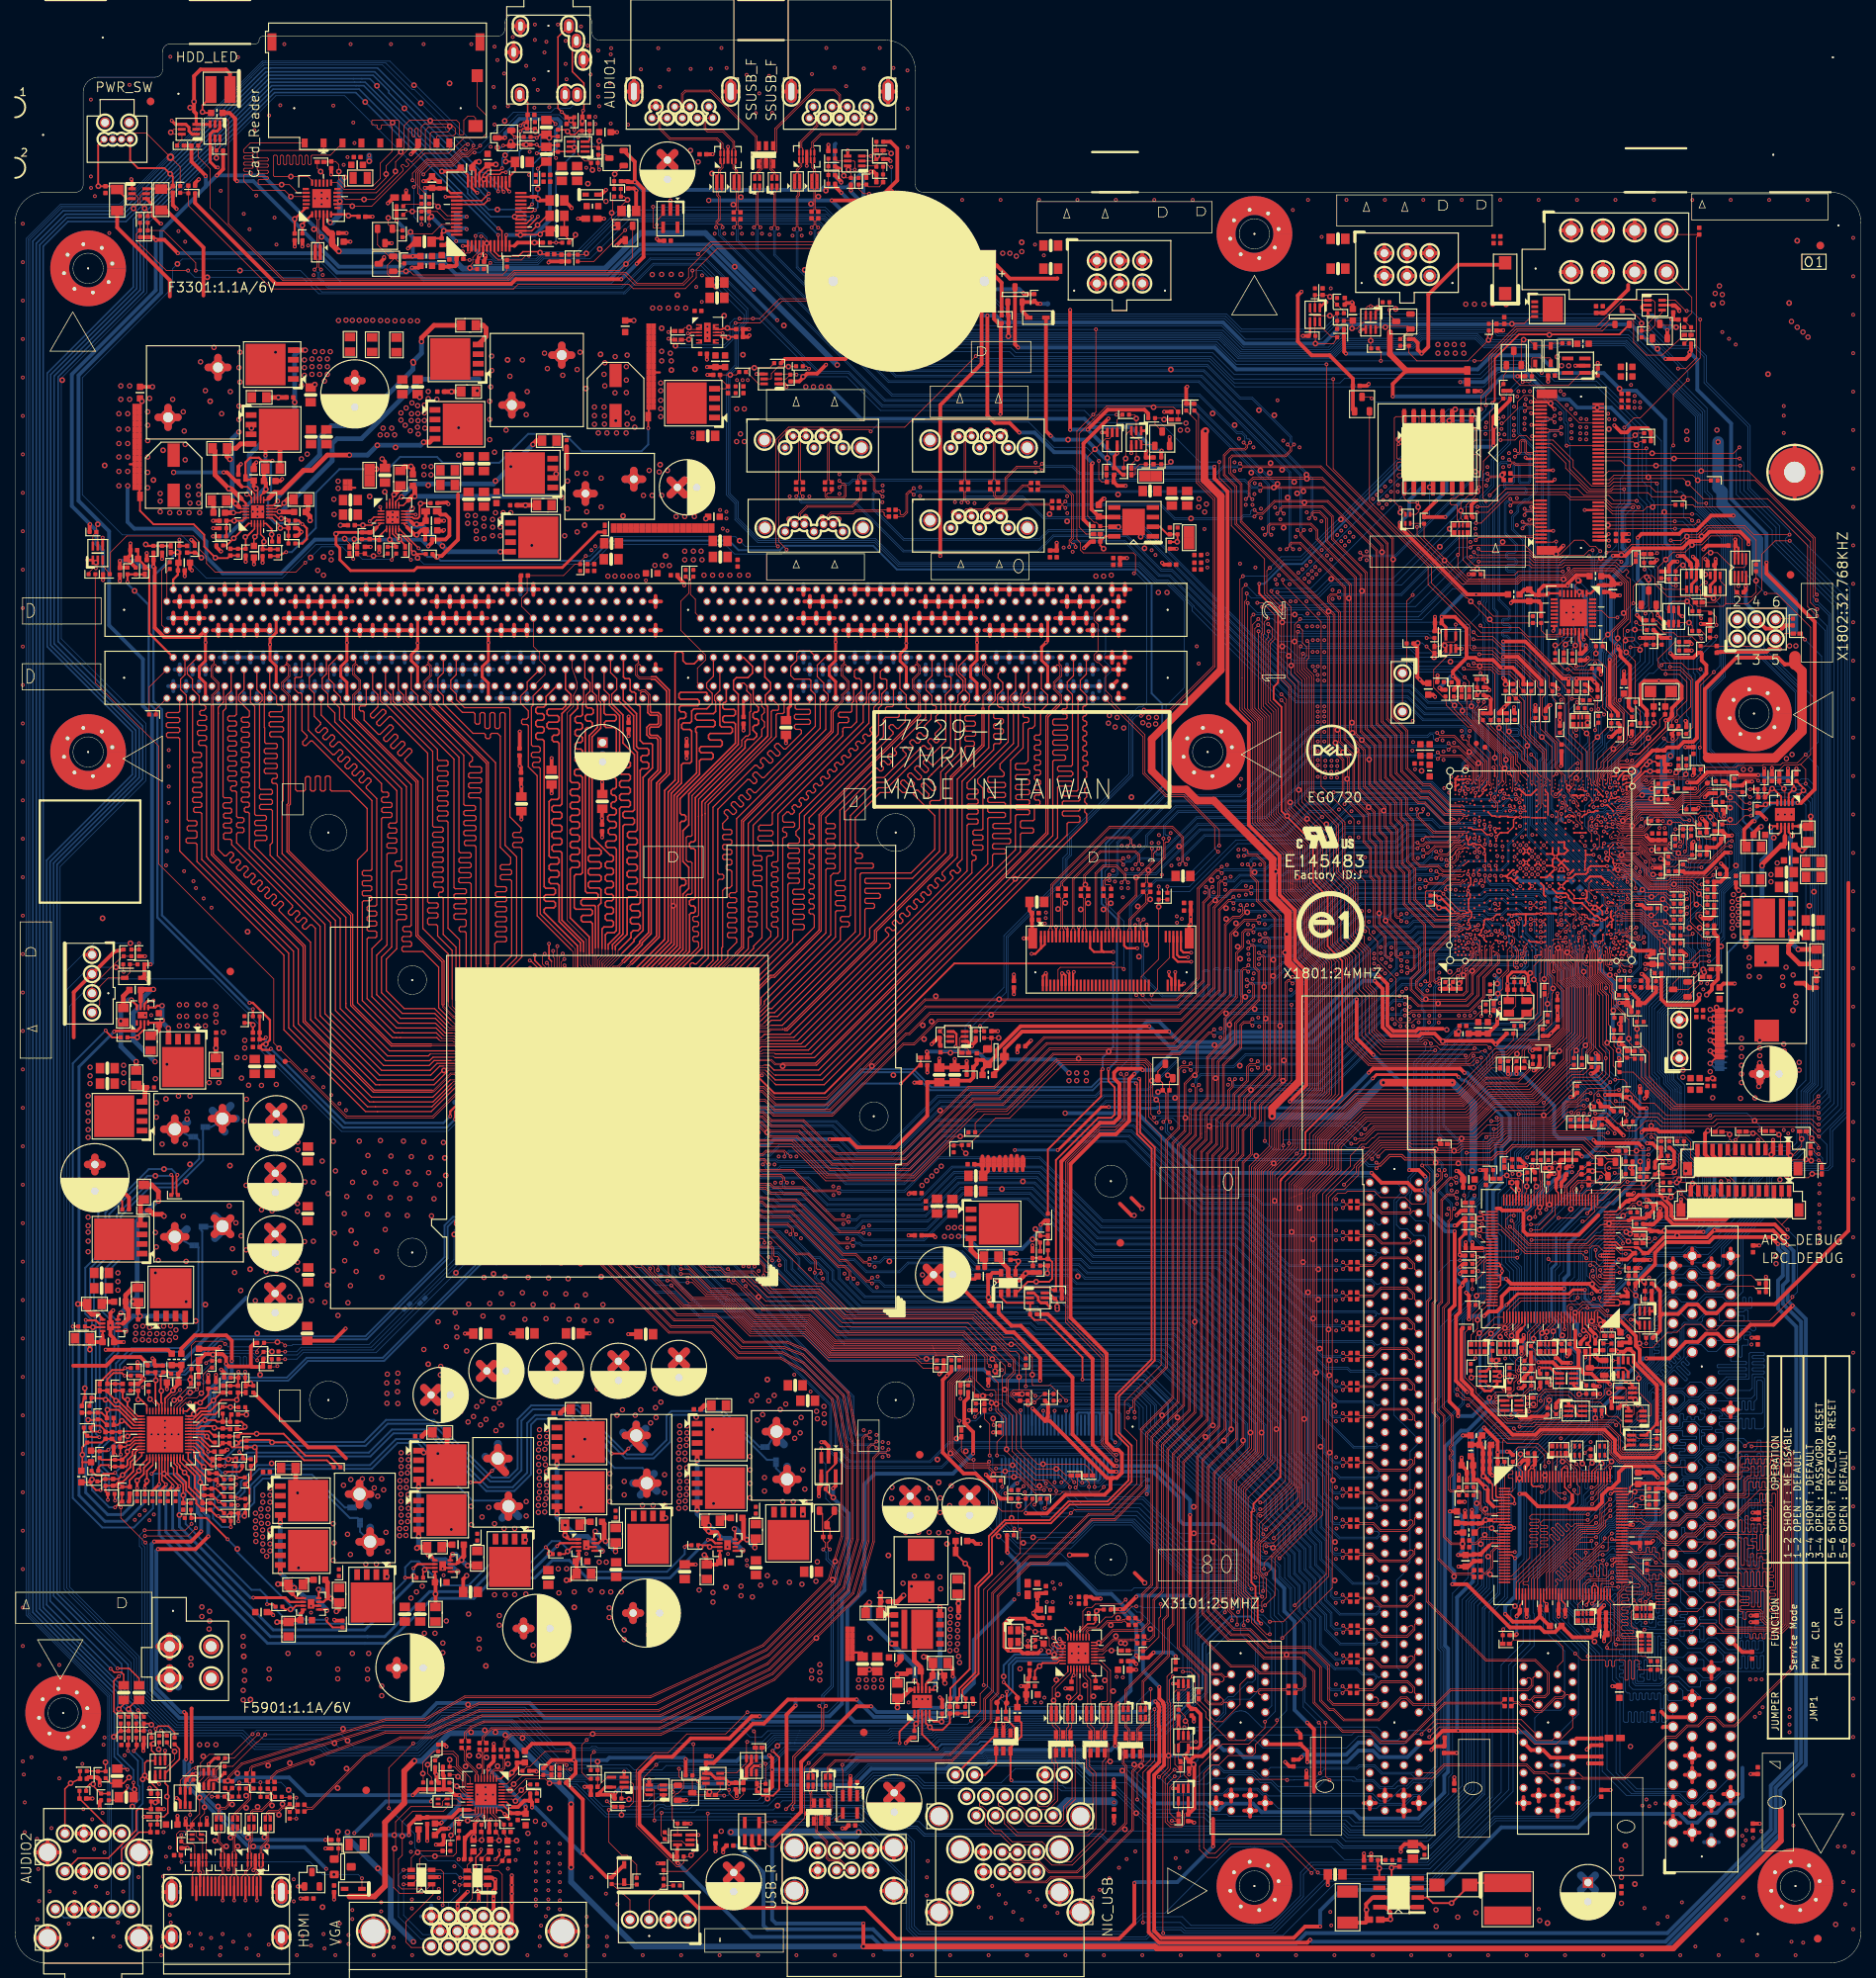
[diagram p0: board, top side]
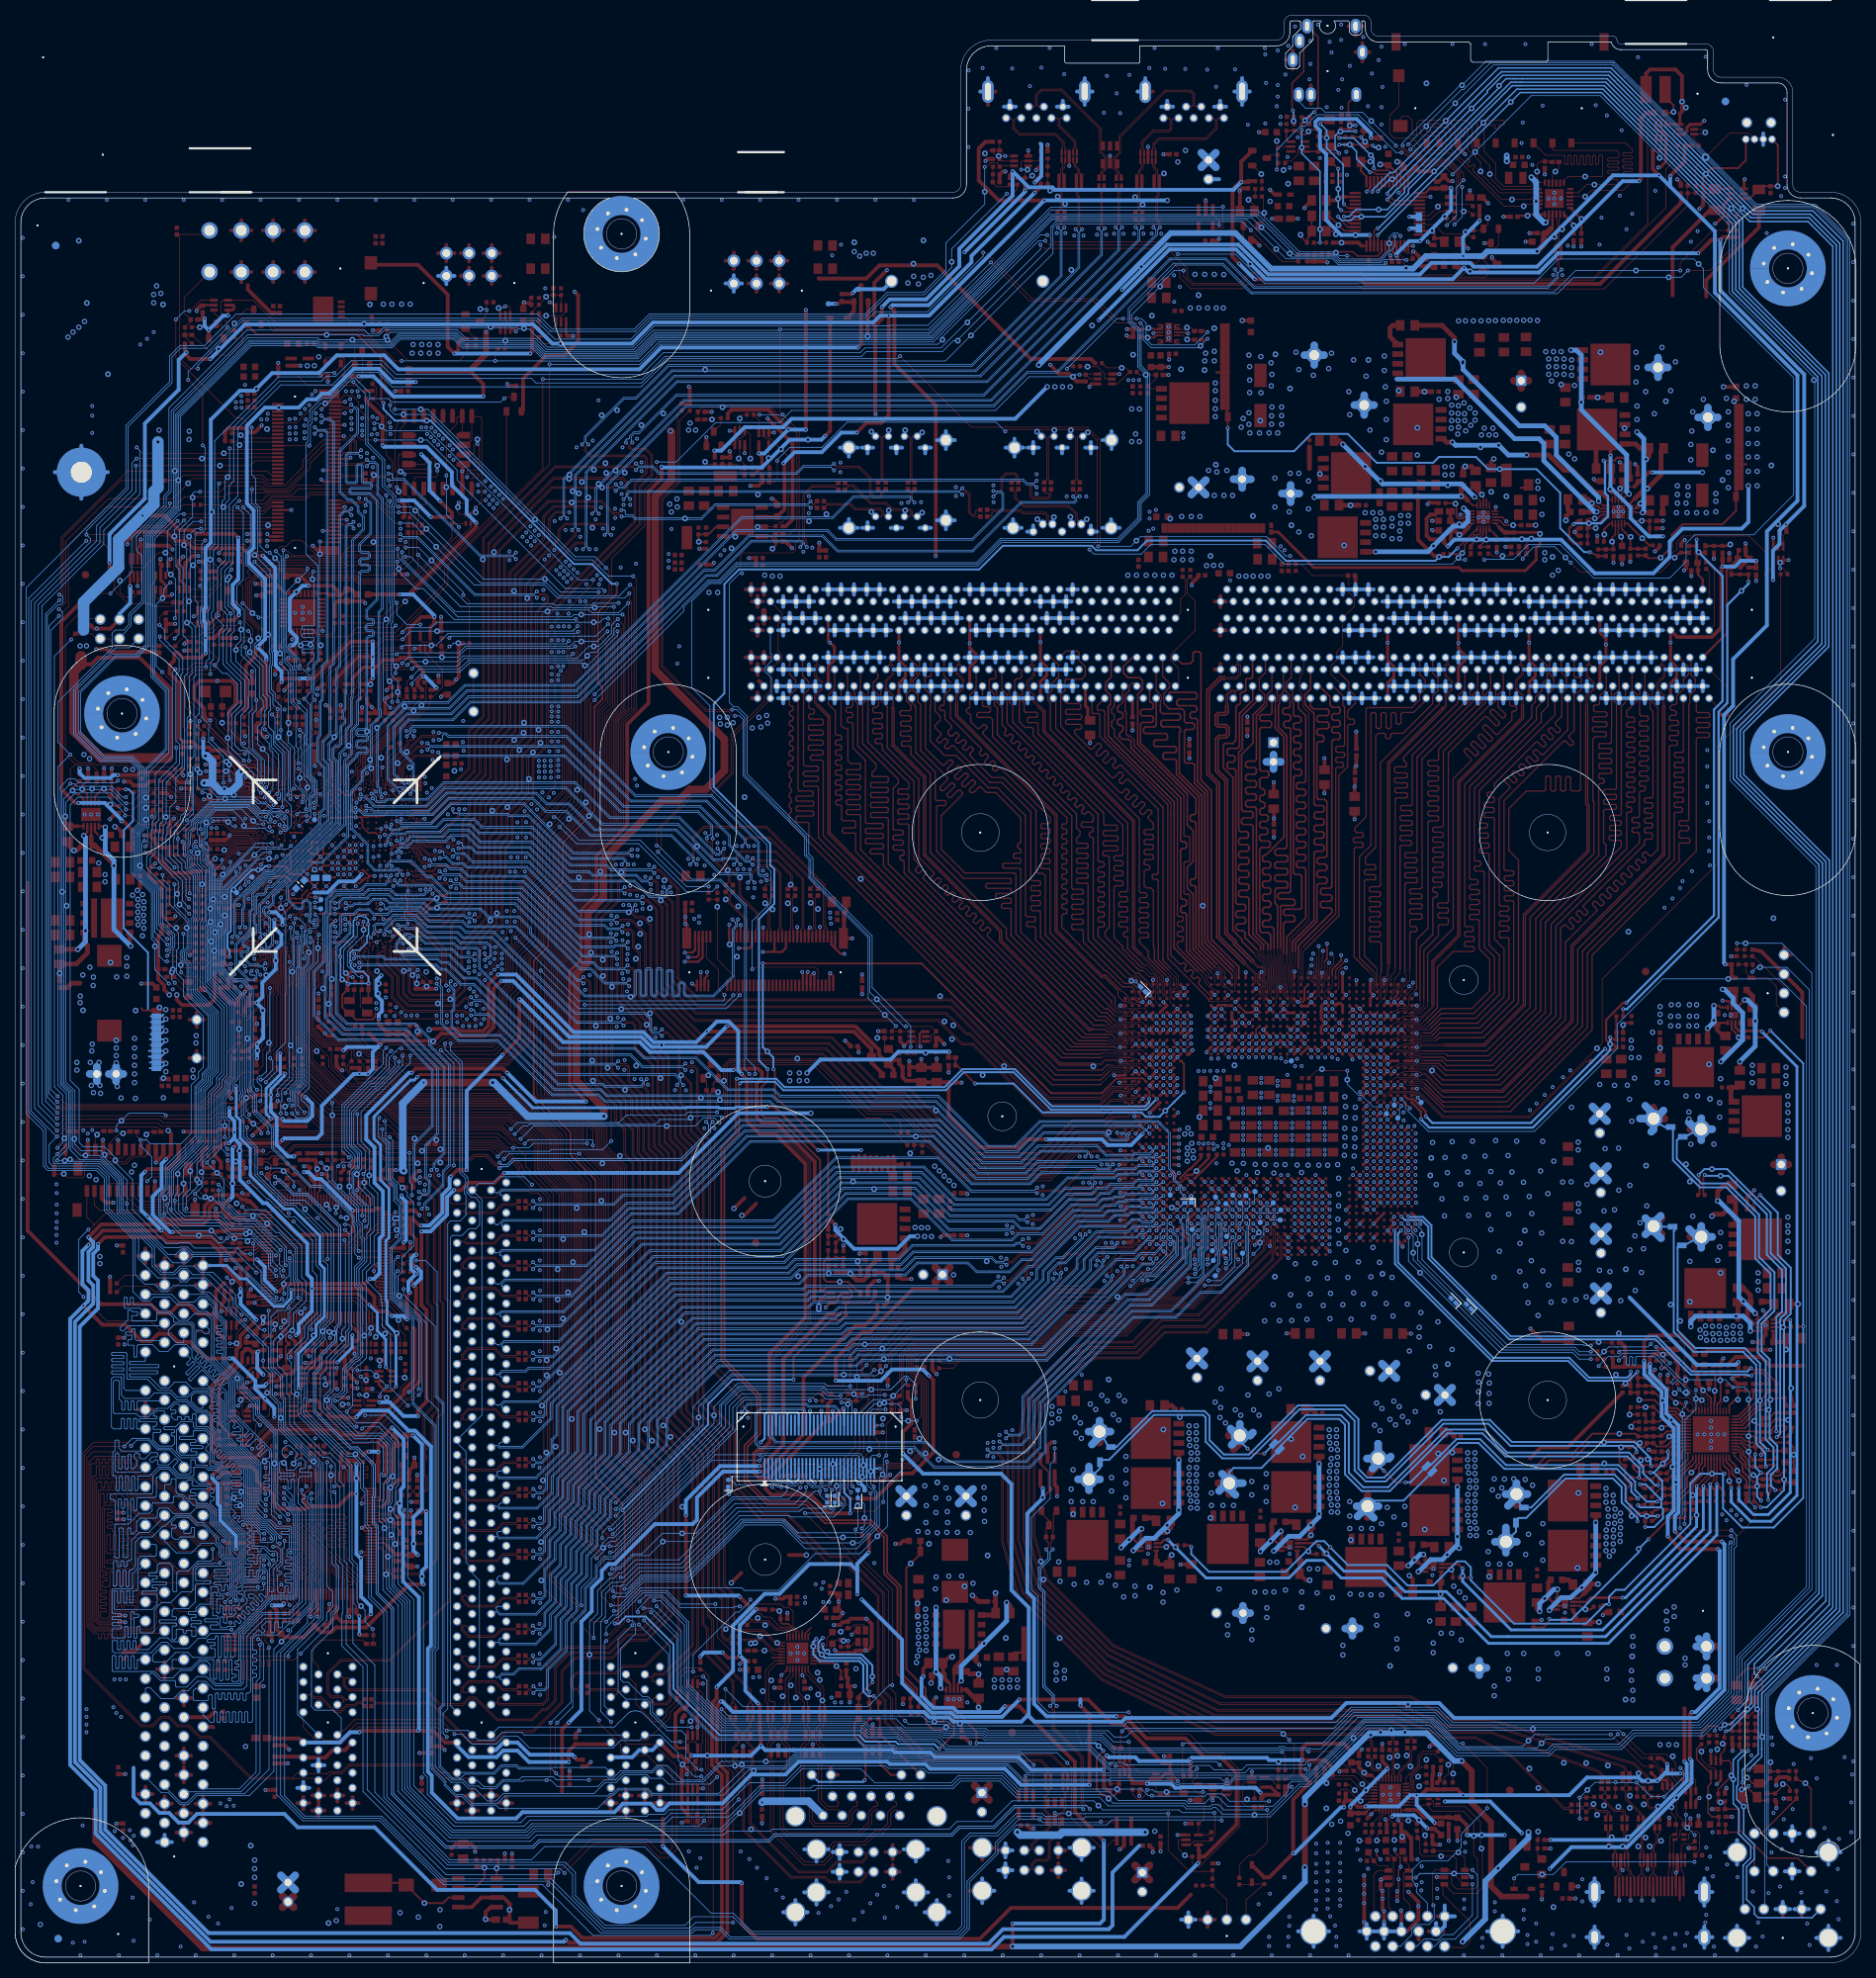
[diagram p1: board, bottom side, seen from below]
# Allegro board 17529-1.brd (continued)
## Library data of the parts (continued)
X1801 = OSC-3225-4P-3H36: tolerance: 082.30006.0531
X1802 = SMD49-3215-0713H36: tolerance: 082.30003.0191
X3101 = SMD-OSC38H20: tolerance: 82.30020.I61
XDP1 = DM-BSH-03001-FDA-01: tolerance: ZZ.F0441.06001

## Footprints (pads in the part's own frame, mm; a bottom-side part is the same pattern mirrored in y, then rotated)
0R0402-PAD-1
  custom 0.14x0.14 smd: 1(0,0.445) 2(0,-0.445)
0R0603-PAD-1-U
  custom 0.216x0.216 smd: 1(0,0.762) 2(0,-0.762)
0R0805-PAD-1-U
  rect 1.397x1.562 smd: 1(0,0.965)
  rect 1.397x1.569 smd: 2(0,-0.965)
0R1210-4P-PAD
  rect 1.041x0.457 smd: 1(-0.635,0.33) 2(-0.635,-0.33) 3(0.635,-0.33) 4(0.635,0.33)
2SJ3062-004111F
  round 0.254 hole 1.219 unplated: (0,6) (0,0)
  oval 1.321x1.93 hole 0.61x1.219: 1(3.8,9.1) 2(-3.7,2) 3(3.7,0.05) 4(-2.7,0.05) 5(-2.2,9.1) 6(-3.8,9.1) G1(4.6,3.5) G2(-4.6,4.5)
10-00870-1A61-A
  round 0.254 hole 2.464 unplated: (0,0) (64.77,0)
  round 1.448 hole 1.041: 1(62.865,-3.81) 2(62.865,1.27) 3(61.595,-1.27) 4(61.595,3.81) 5(60.325,-3.81) 6(60.325,1.27) 7(59.055,-1.27) 8(59.055,3.81) 9(57.785,-3.81) 10(57.785,1.27) 11(56.515,-1.27) 12(56.515,3.81) 13(55.245,-3.81) 14(55.245,1.27) 15(53.975,-1.27) 16(53.975,3.81) 17(52.705,-3.81) 18(52.705,1.27) 19(51.435,-1.27) 20(51.435,3.81) 21(50.165,-3.81) 22(50.165,1.27) 23(48.895,-1.27) 24(48.895,3.81) 25(47.625,-3.81) 26(47.625,1.27) 27(46.355,-1.27) 28(46.355,3.81) 29(45.085,-3.81) 30(45.085,1.27) 31(43.815,-1.27) 32(43.815,3.81) 33(42.545,-3.81) 34(42.545,1.27) 35(41.275,-1.27) 36(41.275,3.81) 37(40.005,-3.81) 38(40.005,1.27) 39(38.735,-1.27) 40(38.735,3.81) 41(37.465,-3.81) 42(37.465,1.27) 43(36.195,-1.27) 44(36.195,3.81) 45(34.925,-3.81) 46(34.925,1.27) 47(33.655,-1.27) 48(33.655,3.81) 49(32.385,-3.81) 50(32.385,1.27) 51(31.115,-1.27) 52(31.115,3.81) 53(29.845,-3.81) 54(29.845,1.27) 55(28.575,-1.27) 56(28.575,3.81) 57(27.305,-3.81) 58(27.305,1.27) 59(26.035,-1.27) 60(26.035,3.81) 61(24.765,-3.81) 62(24.765,1.27) 63(23.495,-1.27) 64(23.495,3.81) 65(22.225,-3.81) 66(22.225,1.27) 67(20.955,-1.27) 68(20.955,3.81) 69(19.685,-3.81) 70(19.685,1.27) 71(18.415,-1.27) 72(18.415,3.81) 73(17.145,-3.81) 74(17.145,1.27) 75(15.875,-1.27) 76(15.875,3.81) 77(14.605,-3.81) 78(14.605,1.27) 79(13.335,-1.27) 80(13.335,3.81) 81(12.065,-3.81) 82(12.065,1.27) 83(10.795,-1.27) 84(10.795,3.81) 85(9.525,-3.81) 86(9.525,1.27) 87(8.255,-1.27) 88(8.255,3.81) 89(6.985,-3.81) 90(6.985,1.27) 91(5.715,-1.27) 92(5.715,3.81) 93(4.445,-3.81) 94(4.445,1.27) 95(3.175,-1.27) 96(3.175,3.81) 97(1.905,-3.81) 98(1.905,1.27) 99(-1.905,-1.27) 100(-1.905,3.81) 101(-3.175,-3.81) 102(-3.175,1.27) 103(-4.445,-1.27) 104(-4.445,3.81) 105(-5.715,-3.81) 106(-5.715,1.27) 107(-6.985,-1.27) 108(-6.985,3.81) 109(-8.255,-3.81) 110(-8.255,1.27) 111(-9.525,-1.27) 112(-9.525,3.81) 113(-10.795,-3.81) 114(-10.795,1.27) 115(-12.065,-1.27) 116(-12.065,3.81) 117(-13.335,-3.81) 118(-13.335,1.27) 119(-14.605,-1.27) 120(-14.605,3.81)
20-00950-1A01-A-U
  round 1.727 hole 1.321: 1(11.8,0) 2(-8.2,0)
21S-92-03GB16
  round 1.422 hole 1.016: 1(-2.54,-1.27) 2(-2.54,1.27) 3(0,-1.27) 4(0,1.27) 5(2.54,-1.27) 6(2.54,1.27)
733-71-06TB18
  round 0.254 hole 1.041 unplated: (-6,0) (6,0)
  round 1.676 hole 1.041: 1(3,-3.94) 2(0,-3.94) 3(-3,-3.94) 4(3,-0.94) 5(0,-0.94) 6(-3,-0.94)
87212-1400N
  rect 0.61x1.549 smd: 1(-6.5,-2.525) 2(-5.5,-2.525) 3(-4.5,-2.525) 4(-3.5,-2.525) 5(-2.5,-2.525) 6(-1.5,-2.525) 7(-0.5,-2.525) 8(0.5,-2.525) 9(1.5,-2.525) 10(2.5,-2.525) 11(3.5,-2.525) 12(4.5,-2.525) 13(5.5,-2.525) 14(6.5,-2.525)
  rect 1.194x1.803 smd: 15(-7.797,0) 16(7.797,0)
A1002WV0-13PS-5E
  rect 0.61x1.549 smd: 1(-6,-2.525) 2(-5,-2.525) 3(-4,-2.525) 4(-3,-2.525) 5(-2,-2.525) 6(-1,-2.525) 7(0,-2.525) 8(1,-2.525) 9(2,-2.525) 10(3,-2.525) 11(4,-2.525) 12(5,-2.525) 13(6,-2.525)
  rect 1.194x1.803 smd: 14(-7.297,0) 15(7.297,0)
AAA-PCI-003-K45
  round 0.254 hole 2.362 unplated: (0,0) (9.15,0)
  round 1.092 hole 0.737: A1(-11.65,1.25) A2(-10.65,3.25) A3(-9.65,1.25) A4(-8.65,3.25) A5(-7.65,1.25) A6(-6.65,3.25) A7(-5.65,1.25) A8(-4.65,3.25) A9(-3.65,1.25) A10(-2.65,3.25) A11(-1.65,1.25) A12(1.35,3.25) A13(2.35,1.25) A14(3.35,3.25) A15(4.35,1.25) A16(5.35,3.25) A17(6.35,1.25) A18(7.35,3.25) B1(-11.65,-1.25) B2(-10.65,-3.25) B3(-9.65,-1.25) B4(-8.65,-3.25) B5(-7.65,-1.25) B6(-6.65,-3.25) B7(-5.65,-1.25) B8(-4.65,-3.25) B9(-3.65,-1.25) B10(-2.65,-3.25) B11(-1.65,-1.25) B12(1.35,-3.25) B13(2.35,-1.25) B14(3.35,-3.25) B15(4.35,-1.25) B16(5.35,-3.25) B17(6.35,-1.25) B18(7.35,-3.25)
AAA-PCI-190-K10
  round 0.254 hole 2.362 unplated: (-73.15,0) (0,0)
  round 1.092 hole 0.737: A1(11.65,-1.25) A2(10.65,-3.25) A3(9.65,-1.25) A4(8.65,-3.25) A5(7.65,-1.25) A6(6.65,-3.25) A7(5.65,-1.25) A8(4.65,-3.25) A9(3.65,-1.25) A10(2.65,-3.25) A11(1.65,-1.25) A12(-1.35,-3.25) A13(-2.35,-1.25) A14(-3.35,-3.25) A15(-4.35,-1.25) A16(-5.35,-3.25) A17(-6.35,-1.25) A18(-7.35,-3.25) A19(-8.35,-1.25) A20(-9.35,-3.25) A21(-10.35,-1.25) A22(-11.35,-3.25) A23(-12.35,-1.25) A24(-13.35,-3.25) A25(-14.35,-1.25) A26(-15.35,-3.25) A27(-16.35,-1.25) A28(-17.35,-3.25) A29(-18.35,-1.25) A30(-19.35,-3.25) A31(-20.35,-1.25) A32(-21.35,-3.25) A33(-22.35,-1.25) A34(-23.35,-3.25) A35(-24.35,-1.25) A36(-25.35,-3.25) A37(-26.35,-1.25) A38(-27.35,-3.25) A39(-28.35,-1.25) A40(-29.35,-3.25) A41(-30.35,-1.25) A42(-31.35,-3.25) A43(-32.35,-1.25) A44(-33.35,-3.25) A45(-34.35,-1.25) A46(-35.35,-3.25) A47(-36.35,-1.25) A48(-37.35,-3.25) A49(-38.35,-1.25) A50(-39.35,-3.25) A51(-40.35,-1.25) A52(-41.35,-3.25) A53(-42.35,-1.25) A54(-43.35,-3.25) A55(-44.35,-1.25) A56(-45.35,-3.25) A57(-46.35,-1.25) A58(-47.35,-3.25) A59(-48.35,-1.25) A60(-49.35,-3.25) A61(-50.35,-1.25) A62(-51.35,-3.25) A63(-52.35,-1.25) A64(-53.35,-3.25) A65(-54.35,-1.25) A66(-55.35,-3.25) A67(-56.35,-1.25) A68(-57.35,-3.25) A69(-58.35,-1.25) A70(-59.35,-3.25) A71(-60.35,-1.25) A72(-61.35,-3.25) A73(-62.35,-1.25) A74(-63.35,-3.25) A75(-64.35,-1.25) A76(-65.35,-3.25) A77(-66.35,-1.25) A78(-67.35,-3.25) A79(-68.35,-1.25) A80(-69.35,-3.25) A81(-70.35,-1.25) A82(-71.35,-3.25) B1(11.65,1.25) B2(10.65,3.25) B3(9.65,1.25) B4(8.65,3.25) B5(7.65,1.25) B6(6.65,3.25) B7(5.65,1.25) B8(4.65,3.25) B9(3.65,1.25) B10(2.65,3.25) B11(1.65,1.25) B12(-1.35,3.25) B13(-2.35,1.25) B14(-3.35,3.25) B15(-4.35,1.25) B16(-5.35,3.25) B17(-6.35,1.25) B18(-7.35,3.25) B19(-8.35,1.25) B20(-9.35,3.25) B21(-10.35,1.25) B22(-11.35,3.25) B23(-12.35,1.25) B24(-13.35,3.25) B25(-14.35,1.25) B26(-15.35,3.25) B27(-16.35,1.25) B28(-17.35,3.25) B29(-18.35,1.25) B30(-19.35,3.25) B31(-20.35,1.25) B32(-21.35,3.25) B33(-22.35,1.25) B34(-23.35,3.25) B35(-24.35,1.25) B36(-25.35,3.25) B37(-26.35,1.25) B38(-27.35,3.25) B39(-28.35,1.25) B40(-29.35,3.25) B41(-30.35,1.25) B42(-31.35,3.25) B43(-32.35,1.25) B44(-33.35,3.25) B45(-34.35,1.25) B46(-35.35,3.25) B47(-36.35,1.25) B48(-37.35,3.25) B49(-38.35,1.25) B50(-39.35,3.25) B51(-40.35,1.25) B52(-41.35,3.25) B53(-42.35,1.25) B54(-43.35,3.25) B55(-44.35,1.25) B56(-45.35,3.25) B57(-46.35,1.25) B58(-47.35,3.25) B59(-48.35,1.25) B60(-49.35,3.25) B61(-50.35,1.25) B62(-51.35,3.25) B63(-52.35,1.25) B64(-53.35,3.25) B65(-54.35,1.25) B66(-55.35,3.25) B67(-56.35,1.25) B68(-57.35,3.25) B69(-58.35,1.25) B70(-59.35,3.25) B71(-60.35,1.25) B72(-61.35,3.25) B73(-62.35,1.25) B74(-63.35,3.25) B75(-64.35,1.25) B76(-65.35,3.25) B77(-66.35,1.25) B78(-67.35,3.25) B79(-68.35,1.25) B80(-69.35,3.25) B81(-70.35,1.25) B82(-71.35,3.25)
ABA-JAK-028-K03
  round 0.254 hole 2.311 unplated: (0,0)
  round 1.422 hole 1.016: 1(0,-3.8) 2(-5,-3.8) 3(-2.5,-3.8) 4(2.5,-3.8) 5(5,-3.8) 22(-3.75,-8.8) 23(-1.25,-8.8) 24(1.25,-8.8) 25(3.75,-8.8) 32(-3.75,-13.8) 33(-1.25,-13.8) 34(1.25,-13.8) 35(3.75,-13.8)
  round 2.718 hole 2.311: G1(6.04,0) G2(-6.04,0) G3(6.04,-11.3) G4(-6.04,-11.3)
ABA-SAT-010-K04-U
  round 1.118 hole 0.762: 1(-3.81,-0.5) 4(0,-0.5) 7(3.81,-0.5)
  oval 1.041x1.168 hole 0.762: 2(-2.54,0.5) 3(-1.27,0.5) 5(1.27,0.5) 6(2.54,0.5)
  round 1.778 hole 1.372: 8(-6.48,0) 9(6.48,0)
AH08847-A9L2-4M
  round 0.254 hole 2.464 unplated: (-74.55,0) (63.4,0)
  round 0.254 hole 2.464x1.219 unplated: (0,0)
  round 0.965 hole 0.66: 1(-68.9,-2.7) 2(-68.05,-1.1) 3(-67.2,-2.7) 4(-66.35,-1.1) 5(-65.5,-2.7) 6(-64.65,-1.1) 7(-63.8,-2.7) 8(-62.95,-1.1) 9(-62.1,-2.7) 10(-61.25,-1.1) 11(-60.4,-2.7) 12(-59.55,-1.1) 13(-58.7,-2.7) 14(-57.85,-1.1) 15(-57,-2.7) 16(-56.15,-1.1) 17(-55.3,-2.7) 18(-54.45,-1.1) 19(-53.6,-2.7) 20(-52.75,-1.1) 21(-51.9,-2.7) 22(-51.05,-1.1) 23(-50.2,-2.7) 24(-49.35,-1.1) 25(-48.5,-2.7) 26(-47.65,-1.1) 27(-46.8,-2.7) 28(-45.95,-1.1) 29(-45.1,-2.7) 30(-44.25,-1.1) 31(-43.4,-2.7) 32(-42.55,-1.1) 33(-41.7,-2.7) 34(-40.85,-1.1) 35(-40,-2.7) 36(-39.15,-1.1) 37(-38.3,-2.7) 38(-37.45,-1.1) 39(-36.6,-2.7) 40(-35.75,-1.1) 41(-34.9,-2.7) 42(-34.05,-1.1) 43(-33.2,-2.7) 44(-32.35,-1.1) 45(-31.5,-2.7) 46(-30.65,-1.1) 47(-29.8,-2.7) 48(-28.95,-1.1) 49(-28.1,-2.7) 50(-27.25,-1.1) 51(-26.4,-2.7) 52(-25.55,-1.1) 53(-24.7,-2.7) 54(-23.85,-1.1) 55(-23,-2.7) 56(-22.15,-1.1) 57(-21.3,-2.7) 58(-20.45,-1.1) 59(-19.6,-2.7) 60(-18.75,-1.1) 61(-17.9,-2.7) 62(-17.05,-1.1) 63(-16.2,-2.7) 64(-15.35,-1.1) 65(-14.5,-2.7) 66(-13.65,-1.1) 67(-12.8,-2.7) 68(-11.95,-1.1) 69(-11.1,-2.7) 70(-10.25,-1.1) 71(-9.4,-2.7) 72(-8.55,-1.1) 73(-7.7,-2.7) 74(-6.85,-1.1) 75(-6,-2.7) 76(-5.15,-1.1) 77(-4.3,-2.7) 78(1.65,-1.1) 79(2.5,-2.7) 80(3.35,-1.1) 81(4.2,-2.7) 82(5.05,-1.1) 83(5.9,-2.7) 84(6.75,-1.1) 85(7.6,-2.7) 86(8.45,-1.1) 87(9.3,-2.7) 88(10.15,-1.1) 89(11,-2.7) 90(11.85,-1.1) 91(12.7,-2.7) 92(13.55,-1.1) 93(14.4,-2.7) 94(15.25,-1.1) 95(16.1,-2.7) 96(16.95,-1.1) 97(17.8,-2.7) 98(18.65,-1.1) 99(19.5,-2.7) 100(20.35,-1.1) 101(21.2,-2.7) 102(22.05,-1.1) 103(22.9,-2.7) 104(23.75,-1.1) 105(24.6,-2.7) 106(25.45,-1.1) 107(26.3,-2.7) 108(27.15,-1.1) 109(28,-2.7) 110(28.85,-1.1) 111(29.7,-2.7) 112(30.55,-1.1) 113(31.4,-2.7) 114(32.25,-1.1) 115(33.1,-2.7) 116(33.95,-1.1) 117(34.8,-2.7) 118(35.65,-1.1) 119(36.5,-2.7) 120(37.35,-1.1) 121(38.2,-2.7) 122(39.05,-1.1) 123(39.9,-2.7) 124(40.75,-1.1) 125(41.6,-2.7) 126(42.45,-1.1) 127(43.3,-2.7) 128(44.15,-1.1) 129(45,-2.7) 130(45.85,-1.1) 131(46.7,-2.7) 132(47.55,-1.1) 133(48.4,-2.7) 134(49.25,-1.1) 135(50.1,-2.7) 136(50.95,-1.1) 137(51.8,-2.7) 138(52.65,-1.1) 139(53.5,-2.7) 140(54.35,-1.1) 141(55.2,-2.7) 142(56.05,-1.1) 143(56.9,-2.7) 144(57.75,-1.1) 145(-68.9,1.1) 146(-68.05,2.7) 147(-67.2,1.1) 148(-66.35,2.7) 149(-65.5,1.1) 150(-64.65,2.7) 151(-63.8,1.1) 152(-62.95,2.7) 153(-62.1,1.1) 154(-61.25,2.7) 155(-60.4,1.1) 156(-59.55,2.7) 157(-58.7,1.1) 158(-57.85,2.7) 159(-57,1.1) 160(-56.15,2.7) 161(-55.3,1.1) 162(-54.45,2.7) 163(-53.6,1.1) 164(-52.75,2.7) 165(-51.9,1.1) 166(-51.05,2.7) 167(-50.2,1.1) 168(-49.35,2.7) 169(-48.5,1.1) 170(-47.65,2.7) 171(-46.8,1.1) 172(-45.95,2.7) 173(-45.1,1.1) 174(-44.25,2.7) 175(-43.4,1.1) 176(-42.55,2.7) 177(-41.7,1.1) 178(-40.85,2.7) 179(-40,1.1) 180(-39.15,2.7) 181(-38.3,1.1) 182(-37.45,2.7) 183(-36.6,1.1) 184(-35.75,2.7) 185(-34.9,1.1) 186(-34.05,2.7) 187(-33.2,1.1) 188(-32.35,2.7) 189(-31.5,1.1) 190(-30.65,2.7) 191(-29.8,1.1) 192(-28.95,2.7) 193(-28.1,1.1) 194(-27.25,2.7) 195(-26.4,1.1) 196(-25.55,2.7) 197(-24.7,1.1) 198(-23.85,2.7) 199(-23,1.1) 200(-22.15,2.7) 201(-21.3,1.1) 202(-20.45,2.7) 203(-19.6,1.1) 204(-18.75,2.7) 205(-17.9,1.1) 206(-17.05,2.7) 207(-16.2,1.1) 208(-15.35,2.7) 209(-14.5,1.1) 210(-13.65,2.7) 211(-12.8,1.1) 212(-11.95,2.7) 213(-11.1,1.1) 214(-10.25,2.7) 215(-9.4,1.1) 216(-8.55,2.7) 217(-7.7,1.1) 218(-6.85,2.7) 219(-6,1.1) 220(-5.15,2.7) 221(-4.3,1.1) 222(1.65,2.7) 223(2.5,1.1) 224(3.35,2.7) 225(4.2,1.1) 226(5.05,2.7) 227(5.9,1.1) 228(6.75,2.7) 229(7.6,1.1) 230(8.45,2.7) 231(9.3,1.1) 232(10.15,2.7) 233(11,1.1) 234(11.85,2.7) 235(12.7,1.1) 236(13.55,2.7) 237(14.4,1.1) 238(15.25,2.7) 239(16.1,1.1) 240(16.95,2.7) 241(17.8,1.1) 242(18.65,2.7) 243(19.5,1.1) 244(20.35,2.7) 245(21.2,1.1) 246(22.05,2.7) 247(22.9,1.1) 248(23.75,2.7) 249(24.6,1.1) 250(25.45,2.7) 251(26.3,1.1) 252(27.15,2.7) 253(28,1.1) 254(28.85,2.7) 255(29.7,1.1) 256(30.55,2.7) 257(31.4,1.1) 258(32.25,2.7) 259(33.1,1.1) 260(33.95,2.7) 261(34.8,1.1) 262(35.65,2.7) 263(36.5,1.1) 264(37.35,2.7) 265(38.2,1.1) 266(39.05,2.7) 267(39.9,1.1) 268(40.75,2.7) 269(41.6,1.1) 270(42.45,2.7) 271(43.3,1.1) 272(44.15,2.7) 273(45,1.1) 274(45.85,2.7) 275(46.7,1.1) 276(47.55,2.7) 277(48.4,1.1) 278(49.25,2.7) 279(50.1,1.1) 280(50.95,2.7) 281(51.8,1.1) 282(52.65,2.7) 283(53.5,1.1) 284(54.35,2.7) 285(55.2,1.1) 286(56.05,2.7) 287(56.9,1.1) 288(57.75,2.7)
ARES2H16
  rect 0.356x0.66 smd: 1(-0.325,-0.599) 2(0.325,-0.599) 3(0.325,0.599) 4(-0.325,0.599)
ARES8-CN24-UH20
  rect 0.61x0.66 smd: 1(-0.9,-0.486) 4(0.9,-0.486) 5(0.9,0.486) 8(-0.9,0.486)
  rect 0.305x0.66 smd: 2(-0.25,-0.486) 3(0.25,-0.486) 6(0.25,0.486) 7(-0.25,0.486)
ARES8-CN24-UH22
  rect 0.61x0.66 smd: 1(-0.9,-0.486) 4(0.9,-0.486) 5(0.9,0.486) 8(-0.9,0.486)
  rect 0.305x0.66 smd: 2(-0.25,-0.486) 3(0.25,-0.486) 6(0.25,0.486) 7(-0.25,0.486)
ARES8-CN24H20
  rect 0.61x0.66 smd: 1(-0.9,-0.486) 4(0.9,-0.486) 5(0.9,0.486) 8(-0.9,0.486)
  rect 0.305x0.66 smd: 2(-0.25,-0.486) 3(0.25,-0.486) 6(0.25,0.486) 7(-0.25,0.486)
AS0BC21-S40BE-7H
  round 0.254 hole 1.168 unplated: (-10,0)
  round 0.254 hole 1.651 unplated: (10,0)
  rect 0.305x1.549 smd: 1(-9.25,5.275) 2(-9,-2.275) 3(-8.75,5.275) 4(-8.5,-2.275) 5(-8.25,5.275) 6(-8,-2.275) 7(-7.75,5.275) 8(-7.5,-2.275) 9(-7.25,5.275) 10(-7,-2.275) 11(-6.75,5.275) 12(-6.5,-2.275) 13(-6.25,5.275) 14(-6,-2.275) 15(-5.75,5.275) 16(-5.5,-2.275) 17(-5.25,5.275) 18(-5,-2.275) 19(-4.75,5.275) 20(-4.5,-2.275) 21(-4.25,5.275) 22(-4,-2.275) 23(-3.75,5.275) 32(-1.5,-2.275) 33(-1.25,5.275) 34(-1,-2.275) 35(-0.75,5.275) 36(-0.5,-2.275) 37(-0.25,5.275) 38(0,-2.275) 39(0.25,5.275) 40(0.5,-2.275) 41(0.75,5.275) 42(1,-2.275) 43(1.25,5.275) 44(1.5,-2.275) 45(1.75,5.275) 46(2,-2.275) 47(2.25,5.275) 48(2.5,-2.275) 49(2.75,5.275) 50(3,-2.275) 51(3.25,5.275) 52(3.5,-2.275) 53(3.75,5.275) 54(4,-2.275) 55(4.25,5.275) 56(4.5,-2.275) 57(4.75,5.275) 58(5,-2.275) 59(5.25,5.275) 60(5.5,-2.275) 61(5.75,5.275) 62(6,-2.275) 63(6.25,5.275) 64(6.5,-2.275) 65(6.75,5.275) 66(7,-2.275) 67(7.25,5.275) 68(7.5,-2.275) 69(7.75,5.275) 70(8,-2.275) 71(8.25,5.275) 72(8.5,-2.275) 73(8.75,5.275) 74(9,-2.275) 75(9.25,5.275)
  rect 1.194x2.743 smd: 76(-10.35,4.5) 77(10.35,4.5)
AS0BC21-S85BM-7H
  round 0.254 hole 1.168 unplated: (-10,0)
  round 0.254 hole 1.651 unplated: (10,0)
  rect 0.305x1.549 smd: 1(-9.25,4.725) 2(-9,-1.725) 3(-8.75,4.725) 4(-8.5,-1.725) 5(-8.25,4.725) 6(-8,-1.725) 7(-7.75,4.725) 8(-7.5,-1.725) 9(-7.25,4.725) 10(-7,-1.725) 11(-6.75,4.725) 12(-6.5,-1.725) 13(-6.25,4.725) 14(-6,-1.725) 15(-5.75,4.725) 16(-5.5,-1.725) 17(-5.25,4.725) 18(-5,-1.725) 19(-4.75,4.725) 20(-4.5,-1.725) 21(-4.25,4.725) 22(-4,-1.725) 23(-3.75,4.725) 24(-3.5,-1.725) 25(-3.25,4.725) 26(-3,-1.725) 27(-2.75,4.725) 28(-2.5,-1.725) 29(-2.25,4.725) 30(-2,-1.725) 31(-1.75,4.725) 32(-1.5,-1.725) 33(-1.25,4.725) 34(-1,-1.725) 35(-0.75,4.725) 36(-0.5,-1.725) 37(-0.25,4.725) 38(0,-1.725) 39(0.25,4.725) 40(0.5,-1.725) 41(0.75,4.725) 42(1,-1.725) 43(1.25,4.725) 44(1.5,-1.725) 45(1.75,4.725) 46(2,-1.725) 47(2.25,4.725) 48(2.5,-1.725) 49(2.75,4.725) 50(3,-1.725) 51(3.25,4.725) 52(3.5,-1.725) 53(3.75,4.725) 54(4,-1.725) 55(4.25,4.725) 56(4.5,-1.725) 57(4.75,4.725) 58(5,-1.725) 67(7.25,4.725) 68(7.5,-1.725) 69(7.75,4.725) 70(8,-1.725) 71(8.25,4.725) 72(8.5,-1.725) 73(8.75,4.725) 74(9,-1.725) 75(9.25,4.725)
  rect 1.194x2.743 smd: 76(-10.35,4.5) 77(10.35,4.5)
AT4203W-D067-08E801B-U
  round 0.254 hole 3.023 unplated: (-11,-2.29)
  round 2.184 hole 1.422: 1(-6.3,2.75) 2(-2.1,2.75) 3(2.1,2.75) 4(6.3,2.75) 5(-6.3,-2.75) 6(-2.1,-2.75) 7(2.1,-2.75) 8(6.3,-2.75)
BGA874M250240H60
  round 0.305 smd: A2(-11.46,11.314) A3(-10.959,11.314) A4(-10.459,11.314) A46(10.459,11.314) A47(10.959,11.314) A48(11.46,11.314) AA19(-3.099,1.549) AA20(-2.324,1.549) AA22(-1.549,1.549) AA23(-0.775,1.549) AA25(0,1.549) AA27(0.775,1.549) AA28(1.549,1.549) AA30(2.324,1.549) AA31(3.099,1.549) AB19(-3.099,0.775) AB20(-2.324,0.775) AB22(-1.549,0.775) AB23(-0.775,0.775) AB25(0,0.775) AB27(0.775,0.775) AB28(1.549,0.775) AB30(2.324,0.775) AB31(3.099,0.775) AC6(-9.374,0.579) AC7(-8.612,0.579) AC9(-7.85,0.579) AC11(-7.088,0.579) AC12(-6.326,0.579) AC14(-5.564,0.579) AC15(-4.802,0.579) AC17(-4.04,0.579) AC33(4.04,0.579) AC35(4.802,0.579) AC36(5.564,0.579) AC38(6.326,0.579) AC39(7.088,0.579) AC41(7.85,0.579) AC43(8.612,0.579) AC44(9.374,0.579) AD19(-3.099,0) AD20(-2.324,0) AD22(-1.549,0) AD23(-0.775,0) AD25(0,0) AD27(0.775,0) AD28(1.549,0) AD30(2.324,0) AD31(3.099,0) AE6(-9.374,-0.579) AE7(-8.612,-0.579) AE9(-7.85,-0.579) AE11(-7.088,-0.579) AE12(-6.326,-0.579) AE14(-5.564,-0.579) AE15(-4.802,-0.579) AE17(-4.04,-0.579) AE33(4.04,-0.579) AE35(4.802,-0.579) AE36(5.564,-0.579) AE38(6.326,-0.579) AE39(7.088,-0.579) AE41(7.85,-0.579) AE43(8.612,-0.579) AE44(9.374,-0.579) AF19(-3.099,-0.775) AF20(-2.324,-0.775) AF22(-1.549,-0.775) AF23(-0.775,-0.775) AF25(0,-0.775) AF27(0.775,-0.775) AF28(1.549,-0.775) AF30(2.324,-0.775) AF31(3.099,-0.775) AG19(-3.099,-1.549) AG20(-2.324,-1.549) AG22(-1.549,-1.549) AG23(-0.775,-1.549) AG25(0,-1.549) AG27(0.775,-1.549) AG28(1.549,-1.549) AG30(2.324,-1.549) AG31(3.099,-1.549) AH9(-7.919,-2.205) AH10(-7.18,-2.014) AH12(-6.402,-2.014) AH14(-5.564,-2.014) AH15(-4.789,-2.014) AH17(-4.027,-2.014) AH33(4.027,-2.014) AH35(4.789,-2.014) AH36(5.564,-2.014) AH38(6.402,-2.014) AH40(7.18,-2.014) AH41(7.919,-2.205) AJ6(-9.397,-2.586) AJ7(-8.658,-2.395) AJ19(-3.099,-2.324) AJ20(-2.324,-2.324) AJ22(-1.549,-2.324) AJ23(-0.775,-2.324) AJ25(0,-2.324) AJ27(0.775,-2.324) AJ28(1.549,-2.324) AJ30(2.324,-2.324) AJ31(3.099,-2.324) AJ43(8.658,-2.395) AJ44(9.397,-2.586) AK19(-3.099,-3.099) AK20(-2.324,-3.099) AK22(-1.549,-3.099) AK23(-0.775,-3.099) AK25(0,-3.099) AK27(0.775,-3.099) AK28(1.549,-3.099) AK30(2.324,-3.099) AK31(3.099,-3.099) AL9(-7.914,-3.495) AL10(-7.181,-3.259) AL12(-6.419,-3.259) AL13(-5.657,-3.259) AL15(-4.895,-3.259) AL17(-4.133,-3.259) AL21(-2.014,-3.578) AL24(-0.579,-3.591) AL26(0.579,-3.591) AL29(2.014,-3.578) AL33(4.133,-3.259) AL35(4.895,-3.259) AL37(5.657,-3.259) AL38(6.419,-3.259) AL40(7.181,-3.259) AL41(7.914,-3.495) AM7(-8.635,-3.843) AM18(-3.259,-3.683) AM32(3.259,-3.683) AM43(8.635,-3.843) AN6(-9.295,-4.224) AN10(-7.181,-4.656) AN12(-6.444,-4.351) AN13(-5.682,-4.351) AN15(-4.92,-4.351) AN16(-4.351,-4.394) AN18(-3.259,-4.394) AN21(-2.014,-4.289) AN24(-0.579,-4.302) AN26(0.579,-4.302) AN29(2.014,-4.289) AN32(3.259,-4.394) AN34(4.351,-4.394) AN35(4.92,-4.351) AN37(5.682,-4.351) AN38(6.444,-4.351) AN40(7.181,-4.656) AN44(9.295,-4.224) AP9(-7.914,-4.968) AP21(-2.014,-5.064) AP24(-0.579,-5.064) AP26(0.579,-5.064) AP29(2.014,-5.064) AP41(7.914,-4.968) AR8(-8.508,-5.469) AR12(-6.444,-5.443) AR13(-5.682,-5.443) AR15(-4.92,-5.443) AR16(-4.351,-5.182) AR18(-3.259,-5.156) AR32(3.259,-5.156) AR34(4.351,-5.182) AR35(4.92,-5.443) AR37(5.682,-5.443) AR38(6.444,-5.443) AR42(8.508,-5.469) AT6(-9.295,-5.659) AT10(-7.181,-5.773) AT16(-4.351,-5.944) AT18(-3.259,-5.918) AT21(-2.014,-5.902) AT24(-0.579,-5.826) AT26(0.579,-5.826) AT29(2.014,-5.902) AT32(3.259,-5.918) AT34(4.351,-5.944) AT40(7.181,-5.773) AT44(9.295,-5.659) AU9(-7.914,-6.416) AU24(-0.579,-6.588) AU26(0.579,-6.588) AU41(7.914,-6.416) AV6(-9.295,-7.094) AV7(-8.597,-6.764) AV11(-7.079,-6.975) AV13(-5.748,-6.757) AV16(-4.656,-6.719) AV18(-3.259,-6.68) AV21(-2.014,-6.679) AV29(2.014,-6.679) AV32(3.259,-6.68) AV34(4.656,-6.719) AV37(5.748,-6.757) AV39(7.079,-6.975) AV43(8.597,-6.764) AV44(9.295,-7.094) AW9(-7.824,-7.577) AW10(-7.262,-7.509) AW13(-6.01,-7.49) AW15(-4.892,-7.452) AW18(-3.495,-7.413) AW21(-2.205,-7.419) AW24(-0.579,-7.35) AW26(0.579,-7.35) AW29(2.205,-7.419) AW32(3.495,-7.413) AW35(4.892,-7.452) AW37(6.01,-7.49) AW40(7.262,-7.509) AW41(7.824,-7.577) AY8(-8.533,-7.898) AY42(8.533,-7.898) B1(-11.814,10.96) B2(-11.33,10.83) B3(-10.709,10.878) B47(10.709,10.878) B48(11.33,10.83) B49(11.814,10.96) BA6(-9.13,-8.203) BA12(-6.485,-8.135) BA14(-5.24,-8.135) BA17(-3.843,-8.135) BA20(-2.395,-8.158) BA24(-0.579,-8.112) BA26(0.579,-8.112) BA30(2.395,-8.158) BA33(3.843,-8.135) BA36(5.24,-8.135) BA38(6.485,-8.135) BA44(9.13,-8.203) BB6(-9.088,-8.706) BB7(-8.589,-9) BB9(-8.024,-8.774) BB11(-6.866,-8.795) BB14(-5.621,-8.795) BB16(-4.224,-8.795) BB20(-2.586,-8.897) BB24(-0.579,-8.874) BB26(0.579,-8.874) BB30(2.586,-8.897) BB34(4.224,-8.795) BB36(5.621,-8.795) BB39(6.866,-8.795) BB41(8.024,-8.774) BB43(8.589,-9) BB44(9.088,-8.706) BC5(-9.634,-9.254) BC45(9.634,-9.254) BD1(-11.814,-9.959) BD4(-10.474,-9.983) BD46(10.474,-9.983) BD49(11.814,-9.959) BE1(-11.814,-10.459) BE2(-11.373,-10.196) BE3(-10.86,-10.311) BE4(-10.391,-10.487) BE5(-9.965,-10.212) BE45(9.965,-10.212) BE46(10.391,-10.487) BE47(10.86,-10.311) BE48(11.373,-10.196) BE49(11.814,-10.459) BF1(-11.814,-10.96) BF2(-11.33,-10.83) BF3(-10.709,-10.878) BF47(10.709,-10.878) BF48(11.33,-10.83) BF49(11.814,-10.96) BG2(-11.46,-11.314) BG3(-10.959,-11.314) BG4(-10.459,-11.314) BG46(10.459,-11.314) BG47(10.959,-11.314) BG48(11.46,-11.314) C1(-11.814,10.459) C2(-11.373,10.196) C3(-10.86,10.311) C4(-10.391,10.487) C5(-9.965,10.212) C45(9.965,10.212) C46(10.391,10.487) C47(10.86,10.311) C48(11.373,10.196) C49(11.814,10.459) D1(-11.814,9.959) D4(-10.474,9.983) D46(10.474,9.983) D49(11.814,9.959) E5(-9.634,9.254) E45(9.634,9.254) F6(-9.088,8.706) F7(-8.589,9) F9(-8.024,8.774) F11(-6.866,8.795) F14(-5.621,8.795) F16(-4.224,8.795) F20(-2.586,8.897) F24(-0.579,8.874) F26(0.579,8.874) F30(2.586,8.897) F34(4.224,8.795) F36(5.621,8.795) F39(6.866,8.795) F41(8.024,8.774) F43(8.589,9) F44(9.088,8.706) G6(-9.13,8.203) G12(-6.485,8.135) G14(-5.24,8.135) G17(-3.843,8.135) G20(-2.395,8.158) G24(-0.579,8.112) G26(0.579,8.112) G30(2.395,8.158) G33(3.843,8.135) G36(5.24,8.135) G38(6.485,8.135) G44(9.13,8.203) H8(-8.533,7.898) H42(8.533,7.898) J9(-7.824,7.577) J10(-7.262,7.509) J13(-6.01,7.49) J15(-4.892,7.452) J18(-3.495,7.413) J21(-2.205,7.419) J24(-0.579,7.35) J26(0.579,7.35) J29(2.205,7.419) J32(3.495,7.413) J35(4.892,7.452) J37(6.01,7.49) J40(7.262,7.509) J41(7.824,7.577) K6(-9.295,7.094) K7(-8.597,6.764) K11(-7.079,6.975) K13(-5.748,6.757) K16(-4.656,6.719) K18(-3.259,6.68) K21(-2.014,6.679) K29(2.014,6.679) K32(3.259,6.68) K34(4.656,6.719) K37(5.748,6.757) K39(7.079,6.975) K43(8.597,6.764) K44(9.295,7.094) L9(-7.914,6.416) L24(-0.579,6.588) L26(0.579,6.588) L41(7.914,6.416) M6(-9.295,5.659) M10(-7.181,5.773) M16(-4.351,5.944) M18(-3.259,5.918) M21(-2.014,5.902) M24(-0.579,5.826) M26(0.579,5.826) M29(2.014,5.902) M32(3.259,5.918) M34(4.351,5.944) M40(7.181,5.773) M44(9.295,5.659) N8(-8.508,5.469) N12(-6.444,5.443) N13(-5.682,5.443) N15(-4.92,5.443) N16(-4.351,5.182) N18(-3.259,5.156) N32(3.259,5.156) N34(4.351,5.182) N35(4.92,5.443) N37(5.682,5.443) N38(6.444,5.443) N42(8.508,5.469) P9(-7.914,4.968) P21(-2.014,5.064) P24(-0.579,5.064) P26(0.579,5.064) P29(2.014,5.064) P41(7.914,4.968) R6(-9.295,4.224) R10(-7.181,4.656) R12(-6.444,4.351) R13(-5.682,4.351) R15(-4.92,4.351) R16(-4.351,4.394) R18(-3.259,4.394) R21(-2.014,4.289) R24(-0.579,4.302) R26(0.579,4.302) R29(2.014,4.289) R32(3.259,4.394) R34(4.351,4.394) R35(4.92,4.351) R37(5.682,4.351) R38(6.444,4.351) R40(7.181,4.656) R44(9.295,4.224) T7(-8.635,3.843) T17(-3.811,3.683) T18(-3.259,3.683) T32(3.259,3.683) T43(8.635,3.843) U9(-7.914,3.495) U10(-7.181,3.259) U12(-6.419,3.259) U13(-5.657,3.259) U15(-4.895,3.259) U17(-4.133,3.259) U21(-2.014,3.578) U24(-0.579,3.591) U26(0.579,3.591) U29(2.014,3.578) U33(4.133,3.259) U35(4.895,3.259) U37(5.657,3.259) U38(6.419,3.259) U40(7.181,3.259) U41(7.914,3.495) V19(-3.099,3.099) V20(-2.324,3.099) V22(-1.549,3.099) V23(-0.775,3.099) V25(0,3.099) V27(0.775,3.099) V28(1.549,3.099) V30(2.324,3.099) V31(3.099,3.099) W6(-9.397,2.586) W7(-8.658,2.395) W19(-3.099,2.324) W20(-2.324,2.324) W22(-1.549,2.324) W23(-0.775,2.324) W25(0,2.324) W27(0.775,2.324) W28(1.549,2.324) W30(2.324,2.324) W31(3.099,2.324) W43(8.658,2.395) W44(9.397,2.586) Y9(-7.919,2.205) Y10(-7.18,2.014) Y12(-6.402,2.014) Y14(-5.564,2.014) Y15(-4.789,2.014) Y17(-4.027,2.014) Y33(4.027,2.014) Y35(4.789,2.014) Y36(5.564,2.014) Y38(6.402,2.014) Y40(7.18,2.014) Y41(7.919,2.205)
  round 0.279 smd: A5(-9.958,11.314) A45(9.958,11.314) BC1(-11.814,-9.458) BC49(11.814,-9.458) BG5(-9.958,-11.314) BG45(9.958,-11.314) E1(-11.814,9.458) E49(11.814,9.458)
  oval 0.203x0.254 smd: A6(-9.399,11.314) A8(-8.294,11.314) A42(8.294,11.314) A44(9.399,11.314) BD8(-8.411,-9.813) BD12(-6.214,-9.813) BD17(-4.017,-9.813) BD21(-1.82,-9.813) BD29(1.82,-9.813) BD33(4.017,-9.813) BD38(6.214,-9.813) BD42(8.411,-9.813) BE9(-7.784,-10.186) BE10(-7.283,-10.059) BE14(-5.587,-10.186) BE15(-5.086,-10.059) BE18(-3.39,-10.186) BE19(-2.889,-10.059) BE23(-1.193,-10.186) BE24(-0.692,-10.059) BE26(0.692,-10.059) BE27(1.193,-10.186) BE31(2.889,-10.059) BE32(3.39,-10.186) BE35(5.086,-10.059) BE36(5.587,-10.186) BE40(7.283,-10.059) BE41(7.784,-10.186) BG6(-9.399,-11.314) BG8(-8.294,-11.314) BG42(8.294,-11.314) BG44(9.399,-11.314) C9(-7.784,10.186) C10(-7.283,10.059) C14(-5.587,10.186) C15(-5.086,10.059) C18(-3.39,10.186) C19(-2.889,10.059) C23(-1.193,10.186) C24(-0.692,10.059) C26(0.692,10.059) C27(1.193,10.186) C31(2.889,10.059) C32(3.39,10.186) C35(5.086,10.059) C36(5.587,10.186) C40(7.283,10.059) C41(7.784,10.186) D8(-8.411,9.813) D12(-6.214,9.813) D17(-4.017,9.813) D21(-1.82,9.813) D29(1.82,9.813) D33(4.017,9.813) D38(6.214,9.813) D42(8.411,9.813)
  oval 0.152x0.254 smd: A13(-6.072,11.314) A17(-3.875,11.314) A22(-1.678,11.314) A25(0,11.314) A28(1.678,11.314) A33(3.875,11.314) A37(6.072,11.314) B10(-7.123,10.603) B12(-6.265,10.816) B14(-5.587,10.687) B15(-4.926,10.603) B17(-4.068,10.816) B18(-3.39,10.687) B19(-2.729,10.603) B21(-1.871,10.816) B23(-1.193,10.687) B24(-0.532,10.603) B25(0,10.806) B26(0.532,10.603) B27(1.193,10.687) B29(1.871,10.816) B31(2.729,10.603) B32(3.39,10.687) B33(4.068,10.816) B35(4.926,10.603) B36(5.587,10.687) B38(6.265,10.816) B40(7.123,10.603) BE11(-6.76,-10.118) BE12(-6.295,-10.313) BE16(-4.563,-10.118) BE17(-4.098,-10.313) BE20(-2.366,-10.118) BE21(-1.901,-10.313) BE25(0,-10.298) BE29(1.901,-10.313) BE30(2.366,-10.118) BE33(4.098,-10.313) BE34(4.563,-10.118) BE38(6.295,-10.313) BE39(6.76,-10.118) BF10(-7.123,-10.603) BF12(-6.265,-10.816) BF14(-5.587,-10.687) BF15(-4.926,-10.603) BF17(-4.068,-10.816) BF18(-3.39,-10.687) BF19(-2.729,-10.603) BF21(-1.871,-10.816) BF23(-1.193,-10.687) BF24(-0.532,-10.603) BF25(0,-10.806) BF26(0.532,-10.603) BF27(1.193,-10.687) BF29(1.871,-10.816) BF31(2.729,-10.603) BF32(3.39,-10.687) BF33(4.068,-10.816) BF35(4.926,-10.603) BF36(5.587,-10.687) BF38(6.265,-10.816) BF40(7.123,-10.603) BG13(-6.072,-11.314) BG17(-3.875,-11.314) BG22(-1.678,-11.314) BG25(0,-11.314) BG28(1.678,-11.314) BG33(3.875,-11.314) BG37(6.072,-11.314) C11(-6.76,10.118) C12(-6.295,10.313) C16(-4.563,10.118) C17(-4.098,10.313) C20(-2.366,10.118) C21(-1.901,10.313) C25(0,10.298) C29(1.901,10.313) C30(2.366,10.118) C33(4.098,10.313) C34(4.563,10.118) C38(6.295,10.313) C39(6.76,10.118)
  oval 0.254x0.152 smd: AA1(-11.814,1.678) AA49(11.814,1.678) AB2(-11.187,1.193) AB48(11.187,1.193) AC2(-11.103,0.532) AC48(11.103,0.532) AD1(-11.814,0) AD2(-11.306,0) AD3(-10.798,0) AD47(10.798,0) AD48(11.306,0) AD49(11.814,0) AE2(-11.103,-0.532) AE48(11.103,-0.532) AF2(-11.187,-1.193) AF48(11.187,-1.193) AG1(-11.814,-1.678) AG49(11.814,-1.678) AH2(-11.316,-1.871) AH3(-10.813,-1.901) AH47(10.813,-1.901) AH48(11.316,-1.871) AJ3(-10.618,-2.366) AJ47(10.618,-2.366) AK2(-11.103,-2.729) AK48(11.103,-2.729) AL2(-11.187,-3.39) AL48(11.187,-3.39) AM1(-11.814,-3.875) AM2(-11.316,-4.068) AM3(-10.813,-4.098) AM47(10.813,-4.098) AM48(11.316,-4.068) AM49(11.814,-3.875) AN3(-10.618,-4.563) AN47(10.618,-4.563) AP2(-11.103,-4.926) AP48(11.103,-4.926) P2(-11.103,4.926) P48(11.103,4.926) R3(-10.618,4.563) R47(10.618,4.563) T1(-11.814,3.875) T2(-11.316,4.068) T3(-10.813,4.098) T47(10.813,4.098) T48(11.316,4.068) T49(11.814,3.875) U2(-11.187,3.39) U48(11.187,3.39) V2(-11.103,2.729) V48(11.103,2.729) W3(-10.618,2.366) W47(10.618,2.366) Y2(-11.316,1.871) Y3(-10.813,1.901) Y47(10.813,1.901) Y48(11.316,1.871)
  round 0.254 smd: AA5(-9.856,1.601) AA45(9.856,1.601) AC4(-10.06,0.579) AC46(10.06,0.579) AE4(-10.06,-0.579) AE46(10.06,-0.579) AG5(-9.856,-1.601) AG45(9.856,-1.601) AJ4(-10.098,-2.274) AJ46(10.098,-2.274) AK4(-10.06,-2.776) AK46(10.06,-2.776) AM5(-9.856,-3.799) AM45(9.856,-3.799) AN4(-10.098,-4.471) AN46(10.098,-4.471) AP4(-10.06,-4.973) AP46(10.06,-4.973) AT5(-9.856,-5.996) AT45(9.856,-5.996) AV4(-10.098,-6.669) AV46(10.098,-6.669) AW4(-10.06,-7.17) AW46(10.06,-7.17) B6(-9.397,10.811) B44(9.397,10.811) BA2(-11.316,-8.526) BA3(-10.809,-8.594) BA4(-10.304,-8.468) BA5(-9.856,-8.193) BA45(9.856,-8.193) BA46(10.304,-8.468) BA47(10.809,-8.594) BA48(11.316,-8.526) BB3(-11.318,-9.315) BB4(-10.825,-9.126) BB46(10.825,-9.126) BB47(11.318,-9.315) BC8(-8.193,-9.356) BC10(-7.17,-9.56) BC13(-5.996,-9.356) BC15(-4.973,-9.56) BC17(-3.799,-9.356) BC19(-2.776,-9.56) BC22(-1.601,-9.356) BC24(-0.579,-9.56) BC26(0.579,-9.56) BC28(1.601,-9.356) BC31(2.776,-9.56) BC33(3.799,-9.356) BC35(4.973,-9.56) BC37(5.996,-9.356) BC40(7.17,-9.56) BC42(8.193,-9.356) BD7(-8.914,-9.872) BD11(-6.669,-9.598) BD16(-4.471,-9.598) BD20(-2.274,-9.598) BD30(2.274,-9.598) BD34(4.471,-9.598) BD39(6.669,-9.598) BD43(8.914,-9.872) BE6(-9.091,-10.357) BE44(9.091,-10.357) BF6(-9.397,-10.811) BF44(9.397,-10.811) C6(-9.091,10.357) C44(9.091,10.357) D7(-8.914,9.872) D11(-6.669,9.598) D16(-4.471,9.598) D20(-2.274,9.598) D30(2.274,9.598) D34(4.471,9.598) D39(6.669,9.598) D43(8.914,9.872) E8(-8.193,9.356) E10(-7.17,9.56) E13(-5.996,9.356) E15(-4.973,9.56) E17(-3.799,9.356) E19(-2.776,9.56) E22(-1.601,9.356) E24(-0.579,9.56) E26(0.579,9.56) E28(1.601,9.356) E31(2.776,9.56) E33(3.799,9.356) E35(4.973,9.56) E37(5.996,9.356) E40(7.17,9.56) E42(8.193,9.356) F3(-11.318,9.315) F4(-10.825,9.126) F46(10.825,9.126) F47(11.318,9.315) G2(-11.316,8.526) G3(-10.809,8.594) G4(-10.304,8.468) G5(-9.856,8.193) G45(9.856,8.193) G46(10.304,8.468) G47(10.809,8.594) G48(11.316,8.526) J4(-10.06,7.17) J46(10.06,7.17) K4(-10.098,6.669) K46(10.098,6.669) M5(-9.856,5.996) M45(9.856,5.996) P4(-10.06,4.973) P46(10.06,4.973) R4(-10.098,4.471) R46(10.098,4.471) T5(-9.856,3.799) T45(9.856,3.799) V4(-10.06,2.776) V46(10.06,2.776) W4(-10.098,2.274) W46(10.098,2.274)
  oval 0.254x0.203 smd: AB3(-10.686,1.193) AB47(10.686,1.193) AC3(-10.559,0.692) AC47(10.559,0.692) AE3(-10.559,-0.692) AE47(10.559,-0.692) AF3(-10.686,-1.193) AF47(10.686,-1.193) AH4(-10.313,-1.82) AH46(10.313,-1.82) AK3(-10.559,-2.883) AK47(10.559,-2.883) AL3(-10.686,-3.39) AL47(10.686,-3.39) AM4(-10.313,-4.017) AM46(10.313,-4.017) AP3(-10.559,-5.08) AP47(10.559,-5.08) AR3(-10.686,-5.587) AR47(10.686,-5.587) AT1(-11.814,-6.097) AT49(11.814,-6.097) AU4(-10.313,-6.214) AU46(10.313,-6.214) AW3(-10.559,-7.277) AW47(10.559,-7.277) AY3(-10.686,-7.784) AY47(10.686,-7.784) BA1(-11.814,-8.32) BA49(11.814,-8.32) G1(-11.814,8.32) G49(11.814,8.32) H3(-10.686,7.784) H47(10.686,7.784) J3(-10.559,7.277) J47(10.559,7.277) L4(-10.313,6.214) L46(10.313,6.214) M1(-11.814,6.097) M49(11.814,6.097) N3(-10.686,5.587) N47(10.686,5.587) P3(-10.559,5.08) P47(10.559,5.08) T4(-10.313,4.017) T46(10.313,4.017) U3(-10.686,3.39) U47(10.686,3.39) V3(-10.559,2.883) V47(10.559,2.883) Y4(-10.313,1.82) Y46(10.313,1.82)
  oval 0.305x0.152 smd: AR2(-11.187,-5.587) AR48(11.187,-5.587) AU2(-11.316,-6.265) AU3(-10.813,-6.295) AU47(10.813,-6.295) AU48(11.316,-6.265) AV3(-10.618,-6.76) AV47(10.618,-6.76) AW2(-11.103,-7.123) AW48(11.103,-7.123) AY2(-11.187,-7.784) AY48(11.187,-7.784) H2(-11.187,7.784) H48(11.187,7.784) J2(-11.103,7.123) J48(11.103,7.123) K3(-10.618,6.76) K47(10.618,6.76) L2(-11.316,6.265) L3(-10.813,6.295) L47(10.813,6.295) L48(11.316,6.265) N2(-11.187,5.587) N48(11.187,5.587)
  oval 0.152x0.305 smd: B8(-8.462,10.816) B9(-7.784,10.687) B41(7.784,10.687) B42(8.462,10.816) BE8(-8.492,-10.313) BE42(8.492,-10.313) BF8(-8.462,-10.816) BF9(-7.784,-10.687) BF41(7.784,-10.687) BF42(8.462,-10.816) C8(-8.492,10.313) C42(8.492,10.313)
C402H22
  custom 0.152x0.152 smd: 1(0,0.445) 2(0,-0.445)
C603H35
  custom 0.216x0.216 smd: 1(0,0.762) 2(0,-0.762)
C603H36
  custom 0.216x0.216 smd: 1(0,0.762) 2(0,-0.762)
C603H40
  custom 0.216x0.216 smd: 1(0,0.762) 2(0,-0.762)
C805H50
  rect 1.397x1.143 smd: 1(0,0.965) 2(0,-0.965)
C805H54
  rect 1.397x1.143 smd: 1(0,0.965) 2(0,-0.965)
C805H56
  rect 1.397x1.143 smd: 1(0,0.965) 2(0,-0.965)
C805H58
  rect 1.397x1.143 smd: 1(0,0.965) 2(0,-0.965)
D4626-D914AKH44
  rect 1.651x1.778 smd: A(0,2.035) K(0,-2.035)
D5126145AKH91
  rect 1.702x2.032 smd: A(0,2.172) K(0,-2.172)
DFN8G2-G1309-UH40
  rect 0.305x0.737 smd: 1(0.75,1.018) 2(0.25,1.018) 3(-0.25,1.018) 4(-0.75,1.018) 5(-0.75,-1.018) 6(-0.25,-1.018) 7(0.25,-1.018) 8(0.75,-1.018)
  rect 1.295x0.889 smd: 9(0,0)
DFN10G3-G265175H32
  rect 0.305x0.914 smd: 1(1,1.549) 2(0.5,1.549) 3(0,1.549) 4(-0.5,1.549) 5(-1,1.549) 6(-1,-1.549) 7(-0.5,-1.549) 8(0,-1.549) 9(0.5,-1.549) 10(1,-1.549)
  rect 2.642x1.753 smd: 11(0,0)
DFN10G2510H26
  rect 0.305x0.787 smd: 1(1,0.494) 5(-1,0.494) 6(-1,-0.494) 10(1,-0.494)
  rect 0.254x0.787 smd: 2(0.521,0.494) 4(-0.521,0.494) 7(-0.521,-0.494) 9(0.521,-0.494)
  rect 0.025x0.025 smd: 3(0,0.494)
  rect 0.406x1.753 smd: 8(0,-0.494)
DM-BSH-03001-FDA-01
  round 0.254 hole 1.016 unplated: (-10.065,0) (10.065,0)
  rect 0.279x2.769 smd: 1(-7.25,-5.526) 2(-7.25,0.198) 3(-6.75,-5.526) 4(-6.75,0.198) 5(-6.25,-5.526) 6(-6.25,0.198) 7(-5.751,-5.526) 8(-5.751,0.198) 9(-5.25,-5.526) 10(-5.25,0.198) 11(-4.75,-5.526) 12(-4.75,0.198) 13(-4.249,-5.526) 14(-4.249,0.198) 15(-3.75,-5.526) 16(-3.75,0.198) 17(-3.25,-5.526) 18(-3.25,0.198) 19(-2.75,-5.526) 20(-2.75,0.198) 21(-2.25,-5.526) 22(-2.25,0.198) 23(-1.75,-5.526) 24(-1.75,0.198) 25(-1.25,-5.526) 26(-1.25,0.198) 27(-0.751,-5.526) 28(-0.751,0.198) 29(-0.25,-5.526) 30(-0.25,0.198) 31(0.25,-5.526) 32(0.25,0.198) 33(0.751,-5.526) 34(0.751,0.198) 35(1.25,-5.526) 36(1.25,0.198) 37(1.75,-5.526) 38(1.75,0.198) 39(2.25,-5.526) 40(2.25,0.198) 41(2.75,-5.526) 42(2.75,0.198) 43(3.25,-5.526) 44(3.25,0.198) 45(3.75,-5.526) 46(3.75,0.198) 47(4.249,-5.526) 48(4.249,0.198) 49(4.75,-5.526) 50(4.75,0.198) 51(5.25,-5.526) 52(5.25,0.198) 53(5.751,-5.526) 54(5.751,0.198) 55(6.25,-5.526) 56(6.25,0.198) 57(6.75,-5.526) 58(6.75,0.198) 59(7.25,-5.526) 60(7.25,0.198)
ECAP-100D6D3H375
  rect 1.397x1.397 hole 0.991: 1(0,-1.27)
  round 1.397 hole 0.991: 2(0,1.27)
ECAP-100D6D3H493
  rect 1.397x1.397 hole 0.991: 1(0,-1.27)
  round 1.397 hole 0.991: 2(0,1.27)
ECAP-138D8-UH355
  rect 1.397x1.397 hole 0.991: 1(0,-1.75)
  round 1.397 hole 0.991: 2(0,1.75)
GAP-CLOSE-PWR-2U
  rect 0.521x0.61 smd: 1(-0.235,0) 2(0.235,0)
GAP-CLOSE-PWR-3
  rect 0.66x0.762 smd: 1(-0.305,0) 2(0.305,0)
GEN315R158-8-F-C-S-U
  round 0.254 hole 4.013 unplated: (0,0)
  round 0.864 hole 0.508: 1(3.189,0.634) 2(1.806,2.703) 3(-0.634,3.189) 4(-2.703,1.806) 5(-3.189,-0.634) 6(-1.806,-2.703) 7(0.634,-3.189) 8(2.703,-1.806)
HB9603E-DW
  round 1.397 hole 0.991: 1(-2.54,0) 2(2.54,0)
HF2704F-RM1
  round 0.254 hole 1.27 unplated: (-1.27,-2.16)
  round 1.422 hole 1.016: 1(3.81,0) 2(1.27,0) 3(-1.27,0) 4(-3.81,0)
HM3502E-P1
  round 0.254 hole 3.023 unplated: (-6.8,-2.29)
  round 2.184 hole 1.422: 1(-2.1,2.75) 2(2.1,2.75) 3(-2.1,-2.75) 4(2.1,-2.75)
L402H24
  custom 0.14x0.14 smd: 1(0,0.445) 2(0,-0.445)
L603H38
  custom 0.216x0.216 smd: 1(0,0.762) 2(0,-0.762)
L805H44
  rect 1.397x1.143 smd: 1(0,0.965) 2(0,-0.965)
L1608-UH38
  custom 0.216x0.216 smd: 1(0,0.762) 2(0,-0.762)
L6060-6018H186
  rect 6.248x2.438 smd: 1(0,2.165) 2(0,-2.165)
L7066-1830-UH119
  rect 3.505x2.921 smd: 1(0,2.78) 2(0,-2.78)
L115100-2030H158
  rect 3.251x2.896 smd: 1(0,4.944) 2(0,-4.944)
L125100-4PH24
  rect 0.457x0.838 smd: 1(-0.326,-0.587) 2(0.326,-0.587) 3(0.326,0.587) 4(-0.326,0.587)
L125100-4PH26
  rect 0.457x0.838 smd: 1(-0.326,-0.587) 2(0.326,-0.587) 3(0.326,0.587) 4(-0.326,0.587)
LE18077-Z55D-4F
  round 0.991 hole 0.635: 1(3.81,0) 2(2.755,1.5) 3(1.055,1.5) 4(0,0) 5(-1.055,1.5) 6(-2.755,1.5) 7(-3.81,0)
  round 1.854 hole 1.372: 8(6.29,0) 9(-6.54,1)
LED3640AK-1H160
  rect 3.556x1.499 smd: A(-0.254,1.27) K(-0.254,-1.27)
LQFP48H63
  rect 0.305x1.524 smd: 1(2.75,4.242) 2(2.25,4.242) 3(1.75,4.242) 4(1.25,4.242) 5(0.751,4.242) 6(0.25,4.242) 7(-0.25,4.242) 8(-0.751,4.242) 9(-1.25,4.242) 10(-1.75,4.242) 11(-2.25,4.242) 12(-2.75,4.242) 25(-2.75,-4.242) 26(-2.25,-4.242) 27(-1.75,-4.242) 28(-1.25,-4.242) 29(-0.751,-4.242) 30(-0.25,-4.242) 31(0.25,-4.242) 32(0.751,-4.242) 33(1.25,-4.242) 34(1.75,-4.242) 35(2.25,-4.242) 36(2.75,-4.242)
  rect 1.524x0.305 smd: 13(-4.242,2.75) 14(-4.242,2.25) 15(-4.242,1.75) 16(-4.242,1.25) 17(-4.242,0.751) 18(-4.242,0.25) 19(-4.242,-0.25) 20(-4.242,-0.751) 21(-4.242,-1.25) 22(-4.242,-1.75) 23(-4.242,-2.25) 24(-4.242,-2.75) 37(4.242,-2.75) 38(4.242,-2.25) 39(4.242,-1.75) 40(4.242,-1.25) 41(4.242,-0.751) 42(4.242,-0.25) 43(4.242,0.25) 44(4.242,0.751) 45(4.242,1.25) 46(4.242,1.75) 47(4.242,2.25) 48(4.242,2.75)
LQFP128H63
  rect 0.203x1.524 smd: 1(6.2,7.747) 2(5.8,7.747) 3(5.4,7.747) 4(5,7.747) 5(4.6,7.747) 6(4.2,7.747) 7(3.8,7.747) 8(3.4,7.747) 9(3,7.747) 10(2.6,7.747) 11(2.2,7.747) 12(1.8,7.747) 13(1.4,7.747) 14(0.999,7.747) 15(0.599,7.747) 16(0.199,7.747) 17(-0.199,7.747) 18(-0.599,7.747) 19(-0.999,7.747) 20(-1.4,7.747) 21(-1.8,7.747) 22(-2.2,7.747) 23(-2.6,7.747) 24(-3,7.747) 25(-3.4,7.747) 26(-3.8,7.747) 27(-4.2,7.747) 28(-4.6,7.747) 29(-5,7.747) 30(-5.4,7.747) 31(-5.8,7.747) 32(-6.2,7.747) 65(-6.2,-7.747) 66(-5.8,-7.747) 67(-5.4,-7.747) 68(-5,-7.747) 69(-4.6,-7.747) 70(-4.2,-7.747) 71(-3.8,-7.747) 72(-3.4,-7.747) 73(-3,-7.747) 74(-2.6,-7.747) 75(-2.2,-7.747) 76(-1.8,-7.747) 77(-1.4,-7.747) 78(-0.999,-7.747) 79(-0.599,-7.747) 80(-0.199,-7.747) 81(0.199,-7.747) 82(0.599,-7.747) 83(0.999,-7.747) 84(1.4,-7.747) 85(1.8,-7.747) 86(2.2,-7.747) 87(2.6,-7.747) 88(3,-7.747) 89(3.4,-7.747) 90(3.8,-7.747) 91(4.2,-7.747) 92(4.6,-7.747) 93(5,-7.747) 94(5.4,-7.747) 95(5.8,-7.747) 96(6.2,-7.747)
  rect 1.524x0.203 smd: 33(-7.747,6.2) 34(-7.747,5.8) 35(-7.747,5.4) 36(-7.747,5) 37(-7.747,4.6) 38(-7.747,4.2) 39(-7.747,3.8) 40(-7.747,3.4) 41(-7.747,3) 42(-7.747,2.6) 43(-7.747,2.2) 44(-7.747,1.8) 45(-7.747,1.4) 46(-7.747,0.999) 47(-7.747,0.599) 48(-7.747,0.199) 49(-7.747,-0.199) 50(-7.747,-0.599) 51(-7.747,-0.999) 52(-7.747,-1.4) 53(-7.747,-1.8) 54(-7.747,-2.2) 55(-7.747,-2.6) 56(-7.747,-3) 57(-7.747,-3.4) 58(-7.747,-3.8) 59(-7.747,-4.2) 60(-7.747,-4.6) 61(-7.747,-5) 62(-7.747,-5.4) 63(-7.747,-5.8) 64(-7.747,-6.2) 97(7.747,-6.2) 98(7.747,-5.8) 99(7.747,-5.4) 100(7.747,-5) 101(7.747,-4.6) 102(7.747,-4.2) 103(7.747,-3.8) 104(7.747,-3.4) 105(7.747,-3) 106(7.747,-2.6) 107(7.747,-2.2) 108(7.747,-1.8) 109(7.747,-1.4) 110(7.747,-0.999) 111(7.747,-0.599) 112(7.747,-0.199) 113(7.747,0.199) 114(7.747,0.599) 115(7.747,0.999) 116(7.747,1.4) 117(7.747,1.8) 118(7.747,2.2) 119(7.747,2.6) 120(7.747,3) 121(7.747,3.4) 122(7.747,3.8) 123(7.747,4.2) 124(7.747,4.6) 125(7.747,5) 126(7.747,5.4) 127(7.747,5.8) 128(7.747,6.2)
NTC-402H24-U
  custom 0.14x0.14 smd: 1(0,0.445) 2(0,-0.445)
OSC-3225-4P-3H36
  rect 1.397x0.914 smd: 1(-1.171,-0.825) 2(1.171,-0.825) 3(1.171,0.825) 4(-1.171,0.825)
P254-1104A0ADKP-W
  round 0.254 hole 1.27 unplated: (-1.27,-2.16)
  round 1.422 hole 1.016: 1(3.81,0) 2(1.27,0) 3(-1.27,0) 4(-3.81,0)
PFPCC128-5H48
  rect 0.203x1.524 smd: 1(6.2,7.747) 2(5.8,7.747) 3(5.4,7.747) 4(5,7.747) 5(4.6,7.747) 6(4.2,7.747) 7(3.8,7.747) 8(3.4,7.747) 9(3,7.747) 10(2.6,7.747) 11(2.2,7.747) 12(1.8,7.747) 13(1.4,7.747) 14(0.999,7.747) 15(0.599,7.747) 16(0.199,7.747) 17(-0.199,7.747) 18(-0.599,7.747) 19(-0.999,7.747) 20(-1.4,7.747) 21(-1.8,7.747) 22(-2.2,7.747) 23(-2.6,7.747) 24(-3,7.747) 25(-3.4,7.747) 26(-3.8,7.747) 27(-4.2,7.747) 28(-4.6,7.747) 29(-5,7.747) 30(-5.4,7.747) 31(-5.8,7.747) 32(-6.2,7.747) 65(-6.2,-7.747) 66(-5.8,-7.747) 67(-5.4,-7.747) 68(-5,-7.747) 69(-4.6,-7.747) 70(-4.2,-7.747) 71(-3.8,-7.747) 72(-3.4,-7.747) 73(-3,-7.747) 74(-2.6,-7.747) 75(-2.2,-7.747) 76(-1.8,-7.747) 77(-1.4,-7.747) 78(-0.999,-7.747) 79(-0.599,-7.747) 80(-0.199,-7.747) 81(0.199,-7.747) 82(0.599,-7.747) 83(0.999,-7.747) 84(1.4,-7.747) 85(1.8,-7.747) 86(2.2,-7.747) 87(2.6,-7.747) 88(3,-7.747) 89(3.4,-7.747) 90(3.8,-7.747) 91(4.2,-7.747) 92(4.6,-7.747) 93(5,-7.747) 94(5.4,-7.747) 95(5.8,-7.747) 96(6.2,-7.747)
  rect 1.524x0.203 smd: 33(-7.747,6.2) 34(-7.747,5.8) 35(-7.747,5.4) 36(-7.747,5) 37(-7.747,4.6) 38(-7.747,4.2) 39(-7.747,3.8) 40(-7.747,3.4) 41(-7.747,3) 42(-7.747,2.6) 43(-7.747,2.2) 44(-7.747,1.8) 45(-7.747,1.4) 46(-7.747,0.999) 47(-7.747,0.599) 48(-7.747,0.199) 49(-7.747,-0.199) 50(-7.747,-0.599) 51(-7.747,-0.999) 52(-7.747,-1.4) 53(-7.747,-1.8) 54(-7.747,-2.2) 55(-7.747,-2.6) 56(-7.747,-3) 57(-7.747,-3.4) 58(-7.747,-3.8) 59(-7.747,-4.2) 60(-7.747,-4.6) 61(-7.747,-5) 62(-7.747,-5.4) 63(-7.747,-5.8) 64(-7.747,-6.2) 97(7.747,-6.2) 98(7.747,-5.8) 99(7.747,-5.4) 100(7.747,-5) 101(7.747,-4.6) 102(7.747,-4.2) 103(7.747,-3.8) 104(7.747,-3.4) 105(7.747,-3) 106(7.747,-2.6) 107(7.747,-2.2) 108(7.747,-1.8) 109(7.747,-1.4) 110(7.747,-0.999) 111(7.747,-0.599) 112(7.747,-0.199) 113(7.747,0.199) 114(7.747,0.599) 115(7.747,0.999) 116(7.747,1.4) 117(7.747,1.8) 118(7.747,2.2) 119(7.747,2.6) 120(7.747,3) 121(7.747,3.4) 122(7.747,3.8) 123(7.747,4.2) 124(7.747,4.6) 125(7.747,5) 126(7.747,5.4) 127(7.747,5.8) 128(7.747,6.2)
POLYSW-2114H30
  rect 1.6x0.965 smd: 1(0,0.94) 2(0,-0.94)
PPAK-8P-3232H36
  rect 0.406x0.914 smd: 1(-0.975,-2.396) 2(-0.325,-2.396) 3(0.325,-2.396) 4(0.975,-2.396)
  rect 3.353x2.692 smd: 5(0,0)
  rect 0.025x0.025 smd: 6(0.65,0.838) 7(0,0.838) 8(-0.65,0.838)
PPAK-8P-5262H40
  rect 0.762x1.448 smd: 1(-1.905,-3.684) 2(-0.635,-3.684) 3(0.635,-3.684) 4(1.905,-3.684)
  rect 5.512x5.309 smd: 5(1.543,1.492)
  rect 0.025x0.025 smd: 6(-1.543,1.492) 7(-1.543,-1.492) 8(1.543,-1.492)
PPAK-8P-G5324H44-COLAY
  rect 0.762x1.016 smd: 1(-1.905,-3.01) 2(-0.635,-3.01) 3(0.635,-3.01) 4(1.905,-3.01) 5(1.905,3.01) 6(0.635,3.01) 7(-0.635,3.01) 8(-1.905,3.01)
  rect 5.207x2.896 smd: 9(0,0.65)
  rect 5.207x0.787 smd: 10(0,-1.7)
QFN20-G1D75H32
  rect 0.203x0.914 smd: 1(0.8,1.551) 2(0.4,1.551) 3(0,1.551) 4(-0.4,1.551) 5(-0.8,1.551) 11(-0.8,-1.551) 12(-0.4,-1.551) 13(0,-1.551) 14(0.4,-1.551) 15(0.8,-1.551)
  rect 0.914x0.203 smd: 6(-1.551,0.8) 7(-1.551,0.4) 8(-1.551,0) 9(-1.551,-0.4) 10(-1.551,-0.8) 16(1.551,-0.8) 17(1.551,-0.4) 18(1.551,0) 19(1.551,0.4) 20(1.551,0.8)
  rect 1.753x1.753 smd: 21(0,0)
QFN24-G2D5H40-U
  rect 0.305x0.838 smd: 1(1.25,2.095) 6(-1.25,2.095) 13(-1.25,-2.095) 18(1.25,-2.095)
  rect 0.305x0.965 smd: 2(0.751,2.032) 3(0.25,2.032) 4(-0.25,2.032) 5(-0.751,2.032) 14(-0.751,-2.032) 15(-0.25,-2.032) 16(0.25,-2.032) 17(0.751,-2.032)
  rect 0.838x0.305 smd: 7(-2.095,1.25) 12(-2.095,-1.25) 19(2.095,-1.25) 24(2.095,1.25)
  rect 0.965x0.305 smd: 8(-2.032,0.751) 9(-2.032,0.25) 10(-2.032,-0.25) 11(-2.032,-0.751) 20(2.032,-0.751) 21(2.032,-0.25) 22(2.032,0.25) 23(2.032,0.751)
  rect 2.489x2.489 smd: 25(0,0)
QFN32G5-G3D6H32
  rect 0.305x0.914 smd: 1(1.75,2.551) 8(-1.75,2.551) 17(-1.75,-2.551) 24(1.75,-2.551)
  rect 0.305x0.991 smd: 2(1.25,2.513) 3(0.75,2.513) 4(0.25,2.513) 5(-0.25,2.513) 6(-0.75,2.513) 7(-1.25,2.513) 18(-1.25,-2.513) 19(-0.75,-2.513) 20(-0.25,-2.513) 21(0.25,-2.513) 22(0.75,-2.513) 23(1.25,-2.513)
  rect 0.914x0.305 smd: 9(-2.551,1.75) 16(-2.551,-1.75) 25(2.551,-1.75) 32(2.551,1.75)
  rect 0.991x0.305 smd: 10(-2.513,1.25) 11(-2.513,0.75) 12(-2.513,0.25) 13(-2.513,-0.25) 14(-2.513,-0.75) 15(-2.513,-1.25) 26(2.513,-1.25) 27(2.513,-0.75) 28(2.513,-0.25) 29(2.513,0.25) 30(2.513,0.75) 31(2.513,1.25)
  rect 3.607x3.607 smd: 33(0,0)
QFN32J4-G2D85H36
  rect 0.203x0.864 smd: 1(1.4,2.085) 2(1,2.085) 3(0.6,2.085) 4(0.2,2.085) 5(-0.2,2.085) 6(-0.6,2.085) 7(-1,2.085) 8(-1.4,2.085) 17(-1.4,-2.085) 18(-1,-2.085) 19(-0.6,-2.085) 20(-0.2,-2.085) 21(0.2,-2.085) 22(0.6,-2.085) 23(1,-2.085) 24(1.4,-2.085)
  rect 0.864x0.203 smd: 9(-2.085,1.4) 10(-2.085,1) 11(-2.085,0.6) 12(-2.085,0.2) 13(-2.085,-0.2) 14(-2.085,-0.6) 15(-2.085,-1) 16(-2.085,-1.4) 25(2.085,-1.4) 26(2.085,-1) 27(2.085,-0.6) 28(2.085,-0.2) 29(2.085,0.2) 30(2.085,0.6) 31(2.085,1) 32(2.085,1.4)
  rect 2.845x2.845 smd: 33(0,0)
QFN52J6-G4D8-UH40
  rect 0.203x0.838 smd: 1(2.4,3.063) 13(-2.4,3.063) 27(-2.4,-3.063) 39(2.4,-3.063)
  rect 0.203x0.889 smd: 2(2,3.063) 3(1.6,3.063) 4(1.2,3.063) 5(0.8,3.063) 6(0.4,3.063) 7(0,3.063) 8(-0.4,3.063) 9(-0.8,3.063) 10(-1.2,3.063) 11(-1.6,3.063) 12(-2,3.063) 28(-2,-3.063) 29(-1.6,-3.063) 30(-1.2,-3.063) 31(-0.8,-3.063) 32(-0.4,-3.063) 33(0,-3.063) 34(0.4,-3.063) 35(0.8,-3.063) 36(1.2,-3.063) 37(1.6,-3.063) 38(2,-3.063)
  rect 0.838x0.203 smd: 14(-3.063,2.4) 26(-3.063,-2.4) 40(3.063,-2.4) 52(3.063,2.4)
  rect 0.889x0.203 smd: 15(-3.063,2) 16(-3.063,1.6) 17(-3.063,1.2) 18(-3.063,0.8) 19(-3.063,0.4) 20(-3.063,0) 21(-3.063,-0.4) 22(-3.063,-0.8) 23(-3.063,-1.2) 24(-3.063,-1.6) 25(-3.063,-2) 41(3.063,-2) 42(3.063,-1.6) 43(3.063,-1.2) 44(3.063,-0.8) 45(3.063,-0.4) 46(3.063,0) 47(3.063,0.4) 48(3.063,0.8) 49(3.063,1.2) 50(3.063,1.6) 51(3.063,2)
  rect 4.801x4.801 smd: 53(0,0)
R402H14
  custom 0.14x0.14 smd: 1(0,0.445) 2(0,-0.445)
R402H16
  custom 0.14x0.14 smd: 1(0,0.445) 2(0,-0.445)
R603
  custom 0.216x0.216 smd: 1(0,0.762) 2(0,-0.762)
R603H22
  custom 0.216x0.216 smd: 1(0,0.762) 2(0,-0.762)
R805H24
  rect 1.397x1.143 smd: 1(0,0.965) 2(0,-0.965)
R1206H24
  rect 1.651x1.27 smd: 1(0,1.397) 2(0,-1.397)
R1206H26
  rect 1.651x1.27 smd: 1(0,1.397) 2(0,-1.397)
R2010-2H28
  rect 2.743x1.626 smd: 1(0,2.059) 2(0,-2.059)
RT-D6D3-1D4-103065H394
  round 2.388 hole 1.626: 1(3.15,0.7) 2(-3.15,-0.7)
RT-D6D4-1D9-103072H394
  round 1.778 hole 1.016: 1(3.2,0.95) 2(-3.2,-0.95)
RT-D6D6-6D6-108108H426
  round 2.083 hole 1.321: 1(-3.3,-3.3) 2(3.3,3.3)
RUA1JA-KJKC-DE0-0R
  round 1.346 hole 0.94: 1(-3.5,-7.34) 2(-1,-7.34) 3(1,-7.34) 4(3.5,-7.34) 5(-3.5,-4.72) 6(-1,-4.72) 7(1,-4.72) 8(3.5,-4.72)
  round 1.321 hole 0.914: 9(5.715,0.1) 10(4.445,2.64) 11(3.175,0.1) 12(1.905,2.64) 13(0.635,0.1) 14(-0.635,2.64) 15(-1.905,0.1) 16(-3.175,2.64) 17(-4.445,0.1) 18(-5.715,2.64) 19(-4.66,5.47) 20(-7.2,5.47) 21(4.66,5.47) 22(7.2,5.47)
  round 2.718 hole 2.311: 23(-9.35,-12.68) 24(9.35,-12.68) 25(-6.57,-10.05) 26(6.57,-10.05) 27(-6.57,-4.37) 28(6.57,-4.37) 29(-9.35,0) 30(9.35,0)
SC70-5H44
  rect 0.406x1.219 smd: 1(0.65,0.826) 2(0,0.826) 3(-0.65,0.826) 4(-0.65,-0.826) 5(0.65,-0.826)
SE3116H241
  rect 1.626x3.099 smd: 1(0,2.654) 2(0,-2.654)
SFNSDAA1542T-U
  round 1.016 hole 0.711: L1(1.725,2.2) L2(-1.725,2.2) S1(0.575,2.2) S2(-0.575,2.2)
  round 1.422 hole 1.016: PTH1(1.6,0) PTH2(-1.6,0)
SKT-HDMI23-150122-9-U
  rect 0.305x2.591 smd: 1(4.5,0.76) 2(4,0.76) 3(3.5,0.76) 4(3,0.76) 5(2.5,0.76) 6(2,0.76) 7(1.5,0.76) 8(1,0.76) 9(0.5,0.76) 10(0,0.76) 11(-0.5,0.76) 12(-1,0.76) 13(-1.5,0.76) 14(-2,0.76) 15(-2.5,0.76) 16(-3,0.76) 17(-3.5,0.76) 18(-4,0.76) 19(-4.5,0.76)
  oval 1.626x3.124 hole 0.914x2.413: 20(7.25,0) 21(-7.25,0)
  oval 1.626x2.311 hole 0.914x1.6: 22(7.25,-5.96) 23(-7.25,-5.96)
SKT-SOIC8-1H211
  rect 0.889x1.499 smd: 1(1.905,3.751) 2(0.635,3.751) 3(-0.635,3.751) 4(-1.905,3.751) 5(-1.905,-3.751) 6(-0.635,-3.751) 7(0.635,-3.751) 8(1.905,-3.751)
SKT-SOIC16-153139H258
  rect 0.508x1.676 smd: 1(4.445,4.897) 2(3.175,4.897) 3(1.905,4.897) 4(0.635,4.897) 5(-0.635,4.897) 6(-1.905,4.897) 7(-3.175,4.897) 8(-4.445,4.897) 9(-4.445,-4.897) 10(-3.175,-4.897) 11(-1.905,-4.897) 12(-0.635,-4.897) 13(0.635,-4.897) 14(1.905,-4.897) 15(3.175,-4.897) 16(4.445,-4.897)
SKT-USB11-138166
  round 1.067 hole 0.711: 1(-3.5,2) 2(-1,2) 3(1,2) 4(3.5,2) 5(4,3.5) 6(2,3.5) 7(0,3.5) 8(-2,3.5) 9(-4,3.5)
  oval 1.524x3.023 hole 0.813x2.311: 10(-6.4,0) 11(6.4,0)
SKT-USB12-157183
  round 1.346 hole 0.94: 1(-3.5,2.71) 2(-1,2.71) 3(1,2.71) 4(3.5,2.71) 5(-3.5,5.33) 6(-1,5.33) 7(1,5.33) 8(3.5,5.33)
  round 2.718 hole 2.311: 9(-6.57,0) 10(6.57,0) 11(-6.57,5.68) 12(6.57,5.68)
SKTBGA1151R754612-UH369
  round 0.254 hole 3.81 unplated: (-35.21,0) (25.81,18) (25.81,-18)
  round 0.508 smd: A4(-16.187,18.288) A5(-15.273,18.288) AT40(18.931,-14.63) AU1(-18.931,-14.63) AU39(18.016,-15.545) AU40(18.931,-15.545) AV1(-18.931,-15.545) AV2(-18.016,-15.545) AV38(17.102,-16.459) AV39(18.016,-16.459) AW2(-18.016,-16.459) AW3(-17.102,-16.459) AW37(16.187,-17.374) AW38(17.102,-17.374) AY3(-17.102,-17.374) AY4(-16.187,-17.374) B3(-17.102,17.374) B4(-16.187,17.374) B37(16.187,16.459) B38(17.102,16.459) B39(18.016,16.459) C2(-18.016,16.459) C3(-17.102,16.459) C39(18.016,15.545) C40(18.931,15.545) D1(-18.931,15.545) D2(-18.016,15.545) D40(18.931,14.63) E40(18.931,13.716)
  round 0.429 smd: A6(-14.359,18.288) A7(-13.444,18.288) A25(3.015,18.288) A26(3.929,18.288) A27(4.844,18.288) A28(5.758,18.288) A29(6.673,18.288) A30(7.587,18.288) AA5(-15.273,0) AA6(-14.359,0) AA7(-13.444,0) AA8(-12.53,0) AA33(12.53,-0.914) AA34(13.444,-0.914) AA35(14.359,-0.914) AA36(15.273,-0.914) AA37(16.187,-0.914) AA38(17.102,-0.914) AB5(-15.273,-0.914) AB6(-14.359,-0.914) AB7(-13.444,-0.914) AB8(-12.53,-0.914) AB33(12.53,-1.829) AB34(13.444,-1.829) AB35(14.359,-1.829) AB36(15.273,-1.829) AB37(16.187,-1.829) AC5(-15.273,-1.829) AC6(-14.359,-1.829) AC7(-13.444,-1.829) AC8(-12.53,-1.829) AC33(12.53,-2.743) AC34(13.444,-2.743) AC35(14.359,-2.743) AC36(15.273,-2.743) AC37(16.187,-2.743) AD3(-17.102,-2.743) AD4(-16.187,-2.743) AD5(-15.273,-2.743) AD6(-14.359,-2.743) AD7(-13.444,-2.743) AD8(-12.53,-2.743) AD33(12.53,-3.658) AD34(13.444,-3.658) AD35(14.359,-3.658) AD36(15.273,-3.658) AD37(16.187,-3.658) AE3(-17.102,-3.658) AE4(-16.187,-3.658) AE5(-15.273,-3.658) AE6(-14.359,-3.658) AE7(-13.444,-3.658) AE8(-12.53,-3.658) AE33(12.53,-4.572) AE34(13.444,-4.572) AE35(14.359,-4.572) AE36(15.273,-4.572) AE37(16.187,-4.572) AE38(17.102,-4.572) AF4(-16.187,-4.572) AF5(-15.273,-4.572) AF6(-14.359,-4.572) AF7(-13.444,-4.572) AF8(-12.53,-4.572) AF33(12.53,-5.486) AF34(13.444,-5.486) AF35(14.359,-5.486) AF36(15.273,-5.486) AF37(16.187,-5.486) AF38(17.102,-5.486) AG4(-16.187,-5.486) AG5(-15.273,-5.486) AG6(-14.359,-5.486) AG7(-13.444,-5.486) AG8(-12.53,-5.486) AG33(12.53,-6.401) AG34(13.444,-6.401) AG35(14.359,-6.401) AG36(15.273,-6.401) AG37(16.187,-6.401) AG38(17.102,-6.401) AH3(-17.102,-6.401) AH4(-16.187,-6.401) AH5(-15.273,-6.401) AH6(-14.359,-6.401) AH7(-13.444,-6.401) AH8(-12.53,-6.401) AH33(12.53,-7.315) AH34(13.444,-7.315) AH35(14.359,-7.315) AH36(15.273,-7.315) AH37(16.187,-7.315) AH38(17.102,-7.315) AJ3(-17.102,-7.315) AJ4(-16.187,-7.315) AJ5(-15.273,-7.315) AJ6(-14.359,-7.315) AJ7(-13.444,-7.315) AJ8(-12.53,-7.315) AJ9(-11.615,-7.315) AJ11(-7.587,-8.23) AJ12(-6.673,-8.23) AJ13(-5.758,-8.23) AJ14(-4.844,-8.23) AJ15(-3.929,-8.23) AJ16(-3.015,-8.23) AJ17(-2.101,-8.23) AJ18(-1.186,-8.23) AJ19(-0.272,-8.23) AJ20(0.643,-8.23) AJ21(1.557,-8.23) AJ22(2.471,-8.23) AJ23(3.386,-8.23) AJ24(4.3,-8.23) AJ25(5.215,-8.23) AJ26(6.129,-8.23) AJ27(7.043,-8.23) AJ28(7.958,-8.23) AJ29(8.872,-8.23) AJ30(9.787,-8.23) AJ31(10.701,-8.23) AJ32(11.615,-8.23) AJ33(12.53,-8.23) AJ34(13.444,-8.23) AJ35(14.359,-8.23) AJ36(15.273,-8.23) AJ37(16.187,-8.23) AJ38(17.102,-8.23) AK3(-17.102,-8.23) AK4(-16.187,-8.23) AK5(-15.273,-8.23) AK6(-14.359,-8.23) AK7(-13.444,-8.23) AK8(-12.53,-8.23) AK9(-11.615,-8.23) AK10(-10.701,-8.23) AK11(-7.587,-9.144) AK12(-6.673,-9.144) AK13(-5.758,-9.144) AK14(-4.844,-9.144) AK15(-3.929,-9.144) AK16(-3.015,-9.144) AK17(-2.101,-9.144) AK18(-1.186,-9.144) AK19(-0.272,-9.144) AK20(0.643,-9.144) AK21(1.557,-9.144) AK22(2.471,-9.144) AK23(3.386,-9.144) AK24(4.3,-9.144) AK25(5.215,-9.144) AK26(6.129,-9.144) AK27(7.043,-9.144) AK28(7.958,-9.144) AK29(8.872,-9.144) AK30(9.787,-9.144) AK31(10.701,-9.144) AK32(11.615,-9.144) AK33(12.53,-9.144) AK34(13.444,-9.144) AK35(14.359,-9.144) AK36(15.273,-9.144) AK37(16.187,-9.144) AK38(17.102,-9.144) AL3(-17.102,-9.144) AL4(-16.187,-9.144) AL5(-15.273,-9.144) AL6(-14.359,-9.144) AL7(-13.444,-9.144) AL8(-12.53,-9.144) AL9(-11.615,-9.144) AL10(-10.701,-9.144) AL11(-7.587,-10.058) AL12(-6.673,-10.058) AL13(-5.758,-10.058) AL14(-4.844,-10.058) AL15(-3.929,-10.058) AL16(-3.015,-10.058) AL17(-2.101,-10.058) AL18(-1.186,-10.058) AL19(-0.272,-10.058) AL20(0.643,-10.058) AL21(1.557,-10.058) AL22(2.471,-10.058) AL23(3.386,-10.058) AL24(4.3,-10.058) AL25(5.215,-10.058) AL26(6.129,-10.058) AL27(7.043,-10.058) AL28(7.958,-10.058) AL29(8.872,-10.058) AL30(9.787,-10.058) AL31(10.701,-10.058) AL32(11.615,-10.058) AL33(12.53,-10.058) AL34(13.444,-10.058) AL35(14.359,-10.058) AL36(15.273,-10.058) AL37(16.187,-10.058) AL38(17.102,-10.058) AM3(-17.102,-10.058) AM4(-16.187,-10.058) AM5(-15.273,-10.058) AM6(-14.359,-10.058) AM7(-13.444,-10.058) AM8(-12.53,-10.058) AM9(-11.615,-10.058) AM10(-10.701,-10.058) AM11(-7.587,-10.973) AM12(-6.673,-10.973) AM13(-5.758,-10.973) AM14(-4.844,-10.973) AM15(-3.929,-10.973) AM16(-3.015,-10.973) AM17(-2.101,-10.973) AM18(-1.186,-10.973) AM19(-0.272,-10.973) AM20(0.643,-10.973) AM21(1.557,-10.973) AM22(2.471,-10.973) AM23(3.386,-10.973) AM24(4.3,-10.973) AM25(5.215,-10.973) AM26(6.129,-10.973) AM27(7.043,-10.973) AM28(7.958,-10.973) AM29(8.872,-10.973) AM30(9.787,-10.973) AM31(10.701,-10.973) AM32(11.615,-10.973) AM33(12.53,-10.973) AM34(13.444,-10.973) AM35(14.359,-10.973) AM36(15.273,-10.973) AM37(16.187,-10.973) AM38(17.102,-10.973) AN3(-17.102,-10.973) AN4(-16.187,-10.973) AN5(-15.273,-10.973) AN6(-14.359,-10.973) AN7(-13.444,-10.973) AN8(-12.53,-10.973) AN9(-11.615,-10.973) AN10(-10.701,-10.973) AN11(-7.587,-11.887) AN12(-6.673,-11.887) AN13(-5.758,-11.887) AN14(-4.844,-11.887) AN15(-3.929,-11.887) AN16(-3.015,-11.887) AN17(-2.101,-11.887) AN18(-1.186,-11.887) AN19(-0.272,-11.887) AN20(0.643,-11.887) AN21(1.557,-11.887) AN22(2.471,-11.887) AN23(3.386,-11.887) AN24(4.3,-11.887) AN25(5.215,-11.887) AN26(6.129,-11.887) AN27(7.043,-11.887) AN28(7.958,-11.887) AN29(8.872,-11.887) AN30(9.787,-11.887) AN31(10.701,-11.887) AN32(11.615,-11.887) AN33(12.53,-11.887) AN34(13.444,-11.887) AN35(14.359,-11.887) AN36(15.273,-11.887) AN37(16.187,-11.887) AN38(17.102,-11.887) AP3(-17.102,-11.887) AP4(-16.187,-11.887) AP5(-15.273,-11.887) AP6(-14.359,-11.887) AP7(-13.444,-11.887) AP8(-12.53,-11.887) AP9(-11.615,-11.887) AP10(-10.701,-11.887) AP11(-7.587,-12.802) AP12(-6.673,-12.802) AP13(-5.758,-12.802) AP14(-4.844,-12.802) AP15(-3.929,-12.802) AP16(-3.015,-12.802) AP17(-2.101,-12.802) AP18(-1.186,-12.802) AP19(-0.272,-12.802) AP20(0.643,-12.802) AP21(1.557,-12.802) AP22(2.471,-12.802) AP23(3.386,-12.802) AP24(4.3,-12.802) AP25(5.215,-12.802) AP26(6.129,-12.802) AP27(7.043,-12.802) AP28(7.958,-12.802) AP29(8.872,-12.802) AP30(9.787,-12.802) AP31(10.701,-12.802) AP32(11.615,-12.802) AP33(12.53,-12.802) AP34(13.444,-12.802) AP35(14.359,-12.802) AP36(15.273,-12.802) AP37(16.187,-12.802) AP38(17.102,-12.802) AR3(-17.102,-12.802) AR4(-16.187,-12.802) AR5(-15.273,-12.802) AR6(-14.359,-12.802) AR7(-13.444,-12.802) AR8(-12.53,-12.802) AR9(-11.615,-12.802) AR10(-10.701,-12.802) AR11(-7.587,-13.716) AR12(-6.673,-13.716) AR13(-5.758,-13.716) AR14(-4.844,-13.716) AR15(-3.929,-13.716) AR16(-3.015,-13.716) AR17(-2.101,-13.716) AR18(-1.186,-13.716) AR19(-0.272,-13.716) AR20(0.643,-13.716) AR21(1.557,-13.716) AR22(2.471,-13.716) AR23(3.386,-13.716) AR24(4.3,-13.716) AR25(5.215,-13.716) AR26(6.129,-13.716) AR27(7.043,-13.716) AR28(7.958,-13.716) AR29(8.872,-13.716) AR30(9.787,-13.716) AR31(10.701,-13.716) AR32(11.615,-13.716) AR33(12.53,-13.716) AR34(13.444,-13.716) AR35(14.359,-13.716) AR36(15.273,-13.716) AR37(16.187,-13.716) AR38(17.102,-13.716) AT3(-17.102,-13.716) AT4(-16.187,-13.716) AT5(-15.273,-13.716) AT6(-14.359,-13.716) AT7(-13.444,-13.716) AT8(-12.53,-13.716) AT9(-11.615,-13.716) AT10(-10.701,-13.716) AT11(-7.587,-14.63) AT12(-6.673,-14.63) AT13(-5.758,-14.63) AT14(-4.844,-14.63) AT15(-3.929,-14.63) AT16(-3.015,-14.63) AT17(-2.101,-14.63) AT18(-1.186,-14.63) AT19(-0.272,-14.63) AT20(0.643,-14.63) AT21(1.557,-14.63) AT22(2.471,-14.63) AT23(3.386,-14.63) AT24(4.3,-14.63) AT25(5.215,-14.63) AT26(6.129,-14.63) AT27(7.043,-14.63) AT28(7.958,-14.63) AT29(8.872,-14.63) AT30(9.787,-14.63) AT31(10.701,-14.63) AT32(11.615,-14.63) AT33(12.53,-14.63) AT34(13.444,-14.63) AT35(14.359,-14.63) AT36(15.273,-14.63) AT37(16.187,-14.63) AT38(17.102,-14.63) AU3(-17.102,-14.63) AU4(-16.187,-14.63) AU5(-15.273,-14.63) AU6(-14.359,-14.63) AU7(-13.444,-14.63) AU8(-12.53,-14.63) AU9(-11.615,-14.63) AU10(-10.701,-14.63) AU11(-7.587,-15.545) AU12(-6.673,-15.545) AU13(-5.758,-15.545) AU14(-4.844,-15.545) AU15(-3.929,-15.545) AU16(-3.015,-15.545) AU17(-2.101,-15.545) AU18(-1.186,-15.545) AU19(-0.272,-15.545) AU20(0.643,-15.545) AU21(1.557,-15.545) AU24(4.3,-15.545) AU25(5.215,-15.545) AU26(6.129,-15.545) AU27(7.043,-15.545) AU28(7.958,-15.545) AU29(8.872,-15.545) AU30(9.787,-15.545) AU31(10.701,-15.545) AU32(11.615,-15.545) AU33(12.53,-15.545) AU34(13.444,-15.545) AU35(14.359,-15.545) AU36(15.273,-15.545) AU37(16.187,-15.545) AU38(17.102,-15.545) AV3(-17.102,-15.545) AV4(-16.187,-15.545) AV5(-15.273,-15.545) AV6(-14.359,-15.545) AV7(-13.444,-15.545) AV8(-12.53,-15.545) AV9(-11.615,-15.545) AV10(-10.701,-15.545) AV11(-7.587,-16.459) AV12(-6.673,-16.459) AV13(-5.758,-16.459) AV14(-4.844,-16.459) AV24(4.3,-16.459) AV25(5.215,-16.459) AV28(7.958,-16.459) AV29(8.872,-16.459) AV37(16.187,-16.459) AW4(-16.187,-16.459) AW9(-11.615,-16.459) AW10(-10.701,-16.459) AW11(-7.587,-17.374) AW12(-6.673,-17.374) AW13(-5.758,-17.374) AW14(-4.844,-17.374) AY10(-10.701,-17.374) B5(-15.273,17.374) B6(-14.359,17.374) B7(-13.444,17.374) B25(3.015,17.374) B26(3.929,17.374) B27(4.844,17.374) B28(5.758,17.374) B29(6.673,17.374) B30(7.587,17.374) B31(10.701,16.459) B32(11.615,16.459) B33(12.53,16.459) B34(13.444,16.459) B35(14.359,16.459) B36(15.273,16.459) C4(-16.187,16.459) C5(-15.273,16.459) C6(-14.359,16.459) C7(-13.444,16.459) C8(-12.53,16.459) C9(-11.615,16.459) C12(-8.872,16.459) C13(-7.958,16.459) C14(-7.043,16.459) C15(-6.129,16.459) C16(-5.215,16.459) C17(-4.3,16.459) C25(3.015,16.459) C26(3.929,16.459) C27(4.844,16.459) C28(5.758,16.459) C29(6.673,16.459) C30(7.587,16.459) C31(10.701,15.545) C32(11.615,15.545) C33(12.53,15.545) C34(13.444,15.545) C35(14.359,15.545) C36(15.273,15.545) C37(16.187,15.545) C38(17.102,15.545) D3(-17.102,15.545) D4(-16.187,15.545) D5(-15.273,15.545) D6(-14.359,15.545) D7(-13.444,15.545) D8(-12.53,15.545) D9(-11.615,15.545) D10(-10.701,15.545) D11(-9.787,15.545) D12(-8.872,15.545) D13(-7.958,15.545) D14(-7.043,15.545) D15(-6.129,15.545) D16(-5.215,15.545) D17(-4.3,15.545) D24(2.101,15.545) D25(3.015,15.545) D26(3.929,15.545) D27(4.844,15.545) D28(5.758,15.545) D29(6.673,15.545) D30(7.587,15.545) D31(10.701,14.63) D32(11.615,14.63) D33(12.53,14.63) D34(13.444,14.63) D35(14.359,14.63) D36(15.273,14.63) D37(16.187,14.63) D38(17.102,14.63) D39(18.016,14.63) E3(-17.102,14.63) E4(-16.187,14.63) E5(-15.273,14.63) E6(-14.359,14.63) E7(-13.444,14.63) E8(-12.53,14.63) E9(-11.615,14.63) E10(-10.701,14.63) E11(-9.787,14.63) E12(-8.872,14.63) E13(-7.958,14.63) E14(-7.043,14.63) E15(-6.129,14.63) E16(-5.215,14.63) E17(-4.3,14.63) E18(-3.386,14.63) E19(-2.471,14.63) E21(-0.643,14.63) E23(1.186,14.63) E24(2.101,14.63) E25(3.015,14.63) E26(3.929,14.63) E27(4.844,14.63) E28(5.758,14.63) E29(6.673,14.63) E30(7.587,14.63) E31(10.701,13.716) E32(11.615,13.716) E33(12.53,13.716) E34(13.444,13.716) E35(14.359,13.716) E36(15.273,13.716) E37(16.187,13.716) E38(17.102,13.716) E39(18.016,13.716) F4(-16.187,13.716) F5(-15.273,13.716) F6(-14.359,13.716) F7(-13.444,13.716) F8(-12.53,13.716) F9(-11.615,13.716) F10(-10.701,13.716) F11(-9.787,13.716) F12(-8.872,13.716) F13(-7.958,13.716) F14(-7.043,13.716) F15(-6.129,13.716) F16(-5.215,13.716) F17(-4.3,13.716) F18(-3.386,13.716) F19(-2.471,13.716) F20(-1.557,13.716) F21(-0.643,13.716) F22(0.272,13.716) F23(1.186,13.716) F24(2.101,13.716) F25(3.015,13.716) F26(3.929,13.716) F27(4.844,13.716) F28(5.758,13.716) F29(6.673,13.716) F30(7.587,13.716) F31(10.701,12.802) F32(11.615,12.802) F33(12.53,12.802) F34(13.444,12.802) F35(14.359,12.802) F36(15.273,12.802) F37(16.187,12.802) F38(17.102,12.802) F39(18.016,12.802) F40(18.931,12.802) G3(-17.102,12.802) G4(-16.187,12.802) G5(-15.273,12.802) G6(-14.359,12.802) G7(-13.444,12.802) G8(-12.53,12.802) G9(-11.615,12.802) G10(-10.701,12.802) G11(-9.787,12.802) G12(-8.872,12.802) G13(-7.958,12.802) G14(-7.043,12.802) G15(-6.129,12.802) G16(-5.215,12.802) G17(-4.3,12.802) G18(-3.386,12.802) G19(-2.471,12.802) G20(-1.557,12.802) G21(-0.643,12.802) G22(0.272,12.802) G23(1.186,12.802) G24(2.101,12.802) G25(3.015,12.802) G26(3.929,12.802) G27(4.844,12.802) G28(5.758,12.802) G29(6.673,12.802) G30(7.587,12.802) G31(10.701,11.887) G32(11.615,11.887) G33(12.53,11.887) G34(13.444,11.887) G35(14.359,11.887) G36(15.273,11.887) G37(16.187,11.887) G38(17.102,11.887) G39(18.016,11.887) G40(18.931,11.887) H4(-16.187,11.887) H5(-15.273,11.887) H6(-14.359,11.887) H7(-13.444,11.887) H8(-12.53,11.887) H9(-11.615,11.887) H10(-10.701,11.887) H11(-9.787,11.887) H12(-8.872,11.887) H13(-7.958,11.887) H14(-7.043,11.887) H15(-6.129,11.887) H16(-5.215,11.887) H17(-4.3,11.887) H18(-3.386,11.887) H19(-2.471,11.887) H20(-1.557,11.887) H21(-0.643,11.887) H22(0.272,11.887) H23(1.186,11.887) H24(2.101,11.887) H25(3.015,11.887) H26(3.929,11.887) H27(4.844,11.887) H28(5.758,11.887) H29(6.673,11.887) H30(7.587,11.887) H31(10.701,10.973) H32(11.615,10.973) H33(12.53,10.973) H34(13.444,10.973) H35(14.359,10.973) H36(15.273,10.973) H37(16.187,10.973) H38(17.102,10.973) H39(18.016,10.973) H40(18.931,10.973) J3(-17.102,10.973) J4(-16.187,10.973) J5(-15.273,10.973) J6(-14.359,10.973) J7(-13.444,10.973) J8(-12.53,10.973) J9(-11.615,10.973) J10(-10.701,10.973) J11(-9.787,10.973) J12(-8.872,10.973) J13(-7.958,10.973) J14(-7.043,10.973) J15(-6.129,10.973) J16(-5.215,10.973) J17(-4.3,10.973) J18(-3.386,10.973) J19(-2.471,10.973) J20(-1.557,10.973) J21(-0.643,10.973) J22(0.272,10.973) J23(1.186,10.973) J24(2.101,10.973) J25(3.015,10.973) J26(3.929,10.973) J27(4.844,10.973) J28(5.758,10.973) J29(6.673,10.973) J30(7.587,10.973) J31(10.701,10.058) J32(11.615,10.058) J33(12.53,10.058) J34(13.444,10.058) J35(14.359,10.058) J36(15.273,10.058) J37(16.187,10.058) J38(17.102,10.058) J39(18.016,10.058) J40(18.931,10.058) K4(-16.187,10.058) K5(-15.273,10.058) K6(-14.359,10.058) K7(-13.444,10.058) K8(-12.53,10.058) K9(-11.615,10.058) K10(-10.701,10.058) K11(-9.787,10.058) K12(-8.872,10.058) K13(-7.958,10.058) K14(-7.043,10.058) K15(-6.129,10.058) K16(-5.215,10.058) K17(-4.3,10.058) K18(-3.386,10.058) K19(-2.471,10.058) K20(-1.557,10.058) K21(-0.643,10.058) K22(0.272,10.058) K23(1.186,10.058) K24(2.101,10.058) K25(3.015,10.058) K26(3.929,10.058) K27(4.844,10.058) K28(5.758,10.058) K29(6.673,10.058) K30(7.587,10.058) K31(10.701,9.144) K32(11.615,9.144) K33(12.53,9.144) K34(13.444,9.144) K35(14.359,9.144) K36(15.273,9.144) K37(16.187,9.144) K38(17.102,9.144) K39(18.016,9.144) K40(18.931,9.144) L3(-17.102,9.144) L4(-16.187,9.144) L5(-15.273,9.144) L6(-14.359,9.144) L7(-13.444,9.144) L8(-12.53,9.144) L9(-11.615,9.144) L10(-10.701,9.144) L11(-9.787,9.144) L12(-8.872,9.144) L13(-7.958,9.144) L14(-7.043,9.144) L15(-6.129,9.144) L16(-5.215,9.144) L17(-4.3,9.144) L18(-3.386,9.144) L19(-2.471,9.144) L20(-1.557,9.144) L21(-0.643,9.144) L22(0.272,9.144) L23(1.186,9.144) L24(2.101,9.144) L25(3.015,9.144) L26(3.929,9.144) L27(4.844,9.144) L28(5.758,9.144) L29(6.673,9.144) L30(7.587,9.144) L31(10.701,8.23) L32(11.615,8.23) L33(12.53,8.23) L34(13.444,8.23) L35(14.359,8.23) L36(15.273,8.23) L37(16.187,8.23) L38(17.102,8.23) L39(18.016,8.23) L40(18.931,8.23) M4(-16.187,8.23) M5(-15.273,8.23) M6(-14.359,8.23) M7(-13.444,8.23) M8(-12.53,8.23) M9(-11.615,8.23) M10(-10.701,8.23) M11(-9.787,8.23) M12(-8.872,8.23) M13(-7.958,8.23) M14(-7.043,8.23) M15(-6.129,8.23) M16(-5.215,8.23) M17(-4.3,8.23) M18(-3.386,8.23) M19(-2.471,8.23) M20(-1.557,8.23) M21(-0.643,8.23) M22(0.272,8.23) M23(1.186,8.23) M24(2.101,8.23) M25(3.015,8.23) M26(3.929,8.23) M27(4.844,8.23) M28(5.758,8.23) M29(6.673,8.23) M30(7.587,8.23) M32(11.615,7.315) M33(12.53,7.315) M34(13.444,7.315) M35(14.359,7.315) M36(15.273,7.315) M37(16.187,7.315) M38(17.102,7.315) M39(18.016,7.315) M40(18.931,7.315) N3(-17.102,7.315) N4(-16.187,7.315) N5(-15.273,7.315) N6(-14.359,7.315) N7(-13.444,7.315) N8(-12.53,7.315) N33(12.53,6.401) N34(13.444,6.401) N35(14.359,6.401) N36(15.273,6.401) N37(16.187,6.401) N38(17.102,6.401) N39(18.016,6.401) N40(18.931,6.401) P4(-16.187,6.401) P5(-15.273,6.401) P6(-14.359,6.401) P7(-13.444,6.401) P8(-12.53,6.401) P33(12.53,5.486) P34(13.444,5.486) P35(14.359,5.486) P36(15.273,5.486) P37(16.187,5.486) P38(17.102,5.486) P39(18.016,5.486) P40(18.931,5.486) R3(-17.102,5.486) R4(-16.187,5.486) R5(-15.273,5.486) R6(-14.359,5.486) R7(-13.444,5.486) R8(-12.53,5.486) R33(12.53,4.572) R34(13.444,4.572) R35(14.359,4.572) R36(15.273,4.572) R37(16.187,4.572) R38(17.102,4.572) R39(18.016,4.572) R40(18.931,4.572) T4(-16.187,4.572) T5(-15.273,4.572) T6(-14.359,4.572) T7(-13.444,4.572) T8(-12.53,4.572) T33(12.53,3.658) T34(13.444,3.658) T35(14.359,3.658) T36(15.273,3.658) T37(16.187,3.658) T38(17.102,3.658) T39(18.016,3.658) T40(18.931,3.658) U4(-16.187,3.658) U5(-15.273,3.658) U6(-14.359,3.658) U7(-13.444,3.658) U8(-12.53,3.658) U33(12.53,2.743) U34(13.444,2.743) U35(14.359,2.743) U36(15.273,2.743) U37(16.187,2.743) U38(17.102,2.743) U39(18.016,2.743) U40(18.931,2.743) V4(-16.187,2.743) V5(-15.273,2.743) V6(-14.359,2.743) V7(-13.444,2.743) V8(-12.53,2.743) V33(12.53,1.829) V34(13.444,1.829) V35(14.359,1.829) V36(15.273,1.829) V37(16.187,1.829) V38(17.102,1.829) V39(18.016,1.829) V40(18.931,1.829) W4(-16.187,1.829) W5(-15.273,1.829) W6(-14.359,1.829) W7(-13.444,1.829) W8(-12.53,1.829) W33(12.53,0.914) W34(13.444,0.914) W35(14.359,0.914) W36(15.273,0.914) W37(16.187,0.914) W38(17.102,0.914) Y5(-15.273,0.914) Y6(-14.359,0.914) Y7(-13.444,0.914) Y8(-12.53,0.914) Y33(12.53,0) Y34(13.444,0) Y35(14.359,0) Y36(15.273,0) Y37(16.187,0) Y38(17.102,0)
  oval 0.356x0.457 smd: A11(-9.787,18.288) A12(-8.872,18.288) A13(-7.958,18.288) A14(-7.043,18.288) A15(-6.129,18.288) A16(-5.215,18.288) A17(-4.3,18.288) A18(-3.386,18.288) A23(1.186,18.288) A24(2.101,18.288) AU22(2.471,-15.545) AU23(3.386,-15.545) AV15(-3.929,-16.459) AV16(-3.015,-16.459) AV17(-2.101,-16.459) AV18(-1.186,-16.459) AV19(-0.272,-16.459) AV20(0.643,-16.459) AV21(1.557,-16.459) AV22(2.471,-16.459) AV23(3.386,-16.459) AV26(6.129,-16.459) AV27(7.043,-16.459) AV30(9.787,-16.459) AV31(10.701,-16.459) AV32(11.615,-16.459) AV33(12.53,-16.459) AV34(13.444,-16.459) AV35(14.359,-16.459) AV36(15.273,-16.459) AW5(-15.273,-16.459) AW6(-14.359,-16.459) AW7(-13.444,-16.459) AW8(-12.53,-16.459) AW15(-3.929,-17.374) AW16(-3.015,-17.374) AW17(-2.101,-17.374) AW18(-1.186,-17.374) AW23(3.386,-17.374) AW24(4.3,-17.374) AW25(5.215,-17.374) AW26(6.129,-17.374) AW27(7.043,-17.374) AW28(7.958,-17.374) AW29(8.872,-17.374) AW30(9.787,-17.374) AW31(10.701,-17.374) AW32(11.615,-17.374) AW33(12.53,-17.374) AW34(13.444,-17.374) AW35(14.359,-17.374) AW36(15.273,-17.374) AY5(-15.273,-17.374) AY6(-14.359,-17.374) AY7(-13.444,-17.374) AY8(-12.53,-17.374) AY9(-11.615,-17.374) AY11(-7.587,-18.288) AY12(-6.673,-18.288) AY13(-5.758,-18.288) AY14(-4.844,-18.288) AY15(-3.929,-18.288) AY16(-3.015,-18.288) AY17(-2.101,-18.288) AY18(-1.186,-18.288) AY23(3.386,-18.288) AY24(4.3,-18.288) AY25(5.215,-18.288) AY26(6.129,-18.288) AY27(7.043,-18.288) AY28(7.958,-18.288) AY29(8.872,-18.288) AY30(9.787,-18.288) AY31(10.701,-18.288) B8(-12.53,17.374) B9(-11.615,17.374) B10(-10.701,17.374) B11(-9.787,17.374) B12(-8.872,17.374) B13(-7.958,17.374) B14(-7.043,17.374) B15(-6.129,17.374) B16(-5.215,17.374) B17(-4.3,17.374) B18(-3.386,17.374) B23(1.186,17.374) B24(2.101,17.374) C10(-10.701,16.459) C11(-9.787,16.459) C18(-3.386,16.459) C19(-2.471,16.459) C20(-1.557,16.459) C21(-0.643,16.459) C22(0.272,16.459) C23(1.186,16.459) C24(2.101,16.459) D18(-3.386,15.545) D19(-2.471,15.545) D20(-1.557,15.545) D21(-0.643,15.545) D22(0.272,15.545) D23(1.186,15.545) E20(-1.557,14.63) E22(0.272,14.63)
  oval 0.457x0.356 smd: AA3(-17.102,0) AA4(-16.187,0) AB3(-17.102,-0.914) AB4(-16.187,-0.914) AB38(17.102,-1.829) AB39(18.016,-1.829) AB40(18.931,-1.829) AC1(-18.931,-1.829) AC2(-18.016,-1.829) AC3(-17.102,-1.829) AC4(-16.187,-1.829) AC38(17.102,-2.743) AC39(18.016,-2.743) AC40(18.931,-2.743) AD1(-18.931,-2.743) AD2(-18.016,-2.743) AD38(17.102,-3.658) AD39(18.016,-3.658) AD40(18.931,-3.658) AE1(-18.931,-3.658) AE2(-18.016,-3.658) AE39(18.016,-4.572) AE40(18.931,-4.572) AF1(-18.931,-4.572) AF2(-18.016,-4.572) AF3(-17.102,-4.572) AF39(18.016,-5.486) AF40(18.931,-5.486) AG1(-18.931,-5.486) AG2(-18.016,-5.486) AG3(-17.102,-5.486) AG39(18.016,-6.401) AG40(18.931,-6.401) AH1(-18.931,-6.401) AH2(-18.016,-6.401) AH39(18.016,-7.315) AH40(18.931,-7.315) AJ1(-18.931,-7.315) AJ2(-18.016,-7.315) AJ39(18.016,-8.23) AJ40(18.931,-8.23) AK1(-18.931,-8.23) AK2(-18.016,-8.23) AK39(18.016,-9.144) AK40(18.931,-9.144) AL1(-18.931,-9.144) AL2(-18.016,-9.144) AL39(18.016,-10.058) AL40(18.931,-10.058) AM1(-18.931,-10.058) AM2(-18.016,-10.058) AM39(18.016,-10.973) AM40(18.931,-10.973) AN1(-18.931,-10.973) AN2(-18.016,-10.973) AN39(18.016,-11.887) AN40(18.931,-11.887) AP1(-18.931,-11.887) AP2(-18.016,-11.887) AP39(18.016,-12.802) AP40(18.931,-12.802) AR1(-18.931,-12.802) AR2(-18.016,-12.802) AR39(18.016,-13.716) AR40(18.931,-13.716) AT1(-18.931,-13.716) AT2(-18.016,-13.716) AT39(18.016,-14.63) AU2(-18.016,-14.63) E1(-18.931,14.63) E2(-18.016,14.63) F1(-18.931,13.716) F2(-18.016,13.716) F3(-17.102,13.716) G1(-18.931,12.802) G2(-18.016,12.802) H1(-18.931,11.887) H2(-18.016,11.887) H3(-17.102,11.887) J1(-18.931,10.973) J2(-18.016,10.973) K1(-18.931,10.058) K2(-18.016,10.058) K3(-17.102,10.058) L1(-18.931,9.144) L2(-18.016,9.144) M1(-18.931,8.23) M2(-18.016,8.23) M3(-17.102,8.23) N1(-18.931,7.315) N2(-18.016,7.315) P1(-18.931,6.401) P2(-18.016,6.401) P3(-17.102,6.401) R1(-18.931,5.486) R2(-18.016,5.486) T1(-18.931,4.572) T2(-18.016,4.572) T3(-17.102,4.572) U1(-18.931,3.658) U2(-18.016,3.658) U3(-17.102,3.658) V1(-18.931,2.743) V2(-18.016,2.743) V3(-17.102,2.743) W1(-18.931,1.829) W2(-18.016,1.829) W3(-17.102,1.829) Y3(-17.102,0.914) Y4(-16.187,0.914)
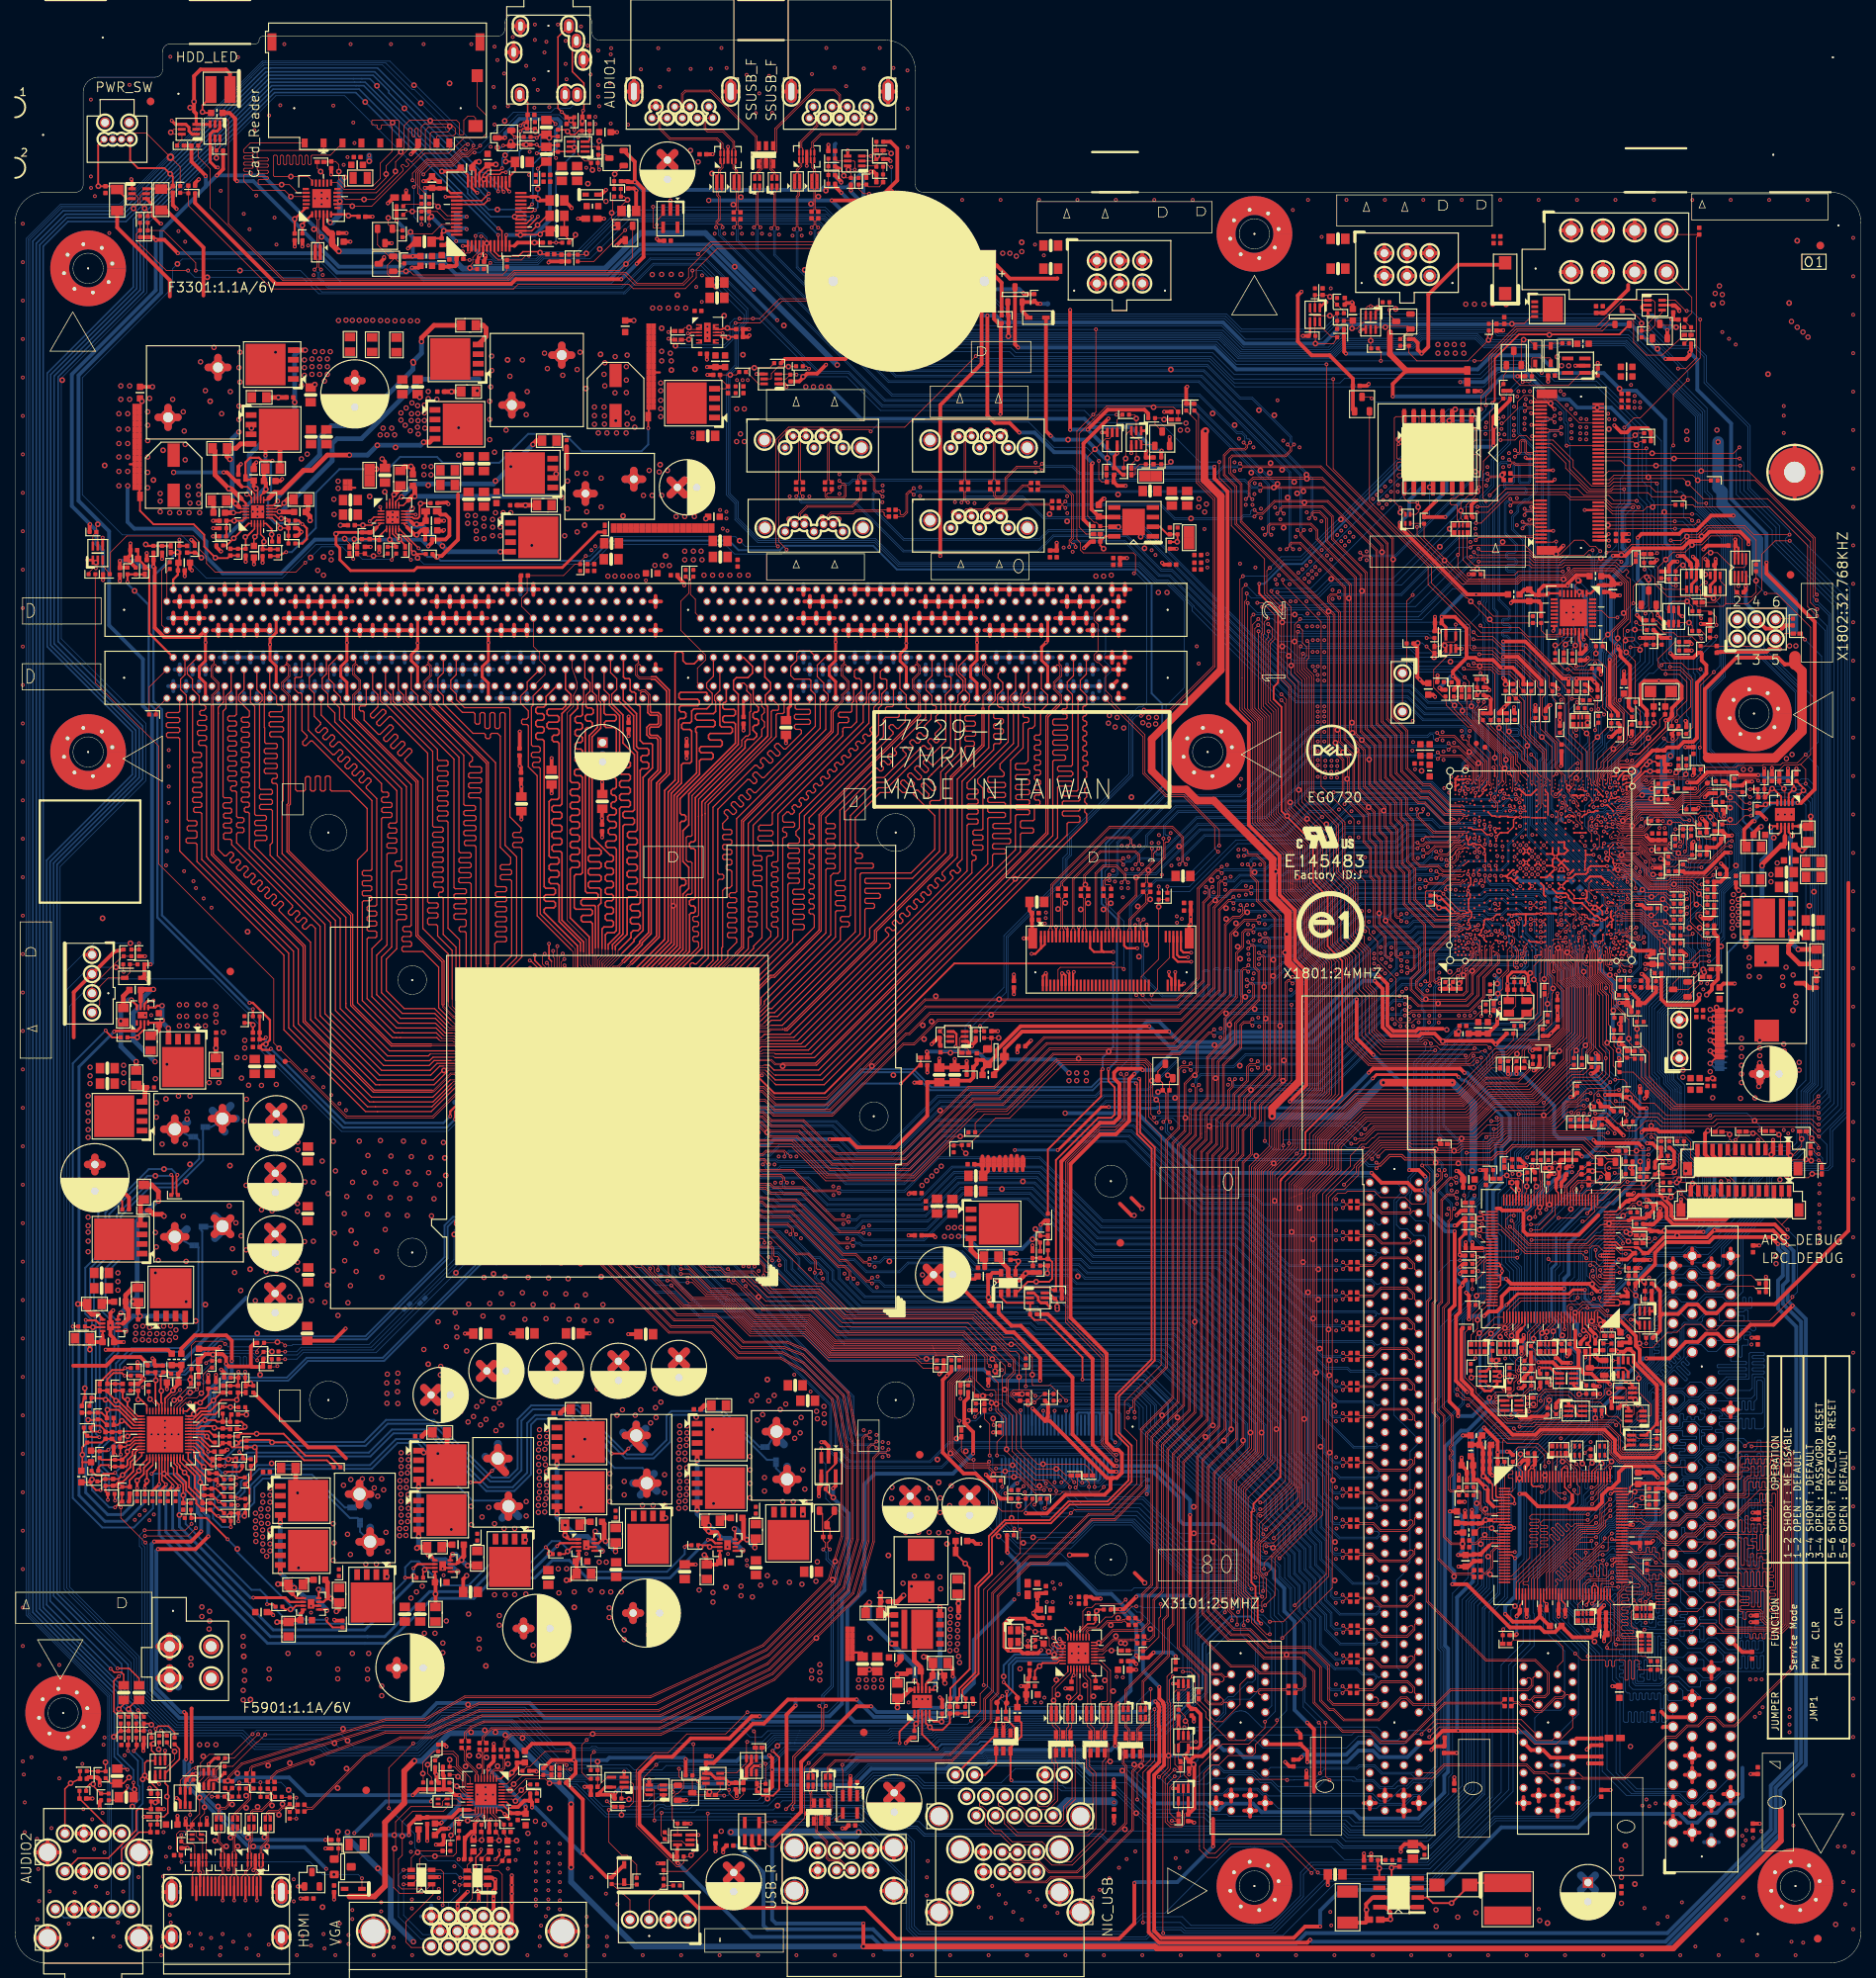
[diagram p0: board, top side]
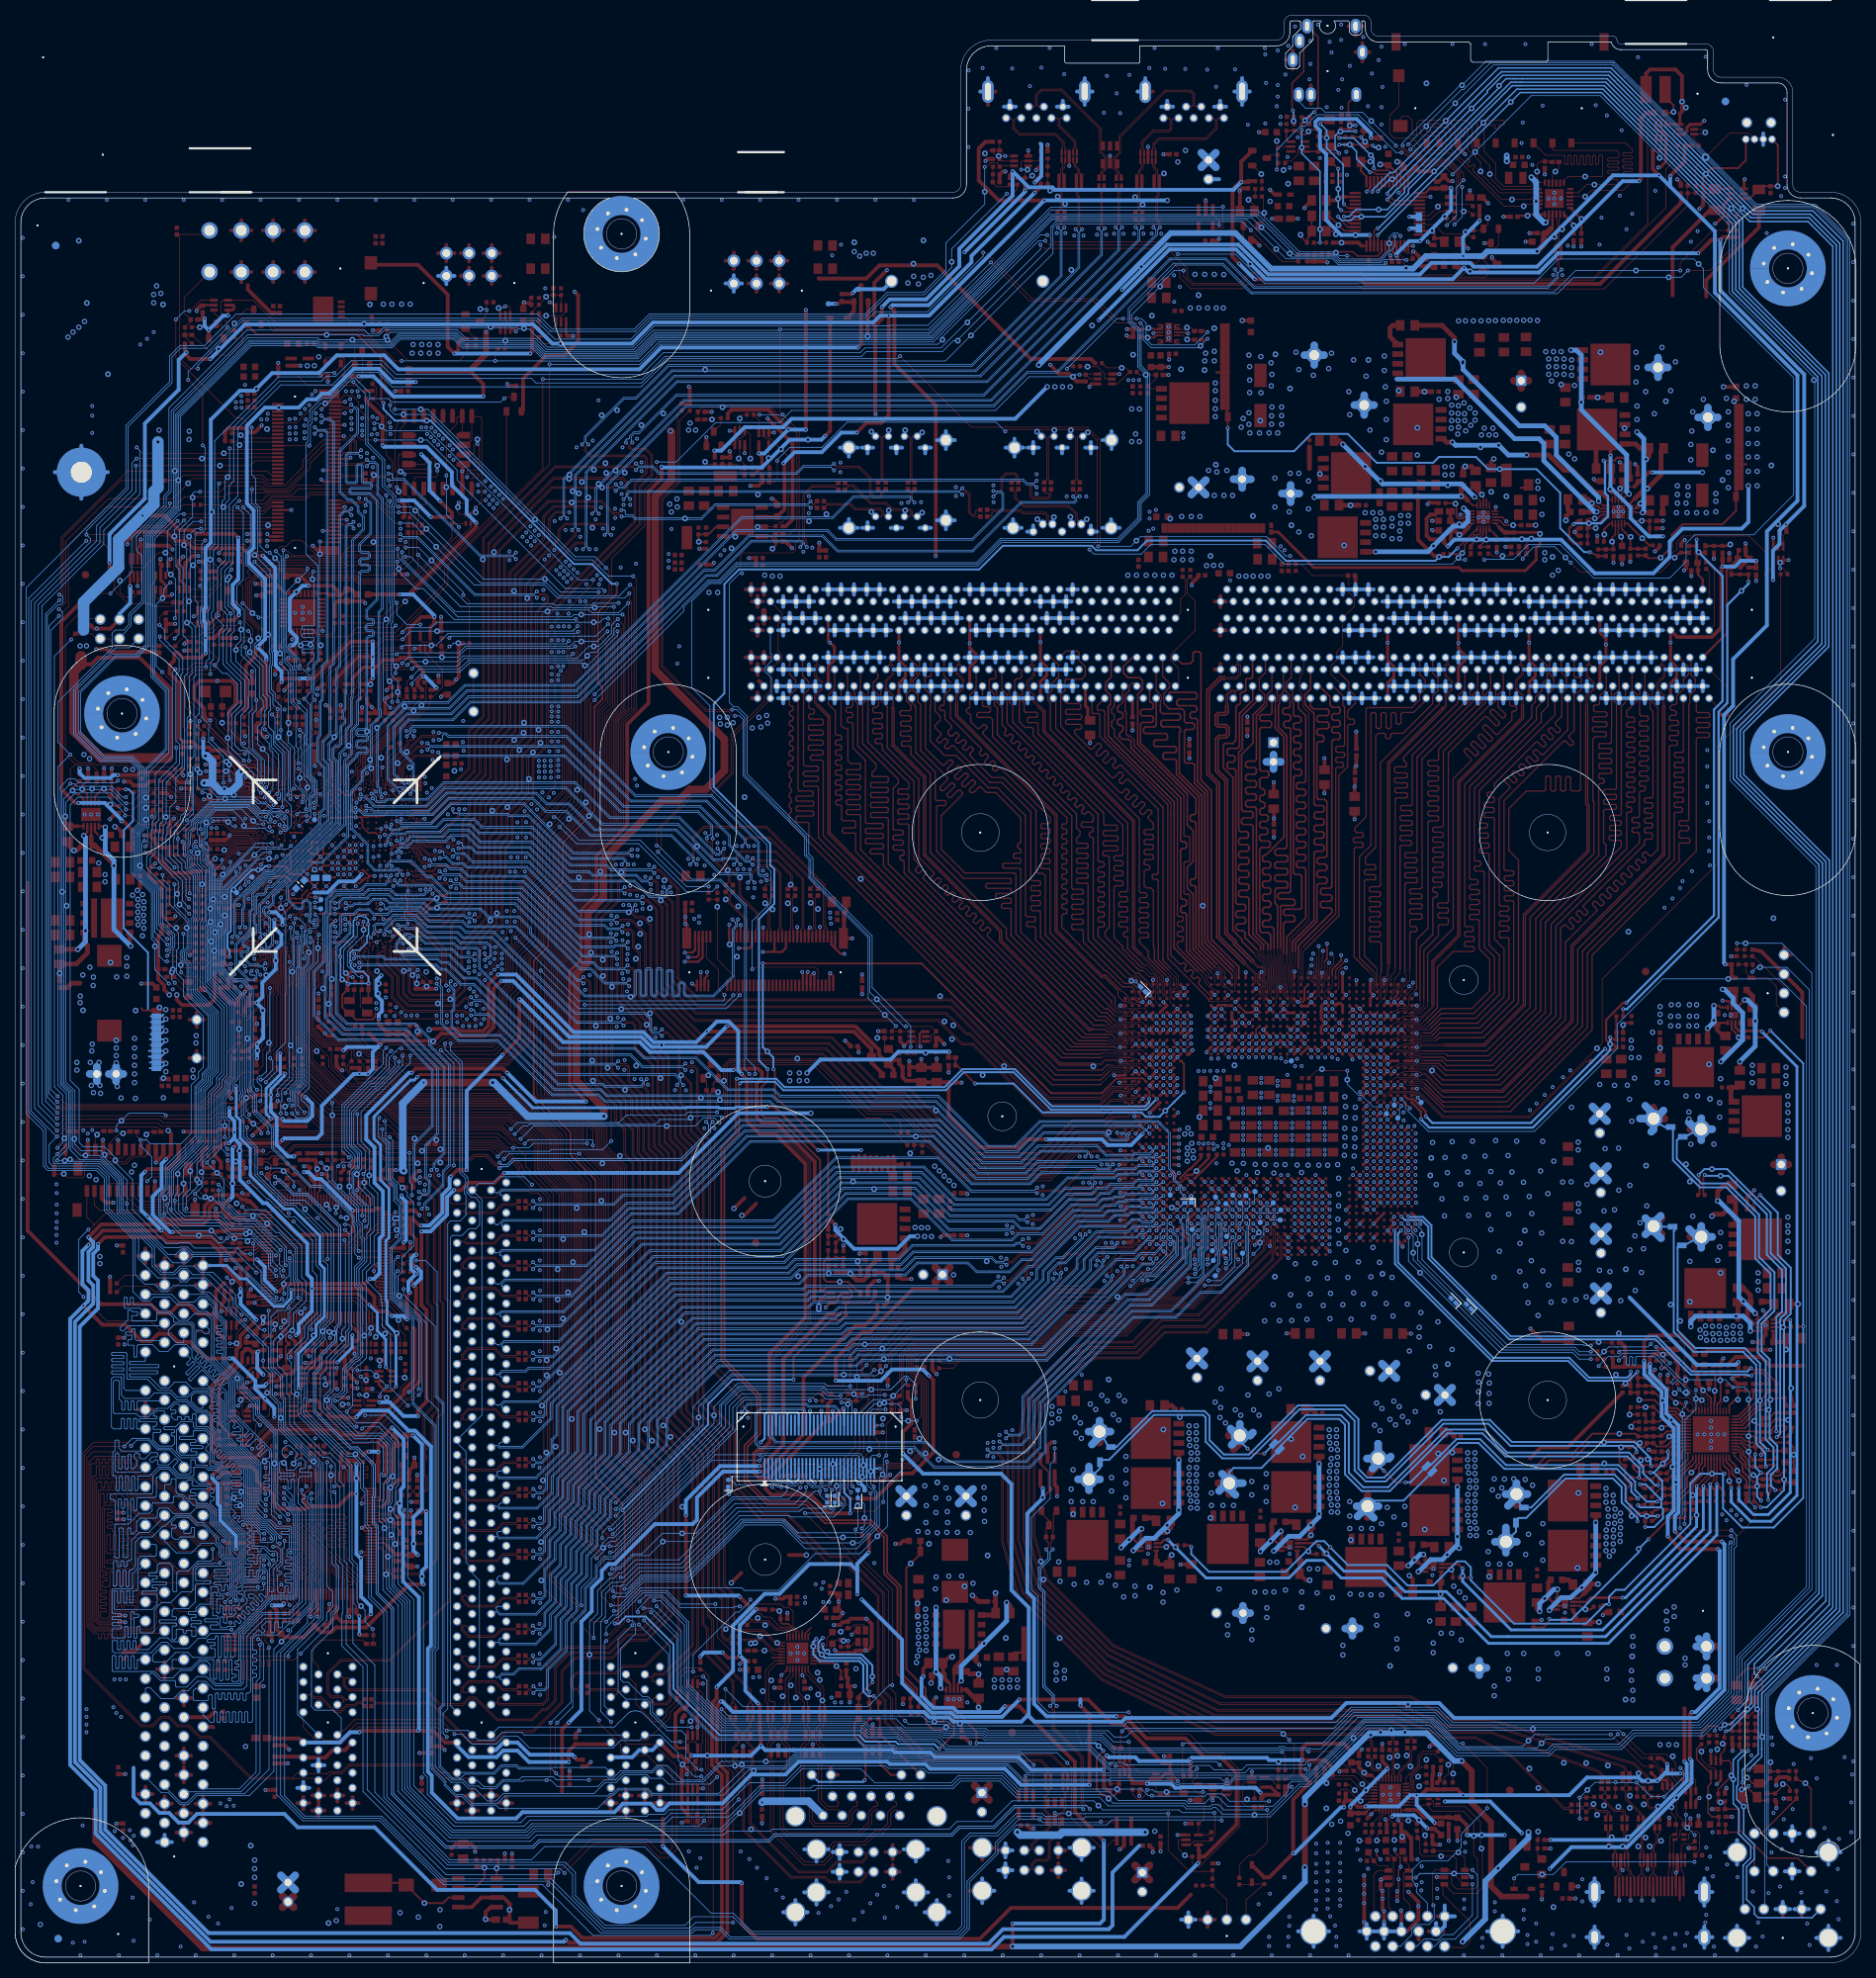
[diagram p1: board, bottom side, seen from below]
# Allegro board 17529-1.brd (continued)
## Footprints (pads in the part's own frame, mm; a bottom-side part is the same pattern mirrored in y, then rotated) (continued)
SMD49-3215-0713H36
  rect 1.549x1.549 smd: 1(0,1.371) 2(0,-1.371)
SMD-ARES4
  rect 0.356x0.66 smd: 1(-0.325,-0.599) 2(0.325,-0.599) 3(0.325,0.599) 4(-0.325,0.599)
SMD-ARES4H18
  rect 0.356x0.66 smd: 1(-0.325,-0.599) 2(0.325,-0.599) 3(0.325,0.599) 4(-0.325,0.599)
SMD-OSC38H20
  rect 1.092x0.737 smd: 1(-0.769,-0.495) 2(0.769,-0.495) 3(0.769,0.495) 4(-0.769,0.495)
SOD323AKH38
  rect 0.559x1.016 smd: A(0,1.143) K(0,-1.143)
SOD-523-4H28
  rect 0.559x0.864 smd: 1(0,0.778) 2(0,-0.778)
SOIC8-1H86
  rect 0.635x1.651 smd: 1(-1.905,-3.493) 2(-0.635,-3.493) 3(0.635,-3.493) 4(1.905,-3.493) 5(1.905,3.493) 6(0.635,3.493) 7(-0.635,3.493) 8(-1.905,3.493)
SOIC8-G3530H63
  rect 0.635x1.651 smd: 1(-1.905,-2.555) 2(-0.635,-2.555) 3(0.635,-2.555) 4(1.905,-2.555) 5(1.905,2.555) 6(0.635,2.555) 7(-0.635,2.555) 8(-1.905,2.555)
  rect 3.505x2.997 smd: 9(0,0)
SOIC8H69
  rect 0.635x1.651 smd: 1(-1.905,-2.54) 2(-0.635,-2.54) 3(0.635,-2.54) 4(1.905,-2.54) 5(1.905,2.54) 6(0.635,2.54) 7(-0.635,2.54) 8(-1.905,2.54)
SOIC16-6H105
  rect 0.635x1.651 smd: 1(-4.445,-4.718) 2(-3.175,-4.718) 3(-1.905,-4.718) 4(-0.635,-4.718) 5(0.635,-4.718) 6(1.905,-4.718) 7(3.175,-4.718) 8(4.445,-4.718) 9(4.445,4.718) 10(3.175,4.718) 11(1.905,4.718) 12(0.635,4.718) 13(-0.635,4.718) 14(-1.905,4.718) 15(-3.175,4.718) 16(-4.445,4.718)
SON14J3020-G2610H32
  rect 0.025x0.025 smd: 1(1.2,1.105) 6(-0.8,1.105) 9(-0.8,-1.105) 14(1.2,-1.105)
  custom 0.151x0.151 smd: 2(0.8,1.105) 7(-1.2,1.105) 8(-1.2,-1.105) 13(0.8,-1.105)
  rect 0.203x0.813 smd: 3(0.4,1.105) 4(0,1.105) 5(-0.4,1.105) 10(-0.4,-1.105) 11(0,-1.105) 12(0.4,-1.105)
  rect 2.591x0.889 smd: 15(0,0)
SOT23-2D4-123H44
  custom 0.191x0.191 smd: 1(0,0.953) 2(-0.984,-0.953) 3(0.984,-0.953)
SOT23-2D4-312H48
  custom 0.191x0.191 smd: 1(-0.984,-0.953) 2(0.984,-0.953) 3(0,0.953)
SOT23CBE2D4H44
  custom 0.191x0.191 smd: B(-0.984,-0.953) C(0,0.953) E(0.984,-0.953)
SOT23DGS2D4H44
  custom 0.191x0.191 smd: D(0,0.953) G(-0.984,-0.953) S(0.984,-0.953)
SOT23DGS2D8H50
  custom 0.254x0.254 smd: D(0,1.118) G(-1.016,-1.118) S(1.016,-1.118)
SOT-6-1H58
  rect 0.584x1.219 smd: 1(-0.95,-1.194) 2(0,-1.194) 3(0.95,-1.194) 4(0.95,1.194) 5(0,1.194) 6(-0.95,1.194)
SOT-6H58
  rect 0.584x1.016 smd: 1(-0.953,-1.346) 2(0,-1.346) 3(0.953,-1.346) 4(0.953,1.346) 5(0,1.346) 6(-0.953,1.346)
SOT-23-5H51
  rect 0.508x1.524 smd: 1(-0.95,-1.143) 2(0,-1.143) 3(0.95,-1.143) 4(0.95,1.143) 5(-0.95,1.143)
SOT-23-5H56
  rect 0.508x1.524 smd: 1(-0.95,-1.143) 2(0,-1.143) 3(0.95,-1.143) 4(0.95,1.143) 5(-0.95,1.143)
SOT-23-5H58
  rect 0.508x1.524 smd: 1(-0.95,-1.143) 2(0,-1.143) 3(0.95,-1.143) 4(0.95,1.143) 5(-0.95,1.143)
SOT-23-9H44
  custom 0.178x0.178 smd: 1(-0.95,-0.999) 2(0.95,-0.999) 3(0,0.999)
SOT-363-1H44
  rect 0.356x1.219 smd: 1(-0.65,-0.922) 2(0,-0.922) 3(0.65,-0.922) 4(0.65,0.922) 5(0,0.922) 6(-0.65,0.922)
SOT-363H44
  rect 0.406x1.016 smd: 1(-0.65,-0.94) 2(0,-0.94) 3(0.65,-0.94) 4(0.65,0.94) 5(0,0.94) 6(-0.65,0.94)
SSOIC8-4H36
  rect 0.305x1.524 smd: 1(-0.751,-1.168) 2(-0.25,-1.168) 3(0.25,-1.168) 4(0.751,-1.168) 5(0.751,1.168) 6(0.25,1.168) 7(-0.25,1.168) 8(-0.751,1.168)
STF256R109H99
  round 6.502 hole 2.769: 1(0,0)
TPAD28
  round 0.711 smd: 1(0,0)
TPAD30
  round 0.762 smd: 1(0,0)
unnamed
  round 1.016 smd: (0,0)
VDS075W-D307-00A3F2B
  round 1.448 hole 1.041: 1(4.33,1.98) 2(2.04,1.98) 3(-0.25,1.98) 4(-2.54,1.98) 5(-4.83,1.98) 6(5.475,0) 7(3.185,0) 8(0.895,0) 9(-1.395,0) 10(-3.685,0) 11(4.33,-1.98) 12(2.04,-1.98) 13(-0.25,-1.98) 14(-2.54,-1.98) 15(-4.83,-1.98)
  round 3.607 hole 3.2: 16(-12.495,0) 17(12.495,0)
WK21921-151146-7H
  round 0.254 hole 1.219 unplated: (-11.2,0)
  round 0.254 hole 1.702 unplated: (10.8,0)
  rect 0.813x1.194 smd: 1(6.925,4.6) 2(4.425,4.6) 3(1.925,4.6) 4(-0.575,4.6) 5(-3.075,4.6) 6(-5.575,4.6) 7(-8,4.6) 8(-9.7,4.6) 9(9.425,4.6)
  rect 1.905x1.6 smd: 10(-13.17,2.35)
  rect 1.499x1.702 smd: 11(-13.39,-4.3)
  rect 1.194x2.311 smd: 12(-13.75,-8.75) 13(13.75,-8.75)

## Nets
1.8VA: C9516.1 C9517.1 C9518.1 L9502.2 U9501.11 U9501.12
1.8VAAUX: C9523.1 C9525.1 C9527.1 L9503.2 U9501.19
1.8VD: C9513.1 C9514.1 C9515.1 L9501.2 U9501.23 U9501.41 U9501.78 U9501.96 U9501.112 U9501.125
1.8VDAUX: C9522.1 C9524.1 C9526.1 L9504.2 U9501.7
1V_CPU_CORE: C1001.1 C1002.1 C1004.1 C1005.1 C1007.1 C1008.1 C1009.1 C1010.1 C1011.1 C1012.1 C1013.1 C1014.1 C1015.1 C1016.1 C1017.1 C1018.1 C1019.1 C1020.1 C1021.1 C1022.1 CPU1.A25 CPU1.A26 CPU1.A27 CPU1.A28 CPU1.A29 CPU1.A30 CPU1.AJ11 CPU1.AJ12 CPU1.AJ13 CPU1.AJ14 CPU1.AJ15 CPU1.AJ16 CPU1.AJ17 CPU1.AJ18 CPU1.AJ19 CPU1.AJ20 CPU1.AJ21 CPU1.AJ25 CPU1.AJ26 CPU1.AJ27 CPU1.AJ28 CPU1.AJ29 CPU1.AK21 CPU1.B25 CPU1.B27 CPU1.B29 CPU1.B31 CPU1.B32 CPU1.B33 CPU1.B34 CPU1.B35 CPU1.B36 CPU1.B37 CPU1.C25 CPU1.C26 CPU1.C27 CPU1.C28 CPU1.C29 CPU1.C30 CPU1.C32 CPU1.C34 CPU1.C36 CPU1.D25 CPU1.D27 CPU1.D29 CPU1.D31 CPU1.D32 CPU1.D33 CPU1.D34 CPU1.D35 CPU1.D36 CPU1.E24 CPU1.E25 CPU1.E26 CPU1.E27 CPU1.E28 CPU1.E29 CPU1.E30 CPU1.E32 CPU1.E34 CPU1.E36 CPU1.F23 CPU1.F24 CPU1.F25 CPU1.F27 CPU1.F29 CPU1.F31 CPU1.F32 CPU1.F33 CPU1.F34 CPU1.F35 CPU1.F37 CPU1.G23 CPU1.G24 CPU1.G25 CPU1.G26 CPU1.G27 CPU1.G28 CPU1.G29 CPU1.G30 CPU1.G32 CPU1.G34 CPU1.G35 CPU1.H22 CPU1.H23 CPU1.H25 CPU1.H27 CPU1.H29 CPU1.H31 CPU1.H32 CPU1.H33 CPU1.H34 CPU1.J21 CPU1.J22 CPU1.J23 CPU1.J24 CPU1.J25 CPU1.J26 CPU1.J27 CPU1.J28 CPU1.J29 CPU1.J30 CPU1.J31 CPU1.J33 CPU1.J35 CPU1.K16 CPU1.K18 CPU1.K20 CPU1.K21 CPU1.K23 CPU1.K25 CPU1.K27 CPU1.K29 CPU1.K31 CPU1.K32 CPU1.K34 CPU1.L14 CPU1.L15 CPU1.L16 CPU1.L17 CPU1.L18 CPU1.L19 CPU1.L20 CPU1.L21 CPU1.L22 CPU1.L23 CPU1.L24 CPU1.L25 CPU1.L26 CPU1.L27 CPU1.L28 CPU1.L29 CPU1.L30 CPU1.L31 CPU1.L33 CPU1.M13 CPU1.M14 CPU1.M16 CPU1.M18 CPU1.M20 CPU1.M22 CPU1.M24 CPU1.M26 CPU1.M28 CPU1.M30 CPU1.M32 PG4502.1 PG4504.1 PG4506.1 PG4508.1 PL4501.2 PL4502.2 PL4503.2 PL4504.2 PR4416.1 PT4502.1 PT4503.1 PT4505.1 PT4507.1 PT4508.1
1V_CPU_GT: CPU1.AA34 CPU1.AA35 CPU1.AA36 CPU1.AA37 CPU1.AA38 CPU1.AB33 CPU1.AB34 CPU1.G36 CPU1.G37 CPU1.G38 CPU1.G39 CPU1.G40 CPU1.H36 CPU1.H38 CPU1.H40 CPU1.J36 CPU1.J37 CPU1.J38 CPU1.J39 CPU1.J40 CPU1.K36 CPU1.K38 CPU1.K40 CPU1.L34 CPU1.L35 CPU1.L36 CPU1.L37 CPU1.L38 CPU1.L39 CPU1.L40 CPU1.M33 CPU1.M34 CPU1.M36 CPU1.M38 CPU1.M40 CPU1.N34 CPU1.N35 CPU1.N36 CPU1.N37 CPU1.N38 CPU1.N39 CPU1.N40 CPU1.P33 CPU1.P34 CPU1.P36 CPU1.P38 CPU1.P40 CPU1.R34 CPU1.R35 CPU1.R36 CPU1.R37 CPU1.R38 CPU1.R39 CPU1.R40 CPU1.T33 CPU1.T34 CPU1.T36 CPU1.T38 CPU1.T40 CPU1.U34 CPU1.U35 CPU1.U36 CPU1.U37 CPU1.U38 CPU1.U39 CPU1.U40 CPU1.V33 CPU1.V34 CPU1.V36 CPU1.V38 CPU1.V40 CPU1.W34 CPU1.W35 CPU1.W36 CPU1.W37 CPU1.W38 CPU1.Y33 CPU1.Y34 CPU1.Y36 CPU1.Y38 PC1034.1 PC1035.1 PC1036.1 PC1037.1 PC1038.1 PC1039.1 PC1040.1 PC1041.1 PC1042.1 PC1043.1 PC1044.1 PC1045.1 PC1068.1 PG4602.1 PG4604.1 PL4601.2 PL4602.2 PR4445.1 PT4602.1 PT4603.1 PT4604.1 PT4605.1
1V_PCH_SB: C2113.1 C2114.1 C2115.1 C2116.1 C2117.1 C2120.1 C2121.1 C2122.1 C2123.1 C2124.1 C2127.1 C2128.1 L2101.1 L2102.1 PR5117.2 PR5118.2 PR5119.2 PR5120.2 PR5121.2 PR5122.2 PR5123.2 PR5124.2 PR5125.2 PR5126.2 PR5127.2 PR5128.2 PR5129.2 PR5130.2 PR5131.2 PR5132.2 PR5133.2 PR5134.2 PR5135.2 Q801.D Q2406.1 R803.1 R9909.1 SB1.AA22 SB1.AA23 SB1.AB20 SB1.AB22 SB1.AB23 SB1.AB27 SB1.AB28 SB1.AB30 SB1.AD20 SB1.AD23 SB1.AD27 SB1.AD28 SB1.AD30 SB1.AD31 SB1.AE17 SB1.AF23 SB1.AF27 SB1.AF30 SB1.AF31 SB1.AG31 SB1.B1 SB1.B2 SB1.B3 SB1.C1 SB1.C2 SB1.D1 SB1.E1 SB1.U26 SB1.U29 SB1.V19 SB1.V25 SB1.V27 SB1.V28 SB1.V30 SB1.V31 SB1.W19 SB1.W20 SB1.W22 SB1.W23 SB1.W31 XDP1.43 XDP1.44
1V_VCCA_XTAL: C2118.1 C2119.1 L2102.2 SB1.P2 SB1.P3
1V_VCCAMPHYPLL: C2110.1 C2111.1 C2112.1 L2101.2 SB1.C49 SB1.D49 SB1.E49
1V_VCCDSW: C2125.1 SB1.BG45 SB1.BG46
5V_AUD_S5: C2704.1 C2705.1 C2708.1 C2709.1 D2701.1 L2701.1 R2701.1 U2701.24
5V_DDC_HDMI: C5609.1 D5601.K RN5601.1(A) RN5601.2(A)
5V_DISPLAY_S0: C5906.1 C5907.1 F5901.1 Q5901.D U5901.17
5V_DISPLAY_SFR_G: Q5901.G R5920.2 R5921.1
5V_HDMI_CONN: C5613.1 HDMI1.18 U5602.2
5V_S0: C4207.1 C4208.1 C5612.1 C6017.1 C6018.1 C9204.1 C9205.1 C9206.1 D5601.A PR4470.1 PR4712.2 Q2402.4 Q5901.S R6418.1 SATAP1.2 SATAP2.2 SLOT4.5 SLOT4.7 SLOT4.9 SLOT4.10 SLOT4.12 SLOT4.15 SLOT4.19 SLOT4.31 SLOT4.38 SLOT4.113 SLOT4.114 SLOT4.117 SLOT4.118 SLOT4.119 SLOT4.120 U4201.13 U4201.14 U5602.3
5V_S5: C3201.1 C3805.1 C3901.1 C4203.1 L2701.2 PC5202.1 PR4401.1 PR4925.2 PR4927.2 PR4929.2 PR4933.2 PR4934.2 PR4936.2 PR4937.2 PR4938.2 PR4939.2 PR4940.2 PR4945.2 PR4946.2 PR4947.2 PR4948.2 PR4949.2 PR5001.1 PR5002.2 PR5115.2 PU5201.6 R2419.2 R2468.1 R3810.2 R4305.1 R6409.2 R6413.1 U3201.5 U3801.5 U3901.5 U4201.1 U4201.2 U4201.4
5V_USB_FRONT: R3807.1 TC3801.1 U3801.1 UC3801.1 USB3F1.1 USB3F2.1
5V_USB_REAR: TC3901.1 U3901.1 UC3901.1 USB2R1.1 USB2R1.5
5V_USB_RJ45: RJ45R1.1 RJ45R1.5 TC3201.1 U3201.1 UC3203.1
5V_VGA_CONN: F5901.2 RN5901.1(A) RN5901.2(A) VGA1.9
12V_CPU: ATX2.3 ATX2.4 C4303.1 FANC1.2 PC4501.1 PC4502.1 PC4506.1 PC4507.1 PC4511.1 PC4512.1 PC4516.1 PC4517.1 PC4601.1 PC4602.1 PC4606.1 PC4607.1 PR4402.1 PR4502.1 PR4508.1 PR4513.1 PR4519.1 PR4602.1 PR4607.1 PR4701.2 PR4702.2 PR4703.2 PR4704.2 PR4705.2 PR4706.2 PT4501.1 PT4504.1 PT4506.1 PT4601.1 PU4501.5 PU4501.6 PU4501.7 PU4501.8 PU4505.5 PU4505.6 PU4505.7 PU4505.8 PU4509.5 PU4509.6 PU4509.7 PU4509.8 PU4513.5 PU4513.6 PU4513.7 PU4513.8 PU4601.5 PU4601.6 PU4601.7 PU4601.8 PU4604.5 PU4604.6 PU4604.7 PU4604.8 R2402.1 R2601.1 R5920.1
12V_DETECT: C4216.1 Q4204.2 R4212.2 R4214.1 R4217.1
12V_DETECT_1: Q4204.3 R4211.2 R4214.2 R4215.1
12V_DETECT_2: Q4204.5 Q4204.6 R4218.2 R4219.1
12V_DETECT_DELAY: C4217.1 Q4202.2 R4215.2
12V_S0: ATX3.5 ATX3.6 C4215.1 C4308.1 C4309.1 C5302.1 C5303.1 C6019.1 C6020.1 C9106.1 C9201.1 C9310.1 C9405.1 C9409.1 FANS1.2 PR4808.1 Q9101.G R2615.1 R4203.1 R4212.1 R4213.1 R5301.2 SATAP1.1 SATAP1.4 SATAP2.1 SATAP2.4 SLOT1.A2 SLOT1.A3 SLOT1.B1 SLOT1.B2 SLOT1.B3 SLOT2.A2 SLOT2.A3 SLOT2.B1 SLOT2.B2 SLOT2.B3 SLOT3.A2 SLOT3.A3 SLOT3.B1 SLOT3.B2 SLOT3.B3 SLOT4.3 U4203.5 U4203.6 U4203.7 U4203.8 U5301.6
12V_S5: C4213.2 D4201.K PL4903.1 PL4904.1 PL4905.1 PL5002.2 PL5003.2 PL5104.2 PL5105.2 R804.1 R807.1 R2466.1 R2467.1 R4206.1 U4203.1 U4203.2 U4203.3
12V_SYSATX_S5: ATX3.1 C4310.1 C4311.1 D4201.A R4208.1 R4211.1 R4218.1
12VBDC_EN: C4213.1 C4214.1 R4209.2 U4203.4
12VBDC_EN_1: R4208.2 R4209.1 R4210.1
12VBDC_EN_2: Q4202.6 Q4203.G R4210.2
+12V_PG: Q4203.D R4213.2
+12V_PG_U29: R4207.1 U4202.5
-12V_S0: C5301.2 C5304.1 C9202.1 D5301.A R5303.2 R5305.1 SLOT4.2 TC5301.2 U5301.4
AGND: AUD1.1 AUD1.4 AUD1.24 AUD1.34 AUD1.G1 AUD1.G2 AUD1.G3 AUD1.G4 C2701.1 C2703.2 C2704.2 C2705.2 C2706.2 C2707.2 C2708.2 C2709.2 C2710.2 C2719.2 C2720.2 C2903.2 C2906.2 C2907.2 C3003.2 C3004.2 C3005.2 C3006.2 C3009.2 C3010.2 HPMIC1.3 HPMIC1.5 HPMIC1.G1 HPMIC1.G2 Q2901.1 Q2901.4 Q3001.1 Q3001.4 R2701.2 R2705.2 R2708.2 R2713.2 R2907.2 R2909.2 R3003.2 R3004.2 R3007.2 R3009.2 R3015.2 R3016.2 U2701.26 U2701.35 U2701.38
GND: APS1.1 APS1.3 APS1.5 APS1.10 APS1.11 ATX2.1 ATX2.2 ATX3.2 ATX3.3 ATX3.7 BT2501.2 C301.2 C302.2 C304.2 C305.2 C402.2 C403.2 C601.2 C603.2 C801.2 C802.2 C804.2 C805.2 C806.2 C1001.2 C1002.2 C1004.2 C1005.2 C1007.2 C1008.2 C1009.2 C1010.2 C1011.2 C1012.2 C1013.2 C1014.2 C1015.2 C1016.2 C1017.2 C1018.2 C1019.2 C1020.2 C1021.2 C1022.2 C1024.2 C1025.2 C1026.2 C1027.2 C1028.2 C1029.2 C1030.2 C1031.2 C1032.2 C1033.2 C1101.2 C1102.2 C1103.2 C1104.2 C1105.2 C1106.2 C1107.2 C1108.2 C1109.2 C1110.2 C1201.2 C1202.2 C1203.2 C1204.2 C1205.2 C1206.2 C1207.2 C1208.2 C1210.2 C1211.2 C1212.2 C1213.2 C1214.2 C1215.2 C1216.2 C1217.2 C1701.2 C1801.2 C1802.2 C1803.2 C1804.2 C2001.2 C2002.2 C2003.2 C2004.2 C2005.2 C2006.2 C2007.2 C2101.2 C2102.2 C2103.2 C2104.2 C2105.2 C2106.2 C2107.2 C2108.2 C2109.2 C2110.2 C2111.2 C2112.2 C2113.2 C2114.2 C2115.2 C2116.2 C2117.2 C2118.2 C2119.2 C2120.2 C2121.2 C2122.2 C2123.2 C2124.2 C2125.2 C2126.2 C2127.2 C2128.2 C2405.2 C2406.2 C2407.2 C2408.2 C2409.2 C2410.2 C2411.2 C2412.2 C2413.2 C2414.2 C2415.2 C2416.2 C2417.2 C2418.2 C2419.2 C2420.2 C2421.2 C2422.2 C2423.2 C2424.2 C2425.2 C2426.2 C2501.2 C2711.2 C2712.2 C2713.2 C2714.2 C2715.2 C2717.2 C2718.2 C2719.1 C2720.1 C2721.2 C2722.2 C3101.2 C3102.2 C3103.2 C3104.2 C3105.2 C3106.2 C3107.2 C3108.2 C3111.2 C3112.2 C3113.2 C3114.2 C3117.2 C3118.2 C3119.2 C3201.2 C3301.2 C3302.2 C3303.2 C3304.2 C3305.2 C3306.2 C3307.2 C3805.2 C3806.2 C3807.2 C3901.2 C4001.2 C4002.2 C4003.2 C4004.2 C4005.2 C4006.2 C4007.2 C4008.2 C4009.2 C4010.2 C4011.2 C4012.2 C4013.2 C4201.2 C4202.2 C4203.2 C4204.2 C4205.2 C4206.2 C4207.2 C4208.2 C4209.2 C4211.2 C4212.2 C4214.2 C4215.2 C4216.2 C4217.2 C4303.2 C4305.2 C4306.2 C4307.2 C4308.2 C4309.2 C4310.2 C4311.2 C5101.2 C5302.2 C5303.2 C5304.2 C5609.2 C5610.2 C5611.2 C5612.2 C5613.2 C5901.2 C5902.2 C5903.1 C5904.2 C5905.2 C5906.2 C5907.2 C5908.2 C5909.2 C5916.2 C5917.2 C5918.2 C5919.2 C5920.2 C5921.2 C5922.2 C5923.2 C6017.2 C6018.2 C6019.2 C6020.2 C6201.2 C6203.2 C6205.2 C6206.2 C6213.2 C6214.2 C6301.2 C6302.2 C6303.2 C6304.2 C6307.2 C6308.2 C6309.2 C6310.2 C6401.2 C6402.2 C6403.2 C9101.2 C9102.2 C9103.2 C9104.2 C9105.2 C9106.2 C9201.2 C9202.2 C9203.2 C9204.2 C9205.2 C9206.2 C9207.2 C9208.2 C9209.2 C9310.2 C9311.2 C9312.2 C9403.2 C9404.2 C9405.2 C9408.2 C9409.2 C9410.2 C9411.2 C9505.2 C9506.2 C9507.2 C9508.2 C9509.2 C9510.2 C9511.2 C9512.2 C9513.2 C9514.2 C9515.2 C9516.2 C9517.2 C9518.2 C9519.2 C9520.2 C9521.2 C9522.2 C9523.2 C9524.2 C9525.2 C9526.2 C9527.2 C9901.2 CPU1.A4 CPU1.A7 CPU1.A11 CPU1.A13 CPU1.A15 CPU1.A17 CPU1.A24 CPU1.AA3 CPU1.AA8 CPU1.AA33 CPU1.AB5 CPU1.AB39 CPU1.AC3 CPU1.AC6 CPU1.AC33 CPU1.AC34 CPU1.AC35 CPU1.AD1 CPU1.AD4 CPU1.AD6 CPU1.AD7 CPU1.AD8 CPU1.AD33 CPU1.AD36 CPU1.AD37 CPU1.AD38 CPU1.AD39 CPU1.AD40 CPU1.AE3 CPU1.AE5 CPU1.AE8 CPU1.AE33 CPU1.AE36 CPU1.AF1 CPU1.AF5 CPU1.AF8 CPU1.AF33 CPU1.AF36 CPU1.AF37 CPU1.AF40 CPU1.AG1 CPU1.AG2 CPU1.AG3 CPU1.AG4 CPU1.AG5 CPU1.AG8 CPU1.AG33 CPU1.AG36 CPU1.AH5 CPU1.AH8 CPU1.AH33 CPU1.AH36 CPU1.AH37 CPU1.AH38 CPU1.AH39 CPU1.AH40 CPU1.AJ1 CPU1.AJ4 CPU1.AJ5 CPU1.AJ8 CPU1.AJ24 CPU1.AJ30 CPU1.AJ31 CPU1.AJ32 CPU1.AJ33 CPU1.AJ34 CPU1.AJ35 CPU1.AJ36 CPU1.AK5 CPU1.AK6 CPU1.AK7 CPU1.AK8 CPU1.AK9 CPU1.AK10 CPU1.AK12 CPU1.AK13 CPU1.AK15 CPU1.AK16 CPU1.AK17 CPU1.AK18 CPU1.AK19 CPU1.AK20 CPU1.AK22 CPU1.AK23 CPU1.AK25 CPU1.AK26 CPU1.AK27 CPU1.AK28 CPU1.AK29 CPU1.AK30 CPU1.AK36 CPU1.AK37 CPU1.AK40 CPU1.AL1 CPU1.AL2 CPU1.AL3 CPU1.AL4 CPU1.AL5 CPU1.AL11 CPU1.AL14 CPU1.AL21 CPU1.AL24 CPU1.AL27 CPU1.AL30 CPU1.AL36 CPU1.AM5 CPU1.AM11 CPU1.AM14 CPU1.AM17 CPU1.AM19 CPU1.AM24 CPU1.AM27 CPU1.AM30 CPU1.AM31 CPU1.AM32 CPU1.AM33 CPU1.AM34 CPU1.AM35 CPU1.AM36 CPU1.AM37 CPU1.AM38 CPU1.AM39 CPU1.AM40 CPU1.AN1 CPU1.AN4 CPU1.AN5 CPU1.AN6 CPU1.AN7 CPU1.AN8 CPU1.AN9 CPU1.AN10 CPU1.AN11 CPU1.AN14 CPU1.AN16 CPU1.AN19 CPU1.AN22 CPU1.AN23 CPU1.AN24 CPU1.AN27 CPU1.AN30 CPU1.AN36 CPU1.AP5 CPU1.AP11 CPU1.AP14 CPU1.AP24 CPU1.AP27 CPU1.AP30 CPU1.AP36 CPU1.AP37 CPU1.AP40 CPU1.AR1 CPU1.AR2 CPU1.AR3 CPU1.AR4 CPU1.AR5 CPU1.AR11 CPU1.AR14 CPU1.AR16 CPU1.AR17 CPU1.AR18 CPU1.AR19 CPU1.AR20 CPU1.AR21 CPU1.AR22 CPU1.AR23 CPU1.AR24 CPU1.AR27 CPU1.AR30 CPU1.AR31 CPU1.AR32 CPU1.AR33 CPU1.AR34 CPU1.AR35 CPU1.AR36 CPU1.AT5 CPU1.AT6 CPU1.AT7 CPU1.AT8 CPU1.AT9 CPU1.AT10 CPU1.AT11 CPU1.AT12 CPU1.AT13 CPU1.AT14 CPU1.AT15 CPU1.AT17 CPU1.AT24 CPU1.AT25 CPU1.AT26 CPU1.AT27 CPU1.AT28 CPU1.AT29 CPU1.AT30 CPU1.AT31 CPU1.AT32 CPU1.AT34 CPU1.AT36 CPU1.AT37 CPU1.AT38 CPU1.AT39 CPU1.AT40 CPU1.AU1 CPU1.AU4 CPU1.AU5 CPU1.AU7 CPU1.AU25 CPU1.AU30 CPU1.AU34 CPU1.AU39 CPU1.AU40 CPU1.AV2 CPU1.AV5 CPU1.AV9 CPU1.AV26 CPU1.AV28 CPU1.AV30 CPU1.AV34 CPU1.AV38 CPU1.AV39 CPU1.AW3 CPU1.AW5 CPU1.AW9 CPU1.AW30 CPU1.AW32 CPU1.AW34 CPU1.AW36 CPU1.AW38 CPU1.AY5 CPU1.AY7 CPU1.AY9 CPU1.AY27 CPU1.AY30 CPU1.B6 CPU1.B24 CPU1.B26 CPU1.B28 CPU1.B30 CPU1.B38 CPU1.C2 CPU1.C5 CPU1.C8 CPU1.C10 CPU1.C12 CPU1.C14 CPU1.C16 CPU1.C18 CPU1.C20 CPU1.C22 CPU1.C24 CPU1.C31 CPU1.C33 CPU1.C35 CPU1.C37 CPU1.D4 CPU1.D7 CPU1.D24 CPU1.D26 CPU1.D28 CPU1.D30 CPU1.D37 CPU1.D39 CPU1.D40 CPU1.E3 CPU1.E6 CPU1.E9 CPU1.E11 CPU1.E13 CPU1.E15 CPU1.E17 CPU1.E19 CPU1.E21 CPU1.E23 CPU1.E31 CPU1.E33 CPU1.E35 CPU1.E37 CPU1.F1 CPU1.F4 CPU1.F7 CPU1.F10 CPU1.F22 CPU1.F26 CPU1.F28 CPU1.F30 CPU1.F36 CPU1.F40 CPU1.G3 CPU1.G6 CPU1.G11 CPU1.G13 CPU1.G15 CPU1.G17 CPU1.G19 CPU1.G22 CPU1.G31 CPU1.G33 CPU1.H1 CPU1.H4 CPU1.H7 CPU1.H9 CPU1.H11 CPU1.H12 CPU1.H21 CPU1.H24 CPU1.H26 CPU1.H28 CPU1.H30 CPU1.H35 CPU1.H37 CPU1.H39 CPU1.J3 CPU1.J6 CPU1.J10 CPU1.J12 CPU1.J16 CPU1.J18 CPU1.J20 CPU1.J32 CPU1.J34 CPU1.K1 CPU1.K4 CPU1.K7 CPU1.K14 CPU1.K15 CPU1.K17 CPU1.K19 CPU1.K22 CPU1.K24 CPU1.K26 CPU1.K28 CPU1.K30 CPU1.K33 CPU1.K35 CPU1.K37 CPU1.K39 CPU1.L3 CPU1.L6 CPU1.L9 CPU1.L11 CPU1.L13 CPU1.L32 CPU1.M1 CPU1.M4 CPU1.M7 CPU1.M10 CPU1.M12 CPU1.M15 CPU1.M17 CPU1.M19 CPU1.M21 CPU1.M23 CPU1.M25 CPU1.M27 CPU1.M29 CPU1.M35 CPU1.M37 CPU1.M39 CPU1.N3 CPU1.N6 CPU1.N8 CPU1.N33 CPU1.P1 CPU1.P4 CPU1.P35 CPU1.P37 CPU1.P39 CPU1.R3 CPU1.R6 CPU1.R8 CPU1.R33 CPU1.T1 CPU1.T4 CPU1.T35 CPU1.T37 CPU1.T39 CPU1.U3 CPU1.U6 CPU1.U33 CPU1.V1 CPU1.V8 CPU1.V35 CPU1.V37 CPU1.V39 CPU1.W3 CPU1.W6 CPU1.W33 CPU1.Y5 CPU1.Y35 CPU1.Y37 D2701.2 DB2001.2 DIMM1.2 DIMM1.4 DIMM1.6 DIMM1.9 DIMM1.11 DIMM1.13 DIMM1.15 DIMM1.17 DIMM1.20 DIMM1.22 DIMM1.24 DIMM1.26 DIMM1.28 DIMM1.31 DIMM1.33 DIMM1.35 DIMM1.37 DIMM1.39 DIMM1.42 DIMM1.44 DIMM1.46 DIMM1.48 DIMM1.50 DIMM1.53 DIMM1.55 DIMM1.57 DIMM1.94 DIMM1.96 DIMM1.98 DIMM1.101 DIMM1.103 DIMM1.105 DIMM1.107 DIMM1.109 DIMM1.112 DIMM1.114 DIMM1.116 DIMM1.118 DIMM1.120 DIMM1.123 DIMM1.125 DIMM1.127 DIMM1.129 DIMM1.131 DIMM1.134 DIMM1.136 DIMM1.138 DIMM1.139 DIMM1.140 DIMM1.147 DIMM1.149 DIMM1.151 DIMM1.154 DIMM1.156 DIMM1.158 DIMM1.160 DIMM1.162 DIMM1.165 DIMM1.167 DIMM1.169 DIMM1.171 DIMM1.173 DIMM1.176 DIMM1.178 DIMM1.180 DIMM1.182 DIMM1.184 DIMM1.187 DIMM1.189 DIMM1.191 DIMM1.193 DIMM1.195 DIMM1.198 DIMM1.200 DIMM1.202 DIMM1.238 DIMM1.239 DIMM1.241 DIMM1.243 DIMM1.246 DIMM1.248 DIMM1.250 DIMM1.252 DIMM1.254 DIMM1.257 DIMM1.259 DIMM1.261 DIMM1.263 DIMM1.265 DIMM1.268 DIMM1.270 DIMM1.272 DIMM1.274 DIMM1.276 DIMM1.279 DIMM1.281 DIMM1.283 DIMM2.2 DIMM2.4 DIMM2.6 DIMM2.9 DIMM2.11 DIMM2.13 DIMM2.15 DIMM2.17 DIMM2.20 DIMM2.22 DIMM2.24 DIMM2.26 DIMM2.28 DIMM2.31 DIMM2.33 DIMM2.35 DIMM2.37 DIMM2.39 DIMM2.42 DIMM2.44 DIMM2.46 DIMM2.48 DIMM2.50 DIMM2.53 DIMM2.55 DIMM2.57 DIMM2.94 DIMM2.96 DIMM2.98 DIMM2.101 DIMM2.103 DIMM2.105 DIMM2.107 DIMM2.109 DIMM2.112 DIMM2.114 DIMM2.116 DIMM2.118 DIMM2.120 DIMM2.123 DIMM2.125 DIMM2.127 DIMM2.129 DIMM2.131 DIMM2.134 DIMM2.136 DIMM2.138 DIMM2.139 DIMM2.147 DIMM2.149 DIMM2.151 DIMM2.154 DIMM2.156 DIMM2.158 DIMM2.160 DIMM2.162 DIMM2.165 DIMM2.167 DIMM2.169 DIMM2.171 DIMM2.173 DIMM2.176 DIMM2.178 DIMM2.180 DIMM2.182 DIMM2.184 DIMM2.187 DIMM2.189 DIMM2.191 DIMM2.193 DIMM2.195 DIMM2.198 DIMM2.200 DIMM2.202 DIMM2.238 DIMM2.239 DIMM2.241 DIMM2.243 DIMM2.246 DIMM2.248 DIMM2.250 DIMM2.252 DIMM2.254 DIMM2.257 DIMM2.259 DIMM2.261 DIMM2.263 DIMM2.265 DIMM2.268 DIMM2.270 DIMM2.272 DIMM2.274 DIMM2.276 DIMM2.279 DIMM2.281 DIMM2.283 EU3201.2 EU3202.2 EU3203.2 EU3204.2 EU3801.3 EU3801.8 EU3802.3 EU3802.8 EU3803.2 EU3901.2 EU5601.3 EU5601.8 EU5602.3 EU5602.8 EU5603.3 EU5603.8 EU5901.2 EU5902.2 FANC1.1 FANS1.1 HDMI1.2 HDMI1.5 HDMI1.8 HDMI1.11 HDMI1.17 HDMI1.20 HDMI1.21 HDMI1.22 HDMI1.23 HS1902.1 HS1902.2 HS2601.1 HS2601.2 HS2601.3 HS2601.4 HS2601.5 HS2601.6 HS2601.7 HS2601.8 HS2602.1 HS2602.2 HS2602.3 HS2602.4 HS2602.5 HS2602.6 HS2602.7 HS2602.8 HS2603.1 HS2603.2 HS2603.3 HS2603.4 HS2603.5 HS2603.6 HS2603.7 HS2603.8 HS2604.1 HS2604.2 HS2604.3 HS2604.4 HS2604.5 HS2604.6 HS2604.7 HS2604.8 HS2605.1 HS2605.2 HS2605.3 HS2605.4 HS2605.5 HS2605.6 HS2605.7 HS2605.8 HS2606.1 HS2606.2 HS2606.3 HS2606.4 HS2606.5 HS2606.6 HS2606.7 HS2606.8 HS2607.1 HS2607.2 HS2607.3 HS2607.4 HS2607.5 HS2607.6 HS2607.7 HS2607.8 HS2608.1 HS2608.2 HS2608.3 HS2608.4 HS2608.5 HS2608.6 HS2608.7 HS2608.8 HS6301.1 JMP1.4 L5301.2 LPC1.3 LPC1.15 LPC1.16 NGFF1.7 NGFF1.13 NGFF1.18 NGFF1.19 NGFF1.33 NGFF1.39 NGFF1.45 NGFF1.57 NGFF1.63 NGFF1.69 NGFF1.75 NGFF1.76 NGFF1.77 NGFF2.1 NGFF2.3 NGFF2.9 NGFF2.15 NGFF2.21 NGFF2.27 NGFF2.33 NGFF2.39 NGFF2.45 NGFF2.51 NGFF2.57 NGFF2.71 NGFF2.73 NGFF2.75 NGFF2.76 NGFF2.77 PC1034.2 PC1035.2 PC1036.2 PC1037.2 PC1038.2 PC1039.2 PC1040.2 PC1041.2 PC1042.2 PC1043.2 PC1044.2 PC1045.2 PC1046.2 PC1047.2 PC1048.2 PC1049.2 PC1050.2 PC1051.2 PC1052.2 PC1053.2 PC1068.2 PC4401.2 PC4402.2 PC4403.2 PC4414.2 PC4416.2 PC4426.2 PC4427.2 PC4428.2 PC4429.2 PC4501.2 PC4502.2 PC4504.1 PC4505.2 PC4506.2 PC4507.2 PC4509.1 PC4510.2 PC4511.2 PC4512.2 PC4514.1 PC4515.2 PC4516.2 PC4517.2 PC4519.1 PC4520.2 PC4601.2 PC4602.2 PC4604.1 PC4605.2 PC4606.2 PC4607.2 PC4609.1 PC4610.2 PC4701.2 PC4702.2 PC4703.2 PC4705.2 PC4706.2 PC4707.2 PC4801.2 PC4802.2 PC4803.2 PC4804.2 PC4805.2 PC4808.2 PC4809.2 PC4810.2 PC4901.2 PC4902.2 PC4903.2 PC4904.2 PC4905.2 PC4906.2 PC4909.2 PC4910.2 PC4911.2 PC4912.2 PC4913.2 PC4916.2 PC4917.2 PC4918.2 PC4919.2 PC5001.2 PC5002.2 PC5003.2 PC5004.2 PC5005.2 PC5006.2 PC5007.2 PC5009.2 PC5010.2 PC5011.2 PC5012.2 PC5014.2 PC5015.2 PC5101.2 PC5102.2 PC5103.2 PC5104.2 PC5105.2 PC5107.2 PC5109.2 PC5110.2 PC5201.2 PC5202.2 PC5203.2 PC5204.2 PC5205.2 PR4403.2 PR4413.2 PR4423.2 PR4424.2 PR4430.2 PR4441.2 PR4454.2 PR4456.2 PR4458.2 PR4465.2 PR4466.2 PR4467.2 PR4468.2 PR4469.2 PR4471.2 PR4708.1 PR4711.2 PR4717.2 PR4816.2 PR4952.2 PR4953.2 PR4956.2 PR4957.2 PR4961.2 PR4962.2 PR5003.2 PR5025.2 PR5111.2 PR5112.2 PR5116.2 PR5206.2 PT4501.2 PT4502.2 PT4503.2 PT4504.2 PT4505.2 PT4506.2 PT4507.2 PT4508.2 PT4601.2 PT4602.2 PT4603.2 PT4604.2 PT4605.2 PT4701.2 PT4702.2 PT4801.2 PT4901.2 PT4902.2 PT4903.2 PT5001.2 PT5101.2 PU4401.53 PU4502.6 PU4502.9 PU4503.1 PU4503.2 PU4503.3 PU4504.1 PU4504.2 PU4504.3 PU4506.6 PU4506.9 PU4507.1 PU4507.2 PU4507.3 PU4508.1 PU4508.2 PU4508.3 PU4510.6 PU4510.9 PU4511.1 PU4511.2 PU4511.3 PU4512.1 PU4512.2 PU4512.3 PU4514.6 PU4514.9 PU4515.1 PU4515.2 PU4515.3 PU4516.1 PU4516.2 PU4516.3 PU4602.6 PU4602.9 PU4603.1 PU4603.2 PU4603.3 PU4605.6 PU4605.9 PU4606.1 PU4606.2 PU4606.3 PU4701.11 PU4702.5 PU4702.6 PU4702.7 PU4801.2 PU4902.21 PU4904.1 PU4904.2 PU4904.3 PU4905.1 PU4905.2 PU4905.3 PU5001.1 PU5001.3 PU5001.14 PU5001.21 PU5003.1 PU5003.2 PU5003.3 PU5101.11 PU5102.5 PU5102.6 PU5102.7 PU5201.1 PWRSW1.S1 Q802.1 Q802.4 Q2401.1 Q2401.4 Q2407.S Q2408.1 Q2408.4 Q2702.C Q2703.C Q2704.C Q3801.4 Q4001.E Q4002.1 Q4002.4 Q4202.4 Q4203.S Q4204.1 Q4204.4 Q4301.E Q5601.1 Q6301.1 Q6301.4 Q6401.1 Q6401.4 R415.2 R418.2 R420.2 R424.2 R426.2 R602.2 R806.2 R808.2 R810.2 R902.1 R903.1 R1106.2 R1206.2 R1207.2 R1511.1 R1512.2 R1514.2 R1515.2 R1516.2 R1609.2 R1610.2 R1611.2 R1708.2 R1713.2 R1802.1 R1808.1 R1917.2 R1919.2 R1920.2 R2011.2 R2030.2 R2035.2 R2043.2 R2047.1 R2049.2 R2050.2 R2051.2 R2052.2 R2053.2 R2054.2 R2055.2 R2056.2 R2057.2 R2058.2 R2304.2 R2305.2 R2309.2 R2311.2 R2312.2 R2315.2 R2316.2 R2320.2 R2322.2 R2323.2 R2326.2 R2328.2 R2330.2 R2331.2 R2332.2 R2406.2 R2408.2 R2409.2 R2410.2 R2416.2 R2417.2 R2423.2 R2424.2 R2442.2 R2446.1 R2448.1 R2449.1 R2450.1 R2453.2 R2460.2 R2471.2 R2472.2 R2474.2 R2475.2 R2505.2 R2604.2 R2611.2 R2617.2 R2619.2 R2704.2 R2705.1 R2708.1 R2713.1 R3101.1 R3106.2 R3302.2 R3809.2 R3812.2 R3813.1 R4002.2 R4004.2 R4023.2 R4205.2 R4217.2 R4219.2 R5304.2 R5305.2 R5609.2 R5904.2 R5908.2 R5909.2 R5910.2 R5913.2 R5914.2 R5915.2 R5921.2 R6301.1 R6302.1 R6304.1 R6315.2 R6406.2 R6407.2 R6408.2 R6423.2 R9110.1 R9504.2 R9505.2 R9506.2 R9507.2 R9509.2 R9510.2 R9511.2 R9904.1 R9914.2 R9915.2 RJ45R1.4 RJ45R1.8 RJ45R1.18 RJ45R1.23 RJ45R1.24 RJ45R1.25 RJ45R1.26 RJ45R1.27 RJ45R1.28 RJ45R1.29 RJ45R1.30 SATA1.1 SATA1.4 SATA1.7 SATA1.8 SATA1.9 SATA2.1 SATA2.4 SATA2.7 SATA2.8 SATA2.9 SATA3.1 SATA3.4 SATA3.7 SATA3.8 SATA3.9 SATA4.1 SATA4.4 SATA4.7 SATA4.8 SATA4.9 SATAP1.3 SATAP1.5 SATAP2.3 SATAP2.5 SB1.A2 SB1.A3 SB1.A4 SB1.A5 SB1.A8 SB1.A28 SB1.A33 SB1.A37 SB1.A45 SB1.A46 SB1.A47 SB1.A48 SB1.AA5 SB1.AA19 SB1.AA20 SB1.AA25 SB1.AA27 SB1.AA28 SB1.AA30 SB1.AA31 SB1.AA49 SB1.AB19 SB1.AB25 SB1.AB31 SB1.AC4 SB1.AC12 SB1.AC17 SB1.AC33 SB1.AC38 SB1.AC46 SB1.AD1 SB1.AD2 SB1.AD19 SB1.AD22 SB1.AD25 SB1.AD49 SB1.AE4 SB1.AE12 SB1.AE33 SB1.AE38 SB1.AE46 SB1.AF22 SB1.AF25 SB1.AF28 SB1.AG1 SB1.AG22 SB1.AG23 SB1.AG25 SB1.AG27 SB1.AG28 SB1.AG30 SB1.AG49 SB1.AH12 SB1.AH17 SB1.AH33 SB1.AH38 SB1.AJ19 SB1.AJ20 SB1.AJ25 SB1.AJ27 SB1.AJ28 SB1.AJ30 SB1.AJ31 SB1.AK4 SB1.AK19 SB1.AK20 SB1.AK25 SB1.AK27 SB1.AK28 SB1.AK30 SB1.AK31 SB1.AK46 SB1.AL12 SB1.AL17 SB1.AL21 SB1.AL24 SB1.AL26 SB1.AL29 SB1.AL33 SB1.AL38 SB1.AM1 SB1.AM18 SB1.AM32 SB1.AM49 SB1.AN12 SB1.AN16 SB1.AN34 SB1.AN38 SB1.AP4 SB1.AP46 SB1.AR12 SB1.AR16 SB1.AR34 SB1.AR38 SB1.AT1 SB1.AT16 SB1.AT18 SB1.AT21 SB1.AT24 SB1.AT26 SB1.AT29 SB1.AT32 SB1.AT34 SB1.AT45 SB1.AV11 SB1.AV39 SB1.AW4 SB1.AW10 SB1.AW40 SB1.AW46 SB1.B47 SB1.B48 SB1.B49 SB1.BA5 SB1.BA6 SB1.BA12 SB1.BA14 SB1.BA44 SB1.BB9 SB1.BB41 SB1.BB43 SB1.BC8 SB1.BC10 SB1.BC13 SB1.BC15 SB1.BC19 SB1.BC24 SB1.BC26 SB1.BC31 SB1.BC35 SB1.BC40 SB1.BC45 SB1.BD43 SB1.BE44 SB1.BF1 SB1.BF2 SB1.BF3 SB1.BF48 SB1.BF49 SB1.BG2 SB1.BG3 SB1.BG4 SB1.BG17 SB1.BG22 SB1.BG25 SB1.BG28 SB1.BG33 SB1.BG37 SB1.BG48 SB1.C4 SB1.C5 SB1.C12 SB1.C25 SB1.C30 SB1.C48 SB1.D8 SB1.D12 SB1.D16 SB1.D17 SB1.D30 SB1.D33 SB1.E8 SB1.E10 SB1.E13 SB1.E15 SB1.E17 SB1.E19 SB1.E22 SB1.E24 SB1.E26 SB1.E31 SB1.E33 SB1.E35 SB1.E40 SB1.E42 SB1.F41 SB1.F43 SB1.F47 SB1.G6 SB1.G44 SB1.H8 SB1.J4 SB1.J9 SB1.J10 SB1.J26 SB1.J29 SB1.J40 SB1.J46 SB1.J47 SB1.J48 SB1.K11 SB1.K39 SB1.M5 SB1.M16 SB1.M18 SB1.M21 SB1.M24 SB1.M32 SB1.M34 SB1.M49 SB1.N12 SB1.N16 SB1.N34 SB1.N35 SB1.N37 SB1.N38 SB1.P4 SB1.P26 SB1.P29 SB1.P46 SB1.R3 SB1.R4 SB1.R12 SB1.R16 SB1.R26 SB1.R29 SB1.R34 SB1.R38 SB1.T4 SB1.T5 SB1.T7 SB1.T17 SB1.T18 SB1.T32 SB1.T49 SB1.U12 SB1.U15 SB1.U17 SB1.U21 SB1.U24 SB1.U33 SB1.U38 SB1.V4 SB1.V20 SB1.V22 SB1.V46 SB1.W25 SB1.W27 SB1.W28 SB1.W30 SB1.Y9 SB1.Y10 SB1.Y12 SB1.Y17 SB1.Y33 SB1.Y38 SD1.3 SD1.6 SD1.12 SD1.13 SLOT1.A1 SLOT1.A4 SLOT1.A12 SLOT1.A15 SLOT1.A18 SLOT1.B4 SLOT1.B7 SLOT1.B13 SLOT1.B16 SLOT1.B18 SLOT2.A1 SLOT2.A4 SLOT2.A12 SLOT2.A15 SLOT2.A18 SLOT2.A20 SLOT2.A23 SLOT2.A24 SLOT2.A27 SLOT2.A28 SLOT2.A31 SLOT2.A34 SLOT2.A37 SLOT2.A38 SLOT2.A41 SLOT2.A42 SLOT2.A45 SLOT2.A46 SLOT2.A49 SLOT2.A51 SLOT2.A54 SLOT2.A55 SLOT2.A58 SLOT2.A59 SLOT2.A62 SLOT2.A63 SLOT2.A66 SLOT2.A67 SLOT2.A70 SLOT2.A71 SLOT2.A74 SLOT2.A75 SLOT2.A78 SLOT2.A79 SLOT2.A82 SLOT2.B4 SLOT2.B7 SLOT2.B13 SLOT2.B16 SLOT2.B18 SLOT2.B21 SLOT2.B22 SLOT2.B25 SLOT2.B26 SLOT2.B29 SLOT2.B32 SLOT2.B35 SLOT2.B36 SLOT2.B39 SLOT2.B40 SLOT2.B43 SLOT2.B44 SLOT2.B47 SLOT2.B49 SLOT2.B52 SLOT2.B53 SLOT2.B56 SLOT2.B57 SLOT2.B60 SLOT2.B61 SLOT2.B64 SLOT2.B65 SLOT2.B68 SLOT2.B69 SLOT2.B72 SLOT2.B73 SLOT2.B76 SLOT2.B77 SLOT2.B80 SLOT3.A1 SLOT3.A4 SLOT3.A12 SLOT3.A15 SLOT3.A18 SLOT3.B4 SLOT3.B7 SLOT3.B13 SLOT3.B16 SLOT3.B18 SLOT4.1 SLOT4.4 SLOT4.6 SLOT4.23 SLOT4.24 SLOT4.25 SLOT4.26 SLOT4.30 SLOT4.34 SLOT4.35 SLOT4.44 SLOT4.47 SLOT4.56 SLOT4.59 SLOT4.68 SLOT4.69 SLOT4.73 SLOT4.76 SLOT4.83 SLOT4.92 SLOT4.95 SLOT4.98 SLOT4.107 SLOT4.110 SSKT1.4 SSKT2.10 TC1101.2 TC3201.2 TC3801.2 TC3901.2 TC5301.1 U401.1 U401.4 U2001.2 U2002.4 U2003.2 U2401.1 U2401.3 U2401.17 U2401.18 U2401.35 U2401.40 U2401.59 U2401.66 U2401.82 U2401.83 U2401.86 U2401.88 U2401.90 U2401.117 U2402.2 U2403.3 U2404.4 U2405.3 U2501.4 U2502.10 U2601.2 U2601.4 U2602.3 U2701.1 U3101.33 U3201.2 U3301.25 U3801.2 U3901.2 U4001.3 U4002.1 U4002.4 U4003.S U4004.3 U4005.2 U4006.3 U4007.3 U4008.2 U4009.3 U4010.3 U4201.11 U4201.15 U4202.1 U4202.4 U4301.2 U4301.3 U4801.1 U4801.4 U5602.1 U5901.24 U5901.33 U6301.2 U6305.S U6401.1 U6401.4 U6402.1 U6402.4 U9101.16 U9101.23 U9101.33 U9501.3 U9501.6 U9501.13 U9501.14 U9501.15 U9501.22 U9501.36 U9501.42 U9501.48 U9501.58 U9501.60 U9501.73 U9501.79 U9501.95 U9501.97 U9501.111 U9501.113 U9501.122 U9501.124 UC3201.2 UC3202.2 UC3203.2 UC3801.2 UC3901.2 USB2R1.4 USB2R1.8 USB2R1.9 USB2R1.10 USB2R1.11 USB2R1.12 USB3F1.4 USB3F1.7 USB3F1.10 USB3F1.11 USB3F2.4 USB3F2.7 USB3F2.10 USB3F2.11 VGA1.5 VGA1.6 VGA1.7 VGA1.8 VGA1.10 VGA1.16 VGA1.17 X1801.2 X1801.4 X3101.2 X3101.4 XDP1.2 XDP1.7 XDP1.8 XDP1.13 XDP1.14 XDP1.19 XDP1.20 XDP1.25 XDP1.26 XDP1.31 XDP1.32 XDP1.37 XDP1.38 XDP1.49 XDP1.50 XDP1.59
V5_ALW_MON: C2426.1 Q2408.3 R2468.2 R2472.1 U2401.15
V5_ALW_MON_1: Q2408.5 Q2408.6 R2467.2
V5_ALW_MON_2: C2425.1 Q2408.2 R2466.2 R2471.1
VBAT1: BT2501.1 R2506.1 TP2501.1
VBAT1_L: D2501.A D2502.2 R2506.2 TP2502.1
VBAT1_R: D2502.1 R2504.2 R2505.1
VBAT2: C2405.1 D2501.K U2401.21
VCCGT_VCC_SEN: CPU1.F39 PR4445.2 PR4447.1
VCCGT_VSS_SEN: CPU1.F38 PC4422.2 PC4423.1 PR4450.1 PR4454.1
VCCIO_SENSE: CPU1.AF4 PR4815.2
VCCPGPPD_PWR: R2101.1 R2102.1 SB1.AN24
VCCPLL_OC_R: C801.1 CPU1.AJ9 R801.1
VCCSA_SENSE: CPU1.AD5 PR4714.1 PR4715.2
VCCST_GD_CPU: CPU1.U2 R419.2 R420.1
VCCST_GD_DRIVER: R419.1 R4014.2 R9908.1
VDD: EU5901.5 EU5902.5
VDDQ_EN: C4012.1 R4024.2 R5003.1
VDDQ_EN_CR: R4024.1 U4010.4
VIN_DET: C2407.1 R2411.2 R2416.1 U2401.46
VSS_SA_IO_SENSE: CPU1.AE4 PR4716.2 PR4717.1
0D95V_CPU_VCCIO: C301.1 C302.1 CPU1.AJ23 CPU1.AK11 CPU1.AK14 CPU1.AK24 CPU1.M8 CPU1.P8 CPU1.T8 CPU1.U8 CPU1.W8 PC1046.1 PC1047.1 PC1048.1 PC1049.1 PC4806.2 PC4808.1 PC4809.1 PC4810.1 PR4812.2 PR4815.1 PT4801.1 PU4802.1 PU4802.2 PU4802.3 Q2402.1 R301.1 R422.1 R425.2 R701.2 R9912.1
0D675V_VTT_S0: C1204.1 C1205.1 DIMM1.77 DIMM1.221 DIMM2.77 DIMM2.221 PG5005.1 PG5006.1
1D2V_SM_S3: C1024.1 C1025.1 C1026.1 C1027.1 C1028.1 C1029.1 C1030.1 C1031.1 C1101.1 C1102.1 C1105.1 C1201.1 C1202.1 C1203.1 C1208.1 C1212.1 C1213.1 C1214.1 C1215.1 CPU1.AT18 CPU1.AT21 CPU1.AU13 CPU1.AU15 CPU1.AU19 CPU1.AU23 CPU1.AV11 CPU1.AV17 CPU1.AV21 CPU1.AW10 CPU1.AW14 CPU1.AW25 CPU1.AY12 CPU1.AY16 CPU1.AY18 CPU1.AY23 DIMM1.7 DIMM1.18 DIMM1.29 DIMM1.40 DIMM1.51 DIMM1.59 DIMM1.61 DIMM1.64 DIMM1.67 DIMM1.70 DIMM1.73 DIMM1.76 DIMM1.80 DIMM1.83 DIMM1.85 DIMM1.88 DIMM1.90 DIMM1.92 DIMM1.99 DIMM1.110 DIMM1.121 DIMM1.132 DIMM1.204 DIMM1.206 DIMM1.209 DIMM1.212 DIMM1.215 DIMM1.217 DIMM1.220 DIMM1.223 DIMM1.226 DIMM1.229 DIMM1.231 DIMM1.233 DIMM1.236 DIMM2.7 DIMM2.18 DIMM2.29 DIMM2.40 DIMM2.51 DIMM2.59 DIMM2.61 DIMM2.64 DIMM2.67 DIMM2.70 DIMM2.73 DIMM2.76 DIMM2.80 DIMM2.83 DIMM2.85 DIMM2.88 DIMM2.90 DIMM2.92 DIMM2.99 DIMM2.110 DIMM2.121 DIMM2.132 DIMM2.204 DIMM2.206 DIMM2.209 DIMM2.212 DIMM2.215 DIMM2.217 DIMM2.220 DIMM2.223 DIMM2.226 DIMM2.229 DIMM2.231 DIMM2.233 DIMM2.236 PR4801.2 PR4802.2 PR4803.2 PR4804.2 PR4805.2 PR4806.2 PR4807.2 PR4809.2 PR5006.2 PR5008.2 PR5010.2 PR5011.2 PR5012.2 PR5013.2 PR5014.1 PR5015.2 PR5017.2 PR5018.2 PR5020.2 PR5021.2 PR5022.2 PR5023.2 PR5026.2 PR5027.2 PR5028.2 PR5029.2 PR5030.2 Q2405.4 R801.2 R1101.1 R1103.1 R1104.1 R1201.1 R1203.1 R3816.2 TC1101.1
1D05V_CPU_SA: C304.1 C305.1 CPU1.AA6 CPU1.AA7 CPU1.AB6 CPU1.AB7 CPU1.AB8 CPU1.AC7 CPU1.AC8 CPU1.N7 CPU1.P7 CPU1.R7 CPU1.T7 CPU1.U7 CPU1.V7 CPU1.W7 CPU1.Y6 CPU1.Y7 CPU1.Y8 PC1050.1 PC1051.1 PC1052.1 PC1053.1 PC4705.1 PG4701.1 PL4701.2 PT4701.1 PT4702.1
1D05V_LAN: C3103.1 C3104.1 C3106.1 C3107.1 C3108.1 C3111.1 C3112.1 U3101.3 U3101.8 U3101.22 U3101.24 U3101.30
1D8V_PCH: C2108.1 R1521.1 R1522.1 R2101.2 R2303.2 R2310.2 R6316.1 R6317.1 SB1.AF19 SB1.AF20 SB1.AG19 SB1.AG20 SB1.AN15 SB1.AR15 SB1.BB11
1D24V_PCH: C2109.1 SB1.AJ22 SB1.AJ23 SB1.AK22 SB1.AK23 SB1.BG5
2D5V_VPP_S3: C1103.1 C1104.1 C1206.1 C1207.1 DIMM1.142 DIMM1.143 DIMM1.286 DIMM1.287 DIMM1.288 DIMM2.142 DIMM2.143 DIMM2.286 DIMM2.287 DIMM2.288 PR5203.2
3D3V_AUD_S0: C2706.1 C2707.1 C2713.1 C2714.1 C2718.1 L2702.2 L2703.2 U2701.5 U2701.37 U2701.48
3D3V_CARD_CON_S0: C3306.1 C3307.1 F3301.2 SD1.4
3D3V_CARD_S0: F3301.1 U3301.5
3D3V_LAN: C3101.1 C3102.1 C3105.1 C3113.1 C3114.1 C3117.1 R3105.2 RJ45R1.21 U3101.11 U3101.23 U3101.32
3D3V_PCIVAUX_SB: C9203.1 C9312.1 C9404.1 C9410.1 C9411.1 R9403.2 R9501.2 R9512.2 SLOT1.B10 SLOT2.B10 SLOT3.B10 SLOT4.27 U9501.4
3D3V_S0: C1109.1 C1110.1 C1216.1 C1217.1 C2406.1 C3301.1 C3302.1 C4001.1 C4002.1 C4004.1 C4005.1 C4210.2 C4211.1 C4212.1 C5904.1 C5905.1 C6201.1 C6203.1 C6205.1 C6206.1 C6213.1 C6214.1 C9207.1 C9208.1 C9209.1 C9311.1 C9403.1 C9408.1 C9519.1 C9520.1 C9521.1 D2601.K D2602.K DIMM1.284 DIMM2.140 DIMM2.284 L2702.1 L5901.1 L5902.1 LPC1.10 NGFF2.2 NGFF2.4 NGFF2.12 NGFF2.14 NGFF2.16 NGFF2.18 NGFF2.70 NGFF2.72 NGFF2.74 Q2406.4 Q4201.1 Q4201.2 Q4201.3 Q5601.2 Q5601.5 R1505.1 R1506.1 R1601.2 R1704.2 R1706.2 R1714.2 R1801.2 R1803.2 R1805.2 R1806.1 R1807.2 R1809.2 R1810.2 R1811.2 R1906.2 R1907.2 R1908.2 R1910.2 R1911.2 R1912.2 R2001.2 R2002.2 R2003.2 R2302.2 R2308.2 R2324.2 R2327.2 R2329.2 R2404.1 R2405.1 R2412.1 R2413.1 R2414.1 R2415.1 R2435.1 R2459.2 R2461.2 R2462.2 R2463.2 R2464.2 R2465.2 R2469.2 R2470.2 R2473.2 R2476.2 R2603.1 R2616.1 R2706.1 R2707.1 R2717.1 R3103.1 R4003.1 R4005.1 R4022.2 R4205.1 R4801.1 R5610.2 R5901.1 R5902.1 R5903.2 R5905.1 R5906.1 R5907.1 R5918.1 R5919.1 R6314.1 R6402.1 R6403.1 R6404.1 R6416.2 R6420.1 R6421.2 R6422.1 R9101.1 R9204.1 R9205.1 RN2402.5(B) RN2402.6(B) RN2402.7(B) RN2402.8(B) RN2403.6(B) RN2403.7(B) RN2403.8(B) RN9501.3(B) RN9501.4(B) RN9502.3(B) RN9502.4(B) RN9503.5(B) RN9503.6(B) RN9503.7(B) RN9503.8(B) RN9504.5(B) RN9504.6(B) RN9504.7(B) RN9504.8(B) RN9505.5(B) RN9505.6(B) RN9505.7(B) RN9505.8(B) RN9506.5(B) RN9506.6(B) RN9506.7(B) RN9506.8(B) SATAP1.6 SATAP2.6 SLOT1.A9 SLOT1.A10 SLOT1.B8 SLOT2.A9 SLOT2.A10 SLOT2.B8 SLOT3.A9 SLOT3.A10 SLOT3.B8 SLOT4.41 SLOT4.50 SLOT4.53 SLOT4.62 SLOT4.65 SLOT4.72 SLOT4.77 SLOT4.82 SLOT4.86 SLOT4.89 SLOT4.101 SLOT4.104 U2401.4 U3301.4 U4001.5 U4004.5 U4006.5 U4007.5 U5601.2 U5601.5 U5901.14 U5901.26 U9501.35 U9501.47 U9501.57 U9501.72 U9501.84 U9501.94 U9501.110 U9501.123
3D3V_S5: APS1.13 C2107.1 C2410.1 C2415.1 C2416.1 C2417.1 C2418.1 C2419.1 C2420.1 C2421.1 C2422.1 C2423.1 C2424.1 C2721.1 C4204.1 C6310.1 PR4901.1 PR4902.1 PR4903.1 PR4904.1 PR4905.1 PR4906.1 PR4908.1 PR4910.1 PR4912.1 PR4914.1 PR4916.1 PR4918.1 PR4920.1 PR4922.1 PR4924.1 PR5201.2 PR5202.1 Q2701.E Q4201.5 Q4201.6 Q4201.7 Q4201.8 R2014.2 R2015.2 R2016.2 R2018.2 R2044.2 R2318.2 R2403.1 R2504.1 R2613.1 R2714.2 R3818.1 R6306.1 R6308.1 R6313.1 R6318.1 R6401.1 SB1.BE48 SB1.BE49 U2401.22 U2401.32 U2401.45 U2401.55 U2401.60 U2401.65 U2401.77 U2401.104 U2401.120 U2403.5 U2601.5 U2602.5 U4201.6 U4201.7 U6301.4 U6301.5
3D3V_SB: APS1.12 C2002.1 C2003.1 C2005.1 C2104.1 C2105.1 C2106.1 C2126.1 C2408.1 C2409.1 C4003.1 C4006.1 C4007.1 C4011.1 C4205.1 C4206.1 C4305.1 C9104.1 C9105.1 JMP1.2 L2703.1 PR5107.1 R413.1 R414.1 R1502.2 R1503.2 R1508.1 R1509.1 R1602.2 R1603.2 R1604.2 R1605.2 R1705.2 R1709.1 R1712.1 R1901.2 R1902.2 R1904.2 R1918.2 R2007.2 R2009.2 R2010.2 R2012.2 R2013.2 R2034.1 R2041.1 R2045.2 R2102.2 R2301.2 R2307.2 R2314.2 R2319.2 R2321.2 R2411.1 R2421.2 R2425.2 R2427.2 R2431.2 R2432.2 R2436.2 R2437.2 R2452.1 R2478.2 R2503.1 R3105.1 R3811.1 R4001.1 R4011.1 R4017.1 R4018.1 R4802.1 R4803.2 R6410.1 R6412.1 R9104.1 R9113.1 R9403.1 R9922.2 RN1601.6(B) RN1601.7(B) RN1601.8(B) RN2401.5(B) RN2401.6(B) RN2401.7(B) RN2401.8(B) SB1.AC35 SB1.AC36 SB1.AE35 SB1.AE36 SB1.AN21 SB1.AN26 SB1.AN32 SB1.AN44 SB1.AP26 SB1.AT44 SB1.AW9 SB1.AY8 SB1.BB7 SB1.BB14 SB1.V23 U2001.1 U2001.5 U2002.2 U2002.7 U2002.8 U2003.1 U2003.5 U2401.27 U2402.1 U2402.5 U2405.5 U4005.1 U4005.5 U4008.1 U4008.5 U4009.5 U4010.5 U4201.8 U4201.9 U4301.5 U9101.1
3D3V_SPI: C2501.1 R2313.2 R2317.2 R2325.2 R2501.1 R2502.1 R2503.2 SSKT1.8 SSKT2.2 U2501.8 U2502.2
3D3V_WLAN_SB: C6301.1 C6302.1 C6303.1 C6304.1 C6307.1 C6308.1 C6309.1 NGFF1.2 NGFF1.4 NGFF1.72 NGFF1.74 R6308.2 R6311.1 R6312.1 U6301.3
3P0V_BAT_VREG: C2102.1 C2103.1 D2502.3 R1507.2 R2040.2 R2042.1 SB1.BC49 SB1.BD49
3P3V_S5_EN: C5101.1 PU5101.3 R5101.2
A20GATE: R2464.1 U2401.119
ACK64_N1: R9204.2 SLOT4.115
ACPRESENT: R2015.1 SB1.BG42
ALDO_CAP: C2710.1 U2701.23
ALL_SYS_PWRGD: C4008.1 R4014.1 R4016.1 U4009.4
AUD_AZACPU_SCLK: CPU1.V3 R2027.1
AUD_AZACPU_SCLK_R: R2027.2 SB1.AM3
AUD_AZACPU_SDI: CPU1.U1 R702.1
AUD_AZACPU_SDI_R: R702.2 SB1.AN3
AUD_AZACPU_SDO: CPU1.V2 R2025.1
AUD_AZACPU_SDO_R: R2025.2 SB1.AM2
AUD_BEEP: C2716.1 U2701.8
AUD_BEEP_R: C2716.2 C2717.1 R2702.1 R2704.1
AUD_LINE1_L: C3001.1 U2701.28
AUD_LINE1_R: C3002.1 U2701.27
AUD_LINE2_L: C2901.1 U2701.13
AUD_LINE2_R: C2902.1 U2701.14
AUD_LINK_SDO_C: Q2001.C R2038.2 R2039.1
AUD_LINK_SDO_R1: JMP1.1 R2039.2
AUD_MIC1_L: C3007.1 U2701.15
AUD_MIC1_R: C3008.1 U2701.16
AUD_MIC2_L: C2905.1 U2701.19
AUD_MIC2_L_C: C2901.2 C2902.2 R2902.1
AUD_MIC2_R: C2904.1 U2701.20
AUD_VREF: C2703.1 U2701.25
AUDOUT_L: R3005.1 U2701.40
AUDOUT_LL: L3003.1 Q3001.3 R3005.2 R3007.1
AUDOUT_R: R3006.1 U2701.39
AUDOUT_RR: L3004.1 Q3001.6 R3006.2 R3009.1
BATLOW_N: R2016.1 SB1.BF44
BLUE_CRT: C5919.1 EU5901.4 L5905.2 VGA1.3
BPM_CPU_N0: CPU1.D16 XDP1.21
BPM_CPU_N1: CPU1.D17 XDP1.23
BPM_CPU_N2: CPU1.G14 TP401.1
BPM_CPU_N3: CPU1.H14 TP402.1
CAP_1: C2414.1 U2401.128
CATERR#_CPU: CPU1.D13 TP403.1
CBN: C2702.1 U2701.34
CBP: C2702.2 U2701.36
CEC_PS_ON_N: Q4301.C R4303.1
CEC_PS_ON_N_EXTD1: Q4301.B R4304.2
CEC_PS_ON_N_EXTD2: D4303.3 R4304.1 U4301.4
CK_100M_CPU_XDP_DN: SB1.Y3 XDP1.42
CK_100M_CPU_XDP_DP: SB1.Y4 XDP1.40
CLKIN_XTAL: R1815.1 SB1.R6
CNV_BRI_DT: R1517.2 R1522.2 R2303.1 R2305.1 SB1.AV4
CNV_BRI_DT_R: NGFF1.36 R1517.1
CNV_BRI_RSP: R1518.1 R6316.2 SB1.AY2
CNV_BRI_RSP_R: NGFF1.22 R1518.2
CNV_DET_G: Q6301.2 Q6301.5 R6318.2 U6305.D
CNV_DET_S: D6301.A D6302.A R6313.2 U6302.S
CNV_RGI_DT: R1519.2 R1521.2 R2310.1 R2312.1 SB1.BA4
CNV_RGI_DT_R: NGFF1.32 R1519.1
CNV_RGI_RSP: R1520.1 R6317.2 SB1.AV3
CNV_RGI_RSP_R: NGFF1.34 R1520.2
CNV_WR_0_DN: NGFF1.15 SB1.BB3
CNV_WR_0_DP: NGFF1.17 SB1.BB4
CNV_WR_1_DN: NGFF1.9 SB1.BA3
CNV_WR_1_DP: NGFF1.11 SB1.BA2
CNV_WR_CLK_DN: NGFF1.21 SB1.BD4
CNV_WR_CLK_DP: NGFF1.23 SB1.BE3
CNV_WT_0_DN: NGFF1.65 SB1.BE6
CNV_WT_0_DP: NGFF1.67 SB1.BD7
CNV_WT_1_DN: NGFF1.59 SB1.BG6
CNV_WT_1_DP: NGFF1.61 SB1.BF6
CNV_WT_CLK_DN: NGFF1.71 SB1.BC5
CNV_WT_CLK_DP: NGFF1.73 SB1.BB6
CNV_WT_RCOMP: R1512.1 SB1.BA1
CPU1_AY3: CPU1.AY3 R903.2
CPU1_G8: CPU1.G8 R902.2
CPU_FAN_CTRL_CONN: D2601.A FANC1.4 R2603.2 R2605.2
CPU_FAN_CTRL_SIO: R2605.1 U2401.47
CPU_FAN_TACH_1: FANC1.3 R2601.2 R2602.1
CPU_FAN_TACH_SIO: R2602.2 R2604.1 U2401.37
CPU_THERMDA+: C2401.1 C2404.1 Q2404.B Q2404.C U2401.41
CPU_THERMDA-: C2401.2 C2404.2 Q2404.E U2401.42
CPVEE: C2701.2 U2701.33
DAS/DSS#: NGFF2.10 R6420.2 U6402.2
DAS/DSS#_NMOS: R6421.1 U6402.5 U6402.6
DCPRTC: C2101.1 SB1.BF47 SB1.BG47
DDI_VGA_DATA_C_N2: C5913.1 U5901.6
DDI_VGA_DATA_C_N3: C5915.1 U5901.8
DDI_VGA_DATA_C_P2: C5912.1 U5901.5
DDI_VGA_DATA_C_P3: C5914.1 U5901.7
DDI_VGA_DATA_CPU_N2: C5913.2 CPU1.H10
DDI_VGA_DATA_CPU_N3: C5915.2 CPU1.G9
DDI_VGA_DATA_CPU_P2: C5912.2 CPU1.G10
DDI_VGA_DATA_CPU_P3: C5914.2 CPU1.F9
DDPC_CTRL_CLK: R1906.1 SB1.AN13
DDPC_CTRL_DATA: R2327.1 SB1.AL10
DDPD_CTRL_CLK: R1907.1 SB1.AL9
DDPD_CTRL_DATA: R2329.1 SB1.AR3
DDR_VTT_CNTL_CPU: R414.2 R4025.1 U401.3
DDR_VTT_CNTL_GATE: R413.2 U401.5 U401.6
DDR_VTT_CNTL_R: R416.1 U401.2
DDSP_B_TX_N0: Q5601.6 R5601.2 R5602.2 R5603.2 R5604.2 R5605.2 R5606.2 R5607.2 R5608.2
DIMM1_EVENT_N: DIMM1.78 R1101.2
DIMM2_EVENT_N: DIMM2.78 R1201.2
DIMM_CA_CPU_VREF_RC: C602.2 R602.1
DIMM_CA_VREF_A: R601.2 R1103.2 R1105.1 R1106.1
DIMM_CA_VREF_A_L: C1106.1 C1107.1 DIMM1.146 R1105.2
DIMM_CA_VREF_B: R1203.2 R1205.1 R1206.1
DIMM_CA_VREF_B_L: C1210.1 C1211.1 DIMM2.146 R1204.2 R1205.2
DIMM_DQ_CPU_VREF_B_RC: C1209.2 R1207.1
DISP_UTIL_CPU: CPU1.D14 TP701.1
DLDO_CAP: C2711.1 C2712.1 U2701.47
DMI_RX_CPU_N0: CPU1.Y4 SB1.C29
DMI_RX_CPU_N1: CPU1.AA5 SB1.C31
DMI_RX_CPU_N2: CPU1.AB3 SB1.C32
DMI_RX_CPU_N3: CPU1.AC5 SB1.C33
DMI_RX_CPU_P0: CPU1.Y3 SB1.B29
DMI_RX_CPU_P1: CPU1.AA4 SB1.B31
DMI_RX_CPU_P2: CPU1.AB4 SB1.B32
DMI_RX_CPU_P3: CPU1.AC4 SB1.B33
DMI_TX_CPU_N0: CPU1.AC1 SB1.G30
DMI_TX_CPU_N1: CPU1.AD2 SB1.K32
DMI_TX_CPU_N2: CPU1.AE1 SB1.G33
DMI_TX_CPU_N3: CPU1.AF3 SB1.K34
DMI_TX_CPU_P0: CPU1.AC2 SB1.F30
DMI_TX_CPU_P1: CPU1.AD3 SB1.J32
DMI_TX_CPU_P2: CPU1.AE2 SB1.F34
DMI_TX_CPU_P3: CPU1.AF2 SB1.J35
DP_AUX_CON_N: C5911.1 U5901.3
DP_AUX_CON_P: C5910.1 U5901.2
DP_AUX_CPU_N: C5911.2 CPU1.E12
DP_AUX_CPU_P: C5910.2 CPU1.D12
DP_HPD_CPU: R1701.1 R5910.1 SB1.AL15 U5901.32
EAPD: R2719.1 U2701.45
EC_PWRGD_3V: R2433.2 U2401.57
EDP_5VDDCCL: EU5902.1 RN5901.4(B) U5901.15 VGA1.15
EDP_5VDDCDA: EU5902.3 RN5901.3(B) U5901.16 VGA1.12
EDP_AVC12: C5901.1 C5902.1 C5903.2 U5901.4 U5901.25
EDP_AVC33: C5908.1 L5901.2 U5901.1
EDP_BLUE_P: C5916.1 L5905.1 R5913.1 U5901.21
EDP_DAC33: C5909.1 L5902.2 U5901.20
EDP_EXPCLKIN: R5904.1 U5901.28
EDP_GPI1: R5905.2 U5901.11
EDP_GPI2: R5906.2 U5901.12
EDP_GPI3: R5907.2 U5901.13
EDP_GREEN_P: C5917.1 L5904.1 R5914.1 U5901.22
EDP_HSYNC: R5917.1 U5901.19
EDP_HSYNC_C: C5923.1 EU5902.6 R5917.2 VGA1.13
EDP_LDORSTB: R5903.1 U5901.27
EDP_RED_P: C5918.1 L5903.1 R5915.1 U5901.23
EDP_VSYNC: R5916.1 U5901.18
EDP_VSYNC_C: C5922.1 EU5902.4 R5916.2 VGA1.14
EXT_ARB: R9511.1 U9501.92
FDI_COMP: CPU1.M9 R701.1
FORM_FAC_ID_0: R6404.2 R6408.1 SB1.BD38
FORM_FAC_ID_1: R6403.2 R6407.1 SB1.BF35
FORM_FAC_ID_2: R6402.2 R6406.1 SB1.BD34
FORM_FAC_ID_3: R6422.2 R6423.1 SB1.BE34
FP_CBL_DET_PD: R2448.2 U2401.50
FP_MIC2_L: C2903.1 FL2901.2 HPMIC1.4
FP_OUT_L: C2906.1 FL2903.2 HPMIC1.1
FP_OUT_LL: FL2903.1 Q2901.6 R2906.2 R2907.1
FP_OUT_R: C2907.1 FL2902.2 HPMIC1.2
FP_OUT_RR: FL2902.1 Q2901.3 R2905.2 R2909.1
FP_RST_N: R2045.1 R9921.1 SB1.AU2 XDP1.48
FP_RST_N_CN: APS1.2 R9921.2
FRONT_JD: AUD1.23 R2710.2
GPD7: R2318.1 SB1.BE41
GPD10: R2057.1 SB1.BC42
GPIO_LAN_RESET_N: R1912.1 SB1.M45 U4001.2
GPIO_PCI_RESET_N: R1601.1 SB1.AV43 U4007.2
GPIO_PEG_RESET_N: R1911.1 SB1.AT49 U4006.2
GPP_A7: R1918.1 R1919.1 SB1.BA36
GPP_A8: R2001.1 SB1.AV32
GPP_A14: R1920.1 SB1.BF38
GPP_H_12: R2322.1 SB1.AB47
GPP_H_15: R2301.1 R2330.1 SB1.AC47
GPP_J0_CNV_BLANKING: NGFF1.44 SB1.AV6
GPP_J1: R1511.2 SB1.AY3
GPP_J8_CNV_RXD: NGFF1.48 SB1.AW2
GPP_J9_CNV_TXD: NGFF1.46 R2315.1 SB1.AU9
GPP_K3: R6314.2 R6315.1 SB1.U47 U6302.G
GPP_K5: R1713.1 R1714.1 SB1.N47
GREEN_CRT: C5920.1 EU5901.1 L5904.2 VGA1.2
H_PRDY_N: CPU1.B10 R9902.2 XDP1.5
H_PREQ_N: CPU1.B9 R9901.2 XDP1.3
H_PWRGD: C402.1 CPU1.F8 R2006.2 R9907.1
H_PWRGD_R: R2006.1 SB1.AE3
H_RSTOUT_XDP_N: R9909.2 R9910.2 R9911.2 XDP1.46
H_SKTOCC_CPU: CPU1.AC38 R2477.2 R2478.1 U2405.1
H_SKTOCC_N: R1509.2 R2477.1 SB1.AP3 U2405.4
H_TCK: CPU1.F11 R415.1 R2008.2 XDP1.57
H_TDI: CPU1.G12 R411.1 XDP1.56
H_TDO: CPU1.H13 R402.1 R410.1 XDP1.52
H_TMS: CPU1.F13 R412.1 XDP1.58
H_TRST_N: CPU1.F12 R417.1 R9915.1 XDP1.54
H_TRST_N_R: R417.2 SB1.AM4
HDA_BITCLK_CODEC: C2715.1 R2017.1 U2701.2
HDA_BITCLK_PCH: R2017.2 R2055.1 SB1.BD11
HDA_RST#_CODEC: R2019.1 R2718.1 U2701.7
HDA_RST#_PCH: R2019.2 R2056.1 SB1.BE10
HDA_SDIN0_CODEC: R2703.2 U2701.4
HDA_SDIN0_PCH: R2703.1 SB1.BE11
HDA_SDOUT_CODEC: R2020.1 U2701.3
HDA_SDOUT_PCH: R2020.2 R2038.1 SB1.BF12
HDA_SYNC_CODEC: R2022.1 U2701.6
HDA_SYNC_PCH: R2022.2 SB1.BG13
HDD_LED_PWR1: LED1.A R6418.2
HDMI1_DETECT: R1702.2 SB1.P47
HDMI_CLK_CON: C5610.1 EU5603.1 EU5603.10 HDMI1.15 RN5601.4(B) U5601.3
HDMI_CLK_CPU: R1908.1 SB1.AL13 U5601.4
HDMI_DATA_CMC_N0: C5602.2 R5601.1 TR5601.4
HDMI_DATA_CMC_N1: C5604.2 R5603.1 TR5602.4
HDMI_DATA_CMC_N2: C5606.2 R5605.1 TR5603.4
HDMI_DATA_CMC_N3: C5608.2 R5607.1 TR5604.4
HDMI_DATA_CMC_P0: C5601.2 R5602.1 TR5601.3
HDMI_DATA_CMC_P1: C5603.2 R5604.1 TR5602.3
HDMI_DATA_CMC_P2: C5605.2 R5606.1 TR5603.3
HDMI_DATA_CMC_P3: C5607.2 R5608.1 TR5604.3
HDMI_DATA_CON: C5611.1 EU5603.2 EU5603.9 HDMI1.16 RN5601.3(B) U5601.6
HDMI_DATA_CON_N0: EU5601.2 EU5601.9 HDMI1.3 TR5601.1
HDMI_DATA_CON_N1: EU5601.5 EU5601.6 HDMI1.6 TR5602.1
HDMI_DATA_CON_N2: EU5602.2 EU5602.9 HDMI1.9 TR5603.1
HDMI_DATA_CON_N3: EU5602.5 EU5602.6 HDMI1.12 TR5604.1
HDMI_DATA_CON_P0: EU5601.1 EU5601.10 HDMI1.1 TR5601.2
HDMI_DATA_CON_P1: EU5601.4 EU5601.7 HDMI1.4 TR5602.2
HDMI_DATA_CON_P2: EU5602.1 EU5602.10 HDMI1.7 TR5603.2
HDMI_DATA_CON_P3: EU5602.4 EU5602.7 HDMI1.10 TR5604.2
HDMI_DATA_CPU: R2324.1 SB1.AR8 U5601.1
HDMI_DATA_CPU_N0: C5602.1 CPU1.D21
HDMI_DATA_CPU_N1: C5604.1 CPU1.E22
HDMI_DATA_CPU_N2: C5606.1 CPU1.A23
HDMI_DATA_CPU_N3: C5608.1 CPU1.D23
HDMI_DATA_CPU_P0: C5601.1 CPU1.C21
HDMI_DATA_CPU_P1: C5603.1 CPU1.D22
HDMI_DATA_CPU_P2: C5605.1 CPU1.B23
HDMI_DATA_CPU_P3: C5607.1 CPU1.C23
HDMI_DET_CON: EU5603.4 EU5603.7 HDMI1.19 Q5601.3 R5609.1
HDMI_DET_CPU: Q5601.4 R1702.1 R5610.1 SB1.AT6
HP_OUT_L: C2905.2 R2904.2 R2906.1 U2701.31
HP_OUT_R: C2904.2 R2903.2 R2905.1 U2701.32
I2C0_SCL_VGA: R5911.1 R5918.2 U5901.30
I2C0_SDA_VGA: R5912.1 R5919.2 U5901.29
I2S1_SFRM: R2058.1 SB1.BD12
IDSEL_1: R9203.2 SLOT4.51
IO_SMI_N: R2420.2 U2401.126
ITP_PMODE: R9911.1 SB1.AL3
KBRST_N: R2463.1 SB1.BE39 U2401.118
KCLK: RN2401.4(A) U2401.113
KDAT: RN2401.3(A) U2401.114
LAN_CONN_CVT: RJ45R1.9 UC3201.1 UC3202.1
LAN_LEDACT_R#: EU3202.6 R3204.1 RJ45R1.22
LAN_MDI0_DN: R3203.3 U3101.2
LAN_MDI0_DN_C: EU3201.1 R3203.2 RJ45R1.11
LAN_MDI0_DP: R3203.4 U3101.1
LAN_MDI0_DP_C: EU3201.6 R3203.1 RJ45R1.10
LAN_MDI1_DN: R3205.3 U3101.5
LAN_MDI1_DN_C: EU3201.4 R3205.2 RJ45R1.13
LAN_MDI1_DP: R3205.4 U3101.4
LAN_MDI1_DP_C: EU3201.3 R3205.1 RJ45R1.12
LAN_MDI2_DN: R3206.3 U3101.7
LAN_MDI2_DN_C: EU3203.1 R3206.2 RJ45R1.15
LAN_MDI2_DP: R3206.4 U3101.6
LAN_MDI2_DP_C: EU3203.6 R3206.1 RJ45R1.14
LAN_MDI3_DN: R3207.3 U3101.10
LAN_MDI3_DN_C: EU3203.4 R3207.2 RJ45R1.17
LAN_MDI3_DP: R3207.4 U3101.9
LAN_MDI3_DP_C: EU3203.3 R3207.1 RJ45R1.16
LAN_RSET: R3101.2 U3101.31
LAN_XTALI: C3119.1 R3104.2 U3101.28 X3101.1
LAN_XTALO: R3104.1 R3107.1 U3101.29
LAN_XTALO_C: C3118.1 R3107.2 X3101.3
LANCLK_REQ_U_N: R3102.1 U3101.12
LANWAKE_R_N: R2018.1 SB1.BG44
LDO5V: PG4903.2 PR4958.2 PR4959.1
LDO_18V: C9505.1 C9506.1 C9507.1 C9508.1 L9501.1 L9502.1 U9501.59
LDO_AUX_18V: C9509.1 C9510.1 C9511.1 C9512.1 L9503.1 L9504.1 U9501.5
LINE1_JD: AUD1.33 R2711.2
LINE1_JD/LINE2_JD: R2707.2 R2711.1 R2712.1 U2701.43
LINE1_LL: L3001.1 R3001.2 R3003.1
LINE1_LL_C: C3001.2 R3001.1
LINE1_RR: L3002.1 R3002.2 R3004.1
LINE1_RR_C: C3002.2 R3002.1
LINE2_JD: HPMIC1.6 R2712.2
LINE2_VREFO: R2901.1 U2701.12
LINEIN_L: D2901.2 R2904.1
LINEIN_R: D2901.3 R2903.1
LINK_ACTIVITY_N: R3204.2 TP3101.1 U3101.27
LPC_AD_PCH_P0: LPC1.9 SB1.BB39 U2401.8
LPC_AD_PCH_P1: LPC1.8 SB1.AW37 U2401.9
LPC_AD_PCH_P2: LPC1.7 SB1.AV37 U2401.10
LPC_AD_PCH_P3: LPC1.6 SB1.BA38 U2401.11
LPC_CLK_14M_DEBUG: LPC1.2 R1915.2
LPC_CLK_14M_EC: R1914.2 U2401.7
LPC_CLK_33M_EC: R1916.2 U2401.16
LPC_CLK_PCH_P0: R1914.1 R1915.1 SB1.BB36
LPC_CLK_PCH_P1: R1916.1 SB1.BB34
LPC_FRAME#_PCH: LPC1.5 R1913.2 U2401.12
LPC_FRAME#_PCH_R: R1913.1 SB1.BE38
LPC_PME_N: R2421.1 SB1.AV21 U2401.75
LPC_SERIRQ_PCH: LPC1.1 R1910.1 SB1.AW35 U2401.127
LPSS_GSPI0_MOSI: R2308.1 R2311.1 SB1.BE30
LPSS_GSPI1_MOSI: R2319.1 R2320.1 SB1.BA26
M_A_A0: CPU1.AW15 DIMM1.79
M_A_A1: CPU1.AU18 DIMM1.72
M_A_A2: CPU1.AU17 DIMM1.216
M_A_A3: CPU1.AV19 DIMM1.71
M_A_A4: CPU1.AT19 DIMM1.214
M_A_A5: CPU1.AU20 DIMM1.213
M_A_A6: CPU1.AV20 DIMM1.69
M_A_A7: CPU1.AU21 DIMM1.211
M_A_A8: CPU1.AT20 DIMM1.68
M_A_A9: CPU1.AT22 DIMM1.66
M_A_A10: CPU1.AY14 DIMM1.225
M_A_A11: CPU1.AU22 DIMM1.210
M_A_A12: CPU1.AV22 DIMM1.65
M_A_A13: CPU1.AV12 DIMM1.232
M_A_A14: CPU1.AV14 DIMM1.228
M_A_A15: CPU1.AY11 DIMM1.86
M_A_A16: CPU1.AW13 DIMM1.82
M_A_ACT#: CPU1.AU24 DIMM1.62
M_A_ALERT#: CPU1.AT23 DIMM1.208
M_A_BG0: CPU1.AW23 DIMM1.63
M_A_BG1: CPU1.AV23 DIMM1.207
M_A_BS0: CPU1.AY13 DIMM1.81
M_A_BS1: CPU1.AV15 DIMM1.224
M_A_CKE0: CPU1.AY24 DIMM1.60
M_A_CKE1: CPU1.AW24 DIMM1.203
M_A_CLK0: CPU1.AW18 DIMM1.74
M_A_CLK1: CPU1.AW17 DIMM1.218
M_A_CLK#0: CPU1.AV18 DIMM1.75
M_A_CLK#1: CPU1.AY17 DIMM1.219
M_A_CS#0: CPU1.AW12 DIMM1.84
M_A_CS#1: CPU1.AU11 DIMM1.89
M_A_DQ0: CPU1.AE40 DIMM1.5
M_A_DQ1: CPU1.AE37 DIMM1.150
M_A_DQ2: CPU1.AG38 DIMM1.12
M_A_DQ3: CPU1.AG37 DIMM1.157
M_A_DQ4: CPU1.AE39 DIMM1.3
M_A_DQ5: CPU1.AE38 DIMM1.148
M_A_DQ6: CPU1.AG39 DIMM1.10
M_A_DQ7: CPU1.AG40 DIMM1.155
M_A_DQ8: CPU1.AJ40 DIMM1.16
M_A_DQ9: CPU1.AJ37 DIMM1.161
M_A_DQ10: CPU1.AL38 DIMM1.23
M_A_DQ11: CPU1.AL37 DIMM1.168
M_A_DQ12: CPU1.AJ39 DIMM1.14
M_A_DQ13: CPU1.AJ38 DIMM1.159
M_A_DQ14: CPU1.AL39 DIMM1.21
M_A_DQ15: CPU1.AL40 DIMM1.166
M_A_DQ16: CPU1.AN40 DIMM1.27
M_A_DQ17: CPU1.AN37 DIMM1.172
M_A_DQ18: CPU1.AR38 DIMM1.34
M_A_DQ19: CPU1.AR37 DIMM1.179
M_A_DQ20: CPU1.AN39 DIMM1.25
M_A_DQ21: CPU1.AN38 DIMM1.170
M_A_DQ22: CPU1.AR39 DIMM1.32
M_A_DQ23: CPU1.AR40 DIMM1.177
M_A_DQ24: CPU1.AV37 DIMM1.38
M_A_DQ25: CPU1.AW37 DIMM1.183
M_A_DQ26: CPU1.AU35 DIMM1.45
M_A_DQ27: CPU1.AV35 DIMM1.190
M_A_DQ28: CPU1.AU38 DIMM1.36
M_A_DQ29: CPU1.AU37 DIMM1.181
M_A_DQ30: CPU1.AT35 DIMM1.43
M_A_DQ31: CPU1.AW35 DIMM1.188
M_A_DQ32: CPU1.AY8 DIMM1.97
M_A_DQ33: CPU1.AU8 DIMM1.242
M_A_DQ34: CPU1.AV6 DIMM1.104
M_A_DQ35: CPU1.AU6 DIMM1.249
M_A_DQ36: CPU1.AW8 DIMM1.95
M_A_DQ37: CPU1.AV8 DIMM1.240
M_A_DQ38: CPU1.AY6 DIMM1.102
M_A_DQ39: CPU1.AW6 DIMM1.247
M_A_DQ40: CPU1.AV4 DIMM1.108
M_A_DQ41: CPU1.AV3 DIMM1.253
M_A_DQ42: CPU1.AT3 DIMM1.115
M_A_DQ43: CPU1.AT2 DIMM1.260
M_A_DQ44: CPU1.AY4 DIMM1.106
M_A_DQ45: CPU1.AW4 DIMM1.251
M_A_DQ46: CPU1.AT4 DIMM1.113
M_A_DQ47: CPU1.AT1 DIMM1.258
M_A_DQ48: CPU1.AP1 DIMM1.119
M_A_DQ49: CPU1.AP2 DIMM1.264
M_A_DQ50: CPU1.AM3 DIMM1.126
M_A_DQ51: CPU1.AM2 DIMM1.271
M_A_DQ52: CPU1.AP4 DIMM1.117
M_A_DQ53: CPU1.AP3 DIMM1.262
M_A_DQ54: CPU1.AM4 DIMM1.124
M_A_DQ55: CPU1.AM1 DIMM1.269
M_A_DQ56: CPU1.AK1 DIMM1.130
M_A_DQ57: CPU1.AK2 DIMM1.275
M_A_DQ58: CPU1.AH3 DIMM1.137
M_A_DQ59: CPU1.AH2 DIMM1.282
M_A_DQ60: CPU1.AK4 DIMM1.128
M_A_DQ61: CPU1.AK3 DIMM1.273
M_A_DQ62: CPU1.AH4 DIMM1.135
M_A_DQ63: CPU1.AH1 DIMM1.280
M_A_DQS_DN0: CPU1.AF39 DIMM1.152
M_A_DQS_DN1: CPU1.AK39 DIMM1.163
M_A_DQS_DN2: CPU1.AP39 DIMM1.174
M_A_DQS_DN3: CPU1.AU36 DIMM1.185
M_A_DQS_DN4: CPU1.AW7 DIMM1.244
M_A_DQS_DN5: CPU1.AU3 DIMM1.255
M_A_DQS_DN6: CPU1.AN3 DIMM1.266
M_A_DQS_DN7: CPU1.AJ3 DIMM1.277
M_A_DQS_DP0: CPU1.AF38 DIMM1.153
M_A_DQS_DP1: CPU1.AK38 DIMM1.164
M_A_DQS_DP2: CPU1.AP38 DIMM1.175
M_A_DQS_DP3: CPU1.AV36 DIMM1.186
M_A_DQS_DP4: CPU1.AV7 DIMM1.245
M_A_DQS_DP5: CPU1.AU2 DIMM1.256
M_A_DQS_DP6: CPU1.AN2 DIMM1.267
M_A_DQS_DP7: CPU1.AJ2 DIMM1.278
M_A_ODT0: CPU1.AW11 DIMM1.87
M_A_ODT1: CPU1.AU14 DIMM1.91
M_A_PARITY: CPU1.AY15 DIMM1.222
M_B_A0: CPU1.AL19 DIMM2.79
M_B_A1: CPU1.AL22 DIMM2.72
M_B_A2: CPU1.AM22 DIMM2.216
M_B_A3: CPU1.AM23 DIMM2.71
M_B_A4: CPU1.AP23 DIMM2.214
M_B_A5: CPU1.AL23 DIMM2.213
M_B_A6: CPU1.AW26 DIMM2.69
M_B_A7: CPU1.AY26 DIMM2.211
M_B_A8: CPU1.AU26 DIMM2.68
M_B_A9: CPU1.AW27 DIMM2.66
M_B_A10: CPU1.AP18 DIMM2.225
M_B_A11: CPU1.AU27 DIMM2.210
M_B_A12: CPU1.AV27 DIMM2.65
M_B_A13: CPU1.AR15 DIMM2.232
M_B_A14: CPU1.AL17 DIMM2.228
M_B_A15: CPU1.AP16 DIMM2.86
M_B_A16: CPU1.AN18 DIMM2.82
M_B_ACT#: CPU1.AU28 DIMM2.62
M_B_ALERT#: CPU1.AY25 DIMM2.208
M_B_BG0: CPU1.AW28 DIMM2.63
M_B_BG1: CPU1.AY28 DIMM2.207
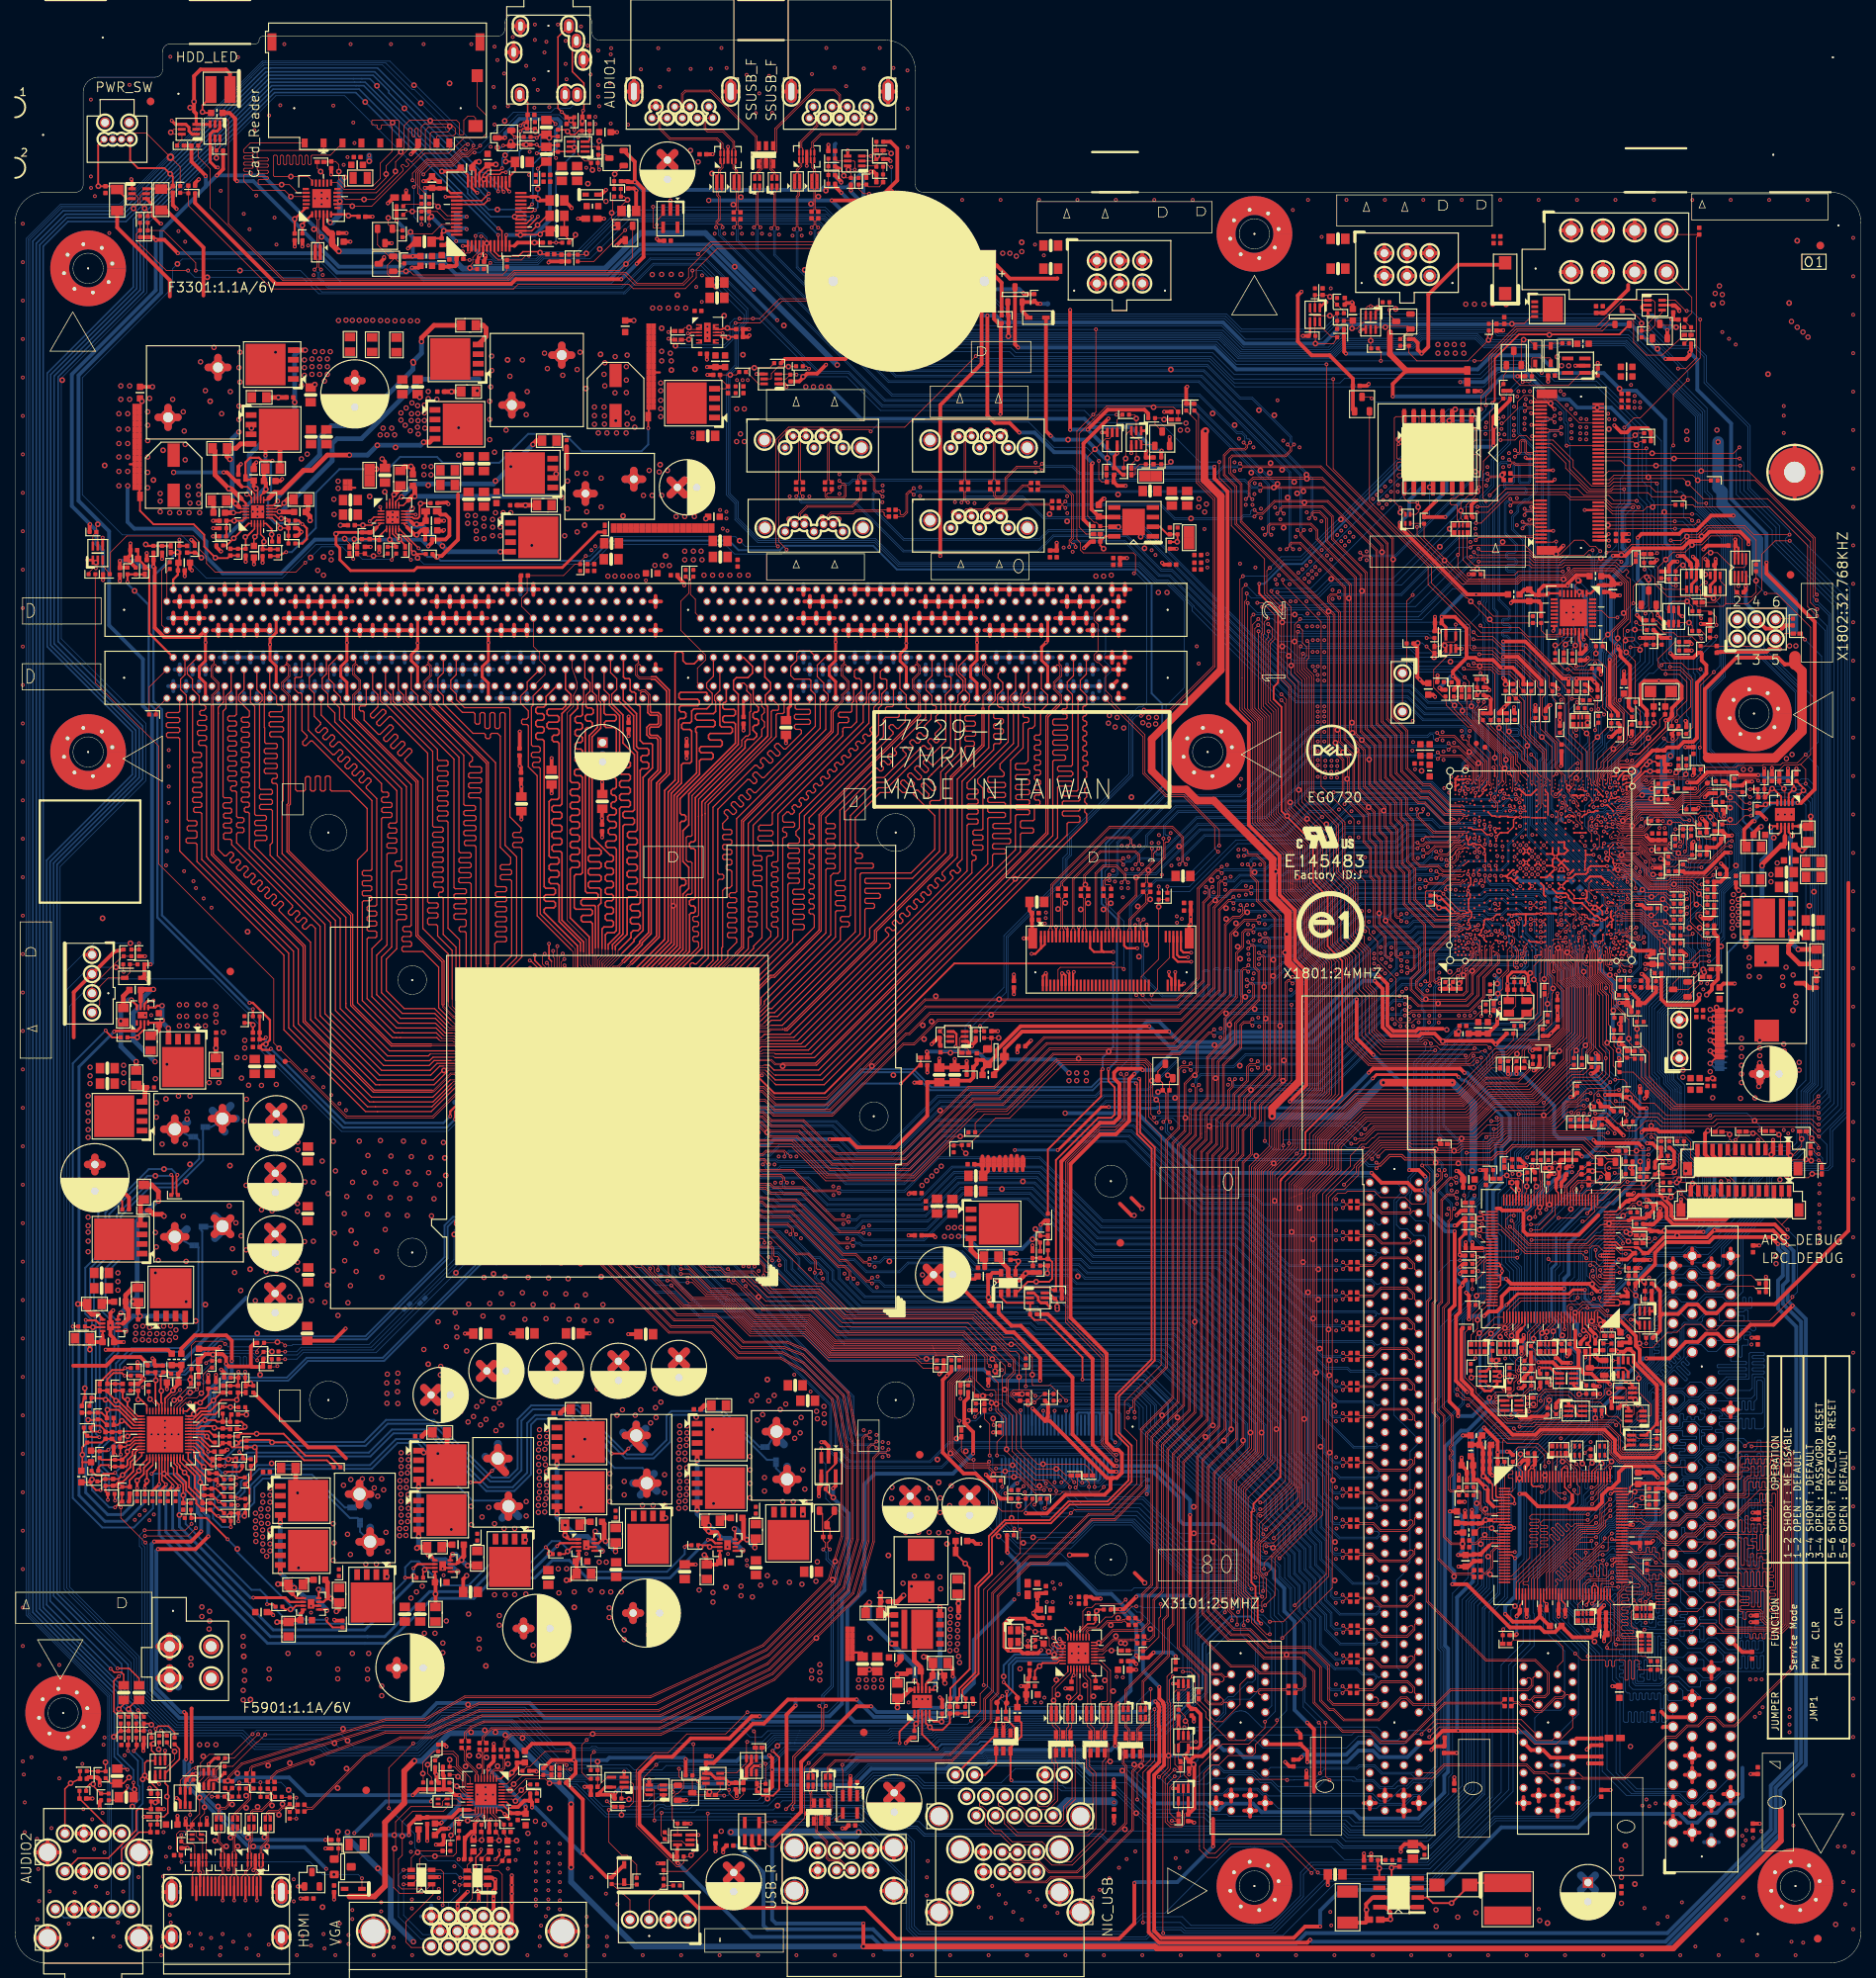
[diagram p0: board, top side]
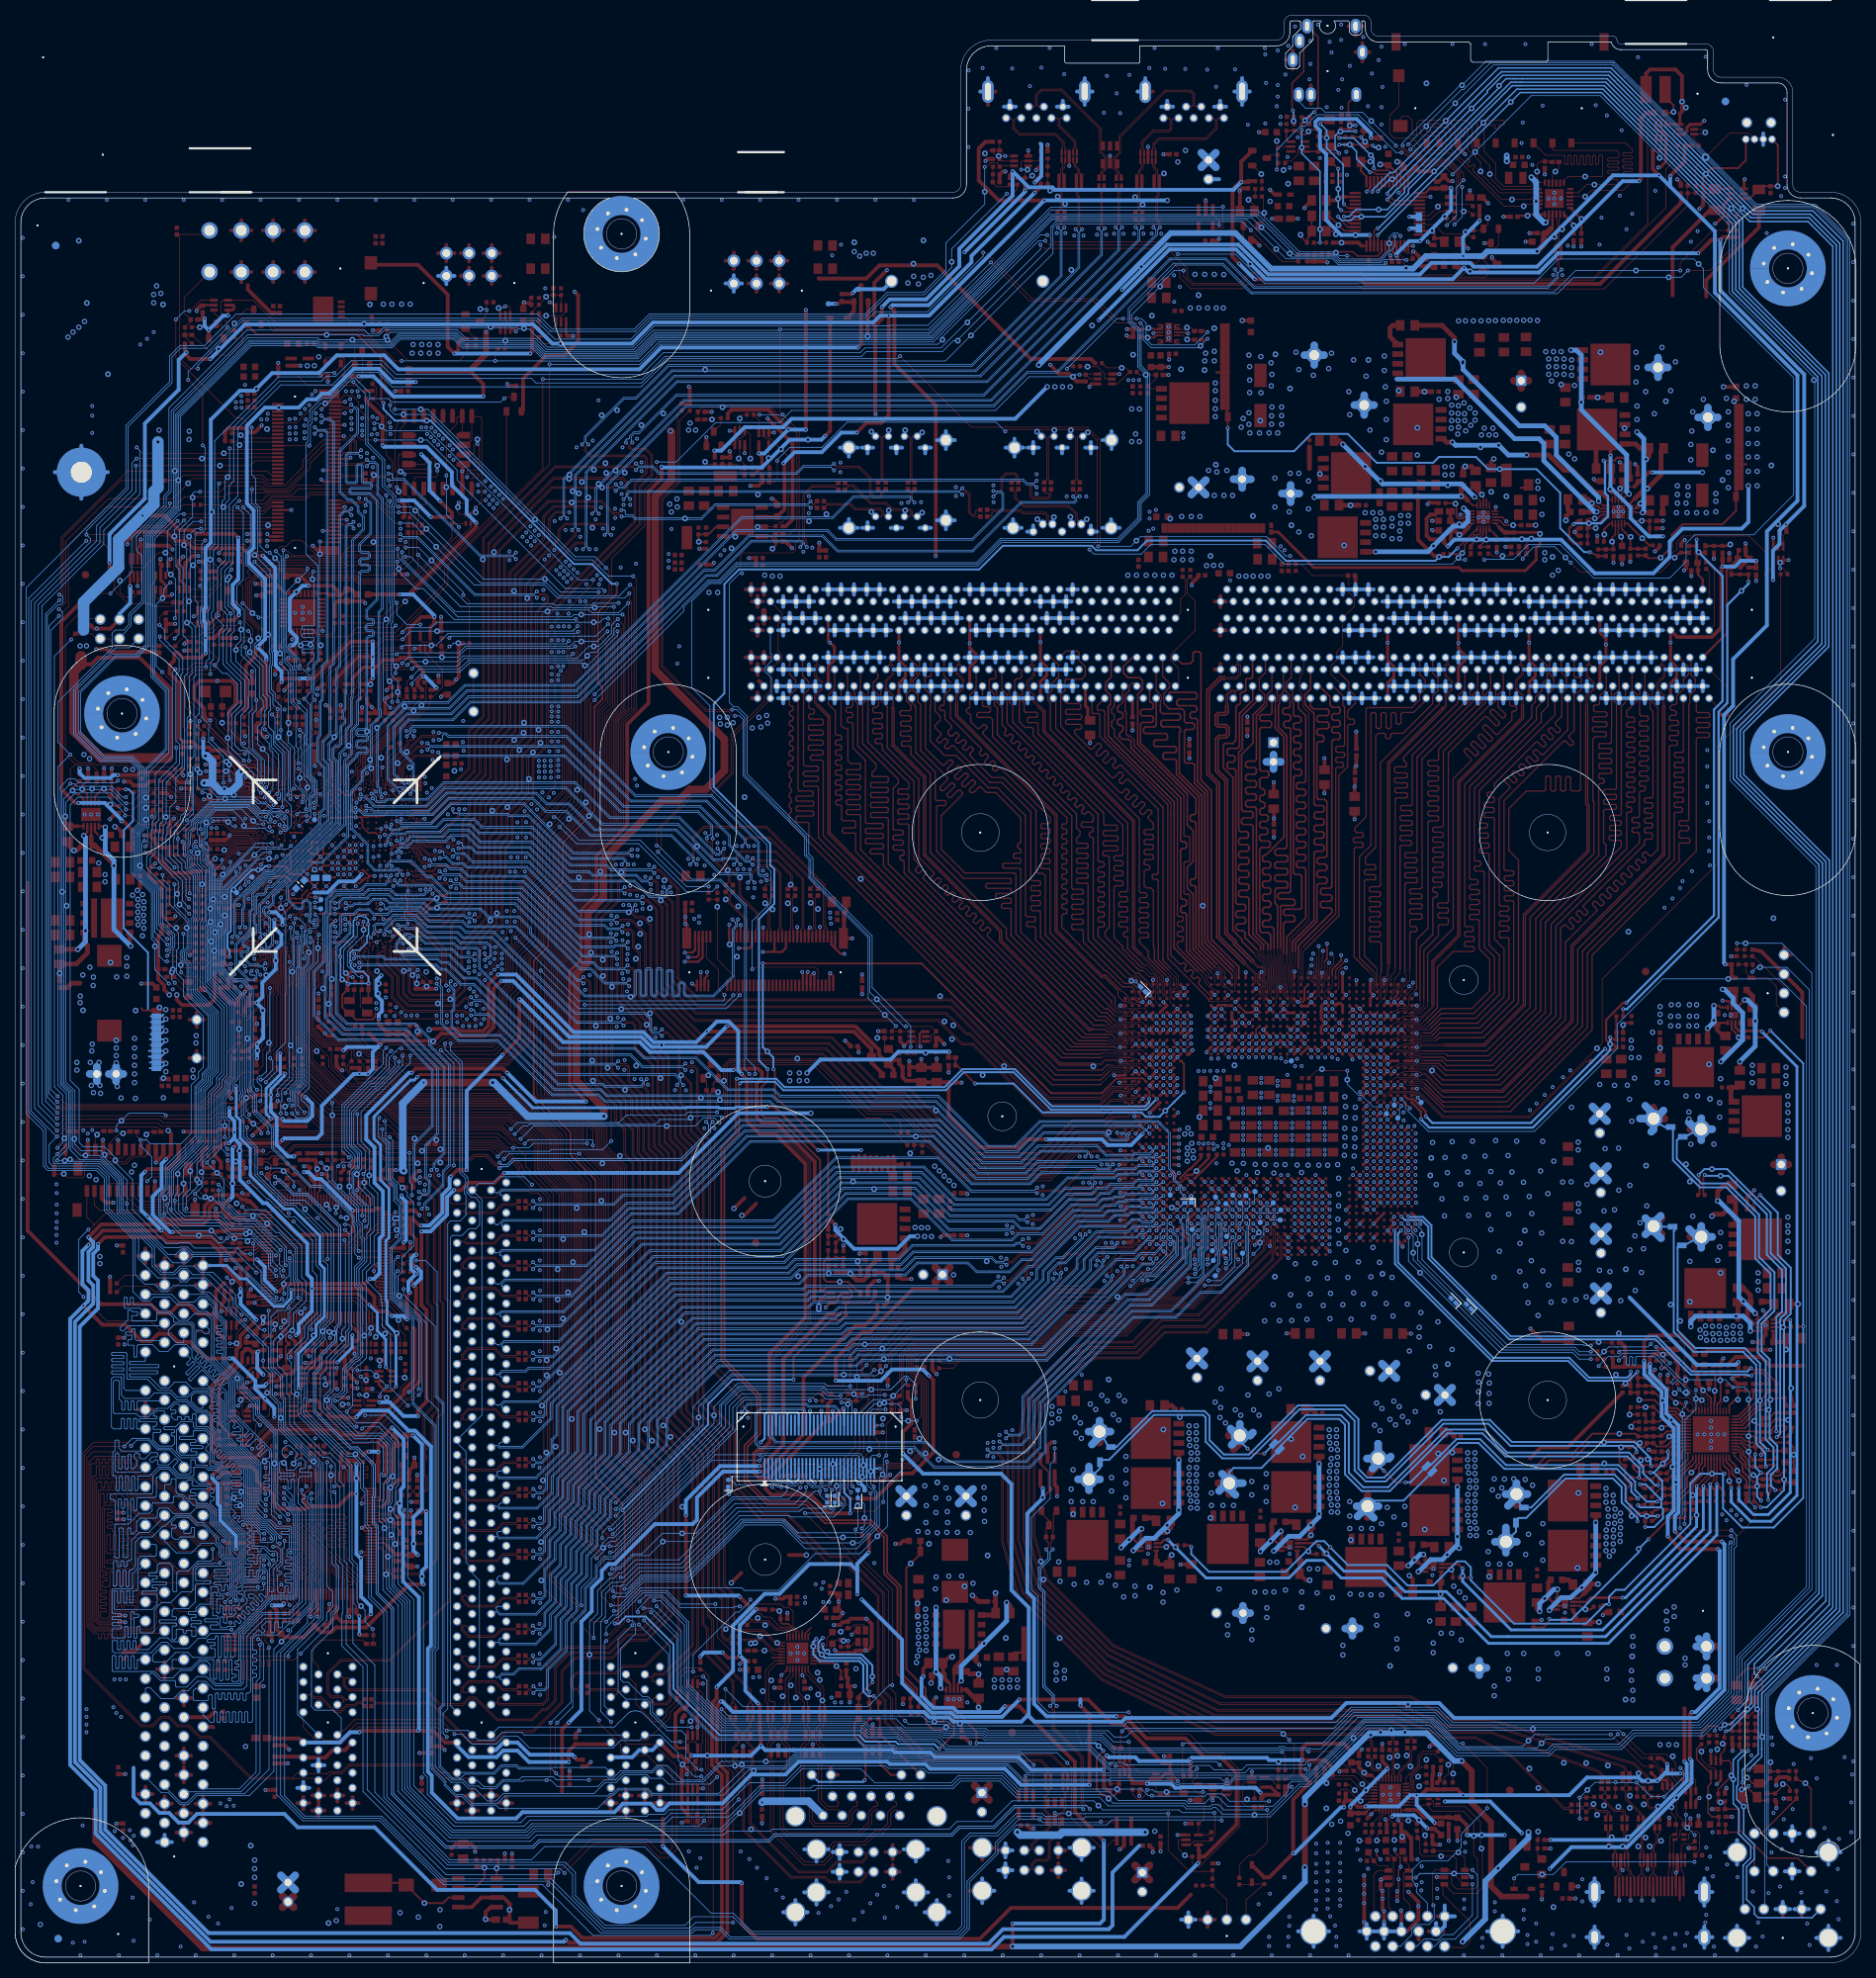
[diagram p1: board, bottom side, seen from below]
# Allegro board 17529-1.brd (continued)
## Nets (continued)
M_B_BS0: CPU1.AL18 DIMM2.81
M_B_BS1: CPU1.AM18 DIMM2.224
M_B_CKE0: CPU1.AY29 DIMM2.60
M_B_CKE1: CPU1.AV29 DIMM2.203
M_B_CLK0: CPU1.AM20 DIMM2.74
M_B_CLK1: CPU1.AP22 DIMM2.218
M_B_CLK#0: CPU1.AM21 DIMM2.75
M_B_CLK#1: CPU1.AP21 DIMM2.219
M_B_CS#0: CPU1.AP17 DIMM2.84
M_B_CS#1: CPU1.AN15 DIMM2.89
M_B_DQ0: CPU1.AE34 DIMM2.5
M_B_DQ1: CPU1.AE35 DIMM2.150
M_B_DQ2: CPU1.AH34 DIMM2.12
M_B_DQ3: CPU1.AH35 DIMM2.157
M_B_DQ4: CPU1.AD34 DIMM2.3
M_B_DQ5: CPU1.AD35 DIMM2.148
M_B_DQ6: CPU1.AG34 DIMM2.10
M_B_DQ7: CPU1.AG35 DIMM2.155
M_B_DQ8: CPU1.AL34 DIMM2.16
M_B_DQ9: CPU1.AL35 DIMM2.161
M_B_DQ10: CPU1.AK31 DIMM2.23
M_B_DQ11: CPU1.AL31 DIMM2.168
M_B_DQ12: CPU1.AK34 DIMM2.14
M_B_DQ13: CPU1.AK35 DIMM2.159
M_B_DQ14: CPU1.AK32 DIMM2.21
M_B_DQ15: CPU1.AL32 DIMM2.166
M_B_DQ16: CPU1.AP35 DIMM2.27
M_B_DQ17: CPU1.AN34 DIMM2.172
M_B_DQ18: CPU1.AN31 DIMM2.34
M_B_DQ19: CPU1.AP31 DIMM2.179
M_B_DQ20: CPU1.AN35 DIMM2.25
M_B_DQ21: CPU1.AP34 DIMM2.170
M_B_DQ22: CPU1.AN32 DIMM2.32
M_B_DQ23: CPU1.AP32 DIMM2.177
M_B_DQ24: CPU1.AM29 DIMM2.38
M_B_DQ25: CPU1.AM28 DIMM2.183
M_B_DQ26: CPU1.AR29 DIMM2.45
M_B_DQ27: CPU1.AR28 DIMM2.190
M_B_DQ28: CPU1.AL29 DIMM2.36
M_B_DQ29: CPU1.AL28 DIMM2.181
M_B_DQ30: CPU1.AP29 DIMM2.43
M_B_DQ31: CPU1.AP28 DIMM2.188
M_B_DQ32: CPU1.AR12 DIMM2.97
M_B_DQ33: CPU1.AP12 DIMM2.242
M_B_DQ34: CPU1.AL13 DIMM2.104
M_B_DQ35: CPU1.AL12 DIMM2.249
M_B_DQ36: CPU1.AR13 DIMM2.95
M_B_DQ37: CPU1.AP13 DIMM2.240
M_B_DQ38: CPU1.AM13 DIMM2.102
M_B_DQ39: CPU1.AM12 DIMM2.247
M_B_DQ40: CPU1.AP9 DIMM2.108
M_B_DQ41: CPU1.AR9 DIMM2.253
M_B_DQ42: CPU1.AP7 DIMM2.115
M_B_DQ43: CPU1.AP6 DIMM2.260
M_B_DQ44: CPU1.AP10 DIMM2.106
M_B_DQ45: CPU1.AR10 DIMM2.251
M_B_DQ46: CPU1.AR7 DIMM2.113
M_B_DQ47: CPU1.AR6 DIMM2.258
M_B_DQ48: CPU1.AM9 DIMM2.119
M_B_DQ49: CPU1.AL9 DIMM2.264
M_B_DQ50: CPU1.AL6 DIMM2.126
M_B_DQ51: CPU1.AL7 DIMM2.271
M_B_DQ52: CPU1.AM10 DIMM2.117
M_B_DQ53: CPU1.AL10 DIMM2.262
M_B_DQ54: CPU1.AM6 DIMM2.124
M_B_DQ55: CPU1.AM7 DIMM2.269
M_B_DQ56: CPU1.AJ7 DIMM2.130
M_B_DQ57: CPU1.AH6 DIMM2.275
M_B_DQ58: CPU1.AF7 DIMM2.137
M_B_DQ59: CPU1.AE7 DIMM2.282
M_B_DQ60: CPU1.AH7 DIMM2.128
M_B_DQ61: CPU1.AJ6 DIMM2.273
M_B_DQ62: CPU1.AF6 DIMM2.135
M_B_DQ63: CPU1.AE6 DIMM2.280
M_B_DQS_DN0: CPU1.AF34 DIMM2.152
M_B_DQS_DN1: CPU1.AK33 DIMM2.163
M_B_DQS_DN2: CPU1.AN33 DIMM2.174
M_B_DQS_DN3: CPU1.AN29 DIMM2.185
M_B_DQS_DN4: CPU1.AN13 DIMM2.244
M_B_DQS_DN5: CPU1.AR8 DIMM2.255
M_B_DQS_DN6: CPU1.AM8 DIMM2.266
M_B_DQS_DN7: CPU1.AG6 DIMM2.277
M_B_DQS_DP0: CPU1.AF35 DIMM2.153
M_B_DQS_DP1: CPU1.AL33 DIMM2.164
M_B_DQS_DP2: CPU1.AP33 DIMM2.175
M_B_DQS_DP3: CPU1.AN28 DIMM2.186
M_B_DQS_DP4: CPU1.AN12 DIMM2.245
M_B_DQS_DP5: CPU1.AP8 DIMM2.256
M_B_DQS_DP6: CPU1.AL8 DIMM2.267
M_B_DQS_DP7: CPU1.AG7 DIMM2.278
M_B_ODT0: CPU1.AM16 DIMM2.87
M_B_ODT1: CPU1.AL16 DIMM2.91
M_B_PARITY: CPU1.AL20 DIMM2.222
M_VREF_DQ_DIM0: CPU1.AC40 TP601.1
M_VREF_DQ_DIM1: C603.1 C1209.1 CPU1.AC39 R1204.1
MB_REG_PG: Q2402.6 Q2405.6 Q2406.3 Q2406.6 R2469.1 U2401.109
MB_REG_PG_1: Q2402.2 R2404.2 R2409.1
MB_REG_PG_2: Q2406.5 R2415.2 R2424.1
MB_REG_PG_3: Q2406.2 R2414.2 R2423.1
MCLK: RN2401.2(A) U2401.115
MDAT: RN2401.1(A) U2401.116
ME_CNTL: R2037.1 SB1.BF32
ME_CNTL_1: Q2001.B R2037.2
ME_CNTL_2: Q2001.E R2034.2
MEM_REG_PG: Q2405.3 R2470.1 U2401.111
MEM_REG_PG_1: Q2405.5 R2413.2 R2417.1
MEM_REG_PG_2: Q2405.2 R2412.2
MIC1_JD: AUD1.3 R2709.2
MIC1_JD/FRONT_JD: R2706.2 R2709.1 R2710.1 U2701.44
MIC1_LL: L3005.1 R3011.2 R3013.2 R3016.1
MIC1_LL_C: C3007.2 R3013.1
MIC1_RR: L3006.1 R3012.2 R3014.2 R3015.1
MIC1_RR_C: C3008.2 R3014.1
MIC1_VREFO_LL: R3011.1 U2701.9
MIC1_VREFO_RR: R3012.1 U2701.10
MIC2_VREFO: D2901.1 U2701.11
MUTE: Q2701.C R2908.1 R2910.1 R3008.1 R3010.1
MUTE_AUDOUT_LL: Q3001.5 R3010.2
MUTE_AUDOUT_RR: Q3001.2 R3008.2
MUTE_FP_OUT_LL: Q2901.2 R2908.2
MUTE_FP_OUTR_RR: Q2901.5 R2910.2
NGFF_WIFI_PWR_CRL: D6302.K R1712.2 SB1.U48
NGFF_WIFI_PWR_EN: R6306.2 U6301.1 U6302.D
NPC3063_#8: R5302.2 U5301.8
NPC3063_COMP: R5303.1 R5304.1 U5301.5
NPC3063_SWC: R5301.1 R5302.1 U5301.1 U5301.7
NPC3063_SWE: D5301.K L5301.1 U5301.2
NPC3063_TCAP: C5301.1 U5301.3
PAD0: SLOT4.111 U9501.30
PAD1: SLOT4.112 U9501.31
PAD2: SLOT4.109 U9501.33
PAD3: SLOT4.108 U9501.34
PAD4: SLOT4.105 U9501.37
PAD5: SLOT4.106 U9501.38
PAD6: SLOT4.103 U9501.39
PAD7: SLOT4.102 U9501.40
PAD8: SLOT4.100 U9501.43
PAD9: SLOT4.97 U9501.44
PAD10: SLOT4.96 U9501.45
PAD11: SLOT4.93 U9501.50
PAD12: SLOT4.94 U9501.51
PAD13: SLOT4.91 U9501.52
PAD14: SLOT4.90 U9501.53
PAD15: SLOT4.87 U9501.54
PAD16: R9203.1 SLOT4.63 U9501.74
PAD17: SLOT4.64 U9501.75
PAD18: SLOT4.61 U9501.76
PAD19: SLOT4.60 U9501.77
PAD20: SLOT4.57 U9501.80
PAD21: SLOT4.58 U9501.81
PAD22: SLOT4.55 U9501.82
PAD23: SLOT4.54 U9501.83
PAD24: SLOT4.49 U9501.85
PAD25: SLOT4.48 U9501.86
PAD26: SLOT4.45 U9501.88
PAD27: SLOT4.46 U9501.89
PAD28: SLOT4.43 U9501.98
PAD29: SLOT4.42 U9501.99
PAD30: SLOT4.39 U9501.100
PAD31: SLOT4.40 U9501.101
PC_SPKR_DET_PD: R2449.2 U2401.54
PCBE0#: SLOT4.99 U9501.46
PCBE1#: SLOT4.88 U9501.49
PCBE2#: SLOT4.66 U9501.69
PCBE3#: SLOT4.52 U9501.87
PCH_CPU_BCLK_DN: CPU1.W4 SB1.C8
PCH_CPU_BCLK_DP: CPU1.W5 SB1.B8
PCH_CPU_NSSC_CLK_DN: CPU1.J9 SB1.C6
PCH_CPU_NSSC_CLK_DP: CPU1.K9 SB1.D7
PCH_CPU_PCIBCLK_DN: CPU1.W2 SB1.B6
PCH_CPU_PCIBCLK_DP: CPU1.W1 SB1.A6
PCH_DPWROK: R2612.2 R2619.1 SB1.AW41 U2602.4
PCH_HEATSINK_DET: HS1901.1 HS1901.2 R1904.1 SB1.AN37
PCH_INTRUDER_N: R1507.1 SB1.BB44
PCH_JTAG_TCK: C2001.1 R2011.1 SB1.AJ3 XDP1.55
PCH_JTAG_TDI: R411.2 R2026.1 SB1.AH2
PCH_JTAG_TDO: R410.2 R2024.1 SB1.AH3
PCH_JTAG_TMS: R412.2 R2028.1 SB1.AJ4
PCH_JTAGX: R2008.1 R2021.1 SB1.AH4
PCH_PECI: R1708.1 SB1.AF2
PCH_PME_N: R1508.2 R9202.2 SB1.BE36
PCH_PS_ON_N: R2023.1 SB1.AP41 U4301.6
PCH_PS_ON_N_EXTD1: C2004.1 R2023.2 U2002.1
PCH_PWROK: DB2001.1 R4016.2 SB1.AY42
PCH_PWROK_EC: C2413.1 R2433.1 R2439.1 R2442.1
PCH_RTCRST_DOWN: JMP1.6 R2035.1
PCH_RTCRST_N: R2036.2 R9919.1
PCH_RTCRST_PULLUP: C2006.1 JMP1.5 R2036.1 R2040.1 SB1.BE47
PCH_RTCX1: C1803.1 R1814.1 SB1.BA49 X1802.1
PCH_RTCX2: C1804.1 R1814.2 SB1.BA48 X1802.2
PCH_SATA_LED_N: R1704.1 SB1.AK48 U6401.2
PCH_SATA_LED_NMOS: R6416.1 U6401.5 U6401.6
PCH_SIO_DPWROK: R2475.1 R2612.1 U2401.28 U2602.1
PCH_SLP_A_N: R2051.1 R2420.1 R9916.1 SB1.BE40
PCH_SRTCRSTB_PULLUP: C2007.1 R2042.2 R2043.1 SB1.BD46
PCH_SYSPWROK: R2003.1 R2439.2 R9905.1 SB1.AU3 U2404.6
PCH_SYSPWROK_EXTD1: U2402.4 U2403.2 U2404.2
PCH_SYSPWROK_EXTD2: U2403.4 U2404.5
PCH_SYSPWROK_EXTD3: U2404.1 U2404.3
PCH_WAKE_N: NGFF1.55 R2014.1 R6202.2 R9512.1 SB1.BB47 SLOT1.B11 SLOT2.B11 SLOT3.B11 U3101.21 U9501.1
PCH_XDP_PRDY_R_N: R9902.1 SB1.AM5
PCH_XDP_PREQ_R_N: R9901.1 SB1.AL2
PCI_CLK1: R9508.2 SLOT4.32
PCI_R_CLKN: R9502.1 U9501.9
PCI_R_CLKP: R9503.1 U9501.10
PCIAUX_GATE: R2432.1 U2401.92
PCICLK0: R9508.1 U9501.104
PCICLK_SEL: R9509.1 U9501.126
PCIE_RCOMP_N: R1513.1 SB1.B12
PCIE_RCOMP_P: R1513.2 SB1.A13
PCIE_RX_CON_N5: C3109.1 U3101.18
PCIE_RX_CON_N6: C9503.1 U9501.20
PCIE_RX_CON_P5: C3110.1 U3101.17
PCIE_RX_CON_P6: C9504.1 U9501.21
PCIE_RX_PCH_N5: C3109.2 SB1.F20
PCIE_RX_PCH_N6: C9503.2 SB1.K21
PCIE_RX_PCH_N7: SB1.L24 SLOT1.A17
PCIE_RX_PCH_N8: NGFF1.43 SB1.F24
PCIE_RX_PCH_N9: SB1.G36 SLOT3.A17
PCIE_RX_PCH_N21: NGFF2.41 SB1.T43
PCIE_RX_PCH_N22: NGFF2.29 SB1.U40
PCIE_RX_PCH_N23: NGFF2.17 SB1.W43
PCIE_RX_PCH_N24: NGFF2.5 SB1.Y40
PCIE_RX_PCH_P5: C3110.2 SB1.G20
PCIE_RX_PCH_P6: C9504.2 SB1.J21
PCIE_RX_PCH_P7: SB1.J24 SLOT1.A16
PCIE_RX_PCH_P8: NGFF1.41 SB1.G24
PCIE_RX_PCH_P9: SB1.F36 SLOT3.A16
PCIE_RX_PCH_P21: NGFF2.43 SB1.R44
PCIE_RX_PCH_P22: NGFF2.31 SB1.U41
PCIE_RX_PCH_P23: NGFF2.19 SB1.W44
PCIE_RX_PCH_P24: NGFF2.7 SB1.Y41
PCIE_SLOT1_PRSNT_N: R1506.2 R9401.1 SB1.BB26
PCIE_SLOT1_PRSNT_N_R: R9401.2 SLOT1.B17
PCIE_SLOT2_PRSNT_N: R1806.2 R9301.1 SB1.BA30
PCIE_SLOT2_PRSNT_N_R: R9301.2 SLOT2.B17 SLOT2.B31 SLOT2.B48 SLOT2.B81
PCIE_SLOT4_PRSNT_N: R1505.2 R9402.1 SB1.BF29
PCIE_SLOT4_PRSNT_N_R: R9402.2 SLOT3.B17
PCIE_TX_CON_N5: C3115.1 U3101.14
PCIE_TX_CON_N6: C9501.1 U9501.18
PCIE_TX_CON_N7: C9402.2 SLOT1.B15
PCIE_TX_CON_N8: C6305.1 NGFF1.37
PCIE_TX_CON_N9: C9407.2 SLOT3.B15
PCIE_TX_CON_N21: C6211.2 NGFF2.47
PCIE_TX_CON_N22: C6209.2 NGFF2.35
PCIE_TX_CON_N23: C6207.2 NGFF2.23
PCIE_TX_CON_N24: C6202.2 NGFF2.11
PCIE_TX_CON_P5: C3116.1 U3101.13
PCIE_TX_CON_P6: C9502.1 U9501.17
PCIE_TX_CON_P7: C9401.2 SLOT1.B14
PCIE_TX_CON_P8: C6306.1 NGFF1.35
PCIE_TX_CON_P9: C9406.2 SLOT3.B14
PCIE_TX_CON_P21: C6212.2 NGFF2.49
PCIE_TX_CON_P22: C6210.2 NGFF2.37
PCIE_TX_CON_P23: C6208.2 NGFF2.25
PCIE_TX_CON_P24: C6204.2 NGFF2.13
PCIE_TX_PCH_N5: C3115.2 SB1.B21
PCIE_TX_PCH_N6: C9501.2 SB1.D21
PCIE_TX_PCH_N7: C9402.1 SB1.C23
PCIE_TX_PCH_N8: C6305.2 SB1.B24
PCIE_TX_PCH_N9: C9407.1 SB1.C34
PCIE_TX_PCH_N21: C6211.1 SB1.G47
PCIE_TX_PCH_N22: C6209.1 SB1.H47
PCIE_TX_PCH_N23: C6207.1 SB1.G49
PCIE_TX_PCH_N24: C6202.1 SB1.G46
PCIE_TX_PCH_P5: C3116.2 SB1.A22
PCIE_TX_PCH_P6: C9502.2 SB1.C21
PCIE_TX_PCH_P7: C9401.1 SB1.B23
PCIE_TX_PCH_P8: C6306.2 SB1.C24
PCIE_TX_PCH_P9: C9406.1 SB1.D34
PCIE_TX_PCH_P21: C6212.1 SB1.F46
PCIE_TX_PCH_P22: C6210.1 SB1.H48
PCIE_TX_PCH_P23: C6208.1 SB1.G48
PCIE_TX_PCH_P24: C6204.1 SB1.G45
PCIRST1#: R2401.1 R2406.1 U2401.51
PCIRST2#: R2407.1 R2410.1 U2401.52
PCIRST#: RN9505.2(A) SLOT4.29 U9501.115
PCM_CLK: NGFF1.8 R2033.1
PCM_CLK_PCH: R2033.2 SB1.AV18
PCM_IN: NGFF1.12 R2032.1
PCM_IN_PCH: R2032.2 SB1.AW18
PCM_OUT: NGFF1.14 R2031.1 R6301.2 R6319.2
PCM_OUT_C: Q6301.3 R6319.1
PCM_OUT_PCH: R2031.2 SB1.BA17
PCM_SYNC: NGFF1.10 R2029.1 R6302.2 R6320.2
PCM_SYNC_C: Q6301.6 R6320.1
PCM_SYNC_PCH: R2029.2 SB1.BE16
PDVSEL#: RN9506.1(A) SLOT4.74 U9501.66
PECI_CPU: CPU1.G7 R2428.1
PECI_EC: R2428.2 U2401.30
PECI_READY: R2430.2 U2401.31
PEG_CLK1_PCH: NGFF1.47 SB1.AH10
PEG_CLK1_PCH#: NGFF1.49 SB1.AH9
PEG_CLK2_PCH: SB1.AE15 U3101.15
PEG_CLK2_PCH#: SB1.AE14 U3101.16
PEG_CLK3_PCH: NGFF2.55 SB1.AE7
PEG_CLK3_PCH#: NGFF2.53 SB1.AE6
PEG_CLK8_PCH: SB1.AC15 SLOT2.A13
PEG_CLK8_PCH#: SB1.AC14 SLOT2.A14
PEG_CLK9_PCH: SB1.U3 SLOT1.A13
PEG_CLK9_PCH#: SB1.U2 SLOT1.A14
PEG_CLK10_PCH: R9503.2 R9505.1 SB1.AC11
PEG_CLK10_PCH#: R9502.2 R9504.1 SB1.AC9
PEG_CLK11_PCH: SB1.AE11 SLOT3.A13
PEG_CLK11_PCH#: SB1.AE9 SLOT3.A14
PEG_CLKREQ1_PCH#: NGFF1.53 R1801.1 SB1.BE31
PEG_CLKREQ2_PCH#: R1803.1 R3102.2 SB1.AR32
PEG_CLKREQ3_PCH#: NGFF2.52 R1805.1 SB1.BB30
PEG_CLKREQ8_PCH#: R1807.1 SB1.AE41 SLOT2.B12
PEG_CLKREQ9_PCH#: R1809.1 SB1.AF48 SLOT1.B12
PEG_CLKREQ10_PCH#: R1808.2 R1810.1 SB1.AC41
PEG_CLKREQ11_PCH#: R1811.1 SB1.AC39 SLOT3.B12
PEG_RCOMP_CPU: CPU1.L7 R301.2
PEG_RX_CPU_N0: CPU1.B7 SLOT2.A17
PEG_RX_CPU_N1: CPU1.C6 SLOT2.A22
PEG_RX_CPU_N2: CPU1.D5 SLOT2.A26
PEG_RX_CPU_N3: CPU1.E4 SLOT2.A30
PEG_RX_CPU_N4: CPU1.F5 SLOT2.A36
PEG_RX_CPU_N5: CPU1.G4 SLOT2.A40
PEG_RX_CPU_N6: CPU1.H5 SLOT2.A44
PEG_RX_CPU_N7: CPU1.J4 SLOT2.A48
PEG_RX_CPU_N8: CPU1.K5 SLOT2.A53
PEG_RX_CPU_N9: CPU1.L4 SLOT2.A57
PEG_RX_CPU_N10: CPU1.M5 SLOT2.A61
PEG_RX_CPU_N11: CPU1.N4 SLOT2.A65
PEG_RX_CPU_N12: CPU1.P5 SLOT2.A69
PEG_RX_CPU_N13: CPU1.R4 SLOT2.A73
PEG_RX_CPU_N14: CPU1.T5 SLOT2.A77
PEG_RX_CPU_N15: CPU1.U4 SLOT2.A81
PEG_RX_CPU_P0: CPU1.B8 SLOT2.A16
PEG_RX_CPU_P1: CPU1.C7 SLOT2.A21
PEG_RX_CPU_P2: CPU1.D6 SLOT2.A25
PEG_RX_CPU_P3: CPU1.E5 SLOT2.A29
PEG_RX_CPU_P4: CPU1.F6 SLOT2.A35
PEG_RX_CPU_P5: CPU1.G5 SLOT2.A39
PEG_RX_CPU_P6: CPU1.H6 SLOT2.A43
PEG_RX_CPU_P7: CPU1.J5 SLOT2.A47
PEG_RX_CPU_P8: CPU1.K6 SLOT2.A52
PEG_RX_CPU_P9: CPU1.L5 SLOT2.A56
PEG_RX_CPU_P10: CPU1.M6 SLOT2.A60
PEG_RX_CPU_P11: CPU1.N5 SLOT2.A64
PEG_RX_CPU_P12: CPU1.P6 SLOT2.A68
PEG_RX_CPU_P13: CPU1.R5 SLOT2.A72
PEG_RX_CPU_P14: CPU1.T6 SLOT2.A76
PEG_RX_CPU_P15: CPU1.U5 SLOT2.A80
PEG_TX_CON_N0: C9304.2 SLOT2.B15
PEG_TX_CON_N1: C9302.2 SLOT2.B20
PEG_TX_CON_N2: C9303.2 SLOT2.B24
PEG_TX_CON_N3: C9308.2 SLOT2.B28
PEG_TX_CON_N4: C9313.2 SLOT2.B34
PEG_TX_CON_N5: C9315.2 SLOT2.B38
PEG_TX_CON_N6: C9317.2 SLOT2.B42
PEG_TX_CON_N7: C9319.2 SLOT2.B46
PEG_TX_CON_N8: C9321.2 SLOT2.B51
PEG_TX_CON_N9: C9323.2 SLOT2.B55
PEG_TX_CON_N10: C9325.2 SLOT2.B59
PEG_TX_CON_N11: C9328.2 SLOT2.B63
PEG_TX_CON_N12: C9331.2 SLOT2.B67
PEG_TX_CON_N13: C9334.2 SLOT2.B71
PEG_TX_CON_N14: C9336.2 SLOT2.B75
PEG_TX_CON_N15: C9338.2 SLOT2.B79
PEG_TX_CON_P0: C9301.2 SLOT2.B14
PEG_TX_CON_P1: C9305.2 SLOT2.B19
PEG_TX_CON_P2: C9306.2 SLOT2.B23
PEG_TX_CON_P3: C9307.2 SLOT2.B27
PEG_TX_CON_P4: C9309.2 SLOT2.B33
PEG_TX_CON_P5: C9314.2 SLOT2.B37
PEG_TX_CON_P6: C9316.2 SLOT2.B41
PEG_TX_CON_P7: C9318.2 SLOT2.B45
PEG_TX_CON_P8: C9320.2 SLOT2.B50
PEG_TX_CON_P9: C9322.2 SLOT2.B54
PEG_TX_CON_P10: C9324.2 SLOT2.B58
PEG_TX_CON_P11: C9326.2 SLOT2.B62
PEG_TX_CON_P12: C9329.2 SLOT2.B66
PEG_TX_CON_P13: C9332.2 SLOT2.B70
PEG_TX_CON_P14: C9335.2 SLOT2.B74
PEG_TX_CON_P15: C9337.2 SLOT2.B78
PEG_TX_CPU_N0: C9304.1 CPU1.A6
PEG_TX_CPU_N1: C9302.1 CPU1.B5
PEG_TX_CPU_N2: C9303.1 CPU1.C4
PEG_TX_CPU_N3: C9308.1 CPU1.D3
PEG_TX_CPU_N4: C9313.1 CPU1.E2
PEG_TX_CPU_N5: C9315.1 CPU1.F3
PEG_TX_CPU_N6: C9317.1 CPU1.G2
PEG_TX_CPU_N7: C9319.1 CPU1.H3
PEG_TX_CPU_N8: C9321.1 CPU1.J2
PEG_TX_CPU_N9: C9323.1 CPU1.K3
PEG_TX_CPU_N10: C9325.1 CPU1.L2
PEG_TX_CPU_N11: C9328.1 CPU1.M3
PEG_TX_CPU_N12: C9331.1 CPU1.N2
PEG_TX_CPU_N13: C9334.1 CPU1.P3
PEG_TX_CPU_N14: C9336.1 CPU1.R1
PEG_TX_CPU_N15: C9338.1 CPU1.T3
PEG_TX_CPU_P0: C9301.1 CPU1.A5
PEG_TX_CPU_P1: C9305.1 CPU1.B4
PEG_TX_CPU_P2: C9306.1 CPU1.C3
PEG_TX_CPU_P3: C9307.1 CPU1.D2
PEG_TX_CPU_P4: C9309.1 CPU1.E1
PEG_TX_CPU_P5: C9314.1 CPU1.F2
PEG_TX_CPU_P6: C9316.1 CPU1.G1
PEG_TX_CPU_P7: C9318.1 CPU1.H2
PEG_TX_CPU_P8: C9320.1 CPU1.J1
PEG_TX_CPU_P9: C9322.1 CPU1.K2
PEG_TX_CPU_P10: C9324.1 CPU1.L1
PEG_TX_CPU_P11: C9326.1 CPU1.M2
PEG_TX_CPU_P12: C9329.1 CPU1.N1
PEG_TX_CPU_P13: C9332.1 CPU1.P2
PEG_TX_CPU_P14: C9335.1 CPU1.R2
PEG_TX_CPU_P15: C9337.1 CPU1.T2
PF_MIC2_LL: FL2901.1 R2901.2 R2902.2
PFRAME#: RN9504.1(A) SLOT4.67 U9501.71
PGNT0#: RN9505.4(A) SLOT4.33 U9501.108
PGNT1#: RN9501.1(A) U9501.103
PINTA_N: RN9506.2(A) SLOT4.11 U9501.65
PINTB_N: RN9506.4(A) SLOT4.14 U9501.63
PINTC_N: RN9506.3(A) SLOT4.13 U9501.64
PINTD_N: RN9505.1(A) SLOT4.16 U9501.116
PIRDY#: RN9504.2(A) SLOT4.70 U9501.70
PIRQA_N: R1902.1 R1917.1 R9112.2 SB1.T45
PLOCK#: RN9503.1(A) SLOT4.78 U9501.62
PLTRST#_PCH: R1504.1 R1516.1 SB1.AV29
PLTRST#_SIO: R1504.2 U2401.14
PLTRST_BUF_LAN_N: R2407.2 R4008.1 U4001.1
PLTRST_BUF_PCI_N: R2401.2 R4009.1 R4010.1 U4004.1
PLTRST_CPU_N: C403.1 CPU1.E7 R9910.1 SB1.AG5
PLTRST_LAN_N: LPC1.4 NGFF1.52 NGFF2.50 Q9101.D R4002.1 R4008.2 R9111.1 U3101.19 U4001.4
PLTRST_PCI_N: R4010.2 SLOT1.A11 SLOT3.A11 U4007.4 U9501.117
PLTRST_PCON_N: R4004.1 U4004.4 U4006.1
PLTRST_PEG_N: R4009.2 SLOT2.A11 U4006.4 U4007.1
PM_DOWN_CPU: CPU1.D8 R421.2
PM_DOWN_PCH: R421.1 SB1.AE2
PM_SYNC_CPU: CPU1.E8 R1711.2
PM_SYNC_PCH: R1711.1 SB1.AF3
PME_N: R9201.2 R9501.1 U9501.2
PME_N_1: R9201.1 R9202.1 SLOT4.37
POL1_SDA: R5901.2 R5908.1 U5901.10
POL2_SCL: R5902.2 R5909.1 U5901.9
PPAR: RN9503.2(A) SLOT4.85 U9501.61
PPERR#: RN9503.4(A) SLOT4.80 U9501.55
PREQ0#: RN9502.1(A) SLOT4.36 U9501.107
PREQ1#: RN9501.2(A) U9501.102
PROC_TRIGIN_CPU: CPU1.D1 R2201.2
PROC_TRIGIN_PCH: R2201.1 SB1.AK3
PROC_TRIGOUT_CPU: CPU1.B3 R901.2
PROC_TRIGOUT_PCH: R901.1 SB1.AK2
PROCHOT#_CPU: CPU1.C39 R409.2
PROCHOT#_CPU_R: PR4461.1 R404.2 R409.1 R2458.2
PROCHOT#_EC: R2458.1 R2460.1 U2401.36
PROCHOT#_IMVP: PR4461.2 PU4401.10
PS_ON_N: ATX3.8 C4306.1 R4302.2 R4303.2 R4305.2
PSERR#: RN9503.3(A) SLOT4.84 U9501.56
PSPWRGD: ATX3.4 C4307.1 R4201.1 R4207.2
PSTOP#: RN9504.4(A) SLOT4.75 U9501.67
PTRDY#: RN9504.3(A) SLOT4.71 U9501.68
PULSAR_38D4M_REFCLK: NGFF1.64 R1815.2 R6304.2
PW_CLEAR: JMP1.3 R2041.2 SB1.V48
PWR2_PRSN_1: Q2401.2 R2402.2 R2408.1
PWR2_PRSN_2: Q2401.5 Q2401.6 R2403.2 U2405.2
PWR2_PRSNT: Q2401.3 R2465.1 U2401.108
PWR_1D0V: PC5107.1 PC5108.1 PL5101.2 PR5114.1 PR5117.1 PR5118.1 PR5119.1 PR5120.1 PR5121.1 PR5122.1 PR5123.1 PR5124.1 PR5125.1 PR5126.1 PR5127.1 PR5128.1 PR5129.1 PR5130.1 PR5131.1 PR5132.1 PR5133.1 PR5134.1 PR5135.1 PT5101.1
PWR_1D0V_BOOT: PR5110.2 PU5101.10
PWR_1D0V_BOOT_R: PC5106.2 PR5110.1
PWR_1D0V_CS: PR5111.1 PU5101.2
PWR_1D0V_FB: PC5108.2 PR5114.2 PR5116.1 PU5101.4
PWR_1D0V_LGATE: PU5101.6 PU5102.8
PWR_1D0V_PG: PR5107.2 PU5101.1
PWR_1D0V_PHASE: PC5106.1 PL5101.1 PR5109.2 PR5113.1 PU5101.8 PU5102.9
PWR_1D0V_RF: PR5112.1 PU5101.5
PWR_1D0V_SNB: PC5110.1 PR5113.2
PWR_1D0V_UGATE: PR5108.2 PU5101.9
PWR_1D0V_UGATE_R: PR5108.1 PR5109.1 PU5102.1
PWR_1D0V_VCC: PC5109.1 PR5115.1 PU5101.7
PWR_2D5V: PC5203.1 PC5204.1 PC5206.2 PR5203.1 PR5205.1 PU5201.3 PU5201.4
PWR_2D5V_EN: PC5205.1 PR5204.2 PU5201.8
PWR_2D5V_FB: PC5206.1 PR5205.2 PR5206.1 PU5201.2
PWR_2D5V_VIN: PC5201.1 PR5201.1 PU5201.5 PU5201.9
PWR_3D3V: PC4909.1 PG4902.2 PL4901.1 PR4901.2 PR4902.2 PR4903.2 PR4904.2 PR4905.2 PR4906.2 PR4908.2 PR4910.2 PR4912.2 PR4914.2 PR4916.2 PR4918.2 PR4920.2 PR4922.2 PR4924.2 PT4902.1
PWR_3D3V_SN: PC4911.1 PR4950.2
PWR_3V_BOOT2: PR4942.2 PU4902.9
PWR_3V_BOOT2_R: PC4907.2 PR4942.1
PWR_3V_CS2: PR4952.1 PU4902.5
PWR_3V_EN2: PC4918.1 PR4959.2 PR4961.1 PU4902.6
PWR_3V_FB2: PC4914.2 PR4954.2 PR4956.1 PU4902.4
PWR_3V_FB2_A: PC4914.1 PG4902.1 PR4954.1
PWR_3V_LGATE2: PU4902.11 PU4904.4
PWR_3V_PHASE2: PC4907.1 PL4901.2 PR4950.1 PU4901.1 PU4901.2 PU4901.3 PU4902.8 PU4904.5 PU4904.6 PU4904.7 PU4904.8
PWR_3V_UGATE2: PR4944.1 PU4902.10
PWR_3V_UGATE2R: PR4944.2 PU4901.4
PWR_5V: PC4910.1 PC4913.1 PG4901.2 PL4902.2 PR4925.1 PR4927.1 PR4929.1 PR4933.1 PR4934.1 PR4936.1 PR4937.1 PR4938.1 PR4939.1 PR4940.1 PR4945.1 PR4946.1 PR4947.1 PR4948.1 PR4949.1 PT4903.1 PU4902.14
PWR_5V3D3V_LDO3: PC4916.1 PU4902.3
PWR_5V3D3V_VIN: PC4901.1 PC4902.1 PC4903.1 PC4904.1 PC4905.1 PL4903.2 PL4904.2 PL4905.2 PR4932.1 PR4960.1 PT4901.1 PU4901.5 PU4901.6 PU4901.7 PU4901.8 PU4903.5 PU4903.6 PU4903.7 PU4903.8
PWR_5V_BOOT1: PR4943.1 PU4902.17
PWR_5V_BOOT1_R: PC4908.1 PR4943.2
PWR_5V_CS1: PR4953.1 PU4902.1
PWR_5V_EN1: PC4919.1 PR4960.2 PR4962.1 PU4902.20
PWR_5V_FB1: PC4915.2 PR4955.2 PR4957.1 PU4902.2
PWR_5V_FB1_A: PC4915.1 PG4901.1 PR4955.1
PWR_5V_LGATE1: PU4902.15 PU4905.4
PWR_5V_PHASE1: PC4908.2 PL4902.1 PR4951.1 PU4902.18 PU4903.1 PU4903.2 PU4903.3 PU4905.5 PU4905.6 PU4905.7 PU4905.8
PWR_5V_SN: PC4912.1 PR4951.2
PWR_5V_UGATE1: PR4941.2 PU4902.16
PWR_5V_UGATE1R: PR4941.1 PU4903.4
PWR_12V_DUAL_1D0V: PC5101.1 PC5102.1 PC5103.1 PC5104.1 PC5105.1 PL5104.1 PL5105.1 PU5102.2 PU5102.3 PU5102.4 PU5102.10
PWR_BTNJ_C: PWRSW1.S2 R6405.1
PWR_DDR4_BT: PR5007.1 PU5001.18
PWR_DDR4_BT1: PC5008.1 PR5007.2
PWR_DDR4_CS: PR5003.1 PU5001.13
PWR_DDR4_FB: PC5013.2 PR5024.2 PR5025.1 PU5001.6
PWR_DDR4_LDOIN: PC5009.1 PR5014.2 PU5001.19
PWR_DDR4_LG: PU5001.15 PU5003.4
PWR_DDR4_LX: PC5008.2 PL5001.1 PR5004.2 PR5016.1 PU5001.16 PU5002.1 PU5002.2 PU5002.3 PU5003.5 PU5003.6 PU5003.7 PU5003.8
PWR_DDR4_UG: PR5005.2 PU5001.17
PWR_DDR4_UG1: PR5004.1 PR5005.1 PU5002.4
PWR_DDR4_VDDQ: PC5013.1 PR5019.1 PR5024.1 PU5001.5
PWR_DDR4_VTTREF: PC5015.1 PU5001.4
PWR_GT_BST1: PR4601.1 PU4602.1
PWR_GT_BST1_R: PC4603.1 PR4601.2
PWR_GT_BST2: PR4608.1 PU4605.1
PWR_GT_BST2_R: PC4608.1 PR4608.2
PWR_GT_COMP: PC4418.2 PC4419.2 PU4401.18
PWR_GT_COMP_A: PC4417.1 PR4439.2
PWR_GT_COMP_R: PC4418.1 PR4440.2
PWR_GT_CSCOMP: PC4424.1 PC4425.1 PR4451.1 PR4455.1 PR4457.2 PU4401.19
PWR_GT_CSN1: PC4420.2 PG4602.2 PR4443.2 PR4459.2 PU4401.24
PWR_GT_CSN2: PC4421.2 PG4604.2 PR4446.2 PR4460.2 PU4401.26
PWR_GT_CSP1: PG4601.2 PR4444.1 PR4449.2
PWR_GT_CSP1_IC: PC4420.1 PR4443.1 PR4444.2 PU4401.23
PWR_GT_CSP2: PG4603.2 PR4448.1 PR4453.2
PWR_GT_CSP2_IC: PC4421.1 PR4446.1 PR4448.2 PU4401.25
PWR_GT_CSREF: PC4427.1 PR4459.1 PR4460.1 PU4401.22
PWR_GT_CSSUM: PC4424.2 PC4425.2 PR4449.1 PR4452.2 PR4453.1 PU4401.21
PWR_GT_DOUT: PR4439.1 PR4442.1 PU4401.16
PWR_GT_EN1: PR4606.2 PU4602.3
PWR_GT_EN2: PR4612.2 PU4605.3
PWR_GT_FB: PC4417.2 PC4419.1 PR4440.1 PR4442.2 PU4401.17
PWR_GT_HG1: PR4604.1 PU4602.8
PWR_GT_HG1_R: PR4603.1 PR4604.2 PU4601.4
PWR_GT_HG2: PR4610.1 PU4605.8
PWR_GT_HG2_R: PR4609.1 PR4610.2 PU4604.4
PWR_GT_ILIM: PR4457.1 PU4401.20
PWR_GT_IOUT: PC4426.1 PR4458.1 PU4401.13
PWR_GT_LG1: PU4602.5 PU4603.4
PWR_GT_LG2: PU4605.5 PU4606.4
PWR_GT_PWM1: PR4465.1 PU4401.28 PU4602.2
PWR_GT_PWM2: PR4441.1 PU4401.29 PU4605.2
PWR_GT_SNB1: PC4605.1 PR4605.2
PWR_GT_SNB2: PC4610.1 PR4611.2
PWR_GT_SW1: PC4603.2 PG4601.1 PL4601.1 PR4603.2 PR4605.1 PU4601.1 PU4601.2 PU4601.3 PU4602.7 PU4603.5 PU4603.6 PU4603.7 PU4603.8
PWR_GT_SW2: PC4608.2 PG4603.1 PL4602.1 PR4609.2 PR4611.1 PU4604.1 PU4604.2 PU4604.3 PU4605.7 PU4606.5 PU4606.6 PU4606.7 PU4606.8
PWR_GT_TCP: PR4451.2 PR4452.1 PR4455.2
PWR_GT_TSNS: PC4428.1 PR4463.1 PU4401.27
PWR_GT_TSNS_R: PR4463.2 PR4467.1 PR4468.1
PWR_GT_VCC1: PC4604.2 PR4602.2 PU4602.4
PWR_GT_VCC2: PC4609.2 PR4607.2 PU4605.4
PWR_GT_VSN: PC4423.2 PR4450.2 PU4401.14
PWR_GT_VSP: PC4422.1 PR4447.2 PU4401.15
PWR_LED_G: C6402.1 PWRSW1.L2 Q6401.6 R6409.1
PWR_LED_Y: C6403.1 PWRSW1.L1 Q6401.3 R6413.2
PWR_PSYS: PR4462.1 PR4471.1 PU4401.8
PWR_RT6575_LDO5: PC4917.1 PG4903.1 PU4902.13
PWR_RT6575_PG: PR4958.1 PU4902.7
PWR_RT6575_VIN: PC4906.1 PR4932.2 PU4902.12
PWR_V_12V_CPU_S0_VSA: PC4701.1 PC4702.1 PC4703.1 PR4701.1 PR4702.1 PR4703.1 PR4704.1 PR4705.1 PR4706.1 PU4702.2 PU4702.3 PU4702.4 PU4702.10
PWR_VCCIO_DRV: PC4807.1 PR4810.2 PR4811.1 PU4801.5
PWR_VCCIO_DRV_R: PC4806.1 PR4810.1 PU4802.4
PWR_VCCIO_FB: PC4807.2 PC4811.2 PC4812.2 PR4814.2 PR4816.1 PU4801.3
PWR_VCCIO_FB1: PR4812.1 PR4813.1 PR4814.1
PWR_VCCIO_FB2: PC4811.1 PR4813.2
PWR_VCCIO_FB3: PC4812.1 PR4811.2
PWR_VCCIO_SS: PC4805.1 PU4801.4
PWR_VCCIO_VCC: PC4804.1 PR4808.2 PU4801.6
PWR_VCCIO_VCCSA_EN: D4303.2 PU4701.3 PU4801.1 R4801.2 U4801.3
PWR_VCCIO_VIN: PC4801.1 PC4802.1 PC4803.1 PR4801.1 PR4802.1 PR4803.1 PR4804.1 PR4805.1 PR4806.1 PR4807.1 PR4809.1 PU4802.5 PU4802.6 PU4802.7 PU4802.8
PWR_VCCSA_BOOT: PR4709.1 PU4701.10
PWR_VCCSA_BOOT_R: PC4704.2 PR4709.2
PWR_VCCSA_CS: PR4708.2 PU4701.2
PWR_VCCSA_FB: PC4708.2 PR4714.2 PR4716.1 PU4701.4
PWR_VCCSA_FB1: PC4708.1 PG4701.2 PR4715.1
PWR_VCCSA_LG: PU4701.6 PU4702.8
PWR_VCCSA_PG: PU4701.1 R4006.1
PWR_VCCSA_PHASE: PC4704.1 PL4701.1 PR4710.1 PR4713.1 PU4701.8 PU4702.9
PWR_VCCSA_RF: PR4711.1 PU4701.5
PWR_VCCSA_SNB: PC4707.1 PR4713.2
PWR_VCCSA_UG: PR4707.2 PU4701.9
PWR_VCCSA_UG_R: PR4707.1 PR4710.2 PU4702.1
PWR_VCCSA_VCC: PC4706.1 PR4712.1 PU4701.7
PWR_VCORE_BST1: PR4501.1 PU4502.1
PWR_VCORE_BST1_R: PC4503.1 PR4501.2
PWR_VCORE_BST2: PR4507.1 PU4506.1
PWR_VCORE_BST2_R: PC4508.1 PR4507.2
PWR_VCORE_BST3: PR4514.1 PU4510.1
PWR_VCORE_BST3_R: PC4513.1 PR4514.2
PWR_VCORE_BST4: PR4520.1 PU4514.1
PWR_VCORE_BST4_R: PC4518.1 PR4520.2
PWR_VCORE_COMP: PC4405.2 PC4406.2 PU4401.48
PWR_VCORE_COMP_A: PC4404.1 PR4407.2
PWR_VCORE_COMP_R: PC4405.1 PR4408.2
PWR_VCORE_CSCOMP: PC4413.1 PC4415.1 PR4427.1 PR4431.1 PR4433.2 PU4401.47
PWR_VCORE_CSN1: PC4407.2 PG4502.2 PR4412.2 PR4435.2 PU4401.36
PWR_VCORE_CSN2: PC4408.2 PG4504.2 PR4415.2 PR4436.2 PU4401.38
PWR_VCORE_CSN3: PC4410.2 PG4506.2 PR4419.2 PR4437.2 PU4401.40
PWR_VCORE_CSN4: PC4412.2 PG4508.2 PR4422.2 PR4438.2 PU4401.42
PWR_VCORE_CSP1: PG4501.2 PR4414.1 PR4426.2
PWR_VCORE_CSP1_IC: PC4407.1 PR4412.1 PR4414.2 PU4401.37
PWR_VCORE_CSP2: PG4503.2 PR4417.1 PR4429.2
PWR_VCORE_CSP2_IC: PC4408.1 PR4415.1 PR4417.2 PU4401.39
PWR_VCORE_CSP3: PG4505.2 PR4421.1 PR4432.2
PWR_VCORE_CSP3_IC: PC4410.1 PR4419.1 PR4421.2 PU4401.41
PWR_VCORE_CSP4: PG4507.2 PR4425.1 PR4434.2
PWR_VCORE_CSP4_IC: PC4412.1 PR4422.1 PR4425.2 PU4401.43
PWR_VCORE_CSREF: PC4416.1 PR4435.1 PR4436.1 PR4437.1 PR4438.1 PU4401.44
PWR_VCORE_CSSUM: PC4413.2 PC4415.2 PR4426.1 PR4428.2 PR4429.1 PR4432.1 PR4434.1 PU4401.45
PWR_VCORE_DOUT: PR4407.1 PR4409.1 PU4401.50
PWR_VCORE_DRVON: PR4506.1 PR4512.1 PR4518.1 PR4524.1 PR4606.1 PR4612.1 PU4401.30
PWR_VCORE_EN1: PR4506.2 PU4502.3
PWR_VCORE_EN2: PR4512.2 PU4506.3
PWR_VCORE_EN3: PR4518.2 PU4510.3
PWR_VCORE_EN4: PR4524.2 PU4514.3
PWR_VCORE_FB: PC4404.2 PC4406.1 PR4408.1 PR4409.2 PU4401.49
PWR_VCORE_HG1: PR4504.1 PU4502.8
PWR_VCORE_HG1_R: PR4503.1 PR4504.2 PU4501.4
PWR_VCORE_HG2: PR4510.1 PU4506.8
PWR_VCORE_HG2_R: PR4509.1 PR4510.2 PU4505.4
PWR_VCORE_HG3: PR4516.1 PU4510.8
PWR_VCORE_HG3_R: PR4515.1 PR4516.2 PU4509.4
PWR_VCORE_HG4: PR4522.1 PU4514.8
PWR_VCORE_HG4_R: PR4521.1 PR4522.2 PU4513.4
PWR_VCORE_ILIM: PR4433.1 PU4401.46
PWR_VCORE_IOUT: PC4414.1 PR4430.1 PU4401.1
PWR_VCORE_LG1: PU4502.5 PU4503.4 PU4504.4
PWR_VCORE_LG2: PU4506.5 PU4507.4 PU4508.4
PWR_VCORE_LG3: PU4510.5 PU4511.4 PU4512.4
PWR_VCORE_LG4: PU4514.5 PU4515.4 PU4516.4
PWR_VCORE_PWM1: PR4413.1 PU4401.34 PU4502.2
PWR_VCORE_PWM2: PR4424.1 PU4401.33 PU4506.2
PWR_VCORE_PWM3: PR4456.1 PU4401.32 PU4510.2
PWR_VCORE_PWM4: PR4403.1 PU4401.31 PU4514.2
PWR_VCORE_SCLK: PR4411.1 PU4401.5
PWR_VCORE_SDIO: PR4410.1 PU4401.3
PWR_VCORE_SNB1: PC4505.1 PR4505.2
PWR_VCORE_SNB2: PC4510.1 PR4511.2
PWR_VCORE_SNB3: PC4515.1 PR4517.2
PWR_VCORE_SNB4: PC4520.1 PR4523.2
PWR_VCORE_SW1: PC4503.2 PG4501.1 PL4501.1 PR4503.2 PR4505.1 PU4501.1 PU4501.2 PU4501.3 PU4502.7 PU4503.5 PU4503.6 PU4503.7 PU4503.8 PU4504.5 PU4504.6 PU4504.7 PU4504.8
PWR_VCORE_SW2: PC4508.2 PG4503.1 PL4502.1 PR4509.2 PR4511.1 PU4505.1 PU4505.2 PU4505.3 PU4506.7 PU4507.5 PU4507.6 PU4507.7 PU4507.8 PU4508.5 PU4508.6 PU4508.7 PU4508.8
PWR_VCORE_SW3: PC4513.2 PG4505.1 PL4503.1 PR4515.2 PR4517.1 PU4509.1 PU4509.2 PU4509.3 PU4510.7 PU4511.5 PU4511.6 PU4511.7 PU4511.8 PU4512.5 PU4512.6 PU4512.7 PU4512.8
PWR_VCORE_SW4: PC4518.2 PG4507.1 PL4504.1 PR4521.2 PR4523.1 PU4513.1 PU4513.2 PU4513.3 PU4514.7 PU4515.5 PU4515.6 PU4515.7 PU4515.8 PU4516.5 PU4516.6 PU4516.7 PU4516.8
PWR_VCORE_TCP: PR4427.2 PR4428.1 PR4431.2
PWR_VCORE_TSNS: PC4429.1 PR4464.1 PU4401.35
PWR_VCORE_TSNS_R: PR4464.2 PR4466.1 PR4469.1
PWR_VCORE_VCC: PC4402.1 PR4401.2 PR4462.2 PR4470.2 PU4401.7
PWR_VCORE_VCC1: PC4504.2 PR4502.2 PU4502.4
PWR_VCORE_VCC2: PC4509.2 PR4508.2 PU4506.4
PWR_VCORE_VCC3: PC4514.2 PR4513.2 PU4510.4
PWR_VCORE_VCC4: PC4519.2 PR4519.2 PU4514.4
PWR_VCORE_VRMP: PC4403.1 PR4402.2 PU4401.9
PWR_VCORE_VSN: PC4411.2 PR4420.2 PU4401.52
PWR_VCORE_VSP: PC4409.1 PR4418.2 PU4401.51
PWR_VDDQ: PC5010.1 PL5001.2 PR5006.1 PR5008.1 PR5010.1 PR5011.1 PR5012.1 PR5013.1 PR5015.1 PR5017.1 PR5018.1 PR5019.2 PR5020.1 PR5021.1 PR5022.1 PR5023.1 PR5026.1 PR5027.1 PR5028.1 PR5029.1 PR5030.1 PT5001.1
PWR_VDDQ_PG: PU5001.10 R4802.2 U4801.2
PWR_VDDQ_PG_ISOLATE: R4803.1 U4801.5 U4801.6
PWR_VDDQ_S3_EN: PU5001.7 R5001.1 R5002.1
PWR_VDDQ_S5_EN: PU5001.8 R5003.2
PWR_VDDQ_SNB: PC5014.1 PR5016.2
PWR_VDDQ_TON: PR5009.2 PU5001.9
PWR_VDDQ_VDDP: PC5002.1 PR5002.1 PU5001.12
PWR_VDDQ_VIN: PC5003.1 PC5004.1 PC5005.1 PC5006.1 PC5007.1 PL5002.1 PL5003.1 PR5009.1 PU5002.5 PU5002.6 PU5002.7 PU5002.8
PWR_VDDQ_VIOP: PC5001.1 PR5001.2 PU5001.11
PWR_VTT: PC5011.1 PC5012.1 PG5005.2 PG5006.2 PU5001.2 PU5001.20
PWRBTN_N: C6401.1 R6401.2 R6405.2 R9920.1 SB1.BE46 U2401.34 XDP1.41
PWRBTN_N_CN: APS1.4 R9920.2
PWRGD_PS: Q2407.D R2435.2 U2401.123 U2402.3
PWRGD_VPP: PR5202.2 PU5201.7 U4010.2
Q82_B: Q2703.B R2718.2
Q83_B: Q2704.B R2719.2
Q84_B: Q2702.B Q2703.E Q2704.E R2717.2
Q84_E: Q2702.E R2715.1
Q84_E2: C2722.1 R2715.2 R2716.1
Q85_B: Q2701.B R2714.1 R2716.2
RED_CRT: C5921.1 EU5901.3 L5903.2 VGA1.1
REQ64B_N1: R9205.2 SLOT4.116
RP_AUDOUT_L: AUD1.22 C3006.1 L3003.2
RP_AUDOUT_R: AUD1.25 C3005.1 L3004.2
RP_LINE1_L: AUD1.32 C3004.1 L3001.2
RP_LINE1_R: AUD1.35 C3003.1 L3002.2
RP_MIC1_L: AUD1.2 C3010.1 L3005.2
RP_MIC1_R: AUD1.5 C3009.1 L3006.2
RREF: R9506.1 U9501.16
RSMRST_SIO_N: R2434.1 R2474.1 R9906.1 SB1.BA47 U6305.G
RSMRST_SIO_N_1: R2434.2 U2401.58
RST_SEL: R9510.1 U9501.91
RTCRST_N_CN: APS1.6 R9919.2
RTL_ISOLATE_N: R3103.2 R3106.1 U3101.20
S0_5V_EN: R4201.2 U4201.3
S3_QUK: R4001.2 U4002.2 U4002.3 U4003.G
S4_VPP_OR: Q4002.5 R4021.1
S4_VPP_OR_R: C4010.1 R4021.2 R4022.1 R4023.1
SATA_LED_OUT: LED1.K U6401.3 U6402.3
SATA_RX_CON_N0: C6004.2 SATA1.5
SATA_RX_CON_N1: C6008.2 SATA4.5
SATA_RX_CON_N2: C6012.2 SATA2.3
SATA_RX_CON_N3: C6016.2 SATA3.5
SATA_RX_CON_P0: C6003.2 SATA1.6
SATA_RX_CON_P1: C6007.2 SATA4.6
SATA_RX_CON_P2: C6011.2 SATA2.2
SATA_RX_CON_P3: C6015.2 SATA3.6
SATA_RX_PCH_N0: C6004.1 SB1.C45
SATA_RX_PCH_N1: C6008.1 SB1.D46
SATA_RX_PCH_N2: C6012.1 SB1.F44
SATA_RX_PCH_N3: C6016.1 SB1.L41
SATA_RX_PCH_P0: C6003.1 SB1.C46
SATA_RX_PCH_P1: C6007.1 SB1.C47
SATA_RX_PCH_P2: C6011.1 SB1.E45
SATA_RX_PCH_P3: C6015.1 SB1.M40
SATA_TX_CON_N0: C6001.2 SATA1.3
SATA_TX_CON_N1: C6006.2 SATA4.3
SATA_TX_CON_N2: C6010.2 SATA2.5
SATA_TX_CON_N3: C6014.2 SATA3.3
SATA_TX_CON_P0: C6002.2 SATA1.2
SATA_TX_CON_P1: C6005.2 SATA4.2
SATA_TX_CON_P2: C6009.2 SATA2.6
SATA_TX_CON_P3: C6013.2 SATA3.2
SATA_TX_PCH_N0: C6001.1 SB1.B38
SATA_TX_PCH_N1: C6006.1 SB1.C39
SATA_TX_PCH_N2: C6010.1 SB1.B40
SATA_TX_PCH_N3: C6014.1 SB1.B41
SATA_TX_PCH_P0: C6002.1 SB1.C38
SATA_TX_PCH_P1: C6005.1 SB1.D39
SATA_TX_PCH_P2: C6009.1 SB1.C40
SATA_TX_PCH_P3: C6013.1 SB1.C41
SB3V_CT2: C4202.1 U4201.10
SB3V_EN: R4202.2 U4201.5
SB5V_CT1: C4201.1 U4201.12
SD_CD_BD: SD1.10 U3301.13
SD_CLK_BD: C3305.1 R3301.1 SD1.5
SD_CMD_BD: SD1.2 U3301.18
SD_DATA0_BD: SD1.7 U3301.11
SD_DATA1_BD: SD1.8 U3301.10
SD_DATA2_BD: SD1.9 U3301.21
SD_DATA3_BD: SD1.1 U3301.20
SD_RCOMP: R1514.1 SB1.BD1 SB1.BE1 SB1.BE2 SB1.BE4 SB1.BE5
SD_WP_BD: SD1.11 U3301.8
SIO_GREEN: R6412.2 R6414.2 U2401.2 U2401.24
SIO_GREEN_1: Q6401.5 R6414.1
SIO_PECI_REQ_N: R2002.1 SB1.BF36 U2401.20
SIO_PS_ON_N: R4302.1 U2401.53
SIO_SMBCLK1: R2425.1 U2401.70
SIO_SMBCLK2: R2426.2 U2401.26
SIO_SMBDAT1: R2427.1 U2401.72
SIO_SMBDAT2: R2422.2 U2401.25
SIO_SPKR: R2452.2 R2453.1 U2401.125
SIO_YELLOW: R6410.2 R6411.2 U2401.23
SIO_YELLOW_1: Q6401.2 R6411.1
SKL_CNL_N: CPU1.AB36 R422.2
SKL_PCUDEBUG_0: CPU1.H15 R9913.1 TP404.1
SKL_PCUDEBUG_1: CPU1.F15 TP405.1
SKL_PCUDEBUG_2: CPU1.F16 TP406.1
SKL_PCUDEBUG_3: CPU1.H16 R423.1 TP407.1
SKL_PCUDEBUG_4: CPU1.F19 R424.1
SKL_PCUDEBUG_5: CPU1.H18 TP408.1
SKL_PCUDEBUG_6: CPU1.G21 TP409.1
SKL_PCUDEBUG_7: CPU1.H20 TP410.1
SKL_PCUDEBUG_8: CPU1.G16 TP411.1
SKL_PCUDEBUG_9: CPU1.E16 R425.1
SKL_PCUDEBUG_10: CPU1.F17 TP412.1
SKL_PCUDEBUG_11: CPU1.H17 TP413.1
SKL_PCUDEBUG_12: CPU1.G20 TP414.1
SKL_PCUDEBUG_13: CPU1.F20 TP415.1
SKL_PCUDEBUG_14: CPU1.F21 R426.1
SKL_PCUDEBUG_15: CPU1.H19 TP416.1
SKL_PCUSTB_0_DN: CPU1.E14 XDP1.6
SKL_PCUSTB_0_DP: CPU1.F14 XDP1.4
SKL_PCUSTB_1_DN: CPU1.G18 XDP1.24
SKL_PCUSTB_1_DP: CPU1.F18 XDP1.22
SLP_A_N_CN: APS1.9 R9916.2
SLP_S0_N: R2048.1 SB1.BC28 U2001.6 U2003.3
SLP_S0_N_EXTD1: U2001.4 U2002.6
SLP_S0_N_EXTD2: U2002.5 U2003.6
SLP_S0_PLT_N: R2048.2 U2003.4 U2402.6 U4004.2 U4005.6 U4008.6 U9101.29
SLP_S3_N: R2046.1 R2049.1 R4216.2 R5002.2 R9917.1 SB1.BF42 U2401.121 U4002.5 U4301.1
SLP_S3_N_CN: APS1.8 R9917.2
SLP_S3_N_EXTD1: R2046.2 R2047.2 U2001.3
SLP_S3_N_R: Q4202.5 R4216.1
SLP_S3_N_R_1: Q4202.1 Q4202.3
SLP_S4_N: R809.2 R2050.1 R4020.1 R9918.1 SB1.BE42 U2401.69 U2401.122 U3201.4 U3801.4 U3901.4 U4010.1
SLP_S4_N_CN: APS1.7 R9918.2
SLP_S4_N_SFR: C806.1 Q802.2 R809.1
SLP_S4_N_SFR_1: Q802.5 Q802.6 R807.2 R810.1
SLP_S4_N_SFR_2: Q802.3 R804.2 R805.1 R806.1
SLP_S4_N_SFR_G: C802.1 C803.1 Q801.G R805.2
SLP_S4_VPP_N: Q4002.2 R4020.2
SLP_SUSB: R2053.1 R4202.1 R5101.1 SB1.BD39 U2401.71
SLP_WLAN_N: D6301.K R2044.1 R2052.1 SB1.BD42
SM_DRAMRST#: C1108.1 DIMM1.58 DIMM2.58 R1104.2 SB1.BB46
SM_PGCNTL: CPU1.AC36 R416.2
SMB_CLK_MAIN: DIMM1.141 DIMM2.141 R2461.1 R5911.2 U2401.81 XDP1.53
SMB_CLK_RESUME: R2437.1 SB1.BE26 SLOT1.B5 SLOT2.B5 SLOT3.B5 SLOT4.79 U2401.80
SMB_DATA_MAIN: DIMM1.285 DIMM2.285 R2459.1 R5912.2 U2401.79 XDP1.51
SMB_DATA_RESUME: R2436.1 SB1.BF26 SLOT1.B6 SLOT2.B6 SLOT3.B6 SLOT4.81 U2401.78
SMBALERT_N: R2314.1 R2316.1 SB1.BE25
SML0ALERT#: R2321.1 R2323.1 SB1.BF24
SML0CLK_PCH: R2009.1 SB1.BF25
SML0DATA_PCH: R2010.1 SB1.BE24
SMLICLK_PCH: R2012.1 R2426.1 SB1.BF27
SMLIDATA_PCH: R2013.1 R2422.1 SB1.BE27
SP_CTS_N: RN2403.3(A) U2401.101
SP_DCD_N: RN2402.4(A) U2401.96
SP_DSR_N: RN2402.3(A) U2401.97
SP_DTR_N: RN2403.2(A) U2401.102
SP_RI_N: RN2403.1(A) U2401.103
SP_RTS_N: RN2402.1(A) U2401.99
SP_RXD_N: R6802.1 RN2402.2(A) U2401.98
SP_RXD_N_CON: LPC1.14 R6802.2
SP_TXD_N: Q2402.3 R2429.2 R2473.1
SP_TXD_N_1: Q2402.5 R2405.2
SP_TXD_SIO: R2429.1 R6801.1 U2401.100
SP_TXD_SIO_CON: LPC1.13 R6801.2
SPEED_100*_CON: EU3202.4 R3201.1 RJ45R1.19
SPEED_100_N: R3201.2 TP3102.1 U3101.26
SPEED_1000*_CON: EU3202.3 R3202.1 RJ45R1.20
SPEED_1000_N: R3202.2 TP3103.1 U3101.25
SPI_CLK_PCH: R1515.1 R9107.1 RN2502.7(B) SB1.AW47
SPI_CLK_ROM1: RN2502.2(A) SSKT1.6 SSKT2.16 U2501.6 U2502.16
SPI_CLK_TPM: R9107.2 U9101.19
SPI_CS_PCH_N0: SB1.AY47 SSKT1.1 SSKT2.7 U2501.1 U2502.7
SPI_CS_PCH_N2: R9108.1 R9113.2 SB1.AT40
SPI_HOLD_PCH: R2317.1 R2331.1 RN2502.8(B) SB1.BA46
SPI_HOLD_ROM1: R2502.2 RN2502.1(A) SSKT1.7 SSKT2.1 U2501.7 U2502.1
SPI_SI_PCH: R2325.1 R2326.1 R9106.1 R9903.1 RN2502.6(B) SB1.AU41
SPI_SI_ROM1: RN2502.3(A) SSKT1.5 SSKT2.15 U2501.5 U2502.15
SPI_SI_TPM: R9106.2 U9101.21
SPI_SO_PCH: R2328.1 R9105.1 RN2501.1(A) SB1.BA45
SPI_SO_ROM1: RN2501.4(B) SSKT1.2 SSKT2.8 U2501.2 U2502.8
SPI_SO_TPM: R9105.2 U9101.24
SPI_WP_PCH: R2313.1 R2332.1 R2501.2 RN2501.2(A) SB1.AY48
SPI_WP_ROM1: RN2501.3(B) SSKT1.3 SSKT2.9 U2501.3 U2502.9
SPKR: R2302.1 R2304.1 R2702.2 SB1.AW29
SSD_PEDET: C1701.1 NGFF2.69 R1705.1 SB1.AM46
SSD_PEWAKE_N: NGFF2.54 R6202.1 R6203.1
SUS_ACK_EN_N: Q3801.1 R2419.1 R3817.2 U2401.94
SUS_PWR_ACK: C3807.1 R2004.1 R3813.2 R3815.1 R3817.1 R3818.2 SB1.BE35
SUS_PWR_ACK_5V_DUAL: R3807.2 R3808.1 R3812.1 R3816.1
SUS_PWR_ACK_5V_DUAL_L: C3806.1 Q3801.5 R3808.2
SUS_PWR_ACK_BJT: Q3801.2 R3809.1 R3814.2
SUS_PWR_ACK_BJT_L: Q3801.3 R3810.1 R3814.1
SUS_PWR_ACK_R: Q3801.6 R3811.2 R3815.2
SUS_WARNB: R2004.2 R2438.1 SB1.BC37
SUS_WARNB_R: C2412.1 R2438.2 U2401.68
SUSCLK: R1818.1 R1822.1 R2030.1 SB1.BE45
SUSCLK_SIO: R1818.2 U2401.19
SUSCLK_WIFI: NGFF1.50 R1822.2
SYS_FAN2_TACH_SIO: R2462.1 U2401.39
SYS_FAN_CTRL_CONN: D2602.A FANS1.4 R2614.2 R2616.2
SYS_FAN_CTRL_SIO: R2614.1 U2401.48
SYS_FAN_TACH_1: FANS1.3 R2615.2 R2618.1
SYS_FAN_TACH_SIO: R2476.1 R2617.1 R2618.2 U2401.38
SYS_THERMDA+: C2402.1 C2403.1 C2427.1 Q2403.B Q2403.C Q2409.E U2401.43
SYS_THERMDA-: C2402.2 C2403.2 C2427.2 Q2403.E Q2409.B Q2409.C U2401.44
TEST_EN: R9507.1 U9501.90
TH_SET: R2611.1 U2601.1
THERMTRIP#_CPU: CPU1.D11 R1703.1 R1710.2
THERMTRIP#_PCH: R1710.1 SB1.AD3
TMIN_SHIFT: R2306.2 R2431.1 R2446.2 U2401.33
TMIN_SHIFT_PCH: R2306.1 R2307.1 R2309.1 SB1.BD33
TP0: RN9502.2(A) U9501.105
TP1: RN9505.3(A) U9501.109
TP_CPU1_AB35: CPU1.AB35 TP902.1
TP_CPU1_AB37: CPU1.AB37 TP904.1
TP_CPU1_AB38: CPU1.AB38 TP905.1
TP_CPU1_AC37: CPU1.AC37 TP901.1
TP_CPU1_AJ22: CPU1.AJ22 TP906.1
TP_CPU1_D15: CPU1.D15 TP907.1
TP_CPU1_L8: CPU1.L8 TP903.1
TP_DIMM1_PIN1: DIMM1.1 R1102.1
TP_DIMM1_PIN145: DIMM1.145 R1102.2
TP_DIMM2_PIN1: DIMM2.1 R1202.1
TP_DIMM2_PIN145: DIMM2.145 R1202.2
TP_PCH_AH14: SB1.AH14 TP2202.1
TP_PCH_AH15: SB1.AH15 TP2201.1
TP_RSVD3_BC1: SB1.BC1 TP1506.1
TP_SLP_LAN_N: R2054.1 SB1.BF40 TP2001.1
TP_VCCPHY_SENSE: SB1.K47 TP2101.1
TP_VSS_AL37: SB1.AL37 TP1501.1
TP_VSSPHY_SENSE: SB1.K46 TP2102.1
TPEV_CFG_RCOMP: CPU1.M11 R418.1
TPM_CS: R9108.2 U9101.20
TPM_PIRQ: R9112.1 U9101.18
TPM_PP: TP9106.1 U9101.4
TPM_RST_R: Q9101.S R9110.2 R9111.2 U9101.17
TPM_VDD_P8: C9101.1 C9102.1 C9103.1 R9101.2 R9104.2 U9101.8 U9101.22
TRST_N: R2450.2 U2401.124
TS_CRIT#: R2613.2 U2601.3 U2602.2
U1.1: R3302.1 U3301.1
U1.6: C3304.1 U3301.6
U1.15: R3301.2 U3301.15
U1.24: C3303.1 U3301.24
UART0_RX: SB1.BE23 TP1505.1
UART0_TX: SB1.BB24 TP1504.1
UART_BT_WAKE_N: NGFF1.20 R2007.1 SB1.BE32
USB2_COMP: R1609.1 SB1.F4
USB2_ID: R1611.1 SB1.G3
USB2_VBUSSENSE: R1610.1 SB1.F3
USB30_RX_CON_N1: EU3801.1 EU3801.10 R3804.4 USB3F1.5
USB30_RX_CON_N2: EU3802.1 EU3802.10 R3806.4 USB3F2.5
USB30_RX_CON_P1: EU3801.2 EU3801.9 R3804.3 USB3F1.6
USB30_RX_CON_P2: EU3802.2 EU3802.9 R3806.3 USB3F2.6
USB30_RX_PCH_N1: R3804.1 SB1.D11
USB30_RX_PCH_N2: R3806.1 SB1.B9
USB30_RX_PCH_P1: R3804.2 SB1.C11
USB30_RX_PCH_P2: R3806.2 SB1.C9
USB30_TX_CMC_N1: C3802.2 R3801.1
USB30_TX_CMC_N2: C3804.2 R3802.1
USB30_TX_CMC_P1: C3801.2 R3801.2
USB30_TX_CMC_P2: C3803.2 R3802.2
USB30_TX_CON_N1: EU3801.4 EU3801.7 R3801.4 USB3F1.8
USB30_TX_CON_N2: EU3802.4 EU3802.7 R3802.4 USB3F2.8
USB30_TX_CON_P1: EU3801.5 EU3801.6 R3801.3 USB3F1.9
USB30_TX_CON_P2: EU3802.5 EU3802.6 R3802.3 USB3F2.9
USB30_TX_PCH_N1: C3802.1 SB1.F9
USB30_TX_PCH_N2: C3804.1 SB1.C3
USB30_TX_PCH_P1: C3801.1 SB1.F7
USB30_TX_PCH_P2: C3803.1 SB1.D4
USB_CON_PN1: EU3803.1 TR3801.4 USB3F1.2
USB_CON_PN2: EU3803.4 TR3802.4 USB3F2.2
USB_CON_PN5: EU3204.4 RJ45R1.2 TR3202.4
USB_CON_PN6: EU3204.1 RJ45R1.6 TR3201.4
USB_CON_PN7: EU3901.4 TR3902.3 USB2R1.6
USB_CON_PN8: R3303.2 U3301.2
USB_CON_PN9: EU3901.1 TR3901.3 USB2R1.2
USB_CON_PP1: EU3803.6 TR3801.3 USB3F1.3
USB_CON_PP2: EU3803.3 TR3802.3 USB3F2.3
USB_CON_PP5: EU3204.3 RJ45R1.3 TR3202.3
USB_CON_PP6: EU3204.6 RJ45R1.7 TR3201.3
USB_CON_PP7: EU3901.3 TR3902.4 USB2R1.7
USB_CON_PP8: R3303.1 U3301.3
USB_CON_PP9: EU3901.6 TR3901.4 USB2R1.3
USB_OC0_R_N: R1602.1 SB1.AH36 U3801.3
USB_OC1_R_N: R1603.1 SB1.AL40 U3901.3
USB_OC2_R_N: R1605.1 SB1.AJ44
USB_OC3_R_N: R1604.1 SB1.AL41 U3201.3
USB_OC4_R_N: RN1601.3(A) SB1.AV47
USB_OC5_R_N: RN1601.1(A) SB1.AR35
USB_OC6_R_N: RN1601.2(A) SB1.AR37
USB_PCH_PN1: SB1.J3 TR3801.1
USB_PCH_PN2: SB1.N13 TR3802.1
USB_PCH_PN5: SB1.M1 TR3202.1
USB_PCH_PN6: SB1.K7 TR3201.1
USB_PCH_PN7: SB1.L4 TR3902.2
USB_PCH_PN8: R3303.3 SB1.G4
USB_PCH_PN9: SB1.M6 TR3901.2
USB_PCH_PN14: NGFF1.5 SB1.E5
USB_PCH_PP1: SB1.J2 TR3801.2
USB_PCH_PP2: SB1.N15 TR3802.2
USB_PCH_PP5: SB1.L2 TR3202.2
USB_PCH_PP6: SB1.K6 TR3201.2
USB_PCH_PP7: SB1.L3 TR3902.1
USB_PCH_PP8: R3303.4 SB1.G5
USB_PCH_PP9: SB1.N8 TR3901.1
USB_PCH_PP14: NGFF1.3 SB1.F6
V_CPU_ST_PLL: C803.2 C804.1 C805.1 C1032.1 C1033.1 C2411.1 CPU1.V4 CPU1.V5 CPU1.V6 PC4401.1 PR4404.1 PR4405.1 PR4406.1 Q801.S R401.1 R402.2 R403.1 R404.1 R803.2 R808.1 R1703.2 R2021.2 R2024.2 R2026.2 R2028.2 R2430.1 U2401.29
V_SM_VREF_CNT: C601.1 C602.1 CPU1.AB40 R601.1
V_VCC3P3_EN: C4209.1 C4210.1 Q4201.4 R4204.2
V_VCC3P3_EN_R: R4203.2 R4204.1 U4202.6
VCORE_VCC_SEN: CPU1.C38 PR4416.2 PR4418.1 R802.1
VCORE_VSS_SEN: CPU1.D38 PC4409.2 PC4411.1 PR4420.1 PR4423.1 R802.2
VCTRL_VCC_EN: Q2407.G R4206.2 U4202.2 U4202.3
VGA1_DETECT: R1701.2 R1706.1 SB1.P48
VGA_CABLE_DET_N: EU5901.6 R1502.1 SB1.Y48 VGA1.4
VIDALERT#_CPU: CPU1.E39 R405.2
VIDALERT#_CPU_R: PR4406.2 PU4401.4 R401.2 R405.1
VIDSCK_CPU: CPU1.E38 R407.2
VIDSCK_CPU_R: PR4405.2 PR4411.2 R407.1
VIDSOUT_CPU: CPU1.E40 R408.2
VIDSOUT_CPU_R: PR4404.2 PR4410.2 R403.2 R408.1
VPP_EN: C4009.1 PR5204.1 R4019.2
VPP_EN_CR: Q4001.C R4017.2 R4019.1
VPP_EN_DDR4: Q4001.B Q4002.3 Q4002.6 R4018.2
VR_ENABLE: D4303.1 R4005.2 R4006.2 R4007.1 U4002.6 U4005.3
VR_ENABLE_IMVP: PU4401.2 R4007.2 U4005.4
VR_READY: Q2405.1 R4013.2 R4015.1 U4008.4
VR_READY_A: R4011.2 U4009.1
VR_READY_B: R4015.2 U4009.2
VR_READY_IMVP: PU4401.6 R4003.2 R4013.1 U4003.D U4008.3
VTT_EN: C4013.1 R4026.2 R5001.2
VTT_EN_CR: R4025.2 R4026.1
W_DISABLE#1: NGFF1.56 R6311.2
W_DISABLE#2: NGFF1.54 R6312.2
WAKE_M2_SSD_N: R1503.1 R6203.2 SB1.AL47
WLAN_PEDET: NGFF1.51 R1709.2 SB1.AR42
WLAN_USB_DET: NGFF1.1 R1901.1 SB1.AP48
XCLK_RBIAS: R1802.2 SB1.T3
XDP_PCUDEBUG_3: R423.2 R9904.2 XDP1.1
XDP_PRS: R9914.1 XDP1.60
XDP_PWR_DEBUG: R9912.2 R9913.2 XDP1.45
XDP_PWRGD: R9906.2 R9907.2 R9908.2 XDP1.39
XDP_VR_READY: C9901.1 R9903.2 R9905.2 R9922.1 XDP1.47
XTAL_24M_PCH_IN: C1802.1 R1812.1 SB1.U10 X1801.3
XTAL_24M_PCH_OUT: C1801.1 R1812.2 SB1.U9 X1801.1

Pads without a net: APS1 14 15; CPU1 A12 A14 A16 A18 AL15 AL25 AL26 AM15 AM25 AM26 AN17 AN20 AN21 AN25 AN26 AP15 AP19 AP20 AP25 AP26 AR25 AR26 AT16 AT33 AU9 AU10 AU12 AU16 AU29 AU31 AU32 AU33 AV1 AV10 AV13 AV16 AV24 AV25 AV31 AV32 AV33 AW2 AW16 AW29 AW31 AW33 AY10 AY31 B11 B12 B13 B14 B15 B16 B17 B18 B39 C9 C11 C13 C15 C17 C19 C40 D9 D10 D18 D19 D20 E10 E18 E20 H8 J7 J8 J11 J13 J14 J15 J17 J19 K8 K10 K11 K12 K13 L10 L12; DIMM1 8 19 30 41 47 49 52 54 56 93 100 111 122 133 144 192 194 196 197 199 201 205 227 230 234 235 237; DIMM2 8 19 30 41 47 49 52 54 56 93 100 111 122 133 144 192 194 196 197 199 201 205 227 230 234 235 237; EU3201 5; EU3202 1 5; EU3203 5; EU3204 5; EU3803 5; EU3901 5; EU5603 5 6; HDMI1 13 14; LPC1 11 12; NGFF1 6 16 38 40 42 58 60 62 66 68 70; NGFF2 6 8 20 22 24 26 28 30 32 34 36 38 40 42 44 46 48 56 58 67 68; PU4401 11 12; PU4902 19; PWRSW1 PTH1 PTH2; RN1601 4 5; RN2403 4 5; RN2502 4 5; SB1 A17 A25 A42 A44 AA1 AA45 AB2 AB3 AB48 AC2 AC3 AC6 AC7 AC43 AC44 AC48 AD47 AD48 AE39 AE43 AE44 AE47 AE48 AF47 AG45 AH35 AH40 AH41 AH46 AH47 AH48 AJ6 AJ7 AJ43 AJ46 AJ47 AK47 AL35 AL48 AM7 AM43 AM45 AM47 AM48 AN4 AN6 AN10 AN18 AN29 AN35 AN40 AN46 AN47 AP2 AP9 AP21 AP24 AP29 AP47 AR2 AR13 AR18 AR47 AR48 AT5 AT10 AU4 AU24 AU26 AU46 AU47 AU48 AV7 AV13 AV16 AV34 AV44 AV46 AW3 AW13 AW15 AW21 AW24 AW26 AW32 AW48 B10 B14 B15 B17 B18 B19 B25 B26 B27 B35 B36 B42 B44 BA20 BA24 BA33 BB16 BB20 BC17 BC22 BC33 BD8 BD16 BD17 BD20 BD21 BD29 BD30 BE8 BE9 BE12 BE14 BE15 BE17 BE18 BE19 BE20 BE21 BE29 BE33 BF8 BF9 BF10 BF14 BF15 BF17 BF18 BF19 BF21 BF23 BF31 BF33 BF41 BG8 C10 C14 C15 C16 C17 C18 C19 C20 C26 C27 C35 C36 C42 C44 D20 D29 D38 D42 D43 E28 E37 F11 F14 F16 F26 F39 G1 G2 G12 G14 G17 G26 G38 H2 H3 H42 J13 J15 J18 J37 J41 K3 K4 K13 K16 K18 K29 K37 K43 K44 L9 L26 L46 L47 L48 M10 M26 M29 M44 N2 N3 N18 N32 N42 N48 P9 P21 P24 P41 R10 R13 R15 R18 R21 R24 R32 R35 R37 R40 R46 R47 T1 T2 T46 T47 T48 U13 U35 U37 V2 V3 V47 W3 W4 W6 W7 W46 W47 Y2 Y14 Y15 Y35 Y36 Y46 Y47; SLOT1 A5 A6 A7 A8 B9; SLOT2 A5 A6 A7 A8 A19 A32 A33 A50 B9 B30 B82; SLOT3 A5 A6 A7 A8 B9; SLOT4 8 17 18 20 21 22 28; SSKT2 3 4 5 6 11 12 13 14; U2002 3; U2401 5 6 13 49 56 61 62 63 64 67 73 74 76 84 85 87 89 91 93 95 105 106 107 110 112; U2403 1; U2502 3 4 5 6 11 12 13 14; U2701 17 18 21 22 29 30 41 42 46; U3301 7 9 12 14 16 17 19 22 23; U5901 31; U9101 2 3 5 6 7 9 10 11 12 13 14 15 25 26 27 28 30 31 32; U9501 8 24 25 26 27 28 29 32 93 106 114 118 119 120 121 127 128; VGA1 11; XDP1 9 10 11 12 15 16 17 18 27 28 29 30 33 34 35 36

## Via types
v1: diameter 0.762, hole 0.381, TOP to BOTTOM, 1111 vias
v2: diameter 0.508, hole 0.254, TOP to BOTTOM, 4000 vias
v3: diameter 0.711, hole 0.406, TOP to BOTTOM, 1078 vias
v4: diameter 1.016, hole 0.508, TOP to BOTTOM, 1 via
v5: diameter 0.711, hole 0.356, TOP to BOTTOM, 1 via

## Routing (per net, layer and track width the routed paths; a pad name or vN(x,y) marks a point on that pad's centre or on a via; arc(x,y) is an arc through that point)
1.8VA: length 8.4
  TOP w0.203: U9501.11 195.31,58.69 195.14,58.52 195.37,58.29 U9501.12
  TOP w0.508: L9502.2 191.6,58.14 C9517.1 C9518.1 C9516.1 193.89,58.08 194.34,58.52 v1(194.41,58.52) 195.14,58.52
1.8VAAUX: length 24.8
  TOP w0.203: U9501.19 195.19,55.49 194.87,55.17
  TOP w0.508: L9503.2 v2(191.39,69.7) ; 194.87,55.17 193.73,54.03 C9523.1 C9527.1 192.75,53.9 C9525.1 v2(190.75,53.9)
  BOTTOM w0.508: v2(191.39,69.7) 190.22,68.53 190.22,60 191.34,58.89 v1(191.34,55.37) 191.34,54.48 v2(190.75,53.9)
1.8VD: length 80.1
  TOP w0.203: 205.84,61.79 205.84,61.87 204.85,62.87 U9501.112 ; U9501.78 213.66,55.49 ; U9501.125 199.65,65.34 ; v2(198.27,53.47) 197.85,53.89 U9501.23 ; 211.07,62.69 U9501.96 ; U9501.41 201.65,47.17
  TOP w0.508: 201.56,45.8 202.83,44.53 L9501.2 ; 201.56,45.8 C9513.1 201.56,47.08 201.65,47.17 ; 201.56,45.8 200.85,45.09 197.99,45.09 v2(196.98,46.1) ; 205.23,60.33 205.84,60.93 205.84,61.79 ; 205.23,60.33 205.56,59.99 208.94,59.99 209.78,60.83 209.78,61.82 210.64,62.69 211.07,62.69 211.07,62.77 212.01,63.71 212.01,64.82 212.83,65.63 216.71,65.63 v2(217.94,64.4) ; 205.23,60.33 201.29,60.33 199.64,61.98 v2(198.88,61.98) ; v2(198.88,65.91) 199.03,66.06 199.25,66.31 199.36,66.42 C9514.1 200.01,65.93 199.65,65.56 199.65,65.34 ; 213.66,55.49 214.79,55.49 C9515.1 v2(214.8,54.69)
  BOTTOM w0.508: v2(198.88,65.91) v1(198.88,64.03) v2(198.88,61.98) 198.88,54.03 198.32,53.47 v2(198.27,53.47) 198.27,48.41 196.98,47.12 v2(196.98,46.1) ; v2(217.94,64.4) 217.94,64.01 217.22,63.29 217.22,60.65 216.89,60.32 216.89,58.5 214.8,56.4 v2(214.8,54.69)
1.8VDAUX: length 9.7
  TOP w0.203: U9501.7 195.45,60.29
  TOP w0.508: 195.45,60.29 194.69,61.05 194.69,62.51 v1(194.39,62.81) 193.37,63.83 C9526.1 C9522.1 192.74,64.78 C9524.1 192.71,65.79 192.69,66.69 L9504.2
1V_CPU_CORE: length 139.4
  TOP w0.254: v2(81.08,67.97) 80.42,67.31 v2(78.87,67.31) ; v2(63.04,65.02) 61.52,63.5 v2(60.2,63.5)
  TOP w0.508: 43.74,66.67 42.29,68.12 38.75,68.12 PR4416.1
  TOP w1.016: PT4505.1 72.45,78.55 ; PT4505.1 72.45,80.46 ; PT4505.1 70.55,78.55 ; PT4505.1 70.55,80.46 ; 99.2,70.21 PL4504.2 ; PL4504.2 100.65,68.76 ; PL4504.2 102.09,70.21 ; PL4504.2 100.65,71.65 ; 86.8,80.84 PT4508.1 ; PT4508.1 88.71,80.84 ; PT4508.1 86.8,78.93 ; PT4508.1 88.71,78.93 ; 45.53,60.5 PL4501.2 ; PL4501.2 46.98,61.95 ; PL4501.2 45.53,63.4 ; PL4501.2 44.08,61.95 ; 64.82,64.8 63.82,65.8 PL4502.2 ; PT4507.1 80.71,80.46 ; PT4507.1 78.8,80.46 ; PT4507.1 80.71,78.55 ; PT4507.1 78.8,78.55 ; 61.4,79.19 PT4503.1 ; PT4503.1 63.31,79.19 ; PT4503.1 63.31,77.28 ; PT4503.1 61.4,77.28 ; 62.37,66.65 PL4502.2 ; PL4502.2 63.82,68.1 ; PL4502.2 65.26,66.65 ; 82.93,67.89 82.1,68.72 PL4503.2 ; 54.04,74.1 PT4502.1 ; PT4502.1 54.04,76.01 ; PT4502.1 55.94,76.01 ; PT4502.1 55.94,74.1 ; PL4503.2 83.55,69.7 ; PL4503.2 80.66,69.7 ; PL4503.2 82.1,71.15
  BOTTOM w0.254: 82.1,69.53 82.1,69 v2(81.08,67.97) ; v2(60.2,63.5) 59.56,63.5 PG4504.1 ; PG4502.1 45.59,61.89 PL4501.2 ; v2(63.04,65.02) 63.82,65.8 63.82,66.05 ; PL4504.2 100.58,70.14 PG4508.1 ; PG4506.1 v2(78.87,67.31)
  BOTTOM w1.016: PL4501.2 45.53,61.53 46.66,60.4 ; PL4501.2 45.53,63.4 ; PL4501.2 46.98,61.95 ; PL4501.2 44.08,61.95 ; 80.37,70.08 80.75,69.7 PL4503.2 ; PL4504.2 100.65,69.51 101.65,68.5 ; PL4504.2 99.2,70.21 ; PL4504.2 102.09,70.21 ; PL4504.2 100.65,71.65 ; 70.55,80.46 PT4505.1 ; PT4505.1 70.55,78.55 ; PT4505.1 72.45,78.55 ; PT4505.1 72.45,80.46 ; 61.4,77.28 PT4503.1 ; PT4503.1 63.31,77.28 ; PT4503.1 63.31,79.19 ; PT4503.1 61.4,79.19 ; 62.15,66.9 62.41,66.65 PL4502.2 ; PL4502.2 63.82,68.59 63.83,68.61 ; PL4502.2 65.28,66.65 ; PL4502.2 63.82,66.05 64.57,65.3 ; PL4503.2 82.1,71.24 ; PL4503.2 82.42,69.7 83.34,70.61 ; PL4503.2 82.1,69.53 83.19,68.45 ; 86.8,78.93 PT4508.1 ; PT4508.1 88.71,78.93 ; PT4508.1 86.8,80.84 ; PT4508.1 88.71,80.84 ; PT4502.1 55.94,76.01 ; PT4502.1 55.94,74.1 ; PT4502.1 54.04,76.01 ; PT4502.1 54.04,74.1 ; 78.8,78.55 PT4507.1 ; PT4507.1 80.71,78.55 ; PT4507.1 80.71,80.46 ; PT4507.1 78.8,80.46
  vias: v1(54.61,79.12) v1(63.25,91.06) v1(71.25,118.11) v1(77.47,90.68) v1(78.36,107.7) v1(82.8,118.62) v1(99.44,77.09) v2(63.5,101.33) v2(64.42,102.27) v2(64.39,100.44) v2(64.39,99.55) v2(65.31,103.18) v2(65.33,101.36) v2(65.33,100.44) v2(66.22,104.1) v2(66.22,102.3) v2(67.14,104.99) v2(67.14,104.11) v2(69.17,119.44) v2(69.9,119.67) v2(70.26,100.44) v2(70.26,98.61) v2(70.26,96.78) v2(70.26,94.96) v2(70.82,119.67) v2(71.17,102.32) v2(71.2,101.33) v2(71.17,100.44) v2(71.17,99.55) v2(71.17,98.61) v2(71.17,97.7) v2(71.17,96.78) v2(71.17,95.87) v2(71.17,94.96) v2(71.73,119.67) v2(72.08,104.11) v2(72.09,103.18) v2(72.09,102.27) v2(72.09,100.44) v2(72.09,98.61) v2(72.09,96.78) v2(72.65,119.67) v2(73.02,107.44) v2(73.02,106.81) v2(73,102.27) v2(73,101.36) v2(73,100.44) v2(73,99.53) v2(73,98.61) v2(73,97.7) v2(73,96.78) v2(73.92,103.18) v2(73.92,102.27) v2(73.92,100.44) v2(73.92,98.61) v2(73.92,96.78) v2(74.83,102.27) v2(74.83,101.36) v2(74.83,100.44) v2(74.83,99.53) v2(74.83,98.61) v2(74.83,97.7) v2(74.83,96.78) v2(75.18,111) v2(75.18,110.37) v2(75.18,109.37) v2(75.18,108.74) v2(75.74,104.11) v2(75.81,117.35) v2(76.64,119.52) v2(76.66,104.11) v2(77.11,116.56) v2(77.11,115.93) v2(77.11,114.58) v2(77.11,113.95) v2(77.34,107.44) v2(77.34,106.81) v2(77.36,119.59) v2(77.57,99.54) v2(78.15,119.69) v2(78.49,102.28) v2(78.5,100.43) v2(79.06,119.69) v2(79.4,101.36) v2(79.5,111) v2(79.5,110.37) v2(79.5,109.37) v2(79.5,108.74) v2(79.98,119.69) v2(80.89,119.69) v2(81.23,104.11) v2(81.66,112.93) v2(81.66,112.3) v2(81.66,107.44) v2(81.66,106.81) v2(81.81,119.69) v2(82.14,101.36) v2(82.72,119.69) v2(83.58,119.7) v2(83.55,111.64) v2(83.55,108.08) v2(83.97,101.36) v2(84.97,119.51) v2(85.8,103.19) v2(85.87,119.51) v3(43.41,63.12) v3(44.37,63.88) v3(45.9,63.96) v3(47.12,63.93) v3(47.47,62.76) v3(47.93,61.67) v3(48.46,63.96) v3(48.72,62.51) v3(49.12,76.63) v3(49.15,75.26) v3(49.2,77.8) v3(49.15,73.95) v3(50.52,76.76) v3(50.55,75.49) v3(50.6,77.93) v3(50.6,73.91) v3(54.03,81.06) v3(55.6,72.83) v3(55.91,84.72) v3(56.21,77.71) v3(56.26,78.83) v3(57,81.44) v3(58.17,85.94) v3(58.37,83.98) v3(58.4,82.71) v3(58.91,72.86) v3(59.69,80.86) v3(59.95,87.06) v3(59.88,71.48) v3(60.6,72.2) v3(61.02,73.51) v3(61.53,71.1) v3(61.74,74.23) v3(61.85,85.48) v3(61.98,90.59) v3(62.25,71.82) v3(62.74,87.13) v3(63.31,73.26) v3(63.63,92.57) v3(63.56,70.34) v3(64.03,73.98) v3(64.27,88.48) v3(64.28,71.06) v3(64.44,85.3) v3(64.49,94.55) v3(64.77,90.66) v3(65.79,87.06) v3(66.42,92.64) v3(67.06,88.55) v3(67.39,85.05) v3(67.82,90.59) v3(68.08,94.14) v3(68.48,86.98) v3(69.04,103.69) v3(69.04,101.58) v3(69.04,100.04) v3(69.04,96.83) v3(68.99,95.06) v3(69.14,98.28) v3(69.17,105.5) v3(69.47,92.57) v3(70.11,88.48) v3(70.18,85.13) v3(70.49,105.42) v3(70.51,90.51) v3(71.07,86.88) v3(71.66,105.42) v3(72.17,92.49) v3(72.8,88.4) v3(73.08,105.42) v3(73.11,90.41) v3(73.23,85.05) v3(73.94,104.45) v3(74.27,86.83) v3(74.53,105.45) v3(74.76,92.39) v3(75.24,84.9) v3(75.39,88.3) v3(76.13,105.5) v3(76.86,84.87) v3(76.94,75.85) v3(77.3,105.47) v3(77.6,104.38) v3(77.7,86.98) v3(78.23,75.18) v3(78.79,105.5) v3(78.82,84.85) v3(79.56,72.37) v3(79.79,104.45) v3(80.06,105.52) v3(80.28,73.09) v3(81.03,75.06) v3(81.64,105.65) v3(81.98,72.37) v3(82.45,104.66) v3(82.7,73.09) v3(83.14,105.67) v3(84.01,71.35) v3(84.59,75.88) v3(84.64,73.39) v3(84.73,72.07) v3(85.36,74.11) v3(97.34,74.28) v3(98.06,74.99) v3(98.11,71.74) v3(98.82,72.45) v3(99.63,74.28) v3(100.35,74.99) v3(101.15,73.13) v3(101.87,73.85) v3(103.06,69.32) v3(103.19,71.35) v3(103.78,70.04) v3(103.9,72.07)
1V_CPU_GT: length 93
  TOP w0.508: v2(16.19,79.4) PR4445.1
  TOP w1.016: PL4602.2 27.41,113.02 ; PL4602.2 25.96,111.57 ; PL4602.2 28.86,111.57 ; PL4602.2 27.41,110.12 ; 33.41,87.52 PT4602.1 ; PT4602.1 33.41,89.42 ; PT4602.1 35.32,87.52 ; PT4602.1 35.32,89.42 ; 33.44,103.39 PT4604.1 ; PT4604.1 35.34,103.39 ; PT4604.1 33.44,105.3 ; PT4604.1 35.34,105.3 ; PT4603.1 35.47,113.17 ; PT4603.1 35.47,111.26 ; PT4603.1 33.57,111.26 ; PT4603.1 33.57,113.17 ; 26.33,98.42 PL4601.2 ; PL4601.2 28.48,96.27 ; PL4601.2 26.33,96.27 ; PL4601.2 28.48,98.42 ; 33.41,95.39 PT4605.1 ; PT4605.1 35.32,95.39 ; PT4605.1 33.41,97.3 ; PT4605.1 35.32,97.3
  BOTTOM w0.254: PL4602.2 26.78,110.95 25.91,110.46 PG4604.1 ; PG4602.1 27.34,97.28 PL4601.2
  BOTTOM w0.508: 30.58,87.93 21.69,79.04 16.55,79.04 v2(16.19,79.4)
  BOTTOM w1.016: 33.41,87.52 PT4602.1 ; PT4602.1 35.32,89.42 ; PT4602.1 35.32,87.52 ; PT4602.1 33.41,89.42 ; 33.57,111.26 PT4603.1 ; PT4603.1 33.57,113.17 ; PT4603.1 35.47,111.26 ; PT4603.1 35.47,113.17 ; PL4602.2 29.21,111.57 ; PL4602.2 27.41,112.19 28.5,113.28 ; PL4602.2 27.41,110.13 27.71,109.83 ; PL4602.2 27.16,111.57 26.09,112.65 ; PT4605.1 35.32,97.3 ; PT4605.1 33.41,97.3 ; PT4605.1 35.32,95.39 ; PT4605.1 33.41,95.39 ; PT4604.1 35.34,105.3 ; PT4604.1 33.44,103.39 ; PT4604.1 33.44,105.3 ; PT4604.1 35.34,103.39 ; PL4601.2 28.48,96.27 ; PL4601.2 28.48,98.42 ; PL4601.2 27.41,96.75 26.42,95.76 ; PL4601.2 27.41,97.79 26.47,98.73
  vias: v1(28.4,105.36) v1(31.06,91.67) v1(44.42,96.77) v1(56.79,106.38) v1(56.92,104.06) v2(58.8,100.47) v2(58.86,109.61) v2(58.86,108.67) v2(58.88,107.78) v2(58.86,106.87) v2(58.88,105.93) v2(58.88,105.04) v2(58.88,104.12) v2(58.88,103.21) v2(58.91,102.3) v2(58.88,101.36) v2(59.01,110.6) v2(59.85,109.59) v2(59.85,107.76) v2(59.85,105.93) v2(59.82,104.12) v2(59.8,102.3) v2(59.82,100.47) v2(60.43,111.34) v2(60.46,112.41) v2(60.74,110.5) v2(60.74,107.78) v2(60.74,106.84) v2(60.74,105.93) v2(60.74,105.01) v2(60.74,104.12) v2(60.76,109.59) v2(60.76,108.67) v2(60.76,103.18) v2(60.76,102.3) v2(60.76,101.36) v2(60.76,100.44) v2(61.65,109.56) v2(61.65,107.76) v2(61.65,104.12) v2(61.65,102.3) v2(61.62,100.47) v2(61.68,105.93) v2(62.54,105.95) v2(62.57,111.42) v2(62.59,110.5) v2(62.56,109.64) v2(62.59,108.67) v2(62.56,107.78) v2(62.56,106.84) v2(62.56,105.01) v2(62.59,104.12) v2(62.56,103.18) v2(62.59,102.3) v2(62.56,101.38) v2(62.56,100.47) v2(63.48,111.41) v2(63.48,109.59) v2(63.48,107.78) v2(63.48,105.93) v2(63.48,104.1) v2(63.45,102.27) v2(64.39,112.3) v2(64.39,111.41) v2(64.39,110.5) v2(64.42,109.59) v2(64.42,108.65) v2(64.42,107.76) v2(64.42,106.82) v2(64.39,105.93) v2(64.39,105.04) v2(64.39,104.1) v2(64.37,103.18) v2(65.33,112.33) v2(65.31,110.5) v2(65.31,108.65) v2(65.31,106.84) v2(65.31,105.01) v2(65.33,104.12) v2(66.23,114.17) v2(70.86,111.03) v2(70.86,110.37) v2(70.86,107.44) v2(70.86,106.81) v2(73.02,111) v2(73.02,110.37) v3(28.3,100.04) v3(28.73,94.37) v3(29.01,91.25) v3(29.19,97.8) v3(29.82,88.86) v3(29.93,116.93) v3(29.87,96.07) v3(30.28,111.24) v3(30.53,102.75) v3(30.53,94.22) v3(30.59,114.13) v3(30.86,115.99) v3(31.75,87.51) v3(32.03,107.66) v3(32,102.11) v3(32.57,115.96) v3(32.57,99.53) v3(33.18,91.35) v3(33.81,107.6) v3(33.96,99.37) v3(34.52,116.09) v3(34.55,91.53) v3(36.2,102.87) v3(36.32,88.01) v3(37.67,87.61) v3(38.26,113.07) v3(38.31,103.21) v3(38.26,95.31) v3(39.2,87.54) v3(39.42,103.18) v3(39.42,95.36) v3(40.59,105.95) v3(40.95,87.31) v3(41.28,89.57) v3(41.38,101.66) v3(42.04,91.45) v3(42.07,108.57) v3(42.19,96.45) v3(42.35,104.66) v3(42.68,85.56) v3(43.51,99.02) v3(43.56,92.8) v3(43.84,101.28) v3(44,87.23) v3(44.33,89.49) v3(44.61,103.16) v3(45.06,95.08) v3(45.09,91.37) v3(45.5,108.6) v3(46.13,104.51) v3(46.64,106.69) v3(46.56,98.94) v3(46.89,101.2) v3(47.65,103.08) v3(47.78,94.04) v3(48.29,108.67) v3(48.49,90.61) v3(48.92,104.58) v3(48.92,96.91) v3(49.25,98.87) v3(49.58,101.13) v3(49.69,106.61) v3(50.35,103.01) v3(51.34,108.6) v3(51.85,98.77) v3(51.97,104.51) v3(52.18,101.03) v3(52.38,106.54) v3(52.94,102.91) v3(54.03,108.52) v3(54.66,104.43) v3(54.97,106.44) v3(55.05,98.71) v3(55.38,100.98) v3(56.14,102.85) v3(56.62,108.42) v3(66.83,113.07) v3(66.86,111.67) v3(66.93,110.2) v3(66.91,109) v3(66.91,107.83) v3(66.98,106.61) v3(68.13,113.17) v3(68.23,114.46) v3(68.15,111.77) v3(68.23,110.3) v3(68.2,109.1) v3(68.2,107.93) v3(68.28,106.72)
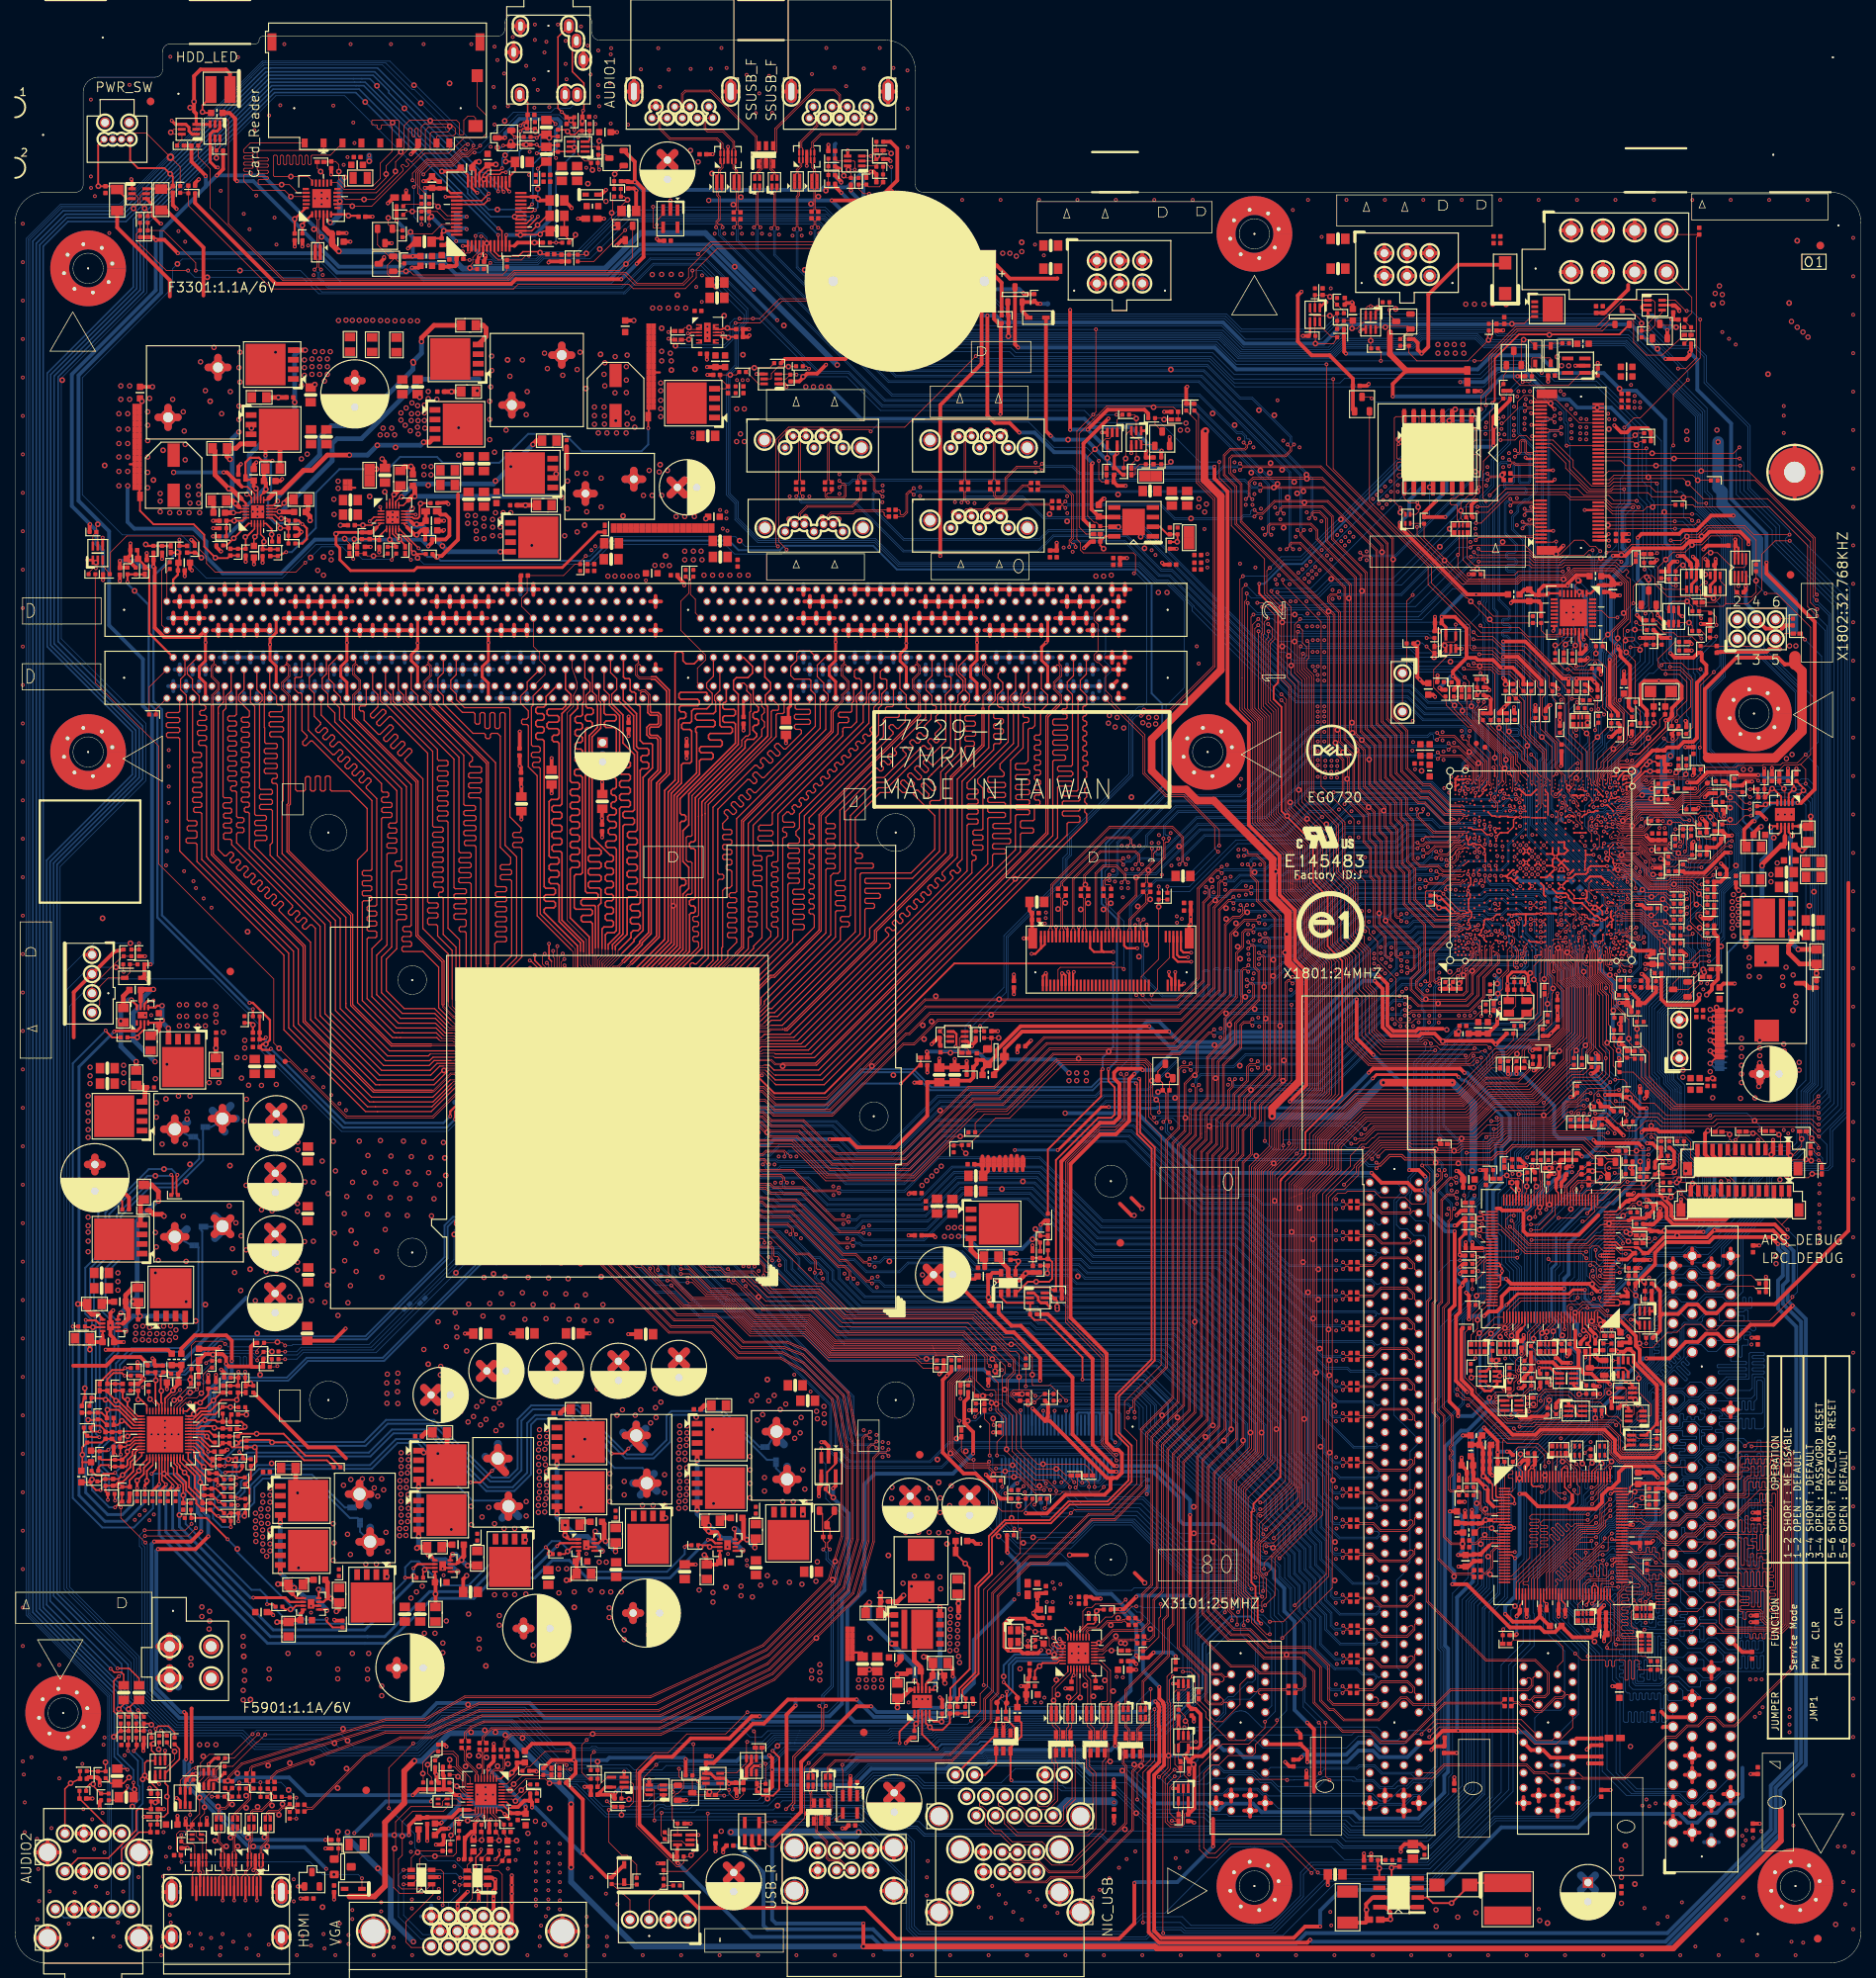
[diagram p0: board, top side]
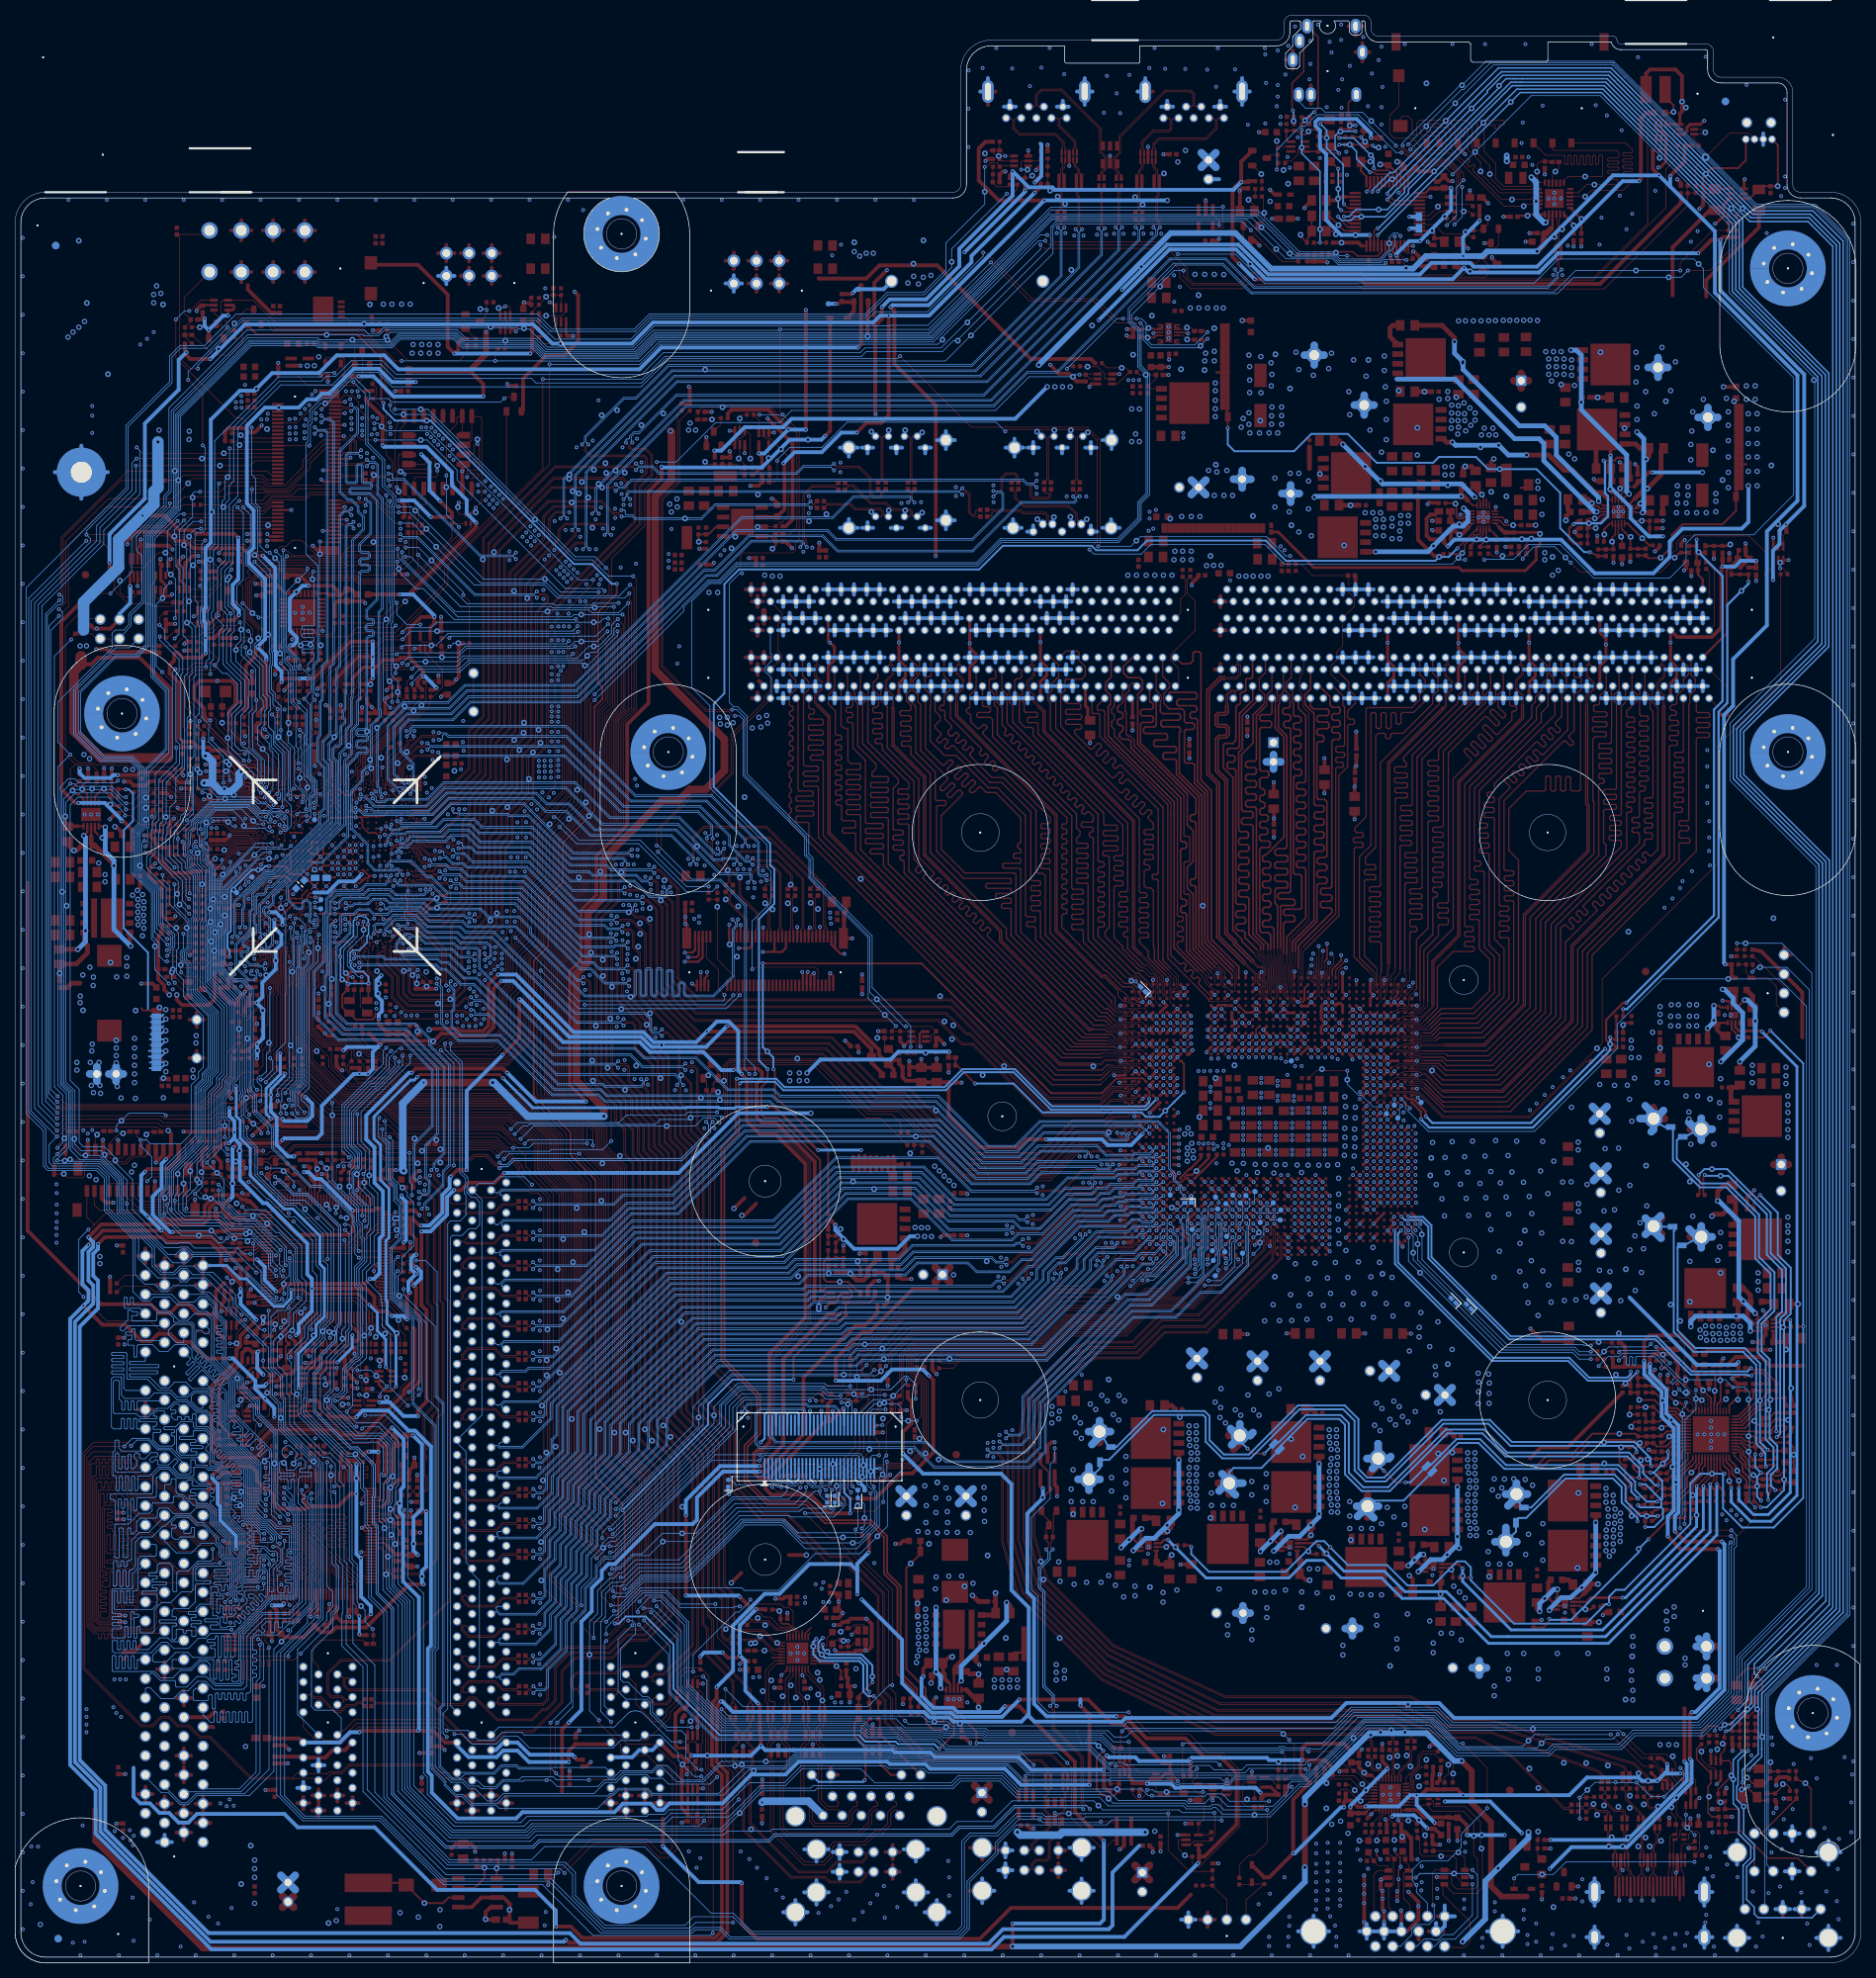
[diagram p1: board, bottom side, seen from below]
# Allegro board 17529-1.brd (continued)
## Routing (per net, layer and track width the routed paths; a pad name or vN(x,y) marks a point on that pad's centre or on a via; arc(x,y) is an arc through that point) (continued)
1V_PCH_SB: length 259.8
  TOP w0.254: v3(224.08,118.87) 224.97,119.76 ; 224.97,119.76 PR5122.2 ; 224.97,119.76 224.71,119.76 224.08,120.39 v3(224.08,120.52) PR5121.2 ; SB1.AD20 202.08,142.29 202.08,141.16 SB1.AE17 ; PR5119.2 224.46,124.33 v3(224.08,124.71) 224.46,125.09 PR5133.2 ; PR5120.2 224.21,122.05 v3(224.08,121.92) 224.08,121.92 224.71,121.28 PR5123.2 ; PR5134.2 224.21,125.86 v3(224.08,125.98) ; PR5117.2 224.46,123.57 v3(224.08,123.19) 224.46,122.81 PR5118.2
  TOP w0.356: v2(206.55,75.95) 206.4,75.95 206.03,76.32 Q2406.1
  TOP w0.508: 136.14,71.63 v2(134.49,73.28) ; 136.14,71.63 136.14,71.75 136.53,72.14 136.53,72.67 136.55,72.69 136.55,73.89 R9909.1 ; 136.14,71.63 136.78,71.63 144.32,64.08 145.11,64.08 ; v2(180.15,130.61) 181.41,129.35 181.41,123.91 182.17,123.14 185.17,123.14 185.47,123.44 188.72,123.44 ; v2(133.6,59.44) 133.65,59.39 136.4,59.39 138.86,61.86 144.03,61.86 144.81,62.64 144.81,63.78 145.11,64.08 ; 145.11,64.08 145.63,64.08 146.3,64.76 146.3,67.32 145.83,67.79 145.29,67.79 144.28,68.8 144.28,80.51 139.52,85.27 139.52,105.58 143.44,109.5 145.52,109.5 147.27,111.25 147.27,116.79 v2(147.96,117.47) ; v2(214.77,115.87) 214.77,115.72 214.82,115.67 C2122.1 ; v2(152.55,123.08) 133.11,123.08 130.78,120.75 Q801.D 130.78,118.97 129.41,117.6 R803.1 ; C2124.1 203.91,125.5 v2(203.89,125.53) C2113.1
  BOTTOM w0.254: PR5122.2 224.71,119.76 224.08,120.39 v3(224.08,120.52) PR5121.2 ; PR5123.2 224.66,121.28 224.28,121.67 ; 224.41,123.83 224.66,123.57 PR5117.2 ; v3(224.08,121.92) 224.21,122.05 PR5120.2 ; 224.41,125.35 224.66,125.09 PR5133.2 ; v3(224.08,124.71) 224.46,124.33 PR5119.2 ; PR5118.2 224.66,122.81 224.41,123.06 ; PR5135.2 224.71,118.24 224.08,118.87 v3(224.08,118.87) 224.21,119 PR5132.2
  BOTTOM w0.279: XDP1.44 134.42,73.05 134.43,73.06 134.43,73.22 v2(134.49,73.28) ; v2(133.6,59.44) 133.6,61.34 134.36,62.1 134.36,62.59 134.42,62.65 XDP1.43
  BOTTOM w0.381: v2(206.55,75.95) 206.55,80.52 204.22,82.85 204.22,84.31 203.11,85.42 203.11,91.76 203.4,92.05 203.4,92.05 203.71,92.35 203.71,96.06 207.29,99.64 208.46,99.64 210.27,101.46 210.3,101.46 212.92,104.08 212.92,107.66 214.25,108.99 214.25,111.35 214.77,111.87 v2(214.77,115.87)
  BOTTOM w0.508: v2(147.96,117.47) 148.41,117.93 148.41,123.16 149.66,124.41 151.22,124.41 v2(152.55,123.08) 153.95,121.68 159.61,121.68 160.93,123.01 170.17,123.01 177.77,130.61 v2(180.15,130.61)
  vias: v1(189.61,129.03) v1(224.38,116.92) v1(224.92,126.26) v2(188.92,155.25) v2(189.56,154.66) v2(198.2,147.73) v2(198.23,146.17) v2(198.98,147.73) v2(198.98,146.94) v2(198.99,145.4) v2(198.98,144.63) v2(198.97,142.29) v2(199.75,143.84) v2(199.77,147.7) v2(199.77,144.6) v2(200.53,146.15) v2(200.53,144.6) v2(200.53,143.84) v2(201.32,146.15) v2(201.32,144.6) v2(201.29,143.84) v2(202.08,147.7) v2(202.08,145.39) v2(202.08,144.6) v2(214.12,129.03) v3(189.26,123.32) v3(189.66,130.96) v3(220.07,122.53) v3(220.09,121.56) v3(220.5,117.98) v3(220.47,117.04) v3(224.08,117.78)
1V_VCCA_XTAL: length 12.1
  TOP w0.127: SB1.P2 196.72,133.95 196.72,134.34 SB1.P3
  TOP w0.508: v2(195.94,124.76) 195.94,124.05 C2119.1 C2118.1 L2102.2
  BOTTOM w0.508: v2(195.94,124.76) 195.94,125.35 195.53,125.76 195.53,127.15 196.24,127.86 196.24,129.84 v2(195.58,130.51)
  vias: v1(196.16,131.06)
1V_VCCAMPHYPLL:
  vias: v1(185.93,157.53)
1V_VCCDSW: length 5.5
  TOP w0.254: SB1.BG45 SB1.BG46 213.47,155.46 215.49,157.48 v1(216.13,157.48) C2125.1
5V_AUD_S5:
  vias: v1(75.72,235.13)
5V_DDC_HDMI: length 33.8
  TOP w0.102: v2(22,13.34) 21.91,13.42 C5609.1 21.91,14.32 21.34,14.89 21.34,17.02 21.72,17.4 22.35,17.4 22.75,17 ; 22.75,17 22.75,16.38 22.82,16.31 RN5601.2 ; 22.75,17 22.79,16.96 RN5601.1 ; v2(45.85,11.18) D5601.K
  BOTTOM w0.102: v2(22,13.34) 38.99,13.34 40.64,11.68 v1(42.14,11.68) 45.34,11.68 v2(45.85,11.18)
5V_DISPLAY_S0: length 15.9
  TOP w0.203: 60.14,20.22 60.2,20.17 U5901.17
  TOP w0.508: v2(52.07,16.89) 52.07,18.16 53.09,19.18 C5907.1 54.42,19.18 C5906.1 54.49,19.23 57.71,19.23 58.7,20.22 60.14,20.22
  BOTTOM w0.508: v2(52.07,16.89) v1(50.11,16.89) v2(47.09,16.89)
5V_DISPLAY_SFR_G: length 3.9
  TOP w0.102: v1(42.67,17.35) 42.67,16.32 R5920.2 R5921.1 42.74,14.26 Q5901.G
5V_HDMI_CONN: length 1.8
  TOP w0.305: HDMI1.18 23.95,8.31
  vias: v1(40.64,7.37)
5V_S0: length 596.3
  TOP w0.356: v2(195,78.77) 195,78.7 194.46,78.17 Q2402.4
  TOP w0.381: v2(207.52,88.95) 205.94,88.95 205.41,88.42 198.63,88.42 v2(197.15,86.94)
  TOP w0.508: 225.8,93.43 SLOT4.120 ; SLOT4.120 227.76,93.43 ; SLOT4.120 226.78,92.45 ; SLOT4.120 226.78,94.4 ; SATAP2.2 185.09,225.94 ; SATAP2.2 184,227.03 ; SATAP2.2 184,224.85 ; v2(113.16,33.91) 111.28,33.91 103.91,26.54 103.91,19.96 v2(100.08,16.13) ; 221.7,34.03 SLOT4.31 ; SLOT4.31 222.68,35.01 ; SLOT4.31 221.7,35.98 ; SLOT4.31 220.72,35.01 ; SLOT4.38 225.22,38.82 ; SLOT4.38 223.26,38.82 ; SLOT4.38 224.24,39.79 ; SLOT4.38 224.24,37.55 ; v2(28.64,79.55) 28.64,82.21 27.91,82.93 23.72,82.93 21.97,81.18 PR4470.1 ; 146,223.85 SATAP1.2 ; SATAP1.2 146,226.03 ; SATAP1.2 147.09,224.94 ; SLOT4.12 226.78,23.28 ; SLOT4.12 226.78,21.33 ; SLOT4.12 225.8,22.31 ; SLOT4.12 227.76,22.31 ; SLOT4.117 220.14,92.16 ; SLOT4.117 219.16,91.18 ; SLOT4.117 219.16,93.13 ; SLOT4.117 218.18,92.16 ; SLOT4.5 219.16,19.47 ; SLOT4.5 220.14,18.5 ; SLOT4.5 218.18,18.5 ; 219.16,20.06 SLOT4.9 ; SLOT4.9 219.16,22.01 ; SLOT4.9 218.18,21.04 ; SLOT4.9 220.14,21.04 ; v2(22.35,33.13) 22.61,32.88 v2(22.61,26.92) ; 224.24,91.18 SLOT4.118 ; SLOT4.118 225.22,92.16 ; SLOT4.118 223.26,92.16 ; SLOT4.118 224.24,93.13 ; SLOT4.10 224.24,22.01 ; SLOT4.10 223.26,21.04 ; SLOT4.10 225.22,21.04 ; SLOT4.10 224.24,20.06 ; 220.72,93.43 SLOT4.119 ; SLOT4.119 221.7,92.45 ; SLOT4.119 222.68,93.43 ; SLOT4.119 221.7,94.4 ; SLOT4.7 222.68,19.77 ; SLOT4.7 221.7,20.74 ; SLOT4.7 220.72,19.77 ; 218.18,89.62 SLOT4.113 ; SLOT4.113 219.16,88.64 ; SLOT4.113 219.16,90.59 ; SLOT4.113 220.14,89.62 ; SLOT4.19 222.68,27.39 ; SLOT4.19 221.7,28.36 ; SLOT4.19 220.72,27.39 ; SLOT4.19 221.7,26.41 ; v2(18.89,54.68) 23.85,54.68 v2(25.53,56.36) ; v2(123.95,37.85) 123.95,38.86 123.27,39.55 PR4712.2 ; v2(112.14,5.21) v3(112.14,2.16) ; 225.22,89.62 SLOT4.114 224.24,90.59 ; 221.7,23.87 SLOT4.15 ; SLOT4.15 221.7,25.82 ; SLOT4.15 222.68,24.85 ; SLOT4.15 220.72,24.85 ; R6418.1 28.35,244.47 29.08,243.74 29.08,235.71 v2(29.34,235.46)
  TOP w0.762: v3(73.5,12.62) v3(73.5,20.95) ; v3(112.14,2.16) 150.67,2.16 150.92,1.91 219.2,1.91 233.43,16.13 233.43,20.19 ; v3(52.78,26.7) 51.44,25.35 51.44,21.11 48.9,18.57 48.9,10.16 47.5,8.76 44.2,8.76
  L3 w0.508: 144.91,224.94 SATAP1.2 ; SATAP1.2 146,226.03 ; SATAP1.2 147.09,224.94 ; SATAP1.2 146,223.85 ; 182.91,225.94 SATAP2.2 ; SATAP2.2 184,224.85 ; SATAP2.2 185.09,225.94 ; SATAP2.2 184,227.03
  BOTTOM w0.381: v2(195,78.77) 195,82.4 196.11,83.52 196.11,85.9 v2(197.15,86.94) ; SLOT4.117 216.03,92.16 214.27,90.39 213.39,90.39 209.76,86.76 208.58,86.76 207.52,87.82 v2(207.52,88.95)
  BOTTOM w0.508: v2(113.16,33.91) 113.92,33.15 119.44,33.15 119.99,33.71 122.59,33.71 122.92,34.04 122.92,34.04 124.18,35.3 124.18,37.62 v2(123.95,37.85) ; v2(100.08,16.13) 100.08,5.71 100.58,5.21 v2(112.14,5.21) ; v2(29.34,235.46) 31.5,235.46 42.8,224.16 51.18,224.16 51.69,224.66 52.19,224.66 56.77,224.66 58.29,223.14 78.36,223.14 82.3,227.08 91.69,227.08 v2(97.66,221.11) ; v2(22.61,26.92) 22.38,26.7 22.38,23.81 30.89,15.29 38.26,15.29 v2(41.13,12.42) ; v2(25.53,56.36) 25.53,59 24.74,59.78 24.74,70.61 26.34,72.21 26.34,75.49 28.64,77.79 v2(28.64,79.55) ; v2(22.35,33.13) 21.86,33.13 18.67,36.32 18.67,54.46 v2(18.89,54.68)
  BOTTOM w0.762: v3(112.14,2.16) 82.04,2.16 73.5,10.7 v3(73.5,12.62) ; v3(52.78,26.7) 53.75,26.7 57.4,30.35 64.97,30.35 65.6,29.72 65.6,29.72 66.75,28.57 73.5,21.82 v3(73.5,20.95)
  vias: v1(93.73,217.68) v1(95.12,224.16) v2(229.36,37.47) v2(230,32.51) v2(230.12,37.47) v2(230.63,33.02) v2(230.89,37.47) v2(231.01,33.78) v2(234.57,33.53) v2(234.57,32.51) v2(234.57,31.5) v2(234.57,30.48) v3(232.79,93.34) v3(232.79,92.41)
5V_S5: length 723.1
  TOP w0.203: U4201.4 89.36,215.47 89.23,215.34 v2(88.95,215.34)
  TOP w0.305: PR4937.2 PR4938.2 PR4939.2 PR4940.2 PR4925.2 PR4927.2 PR4929.2 PR4949.2 PR4948.2 PR4947.2 PR4946.2 ; PR4946.2 PR4945.2 PR4936.2 PR4933.2 PR4934.2 ; PR4946.2 15.16,198.04
  TOP w0.508: R4305.1 221.55,213.04 v2(221.36,212.85) 221.36,212.47 220.85,211.96 v2(218.19,211.96) ; v2(233.04,95) 232.13,95.91 224.56,95.91 223.9,95.25 218.2,95.25 216.79,93.84 216.79,92.31 214.27,89.79 R2468.1 v2(214.19,89.05) ; v2(231.52,185.06) 231.52,183.62 237.9,177.24 237.9,155.09 236.09,153.29 v2(235.62,153.29) ; R3810.2 115.72,240.66 116.61,239.78 116.61,235.56 113.97,232.92 v2(107.95,232.92) ; PR5115.2 228.57,147.8 228.57,149.78 229.67,150.88 v2(229.96,150.88) ; PU5201.6 143.29,191.06 PC5202.1 142.29,192.1 142.29,198.04 v2(142.43,198.18) ; R2419.2 191.19,83.71 191.19,77.1 192.58,75.7 192.58,75.18 197.97,69.8 200.99,69.8 201.65,70.46 210.13,70.46 211.48,69.1 211.48,67.54 212.25,66.78 216.87,66.78 217.98,67.89 217.98,76.28 217.68,76.58 217.68,76.59 214.76,79.51 214.76,81.03 214.25,81.53 214.25,82.83 v2(212.1,84.98) ; PR5002.2 56.24,191.39 56.9,191.39 57.4,190.88 57.4,188.62 56.9,188.11 PR5001.1 55.11,187.69 v2(54.61,187.2) ; v2(132.74,202.23) 131.47,203.5 129.51,203.5 128.52,204.5 v2(128.52,217.69) ; PR4401.1 20.19,81.03 v2(11.96,81.03) ; R6413.1 13.49,229.34 20.45,222.38 20.45,220.22 ; 24.89,220.34 24.89,226.69 19.96,231.62 R6409.2
  BOTTOM w0.508: v2(229.96,150.88) 229.96,151.09 232.16,153.29 v2(235.62,153.29) ; v2(212.1,84.98) 214.19,87.06 v2(214.19,89.05) ; v3(91.69,232.92) v2(107.95,232.92) 123.18,217.69 v2(128.52,217.69) 129.65,217.69 130.56,216.79 159.68,216.79 162.48,214 172.97,214 175.51,216.53 213.61,216.53 v2(218.19,211.96) ; 95.38,15.49 98.93,11.94 98.93,4.95 99.44,4.45 113.41,4.45 115.32,2.54 169.27,2.54 170.66,3.94 218.42,3.94 232.09,17.61 232.09,23.43 235.46,26.8 235.46,84.07 233.04,86.49 233.04,90.17 233.68,90.81 233.68,93.71 233.04,94.34 v2(233.04,95) ; v2(221.36,212.85) 222.38,211.84 222.38,207.9 226.85,203.43 226.85,193.49 231.52,188.81 v2(231.52,185.06) ; v3(14.88,195.2) 14.86,195.17 14.86,190.42 15.75,189.53 23.57,189.53 25.27,187.83 25.27,185.8 27.43,183.64 35.18,183.64 39.62,188.09 53.72,188.09 v2(54.61,187.2) ; v2(142.43,198.18) 140.97,199.64 137.36,199.64 134.77,202.23 v2(132.74,202.23)
  BOTTOM w1.016: v3(111.51,17.27) 111.12,16.89 105.92,16.89 105.54,17.27 v3(94.61,17.27)
  vias: v1(11.84,197.89) v1(24.87,27.3) v1(61.26,27.36) v1(87.55,220.4) v3(13.72,204.72) v3(13.72,202.69) v3(13.72,200.79) v3(13.72,199.01) v3(13.72,197.1) v3(13.72,195.2) v3(13.97,208.41) v3(13.97,206.63) v3(14.88,204.72) v3(14.88,202.69) v3(14.88,200.79) v3(14.88,199.01) v3(14.88,197.1) v3(15.14,208.41) v3(15.14,206.63) v3(24.38,28.83) v3(25.4,28.83) v3(26.54,28.83) v3(78.11,232.79) v3(84.22,223.12) v3(84.28,218.69) v3(85.22,218.69) v3(85.47,223.14) v3(86.36,218.69) v3(86.74,223.14) v3(87.5,218.69) v3(88.04,223.14) v3(88.65,218.69) v3(93.34,17.4)
5V_USB_FRONT: length 22.4
  TOP w0.508: R3807.1 108.39,236.23 109.19,235.43 v2(109.19,235.28)
  TOP w1.016: 85.28,237.3 TC3801.1 ; TC3801.1 87.19,237.3 ; TC3801.1 87.19,239.21 ; TC3801.1 85.28,239.21
  BOTTOM w0.508: USB3F1.1 91.7,246.09 ; USB3F1.1 90.91,245.3 ; USB3F1.1 92.49,245.3 ; USB3F2.1 112.5,246.09 ; USB3F2.1 113.29,245.3 ; USB3F2.1 111.71,245.3 ; v2(109.19,235.28) 108.33,236.14 108.33,240.28 108.46,240.41
  BOTTOM w1.016: TC3801.1 87.19,237.3 ; TC3801.1 85.28,239.21 ; TC3801.1 87.19,239.21 ; TC3801.1 85.28,237.3
  vias: v1(92.13,236.47) v3(89.28,239.52) v3(90.3,238)
5V_USB_REAR: length 11.9
  TOP w0.508: USB2R1.1 107.02,12.24 ; USB2R1.1 105.16,12.24 ; USB2R1.1 106.09,11.31 ; USB2R1.1 106.09,13.17 ; 105.16,14.86 USB2R1.5 ; USB2R1.5 106.09,15.79 ; USB2R1.5 106.09,13.93
  TOP w1.016: TC3901.1 95.95,12.89 ; TC3901.1 94.04,10.98 ; TC3901.1 95.95,10.98 ; TC3901.1 94.04,12.89
5V_USB_RJ45: length 12.8
  TOP w0.508: 128,13.72 RJ45R1.5 ; RJ45R1.5 127.07,14.65 ; RJ45R1.5 128.93,14.65 ; RJ45R1.5 128,15.58 ; RJ45R1.1 128.93,12.03 ; RJ45R1.1 128,12.96 ; RJ45R1.1 127.07,12.03 ; RJ45R1.1 128,11.1
  TOP w1.016: 115.25,21.53 TC3201.1 ; TC3201.1 117.16,21.53 ; TC3201.1 117.16,23.43 ; TC3201.1 115.25,23.43
5V_VGA_CONN: length 31.1
  TOP w0.508: VGA1.9 58.46,3.11 58.45,3.1
  BOTTOM w0.508: v2(44.83,17.14) 49.02,21.34 v2(54.99,21.34)
  BOTTOM w0.762: v3(43.94,17.27) 43.94,16.51 v1(47.96,12.5) 49.66,10.79 49.66,5.79 v3(52.65,2.79)
12V_CPU: length 277.3
  TOP w0.305: PR4701.2 PR4702.2 PR4703.2 PR4704.2 PR4705.2 PR4706.2
  TOP w0.508: R2402.1 202.3,72.19 200.44,72.19 200.28,72.03 198.98,72.03 v2(198.88,72.14) ; PR4402.1 17.53,79.12 16.59,80.06 13.18,80.06 12.04,78.92 7.67,78.92 ; v2(101.98,23.52) 101.98,32.82 v2(103.17,34.01) ; 7.75,122.3 7.75,128.27 10.16,130.68 FANC1.2 13.15,133.67 R2601.1 ; 23.33,33.62 23.32,33.6 v2(23.32,26.59) ; R5920.1 v2(41.02,16.26)
  TOP w1.016: PT4506.1 81.69,47.18 ; PT4506.1 80.74,46.23 ; PT4506.1 82.64,46.23 ; PT4506.1 81.69,45.27 ; 20.41,36.27 ATX2.4 ; ATX2.4 21.76,37.62 ; ATX2.4 20.41,38.97 ; ATX2.4 19.06,37.62 ; 66.26,44.2 PT4501.1 ; PT4501.1 67.21,43.24 ; PT4501.1 67.21,45.15 ; PT4501.1 68.16,44.2 ; PT4601.1 10.54,106.46 ; PT4601.1 9.59,105.51 ; PT4601.1 10.54,104.56 ; PT4601.1 11.49,105.51 ; 19.06,41.82 ATX2.3 ; ATX2.3 21.76,41.82 ; ATX2.3 20.41,40.47 ; ATX2.3 20.41,43.17 ; 49.49,38.99 PT4504.1 ; PT4504.1 50.45,38.04 ; PT4504.1 50.45,39.94 ; PT4504.1 51.4,38.99
  BOTTOM w0.508: v2(41.02,16.26) 30.83,16.26 23.01,24.07 23.01,26.29 v2(23.32,26.59) ; v2(101.98,23.52) 111.02,23.52 113.15,25.65 123.06,25.65 123.67,26.26 128.37,26.26 128.7,26.59 140.43,26.59 142.13,24.89 146.69,24.89 150.5,21.08 157.48,21.08 158.37,20.19 159.14,20.19 160,21.05 163.64,21.05 164.77,19.92 176.93,19.92 177.76,19.09 185.51,19.09 188.93,22.51 188.93,24.74 189.43,25.25 189.43,41.52 189.03,41.93 189.03,68.23 191.13,70.33 192,70.33 194.66,72.99 198.02,72.99 v2(198.88,72.14) ; 103.17,34.82 v2(103.17,34.01)
  BOTTOM w1.016: 21.76,37.62 20.44,37.62 ; 20.44,37.62 21.56,36.5 ; 20.44,37.62 ATX2.4 ; PT4501.1 67.21,45.15 ; PT4501.1 67.21,43.24 ; PT4501.1 68.16,44.2 ; PT4501.1 66.26,44.2 ; ATX2.3 20.41,43.17 ; ATX2.3 20.41,40.47 ; ATX2.3 20.43,41.82 ; 50.45,38.04 PT4504.1 ; PT4504.1 49.49,38.99 ; PT4504.1 50.45,39.94 ; PT4504.1 51.4,38.99 ; 80.74,46.23 PT4506.1 ; PT4506.1 81.69,45.27 ; PT4506.1 82.64,46.23 ; PT4506.1 81.69,47.18 ; 21.44,42.82 20.43,41.82 ; 20.43,41.82 21.76,41.82 ; 20.41,36.27 ATX2.4 ; ATX2.4 20.41,38.97
  vias: v1(30.23,40.51) v1(31.11,34.8) v1(62.23,39.24) v1(73.91,46.99) v1(93.98,49.66) v1(105.92,42.93) v3(9.65,114.55) v3(9.65,113.41) v3(9.65,112.39) v3(9.65,111.25) v3(9.65,110.11) v3(9.65,109.09) v3(9.65,98.55) v3(9.65,97.41) v3(9.65,96.57) v3(9.65,95.38) v3(9.65,93.98) v3(9.91,118.36) v3(9.91,117.22) v3(9.91,116.2) v3(23.24,40.26) v3(23.24,39.37) v3(24.69,47.04) v3(24.69,45.77) v3(25.64,44.12) v3(25.7,46.46) v3(25.7,45.19) v3(30.15,43.13) v3(30.15,41.86) v3(30.15,36.02) v3(30.15,34.75) v3(30.33,38.61) v3(30.33,37.34) v3(33.58,38.81) v3(33.58,37.54) v3(36.07,40.89) v3(40.13,40.89) v3(42.65,38.81) v3(42.65,37.54) v3(44.58,40.89) v3(46.58,38.79) v3(46.58,37.52) v3(46.74,40.89) v3(48.46,36.58) v3(48.46,35.31) v3(52.83,42.67) v3(54.1,43.56) v3(55.5,43.56) v3(56.54,42.27) v3(56.54,41) v3(57,45.19) v3(59.94,46.1) v3(61.34,42.8) v3(61.34,41.53) v3(63.37,48.64) v3(64.01,45.9) v3(64.01,44.63) v3(64.77,48.64) v3(66.04,48.67) v3(67.51,48.74) v3(68.48,41.96) v3(68.48,40.69) v3(69.85,48.26) v3(71.88,48.9) v3(73.91,49.02) v3(76.07,49.28) v3(77.6,49.02) v3(78.54,46.91) v3(78.54,45.64) v3(78.74,49.02) v3(80.14,49.02) v3(80.52,43.99) v3(80.52,42.72) v3(83.72,44.63) v3(83.72,43.36) v3(84.84,49.4) v3(90.42,49.28) v3(92.25,48.95) v3(92.25,47.68) v3(95.96,49.78) v3(95.96,48.51) v3(97.46,48.36) v3(98.55,49.91) v3(99.44,51.18) v3(100.46,50.29) v3(102.36,50.29) v3(104.01,50.04) v3(105.28,38.63) v3(105.28,37.62) v3(106.38,39.42) v3(106.38,38.4) v3(106.38,37.39)
12V_DETECT: length 6.7
  TOP w0.102: R4214.1 175.65,218.24 R4212.2 174.15,219.74 174.15,219.85 v1(173.81,220.19) 173.59,220.41 C4216.1 R4217.1 Q4204.2
12V_DETECT_1: length 6.5
  TOP w0.102: Q4204.3 171.18,218.2 171.7,217.68 v1(173.81,217.68) 174.43,217.68 R4214.2 R4215.1 R4211.2
12V_DETECT_2: length 9.7
  TOP w0.102: Q4204.5 171.83,215.07 R4219.1 v1(171.89,214) 174.31,214 R4218.2 174.43,214.88 173.99,214.88 172.48,216.39 Q4204.6
12V_DETECT_DELAY: length 5.8
  TOP w0.102: Q4202.2 179.2,217.04 178.94,216.79 178.18,216.79 177.39,216 v1(176.73,216) 176.73,216.94 C4217.1 175.7,217.04 R4215.2
12V_S0: length 331.1
  TOP w0.508: SLOT3.A3 202.2,22.12 ; SLOT3.A3 201.4,21.32 ; SLOT3.A3 201.4,22.92 ; SLOT3.A3 200.6,22.12 ; SATAP2.1 181,227.03 ; SATAP2.1 181,224.85 ; SATAP2.1 179.91,225.94 ; SATAP2.1 182.09,225.94 ; R4203.1 101.79,211.96 109.73,211.96 122.1,224.33 129.74,224.33 131.5,222.58 137.74,222.58 137.79,222.63 ; 183.58,19.32 SLOT2.B1 ; SLOT2.B1 183.58,20.92 ; SLOT2.B1 182.78,20.12 ; SLOT2.B1 184.38,20.12 ; 179.08,20.32 SLOT2.A2 ; SLOT2.A2 178.28,21.12 ; SLOT2.A2 179.88,21.12 ; SLOT2.A2 179.08,21.92 ; 143,220.85 SATAP1.4 ; SATAP1.4 141.91,221.94 ; SATAP1.4 144.09,221.94 ; SATAP1.4 143,223.03 ; v2(147.96,10.54) 147.96,5.21 145.92,3.17 116.46,3.17 112.37,7.26 90.32,7.26 88.57,9.02 ; SLOT3.B2 206.7,21.12 ; SLOT3.B2 205.9,21.92 ; SLOT3.B2 205.1,21.12 ; SLOT3.B2 205.9,20.32 ; SLOT1.A2 159.56,21.12 ; SLOT1.A2 158.76,21.92 ; SLOT1.A2 158.76,20.32 ; SLOT1.A2 157.96,21.12 ; SLOT3.B3 204.7,22.12 ; SLOT3.B3 203.1,22.12 ; SLOT3.B3 203.9,21.32 ; SLOT3.B3 203.9,22.92 ; ATX3.6 211.25,223.45 ; ATX3.6 209.9,224.8 ; ATX3.6 208.55,223.45 ; ATX3.6 209.9,222.1 ; SATAP2.4 181,224.03 ; SATAP2.4 181,221.85 ; SATAP2.4 182.09,222.94 ; SATAP2.4 179.91,222.94 ; PR4808.1 130.01,85.89 131.7,84.2 132.94,84.2 139.78,77.36 139.78,69.84 144.7,64.92 v2(145.57,64.92) ; 141.91,224.94 SATAP1.1 ; SATAP1.1 143,226.03 ; SATAP1.1 143,223.85 ; SATAP1.1 144.09,224.94 ; Q9101.G 176.85,205.26 C9106.1 176.85,209.36 173.76,212.45 171.4,212.45 169.57,214.27 169.57,220.37 v2(170.05,220.85) ; SLOT1.A3 160.76,22.92 ; SLOT1.A3 161.56,22.12 ; SLOT1.A3 159.96,22.12 ; SLOT1.A3 160.76,21.32 ; SLOT2.A3 181.08,22.92 ; SLOT2.A3 181.88,22.12 ; SLOT2.A3 181.08,21.32 ; SLOT2.A3 180.28,22.12 ; 85.39,5.71 FANS1.2 ; FANS1.2 86.36,6.68 ; FANS1.2 87.33,5.71 ; FANS1.2 86.36,4.75 ; 205.7,222.1 ATX3.5 ; ATX3.5 204.35,223.45 ; ATX3.5 205.7,224.8 ; ATX3.5 207.05,223.45 ; SLOT2.B2 185.58,21.92 ; SLOT2.B2 186.38,21.12 ; SLOT2.B2 184.78,21.12 ; SLOT2.B2 185.58,20.32 ; 199.4,20.32 SLOT3.A2 ; SLOT3.A2 199.4,21.92 ; SLOT3.A2 200.2,21.12 ; SLOT3.A2 198.6,21.12 ; 163.26,21.32 SLOT1.B3 ; SLOT1.B3 162.46,22.12 ; SLOT1.B3 163.26,22.92 ; SLOT1.B3 164.06,22.12 ; SLOT2.B3 184.38,22.12 ; SLOT2.B3 183.58,21.32 ; SLOT2.B3 183.58,22.92 ; SLOT2.B3 182.78,22.12 ; 203.9,19.32 SLOT3.B1 ; SLOT3.B1 203.1,20.12 ; SLOT3.B1 203.9,20.92 ; SLOT3.B1 204.7,20.12 ; SLOT1.B1 163.26,20.92 ; SLOT1.B1 164.06,20.12 ; SLOT1.B1 162.46,20.12 ; SLOT1.B1 163.26,19.32 ; SLOT4.3 221.7,18.2 ; SLOT4.3 221.7,16.25 ; SLOT4.3 222.68,17.23 ; SLOT4.3 220.72,17.23 ; SLOT1.B2 165.26,21.92 ; SLOT1.B2 165.26,20.32 ; SLOT1.B2 164.46,21.12 ; SLOT1.B2 166.06,21.12 ; v2(170.81,31.75) 171.7,30.86 171.7,22.61 ; v2(158.37,15.41) 158.37,19.05
  L3 w0.508: ATX3.5 207.05,223.45 ; ATX3.5 205.7,224.8 ; ATX3.5 205.7,222.1 ; ATX3.5 204.35,223.45 ; 209.9,222.1 ATX3.6 ; ATX3.6 209.9,224.8 ; ATX3.6 211.25,223.45 ; ATX3.6 208.55,223.45
  BOTTOM w0.508: v2(170.81,31.75) 169.14,33.43 169.14,45.11 167.78,46.47 167.78,49.51 166.45,50.84 166.45,51.82 165.56,52.7 164.72,52.7 159.44,57.99 154.43,57.99 153.87,58.55 153.87,61.49 150.44,64.92 v2(145.57,64.92) ; v2(158.37,15.41) 153.63,10.67 148.08,10.67 v2(147.96,10.54)
  vias: v2(215.11,20.78) v2(215.65,21.59) v2(216.03,20.7) v2(216.87,21.08) v2(228.33,16.79) v2(228.42,15.54) v2(228.76,16.2) v2(228.85,17.53) v2(229.74,16.51) v2(230.84,17.4)
12V_S5: length 93.6
  TOP w0.508: v2(154.94,208.31) 154.81,208.18 R807.1 R804.1 ; 242.35,142.71 242.35,96.76 232.64,87.05 226.11,87.05 224.92,85.85 223.55,85.85 222.4,87 221.08,87 219.84,85.75 217.78,85.75 217.45,85.42 ; R2466.1 216.43,89.79 217.45,88.77 217.45,85.42 ; 217.45,85.42 217.45,83.55 R2467.1 ; v2(107.19,211.2) 106.02,210.03 104.7,210.03 103.67,209 R4206.1
  vias: v1(50.29,200.28) v1(54.61,195.28) v1(197.1,219.18) v1(224.46,219.15) v3(42.75,217.04) v3(43.74,217.09) v3(44.58,217.07) v3(45.49,217.07) v3(46.41,217.07) v3(47.27,217.07) v3(48.31,217.04) v3(48.26,201.93) v3(48.64,202.82) v3(49.15,201.93) v3(49.2,217.02) v3(49.78,202.82) v3(50.22,217) v3(50.16,201.93) v3(51.23,217) v3(52.27,217) v3(53.19,216.99) v3(54.04,196.67) v3(54.05,197.76) v3(54.99,197.74) v3(54.98,196.65) v3(188.09,213.87) v3(188.09,212.72) v3(189.23,213.87) v3(189.23,212.72) v3(190.25,213.87) v3(190.37,212.72) v3(191.39,213.87) v3(191.52,212.72) v3(191.77,219.2) v3(192.91,219.2) v3(194.18,219.2) v3(195.33,219.2) v3(224.74,220.62) v3(225.3,221.62) v3(225.68,220.47) v3(225.68,219.38)
12V_SYSATX_S5: length 41.8
  TOP w0.508: ATX3.1 205.7,230.3 ; ATX3.1 204.35,228.95 ; ATX3.1 207.05,228.95 ; ATX3.1 205.7,227.6 ; R4211.1 R4218.1 175.7,212.89 v2(175.92,212.67) ; D4201.A 196.72,224.41 190.75,224.41 186.82,220.47 186.82,213.56 v2(185.93,212.67) 185.42,213.18 185.42,214.08 184.91,214.59 R4208.1
  BOTTOM w0.508: v2(175.92,212.67) v2(185.93,212.67)
12VBDC_EN: length 6.5
  TOP w0.102: R4209.2 C4214.1 C4213.1 v1(197.87,216.6) 197.93,216.66 199.52,216.66 200.42,217.57 U4203.4
12VBDC_EN_1: length 15.4
  TOP w0.102: R4209.1 194.82,214.5 v1(194.78,214.46) 192.02,211.71 185.32,211.71 184.25,212.78 R4208.2 R4210.1
12VBDC_EN_2: length 6.9
  TOP w0.102: R4210.2 183.13,214.59 Q4203.G 184.12,216.28 181.24,216.28 v1(181.14,216.17) 181.12,216.15 180.13,216.15 Q4202.6
+12V_PG: length 3.8
  TOP w0.102: R4213.2 v2(181.67,218.44) 181.67,217.81 Q4203.D
  BOTTOM w0.102: v1(182.5,218.57) 181.8,218.57 v2(181.67,218.44)
+12V_PG_U29: length 5.3
  TOP w0.102: U4202.5 99.9,209.32 99.97,209.4 99.97,210.03 100.89,210.95 v1(102.23,210.95) 103.19,210.95 R4207.1
-12V_S0: length 7
  TOP w1.016: TC5301.2 208.65,7.35 ; TC5301.2 208.65,8.8 ; TC5301.2 207.2,8.8 ; TC5301.2 207.2,7.35
  BOTTOM w0.508: SLOT4.2 225.22,15.96 ; SLOT4.2 224.24,16.93 ; SLOT4.2 223.26,15.96
  vias: v1(212.85,15.49) v1(214.12,10.41) v3(212.34,13.59) v3(212.34,12.45) v3(212.34,11.3)
AGND: length 170.6
  TOP w0.305: v2(65.33,234.09) 65.15,234.27 65.15,234.28 64.87,234.56 64.87,235.29 64.86,235.3 U2701.26 ; v2(61.09,233.93) 61,233.93 60.36,234.57 U2701.35 ; v2(56.9,233.39) U2701.38
  TOP w0.356: Q3001.4 v2(19.83,28.05) ; v2(19.05,23.62) 18.53,24.14 Q3001.1
  TOP w0.508: 4.29,12.99 AUD1.G3 ; AUD1.G3 2.68,14.6 ; AUD1.G3 5.9,14.6 ; AUD1.G3 4.29,16.21 ; 16.37,12.99 AUD1.G4 ; AUD1.G4 17.98,14.6 ; AUD1.G4 16.37,16.21 ; C2707.2 55.82,235.39 C2706.2 54.48,235.46 v2(53.98,235.46) ; 64.99,252.5 HPMIC1.G1 ; HPMIC1.G1 66.81,252.5 ; HPMIC1.G1 65.9,251.28 ; HPMIC1.G1 65.9,253.72 ; HPMIC1.G2 76.01,251.5 ; HPMIC1.G2 75.1,250.28 ; HPMIC1.G2 75.1,252.72 ; AUD1.1 11.3,7.1 ; AUD1.1 10.33,8.07 ; AUD1.1 10.33,6.13 ; AUD1.1 9.36,7.1 ; v2(17.78,23.14) 17.78,22.99 17.97,22.8 R3009.2 ; 16.37,1.69 AUD1.G2 ; AUD1.G2 16.37,4.91 ; AUD1.G2 14.76,3.3 ; AUD1.G2 17.98,3.3 ; 9.08,11.13 AUD1.24 ; AUD1.24 9.08,13.07 ; AUD1.24 8.11,12.1 ; AUD1.24 10.05,12.1 ; C2710.2 73.53,231.98 73.53,231.93 v2(73.56,231.9) ; C3004.2 v2(10.22,21.72) ; R2713.2 v2(74.42,230.5) ; R2708.2 v2(51.69,234.24) ; R3003.2 11.18,21.31 v2(11.18,20.45) ; C3003.2 9.68,24.54 10.82,24.54 R3004.2 11.18,24.18 v2(11.18,23.46) ; 6.86,7.1 AUD1.4 ; AUD1.4 8.8,7.1 ; AUD1.4 7.83,8.07 ; AUD1.4 7.83,6.13 ; C3005.2 v2(19.68,20.32) ; HPMIC1.3 67.71,255.95 ; HPMIC1.3 66.8,254.73 ; HPMIC1.3 65.89,255.95 ; 8.11,17.1 AUD1.34 ; AUD1.34 9.08,18.07 ; AUD1.34 10.05,17.1 ; AUD1.34 9.08,16.13 ; 2.68,3.3 AUD1.G1 ; AUD1.G1 4.29,1.69 ; AUD1.G1 4.29,4.91 ; AUD1.G1 5.9,3.3 ; v2(16.95,28.02) C3010.2 17.02,28.89 R3016.2 ; 72.7,248.12 HPMIC1.5 72.7,245.68 ; R3007.2 v2(17.02,19.3)
  L3 w0.508: 16.37,12.99 AUD1.G4 ; AUD1.G4 16.37,16.21 ; AUD1.G4 17.98,14.6 ; AUD1.G4 14.76,14.6 ; 71.78,246.9 HPMIC1.5 ; HPMIC1.5 72.7,245.68 ; HPMIC1.5 72.7,248.12 ; AUD1.34 10.05,17.1 ; AUD1.34 9.08,18.07 ; AUD1.34 8.11,17.1 ; AUD1.34 9.08,16.13 ; 9.36,7.1 AUD1.1 ; AUD1.1 10.33,6.13 ; AUD1.1 11.3,7.1 ; AUD1.1 10.33,8.07 ; 16.37,1.69 AUD1.G2 ; AUD1.G2 16.37,4.91 ; AUD1.G2 14.76,3.3 ; AUD1.G2 17.98,3.3 ; 66.8,254.73 HPMIC1.3 ; HPMIC1.3 65.89,255.95 ; HPMIC1.3 67.71,255.95 ; HPMIC1.G1 66.81,252.5 ; HPMIC1.G1 64.99,252.5 ; HPMIC1.G1 65.9,251.28 ; HPMIC1.G1 65.9,253.72 ; AUD1.G1 4.29,4.91 ; AUD1.G1 2.68,3.3 ; AUD1.G1 4.29,1.69 ; AUD1.G1 5.9,3.3 ; 7.83,6.13 AUD1.4 ; AUD1.4 8.8,7.1 ; AUD1.4 7.83,8.07 ; AUD1.4 6.86,7.1 ; AUD1.24 9.08,13.07 ; AUD1.24 10.05,12.1 ; AUD1.24 9.08,11.13 ; AUD1.24 8.11,12.1 ; 2.68,14.6 AUD1.G3 ; AUD1.G3 4.29,16.21 ; AUD1.G3 5.9,14.6 ; AUD1.G3 4.29,12.99 ; HPMIC1.G2 76.01,251.5 ; HPMIC1.G2 75.1,252.72 ; HPMIC1.G2 74.19,251.5 ; HPMIC1.G2 75.1,250.28
  BOTTOM w0.508: AUD1.G1 4.29,4.91 ; AUD1.G1 5.9,3.3 ; AUD1.G1 4.29,1.69 ; AUD1.G1 2.68,3.3 ; 2.68,14.6 AUD1.G3 ; AUD1.G3 5.9,14.6 ; AUD1.G3 4.29,16.21 ; AUD1.G3 4.29,12.99 ; AUD1.G2 17.98,3.3 ; AUD1.G2 16.37,4.91 ; AUD1.G2 14.76,3.3 ; AUD1.G2 16.37,1.69 ; 8.11,17.1 AUD1.34 ; AUD1.34 9.08,16.13 ; AUD1.34 10.05,17.1 ; AUD1.34 9.08,18.07 ; AUD1.G4 17.98,14.6 ; AUD1.G4 16.37,16.21 ; AUD1.G4 16.37,12.99 ; AUD1.4 8.8,7.1 ; AUD1.4 7.83,8.07 ; AUD1.4 6.86,7.1 ; 9.36,7.1 AUD1.1 ; AUD1.1 11.3,7.1 ; AUD1.1 10.33,8.07 ; 8.11,12.1 AUD1.24 ; AUD1.24 9.08,11.13 ; AUD1.24 9.08,13.07 ; AUD1.24 10.05,12.1 ; R2705.2 v2(59.69,230.76)
  vias: v1(18.29,28.96) v1(18.54,21.21) v2(1.14,24.89) v2(1.27,21.21) v2(1.27,17.27) v2(2.9,16.39) v2(2.95,5.77) v2(3.05,12.4) v2(3.18,8.16) v2(4.55,9.45) v2(4.81,17.81) v2(5.84,24.38) v2(6.79,2.37) v2(7.09,5.18) v2(7.85,14.76) v2(7.88,9.3) v2(8.89,26.29) v2(9.02,20.32) v2(10.19,18.98) v2(10.44,15.04) v2(10.7,10.09) v2(11.56,19.81) v2(11.68,28.83) v2(11.81,29.78) v2(11.81,14.61) v2(12.22,9.22) v2(12.98,3.48) v2(13.59,5.34) v2(13.87,2.16) v2(14.28,9.43) v2(14.48,27.43) v2(16.31,11.33) v2(17.68,13.01) v2(19.62,17.27) v2(62.87,240) v2(63.25,247.9) v2(63.37,253.24) v2(63.37,245.24) v2(63.37,242.95) v2(63.75,251.46) v2(64.64,249.68) v2(65.15,245.36) v2(65.79,254.51) v2(67.56,250.7) v2(67.94,236.28) v2(68.02,239.34) v2(68.58,248.92) v2(68.64,245.17) v2(68.71,256.16) v2(68.71,254.13) v2(69.09,247.52) v2(69.98,252.48) v2(70.23,253.87) v2(70.61,245.24) v2(71.5,238.51) v2(71.75,256.16) v2(72.77,254) v2(72.77,250.95) v2(72.9,248.92) v2(74.42,241.26) v2(74.8,255.91) v2(75.5,237.24) v2(75.69,253.37) v2(75.8,238.66) v2(76.07,249.56) v2(76.71,243.97) v2(76.73,243.01) v2(77.09,252.73) v2(77.09,248.16) v2(77.09,246.63) v2(77.22,245.36)
GND: length 3403.7
  TOP w0.102: 190.14,138.3 190.49,138.3 190.7,138.51 191.19,138.51 SB1.C12 ; CPU1.AW38 v2(60.53,129.92) ; CPU1.AU39 60.28,127.73 59.21,128.8 v2(59.21,129.54) ; SB1.D8 191.7,136.78 190.46,136.78 SB1.A8 ; v2(59.7,129.06) 59.7,128.97 60.28,128.38 CPU1.AV39 ; CPU1.AU40 v2(58.79,128.01)
  TOP w0.127: v2(210.36,150.11) 210.99,150.11 211.12,149.97 SB1.BC35 ; SB1.D12 191.61,139.06 190.97,139.06 188.82,141.22 v2(188.82,141.29) 188.45,141.66 186.56,141.66 186.44,141.53 186.44,139.98 188.11,138.3 190.14,138.3 ; v2(213.16,140.61) 213.16,140.98 SB1.BG17 ; v2(200.41,159.69) 201.19,158.9 201.19,157.32 SB1.AD49
  TOP w0.152: v2(199.48,157.43) 200.02,156.89 SB1.AA49 ; SB1.E24 192.06,144.34 v2(192.06,143.87) SB1.E22 ; v2(215.65,149.02) 213.16,149.02 SB1.BG33 ; SB1.E19 192.06,142.15 v2(192.06,141.68) ; v2(203.76,157.13) 203.69,157.13 SB1.AG49 ; v2(205.81,132.72) 205.81,132.95 SB1.AM1 ; SB1.AD2 SB1.AD1 201.25,133.19 v2(201,132.93) ; SB1.AM49 206.55,157.79 v2(206.55,157.81) ; SB1.T5 197.9,134.91 SB1.T4 ; SB1.AG1 203.38,132.14 203.31,132.07 203.31,131.08 v2(203.38,131.01) ; v2(214.45,146.61) 214.38,146.68 SB1.BG28 ; v2(213.53,145.03) 213.5,145 SB1.BG25 212.76,145.25 211.62,145.25 v2(211.5,145.13) ; SB1.AR16 SB1.AN16 ; SB1.D12 191.81,138.7 SB1.C12 ; SB1.M24 195.87,144.81 195.74,144.94 v2(195.74,145) ; SB1.E17 v2(192.06,141.68) ; v2(192.06,141.68) SB1.D17 ; 197.14,134.81 SB1.R3 ; SB1.N38 195.8,151.44 195.7,151.55 ; SB1.BG22 213.01,142.97 v2(213.13,142.85) ; SB1.BC26 211.26,145.86 210.75,146.37 210.75,147.23 211.26,147.74 SB1.BC31 ; SB1.BG37 213.17,151.23 v2(213.59,151.23) ; SB1.C25 SB1.E26 ; SB1.A33 190.33,148.82 186.44,148.82 v2(186.06,148.44) ; v2(195.63,143.66) 195.8,143.5 SB1.M21 ; v2(189.84,145.95) 189.84,146.06 190.39,146.6 SB1.A28 190.39,146.82 190.79,147.22 191.43,147.22 SB1.C30 192.01,147.37 SB1.D30 ; SB1.J47 194.58,155.71 SB1.J48 ; SB1.BA6 SB1.BA5 209.57,134.95 209.47,134.87 v2(209.45,134.87) 209.41,134.87 209.35,134.94 SB1.AW4 ; v2(189.87,151.19) 189.88,151.21 190.25,151.21 SB1.A37
  TOP w0.203: U9501.124 200.05,65.02 v2(200.54,65.52) 200.85,65.22 U9501.122 ; PU5001.14 52.88,191.46 v2(52.96,191.39) ; PU5001.3 47.42,191.06 v2(46.86,190.5) ; SB1.BC45 211.03,154.56 v2(211.03,154.01) ; SB1.AT34 SB1.AR34 SB1.AN34 ; 196.37,92 196.37,92.28 196.18,92.47 U2401.82 ; 196.37,92 196.57,91.8 v2(196.57,91.44) 196.57,91.11 196.37,90.91 ; 196.37,92 196.3,92.07 U2401.83 ; 196.37,90.07 196.36,90.07 U2401.88 ; 196.37,90.07 196.37,89.6 196.04,89.27 U2401.90 ; 196.37,90.07 196.37,90.91 ; SB1.M34 195.61,149.5 v2(195.61,149.89) 195.64,149.92 SB1.N35 ; v2(209.81,153) 210.45,153 SB1.BB41 211.26,152.24 SB1.BC40 ; SB1.D8 192.13,136.59 SB1.E8 192.34,137.08 v2(192.1,137.32) 192.1,137.33 192.1,137.36 192.14,137.4 SB1.E10 192.53,138.22 192.53,138.82 SB1.E13 ; v2(193.74,99.2) 194.07,98.87 U2401.66 ; U9501.14 v2(198.18,57.49) ; v2(198.18,57.49) 197.78,57.89 U9501.13 ; v2(198.18,57.49) 197.78,57.09 U9501.15 ; SB1.AW10 208.86,137.74 SB1.AV11 208.05,137.92 207.67,138.3 v2(207.67,138.31) 207.67,138.32 207.67,138.35 207.47,138.56 SB1.AR12 ; U5901.24 64.21,20.17 v2(64.72,19.66) ; v2(211.03,154.01) 210.7,153.68 SB1.BB43 ; v2(211.03,154.01) 211.13,153.91 SB1.BD43 211.75,154.09 SB1.BE44 ; SB1.E19 192.43,142.52 192.43,143.31 SB1.E22 ; CPU1.AV2 96.05,127.42 95.59,126.97 v2(94.94,126.97) 94.94,127.6 95.4,128.05 CPU1.AW3 ; SB1.P4 196.26,134.94 v2(196.2,134.88) 196.16,134.88 195.9,135.14 SB1.M5 ; PU5001.1 48.36,192.3 v2(48.26,192.41) ; v2(210.92,61.99) 211.06,61.99 211.36,62.29 U9501.95 ; v2(206.76,135.51) 206.67,135.43 SB1.AP4 ; 202.63,151.68 202.63,154.52 202.28,154.88 SB1.AE46 ; 200.17,151.4 SB1.Y38 v2(198.98,151.4) 198.46,151.4 SB1.U38 ; v2(208.66,146.43) 207.62,146.43 ; 207.62,146.43 207.62,145.64 SB1.AT26 SB1.AT24 ; 207.62,146.43 207.62,146.99 SB1.AT29 ; SB1.AK4 204.91,134.94 204.99,134.86 v2(205,134.86) ; v2(207.82,99.06) 208.4,99.63 U2401.35 ; v2(201.72,134.87) 202.21,134.87 SB1.AE4 ; U4201.11 93.43,215.47 v2(93.53,215.37) ; v2(194.04,154.93) 194.04,154.54 193.62,154.13 SB1.G44 ; v2(194.04,154.93) 194.4,154.93 SB1.J46 ; v2(194.04,154.93) 194.04,155.17 SB1.J47 ; U9501.6 v2(198.21,60.69) 198.21,61.37 197.69,61.89 U9501.3 ; SB1.E33 192.34,148.6 192.06,148.32 ; SB1.AW46 209.04,155.06 209.35,154.75 209.35,154.48 v2(209.37,154.46) 209.57,154.46 SB1.BA44 ; U9501.113 204.45,65.22 204.76,65.53 v2(205.03,65.53) 205.04,65.53 205.25,65.33 U9501.111 ; v2(61.29,9.47) 61.11,9.65 v2(61.11,11.05) 61.11,12.24 60.83,12.52 v2(60.83,12.7) 60.9,12.76 60.9,13.91 61.59,14.61 v2(61.59,14.99) ; U9501.42 202.05,47.82 v2(202.45,47.42) ; v2(198.42,155.11) 198.87,155.11 SB1.V46 ; U9501.60 209.25,49.58 v2(208.81,50.01) 208.45,49.65 U9501.58 ; SB1.R4 197.14,134.81 ; SB1.AL12 205.41,138.58 v2(205.51,138.48) 205.59,138.48 205.66,138.56 SB1.AN12 ; SB1.U38 197.37,151.42 SB1.R38 197.28,151.52 196.33,151.52 SB1.N38 ; SB1.U38 198.09,151.06 198.09,150.13 SB1.R34 SB1.N34 196.33,149.35 v2(195.78,148.8) SB1.M32 ; 192.06,148.32 191.89,148.5 SB1.D33 ; 192.06,148.32 192.06,147.85 SB1.E31 192.49,147.78 192.66,147.94 192.95,147.94 193.12,147.78 193.67,147.78 194.25,147.2 SB1.J29 194.28,146.68 194.2,146.6 v2(194.2,146.58) 194.2,146.56 194.35,146.42 SB1.J26 ; SB1.AC4 200.3,134.94 SB1.AA5 ; SB1.T49 197.83,156.89 v2(197.49,157.23) ; U9501.22 v2(198.25,54.29) ; SB1.AE38 SB1.AC38 200.46,151.33 ; v2(198.8,102.11) U2401.59 ; U2401.17 209.73,93.26 v2(209.52,93.47) 209.72,93.66 U2401.18 ; v2(210.32,142.87) 210.35,142.87 210.35,142.87 210.64,142.87 211.26,142.25 SB1.BC19 ; SB1.C48 191.59,156.46 192.25,156.46 SB1.F47 ; SB1.E17 192.34,140.77 SB1.D16 192.14,140.49 SB1.E15 192.14,139.21 SB1.E13 ; U2401.40 206.4,102.13 206.42,102.15 v2(206.41,102.15) ; SB1.N12 195.86,138.56 195.32,138.02 v2(195.32,137.92) SB1.K11 194.37,137.92 SB1.J10 194.19,137.24 SB1.J9 194.12,136.79 SB1.H8 193.8,136.18 SB1.G6 193.56,135.87 193.67,135.76 194,135.76 v2(194.07,135.69) 194.18,135.58 194.18,135.25 194.49,134.94 SB1.J4 ; SB1.AT45 207.46,154.86 207.17,155.15 v2(207.17,155.18) 207.11,155.18 206.99,155.06 SB1.AP46 ; v2(207.72,132.27) 207.72,132.81 207.83,132.92 207.83,133.16 SB1.AT1 ; U2401.1 211.96,86.87 v2(212.33,87.24) 211.9,87.67 U2401.3 ; v2(195.15,149.1) 194.54,149.1 193.85,149.78 192.71,149.78 192.52,149.97 SB1.E35 ; v2(210.89,65.46) 210.85,65.42 U9501.97 ; SB1.AH17 203.87,140.82 v2(204.29,140.82) 204.91,140.82 SB1.AL17 ; SB1.BA12 209.83,138.95 209.43,139.36 ; C9520.2 204.91,47.41 204.45,47.88 U9501.48 ; U9501.79 211.19,55.89 v2(211.07,56.01) ; SB1.K39 195.24,151.56 195.59,151.56 195.61,151.55 195.7,151.55 ; SB1.Y9 199.69,137.27 SB1.Y10 ; v2(197.36,137.29) 197.86,136.79 SB1.T7 ; C9519.2 199.65,46.77 U9501.36 ; SB1.E13 192.13,138.79 SB1.D12 ; CPU1.AV38 61.2,128.06 61.66,127.61 v2(61.66,126.99) ; 196.37,90.91 196.33,90.87 U2401.86 ; 209.43,139.36 209.04,139.75 208.3,139.75 v2(208.18,139.87) 207.64,140.4 SB1.AT16 SB1.AR16 ; 209.43,139.36 SB1.BA14 ; v2(218.19,164.21) 218.19,163.26 214.69,159.77 v2(213.61,159.77) ; SB1.AK46 204.17,154.75 204.1,154.75 203.78,154.43 v2(203.66,154.43) ; U9501.73 211.32,53.49 v2(211.09,53.25) ; SB1.AL38 205.03,151.42 205.2,151.59 v2(205.46,151.59) ; SB1.M49 195.6,156.82 195.6,157.84 v2(195.45,157.99) ; SB1.AN16 206.09,141.03 SB1.AM18 ; v2(204.83,83.72) 204.8,83.72 U2401.117 ; v2(197.84,138.35) 197.84,138.36 198.07,138.58 SB1.U12 ; SB1.AW40 208.86,152.26 SB1.AV39 208.17,152.08 v2(208.05,152.2) 208.05,152.14 207.67,151.76 207.46,151.76 SB1.AR38 ; CPU1.V1 97.26,109.11 97.94,109.11 98.3,109.47 98.3,109.73 v2(98.31,109.74)
  TOP w0.254: SB1.V22 198.59,143.45 SB1.U21 ; v2(196.47,143.64) 197.05,143.64 ; 197.05,143.64 197.32,143.37 197.74,143.37 SB1.U21 ; 197.05,143.64 197.2,143.64 197.98,144.42 SB1.U24 ; SB1.V20 198.43,142.68 SB1.U21 ; v2(200.16,190.7) 200.21,190.75 NGFF1.13 ; SB1.AJ20 204.03,142.68 v2(204.41,142.29) ; SB1.BC15 211.16,140.13 v2(210.62,140.13) ; v2(199.74,145.39) 200.13,145.77 SB1.AA27 ; v2(199.74,145.39) 199.38,145.75 SB1.W27 ; v2(199.74,145.39) 199.38,145.02 SB1.W25 ; v2(199.74,145.39) 200.13,145 SB1.AA25 ; C1804.2 215.71,163.83 R2331.2 215.71,163.83 215.71,163.01 213.87,161.16 v2(213.74,161.16) ; SB1.AD22 SB1.AF22 202.85,143.83 ; SB1.AK19 204.8,141.91 v2(204.41,142.29) ; C1802.2 200.75,127.94 200.75,126.28 199.99,125.51 X1801.2 198.95,124.66 196.77,124.66 196.39,125.04 196.39,125.5 ; SB1.AD25 201.7,145.01 v2(201.31,145.4) 200.93,145.02 SB1.AB25 ; 204.4,145.4 204.03,145.77 SB1.AJ27 v2(203.64,146.16) ; 204.4,145.4 204.78,145.77 SB1.AK27 204.99,145.58 SB1.AL26 ; 204.4,145.4 204.02,145.02 SB1.AJ25 ; 204.4,145.4 204.8,145.01 SB1.AK25 205.29,144.51 SB1.AL24 ; 202.85,143.83 SB1.AG23 v2(203.63,144.6) 203.6,144.6 203.25,144.96 SB1.AG25 ; 202.85,143.83 203.23,143.45 SB1.AG22 ; v2(213.5,156.67) 213.31,156.87 212.72,156.87 SB1.BF49 SB1.BF48 SB1.BG48 ; SB1.C48 190.91,156.37 SB1.B48 190.83,156.37 190.48,156.37 SB1.A48 ; SB1.AC4 201.19,134.87 v2(201.72,134.87) ; SB1.A48 SB1.B49 ; SB1.A48 SB1.A47 SB1.A46 ; SB1.R12 197.64,138.56 v2(197.84,138.35) ; SB1.AH12 203.64,138.67 SB1.AE12 201.76,138.67 v2(201.72,138.63) 201.68,138.67 SB1.AC12 201.05,138.6 SB1.Y12 ; v2(199.75,146.93) SB1.AA30 200.17,147.32 200.53,146.96 v2(200.53,146.94) ; v2(199.75,146.93) 199.38,147.3 SB1.W30 ; v2(199.75,146.93) SB1.W28 ; v2(199.75,146.93) 200.13,146.55 SB1.AA28 ; SB1.BC24 211.46,144.62 211.46,145.09 v2(211.5,145.13) 211.26,145.37 SB1.BC26 ; SB1.AT18 207.77,141.59 207.77,140.78 SB1.AT16 ; v2(133.4,43.38) 132.83,43.95 X3101.4 ; SB1.V46 199.21,154.78 199.24,154.78 199.28,154.74 199.31,154.74 199.72,154.33 200.39,154.33 SB1.AC46 ; v2(97.87,114.62) CPU1.AD1 ; SB1.A46 SB1.B47 ; SB1.A46 SB1.A45 ; X1801.4 197.29,127.33 C1801.2 ; v2(210.89,137.41) 211.06,137.25 SB1.BC8 ; v2(210.89,137.41) 210.89,137.46 SB1.BC10 211.26,137.87 210.94,138.18 210.94,138.89 SB1.BC13 ; v2(210.89,137.41) 210.47,136.99 SB1.BB9 ; SB1.AJ19 v2(204.41,142.29) ; v2(204.41,142.29) 204.8,142.67 SB1.AK20 205.11,142.99 SB1.AL21 ; SB1.U12 198.46,138.6 SB1.Y12 ; SB1.AG30 SB1.AG28 ; SB1.AG28 SB1.AF28 ; SB1.AG28 v2(203.64,146.16) ; v2(63.5,13.69) 64.01,14.2 v2(64.01,14.86) ; CPU1.AF1 97.83,116.45 97.95,116.33 v2(98.02,116.33) ; SB1.AN38 205.91,151.59 v2(205.46,151.59) ; SB1.AA20 200.15,142.67 v2(200.52,142.29) 200.15,141.92 SB1.AA19 ; SB1.AF25 SB1.AG25 ; SB1.AG25 SB1.AG27 v2(203.64,146.16) ; v2(196.3,154.78) 196.31,154.78 196.59,155.06 SB1.P46 ; SB1.AJ30 SB1.AJ28 ; SB1.AJ28 v2(203.64,146.16) ; SB1.AJ28 SB1.AK28 204.81,146.55 SB1.AL29 204.97,147.32 SB1.AK30 SB1.AK31 SB1.AJ31 ; CPU1.AT15 CPU1.AR16 ; SB1.Y12 SB1.Y10 ; CPU1.E9 89.47,96.81 89.47,96.11 89.39,96.03
  TOP w0.279: NGFF2.57 149.61,137.18 v2(149.58,137.21)
  TOP w0.305: CPU1.AR16 81.31,125.6 CPU1.AR17 ; U2701.1 v2(59.18,226.9) ; v2(203.33,176.02) 203.44,176.14 U9101.16 ; NGFF2.51 148.11,137.13 v2(148.08,137.15) ; v2(67.14,125.98) 67.52,125.6 CPU1.AR31 ; v2(67.14,125.98) 66.75,125.6 CPU1.AR32 ; v2(67.14,125.98) 67.6,126.45 CPU1.AT31 ; v2(173.36,219.46) 173.17,219.46 172.73,219.02 Q4204.1 ; CPU1.AD38 v2(60.74,115.99) CPU1.AD39 ; PU4510.6 75.54,54.97 v2(75.51,54.94) ; PU4602.6 12.83,84 v2(12.58,84.25) ; v2(203.3,197.25) NGFF1.39 ; v2(155.47,132.3) 153.7,132.3 153.11,132.89 NGFF2.71 ; NGFF1.57 v2(200.54,201.75) ; PU4506.6 56.62,52.2 v2(56.52,52.1) ; v2(95.86,109.59) CPU1.W3 ; CPU1.AT13 84.14,126.6 84.89,126.6 CPU1.AT12 ; v2(134.37,133.35) 134.87,133.35 135.61,134.09 ; v2(155.04,132.9) 153.91,132.9 153.61,133.21 NGFF2.73 ; NGFF2.39 v2(145.11,136.83) ; CPU1.C24 76.16,95.42 v2(75.7,94.96) ; Q802.4 124.1,123.08 124.43,122.75 124.43,121.2 v2(124.33,121.1) ; 135.61,134.09 NGFF2.1 ; 135.61,134.09 136.11,134.59 NGFF2.3 ; NGFF2.15 139.11,136.66 v2(138.94,136.82) ; v2(199.67,198.93) 199.85,198.75 NGFF1.45 ; Q2401.1 205.91,73.58 206.27,73.23 206.27,72.7 206.69,72.28 Q2401.4 ; HDMI1.5 v2(30.45,8.26) ; SB1.AT21 208.18,143.56 209.63,143.56 v2(210.32,142.87) ; v2(75.7,93.13) 76.16,93.59 CPU1.A24 ; v2(213.31,76.71) 213.28,76.73 212.88,76.73 212.57,77.04 U2402.2 ; 228.79,181.89 228.82,181.92 U2002.4 ; NGFF2.27 142.11,134.12 142.62,133.6 143.89,133.6 ; U9101.23 207.24,175.03 v2(207.39,174.88) ; CPU1.AC3 95.4,113.73 v2(94.94,114.19) ; U2405.3 213.14,68.44 v2(212.65,67.95) ; HDMI1.2 v2(31.95,8.26) ; CPU1.AC34 v2(65.31,115.08) ; v2(140.61,136.88) NGFF2.21 ; v2(200.41,192.41) 200.71,192.41 200.86,192.25 NGFF1.19 ; v2(75.7,94.04) 76.16,94.51 CPU1.B24 ; v2(155.47,133.5) 155.42,133.5 155.4,133.53 154.44,133.53 154.11,133.86 NGFF2.75 ; 76.75,121.94 CPU1.AL21 ; R4219.2 171.18,215.19 Q4204.4 ; CPU1.AA3 96.04,111.88 v2(96.04,111.88) ; HDMI1.11 v2(27.45,8.26) ; PU4502.9 39.37,47.2 PU4502.6 ; CPU1.AB39 60.28,113.6 v2(59.62,112.94) ; 143.89,133.6 143.61,133.88 NGFF2.33 ; 143.89,133.6 v2(145.16,133.6) ; v2(203.5,205.32) 202.57,206.25 NGFF1.75 200.41,206.25 v2(200.36,206.3) ; NGFF1.18 v2(207.49,192) ; v2(70.8,121.48) CPU1.AK27 ; v2(148.34,134.09) 146.96,134.09 146.61,134.44 NGFF2.45 ; NGFF1.7 v2(203.33,189.25) ; NGFF1.69 200.44,204.75 v2(200.4,204.8) ; v2(18.29,127.18) 18.21,127.1 17.5,127.1 17.09,126.69 PU4605.6 ; HDMI1.17 v2(24.45,11.94) ; NGFF2.9 v2(137.61,136.91) ; NGFF1.63 v2(200.44,203.25) ; NGFF1.33 203.24,195.75 v2(203.53,196.04) ; HDMI1.8 v2(28.95,8.26)
  TOP w0.33: CPU1.AF40 v2(58.72,117.37)
  TOP w0.356: CPU1.AN1 97.57,122.85 v2(97.89,122.85) ; CPU1.C22 78.03,94.83 v2(78.13,94.73) ; v2(86.36,92.98) 86.36,93.09 86.26,93.19 CPU1.A13 ; v2(72.67,127.88) 72.63,127.88 72.36,128.15 CPU1.AV26 ; v2(85.43,126.05) 85.21,126.26 85.21,126.27 CPU1.AT12 ; CPU1.AM40 59.06,122.85 v2(58.7,122.85) ; CPU1.AM27 71.36,122.95 71.36,123.67 CPU1.AN27 71.02,124 70.99,124 v2(70.76,124.22) 70.99,124.45 71.02,124.45 CPU1.AP27 71.36,124.78 71.36,125.5 CPU1.AR27 71.35,125.69 71.35,126.42 CPU1.AT27 71.06,126.71 v2(70.76,126.97) 70.51,126.71 70.34,126.54 CPU1.AT28 ; CPU1.AN11 86.1,123.55 v2(86.34,123.31) CPU1.AM11 ; CPU1.AN23 75.16,123.53 v2(75.37,123.31) CPU1.AN22 ; CPU1.AT39 60.52,126.72 v2(60.74,126.94) ; v2(82.15,94.96) 81.69,95.42 CPU1.C18 ; EU3802.8 EU3802.3 v2(104.65,237.48) ; Q2408.4 214.05,84.99 v2(213.56,84.99) ; CPU1.AP11 v2(86.34,125.14) 86.1,125.38 CPU1.AR11 ; CPU1.C12 87.18,95.42 v2(87.65,94.95) ; CPU1.AP40 59.06,124.68 v2(58.72,124.68) ; v2(61.7,98.61) 61.7,98.58 CPU1.E37 62.11,98.16 v2(61.68,97.72) ; CPU1.C16 83.51,95.42 v2(83.98,94.96) ; CPU1.AT25 72.83,126.76 72.83,126.77 v2(72.67,126.97) 72.63,126.97 CPU1.AT26 ; v2(79.92,126.05) 79.69,125.81 79.69,125.79 CPU1.AR18 ; v2(79.92,126.05) 80.15,126.27 80.16,126.27 CPU1.AT17 ; v2(79.92,126.05) 80.15,125.83 80.39,125.6 CPU1.AR17 ; v2(77.2,121.48) 76.95,121.73 76.95,121.74 76.75,121.94 ; v2(80.14,94.87) 79.86,95.15 CPU1.C20 ; v2(97.94,101.78) 97.87,101.78 97.82,101.82 CPU1.K1 ; CPU1.AG1 97.28,117.37 97.37,117.28 98.6,117.28 98.61,117.29 v2(98.72,117.29) ; v2(68.51,130.83) 68.51,130.49 CPU1.AY30 68.51,129.65 CPU1.AW30 68.51,128.71 CPU1.AV30 68.32,128.12 68.14,127.94 v2(68.05,127.94) 68.05,127.92 68.32,127.64 CPU1.AU30 ; v2(98.03,103.49) 97.88,103.65 CPU1.M1 ; CPU1.AK36 63.02,121.02 62.81,121.23 v2(62.57,121.46) 62.59,121.48 62.59,121.5 CPU1.AL36 ; v2(177.8,215.6) 178.07,215.87 Q4202.4 ; CPU1.AV28 v2(69.91,127.88) ; CPU1.C10 89,95.64 89.39,96.03 ; v2(76.31,126.05) 76.54,125.81 76.74,125.61 CPU1.AR21 ; CPU1.H12 87.12,99.99 v2(86.67,100.44) ; CPU1.A17 82.6,93.27 v2(82.3,92.96) ; CPU1.T1 97.84,107.31 v2(97.9,107.37) ; CPU1.AF36 62.84,117.56 v2(62.57,117.82) ; U6305.S 216.94,178.72 217.13,178.52 v2(217.13,178.07) 217.2,178.07 218.28,176.99 Q6301.1 ; v2(98.52,26.04) 97.69,26.04 97.33,25.68 U4005.2 ; v2(85.8,94.96) CPU1.C14 ; CPU1.AY27 71.26,130.84 v2(71.25,130.85) ; v2(97.95,121.02) CPU1.AL1 ; U4801.1 134.68,88.53 135.25,87.96 135.25,87.55 135.58,87.23 U4801.4 136.24,87.23 v2(136.86,86.61) ; CPU1.AL11 v2(86.34,122.4) ; CPU1.AJ24 CPU1.AK25 ; CPU1.AD40 59.06,115.54 58.69,115.54 v2(58.67,115.52) ; v2(91.29,94.96) CPU1.C8 ; v2(62.55,118.77) 62.36,118.96 CPU1.AH37 CPU1.AH38 ; v2(75.37,120.57) 75.13,120.81 75.13,120.81 CPU1.AK23 ; CPU1.F36 CPU1.E35 ; v2(95.86,117.82) 96.11,117.58 CPU1.AG2 ; v2(97.85,119.19) 97.84,119.2 CPU1.AJ1 ; EU3801.8 v2(94.23,240) ; CPU1.AW36 63.03,129.81 v2(62.93,129.91) ; CPU1.AR24 v2(73.54,125.14) 73.79,124.9 CPU1.AP24 v2(73.54,124.22) 73.77,123.99 CPU1.AN24 ; CPU1.AV5 v2(94.03,127.88) 93.77,128.14 CPU1.AW5 ; v2(92.2,95.88) CPU1.D7 ; CPU1.AL2 95.88,121.46 v2(95.86,121.46) 95.83,121.46 CPU1.AL3 ; v2(98.06,105.48) CPU1.P1 ; v2(93.57,129.91) CPU1.AY5 ; CPU1.AT40 59.03,126.51 v2(58.71,126.51) ; v2(83.94,93.1) CPU1.A15 ; v2(21.33,21.78) 21.47,21.78 21.83,21.43 Q5601.1 ; CPU1.AR19 78.35,125.82 78.34,125.82 v2(78.09,126.05) 77.85,125.8 77.85,125.79 CPU1.AR20 ; CPU1.AH40 59.01,119.2 v2(58.68,119.2) ; CPU1.H11 v2(87.61,99.51) ; v2(91.74,129.91) CPU1.AY7 ; v2(66.68,129.87) 66.68,129.55 CPU1.AW32 ; v2(216.75,86.11) 216.69,86.11 216.68,86.11 Q2408.1 ; v2(58.7,121.02) 59.08,121.02 CPU1.AK40 ; Q4002.1 v2(149.54,202.47) ; U401.4 v2(11.57,188.35) ; v2(82.69,122.4) CPU1.AM14 ; Q4002.4 v2(147.56,199.51) ; CPU1.AR1 97.54,124.68 v2(97.89,124.68) ; v2(97.87,99.99) 97.54,99.99 97.23,99.99 CPU1.H1 ; U4301.2 215.21,219.07 215.04,218.9 215.04,218.66 215.27,218.42 U4301.3 v2(215.85,217.68) ; v2(97.92,98.16) CPU1.F1 ; CPU1.H9 v2(90.35,100.43) ; v2(88.09,92.96) CPU1.A11 ; Q6301.4 219.9,178.31 220.26,177.95 v2(220.41,177.95) ; CPU1.AT14 CPU1.AT13 ; CPU1.AL21 v2(76.29,121.48) CPU1.AK22 ; v2(61.66,121.46) 61.91,121.22 62.1,121.02 CPU1.AK37 ; CPU1.AN36 v2(62.57,123.34) ; U401.1 v2(9.56,185.39) ; CPU1.AY9 v2(89.47,128.81)
  TOP w0.381: v2(90.37,115.99) CPU1.AE8 ; CPU1.M7 v2(92.2,104.11) CPU1.N6 ; v2(92.2,126.97) CPU1.AU7 CPU1.AT6 ; v2(90.37,115.08) CPU1.AD8 ; CPU1.AR30 CPU1.AT30 ; CPU1.AT10 89,125.57 v2(88.57,125.14) ; CPU1.AM39 v2(60.73,123.34) CPU1.AM38 ; CPU1.L6 v2(92.2,102.28) CPU1.K7 ; v2(79,123.31) 78.57,123.74 CPU1.AN19 ; v2(65.31,115.08) CPU1.AC33 v2(66.23,115.08) ; v2(197.29,129.43) 197.29,130.32 197.87,130.9 197.87,130.91 197.91,130.95 199.59,130.95 200.03,130.52 200.03,129.42 v2(199.97,129.36) ; CPU1.U6 v2(92.2,107.77) ; CPU1.R3 v2(94.94,105.94) CPU1.P4 ; CPU1.AN14 83.12,123.77 82.66,124.23 v2(82.66,124.27) 82.66,124.27 82.97,124.58 83.05,124.58 CPU1.AP14 ; CPU1.AD36 v2(62.57,115.99) ; CPU1.AR22 75.85,125.6 ; 75.85,125.6 75.85,125.67 76.24,126.05 v2(76.31,126.05) ; 75.85,125.6 75.8,125.54 74.97,125.54 CPU1.AR23 ; CPU1.AT36 v2(62.57,126.99) CPU1.AT37 v2(61.66,126.99) CPU1.AT38 v2(60.74,126.94) ; v2(94.01,94.96) 93.57,95.4 CPU1.C5 ; CPU1.AT9 90.37,126.05 ; v2(213.31,76.71) 213.42,76.71 213.8,76.33 U2403.3 ; v2(90.18,106.39) CPU1.R8 ; CPU1.B6 v2(92.2,94.05) CPU1.A7 ; v2(90.37,116.91) CPU1.AF8 ; CPU1.D39 v2(59.83,96.79) ; CPU1.D40 59.29,97.25 v2(58.86,96.82) ; CPU1.AT34 CPU1.AU34 v2(64.42,127.88) CPU1.AV34 CPU1.AW34 64.86,129.81 v2(64.75,129.91) ; C2113.2 v2(203.89,128.12) ; CPU1.AU25 v2(72.67,127.88) ; v2(90.17,109.14) CPU1.V8 ; CPU1.AM30 v2(68.06,122.4) ; CPU1.AT32 66.29,126.14 66.24,126.14 66.23,126.13 v2(66.23,126.13) 66.23,126.08 CPU1.AR33 ; CPU1.H4 v2(94.94,100.45) CPU1.J3 ; v2(91.29,117.82) CPU1.AH8 ; v2(61.18,18.88) 61.18,18.79 60.76,18.37 R5913.2 ; v2(63.5,119.66) CPU1.AJ35 ; R5914.2 62.68,18.79 v2(62.87,18.97) ; v2(92.2,115.08) CPU1.AD6 ; CPU1.T4 v2(94.94,107.77) CPU1.U3 ; CPU1.AN30 v2(68.97,124.22) CPU1.AP30 ; v2(61.66,115.99) CPU1.AD37 ; CPU1.N3 v2(94.94,104.11) CPU1.M4 ; CPU1.K4 v2(94.94,102.28) CPU1.L3 ; CPU1.AH39 CPU1.AH40 ; CPU1.A4 v2(94.99,93.09) ; v2(91.29,116.91) CPU1.AG8 ; CPU1.AE33 v2(65.31,115.99)
  TOP w0.406: CPU1.AT25 73.14,126.45 73.94,126.45 CPU1.AT24 ; v2(68.99,120.58) 68.92,120.52 68.88,120.51 68.55,120.18 68.53,120.13 CPU1.AJ30 ; v2(85.81,102.29) 86.25,102.74 CPU1.L13 ; CPU1.W6 v2(93.12,110.51) ; CPU1.F10 89,98.15 v2(88.54,97.69) ; U4202.1 101.72,208.67 101.98,208.41 v2(101.98,208.28) ; CPU1.AJ8 90.83,119.22 v2(90.35,119.69) 89.94,120.11 CPU1.AK9 ; v2(20.7,243.46) 21.19,242.97 U6402.4 22.58,242.97 22.99,242.55 22.99,242.07 23.39,241.67 U6402.1 ; U4202.4 v2(98,209.97) ; v2(69.89,126.97) CPU1.AT29 69.16,126.78 68.78,126.78 CPU1.AT30 ; CPU1.AW9 89.96,128.3 89.96,128.25 90.29,127.92 90.36,127.92 v2(90.4,127.87) 89.95,127.42 CPU1.AV9 ; CPU1.AR14 CPU1.AP14 ; CPU1.L11 v2(88.54,103.19) CPU1.M10 ; CPU1.F40 58.24,97.95 58.24,97.64 v2(58.24,97.64) ; CPU1.AT11 v2(85.43,126.05) ; U2602.3 v2(90.34,16.91) ; CPU1.E21 v2(78.49,96.79) ; U4009.3 v2(80.51,25.27) ; EU5603.3 EU5603.8 24.26,12.13 v2(24.45,11.94) ; U6401.1 27.07,242.43 26.7,242.06 26.17,242.06 25.77,241.66 U6401.4 25.77,241.03 25.78,241.02 25.78,238.02 26.54,237.26 v2(26.8,237.26) ; U4008.2 90.68,24.39 v2(90.3,24) ; v2(90.28,112.38) 90.78,111.88 CPU1.AA8 ; 126.49,121.16 125.87,121.78 Q802.1 ; CPU1.E19 v2(80.31,96.79) ; v2(205.03,74.32) 205.03,74.32 205.38,73.98 Q2401.1 ; CPU1.AT8 90.37,126.05 v2(90.37,126.11) ; U4001.3 191.21,173.7 v2(191.24,173.67) ; CPU1.AL30 v2(68.06,121.48) ; v2(19.3,229.84) 19.15,229.84 18.15,230.85 18.15,232.33 Q6401.4 ; v2(155.88,18.54) 155.7,18.54 155.51,18.73 C4005.2 ; v2(93.12,96.79) 92.66,97.25 CPU1.E6 ; CPU1.G17 v2(82.14,98.62) ; U4004.3 v2(153.07,36.89) ; U2404.4 213.31,73.29 v2(212.98,73.62) ; CPU1.M12 v2(86.72,103.19) ; v2(223.25,180.85) 223.45,180.64 224.43,180.64 224.74,180.95 U2003.2 ; U2001.2 221.62,184.02 221.63,184.04 221.63,184.61 C2002.2 ; v2(91.32,104.07) CPU1.N8 ; v2(153.78,31.15) U4006.3 ; CPU1.J6 v2(92.2,100.45) ; CPU1.E13 v2(85.8,96.79) ; Q6401.1 15.44,235.64 v2(15.35,235.72) ; CPU1.G15 v2(83.95,98.6) ; EU5601.3 EU5601.8 31.75,12.5 v2(31.5,12.24) ; CPU1.AG36 v2(62.57,117.82) ; U4010.3 v2(143.67,202.25) ; v2(28.19,12.33) EU5602.8 EU5602.3 ; CPU1.G13 v2(85.8,98.62) ; CPU1.F4 v2(94.94,98.62) CPU1.G3 ; Q3801.4 v2(110.06,239.52) ; U4007.3 v2(153.07,23.05) ; CPU1.R6 v2(92.2,105.94) ; CPU1.E15 v2(83.99,96.81)
  TOP w0.432: CPU1.D30 70.5,96.13 70.22,95.87 v2(70.21,95.87) ; v2(64.4,114.17) 64.17,114.39 CPU1.AC35 ; v2(88.54,123.34) 88.77,123.11 88.77,123.09 CPU1.AN10 v2(89.42,122.43) ; CPU1.F10 88.09,99.08 CPU1.G11 ; CPU1.K28 72.33,101.62 72.05,101.36 v2(72.04,101.36) ; CPU1.AN4 94.72,123.08 v2(94.94,123.34) ; CPU1.G22 v2(78.49,99.54) ; CPU1.AM17 80.63,122.62 v2(80.86,122.4) ; CPU1.M15 84.22,103.45 83.94,103.19 v2(83.93,103.19) ; CPU1.AK29 v2(68.99,120.58) ; CPU1.AR2 96.12,124.88 v2(95.86,125.14) CPU1.AR3 ; CPU1.M35 63.74,104.78 v2(63.48,105.05) ; v2(64.37,101.36) 64.64,101.62 CPU1.J34 ; CPU1.G19 80.75,99.08 v2(80.3,98.62) ; v2(78.11,120.57) 77.89,120.79 77.89,120.79 CPU1.AK20 ; CPU1.V37 62.1,110.05 v2(61.65,110.5) ; CPU1.E17 82.59,97.25 v2(82.15,96.81) ; v2(74.79,103.19) 74.8,103.19 75.07,103.45 CPU1.M25 ; CPU1.B28 72.33,94.31 72.05,94.04 v2(72.04,94.04) ; CPU1.AK7 91.98,119.88 91.98,119.88 v2(92.2,119.65) ; CPU1.AJ5 v2(94.03,119.65) 93.8,119.89 93.79,119.89 CPU1.AK5 ; CPU1.AN5 93.76,123.04 93.76,123.05 v2(94.03,123.34) 93.81,123.55 93.79,123.55 CPU1.AP5 ; CPU1.AM5 93.79,121.72 93.79,121.71 v2(94.03,121.46) 93.78,121.22 93.77,121.22 CPU1.AL5 ; CPU1.AR5 v2(94.03,125.14) 93.8,125.37 CPU1.AT5 ; v2(64.4,123.34) 64.63,123.09 CPU1.AM34 ; v2(63.5,110.5) 63.94,110.06 CPU1.V35 ; CPU1.AJ4 v2(94.94,119.65) ; CPU1.H37 61.91,101.12 61.65,101.4 v2(61.65,101.41) ; v2(81.77,120.57) 81.53,120.81 CPU1.AK16 ; v2(61.66,117.82) 61.91,117.57 CPU1.AF37 ; CPU1.AL27 v2(70.8,121.48) ; v2(90.37,102.28) CPU1.L9 ; v2(65.31,115.99) 65.54,115.77 CPU1.AD33 ; v2(83.6,121.48) 83.37,121.71 CPU1.AL14 v2(83.6,122.4) CPU1.AM14 ; v2(75.7,101.36) 75.71,101.36 75.99,101.62 CPU1.K24 ; v2(63.48,103.22) 63.74,102.95 CPU1.K35 ; CPU1.AE5 93.96,115.93 94.01,115.93 v2(94.02,115.93) 94.01,115.94 94.01,116.02 CPU1.AF5 ; v2(79,123.31) 78.57,122.88 CPU1.AM19 v2(78.11,122.4) ; v2(62.57,123.34) 62.83,123.08 CPU1.AM36 ; CPU1.AR36 v2(62.57,125.14) 62.83,124.88 CPU1.AP36 ; CPU1.J32 66.47,101.62 v2(66.2,101.36) ; v2(70.21,99.53) 70.22,99.53 70.5,99.79 CPU1.H30 ; CPU1.B26 74.16,94.31 73.88,94.04 v2(73.87,94.04) ; CPU1.AD4 94.92,114.19 v2(94.94,114.19) ; CPU1.M23 76.9,103.45 76.62,103.19 v2(76.61,103.19) ; v2(72.96,103.19) 72.97,103.19 73.24,103.45 CPU1.M27 ; v2(72.04,99.53) 72.05,99.53 72.33,99.79 CPU1.H28 ; CPU1.J20 79.84,100.91 v2(79.38,100.44) 78.94,100.01 CPU1.H21 ; CPU1.E23 v2(77.55,97.69) ; CPU1.K30 70.5,101.62 70.22,101.36 v2(70.21,101.36) ; CPU1.K26 74.16,101.62 73.88,101.36 v2(73.87,101.36) ; v2(68.06,97.66) 68.06,97.67 67.8,97.95 CPU1.E31 ; v2(65.31,116.91) CPU1.AF33 ; CPU1.AN16 v2(81.77,124.22) ; v2(77.53,101.36) 77.54,101.36 77.82,101.62 CPU1.K22 ; v2(78.44,103.19) 78.45,103.19 78.73,103.45 CPU1.M21 ; CPU1.AK19 78.83,120.77 78.83,120.77 v2(79.03,120.57) ; v2(61.66,106.88) 61.91,106.61 CPU1.P37 ; CPU1.D28 72.33,96.13 72.05,95.87 v2(72.04,95.87) ; v2(94.97,117.82) 94.7,117.57 94.69,117.57 CPU1.AG4 ; v2(65.31,105.96) 65.57,105.69 CPU1.N33 ; CPU1.Y35 63.94,111.89 v2(63.5,112.33) ; v2(73.87,97.7) 73.88,97.7 74.16,97.96 CPU1.F26 ; CPU1.AN6 92.2,123.31 v2(92.2,123.34) ; v2(66.23,119.65) CPU1.AJ32 ; CPU1.M17 82.39,103.45 82.11,103.19 v2(82.1,103.19) ; v2(83.07,100.46) 83.51,100.9 CPU1.J16 ; CPU1.AK15 82.47,120.78 v2(82.69,120.57) ; v2(81.24,102.29) 80.77,101.82 CPU1.K19 ; v2(94.03,116.98) 93.96,116.98 CPU1.AG5 93.36,117.58 93.14,117.8 v2(93.14,117.85) ; v2(63.46,100.45) 63.73,100.71 CPU1.H35 ; CPU1.AG3 v2(95.86,117.82) ; CPU1.AJ31 67.21,119.72 v2(67.21,119.39) ; v2(75.7,95.87) 75.71,95.87 75.99,96.13 CPU1.D24 ; v2(85.81,102.29) 85.34,101.82 CPU1.K14 ; v2(65.31,118.74) CPU1.AH33 ; CPU1.H24 75.99,99.79 75.71,99.53 v2(75.7,99.53) ; CPU1.Y37 62.11,111.89 v2(61.68,112.33) ; v2(65.33,113.24) 65.77,112.81 CPU1.AA33 ; v2(94.94,121.46) 94.92,121.46 CPU1.AL4 ; CPU1.E11 88.53,97.69 v2(88.54,97.69) ; CPU1.K17 82.6,101.82 v2(83.07,102.29) ; CPU1.AD7 v2(92.2,115.08) ; CPU1.R33 65.57,107.52 v2(65.31,107.79) ; CPU1.AM33 v2(66.23,123.34) ; v2(70.21,94.04) 70.22,94.04 70.5,94.31 CPU1.B30 ; v2(92.2,120.57) 92.49,120.28 92.49,120.28 CPU1.AK6 92.89,119.88 v2(93.12,119.65) ; v2(71.13,103.19) 71.14,103.19 71.41,103.45 CPU1.M29 ; v2(65.31,119.65) CPU1.AJ33 ; v2(66.23,97.66) 66.23,97.67 65.97,97.95 CPU1.E33 ; CPU1.C33 65.97,96.12 66.23,95.85 v2(66.23,95.84) ; CPU1.AP37 61.91,124.88 v2(61.66,125.14) ; v2(68.06,122.4) 67.85,122.6 CPU1.AM31 ; CPU1.AK26 v2(71.73,120.58) ; v2(91.29,119.65) 91.03,119.91 CPU1.AK8 ; v2(61.66,105.05) 61.91,104.78 CPU1.M37 ; CPU1.G33 65.56,99.79 v2(65.29,99.54) ; CPU1.AC6 92.87,113.5 CPU1.AB5 94.02,112.35 v2(94.02,112.32) ; CPU1.AH5 v2(94.03,118.74) ; CPU1.T35 63.94,108.23 v2(63.5,108.67) ; v2(95.85,96.81) 95.7,96.95 CPU1.E3 ; v2(65.33,109.59) 65.77,109.15 CPU1.U33 ; v2(73.87,99.53) 73.88,99.53 74.16,99.79 CPU1.H26 ; v2(90.37,96.79) CPU1.E9 ; CPU1.H39 59.86,101.33 v2(59.85,101.33) ; v2(80.27,103.19) 80.28,103.19 80.56,103.45 CPU1.M19 ; v2(84.52,120.57) 84.31,120.77 CPU1.AK13 ; v2(65.29,102.28) 65.56,102.53 CPU1.K33 ; CPU1.AM37 61.88,123.09 v2(61.65,123.34) ; v2(91.29,123.34) 91.55,123.06 91.55,123.04 CPU1.AN7 ; v2(95.86,115.11) 95.58,115.37 95.57,115.37 CPU1.AE3 ; v2(73.54,122.4) CPU1.AM24 ; CPU1.E35 64.14,97.95 64.4,97.67 v2(64.4,97.66) ; v2(65.31,117.82) CPU1.AG33 ; v2(59.83,103.22) 60.08,102.95 CPU1.K39 ; CPU1.P35 63.74,106.61 v2(63.48,106.88) ; v2(70.21,97.7) 70.22,97.7 70.5,97.96 CPU1.F30 ; CPU1.AR35 64.34,125.2 v2(64.34,125.16) 64.42,125.16 CPU1.AR34 ; CPU1.AU4 94.29,126.71 94.03,126.96 v2(94.03,126.97) 94.03,126.97 CPU1.AU5 ; v2(59.83,105.05) 60.08,104.78 CPU1.M39 ; CPU1.F7 v2(92.2,98.62) CPU1.G6 ; v2(64.4,95.84) 64.4,95.85 64.14,96.12 CPU1.C35 ; v2(89.46,123.34) 89.7,123.08 89.7,123.07 CPU1.AN9 ; CPU1.AK18 79.69,120.82 v2(79.94,120.57) ; v2(85.43,120.57) 85.23,120.77 CPU1.AK12 ; v2(84.9,102.29) 84.43,101.82 CPU1.K15 ; CPU1.D4 94.49,96.31 v2(94.92,95.87) ; CPU1.K37 61.91,102.95 v2(61.66,103.22) ; CPU1.AK30 68.34,121.2 v2(68.06,121.48) ; v2(77.57,98.62) CPU1.F22 ; v2(62.57,115.99) CPU1.AE36 ; CPU1.AR4 v2(94.94,125.14) ; v2(73.54,121.48) CPU1.AL24 ; CPU1.AK28 v2(69.9,120.58) ; v2(68.06,95.84) 68.06,95.85 67.8,96.12 CPU1.C31 ; v2(65.33,111.41) 65.77,110.98 CPU1.W33 ; CPU1.AM35 63.74,123.07 v2(63.48,123.34) ; CPU1.V39 59.87,110.46 59.87,110.47 v2(59.82,110.53) ; v2(86.72,101.36) CPU1.J12 ; CPU1.AM32 v2(67.14,123.34) ; v2(73.87,95.87) 73.88,95.87 74.16,96.13 CPU1.D26 ; v2(93.12,110.51) CPU1.Y5 ; v2(81.22,100.43) 81.69,100.9 CPU1.J18 ; v2(88.54,101.36) CPU1.J10 ; CPU1.AT7 v2(91.29,125.14) ; v2(90.37,123.34) 90.61,123.08 90.61,123.07 CPU1.AN8 ; CPU1.F28 72.33,97.96 72.05,97.7 v2(72.04,97.7) ; CPU1.P39 60.08,106.61 v2(59.83,106.88) ; v2(61.68,108.67) 62.11,108.23 CPU1.T37 ; v2(59.85,108.67) 60.28,108.23 CPU1.T39 ; v2(80.86,120.57) 80.64,120.78 80.64,120.78 CPU1.AK17 ; CPU1.G31 67.8,99.78 68.06,99.5 v2(68.06,99.49) ; CPU1.L32 66.47,103.45 v2(66.2,103.19) ; v2(64.4,119.65) CPU1.AJ34 ; CPU1.C37 62.14,96.34 v2(62.57,96.77) 62.31,97.04 CPU1.D37 61.68,97.69 v2(61.68,97.72) ; CPU1.AH36 62.8,119.41 v2(62.57,119.63) CPU1.AJ36 ; v2(92.2,100.45) CPU1.H7 ; CPU1.AK25 v2(72.65,120.58)
  TOP w0.457: PC4804.2 126.87,90.37 v2(125.5,90.37) ; v2(93.12,123.34) 93.12,123.31 CPU1.AN6
  TOP w0.508: DIMM2.46 58.31,178.45 ; DIMM2.46 59.05,177.71 ; DIMM2.46 58.31,176.97 ; DIMM2.46 57.57,177.71 ; USB3F2.10 116.42,247.3 ; USB3F2.10 115.4,249.07 ; USB3F2.10 115.4,245.53 ; USB3F2.10 114.38,247.3 ; 125.57,177.71 DIMM2.120 ; DIMM2.120 126.31,178.45 ; DIMM2.120 127.05,177.71 ; DIMM2.120 126.31,176.97 ; VGA1.6 VGA1.7 ; VGA1.6 65.66,4.5 v2(65.66,5.41) v2(65.66,7.87) v2(65.66,9.14) v2(65.66,10.29) v2(65.66,11.56) ; VGA1.6 65.32,3.19 ; VGA1.6 66.3,4.17 ; VGA1.7 VGA1.8 ; VGA1.7 v2(63.03,5.44) v2(63.03,6.83) 63.25,7.04 v2(63.25,8.48) v2(63.25,9.53) 63.47,9.75 v2(63.47,11.01) 63.3,11.01 63.05,11.25 EU5901.2 ; DIMM2.263 125.46,180.65 ; DIMM2.263 124.72,179.91 ; DIMM2.263 125.46,179.17 ; DIMM2.263 126.2,179.91 ; DIMM2.15 32.7,176.11 ; DIMM2.15 31.96,176.85 ; DIMM2.15 31.96,175.37 ; DIMM2.15 31.22,176.11 ; VGA1.17 74.4,4.17 ; VGA1.17 72.35,6.23 ; VGA1.17 72.35,2.11 ; VGA1.17 70.29,4.17 ; DIMM2.250 115.15,181.51 ; DIMM2.250 114.41,180.77 ; DIMM2.250 113.67,181.51 ; R6301.1 224.08,176.06 224.08,176.94 ; C3301.2 v2(43.81,228.6) ; C1005.2 v2(75.95,83.19) ; DIMM2.53 65,176.11 ; DIMM2.53 63.52,176.11 ; DIMM2.53 64.26,176.85 ; DIMM2.53 64.26,175.37 ; PC4916.2 v2(31.57,184.84) ; 121.32,179.91 DIMM2.259 ; DIMM2.259 122.06,180.65 ; DIMM2.259 122.8,179.91 ; DIMM2.259 122.06,179.17 ; DIMM2.22 38.65,177.71 ; DIMM2.22 37.91,178.45 ; DIMM2.22 37.91,176.97 ; DIMM2.22 37.17,177.71 ; RJ45R1.23 123.76,6.69 ; RJ45R1.23 120.54,6.69 ; RJ45R1.23 122.15,8.3 ; RJ45R1.23 122.15,5.08 ; C3102.2 v2(148.21,38.73) ; 27.82,176.11 DIMM2.11 ; DIMM2.11 28.56,175.37 ; DIMM2.11 28.56,176.85 ; DIMM2.11 29.3,176.11 ; 54.17,177.71 DIMM2.42 ; DIMM2.42 54.91,178.45 ; DIMM2.42 55.65,177.71 ; DIMM2.42 54.91,176.97 ; 139.91,176.97 DIMM2.136 ; DIMM2.136 139.91,178.45 ; DIMM2.136 140.65,177.71 ; DIMM2.136 139.17,177.71 ; USB3F1.10 95.62,247.3 ; USB3F1.10 94.6,249.07 ; USB3F1.10 93.58,247.3 ; 22.61,176.97 DIMM2.4 ; DIMM2.4 21.87,177.71 ; DIMM2.4 22.61,178.45 ; DIMM2.4 23.35,177.71 ; DIMM2.118 125.35,177.71 ; DIMM2.118 124.61,178.45 ; DIMM2.118 123.87,177.71 ; DIMM2.118 124.61,176.97 ; DIMM2.162 34.51,182.25 ; DIMM2.162 35.25,181.51 ; DIMM2.162 34.51,180.77 ; DIMM2.162 33.77,181.51 ; 41.31,176.97 DIMM2.26 ; DIMM2.26 42.05,177.71 ; DIMM2.26 41.31,178.45 ; DIMM2.26 40.57,177.71 ; C3112.2 135.13,45.59 134.62,46.1 134.62,46.2 v2(134.6,46.23) 134.62,46.23 135.08,46.69 C3104.2 135.13,47.04 v2(135.13,47.75) C3117.2 135.33,48.84 136.2,48.84 C3113.2 ; v2(70.51,224.71) 70.65,224.85 C2717.2 R2704.2 ; C4306.2 219.07,217.17 v2(218.95,217.3) 219.2,217.55 C4305.2 ; C5612.2 v2(42.16,8.38) ; U3801.2 v2(86.61,232.92) ; CPU1.B38 60.58,94.8 v2(60.58,94.63) ; C2004.2 228.79,181.41 v2(228.79,181.94) ; C4308.2 C4309.2 210.14,218.05 213.23,221.14 213.23,221.74 ; C5906.2 v2(54.48,16.13) ; R2056.2 216.55,131.94 C2109.2 v2(215.47,132) ; R1611.2 R1609.2 R1610.2 189.05,128.73 v2(188.31,128.74) ; 111.97,181.51 DIMM2.248 ; DIMM2.248 112.71,180.77 ; DIMM2.248 113.45,181.51 ; C3807.2 R3813.1 113.47,236.73 v2(113.09,236.73) ; v3(139.4,53.9) 141.71,53.9 ; R2058.2 215.52,139.36 215.07,139.81 214.41,139.81 v2(214.41,139.8) ; 68.51,180.77 DIMM2.202 ; DIMM2.202 68.51,182.25 ; DIMM2.202 69.25,181.51 ; PC4805.2 132.27,93.79 132.33,93.73 v2(132.38,93.73) ; C9517.2 v2(191.67,59.79) ; v2(110.43,24.69) UC3203.2 110.36,23.81 U3201.2 ; Q4001.E v2(152.62,201.64) ; v2(43.69,83.82) 42.09,82.22 PC1043.2 ; 43.01,176.97 DIMM2.28 ; DIMM2.28 43.01,178.45 ; DIMM2.28 42.27,177.71 ; DIMM2.28 43.75,177.71 ; 130.56,175.37 DIMM2.125 ; DIMM2.125 129.82,176.11 ; DIMM2.125 130.56,176.85 ; DIMM2.125 131.3,176.11 ; C2721.2 81.83,234.51 v2(82.12,234.21) 82.09,234.19 C2722.2 ; U2501.4 184.85,197.18 v2(184.9,197.13) U2502.10 ; 131.52,176.11 DIMM2.127 ; DIMM2.127 132.26,175.37 ; DIMM2.127 133,176.11 ; DIMM2.127 132.26,176.85 ; PC4701.2 117.04,39.9 v2(116.51,39.37) ; v2(21.34,231.79) 20.85,232.28 C6402.2 ; C4010.2 R4023.2 149.48,199.69 v2(149.56,199.77) ; v2(57.02,28.57) 56.76,28.84 R5909.2 ; PR4961.2 37.34,188.59 v2(37.85,189.1) 37.34,189.61 PC4918.2 ; v2(14.35,82.04) 13.08,82.04 13.08,82.48 12.58,82.98 v2(12.58,84.25) 12.58,85.86 v2(12.95,86.23) ; C9312.2 208.34,28.77 v2(207.77,28.19) ; C2426.2 R2472.2 v2(214.86,91.82) ; C1103.2 151.87,184.78 v2(151.63,185.03) ; C402.2 v2(128.65,76.26) ; APS1.10 v2(225.4,105.77) 224.4,106.77 APS1.11 ; 214.1,222.1 ATX3.7 ; ATX3.7 214.1,224.8 ; ATX3.7 212.75,223.45 ; ATX3.7 215.45,223.45 ; PC5107.2 225.83,129.41 v2(227.33,129.41) ; v2(197.29,129.43) 197.29,128.6 C1801.2 ; C4006.2 92,27.31 92,27.3 v2(92.15,27.3) ; v2(97.89,126.51) 97.51,126.51 CPU1.AU1 ; R3812.2 108.99,237.08 v2(109.04,236.91) ; VGA1.16 49.41,4.17 ; VGA1.16 47.35,6.23 ; VGA1.16 47.35,2.11 ; VGA1.16 45.3,4.17 ; 122.91,176.97 DIMM2.116 ; DIMM2.116 122.17,177.71 ; DIMM2.116 122.91,178.45 ; DIMM2.116 123.65,177.71 ; C1210.2 v2(22.42,183.26) ; v2(187.71,167.31) 187.43,167.59 C2126.2 ; 33.95,253.53 SD1.13 ; v2(220.83,164.13) 220.93,164.03 R2052.2 ; 48.96,175.37 DIMM2.35 ; DIMM2.35 48.22,176.11 ; DIMM2.35 49.7,176.11 ; DIMM2.35 48.96,176.85 ; DIMM2.180 50.55,181.51 ; DIMM2.180 49.81,180.77 ; DIMM2.180 49.07,181.51 ; DIMM2.180 49.81,182.25 ; v2(56.69,189.36) 56.58,189.25 55.86,189.25 PC5001.2 ; 17.4,185.39 v2(17.4,186.31) ; UC3201.2 v2(145.26,18.44) ; RJ45R1.26 139.68,9.32 ; RJ45R1.26 138.07,7.71 ; RJ45R1.26 136.46,9.32 ; v2(31.89,198.3) 31.55,197.95 PC4917.2 ; v2(88.35,120.63) 88.87,120.11 CPU1.AK10 ; C2416.2 205.25,105.26 v2(205.82,105.26) ; DIMM2.154 27.71,182.25 ; DIMM2.154 27.71,180.77 ; DIMM2.154 28.45,181.51 ; DIMM2.154 26.97,181.51 ; VGA1.8 60.75,6.9 v2(60.78,6.93) ; VGA1.8 60.02,4.17 58.91,5.27 58.91,5.27 58.5,5.69 v2(58.5,7.49) 58.5,8.08 v2(59.82,9.4) ; R2049.2 218.62,183.88 R2047.1 218.63,184.67 219.15,185.19 v2(219.76,185.19) ; v2(128.32,64.52) 128.35,64.52 129.11,63.75 R415.2 ; 135.77,181.51 DIMM2.276 ; DIMM2.276 137.25,181.51 ; DIMM2.276 136.51,180.77 ; 141.72,176.11 DIMM2.139 ; DIMM2.139 142.46,175.37 ; DIMM2.139 142.46,176.85 ; R4219.2 v2(170.23,215.01) ; HDMI1.20 35.2,11.18 ; HDMI1.20 36.27,9.36 ; HDMI1.20 34.13,9.36 ; R5913.2 60.76,17.35 C5916.2 60.29,17.31 C5923.2 59.47,16.24 59.42,16.2 59.42,13.77 C5919.2 ; R1206.2 v2(19.43,185.55) ; DIMM2.167 38.76,180.65 ; DIMM2.167 38.76,179.17 ; DIMM2.167 39.5,179.91 ; DIMM2.167 38.02,179.91 ; SD1.12 61.45,253.51 61.47,253.49 ; v2(196.72,215.75) 196.7,215.75 196.66,215.71 C4214.2 ; C6206.2 134.11,139.05 C6213.2 C6205.2 134.43,135.48 NGFF2.76 v2(133.33,135.4) ; PR5111.2 v2(234.36,157.86) ; v2(14.1,102.11) 15.05,101.16 PR4468.2 ; VGA1.5 56,6.15 ; VGA1.5 55.02,5.17 ; VGA1.5 54.04,6.15 ; VGA1.5 55.02,7.13 ; C9512.2 194.93,68.26 C9511.2 C9510.2 C9509.2 194.93,64.76 v2(195.28,64.41) ; DIMM2.44 56.61,178.45 ; DIMM2.44 56.61,176.97 ; DIMM2.44 55.87,177.71 ; DIMM2.44 57.35,177.71 ; C2407.2 R2416.2 203.52,106.97 v2(203.5,106.98) 202.7,106.98 R2406.2 R2410.2 ; v2(223.44,185.52) 223.74,185.23 C2005.2 ; v2(75.29,23.27) C4008.2 C4007.2 ; v2(205.03,74.32) 204.12,74.32 203.71,73.91 R2408.2 ; R2417.2 199.2,75.95 v2(198.75,75.95) ; v2(167.89,26.54) 168.48,25.96 C9403.2 ; v2(48.77,225.41) 48.77,225.23 Q2703.C ; C2417.2 213.78,101.54 v2(214,101.75) ; C2003.2 223.7,187.3 v2(223.19,186.79) ; DIMM2.107 116,176.11 ; DIMM2.107 115.26,175.37 ; DIMM2.107 115.26,176.85 ; DIMM2.107 114.52,176.11 ; 47.37,181.51 DIMM2.178 ; DIMM2.178 48.85,181.51 ; DIMM2.178 48.11,182.25 ; DIMM2.178 48.11,180.77 ; v2(49.28,232.54) 50.04,233.3 R2708.1 ; 43.12,179.91 DIMM2.173 ; DIMM2.173 44.6,179.91 ; DIMM2.173 43.86,180.65 ; DIMM2.173 43.86,179.17 ; C5908.2 66.34,27.85 v2(65.96,28.22) ; 32.92,176.11 DIMM2.17 33.66,176.85 ; v2(220.9,133.17) 220.93,133.17 220.89,133.21 220.89,133.25 220.34,133.72 R2055.2 ; C2413.2 198.93,106.2 v2(199.77,105.36) 199.59,105.18 R2442.2 ; C2405.2 C2415.2 v2(216.15,92.9) ; DIMM2.50 61.71,178.45 ; DIMM2.50 62.45,177.71 ; DIMM2.50 61.71,176.97 ; DIMM2.50 60.97,177.71 ; C9310.2 v2(190.25,24.51) ; v2(215.01,130.68) 215.13,130.68 215.84,129.98 C2115.2 C2114.2 216.85,128.91 R2320.2 216.92,128.3 215.44,126.82 214.7,126.82 C2108.2 214.63,127.3 v2(213.61,128.32) 213.61,128.4 213.36,128.65 R1514.2 R1512.2 ; R2057.2 v2(219.05,153.75) ; v2(27.23,186.54) 27.18,186.54 26.61,187.11 PR4953.2 ; 28.67,181.51 DIMM2.156 ; DIMM2.156 29.41,180.77 ; DIMM2.156 30.15,181.51 ; DIMM2.156 29.41,182.25 ; 128.12,176.11 DIMM2.123 ; DIMM2.123 128.86,175.37 ; DIMM2.123 128.86,176.85 ; DIMM2.123 129.6,176.11 ; v2(79.5,226.95) 80.2,227.65 Q2702.C ; C1021.2 v2(81.05,83.08) ; 23.46,179.17 DIMM2.149 ; DIMM2.149 22.72,179.91 ; DIMM2.149 23.46,180.65 ; DIMM2.149 24.2,179.91 ; C2410.2 212.24,73.62 v2(212.98,73.62) ; PC4706.2 122.81,37.08 v3(122.92,36.97) ; v2(204.34,158.17) 204.42,158.24 C1701.2 ; v2(56.08,11.33) EU5902.2 ; R6408.2 222.33,152.45 v2(222.53,152.65) ; C2406.2 v2(212.33,87.24) ; C4209.2 v2(91.52,209.85) ; DIMM2.265 127.16,180.65 ; DIMM2.265 127.16,179.17 ; DIMM2.265 126.42,179.91 ; DIMM2.265 127.9,179.91 ; HS1902.2 220.95,124.64 ; HS1902.2 219.05,124.64 ; HS1902.2 220,125.59 ; HS1902.2 220,123.69 ; Q4301.E v2(218.41,215.77) ; 61.82,179.91 DIMM2.195 ; DIMM2.195 62.56,180.65 ; DIMM2.195 63.3,179.91 ; DIMM2.195 62.56,179.17 ; DIMM2.182 52.25,181.51 ; DIMM2.182 51.51,182.25 ; DIMM2.182 51.51,180.77 ; DIMM2.182 50.77,181.51 ; v2(130.63,31.52) EU3202.2 ; 81.8,245.53 USB3F1.11 ; USB3F1.11 81.8,249.07 ; USB3F1.11 82.82,247.3 ; USB3F1.11 80.78,247.3 ; 134.81,180.77 DIMM2.274 ; DIMM2.274 134.07,181.51 ; DIMM2.274 135.55,181.51 ; SATAP2.3 187,227.03 ; SATAP2.3 187,224.85 ; SATAP2.3 185.91,225.94 ; SATAP2.3 188.09,225.94 ; 111.86,175.37 DIMM2.103 ; DIMM2.103 111.12,176.11 ; DIMM2.103 111.86,176.85 ; DIMM2.103 112.6,176.11 ; D2701.2 77.47,233.68 v2(78.11,234.31) ; DIMM2.147 21.76,180.65 ; DIMM2.147 22.5,179.91 ; DIMM2.147 21.02,179.91 ; DIMM2.147 21.76,179.17 ; 123.76,179.17 DIMM2.261 ; DIMM2.261 124.5,179.91 ; DIMM2.261 123.76,180.65 ; DIMM2.261 123.02,179.91 ; 35.2,1.99 HDMI1.22 ; HDMI1.22 34.13,3.4 ; HDMI1.22 36.27,3.4 ; PC4506.2 59.23,50.72 v3(59.69,51.18) ; C6203.2 C6201.2 v2(155.41,138.21) v2(155.41,137.31) 155.21,137.11 NGFF2.77 ; RJ45R1.24 140.85,8.3 ; RJ45R1.24 139.24,6.69 ; RJ45R1.24 140.85,5.08 ; RJ45R1.24 142.46,6.69 ; C5101.2 v2(232.24,157.91) ; R2619.2 v2(89.31,18.41) ; v3(81.79,217.04) PC4909.2 ; C9209.2 v2(229.44,45.02) ; v2(218.8,157.48) C2125.2 218.14,157.52 218.14,158.33 C2101.2 ; v2(68.94,25.27) 68.83,25.38 R5910.2 ; R1917.2 194.51,168.58 v2(194.89,168.2) ; DIMM2.57 67.66,176.85 ; DIMM2.57 66.92,176.11 ; DIMM2.57 67.66,175.37 ; C9513.2 v2(202.45,47.42) ; v2(23.37,184.02) 23.11,184.28 C1211.2 ; v2(127.64,55.37) 127,55.37 126.62,55.75 PC4705.2 ; DIMM2.48 60.75,177.71 ; DIMM2.48 59.27,177.71 ; DIMM2.48 60.01,176.97 ; DIMM2.48 60.01,178.45 ; R2054.2 226.14,156.16 226.71,155.59 R2051.2 228.3,155.59 R2053.2 228.82,156.11 v2(229.62,156.11) ; USB3F2.11 102.6,249.07 ; USB3F2.11 103.62,247.3 ; USB3F2.11 101.58,247.3 ; v2(125.79,119.19) C805.2 ; C805.2 R808.2 ; C805.2 124.26,118.36 C804.2 ; 116.96,175.37 DIMM2.109 ; DIMM2.109 116.22,176.11 ; DIMM2.109 116.96,176.85 ; DIMM2.189 58.2,179.91 ; DIMM2.189 57.46,180.65 ; DIMM2.189 57.46,179.17 ; DIMM2.189 56.72,179.91 ; v2(210.06,42.52) 210.06,43.1 210.36,43.4 C9508.2 210.3,43.52 C9506.2 C9505.2 C9507.2 ; DIMM2.2 20.91,178.45 ; DIMM2.2 21.65,177.71 ; DIMM2.2 20.91,176.97 ; R2423.2 208.72,76.2 v2(209.47,76.2) ; C4217.2 176.83,219.35 v2(176.73,219.46) 176.63,219.35 175.98,219.35 C4215.2 ; DIMM2.20 36.95,177.71 ; DIMM2.20 36.21,178.45 ; DIMM2.20 35.47,177.71 ; DIMM2.20 36.21,176.97 ; v2(24.28,235.71) 23.79,235.22 C6401.2 ; DIMM2.268 130.45,181.51 ; DIMM2.268 129.71,180.77 ; DIMM2.268 128.97,181.51 ; 134.92,176.11 DIMM2.131 ; DIMM2.131 135.66,175.37 ; DIMM2.131 135.66,176.85 ; R2453.2 R2450.1 v2(208.89,80.16) 209.43,79.62 Q2407.S ; v2(138.84,36.26) C3107.2 ; C1212.2 77.6,151.23 v2(77.58,151.24) 77.58,152.49 C1028.2 ; C2712.2 56.83,227.01 v2(57.28,227.46) ; C2718.2 62.19,225.46 62.18,225.48 v2(62.18,225.63) ; v2(213.33,188.82) C6304.2 C6303.2 213.23,187.95 v2(213.33,187.95) ; 104.21,180.77 DIMM2.238 ; DIMM2.238 103.47,181.51 ; DIMM2.238 104.95,181.51 ; v2(117.73,29.06) 118.45,29.78 PR4708.1 ; v2(122.25,35.08) 122.56,34.77 PR4711.2 ; R5908.2 55.52,25.07 v2(55.7,24.89) 55.7,24.12 C5904.2 ; v2(57.28,192.79) 57.07,192.99 PR5003.2 ; R1808.1 197.5,166.59 v2(196.88,165.96) 196.16,165.25 R2322.2 R2330.2 ; C3806.2 v2(107.51,240.26) ; C9409.2 v2(210.91,22.85) ; PC4910.2 v3(18.16,208.28) ; C5909.2 56.64,15.81 C5922.2 56.45,15.62 v2(55.63,15.62) ; 36.32,179.91 DIMM2.165 ; DIMM2.165 37.06,180.65 ; DIMM2.165 37.8,179.91 ; DIMM2.165 37.06,179.17 ; v2(200.54,65.52) 200.9,65.88 C9514.2 R9509.2 ; C1102.2 66.71,159.54 v2(66.71,158.17) 66.88,158 C1214.2 ; R2030.2 216.66,185.04 v2(217.04,185.42) ; DIMM2.9 27.6,176.11 ; DIMM2.9 26.86,176.85 ; DIMM2.9 26.12,176.11 ; DIMM2.9 26.86,175.37 ; PC4428.2 15.11,61.02 PR4467.2 ; PR4952.2 v2(34.86,188.59) ; C4204.2 v2(91.45,211.89) ; v2(98,15) 97.91,15 97.41,15.49 U3901.2 ; C1802.2 200.08,128.6 200.08,129.25 v2(199.97,129.36) ; v2(200.74,117.94) 200.88,117.94 201.51,118.57 R2011.2 201.54,118.8 C2001.2 ; C2414.2 212.41,81.98 C2409.2 213.49,82.55 v2(213.23,82.8) ; 24.42,179.91 DIMM2.151 ; DIMM2.151 25.16,180.65 ; DIMM2.151 25.9,179.91 ; DIMM2.151 25.16,179.17 ; C9205.2 228.32,41.08 SLOT4.44 ; 30.37,181.51 DIMM2.158 ; DIMM2.158 31.11,182.25 ; DIMM2.158 31.85,181.51 ; DIMM2.158 31.11,180.77 ; v2(218.19,164.21) 218.5,164.21 219.01,164.72 219.01,164.98 C1803.2 219.02,165.8 220.32,167.11 220.32,168.71 219.61,169.42 v2(217.3,169.42) 215.39,169.42 214.88,168.91 214.88,166.34 215.71,165.52 C1804.2 ; C3201.2 109.79,17.78 v2(109.35,17.78) ; ATX3.3 214.1,230.3 ; ATX3.3 212.75,228.95 ; ATX3.3 214.1,227.6 ; ATX3.3 215.45,228.95 ; U5602.1 v2(37.37,10.1) ; 19.63,3.4 HDMI1.23 ; HDMI1.23 20.7,4.81 ; HDMI1.23 20.7,1.99 ; C2006.2 225.03,173.23 225.46,173.23 225.48,173.25 231.53,173.25 231.89,173.61 v2(233.3,173.61) ; DIMM2.241 107.5,179.91 ; DIMM2.241 106.76,179.17 ; DIMM2.241 106.02,179.91 ; DIMM2.241 106.76,180.65 ; v2(29.84,198.07) 29.51,197.74 PC4913.2 ; DIMM2.176 47.15,181.51 ; DIMM2.176 45.67,181.51 ; DIMM2.176 46.41,182.25 ; DIMM2.176 46.41,180.77 ; DIMM2.101 110.9,176.11 ; DIMM2.101 109.42,176.11 ; DIMM2.101 110.16,175.37 ; DIMM2.101 110.16,176.85 ; C9204.2 v2(229.43,24.96) ; USB2R1.8 113.09,15.79 ; USB2R1.8 114.02,14.86 ; USB2R1.8 113.09,13.93 ; USB2R1.8 112.16,14.86 ; v2(93.6,14.61) 93.6,15.05 UC3901.2 ; SLOT4.25 217.89,31.2 217.81,31.11 ; R1919.2 221.36,174.57 v2(221.64,174.29) ; 132.37,181.51 DIMM2.272 ; DIMM2.272 133.85,181.51 ; DIMM2.272 133.11,180.77 ; v2(15.24,187.58) C1106.2 15.24,186.06 C1107.2 14.79,185.55 R1106.2 ; R2316.2 224.6,138.8 R2323.2 224.59,138.43 224.15,137.99 223.12,137.99 v2(222.79,138.32) ; C3111.2 C3108.2 142.27,48.36 142.49,48.13 v2(143.51,48.13) ; R2713.1 v2(77.85,230.5) ; v2(46.99,187.13) C4013.2 ; PC4416.2 27.67,67.56 27.93,67.83 v2(28.07,67.83) ; v2(97.03,215.9) C4201.2 C4202.2 96.88,214.88 v2(97.08,215.09) ; R9506.2 v2(190.45,56.87) ; 121.21,176.97 DIMM2.114 ; DIMM2.114 121.95,177.71 ; DIMM2.114 120.47,177.71 ; DIMM2.114 121.21,178.45 ; DIMM2.134 138.95,177.71 ; DIMM2.134 138.21,178.45 ; DIMM2.134 138.21,176.97 ; DIMM2.134 137.47,177.71 ; PR5025.2 v2(48.13,186.41) ; PC5205.2 142.16,187.83 v2(141.3,186.97) ; CPU1.C2 96.54,95.19 v2(97.46,95.19) ; v2(214.78,175.09) C2007.2 R2043.2 ; R5921.2 v2(41.02,15.11) ; DIMM2.184 53.21,182.25 ; DIMM2.184 53.95,181.51 ; DIMM2.184 53.21,180.77 ; DIMM2.184 52.47,181.51 ; USB3F1.4 84.7,246.09 ; USB3F1.4 85.49,245.3 ; USB3F1.4 83.91,245.3 ; VGA1.10 57.14,4.17 ; VGA1.10 56.16,5.15 ; VGA1.10 55.19,4.17 ; 107.61,176.97 DIMM2.98 ; DIMM2.98 107.61,178.45 ; DIMM2.98 108.35,177.71 ; DIMM2.98 106.87,177.71 ; C2719.1 v2(21.46,19.43) ; APS1.3 v2(232.4,108.76) ; HS1902.1 220.95,119.56 ; HS1902.1 220,120.51 ; HS1902.1 219.05,119.56 ; 39.72,179.91 DIMM2.169 ; DIMM2.169 41.2,179.91 ; DIMM2.169 40.46,180.65 ; DIMM2.169 40.46,179.17 ; v2(146.99,185.65) C1217.2 C1110.2 ; v2(153.78,31.15) 153.8,31.17 R4004.2 ; LPC1.3 232.52,100.97 232.01,100.46 v2(231.01,100.46) ; 60.12,179.91 DIMM2.193 ; DIMM2.193 60.86,179.17 ; DIMM2.193 60.86,180.65 ; DIMM2.193 61.6,179.91 ; C2711.2 52.83,227.46 v2(51.94,226.57) ; 44.82,176.11 DIMM2.31 ; DIMM2.31 45.56,176.85 ; DIMM2.31 45.56,175.37 ; DIMM2.31 46.3,176.11 ; DIMM2.279 139.8,179.91 ; DIMM2.279 139.06,180.65 ; DIMM2.279 139.06,179.17 ; DIMM2.279 138.32,179.91 ; v2(148.21,39.5) 147.83,39.88 C3101.2 ; DIMM2.257 120.36,180.65 ; DIMM2.257 119.62,179.91 ; DIMM2.257 120.36,179.17 ; DIMM2.257 121.1,179.91 ; 113.09,11.31 USB2R1.4 ; USB2R1.4 113.09,13.17 ; USB2R1.4 112.16,12.24 ; USB2R1.4 114.02,12.24 ; R2449.1 200.56,104.81 v2(200.56,105.28) ; 19.63,9.36 HDMI1.21 ; HDMI1.21 20.7,7.54 ; HDMI1.21 20.7,11.18 ; R3809.2 115.47,238.38 v2(115.72,238.12) ; 235.25,193.49 HS6301.1 ; HS6301.1 238.76,197 ; HS6301.1 231.74,197 ; HS6301.1 235.25,200.51 ; PR4957.2 v2(30.48,185.17) ; DIMM2.37 50.66,176.85 ; DIMM2.37 49.92,176.11 ; DIMM2.37 51.4,176.11 ; DIMM2.37 50.66,175.37 ; v2(106.26,61.66) R2611.2 106.26,62.86 106.57,63.17 U2601.4 ; NGFF1.76 204.02,186.65 v2(204.66,187.29) ; v2(34.11,45.95) 33.71,46.35 C4303.2 ; C9201.2 v2(230.63,18.4) ; v2(210.69,162.05) 211.07,162.05 211.77,162.75 R2328.2 212.14,162.8 212.14,163.59 R2326.2 ; EU3201.2 v2(138.56,28.91) ; v2(129.79,90.14) 130.4,90.14 131.29,89.25 PU4801.2 ; DIMM2.55 65.96,176.85 ; DIMM2.55 65.22,176.11 ; DIMM2.55 65.96,175.37 ; DIMM2.55 66.7,176.11 ; DIMM2.243 109.2,179.91 ; DIMM2.243 108.46,179.17 ; DIMM2.243 107.72,179.91 ; DIMM2.243 108.46,180.65 ; PR5116.2 v2(231.23,157.86) ; R9505.2 v2(191.64,60.92) ; R2409.2 v2(196.77,75.86) ; 55.76,179.17 DIMM2.187 ; DIMM2.187 55.02,179.91 ; DIMM2.187 56.5,179.91 ; DIMM2.187 55.76,180.65 ; v2(27.23,78.41) 27.62,78.02 PR4423.2 ; v2(212.69,170.69) 212.69,170.12 212.67,170.1 DB2001.2 ; v2(183.18,14.68) 183.18,15.19 183.69,15.7 C5304.2 185.79,15.7 R5305.2 ; v2(131.58,41.27) 132.84,41.27 133.2,40.92 133.87,40.92 C3118.2 133.9,40.92 134.57,40.92 134.58,40.93 135.22,40.93 v2(135.64,41.34) ; v2(131.58,41.27) 131.27,41.27 130.77,41.77 130.77,44.8 v2(131.46,45.49) 133.55,45.49 C3119.2 134.67,45 134.92,44.65 134.94,44.64 v2(135.76,44.64) ; v2(131.58,41.27) X3101.2 ; v2(23.29,188.06) 23.75,187.6 R1207.2 ; v2(203.48,104.24) 202.98,104.24 R2448.1 ; 58.65,13.69 v2(58.62,13.69) ; v2(188.04,170.15) 188.04,169.33 R1713.2 ; C4009.2 v2(151.89,204.98) ; R1708.2 202.68,122.49 v2(203.03,122.85) C2124.2 ; C1205.2 87.57,183.2 88.45,182.31 v2(88.45,182.05) ; PR4717.2 126.64,34.84 v2(126.64,34.19) ; v2(122.17,77.8) 122.17,77.8 122.75,78.37 R426.2 R424.2 ; v2(35.31,196.09) 35.05,195.83 PC4906.2 ; v2(133.66,34.42) C3114.2 133.66,36.31 C3105.2 ; 24.31,176.97 DIMM2.6 ; DIMM2.6 23.57,177.71 ; DIMM2.6 25.05,177.71 ; DIMM2.6 24.31,178.45 ; v2(221.77,156.92) 221.93,157.09 R2050.2 ; 103.47,177.71 DIMM2.94 ; DIMM2.94 104.21,178.45 ; DIMM2.94 104.21,176.97 ; DIMM2.94 104.95,177.71 ; v2(96.29,162.88) 96.29,163.76 C1101.2 ; v2(121.16,121.41) 121.98,122.24 R810.2 122.25,121.3 C806.2 ; 112.82,176.11 DIMM2.105 ; DIMM2.105 113.56,175.37 ; DIMM2.105 113.56,176.85 ; DIMM2.105 114.3,176.11 ; C804.2 v2(124.21,119.46) ; C804.2 C1032.2 v2(122.17,119.51) ; v3(227.84,141.73) 227.51,142.06 PC5110.2 ; 10.16,134.19 FANC1.1 9.19,133.22 ; v3(48.51,198.75) 48.9,198.37 PC5009.2 ; C5907.2 v2(53.34,16.13) ; 131.41,180.77 DIMM2.270 ; DIMM2.270 132.15,181.51 ; DIMM2.270 130.67,181.51 ; ATX3.2 211.25,228.95 ; ATX3.2 208.55,228.95 ; ATX3.2 209.9,227.6 ; ATX3.2 209.9,230.3 ; v2(187.69,177.88) C4001.2 187.69,176.05 R4002.2 ; v2(129.92,123.13) C802.2 ; v2(202.65,208.97) C6310.2 ; C3805.2 85.09,227.58 v2(84.84,227.84) ; C9106.2 178.69,208.41 v2(178.94,208.66) ; v2(215.42,114.25) 215.71,114.54 C2122.2 ; Q2704.C v2(49.78,227.27) ; C5303.2 v2(173.53,10.29) ; v2(198.8,102.11) 198.8,102.14 198.7,102.23 198.7,102.25 198.56,102.39 C2422.2 ; DIMM2.33 48,176.11 ; DIMM2.33 47.26,176.85 ; DIMM2.33 46.52,176.11 ; DIMM2.33 47.26,175.37 ; 104.32,179.91 DIMM2.239 ; DIMM2.239 105.8,179.91 ; DIMM2.239 105.06,180.65 ; DIMM2.239 105.06,179.17 ; C3302.2 v2(44.32,227.46) ; C9519.2 v2(199.81,45.72) ; R9915.2 v2(126.11,73.03) ; C5302.2 v2(178.31,14.45) ; v2(91.47,210.9) C4206.2 C4205.2 ; 59.16,179.17 DIMM2.191 ; DIMM2.191 59.16,180.65 ; DIMM2.191 58.42,179.91 ; DIMM2.191 59.9,179.91 ; C1105.2 v2(13.84,182.63) ; C1029.2 v2(70.92,154.56) ; v2(143.99,193.5) 143.84,193.5 143.26,192.91 PC5202.2 ; v2(216.75,86.11) 216.75,87.03 216.34,87.44 R2471.2 C2425.2 ; DIMM2.24 40.35,177.71 ; DIMM2.24 39.61,178.45 ; DIMM2.24 38.87,177.71 ; DIMM2.24 39.61,176.97 ; PR4454.2 16.57,77.6 16.95,77.22 v2(17.02,77.22) 16.32,76.52 PC4426.2 PR4458.2 ; R6423.2 223.58,149.38 R6407.2 223.58,150.65 v2(223.01,151.23) ; R2035.2 234,176.75 233.58,176.33 v2(233.2,176.33) 231.42,176.33 JMP1.4 ; C5903.1 v2(63.27,28.96) ; C2002.2 221.48,185 220.55,185.93 v2(219.79,185.93) ; 89.87,5.71 FANS1.1 88.9,4.75 ; U4002.4 v2(83.82,24.22) ; 41.42,179.91 DIMM2.171 ; DIMM2.171 42.9,179.91 ; DIMM2.171 42.16,180.65 ; DIMM2.171 42.16,179.17 ; 225.8,73.11 SLOT4.92 ; SLOT4.92 226.78,74.08 ; SLOT4.92 226.78,72.13 ; SLOT4.92 227.76,73.11 ; SLOT4.73 218.15,62.69 R9511.2 R9510.2 R9507.2 ; DIMM2.112 119.51,178.45 ; DIMM2.112 119.51,176.97 ; DIMM2.112 120.25,177.71 ; DIMM2.112 118.77,177.71 ; R2604.2 v2(17.17,133.03) ; v2(13.21,67.13) 13.02,67.32 PC4427.2 ; v2(169.42,30.73) 169.93,30.23 C9404.2 ; PC5002.2 v2(56.69,190.58) ; UC3202.2 v2(145.24,24.23) ; C2106.2 C2105.2 C2104.2 216.17,148.37 215.65,148.89 v2(215.65,149.02) ; v2(134.28,121.88) C301.2 ; C801.2 v2(120.59,117.67) ; R2311.2 v2(216.43,144.72) ; v2(106.58,68.81) 107.01,68.81 107.52,68.3 U2601.2 ; 65.28,19.05 65.05,19.28 65.05,19.33 v2(64.72,19.66) ; C2101.2 218.01,158.46 C2103.2 C2102.2 ; C2101.2 v2(218.85,158.37) ; C2423.2 v2(199.14,80.52) ; C4002.2 155.83,32.37 v2(155.83,31.9) ; C3901.2 v2(92.58,14.73) ; C5613.2 v2(37.72,8.51) ; SATAP2.5 185.09,222.94 ; SATAP2.5 184,224.03 ; SATAP2.5 184,221.85 ; C2418.2 194.44,104.71 R2474.2 v2(193.65,104.78) ; 224.08,176.94 222.94,176.94 222.91,176.96 v2(222.83,176.96) ; 224.08,176.94 R6302.1 ; C2720.1 v2(79.58,241.94) ; 111.01,180.77 DIMM2.246 ; DIMM2.246 111.75,181.51 ; DIMM2.246 110.27,181.51 ; SATAP1.5 147.09,221.94 ; SATAP1.5 146,220.85 ; SATAP1.5 146,223.03 ; C9521.2 216.51,64.8 v2(217.17,64.14) ; DIMM2.198 65.11,182.25 ; DIMM2.198 65.11,180.77 ; DIMM2.198 64.37,181.51 ; DIMM2.198 65.85,181.51 ; U4003.S v2(88.7,21.49) ; C2412.2 191.16,99.44 v2(190.53,98.81) ; DIMM2.129 133.96,176.85 ; DIMM2.129 134.7,176.11 ; DIMM2.129 133.96,175.37 ; DIMM2.129 133.22,176.11 ; v2(187.22,28.14) 187.71,28.63 C9311.2 188.98,28.7 C9410.2 ; 29.52,176.11 DIMM2.13 ; DIMM2.13 30.26,175.37 ; DIMM2.13 31,176.11 ; DIMM2.13 30.26,176.85 ; 114.55,9.53 USB2R1.10 ; USB2R1.10 116.16,11.14 ; USB2R1.10 117.77,9.53 ; USB2R1.10 116.16,7.92 ; R6406.2 221.69,147.98 v2(221.87,148.16) ; DIMM2.160 33.55,181.51 ; DIMM2.160 32.07,181.51 ; DIMM2.160 32.81,182.25 ; DIMM2.160 32.81,180.77 ; v3(147.93,98.78) 147.6,98.78 146.05,100.33 ; v2(179.26,14.45) R5304.2 ; R1515.2 v2(192.15,183.51) ; C1213.2 v2(88.77,161.77) ; v2(52.32,239.01) 53.27,239.96 SD1.6 ; 147.57,101.09 v3(148.97,99.7) ; C3103.2 v2(143.64,36.36) ; v2(209.3,113.94) 209.3,113.79 209.61,113.47 R2315.2 210.66,113.16 211.27,112.55 211.36,112.55 R1516.2 ; R2424.2 201.61,76.01 v2(201.42,75.82) ; v2(190.53,104.65) 190.75,104.65 191.41,103.99 C2424.2 191.43,103.52 C2419.2 ; R2617.2 v2(84.94,13.14) ; DIMM2.283 142.46,180.65 ; DIMM2.283 141.72,179.91 ; DIMM2.283 142.46,179.17 ; DIMM2.283 143.2,179.91 ; EU3901.2 v2(106.55,19.81) ; C1109.2 C1216.2 v2(137.69,187.68) ; C4003.2 95.38,22.8 v2(95.38,22.05) ; DIMM2.39 52.36,176.85 ; DIMM2.39 52.36,175.37 ; DIMM2.39 51.62,176.11 ; C9208.2 v2(229.62,58.61) ; DIMM2.252 116.85,181.51 ; DIMM2.252 116.11,180.77 ; DIMM2.252 115.37,181.51 ; R5914.2 62.68,17.3 C5917.2 ; C1031.2 v2(66.93,151.12) ; C4004.2 v2(155.19,24.89) ; 123.32,9.32 RJ45R1.25 ; RJ45R1.25 126.54,9.32 ; RJ45R1.25 124.93,7.71 ; C9405.2 v2(170.71,25.4) ; R5609.2 22.77,15.18 v2(22.78,15.19) ; v2(217.81,105.87) R2446.1 218.89,105.09 219.3,105.5 219.3,107.2 218.8,107.71 R2309.2 ; R2304.2 207.68,168.95 208.41,168.22 v2(208.41,168.15) ; v2(191.21,66.78) C9524.2 191.91,65.06 C9522.2 C9526.2 ; v2(207.9,172.47) 207.58,172.15 C9103.2 ; C3305.2 v2(41.78,236.35) ; R9504.2 v2(190.86,64.52) ; 114.55,15.21 USB2R1.12 ; USB2R1.12 116.16,13.6 ; USB2R1.12 117.77,15.21 ; C3106.2 134.11,37.78 R3101.1 C3105.2 ; C5611.2 v2(22.54,19.1) ; C2421.2 v2(207.58,80.04) ; v3(230.82,150.15) 230.64,150.15 229.83,149.33 PC5109.2 ; R2305.2 212.26,123.86 v2(212.01,124.1) 212.31,124.4 R1511.1 ; R2460.2 215.9,105.09 v2(215.9,106.05) ; v2(18.16,79.88) 18.41,79.63 18.41,79.06 PC4403.2 PR4471.2 ; 117.81,180.77 DIMM2.254 ; DIMM2.254 117.07,181.51 ; DIMM2.254 118.55,181.51 ; 140.87,177.71 DIMM2.138 ; DIMM2.138 141.61,176.97 ; DIMM2.138 141.61,178.45 ; SATAP1.3 150.09,224.94 ; SATAP1.3 149,226.03 ; SATAP1.3 149,223.85 ; R9110.1 201.73,179.59 C9102.2 201.36,179.96 C9101.2 197.99,179.96 v2(197.74,179.71) ; C1215.2 v2(81.1,162.13) ; C304.2 121.41,96.14 v2(121.64,95.91) ; U4002.1 v2(85.7,21.49) ; EU3803.2 v2(99.26,238.81) ; C2713.2 57.34,224.16 C2714.2 58.17,224.22 58.36,224.41 C2715.2 58.36,225.44 59.07,226.16 v2(59.18,226.16) ; APS1.1 v2(234.4,108.76) ; 60.58,83.16 v2(59.46,83.16) ; C3303.2 v2(36.96,226.82) ; R3302.2 v2(37.97,226.82) ; C2501.2 v2(193.78,207.72) ; EU3203.2 v2(143.1,28.75) ; v2(132.97,36.58) C3105.2 ; 197.76,207.73 197.74,207.76 R6315.2 ; PR5112.2 230.62,151.98 v2(231.47,151.13) ; PC4401.2 26.82,81.15 v2(27.08,81.41) ; DIMM2.200 66.81,183.26 C1108.2 ; v2(216.51,55.78) 216.23,55.5 C9515.2 ; C4011.2 145.22,196.6 C4012.2 145.73,195.2 v2(146.81,195.2) ; 140.76,179.17 DIMM2.281 ; DIMM2.281 141.5,179.91 ; DIMM2.281 140.02,179.91 ; DIMM2.281 140.76,180.65 ; EU3204.2 v2(147.78,28.65) ; v2(61.29,9.47) v2(61.29,8.18) ; C9411.2 v2(211.15,36.55) ; PC5015.2 v3(43,189.99) ; v3(149.33,50.22) 148.01,51.54 ; 105.91,176.97 DIMM2.96 ; DIMM2.96 106.65,177.71 ; DIMM2.96 105.17,177.71 ; DIMM2.96 105.91,178.45 ; C9523.2 C9527.2 192.11,52.37 C9525.2 v2(190.8,52.37) ; PC4402.2 v2(20.07,75.82) ; PR4956.2 v2(32.72,185.04) ; APS1.5 v2(230.4,108.76) ; C1020.2 v2(65.53,83.19) ; v2(141.91,46.25) 141.92,46.24 R3106.2 ; v2(212.14,180.72) C9104.2 210.76,181.17 C9105.2 ; C1030.2 v2(101.9,161.2) ; v2(128.75,223.7) 130.4,222.05 130.4,217.72 R2505.2 ; PC4414.2 v2(25.53,77.72) ; C3304.2 v2(47.24,230.76) ; C1033.2 v2(118.87,116.33) ; UC3801.2 v2(92.2,239.01) ; C403.2 v2(132.03,75.18) ; v2(126.49,121.15) 126.49,121.28 127,121.79 R806.2 ; LPC1.16 v2(220.22,100.9) ; PR4962.2 v2(26.19,189.59) ; v2(217.47,99.69) 217.47,99.59 217.42,99.54 C2411.2 217.42,98.42 216.6,97.6 C2408.2 215.26,97.6 R2475.2 ; R1920.2 223.9,154.58 v2(223.37,154.05) ; C9408.2 v2(207.95,26.37) ; PR4816.2 v2(134.49,94.82) ; v2(26.16,190.58) PC4919.2 ; PR4430.2 v2(26.54,77.72) ; C2420.2 v2(191.76,95.22) ; v2(42.19,45.34) 42.3,45.22 PR4466.2 ; R2332.2 213.74,162.26 v2(213.59,162.1) ; PR5206.2 v2(153.54,186.88) ; C302.2 v2(132.03,130.61) ; C5610.2 v2(25.34,19.18) ; PC4512.2 v2(89.97,52.65) ; C9206.2 v2(230.57,94.81) ; v2(204.91,45.75) C9520.2 ; v2(192.58,59.87) C9518.2 C9516.2 ; C2107.2 v2(220.8,160.67) ; U6301.2 v2(206.25,211.07) ; R9914.2 v2(129.29,70.1)
  TOP w1.016: 233.2,116.52 PT5101.2 ; PT5101.2 234.15,117.47 ; PT5101.2 233.2,118.43
  L3 w0.508: 34.13,3.4 HDMI1.22 ; HDMI1.22 35.2,4.81 ; HDMI1.22 35.2,1.99 ; HDMI1.22 36.27,3.4 ; SLOT4.76 226.78,63.92 ; SLOT4.76 227.76,62.95 ; SLOT4.76 226.78,61.97 ; SLOT4.76 225.8,62.95 ; SLOT3.A1 201.4,20.92 ; SLOT3.A1 200.6,20.12 ; SLOT3.A1 202.2,20.12 ; SLOT3.A1 201.4,19.32 ; 205.9,38.32 SLOT3.B18 ; SLOT3.B18 206.7,39.12 ; SLOT3.B18 205.9,39.92 ; SLOT3.B18 205.1,39.12 ; 185.58,80.32 SLOT2.B60 ; SLOT2.B60 184.78,81.12 ; SLOT2.B60 185.58,81.92 ; SLOT2.B60 186.38,81.12 ; SLOT3.A12 199.4,33.92 ; SLOT3.A12 199.4,32.32 ; SLOT3.A12 200.2,33.12 ; SLOT3.A12 198.6,33.12 ; SLOT3.B4 206.7,23.12 ; SLOT3.B4 205.1,23.12 ; SLOT3.B4 205.9,23.92 ; SLOT3.B4 205.9,22.32 ; SLOT4.44 226.78,43.6 ; SLOT4.44 226.78,41.65 ; SLOT4.44 225.8,42.63 ; SLOT4.44 227.76,42.63 ; SLOT4.25 219.16,32.17 ; SLOT4.25 219.16,30.22 ; SLOT4.25 218.18,31.2 ; SLOT4.25 220.14,31.2 ; 180.28,92.12 SLOT2.A71 ; SLOT2.A71 181.08,91.32 ; SLOT2.A71 181.08,92.92 ; SLOT2.A71 181.88,92.12 ; 181.08,83.32 SLOT2.A63 ; SLOT2.A63 181.08,84.92 ; SLOT2.A63 180.28,84.12 ; SLOT2.A63 181.88,84.12 ; 184.78,97.12 SLOT2.B76 ; SLOT2.B76 185.58,96.32 ; SLOT2.B76 186.38,97.12 ; SLOT2.B76 185.58,97.92 ; SLOT2.A28 179.88,49.12 ; SLOT2.A28 178.28,49.12 ; SLOT2.A28 179.08,48.32 ; SLOT2.A28 179.08,49.92 ; SLOT2.B22 185.58,43.92 ; SLOT2.B22 185.58,42.32 ; SLOT2.B22 184.78,43.12 ; SLOT2.B22 186.38,43.12 ; SATA4.1 110.16,200.24 ; SATA4.1 109.41,200.99 ; SATA4.1 108.66,200.24 ; SATA4.1 109.41,199.49 ; 183.58,89.32 SLOT2.B69 ; SLOT2.B69 182.78,90.12 ; SLOT2.B69 184.38,90.12 ; SLOT2.B69 183.58,90.92 ; SLOT2.A70 179.88,91.12 ; SLOT2.A70 179.08,91.92 ; SLOT2.A70 179.08,90.32 ; SLOT2.A70 178.28,91.12 ; 20.17,177.71 DIMM2.2 ; DIMM2.2 20.91,176.97 ; DIMM2.2 20.91,178.45 ; RJ45R1.8 135.93,14.65 ; RJ45R1.8 135,13.72 ; RJ45R1.8 134.07,14.65 ; RJ45R1.8 135,15.58 ; 184.78,57.12 SLOT2.B36 ; SLOT2.B36 185.58,57.92 ; SLOT2.B36 185.58,56.32 ; SLOT2.B36 186.38,57.12 ; SLOT4.35 222.68,37.55 ; SLOT4.35 220.72,37.55 ; SLOT4.35 221.7,38.52 ; SLOT4.35 221.7,36.57 ; 178.28,75.12 SLOT2.A54 ; SLOT2.A54 179.08,75.92 ; SLOT2.A54 179.88,75.12 ; SLOT2.A54 179.08,74.32 ; 179.08,40.32 SLOT2.A20 ; SLOT2.A20 178.28,41.12 ; SLOT2.A20 179.08,41.92 ; SLOT2.A20 179.88,41.12 ; 181.08,61.32 SLOT2.A41 ; SLOT2.A41 181.88,62.12 ; SLOT2.A41 180.28,62.12 ; SLOT2.A41 181.08,62.92 ; VGA1.10 56.16,5.15 ; VGA1.10 57.14,4.17 ; VGA1.10 55.19,4.17 ; VGA1.10 56.16,3.19 ; SLOT2.B40 185.58,61.92 ; SLOT2.B40 185.58,60.32 ; SLOT2.B40 186.38,61.12 ; SLOT2.B40 184.78,61.12 ; SLOT2.B52 186.38,73.12 ; SLOT2.B52 184.78,73.12 ; SLOT2.B52 185.58,72.32 ; SLOT2.B52 185.58,73.92 ; SLOT4.47 221.7,46.14 ; SLOT4.47 220.72,45.17 ; SLOT4.47 222.68,45.17 ; SLOT4.47 221.7,44.19 ; 99.06,200.06 SATA4.9 ; SATA4.9 97.88,201.24 ; SATA4.9 99.06,202.42 ; SATA4.9 100.24,201.24 ; 181.08,87.32 SLOT2.A67 ; SLOT2.A67 181.88,88.12 ; SLOT2.A67 181.08,88.92 ; SLOT2.A67 180.28,88.12 ; 182.78,98.12 SLOT2.B77 ; SLOT2.B77 184.38,98.12 ; SLOT2.B77 183.58,98.92 ; SLOT2.B77 183.58,97.32 ; SLOT1.B7 163.26,26.92 ; SLOT1.B7 162.46,26.12 ; SLOT1.B7 163.26,25.32 ; SLOT1.B7 164.06,26.12 ; SLOT4.34 224.24,37.25 ; SLOT4.34 225.22,36.28 ; SLOT4.34 224.24,35.3 ; SLOT4.34 223.26,36.28 ; SLOT4.107 221.7,86.78 ; SLOT4.107 222.68,85.81 ; SLOT4.107 221.7,84.83 ; SLOT4.107 220.72,85.81 ; 184.78,93.12 SLOT2.B72 ; SLOT2.B72 185.58,93.92 ; SLOT2.B72 185.58,92.32 ; SLOT2.B72 186.38,93.12 ; 104.71,245.3 USB3F2.4 ; USB3F2.4 106.29,245.3 ; USB3F2.4 105.5,246.09 ; VGA1.8 60.75,5.15 ; VGA1.8 59.77,4.17 ; VGA1.8 61.72,4.17 ; VGA1.8 60.75,3.19 ; SATA3.1 132.06,200.24 ; SATA3.1 130.56,200.24 ; SATA3.1 131.31,199.49 ; SATA3.1 131.31,200.99 ; SATA3.9 120.96,202.42 ; SATA3.9 119.78,201.24 ; SATA3.9 122.14,201.24 ; SATA3.9 120.96,200.06 ; 20.17,168.73 DIMM1.2 20.91,169.46 ; 111.89,199.06 SATA4.8 ; SATA4.8 111.89,201.42 ; SATA4.8 110.71,200.24 ; SATA4.8 113.07,200.24 ; 185.58,76.32 SLOT2.B56 ; SLOT2.B56 186.38,77.12 ; SLOT2.B56 184.78,77.12 ; SLOT2.B56 185.58,77.92 ; 183.58,73.32 SLOT2.B53 ; SLOT2.B53 182.78,74.12 ; SLOT2.B53 184.38,74.12 ; SLOT2.B53 183.58,74.92 ; 183.58,41.32 SLOT2.B21 ; SLOT2.B21 184.38,42.12 ; SLOT2.B21 182.78,42.12 ; SLOT2.B21 183.58,42.92 ; 220.72,75.65 SLOT4.95 ; SLOT4.95 222.68,75.65 ; SLOT4.95 221.7,74.67 ; SLOT4.95 221.7,76.62 ; 224.24,17.52 SLOT4.6 ; SLOT4.6 225.22,18.5 ; SLOT4.6 224.24,19.47 ; SLOT4.6 223.26,18.5 ; 119.78,190.64 SATA1.9 ; SATA1.9 120.96,191.82 ; SATA1.9 122.14,190.64 ; SATA1.9 120.96,189.46 ; SLOT2.B13 183.58,34.92 ; SLOT2.B13 182.78,34.12 ; SLOT2.B13 184.38,34.12 ; SLOT2.B13 183.58,33.32 ; 223.26,76.92 SLOT4.98 ; SLOT4.98 224.24,75.94 ; SLOT4.98 225.22,76.92 ; 214.1,227.6 ATX3.3 ; ATX3.3 214.1,230.3 ; ATX3.3 212.75,228.95 ; ATX3.3 215.45,228.95 ; 181.08,99.32 SLOT2.A79 ; SLOT2.A79 181.08,100.92 ; SLOT2.A79 180.28,100.12 ; SLOT2.A79 181.88,100.12 ; SLOT4.24 227.76,29.93 ; SLOT4.24 226.78,30.9 ; SLOT4.24 225.8,29.93 ; SLOT4.24 226.78,28.95 ; 164.46,37.12 SLOT1.B16 ; SLOT1.B16 165.26,36.32 ; SLOT1.B16 166.06,37.12 ; SLOT1.B16 165.26,37.92 ; 179.08,32.32 SLOT2.A12 ; SLOT2.A12 179.88,33.12 ; SLOT2.A12 178.28,33.12 ; SLOT2.A12 179.08,33.92 ; SATA1.4 128.25,189.64 ; SATA1.4 126.75,189.64 ; SATA1.4 127.5,190.39 ; SATA1.4 127.5,188.89 ; 185.58,64.32 SLOT2.B44 ; SLOT2.B44 184.78,65.12 ; SLOT2.B44 186.38,65.12 ; SLOT2.B44 185.58,65.92 ; 157.96,23.12 SLOT1.A4 ; SLOT1.A4 159.56,23.12 ; SLOT1.A4 158.76,23.92 ; SLOT1.A4 158.76,22.32 ; SATA1.8 133.79,190.82 ; SATA1.8 132.61,189.64 ; SATA1.8 134.97,189.64 ; SATA1.8 133.79,188.46 ; 221.7,51.81 SLOT4.59 ; SLOT4.59 221.7,53.76 ; SLOT4.59 220.72,52.79 ; SLOT4.59 222.68,52.79 ; SLOT4.56 227.76,50.25 ; SLOT4.56 225.8,50.25 ; SLOT4.56 226.78,51.22 ; SLOT4.56 226.78,49.27 ; 114.55,15.21 USB2R1.12 ; USB2R1.12 116.16,16.82 ; USB2R1.12 117.77,15.21 ; USB2R1.12 116.16,13.6 ; SLOT2.A23 181.08,44.92 ; SLOT2.A23 181.08,43.32 ; SLOT2.A23 181.88,44.12 ; SLOT2.A23 180.28,44.12 ; SLOT4.68 226.78,58.84 ; SLOT4.68 226.78,56.89 ; SLOT4.68 227.76,57.87 ; SLOT4.68 225.8,57.87 ; BT2501.2 109.26,222.23 ; BT2501.2 108.14,221.11 ; BT2501.2 107.02,222.23 ; BT2501.2 108.14,223.35 ; SLOT2.A4 179.08,23.92 ; SLOT2.A4 178.28,23.12 ; SLOT2.A4 179.88,23.12 ; SLOT2.A4 179.08,22.32 ; 62.06,4.17 VGA1.7 ; VGA1.7 63.03,5.15 ; VGA1.7 64.01,4.17 ; VGA1.7 63.03,3.19 ; 185.58,36.32 SLOT2.B16 ; SLOT2.B16 185.58,37.92 ; SLOT2.B16 186.38,37.12 ; SLOT2.B16 184.78,37.12 ; USB3F2.10 115.4,249.07 ; USB3F2.10 115.4,245.53 ; USB3F2.10 114.38,247.3 ; 64.35,4.17 VGA1.6 ; VGA1.6 66.3,4.17 ; VGA1.6 65.32,3.19 ; VGA1.6 65.32,5.15 ; SLOT1.B4 166.06,23.12 ; SLOT1.B4 165.26,22.32 ; SLOT1.B4 164.46,23.12 ; SLOT1.B4 165.26,23.92 ; SATA2.1 101.79,189.95 ; SATA2.1 101.79,188.33 ; SATA2.1 102.6,189.14 ; SATA2.1 100.98,189.14 ; 19.63,9.36 HDMI1.21 ; HDMI1.21 20.7,11.18 ; HDMI1.21 20.7,7.54 ; HDMI1.21 21.77,9.36 ; 181.08,19.32 SLOT2.A1 ; SLOT2.A1 181.88,20.12 ; SLOT2.A1 181.08,20.92 ; SLOT2.A1 180.28,20.12 ; SLOT2.A15 181.88,36.12 ; SLOT2.A15 180.28,36.12 ; SLOT2.A15 181.08,35.32 ; SLOT2.A15 181.08,36.92 ; ATX3.2 209.9,230.3 ; ATX3.2 209.9,227.6 ; ATX3.2 211.25,228.95 ; ATX3.2 208.55,228.95 ; 185.58,38.32 SLOT2.B18 ; SLOT2.B18 184.78,39.12 ; SLOT2.B18 186.38,39.12 ; SLOT2.B18 185.58,39.92 ; RJ45R1.30 140.85,20.98 ; RJ45R1.30 140.85,17.76 ; RJ45R1.30 142.46,19.37 ; RJ45R1.30 139.24,19.37 ; 105.6,199.49 SATA4.4 ; SATA4.4 106.35,200.24 ; SATA4.4 105.6,200.99 ; SATA4.4 104.85,200.24 ; 183.58,63.32 SLOT2.B43 ; SLOT2.B43 182.78,64.12 ; SLOT2.B43 183.58,64.92 ; SLOT2.B43 184.38,64.12 ; VGA1.17 72.35,6.23 ; VGA1.17 72.35,2.11 ; VGA1.17 70.29,4.17 ; VGA1.17 74.4,4.17 ; FANS1.1 89.87,5.71 ; FANS1.1 87.93,5.71 ; FANS1.1 88.9,4.75 ; FANS1.1 88.9,6.68 ; 200.6,36.12 SLOT3.A15 ; SLOT3.A15 201.4,35.32 ; SLOT3.A15 202.2,36.12 ; SLOT3.A15 201.4,36.92 ; 109.41,188.33 SATA2.7 ; SATA2.7 108.6,189.14 ; SATA2.7 110.22,189.14 ; SATA2.7 109.41,189.95 ; SATA1.7 123.69,190.39 ; SATA1.7 124.44,189.64 ; SATA1.7 122.94,189.64 ; SATA1.7 123.69,188.89 ; SLOT2.A74 179.08,95.92 ; SLOT2.A74 178.28,95.12 ; SLOT2.A74 179.08,94.32 ; SLOT2.A74 179.88,95.12 ; USB3F2.11 103.62,247.3 ; USB3F2.11 102.6,245.53 ; USB3F2.11 102.6,249.07 ; USB3F2.11 101.58,247.3 ; SLOT1.B18 166.06,39.12 ; SLOT1.B18 165.26,38.32 ; SLOT1.B18 164.46,39.12 ; SLOT1.B18 165.26,39.92 ; USB3F1.11 82.82,247.3 ; USB3F1.11 81.8,249.07 ; USB3F1.11 80.78,247.3 ; USB3F1.11 81.8,245.53 ; SLOT2.B61 183.58,82.92 ; SLOT2.B61 183.58,81.32 ; SLOT2.B61 182.78,82.12 ; SLOT2.B61 184.38,82.12 ; 225.8,73.11 SLOT4.92 ; SLOT4.92 227.76,73.11 ; SLOT4.92 226.78,74.08 ; SLOT4.92 226.78,72.13 ; 158.76,38.32 SLOT1.A18 ; SLOT1.A18 158.76,39.92 ; SLOT1.A18 157.96,39.12 ; SLOT1.A18 159.56,39.12 ; 185.58,84.32 SLOT2.B64 ; SLOT2.B64 186.38,85.12 ; SLOT2.B64 184.78,85.12 ; SLOT2.B64 185.58,85.92 ; RJ45R1.28 138.07,16.61 ; RJ45R1.28 138.07,13.39 ; RJ45R1.28 139.68,15 ; RJ45R1.28 136.46,15 ; 185.58,88.32 SLOT2.B68 ; SLOT2.B68 186.38,89.12 ; SLOT2.B68 185.58,89.92 ; SLOT2.B68 184.78,89.12 ; USB3F1.7 88.2,244.59 ; USB3F1.7 88.2,243.01 ; USB3F1.7 88.99,243.8 ; USB3F1.7 87.41,243.8 ; 180.28,52.12 SLOT2.A31 ; SLOT2.A31 181.88,52.12 ; SLOT2.A31 181.08,52.92 ; SLOT2.A31 181.08,51.32 ; SLOT2.A45 181.88,66.12 ; SLOT2.A45 181.08,66.92 ; SLOT2.A45 180.28,66.12 ; SLOT2.A45 181.08,65.32 ; SLOT2.B25 183.58,46.92 ; SLOT2.B25 184.38,46.12 ; SLOT2.B25 183.58,45.32 ; SLOT2.B25 182.78,46.12 ; 183.58,55.32 SLOT2.B35 ; SLOT2.B35 183.58,56.92 ; SLOT2.B35 184.38,56.12 ; SLOT2.B35 182.78,56.12 ; SLOT4.83 222.68,68.03 ; SLOT4.83 220.72,68.03 ; SLOT4.83 221.7,69 ; SLOT4.83 221.7,67.05 ; SLOT3.A18 199.4,39.92 ; SLOT3.A18 198.6,39.12 ; SLOT3.A18 199.4,38.32 ; SLOT3.A18 200.2,39.12 ; SLOT2.A18 179.08,39.92 ; SLOT2.A18 178.28,39.12 ; SLOT2.A18 179.88,39.12 ; SLOT2.A18 179.08,38.32 ; 47.35,2.11 VGA1.16 ; VGA1.16 49.41,4.17 ; VGA1.16 47.35,6.23 ; VGA1.16 45.3,4.17 ; FANC1.1 11.13,133.22 ; FANC1.1 10.16,134.19 ; FANC1.1 10.16,132.25 ; FANC1.1 9.19,133.22 ; 182.78,70.12 SLOT2.B49 ; SLOT2.B49 183.58,69.32 ; SLOT2.B49 183.58,70.92 ; SLOT2.B49 184.38,70.12 ; SLOT2.B26 186.38,47.12 ; SLOT2.B26 184.78,47.12 ; SLOT2.B26 185.58,47.92 ; SLOT2.B26 185.58,46.32 ; 179.08,58.32 SLOT2.A38 ; SLOT2.A38 178.28,59.12 ; SLOT2.A38 179.88,59.12 ; SLOT2.A38 179.08,59.92 ; USB2R1.9 103.02,11.14 ; USB2R1.9 103.02,7.92 ; USB2R1.9 101.41,9.53 ; USB2R1.9 104.63,9.53 ; 12.9,240.24 PWRSW1.S1 12.9,241.76 ; 205.9,36.32 SLOT3.B16 ; SLOT3.B16 206.7,37.12 ; SLOT3.B16 205.9,37.92 ; SLOT3.B16 205.1,37.12 ; 94.6,245.53 USB3F1.10 ; USB3F1.10 95.62,247.3 ; USB3F1.10 93.58,247.3 ; USB3F1.10 94.6,249.07 ; SLOT2.A75 181.08,96.92 ; SLOT2.A75 181.88,96.12 ; SLOT2.A75 180.28,96.12 ; SLOT2.A75 181.08,95.32 ; SLOT2.A78 179.88,99.12 ; SLOT2.A78 178.28,99.12 ; SLOT2.A78 179.08,99.92 ; SLOT2.A78 179.08,98.32 ; 219.16,58.16 SLOT4.69 ; SLOT4.69 219.16,60.11 ; SLOT4.69 220.14,59.14 ; SLOT4.69 218.18,59.14 ; 124.87,22.01 RJ45R1.18 ; RJ45R1.18 125.79,22.93 ; RJ45R1.18 125.79,21.1 ; RJ45R1.18 126.7,22.01 ; 203.1,26.12 SLOT3.B7 ; SLOT3.B7 203.9,26.92 ; SLOT3.B7 203.9,25.32 ; SLOT3.B7 204.7,26.12 ; SLOT4.30 224.24,34.71 ; SLOT4.30 225.22,33.74 ; SLOT4.30 224.24,32.76 ; SLOT4.30 223.26,33.74 ; 183.58,59.32 SLOT2.B39 ; SLOT2.B39 184.38,60.12 ; SLOT2.B39 183.58,60.92 ; SLOT2.B39 182.78,60.12 ; 20.7,1.99 HDMI1.23 ; HDMI1.23 20.7,4.81 ; HDMI1.23 19.63,3.4 ; HDMI1.23 21.77,3.4 ; 226.78,16.25 SLOT4.4 ; SLOT4.4 225.8,17.23 ; SLOT4.4 226.78,18.2 ; USB2R1.11 104.63,15.21 ; USB2R1.11 101.41,15.21 ; USB2R1.11 103.02,13.6 ; USB2R1.11 103.02,16.82 ; 182.78,78.12 SLOT2.B57 ; SLOT2.B57 184.38,78.12 ; SLOT2.B57 183.58,77.32 ; SLOT2.B57 183.58,78.92 ; 180.28,72.12 SLOT2.A51 ; SLOT2.A51 181.88,72.12 ; SLOT2.A51 181.08,72.92 ; SLOT2.A51 181.08,71.32 ; SATA3.7 123.69,200.99 ; SATA3.7 122.94,200.24 ; SATA3.7 123.69,199.49 ; SATA3.7 124.44,200.24 ; SLOT2.B29 183.58,50.92 ; SLOT2.B29 183.58,49.32 ; SLOT2.B29 182.78,50.12 ; SLOT2.B29 184.38,50.12 ; RJ45R1.4 135,12.96 ; RJ45R1.4 135,11.1 ; RJ45R1.4 135.93,12.03 ; RJ45R1.4 134.07,12.03 ; RJ45R1.25 124.93,10.93 ; RJ45R1.25 124.93,7.71 ; RJ45R1.25 123.32,9.32 ; RJ45R1.25 126.54,9.32 ; 184.78,53.12 SLOT2.B32 ; SLOT2.B32 186.38,53.12 ; SLOT2.B32 185.58,53.92 ; SLOT2.B32 185.58,52.32 ; RJ45R1.29 123.76,19.37 ; RJ45R1.29 120.54,19.37 ; RJ45R1.29 122.15,17.76 ; RJ45R1.29 122.15,20.98 ; 182.78,26.12 SLOT2.B7 ; SLOT2.B7 183.58,26.92 ; SLOT2.B7 183.58,25.32 ; SLOT2.B7 184.38,26.12 ; RJ45R1.24 142.46,6.69 ; RJ45R1.24 140.85,5.08 ; RJ45R1.24 140.85,8.3 ; RJ45R1.24 139.24,6.69 ; 160.76,35.32 SLOT1.A15 ; SLOT1.A15 159.96,36.12 ; SLOT1.A15 160.76,36.92 ; SLOT1.A15 161.56,36.12 ; USB2R1.8 113.09,15.79 ; USB2R1.8 112.16,14.86 ; USB2R1.8 113.09,13.93 ; USB2R1.8 114.02,14.86 ; 178.28,83.12 SLOT2.A62 ; SLOT2.A62 179.08,83.92 ; SLOT2.A62 179.88,83.12 ; SLOT2.A62 179.08,82.32 ; 199.4,22.32 SLOT3.A4 ; SLOT3.A4 198.6,23.12 ; SLOT3.A4 200.2,23.12 ; SLOT3.A4 199.4,23.92 ; SLOT4.110 224.24,88.05 ; SLOT4.110 223.26,87.08 ; SLOT4.110 225.22,87.08 ; SLOT4.110 224.24,86.1 ; 105.6,188.33 SATA2.4 ; SATA2.4 106.41,189.14 ; SATA2.4 105.6,189.95 ; SATA2.4 104.79,189.14 ; 178.28,67.12 SLOT2.A46 ; SLOT2.A46 179.88,67.12 ; SLOT2.A46 179.08,66.32 ; SLOT2.A46 179.08,67.92 ; SLOT2.A58 179.88,79.12 ; SLOT2.A58 179.08,79.92 ; SLOT2.A58 179.08,78.32 ; SLOT2.A58 178.28,79.12 ; 179.08,86.32 SLOT2.A66 ; SLOT2.A66 179.08,87.92 ; SLOT2.A66 178.28,87.12 ; SLOT2.A66 179.88,87.12 ; SLOT3.B13 203.9,34.92 ; SLOT3.B13 203.9,33.32 ; SLOT3.B13 203.1,34.12 ; SLOT3.B13 204.7,34.12 ; 180.28,48.12 SLOT2.A27 ; SLOT2.A27 181.08,48.92 ; SLOT2.A27 181.88,48.12 ; SLOT2.A27 181.08,47.32 ; SLOT2.A55 181.08,76.92 ; SLOT2.A55 181.88,76.12 ; SLOT2.A55 180.28,76.12 ; SLOT2.A55 181.08,75.32 ; SLOT1.B13 163.26,34.92 ; SLOT1.B13 164.06,34.12 ; SLOT1.B13 162.46,34.12 ; SLOT1.B13 163.26,33.32 ; 136.46,9.32 RJ45R1.26 ; RJ45R1.26 139.68,9.32 ; RJ45R1.26 138.07,7.71 ; RJ45R1.26 138.07,10.93 ; SATA3.8 133.79,201.42 ; SATA3.8 134.97,200.24 ; SATA3.8 132.61,200.24 ; SATA3.8 133.79,199.06 ; 112.08,188.5 SATA2.9 ; SATA2.9 113.22,189.64 ; SATA2.9 110.94,189.64 ; SATA2.9 112.08,190.78 ; 219.16,60.7 SLOT4.73 ; SLOT4.73 220.14,61.68 ; SLOT4.73 219.16,62.65 ; SLOT4.73 218.18,61.68 ; 183.58,85.32 SLOT2.B65 ; SLOT2.B65 182.78,86.12 ; SLOT2.B65 184.38,86.12 ; SLOT2.B65 183.58,86.92 ; RJ45R1.27 124.93,16.61 ; RJ45R1.27 124.93,13.39 ; RJ45R1.27 126.54,15 ; RJ45R1.27 123.32,15 ; VGA1.5 56,6.15 ; VGA1.5 54.04,6.15 ; VGA1.5 55.02,5.17 ; VGA1.5 55.02,7.13 ; SLOT2.B47 183.58,68.92 ; SLOT2.B47 183.58,67.32 ; SLOT2.B47 184.38,68.12 ; SLOT2.B47 182.78,68.12 ; SLOT2.A42 179.08,63.92 ; SLOT2.A42 179.88,63.12 ; SLOT2.A42 179.08,62.32 ; SLOT2.A42 178.28,63.12 ; SLOT1.A1 161.56,20.12 ; SLOT1.A1 159.96,20.12 ; SLOT1.A1 160.76,19.32 ; SLOT1.A1 160.76,20.92 ; USB3F1.4 85.49,245.3 ; USB3F1.4 84.7,246.09 ; USB3F1.4 83.91,245.3 ; 127.5,199.49 SATA3.4 ; SATA3.4 127.5,200.99 ; SATA3.4 126.75,200.24 ; SATA3.4 128.25,200.24 ; 235.25,195.16 HS6301.1 ; HS6301.1 235.25,198.84 ; HS6301.1 237.09,197 ; HS6301.1 233.41,197 ; USB3F2.7 109,244.59 ; USB3F2.7 108.21,243.8 ; USB3F2.7 109,243.01 ; USB3F2.7 109.79,243.8 ; RJ45R1.23 123.76,6.69 ; RJ45R1.23 122.15,8.3 ; RJ45R1.23 120.54,6.69 ; RJ45R1.23 122.15,5.08 ; SLOT2.A34 179.08,55.92 ; SLOT2.A34 179.88,55.12 ; SLOT2.A34 178.28,55.12 ; SLOT2.A34 179.08,54.32 ; 181.08,57.32 SLOT2.A37 ; SLOT2.A37 181.88,58.12 ; SLOT2.A37 181.08,58.92 ; SLOT2.A37 180.28,58.12 ; SLOT1.A12 159.56,33.12 ; SLOT1.A12 158.76,32.32 ; SLOT1.A12 157.96,33.12 ; SLOT1.A12 158.76,33.92 ; SLOT2.A24 179.08,45.92 ; SLOT2.A24 179.88,45.12 ; SLOT2.A24 179.08,44.32 ; SLOT2.A24 178.28,45.12 ; 178.28,103.12 SLOT2.A82 ; SLOT2.A82 179.88,103.12 ; SLOT2.A82 179.08,102.32 ; 185.58,22.32 SLOT2.B4 ; SLOT2.B4 185.58,23.92 ; SLOT2.B4 186.38,23.12 ; SLOT2.B4 184.78,23.12 ; 219.16,14.98 SLOT4.1 ; SLOT4.1 219.16,16.93 ; SLOT4.1 220.14,15.96 ; SLOT4.1 218.18,15.96 ; 101.79,199.49 SATA4.7 ; SATA4.7 102.54,200.24 ; SATA4.7 101.79,200.99 ; SATA4.7 101.04,200.24 ; SLOT4.26 225.22,31.2 ; SLOT4.26 224.24,30.22 ; SLOT4.26 223.26,31.2 ; SLOT4.26 224.24,32.17 ; 34.13,9.36 HDMI1.20 ; HDMI1.20 35.2,7.54 ; HDMI1.20 35.2,11.18 ; HDMI1.20 36.27,9.36 ; 112.16,12.24 USB2R1.4 ; USB2R1.4 113.09,13.17 ; USB2R1.4 114.02,12.24 ; USB2R1.4 113.09,11.31 ; SLOT4.23 222.68,29.93 ; SLOT4.23 221.7,28.95 ; SLOT4.23 220.72,29.93 ; SLOT4.23 221.7,30.9 ; 185.58,100.32 SLOT2.B80 ; SLOT2.B80 184.78,101.12 ; SLOT2.B80 186.38,101.12 ; SLOT2.B73 183.58,94.92 ; SLOT2.B73 183.58,93.32 ; SLOT2.B73 182.78,94.12 ; SLOT2.B73 184.38,94.12 ; 180.28,70.12 SLOT2.A49 ; SLOT2.A49 181.88,70.12 ; SLOT2.A49 181.08,70.92 ; SLOT2.A49 181.08,69.32 ; USB2R1.10 116.16,11.14 ; USB2R1.10 116.16,7.92 ; USB2R1.10 114.55,9.53 ; USB2R1.10 117.77,9.53 ; 181.08,79.32 SLOT2.A59 ; SLOT2.A59 181.88,80.12 ; SLOT2.A59 180.28,80.12 ; SLOT2.A59 181.08,80.92 ; 131.31,188.89 SATA1.1 ; SATA1.1 131.31,190.39 ; SATA1.1 132.06,189.64 ; SATA1.1 130.56,189.64 ; SATA2.8 100.26,189.64 ; SATA2.8 97.98,189.64 ; SATA2.8 99.12,190.78 ; SATA2.8 99.12,188.5
  L3 w1.016: 87.03,76.62 PT4508.2 ; PT4508.2 88.48,76.62 ; PT4508.2 88.48,78.07 ; PT4508.2 87.03,78.07 ; PT4603.2 35.24,110.4 ; PT4603.2 33.79,108.95 ; PT4603.2 35.24,108.95 ; PT4603.2 33.79,110.4 ; 84.24,46.23 PT4506.2 ; PT4506.2 86.14,46.23 ; PT4506.2 85.19,47.18 ; PT4506.2 85.19,45.27 ; PT4502.2 58.26,74.33 ; PT4502.2 58.26,75.78 ; PT4502.2 56.81,75.78 ; PT4502.2 56.81,74.33 ; PT4504.2 54.9,38.99 ; PT4504.2 52.99,38.99 ; PT4504.2 53.95,38.04 ; PT4504.2 53.95,39.94 ; PT4702.2 119.04,59.86 ; PT4702.2 117.59,59.86 ; PT4702.2 117.59,58.41 ; PT4702.2 119.04,58.41 ; 85.51,234.99 TC3801.2 ; TC3801.2 86.96,234.99 ; TC3801.2 86.96,236.44 ; TC3801.2 85.51,236.44 ; 44.91,204.64 PT4901.2 ; PT4901.2 43.95,205.59 ; PT4901.2 45.86,205.59 ; PT4901.2 44.91,206.54 ; 33.64,86.65 PT4602.2 ; PT4602.2 33.64,85.2 ; PT4602.2 35.09,86.65 ; PT4602.2 35.09,85.2 ; 25.91,40.47 ATX2.1 ; ATX2.1 25.91,43.17 ; ATX2.1 24.56,41.82 ; ATX2.1 27.26,41.82 ; 69.76,44.2 PT4501.2 ; PT4501.2 71.66,44.2 ; PT4501.2 70.71,45.15 ; PT4501.2 70.71,43.24 ; PT4605.2 35.09,94.53 ; PT4605.2 35.09,93.08 ; PT4605.2 33.64,94.53 ; PT4605.2 33.64,93.08 ; PT4701.2 126.91,58.41 ; PT4701.2 126.91,59.86 ; PT4701.2 125.46,58.41 ; PT4701.2 125.46,59.86 ; PT4604.2 35.12,102.53 ; PT4604.2 33.67,101.08 ; PT4604.2 35.12,101.08 ; PT4604.2 33.67,102.53 ; TC3901.2 95.72,8.67 ; TC3901.2 94.27,10.12 ; TC3901.2 95.72,10.12 ; TC3901.2 94.27,8.67 ; TC3201.2 116.93,20.66 ; TC3201.2 115.48,20.66 ; TC3201.2 116.93,19.21 ; TC3201.2 115.48,19.21 ; 64.17,77.51 PT4503.2 ; PT4503.2 64.17,78.96 ; PT4503.2 65.62,78.96 ; PT4503.2 65.62,77.51 ; PT4801.2 124.68,90.23 ; PT4801.2 123.23,90.23 ; PT4801.2 124.68,91.68 ; PT4801.2 123.23,91.68 ; 79.03,76.24 PT4507.2 ; PT4507.2 80.48,76.24 ; PT4507.2 79.03,77.69 ; PT4507.2 80.48,77.69 ; PT4601.2 11.49,102.01 ; PT4601.2 10.54,102.96 ; PT4601.2 9.59,102.01 ; PT4601.2 10.54,101.06 ; PT4505.2 72.23,76.24 ; PT4505.2 70.78,76.24 ; PT4505.2 72.23,77.69 ; PT4505.2 70.78,77.69 ; ATX2.2 25.91,38.97 ; ATX2.2 25.91,36.27 ; ATX2.2 27.26,37.62 ; ATX2.2 24.56,37.62 ; TC5301.1 208.65,11.34 ; TC5301.1 207.2,9.89 ; TC5301.1 208.65,9.89 ; TC5301.1 207.2,11.34 ; 89.37,195.72 PT5001.2 ; PT5001.2 90.82,195.72 ; PT5001.2 90.82,194.27 ; PT5001.2 89.37,194.27
  BOTTOM w0.203: 199.62,132.24 199.62,132.26 199.72,132.36 199.72,133.47 199.36,133.83 198.48,133.83 197.49,134.82 197.49,135.72 197.28,135.92 197.28,137.21 v2(197.36,137.29) 197.32,137.33 197.32,137.87 197.8,138.35 v2(197.84,138.35) 198.63,138.35 v2(198.97,138.01) 199.28,137.71 199.28,135.7 201,133.97 v2(201,132.93) 201,130.38 199.99,129.36 v2(199.97,129.36) 199.9,129.43 v2(197.29,129.43) 197.29,130.31 197.99,131.01 198.98,131.01 199.64,131.68 199.64,132.21 199.62,132.24 ; 199.62,132.24 v2(199.63,132.24)
  BOTTOM w0.279: v2(132.46,63.37) 132.92,63.83 XDP1.49 ; XDP1.20 140.42,72.57 140.56,72.72 141.78,72.72 141.92,72.58 ; 141.92,72.58 XDP1.14 ; 141.92,72.58 142.05,72.72 143.27,72.72 143.42,72.56 ; XDP1.37 135.92,63.73 v2(136.27,63.37) ; 141.67,63.69 141.67,63.69 141.57,63.69 141.32,63.45 v2(141.06,63.45) 141.01,63.5 140.84,63.5 140.42,63.93 XDP1.19 ; 141.67,63.69 141.92,63.94 XDP1.13 ; 141.67,63.69 143.17,63.69 143.42,63.94 XDP1.7 ; 143.42,72.56 143.57,72.72 144.67,72.72 144.92,72.46 XDP1.2 144.92,69.31 v2(145.43,68.79) ; 143.42,72.56 XDP1.8 ; v2(138.3,63.5) 138.48,63.5 138.92,63.94 XDP1.25 ; XDP1.32 v2(137.42,72.96) ; XDP1.50 v2(132.92,73.03) ; XDP1.38 v2(135.92,72.96) ; XDP1.59 v2(129.67,65.34) ; XDP1.26 v2(138.92,72.96) ; XDP1.31 v2(137.42,63.5)
  BOTTOM w0.508: DIMM1.187 55.76,171.61 ; DIMM1.187 56.45,170.93 ; DIMM1.187 55.76,170.24 ; DIMM1.187 55.07,170.93 ; DIMM1.20 36.21,169.41 ; DIMM1.20 36.21,168.04 ; DIMM1.20 35.52,168.73 ; DIMM1.20 36.9,168.73 ; 129.71,180.82 DIMM2.268 ; DIMM2.268 130.4,181.51 ; DIMM2.268 129.02,181.51 ; DIMM2.268 129.71,182.2 ; DIMM2.2 20.91,178.4 ; DIMM2.2 20.91,177.02 ; DIMM2.2 21.6,177.71 ; DIMM2.2 20.22,177.71 ; DIMM1.246 111.01,173.21 ; DIMM1.246 110.32,172.53 ; DIMM1.246 111.01,171.84 ; DIMM1.246 111.7,172.53 ; 112.71,180.82 DIMM2.248 ; DIMM2.248 112.02,181.51 ; DIMM2.248 113.4,181.51 ; DIMM2.248 112.71,182.2 ; 123.07,179.91 DIMM2.261 ; DIMM2.261 123.76,180.6 ; DIMM2.261 124.45,179.91 ; DIMM2.261 123.76,179.22 ; 124.61,177.02 DIMM2.118 ; DIMM2.118 125.3,177.71 ; DIMM2.118 124.61,178.4 ; DIMM2.118 123.92,177.71 ; DIMM1.55 66.65,167.13 ; DIMM1.55 65.96,167.81 ; DIMM1.55 65.96,166.44 ; DIMM1.55 65.27,167.13 ; 121.37,179.91 DIMM2.259 ; DIMM2.259 122.06,180.6 ; DIMM2.259 122.75,179.91 ; DIMM2.259 122.06,179.22 ; 110.16,175.42 DIMM2.101 ; DIMM2.101 110.16,176.8 ; DIMM2.101 109.47,176.11 ; DIMM2.101 110.85,176.11 ; DIMM2.13 30.95,176.11 ; DIMM2.13 30.26,175.42 ; DIMM2.13 29.57,176.11 ; DIMM2.13 30.26,176.8 ; 105.22,168.73 DIMM1.96 ; DIMM1.96 105.91,169.41 ; DIMM1.96 105.91,168.04 ; DIMM1.96 106.6,168.73 ; DIMM1.11 29.25,167.13 ; DIMM1.11 28.56,166.44 ; DIMM1.11 27.87,167.13 ; DIMM1.11 28.56,167.81 ; 117.12,181.51 DIMM2.254 ; DIMM2.254 118.5,181.51 ; DIMM2.254 117.81,182.2 ; DIMM2.254 117.81,180.82 ; 44.87,176.11 DIMM2.31 ; DIMM2.31 45.56,175.42 ; DIMM2.31 46.25,176.11 ; DIMM2.31 45.56,176.8 ; DIMM1.165 37.06,171.61 ; DIMM1.165 37.06,170.24 ; DIMM1.165 37.75,170.93 ; DIMM1.165 36.37,170.93 ; 66.97,167.13 DIMM1.57 ; DIMM1.57 67.66,166.44 ; DIMM1.57 68.35,167.13 ; DIMM1.57 67.66,167.81 ; DIMM2.44 56.61,178.4 ; DIMM2.44 56.61,177.02 ; DIMM2.44 55.92,177.71 ; DIMM2.44 57.3,177.71 ; SATA4.9 100.24,201.24 ; SATA4.9 99.06,200.06 ; SATA4.9 99.06,202.42 ; 231.74,197 HS6301.1 ; HS6301.1 235.25,200.51 ; HS6301.1 238.76,197 ; HS6301.1 235.25,193.49 ; SATA2.9 113.22,189.64 ; SATA2.9 110.94,189.64 ; SATA2.9 112.08,190.78 ; 113.72,172.53 DIMM1.250 ; DIMM1.250 114.41,173.21 ; DIMM1.250 114.41,171.84 ; DIMM1.250 115.1,172.53 ; 139.22,177.71 DIMM2.136 ; DIMM2.136 139.91,177.02 ; DIMM2.136 139.91,178.4 ; DIMM2.136 140.6,177.71 ; DIMM1.24 39.61,169.41 ; DIMM1.24 39.61,168.04 ; DIMM1.24 38.92,168.73 ; DIMM1.24 40.3,168.73 ; VGA1.6 65.32,5.15 ; VGA1.6 65.32,3.19 ; VGA1.6 64.35,4.17 ; VGA1.6 66.3,4.17 ; 134.12,172.53 DIMM1.274 ; DIMM1.274 134.81,173.21 ; DIMM1.274 135.5,172.53 ; DIMM1.274 134.81,171.84 ; VGA1.16 47.35,6.23 ; VGA1.16 45.3,4.17 ; VGA1.16 47.35,2.11 ; VGA1.16 49.41,4.17 ; DIMM2.4 22.61,178.4 ; DIMM2.4 21.92,177.71 ; DIMM2.4 23.3,177.71 ; DIMM2.4 22.61,177.02 ; 122.94,200.24 SATA3.7 ; SATA3.7 123.69,199.49 ; SATA3.7 124.44,200.24 ; DIMM2.9 26.86,176.8 ; DIMM2.9 26.17,176.11 ; DIMM2.9 26.86,175.42 ; DIMM2.9 27.55,176.11 ; 125.46,170.24 DIMM1.263 ; DIMM1.263 124.77,170.93 ; DIMM1.263 126.15,170.93 ; DIMM1.263 125.46,171.61 ; DIMM2.11 28.56,176.8 ; DIMM2.11 27.87,176.11 ; DIMM2.11 29.25,176.11 ; DIMM2.11 28.56,175.42 ; DIMM2.98 108.3,177.71 ; DIMM2.98 107.61,177.02 ; DIMM2.98 107.61,178.4 ; DIMM2.98 106.92,177.71 ; DIMM1.2 20.91,169.41 ; DIMM1.2 21.6,168.73 ; DIMM1.2 20.91,168.04 ; DIMM1.2 20.22,168.73 ; 133.79,199.06 SATA3.8 ; SATA3.8 132.61,200.24 ; SATA3.8 134.97,200.24 ; DIMM1.252 116.8,172.53 ; DIMM1.252 116.11,173.21 ; DIMM1.252 115.42,172.53 ; DIMM1.252 116.11,171.84 ; 44.87,167.13 DIMM1.31 ; DIMM1.31 45.56,166.44 ; DIMM1.31 46.25,167.13 ; DIMM1.31 45.56,167.81 ; 129.87,176.11 DIMM2.125 ; DIMM2.125 130.56,176.8 ; DIMM2.125 131.25,176.11 ; DIMM2.125 130.56,175.42 ; 19.63,9.36 HDMI1.21 ; HDMI1.21 20.7,11.18 ; HDMI1.21 20.7,7.54 ; HDMI1.21 21.77,9.36 ; 121.21,168.04 DIMM1.114 ; DIMM1.114 121.21,169.41 ; DIMM1.114 120.52,168.73 ; DIMM1.114 121.9,168.73 ; DIMM1.6 25,168.73 ; DIMM1.6 24.31,169.41 ; DIMM1.6 24.31,168.04 ; DIMM1.6 23.62,168.73 ; 137.52,168.73 DIMM1.134 ; DIMM1.134 138.21,168.04 ; DIMM1.134 138.9,168.73 ; DIMM1.134 138.21,169.41 ; 124.77,179.91 DIMM2.263 ; DIMM2.263 126.15,179.91 ; DIMM2.263 125.46,180.6 ; DIMM2.263 125.46,179.22 ; 132.26,175.42 DIMM2.127 ; DIMM2.127 132.26,176.8 ; DIMM2.127 132.95,176.11 ; DIMM2.127 131.57,176.11 ; DIMM2.139 142.46,176.8 ; DIMM2.139 141.77,176.11 ; DIMM2.139 143.15,176.11 ; DIMM2.139 142.46,175.42 ; DIMM1.151 25.85,170.93 ; DIMM1.151 25.16,170.24 ; DIMM1.151 25.16,171.61 ; DIMM1.151 24.47,170.93 ; USB3F1.4 84.7,246.09 ; USB3F1.4 85.49,245.3 ; USB3F1.4 83.91,245.3 ; 117.81,171.84 DIMM1.254 ; DIMM1.254 117.81,173.21 ; DIMM1.254 118.5,172.53 ; DIMM1.254 117.12,172.53 ; 38.92,177.71 DIMM2.24 ; DIMM2.24 39.61,177.02 ; DIMM2.24 40.3,177.71 ; DIMM2.24 39.61,178.4 ; DIMM1.39 52.36,167.81 ; DIMM1.39 52.36,166.44 ; DIMM1.39 51.67,167.13 ; DIMM1.39 53.05,167.13 ; DIMM1.202 69.2,172.53 ; DIMM1.202 67.82,172.53 ; DIMM1.202 68.51,171.84 ; DIMM1.202 68.51,173.21 ; 122.06,170.24 DIMM1.259 ; DIMM1.259 122.75,170.93 ; DIMM1.259 121.37,170.93 ; DIMM1.259 122.06,171.61 ; HDMI1.20 35.2,11.18 ; HDMI1.20 35.2,7.54 ; HDMI1.20 36.27,9.36 ; HDMI1.20 34.13,9.36 ; DIMM1.238 104.21,173.21 ; DIMM1.238 104.9,172.53 ; DIMM1.238 104.21,171.84 ; DIMM1.238 103.52,172.53 ; DIMM1.94 104.9,168.73 ; DIMM1.94 103.52,168.73 ; DIMM1.94 104.21,168.04 ; DIMM1.94 104.21,169.41 ; DIMM2.96 105.91,178.4 ; DIMM2.96 106.6,177.71 ; DIMM2.96 105.91,177.02 ; DIMM2.96 105.22,177.71 ; 139.06,179.22 DIMM2.279 ; DIMM2.279 139.06,180.6 ; DIMM2.279 138.37,179.91 ; DIMM2.279 139.75,179.91 ; DIMM2.270 132.1,181.51 ; DIMM2.270 130.72,181.51 ; DIMM2.270 131.41,180.82 ; DIMM2.270 131.41,182.2 ; 106.07,170.93 DIMM1.241 ; DIMM1.241 106.76,170.24 ; DIMM1.241 106.76,171.61 ; DIMM1.241 107.45,170.93 ; 42.16,170.24 DIMM1.171 ; DIMM1.171 42.16,171.61 ; DIMM1.171 42.85,170.93 ; DIMM1.171 41.47,170.93 ; 128.17,167.13 DIMM1.123 ; DIMM1.123 128.86,167.81 ; DIMM1.123 128.86,166.44 ; DIMM1.123 129.55,167.13 ; RJ45R1.4 135.93,12.03 ; RJ45R1.4 134.07,12.03 ; RJ45R1.4 135,12.96 ; RJ45R1.4 135,11.1 ; 138.07,7.71 RJ45R1.26 ; RJ45R1.26 138.07,10.93 ; RJ45R1.26 136.46,9.32 ; RJ45R1.26 139.68,9.32 ; DIMM1.118 124.61,169.41 ; DIMM1.118 123.92,168.73 ; DIMM1.118 125.3,168.73 ; DIMM1.118 124.61,168.04 ; 38.76,170.24 DIMM1.167 ; DIMM1.167 38.07,170.93 ; DIMM1.167 39.45,170.93 ; DIMM1.167 38.76,171.61 ; v2(88.54,101.36) 88.49,101.31 R902.1 ; DIMM1.33 47.26,167.81 ; DIMM1.33 46.57,167.13 ; DIMM1.33 47.26,166.44 ; DIMM1.33 47.95,167.13 ; 47.42,181.51 DIMM2.178 ; DIMM2.178 48.8,181.51 ; DIMM2.178 48.11,180.82 ; DIMM2.178 48.11,182.2 ; 103.02,7.92 USB2R1.9 ; USB2R1.9 101.41,9.53 ; USB2R1.9 104.63,9.53 ; USB2R1.9 103.02,11.14 ; DIMM2.276 136.51,182.2 ; DIMM2.276 135.82,181.51 ; DIMM2.276 137.2,181.51 ; DIMM2.276 136.51,180.82 ; 64.26,175.42 DIMM2.53 ; DIMM2.53 64.95,176.11 ; DIMM2.53 63.57,176.11 ; DIMM2.53 64.26,176.8 ; DIMM2.195 63.25,179.91 ; DIMM2.195 62.56,179.22 ; DIMM2.195 61.87,179.91 ; DIMM2.195 62.56,180.6 ; DIMM2.138 141.61,178.4 ; DIMM2.138 142.3,177.71 ; DIMM2.138 140.92,177.71 ; DIMM2.138 141.61,177.02 ; 112.16,12.24 USB2R1.4 ; USB2R1.4 113.09,13.17 ; USB2R1.4 114.02,12.24 ; USB2R1.4 113.09,11.31 ; 60.01,168.04 DIMM1.48 ; DIMM1.48 60.01,169.41 ; DIMM1.48 59.32,168.73 ; DIMM1.48 60.7,168.73 ; 32.12,172.53 DIMM1.160 ; DIMM1.160 33.5,172.53 ; DIMM1.160 32.81,173.21 ; DIMM1.160 32.81,171.84 ; DIMM2.198 65.11,182.2 ; DIMM2.198 65.11,180.82 ; DIMM2.198 65.8,181.51 ; DIMM2.198 64.42,181.51 ; 129.02,172.53 DIMM1.268 ; DIMM1.268 130.4,172.53 ; DIMM1.268 129.71,173.21 ; DIMM1.268 129.71,171.84 ; 132.61,189.64 SATA1.8 ; SATA1.8 134.97,189.64 ; SATA1.8 133.79,190.82 ; 56.77,179.91 DIMM2.189 ; DIMM2.189 57.46,179.22 ; DIMM2.189 57.46,180.6 ; DIMM2.189 58.15,179.91 ; 58.31,177.02 DIMM2.46 ; DIMM2.46 59,177.71 ; DIMM2.46 57.62,177.71 ; DIMM2.46 58.31,178.4 ; DIMM1.37 51.35,167.13 ; DIMM1.37 50.66,167.81 ; DIMM1.37 49.97,167.13 ; DIMM1.37 50.66,166.44 ; 94.6,249.07 USB3F1.10 95.62,247.3 ; DIMM1.139 143.15,167.13 ; DIMM1.139 142.46,166.44 ; DIMM1.139 142.46,167.81 ; DIMM1.139 141.77,167.13 ; 48.96,175.42 DIMM2.35 ; DIMM2.35 49.65,176.11 ; DIMM2.35 48.27,176.11 ; DIMM2.35 48.96,176.8 ; DIMM2.241 107.45,179.91 ; DIMM2.241 106.76,180.6 ; DIMM2.241 106.07,179.91 ; DIMM2.241 106.76,179.22 ; SATA3.9 122.14,201.24 ; SATA3.9 119.78,201.24 ; SATA3.9 120.96,202.42 ; SATA3.9 120.96,200.06 ; DIMM1.283 143.15,170.93 ; DIMM1.283 142.46,170.24 ; DIMM1.283 142.46,171.61 ; DIMM1.283 141.77,170.93 ; DIMM2.48 60.7,177.71 ; DIMM2.48 60.01,178.4 ; DIMM2.48 59.32,177.71 ; DIMM2.48 60.01,177.02 ; DIMM2.238 104.21,182.2 ; DIMM2.238 103.52,181.51 ; DIMM2.238 104.21,180.82 ; DIMM2.238 104.9,181.51 ; 27.71,171.84 DIMM1.154 ; DIMM1.154 28.4,172.53 ; DIMM1.154 27.02,172.53 ; DIMM1.154 27.71,173.21 ; 123.32,9.32 RJ45R1.25 ; RJ45R1.25 124.93,7.71 ; RJ45R1.25 126.54,9.32 ; RJ45R1.25 124.93,10.93 ; SATA3.1 132.06,200.24 ; SATA3.1 131.31,199.49 ; SATA3.1 130.56,200.24 ; 48.96,166.44 DIMM1.35 ; DIMM1.35 48.96,167.81 ; DIMM1.35 48.27,167.13 ; DIMM1.35 49.65,167.13 ; DIMM2.239 105.75,179.91 ; DIMM2.239 105.06,180.6 ; DIMM2.239 104.37,179.91 ; DIMM2.239 105.06,179.22 ; VGA1.17 72.35,6.23 ; VGA1.17 70.29,4.17 ; VGA1.17 72.35,2.11 ; VGA1.17 74.4,4.17 ; DIMM2.257 120.36,180.6 ; DIMM2.257 121.05,179.91 ; DIMM2.257 120.36,179.22 ; DIMM2.257 119.67,179.91 ; 132.26,166.44 DIMM1.127 ; DIMM1.127 132.26,167.81 ; DIMM1.127 132.95,167.13 ; DIMM1.127 131.57,167.13 ; DIMM1.131 135.66,167.81 ; DIMM1.131 136.35,167.13 ; DIMM1.131 135.66,166.44 ; DIMM1.131 134.97,167.13 ; DIMM1.270 131.41,173.21 ; DIMM1.270 132.1,172.53 ; DIMM1.270 130.72,172.53 ; DIMM1.270 131.41,171.84 ; 58.47,170.93 DIMM1.191 ; DIMM1.191 59.16,170.24 ; DIMM1.191 59.85,170.93 ; DIMM1.191 59.16,171.61 ; 122.22,177.71 DIMM2.116 ; DIMM2.116 122.91,177.02 ; DIMM2.116 122.91,178.4 ; DIMM2.116 123.6,177.71 ; 37.91,177.02 DIMM2.22 ; DIMM2.22 37.91,178.4 ; DIMM2.22 38.6,177.71 ; DIMM2.22 37.22,177.71 ; DIMM1.46 58.31,169.41 ; DIMM1.46 58.31,168.04 ; DIMM1.46 57.62,168.73 ; DIMM1.46 59,168.73 ; 139.24,6.69 RJ45R1.24 ; RJ45R1.24 140.85,5.08 ; RJ45R1.24 142.46,6.69 ; RJ45R1.24 140.85,8.3 ; 115.42,181.51 DIMM2.252 ; DIMM2.252 116.11,182.2 ; DIMM2.252 116.11,180.82 ; DIMM2.252 116.8,181.51 ; 21.92,168.73 DIMM1.4 ; DIMM1.4 22.61,169.41 ; DIMM1.4 23.3,168.73 ; DIMM1.4 22.61,168.04 ; 114.57,167.13 DIMM1.107 ; DIMM1.107 115.26,166.44 ; DIMM1.107 115.26,167.81 ; DIMM1.107 115.95,167.13 ; DIMM2.55 66.65,176.11 ; DIMM2.55 65.96,175.42 ; DIMM2.55 65.96,176.8 ; DIMM2.55 65.27,176.11 ; 109.41,189.95 SATA2.7 110.22,189.14 ; 43.01,168.04 DIMM1.28 ; DIMM1.28 42.32,168.73 ; DIMM1.28 43.7,168.73 ; DIMM1.28 43.01,169.41 ; USB2R1.11 104.63,15.21 ; USB2R1.11 101.41,15.21 ; USB2R1.11 103.02,13.6 ; 135.66,175.42 DIMM2.131 ; DIMM2.131 135.66,176.8 ; DIMM2.131 136.35,176.11 ; DIMM2.131 134.97,176.11 ; SATA4.7 102.54,200.24 ; SATA4.7 101.04,200.24 ; SATA4.7 101.79,200.99 ; SATA4.7 101.79,199.49 ; 88.9,4.75 FANS1.1 ; FANS1.1 88.9,6.68 ; FANS1.1 89.87,5.71 ; FANS1.1 87.93,5.71 ; 101.79,189.95 SATA2.1 100.98,189.14 ; 109.47,167.13 DIMM1.101 ; DIMM1.101 110.16,166.44 ; DIMM1.101 110.16,167.81 ; DIMM1.101 110.85,167.13 ; 51.67,176.11 DIMM2.39 ; DIMM2.39 52.36,176.8 ; DIMM2.39 53.05,176.11 ; DIMM2.39 52.36,175.42 ; DIMM2.105 114.25,176.11 ; DIMM2.105 113.56,176.8 ; DIMM2.105 113.56,175.42 ; DIMM2.105 112.87,176.11 ; 56.77,170.93 DIMM1.189 ; DIMM1.189 57.46,171.61 ; DIMM1.189 58.15,170.93 ; DIMM1.189 57.46,170.24 ; DIMM1.147 22.45,170.93 ; DIMM1.147 21.76,170.24 ; DIMM1.147 21.07,170.93 ; DIMM1.147 21.76,171.61 ; 115.26,175.42 DIMM2.107 ; DIMM2.107 114.57,176.11 ; DIMM2.107 115.26,176.8 ; DIMM2.107 115.95,176.11 ; DIMM2.184 53.21,182.2 ; DIMM2.184 52.52,181.51 ; DIMM2.184 53.21,180.82 ; DIMM2.184 53.9,181.51 ; 205.1,23.12 SLOT3.B4 ; SLOT3.B4 206.7,23.12 ; SLOT3.B4 205.9,23.92 ; 32.97,176.11 DIMM2.17 ; DIMM2.17 34.35,176.11 ; DIMM2.17 33.66,176.8 ; DIMM2.17 33.66,175.42 ; 64.42,172.53 DIMM1.198 ; DIMM1.198 65.8,172.53 ; DIMM1.198 65.11,173.21 ; DIMM1.198 65.11,171.84 ; 34.13,3.4 HDMI1.22 ; HDMI1.22 36.27,3.4 ; HDMI1.22 35.2,1.99 ; HDMI1.22 35.2,4.81 ; 24.47,179.91 DIMM2.151 ; DIMM2.151 25.16,179.22 ; DIMM2.151 25.85,179.91 ; DIMM2.151 25.16,180.6 ; 67.82,181.51 DIMM2.202 ; DIMM2.202 69.2,181.51 ; DIMM2.202 68.51,180.82 ; DIMM2.202 68.51,182.2 ; DIMM1.13 30.95,167.13 ; DIMM1.13 30.26,166.44 ; DIMM1.13 29.57,167.13 ; DIMM1.13 30.26,167.81 ; DIMM1.17 34.35,167.13 ; DIMM1.17 32.97,167.13 ; DIMM1.17 33.66,167.81 ; DIMM1.17 33.66,166.44 ; DIMM1.279 139.06,171.61 ; DIMM1.279 139.75,170.93 ; DIMM1.279 139.06,170.24 ; DIMM1.279 138.37,170.93 ; DIMM1.22 38.6,168.73 ; DIMM1.22 37.22,168.73 ; DIMM1.22 37.91,169.41 ; DIMM1.22 37.91,168.04 ; 125.62,177.71 DIMM2.120 ; DIMM2.120 126.31,178.4 ; DIMM2.120 127,177.71 ; DIMM2.120 126.31,177.02 ; 56.13,5.26 56.16,5.23 VGA1.10 55.7,4.17 55.02,4.85 VGA1.5 ; DIMM1.162 35.2,172.53 ; DIMM1.162 33.82,172.53 ; DIMM1.162 34.51,173.21 ; DIMM1.162 34.51,171.84 ; 66.12,172.53 DIMM1.200 ; DIMM1.200 67.5,172.53 ; DIMM1.200 66.81,173.21 ; DIMM1.200 66.81,171.84 ; 133.11,180.82 DIMM2.272 ; DIMM2.272 133.8,181.51 ; DIMM2.272 133.11,182.2 ; DIMM2.272 132.42,181.51 ; DIMM2.156 29.41,182.2 ; DIMM2.156 30.1,181.51 ; DIMM2.156 29.41,180.82 ; DIMM2.156 28.72,181.51 ; DIMM1.169 41.15,170.93 ; DIMM1.169 40.46,171.61 ; DIMM1.169 40.46,170.24 ; DIMM1.169 39.77,170.93 ; DIMM2.28 43.7,177.71 ; DIMM2.28 43.01,178.4 ; DIMM2.28 42.32,177.71 ; DIMM2.28 43.01,177.02 ; 101.58,247.3 USB3F2.11 ; USB3F2.11 103.62,247.3 ; USB3F2.11 102.6,249.07 ; USB3F2.11 102.6,245.53 ; 49.81,171.84 DIMM1.180 ; DIMM1.180 49.81,173.21 ; DIMM1.180 49.12,172.53 ; DIMM1.180 50.5,172.53 ; 132.42,172.53 DIMM1.272 ; DIMM1.272 133.11,173.21 ; DIMM1.272 133.8,172.53 ; DIMM1.272 133.11,171.84 ; TC3801.2 84.84,235.71 ; 66.81,180.82 DIMM2.200 ; DIMM2.200 66.12,181.51 ; DIMM2.200 67.5,181.51 ; DIMM2.200 66.81,182.2 ; DIMM2.274 134.81,182.2 ; DIMM2.274 134.81,180.82 ; DIMM2.274 134.12,181.51 ; DIMM2.274 135.5,181.51 ; 49.12,181.51 DIMM2.180 ; DIMM2.180 49.81,182.2 ; DIMM2.180 49.81,180.82 ; DIMM2.180 50.5,181.51 ; DIMM1.9 27.55,167.13 ; DIMM1.9 26.86,167.81 ; DIMM1.9 26.86,166.44 ; DIMM1.9 26.17,167.13 ; 113.56,166.44 DIMM1.105 ; DIMM1.105 113.56,167.81 ; DIMM1.105 114.25,167.13 ; DIMM1.105 112.87,167.13 ; 126.31,168.04 DIMM1.120 ; DIMM1.120 126.31,169.41 ; DIMM1.120 127,168.73 ; DIMM1.120 125.62,168.73 ; DIMM2.250 114.41,182.2 ; DIMM2.250 115.1,181.51 ; DIMM2.250 113.72,181.51 ; DIMM2.250 114.41,180.82 ; 123.32,15 RJ45R1.27 ; RJ45R1.27 124.93,13.39 ; RJ45R1.27 126.54,15 ; DIMM2.283 142.46,180.6 ; DIMM2.283 142.46,179.22 ; DIMM2.283 143.15,179.91 ; DIMM2.283 141.77,179.91 ; DIMM2.103 111.86,176.8 ; DIMM2.103 111.17,176.11 ; DIMM2.103 112.55,176.11 ; DIMM2.103 111.86,175.42 ; DIMM2.165 37.75,179.91 ; DIMM2.165 37.06,179.22 ; DIMM2.165 37.06,180.6 ; DIMM2.165 36.37,179.91 ; 113.09,13.93 USB2R1.8 ; USB2R1.8 113.09,15.79 ; USB2R1.8 112.16,14.86 ; 30.42,172.53 DIMM1.158 ; DIMM1.158 31.8,172.53 ; DIMM1.158 31.11,171.84 ; DIMM1.158 31.11,173.21 ; JMP1.4 230.2,178.28 228.79,179.69 v2(228.79,181.94) ; 80.78,247.3 USB3F1.11 ; USB3F1.11 81.8,245.53 ; USB3F1.11 82.82,247.3 ; USB3F1.11 81.8,249.07 ; DIMM2.149 23.46,180.6 ; DIMM2.149 24.15,179.91 ; DIMM2.149 23.46,179.22 ; DIMM2.149 22.77,179.91 ; 119.51,177.02 DIMM2.112 ; DIMM2.112 118.82,177.71 ; DIMM2.112 120.2,177.71 ; DIMM2.112 119.51,178.4 ; DIMM1.138 141.61,169.41 ; DIMM1.138 141.61,168.04 ; DIMM1.138 140.92,168.73 ; DIMM1.138 142.3,168.73 ; DIMM1.178 48.11,173.21 ; DIMM1.178 47.42,172.53 ; DIMM1.178 48.11,171.84 ; DIMM1.178 48.8,172.53 ; 31.96,175.42 DIMM2.15 ; DIMM2.15 31.27,176.11 ; DIMM2.15 31.96,176.8 ; DIMM2.15 32.65,176.11 ; DIMM2.162 35.2,181.51 ; DIMM2.162 34.51,182.2 ; DIMM2.162 33.82,181.51 ; DIMM2.162 34.51,180.82 ; DIMM1.176 46.41,173.21 ; DIMM1.176 47.1,172.53 ; DIMM1.176 46.41,171.84 ; DIMM1.176 45.72,172.53 ; 54.91,177.02 DIMM2.42 ; DIMM2.42 55.6,177.71 ; DIMM2.42 54.91,178.4 ; DIMM2.42 54.22,177.71 ; 111.89,199.06 SATA4.8 ; SATA4.8 113.07,200.24 ; SATA4.8 111.89,201.42 ; SATA4.8 110.71,200.24 ; DIMM1.44 56.61,169.41 ; DIMM1.44 56.61,168.04 ; DIMM1.44 55.92,168.73 ; DIMM1.44 57.3,168.73 ; 40.46,179.22 DIMM2.169 ; DIMM2.169 39.77,179.91 ; DIMM2.169 41.15,179.91 ; DIMM2.169 40.46,180.6 ; 60.86,170.24 DIMM1.193 ; DIMM1.193 60.17,170.93 ; DIMM1.193 61.55,170.93 ; DIMM1.193 60.86,171.61 ; 111.17,167.13 DIMM1.103 ; DIMM1.103 112.55,167.13 ; DIMM1.103 111.86,166.44 ; DIMM1.103 111.86,167.81 ; 116.42,247.3 USB3F2.10 115.4,249.07 ; DIMM2.123 128.86,176.8 ; DIMM2.123 129.55,176.11 ; DIMM2.123 128.86,175.42 ; DIMM2.123 128.17,176.11 ; HDMI1.23 20.7,4.81 ; HDMI1.23 19.63,3.4 ; HDMI1.23 20.7,1.99 ; HDMI1.23 21.77,3.4 ; DIMM2.191 59.85,179.91 ; DIMM2.191 59.16,179.22 ; DIMM2.191 59.16,180.6 ; DIMM2.191 58.47,179.91 ; 119.67,170.93 DIMM1.257 ; DIMM1.257 120.36,170.24 ; DIMM1.257 121.05,170.93 ; DIMM1.257 120.36,171.61 ; 120.54,6.69 RJ45R1.23 ; RJ45R1.23 122.15,5.08 ; RJ45R1.23 123.76,6.69 ; RJ45R1.23 122.15,8.3 ; DIMM2.281 141.45,179.91 ; DIMM2.281 140.07,179.91 ; DIMM2.281 140.76,179.22 ; DIMM2.281 140.76,180.6 ; 120.96,189.46 SATA1.9 ; SATA1.9 119.78,190.64 ; SATA1.9 122.14,190.64 ; SATA1.9 120.96,191.82 ; DIMM1.149 23.46,171.61 ; DIMM1.149 22.77,170.93 ; DIMM1.149 24.15,170.93 ; DIMM1.149 23.46,170.24 ; DIMM1.281 140.76,171.61 ; DIMM1.281 141.45,170.93 ; DIMM1.281 140.76,170.24 ; DIMM1.281 140.07,170.93 ; 51.51,171.84 DIMM1.182 ; DIMM1.182 51.51,173.21 ; DIMM1.182 50.82,172.53 ; DIMM1.182 52.2,172.53 ; VGA1.5 53.67,6.15 ; VGA1.5 55.02,7.59 ; 134.07,14.65 RJ45R1.8 ; RJ45R1.8 135,13.72 ; RJ45R1.8 135,15.58 ; RJ45R1.8 135.93,14.65 ; DIMM1.265 127.16,171.61 ; DIMM1.265 126.47,170.93 ; DIMM1.265 127.16,170.24 ; DIMM1.265 127.85,170.93 ; DIMM2.37 51.35,176.11 ; DIMM2.37 49.97,176.11 ; DIMM2.37 50.66,175.42 ; DIMM2.37 50.66,176.8 ; DIMM2.20 36.21,178.4 ; DIMM2.20 36.21,177.02 ; DIMM2.20 36.9,177.71 ; DIMM2.20 35.52,177.71 ; VGA1.7 64.01,4.17 ; VGA1.7 62.06,4.17 ; VGA1.7 63.03,5.15 ; VGA1.7 63.03,3.19 ; DIMM1.116 123.6,168.73 ; DIMM1.116 122.91,168.04 ; DIMM1.116 122.91,169.41 ; DIMM1.116 122.22,168.73 ; DIMM2.171 42.16,180.6 ; DIMM2.171 42.16,179.22 ; DIMM2.171 42.85,179.91 ; DIMM2.171 41.47,179.91 ; 55.07,179.91 DIMM2.187 ; DIMM2.187 55.76,179.22 ; DIMM2.187 55.76,180.6 ; DIMM2.187 56.45,179.91 ; DIMM1.173 43.86,171.61 ; DIMM1.173 43.17,170.93 ; DIMM1.173 44.55,170.93 ; DIMM1.173 43.86,170.24 ; v2(149.61,61.95) 149.61,62.13 149.73,62.26 R9904.1 ; DIMM2.50 62.4,177.71 ; DIMM2.50 61.71,178.4 ; DIMM2.50 61.71,177.02 ; DIMM2.50 61.02,177.71 ; 116.96,166.44 DIMM1.109 ; DIMM1.109 116.96,167.81 ; DIMM1.109 116.27,167.13 ; DIMM1.109 117.65,167.13 ; DIMM1.42 54.91,169.41 ; DIMM1.42 54.91,168.04 ; DIMM1.42 55.6,168.73 ; DIMM1.42 54.22,168.73 ; USB2R1.10 116.16,11.14 ; USB2R1.10 116.16,7.92 ; USB2R1.10 114.55,9.53 ; 128.25,189.64 SATA1.4 126.75,189.64 ; 118.82,168.73 DIMM1.112 ; DIMM1.112 119.51,168.04 ; DIMM1.112 119.51,169.41 ; DIMM1.112 120.2,168.73 ; 51.51,180.82 DIMM2.182 ; DIMM2.182 51.51,182.2 ; DIMM2.182 50.82,181.51 ; DIMM2.182 52.2,181.51 ; SATA3.4 128.25,200.24 ; SATA3.4 127.5,199.49 ; SATA3.4 126.75,200.24 ; 62.56,170.24 DIMM1.195 ; DIMM1.195 63.25,170.93 ; DIMM1.195 61.87,170.93 ; DIMM1.195 62.56,171.61 ; SATA4.4 106.35,200.24 ; SATA4.4 105.6,199.49 ; SATA4.4 104.85,200.24 ; 143.31,168.04 DIMM1.140 ; DIMM1.140 143.31,169.41 ; DIMM1.140 142.62,168.73 ; DIMM1.129 133.96,167.81 ; DIMM1.129 133.96,166.44 ; DIMM1.129 134.65,167.13 ; DIMM1.129 133.27,167.13 ; 61.02,168.73 DIMM1.50 ; DIMM1.50 61.71,168.04 ; DIMM1.50 62.4,168.73 ; DIMM1.50 61.71,169.41 ; 38.76,179.22 DIMM2.167 ; DIMM2.167 38.07,179.91 ; DIMM2.167 38.76,180.6 ; DIMM2.167 39.45,179.91 ; 41.31,168.04 DIMM1.26 ; DIMM1.26 40.62,168.73 ; DIMM1.26 41.31,169.41 ; DIMM1.26 42,168.73 ; DIMM2.26 41.31,178.4 ; DIMM2.26 42,177.71 ; DIMM2.26 40.62,177.71 ; DIMM2.26 41.31,177.02 ; R2705.1 59.56,229.24 v2(59.69,229.11) ; DIMM1.239 105.75,170.93 ; DIMM1.239 105.06,171.61 ; DIMM1.239 105.06,170.24 ; DIMM1.239 104.37,170.93 ; SATA2.8 99.12,190.78 ; SATA2.8 100.26,189.64 ; SATA2.8 97.98,189.64 ; 133.27,176.11 DIMM2.129 ; DIMM2.129 133.96,175.42 ; DIMM2.129 134.65,176.11 ; DIMM2.129 133.96,176.8 ; DIMM2.158 31.8,181.51 ; DIMM2.158 31.11,180.82 ; DIMM2.158 31.11,182.2 ; DIMM2.158 30.42,181.51 ; DIMM2.6 25,177.71 ; DIMM2.6 23.62,177.71 ; DIMM2.6 24.31,177.02 ; DIMM2.6 24.31,178.4 ; 53.21,171.84 DIMM1.184 ; DIMM1.184 53.9,172.53 ; DIMM1.184 52.52,172.53 ; DIMM1.184 53.21,173.21 ; 139.22,168.73 DIMM1.136 ; DIMM1.136 140.6,168.73 ; DIMM1.136 139.91,169.41 ; DIMM1.136 139.91,168.04 ; DIMM1.98 108.3,168.73 ; DIMM1.98 106.92,168.73 ; DIMM1.98 107.61,169.41 ; DIMM1.98 107.61,168.04 ; 104.21,177.02 DIMM2.94 ; DIMM2.94 104.9,177.71 ; DIMM2.94 103.52,177.71 ; DIMM2.94 104.21,178.4 ; 203.9,25.32 SLOT3.B7 ; SLOT3.B7 203.1,26.12 ; SLOT3.B7 203.9,26.92 ; SLOT3.B7 204.7,26.12 ; USB3F2.4 106.29,245.3 ; USB3F2.4 105.5,246.09 ; USB3F2.4 104.71,245.3 ; DIMM2.134 138.21,178.4 ; DIMM2.134 138.9,177.71 ; DIMM2.134 138.21,177.02 ; DIMM2.134 137.52,177.71 ; 111.01,180.82 DIMM2.246 ; DIMM2.246 110.32,181.51 ; DIMM2.246 111.7,181.51 ; DIMM2.246 111.01,182.2 ; 64.26,166.44 DIMM1.53 ; DIMM1.53 63.57,167.13 ; DIMM1.53 64.26,167.81 ; DIMM1.53 64.95,167.13 ; R903.1 94.49,128.34 v2(94.03,127.88) ; 130.56,189.64 SATA1.1 ; SATA1.1 131.31,190.39 ; SATA1.1 132.06,189.64 ; DIMM2.33 47.95,176.11 ; DIMM2.33 47.26,176.8 ; DIMM2.33 47.26,175.42 ; DIMM2.33 46.57,176.11 ; 122.94,189.64 SATA1.7 124.44,189.64 ; DIMM2.173 44.55,179.91 ; DIMM2.173 43.17,179.91 ; DIMM2.173 43.86,179.22 ; DIMM2.173 43.86,180.6 ; DIMM1.243 108.46,171.61 ; DIMM1.243 107.77,170.93 ; DIMM1.243 108.46,170.24 ; DIMM1.243 109.15,170.93 ; DIMM2.109 117.65,176.11 ; DIMM2.109 116.27,176.11 ; DIMM2.109 116.96,176.8 ; DIMM2.109 116.96,175.42 ; DIMM1.125 131.25,167.13 ; DIMM1.125 130.56,167.81 ; DIMM1.125 129.87,167.13 ; DIMM1.125 130.56,166.44 ; SATA4.1 109.41,200.99 ; SATA4.1 109.41,199.49 ; SATA4.1 108.66,200.24 ; SATA4.1 110.16,200.24 ; DIMM1.248 113.4,172.53 ; DIMM1.248 112.71,173.21 ; DIMM1.248 112.71,171.84 ; DIMM1.248 112.02,172.53 ; 12.9,240.24 PWRSW1.S1 12.9,241.76 ; DIMM1.261 124.45,170.93 ; DIMM1.261 123.76,171.61 ; DIMM1.261 123.07,170.93 ; DIMM1.261 123.76,170.24 ; v2(215.85,217.68) 216.5,217.68 v2(218.41,215.77) 218.95,216.31 v2(218.95,217.3) ; DIMM2.154 27.71,182.2 ; DIMM2.154 27.71,180.82 ; DIMM2.154 27.02,181.51 ; DIMM2.154 28.4,181.51 ; DIMM2.265 127.16,180.6 ; DIMM2.265 127.85,179.91 ; DIMM2.265 126.47,179.91 ; DIMM2.265 127.16,179.22 ; DIMM2.114 121.21,178.4 ; DIMM2.114 121.9,177.71 ; DIMM2.114 120.52,177.71 ; DIMM2.114 121.21,177.02 ; 46.41,180.82 DIMM2.176 ; DIMM2.176 45.72,181.51 ; DIMM2.176 47.1,181.51 ; DIMM2.176 46.41,182.2 ; 21.76,179.22 DIMM2.147 ; DIMM2.147 21.07,179.91 ; DIMM2.147 22.45,179.91 ; DIMM2.147 21.76,180.6 ; 60.86,179.22 DIMM2.193 ; DIMM2.193 61.55,179.91 ; DIMM2.193 60.86,180.6 ; DIMM2.193 60.17,179.91 ; 138.07,13.39 RJ45R1.28 ; RJ45R1.28 136.46,15 ; RJ45R1.28 139.68,15 ; 107.77,179.91 DIMM2.243 ; DIMM2.243 108.46,180.6 ; DIMM2.243 108.46,179.22 ; DIMM2.243 109.15,179.91 ; 28.72,172.53 DIMM1.156 ; DIMM1.156 29.41,173.21 ; DIMM1.156 29.41,171.84 ; DIMM1.156 30.1,172.53 ; 32.12,181.51 DIMM2.160 ; DIMM2.160 32.81,180.82 ; DIMM2.160 33.5,181.51 ; DIMM2.160 32.81,182.2 ; DIMM1.15 31.96,167.81 ; DIMM1.15 32.65,167.13 ; DIMM1.15 31.27,167.13 ; DIMM1.15 31.96,166.44 ; 67.66,175.42 DIMM2.57 ; DIMM2.57 68.35,176.11 ; DIMM2.57 66.97,176.11 ; DIMM2.57 67.66,176.8 ; 135.82,172.53 DIMM1.276 ; DIMM1.276 136.51,173.21 ; DIMM1.276 137.2,172.53 ; DIMM1.276 136.51,171.84 ; 131.7,62.48 131.7,62.81 132.26,63.37 v2(132.46,63.37) ; 61.72,4.17 VGA1.8 60.75,5.15
  BOTTOM w1.016: TC1101.2 77.65,159.68 ; TC1101.2 76.69,158.72 ; TC1101.2 77.65,157.77 ; TC1101.2 78.6,158.72 ; 206.97,11.57 TC5301.1 ; TC5301.1 208.88,9.66 ; TC5301.1 208.88,11.57 ; TC5301.1 206.97,9.66 ; 233.2,116.52 PT5101.2 ; PT5101.2 233.2,118.43 ; PT5101.2 234.15,117.47
  vias: v1(6.22,209.17) v1(11.56,138.05) v1(23.14,245.19) v1(30.73,136.27) v1(39.62,208.58) v1(53.49,206.91) v1(56.69,117.93) v1(57.43,248.39) v1(60.63,16.66) v1(70.66,20.42) v1(79.4,203.81) v1(87,139.7) v1(101.47,118.49) v1(112.93,38.76) v1(124.69,45.82) v1(132.21,143.26) v1(152.78,210.57) v1(202.56,5.26) v1(231.72,209.96) v1(235.59,227.58) v2(1.02,229.83) v2(1.02,224.75) v2(1.02,219.67) v2(1.02,214.59) v2(1.02,209.51) v2(1.02,204.43) v2(1.02,199.35) v2(1.02,194.27) v2(1.02,189.19) v2(1.02,184.11) v2(1.02,179.03) v2(1.02,173.95) v2(1.02,168.87) v2(1.02,163.79) v2(1.02,158.71) v2(1.02,153.63) v2(1.02,148.55) v2(1.02,143.47) v2(1.02,138.39) v2(1.02,133.31) v2(1.02,128.23) v2(1.02,123.15) v2(1.02,118.07) v2(1.02,112.99) v2(1.02,107.91) v2(1.02,102.83) v2(1.02,97.75) v2(1.02,92.67) v2(1.02,87.59) v2(1.02,82.51) v2(1.02,77.43) v2(1.02,72.35) v2(1.02,67.27) v2(1.02,62.19) v2(1.02,57.11) v2(1.02,52.03) v2(1.02,46.95) v2(1.02,41.87) v2(1.02,26.63) v2(2.16,27.18) v2(3.17,39.37) v2(5.84,39.37) v2(6.6,27.05) v2(10.02,246.24) v2(10.02,236.08) v2(10.03,234.57) v2(10.54,233.48) v2(12.45,228.6) v2(15.12,248.18) v2(15.82,58.55) v2(16.46,59.18) v2(17.14,59.79) v2(17.2,125.25) v2(17.75,58.5) v2(18,125.25) v2(18.03,69.85) v2(18.34,59.26) v2(18.92,69.85) v2(19.3,1.02) v2(19.43,2.16) v2(19.56,11.43) v2(19.81,71.63) v2(19.81,70.74) v2(19.81,69.85) v2(19.81,68.96) v2(19.81,68.07) v2(19.94,14.03) v2(19.95,145.04) v2(20.05,150.88) v2(20.05,148.72) v2(20.07,146.94) v2(20.31,160.28) v2(20.31,158.12) v2(20.31,155.45) v2(20.31,153.29) v2(20.32,12.45) v2(20.45,15.24) v2(20.45,6.35) v2(20.52,251.9) v2(20.57,5.33) v2(20.7,69.85) v2(21.59,228.85) v2(21.59,69.85) v2(22.34,144.27) v2(22.48,227.46) v2(22.99,3.94) v2(23.24,2.29) v2(23.57,142.95) v2(23.9,142.04) v2(24.51,3.81) v2(24.77,1.91) v2(24.92,140.67) v2(25.91,3.3) v2(25.96,139.45) v2(27.09,1.02) v2(27.18,234.19) v2(27.18,2.03) v2(27.43,3.81) v2(28.83,2.79) v2(29.46,251.84) v2(30.23,231.14) v2(30.61,1.91) v2(30.99,229.11) v2(30.99,3.68) v2(31.42,191.8) v2(31.62,242.19) v2(31.88,233.55) v2(32.03,192.41) v2(32.03,191.13) v2(32.05,191.77) v2(32.17,1.02) v2(32.69,191.8) v2(33.53,2.41) v2(33.58,244.14) v2(34.29,230.63) v2(34.54,227.08) v2(35.05,245.49) v2(35.59,253.57) v2(36.83,11.05) v2(36.83,8.13) v2(37.25,1.02) v2(37.97,3.56) v2(38.43,117.94) v2(38.73,226.95) v2(39.12,47.17) v2(39.12,46.29) v2(39.12,2.29) v2(39.37,117.03) v2(39.46,223.05) v2(39.62,233.17) v2(40.51,233.93) v2(40.51,233.17) v2(40.51,232.41) v2(40.67,223.06) v2(40.75,115.73) v2(40.77,3.81) v2(40.89,1.91) v2(41.27,233.17) v2(41.79,114.69) v2(42.06,245.44) v2(42.33,1.02) v2(42.88,113.57) v2(42.93,5.21) v2(42.93,2.79) v2(43.43,237.62) v2(43.74,112.68) v2(43.94,238.63) v2(44.07,3.68) v2(44.07,2.49) v2(44.35,253.57) v2(44.58,6.99) v2(44.58,5.79) v2(44.7,243.21) v2(44.86,240.5) v2(47.41,1.02) v2(48.39,8) v2(48.39,6.81) v2(49.28,191.03) v2(49.68,253.57) v2(49.91,191.69) v2(49.91,191.06) v2(49.89,190.42) v2(50.04,3.3) v2(50.04,2.11) v2(50.55,191.03) v2(52.32,15.88) v2(52.32,14.68) v2(52.45,8.38) v2(52.45,7.19) v2(52.49,1.02) v2(54,253.57) v2(56.01,9.78) v2(56.01,8.59) v2(56.64,51.23) v2(58.06,12.75) v2(58.06,10.67) v2(58.12,9.58) v2(60.3,253.57) v2(61.11,22.25) v2(62.18,23.22) v2(62.22,22.25) v2(62.18,21.49) v2(63.17,22.23) v2(65.15,12.45) v2(66.17,13.59) v2(66.55,14.99) v2(67.73,1.02) v2(68.83,15.88) v2(68.83,14.61) v2(68.83,13.21) v2(68.83,12.06) v2(68.83,10.79) v2(68.83,9.6) v2(68.83,8.38) v2(68.86,7.57) v2(69.34,3.43) v2(69.34,2.24) v2(69.52,4.93) v2(70.15,6.15) v2(70.48,15.88) v2(70.48,14.61) v2(70.48,13.21) v2(70.48,12.06) v2(70.48,10.79) v2(70.48,9.6) v2(70.48,8.38) v2(70.48,7.19) v2(70.86,112.98) v2(70.86,112.34) v2(70.86,109.37) v2(70.86,108.74) v2(72.01,15.75) v2(72.01,14.48) v2(72.01,13.08) v2(72.01,11.94) v2(72.01,10.67) v2(72.01,9.47) v2(72.01,8.26) v2(72.01,7.06) v2(72.81,1.02) v2(73.02,112.98) v2(73.02,112.34) v2(73.02,109.37) v2(73.02,108.74) v2(74.46,124.22) v2(74.96,114.56) v2(74.96,113.92) v2(75.18,112.93) v2(75.18,112.3) v2(75.18,107.44) v2(75.18,106.81) v2(75.51,54.06) v2(75.56,6.1) v2(75.56,4.9) v2(75.69,3.43) v2(75.69,2.24) v2(76.19,186.7) v2(76.2,11.3) v2(76.69,187.21) v2(77.34,111) v2(77.34,110.37) v2(77.34,109.32) v2(77.34,108.69) v2(77.89,1.02) v2(78.11,9.14) v2(78.23,3.43) v2(78.23,2.24) v2(78.64,248.44) v2(78.74,252.22) v2(78.74,243.08) v2(78.79,253.03) v2(79.27,116.94) v2(79.27,116.31) v2(79.27,114.99) v2(79.27,114.35) v2(79.5,112.93) v2(79.5,112.3) v2(79.5,107.44) v2(79.5,106.81) v2(79.63,7.75) v2(81.03,242.93) v2(81.66,111) v2(81.66,110.37) v2(81.66,109.37) v2(81.66,108.74) v2(82.73,250.24) v2(82.97,1.02) v2(83.39,182.7) v2(84.28,108.3) v2(84.25,107.65) v2(85.01,253.03) v2(85.24,247.93) v2(85.2,105.67) v2(85.98,115.77) v2(85.98,115.14) v2(86,113.61) v2(85.99,112.93) v2(86.41,250.19) v2(88.05,1.02) v2(89.31,250.29) v2(89.57,202.18) v2(89.57,201.55) v2(90.04,221.49) v2(90.81,223.01) v2(90.78,219.51) v2(91.52,216.23) v2(91.52,215.47) v2(91.52,214.71) v2(91.97,250.32) v2(92.48,228.52) v2(93.13,1.02) v2(93.19,192) v2(93.37,253.06) v2(93.55,189.53) v2(93.75,228.53) v2(94.03,191.77) v2(94.03,190.88) v2(94.06,250.42) v2(94.16,189.26) v2(94.16,54.97) v2(94.23,54.05) v2(94.83,228.52) v2(95.43,209.17) v2(96.07,228.52) v2(96.16,209.17) v2(96.27,92.08) v2(96.7,249.5) v2(96.72,53.21) v2(96.74,52.53) v2(96.85,209.17) v2(97.49,228.52) v2(97.92,244.45) v2(98.21,1.02) v2(98.3,91.44) v2(98.37,247.07) v2(98.73,228.52) v2(99.63,93.29) v2(99.67,249.38) v2(99.77,228.39) v2(99.82,95.14) v2(100,90.14) v2(100.08,244.5) v2(100.39,105.51) v2(100.47,103.11) v2(100.94,106.56) v2(100.98,228.39) v2(101.09,92.2) v2(101.98,96.65) v2(102.4,193.8) v2(102.77,228.26) v2(102.81,103.11) v2(103,77.72) v2(103.28,106.56) v2(103.29,1.02) v2(103.89,95.76) v2(103.99,228.26) v2(104.99,193.8) v2(105.08,91.67) v2(105.16,228.6) v2(105.16,75.5) v2(105.33,249.61) v2(106.3,228.6) v2(106.78,90.42) v2(107.24,253.06) v2(108.15,102.62) v2(108.18,101.47) v2(108.33,250.47) v2(108.37,1.02) v2(108.97,196.73) v2(108.97,194.14) v2(109.45,98.83) v2(109.47,97.64) v2(109.64,91.08) v2(109.86,248.01) v2(110.01,95.74) v2(110.01,94.54) v2(111.38,89.79) v2(112.19,250.34) v2(112.18,70.4) v2(112.9,97.45) v2(112.93,96.32) v2(113.45,1.02) v2(113.64,91.98) v2(113.69,93.21) v2(113.92,89.29) v2(113.87,69.77) v2(114.02,90.7) v2(114.3,253.06) v2(114.68,195.25) v2(114.65,193.04) v2(114.68,68.83) v2(114.68,68.07) v2(114.68,66.85) v2(115.44,68.71) v2(116.1,250.42) v2(117.96,250.09) v2(117.98,245.05) v2(117.98,239.97) v2(118.11,34.42) v2(118.53,1.02) v2(119.15,34.85) v2(119.64,195.02) v2(119.63,193.85) v2(119.91,34.85) v2(120.52,11.3) v2(120.52,8.89) v2(120.68,34.85) v2(120.65,13.46) v2(123.61,1.02) v2(124.25,193.04) v2(125.19,232.98) v2(126.83,192.9) v2(127.38,7.37) v2(128.69,1.02) v2(129.03,5.97) v2(129.16,10.16) v2(130.05,9.02) v2(130.27,232.98) v2(130.43,52.83) v2(130.94,7.87) v2(131.95,6.73) v2(133.1,5.71) v2(133.77,1.02) v2(134.11,9.4) v2(134.82,227.08) v2(134.89,198.27) v2(134.91,197) v2(135.13,8.38) v2(135.35,232.98) v2(135.99,225.65) v2(136.14,7.49) v2(137.79,6.6) v2(138.61,187.03) v2(138.85,1.02) v2(139.08,193.83) v2(139.09,191.58) v2(139.7,40.89) v2(139.8,186.48) v2(140.43,232.98) v2(140.59,41.78) v2(140.56,40.94) v2(140.59,40.01) v2(141.48,40.89) v2(142.49,8.64) v2(143.38,9.65) v2(143.93,1.02) v2(144.65,11.18) v2(145.14,144.35) v2(145.39,142.9) v2(145.51,232.98) v2(145.92,12.57) v2(146.3,147.62) v2(146.25,142.04) v2(146.43,140.82) v2(146.87,144.49) v2(146.94,13.72) v2(147.13,142.03) v2(147.12,72.03) v2(147.2,146.16) v2(147.69,144.56) v2(148.01,72.03) v2(148.08,14.73) v2(148.5,144.53) v2(148.63,147.62) v2(149.01,1.02) v2(150.24,186.69) v2(150.26,148.01) v2(150.59,232.98) v2(150.75,186.06) v2(151.21,149.05) v2(151.16,148.01) v2(151.59,143.79) v2(151.55,110.31) v2(152.76,149.31) v2(152.86,145.01) v2(152.88,110.31) v2(153.42,13.84) v2(153.75,145.88) v2(153.92,12.57) v2(154.09,1.02) v2(154.53,119.01) v2(154.56,117.83) v2(154.94,14.73) v2(155.02,145.9) v2(155.32,115.32) v2(155.67,232.98) v2(156.21,173.99) v2(156.46,171.7) v2(156.77,115.34) v2(157.23,189.48) v2(157.29,141.45) v2(157.61,186.18) v2(157.61,185.29) v2(157.61,184.4) v2(158.45,141.47) v2(159,143.48) v2(159.17,1.02) v2(159.34,122.31) v2(159.36,123.47) v2(159.97,141.8) v2(160.21,145.1) v2(160.35,116.05) v2(160.69,143.54) v2(161.06,139.29) v2(161.2,198.3) v2(161.19,197.15) v2(161.72,147.12) v2(161.71,146.27) v2(161.8,201.42) v2(161.8,155.57) v2(161.8,141.03) v2(161.84,139.07) v2(161.93,184.91) v2(162.05,156.46) v2(162.13,116.79) v2(162.22,145.16) v2(162.69,192.68) v2(162.7,142.32) v2(162.7,141.17) v2(162.98,137.25) v2(163.01,135.95) v2(163.04,133.31) v2(163.1,132.58) v2(163.12,128.38) v2(163.43,119.31) v2(163.47,118.02) v2(163.57,192.68) v2(163.59,139.8) v2(163.6,130.04) v2(163.7,200.28) v2(163.71,135.14) v2(163.74,130.76) v2(163.82,194.11) v2(163.87,195.55) v2(163.96,184.4) v2(164.25,1.02) v2(164.34,124.93) v2(164.41,131.95) v2(164.47,123.74) v2(164.59,145.14) v2(164.69,192.17) v2(164.67,190.95) v2(164.95,189.55) v2(165.13,133.64) v2(165.19,138.41) v2(165.2,137.27) v2(165.25,136.06) v2(165.25,134.9) v2(166.3,189.55) v2(166.56,192.33) v2(166.6,182.83) v2(166.8,182.19) v2(166.88,206.5) v2(167.08,183.39) v2(167.21,186.82) v2(167.26,190.75) v2(167.64,201.17) v2(168.04,130.54) v2(168.48,182.19) v2(168.61,179.93) v2(168.65,128.59) v2(168.91,231.65) v2(169.29,188.47) v2(169.29,179.93) v2(169.33,1.02) v2(169.65,183.72) v2(169.8,200.28) v2(169.81,186.82) v2(170.18,184.18) v2(170.46,182.93) v2(170.71,184.68) v2(170.71,179.93) v2(170.75,191.7) v2(170.84,178.31) v2(170.76,176.61) v2(170.91,232.98) v2(170.94,183.49) v2(171.04,182.5) v2(171.24,189.36) v2(171.22,185.19) v2(171.42,183.95) v2(171.5,183.03) v2(171.48,176.63) v2(171.53,173.25) v2(171.55,174.8) v2(171.55,171.35) v2(171.88,184.48) v2(171.86,170.76) v2(172.01,183.51) v2(172.19,176.61) v2(172.21,174.8) v2(172.16,173.25) v2(172.21,171.35) v2(172.19,170.21) v2(172.21,169.52) v2(172.19,166.04) v2(172.21,165.35) v2(172.21,164.69) v2(172.21,164.01) v2(172.21,162.69) v2(172.21,161.42) v2(172.21,160.15) v2(172.21,158.95) v2(172.21,158.27) v2(172.21,157.56) v2(172.21,156.74) v2(172.31,178.31) v2(172.47,184.05) v2(172.72,228.09) v2(172.69,190.53) v2(172.72,186.72) v2(172.8,154.61) v2(173.08,176.58) v2(173.08,174.8) v2(173.08,173.23) v2(173.08,171.22) v2(173.08,170.31) v2(173.08,169.44) v2(173.08,166.04) v2(173.08,165.38) v2(173.08,164.72) v2(173.08,164.03) v2(173.08,162.69) v2(173.08,161.42) v2(173.2,158.88) v2(173.2,158.17) v2(173.18,157.43) v2(173.18,156.64) v2(173.43,186) v2(173.38,160.12) v2(173.43,154.03) v2(173.93,221.3) v2(173.86,6.73) v2(173.99,185.47) v2(174.02,158.88) v2(174.02,158.17) v2(173.99,157.43) v2(173.99,156.64) v2(173.99,4.95) v2(174.16,181.43) v2(174.17,180.24) v2(174.29,154.69) v2(174.41,1.02) v2(174.64,100.91) v2(174.63,99.62) v2(174.63,96.79) v2(174.62,95.51) v2(174.64,91.54) v2(174.62,88.84) v2(174.6,87.55) v2(174.64,83.57) v2(174.64,79.55) v2(174.62,75.56) v2(174.6,72.77) v2(174.6,71.58) v2(174.63,66.82) v2(174.61,62.86) v2(174.61,58.8) v2(174.62,54.68) v2(174.6,53.39) v2(174.61,48.86) v2(174.59,47.58) v2(174.59,36.8) v2(174.6,35.43) v2(174.66,92.83) v2(174.66,84.85) v2(174.66,80.84) v2(174.68,76.89) v2(174.68,65.46) v2(174.7,61.44) v2(174.68,57.4) v2(174.68,44.8) v2(174.67,43.51) v2(174.66,40.86) v2(174.73,39.5) v2(174.78,188.7) v2(174.78,158.88) v2(174.78,158.17) v2(174.75,157.43) v2(174.75,156.64) v2(175.01,152.43) v2(175.31,189.28) v2(175.31,187.88) v2(175.74,153.14) v2(175.84,188.42) v2(175.79,187.32) v2(175.87,189.84) v2(175.99,232.98) v2(176.33,187.86) v2(176.43,189.03) v2(176.45,150.75) v2(176.45,148.72) v2(176.5,146.1) v2(176.61,144.22) v2(176.66,152.2) v2(176.91,188.47) v2(177.6,150.72) v2(177.6,148.74) v2(177.57,146.1) v2(177.9,144.2) v2(178.03,139.01) v2(177.95,137.59) v2(178.46,146.1) v2(178.46,136.35) v2(178.59,144.2) v2(178.66,186.53) v2(178.66,185.37) v2(178.99,139.01) v2(178.97,137.59) v2(179.03,135.35) v2(179.5,193.47) v2(179.49,1.02) v2(179.58,136.22) v2(179.63,131.29) v2(179.65,133.38) v2(179.65,132.74) v2(179.65,132.05) v2(180.01,194.01) v2(180.19,131.7) v2(180.29,192.84) v2(180.54,134.24) v2(180.54,133.45) v2(180.57,194.51) v2(180.64,131.24) v2(180.75,192.28) v2(180.67,132.66) v2(180.85,193.32) v2(181.07,232.98) v2(181.1,195.1) v2(181.1,130.76) v2(181.2,132.16) v2(181.31,192.76) v2(181.36,193.85) v2(181.84,195.81) v2(181.81,193.29) v2(181.76,131.67) v2(181.89,194.41) v2(181.94,134.19) v2(181.89,129.87) v2(182.04,124.74) v2(182.07,126.09) v2(182.4,124.08) v2(182.65,130.63) v2(182.8,195.3) v2(182.78,194.41) v2(183.02,127.76) v2(183.01,126.58) v2(183.13,123.8) v2(183.16,124.71) v2(183.26,131.75) v2(183.29,131.04) v2(183.36,128.35) v2(183.9,128.75) v2(183.97,138.68) v2(183.97,137.55) v2(184.02,132.33) v2(183.97,123.8) v2(184.09,133.5) v2(184.25,196.34) v2(184.28,124.71) v2(184.38,126.34) v2(184.58,152.45) v2(184.57,1.02) v2(184.71,160.2) v2(184.76,164.13) v2(184.81,161.33) v2(184.81,123.8) v2(184.91,125.2) v2(185.06,157.73) v2(185.44,146) v2(185.55,124.31) v2(185.6,125.2) v2(185.7,143.19) v2(185.7,142.01) v2(185.83,129.26) v2(186.13,200) v2(186.06,198.65) v2(186.15,232.98) v2(186.56,200.53) v2(186.56,199.16) v2(186.69,128.5) v2(186.8,151.78) v2(186.77,147.48) v2(186.94,125.2) v2(186.92,124.31) v2(187.15,144.37) v2(187.17,143.21) v2(187.45,201.42) v2(187.55,200.1) v2(187.99,201.9) v2(188,104.08) v2(188.06,200.63) v2(188.19,124.28) v2(188.26,130.86) v2(188.29,125.2) v2(188.47,202.36) v2(188.49,146.97) v2(188.54,145.87) v2(188.59,201.12) v2(188.7,162.65) v2(188.7,161.57) v2(188.82,160.1) v2(188.82,158.98) v2(188.95,202.87) v2(189.03,201.63) v2(189.15,104.06) v2(189.28,98.91) v2(189.53,202.06) v2(189.65,1.02) v2(189.66,202.92) v2(189.84,156.74) v2(189.77,155.88) v2(189.82,102.86) v2(189.87,144.83) v2(189.89,102.09) v2(190.22,161.25) v2(190.25,160.12) v2(190.3,202.92) v2(190.42,141.81) v2(190.61,100.31) v2(190.91,135.08) v2(190.86,125.2) v2(191.23,232.98) v2(191.22,162.81) v2(191.62,125.2) v2(192.3,162.81) v2(192.38,187.78) v2(192.35,125.2) v2(193.04,189.54) v2(192.96,125.63) v2(193.29,146.15) v2(193.62,126.29) v2(193.83,125.15) v2(194.01,142.32) v2(194.39,202.92) v2(194.39,202.06) v2(194.49,203.56) v2(194.47,195.23) v2(194.64,197.68) v2(194.73,1.02) v2(195,127.58) v2(195.02,125.15) v2(195.73,147.68) v2(195.94,146.28) v2(196.14,204.09) v2(196.14,202.03) v2(196.24,126.09) v2(196.31,232.98) v2(196.27,126.85) v2(196.49,202.72) v2(196.55,138.02) v2(196.63,147.56) v2(196.64,146.13) v2(196.75,204.32) v2(196.68,198.91) v2(196.72,197.66) v2(196.88,201.98) v2(196.98,135.51) v2(197.48,199.52) v2(197.75,191.76) v2(198.15,205.66) v2(198.12,204.14) v2(198.15,203.23) v2(198.12,202.49) v2(198.12,201.85) v2(198.52,193.57) v2(198.52,190) v2(198.58,207.01) v2(198.73,207.7) v2(198.88,153.34) v2(198.93,150.24) v2(199.1,131.86) v2(199.21,148.79) v2(199.47,207.7) v2(199.52,203.4) v2(199.54,202.67) v2(199.57,204.14) v2(199.72,206.65) v2(199.81,1.02) v2(200.25,207.7) v2(200.35,136.55) v2(200.56,149.07) v2(201.39,232.98) v2(201.42,7.11) v2(203.17,151.59) v2(203.56,201.85) v2(204.24,204.77) v2(204.29,207.72) v2(204.27,204.04) v2(204.75,207.26) v2(204.89,1.02) v2(205.13,205.87) v2(205.08,178.44) v2(205.56,203.96) v2(205.69,205.36) v2(205.74,202.29) v2(205.74,201.47) v2(205.77,203.17) v2(205.97,179.2) v2(205.99,178.44) v2(205.97,177.55) v2(206.27,204.75) v2(206.47,232.98) v2(206.91,202.95) v2(206.91,202.13) v2(206.88,201.35) v2(206.98,204.06) v2(206.98,178.44) v2(207.72,203.99) v2(207.72,202.92) v2(207.72,202.11) v2(207.7,201.32) v2(209.97,1.02) v2(211.55,232.98) v2(211.58,130.58) v2(213.28,133.07) v2(213.49,131.06) v2(213.61,208.53) v2(214.09,207.08) v2(214.08,206.33) v2(214.07,205.51) v2(214.2,136.1) v2(214.81,206.25) v2(214.81,205.52) v2(215.05,1.02) v2(215.34,134.83) v2(215.39,7.24) v2(216.63,232.98) v2(217.17,5.21) v2(218.44,6.1) v2(220.13,1.02) v2(220.34,8) v2(221.71,232.98) v2(222.12,2.16) v2(225.21,1.02) v2(225.68,215.52) v2(226.19,5.71) v2(226.57,214.63) v2(226.79,232.98) v2(227.46,213.87) v2(228.35,2.92) v2(228.47,8.64) v2(229.54,81.72) v2(230.29,1.02) v2(231.87,232.98) v2(233.04,151.76) v2(233.81,205.74) v2(233.81,204.47) v2(233.81,202.18) v2(233.96,151.76) v2(234.82,151.76) v2(234.82,2.79) v2(235.08,18.16) v2(235.37,1.02) v2(236.37,2.67) v2(236.95,232.98) v2(238.53,102.9) v2(238.51,101.73) v2(238.51,100.2) v2(238.51,99.06) v2(238.51,97.92) v2(238.53,97.1) v2(238.53,96.19) v2(238.53,95.17) v2(240.97,15.37) v2(241.68,10.67) v2(241.86,15.39) v2(241.94,7.75) v2(242.98,227.97) v2(242.98,222.89) v2(242.98,217.81) v2(242.98,212.73) v2(242.98,207.65) v2(242.98,202.57) v2(242.98,197.49) v2(242.98,192.41) v2(242.98,187.33) v2(242.98,182.25) v2(242.98,177.17) v2(242.98,172.09) v2(242.98,167.01) v2(242.98,161.93) v2(242.98,156.85) v2(242.98,151.77) v2(242.98,146.69) v2(242.98,141.61) v2(242.98,136.53) v2(242.98,131.45) v2(242.98,126.37) v2(242.98,121.29) v2(242.98,116.21) v2(242.98,111.13) v2(242.98,106.05) v2(242.98,100.97) v2(242.98,95.89) v2(242.98,90.81) v2(242.98,85.73) v2(242.98,80.65) v2(242.98,75.57) v2(242.98,70.49) v2(242.98,65.41) v2(242.98,60.33) v2(242.98,55.25) v2(242.98,50.17) v2(242.98,45.09) v2(242.98,40.01) v2(242.98,34.93) v2(242.98,29.85) v2(242.98,24.77) v2(242.98,19.69) v2(242.98,14.61) v2(242.98,9.53) v2(242.98,4.45) v3(13.59,91.19) v3(13.59,90.04) v3(13.59,88.9) v3(14.34,118.62) v3(14.35,117.6) v3(14.35,116.33) v3(15.94,83.19) v3(15.88,82.32) v3(15.95,84.1) v3(16.83,82.35) v3(16.88,84.15) v3(16.9,83.2) v3(17.66,82.27) v3(17.78,83.97) v3(17.81,83.13) v3(18.57,82.26) v3(18.72,84.14) v3(18.74,83.15) v3(19.18,194.18) v3(19.18,193.17) v3(19.18,191.77) v3(19.48,82.3) v3(19.63,84.14) v3(19.58,83.15) v3(20.45,191.64) v3(20.39,82.27) v3(20.55,84.18) v3(20.5,83.19) v3(21.21,82.65) v3(21.26,83.64) v3(21.72,191.64) v3(21.72,126.62) v3(21.72,125.09) v3(21.72,123.83) v3(22.66,126.62) v3(22.66,125.09) v3(22.73,123.83) v3(22.86,195.07) v3(22.86,193.95) v3(22.99,191.64) v3(23.11,192.91) v3(24.13,126.62) v3(24.13,125.09) v3(24.13,123.83) v3(24.26,195.2) v3(24.26,194.06) v3(24.26,192.91) v3(24.38,191.64) v3(25.07,126.62) v3(25.15,125.09) v3(25.15,123.83) v3(26.54,126.36) v3(26.54,125.35) v3(26.54,124.33) v3(27.53,122.99) v3(29.34,119.63) v3(30.35,121.92) v3(30.35,120.9) v3(30.37,119.63) v3(31.78,59.42) v3(31.78,58.41) v3(31.78,57.5) v3(31.83,56.61) v3(31.83,55.69) v3(32.49,59.97) v3(32.51,59.01) v3(32.56,58.09) v3(32.74,61.8) v3(32.74,60.88) v3(32.72,57.2) v3(32.72,56.29) v3(32.74,55.37) v3(32.74,54.46) v3(33.26,53.74) v3(33.44,59.97) v3(33.39,59) v3(33.41,58.06) v3(33.69,62.71) v3(33.69,61.8) v3(33.69,60.88) v3(33.67,57.2) v3(33.67,56.29) v3(33.69,55.37) v3(33.69,54.46) v3(37.32,100.33) v3(37.32,99.32) v3(37.32,92.59) v3(37.32,91.57) v3(37.38,108.46) v3(37.38,107.44) v3(37.85,198.75) v3(37.86,208.46) v3(38.24,211.84) v3(38.24,210.82) v3(38.24,209.8) v3(38.61,199.39) v3(39.24,211.96) v3(39.24,210.95) v3(39.24,209.93) v3(39.62,212.93) v3(40.26,211.96) v3(40.26,210.95) v3(40.26,209.93) v3(40.64,212.93) v3(40.89,209.04) v3(41.27,211.96) v3(41.27,210.95) v3(41.27,209.93) v3(41.66,212.93) v3(42.14,193.42) v3(42.16,191.41) v3(50.83,57.38) v3(50.83,56.46) v3(50.88,63.73) v3(50.88,62.81) v3(51,204.83) v3(51,203.89) v3(51.03,67.41) v3(51.03,66.5) v3(51.03,65.58) v3(51.03,64.67) v3(51,61.9) v3(51,60.99) v3(51.03,60.07) v3(51.03,59.16) v3(51.03,58.24) v3(51.56,203.2) v3(51.69,205.49) v3(51.71,63.73) v3(51.71,62.81) v3(51.66,57.41) v3(51.66,56.49) v3(51.86,64.75) v3(51.89,58.32) v3(51.98,67.41) v3(51.98,66.5) v3(51.98,65.58) v3(51.95,61.9) v3(51.95,60.99) v3(51.98,60.07) v3(51.98,59.16) v3(52.24,202.47) v3(52.32,48.21) v3(52.4,204.72) v3(52.36,203.82) v3(52.46,206.16) v3(53.06,49.02) v3(53.21,205.79) v3(53.24,204.75) v3(53.19,202.95) v3(53.26,203.81) v3(53.29,202.03) v3(53.82,49.78) v3(54.1,205.87) v3(54.1,204.83) v3(54.1,203.84) v3(54.16,202.82) v3(54.61,207.66) v3(54.61,206.72) v3(55.75,206.63) v3(58.64,199.26) v3(59.82,191.26) v3(59.82,190.25) v3(60.83,191.26) v3(60.83,190.25) v3(60.96,189.23) v3(60.96,188.21) v3(61.98,190.88) v3(61.98,189.87) v3(61.98,188.21) v3(63.12,190.75) v3(63.12,189.74) v3(63.12,188.59) v3(63.37,199.64) v3(63.5,191.64) v3(64.14,190.75) v3(64.14,189.74) v3(64.14,188.59) v3(64.52,191.64) v3(65.53,191.64) v3(67.79,17.12) v3(68.78,18.72) v3(69.19,67.79) v3(69.19,66.83) v3(69.22,65.86) v3(69.19,61.37) v3(69.16,60.45) v3(69.16,59.54) v3(69.32,70.46) v3(69.32,69.55) v3(69.32,68.63) v3(69.29,64.95) v3(69.29,64.03) v3(69.32,63.12) v3(69.32,62.2) v3(70.02,67.87) v3(70.01,66.66) v3(70,60.53) v3(70,59.59) v3(69.95,18.31) v3(70.1,65.81) v3(70.21,68.71) v3(70.24,64.95) v3(70.24,64.03) v3(70.15,61.37) v3(70.27,70.46) v3(70.27,69.55) v3(70.27,63.12) v3(70.27,62.2) v3(71.79,52.07) v3(72.9,52.07) v3(76.58,205.61) v3(76.58,204.47) v3(76.58,203.33) v3(77.09,202.18) v3(77.22,52.96) v3(77.85,205.61) v3(77.9,204.44) v3(77.9,203.35) v3(78.14,52.96) v3(78.23,202.18) v3(79.5,202.18) v3(80.77,202.18) v3(80.9,204.85) v3(80.9,203.33) v3(81.66,204.09) v3(81.92,202.95) v3(87.7,67.39) v3(87.73,66.52) v3(87.73,60.07) v3(87.83,65.46) v3(87.83,64.54) v3(87.76,60.93) v3(87.86,70.97) v3(87.86,70.05) v3(87.86,69.14) v3(87.86,68.22) v3(87.86,63.63) v3(87.86,62.71) v3(87.86,61.8) v3(88.54,67.38) v3(88.57,66.49) v3(88.59,61.04) v3(88.6,60.12) v3(88.72,68.38) v3(88.72,61.88) v3(88.81,70.97) v3(88.81,70.05) v3(88.78,69.22) v3(88.78,65.46) v3(88.78,64.54) v3(88.81,63.63) v3(88.81,62.71) v3(105.94,72.9) v3(105.87,50.43) v3(106.05,71.91) v3(106.05,53) v3(106.92,73.53) v3(106.96,72.54) v3(106.96,71.35) v3(111.51,37.4) v3(111.51,36.42) v3(112.52,37.4) v3(112.52,36.42) v3(113.54,37.4) v3(113.54,36.42) v3(114.55,37.4) v3(114.55,36.42) v3(119.89,102.74) v3(120.52,103.38) v3(121.18,103.99) v3(121.81,104.66) v3(122.43,105.28) v3(123.65,46.74) v3(123.65,45.78) v3(123.58,44.94) v3(123.57,44.07) v3(123.57,43.1) v3(123.57,42.19) v3(123.57,41.27) v3(124.45,41.34) v3(124.59,44.75) v3(124.59,43.92) v3(124.59,43.05) v3(124.59,42.16) v3(124.71,40.51) v3(124.85,39.69) v3(156.51,193.47) v3(156.46,192.41) v3(157.25,191.74) v3(157.48,192.79) v3(187.83,7.01) v3(187.86,4.8) v3(190.7,6.05) v3(193.12,6.63) v3(201.55,5.59) v3(212.34,7.87) v3(224.41,114.33) v3(226.99,140.24) v3(227,139.35) v3(227.03,138.45) v3(227,137.61) v3(226.98,136.72) v3(227.15,141.17) v3(227.17,135.73) v3(227.74,137.19) v3(227.78,140.54) v3(227.77,139.7) v3(227.78,138.86) v3(227.81,138.02) v3(228.09,114.25) v3(228.47,141.1) v3(230,114.3) v3(232.12,143.81) v3(232.12,142.88) v3(232.71,114.91) v3(232.79,115.95) v3(232.94,145.35) v3(232.92,119) v3(233.65,115.01) v3(233.93,115.95) v3(234.06,119) v3(235.38,127.76) v3(235.41,126.9) v3(235.84,119) v3(235.84,117.98) v3(240.66,5.08)
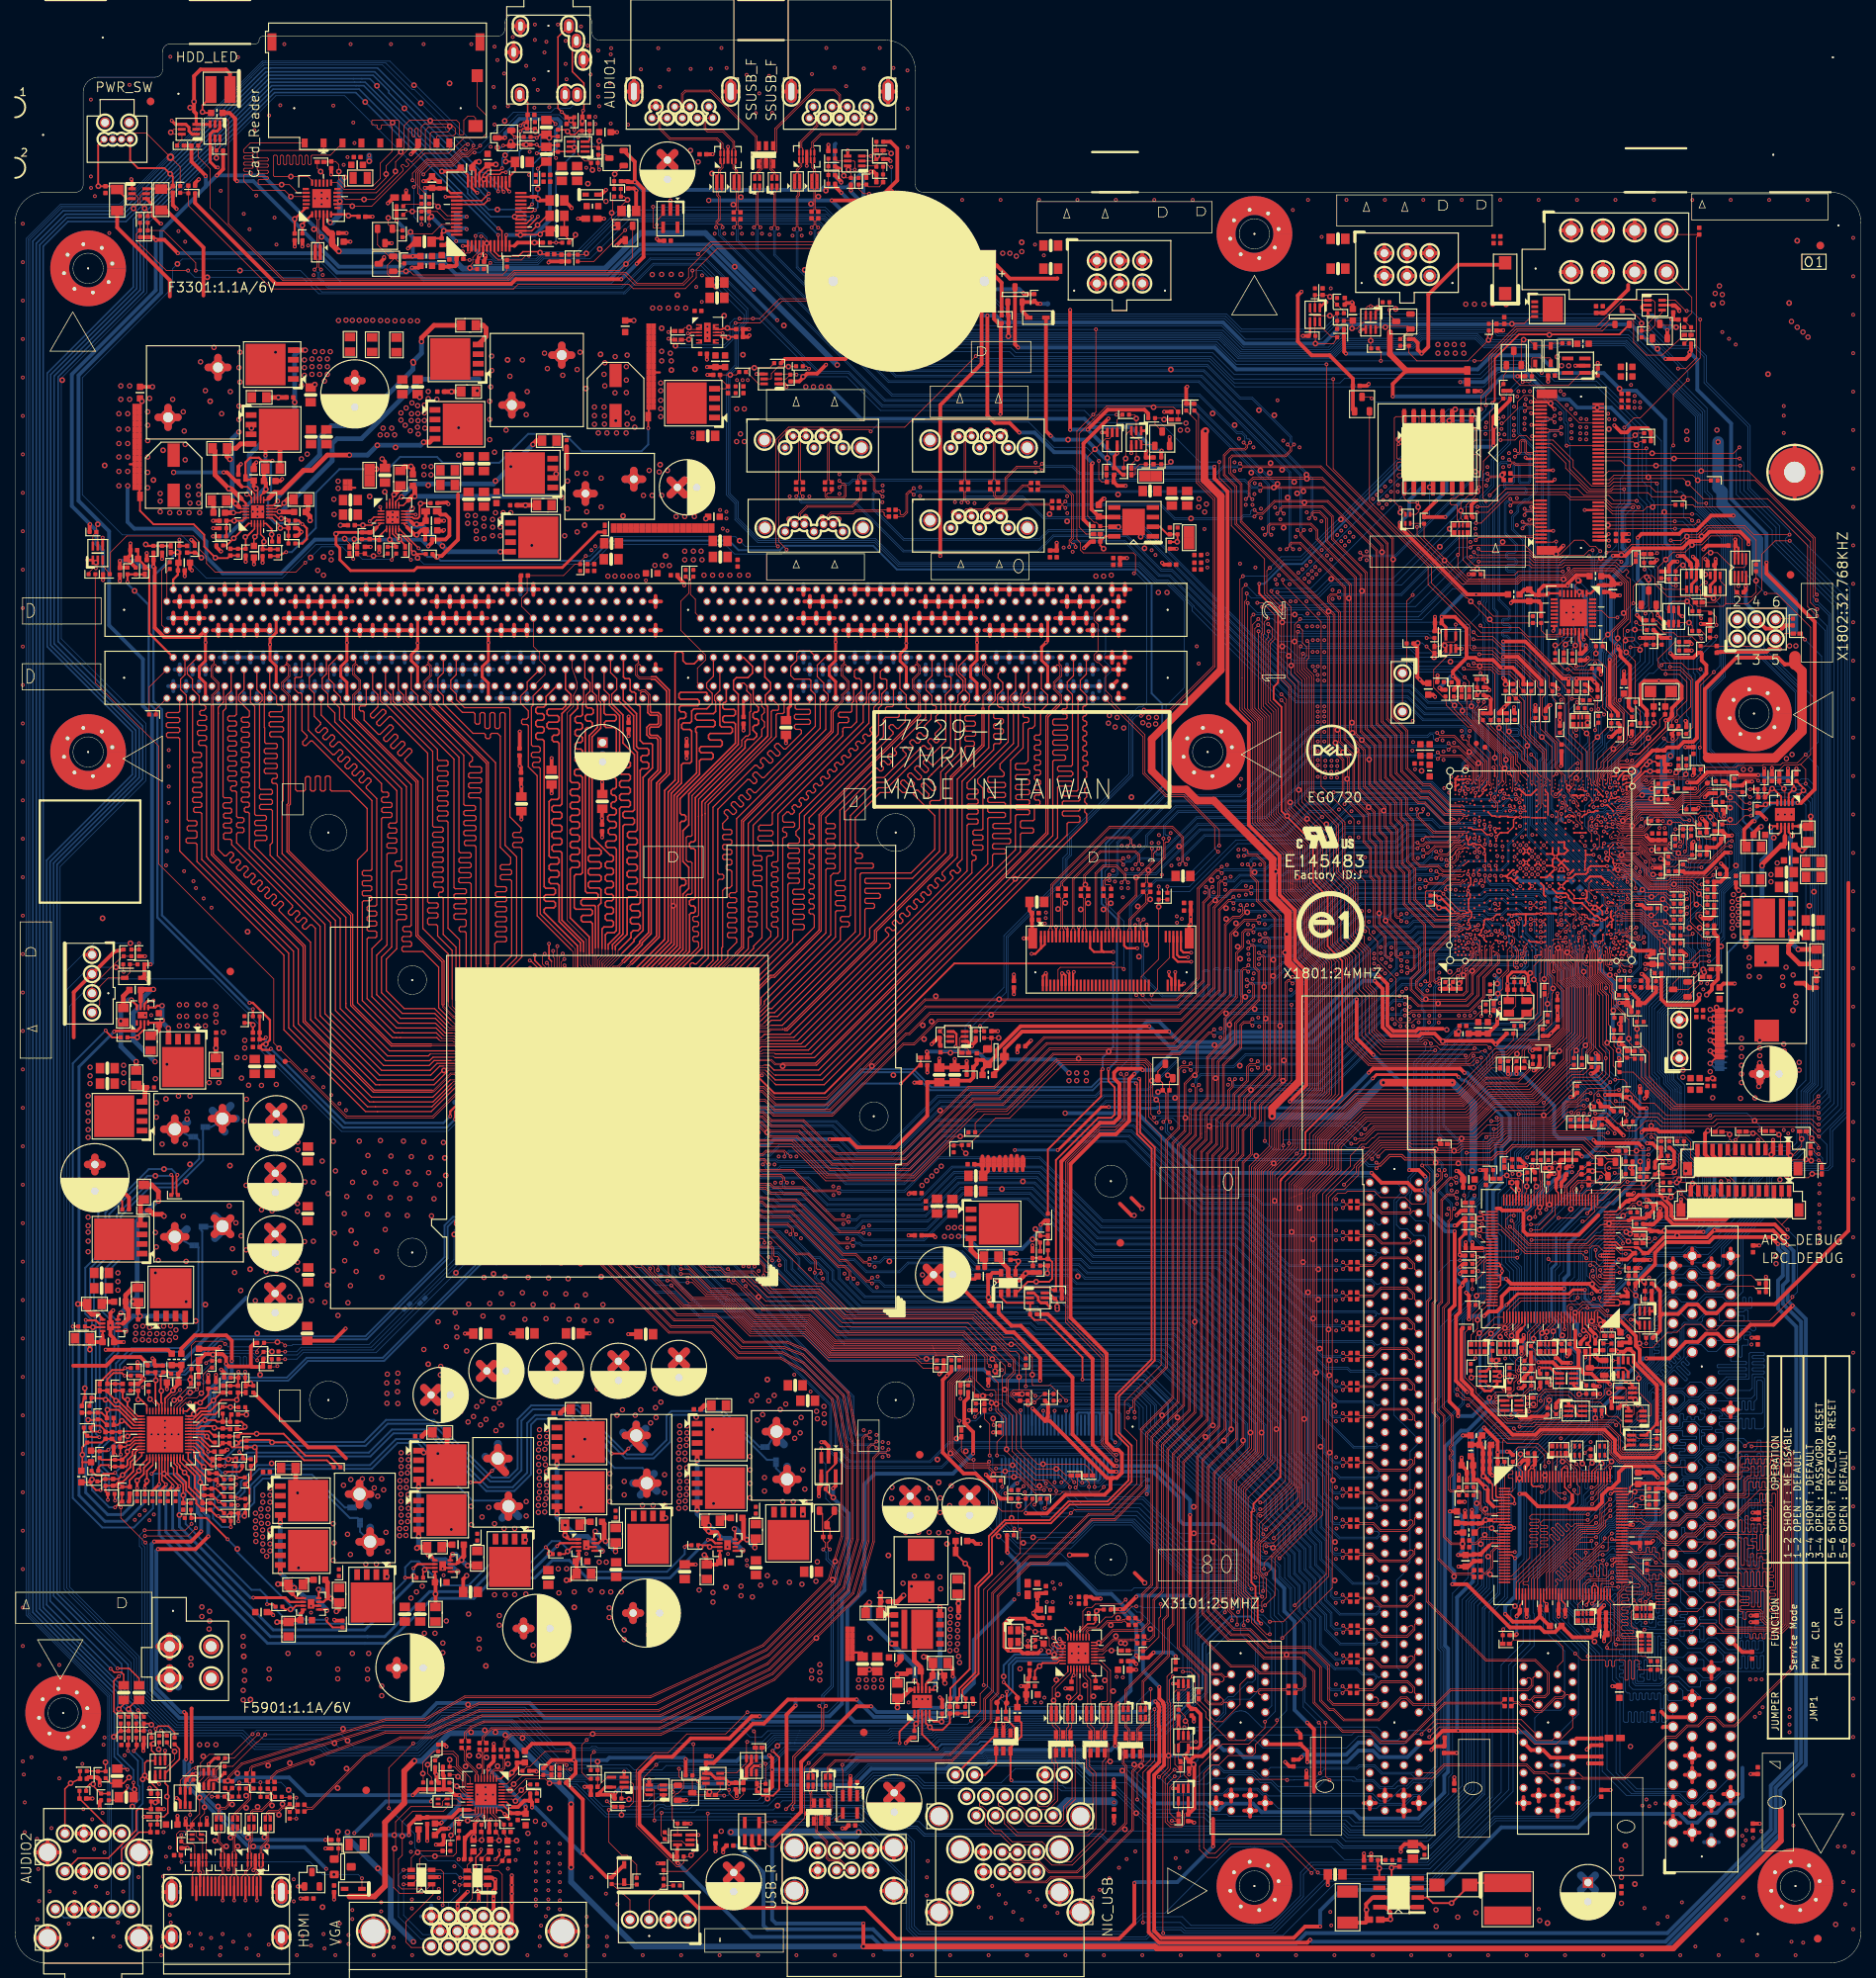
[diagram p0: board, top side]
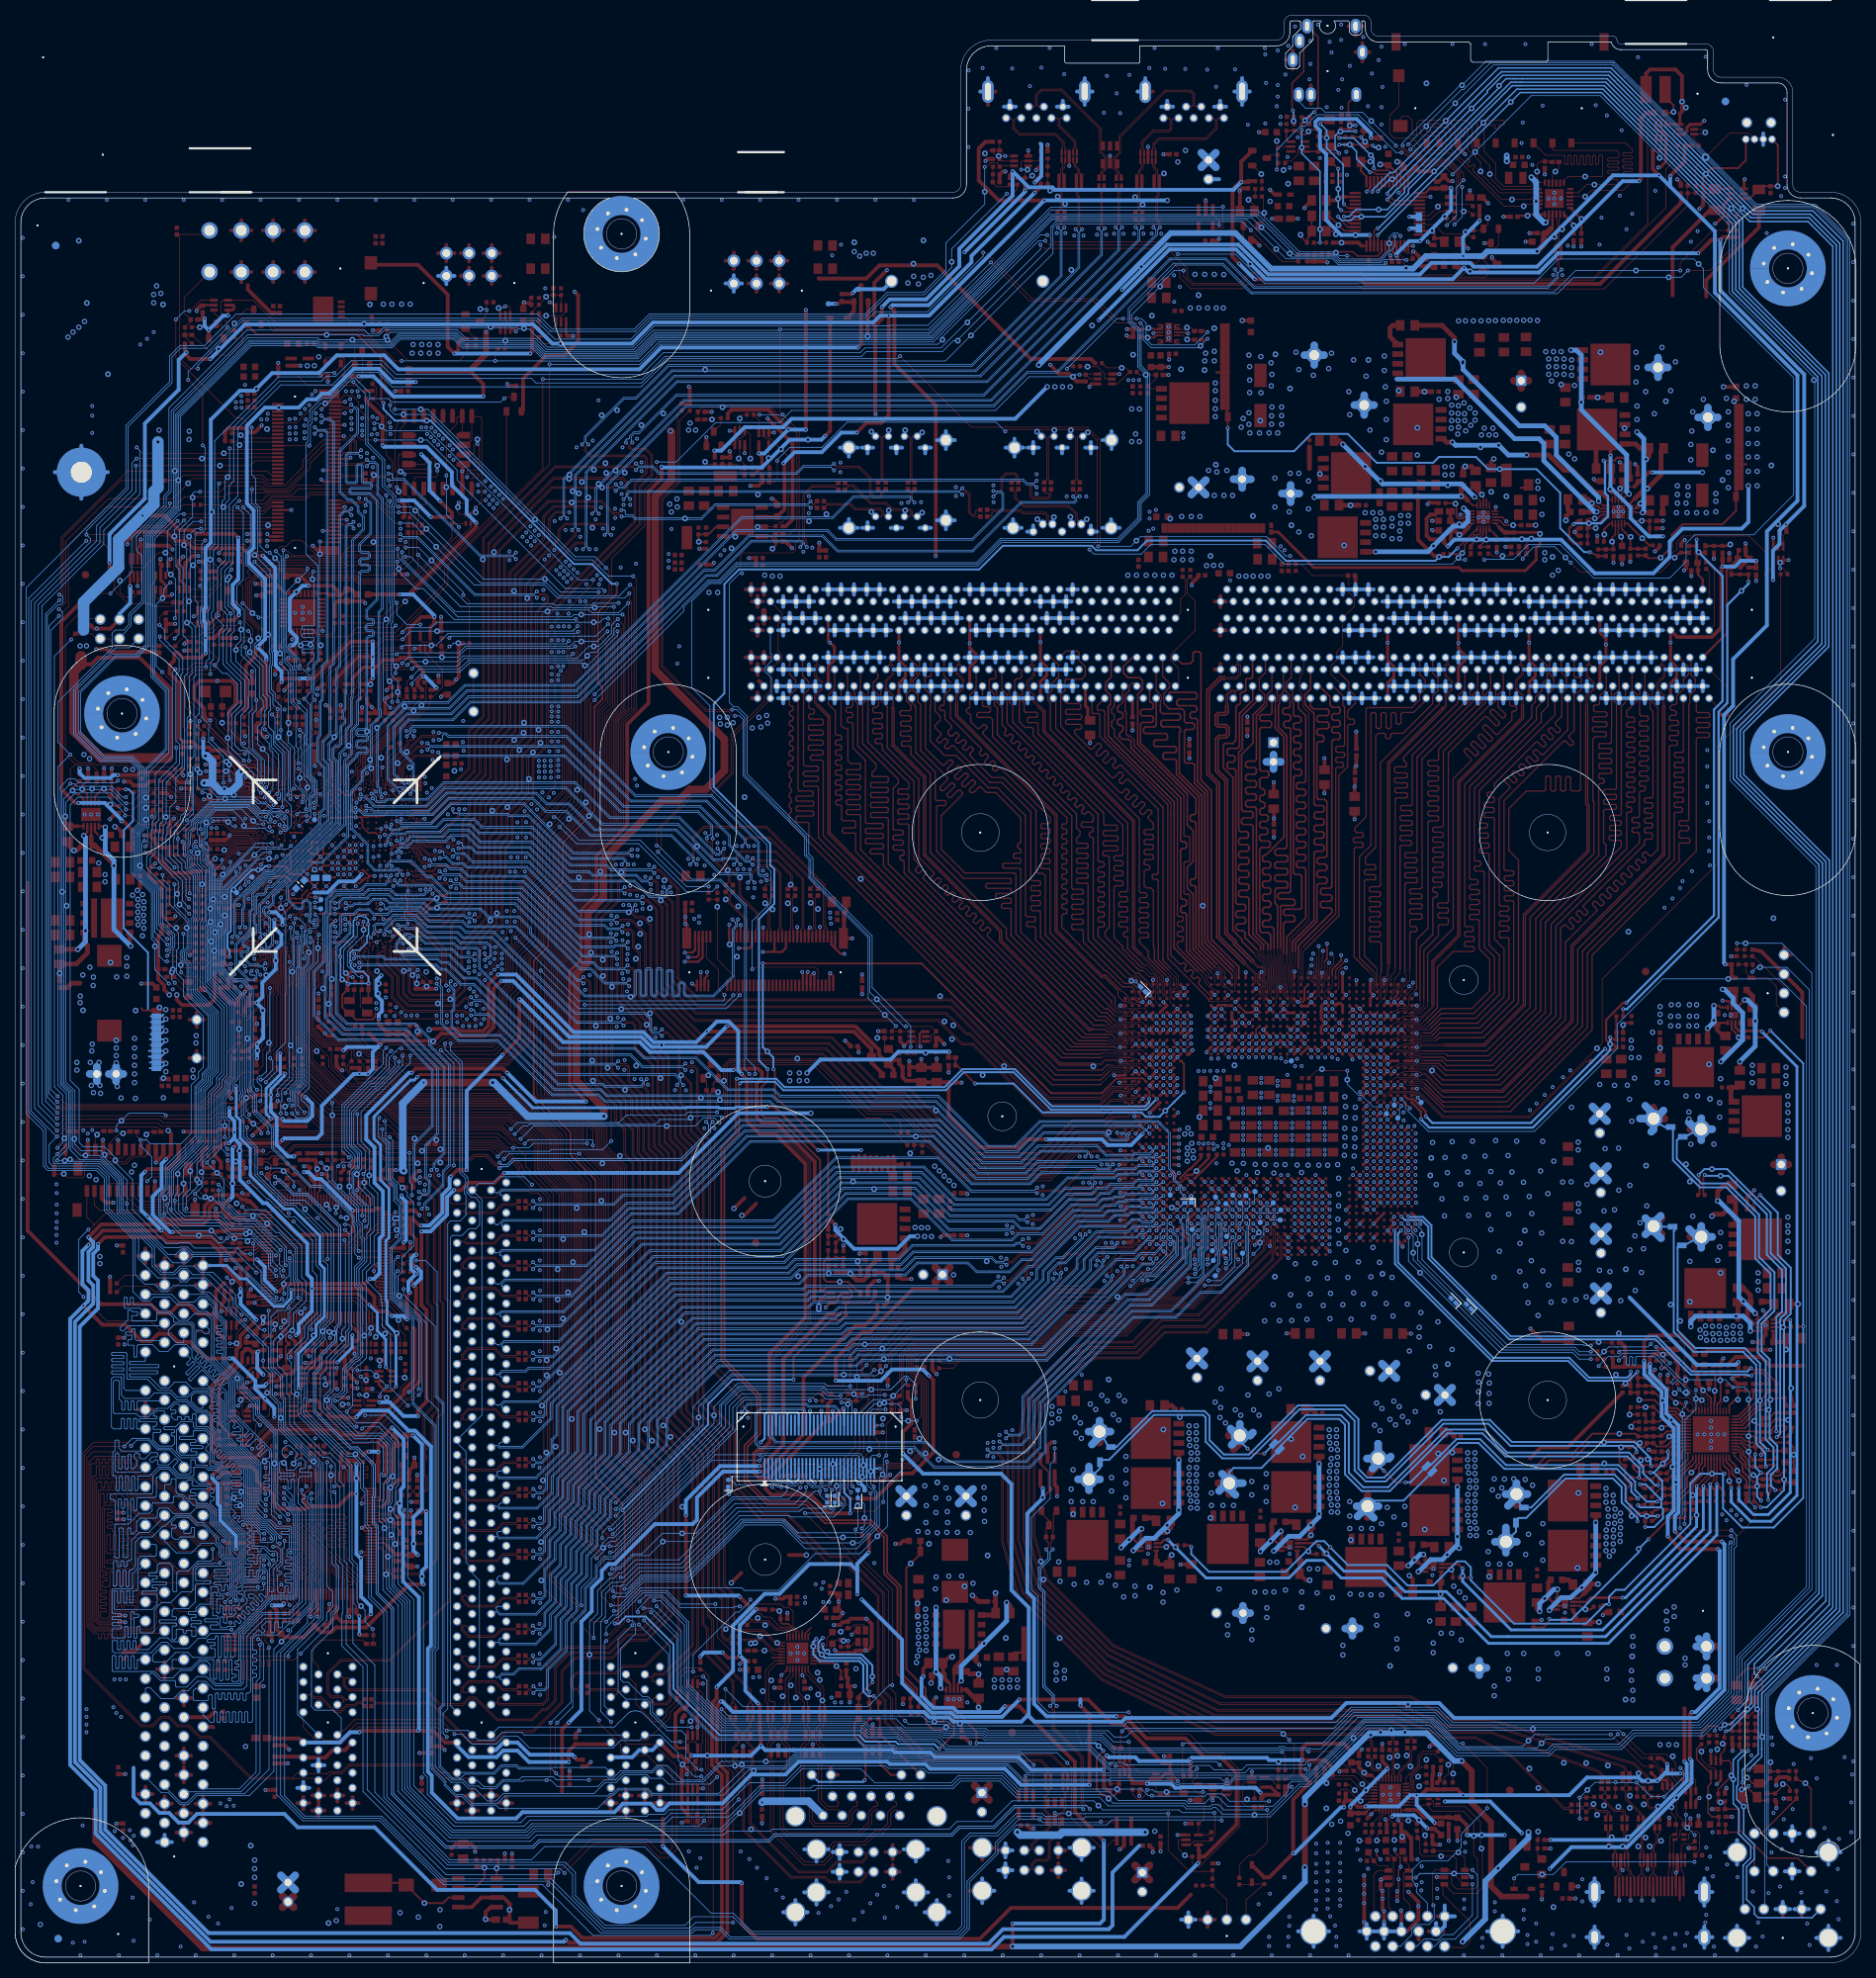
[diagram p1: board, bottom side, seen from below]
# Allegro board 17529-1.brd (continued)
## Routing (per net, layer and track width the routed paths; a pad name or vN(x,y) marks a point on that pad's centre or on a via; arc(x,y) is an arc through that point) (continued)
V5_ALW_MON: length 9.1
  TOP w0.102: Q2408.3 214.77,87.69 v1(214.24,88.21) 213.3,89.16 R2468.2 C2426.1 R2472.1 212.1,91.82 211.46,92.47 U2401.15
V5_ALW_MON_1: length 5.2
  TOP w0.102: R2467.2 v2(215.61,81.85) ; R2467.2 216.07,83.06 Q2408.6 ; R2467.2 215.42,82.79 Q2408.5
  BOTTOM w0.102: v1(214.73,81.86) 215.6,81.86 v2(215.61,81.85)
V5_ALW_MON_2: length 5.6
  TOP w0.102: v2(216,90.58) 215.46,90.03 R2466.2 C2425.1 R2471.1 215.46,86.15 Q2408.2
  BOTTOM w0.102: v2(216,90.58) 215.47,90.04 v1(215.32,90.04)
VBAT1: length 7.3
  TOP w0.508: R2506.1 133.41,220.54 v2(133.27,220.68)
  BOTTOM w0.508: v2(133.27,220.68) 132.77,221.18 TP2501.1 129.19,221.18 BT2501.1
VBAT1_L: length 6
  TOP w0.508: v2(135.53,219.25) 135.14,219.25 R2506.2 134.59,219.49 D2502.2 133.12,218.29 D2501.A
  BOTTOM w0.508: TP2502.1 v2(135.53,219.25)
VBAT1_R: length 4.5
  TOP w0.508: v1(131.31,214.96) R2504.2 R2505.1 131.22,217.85 D2502.1
VBAT2: length 210.5
  TOP w0.203: U2401.21 211.53,94.86 212.19,94.21 213.51,94.21 213.93,93.79
  TOP w0.508: D2501.K 136.27,202.44 v2(136.91,201.8) ; v2(209.52,88.76) 209.08,88.76 208.1,89.74 197.76,89.74 v2(197.1,90.4) ; C2405.1 213.93,93.79 213.11,92.96 v2(211.99,92.96) ; v2(168.53,113.84) 170.69,116 170.69,131.06 169.19,132.55 169.19,139.12 167.16,141.15 167.16,146.3 163.09,150.37 163.09,163.66 160.27,166.48 160.27,194.44 158.55,196.16 v2(158.55,197.71) ; v2(191.59,117.63) 191.03,118.19 179.5,118.19 v2(178.96,117.64)
  BOTTOM w0.508: v2(136.91,201.8) 137.41,201.29 v1(139.19,201.29) 141.61,201.29 145.28,197.62 158.46,197.62 v2(158.55,197.71) ; v2(168.53,113.84) 175.16,113.84 v2(178.96,117.64) ; v2(211.99,92.96) 211,91.97 211,90.23 v2(209.52,88.76) ; v2(191.59,117.63) 191.95,117.63 197.59,111.99 197.59,108.85 196.49,107.75 196.49,103.09 195.38,101.98 195.38,96.18 195.83,95.73 195.83,91.11 196.55,90.4 v2(197.1,90.4)
VCCGT_VCC_SEN: length 62.6
  TOP w0.254: PR4447.1 11.18,76.71 12.82,78.35 14.27,78.35 v2(14.53,78.61) PR4445.2 ; CPU1.F39 59.9,98.69 v2(59.83,98.69)
  BOTTOM w0.254: v2(59.83,98.69) 59.72,98.58 57.89,98.58 56.77,97.46 56.77,93.27 46.3,82.8 32,82.8 ; v1(32,83.19) 32,82.8 ; 32,82.8 26.98,82.8 22.33,78.16 14.99,78.16 v2(14.53,78.61)
VCCGT_VSS_SEN: length 64.7
  TOP w0.254: PC4423.1 PR4450.1 PC4422.2 12.19,77.15 12.99,77.94 14.13,77.94 v2(14.48,77.6) PR4454.1 ; v2(60.73,98.63) 60.75,98.63 CPU1.F38
  BOTTOM w0.254: v2(14.48,77.6) 14.86,77.6 15.01,77.75 22.5,77.75 27.15,82.4 34.67,82.4 ; 34.67,82.4 v1(34.67,82.04) ; 34.67,82.4 46.47,82.4 57.18,93.1 57.18,97.29 58.06,98.18 60.28,98.18 v2(60.73,98.63)
VCCIO_SENSE: length 95.4
  TOP w0.254: v2(143.76,118.11) 143.56,117.91 143.56,114.53 136.52,107.49 136.52,102.01 PR4815.2 ; CPU1.AF4 94.93,116.9 97.18,116.9 97.2,116.87 98.42,116.87 100.36,114.93 107.02,114.93 124.17,132.08 v2(145.16,132.08)
  BOTTOM w0.254: v2(143.76,118.11) 143.76,119.63 v1(144.57,120.44) 145.16,121.03 v2(145.16,132.08)
VCCPGPPD_PWR: length 0.9
  TOP w0.305: SB1.AN24 205.47,143.89 v2(205.36,143.89)
  vias: v1(204.42,144.48)
VCCPLL_OC_R: length 39.7
  TOP w0.254: v2(89.48,115.06) 89.48,118.84 89.84,119.2 CPU1.AJ9 ; R801.1 C801.1 119.51,118.62 v2(117.09,116.2)
  BOTTOM w0.254: v2(117.09,116.2) 112,116.2 108.18,112.39 95.12,112.39 94.54,111.81 92.73,111.81 v1(91.95,112.6) v2(89.48,115.06)
VCCSA_SENSE: length 162.1
  TOP w0.254: CPU1.AD5 93.53,114.62 v2(93.08,114.17) ; v2(148.16,116.24) 148.31,116.09 148.31,109.53 150.24,107.6 150.24,79.77 145.52,75.05 145.52,69.87 147.19,68.2 147.19,63.77 144.4,60.97 139.23,60.97 136.76,58.5 130.83,58.5 128.73,56.4 128.73,51.58 126.95,49.8 126.95,38.37 124.82,36.23 124.82,35.22 PR4715.2 124.52,33.91 PR4714.1
  BOTTOM w0.254: v2(93.08,114.17) 94.16,113.08 94.47,112.78 107.07,112.78 112,117.7 116.1,117.7 ; 116.1,117.7 118.58,117.7 120.95,115.33 142.45,115.33 143.55,116.43 147.92,116.43 148.12,116.24 v2(148.16,116.24) ; 116.1,117.7 v1(116.1,117.32)
VCCST_GD_CPU: length 34.1
  TOP w0.102: v1(125.68,106.98) 125.16,107.51 R419.2 124.14,108.08 R420.1 123.5,108.01 118.84,103.35 107.15,103.35 102.63,107.87 96.66,107.87 CPU1.U2
VCCST_GD_DRIVER: length 193.8
  TOP w0.102: R419.1 129.6,111.63 131.47,111.63 138.51,118.68 149.12,118.68 149.48,118.32 149.48,111.33 151.5,109.31 151.5,79.01 146.67,74.17 146.67,70.63 148.29,69.01 148.29,63.32 144.85,59.88 140.02,59.88 v2(139.57,59.44) 136.14,56.01 135.38,56.01 128.52,49.15 128.52,36.5 127.57,35.55 127.57,33.21 v2(126.36,32) ; R4014.2 75.74,24.33 74.9,25.17 74.9,28.8 v2(75.56,29.46)
  BOTTOM w0.102: v2(139.57,59.44) 136.14,59.44 135.64,59.94 135.64,60.83 ; v2(126.36,32) 125.88,31.52 120.9,31.52 120.34,30.96 115.67,30.96 115.39,30.68 103.74,30.68 99.51,30.68 98.68,29.84 97.16,29.84 96.34,30.66 76.76,30.66 v1(76.36,30.25) v2(75.56,29.46)
VDD: length 9.7
  TOP w0.127: v2(58.85,11.25) EU5901.5 ; EU5902.5 v2(51.43,11.33)
  BOTTOM w0.127: v2(51.43,11.33) 51.91,11.81 v1(53.77,11.81) 58.29,11.81 v2(58.85,11.25)
VDDQ_EN: length 118.3
  TOP w0.102: v2(143.26,198.5) 143.26,196.09 143.64,195.71 C4012.1 144.27,195.77 R4024.2 ; v2(113.11,202.39) 112.85,202.64 102.36,202.64 100.97,201.24 100.97,187.83 101.98,186.82 v2(101.98,186.77) ; R5003.1 51.56,186.18 v2(52.32,185.42)
  BOTTOM w0.102: v2(143.26,198.5) 143.26,198.63 141.6,200.28 137.34,200.28 134.01,203.61 114.33,203.61 v2(113.11,202.39) ; v2(52.32,185.42) 52.96,185.42 v1(53.21,185.67) 54.03,184.86 76.2,184.86 78.79,187.45 93.85,187.45 95.12,186.18 101.4,186.18 v2(101.98,186.77)
VDDQ_EN_CR: length 3.1
  TOP w0.102: R4024.1 144.38,197.66 v1(144.38,198.88) U4010.4
VIN_DET: length 7.7
  TOP w0.203: U2401.46 204,101.77 203.71,102.06 203.71,102.41
  TOP w0.508: 203.71,102.41 203.71,103.44 204.11,103.85 204.11,104.86 v1(204.06,104.91) 204.22,105.07 204.22,105.93 R2416.1 C2407.1 R2411.2
VSS_SA_IO_SENSE: length 163.1
  TOP w0.254: PR4716.2 125.67,33.91 PR4717.1 125.22,35.37 125.22,36.07 127.36,38.2 127.36,49.63 129.13,51.41 129.13,56.24 131,58.1 136.93,58.1 139.4,60.57 144.56,60.57 147.6,63.6 147.6,68.36 145.92,70.04 145.92,74.88 150.65,79.6 150.65,107.77 148.72,109.7 148.72,116.71 v2(148.59,116.84) ; CPU1.AE4 94.04,115.09 94.04,114.22 v2(94.09,114.17)
  BOTTOM w0.254: v2(148.59,116.84) 143.38,116.84 142.28,115.74 121.12,115.74 118.75,118.11 113.26,118.11 ; v2(94.09,114.17) 94.09,113.72 94.64,113.18 106.9,113.18 111.83,118.11 113.26,118.11 ; v1(113.26,118.52) 113.26,118.11
0D95V_CPU_VCCIO: length 197.7
  TOP w0.356: v2(193.65,76.19) 193.66,76.19 194.26,75.59 195.09,75.59 195.92,76.42 Q2402.1
  TOP w0.381: v2(137.82,107.42) 137.9,107.42 143.59,113.11 v2(144.58,113.11) ; v2(190.83,117.07) 190.51,117.39 179.97,117.39 v2(179.48,116.89)
  TOP w0.406: v2(86.49,120.33) 86.49,120.41 85.89,121.01 CPU1.AK11 ; v2(90.07,110.12) 90.14,110.05 CPU1.W8 ; CPU1.AK24 74.04,121.02 v2(74.44,120.62) 74.91,120.15 CPU1.AJ23 ; CPU1.P8 90.24,105.48 v2(90.17,105.41) ; v2(90.15,107.33) 90.17,107.31 CPU1.T8 ; CPU1.M8 90.83,103.72 v2(90.16,104.39) ; CPU1.AK14 83.18,121.02 v2(83.6,120.61) ; CPU1.U8 90.14,108.22 v2(90.12,108.24)
  TOP w0.508: 122.17,89.03 125.35,89.03 131.04,83.34 132.04,83.34 135.51,79.87 v2(135.51,76.94) ; 131.7,61.34 130.3,61.34 126.96,64.68 125.39,64.68 122.63,67.44 122.63,77.04 v2(123.19,77.6) 123.77,78.18 R425.2 ; C302.1 v2(132.03,128.02) ; C301.1 132.49,120.97 v2(132.49,120.32) ; v2(135.57,97.54) 136.14,98.11 PR4815.1 PR4812.2
  TOP w1.016: PT4801.1 122.37,90 ; PT4801.1 122.37,91.91 ; PT4801.1 120.46,90 ; PT4801.1 120.46,91.91
  BOTTOM w0.381: v2(144.58,113.11) 144.59,113.09 148.73,113.09 148.87,112.95 150.9,112.95 151.01,113.07 155.26,113.07 155.33,113 175.59,113 v2(179.48,116.89) ; v2(190.83,117.07) 191.24,116.66 191.73,116.66 196.56,111.83 196.56,108.95 195.69,108.09 195.69,103.42 194.58,102.31 194.58,95.85 194.98,95.45 194.98,87.59 194.84,87.45 194.84,84.43 193.65,83.24 v2(193.65,76.19) ; v2(132.16,107.42) v2(137.82,107.42)
  BOTTOM w0.508: v2(123.19,77.6) 124.02,78.42 128.08,78.42 129.57,76.94 v2(135.51,76.94) ; v2(135.57,97.54) 135.57,96.84 133.1,94.36 127.38,94.36 125.73,96.01 v3(124.71,96.01)
  vias: v1(85.32,116.92) v1(87.45,111.79) v1(87.83,104.65) v2(73.94,118.52) v2(74.52,119.48) v2(74.8,118.49) v2(84.23,117.89) v2(85.09,117.88) v2(85.06,107.92) v2(85.55,107.52) v2(85.63,108.25) v2(86,117.88) v2(86.26,108.31) v2(86.82,117.86) v2(86.89,108.25) v2(87.53,108.31) v2(87.58,117.86) v3(119.94,90.92) v3(122.86,95.99) v3(123.35,97.15) v3(123.77,95.99) v3(124.19,97.17) v3(125.03,97.19)
0D675V_VTT_S0: length 13.3
  TOP w0.508: 84.66,175.37 DIMM2.77 ; DIMM2.77 84.66,176.85 ; DIMM2.77 83.92,176.11 ; DIMM2.77 85.4,176.11 ; DIMM2.221 85.4,179.91 ; DIMM2.221 84.66,179.17 ; DIMM2.221 84.66,180.65 ; DIMM2.221 83.92,179.91 ; 85.4,170.93 DIMM1.221 84.66,171.66
  L3 w0.508: 84.66,170.19 DIMM1.221 ; DIMM1.221 85.4,170.93 ; DIMM1.221 84.66,171.66 ; DIMM1.221 83.92,170.93 ; DIMM1.77 84.66,167.86 ; DIMM1.77 85.4,167.13 ; DIMM1.77 83.92,167.13 ; DIMM1.77 84.66,166.39
  vias: v1(40.77,185.8) v1(85.98,185.93) v3(41.78,186.36) v3(41.78,185.42) v3(42.7,195.81) v3(42.7,194.87) v3(84.58,184.68) v3(85.56,184.68) v3(86.5,184.65)
1D2V_SM_S3: length 320.6
  TOP w0.254: CPU1.AW25 73.56,128.78 73.56,127.24 73.82,126.98 74.4,126.98 v2(74.42,127)
  TOP w0.305: CPU1.AY18 79.49,130.71 v2(79.25,130.95)
  TOP w0.356: CPU1.AY12 84.97,130.67 85.04,130.74 v2(85.04,130.78) ; v2(74.42,127) 74.45,127.04 74.53,127.04 74.91,127.42 CPU1.AU23 ; CPU1.AY16 81.32,130.89 v2(81.31,130.9) ; v2(74.86,131) 74.91,130.94 CPU1.AY23 ; v2(195.83,74.09) 196.05,74.31 Q2405.4
  TOP w0.381: v2(89.46,127.87) 89.43,127.9 89.43,127.99 89.08,128.34 CPU1.AW10 ; CPU1.AV21 v2(76.74,128.96)
  TOP w0.406: DIMM1.18 34.51,171.38 33.7,172.19 v2(33.7,174.22) 33.7,175 34.51,175.81 DIMM2.18 ; DIMM2.51 v2(62.56,174.47) 62.56,172.11 61.75,171.3 61.75,169.93 62.56,169.11 DIMM1.51 ; CPU1.AV17 80.36,128.34 v2(79.94,128.76) ; CPU1.AT18 79.49,126.51 79.91,126.93 v2(79.94,126.93) ; DIMM1.92 102.51,166.11 102.21,165.81 102.21,164.52 C1030.1 ; CPU1.AW14 83.17,129.25 83.58,129.66 v2(83.58,129.66) ; C1101.1 96.29,166.86 DIMM1.85 ; CPU1.AU13 84.06,127.46 v2(83.62,127.9) ; DIMM2.132 136.51,174.71 v2(136.28,174.49) 135.7,173.9 135.7,172.15 136.51,171.34 DIMM1.132 ; DIMM2.99 v2(108.46,174.55) 108.46,172.11 107.63,171.27 107.63,170.21 107.66,170.12 108.46,169.32 DIMM1.99 ; v2(85.42,127.92) 85.42,127.95 85.81,128.34 CPU1.AV11 ; DIMM2.40 v2(53.21,174.42) 53.21,173.71 52.38,172.87 52.38,172.09 53.21,171.26 DIMM1.40 ; v2(82.67,127.01) 82.64,127.01 CPU1.AU15 ; DIMM2.7 v2(25.16,174.5) 25.16,172.08 24.35,171.26 24.35,169.91 25.16,169.1 DIMM1.7 ; DIMM1.121 127.16,169.1 126.31,169.95 126.31,171.32 127.16,172.17 v2(127.16,174.5) DIMM2.121 ; v2(78.13,127.01) 78.55,127.42 CPU1.AU19 ; v2(76.31,126.93) 76.31,126.9 76.7,126.51 CPU1.AT21 ; DIMM2.110 v2(117.81,174.4) 117.81,173.79 117,172.98 117,172.04 117.81,171.23 DIMM1.110 ; DIMM1.29 43.86,169.22 43.05,170.03 43.05,171.32 43.86,172.13 v2(43.86,174.47) DIMM2.29
  TOP w0.508: PR4802.2 128.63,106.53 ; PR4807.2 132.44,106.65 ; DIMM2.7 24.27,175.22 19.69,175.22 18.45,176.46 18.45,184.36 v2(18.29,184.53) C1208.1 R1203.1 ; PR4803.2 129.39,106.4 ; C1214.1 66.88,155.5 v2(66.93,155.45) C1031.1 ; v2(13.84,185.29) C1105.1 13.91,184.4 R1103.1 ; v2(66.71,162.72) 66.71,160.5 C1102.1 ; v2(120.52,120.42) 120.52,120.4 120.59,120.33 R801.2 ; v2(109.22,233.93) 108.46,234.7 R3816.2 ; v2(190.3,96.67) 190.3,86.91 189.61,86.23 189.61,74.17 190.75,73.03 v2(190.75,72.26) ; v2(179.32,104.39) 180.62,103.1 184.07,103.1 185.06,102.11 v2(185.98,102.11) ; v2(128.27,218.82) 127.76,218.31 127.76,211.33 122.3,205.87 v2(122.3,185.93) ; C1213.1 v2(88.77,159.18) ; PR4809.2 131.67,106.65 ; v2(77.61,156.03) 77.62,156.02 C1028.1 ; PR4806.2 130.91,106.53 ; C1029.1 v2(70.92,159.21) ; PR4805.2 133.2,106.53 ; C1212.1 v2(77.6,148.74) ; PR4801.2 127.86,106.58 ; C1215.1 v2(81.1,164.69) ; PR4804.2 130.15,106.53
  BOTTOM w0.508: v2(185.98,102.11) 186,102.11 186.89,101.21 186.89,98.87 189.09,96.67 v2(190.3,96.67) ; v2(179.32,104.39) 156.3,104.39 148.4,112.29 v3(138.81,112.29) ; v2(18.29,184.53) 16.64,184.53 15.88,185.29 v2(13.84,185.29) ; v2(128.27,218.82) 128.02,219.07 123.23,219.07 117.58,224.73 117.58,225.58 v2(109.22,233.93) ; v2(190.75,72.26) 192.66,72.26 194.49,74.09 v2(195.83,74.09) ; v3(139.32,117.6) 137.54,119.38 128.27,119.38 127.23,120.42 v2(120.52,120.42)
  vias: v1(140.59,119.51) v1(141.48,142.49) v1(147.57,154.05) v3(40.01,184.02) v3(40.77,183.39) v3(78.36,183.26) v3(79.3,183.26) v3(80.34,183.26) v3(81.28,183.26) v3(82.22,183.26) v3(88.52,186.56) v3(88.52,185.42) v3(89.66,186.56) v3(89.66,185.42) v3(90.68,186.56) v3(90.81,185.42) v3(91.06,183.39) v3(92.2,183.39) v3(93.34,183.39) v3(94.49,183.39) v3(95.76,183.39) v3(96.9,183.39) v3(139.32,116.59) v3(140.34,117.6) v3(140.34,116.59) v3(141.6,117.6) v3(141.6,116.59) v3(149.08,163.89) v3(149.86,164.59) v3(149.86,163.58) v3(150.77,163.73) v3(150.88,164.59) v3(151.13,181.1) v3(152.27,181.1)
1D05V_CPU_SA: length 24.4
  TOP w0.305: PG4701.1 PC4705.1
  TOP w0.508: v2(118.11,101.6) 118.24,101.73 C305.1 ; C304.1 v2(118.11,96.14)
  TOP w1.016: PT4702.1 119.27,62.62 ; PT4702.1 119.27,60.72 ; PT4702.1 117.36,60.72 ; PT4702.1 117.36,62.62 ; 125.23,60.72 PT4701.1 ; PT4701.1 127.14,60.72 ; PT4701.1 127.14,62.62 ; PT4701.1 125.23,62.62
  BOTTOM w1.016: 125.23,60.72 PT4701.1 ; PT4701.1 125.23,62.62 ; PT4701.1 127.14,60.72 ; PT4701.1 127.14,62.62 ; 117.36,62.62 PT4702.1 ; PT4702.1 117.36,60.72 ; PT4702.1 119.27,60.72 ; PT4702.1 119.27,62.62
  vias: v1(115.44,53.85) v1(122.1,63.5) v1(123.19,55.37) v3(88.24,106.38) v3(88.27,107.29) v3(88.45,108.31) v3(88.54,109.55) v3(88.95,110.32) v3(89.03,107.7) v3(89.05,106.87) v3(89.05,105.95) v3(89.38,109.53) v3(115.85,58.34) v3(115.93,62.84) v3(115.87,61.39) v3(115.9,59.79) v3(117.73,56.87) v3(119.43,56.9) v3(120.57,61.39) v3(120.73,58.19) v3(120.78,59.64) v3(120.83,56.9) v3(120.95,62.76) v3(122.1,56.85) v3(122.3,61.44) v3(122.28,59.51) v3(123.37,56.92) v3(123.55,60.43) v3(123.6,58.19) v3(123.75,63.04) v3(124.64,57.02)
1D05V_LAN: length 6.9
  TOP w0.203: C3103.1 142.82,37.9 v2(142.68,38.04) 141.96,38.76 U3101.8 ; 136.99,40.34 137.23,40.11 137.75,40.11 137.99,40.34 U3101.30 ; U3101.24 139.16,43.31 138.96,43.51 ; C3107.1 139.65,37.69 139.93,37.97 v2(139.93,37.99) 139.96,38.02 U3101.3 ; 139.96,43.88 U3101.22
  vias: v1(137.92,38.35) v1(143.26,42.29) v2(136.4,47.7) v2(137.17,47.69) v2(139.57,48.31) v2(139.57,47.57) v3(132.84,38.86)
1D8V_PCH: length 38.1
  TOP w0.254: SB1.BB11 210.18,137.82 v2(209.74,137.82) 209.69,137.82 209.16,138.35 208.82,138.35 207.14,140.03 SB1.AR15 SB1.AN15 205.34,140.79 205.34,141.03 205.01,141.36 203.79,141.36 SB1.AG19
  TOP w0.508: v2(212.09,126.87) 212.98,126.87 C2108.1 ; C2108.1 213.65,126.2 R1521.1 ; C2108.1 213.11,127.7 R2310.2 ; R2303.2 212.09,122.06 212.09,121.49 v2(212.01,121.41) 212.42,121.41 213.1,120.73 R1522.1 214.1,120.51 R6316.1 ; R6317.1 212.09,119.48 v2(212.01,119.56)
  BOTTOM w0.508: v2(212.01,119.56) v2(212.01,121.41) 211.2,122.22 211.2,125.98 v2(212.09,126.87) 211.33,127.64 211.33,129.54 209.55,131.32 v1(209.55,132.46) 209.55,133.88 208.81,134.61 208.81,135.89 209.74,136.81 v2(209.74,137.82)
  vias: v2(202.87,142.29)
1D24V_PCH: length 26.7
  TOP w0.254: 205.23,143.37 205.77,143.37 206.29,143.89 207.64,143.89 207.91,144.15 207.91,144.58 208.26,144.94 v2(210.44,144.94)
  TOP w0.279: SB1.BG5 213.07,135.04 213.86,134.25
  TOP w0.508: v2(215.65,132.97) 215.93,132.97 C2109.1 216.26,133.76 214.36,133.76 213.86,134.25
  BOTTOM w0.254: v2(215.65,132.97) 215.65,133.86 215.93,134.14 215.93,135.94 215.49,136.38 215.49,141.67 212.71,144.45 v1(211.86,144.45) 211.41,144.45 210.93,144.94 v2(210.44,144.94)
2D5V_VPP_S3: length 25.5
  TOP w0.508: DIMM1.288 147.45,172.53 ; DIMM1.288 146.71,171.79 ; DIMM1.288 146.71,173.26 ; DIMM1.288 145.97,172.53 ; DIMM1.286 145.01,173.26 ; DIMM1.286 145.75,172.53 ; DIMM1.286 145.01,171.79 ; DIMM1.286 144.27,172.53 ; DIMM2.143 145.86,176.85 ; DIMM2.143 145.12,176.11 ; DIMM2.143 146.6,176.11 ; DIMM2.143 145.86,175.37 ; 145.86,170.19 DIMM1.287 ; DIMM1.287 146.6,170.93 ; DIMM1.287 145.12,170.93 ; DIMM1.287 145.86,171.66 ; DIMM2.142 145.75,177.71 ; DIMM2.142 145.01,176.97 ; DIMM2.142 144.27,177.71 ; 145.97,181.51 DIMM2.288 ; DIMM2.288 147.45,181.51 ; DIMM2.288 146.71,182.25 ; DIMM2.288 146.71,180.77 ; 145.67,169.42 145.01,168.76 DIMM1.142 ; 145.12,179.91 DIMM2.287 ; DIMM2.287 146.6,179.91 ; DIMM2.287 145.86,180.65 ; DIMM2.287 145.86,179.17 ; 146.6,167.13 DIMM1.143 145.86,167.86 ; DIMM2.286 145.75,181.51 ; DIMM2.286 145.01,180.77 ; DIMM2.286 145.01,182.25
  TOP w0.762: DIMM2.142 145.01,178.66
3D3V_AUD_S0: length 19.6
  TOP w0.305: v2(61.42,225.63) 61.86,226.07 U2701.5 ; U2701.37 57.58,233.89 56.96,234.51
  TOP w0.508: 56.96,234.51 C2707.1 55.18,234.51 C2706.1 v2(54.18,234.57) ; C2718.1 61.3,225.51 v2(61.42,225.63)
  BOTTOM w0.508: v2(61.42,225.63) 61.42,225.83 59.72,227.53 v2(58.29,227.53) v1(55.04,230.79) 54.18,231.65 v2(54.18,234.57)
3D3V_CARD_CON_S0: length 0.8
  BOTTOM w0.762: v2(46.81,238.86) v1(46.81,238.1)
3D3V_CARD_S0: length 8.2
  TOP w0.305: U3301.5 41.26,230.39 41.44,230.21
  TOP w0.508: v3(41.66,230) 41.44,230.21
  BOTTOM w0.762: v3(41.66,230) 41.91,230 42.93,231.01 v1(42.93,232.79) 42.93,235.33 v3(43.56,235.97)
3D3V_LAN: length 5.7
  TOP w0.203: 138.77,44.31 139.56,43.52 U3101.23 ; U3101.11 143.98,40.34
  TOP w0.508: RJ45R1.21 136.16,25.75 ; RJ45R1.21 135.25,24.84 ; RJ45R1.21 136.16,23.93
  vias: v1(137.29,34.67) v1(146.18,42.29) v2(134.8,34.42) v2(135.64,34.42) v2(136.07,35.05) v2(137.16,50.29) v2(137.38,49.45) v2(138.18,50.04) v2(145.62,37.8) v2(146.43,37.72)
3D3V_PCIVAUX_SB: length 109.7
  TOP w0.203: 195.99,63.65 195.76,63.42 195.76,61.69 195.96,61.49 U9501.4
  TOP w0.508: SLOT4.27 218.36,32.47 217.61,33.21 ; 195.99,63.65 195.99,66.21 R9512.2 195.99,66.23 v2(195.99,67.49) 195.99,68.94 v2(194.18,70.74) ; v2(198.5,30.48) 198.31,30.67 v2(190.75,30.67) C9410.1 188.7,30.67 187.15,29.12 SLOT2.B10 ; SLOT1.B10 165.49,28.89 C9404.1 170.81,28 v2(170.81,26.54) ; C9312.1 206.43,29.65 SLOT3.B10 ; R9501.2 197.55,67.56 v2(197.23,67.56)
  BOTTOM w0.508: v2(197.23,67.56) 196.11,67.56 196.04,67.49 v2(195.99,67.49) ; v2(194.18,70.74) 192.63,69.19 192.63,62.93 193.01,62.54 193.01,60.33 193.22,60.13 193.22,59.6 192.85,59.23 192.71,59.1 192.71,59.1 192.71,56.14 192.71,50.39 190.62,48.3 190.62,30.81 v2(190.75,30.67) ; v2(170.81,26.54) 176.07,26.54 177.58,28.05 179.5,28.05 180.35,27.19 184.06,27.19 185.58,28.71 SLOT2.B10 ; SLOT3.B10 201.09,29.12 199.73,30.48 v2(198.5,30.48)
3D3V_S0: length 946.5
  TOP w0.203: v2(211.13,52.51) 211.13,52.61 211.61,53.09 U9501.72 ; U9501.47 204.05,47.48 ; v2(207.72,47.29) 207.72,47.42 208.05,47.75 U9501.57 ; v2(58.72,22.16) 59.22,21.65 U5901.14 ; 213.46,57.89 U9501.84 ; U9501.123 200.45,63.2 200.68,62.97 v2(201.8,62.97) ; 212.26,88.07 U2401.4 ; U9501.94 213.18,61.89 213.46,62.17 213.46,62.84 213.89,63.27 C9521.1 ; U5901.26 64.98,21.25 65.46,20.78 v2(65.46,20.68) ; U9501.110 205.65,63.11 v2(205.51,62.97) ; U9501.35 199.25,47.56 198.92,47.23 C9519.1
  TOP w0.305: NGFF2.72 v2(153.36,130.94) ; NGFF2.14 138.86,130.48 138.56,130.78 v2(138.4,130.78) 138.36,130.74 NGFF2.12 ; NGFF2.74 154.28,129.18 v2(154.52,129.41) ; U3301.4 40.76,229.37 40.89,229.24 ; v2(139.22,130.96) 139.36,130.82 NGFF2.16 ; NGFF2.4 136.36,130.7 v2(136.26,130.8) 135.86,130.4 NGFF2.2 ; v2(139.95,130.95) 139.94,130.95 139.86,130.87 NGFF2.18 ; NGFF2.70 152.86,130.1 152.53,130.43 v2(152.53,130.94)
  TOP w0.356: v2(26.9,24.05) 26.8,24.16 25.73,24.16 25.58,24 U5601.2 ; Q5601.2 Q5601.5 22.48,24.02 R5610.2 22.67,24.26 23.43,25.02 v2(23.88,25.02) ; Q2406.4 203.69,77.89 202.95,78.64 v2(201.47,78.64) 201.47,77.99 R2415.1 ; v2(25.58,26.26) U5601.5
  TOP w0.381: R2324.2 26.9,24.3 v2(26.9,24.05) ; v2(25.58,26.26) 26.37,27.05 R1908.2
  TOP w0.406: 155.08,34.23 U4004.5 ; 156.4,28.38 U4006.5 155.08,27.92 v2(154.55,27.39) ; C4001.1 189.14,176.51 U4001.5 ; 155.08,19.64 U4007.5
  TOP w0.508: v2(196.72,169.8) 197.03,169.49 R1810.2 R1811.2 ; C5905.1 67.31,21.44 66.47,20.6 65.53,20.6 v2(65.46,20.68) ; C5905.1 68.11,22.35 R5903.2 ; C5905.1 68.33,21.22 v2(68.33,20.55) ; R2435.1 206.95,82.03 v2(207.7,82.78) ; R6421.2 R6420.1 23.3,238.06 25.17,236.19 v2(25.17,236.12) ; SLOT3.A10 200.4,28.12 SLOT3.A9 202,28.12 203,27.12 SLOT3.B8 206.03,27.25 C9408.1 ; R1704.2 201.78,169.47 198.65,172.59 v2(196.72,172.59) ; v2(145.41,28.7) 145.41,30 145.54,30.12 145.54,34.04 v2(145.8,34.29) ; R2329.2 209.31,119.85 v2(208.94,120.22) ; R2470.2 200.38,79.62 R2469.2 R2465.2 200.42,78.35 199.58,77.51 R2413.1 199.39,77.29 v2(198.81,76.71) ; C4001.1 v2(188.58,177.88) 190.33,177.88 191.87,176.34 191.87,172.47 ; L5901.1 68.33,28.96 73.28,28.96 73.86,28.37 v2(73.86,26.8) ; v2(151.56,199.85) 151.51,199.8 R4022.2 ; v2(73.86,26.8) 74.09,26.57 74.09,25.06 R5919.1 75.04,21.59 v2(75.04,14.48) 78.22,11.3 78.87,11.3 D2602.K ; v2(73.86,26.8) 70.9,26.8 R5918.1 ; v2(191.01,91.95) 191.26,92.2 191.27,92.2 191.45,92.38 R2459.2 ; v2(150.5,41.02) 149.8,40.32 R1803.2 148.53,40.32 v2(148.21,40.64) ; v2(154.55,27.39) 155.19,26.74 C4004.1 ; v2(196.72,174.62) 199.64,174.62 204.55,169.72 v2(205.36,169.72) R1911.2 ; 212.26,88.07 212.32,88.13 C2406.1 213.16,88.6 212.85,88.9 v2(212.85,89.03) ; R4801.1 136.53,85.72 142.44,79.81 142.44,68.51 145.29,65.66 v2(145.62,65.66) ; 204.05,47.48 204.05,46.61 C9520.1 v2(204.03,45.77) ; v2(148.21,48.39) 146.56,46.74 v2(146.05,46.74) 144.87,46.74 R3103.1 ; v2(56.39,18.54) 56.26,18.41 L5902.1 ; R2302.2 v2(206.43,169.75) 206.45,169.72 208.35,169.72 v2(208.79,169.29) 209.19,168.88 R1601.2 ; R5905.1 R5906.1 56.67,24.75 56.67,22.95 56.64,22.92 ; v2(213.87,57.89) 213.46,57.89 ; L2702.1 v2(52.58,225.55) 52.51,225.49 R2717.1 ; R2003.2 206.44,115 205.87,114.43 v2(205.61,114.43) ; C4004.1 155.91,27.32 156.96,27.32 SLOT1.A10 ; C4004.1 155.38,26.61 155.88,26.11 155.88,20.43 C4005.1 ; R2308.2 219.48,144.26 R1801.2 220.71,144.04 223.32,144.04 226,146.72 v2(226.8,146.72) ; v2(26.67,236.22) 27.5,237.05 R6416.2 ; v2(191.95,75.44) 190.47,76.91 190.47,85.47 191.01,86 191.01,89.21 v2(191.31,89.52) 191.39,89.59 191.39,89.88 R2461.2 ; R2327.2 R1907.2 R1906.2 208.66,110.55 R1806.1 208.85,111.34 v2(208.66,111.53) 208.7,111.57 v2(210.19,111.57) 210.5,111.25 210.52,111.25 211.54,110.24 211.72,110.24 212.61,109.35 v2(212.62,109.35) ; R2463.2 R2464.2 205.51,80.52 v2(205.16,80.16) ; 226.2,148.96 226.91,148.96 v2(226.95,149) ; 226.2,148.96 226.2,149.03 225.93,149.3 R2002.2 R6403.1 ; 226.2,148.96 225.78,148.54 R6422.1 225.51,148.08 224.84,147.41 223.89,147.41 R1910.2 R6402.1 ; 56.64,22.92 R5907.1 58.17,22.16 v2(58.72,22.16) ; 56.64,22.92 C5904.1 55.3,22.92 R5901.1 54.22,22.93 R5902.1 53.37,22.95 v2(52.58,22.16) ; v2(211.24,185.97) 212.89,185.97 213.87,186.94 220.43,186.94 221.39,187.91 222.77,187.91 223.98,189.13 228.02,189.13 229.16,187.99 v2(229.16,187.48) ; v2(229.44,45.9) 230.2,45.9 C9209.1 ; SLOT4.77 218.32,63.37 214.66,63.37 C9521.1 ; R1706.2 190.2,168.29 190.79,168.88 R1714.2 190.79,169.4 190.17,170.03 v2(190.07,170.03) 190.07,170.66 191.87,172.47 ; R9101.1 v2(193.14,180.85) 191.97,180.85 183.06,189.76 v2(183.06,190.32) ; v2(170.05,27.2) 169.7,26.85 C9403.1 ; v2(198.5,45.81) 198.5,45.85 198.92,46.27 C9519.1 ; R6404.1 225.91,152.21 v2(225.91,151.51) ; R9204.1 R9205.1 v2(231.46,90.68) ; 191.87,172.47 193.07,172.47 193.34,172.19 195.37,172.19 196.36,171.2 v2(196.72,171.2) 197.97,171.2 199.39,169.77 R1807.2 R1809.2 ; 156.4,28.38 156.72,28.7 156.72,32.87 156.02,33.57 C4002.1 155.08,34.01 155.08,34.23 ; R4003.1 v2(88.65,26.92) ; D2601.K 17.08,130.49 R2603.1 v2(17.91,131.95) ; v2(199.95,74.69) R2412.1 ; R2707.1 R2706.1 50.42,230.22 v2(50.42,230.22) ; R1805.2 v2(211.2,107.31) ; v2(209.55,75.18) R2414.1 ; v2(198.5,43.43) 198.37,43.31 R1505.1 ; v2(153.42,40.51) R1506.1 ; R2462.2 213.8,105.35 213.51,105.05 v2(213.49,105.05) 213.49,105.03 213.8,104.71 R2476.2 ; R6314.1 197.62,206.51 195.43,204.31 v2(195.43,200.53) ; v2(222.07,155.19) R2001.2 ; 40.89,229.24 40.93,229.2 ; v2(155.32,48.54) v2(155.32,59.18) ; v2(99.69,27.43) 100.08,27.05 v2(100.08,25.53) 100.08,23.28 99.57,22.77 R4005.1 ; C9208.1 v2(229.69,59.5) ; C9207.1 v2(229.57,82.61) ; R1912.2 188.61,168.24 188.35,168.49 v2(188.29,168.49) ; C9311.1 v2(190.55,27.74) ; v2(225.52,103.3) LPC1.10
  TOP w0.762: v3(42.8,226.19) 41.91,227.08 C3302.1 41.91,228.54 C3301.1 41.54,228.6 40.93,229.2
  L3 w0.508: DIMM2.284 143.31,182.25 ; DIMM2.284 143.31,180.77 ; DIMM2.284 144.05,181.51 ; 143.31,173.26 DIMM1.284 144.05,172.53 ; 143.31,176.97 DIMM2.140 ; DIMM2.140 144.05,177.71 ; DIMM2.140 143.31,178.45
  BOTTOM w0.381: v2(198.5,45.81) v2(198.5,43.43) ; v2(208.94,120.22) 208.94,117.42 210.82,115.54 210.82,112.2 v2(210.19,111.57)
  BOTTOM w0.508: v2(205.36,169.72) 205.38,169.75 v2(206.43,169.75) ; v2(195.43,200.53) 195.25,200.36 189.61,200.36 186.26,197.01 186.26,195.27 184.3,193.32 184.3,191.57 v2(183.06,190.32) ; v3(107.57,208.28) 111.8,204.05 141.36,204.05 142.47,202.95 147.55,202.95 150.65,199.85 v2(151.56,199.85) ; v2(193.14,180.85) 191.39,180.85 188.58,178.04 v2(188.58,177.88) ; v2(56.39,18.54) 58.72,20.87 v2(58.72,22.16) ; v3(42.8,226.19) 32.77,236.22 v2(26.67,236.22) 25.21,234.76 ; v2(145.62,65.66) 150.8,65.66 155.32,61.14 v2(155.32,59.18) ; v2(150.5,41.02) 152.91,41.02 v2(153.42,40.51) ; v2(68.33,20.55) 68.76,20.55 74.83,14.48 v2(75.04,14.48) ; v2(73.86,26.8) 78.23,26.8 78.54,27.1 88.47,27.1 v2(88.65,26.92) 88.9,26.67 95.4,26.67 95.91,27.18 99.44,27.18 v2(99.69,27.43) ; v2(196.72,169.8) v2(196.72,171.2) v2(196.72,172.59) v2(196.72,174.62) ; v2(50.42,230.22) 50.42,230.22 52.58,228.06 v2(52.58,225.55) ; v2(17.91,131.95) 18.1,132.14 18.1,164.91 16.89,166.12 16.89,172.29 12.42,176.76 12.42,189.18 8.38,193.22 8.38,209.8 19.3,220.73 19.3,228.85 25.21,234.76 ; SLOT1.A10 159.76,28.12 SLOT1.A9 161.49,28.12 162.43,27.18 165.2,27.18 SLOT1.B8 ; v2(58.72,22.16) v2(52.58,22.16) 38.55,22.16 36.21,24.5 29.39,24.5 28.95,24.05 v1(28.12,24.05) v2(26.9,24.05) 25.81,25.15 ; v2(58.72,22.16) 59.6,22.16 61.09,20.68 v2(65.46,20.68) ; SATAP2.6 188.09,222.94 ; SATAP2.6 187,221.85 ; SATAP2.6 187,224.03 ; SATAP2.6 185.91,222.94 ; v2(145.8,34.29) 147.47,35.96 147.47,39.9 v2(148.21,40.64) 148.21,44.58 v2(146.05,46.74) ; v2(170.05,27.2) 170.36,27.51 175.97,27.51 177.58,29.12 SLOT2.A10 179.44,29.12 180.44,28.12 SLOT2.A9 ; v2(148.21,48.39) 148.36,48.54 v2(155.32,48.54) ; SATAP1.6 149,223.03 ; SATAP1.6 149,220.85 ; SATAP1.6 147.91,221.94 ; SATAP1.6 150.09,221.94 ; v2(25.58,26.26) 25.58,25.37 25.81,25.15 ; v2(23.88,25.02) 25.68,25.02 25.81,25.15 ; v2(208.79,169.29) 208.79,170.67 209.55,171.44 209.55,171.51 209.55,173.31 209.63,173.39 209.63,184.35 v2(211.24,185.97) ; v2(190.07,170.03) 189.83,170.03 v2(188.29,168.49) ; v2(191.31,89.52) 190.35,90.49 190.35,91.32 190.97,91.95 v2(191.01,91.95) ; 25.21,234.76 25.21,236.08 v2(25.17,236.12) ; v2(154.55,27.39) v1(152.48,27.39) 146.73,27.39 v2(145.41,28.7) 144.83,28.12 141.1,28.12 141.08,28.14 128.06,28.14 127.73,27.81 123.03,27.81 122.42,27.2 111.39,27.2 111.29,27.1 111.28,27.1 109.7,25.53 v2(100.08,25.53) ; v2(208.66,111.53) 208.38,111.25 205.38,111.25 204.72,111.91 204.72,113.54 v2(205.61,114.43)
  BOTTOM w0.762: v3(42.8,226.19) 42.82,226.17 49.42,226.17 50.04,225.55 v2(52.58,225.55) 57.53,225.55 59.18,223.9 77.98,223.9 82.68,228.6 91.25,228.6 v3(108.68,211.17)
  vias: v1(123.93,227.63) v1(125.25,224.56) v1(234.52,219.35) v2(136.13,137.35) v2(136.24,138.07) v2(136.27,138.81) v2(153.57,138.3) v2(153.59,137.46) v2(154.23,137.97) v2(193.04,79.91) v2(196.98,79.88) v2(204.34,69.32) v2(207.9,43.96) v2(208.28,68.83) v2(215.54,44.96) v2(233.81,110.06) v2(234.39,109.61) v2(234.99,110.04) v3(95.38,205.36) v3(95.38,201.04) v3(95.89,202.06) v3(96.39,205.36) v3(96.39,201.04) v3(104.52,208.28) v3(105.54,208.28) v3(106.55,208.28) v3(122.94,223.01) v3(123.95,222.76) v3(124.59,221.87) v3(125.22,222.88) v3(125.98,222) v3(142.88,183.26) v3(143.89,183.26) v3(144.53,163.83) v3(144.65,164.85) v3(144.91,183.39) v3(145.41,163.32) v3(145.67,164.59) v3(146.56,163.19) v3(228.47,157.71) v3(229.41,157.71) v3(234.16,159.13) v3(234.82,216.92) v3(234.9,159.69) v3(235.59,216.15) v3(236.35,215.52) v3(237.01,214.85)
3D3V_S5: length 942.3
  TOP w0.203: 212.09,99.76 211.6,99.27 U2401.32 ; U2401.22 211.62,95.26 212.29,94.59 214.08,94.59 214.15,94.53 ; 197.68,102.55 198.4,101.83 U2401.60 ; U2401.77 193.95,94.46 ; U2401.55 200.4,99.97 199.87,99.44 v2(199.39,99.44) ; 206.25,83.57 206,83.82 U2401.120 ; U2401.104 199.6,84.28 199.12,83.81 ; 204.4,102.59 U2401.45
  TOP w0.254: SB1.BE48 SB1.BE49 212.16,156.85 212.74,157.43 v3(214.1,157.43) ; R2014.2 R2044.2
  TOP w0.305: PR4916.1 PR4914.1 PR4912.1 PR4910.1 PR4908.1 PR4924.1 PR4922.1 PR4920.1 PR4905.1 ; PR4918.1 PR4901.1 PR4902.1 PR4903.1 PR4904.1 PR4906.1 PR4905.1 ; PR4905.1 85.22,210.19
  TOP w0.381: C2415.1 214.53,94.53 214.15,94.53 ; v2(209.74,72.16) R2403.1
  TOP w0.406: U2403.5 211.08,74.69 v2(210.95,74.55) ; 87.57,14.9 U2602.5
  TOP w0.508: v2(81.92,235.33) 81.92,238.03 Q2701.E ; v2(81.92,235.33) 82.12,235.33 83.07,234.38 83.07,225.44 v2(82.17,224.54) ; v2(81.92,235.33) 81.09,235.33 C2721.1 80.96,235.46 R2714.2 ; 206.68,80.85 206.68,78.75 ; 206.68,80.85 206.25,81.28 206.25,83.57 ; 206.68,80.85 C2421.1 ; 206.68,78.75 207.21,78.22 207.21,78.1 207.44,77.88 208.38,77.88 209.37,76.89 210.41,76.89 v2(210.82,76.48) ; 206.68,78.75 206.57,78.64 204,78.64 203.27,79.38 v2(201.37,79.38) ; v2(227.15,191.26) 224.21,191.26 222.28,189.33 220.47,189.33 219.99,188.85 215.01,188.85 v2(214.5,188.34) ; R2613.1 87.49,13.3 v2(87.63,13.16) ; R2613.1 87.49,14.82 87.57,14.9 ; R2613.1 86.77,14.05 82.52,18.29 82.52,25.1 84.66,27.23 86.87,27.23 89.31,29.67 94.44,29.67 97.36,32.59 v2(98.42,32.59) ; v2(199.42,82.96) 199.42,82.46 C2423.1 198.81,82.23 198.6,82.45 198.6,83.28 199.12,83.81 ; U2601.5 108.47,63.05 v2(108.13,62.71) ; v2(192.65,95.22) C2420.1 193.95,94.46 193.95,94.46 ; R6306.1 v2(209.22,211.46) ; v2(80.14,222.5) 66.19,222.5 65.58,221.89 34.47,221.89 23.79,232.58 R6401.1 ; v2(210.95,74.55) 211.01,74.49 C2410.1 ; v3(219.02,155.93) 218.54,155.93 218.44,155.83 R2015.2 218.1,154.78 R2318.2 ; v2(226.49,98.63) 226.07,98.21 219.46,98.21 218.95,98.72 218.95,100.02 217.5,101.47 214.61,101.47 214,100.86 213.45,100.86 C2417.1 213.22,100.63 212.97,100.63 212.09,99.76 ; 195.83,99.69 196.34,99.69 196.6,99.44 v2(199.39,99.44) 199.39,96.72 199.9,96.22 206.71,96.22 209.3,98.81 ; v2(234.31,94.87) 232.41,96.77 224.71,96.77 v2(224.65,96.83) 224.62,96.83 224.62,96.87 223.64,95.89 217.93,95.89 215.85,93.8 215.28,93.8 C2415.1 ; R3818.1 112.52,236.22 112.14,236.6 v2(112.14,236.73) ; v2(234.98,86.84) 232.46,84.33 229.41,84.33 227.24,82.16 226.04,82.16 225.07,83.13 223.52,83.13 222.45,82.07 220.88,82.07 218.69,79.88 v2(215.65,79.88) ; 235.28,171.63 234.01,171.63 233.96,171.58 233.04,172.49 227.53,172.49 223.37,168.33 223.37,159.92 223.67,159.61 223.55,159.49 223.72,159.31 ; v2(129.41,218.82) 129.41,217.25 129.92,216.74 R2504.1 130.3,216.57 130.3,204.75 v2(130.24,204.69) ; v2(214.41,178.1) 215.1,177.42 R6318.1 ; R2044.2 219.02,162.43 219.13,162.3 v2(219.13,161.77) ; v2(144.53,204.09) 141.22,200.79 141.22,190.75 142.11,189.87 PR5202.1 ; 204.4,102.59 204.4,103.1 204.89,103.59 204.89,104.01 C2416.1 ; v2(226.85,104.55) 226.49,104.9 223.77,104.9 222.4,106.28 APS1.13
  TOP w1.016: v3(166.17,111.89) 166.17,112.93 169.8,116.56 169.8,130.69 168.27,132.21 168.27,138.77 166.24,140.8 166.24,145.82 158.47,153.59 156.29,153.59 154.82,155.07 152.73,155.07 150.24,157.56 150.24,161.72 159.38,170.87 159.38,193.8 157.23,195.96 157.23,202.31 v3(157.35,202.44) ; v3(180.87,116.33) v2(189.99,116.33)
  TOP w1.27: 235.28,171.63 236.22,170.69 236.22,162.79 232.66,159.23 223.8,159.23 223.72,159.31
  TOP w1.524: 235.28,171.63 235.28,172.62
  BOTTOM w0.406: v2(199.42,82.96) 199.44,82.93 199.44,81.31 v2(201.37,79.38)
  BOTTOM w0.508: v2(129.41,218.82) 128.4,219.84 123.57,219.84 119.18,224.23 119.18,226.52 112.14,233.55 v2(112.14,236.73) 112.08,236.73 110,234.65 106.88,234.65 106.55,234.31 82.93,234.31 v2(81.92,235.33) ; v2(219.13,161.77) 219.13,159.79 v3(218.85,159.51) ; v2(209.74,72.16) 209.74,73.34 v2(210.95,74.55) 212.24,75.84 212.24,76.2 ; 212.24,76.2 211.1,76.2 v2(210.82,76.48) ; 212.24,76.2 212.24,76.94 215.19,79.88 v2(215.65,79.88) ; v2(192.91,101.42) 192.91,101.19 192.33,100.61 192.33,95.54 v2(192.65,95.22) ; v2(108.13,62.71) 108.13,61.44 110.19,59.39 110.19,49.02 109.3,48.13 109.3,34.24 107.65,32.59 v2(98.42,32.59) ; v2(214.5,188.34) 214.5,182.84 215.24,182.11 215.24,179.58 214.41,178.75 v2(214.41,178.1) ; v2(87.63,13.16) 97.36,3.43 113.28,3.43 114.93,1.78 218.06,1.78 233.36,17.08 233.36,22.8 236.73,26.16 236.73,85.09 v2(234.98,86.84) 234.31,87.5 234.31,88.9 235.1,89.69 235.1,94.08 v2(234.31,94.87) ; v2(82.17,224.54) v2(80.14,222.5) ; v2(199.39,99.44) 203.56,103.61 204.29,103.61 205.18,104.5 v2(205.82,104.5) ; v2(224.65,96.83) 224.69,96.87 224.73,96.87 v2(226.49,98.63) 227.33,99.47 227.33,104.06 v2(226.85,104.55)
  BOTTOM w1.016: v3(218.85,159.51) 218.64,159.51 217.91,158.77 217.91,155.97 217.94,155.93 ; 217.94,155.93 216.83,154.81 215.42,154.81 214.4,155.83 214.4,157.12 v3(214.1,157.43) ; 217.94,155.93 v3(219.02,155.93) ; v3(166.17,111.89) 176.25,111.89 180.7,116.33 v3(180.87,116.33) ; v3(192.63,104.67) 192.76,104.8 192.76,113.56 v2(189.99,116.33)
  BOTTOM w1.524: v3(225.12,200.99) 225.12,194.96 225.65,194.43 225.65,192.76 v2(227.15,191.26) 230.33,188.09 230.33,184.43 234.95,179.81 234.95,176.15
  vias: v1(85.47,216.03) v1(86.76,210.49) v1(89.87,210.6) v3(85.34,208.79) v3(85.34,207.77) v3(85.34,206.5) v3(85.34,205.38) v3(85.34,204.34) v3(85.47,212.98) v3(85.47,211.71) v3(86.61,212.72) v3(86.74,211.71) v3(154.03,202.56) v3(154.78,203.48) v3(154.97,202.57) v3(203.86,212.24) v3(204.44,211.08) v3(205.38,211.06) v3(220.98,202.41) v3(221.01,201.32) v3(224.97,202.56) v3(234.57,174.04) v3(235.41,174.04)
3D3V_SB: length 847.9
  TOP w0.203: v2(210.4,138.85) 210.41,138.85 210.41,139.29 SB1.BB14 ; 213.84,96.9 213.48,97.27 212.57,97.27 U2401.27
  TOP w0.305: R2478.2 216.97,71.18 215.52,69.74 U2405.5 ; v2(227.82,181.94) U2002.2 ; U2402.5 212.57,80.62 212.72,80.77 ; U4301.5 219.14,219.07 C4305.1 ; U2402.1 v2(211.18,77.72) ; v2(198.19,143.87) 198.55,144.23 SB1.V23 ; SB1.AT44 207,154.3 v2(206.76,154.05) 206.63,154.05 206.38,154.3 SB1.AN44 ; 208.91,181.61 208.29,180.99 U9101.1 ; U2002.8 227.32,187.2 C2003.1 227.48,187.3 227.82,186.97 U2002.7 ; v2(208.66,137.18) SB1.AW9
  TOP w0.381: R2421.2 190.96,95.64 v2(190.96,93.57)
  TOP w0.406: C2002.1 222.27,184.66 U2001.1 222.27,182.82 221.62,182.17 U2001.5 ; U4009.5 78,23.23 77.36,22.58 ; U4010.5 v2(145.68,199.48) 145.3,199.1 145.3,197.79 C4011.1 145.48,197.55 146.37,196.66 R4018.1 ; C2005.1 224.74,184.59 U2003.5 224.74,182.7 224.09,182.05 U2003.1 ; U4005.5 97.33,26.43 96.68,25.78 U4005.1 96.68,24.55 96.52,24.38 ; v2(94.36,23.67) 94.36,23.82 93.8,24.38 93.2,24.38 U4008.5 92.58,24.39 91.93,25.04 U4008.1 91.31,25.04 C4006.1
  TOP w0.508: v2(94.36,23.67) 94.41,23.67 94.5,23.76 95.2,23.76 C4003.1 95.3,23.76 96.27,23.76 R4001.1 96.29,24.16 96.52,24.38 ; v2(141.8,202.63) 144.42,205.26 149.29,205.26 149.8,204.75 R4017.1 ; v2(179.55,119.99) 177.34,122.2 v2(177.34,127.33) ; R1705.2 203.42,168.95 v2(204.01,168.35) ; v2(190.3,97.43) 190.53,97.43 191.53,98.42 R2425.2 R2427.2 R2421.2 ; R2319.2 217.61,127.37 218.4,126.58 221.93,126.58 222.63,127.28 v3(222.63,127.93) ; C9104.1 211.2,182.75 210.69,183.26 R9104.1 ; C9104.1 211.01,182.05 C9105.1 209.36,182.05 208.91,181.61 ; C9104.1 v2(212.22,182.25) ; v2(111.25,34.8) 102.16,34.8 98.98,31.62 97.54,31.62 92.33,26.42 C4006.1 ; R4803.2 R4802.1 138.3,88.96 138.3,105.91 143.42,111.02 145.24,111.02 145.99,111.77 145.99,116.17 145.28,116.87 145.28,117.66 145.79,118.17 148.86,118.17 v2(149.05,117.98) ; v2(215.01,109.75) 215.37,110.11 217.07,110.11 217.32,109.86 v2(221.74,109.86) ; R2301.2 198.15,165.27 v2(198.15,165.94) ; v2(200.96,166.22) R1605.2 ; v2(194.21,85.5) 194.79,86.08 195.87,86.08 196.52,86.73 196.52,88.06 197.56,89.1 v2(204.77,89.1) ; v2(190.96,93.57) 191.01,93.57 191.11,93.47 R2436.2 ; 213.84,96.9 216.09,96.9 C2408.1 217.17,96.71 217.28,96.6 v2(223.19,96.6) ; R1503.2 202.31,165.71 202.82,166.22 v2(202.95,166.22) ; R2041.1 R1502.2 195.07,167 v2(194.89,167.18) 194.75,167.33 194.52,167.33 R1902.2 ; v2(9.91,190.12) 9.84,190.06 R413.1 ; C2003.1 227.42,188.07 v2(227.38,188.11) ; R2007.2 218.33,145.3 217.7,145.92 v3(217.55,145.92) ; v2(224.05,106.2) 223.4,106.85 APS1.12 223.4,109.6 v3(223.77,109.98) ; R2321.2 224.61,137.1 224.61,136.77 R2010.2 225.1,135.59 225.1,133.21 225.11,132.42 R2034.1 225.11,130.01 224.31,129.21 224.31,128.63 v3(223.61,127.93) ; C2002.1 222.36,185.27 v2(221.8,185.83) ; C2005.1 224.79,184.86 v2(224.79,185.52) ; v2(205.66,79.3) 204.5,79.3 203.86,79.93 203.61,79.93 ; R2431.2 216.79,105.85 R1508.1 217.59,107.7 ; v2(215.67,112.94) 214.72,112.94 213.26,114.4 R2045.2 212.52,114.4 212.21,114.71 v2(210.19,114.71) ; v2(209.63,170.26) 209.63,170.78 R9113.1 ; R1901.2 v2(204.22,164.26) R1602.2 ; v2(151.26,36.45) 151.26,34.93 151.76,34.43 151.76,34.18 151.89,34.05 151.89,26.14 150.57,24.82 150.57,4.23 151.5,3.3 169.04,3.3 170.54,4.8 v2(172.52,4.8) ; v2(215.75,108.31) 216.43,108.31 217.04,107.7 217.59,107.7 ; v2(182.12,207.01) 182.12,208.66 183.9,210.44 ; 217.59,107.7 R2307.2 ; v2(207.12,106.57) 206.71,106.98 206.39,106.98 R2411.1 ; 77.36,22.58 C4007.1 78.75,22.23 R4011.1 79.26,22.4 v2(79.38,22.51) ; R9922.2 131.13,54.29 v2(131.19,54.23) ; R2314.2 R2009.2 R2013.2 225.46,142.88 226.25,143.67 R2012.2 226.25,144.54 v2(225.5,145.29) ; R3811.1 v2(110.49,234.24) ; R1904.2 185.37,173.85 185.37,169.93 v2(185.7,169.6) 186.18,169.11 C2126.1 ; R2478.2 217.04,76.33 214,79.38 214,80.58 C2409.1 213.04,81.09 212.72,80.77 v2(211.87,80.77) 211.68,80.96 R2452.1 ; PR5107.1 v2(235.48,157.85) ; R6410.1 R6412.1 18.22,228.05 v2(18.59,227.69) 18.62,227.71 19.74,227.71 v2(21.51,225.93) ; R2437.2 191.26,91.34 v2(190.98,91.06) ; C4305.1 219.45,219.01 219.96,218.5 219.96,218.31 v2(220.01,218.31) ; v2(198.6,209.68) R1712.1 ; v2(186.4,103.92) 185.55,104.78 v2(184.3,104.78) ; R1509.1 209.16,117.96 208.57,117.55 208.33,117.55 v2(208.29,117.51) ; v2(192.2,85.03) 192.19,85.04 R2432.2 192.19,88.2 v2(191.82,88.57) ; v2(221.64,173.43) R1918.2 ; v2(52.45,224.03) 53.34,224.03 L2703.1 ; v2(139.47,202.6) v2(139.47,218.44) ; R414.1 v2(11.62,182.75) ; v2(230.44,156.97) 227.91,156.97 227.53,157.35 223.68,157.35 222.31,155.98 v2(221.06,155.98)
  TOP w0.762: v2(181.74,215.52) 181.74,212.6 183.9,210.44 R2503.1
  BOTTOM w0.381: 210.19,113.54 v2(210.19,114.71) 210.19,115.43 208.43,117.19 208.43,117.37 v2(208.29,117.51)
  BOTTOM w0.508: 215.01,108.93 215.12,108.93 v2(215.75,108.31) ; 215.01,108.93 214.3,108.22 214.3,103.48 211.22,100.41 210.73,100.41 205.37,95.05 205.37,91 204.77,90.4 v2(204.77,89.1) 204.77,86.13 206.5,84.4 206.5,83.34 v2(206.88,82.96) ; 215.01,108.93 v2(215.01,109.75) 215.01,111.25 215.67,111.91 v2(215.67,112.94) ; v2(198.19,143.87) 199.13,142.93 201.2,142.93 202.68,141.45 204.47,141.45 ; v2(151.26,36.45) 149.1,38.61 149.1,44.59 144.92,48.77 142.94,48.77 139,52.7 133.55,52.7 132.66,51.82 ; v2(111.25,34.8) 113.54,32.51 119.7,32.51 120.26,33.07 122.85,33.07 123.18,33.4 123.18,33.4 126.75,36.97 126.75,42.7 v2(132.08,48.03) ; v2(79.38,22.51) 79.99,23.13 84.27,23.13 84.36,23.22 89.86,23.22 89.94,23.14 90.66,23.14 91.19,23.67 v2(94.36,23.67) ; v2(149.05,117.98) 150.62,117.98 153.01,120.37 160.1,120.37 161.42,121.69 171.55,121.69 177.19,127.33 v2(177.34,127.33) ; 132.66,51.82 132.66,52.76 v2(131.19,54.23) ; 132.66,51.82 v2(132.66,48.73) ; v2(100.75,217.08) 91.39,226.44 82.59,226.44 78.66,222.5 53.98,222.5 v2(52.45,224.03) 51.82,223.39 42.54,223.39 40,225.93 v2(21.51,225.93) ; v2(208.66,137.18) 208.66,137.97 209.54,138.85 v2(210.4,138.85) ; v2(194.21,85.5) 192.66,85.5 v2(192.2,85.03) ; 228.35,25.78 228.35,21.97 227.46,21.08 226.19,21.08 224.92,19.81 223.65,19.81 222.38,18.54 221.11,18.54 219.96,19.68 208.41,19.68 206.63,17.91 196.47,17.91 188.21,9.65 175.26,9.65 172.52,6.91 v2(172.52,4.8) ; v2(186.4,103.92) 186.56,103.76 186.56,102.44 187.53,101.48 187.53,99.14 189.23,97.43 v2(190.3,97.43) ; v2(145.68,199.48) 144.95,199.48 v2(141.8,202.63) 139.5,202.63 v2(139.47,202.6) ; v2(223.19,96.6) 223.52,96.6 225.81,98.88 225.81,101.27 224.64,102.44 224.64,105.61 v2(224.05,106.2) ; 210.19,113.54 210.19,112.5 209.42,111.73 209.42,110.59 209.42,110.59 209.42,110.04 209.42,110.04 209.42,108.08 207.91,106.57 v2(207.12,106.57) ; v2(182.12,207.01) 193.96,207.01 196.63,209.68 v2(198.6,209.68) ; v2(179.55,119.99) 184.3,115.24 v2(184.3,104.78) ; v2(11.62,182.75) 11.62,186.63 10.74,187.5 10.74,189.28 v2(9.91,190.12) 7.49,192.53 7.49,209.93 18.59,221.03 v2(18.59,227.69) ; v2(211.18,77.72) 212,78.55 212,80.64 v2(211.87,80.77) ; v2(191.82,88.57) 192.01,88.76 192.01,90.03 v2(190.98,91.06) 191.02,91.06 191.64,91.68 191.64,93.1 191.17,93.57 v2(190.96,93.57) ; v2(230.44,156.97) 231.01,156.97 231.39,156.59 234.82,156.59 235.48,157.24 v2(235.48,157.85) ; v2(110.49,234.24) 110.49,234.06 v2(118.49,226.06)
  vias: v1(96.22,212.52) v1(101.63,216.38) v1(133.07,227.38) v2(206.43,150.3) v2(207.14,148.84) v2(207.26,141.22) v2(208.38,165.63) v2(217.38,149.98) v2(218.05,150) v2(223.16,128.65) v3(130.56,225.93) v3(131.5,225.93) v3(132.35,225.54) v3(133.07,226.15) v3(213.54,28.6) v3(228.22,105.41) v3(228.6,104.52) v3(233.3,103.5) v3(234.19,104.01)
3D3V_SPI: length 97.2
  TOP w0.508: R2313.2 213.3,165.99 R2317.2 213.3,167.07 213.49,167.26 213.49,171.42 212.22,172.7 212.22,173.36 211.94,173.63 v2(211.94,173.96) ; v2(193.22,193.27) 193.12,193.27 192.53,192.68 192.53,191.2 R2502.1 ; v2(210.79,172.21) 210.79,166.24 211.9,165.14 R2325.2 ; v2(187.83,193.19) 186.26,191.62 R2501.1 v2(189.05,191.07)
  BOTTOM w0.508: v2(187.83,193.19) 189.22,194.58 189.22,198.26 v2(190.32,199.36) ; v2(193.22,193.27) 191.25,193.27 v2(189.05,191.07) ; v2(210.79,172.21) 210.79,172.36 210.79,172.69 211.94,173.84 v2(211.94,173.96) 210.95,174.96 210.95,182.87 212.98,184.9 213.1,185.03 213.1,186.37 212.47,187 212.47,191.97 213.36,192.86 213.36,203.16 210.98,205.54 v1(209.14,205.54) 206.5,205.54 205.41,206.63 204.19,206.63 203.43,207.39 202.5,207.39 199.22,210.67 195.94,210.67 194.18,208.91 v2(191.03,208.91)
3D3V_WLAN_SB: length 9.9
  TOP w0.305: NGFF1.4 210.34,188.5 210.66,188.83 v2(210.66,188.83) ; NGFF1.2 210.43,188 210.47,187.97 v2(210.68,187.97)
  TOP w0.508: v2(211.41,203.17) 212.32,202.26 213.08,202.26 213.64,202.82 215.8,202.82 216.24,202.38 R6311.1 R6312.1
  vias: v1(210.57,189.99) v1(210.69,202.69) v2(210.59,204.72) v2(210.71,204) v2(210.7,187.23) v2(211.46,203.96)
3P0V_BAT_VREG: length 163.4
  TOP w0.254: 214.35,158.14 213.68,158.14 213.51,157.96 212.29,157.96 211.66,157.33 SB1.BD49 SB1.BC49
  TOP w0.508: D2502.3 132.17,213.89 v2(132.59,213.47) ; R1507.2 217.65,175.09 R2042.1 v2(218.82,175.09) ; 214.35,158.14 216.45,160.24 C2102.1 C2103.1 218.4,160.63 219.86,160.63 220.6,161.37 221.82,161.37 222.33,161.87 222.33,169.16 223.57,170.41 223.57,171.5 222.96,172.11 222.96,172.99 R2040.2 222.49,173.14 221.84,172.49 219.4,172.49 v2(218.82,173.08)
  BOTTOM w0.508: v2(132.59,213.47) 158.58,213.47 161.47,210.59 193.34,210.59 195.19,212.45 201.48,212.45 203.83,210.1 210.02,210.1 v1(212.09,208.03) 212.34,207.77 214.3,207.77 218.14,203.94 218.14,187.68 218.82,186.99 218.82,179.07 219.04,178.86 219.04,177.28 218.82,177.06 v2(218.82,175.09) v2(218.82,173.08)
3P3V_S5_EN: length 4.2
  TOP w0.102: C5101.1 232.24,156.2 R5101.2 233.22,155.76 v1(233.82,155.16) 233.96,155.03 PU5101.3
A20GATE: length 5.6
  TOP w0.102: R2464.1 205.6,81.89 U2401.119 205.6,86.42 v2(205.69,86.51)
  BOTTOM w0.102: v1(206.22,85.93) 205.69,86.46 v2(205.69,86.51)
ACK64_N1: length 10.6
  TOP w0.102: R9204.2 230.57,88.66 229.82,89.41 226.31,89.41 225.62,88.71 223.45,88.71 221.7,90.47 SLOT4.115
ACPRESENT: length 5.3
  TOP w0.102: R2015.1 216.52,155.14 216.36,155.14 v1(216.33,155.17) 216.31,155.14 215.05,155.14 213.4,153.49 213.21,153.49 SB1.BG42
ALDO_CAP: length 4
  TOP w0.305: U2701.23 68.2,233.39
  TOP w0.508: C2710.1 69.34,232.92 v1(69.13,233.13) 68.87,233.39 68.2,233.39
ALL_SYS_PWRGD: length 5.7
  TOP w0.102: v1(77,26.59) R4016.1 R4014.1 C4008.1 78.26,24.53 U4009.4
AUD_AZACPU_SCLK: length 131.9
  TOP w0.102: v2(177.95,109.52) 178.5,109.52 179.57,110.59 192.38,110.59 194.6,112.82 195.5,113.72 201.17,113.72 205.49,118.03 206.49,118.03 R2027.1 ; v2(150.57,111.71) 150.14,112.14 150.14,118.48 149.41,119.21 137.76,119.21 131.07,112.52 127.25,112.52 118.75,104.02 107.31,104.02 102.75,108.58 95.96,108.58 CPU1.V3
  BOTTOM w0.102: v2(177.95,109.52) 176.86,110.62 176.23,110.62 176.02,110.82 159.38,110.82 158.75,111.46 154.91,111.46 v1(154.7,111.67) 154.43,111.94 150.8,111.94 v2(150.57,111.71)
AUD_AZACPU_SCLK_R: length 16
  TOP w0.089: 206.57,130.37 206.34,130.59 206.34,132.37 206.43,132.46 206.43,133.17 205.99,133.6 205.99,133.83 205.8,134.02 SB1.AM3
  TOP w0.102: 206.57,130.37 206.78,130.15 206.79,130.15 208,128.94 208,127.93 207.98,127.91 207.98,121.64 v1(207.59,121.26) 207.14,120.8 R2027.2
AUD_AZACPU_SDI: length 33.1
  TOP w0.102: R702.1 125.49,109.22 v1(124.94,109.22) 124.28,109.22 118.79,103.73 107.2,103.73 102.71,108.22 CPU1.U1
AUD_AZACPU_SDI_R: length 114.9
  TOP w0.102: v2(177.16,108.89) 177.6,108.89 177.66,108.95 178.25,108.95 179.66,110.36 192.47,110.36 194.83,112.72 195.59,113.49 201.27,113.49 205.51,117.73 206.93,117.73 207.62,118.41 207.62,120.37 208.2,120.95 208.2,129.03 206.53,130.7 206.53,132.29 206.62,132.38 206.62,133.35 206.26,133.71 SB1.AN3 ; R702.2 126.91,110.96 128.09,112.14 131.22,112.14 138.06,118.98 149.32,118.98 149.83,118.46 149.83,111.84 150.65,111.02 v2(150.9,111.02)
  BOTTOM w0.102: v2(177.16,108.89) 175.46,110.59 v1(157.86,110.59) 154.1,110.59 153.03,111.66 151.54,111.66 v2(150.9,111.02)
AUD_AZACPU_SDO: length 128.6
  TOP w0.102: v2(151.21,112.42) 151.26,112.47 151.26,113.67 v1(150.85,114.07) 150.39,114.53 150.39,118.55 149.51,119.44 137.66,119.44 131.07,112.84 127.08,112.84 118.48,104.24 107.48,104.24 102.94,108.78 96.67,108.78 CPU1.V2 ; v2(178.46,110.19) 179.2,110.92 192.38,110.92 194.37,112.91 195.4,113.94 200.88,113.94 205.61,118.68 R2025.1
  BOTTOM w0.102: v2(178.46,110.19) 177.6,111.05 164.17,111.05 163.19,112.03 155.46,112.03 155.07,112.42 v2(151.21,112.42)
AUD_AZACPU_SDO_R: length 15.7
  TOP w0.089: SB1.AM2 205.77,133.42 206.24,132.95 206.24,132.54 206.15,132.45 206.15,130.51 206.71,129.95
  TOP w0.102: 206.71,129.95 207.72,128.93 207.72,122.28 206.38,120.93 v1(206.38,120.57) 206.07,120.27 R2025.2
AUD_BEEP: length 8.4
  TOP w0.203: C2716.1 69.65,225.81 69.44,226.01 v1(69.39,226.01) 69.27,226.14 67.13,226.14 66.55,225.55 63.96,225.55 63.36,226.15 U2701.8
AUD_BEEP_R: length 4.3
  TOP w0.102: v1(75.51,225.91) 75.35,225.74 R2702.1 R2704.1 C2717.1 71.32,225.74 C2716.2
AUD_LINE1_L: length 288.9
  TOP w0.203: v2(15.65,23.83) C3001.1 ; v2(63.85,234.11) 63.86,234.11 U2701.28
  BOTTOM w0.203: v2(63.85,234.11) 63.85,234.12 62.26,235.71 v1(61.98,235.71) 61.71,235.71 54.24,243.18 54.24,243.19 47.53,249.91 33.16,249.91 32.09,248.84 14.34,231.09 6.66,231.09 2.79,227.23 2.79,46.52 13.56,35.75 13.56,30.51 13.56,27.58 15.65,25.5 v2(15.65,23.83)
AUD_LINE1_R: length 288.6
  TOP w0.203: U2701.27 64.36,234.28 v2(64.59,234.05) ; v2(14.84,25.52) 14.7,25.66 C3002.1
  BOTTOM w0.203: v2(64.59,234.05) 64.59,234.24 62.23,236.6 61.72,236.6 v1(54.88,243.44) 47.9,250.42 33.78,250.42 33.02,250.42 32.97,250.37 14.15,231.55 6.35,231.55 2.34,227.53 2.34,46.33 13.11,35.56 13.11,30.32 13.11,27.25 v2(14.84,25.52)
AUD_LINE2_L: length 4
  TOP w0.203: C2901.1 69.83,228.85 v1(69.42,228.44) 69.37,228.39 U2701.13
AUD_LINE2_R: length 4.6
  TOP w0.203: U2701.14 68.29,228.89 v1(69.06,229.66) 70.29,230.89 C2902.1
AUD_LINK_SDO_C: length 15.8
  TOP w0.102: v2(222.05,130.89) 221.47,130.3 220.07,130.3 219.18,129.42 Q2001.C 221.21,128.65 222.86,130.3 R2039.1 ; R2038.2 221.51,135.76 v2(221.77,136.02)
  BOTTOM w0.102: v2(221.77,136.02) 221.77,134.03 222.1,133.7 222.1,133.5 222.1,133.49 v1(222.1,131.88) 222.1,130.94 v2(222.05,130.89)
AUD_LINK_SDO_R1: length 59.5
  TOP w0.102: v2(223.69,129.41) 223.96,129.69 R2039.2
  BOTTOM w0.102: JMP1.1 228.91,173.79 230.71,173.79 236.25,168.25 236.25,162.36 232.64,158.75 228.73,158.75 227.71,157.73 227.71,150.62 228.7,149.63 228.7,144.11 228.2,143.6 225.98,141.39 225.98,135.33 225.53,134.87 v1(225.53,134.34) 225.53,131.25 v2(223.69,129.41)
AUD_MIC1_L: length 284.6
  TOP w0.203: C3007.1 16.38,37.59 15.06,38.91 v2(13.54,38.91) ; U2701.15 67.82,229.39 69.11,230.68 v2(69.11,230.78)
  BOTTOM w0.203: v2(69.11,230.78) 68.61,230.28 67.41,230.28 66.93,230.76 v1(66.04,230.76) 62.9,230.76 59.82,233.84 59.82,234.35 46.09,248.08 45.45,248.08 33.92,248.08 16.08,230.24 16.08,221.27 4.7,209.89 4.7,174.13 4.97,173.87 15.95,162.88 15.95,156.85 4.62,145.52 4.62,47.83 v2(13.54,38.91)
AUD_MIC1_R: length 282.5
  TOP w0.203: v2(68.35,230.78) 68.35,230.61 67.64,229.89 U2701.16 ; C3008.1 14.35,38.1 14.05,38.4 13.08,38.4 v2(12.62,38.86)
  BOTTOM w0.203: v2(12.62,38.86) 4.17,47.32 4.17,145.71 15.49,157.04 15.49,162.69 4.78,173.41 4.78,173.41 4.24,173.94 4.24,210.08 15.62,221.46 15.62,230.43 33.46,248.27 33.73,248.54 44.89,248.54 45.64,248.54 45.64,248.54 46.28,248.54 60.33,234.49 60.33,233.98 62.59,231.71 v1(63.75,231.71) 66.74,231.71 67.67,230.78 v2(68.35,230.78)
AUD_MIC2_L: length 9.1
  TOP w0.203: C2905.1 70.03,238.05 v2(69.09,237.11) ; U2701.19 68.32,231.39 68.57,231.64 v2(68.71,231.64)
  BOTTOM w0.203: v2(69.09,237.11) v1(69.09,234.44) 69.09,232.01 v2(68.71,231.64)
AUD_MIC2_L_C: length 5.2
  TOP w0.203: v1(74.07,228.37) 74.07,228.18 R2902.1 73.22,227.77 72.59,228.4 C2901.2 C2902.2
AUD_MIC2_R: length 15
  TOP w0.203: C2904.1 70.92,243.54 71.43,243.02 v2(71.44,243.02) ; U2701.20 67.81,231.89 v2(68.33,232.41)
  BOTTOM w0.203: v2(71.44,243.02) 70.61,242.19 v1(70.61,241.17) 70.61,239.83 68.45,237.67 68.45,232.54 v2(68.33,232.41)
AUD_VREF: length 4.2
  TOP w0.254: v1(64.86,238.05) 66.04,238.05 C2703.1 66.09,236.8 65.36,236.07 U2701.25
AUDOUT_L: length 285.6
  TOP w0.203: U2701.40 61.96,232.39 v2(62.61,233.04) ; v2(18.58,30.93) 18.58,30.94 18.93,31.29 20.24,31.29 21.08,30.45 R3005.1
  BOTTOM w0.203: v2(62.61,233.04) 61.59,234.06 61.59,234.14 61.3,234.44 61.2,234.44 47.83,247.81 v1(47.83,248.06) 46.9,249 45.83,249 33.54,249 33,248.46 33,248.46 14.67,230.12 6.99,230.12 3.71,226.85 3.71,46.97 14.48,36.2 14.48,34.3 17.05,31.72 17.06,31.72 17.27,31.51 17.98,31.51 18.57,30.93 v2(18.58,30.93)
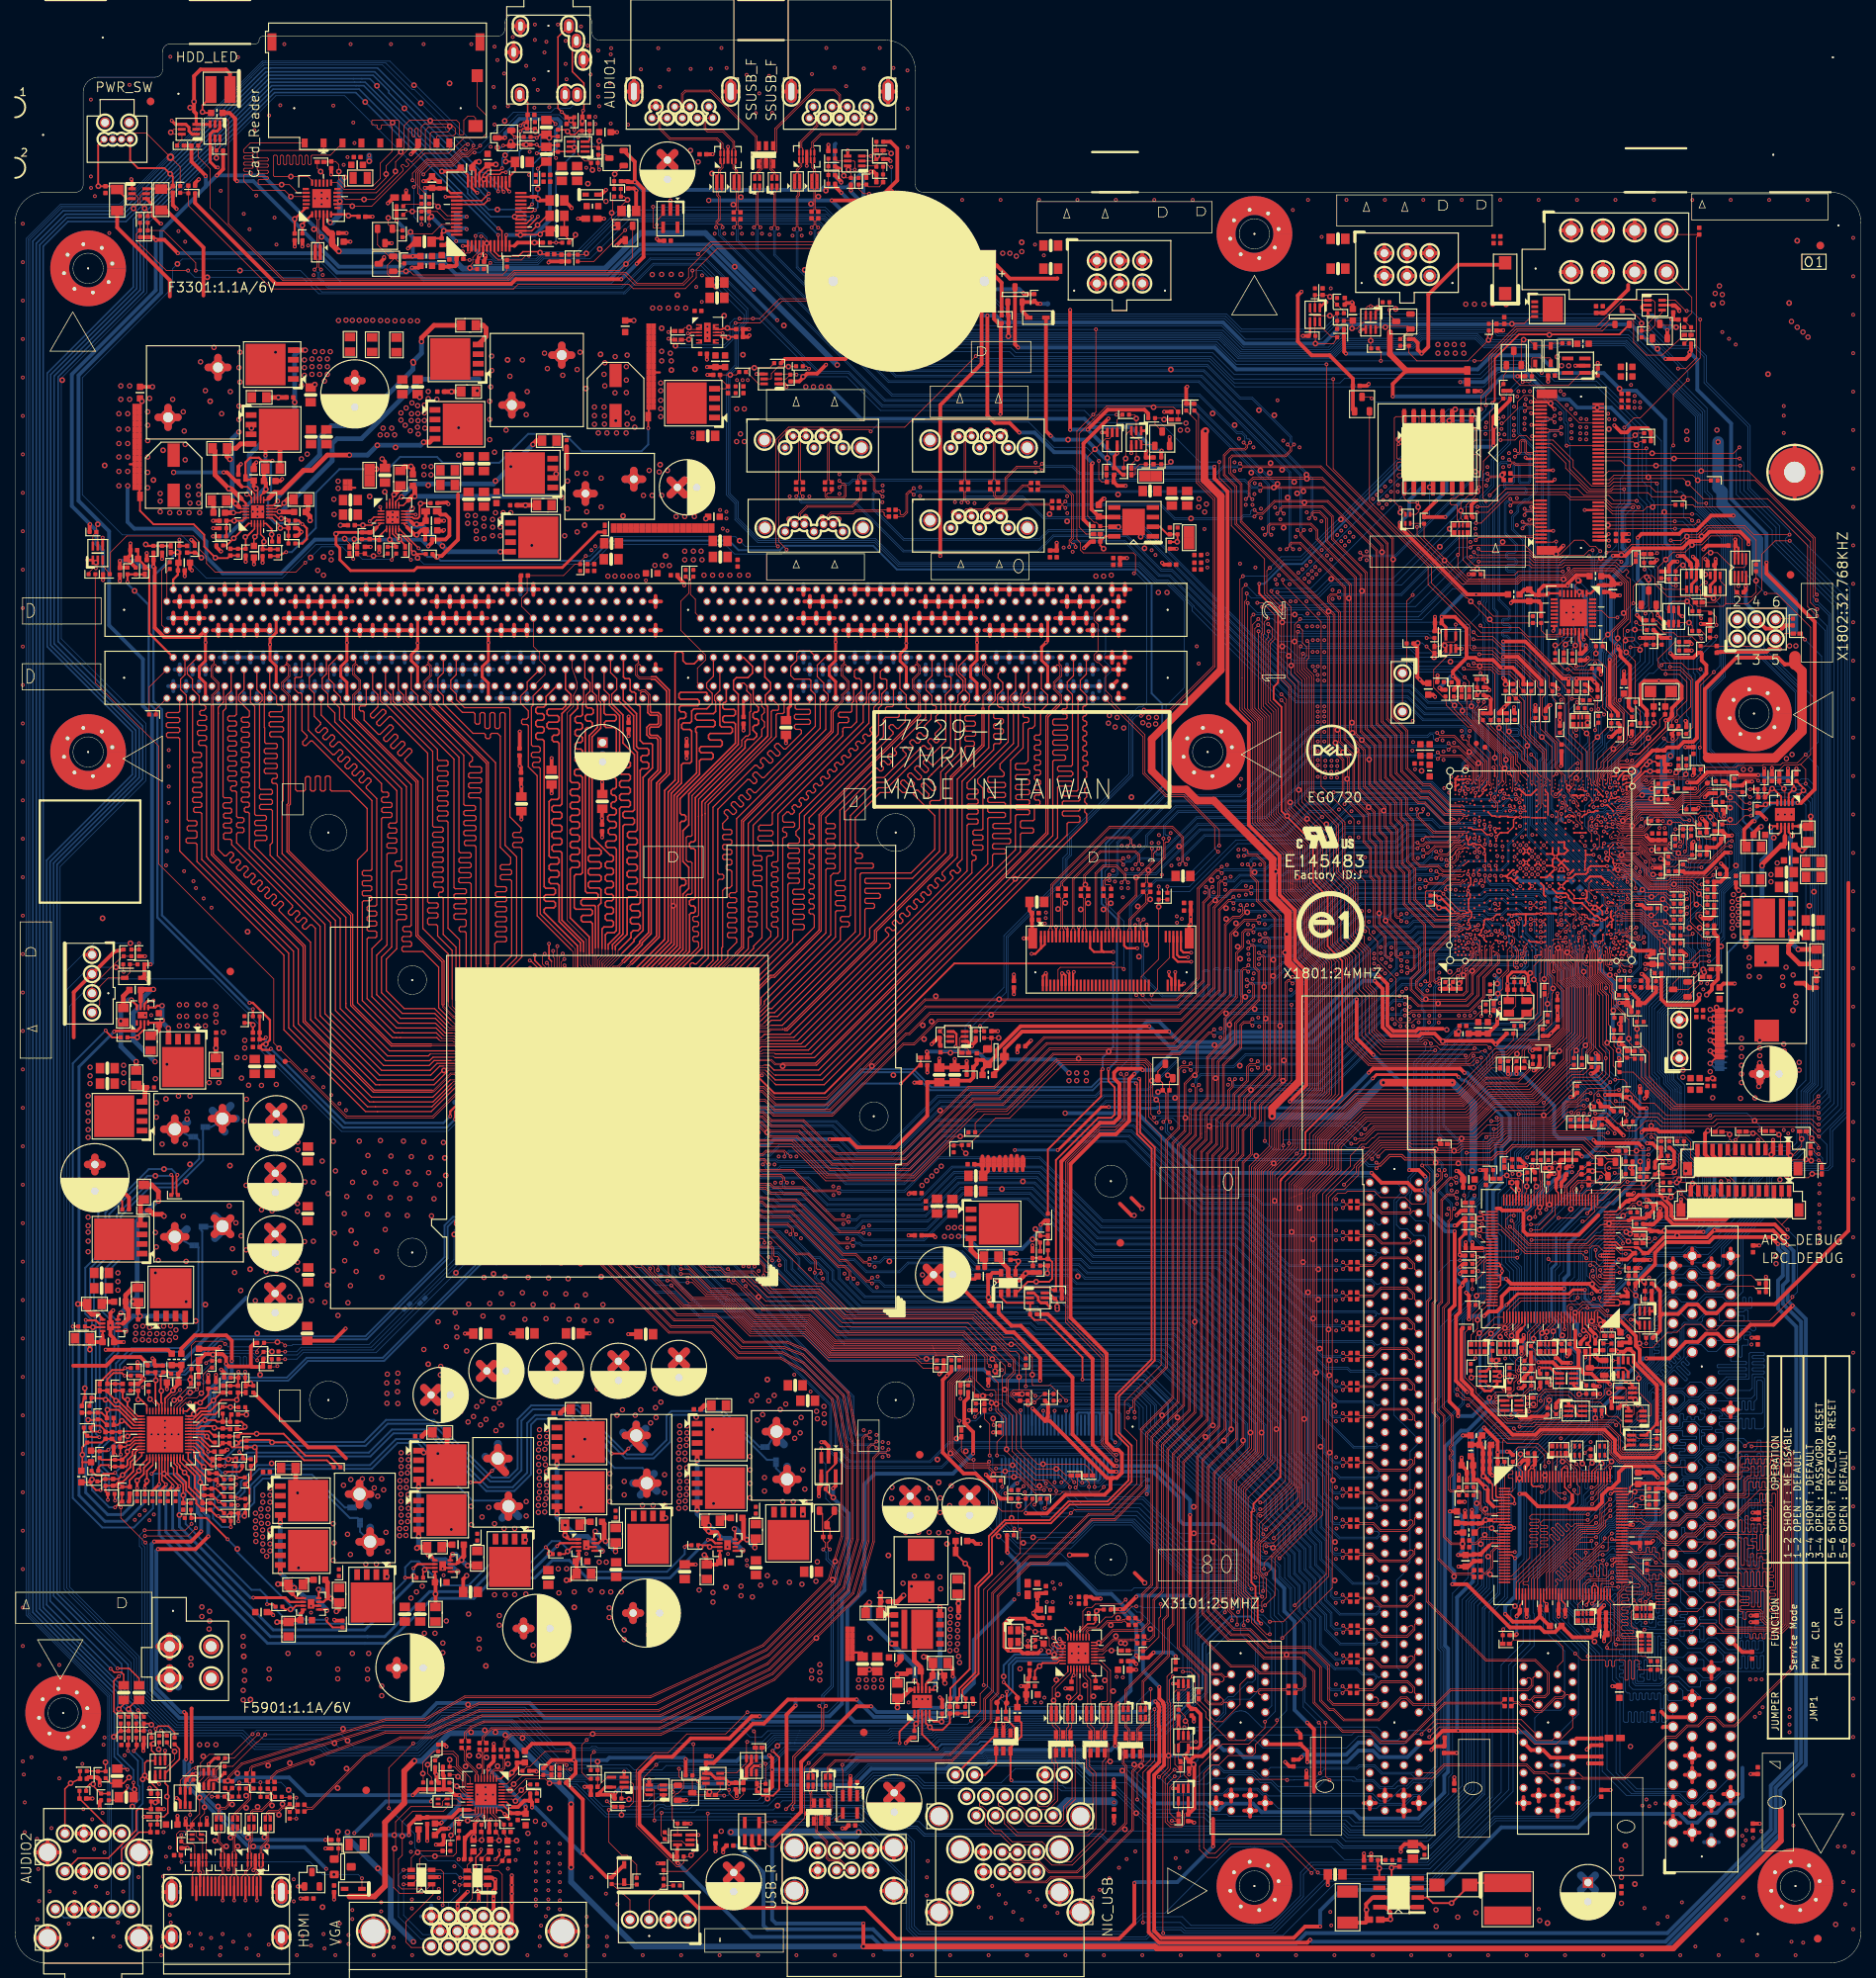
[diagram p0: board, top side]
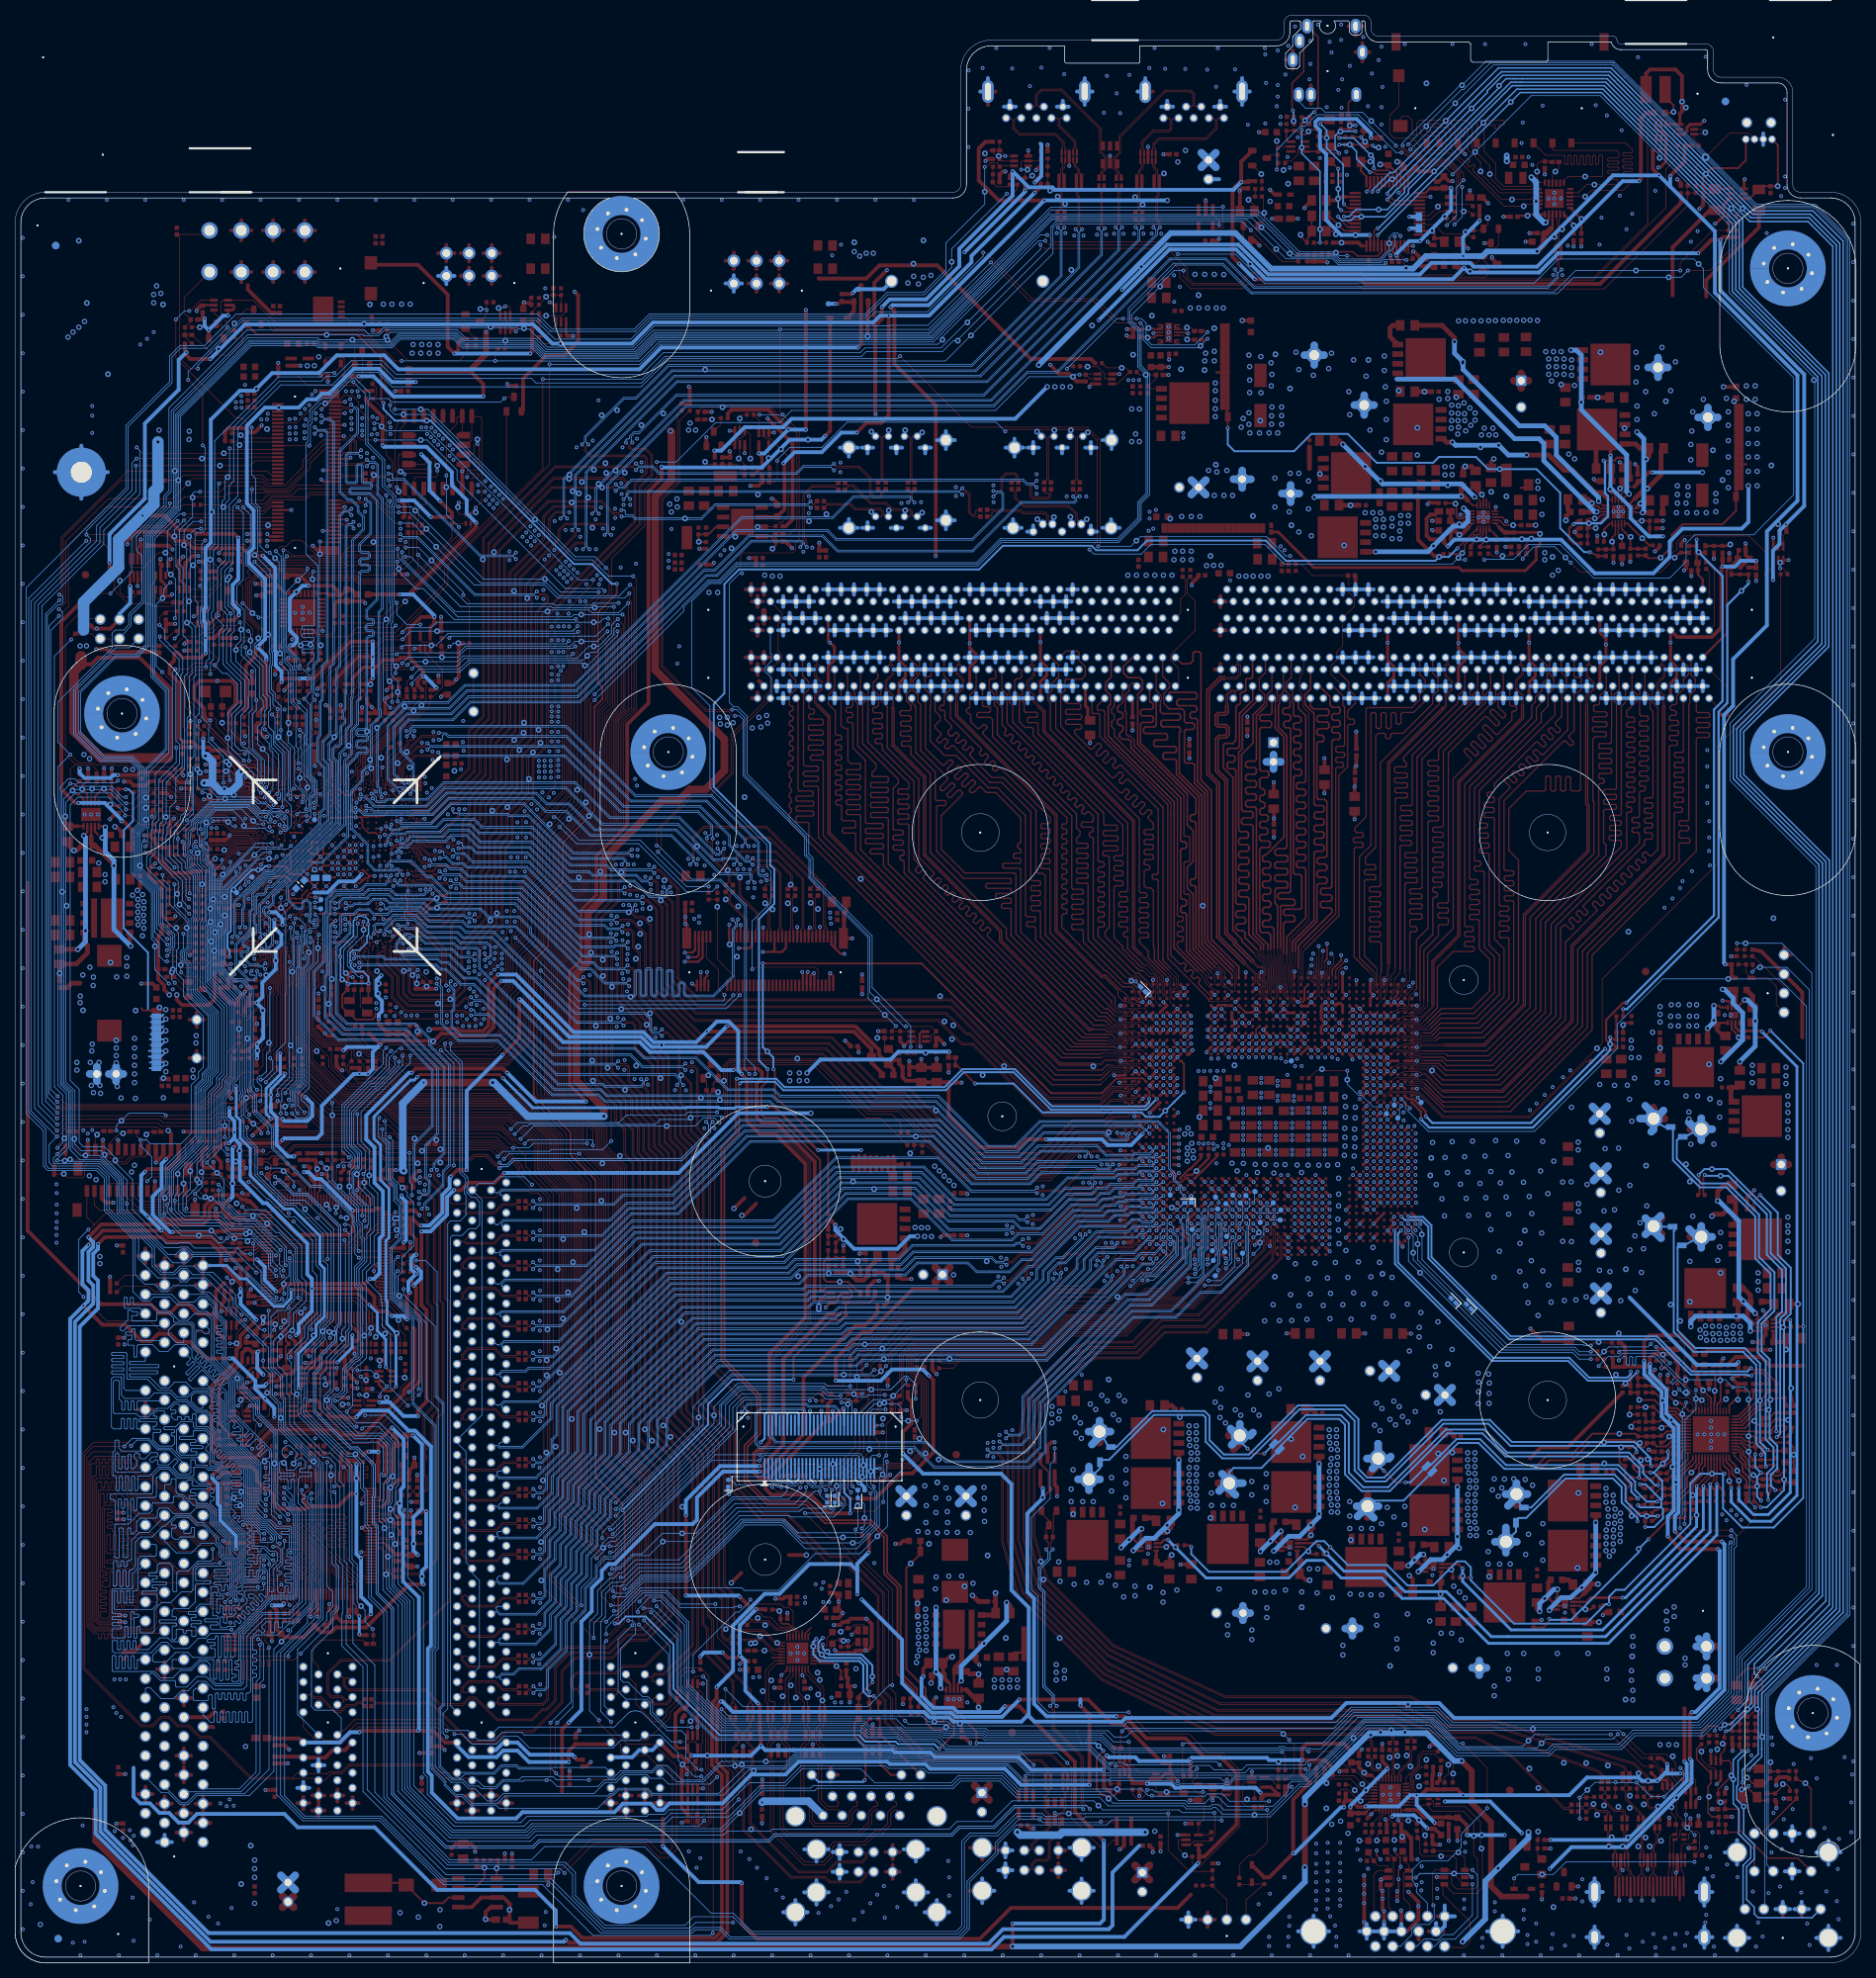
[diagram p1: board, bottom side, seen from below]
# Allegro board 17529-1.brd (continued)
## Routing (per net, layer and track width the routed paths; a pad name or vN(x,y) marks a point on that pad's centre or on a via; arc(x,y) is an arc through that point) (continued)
AUDOUT_LL: length 13
  TOP w0.203: L3003.1 R3007.1 19.68,19.3 20.19,19.81 20.19,21.84 v1(20.07,21.97) 20.19,22.1 20.19,23.37 19.83,23.73 Q3001.3 19.83,25.03 21.72,26.92 21.72,28.26 R3005.2
AUDOUT_R: length 283.5
  TOP w0.203: v2(17.83,30.63) 18.03,30.43 R3006.1 ; v2(62.61,233.81) 61.69,232.89 U2701.39
  BOTTOM w0.203: v2(17.83,30.63) 17.75,30.71 17.42,30.71 14.02,34.11 14.02,36.01 3.25,46.78 3.25,227.04 6.85,230.63 14.53,230.63 32.55,248.65 33.35,249.45 47.34,249.45 49.4,247.39 49.4,247.14 v1(51.46,245.08) 62.61,233.93 v2(62.61,233.81)
AUDOUT_RR: length 9.7
  TOP w0.203: L3004.1 R3009.1 18.86,22.92 17.14,24.64 v1(17.14,24.77) 17.14,26.42 17.43,26.7 Q3001.6 18.53,27.57 18.03,28.07 R3006.2
BATLOW_N: length 9.4
  TOP w0.102: SB1.BF44 212.62,154.4 212.89,154.67 213.13,154.67 213.31,154.84 213.31,154.86 215.34,156.9 219.19,156.9 v1(219.58,157.28) 219.89,157.6 R2016.1
BLUE_CRT: length 9.7
  TOP w0.102: VGA1.3 59.6,7.66 60.45,8.51 60.45,11.79 60.03,12.2 EU5901.4 59.77,12.9 60.24,13.37 C5919.1 60.24,14.39 L5905.2
BPM_CPU_N0: length 84.7
  TOP w0.102: v2(83.95,92.46) 84.48,91.92 84.48,91.34 85.01,90.81 86.45,90.81 88.21,89.04 88.21,89.01 89.5,87.72 93.95,87.72 97.42,84.25 104.58,84.25 107.9,80.92 121.52,80.92 124.59,80.92 125.5,80.02 125.5,78.32 123.77,76.59 123.77,67.88 125.83,65.82 128.56,65.82 128.57,65.81 128.93,65.81 128.94,65.82 131.8,65.82 v1(131.85,65.77) 132.09,65.77 134.92,62.94 136.32,62.94 136.78,62.48 v2(136.83,62.48) ; v2(83.07,95.88) 83.51,96.32 CPU1.D16
  BOTTOM w0.102: v2(83.07,95.88) 83.44,95.51 83.44,92.96 v2(83.95,92.46) ; XDP1.21 139.92,64.07 138.67,62.81 137.16,62.81 v2(136.83,62.48)
BPM_CPU_N1: length 85.3
  TOP w0.102: v2(86.23,90.17) 86.74,90.17 87.99,88.93 87.99,88.91 89.41,87.49 93.86,87.49 97.33,84.02 104.48,84.02 107.81,80.7 121.61,80.7 124.5,80.7 125.27,79.92 125.27,78.41 123.55,76.68 123.55,67.79 125.76,65.57 128.77,65.57 129.46,64.87 130.78,64.87 130.88,64.96 ; 130.88,64.96 130.89,64.96 130.89,64.97 132.26,64.97 134.75,62.48 v2(136.02,62.48) ; 130.88,64.96 v1(130.87,64.96) ; CPU1.D17 82.59,96.34 v2(82.15,95.9)
  BOTTOM w0.102: v2(82.15,95.9) 82.15,95.76 82.8,95.11 82.8,91.97 84.61,90.17 v2(86.23,90.17) ; XDP1.23 139.42,63.9 138.58,63.07 136.6,63.07 v2(136.02,62.48)
BPM_CPU_N2: length 1.5
  TOP w0.102: CPU1.G14 v2(85.8,99.54)
  BOTTOM w0.102: TP401.1 85.71,99.63 v2(85.8,99.54)
BPM_CPU_N3: length 1.6
  TOP w0.102: v2(84.89,100.45) 85.34,99.99 CPU1.H14
  BOTTOM w0.102: v2(84.89,100.45) 84.89,100.79 TP402.1
CAP_1: length 4.8
  TOP w0.203: 209.99,84.82 209.5,85.32 U2401.128
  TOP w0.508: C2414.1 212.22,83.57 v2(211.25,84.53) 210.29,84.53 209.99,84.82
  BOTTOM w0.508: v1(211.2,85.29) 211.2,84.58 v2(211.25,84.53)
CATERR#_CPU: length 3.4
  TOP w0.102: CPU1.D13 86.72,96.79 86.72,97.43 86.99,97.71 v2(87.63,97.71)
  BOTTOM w0.102: TP403.1 v2(87.63,97.71)
CBN: length 3.5
  TOP w0.305: U2701.34 60.86,236.95 C2702.1
  TOP w0.508: v1(61.32,238.02) 60.91,238.02 60.43,237.54 C2702.1
CBP: length 4.9
  TOP w0.305: U2701.36 59.86,236.28 C2702.2
  TOP w0.508: C2702.2 58.42,236.75 v1(56.41,236.75)
CEC_PS_ON_N: length 3.4
  TOP w0.102: R4303.1 v1(219.58,216.15) 219.33,216.41 217.61,216.41 Q4301.C
CEC_PS_ON_N_EXTD1: length 3.2
  TOP w0.102: R4304.2 215.14,214.69 Q4301.B 216.44,213.96 v1(217.11,213.3)
CEC_PS_ON_N_EXTD2: length 8.9
  TOP w0.102: D4303.3 213.47,218.53 215.01,216.98 v1(215.01,216.66) R4304.1 216.09,215.71 216.79,216.41 216.79,217.17 217.73,218.11 U4301.4
CK_100M_CPU_XDP_DN: length 117.7
  TOP w0.102: v2(199.22,132.72) 199.59,133.09 199.59,133.96 199.8,134.17 SB1.Y3 ; v2(155.41,117.99) 155.4,117.99 155.05,118.34 154.23,118.34 153.92,118.03 153.92,110.24 152.32,108.64 152.32,78.66 147.99,74.33 v2(147.99,72.77)
  BOTTOM w0.102: v2(199.22,132.72) 199.05,132.88 195.44,132.88 195.1,132.54 188.19,132.54 187.76,132.11 186.84,132.11 184.77,130.04 183.07,130.04 172.96,119.92 162.72,119.92 161.63,118.83 ; XDP1.42 134.92,72.6 135.06,72.74 135.06,73.11 135.61,73.66 139.09,73.66 139.37,73.94 147.17,73.94 147.66,73.44 147.66,73.09 v2(147.99,72.77) ; 161.63,118.83 161.11,118.31 155.73,118.31 v2(155.41,117.99) ; 161.63,118.83 v1(161.9,118.57)
CK_100M_CPU_XDP_DP: length 117.6
  TOP w0.102: v2(199.16,133.35) 199.38,133.57 199.38,134.05 199.57,134.24 199.57,134.38 SB1.Y4 ; v2(147.12,72.77) 147.32,72.97 147.32,73.23 147.45,73.36 147.65,73.36 147.77,73.48 147.77,74.42 152.11,78.75 152.11,108.73 153.71,110.33 153.71,114.3 ; 153.71,114.3 153.71,118.12 154.14,118.55 155.11,118.55 155.4,118.85 v2(155.4,118.85) ; 153.71,114.3 v1(153.34,114.3)
  BOTTOM w0.102: v2(147.12,72.77) 147.45,73.09 147.45,73.35 147.08,73.72 139.46,73.72 139.18,73.44 135.69,73.44 135.28,73.03 135.28,72.74 135.42,72.6 XDP1.40 ; v2(199.16,133.35) 198.91,133.1 195.35,133.1 195.01,132.75 188.1,132.75 187.67,132.32 186.75,132.32 184.68,130.25 182.98,130.25 172.87,120.14 162.63,120.14 161.02,118.53 155.72,118.53 v2(155.4,118.85)
CLKIN_XTAL: length 10.7
  TOP w0.102: SB1.R6 197.85,135.7 198.22,135.33 198.22,134.82 197.87,134.47 197.87,133.52 198.05,133.33 198.05,133.03 197.46,132.44 197.46,131.06 196.62,130.23 196.62,128.7 v1(196.01,128.09) 196.01,127.36 195.45,126.8 R1815.1
CNV_BRI_DT: length 18.5
  TOP w0.102: SB1.AV4 208.69,134.58 208.69,134.16 208.59,134.07 208.59,133.73 208.76,133.56 208.76,130.55 209.78,129.52 209.78,129.51 209.88,129.41 209.88,128.63 210.62,127.89 210.62,124.02 R2305.1 R2303.1 211.37,121.15 v1(211.96,120.55) 212.89,119.62 R1522.2 213.97,119.62 R1517.2
CNV_BRI_DT_R: length 137.4
  TOP w0.102: v2(238.17,180.81) 237.93,181.05 237.93,188.35 229.13,197.15 v1(222.88,197.15) 210.67,197.15 210.01,196.5 NGFF1.36 ; v2(238.38,113.06) 238.3,112.98 219.1,112.98 215,117.08 R1517.1
  BOTTOM w0.102: v2(238.17,180.81) 237.96,180.81 237.67,180.52 237.67,179.81 238,179.48 238.35,179.48 239.75,178.08 239.75,114.43 v2(238.38,113.06)
CNV_BRI_RSP: length 138.2
  TOP w0.102: v2(238.41,113.79) 238.4,113.79 237.82,113.21 219.33,113.21 215.52,117.02 215.52,119.98 R6316.2 214.51,120.98 214.02,120.98 213.31,121.69 v1(213.31,122.15) 213.31,124.64 211.33,126.62 211.33,128.12 211,128.45 211,129.24 209.39,130.85 209.39,133.72 SB1.AY2 ; R1518.1 221.79,192.68 222.08,192.39 231.89,192.39 236.96,187.32 236.96,179.25 v2(238.2,178)
  BOTTOM w0.102: v2(238.2,178) 239.52,176.68 239.52,114.91 v2(238.41,113.79)
CNV_BRI_RSP_R: length 11
  TOP w0.102: R1518.2 216.78,192.68 v1(216.48,192.39) 215.72,192.39 215.2,191.87 211.12,191.87 210,193 NGFF1.22
CNV_DET_G: length 11.3
  TOP w0.102: v1(215.95,182.78) U6305.D 215.95,178.84 216.52,178.27 R6318.2 216.98,177.42 218.14,176.26 219.02,176.26 219.25,176.49 Q6301.2 Q6301.5
CNV_DET_S: length 9.1
  TOP w0.102: R6313.2 203.35,214.05 D6302.A 200.96,213.69 D6301.A 200.1,214.5 v1(199.42,214.5) 199.1,214.19 U6302.S
CNV_RGI_DT: length 16.5
  TOP w0.102: SB1.BA4 209.8,134.33 209.8,133.35 209.59,133.14 209.59,130.95 211.2,129.34 211.2,128.69 211.96,127.93 R2310.1 211.66,127.52 211.66,126.62 213.13,125.15 214.03,125.15 R1521.2 214.54,124.51 R2312.1 214.4,124.35 v1(214.4,123.42) R1519.2
CNV_RGI_DT_R: length 136.4
  TOP w0.102: R1519.1 214.74,121.53 216.03,120.24 216.03,117.07 219.66,113.44 237.29,113.44 v2(238.38,114.53) ; NGFF1.32 210.67,195.5 211.33,196.16 220.5,196.16 v1(221.13,195.53) 223.16,193.5 231.65,193.5 237.34,187.81 237.34,179.78 v2(238.23,178.89)
  BOTTOM w0.102: v2(238.38,114.53) 239.29,115.44 239.29,176.07 237.74,177.62 237.74,178.51 238.12,178.89 v2(238.23,178.89)
CNV_RGI_RSP: length 140.1
  TOP w0.089: 208.55,131.64 208.55,133.49 208.4,133.64 208.4,134.21 208.46,134.27 SB1.AV3
  TOP w0.102: v2(238.41,112.32) 237.98,112.75 218.85,112.75 213.89,117.72 R6317.2 211.25,118.55 211.25,120.67 210.46,121.45 v1(210.46,121.59) 210.39,121.67 210.39,127.83 209.92,128.3 209.91,128.3 209.58,128.63 209.58,129.44 208.55,130.46 208.55,131.64 ; R1520.1 230.05,195.91 237.67,188.29 237.67,180.56 v2(238.15,180.08)
  BOTTOM w0.102: v2(238.15,180.08) 238.16,180.08 239.98,178.26 239.98,113.89 v2(238.41,112.32)
CNV_RGI_RSP_R: length 15.4
  TOP w0.102: R1520.2 224.14,195.94 v1(222.43,195.94) 221.77,196.6 211.35,196.6 210.76,196 NGFF1.34
CNV_WR_0_DN: length 79.4
  TOP w0.089: SB1.BB3 211.01,133.45 210.87,133.3 210.87,132.79 210.96,132.7 211.15,132.7 211.39,132.7 212.23,131.86 212.23,131.61 v2(212.75,131.09)
  TOP w0.102: v2(199.54,191.32) 199.54,191.57 199.73,191.76 200.52,191.76 200.66,191.62 200.66,191.36 200.77,191.25 NGFF1.15
  BOTTOM w0.102: v2(212.75,131.09) 212.97,130.87 212.97,130.63 212.87,130.53 212.37,130.53 212.26,130.42 212.26,130.23 212.48,130 213.06,130 214.71,131.65 214.71,134.51 212.84,136.38 212.84,138.87 212.51,139.2 212.51,141.33 210.54,143.31 209.45,143.31 202.01,150.74 202.01,158.73 202.4,159.12 202.4,161.05 201.42,162.03 201.42,170.86 200.96,171.32 200.96,191.24 200.47,191.73 199.91,191.73 199.54,191.36 v2(199.54,191.32)
CNV_WR_0_DP: length 79.4
  TOP w0.089: SB1.BB4 210.83,134.08 210.74,133.99 210.74,133.44 210.68,133.38 210.68,132.71 210.88,132.51 211.23,132.51 211.31,132.51 212.04,131.79 212.04,131.09 v2(212.01,131.06)
  TOP w0.102: v2(199.54,192.16) 199.73,191.97 200.61,191.97 200.75,191.83 200.83,191.75 NGFF1.17
  BOTTOM w0.102: v2(199.54,192.16) 199.75,191.95 200.56,191.95 201.18,191.33 201.18,171.41 201.64,170.95 201.64,162.12 202.62,161.14 202.62,159.03 202.23,158.64 202.23,150.83 209.54,143.52 210.62,143.52 212.72,141.42 212.72,139.29 213.06,138.96 213.06,136.47 214.92,134.6 214.92,131.56 213.15,129.78 212.39,129.78 212.04,130.14 212.04,131.04 v2(212.01,131.06)
CNV_WR_1_DN: length 76.2
  TOP w0.089: SB1.BA3 210.5,133.99 210.5,133.54 210.46,133.5 210.46,131.99 210.59,131.86 210.71,131.86 v2(210.93,132.08)
  TOP w0.102: v2(199.27,189.57) 199.74,190.03 200.74,190.03 201.03,189.75 NGFF1.9
  BOTTOM w0.102: v2(199.27,189.57) 199.27,189.85 199.39,189.97 199.92,189.97 200.14,189.75 200.14,167.75 200.27,167.63 200.27,165.65 200.57,165.34 200.57,164.66 200.27,164.35 200.27,163.89 200.84,163.32 200.84,161.04 201.21,160.67 201.56,160.67 201.87,160.36 201.87,159.35 201.39,158.87 201.39,150.68 209.96,142.11 210.54,142.11 210.73,141.92 210.73,141.45 211.09,141.1 211.84,141.1 212.05,140.88 212.05,138.67 212.28,138.44 212.28,137.45 212.05,137.22 212.05,136.12 212.36,135.81 212.77,135.81 213.77,134.81 213.77,134.59 213.58,134.4 213.29,134.4 213.07,134.18 213.07,133.76 213.32,133.5 213.87,133.5 214.02,133.35 214.02,133.15 212.86,131.99 211.85,131.99 211.67,131.81 211.2,131.81 v2(210.93,132.08)
CNV_WR_1_DP: length 76.2
  TOP w0.089: SB1.BA2 210.27,133.64 210.27,131.91 210.57,131.61 210.65,131.61 v2(210.94,131.32)
  TOP w0.102: NGFF1.11 199.65,190.25 199.45,190.25 v2(199.27,190.43)
  BOTTOM w0.102: v2(210.94,131.32) 211.22,131.6 211.76,131.6 211.94,131.78 212.95,131.78 214.24,133.06 214.24,133.44 213.96,133.72 213.41,133.72 213.28,133.85 213.28,134.09 213.38,134.19 213.67,134.19 213.99,134.5 213.99,134.9 212.86,136.03 212.45,136.03 212.27,136.21 212.27,137.13 212.5,137.36 212.5,138.53 212.27,138.76 212.27,140.97 211.93,141.31 211.18,141.31 210.95,141.54 210.95,142.01 210.63,142.33 210.05,142.33 201.61,150.77 201.61,158.78 202.08,159.26 202.08,160.45 201.65,160.88 201.29,160.88 201.05,161.12 201.05,163.41 200.48,163.98 200.48,164.26 200.79,164.57 200.79,165.43 200.48,165.74 200.48,167.72 200.36,167.84 200.36,189.84 200.01,190.18 199.52,190.18 v2(199.27,190.43)
CNV_WR_CLK_DN: length 76.8
  TOP w0.102: v2(197.66,192.59) 197.96,192.89 200.66,192.89 200.8,192.75 NGFF1.21 ; SB1.BD4 211.42,134.53 211.3,134.65 v2(211.3,134.9)
  BOTTOM w0.102: v2(211.3,134.9) 210.97,134.9 210.85,134.77 210.85,134.37 210.73,134.25 210.49,134.25 210.1,134.65 210.1,135.85 210.46,136.22 210.46,137.98 211.28,138.8 211.28,139.33 210.96,139.65 210.42,139.65 209.99,140.07 209.99,141.01 200.55,150.46 200.55,158.91 199.64,159.82 199.64,162.92 198.83,163.73 198.83,166.83 198.56,167.09 198.56,183.72 198.26,184.02 197.42,184.02 197.24,184.2 197.24,184.45 197.42,184.63 198.26,184.63 198.56,184.94 198.56,185.37 198.26,185.67 197.42,185.67 197.24,185.85 197.24,186.11 197.42,186.28 198.26,186.28 198.56,186.59 198.56,187.49 197.09,188.96 197.09,192.85 197.27,193.03 197.47,193.03 197.66,192.84 v2(197.66,192.59)
CNV_WR_CLK_DP: length 76.9
  TOP w0.102: SB1.BE3 211.91,134.04 v2(211.38,134.04) ; v2(197.66,193.46) 198.01,193.11 200.66,193.11 200.8,193.25 NGFF1.23
  BOTTOM w0.102: v2(211.38,134.04) 210.4,134.04 209.88,134.56 209.88,135.94 210.25,136.31 210.25,138.07 211.06,138.89 211.06,139.24 210.87,139.43 210.33,139.43 209.78,139.98 209.78,140.92 200.33,150.37 200.33,158.83 199.43,159.73 199.43,162.83 198.62,163.64 198.62,166.74 198.35,167 198.35,183.63 198.17,183.81 197.33,183.81 197.03,184.11 197.03,184.54 197.33,184.85 198.17,184.85 198.35,185.03 198.35,185.28 198.17,185.46 197.33,185.46 197.03,185.76 197.03,186.19 197.33,186.5 198.17,186.5 198.35,186.68 198.35,187.4 196.88,188.87 196.88,192.94 197.18,193.24 197.45,193.24 v2(197.66,193.46)
CNV_WT_0_DN: length 79.3
  TOP w0.102: v2(203.52,203.59) 203.22,203.89 202.79,203.89 202.65,203.75 NGFF1.65 ; v2(214.32,136.83) 214.17,136.83 213.72,136.37 213.41,136.37 213.09,136.06 212.21,136.06 SB1.BE6
  BOTTOM w0.102: v2(203.52,203.59) 203.22,203.89 202.42,203.89 202.01,203.48 202.01,171.75 202.49,171.27 202.49,162.36 203.4,161.44 203.4,159 202.74,158.34 202.74,151.03 209.79,143.98 210.78,143.98 213.83,140.93 213.83,139.54 214.04,139.32 214.04,137.11 v2(214.32,136.83)
CNV_WT_0_DP: length 79.4
  TOP w0.102: v2(203.52,204.46) 203.17,204.11 202.79,204.11 202.65,204.25 NGFF1.67 ; SB1.BD7 211.78,136.09 211.97,136.27 213,136.27 v2(213.56,136.83)
  BOTTOM w0.102: v2(203.52,204.46) 203.17,204.11 202.33,204.11 201.79,203.57 201.79,171.66 202.27,171.18 202.27,162.27 203.19,161.35 203.19,159.09 202.52,158.43 202.52,150.94 209.7,143.76 210.69,143.76 213.61,140.84 213.61,139.45 213.83,139.23 213.83,137.1 v2(213.56,136.83)
CNV_WT_1_DN: length 80.4
  TOP w0.102: SB1.BG6 213.05,135.64 213.18,135.64 213.46,135.35 214.18,135.35 214.4,135.14 214.88,135.14 v2(215.32,135.57) ; NGFF1.59 202.64,202.25 202.79,202.4 204.07,202.4 v2(204.39,202.08)
  BOTTOM w0.102: v2(215.32,135.57) 215.32,135.58 215.09,135.81 215.09,140.26 214.25,141.1 210.95,144.4 210.03,144.4 203.82,150.61 203.82,151.99 203.23,152.58 203.23,157.89 204.11,158.77 204.11,161.98 203.78,162.31 203.78,166.65 203.52,166.92 203.52,171.41 202.84,172.08 202.84,202.2 203.07,202.43 204.04,202.43 v2(204.39,202.08)
CNV_WT_1_DP: length 80.4
  TOP w0.102: v2(204.39,202.94) 204.07,202.62 202.79,202.62 202.66,202.75 NGFF1.61 ; v2(214.58,135.57) 213.55,135.57 213.27,135.85 212.88,135.85 212.63,135.6 SB1.BF6
  BOTTOM w0.102: v2(214.58,135.57) 214.58,135.59 214.87,135.88 214.87,140.17 210.86,144.18 209.94,144.18 203.6,150.52 203.6,151.9 203.01,152.49 203.01,157.98 203.9,158.86 203.9,161.89 203.57,162.22 203.57,166.56 203.3,166.83 203.3,171.32 202.63,172 202.63,202.29 202.98,202.64 204.1,202.64 v2(204.39,202.94)
CNV_WT_CLK_DN: length 82
  TOP w0.102: NGFF1.71 200.8,205.25 200.66,205.39 199.9,205.39 v2(199.58,205.07) ; SB1.BC5 211.43,135.37 v2(211.58,135.51)
  BOTTOM w0.102: v2(199.58,205.07) 199.25,205.39 199.01,205.39 198.83,205.21 198.83,202.21 201.18,199.86 201.18,194.37 200.06,193.25 199.6,193.25 198.77,192.42 198.77,191.76 198.06,191.05 198.06,189.49 199.52,188.04 199.52,167.36 199.66,167.22 199.66,163.72 200.36,163.02 200.36,160.68 201.19,159.85 201.19,150.47 211.76,139.9 211.76,136.19 211.48,135.91 211.48,135.61 v2(211.58,135.51)
CNV_WT_CLK_DP: length 82.1
  TOP w0.102: v2(210.94,135.91) SB1.BB6 ; NGFF1.73 200.8,205.75 200.66,205.61 199.9,205.61 v2(199.58,205.93)
  BOTTOM w0.102: v2(210.94,135.91) 211.17,135.91 211.54,136.28 211.54,139.81 200.97,150.39 200.97,159.76 200.14,160.59 200.14,162.93 199.44,163.63 199.44,167.13 199.3,167.27 199.3,187.95 197.85,189.4 197.85,191.14 198.55,191.85 198.55,192.51 199.51,193.47 199.97,193.47 200.96,194.46 200.96,199.77 198.62,202.12 198.62,205.3 198.92,205.61 199.25,205.61 v2(199.58,205.93)
CNV_WT_RCOMP: length 4.9
  TOP w0.102: R1512.1 211.51,129.86 v1(210.81,130.55) 210.32,130.55 210.02,130.85 SB1.BA1
CPU1_AY3: length 2.3
  TOP w0.102: CPU1.AY3 95.43,129.25 95.86,129.69 v2(95.86,129.69)
  BOTTOM w0.102: R903.2 95.21,129.04 95.86,129.69 v2(95.86,129.69) 95.97,129.79 v5(96.44,129.79)
CPU1_G8: length 2.9
  TOP w0.102: v2(90.4,99.52) 90.83,99.09 CPU1.G8
  BOTTOM w0.102: v1(91.11,99.8) 90.68,99.8 v2(90.4,99.52) 89.86,100.05 89.78,100.05 89.38,100.44 R902.2
CPU_FAN_CTRL_CONN: length 10.7
  TOP w0.102: FANC1.4 11.18,126.62 11.18,129.03 12.32,130.18 D2601.A 15.18,130.87 R2605.2 R2603.2
CPU_FAN_CTRL_SIO: length 389.4
  TOP w0.102: v2(200.38,96.85) 201.55,96.85 203.6,98.9 U2401.47 ; R2605.1 14.29,131.03 v2(14.35,130.96)
  BOTTOM w0.102: v2(200.38,96.85) 199.86,96.33 199.86,83.83 200.31,83.37 200.31,81.78 202.16,79.93 202.16,79.93 202.34,79.75 202.34,75.76 203.17,74.92 203.17,73.34 199.13,69.29 195.85,69.29 194.84,68.29 194.84,63.81 195.28,63.37 195.28,61.16 195.4,61.04 195.4,58.7 194.89,58.19 194.89,57.04 194.89,55.8 194.89,49.48 194.48,49.06 192.86,47.44 192.86,22.85 186.56,16.55 176.1,16.55 175.28,17.37 150.56,17.37 150.55,17.38 145.2,22.73 138.31,22.73 137.96,23.08 124.17,23.08 119.96,23.08 119.01,24.02 113.83,24.02 111.7,21.89 100.66,21.89 99.52,20.75 89.57,20.75 89.17,20.35 85.85,20.35 85.65,20.55 85.29,20.55 84.4,19.66 78.23,19.66 74.27,23.62 73.17,23.62 65.4,31.39 56.97,31.39 53.31,27.74 41.32,27.74 40.49,28.56 31.81,28.56 30.63,29.74 29.99,30.38 22.55,30.38 20.91,30.38 16.05,35.24 16.05,35.83 16.05,35.83 16.05,40.31 6.83,49.53 6.83,128.61 9.79,131.57 v1(13.34,131.57) 13.74,131.57 v2(14.35,130.96)
CPU_FAN_TACH_1: length 7.7
  TOP w0.102: FANC1.3 10.16,129.03 13.91,132.78 R2601.2 R2602.1
CPU_FAN_TACH_SIO: length 414.4
  TOP w0.102: R2602.2 R2604.1 v2(16.38,134.75) ; v2(204.04,98.45) 206.22,98.45 207.6,99.82 U2401.37
  BOTTOM w0.102: v2(204.04,98.45) 202.22,96.63 202.22,85.15 203.38,84 203.38,82.49 204.72,81.15 204.72,79.48 205.74,78.46 205.74,74.72 205.87,74.6 205.87,72.69 200.1,66.93 199.26,66.93 198.32,65.99 198.32,62.77 197.76,62.21 197.76,57.72 197.26,57.21 197.26,48.26 195.28,46.28 195.28,21.89 186.67,13.28 171.27,13.28 169.93,11.94 169.93,8.89 165.99,4.95 155.44,4.95 154.3,6.1 149.1,6.1 146.79,3.78 119.46,3.78 118.52,4.73 118.52,15.92 117.63,16.8 114.08,16.8 111.5,19.39 108.38,19.39 108.01,19.02 102.82,19.02 102.54,19.3 78.08,19.3 74.12,23.27 73.03,23.27 67.03,29.26 65.89,30.4 65.25,31.04 57.12,31.04 53.46,27.38 41.17,27.38 40.35,28.21 31.66,28.21 29.84,30.02 22.7,30.02 21.06,30.02 20.77,30.02 15.7,35.09 15.7,35.97 15.7,35.97 15.7,40.15 6.48,49.37 6.48,130.79 10.43,134.75 v1(15.24,134.75) v2(16.38,134.75)
CPU_THERMDA+: length 238.8
  TOP w0.127: v2(209.65,103.02) 209.6,103.07 208.29,103.07 C2404.1 207.73,103.1 206.67,103.1 205.93,102.36 205.93,101.98 206,101.91 U2401.41 ; v2(107.7,54.64) 107.4,54.94 107.4,55.52 107.71,55.83 C2401.1 107.71,57.45 Q2404.C 107.31,58.42 108.3,59.4 Q2404.B ; v2(102.79,20.32) 102.79,20.8 103.09,21.1 103.09,27.14 106.88,30.94 106.88,33.66 v2(107.18,33.96)
  BOTTOM w0.127: 108.13,52.78 107.47,53.44 107.47,54.4 v2(107.7,54.64) ; 108.13,52.78 v1(108.41,53.06) ; 108.13,52.78 108.71,52.2 108.71,50.76 108.71,49.54 108.14,48.97 108.14,36.49 106.91,35.25 106.91,34.23 v2(107.18,33.96) ; v2(102.79,20.32) 102.98,20.51 111.82,20.51 114.55,17.78 119.13,17.78 120.14,16.76 143.52,16.76 144.29,15.99 174.64,15.99 175.46,15.16 187.13,15.16 194.25,22.28 194.25,46.76 196.28,48.79 196.28,55.23 196.28,57.62 196.79,58.13 196.79,61.61 196.66,61.74 196.66,65.72 198.84,67.91 199.7,67.91 204.56,72.77 204.56,77.95 203.75,78.76 203.75,80.3 201.75,82.3 201.75,83.95 201.24,84.46 201.24,97.26 205.39,101.4 207.21,101.4 209.13,103.33 209.35,103.33 v2(209.65,103.02)
CPU_THERMDA-: length 240.4
  TOP w0.127: v2(106.82,54.64) 107.12,54.94 107.12,55.52 106.82,55.83 C2401.2 106.82,57.12 106.74,57.2 106.74,59.34 Q2404.E ; v2(106.3,33.96) 106.6,33.66 106.6,31.05 102.81,27.26 102.81,21.22 v2(101.91,20.32) ; v2(209.65,103.89) 209.12,103.35 208.37,103.35 C2404.2 207.71,103.38 206.55,103.38 205.65,102.47 205.65,102.02 205.6,101.96 U2401.42
  BOTTOM w0.127: v2(106.82,54.64) 107.19,54.28 107.19,53.33 108.43,52.08 108.43,50.65 ; 108.43,50.65 v1(108.05,50.65) ; 108.43,50.65 108.43,49.66 107.86,49.09 107.86,36.6 106.63,35.37 106.63,34.29 v2(106.3,33.96) ; v2(209.65,103.89) 209.37,103.61 209.02,103.61 207.09,101.68 205.51,101.68 205.28,101.68 200.97,97.37 200.97,84.34 201.47,83.84 201.47,82.18 203.47,80.19 203.47,78.65 204.28,77.83 204.28,72.88 199.58,68.19 198.73,68.19 196.38,65.84 196.38,61.62 196.51,61.5 196.51,58.24 196,57.73 196,57.5 196,57.5 196,55.34 196,48.9 193.97,46.87 193.97,22.39 187.02,15.44 175.58,15.44 174.75,16.27 144.41,16.27 143.63,17.04 120.26,17.04 119.24,18.06 114.67,18.06 111.94,20.79 102.38,20.79 v2(101.91,20.32)
CPVEE: length 3.8
  TOP w0.305: C2701.2 62.33,237.54 61.36,236.57 U2701.33
  TOP w0.508: C2701.2 62.59,237.67 v1(63.55,237.67)
DAS/DSS#: length 248.7
  TOP w0.102: v2(146.56,131.32) 146.3,131.57 138.18,131.57 137.86,131.26 NGFF2.10 ; v2(89.53,223.65) 89.53,222.88 88.39,221.74 81.92,221.74 80.47,223.19 66.13,223.19 65.26,222.32 35.38,222.32 25.78,231.93 25.78,237.08 24.19,238.67 R6420.2 24.77,240.73 24.77,242.06 24.51,242.32 U6402.2
  BOTTOM w0.102: v2(89.53,223.65) 90.81,223.65 92.58,221.87 92.58,221.59 v1(92.63,221.54) 96.39,217.78 96.39,217.02 95.15,215.77 95.15,211.11 94.03,209.99 94.03,193.99 95.15,192.88 95.15,190.72 98.16,187.71 113.62,187.71 116.74,184.58 148.48,184.58 150.77,182.3 152.2,182.3 154.56,179.93 154.56,168.53 152.15,166.12 152.15,155.29 144.61,147.76 144.61,144.79 144.07,144.24 144.07,140.16 146.56,137.67 v2(146.56,131.32)
DAS/DSS#_NMOS: length 5
  TOP w0.102: U6402.5 20.98,242.32 v1(20.57,241.91) 20.82,241.67 U6402.6 22.05,241 21.4,240.35 R6421.1
DCPRTC: length 6.3
  TOP w0.203: C2101.1 216.83,158.75 v1(216.07,158.75) 215.82,158.75 214.93,157.86 214.93,157.4 213.49,155.96 SB1.BG47 SB1.BF47
DDI_VGA_DATA_C_N2: length 4.4
  TOP w0.102: 61.71,25.98 61.71,27.86 C5913.1 ; 61.71,25.98 61.71,25.02 61.62,24.93 U5901.6 ; 61.71,25.98 v1(61.32,25.98)
DDI_VGA_DATA_C_N3: length 5.3
  TOP w0.102: C5915.1 59.41,28.02 59.41,26.67 59.83,26.25 ; v1(59.54,25.96) 59.83,26.25 ; 59.83,26.25 60.9,25.18 60.9,24.92 60.82,24.84 U5901.8
DDI_VGA_DATA_C_P2: length 4.4
  TOP w0.102: U5901.5 62.02,24.93 61.93,25.02 61.93,27.15 ; 61.93,27.15 61.93,27.81 C5912.1 ; 61.93,27.15 v1(62.31,27.15)
DDI_VGA_DATA_C_P3: length 5.3
  TOP w0.102: C5914.1 59.63,28.08 59.63,27.41 ; 59.63,27.41 v1(60.05,27.41) ; 59.63,27.41 59.63,26.76 61.11,25.27 61.11,24.92 61.22,24.81 U5901.7
DDI_VGA_DATA_CPU_N2: length 123.6
  TOP w0.102: 62.36,30.48 62.95,31.08 85.12,31.08 100.07,38.32 110.68,48.91 112.67,55.77 112.67,68.14 113.11,68.58 113.54,68.58 v2(113.87,68.9) ; 62.36,30.48 61.74,29.86 61.74,29.39 C5913.2 ; 62.36,30.48 v1(62.09,30.75) ; v2(89.46,99.54) CPU1.H10
  BOTTOM w0.102: v2(113.87,68.9) 113.54,68.58 111,68.58 110.11,69.47 110.11,73.78 110.11,74.54 108,76.66 107.99,76.66 96.92,87.73 94.11,87.73 89.32,92.52 89.32,94.37 88.89,94.8 88.89,96.14 89.19,96.44 89.19,98.06 89.1,98.15 89.1,99.18 v2(89.46,99.54)
DDI_VGA_DATA_CPU_N3: length 122.6
  TOP w0.102: C5915.2 59.38,29.66 59.38,30.42 60.19,31.24 61.88,31.95 61.98,31.97 85.35,31.97 99.66,38.89 110.06,49.28 111.97,55.87 111.97,69.43 112.39,69.85 112.68,69.85 v2(113.01,70.18) ; v2(90.37,98.62) CPU1.G9
  BOTTOM w0.102: v2(90.37,98.62) 90.04,98.29 90.04,97.84 89.74,97.54 89.74,93.19 94.48,88.46 97.3,88.46 98.01,87.75 ; 98.01,87.75 110.89,74.86 110.89,70.19 111.22,69.86 112.69,69.86 v2(113.01,70.18) ; 98.01,87.75 v1(98.27,88.01)
DDI_VGA_DATA_CPU_P2: length 123.4
  TOP w0.102: v2(88.58,99.5) 88.58,99.5 89,99.08 CPU1.G10 ; 63.5,30.86 63.04,30.86 61.95,29.77 61.95,29.39 C5912.2 ; 63.5,30.86 85.17,30.86 100.19,38.14 110.87,48.8 112.88,55.74 112.88,68.05 113.2,68.36 113.54,68.36 v2(113.87,68.04) ; 63.5,30.86 v1(63.5,30.48)
  BOTTOM w0.102: v2(113.87,68.04) 113.54,68.36 110.91,68.36 109.9,69.38 109.9,73.87 109.9,74.45 107.91,76.44 107.9,76.44 96.83,87.52 94.02,87.52 89.1,92.43 89.1,94.28 88.67,94.72 88.67,96.23 88.97,96.53 88.97,97.97 88.88,98.06 88.88,99.2 88.58,99.5 v2(88.58,99.5)
DDI_VGA_DATA_CPU_P3: length 122.6
  TOP w0.102: C5914.2 59.6,29.66 59.6,30.33 60.01,30.75 ; 60.01,30.75 v1(60.27,30.48) ; 60.01,30.75 60.32,31.06 61.94,31.74 62,31.75 85.4,31.75 99.78,38.71 110.25,49.17 112.19,55.84 112.19,69.34 112.48,69.63 112.7,69.63 v2(113.01,69.32) ; v2(89.53,98.62) 89.92,98.24 CPU1.F9
  BOTTOM w0.102: v2(89.53,98.62) 89.83,98.33 89.83,97.93 89.52,97.63 89.52,93.1 94.39,88.24 97.21,88.24 110.68,74.77 110.68,70.1 111.13,69.64 112.69,69.64 v2(113.01,69.32)
DDPC_CTRL_CLK: length 30.5
  TOP w0.102: v2(206.93,138.02) 206.81,138.15 206.81,138.56 SB1.AN13 ; v2(208.15,112.21) 208.15,112.14 207.77,111.76 R1906.1
  BOTTOM w0.102: v2(206.93,138.02) 206.48,138.02 205.69,137.24 205.69,136.46 205.84,136.31 205.84,134.75 206.24,134.34 206.24,131.52 206.26,131.51 206.26,116.32 207.39,115.19 207.39,113.92 208.13,113.18 v1(208.31,113.18) 208.33,113.16 208.33,112.38 v2(208.15,112.21)
DDPC_CTRL_DATA: length 28.5
  TOP w0.102: R2327.1 205.82,111.44 206.65,112.27 v2(206.65,112.27) ; SB1.AL10 205.5,137.28 205.5,136.79 v2(204.98,136.27)
  BOTTOM w0.102: v2(206.65,112.27) 206.93,112.55 206.93,115 205.8,116.13 205.8,131.39 205.18,132.02 v1(205.18,133.55) 205.18,134.16 205.43,134.41 205.43,135.82 v2(204.98,136.27)
DDPD_CTRL_CLK: length 30.9
  TOP w0.102: R1907.1 206.76,111.63 v2(207.39,112.27) ; SB1.AL9 205.18,137.09 204.4,136.3 204.4,136.22 204.06,135.88 v2(203.83,135.88)
  BOTTOM w0.102: v2(203.83,135.88) 203.96,135.75 v1(203.96,134.11) 203.96,132.33 205.13,131.17 205.13,115.65 206.25,114.53 206.25,114.17 205.19,113.11 205.19,112.06 205.56,111.68 206.81,111.68 v2(207.39,112.27)
DDPD_CTRL_DATA: length 15.9
  TOP w0.089: SB1.AR3 207.29,134.21 207.05,133.98 207.05,131.3 v1(207.36,130.99)
  TOP w0.102: v1(207.36,130.99) 207.36,130.46 208.66,129.16 208.66,120.73 208.2,120.27 208.2,119.67 R2329.1
DDR_VTT_CNTL_CPU: length 44.2
  TOP w0.102: U401.3 11.57,184.64 11.94,184.28 11.94,184.21 R414.2 12.6,183.73 12.6,186.41 14.76,188.57 23.55,188.57 24.31,187.81 24.31,186.87 25.3,185.88 25.3,184.94 26.44,183.79 37.11,183.79 v2(38.35,185.04) ; R4025.1 44.45,185.93 44.7,185.67 v2(44.7,185.55)
  BOTTOM w0.102: v2(38.35,185.04) 38.37,185.04 v1(39.06,185.73) 40.48,187.15 43.23,187.15 44.7,185.67 v2(44.7,185.55)
DDR_VTT_CNTL_GATE: length 5.1
  TOP w0.102: R413.2 10.73,189.93 v1(10.92,190.12) ; R413.2 10.27,188.64 U401.6 ; R413.2 10.92,188.91 U401.5
DDR_VTT_CNTL_R: length 3.3
  TOP w0.102: R416.1 9.72,183.71 10.31,184.3 v2(10.67,184.3) 10.92,184.56 U401.2
  BOTTOM w0.102: v1(10.67,185.06) v2(10.67,184.3)
DDSP_B_TX_N0: length 32.1
  TOP w0.102: v2(37.17,21.83) 36.32,21.83 R5601.2 35.33,21.86 R5604.2 ; v2(32.42,23.86) R5606.2 32.45,23.01 R5603.2 ; Q5601.6 21.83,24.12 23.47,25.76 v2(23.88,25.76) ; R5608.2 29.58,22.99 R5605.2 v2(29.63,23.84) ; R5607.2 v2(26.01,21.97) ; R5602.2 v2(37.17,19.06)
  BOTTOM w0.102: v2(23.88,25.76) 23.44,25.32 23.44,24.54 v2(26.01,21.97) 27.76,21.97 v2(29.63,23.84) 32.4,23.84 v2(32.42,23.86) 35.14,23.86 v1(36.15,22.85) v2(37.17,21.83) v2(37.17,19.06)
DIMM1_EVENT_N: length 17.1
  TOP w0.102: R1101.2 88.66,183.2 89.05,182.81 89.05,181 87.99,179.94 87.99,176.11 91.29,172.81 91.29,172.2 90.2,171.1 90.2,169.14 DIMM1.78
DIMM2_EVENT_N: length 6.2
  TOP w0.102: R1201.2 89.28,182.82 89.28,180.85 89.93,180.2 89.93,178.39 DIMM2.78
DIMM_CA_CPU_VREF_RC: length 2.2
  TOP w0.305: C602.2 v1(31.43,123.95) 31.17,124.22 R602.1
DIMM_CA_VREF_A: length 67.9
  TOP w0.305: R1105.1 17.13,183.5 R1106.1 14.87,183.5 R1103.2 v2(14.86,182.5) ; v2(31.43,126.05) R601.2
  BOTTOM w0.305: v2(31.43,126.05) 30.92,126.05 18.81,138.16 18.81,165.34 17.65,166.5 17.65,179.45 v1(15.79,181.31) 14.86,182.25 v2(14.86,182.5)
DIMM_CA_VREF_A_L: length 16.3
  TOP w0.305: DIMM1.146 17.74,175.7 17.74,184.06 17.4,184.4 R1105.2 17.14,184.66 C1107.1 16.26,186.56 C1106.1
DIMM_CA_VREF_B: length 3.4
  TOP w0.305: R1205.1 R1206.1 R1203.2 17.46,187.26 v1(17.27,187.45)
DIMM_CA_VREF_B_L: length 6.4
  TOP w0.305: DIMM2.146 20.91,182.3 20.89,182.31 20.89,182.82 21.51,183.44 21.51,184.01 C1210.1 21.53,184.98 C1211.1 21.72,185.17 R1204.2 R1205.2
DIMM_DQ_CPU_VREF_B_RC: length 2.2
  TOP w0.305: v1(24.61,185.7) 23.94,186.37 R1207.1 C1209.2
DISP_UTIL_CPU: length 2.7
  TOP w0.102: v2(85.78,95.9) CPU1.D14
  BOTTOM w0.102: TP701.1 85.37,94.58 85.37,95.48 v2(85.78,95.9)
DLDO_CAP: length 4.3
  TOP w0.305: C2711.1 55.51,227.9 C2712.1 56.39,228.61 v1(56.67,228.89) U2701.47
DMI_RX_CPU_N0: length 122.3
  TOP w0.102: 161.57,132.69 161.57,127.58 153.98,119.99 137.29,119.99 130.62,113.32 126.88,113.32 118.3,104.74 107.67,104.74 103.32,109.09 99.72,109.09 98.42,110.38 94.95,110.38 94.75,110.58 CPU1.Y4 ; 161.57,132.69 v1(161.95,132.69) ; 161.57,132.69 161.57,133.4 162.4,134.23 162.4,136.11 162.7,136.41 163.5,136.41 v2(163.7,136.21) ; v2(189.24,145) 189.53,145.29 190.21,145.29 190.73,145.81 190.73,146.29 191.35,146.9 SB1.C29
  BOTTOM w0.102: v2(163.7,136.21) 164.05,136.55 165.68,136.55 166.14,137.01 170.05,137.01 176.54,143.5 184.11,143.5 185.09,144.47 186.53,144.47 187.06,145 v2(189.24,145)
DMI_RX_CPU_N1: length 123.6
  TOP w0.102: 161.11,136.25 162.57,137.71 164.08,137.71 v2(164.46,137.43) ; 161.11,136.25 v1(161.38,135.98) ; 161.11,136.25 160.78,135.91 160.78,127.86 153.61,120.69 136.82,120.69 130.21,114.08 126.65,114.08 118.01,105.44 107.96,105.44 103.59,109.81 99.76,109.81 98.61,110.95 96.02,110.95 95.68,111.3 94.04,111.3 93.85,111.48 93.6,111.83 CPU1.AA5 ; SB1.C31 191.24,147.49 190.54,147.49 189.37,146.32 188.24,146.32 v2(187.84,146.01)
  BOTTOM w0.102: v2(164.46,137.43) 164.85,137.73 169.43,137.73 176.39,144.69 184.32,144.69 184.8,145.17 186.22,145.17 187.06,146.01 v2(187.84,146.01)
DMI_RX_CPU_N2: length 124.8
  TOP w0.102: 160.35,137.69 159.87,137.21 159.87,128.32 153.15,121.6 136.34,121.6 129.79,115.06 126.34,115.06 117.63,106.35 108.34,106.35 103.97,110.72 100.04,110.72 98.82,111.94 96.9,111.94 96.3,112.53 95.77,112.53 95.66,112.43 95.17,112.43 95.07,112.53 95.07,112.69 95.17,112.79 CPU1.AB3 ; 160.35,137.69 160.96,138.3 161.88,138.3 162.29,138.72 162.29,139.51 v2(162,139.8) ; 160.35,137.69 v1(160.09,137.95) ; v2(186.14,146.21) 186.45,146.53 186.84,146.53 187.73,147.42 189.74,147.42 190.27,147.96 190.88,147.96 SB1.C32
  BOTTOM w0.102: v2(186.14,146.21) 185.87,146.49 184.65,146.49 183.57,145.4 176.11,145.4 169.6,138.89 162.58,138.89 162.3,139.18 162.3,139.51 v2(162,139.8)
DMI_RX_CPU_N3: length 125
  TOP w0.102: 159.82,139.65 159.3,139.13 159.3,128.46 153.01,122.17 136.07,122.17 129.5,115.61 126.07,115.61 117.33,106.86 108.51,106.86 104.17,111.2 99.94,111.2 98.83,112.31 96.84,112.31 96.02,113.12 94.04,113.12 93.8,113.36 93.74,113.46 CPU1.AC5 ; 159.82,139.65 v1(160.08,139.38) ; 159.82,139.65 160.46,140.3 160.71,140.3 v2(161.06,140.03) ; SB1.C33 191.35,149.1 190.62,148.37 189.85,148.37 189.42,147.94 186.58,147.94 186.23,147.59 185.67,147.59 v2(185.38,147.3)
  BOTTOM w0.102: v2(161.06,140.03) 161.37,140.33 170.05,140.33 176.31,146.6 183.08,146.6 183.78,147.3 v2(185.38,147.3)
DMI_RX_CPU_P0: length 122.3
  TOP w0.102: SB1.B29 190.89,146.86 190.89,146.75 190.52,146.38 190.52,145.9 190.12,145.5 189.46,145.5 v2(189.21,145.76) ; CPU1.Y3 95.04,110.97 94.93,110.86 94.93,110.71 95.04,110.6 98.51,110.6 99.81,109.3 103.41,109.3 107.76,104.95 118.21,104.95 126.79,113.54 130.53,113.54 137.2,120.21 153.89,120.21 161.35,127.67 161.35,133.49 161.89,134.02 ; 161.89,134.02 v1(161.62,134.29) ; 161.89,134.02 162.18,134.32 162.18,136.2 162.61,136.63 163.5,136.63 163.69,136.82 v2(163.69,137.07)
  BOTTOM w0.102: v2(189.21,145.76) 188.96,145.51 188.96,145.35 188.83,145.21 186.97,145.21 186.44,144.69 185,144.69 184.02,143.71 176.45,143.71 169.96,137.22 166.05,137.22 165.59,136.77 163.99,136.77 v2(163.69,137.07)
DMI_RX_CPU_P1: length 123.6
  TOP w0.102: v2(164.46,138.29) 164.09,137.92 162.48,137.92 161.67,137.11 ; SB1.B31 191.07,147.7 190.45,147.7 189.28,146.54 188.18,146.54 v2(187.84,146.88) ; 161.67,137.11 v1(161.39,137.39) ; 161.67,137.11 160.57,136 160.57,127.95 153.52,120.91 136.73,120.91 130.12,114.3 126.56,114.3 117.92,105.65 108.05,105.65 103.68,110.02 99.85,110.02 98.7,111.17 96.11,111.17 95.77,111.51 94.13,111.51 94.02,111.62 94.02,111.77 94.16,111.91 94.45,111.91 CPU1.AA4
  BOTTOM w0.102: v2(164.46,138.29) 164.81,137.94 169.34,137.94 176.3,144.91 184.23,144.91 184.71,145.38 186.13,145.38 186.97,146.23 187.2,146.23 187.32,146.35 187.32,146.76 187.44,146.88 v2(187.84,146.88)
DMI_RX_CPU_P2: length 124.8
  TOP w0.102: SB1.B32 190.79,148.17 190.18,148.17 189.65,147.64 187.64,147.64 186.75,146.74 186.47,146.74 186.12,147.09 v2(186.12,147.09) ; 162.51,138.84 162.51,138.63 161.97,138.09 161.05,138.09 160.08,137.12 160.08,128.23 153.24,121.39 136.43,121.39 129.88,114.85 126.43,114.85 117.72,106.13 108.25,106.13 103.88,110.5 99.95,110.5 98.73,111.72 96.81,111.72 96.21,112.32 95.86,112.32 95.75,112.21 95.08,112.21 94.85,112.44 94.85,112.67 94.73,112.79 CPU1.AB4 ; 162.51,138.84 v1(162.89,138.84) ; 162.51,138.84 162.51,139.46 v2(162.85,139.8)
  BOTTOM w0.102: v2(162.85,139.8) 162.79,139.8 162.51,139.52 162.51,139.27 162.67,139.11 169.51,139.11 176.02,145.62 183.48,145.62 184.57,146.71 185.74,146.71 v2(186.12,147.09)
DMI_RX_CPU_P3: length 125
  TOP w0.102: 122.54,112.38 125.98,115.82 129.42,115.82 135.98,122.39 152.92,122.39 159.08,128.55 159.08,139.22 160.37,140.51 160.68,140.51 v2(161.06,140.89) ; 122.54,112.38 v1(122.28,112.65) ; 122.54,112.38 117.24,107.08 108.6,107.08 104.26,111.42 100.03,111.42 98.92,112.52 96.93,112.52 96.11,113.34 94.13,113.34 94.02,113.45 94.02,113.6 94.13,113.71 CPU1.AC4 ; v2(185.39,148.04) 185.63,147.8 186.14,147.8 186.49,148.16 189.33,148.16 189.76,148.59 190.53,148.59 190.88,148.94 SB1.B33
  BOTTOM w0.102: v2(185.39,148.04) 185.32,148.11 185.06,148.11 184.91,147.96 184.91,147.65 184.77,147.51 183.7,147.51 182.99,146.81 176.22,146.81 169.96,140.55 161.41,140.55 v2(161.06,140.89)
DMI_TX_CPU_N0: length 122.1
  TOP w0.102: SB1.G30 193.52,147.4 193.33,147.2 193.33,147.04 v2(193.6,146.77) ; CPU1.AC1 97.23,113.71 96.95,113.71 96.81,113.58 96.81,113.4 96.84,113.37 97.08,113.13 99.3,113.13 100.32,112.12 107.96,112.12 117.37,121.53 118.78,121.53 121.41,124.16 ; 121.41,124.16 v1(121.15,124.42) ; 121.41,124.16 121.93,124.68 154.14,124.68 158.38,128.92 158.38,139.51 160.73,141.86 163.11,141.86 v2(163.42,142.18)
  BOTTOM w0.102: v2(163.42,142.18) 163.77,141.83 170.26,141.83 175.95,147.52 182.69,147.52 184.28,149.11 186.37,149.11 187.12,148.36 191.44,148.36 192.28,147.52 193.14,147.52 193.42,147.24 193.42,147.01 193.42,146.94 v2(193.6,146.77)
DMI_TX_CPU_N1: length 125.8
  TOP w0.102: v2(159.97,143.38) 159.65,143.07 159.3,143.07 159.02,142.79 159.02,141.13 157.68,139.8 157.68,129.36 153.92,125.6 120.88,125.6 118.16,122.89 117.74,122.89 107.67,112.82 100.46,112.82 99.17,114.1 97.76,114.1 97.61,114.26 96.06,114.26 95.95,114.36 95.95,114.52 96.06,114.62 CPU1.AD2 ; v2(195.04,147.73) 195.02,147.75 SB1.K32
  BOTTOM w0.102: v2(195.04,147.73) 194.82,148.02 194.84,148.18 194.84,148.72 194.25,149.31 192.47,149.31 192.23,149.56 187.91,149.56 186.95,150.51 183.7,150.51 182.62,149.43 175.84,149.43 170.73,144.31 168.09,144.31 167.61,143.84 166.65,143.84 ; v1(166.65,144.22) 166.65,143.84 ; 166.65,143.84 161.85,143.84 161.07,143.07 160.29,143.07 v2(159.97,143.38)
DMI_TX_CPU_N2: length 124.1
  TOP w0.102: v2(193.57,148.31) SB1.G33 ; v2(157.43,142.19) 157.75,141.87 157.75,140.93 156.98,140.17 156.98,129.81 153.63,126.45 120.32,126.45 107.38,113.51 100.6,113.51 98.79,115.32 97.65,115.32 97.5,115.17 96.92,115.17 96.75,115.34 96.75,115.52 96.88,115.65 97.12,115.65 CPU1.AE1
  BOTTOM w0.102: 158.65,140.8 158.11,140.8 157.75,141.16 157.75,141.87 v2(157.43,142.19) ; 158.65,140.8 160.15,140.8 162.2,142.85 170.59,142.85 175.76,148.02 182.5,148.02 184.08,149.59 186.57,149.59 187.44,148.73 191.68,148.73 191.97,148.44 192.58,147.83 193.04,147.83 193.52,148.31 v2(193.57,148.31) ; 158.65,140.8 v1(158.65,140.41)
DMI_TX_CPU_N3: length 124.8
  TOP w0.102: v2(159.51,144.01) 159.22,144.3 158.88,144.3 157.91,143.33 ; 157.91,143.33 v1(158.18,143.07) ; 157.91,143.33 156.5,141.92 156.5,130.06 153.61,127.17 120.35,127.17 107.34,114.16 100.38,114.16 98.92,115.62 97.78,115.62 97.53,115.87 95.87,115.87 95.63,116.1 95.58,116.17 CPU1.AF3 ; v2(194.98,150.2) SB1.K34
  BOTTOM w0.102: v2(159.51,144.01) 159.85,144.34 165.24,144.34 165.85,144.95 170.65,144.95 175.67,149.96 182.32,149.96 183.35,150.99 187.29,150.99 188.29,149.99 192.86,149.99 193.21,149.63 194.37,149.63 194.6,149.86 194.6,149.92 194.63,150.02 v2(194.98,150.2)
DMI_TX_CPU_P0: length 122.1
  TOP w0.102: 119.9,122.34 118.87,121.31 117.46,121.31 108.05,111.9 100.23,111.9 99.21,112.92 96.99,112.92 96.71,113.19 96.6,113.31 96.6,113.47 96.36,113.71 CPU1.AC2 ; 119.9,122.34 v1(120.16,122.08) ; 119.9,122.34 122.02,124.46 154.23,124.46 158.6,128.83 158.6,139.42 160.82,141.64 163.11,141.64 v2(163.42,141.33) ; SB1.F30 193.11,147.28 193.11,146.91 v2(192.96,146.76)
  BOTTOM w0.102: v2(163.42,141.33) 163.72,141.62 170.35,141.62 176.03,147.31 182.78,147.31 184.37,148.89 186.28,148.89 187.03,148.15 191.35,148.15 192.19,147.31 193.05,147.31 193.21,147.15 193.21,147.01 v2(192.96,146.76)
DMI_TX_CPU_P1: length 125.8
  TOP w0.102: v2(194.31,147.83) 194.29,147.85 SB1.J32 ; 119.74,124.16 120.97,125.39 154.01,125.39 157.9,129.27 157.9,139.71 159.23,141.04 159.23,142.7 159.39,142.85 159.65,142.85 v2(159.97,142.53) ; 119.74,124.16 118.25,122.67 117.83,122.67 107.76,112.6 100.37,112.6 99.08,113.88 97.67,113.88 97.52,114.04 95.97,114.04 95.73,114.27 95.73,114.43 95.54,114.62 CPU1.AD3 ; 119.74,124.16 v1(119.99,123.9)
  BOTTOM w0.102: v2(159.97,142.53) 160.29,142.85 161.16,142.85 161.94,143.62 167.7,143.62 168.18,144.1 170.82,144.1 175.93,149.21 182.71,149.21 183.79,150.29 186.86,150.29 187.82,149.34 192.14,149.34 192.38,149.1 194.16,149.1 194.62,148.63 194.62,148.2 194.6,148.05 v2(194.31,147.83)
DMI_TX_CPU_P2: length 124.1
  TOP w0.102: SB1.F34 193.12,149.01 193.12,148.8 v2(192.9,148.59) ; v2(158.28,142.19) 157.96,141.87 157.96,140.84 157.2,140.08 157.2,129.72 153.72,126.24 120.41,126.24 107.47,113.3 100.51,113.3 98.7,115.11 97.74,115.11 97.59,114.95 96.83,114.95 96.32,115.47 CPU1.AE2
  BOTTOM w0.102: v1(169.47,143.43) 169.47,143.07 ; 169.47,143.07 162.11,143.07 160.06,141.01 158.2,141.01 157.96,141.25 157.96,141.87 v2(158.28,142.19) ; 169.47,143.07 170.5,143.07 175.67,148.23 182.41,148.23 183.99,149.81 186.66,149.81 187.53,148.95 191.77,148.95 192.67,148.04 192.95,148.04 193.09,148.18 193.09,148.4 v2(192.9,148.59)
DMI_TX_CPU_P3: length 124.7
  TOP w0.102: 121.72,127.38 120.26,127.38 107.25,114.37 100.47,114.37 99.01,115.84 97.87,115.84 97.62,116.08 95.96,116.08 95.81,116.23 95.81,116.48 95.94,116.61 96.16,116.61 CPU1.AF2 ; 121.72,127.38 v1(121.72,127.75) ; 121.72,127.38 153.52,127.38 156.29,130.15 156.29,142.01 158.79,144.51 159.17,144.51 v2(159.51,144.86) ; SB1.J35 v2(194.25,150.44)
  BOTTOM w0.102: v2(159.51,144.86) 159.81,144.56 165.15,144.56 165.76,145.16 170.56,145.16 175.58,150.18 182.23,150.18 183.26,151.21 187.38,151.21 188.38,150.2 192.95,150.2 193.3,149.85 194.28,149.85 194.38,149.95 194.39,149.98 194.43,150.09 v2(194.25,150.44)
DP_AUX_CON_N: length 4.8
  TOP w0.102: 63.78,25.59 64.33,25.59 64.53,25.79 64.53,26.97 C5911.1 ; 63.78,25.59 63.29,25.59 62.91,25.21 62.91,25.02 62.82,24.93 U5901.3 ; 63.78,25.59 v1(63.78,26.01)
DP_AUX_CON_P: length 4.8
  TOP w0.102: U5901.2 63.22,24.93 63.13,25.02 63.13,25.12 63.38,25.37 64.42,25.37 64.74,25.7 64.74,26.29 ; 64.74,26.29 64.74,26.9 C5910.1 ; 64.74,26.29 v1(65.15,26.29)
DP_AUX_CPU_N: length 122.3
  TOP w0.102: 65.07,29.82 64.56,29.31 64.56,28.5 C5911.2 ; 65.07,29.82 65.57,30.31 85.36,30.31 100.28,37.54 111.3,48.55 113.37,55.67 113.37,66.73 114.18,67.55 115.16,67.55 v2(115.46,67.85) ; 65.07,29.82 v1(64.8,30.1) ; CPU1.E12 87.2,97.25 v2(87.63,96.82)
  BOTTOM w0.102: v2(87.63,96.82) 87.76,96.82 88.4,96.18 88.4,94.37 88.75,94.03 88.75,92.08 93.79,87.03 96.63,87.03 107.7,75.96 107.71,75.96 109.41,74.25 109.41,68.71 110.6,67.53 115.14,67.53 v2(115.46,67.85)
DP_AUX_CPU_P: length 122.2
  TOP w0.102: v2(115.46,66.99) 115.11,67.34 114.27,67.34 113.58,66.64 113.58,55.64 111.49,48.43 100.41,37.36 85.41,30.1 67.08,30.1 ; v1(67.08,29.72) 67.08,30.1 ; 67.08,30.1 65.66,30.1 64.78,29.22 64.78,28.5 C5910.2 ; v2(87.63,95.88) CPU1.D12
  BOTTOM w0.102: v2(115.46,66.99) 115.14,67.31 110.51,67.31 109.2,68.62 109.2,74.16 107.62,75.74 107.61,75.74 96.54,86.82 93.7,86.82 88.53,91.99 88.53,92.17 88.53,93.94 88.19,94.29 88.19,96.09 87.96,96.32 87.76,96.32 87.63,96.19 v2(87.63,95.88)
DP_HPD_CPU: length 353.6
  TOP w0.102: v2(206.12,136.88) 205.99,137.01 205.99,137.92 206.36,138.28 206.36,138.68 206.05,138.99 205.95,138.99 204.96,139.98 SB1.AL15 ; v2(161.67,46.35) 161.98,46.66 161.98,48.13 161.47,48.64 161.47,63.68 165,67.21 165,104.52 168.4,107.92 v2(168.4,108.31) 168.4,110.37 173.13,115.1 173.13,131.97 171.55,133.54 171.55,140.1 169.53,142.12 169.53,147.29 165.46,151.36 165.46,164.64 164.73,165.37 164.73,165.37 164.36,165.74 v2(164.36,175.97) ; v2(178.18,107.71) 178.92,107.71 180.33,109.12 193.01,109.12 194.62,110.72 196.01,110.72 196.43,111.14 202.96,111.14 205.24,113.42 206.52,113.42 207.18,114.07 v2(207.85,114.07) ; v2(191.57,169) 191.57,168.59 R1701.1 ; v2(73.03,27.94) 70.05,27.94 68.05,25.93 67.63,25.93 R5910.1 66.75,25.37 65.03,23.65 U5901.32
  BOTTOM w0.102: v2(206.12,136.88) 206.12,134.82 206.45,134.5 206.45,131.61 206.54,131.52 206.54,116.44 207.67,115.31 207.67,115.08 207.67,114.25 v2(207.85,114.07) ; v2(191.57,169) 191.57,169.14 190.1,170.6 185.17,170.6 183.97,171.81 169.04,171.81 v1(168.68,171.45) 168.33,171.45 164.36,175.41 v2(164.36,175.97) ; v2(161.67,46.35) 161.67,46.76 160.12,48.31 158.6,48.31 155.22,44.93 155.22,36.69 150.21,31.67 131.79,31.67 130.93,30.81 127.21,30.81 126.96,30.81 126.62,30.48 121.64,30.48 121.24,30.07 116.04,30.07 115.76,29.79 103.37,29.79 103.37,29.79 102.15,29.79 102.15,29.79 100.41,29.79 98.74,28.12 76.89,28.12 76.7,28.31 76.34,28.31 76.12,28.09 73.18,28.09 v2(73.03,27.94) ; v2(178.18,107.71) 176.09,107.71 175.49,108.31 v2(168.4,108.31)
EAPD: length 8.1
  TOP w0.102: R2719.1 51.58,228.05 v1(52.27,228.75) 52.52,228.5 55.14,228.5 56.39,229.74 57.53,229.74 57.68,229.89 U2701.45
EC_PWRGD_3V: length 2.9
  TOP w0.102: R2433.2 199.9,102.69 v1(199.82,102.62) 199.82,101.93 199.6,101.71 U2401.57
EDP_5VDDCCL: length 39.1
  TOP w0.102: VGA1.15 54.86,2.03 52.37,2.03 51.66,2.74 51.66,5.44 55.24,9.02 55.24,10.2 EU5902.1 53.84,9.16 50.85,9.16 50.04,9.97 50.04,14.99 v1(50.16,15.11) 50.29,15.24 50.29,18.64 52.3,20.66 56.32,20.66 56.52,20.85 56.52,21.34 56.84,21.66 RN5901.4 58.35,21.66 58.76,21.25 U5901.15
EDP_5VDDCDA: length 40.9
  TOP w0.102: U5901.16 57.27,20.85 RN5901.3 57.11,20.54 56.62,20.05 52.56,20.05 51.18,18.67 v1(51.18,16.76) 51.18,14.22 50.67,13.72 50.67,10.2 51.1,9.77 53.46,9.77 54.1,10.41 54.1,11.94 54.45,12.29 EU5902.3 56.29,12.29 56.64,11.94 56.64,7.75 v2(56.52,7.62)
  BOTTOM w0.102: v2(56.52,7.62) 56.41,7.51 56.41,5.78 57.11,5.07 58.83,5.07 59.36,4.54 59.36,3.71 60.88,2.19 VGA1.12
EDP_AVC12: length 14.9
  TOP w0.203: 65.43,19.91 64.49,20.85 U5901.25 ; U5901.4 62.42,25.44 62.51,25.53
  TOP w0.508: 65.43,19.91 65.57,19.77 C5902.1 67.42,19.77 C5901.1 v2(67.49,20.6) ; C5903.2 63.27,26.64 62.61,25.98 v2(62.61,25.65) 62.51,25.55 62.51,25.53
  BOTTOM w0.508: v2(62.61,25.65) v1(65.45,22.82) 67.49,20.78 v2(67.49,20.6)
EDP_AVC33: length 5
  TOP w0.203: 64.67,24.79 64.21,24.34 U5901.1
  TOP w0.508: L5901.2 67.35,26.45 C5908.1 66.34,25.82 65.66,25.15 65.66,25.13 v1(65.67,25.13) 65.33,24.79 64.67,24.79
EDP_BLUE_P: length 5.6
  TOP w0.102: U5901.21 62.42,19.06 62.31,18.95 62.31,18.93 R5913.1 61.65,17.35 C5916.1 61.8,17.11 61.8,16.36 v1(61.67,16.23) 61.59,16.15 60.68,16.15 L5905.1
EDP_DAC33: length 8.5
  TOP w0.203: v2(61.95,19.33) 61.95,19.34 62.02,19.41 U5901.20
  TOP w0.508: L5902.2 56.32,17.72 C5909.1 57.21,17.72 57.28,17.78 v2(57.33,17.78)
  BOTTOM w0.508: v2(57.33,17.78) v1(58.42,18.87) 59.06,19.51 61.76,19.51 v2(61.95,19.33)
EDP_EXPCLKIN: length 4.4
  TOP w0.102: R5904.1 67.67,23.57 v1(66.92,22.82) 66.15,22.05 U5901.28
EDP_GPI1: length 5.8
  TOP w0.102: U5901.11 59.62,22.85 59.31,23.16 59.31,24.66 58.06,25.91 R5905.2 v1(57.44,26.85)
EDP_GPI2: length 4.3
  TOP w0.102: U5901.12 59.67,22.45 59.11,23.02 59.11,24.08 58.58,24.6 v1(58.54,24.6) 58.48,24.6 58.22,24.87 R5906.2
EDP_GPI3: length 3.5
  TOP w0.102: R5907.2 57.92,23.81 v1(58.39,23.34) 58.9,22.83 58.9,22.76 59.61,22.05 U5901.13
EDP_GREEN_P: length 5.7
  TOP w0.102: U5901.22 62.82,19.78 63.57,19.03 R5914.1 63.57,17.3 C5917.1 63.91,16.92 63.91,16.26 v1(63.98,16.18) 62.87,16.18 L5904.1
EDP_HSYNC: length 4
  TOP w0.102: U5901.19 61.62,19.71 61.22,19.31 61,19.31 60.49,18.8 v1(59.82,18.8) 59.12,18.8 R5917.1
EDP_HSYNC_C: length 27.3
  TOP w0.102: R5917.2 58.67,16.87 58.67,16.86 58.66,16.59 C5923.1 58.31,16.24 58.31,14.5 57.91,14.1 v1(55.5,14.1) 53.82,14.1 53.47,13.74 53.47,11.38 52.47,10.38 EU5902.6 v2(51.35,10.38)
  BOTTOM w0.102: VGA1.13 58.7,2.19 57.71,3.17 56.64,3.17 56.52,3.05 55.88,3.05 55.19,3.73 53.91,3.73 51.35,6.29 v2(51.35,10.38)
EDP_LDORSTB: length 5.8
  TOP w0.102: U5901.27 65.67,21.65 65.94,21.39 v1(66.14,21.39) 66.31,21.39 67.86,22.94 68.71,22.94 68.97,22.67 R5903.1
EDP_RED_P: length 6
  TOP w0.102: U5901.23 63.22,19.78 64.61,18.39 R5915.1 64.61,17.31 C5918.1 64.62,17.02 65.1,16.54 L5903.1 66.27,16.13 v1(66.29,16.15)
EDP_VSYNC: length 7.2
  TOP w0.102: U5901.18 61.22,19.78 61.02,19.58 58.95,19.58 57.91,18.54 57.91,17.22 57.61,16.92 v1(57.61,16.87) 57.53,16.79 R5916.1
EDP_VSYNC_C: length 22.9
  TOP w0.102: v2(51.35,12.29) EU5902.4 52.37,13.89 53.09,14.61 v1(53.21,14.61) 53.4,14.8 C5922.1 R5916.2
  BOTTOM w0.102: v2(51.35,12.29) 50.67,11.61 50.67,6.1 53.59,3.18 53.59,3.17 53.64,3.12 55.42,3.12 56.36,2.19 VGA1.14
EXT_ARB: length 4.5
  TOP w0.102: R9511.1 215.8,62.47 214.32,62.47 v1(214.1,62.26) 213.79,61.94 213.79,61.54 213.34,61.09 U9501.92
FDI_COMP: length 4.3
  TOP w0.254: CPU1.M9 89.92,103.79 88.82,104.89 88.77,104.89
  TOP w0.305: 88.77,104.89 88.69,104.89 87.24,106.34 R701.1
FORM_FAC_ID_0: length 18.1
  TOP w0.089: 214.26,151.04 213.84,150.62 212.82,150.62 212.6,150.83 211.86,150.83 211.51,151.18 SB1.BD38
  TOP w0.102: v1(226.72,151.08) 225.73,151.08 225.5,151.3 225.3,151.51 225.3,151.93 R6404.2 224.45,152.78 223.02,152.78 222.71,153.09 221.18,153.09 220.94,152.84 R6408.1 220.91,152.42 220.05,152.42 219.67,152.03 214.84,152.03 214.26,151.46 214.26,151.04
FORM_FAC_ID_1: length 16.3
  TOP w0.102: R6403.2 224.08,150.99 v1(224.08,151.43) 223.85,151.66 222.83,151.66 222.5,151.34 222.5,150.98 222.69,150.79 R6407.1 222.33,150.44 221.92,150.85 221.92,151.13 221.45,151.6 216.09,151.6 215.35,150.86 215.35,150.03 215.08,149.76 212.47,149.76 SB1.BF35
FORM_FAC_ID_2: length 14
  TOP w0.089: SB1.BD34 210.78,148.96 210.78,148.69 210.94,148.53 211.17,148.53 211.28,148.64 212.6,148.64 212.68,148.56 212.69,148.56 212.8,148.45 214.07,148.45
  TOP w0.102: R6402.2 222.58,146.42 R6406.1 221.6,146.33 220.22,146.33 v1(219.89,146.66) 219.63,146.91 219.18,146.91 218.41,147.68 215.82,147.68 215.05,148.45 214.07,148.45
FORM_FAC_ID_3: length 14.5
  TOP w0.102: SB1.BE34 212.05,149.33 215.33,149.33 216.46,150.47 218.49,150.47 v1(218.73,150.71) 220.18,150.71 220.45,150.44 221.82,150.44 222.72,149.54 R6423.1 223.53,148.54 R6422.2
FP_CBL_DET_PD: length 4.4
  TOP w0.102: R2448.2 202.69,102.06 202.4,101.76 U2401.50 v2(202.4,99.57)
  BOTTOM w0.102: v2(202.4,99.57) 202.4,99.78 v1(202.82,100.2)
FP_MIC2_L: length 15.8
  TOP w0.203: FL2901.2 C2903.1 72.9,243.97 v2(72.26,244.6) 71.75,245.11 71.75,254.5 HPMIC1.4
  BOTTOM w0.203: v1(73.49,243.48) 72.37,244.6 v2(72.26,244.6)
FP_OUT_L: length 5.9
  TOP w0.203: HPMIC1.1 67.75,245.85 C2906.1 67.69,244.16 FL2903.2 67.25,243.27 v2(66.8,242.82)
  BOTTOM w0.203: v1(67.56,242.82) v2(66.8,242.82)
FP_OUT_LL: length 12.2
  TOP w0.203: Q2901.6 71.8,239.38 R2906.2 71.18,239.33 70.99,239.14 v2(68.96,239.14) ; v2(66.8,242.06) 67.12,242.38 FL2903.1 R2907.1
  BOTTOM w0.203: v2(68.96,239.14) 69.5,239.68 69.5,241.44 68.93,242.02 v1(68.8,242.02) 68.76,242.06 v2(66.8,242.06)
FP_OUT_R: length 13.4
  TOP w0.203: HPMIC1.2 73.66,253.46 73.66,249.94 75.19,248.41 75.19,244.86 75.08,244.75 ; 75.08,244.75 74.99,244.67 C2907.1 74.99,243.08 FL2902.2 ; 75.08,244.75 v2(75.08,244.78)
  BOTTOM w0.203: v1(74.99,243.39) 74.99,244.67 75.08,244.75 v2(75.08,244.78)
FP_OUT_RR: length 6.6
  TOP w0.203: R2905.2 72.81,242.25 v1(73.03,242.04) 73.44,241.62 74.01,241.62 74.52,242.13 FL2902.1 R2909.1 75.95,240.92 75.71,240.68 Q2901.3
FP_RST_N: length 188.6
  TOP w0.102: v2(167.13,53.47) 172.85,59.18 172.85,101.62 176.52,105.29 176.52,106.66 177.7,107.84 177.7,107.91 177.98,108.19 178.57,108.19 179.42,109.04 179.57,109.04 180.13,109.6 192.79,109.6 195.59,112.4 195.83,112.65 202.34,112.65 206.25,116.56 209.45,116.56 210.29,117.4 v2(210.29,119.56) 210.29,120.27 209.42,121.13 209.42,127.81 209.17,128.07 209.17,129.27 208.15,130.29 208.15,132.08 208.15,132.09 208.15,133.32 207.97,133.51 SB1.AU2 ; v2(230.61,110) 230.67,109.93 R9921.1 ; v2(224.08,111.99) 218.31,111.99 216.67,113.63 215.01,113.63 213.34,115.29 R2045.1 213.04,116.32 212.64,116.72 v2(211.52,116.72)
  BOTTOM w0.102: v2(210.29,119.56) 209.96,119.23 209.96,117.98 211.21,116.72 v2(211.52,116.72) ; XDP1.48 133.38,71.11 133.38,73.59 133.36,73.61 133.36,74.08 133.38,74.09 133.38,74.17 133.71,74.5 136.83,74.5 137.54,75.21 147.95,75.21 149.61,73.55 149.61,70.73 164.62,55.72 165.02,55.72 165.02,55.72 165.37,55.72 165.91,55.18 165.91,54.69 v2(167.13,53.47) ; v2(224.08,111.99) 224.38,112.29 228.96,112.29 v1(229.96,111.29) 230.61,110.64 v2(230.61,110)
FP_RST_N_CN: length 3.2
  TOP w0.102: APS1.2 233.4,109.22 v1(233.17,109.45) 232.68,109.93 R9921.2
FRONT_JD: length 310.5
  TOP w0.102: R2710.2 v2(54.74,229.62) ; v2(52.53,235.59) 52.53,236.5 54.38,238.36 57.51,238.36 59.46,240.31 v2(59.85,240.31)
  BOTTOM w0.102: v2(52.53,235.59) 53.47,234.65 53.47,230.89 v2(54.74,229.62) ; v2(59.85,240.31) v1(57.45,242.71) 57.45,242.9 52.78,247.58 52.49,247.58 48.99,251.08 32.98,251.08 32.98,251.08 32.79,251.08 32.71,251 13.89,232.18 6.09,232.18 1.7,227.79 1.7,46.07 1.83,45.93 1.84,45.93 12.47,35.3 12.47,30.06 12.47,17.48 12.47,17.48 12.47,12.99 AUD1.23
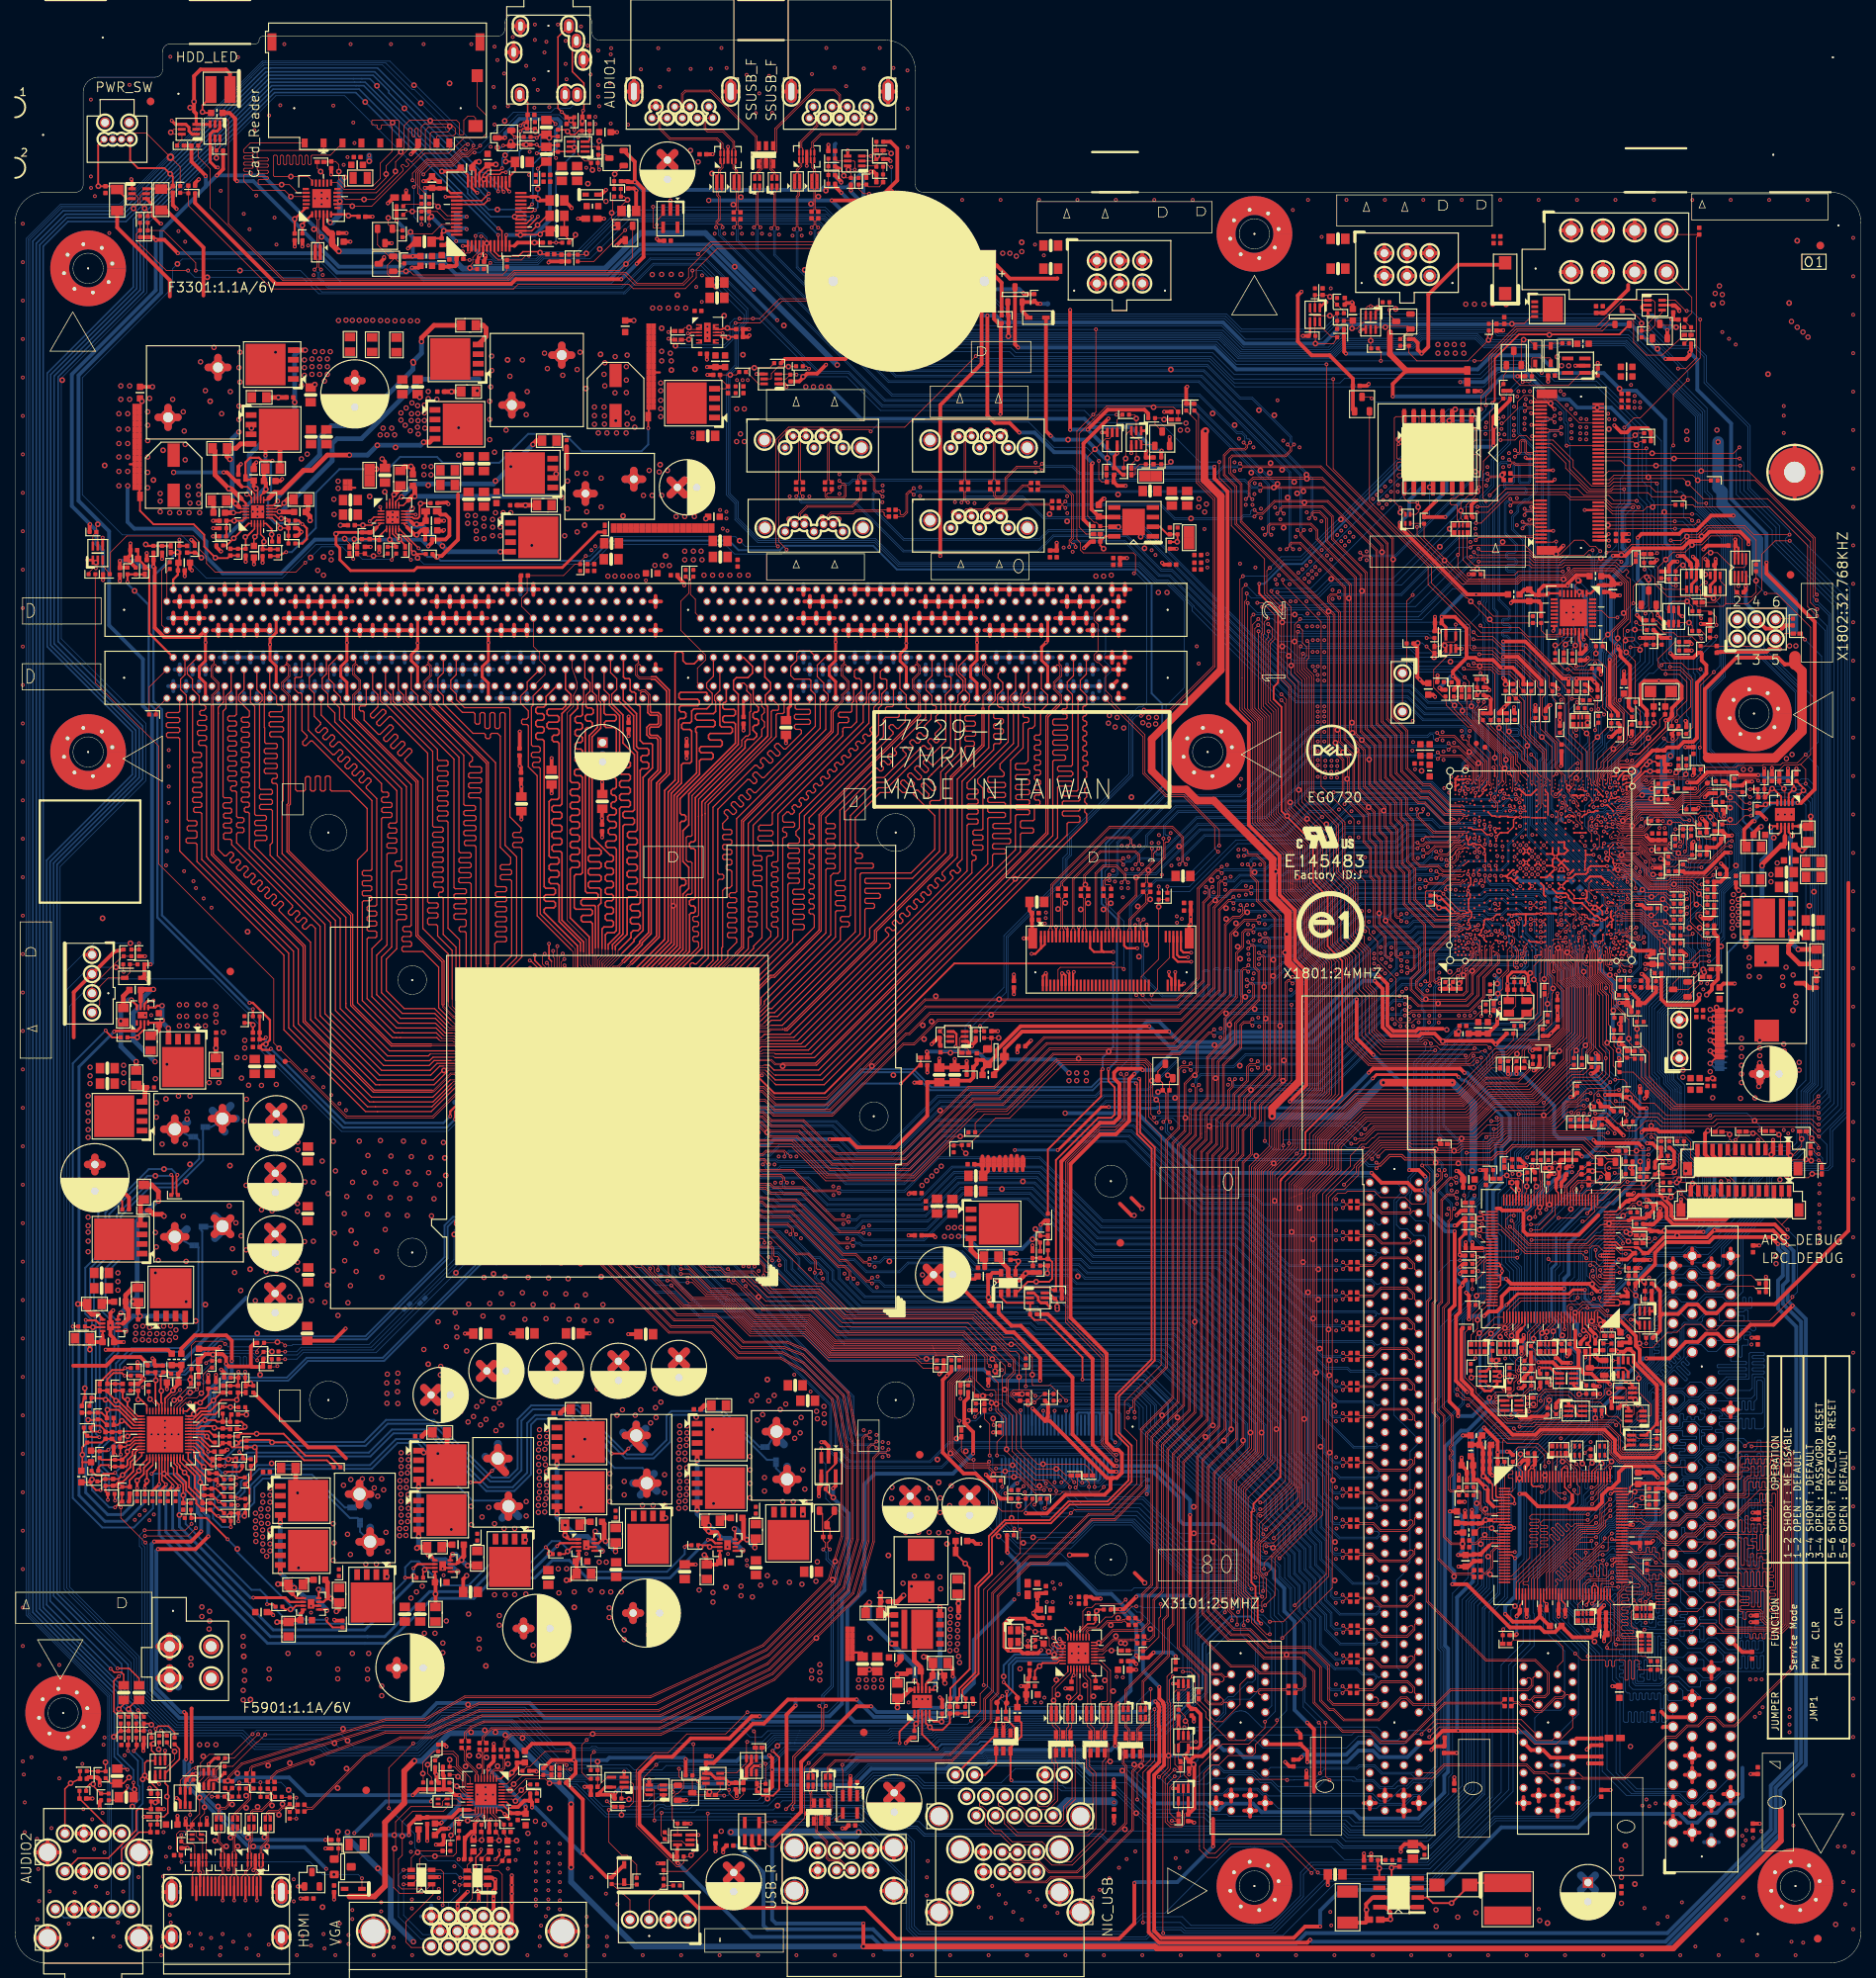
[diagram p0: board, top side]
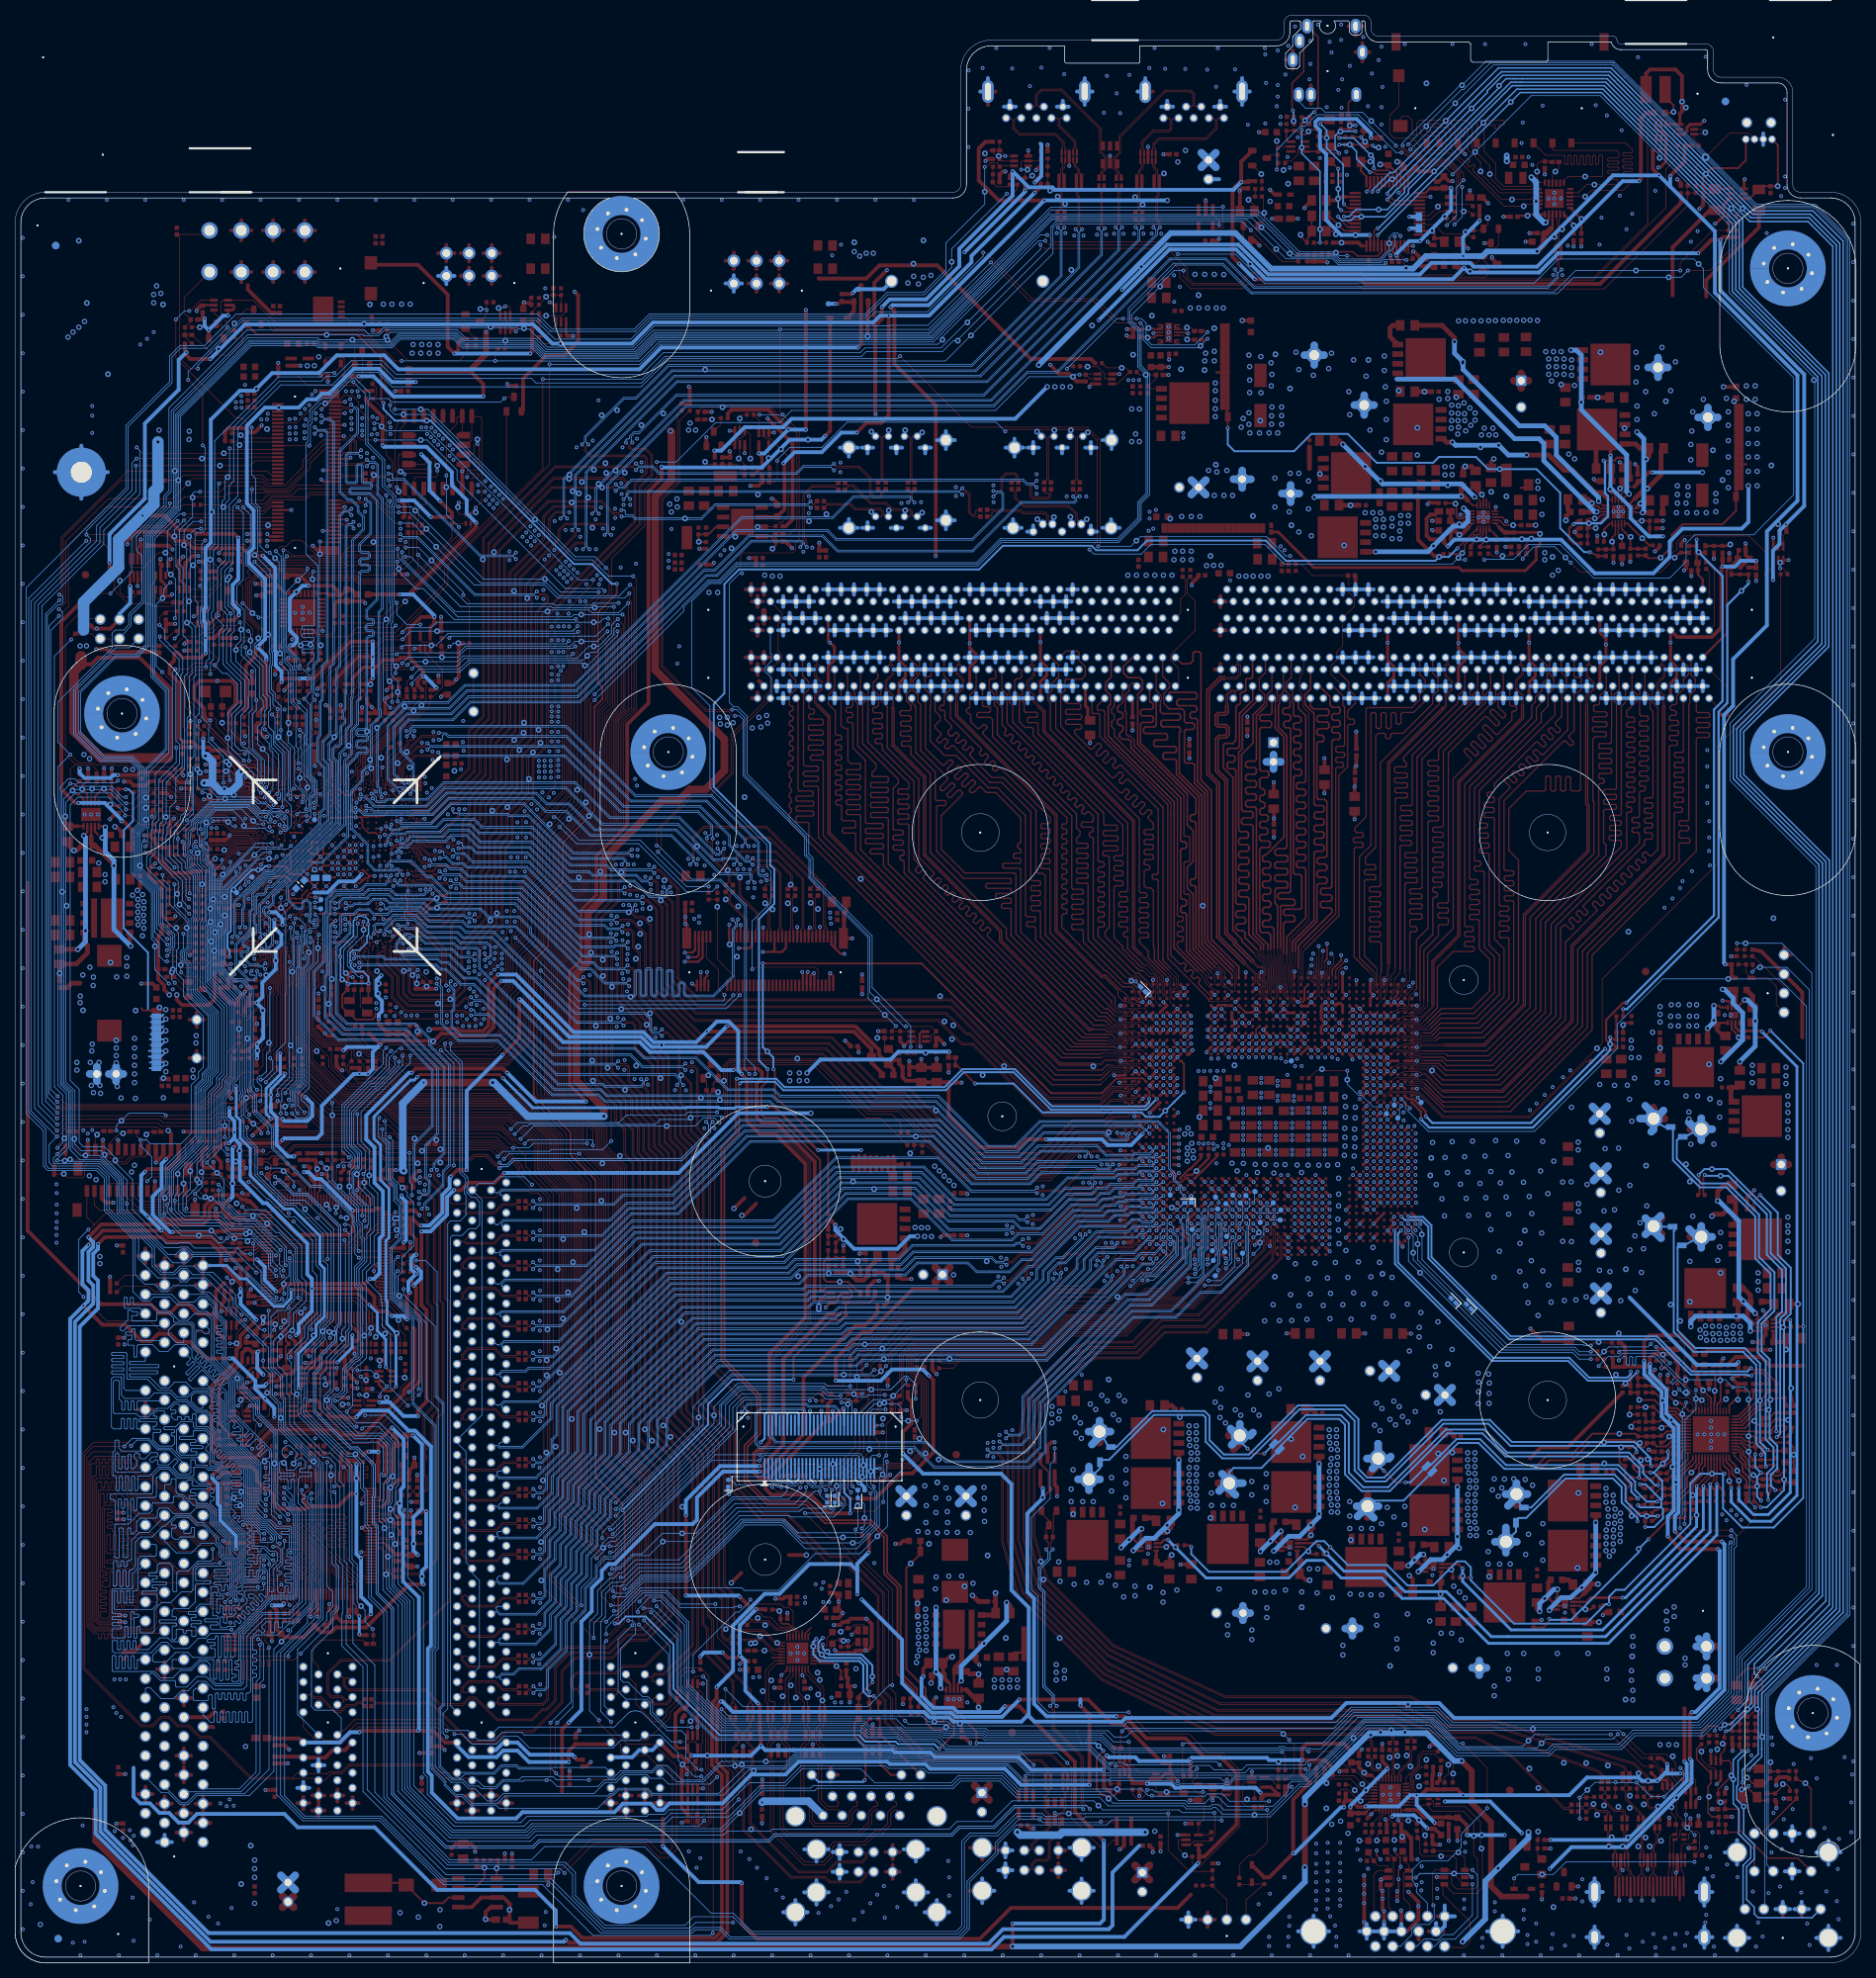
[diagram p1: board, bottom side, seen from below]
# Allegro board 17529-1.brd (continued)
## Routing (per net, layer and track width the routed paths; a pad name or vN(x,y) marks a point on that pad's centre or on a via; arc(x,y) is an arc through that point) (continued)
GPD7: length 6.2
  TOP w0.089: 213.33,153.1 213.28,153.05 212.17,153.05 211.9,152.78 SB1.BE41
  TOP w0.102: 213.33,153.1 214.44,154.21 214.96,154.21 v1(215.07,154.33) 215.28,154.53 216.97,154.53 R2318.1
GPD10: length 7
  TOP w0.089: SB1.BC42 211.71,152.54 212.57,152.54 212.83,152.79 213.03,152.79
  TOP w0.102: R2057.1 217.1,153.86 v1(216.26,153.86) 216.19,153.8 216.08,153.68 214.22,153.68 213.32,152.79 213.03,152.79
GPIO_LAN_RESET_N: length 23.8
  TOP w0.089: SB1.M45 195.83,154.99 195.83,156.59 195.96,156.72
  TOP w0.102: 195.96,156.72 195.96,158.14 195.61,158.5 v1(195.61,159.26) 195.61,160.19 192.47,163.32 192.08,163.32 189.2,166.19 R1912.1 188.73,167.32 187.53,168.53 187.53,170.92 189.79,173.18 U4001.2
GPIO_PCI_RESET_N: length 272.1
  TOP w0.102: v2(212.34,185.17) 212.11,185.4 204.59,185.4 204.28,185.09 200.76,185.09 200.15,185.7 192.56,185.7 v2(192.43,185.83) ; v2(209.3,165.68) 209.19,165.79 R1601.1 ; v2(164.85,179.2) 164.85,175.77 164.72,175.64 164.72,165.81 165.76,164.77 165.76,151.49 169.83,147.42 169.83,142.25 171.86,140.22 171.86,133.67 173.43,132.09 173.43,114.97 168.91,110.45 168.91,108 165.58,104.67 165.58,66.65 161.78,62.84 161.78,48.76 162.41,48.13 v2(162.41,44.62) ; SB1.AV43 208.46,153.83 207.91,154.38 v2(207.9,154.38) ; U4007.2 154.43,19.79 154.56,19.66 154.56,18.33 154.22,17.98 152.68,17.98 152.03,18.63 152.03,24.29 v2(153.26,25.53)
  BOTTOM w0.102: v2(153.26,25.53) 153.7,25.53 155.35,27.18 155.35,30.1 155.93,30.68 157.78,30.68 160.04,32.94 160.04,34.42 160.46,34.84 163.24,34.84 164.29,35.89 164.29,42.74 v2(162.41,44.62) ; v2(212.34,185.17) 210.36,183.18 210.36,173.1 210.29,173.02 210.29,171.64 210.41,171.38 210.41,168.02 209.93,167.54 209.93,166.32 v2(209.3,165.68) 209.3,161.57 207.9,160.17 v2(207.9,154.38) ; v2(164.85,179.2) 167.31,179.2 v1(167.39,179.12) 167.41,179.1 172.97,179.1 173.13,179.25 185.14,179.25 191.72,185.83 v2(192.43,185.83)
GPIO_PEG_RESET_N: length 220.9
  TOP w0.102: SB1.AT49 207.8,160.03 205.36,162.47 R1911.1 204.83,168.59 204.83,168.72 199.56,173.99 199.27,173.99 199.24,174.02 196.6,174.02 195.33,175.29 193.37,175.29 v2(192.81,175.84) ; v2(165.61,177.67) 165.15,177.22 165.15,175.64 165.02,175.51 165.02,166.07 166.07,165.02 166.07,151.61 170.21,147.47 170.21,142.3 172.16,140.35 172.16,133.8 173.74,132.22 173.74,114.85 169.21,110.32 169.21,107.87 165.91,104.57 165.91,66.55 162.08,62.72 162.08,48.89 162.95,48.02 v2(162.95,45.22) ; v2(154.56,31.15) 154.56,31.11 154.43,30.99 U4006.2
  BOTTOM w0.102: v2(162.95,45.22) 162.41,45.22 161.98,44.79 161.98,43.5 163.98,41.5 163.98,37.5 163.57,37.08 162.94,37.08 161.04,35.18 160.36,35.18 159.73,34.55 159.73,33.07 157.82,31.15 v2(154.56,31.15) ; v2(165.61,177.67) 166.19,177.67 166.7,177.16 v1(167.51,177.16) 188.27,177.16 188.99,176.44 192.22,176.44 v2(192.81,175.84)
GPP_A7: length 43.3
  TOP w0.102: v2(209.03,150.41) 209.21,150.24 SB1.BA36 ; R1918.1 R1919.1 219.43,174.57 217.22,172.36 217.22,171.32 217.7,170.84 220.12,170.84 221.49,169.47 221.49,165.98 v2(219.62,164.11)
  BOTTOM w0.102: v2(219.62,164.11) 219.62,164.1 219.74,163.98 219.74,157.94 v1(219.94,157.73) 219.94,155.3 219.75,155.1 218.32,155.1 217.3,154.08 212.29,154.08 211.62,153.4 210.84,153.4 210.01,152.57 209.11,152.57 208.25,151.71 208.23,151.71 207.97,151.46 207.97,150.4 207.97,150.04 208.23,149.79 208.58,149.79 209.03,150.24 v2(209.03,150.41)
GPP_A8: length 16.6
  TOP w0.102: SB1.AV32 208.38,149.25 207.97,149.66 207.97,150.85 v2(208.4,151.28) ; R2001.1 219.77,155.19 v2(219.25,154.67)
  BOTTOM w0.102: v2(208.4,151.28) 208.4,151.53 209.04,152.17 209.93,152.17 210.95,153.19 211.91,153.19 212.47,153.75 217.88,153.75 v1(218.31,154.18) 218.81,154.67 v2(219.25,154.67)
GPP_A14: length 15.8
  TOP w0.102: SB1.BF38 212.57,151.32 212.92,151.32 213.27,151.66 213.83,151.66 214.61,152.45 219.51,152.45 220.67,153.61 223.97,153.61 224.36,154 225.11,154 R1920.1 225.83,154.58 226.42,154 v1(226.72,154)
GPP_H_12: length 10.4
  TOP w0.102: SB1.AB47 200.28,155.91 200.28,157.86 199.19,158.95 199.19,160.1 196.16,163.12 v1(196.16,163.22) R2322.1
GPP_H_15: length 11.3
  TOP w0.102: SB1.AC47 200.76,155.81 200.76,157.76 199.52,159 199.52,160.38 197.49,162.41 v1(197.49,162.74) 197.21,163.02 R2330.1 198.22,164.25 R2301.1
GPP_J0_CNV_BLANKING: length 168.4
  TOP w0.102: v2(238.43,110.79) 238.2,110.79 237.51,111.48 224.9,111.48 224.44,111.02 217.81,111.02 217.06,111.77 214.24,111.77 212.77,113.24 211.55,113.24 210.83,113.96 210.15,113.96 209.42,114.68 v2(209.3,114.68) ; v2(228.04,197.87) v1(216.92,197.87) 212.93,197.87 212.29,198.5 NGFF1.44 ; SB1.AV6 208.71,135.7 v2(207.58,136.83)
  BOTTOM w0.102: v2(209.3,114.68) 209.3,115.44 207.78,116.95 207.78,131.43 207.29,131.93 207.29,135.14 207.58,135.44 v2(207.58,136.83) ; v2(238.43,110.79) 240.94,113.31 240.94,179.51 232.79,187.66 232.79,189.67 228.04,194.42 v2(228.04,197.87)
GPP_J1: length 10.5
  TOP w0.102: SB1.AY3 209.18,134.01 209.18,130.72 210.74,129.16 210.74,128.3 211.02,128.02 211.02,126.11 v1(211.28,125.86) 211.39,125.74 R1511.2
GPP_J8_CNV_RXD: length 164.1
  TOP w0.102: v2(227.94,200.28) 227.16,199.5 v1(216.41,199.5) NGFF1.48 ; v2(210.31,128.83) 210.31,129.29 208.96,130.64 208.96,133.65 208.82,133.79 SB1.AW2 ; v2(211.59,113.89) 211.75,113.72 212.97,113.72 214.44,112.25 217.26,112.25 218.01,111.51 224.24,111.51 224.7,111.96 238.08,111.96 v2(238.46,111.59)
  BOTTOM w0.102: v2(211.59,113.89) 211.44,114.03 211.44,115.88 212.01,116.45 212.01,116.92 211.72,117.21 211.41,117.21 210.74,117.88 210.74,119.33 210.77,119.36 210.77,119.76 210.74,119.78 210.74,120.11 210.31,120.55 v2(210.31,128.83) ; v2(238.46,111.59) 240.46,113.59 240.46,179.31 232.28,187.49 232.28,189.31 227.53,194.06 227.53,199.87 v2(227.94,200.28)
GPP_J9_CNV_TXD: length 174.5
  TOP w0.102: SB1.AU9 207.79,137.41 v2(207.13,137.41) ; NGFF1.46 213.32,199 213.51,198.81 v1(219.3,198.81) v2(227.97,198.81) ; v2(238.46,109.98) 238.33,109.98 237.31,111 225.1,111 224.64,110.54 217.61,110.54 216.86,111.29 215.58,111.29 214.21,109.93 213.02,109.93 212.91,110.03 212.89,110.03 212,110.92 211.82,110.92 210.81,111.94 210.8,111.94 210.49,112.25 210.47,112.25 209.9,112.25 209.9,112.25 v2(208.89,112.25) 208.72,112.42 R2315.1
  BOTTOM w0.102: v2(238.46,109.98) 241.43,112.95 241.43,179.71 233.27,187.86 233.27,189.87 228.55,194.59 228.55,198.22 v2(227.97,198.81) ; v2(208.89,112.25) 208.89,113.74 208.76,113.87 208.76,115.29 207.3,116.75 207.3,131.48 207.09,131.7 207.09,135.23 207.19,135.33 207.19,136.32 207.13,136.38 v2(207.13,137.41)
GPP_K3: length 60.5
  TOP w0.102: SB1.U47 198.55,155.93 198.55,157.53 198.09,157.99 198.09,159.42 193.29,164.22 193.29,165.58 194.17,166.46 v2(194.17,166.63) ; v2(194.44,193.19) 194.04,193.59 194.04,197.14 194.11,197.21 194.11,198.45 194.92,199.26 194.92,204.91 R6314.2 196.27,207.2 196.27,208.17 R6315.1 196.74,208.66 196.74,209.68 197.14,210.28 U6302.G
  BOTTOM w0.102: v2(194.17,166.63) 194.17,169.02 v1(194.51,169.37) 194.87,169.72 194.87,176.83 194.39,177.31 194.39,179.71 194.51,179.83 194.51,192.78 194.39,192.91 194.39,193.14 v2(194.44,193.19)
GPP_K5: length 17.8
  TOP w0.102: R1713.1 189.88,169.27 R1714.1 189.69,169.02 189.69,166.77 v1(190.27,166.18) 190.27,165.63 192.38,163.53 192.56,163.53 196.22,159.87 196.22,158.32 196.47,158.06 196.47,156.04 SB1.N47
GREEN_CRT: length 10
  TOP w0.102: L5904.2 62.67,14.73 C5920.1 61.77,13.6 61.77,10.39 61.86,10.3 EU5901.1 62.46,9.89 62.43,9.86 62.43,7.38 62.22,7.17 62.22,7.09 61.89,6.76 VGA1.2
H_PRDY_N: length 77.8
  TOP w0.102: v2(140,63.53) 139.61,63.92 R9902.2 138.91,64.41 138.05,65.28 v1(137.64,65.28) 134.93,65.28 132.36,67.85 132.36,72.65 131.06,73.94 131.06,77.22 131.93,78.08 131.93,79.67 126.51,85.09 109.51,85.09 106.1,88.49 99.65,88.49 98.26,89.89 97.87,89.89 96.83,90.93 93.85,90.93 93.22,91.57 91.31,91.57 89,93.88 CPU1.B10
  BOTTOM w0.102: v2(140,63.53) 140,63.53 140.03,63.5 140.31,63.5 140.82,62.99 141.38,62.99 141.76,63.37 143.38,63.37 143.92,63.91 XDP1.5
H_PREQ_N: length 78.1
  TOP w0.102: CPU1.B9 89.92,93.35 91.31,91.95 93.22,91.95 93.98,91.19 97.43,91.19 99.9,88.72 106.2,88.72 109.6,85.32 126.6,85.32 132.16,79.76 132.16,79.58 132.16,77.9 131.29,77.04 131.29,74.04 132.97,72.36 132.97,68.1 135.15,65.91 v1(135.89,65.91) 141.4,65.91 142.41,64.91 R9901.2 142.7,64.12 v2(142.7,62.89)
  BOTTOM w0.102: XDP1.3 144.42,64.03 143.28,62.89 v2(142.7,62.89)
H_PWRGD: length 206.4
  TOP w0.102: v2(137.63,62.34) 137.63,62.62 136.45,63.8 134.82,63.8 131.09,67.54 131.09,67.84 v1(131.06,67.87) 131.06,71.93 129.95,73.05 129.95,76.68 C402.1 128.19,78.44 128.19,80.02 127.53,80.68 125.26,82.96 108.57,82.96 105.29,86.23 98.98,86.23 98.73,86.23 95.99,88.98 95.99,89.05 95.3,89.74 94.75,89.74 v2(94.28,90.21) ; v2(91.29,97.71) CPU1.F8 ; R2006.2 202.01,127.88 202.01,124.82 197.23,120.04 195.96,120.04 195.55,119.63 195.55,119.49 192.35,116.29 192.35,116.07 190.89,114.6 177.3,114.6 171.91,109.21 171.91,106.11 168.71,102.91 168.71,101.12 168.71,101.11 168.71,63.3 164.92,59.51 164.42,59.51 164.16,59.25 164.16,56.03 163.86,55.73 163.86,51.02 v2(163.96,50.93)
  BOTTOM w0.102: v2(94.28,90.21) 93.53,90.21 90.25,93.49 90.25,96 90.86,96.61 90.86,97.28 v2(91.29,97.71) ; 136.65,60.83 137.63,61.81 v2(137.63,62.34) 138.29,62.34 140.48,60.15 148.59,60.15 156.03,52.7 161.39,52.7 161.39,52.71 161.79,52.71 163.57,50.93 v2(163.96,50.93)
H_PWRGD_R: length 5.7
  TOP w0.102: R2006.1 202.18,129.97 v1(202.14,130.01) 202.14,132.29 202.46,132.62 202.46,134.37 SB1.AE3
H_RSTOUT_XDP_N: length 8.2
  TOP w0.102: R9911.2 R9909.2 135.88,75.18 v2(134.75,74.05) 134.75,74.17 134.15,74.76 134.15,74.76 133.86,75.06 R9910.2
  BOTTOM w0.102: XDP1.46 v1(133.92,73.84) 134.06,73.84 134.27,74.05 v2(134.75,74.05)
H_SKTOCC_CPU: length 439.3
  TOP w0.102: v2(60.74,114.16) 61.2,114.62 CPU1.AC38 ; v2(198.12,70.61) 198.5,70.23 200.66,70.23 201.32,70.89 210.54,70.89 211.96,69.47 211.96,67.68 212.4,67.23 216.71,67.23 217.55,68.07 217.55,70.1 217.36,70.29 R2478.1 R2477.2 214.57,69.28 214.11,69.74 U2405.1
  BOTTOM w0.102: v2(60.74,114.16) 60.2,113.62 60.2,112.91 57.17,109.88 43.15,109.88 32.21,120.83 32.21,124.04 26.21,130.04 v1(17.53,130.04) 10.8,130.04 7.19,126.43 7.19,49.68 16.41,40.46 16.41,35.68 16.41,35.39 21.06,30.73 22.41,30.73 30.14,30.73 30.99,29.89 31.96,28.92 40.64,28.92 41.47,28.09 53.17,28.09 56.83,31.75 65.55,31.75 73.32,23.98 74.12,23.98 74.41,23.98 74.41,23.98 75.26,23.98 75.72,23.52 75.72,22.67 77.69,20.7 83.74,20.7 84.96,21.92 85.9,21.92 86.76,21.06 88.88,21.06 89.28,21.46 98.2,21.46 99.34,22.61 111.4,22.61 113.53,24.73 119.31,24.73 120.26,23.79 130.34,23.79 132.23,25.68 139.93,25.68 142.17,23.44 145.49,23.44 149.66,19.28 157.13,19.28 157.64,18.77 158.01,18.39 158.02,18.39 175.7,18.39 175.7,18.39 176.52,17.56 186.14,17.56 191.8,23.22 191.8,47.81 193.88,49.9 193.88,56.22 193.88,56.62 193.88,58.61 194.39,59.12 194.39,60.62 194.18,60.82 194.18,63.03 193.8,63.41 193.8,68.69 196,70.89 197.84,70.89 v2(198.12,70.61)
H_SKTOCC_N: length 97.4
  TOP w0.089: SB1.AP3 206.88,134.34 206.88,134.07 206.85,134.04 206.85,134.04 206.85,133.75 206.82,133.73 206.82,132.3 206.73,132.21 206.73,130.79 207.22,130.3
  TOP w0.102: v2(202.07,113.68) 205.79,117.4 207.34,117.4 208.33,118.39 R1509.2 207.85,118.96 207.85,120.28 208.43,120.86 208.43,127.91 208.41,127.93 208.41,129.12 207.22,130.3 ; v2(198.88,70.87) 200.79,70.87 201.04,71.12 210.64,71.12 212.22,69.54 212.22,67.74 212.47,67.49 216.59,67.49 217.04,67.94 R2477.1 215.38,68.39 U2405.4
  BOTTOM w0.102: v2(198.88,70.87) 199.06,70.87 202.11,73.91 202.11,74.45 201.75,74.8 201.17,74.8 200.43,75.54 200.43,78.36 199.01,79.78 198.83,79.78 198.37,80.24 198.37,89.14 198.84,89.61 198.84,91.83 197.84,92.84 197.84,95.73 198.11,95.99 198.11,97.65 198.58,98.12 198.58,99.9 202.07,103.4 v1(202.07,112.01) v2(202.07,113.68)
H_TCK: length 211.7
  TOP w0.102: R415.1 130.48,63.56 v2(130.48,62.92) ; v2(164.85,48.39) 164.47,48.77 164.47,51.17 164.17,51.47 164.17,55.61 164.47,55.9 164.47,58.04 169.19,62.76 169.19,63.02 169.24,63.08 169.24,101.34 169.24,102.68 172.44,105.89 172.44,108.97 177.54,114.07 191.11,114.07 192.89,115.85 192.89,115.96 195.2,118.28 R2008.2 ; v2(87.63,98.62) CPU1.F11 ; v2(129.79,67.06) 129.79,68.83 130.63,69.67 130.63,71.93 129.64,72.92 129.64,75.46 129.41,75.69 128.29,75.69 127.08,76.91 127.08,80.38 125.16,82.3 108.47,82.3 105.07,85.7 98.02,85.7 94.56,89.15 91.95,89.15 88.78,92.33 v2(88.01,92.33)
  BOTTOM w0.102: v2(164.85,48.39) 163.35,48.39 161.04,50.7 155.17,50.7 147.69,58.18 142.53,58.18 139.85,55.5 v1(133.27,55.5) 132.42,55.5 130.06,57.85 130.06,62.22 130.48,62.64 v2(130.48,62.92) 130.92,63.35 XDP1.57 130.92,66.82 130.68,67.06 v2(129.79,67.06) ; v2(88.01,92.33) 87.66,92.68 87.66,94.31 87.2,94.77 87.2,98.19 87.36,98.35 87.36,98.35 v2(87.63,98.62)
H_TDI: length 65.7
  TOP w0.102: v2(128.93,73.15) 129.08,73.3 v1(129.08,74.02) 129.08,74.24 128.85,74.47 127.47,74.47 127.13,74.82 R411.1 126.85,75.21 126.85,80.29 125.07,82.07 108.38,82.07 104.97,85.47 97.92,85.47 94.53,88.86 91.92,88.86 89.09,91.69 v2(88.01,91.69) ; v2(86.74,99.5) 87.17,99.08 CPU1.G12
  BOTTOM w0.102: v2(88.01,91.69) 87.45,92.25 87.45,94.23 86.99,94.68 86.99,98.27 87.16,98.43 87.16,99.09 v2(86.74,99.5) ; XDP1.56 131.42,72.38 130.65,73.15 v2(128.93,73.15)
H_TDO: length 69.6
  TOP w0.102: v2(85.82,100.4) 86.22,99.99 CPU1.H13 ; R402.1 R410.1 125.73,77.09 126.17,77.09 v2(126.19,77.1) 126.19,80.3 124.88,81.61 121.23,81.61 108.19,81.61 104.84,84.96 97.71,84.96 94.27,88.4 91.43,88.4 89.28,90.55 v2(88.9,90.55)
  BOTTOM w0.102: v2(85.82,100.4) 86.29,99.92 86.29,98.43 86.52,98.2 86.52,94.49 87.05,93.97 87.05,91.14 87.63,90.55 v2(88.9,90.55) ; XDP1.52 132.42,72.56 130.56,74.42 128.42,74.42 v1(127.91,74.93) 126.19,76.66 v2(126.19,77.1)
H_TMS: length 70.2
  TOP w0.102: v2(88.9,89.92) 89.53,89.92 91.28,88.18 94.14,88.18 97.61,84.71 104.77,84.71 108.09,81.38 121.33,81.38 124.78,81.38 125.96,80.21 125.96,78.08 124.23,76.35 124.23,72.24 v2(124.84,71.63) 124.84,70.74 125.09,70.48 R412.1 ; CPU1.F13 v2(85.8,97.71)
  BOTTOM w0.102: XDP1.58 130.92,72.41 130.7,72.63 128,72.63 127,71.63 v1(125.93,71.63) v2(124.84,71.63) ; v2(85.8,97.71) 86.28,97.22 86.28,94.4 86.84,93.85 86.84,90.92 87.84,89.92 v2(88.9,89.92)
H_TRST_N: length 70
  TOP w0.102: 128.03,73.91 R9915.1 126.62,74.3 126.62,80.19 124.97,81.84 108.28,81.84 104.88,85.24 97.82,85.24 94.43,88.63 91.58,88.63 89.16,91.06 v2(88.01,91.06) ; 128.03,73.91 127.64,73.52 127.64,72.92 v2(126.86,72.15) ; 128.03,73.91 R417.1 ; v2(86.72,98.61) CPU1.F12
  BOTTOM w0.102: v2(86.72,98.61) 86.78,98.56 86.78,94.61 87.25,94.14 87.25,91.82 v2(88.01,91.06) ; v2(126.86,72.15) 126.86,73.37 127.36,73.86 v1(129.72,73.86) 130.39,73.86 131.92,72.34 XDP1.54
H_TRST_N_R: length 175.4
  TOP w0.089: 205.72,132.21 205.35,132.57 205.35,133.38 205.54,133.56 205.54,134.3 205.72,134.48 SB1.AM4
  TOP w0.102: v2(165.23,47.24) 166.55,48.56 166.55,53.57 172.06,59.08 172.06,101.52 175.29,104.75 175.29,107.8 178.74,111.25 192.28,111.25 194.07,113.04 195.28,114.25 195.53,114.25 195.53,114.25 200.69,114.25 205.54,119.09 205.54,120.54 207.25,122.25 207.27,122.25 207.37,122.35 207.37,128.96 205.92,130.4 205.92,132.01 205.72,132.21 ; v2(128.83,67.06) 128.83,71.2 128.14,71.88 R417.2
  BOTTOM w0.102: v2(128.83,67.06) 129.24,66.65 129.24,64.62 v1(129.31,64.54) 129.76,64.09 129.76,57.72 132.75,54.74 139.52,54.74 142.66,57.87 147.56,57.87 155.04,50.39 160.91,50.39 164.06,47.24 v2(165.23,47.24)
HDA_BITCLK_CODEC: length 262.4
  TOP w0.102: v2(60.07,225.04) 59.4,225.04 C2715.1 59.25,225.61 59.59,225.96 60.09,225.96 60.19,226.06 60.19,226.73 U2701.2 ; v2(223.94,133.82) 222.79,133.82 221.35,132.39 220.41,132.39 R2017.1
  BOTTOM w0.102: v2(223.94,133.82) 223.94,133.87 223.44,134.38 223.44,135.58 225.04,137.19 225.04,141.79 227.55,144.3 227.69,144.43 227.69,149.03 227.69,149.35 226.8,150.24 226.8,157.78 224.16,160.42 224.16,168.04 226.03,169.92 226.03,179.53 226.03,179.53 226.03,188.51 222.38,192.17 222.38,204.43 212.84,213.97 212.65,213.97 204.17,213.97 203.86,213.66 194.28,213.66 193.14,214.81 185.96,214.81 184.76,213.61 175.57,213.61 174.17,212.22 161.77,212.22 159.24,214.74 122.84,214.74 106.97,230.61 80.49,230.61 v1(79.24,229.36) 75.31,225.43 69.76,225.43 69.03,224.69 63.42,224.69 63,225.11 60.47,225.11 60.4,225.04 v2(60.07,225.04)
HDA_BITCLK_PCH: length 11.7
  TOP w0.089: SB1.BD11 211.45,138.48 212.37,138.48 212.56,138.29 213.57,138.29
  TOP w0.102: 213.57,138.29 214.91,138.29 216.73,136.47 217.3,136.47 v1(217.58,136.19) 218.03,136.19 218.67,135.56 218.67,134.52 219.22,133.97 R2055.1 R2017.2
HDA_RST#_CODEC: length 269.8
  TOP w0.102: v2(223.92,132.35) 222.79,132.35 221.95,131.51 R2019.1 ; v2(67.92,225.6) 67.92,225.58 67.47,225.58 66.93,225.04 R2718.1 63.88,225.04 62.86,226.06 U2701.7
  BOTTOM w0.102: v2(67.92,225.6) 68.97,225.6 69.48,226.11 74.22,226.11 79.76,231.65 106.85,231.65 107.03,231.65 123.24,215.44 159.51,215.44 162.05,212.9 173.89,212.9 175.36,214.38 184.56,214.38 185.67,215.49 194.36,215.49 v1(194.94,214.91) 195.35,214.5 203.73,214.5 203.89,214.66 203.99,214.76 213.23,214.76 223.06,204.93 223.06,192.46 226.72,188.8 226.72,179.81 226.72,174.26 228,172.97 231.16,172.97 236.02,168.12 236.02,162.5 232.5,158.98 228.83,158.98 228.64,158.98 227.48,157.82 227.48,150.52 228.37,149.64 228.37,149.5 228.37,144.1 228.1,143.83 225.76,141.48 225.76,135.58 224.97,134.8 224.97,133.09 224.22,132.35 v2(223.92,132.35)
HDA_RST#_PCH: length 11.3
  TOP w0.089: SB1.BE10 212.1,137.72 212.16,137.65 212.45,137.65 212.51,137.72 212.61,137.72
  TOP w0.102: R2019.2 219,131.51 R2056.1 v1(217.68,133.76) 217.42,134.01 217.42,135.07 214.78,137.72 212.61,137.72
HDA_SDIN0_CODEC: length 4.4
  TOP w0.102: R2703.2 60.25,223.85 v1(60.12,223.98) 60.12,224.28 60.5,224.66 60.5,225.37 61.36,226.23 U2701.4
HDA_SDIN0_PCH: length 269.4
  TOP w0.089: 212.69,138.02 212.55,138.02 212.32,138.24 SB1.BE11
  TOP w0.102: 212.69,138.02 214.8,138.02 217.22,135.6 217.5,135.6 218.1,135 ; v2(223.91,133.09) 222.7,133.09 221.77,132.16 219.01,132.16 218.51,132.66 218.51,134.01 218.1,134.42 218.1,135 ; v2(62.81,224.66) 62,223.85 R2703.1 ; 218.1,135 v1(218.08,135)
  BOTTOM w0.102: v2(223.91,133.09) 223.91,133.09 223.51,133.49 223.51,133.98 223.21,134.28 223.21,135.83 224.79,137.42 224.79,141.86 227.46,144.53 227.46,149.26 226.57,150.15 226.57,157.68 223.93,160.33 223.93,168.14 225.81,170.02 225.81,179.43 225.81,188.42 222.15,192.08 222.15,204.34 212.74,213.74 204.26,213.74 203.96,213.44 194.19,213.44 193.04,214.58 186.05,214.58 184.86,213.39 175.66,213.39 174.27,211.99 161.67,211.99 159.87,213.79 159.15,214.52 122.74,214.52 106.88,230.38 81.18,230.38 v1(77.29,226.49) 76,225.2 69.86,225.2 69.12,224.46 63.02,224.46 v2(62.81,224.66)
HDA_SDOUT_CODEC: length 270.2
  TOP w0.102: U2701.3 v2(60.86,228.22) ; v2(223.87,134.56) 223.87,134.56 223.68,134.75 R2020.1
  BOTTOM w0.102: v2(223.87,134.56) 225.53,136.22 225.53,141.58 228.14,144.2 228.14,148.84 228.14,148.84 228.14,149.41 228.14,149.41 228.14,149.54 227.26,150.43 227.26,157.92 228.54,159.21 232.25,159.21 235.59,162.54 235.59,167.96 230.8,172.75 227.91,172.75 226.49,174.16 226.49,179.72 226.49,188.7 222.83,192.36 222.83,204.62 213.03,214.43 203.98,214.43 203.75,214.2 194.39,214.2 193.33,215.26 185.77,215.26 184.57,214.07 175.38,214.07 173.98,212.67 161.96,212.67 159.43,215.2 123.16,215.2 107.3,231.06 79.68,231.06 74.5,225.88 69.57,225.88 68.86,225.17 63.59,225.17 62.36,226.4 v1(62.36,227.25) 62.36,228.01 61.77,228.6 61.24,228.6 v2(60.86,228.22)
HDA_SDOUT_PCH: length 9
  TOP w0.102: R2020.2 R2038.1 219.09,135.76 217.82,137.03 217.06,137.03 v1(216.84,137.25) 216.73,137.36 216.19,137.36 214.99,138.57 212.69,138.57 212.53,138.73 SB1.BF12
HDA_SYNC_CODEC: length 268.8
  TOP w0.102: v2(61.6,228.16) 61.83,228.16 62.36,227.63 U2701.6 ; R2022.1 v1(221.34,136.78) 221.79,136.78 223.27,135.31 v2(223.88,135.31)
  BOTTOM w0.102: v2(61.6,228.16) 61.6,226.84 63.52,224.92 68.93,224.92 69.67,225.65 74.75,225.65 79.93,230.84 107.07,230.84 122.93,214.97 159.34,214.97 161.86,212.45 174.08,212.45 175.47,213.84 184.67,213.84 185.86,215.04 193.23,215.04 194.38,213.89 203.77,213.89 204.08,214.2 212.93,214.2 222.61,204.53 222.61,192.27 226.26,188.61 226.26,179.62 226.26,174.07 227.81,172.52 230.71,172.52 235.36,167.87 235.36,162.64 232.15,159.44 228.45,159.44 227.03,158.01 227.03,150.33 227.91,149.45 227.91,149.31 227.91,144.29 225.3,141.67 225.3,136.72 v2(223.88,135.31)
HDA_SYNC_PCH: length 7.1
  TOP w0.102: SB1.BG13 213.17,138.77 215.11,138.77 216.03,137.85 217.91,137.85 v1(218.19,137.57) 218.97,136.78 R2022.2
HDD_LED_PWR1: length 4.6
  TOP w0.254: R6418.2 24.89,244.47 v1(24.77,244.6) 24.77,245.49 25.87,246.6 LED1.A
HDMI1_DETECT: length 14.3
  TOP w0.102: R1702.2 191.9,167.02 191.9,164.76 197.08,159.58 v1(197.08,159) 197.08,157.43 197.05,157.41 197.05,157.05 197.08,157.02 197.08,156.02 SB1.P47
HDMI_CLK_CON: length 14.7
  TOP w0.102: U5601.3 26.23,22.9 25.03,21.7 v1(25.03,20.57) 25.03,19.76 24.45,19.18 C5610.1 24.32,18.16 24.32,17.24 RN5601.4 24.95,16.96 25.26,16.66 EU5603.1 EU5603.10 25.26,12.46 25.45,12.27 HDMI1.15
HDMI_CLK_CPU: length 308.9
  TOP w0.102: v2(195.48,110.19) 195.87,110.19 196.55,110.86 203.07,110.86 205.35,113.14 206.64,113.14 206.78,113.28 v2(207.37,113.28) ; v2(32.13,30.23) 28.96,27.05 R1908.1 26.23,25.53 U5601.4 ; v2(204.34,138.56) 204.34,138.73 SB1.AL13
  BOTTOM w0.102: v2(32.13,30.23) 32.77,29.59 41.66,29.59 v1(42.22,29.03) 42.9,28.35 53.1,28.35 56.73,31.98 65.64,31.98 73.36,24.26 82.85,24.26 83.55,23.56 84.09,23.56 84.18,23.65 90.04,23.65 90.12,23.57 90.48,23.57 91.01,24.1 99.2,24.1 99.28,24.03 110.79,24.03 112.85,26.08 122.88,26.08 123.49,26.7 128.19,26.7 128.52,27.02 140.61,27.02 142.06,25.58 146.95,25.58 150.36,22.17 159.78,22.17 160.46,22.84 164.19,22.84 164.87,22.17 165.24,22.17 167.01,20.4 179.96,20.4 180.42,20.85 183.79,20.85 184.91,21.97 185.78,21.97 187.28,23.47 187.28,23.89 189,25.61 189,41.34 188.59,41.75 188.59,70.95 191.52,73.87 191.52,84.96 194.39,87.83 194.39,94.54 193.03,95.89 193.03,100.3 193.74,101 193.74,102.64 194.69,103.59 194.69,108.31 195.48,109.09 v2(195.48,110.19) ; v2(204.34,138.56) 203.95,138.17 203.95,137.05 204.25,136.76 205.1,136.76 205.63,136.23 205.63,134.67 205.99,134.31 205.99,133.51 205.38,132.89 205.38,132.1 206.03,131.45 206.03,116.23 207.16,115.1 207.16,113.49 v2(207.37,113.28)
HDMI_DATA_CMC_N0: length 6
  TOP w0.102: v1(35.34,20.99) 35.34,20.61 ; 35.34,20.61 35.76,20.61 R5601.1 36.78,20.61 36.96,20.61 C5602.2 ; 35.34,20.61 35.24,20.61 34.78,20.15 33.53,20.15 33.25,19.87 33.25,19.51 33.08,19.33 TR5601.4
HDMI_DATA_CMC_N1: length 6.6
  TOP w0.102: C5604.2 33.74,22.68 33.74,22.35 R5603.1 33.73,21.56 33.73,21.41 32.56,20.24 32.05,20.24 ; 32.05,20.24 v1(32.05,20.62) ; 32.05,20.24 31.39,20.24 31.14,19.99 31.14,19.56 30.92,19.33 TR5602.4
HDMI_DATA_CMC_N2: length 6.8
  TOP w0.102: 30.92,22.1 30.92,22.64 R5605.1 30.92,23.44 30.92,23.78 C5606.2 ; 30.92,22.1 30.92,21.71 28.98,19.77 28.98,19.58 28.76,19.36 TR5603.4 ; 30.92,22.1 v1(30.53,22.1)
HDMI_DATA_CMC_N3: length 5.8
  TOP w0.102: TR5604.4 26.6,19.31 26.82,19.53 26.82,20.11 27.1,20.4 ; C5608.2 28.1,22.76 28.1,22.4 R5607.1 28.09,21.56 28.09,20.87 27.76,20.55 27.25,20.55 27.1,20.4 ; 27.1,20.4 v1(26.82,20.68)
HDMI_DATA_CMC_P0: length 5.9
  TOP w0.102: TR5601.3 33.73,19.33 33.46,19.59 33.46,19.78 33.62,19.94 34.87,19.94 ; C5601.2 36.96,20.4 36.74,20.4 R5602.1 35.86,20.39 35.33,20.39 34.87,19.94 ; 34.87,19.94 v1(34.87,19.56)
HDMI_DATA_CMC_P1: length 6.6
  TOP w0.102: v1(33.96,20.8) 33.69,21.07 ; 33.69,21.07 33.94,21.32 33.94,21.53 R5604.1 33.95,22.34 33.95,22.68 C5603.2 ; 33.69,21.07 32.65,20.03 31.48,20.03 31.36,19.9 31.36,19.52 31.57,19.31 TR5602.3
HDMI_DATA_CMC_P2: length 6.8
  TOP w0.102: 30.27,20.76 31.13,21.62 31.13,22.64 R5606.1 31.14,23.43 31.14,23.78 C5605.2 ; 30.27,20.76 v1(30.54,20.48) ; 30.27,20.76 29.19,19.68 29.19,19.58 29.41,19.36 TR5603.3
HDMI_DATA_CMC_P3: length 5.8
  TOP w0.102: 28.3,20.94 28.3,20.78 27.85,20.33 27.34,20.33 27.03,20.02 27.03,19.53 27.25,19.31 TR5604.3 ; 28.3,20.94 v1(28.69,20.94) ; 28.3,20.94 28.3,21.58 R5608.1 28.32,22.34 28.32,22.74 C5607.2
HDMI_DATA_CON: length 16.5
  TOP w0.102: HDMI1.16 24.95,12.13 24.78,12.31 EU5603.9 EU5603.2 24.78,16.14 RN5601.3 24.38,16.31 23.91,16.78 23.91,17.36 23.43,17.84 C5611.1 23.43,18.73 24.38,19.68 v1(24.38,21.84) 24.38,24 24.93,24.55 U5601.6
HDMI_DATA_CON_N0: length 9.1
  TOP w0.102: HDMI1.3 31.45,11.33 31.84,11.73 31.84,11.98 32.38,12.51 32.38,12.66 32.27,12.76 EU5601.9 EU5601.2 32.27,14.39 32.4,14.52 32.4,15.28 33.31,16.19 33.31,16.61 ; 33.31,16.61 33.31,17.31 33.08,17.55 TR5601.1 ; 33.31,16.61 v1(32.94,16.61)
HDMI_DATA_CON_N1: length 8.7
  TOP w0.102: HDMI1.6 29.95,11.33 30.34,11.72 30.34,12.09 30.75,12.5 EU5601.6 EU5601.5 30.75,14.47 30.88,14.6 30.88,15.92 31.13,16.17 31.13,16.59 ; v1(30.77,16.59) 31.13,16.59 ; 31.13,16.59 31.13,17.3 30.92,17.52 TR5602.1
HDMI_DATA_CON_N2: length 8.6
  TOP w0.102: HDMI1.9 28.45,11.33 28.84,11.72 28.84,12.93 28.71,13.06 EU5602.9 EU5602.2 28.71,14.62 28.85,14.75 28.85,16.56 ; 28.85,16.56 28.85,16.76 28.98,16.89 28.98,17.3 28.76,17.52 TR5603.1 ; 28.85,16.56 v1(28.47,16.56)
HDMI_DATA_CON_N3: length 8.8
  TOP w0.102: HDMI1.12 26.95,11.35 27.34,11.75 27.34,12.64 27.19,12.79 EU5602.6 EU5602.5 27.19,14.52 27.33,14.65 27.33,15.42 26.82,15.93 26.82,16.13 ; 26.82,16.13 v1(26.42,16.13) ; 26.82,16.13 26.82,17 26.6,17.22 TR5604.1
HDMI_DATA_CON_P0: length 9.1
  TOP w0.102: HDMI1.1 32.45,11.34 32.06,11.73 32.06,11.89 32.62,12.45 32.62,12.68 32.75,12.81 EU5601.10 EU5601.1 32.75,14.39 32.62,14.52 32.62,15.19 33.07,15.65 ; 33.07,15.65 33.53,16.1 33.53,17.32 33.73,17.52 TR5601.2 ; 33.07,15.65 v1(33.33,15.39)
HDMI_DATA_CON_P1: length 8.9
  TOP w0.102: v1(31.5,15.39) 31.1,15.39 ; 31.1,15.39 31.1,14.65 31.23,14.52 EU5601.4 EU5601.7 31.23,12.68 30.56,12 30.56,11.71 30.95,11.32 HDMI1.4 ; 31.1,15.39 31.1,15.83 31.35,16.08 31.35,17.35 31.57,17.57 TR5602.2
HDMI_DATA_CON_P2: length 8.6
  TOP w0.102: v1(29.43,15.39) 29.06,15.39 ; 29.06,15.39 29.06,16.67 29.19,16.8 29.19,17.33 29.41,17.55 TR5603.2 ; 29.06,15.39 29.06,14.73 29.19,14.6 EU5602.1 EU5602.10 29.19,13.06 29.06,12.93 29.06,11.77 29.45,11.37 HDMI1.7
HDMI_DATA_CON_P3: length 8.7
  TOP w0.102: 27.54,15.39 27.54,14.65 27.67,14.52 EU5602.4 EU5602.7 27.67,12.76 27.56,12.65 27.56,11.76 27.95,11.37 HDMI1.10 ; 27.54,15.39 v1(27.91,15.39) ; 27.54,15.39 27.54,15.51 27.03,16.02 27.03,17 27.25,17.22 TR5604.2
HDMI_DATA_CPU: length 307.1
  TOP w0.102: v2(206.76,136.14) 206.82,136.14 SB1.AR8 ; v2(195.15,111.25) 196.09,111.25 196.25,111.42 202.84,111.42 205.12,113.7 206.41,113.7 207.65,114.94 v2(208.28,114.94) ; U5601.1 24.93,23.91 25.55,24.54 26.5,24.54 26.61,24.64 26.61,25.45 27.13,25.97 R2324.1 28.77,25.97 32,29.21 32.11,29.21 v2(33.07,30.18)
  BOTTOM w0.102: v2(33.07,30.18) 43.13,30.18 v1(43.95,29.36) 44.73,28.57 53,28.57 56.64,32.21 65.74,32.21 73.41,24.54 82.89,24.54 83.64,23.79 84,23.79 84.64,24.43 99.19,24.43 99.37,24.26 110.7,24.26 112.75,26.31 122.78,26.31 123.4,26.92 128.1,26.92 128.43,27.25 140.71,27.25 140.88,27.08 142.15,25.81 147.59,25.81 148.61,24.79 151,22.4 159.69,22.4 160.37,23.07 164.28,23.07 164.96,22.4 165.33,22.4 165.67,22.06 179.26,22.06 180.23,21.09 183.65,21.09 184.79,22.23 185.71,22.23 187.05,23.57 187.05,23.98 188.77,25.7 188.77,41.25 188.37,41.65 188.37,71.04 191.29,73.96 191.29,85.06 194.16,87.93 194.16,94.44 192.76,95.84 192.76,100.38 193.51,101.13 193.51,102.73 194.46,103.68 194.46,108.4 195.02,108.96 195.02,111.12 v2(195.15,111.25) ; v2(208.28,114.94) 208.28,115.09 206.82,116.55 206.82,131.52 206.65,131.69 206.65,134.78 206.32,135.1 206.32,135.71 v2(206.76,136.14)
HDMI_DATA_CPU_N0: length 149.1
  TOP w0.102: 44.09,25.4 46.1,27.41 50.91,29.87 55.07,29.87 61.7,32.78 85.26,32.78 99.4,39.62 109.44,49.65 111.27,55.97 111.27,69.01 110.63,72.25 110.47,73.02 110.02,75.32 104.4,80.93 102.02,81.93 96.26,81.93 92.65,85.53 92.25,85.53 87.47,85.53 78.78,94.22 78.78,94.69 78.36,95.11 78.36,95.87 78.59,96.11 78.81,96.11 78.94,96.24 CPU1.D21 ; 44.09,25.4 39.21,20.51 38.62,20.51 C5602.1 ; 44.09,25.4 v1(43.81,25.68)
HDMI_DATA_CPU_N1: length 151.9
  TOP w0.102: 36.43,26.04 34.55,25.36 33.73,24.54 33.73,24.24 C5604.1 ; 36.43,26.04 v1(36.31,26.41) ; 36.43,26.04 39.07,27 39.07,27 48.9,30.57 54.68,30.57 61.38,33.48 85.03,33.48 99.54,40.76 108.83,50.05 110.57,56.07 110.57,68.95 109.37,74.98 104.07,80.28 101.61,81.23 95.97,81.23 92.36,84.84 87.11,84.84 77.44,94.5 77.44,96.79 77.68,97.02 77.89,97.02 78.03,97.15 CPU1.E22
HDMI_DATA_CPU_N2: length 149.9
  TOP w0.102: 60.01,33.79 61.29,34.37 84.69,34.37 99.25,41.46 108.18,50.39 109.87,56.17 109.87,68.25 109.87,68.25 108.57,74.79 104.14,79.22 101.38,80.53 95.68,80.53 92.22,83.99 86.65,83.99 77.64,93 77.64,93.68 77.4,93.92 77.23,93.92 77.11,93.8 CPU1.A23 ; 60.01,33.79 54.75,31.4 54.64,31.38 48.63,31.38 31.3,26.05 31.03,25.77 31.03,25.45 C5606.1 ; 60.01,33.79 v1(59.87,34.14)
HDMI_DATA_CPU_N3: length 154.5
  TOP w0.102: CPU1.D23 77.11,96.29 76.93,96.11 76.76,96.11 76.53,95.87 76.53,93.09 86.4,83.22 91.99,83.22 95.39,79.83 101.16,79.83 104.33,78.04 107.86,74.51 109.18,67.97 109.18,56.4 108.34,53.57 108.34,53.57 107.5,50.74 98.81,42.04 83.96,35.27 59.43,35.27 54.14,32.26 48.99,32.26 43.44,30.55 ; C5608.1 28.11,24.33 28.11,24.6 29.91,26.4 43.44,30.55 ; v1(43.35,30.94) 43.44,30.55
HDMI_DATA_CPU_P0: length 149.2
  TOP w0.102: C5601.1 38.71,20.3 39.3,20.3 42.37,23.37 ; CPU1.C21 78.94,95.78 78.84,95.89 78.68,95.89 78.57,95.78 78.57,95.2 78.99,94.78 78.99,94.31 87.56,85.75 92.16,85.75 92.74,85.75 96.35,82.14 102.06,82.14 104.53,81.12 110.15,75.49 110.21,75.45 110.22,75.43 110.69,73.07 110.83,72.32 110.83,72.32 111.49,69.04 111.49,55.94 109.63,49.53 99.52,39.44 85.31,32.56 61.75,32.56 55.11,29.65 50.97,29.65 46.23,27.23 42.37,23.37 ; v1(42.63,23.1) 42.37,23.37
HDMI_DATA_CPU_P1: length 151.8
  TOP w0.102: CPU1.D22 78.03,96.7 77.92,96.8 77.77,96.8 77.66,96.7 77.66,94.59 87.2,85.05 92.45,85.05 96.06,81.44 101.65,81.44 104.19,80.46 109.57,75.08 110.79,68.97 110.79,56.04 109.02,49.94 99.67,40.58 85.08,33.26 61.42,33.26 54.73,30.35 48.94,30.35 39.14,26.8 39.14,26.79 ; 39.14,26.79 v1(39.27,26.44) ; 39.14,26.79 34.67,25.17 33.95,24.45 33.95,24.26 C5603.1
HDMI_DATA_CPU_P2: length 150
  TOP w0.102: 33.32,26.44 31.42,25.86 31.25,25.68 31.25,25.45 C5605.1 ; 33.32,26.44 v1(33.45,26.09) ; 33.32,26.44 48.66,31.17 54.66,31.17 54.81,31.2 61.33,34.15 84.74,34.15 99.38,41.29 108.37,50.28 110.09,56.14 110.09,68.27 108.77,74.89 104.26,79.4 101.43,80.74 95.77,80.74 92.31,84.2 86.74,84.2 77.85,93.09 77.85,93.77 77.5,94.12 77.5,94.12 77.37,94.25 CPU1.B23
HDMI_DATA_CPU_P3: length 154.4
  TOP w0.102: 29.12,25.31 v1(29.39,25.04) ; 29.12,25.31 30.02,26.21 49.02,32.04 54.2,32.04 59.49,35.05 84,35.05 98.93,41.86 107.7,50.62 108.55,53.51 109.39,56.37 109.39,67.99 108.06,74.61 104.46,78.21 101.21,80.05 95.48,80.05 92.08,83.44 86.49,83.44 76.75,93.18 76.75,95.78 76.85,95.89 77.01,95.89 77.11,95.78 CPU1.C23 ; 29.12,25.31 28.32,24.51 28.32,24.34 C5607.1
HDMI_DET_CON: length 12.8
  TOP w0.102: HDMI1.19 23.45,11.89 23.74,12.18 EU5603.7 EU5603.4 23.74,15.49 23.48,15.75 22.29,15.75 R5609.1 v2(21.97,16.89) ; Q5601.3 v2(23.13,19.57)
  BOTTOM w0.102: v2(23.13,19.57) 23.13,18.05 v1(22.95,17.87) v2(21.97,16.89)
HDMI_DET_CPU: length 396.4
  TOP w0.102: v2(191.62,169.9) 192.23,169.29 R1702.1 ; Q5601.4 23.13,23.78 R5610.1 23.95,24.21 24.51,24.77 24.51,26.42 25.65,27.56 28.63,27.56 31.29,30.23 v2(31.39,30.23) ; v2(164.34,176.78) 163.88,176.33 163.88,165.82 164.61,165.09 165.18,164.53 165.18,151.24 169.25,147.17 169.25,142.44 169.25,142 171.27,139.98 171.27,133.43 172.85,131.85 172.85,115.21 167.64,110.01 v2(167.64,108.03) 167.64,107.56 164.72,104.64 164.72,67.32 161.2,63.8 161.2,48.02 v2(161.47,47.75) ; SB1.AT6 207.36,134.63 207.54,134.44 207.54,133.6 207.29,133.35 207.29,132.08 207.58,131.78 207.81,131.78 207.94,131.65 207.94,130.21 208.94,129.21 208.94,120.93 209.8,120.07 209.8,117.6 209.25,117.04 206.05,117.04 202.14,113.13 195.63,113.13 195.11,112.6 192.59,110.08 179.78,110.08 178.37,108.67 177.78,108.67 177.36,108.25 v2(176.63,108.25)
  BOTTOM w0.102: v2(164.34,176.78) 164.85,176.28 164.85,175.51 167.14,173.22 167.88,173.22 v1(168.38,172.72) 168.99,172.11 184.12,172.11 185.29,170.94 190.58,170.94 v2(191.62,169.9) ; v2(161.47,47.75) 160.63,48.59 158.48,48.59 154.94,45.05 154.94,36.8 150.09,31.95 131.67,31.95 130.81,31.09 127.32,31.09 126.84,31.09 126.51,30.76 121.53,30.76 121.12,30.35 115.92,30.35 115.64,30.07 103.49,30.07 102.04,30.07 102.04,30.07 100.3,30.07 98.63,28.4 77,28.4 76.81,28.59 76.22,28.59 76.01,28.37 72.85,28.37 72.74,28.27 71.4,28.27 66.95,32.72 56.43,32.72 54.44,30.73 31.9,30.73 v2(31.39,30.23) ; v2(176.63,108.25) 176.12,108.76 167.74,108.76 167.64,108.66 v2(167.64,108.03)
HP_OUT_L: length 13.5
  TOP w0.203: v2(64.87,236.63) 64.34,236.63 64.08,236.37 62.61,236.37 62.36,236.12 U2701.31 ; R2906.1 70.47,240.22 C2905.2 69.27,239.98 v2(68.96,240.28) R2904.2
  BOTTOM w0.203: v2(64.87,236.63) 66.67,238.43 66.67,239.4 v1(67.56,240.28) v2(68.96,240.28)
HP_OUT_R: length 14.7
  TOP w0.203: R2903.2 68.83,241.3 v2(68.96,241.17) 69.39,241.6 C2904.2 70.47,241.36 R2905.1 ; U2701.32 61.86,236.27 62.48,236.88 64.08,236.88 v2(64.38,237.17)
  BOTTOM w0.203: v2(64.38,237.17) 64.39,237.18 64.39,238.51 v1(64.77,238.89) 67.06,241.17 v2(68.96,241.17)
I2C0_SCL_VGA: length 7.4
  TOP w0.102: R5911.1 R5918.2 69.74,24.74 67.03,24.74 v1(65.91,23.62) 65.14,22.85 U5901.30
I2C0_SDA_VGA: length 9.7
  TOP w0.102: U5901.29 65.61,22.45 67.46,24.31 70.08,24.31 v1(70.64,23.75) 71.89,23.75 R5919.2 71.96,23.81 R5912.1
I2S1_SFRM: length 6.8
  TOP w0.102: SB1.BD12 211.88,139.16 215.03,139.16 215.75,138.43 v1(216.28,138.43) 216.74,138.43 217.13,138.82 R2058.1
IDSEL_1: length 7.9
  TOP w0.102: SLOT4.51 221.7,48.02 219.62,50.11 219.26,50.11 217.49,51.88 R9203.2
IO_SMI_N: length 4.2
  TOP w0.102: R2420.2 210.15,83.25 v2(209.75,83.64) 209.75,83.67 209.04,84.38 208.62,84.38 208.4,84.6 U2401.126
  BOTTOM w0.102: v2(209.75,83.64) 209.75,84.26 v1(209.62,84.39)
ITP_PMODE: length 147.3
  TOP w0.089: SB1.AL3 205.09,134.23 204.85,133.99 204.85,133.68 204.78,133.61 204.78,132.15 205.23,131.7 205.23,131.44
  TOP w0.102: v2(138.13,74.3) R9911.1 ; 205.23,131.44 205.23,130.15 206.53,128.85 206.53,122.71 204.7,120.88 204.7,119.44 200.34,115.09 195.88,115.09 195.37,115.09 195.37,115.09 194.93,115.09 193.23,113.38 191.93,112.09 178.39,112.09 174.45,108.15 174.45,105.09 171.22,101.86 171.22,101.17 171.22,101.17 171.22,59.59 166.7,55.07 166.5,55.07 v1(166.29,54.86) 166.09,55.07 v2(165.41,55.07)
  BOTTOM w0.102: v2(138.13,74.3) 138.56,74.73 147.75,74.73 149.12,73.35 149.12,70.53 164.59,55.07 v2(165.41,55.07)
KBRST_N: length 124.4
  TOP w0.102: R2463.1 204.44,81.81 205.28,82.65 205.28,84.28 205.2,84.36 U2401.118 205.2,86.78 205.43,87.02 206.83,87.02 207.19,87.38 208.33,87.38 v2(208.73,87.77) ; SB1.BE39 212.05,151.52 212.84,151.52 213.19,151.87 213.75,151.87 214.53,152.65 219.42,152.65 220.68,153.91 222.63,153.91 222.94,154.22 222.94,154.23 223.72,155.02 223.77,155.02 223.8,155.04 226.03,155.04 226.44,154.64 227.28,154.64 228.68,153.24 v2(229.31,153.24)
  BOTTOM w0.102: v2(208.73,87.77) 209.02,87.48 209.63,87.48 209.88,87.73 209.88,87.8 215.7,93.63 220.63,93.63 221.33,94.33 222.07,94.33 222.77,93.63 223.8,93.63 229.74,99.57 229.74,103.59 232.86,106.71 v1(234.7,106.71) 235.36,106.71 236.44,107.79 236.44,115.16 237.57,116.29 237.57,153.85 236.35,155.07 231.32,155.07 229.49,153.24 v2(229.31,153.24)
KCLK: length 4.2
  TOP w0.102: U2401.113 203.2,84.58 v1(201.85,83.24) 201.61,83 RN2401.4
KDAT: length 4.9
  TOP w0.102: U2401.114 203.6,84.52 202.41,83.34 202.41,82.63 v2(202.39,82.6) 202.26,82.48 RN2401.3
  BOTTOM w0.102: v2(202.39,82.6) 202.39,83.31 v1(202.46,83.39)
LAN_CONN_CVT: length 8.9
  BOTTOM w1.016: RJ45R1.9 139.11,21.36 145.03,21.36 v2(145.26,21.21)
LAN_LEDACT_R#: length 16.5
  TOP w0.267: R3204.1 133.02,31.73 133.02,29.92 131.58,28.48 EU3202.6 131.58,24.25 v2(131.7,24.13)
  BOTTOM w0.267: v2(131.7,24.13) 131.91,23.92 137.78,23.92 RJ45R1.22
LAN_MDI0_DN: length 6.5
  TOP w0.102: v1(137.85,35.46) 137.51,35.46 ; 137.51,35.46 137.51,34.24 137.64,34.12 R3203.3 ; 137.51,35.46 137.51,36.24 139.56,38.29 U3101.2
LAN_MDI0_DN_C: length 15.7
  TOP w0.102: RJ45R1.11 134.68,19.69 135.23,20.24 136.61,20.24 137.79,21.42 137.79,26.37 137.49,26.67 137.49,27.65 EU3201.1 137.49,27.88 137.49,28.43 138.11,29.05 138.11,30.95 137.52,31.55 137.52,31.8 137.64,31.93 R3203.2
LAN_MDI0_DP: length 6.5
  TOP w0.102: U3101.1 139.16,38.85 139.16,38.46 137.86,37.17 ; v1(137.63,37.4) 137.86,37.17 ; 137.86,37.17 137.11,36.41 137.11,34.24 136.98,34.12 R3203.4
LAN_MDI0_DP_C: length 15.7
  TOP w0.102: R3203.1 136.98,31.93 137.11,31.8 137.11,31.38 137.71,30.78 137.71,30.27 137.61,30.17 EU3201.6 137.71,30.05 137.71,29.22 137.08,28.6 137.08,26.5 137.39,26.2 137.39,21.59 136.44,20.65 135.36,20.65 135.18,20.83 135.18,21.24 RJ45R1.10
LAN_MDI1_DN: length 6.1
  TOP w0.102: v1(140.79,35.05) 140.56,35.29 ; 140.56,35.29 139.67,34.4 139.67,34.06 139.8,33.94 R3205.3 ; 140.56,35.29 140.77,35.49 140.77,38.18 140.76,38.18 U3101.5
LAN_MDI1_DN_C: length 23.8
  TOP w0.102: RJ45R1.13 132.45,20.11 132.59,20.24 132.87,20.24 133.32,19.79 133.32,18.68 133.97,18.03 138.3,18.03 139.02,18.75 139.02,20.48 140.13,21.6 140.13,28.65 139.41,29.38 139.41,30.05 EU3201.4 139.41,30.25 139.41,30.82 139.67,31.09 139.67,31.66 139.8,31.79 R3205.2
LAN_MDI1_DP: length 6.2
  TOP w0.102: U3101.4 140.36,38.18 140.36,38.18 140.36,35.66 139.53,34.84 ; 139.53,34.84 139.27,34.57 139.27,34.06 139.14,33.93 R3205.4 ; 139.53,34.84 v1(139.27,35.1)
LAN_MDI1_DP_C: length 23.8
  TOP w0.102: R3205.1 139.14,31.79 139.27,31.66 139.27,31.26 139,30.99 139,29.21 139.73,28.48 139.73,27.98 EU3201.3 139.73,27.54 139.73,21.77 138.61,20.65 138.61,18.92 138.13,18.44 134.14,18.44 133.73,18.85 133.73,19.96 133.04,20.65 132.83,20.65 132.66,20.82 132.66,21.27 RJ45R1.12
LAN_MDI2_DN: length 5.9
  TOP w0.102: R3206.3 142.3,34.15 142.19,34.26 142.19,35.23 ; 142.19,35.23 142.19,37.41 141.57,38.04 141.57,38.86 U3101.7 ; 142.19,35.23 v1(142.54,35.23)
LAN_MDI2_DN_C: length 31.8
  TOP w0.102: R3206.2 142.3,31.78 142.17,31.65 142.17,31.44 142.66,30.96 142.66,29.11 142.04,28.48 142.04,27.85 EU3203.1 142.04,27.62 142.04,25.96 142.88,25.12 142.88,24.78 142.88,17.79 141.9,16.81 132.37,16.81 130.78,18.4 130.78,19.75 130.52,20.01 130.28,20.26 130.07,20.26 129.9,20.09 RJ45R1.15
LAN_MDI2_DP: length 5.9
  TOP w0.102: v1(141.45,36.68) 141.78,36.68 ; 141.78,36.68 141.78,34.21 141.64,34.07 R3206.4 ; 141.78,36.68 141.78,37.25 141.16,37.87 141.16,38.86 U3101.6
LAN_MDI2_DP_C: length 31.9
  TOP w0.102: R3206.1 141.64,31.78 141.77,31.65 141.77,31.28 142.25,30.79 142.25,30.22 EU3203.6 142.16,30.12 142.25,30.03 142.25,29.27 141.63,28.65 141.63,25.79 142.47,24.95 142.47,17.96 141.73,17.22 132.54,17.22 131.19,18.57 131.19,19.92 130.45,20.66 130.16,20.66 130,20.83 130,21.14 RJ45R1.14
LAN_MDI3_DN: length 8.3
  TOP w0.102: v1(145.16,35.92) 144.81,35.92 ; 144.81,35.92 144.81,38.64 143.98,39.46 143.5,39.94 U3101.10 ; 144.81,35.92 144.81,34.54 144.48,34.21 R3207.3
LAN_MDI3_DN_C: length 39.7
  TOP w0.102: RJ45R1.17 127.06,19.82 127.46,20.22 127.74,20.22 128.24,19.71 128.24,18.22 129.4,17.07 130.15,17.07 131.62,15.6 135.59,15.6 135.99,15.2 135.99,14 137.06,12.93 139.74,12.93 144.17,17.36 144.17,26.42 144.55,26.8 144.55,28.95 143.95,29.54 143.95,30.03 EU3203.4 143.95,30.22 143.95,30.76 144.35,31.15 144.35,31.7 144.48,31.83 R3207.2
LAN_MDI3_DP: length 8.2
  TOP w0.102: 144.4,37.34 144.4,38.47 143.33,39.54 U3101.9 ; 144.4,37.34 144.4,34.71 144.2,34.52 143.66,34.52 143.56,34.42 143.56,33.83 R3207.4 ; 144.4,37.34 v1(144.04,37.34)
LAN_MDI3_DP_C: length 39.7
  TOP w0.102: R3207.1 143.81,31.85 143.94,31.72 143.94,31.32 143.55,30.92 143.55,29.38 144.15,28.78 144.15,27.83 EU3203.3 144.15,27.65 144.15,26.97 143.76,26.58 143.76,17.53 139.57,13.34 137.23,13.34 136.4,14.16 136.4,15.37 135.76,16 131.79,16 130.44,17.36 130.32,17.48 129.56,17.48 128.65,18.39 128.65,19.88 127.91,20.62 127.63,20.62 127.51,20.75 127.51,21.19 RJ45R1.16
LAN_RSET: length 5.2
  TOP w0.203: 137.47,39.62 137.73,39.62 138.06,39.94 U3101.31
  TOP w0.254: R3101.2 134.81,38.6 v1(135.43,39.22) 135.84,39.62 137.47,39.62
LAN_XTALI: length 9.6
  TOP w0.102: U3101.28 137.47,41.14 136.7,41.91 136.7,42.93 135.97,43.66 R3104.2 135.92,43.76 v1(134.86,43.76) 134.66,43.76 134.19,44.23 C3119.1 133.52,44.23 133.12,44.63 133.11,44.63 133.08,44.67 131.79,44.67 131.58,44.46 X3101.1
LAN_XTALO: length 4.7
  TOP w0.102: U3101.29 137,40.74 v1(136.63,41.12) 135.97,41.78 R3104.1 135.48,42.67 134.86,42.67 R3107.1
LAN_XTALO_C: length 3.9
  TOP w0.102: C3118.1 133.54,41.82 132.95,42.41 X3101.3 ; C3118.1 v2(133.88,42.57) ; C3118.1 133.9,41.83 134.37,41.83 134.39,41.81 134.84,41.81 R3107.2
  BOTTOM w0.102: v1(134.49,42.57) v2(133.88,42.57)
LANCLK_REQ_U_N: length 3.8
  TOP w0.102: U3101.12 143.74,40.74 144.27,41.27 v1(144.93,41.27) R3102.1
LANWAKE_R_N: length 10.2
  TOP w0.102: R2018.1 220.93,157.15 v1(220.85,157.07) 220.47,156.69 215.42,156.69 213.51,154.78 213.51,154.75 213.22,154.46 213.08,154.46 SB1.BG44
LDO5V: length 23.5
  TOP w0.305: PR4959.1 37.97,187.58 38.56,188.16 38.56,189.58 38.02,190.12 v2(37.97,190.12) 37.49,190.6 PR4958.2 ; v2(34.02,198.53) 32.61,198.53 32.23,198.91 31.06,198.91 30.45,198.3 PG4903.2
  BOTTOM w0.305: v2(37.97,190.12) 37.85,190.25 v1(35.94,190.25) 34.35,190.25 33.44,191.15 33.44,193.84 33.82,194.22 33.82,198.34 34.01,198.53 v2(34.02,198.53)
LDO_18V: length 40.9
  TOP w0.203: U9501.59 208.85,47.86 v2(208.46,47.47)
  TOP w0.508: v2(210.06,47.24) 209.41,46.6 C9507.1 C9505.1 C9506.1 209.41,44.03 C9508.1 208.41,43.03 205.88,43.03 204.83,44.08 204.83,44.12 L9501.1 204.37,44.53 203.56,43.71 202.18,43.71 201.57,44.32 197.61,44.32 191.9,50.04 v2(189.99,50.04) ; L9502.1 v2(189.66,59.66)
  BOTTOM w0.508: v2(210.06,47.24) 208.69,47.24 v2(208.46,47.47) ; v2(189.66,59.66) 189.66,52.35 190.22,51.79 v1(190.22,51.05) 190.22,50.27 v2(189.99,50.04)
LDO_AUX_18V: length 12.1
  TOP w0.203: U9501.5 195.58,61.09 195.3,61.37 195.3,63.22 194.94,63.58
  TOP w0.508: L9503.1 193.6,69.37 C9512.1 ; C9512.1 194.04,68.01 C9511.1 C9510.1 C9509.1 194.04,64.35 v1(194.08,64.31) 194.21,64.31 194.94,63.58 ; C9512.1 193.57,68.48 L9504.1
LINE1_JD: length 301.6
  TOP w0.102: R2711.2 53.21,233.87 53.21,236.54 54.57,237.9 57.7,237.9 58.94,239.14 59.69,239.14 60.58,240.03 v2(60.58,240.16)
  BOTTOM w0.102: v2(60.58,240.16) 60.58,240.54 52.98,248.14 v1(52.73,248.14) 49.55,251.31 33.07,251.31 32.7,251.31 32.61,251.23 32.61,251.23 30.77,249.39 13.79,232.41 5.99,232.41 1.47,227.89 1.47,45.97 1.61,45.84 1.74,45.7 12.24,35.2 12.24,29.96 12.24,17.58 11.77,17.1 AUD1.33
LINE1_JD/LINE2_JD: length 7.8
  TOP w0.102: U2701.43 57.12,230.89 v1(55.91,232.1) 55.54,232.47 R2712.1 R2711.1 53.66,232.41 51.56,232.41 R2707.2
LINE1_LL: length 4.2
  TOP w0.203: L3001.1 9.4,23.14 9.88,23.62 v1(10.31,23.62) 10.31,23.39 11.33,22.38 R3003.1 11.36,22.37 R3001.2
LINE1_LL_C: length 4.6
  TOP w0.203: v2(14.84,23.37) 14.84,23.02 C3001.2 13.3,21.48 R3001.1
  BOTTOM w0.203: v1(15.78,22.91) 15.3,22.91 v2(14.84,23.37)
LINE1_RR: length 3.7
  TOP w0.203: L3002.1 10.9,25.35 R3004.1 R3002.2 v1(11.94,26.52)
LINE1_RR_C: length 3.7
  TOP w0.203: R3002.1 12.65,23.73 C3002.2 14.3,23.73 v1(15.06,24.49)
LINE2_JD: length 29.4
  TOP w0.102: v2(61.47,240.16) 61.04,239.73 60.6,239.73 59.78,238.91 59.03,238.91 57.79,237.67 54.66,237.67 53.47,236.47 53.47,234.57 54.67,233.36 R2712.2
  BOTTOM w0.102: v2(61.47,240.16) v1(64.72,243.41) 65.86,244.55 70.82,244.55 71.37,245.11 73.41,245.11 74.3,246 HPMIC1.6
LINE2_VREFO: length 4.6
  TOP w0.305: U2701.12 65.99,226.9
  TOP w0.508: R2901.1 v1(68.66,227.33) 66.42,227.33 65.99,226.9
LINEIN_L: length 3.7
  TOP w0.203: v2(64.52,240.16) 64.55,240.19 D2901.2 65.69,240.28 R2904.1
  BOTTOM w0.203: v2(64.52,240.16) 64.26,239.9 v1(63.75,239.9)
LINEIN_R: length 3.1
  TOP w0.203: R2903.1 66.1,241.3 v2(66.07,241.27) 65.6,241.74 D2901.3
  BOTTOM w0.203: v1(65.53,240.66) 66.07,241.2 v2(66.07,241.27)
LINK_ACTIVITY_N: length 15.7
  TOP w0.203: U3101.27 137.75,41.54 v2(137.24,42.06)
  TOP w0.267: R3204.2 132.49,35.02 TP3101.1 132.49,35.27 v2(130.68,37.08)
  BOTTOM w0.267: v2(137.24,42.06) 137.24,41.55 136.45,40.76 132.12,40.76 130.68,39.32 v1(130.68,37.85) v2(130.68,37.08)
LPC_AD_PCH_P0: length 93.5
  TOP w0.102: SB1.BB39 210.81,151.55 210.81,151.49 210.84,151.46 v2(210.84,151.46) ; v2(222.88,100.71) 223.09,100.91 226.01,100.91 226.52,101.42 LPC1.9 ; v2(208.61,90.73) 208.61,90.56 209.51,89.67 U2401.8
  BOTTOM w0.102: v2(208.61,90.73) 208.99,91.11 208.99,91.74 209.96,92.71 209.96,93.9 213.04,96.98 215.01,96.98 215.02,96.98 215.6,96.98 216.8,98.17 221.62,98.17 222.88,99.44 v2(222.88,100.71) 222.88,101.37 222.5,101.75 v1(222.5,104.27) 222.5,104.66 218.9,108.27 218.9,115.23 217.93,116.2 217.93,116.96 217.12,117.77 217.12,125.68 219.91,128.48 219.91,128.83 219.91,137.62 219.61,137.93 219.61,143.98 220.62,145 220.62,146.06 221.18,146.61 221.18,147.44 220.85,147.77 220.85,149.2 220.17,149.89 220.17,150.57 217.86,152.88 213.11,152.88 211.66,151.43 210.86,151.43 210.84,151.46 v2(210.84,151.46)
LPC_AD_PCH_P1: length 95.5
  TOP w0.102: v2(209.67,150.77) 209.43,150.77 SB1.AW37 ; v2(220.21,101.64) 221.57,100.28 223.09,100.28 223.44,100.63 227,100.63 227.52,101.15 LPC1.8 ; v2(208.23,92.2) 208.61,92.2 209.04,91.77 209.04,90.58 209.55,90.07 U2401.9
  BOTTOM w0.102: v2(209.67,150.77) 209.76,150.67 210.54,150.67 210.82,150.95 211.51,150.95 213.23,152.68 217.69,152.68 219.91,150.45 219.91,149.2 219.66,148.95 219.66,147.58 219.2,147.13 219.2,145.59 218.36,144.75 218.36,137.38 218.64,137.1 218.64,129.57 215.95,126.87 215.95,126.87 215.79,126.71 215.65,126.56 215.65,117.18 216.29,116.53 216.29,116.47 216.29,115.6 217.37,114.52 217.37,107.75 219.2,105.92 219.2,102.65 v2(220.21,101.64) 219.59,101.01 v1(218.13,101.01) 217.8,101.01 214.83,98.04 212.26,98.04 209.72,95.5 209.58,95.5 208.43,94.36 208.43,92.41 v2(208.23,92.2)
LPC_AD_PCH_P2: length 96.9
  TOP w0.102: U2401.10 209.79,90.47 v2(209.47,90.78) ; v2(209.3,151.53) 209.24,151.53 208.84,151.13 208.84,151.08 208.59,150.83 208.53,150.83 SB1.AV37 ; LPC1.7 228.52,101.52 227.2,100.2 v2(223.9,100.2)
  BOTTOM w0.102: v2(209.3,151.53) 209.9,151.53 210.46,152.09 211.1,152.09 211.65,152.09 212.85,153.29 218.14,153.29 220.68,150.75 220.68,150.34 221.43,149.58 221.43,147.98 221.74,147.67 221.74,146.38 221.21,145.85 221.21,144.79 220.17,143.75 220.17,138.16 220.47,137.85 220.47,130.73 220.47,130.73 220.47,128.6 220.47,128.6 220.47,128.25 217.68,125.45 217.68,118 218.49,117.19 218.49,116.44 219.46,115.47 219.46,115.46 219.46,115.23 219.46,108.6 223.34,104.71 223.34,101.79 223.6,101.54 223.6,100.51 v2(223.9,100.2) 223.9,99.21 222.1,97.41 217.02,97.41 215.37,95.76 v1(215.01,95.76) 214.76,95.76 214.71,95.71 212.56,95.71 210.52,93.67 210.52,91.82 v2(209.47,90.78)
LPC_AD_PCH_P3: length 96
  TOP w0.102: U2401.11 210.02,90.87 209.55,91.34 v2(209.55,91.57) ; v2(210.24,151.11) 210.24,151.13 209.88,151.48 SB1.BA38 ; v2(223.39,99.57) 223.59,99.77 224.08,99.77 224.13,99.82 227.84,99.82 229.52,101.5 LPC1.6
  BOTTOM w0.102: v2(209.55,91.57) 210.24,92.25 210.24,93.78 212.72,96.27 213.41,96.27 v1(213.49,96.34) 213.54,96.39 215.52,96.39 216.94,97.81 221.89,97.81 223.39,99.31 v2(223.39,99.57) 223.32,99.64 223.32,101.42 223.06,101.68 223.06,104.6 219.18,108.48 219.18,115.34 218.21,116.31 218.21,117.08 217.4,117.88 217.4,125.57 220.19,128.36 220.19,128.72 220.19,137.74 219.89,138.04 219.89,143.87 220.9,144.88 220.9,145.94 221.46,146.5 221.46,147.55 221.13,147.88 221.13,149.35 220.42,150.06 220.42,150.67 218.01,153.09 213,153.09 211.8,151.89 211.02,151.89 210.66,151.89 210.64,151.89 210.24,151.48 v2(210.24,151.11)
LPC_CLK_14M_DEBUG: length 68.3
  TOP w0.102: LPC1.2 233.52,100.14 232.84,99.46 227.98,99.46 227.97,99.45 224.3,99.45 224.26,99.41 223.89,99.41 223.58,99.11 223.57,99.11 223.52,99.06 221.99,99.06 v2(221.36,99.69) ; v2(220.12,147.53) 220.57,147.99 220.57,148.86 R1915.2
  BOTTOM w0.102: v2(221.36,99.69) 221.36,101.12 220.67,101.81 220.67,101.83 220.4,102.1 220.38,102.1 219.96,102.51 v1(219.96,103.5) 219.96,105.67 217.73,107.9 217.73,114.67 216.65,115.75 216.65,116.68 216,117.33 216,126.41 216.04,126.46 216.31,126.72 216.31,126.73 217.25,127.67 218.85,129.27 218.85,137.18 218.69,137.33 218.69,144.58 219.56,145.44 219.56,146.97 v2(220.12,147.53)
LPC_CLK_14M_EC: length 76.6
  TOP w0.102: v2(220.73,146.88) 220.95,147.11 220.95,148.32 R1914.2 ; U2401.7 209.4,89.27 208.15,90.52 208.15,91.11 v2(208.53,91.49)
  BOTTOM w0.102: v2(208.53,91.49) 208.53,91.82 209.07,92.35 209.07,93.66 212.74,97.33 215.16,97.33 215.46,97.33 216.8,98.68 221.62,98.68 222.38,99.44 222.38,101.37 221.74,102.01 v1(221.74,103) 221.74,104.89 218.44,108.19 218.44,114.97 217.36,116.04 217.36,116.91 217.36,116.98 216.71,117.62 216.71,126.12 218.11,127.52 218.11,127.53 218.24,127.67 218.24,127.88 218.75,128.39 218.97,128.39 219.1,128.52 219.12,128.52 219.56,128.97 219.56,130.35 219.56,137.47 219.25,137.78 219.25,144.13 220.27,145.14 220.27,146.2 220.73,146.66 v2(220.73,146.88)
LPC_CLK_33M_EC: length 72
  TOP w0.102: U2401.16 209.37,92.87 208.93,93.3 v2(208.93,94.21) ; R1916.2 220,148.18 v2(220.14,148.18)
  BOTTOM w0.102: v2(208.93,94.21) 212.41,97.69 215.31,97.69 216.81,99.19 221.5,99.19 221.82,99.5 221.82,101.32 220.85,102.29 v1(220.85,104.65) 220.85,105.28 218.08,108.05 218.08,114.82 217.01,115.9 217.01,116.77 217,116.77 217,116.83 216.36,117.48 216.36,126.27 217.76,127.67 217.76,127.68 218.95,128.88 218.97,128.88 219.2,129.11 219.2,130.2 219.2,130.2 219.2,137.33 218.9,137.63 218.9,144.28 219.91,145.29 219.91,146.72 220.55,147.35 220.55,147.78 v2(220.14,148.18)
LPC_CLK_PCH_P0: length 13.5
  TOP w0.102: v2(211.19,150.5) 211.07,150.62 SB1.BB36 ; v2(219.48,149.82) R1915.1 R1914.1
  BOTTOM w0.102: v2(219.48,149.82) 219.48,150.6 217.6,152.48 214.07,152.48 v1(212.53,150.93) 212.1,150.5 v2(211.19,150.5)
LPC_CLK_PCH_P1: length 14.1
  TOP w0.102: v2(219.25,149.2) 219.46,149 R1916.1 ; SB1.BB34 210.19,149.53 v2(210.03,149.53)
  BOTTOM w0.102: v2(219.25,149.2) 219.05,149.4 219.05,150.7 217.47,152.27 215.17,152.27 214.02,151.13 214.02,151.05 213.76,150.79 v1(213.76,150.26) 213.46,149.96 211,149.96 210.57,149.53 v2(210.03,149.53)
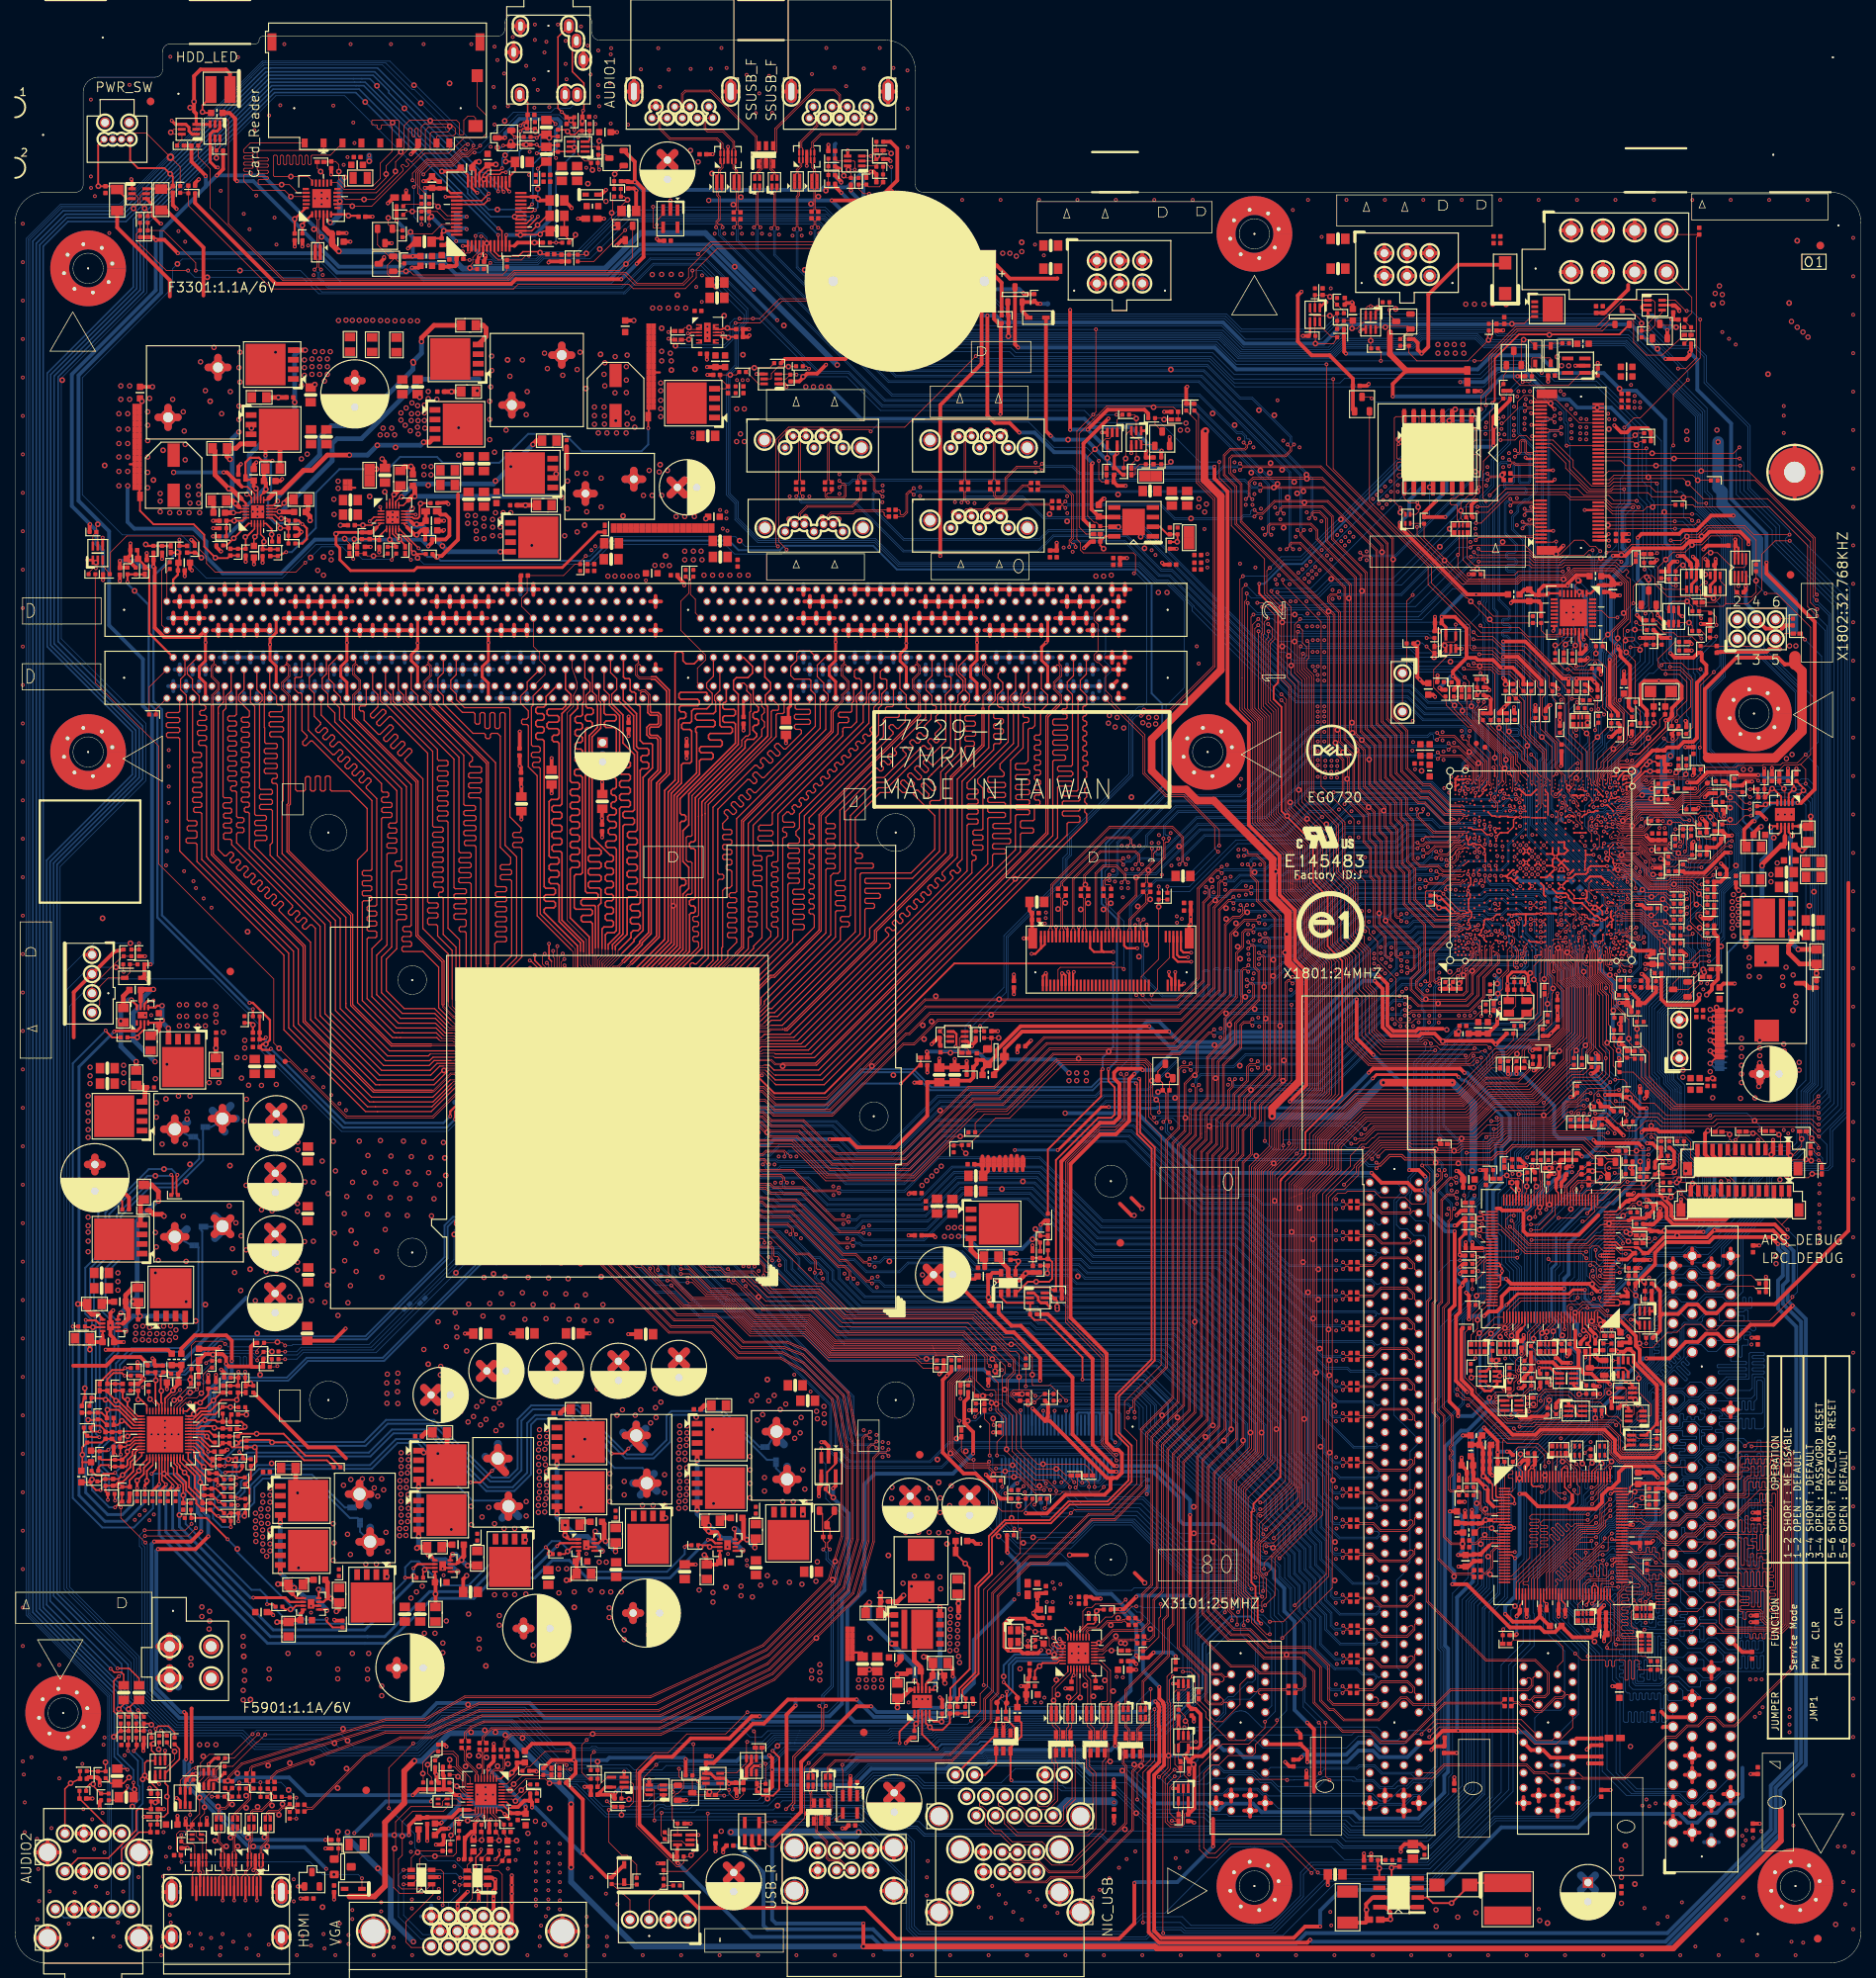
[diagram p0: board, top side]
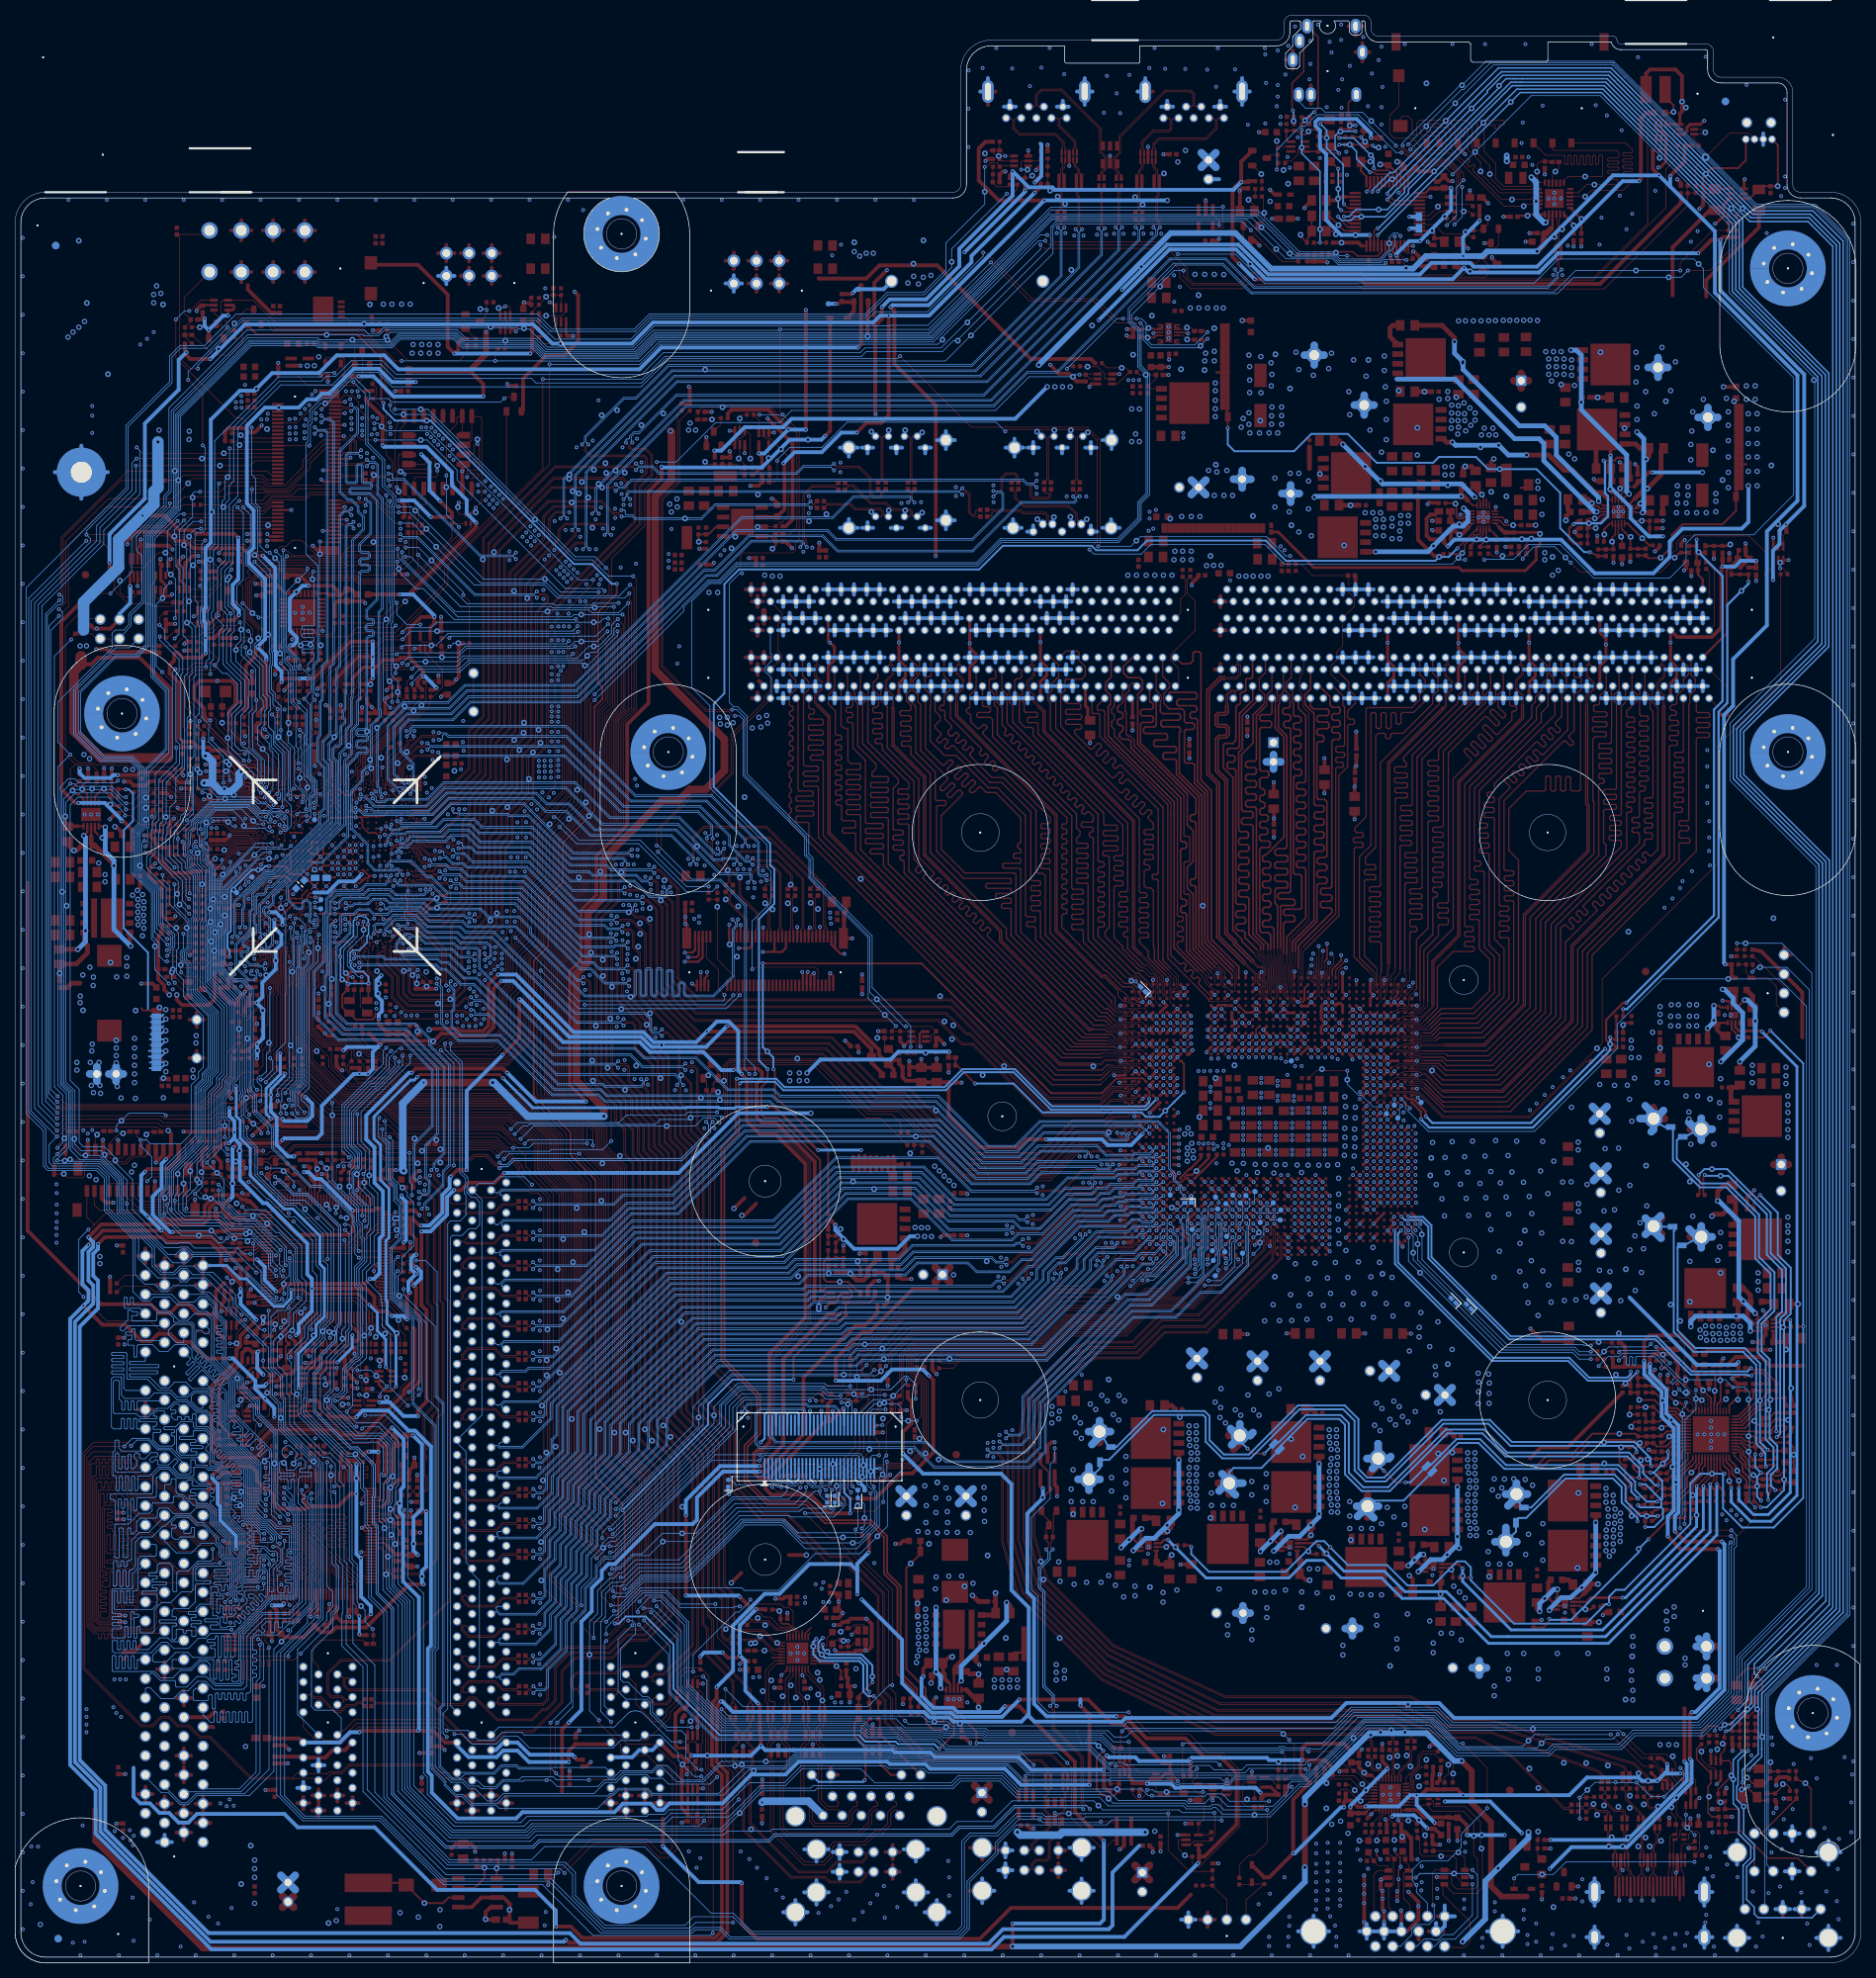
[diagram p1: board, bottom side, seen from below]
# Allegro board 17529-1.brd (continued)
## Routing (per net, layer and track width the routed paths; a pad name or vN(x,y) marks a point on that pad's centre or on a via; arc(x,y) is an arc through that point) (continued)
LPC_FRAME#_PCH: length 96.4
  TOP w0.102: LPC1.5 230.52,101.61 v2(229.24,100.33) ; U2401.12 212.09,91.27 v2(212.12,91.24) ; v2(229.34,152.43) 228.35,152.43 227.36,153.42 R1913.2
  BOTTOM w0.102: v2(229.34,152.43) 229.34,152.58 231.37,154.61 235.46,154.61 236.04,154.61 237.29,153.37 237.29,116.4 236.09,115.21 236.09,108.18 235.23,107.31 232.66,107.31 v1(232.16,106.81) 232.08,106.73 232.08,106.32 229.24,103.48 v2(229.24,100.33) 229.24,99.47 224.29,94.52 222.27,94.52 222.19,94.61 221.21,94.61 220.51,93.91 214.79,93.91 v2(212.12,91.24)
LPC_FRAME#_PCH_R: length 16.6
  TOP w0.089: SB1.BE38 212.27,151.04 212.67,151.04 212.9,150.81 213.76,150.81 214.02,151.06 214.02,151.2
  TOP w0.102: v1(226.72,152.65) 226.42,152.96 225.27,152.96 224.83,153.4 R1913.1 224.65,153.24 222.95,153.24 222.88,153.31 220.66,153.31 219.59,152.24 214.76,152.24 214.02,151.5 214.02,151.2
LPC_PME_N: length 65.4
  TOP w0.102: U2401.75 194.35,95.26 v2(193.57,96.04) 193.22,96.39 R2421.1 ; v2(210.87,116.38) 210.06,115.57 207.92,115.57 206.28,113.93 205.03,113.93 202.78,111.68 v2(195.86,111.68) ; SB1.AV21 208.08,142.68 208.08,141.58 v2(208.86,140.79)
  BOTTOM w0.102: v2(193.57,96.04) 193.26,96.35 193.26,100.05 193.97,100.75 193.97,102.54 194.95,103.52 194.95,108.2 195.96,109.21 195.96,111.58 v2(195.86,111.68) ; v2(210.87,116.38) 209.42,117.83 209.42,120.45 208.27,121.6 208.27,128.01 208.23,128.05 208.23,138.79 v1(208.86,139.42) v2(208.86,140.79)
LPC_SERIRQ_PCH: length 134.4
  TOP w0.102: v2(234.95,88.01) 234.95,87.88 231.88,84.81 226.06,84.81 224.87,83.62 223.6,83.62 222.83,84.38 220.75,84.38 219.71,83.34 218.47,83.34 216.47,81.33 215.19,81.33 214.76,81.76 214.76,83.19 213.39,84.56 213.38,84.56 213.13,84.81 212.53,85.41 210.26,85.41 209.41,86.26 209.02,86.26 208.76,86 208.76,85.35 U2401.127 ; R1910.1 222.72,148.32 v2(222.48,148.56) ; v2(208.4,150.22) 208.73,149.89 SB1.AW35 ; 233.55,97.54 233.55,97.58 234.52,98.55 LPC1.1 ; 233.55,97.54 234.19,96.9 v2(234.31,96.9) ; 233.55,97.54 231.99,99.1 224.45,99.1 224.31,98.96 v2(224.26,98.96)
  BOTTOM w0.102: v2(234.31,96.9) 235.59,95.63 235.59,88.65 v2(234.95,88.01) ; v2(208.4,150.22) 208.41,150.22 208.41,150.67 208.87,151.13 208.87,151.71 209.12,151.96 210.05,151.96 210.38,152.29 211.18,152.29 211.19,152.29 211.5,152.29 212.7,153.49 218.22,153.49 221.13,150.58 221.13,150.57 222.48,149.23 v2(222.48,148.56) 222.48,146.4 221.49,145.41 221.49,144.68 220.45,143.63 220.45,138.28 220.75,137.97 220.75,134.01 221.34,133.42 221.34,132.64 220.77,132.07 220.77,128.5 220.75,128.48 220.75,128.13 217.96,125.34 217.96,118.12 218.77,117.31 218.77,116.56 219.74,115.59 219.74,115.11 219.74,108.72 223.62,104.83 223.62,101.93 224.21,101.35 v1(224.21,101.09) 224.33,100.97 224.33,99.03 v2(224.26,98.96)
LPSS_GSPI0_MOSI: length 9.4
  TOP w0.102: SB1.BE30 211.89,147.3 214.65,147.3 214.71,147.24 214.72,147.24 215.09,146.87 215.09,146.61 215.99,145.71 215.99,144.25 216.4,143.83 v1(216.53,143.83) R2311.1 218.14,143.83 R2308.1
LPSS_GSPI1_MOSI: length 22.5
  TOP w0.102: v2(209.42,146.18) 209.42,145.97 SB1.BA26 ; R2320.1 216.92,130.62 R2319.1 216.22,131.32 v2(215.52,131.32)
  BOTTOM w0.102: v2(215.52,131.32) 216.21,132 216.21,136.06 215.85,136.41 215.85,141.8 211.73,145.92 v1(210.44,145.92) 209.68,145.92 v2(209.42,146.18)
M_A_A0: length 51.5
  TOP w0.089: CPU1.AW15 82.48,129.25 82.57,129.34 82.57,131.27 82.87,131.58
  TOP w0.216: DIMM1.79 91.46,167.78 91.33,167.91 87.97,167.91 87.76,167.69 87.76,167.21 87.97,167 90.21,167 90.45,166.76 90.45,166.35 90.23,166.13 88,166.13 87.78,165.92 87.78,165.54 88,165.32 88.46,165.32 88.67,165.11 88.67,164.67 88.46,164.46 87.91,164.46 87.7,164.24 87.7,156.1 86.33,154.74 86.33,135.04 82.87,131.58
M_A_A1: length 52.8
  TOP w0.089: CPU1.AU18 78.91,128 78.91,128.62 78.68,128.84 78.68,129.56 78.16,130.08 78.16,131.61 79.71,133.16 79.71,133.78 79.84,133.92
  TOP w0.216: 79.84,133.92 81.42,135.5 81.42,136.13 81.71,136.42 82.35,136.42 82.63,136.71 82.63,137.09 82.41,137.3 81.55,137.3 81.33,137.52 81.33,137.95 81.55,138.17 82.41,138.17 82.63,138.38 82.63,138.81 82.41,139.03 81.55,139.03 81.33,139.25 81.33,139.68 81.55,139.89 82.41,139.89 82.63,140.11 82.63,157.59 82.85,157.81 83.55,157.81 83.77,158.03 83.77,158.47 83.55,158.69 82.94,158.69 82.73,158.91 82.73,159.34 82.94,159.55 83.55,159.55 83.77,159.77 83.77,160.29 83.55,160.5 82.4,160.5 82.14,160.76 82.14,165.1 80.38,166.86 80.38,168.7 DIMM1.72
M_A_A2: length 51.5
  TOP w0.089: 80.27,133.47 80.09,133.28 80.09,133.12 78.36,131.39 78.36,130.17 78.91,129.61 78.91,128.93 79.1,128.75 79.1,128.22 79.38,127.93 79.89,127.93 CPU1.AU17
  TOP w0.216: DIMM1.216 80.41,169.94 80.63,169.72 81.16,169.72 81.31,169.58 81.31,168.17 81.52,167.95 81.83,167.95 82.04,167.74 82.04,166.46 82.26,166.24 82.41,166.24 82.63,166.03 82.63,161.54 83.02,161.15 84.09,161.15 84.26,160.98 84.26,157.91 83.01,156.66 83.01,136.45 81.83,135.26 81.83,135.02 80.27,133.47
M_A_A3: length 53.4
  TOP w0.089: CPU1.AV19 78.44,128.47 78.44,129.51 77.93,130.02 77.93,131.81 79.34,133.22 79.34,133.91
  TOP w0.216: 79.34,133.91 79.34,134.36 80.9,135.92 80.9,140.65 81.11,140.87 82.03,140.87 82.25,141.08 82.25,141.52 82.03,141.73 81.11,141.73 80.9,141.95 80.9,142.38 81.11,142.6 82.03,142.6 82.25,142.81 82.25,143.24 82.03,143.46 81.11,143.46 80.9,143.68 80.9,144.11 81.11,144.32 82.03,144.32 82.25,144.54 82.25,144.97 82.03,145.19 81.11,145.19 80.9,145.4 80.9,145.83 81.11,146.05 82.03,146.05 82.25,146.27 82.25,146.7 82.03,146.91 81.11,146.91 80.9,147.13 80.9,147.56 81.11,147.78 82.03,147.78 82.25,147.99 82.25,148.43 82.03,148.64 81.17,148.64 80.95,148.86 80.95,149.29 81.17,149.5 82.03,149.5 82.25,149.72 82.25,159.99 81.76,160.48 81.76,164.82 79.56,167.02 DIMM1.71
M_A_A4: length 53.5
  TOP w0.089: CPU1.AT19 78.93,126.87 78.93,127.57 78.68,127.83 78.57,127.83 78.24,128.17 78.24,129.39 77.72,129.9 77.72,132.02 78.96,133.26 78.96,133.99
  TOP w0.165: 79.03,166.24 78.87,166.4 78.87,167.64 79.53,168.3 79.53,169.7 78.71,170.52 DIMM1.214
  TOP w0.216: 78.96,133.99 78.96,134.56 80.35,135.95 80.35,150.22 80.57,150.44 81.65,150.44 81.87,150.66 81.87,151.09 81.65,151.3 80.57,151.3 80.35,151.52 80.35,151.95 80.57,152.17 81.65,152.17 81.87,152.38 81.87,159.69 80.35,161.2 80.35,164.92 79.03,166.24
M_A_A5: length 55
  TOP w0.089: CPU1.AU20 77.98,127.75 77.98,129.32 77.52,129.78 77.52,132.21 78.4,133.09 78.4,133.99
  TOP w0.165: DIMM1.213 77.86,168.24 78.55,167.55 78.55,166.18 78.88,165.86
  TOP w0.216: 78.88,165.86 79.91,164.83 79.91,159.02 80.12,158.81 81.11,158.81 81.33,158.59 81.33,158.16 81.11,157.94 80.12,157.94 79.91,157.73 79.91,157.3 80.12,157.08 81.11,157.08 81.33,156.87 81.33,156.43 81.11,156.22 80.12,156.22 79.91,156 79.91,155.57 80.12,155.35 81.11,155.35 81.33,155.14 81.33,154.71 81.11,154.49 80.12,154.49 79.91,154.27 79.91,153.84 80.12,153.63 81.11,153.63 81.33,153.41 81.33,152.98 81.11,152.76 80.12,152.76 79.91,152.55 79.91,136.09 78.4,134.59 78.4,133.99
M_A_A6: length 53.6
  TOP w0.089: 78.02,133.99 78.02,133.13 77.29,132.4 77.29,129.69 77.66,129.33 CPU1.AV20
  TOP w0.216: 78.02,133.99 78.02,135.86 78.3,136.14 79.2,136.14 79.48,136.42 79.48,147.17 79.26,147.39 78.3,147.39 78.08,147.61 78.08,148.04 78.3,148.25 79.26,148.25 79.48,148.47 79.48,148.9 79.26,149.12 78.63,149.12 78.42,149.33 78.42,149.74 78.66,149.98 79.26,149.98 79.48,150.2 79.48,150.63 79.26,150.84 78.58,150.84 78.34,151.09 78.34,151.49 78.55,151.71 79.26,151.71 79.48,151.92 79.48,152.36 79.26,152.57 79.01,152.57 78.79,152.79 78.79,153.22 79.01,153.43 79.26,153.43 79.48,153.65 79.48,154.08 79.26,154.3 79.01,154.3 78.79,154.51 78.79,154.92 79.03,155.16 79.26,155.16 79.48,155.38 79.48,156.42 79.26,156.63 78.5,156.63 78.26,156.88 78.26,157.28 78.48,157.5 79.26,157.5 79.48,157.71 79.48,163.04 79.26,163.26 78.12,163.26 77.9,163.47 77.9,163.91 78.12,164.12 79.26,164.12 79.48,164.34 79.48,164.72 79.25,164.95 78.08,164.95 77.86,165.16 DIMM1.69
M_A_A7: length 54.9
  TOP w0.089: CPU1.AU21 77.08,127.76 77.08,128.69 77.17,128.78 77.17,129.16 76.83,129.49 76.83,132.89 77.11,133.16 77.11,134.19
  TOP w0.165: 76.99,166.12 76.99,166.24 76.85,166.38 76.85,167.45 76.32,167.98 76.32,170.77 DIMM1.211
  TOP w0.216: 77.11,134.19 77.11,139.72 77.44,140.06 77.44,141.83 77.23,142.05 75.98,142.05 75.76,142.27 75.76,142.7 75.98,142.91 77.25,142.91 77.47,143.13 77.47,143.56 77.25,143.78 75.98,143.78 75.76,143.99 75.76,144.42 75.98,144.64 77.25,144.64 77.47,144.86 77.47,145.29 77.25,145.5 75.98,145.5 75.76,145.72 75.76,146.15 75.98,146.37 77.25,146.37 77.47,146.58 77.47,146.96 77.19,147.24 76.1,147.24 75.89,147.46 75.89,162.18 76.99,163.28 76.99,166.12
M_A_A8: length 54.1
  TOP w0.089: CPU1.AT20 77.3,126.87 77.3,128.61 77.36,128.67 77.36,129.3 77.06,129.59 77.06,132.59 77.59,133.11 77.59,134.06
  TOP w0.165: DIMM1.68 77.17,168.57 77.17,166.84 77.41,166.6 77.41,165.8
  TOP w0.216: 77.59,134.06 77.59,136.64 77.85,136.9 78.88,136.9 79.1,137.12 79.1,137.55 78.88,137.77 78.24,137.77 78.02,137.98 78.02,138.41 78.24,138.63 78.88,138.63 79.1,138.84 79.1,139.28 78.88,139.49 78.24,139.49 78.02,139.71 78.02,140.14 78.24,140.36 78.88,140.36 79.1,140.57 79.1,141 78.88,141.22 78.24,141.22 78.02,141.44 78.02,141.87 78.24,142.08 78.88,142.08 79.1,142.3 79.1,142.73 78.88,142.95 78.24,142.95 78.02,143.16 78.02,143.59 78.24,143.81 78.88,143.81 79.1,144.03 79.1,144.46 78.88,144.67 78.24,144.67 78.02,144.89 78.02,145.32 78.24,145.54 78.88,145.54 79.1,145.75 79.1,146.19 78.88,146.4 78.64,146.4 76.27,148.78 76.27,162.02 77.41,163.16 77.41,165.8
M_A_A9: length 55.8
  TOP w0.089: CPU1.AT22 75.5,126.83 75.5,127.61 75.74,127.85 75.85,127.85 76.2,128.2 76.2,128.63 76.13,128.7 76.13,129.26 76.33,129.46 76.33,133.41
  TOP w0.165: DIMM1.66 75.15,168.57 75.15,166.62 75,166.46 75,166.19
  TOP w0.216: 76.33,133.41 76.33,137.35 76.11,137.57 75.04,137.57 74.83,137.78 74.83,138.21 75.04,138.43 76.11,138.43 76.33,138.65 76.33,139.03 76.11,139.24 74.13,139.24 73.91,139.46 73.91,143.63 74.13,143.85 74.78,143.85 75,144.06 75,156.66 74.78,156.88 74.16,156.88 73.94,157.1 73.94,157.53 74.16,157.74 74.78,157.74 75,157.96 75,158.47 74.78,158.68 74.24,158.68 74.02,158.9 74.02,159.33 74.24,159.55 74.78,159.55 75,159.76 75,160.19 74.78,160.41 74.24,160.41 74.02,160.63 74.02,161.06 74.24,161.27 74.78,161.27 75,161.49 75,161.92 74.78,162.14 74.24,162.14 74.02,162.35 74.02,162.79 74.24,163 74.78,163 75,163.22 75,163.65 74.78,163.87 74.24,163.87 74.02,164.08 74.02,164.51 74.24,164.73 74.78,164.73 75,164.94 75,166.19
M_A_A10: length 51.1
  TOP w0.165: 92.61,166.15 92.61,166.7 92.47,166.84 92.47,167.45 93.16,168.14 DIMM1.225
  TOP w0.216: 92.61,166.15 92.61,165.38 92.32,165.09 90.16,165.09 89.94,164.87 89.94,164.44 90.16,164.22 92.32,164.22 92.53,164.01 92.53,163.58 92.32,163.36 90.18,163.36 89.97,163.14 89.97,162.71 90.09,162.59 90.09,157.25 87.11,154.27 87.11,134.59 83.14,130.62 CPU1.AY14
M_A_A11: length 54
  TOP w0.089: 76.71,134.14 76.71,133.2 76.59,133.08 76.59,129.41 76.32,129.14 76.32,128.78 76.41,128.69 76.41,128 75.94,127.54
  TOP w0.102: CPU1.AU22 75.94,127.54
  TOP w0.165: DIMM1.210 75.31,169.85 76,169.16 76,168.05 75.47,167.52 75.47,166.37
  TOP w0.216: 75.47,166.37 75.47,166.05 75.68,165.84 76.19,165.84 76.43,165.59 76.43,165.19 76.21,164.97 75.6,164.97 75.38,164.76 75.38,164.32 75.6,164.11 76.06,164.11 76.3,163.87 76.3,163.46 76.09,163.24 75.6,163.24 75.38,163.03 75.38,141.63 75.6,141.41 76.85,141.41 77.06,141.19 77.06,140.81 76.85,140.6 75.04,140.6 74.8,140.36 74.8,139.95 75.02,139.73 76.59,139.73 76.71,139.62 76.71,134.14
M_A_A12: length 54.2
  TOP w0.089: 75.9,133.26 75.9,131.95 76.07,131.78 76.07,129.54 75.9,129.36 75.9,128.41 CPU1.AV22
  TOP w0.216: 75.9,133.26 75.9,135.59 73.38,138.1 73.38,144.53 73.6,144.75 74.4,144.75 74.62,144.97 74.62,145.4 74.4,145.61 73.6,145.61 73.38,145.83 73.38,146.26 73.6,146.48 74.4,146.48 74.62,146.69 74.62,147.12 74.4,147.34 73.6,147.34 73.38,147.56 73.38,147.99 73.6,148.2 74.4,148.2 74.62,148.42 74.62,148.85 74.4,149.07 73.6,149.07 73.38,149.28 73.38,149.71 73.6,149.93 74.4,149.93 74.62,150.15 74.62,150.58 74.4,150.79 73.6,150.79 73.38,151.01 73.38,151.44 73.6,151.66 74.4,151.66 74.62,151.87 74.62,152.31 74.4,152.52 73.6,152.52 73.38,152.74 73.38,153.17 73.6,153.39 74.4,153.39 74.62,153.6 74.62,154.03 74.4,154.25 73.6,154.25 73.38,154.46 73.38,154.9 73.6,155.11 74.4,155.11 74.62,155.33 74.62,155.76 74.4,155.98 73.6,155.98 73.38,156.19 73.38,164.82 74.37,165.81 74.37,167.04 DIMM1.65
M_A_A13: length 51.1
  TOP w0.089: CPU1.AV12 85.54,128.67 86.06,128.92 86.7,129.56 86.98,130.32 87.73,131.07 87.73,131.07
  TOP w0.216: 87.73,131.07 90.78,134.12 90.78,151.7 90.78,153.43 99.49,162.14 99.49,166.03 99.18,166.34 99.18,167.53 99.86,168.22 99.86,169.18 99.11,169.93 DIMM1.232
M_A_A14: length 54
  TOP w0.089: CPU1.AV14 83.7,128.89 84.21,128.89 84.61,129.3 84.61,130.95 84.87,131.2 85.56,131.2 85.75,131.39
  TOP w0.216: DIMM1.228 96.28,172.53 97.49,171.32 97.49,170.46 96.88,169.85 95.35,169.85 94.97,169.47 94.97,168.28 95.6,167.64 95.6,161.03 89.06,154.48 89.06,150.4 88.28,149.62 88.28,145.55 89.06,144.78 89.06,142 88.28,141.23 88.28,133.92 85.75,131.39
M_A_A15: length 48.5
  TOP w0.089: CPU1.AY11 86.12,130.17 86.21,130.26 86.21,130.71 86.72,131.23
  TOP w0.165: 98.06,166.14 97.57,166.63 97.57,168.57 DIMM1.86
  TOP w0.216: 98.06,166.14 98.27,165.93 98.27,165.49 98.06,165.28 97.76,165.28 97.54,165.06 97.54,164.63 97.76,164.41 98.06,164.41 98.27,164.2 98.27,163.77 98.06,163.55 97.76,163.55 97.54,163.33 97.54,162.9 98.04,162.41 98.04,162.1 97.63,161.7 96.79,161.7 96.49,161.4 96.49,160.56 89.92,153.98 89.92,148.36 89.7,148.14 89.36,148.14 89.15,147.92 89.15,147.49 89.36,147.28 89.7,147.28 89.92,147.06 89.92,140.75 89.7,140.54 89.36,140.54 89.15,140.32 89.15,139.89 89.36,139.67 89.7,139.67 89.92,139.46 89.92,138.98 89.7,138.76 89.37,138.76 89.15,138.54 89.15,133.66 86.72,131.23
M_A_A16: length 50.9
  TOP w0.089: CPU1.AW13 84.39,129.59 84.39,131 84.86,131.47 85.22,131.47 85.37,131.62
  TOP w0.216: 85.37,131.62 87.9,134.15 87.9,142.16 88.12,142.37 88.46,142.37 88.67,142.59 88.67,143.02 88.46,143.24 88.12,143.24 87.9,143.45 87.9,150.65 88.12,150.87 88.46,150.87 88.67,151.08 88.67,151.51 88.46,151.73 88.12,151.73 87.9,151.95 87.9,153.86 95.22,161.18 95.22,163.72 95,163.93 93.76,163.93 93.54,164.15 93.54,164.58 93.76,164.8 95,164.8 95.22,165.01 95.22,165.44 95,165.66 93.76,165.66 93.54,165.88 93.54,166.39 93.7,166.55 93.86,166.55 94.01,166.7 DIMM1.82
M_A_ACT#: length 54.4
  TOP w0.089: 74.35,131.52 74.35,128.5 74.36,128.49 74.36,128.19 74.35,128.17 74.35,127.77 CPU1.AU24
  TOP w0.216: 74.35,131.52 74.35,134.41 69.93,138.82 69.93,139.21 70.15,139.43 71.21,139.43 71.42,139.64 71.42,140.08 71.21,140.29 70.15,140.29 69.93,140.51 69.93,140.94 70.15,141.16 71.21,141.16 71.42,141.37 71.42,141.8 71.21,142.02 70.15,142.02 69.93,142.23 69.93,161.47 69.72,161.68 69.05,161.68 68.83,161.9 68.83,162.33 69.05,162.55 69.72,162.55 69.93,162.76 69.93,163.14 69.72,163.36 69.05,163.36 68.83,163.57 68.83,164.01 69.05,164.22 69.72,164.22 69.93,164.44 69.93,164.87 69.72,165.09 69.05,165.09 68.83,165.3 68.83,165.73 69.05,165.95 69.89,165.95 70.18,166.24 70.18,167.34 71.57,168.73 DIMM1.62
M_A_ALERT#: length 47.9
  TOP w0.089: CPU1.AT23 75.17,127.07 75.25,127.25 75.25,128.05 75.77,130.01 75.77,131.65 75.51,131.9
  TOP w0.102: 75.51,131.9 75.51,135.23 72.97,137.77 72.97,165.2 73.8,166.02 73.8,167.4 73.81,167.41 73.81,167.5 74.29,168.45 74.29,169.16 74.06,169.92 73.61,171.17 DIMM1.208
M_A_BG0: length 53.2
  TOP w0.089: 74.74,133.71 74.74,131.79 75.28,131.25 75.28,131.17 75.28,131.17 75.28,130.82 75.28,130.82 75.28,130.01 74.91,129.64 CPU1.AW23
  TOP w0.216: DIMM1.63 72.76,166.11 72.35,165.7 70.53,165.7 70.31,165.48 70.31,165.05 70.53,164.83 71.69,164.83 71.91,164.62 71.91,164.19 71.69,163.97 70.53,163.97 70.31,163.75 70.31,163.32 70.53,163.11 71.69,163.11 71.91,162.89 71.91,162.46 71.69,162.24 71.21,162.24 70.99,162.03 70.99,161.6 71.21,161.38 71.69,161.38 71.91,161.16 71.91,153.96 71.69,153.75 70.87,153.75 70.59,153.47 70.59,146.29 70.8,146.07 71.69,146.07 71.91,145.85 71.91,145.42 71.69,145.21 70.8,145.21 70.59,144.99 70.59,144.56 70.8,144.34 71.69,144.34 71.91,144.13 71.91,143.7 71.69,143.48 70.8,143.48 70.59,143.26 70.59,142.83 70.8,142.62 71.69,142.62 71.91,142.4 71.91,137.63 74.74,134.8 74.74,133.71
M_A_BG1: length 53.5
  TOP w0.089: 75.14,133.64 75.14,131.84 75.54,131.44 75.54,129.92 75.25,129.63 75.25,129.01 74.91,128.67 CPU1.AV23
  TOP w0.216: 75.14,133.64 75.14,134.93 72.29,137.79 72.29,146.68 72.07,146.9 71.18,146.9 70.97,147.11 70.97,147.54 71.18,147.76 72.07,147.76 72.29,147.98 72.29,148.41 72.07,148.62 71.18,148.62 70.97,148.84 70.97,149.27 71.18,149.49 72.07,149.49 72.29,149.7 72.29,150.13 72.07,150.35 71.18,150.35 70.97,150.57 70.97,151 71.18,151.21 72.07,151.21 72.29,151.43 72.29,151.86 72.07,152.08 71.18,152.08 70.97,152.29 70.97,152.73 71.18,152.94 72.07,152.94 72.29,153.16 72.29,165.1 73.48,166.29 73.48,167.6 72.76,168.32 DIMM1.207
M_A_BS0: length 51.3
  TOP w0.089: CPU1.AY13 84.06,130.93 85.12,132
  TOP w0.216: 85.12,132 87.5,134.38 87.5,154.12 90.47,157.09 90.47,158.85 90.69,159.07 92.06,159.07 92.28,159.28 92.28,159.72 92.06,159.93 90.69,159.93 90.47,160.15 90.47,160.53 90.69,160.74 93.26,160.74 93.47,160.96 93.47,161.39 93.26,161.61 91.88,161.61 91.67,161.82 91.67,162.26 91.88,162.47 94.6,162.47 94.82,162.69 94.82,163.12 94.6,163.34 93.38,163.34 93.16,163.55 DIMM1.81
M_A_BS1: length 52.9
  TOP w0.089: CPU1.AV15 82.69,128.34 82.78,128.43 82.78,130.89 82.98,131.08
  TOP w0.165: 91.72,166.01 92.15,166.45 92.15,167.77 91.41,168.5 91.41,169.14 92.31,170.03 DIMM1.224
  TOP w0.216: 91.72,166.01 91.43,165.72 89.73,165.72 89.43,165.43 89.43,164.08 89.22,163.86 88.33,163.86 88.11,163.65 88.11,163.21 88.33,163 89.22,163 89.43,162.78 89.43,158.76 89.22,158.55 88.31,158.55 88.08,158.32 88.08,155.91 86.73,154.55 86.73,134.84 82.98,131.08
M_A_CKE0: length 46.1
  TOP w0.089: 73.67,134.37 74,134.04 CPU1.AY24
  TOP w0.165: 73.67,134.37 69.42,138.62 69.42,157.84 69.25,158 68.57,158 68.4,158.17 68.4,158.5 68.57,158.66 69.25,158.66 69.42,158.83 69.42,159.16 69.25,159.32 68.41,159.32 68.25,159.49 68.25,159.82 68.41,159.98 69.25,159.98 69.42,160.15 69.42,160.55 69.19,160.78 68.43,160.78 68.25,160.96 68.25,165.99 68.48,166.22 68.48,167.44 69.77,168.73 DIMM1.60
M_A_CKE1: length 47.1
  TOP w0.089: 73.48,133.9 73.74,133.64 73.74,130.41 73.68,130.35 73.68,129.98 73.71,129.95 73.71,129.93 74,129.64 CPU1.AW24
  TOP w0.165: 73.48,133.9 69.01,138.37 69.01,156.9 67.84,158.06 67.84,163.49 67.68,163.65 67.12,163.65 66.95,163.82 66.95,164.2 67.12,164.36 67.61,164.36 67.84,164.59 67.84,165.46 66.83,166.47 66.83,167.41 67.69,168.28 67.69,169.26 DIMM1.203
M_A_CLK0: length 48
  TOP w0.102: CPU1.AW18 79.57,129.25 79.72,129.4 79.72,129.6 79.55,129.77 79.33,129.77 79.09,130.01 79.09,130.46 78.81,130.74 78.81,131.11 78.87,131.22 79.16,131.51 79.72,131.51 80.39,132.17 80.49,132.17 80.51,132.19
  TOP w0.127: DIMM1.74 82.39,168.19 82.65,168.12 82.83,168.21 83.3,168.21 83.92,167.6 83.92,166.17 83.97,166.11 83.97,166.1
  TOP w0.216: 83.97,166.1 83.97,165.36 84.11,165.23 85.05,165.23 85.37,164.9 85.37,163.64 85.05,163.31 84.03,163.31 83.85,163.13 83.85,162.42 84.05,162.22 84.91,162.22 85.32,161.8 85.32,157.47 84.08,156.22 84.08,136 82.89,134.82 82.89,134.58 80.51,132.19
M_A_CLK1: length 49.3
  TOP w0.102: DIMM1.218 82.44,171.91 82.4,171.77 82.24,171.69 82.02,171.46 82.02,170.17 82.5,169.69 84.03,169.69 84.1,169.62 84.12,169.62 ; CPU1.AW17 80.08,129.57 79.82,129.84 79.82,130.62 81.32,132.13 81.32,132.23 81.34,132.25
  TOP w0.216: 81.34,132.25 84.8,135.7 84.8,155.92 86.14,157.26 86.14,168.07 84.58,169.62 84.12,169.62
M_A_CLK#0: length 48
  TOP w0.102: CPU1.AV18 79.38,128.81 79.13,129.06 79.13,129.68 78.89,129.93 78.89,130.38 78.61,130.65 78.61,131.15 78.7,131.34 79.07,131.71 79.64,131.71 80.25,132.31 80.25,132.41 80.27,132.43
  TOP w0.127: DIMM1.75 82.65,167.71 82.7,167.89 82.89,167.99 83.21,167.99 83.69,167.5 83.69,166.16 83.63,166.1
  TOP w0.216: 83.63,166.1 83.63,165.22 83.96,164.89 84.9,164.89 85.03,164.76 85.03,163.78 84.9,163.65 83.89,163.65 83.5,163.27 83.5,162.28 83.91,161.88 84.76,161.88 84.98,161.66 84.98,157.61 83.73,156.36 83.73,136.15 82.55,134.96 82.55,134.72 80.27,132.43
M_A_CLK#1: length 49.3
  TOP w0.102: 81.59,132 81.57,131.98 81.47,131.98 80.02,130.54 80.02,129.92 80.17,129.77 80.3,129.77 80.4,129.88 CPU1.AY17 ; 84.12,169.96 84.1,169.96 84.03,169.89 82.58,169.89 82.22,170.26 82.22,171.38 82.37,171.52 82.49,171.59 82.63,171.55 DIMM1.219
  TOP w0.216: 81.59,132 85.14,135.56 85.14,155.78 86.48,157.11 86.48,168.21 84.72,169.96 84.12,169.96
M_A_CS#0: length 47.9
  TOP w0.089: CPU1.AW12 85.36,129.25 85.45,129.34 85.45,130.49 85.92,130.97
  TOP w0.165: DIMM1.84 95.71,168.74 96.11,169.14 96.34,169.14 96.72,168.76 96.72,168.11 97.25,167.58 97.25,165.41 97.11,165.27 97.11,162.36 96.88,162.13 96.61,162.13 96.06,161.58 96.06,160.83 89.49,154.26 89.49,149.02 89.35,148.88 88.89,148.88 88.71,148.71 88.71,145.73 88.93,145.52 89.32,145.52 89.49,145.35 89.49,141.38 89.32,141.22 88.88,141.22 88.71,141.05 88.71,133.75 85.92,130.97
M_A_CS#1: length 49.1
  TOP w0.165: CPU1.AU11 85.89,127.72 87.54,129.37 87.54,129.61 87.37,129.78 87.37,130.01 87.6,130.25 87.83,130.25 88.01,130.07 88.24,130.07 88.47,130.31 88.47,130.54 88.25,130.76 88.25,131 88.48,131.23 88.72,131.23 88.94,131.01 89.17,131.01 89.41,131.24 89.41,131.47 89.2,131.69 89.2,131.92 89.43,132.15 89.66,132.15 89.8,132.01 90.04,132.01 91.22,133.19 91.22,151.88 91.21,151.88 91.21,153.25 99.96,162 99.96,165.37 100.13,165.53 100.82,165.53 100.94,165.65 100.94,166.15 DIMM1.89
M_A_DQ0: length 89
  TOP w0.089: CPU1.AE40 57.92,116.45 57.68,116.21
  TOP w0.165: DIMM1.5 23.46,160.13 23.63,159.97 24.47,159.97 24.64,159.8 24.64,159.47 24.47,159.3 23.63,159.3 23.46,159.14 23.46,158.81 23.63,158.64 24.51,158.64 24.67,158.48 24.67,158.15 24.51,157.98 23.63,157.98 23.46,157.82 23.46,157.49 23.63,157.32 24.51,157.32 24.67,157.16 24.67,156.83 24.51,156.66 23.63,156.66 23.46,156.5 23.46,156.17 23.63,156 24.51,156 24.67,155.84 24.67,155.51 24.51,155.34 23.63,155.34 23.46,155.18 23.46,154.85 23.63,154.68 24.51,154.68 24.67,154.52 24.67,154.19 24.51,154.02 23.63,154.02 23.46,153.86 23.46,153.53 23.63,153.36 24.51,153.36 24.67,153.2 24.67,152.87 24.51,152.7 23.76,152.7 23.6,152.54 23.6,152.21 23.76,152.04 24.51,152.04 24.67,151.88 24.67,145.81 36.8,133.68 36.8,123.83 46.85,113.77 47.38,113.77 55.24,113.77 57.68,116.21
M_A_DQ1: length 92.5
  TOP w0.089: 57.5,116.69 59.06,116.69 59.15,116.79 59.73,116.79 59.94,117.01 61.56,117.01 CPU1.AE37
  TOP w0.165: 57.5,116.69 55.22,114.41 47.11,114.41 37.43,124.09 37.43,133.95 25.5,145.88 25.5,145.97 25.31,146.16 25.31,160.73 25.14,160.89 24.42,160.89 24.26,161.06 24.26,161.39 24.42,161.55 25.14,161.55 25.31,161.72 25.31,162.05 25.14,162.21 24.26,162.21 24.1,162.38 24.1,162.71 24.26,162.87 25.14,162.87 25.31,163.04 25.31,163.37 25.14,163.53 24.26,163.53 24.1,163.7 24.1,164.03 24.26,164.19 25.14,164.19 25.31,164.36 25.31,164.69 25.14,164.85 24.57,164.85 24.41,165.02 24.41,165.35 24.57,165.51 24.97,165.51 25.2,165.74 25.2,166.03 24.98,166.25 24.55,166.25 24.33,166.47 24.33,167.44 23.44,168.33 23.44,169.65 22.77,170.32 22.77,171.21 24.08,172.53 DIMM1.150
M_A_DQ2: length 90.7
  TOP w0.089: 56.59,118.52 58.84,118.52 59,118.56 59.12,118.6 59.14,118.6 59.16,118.6 60.48,118.6 CPU1.AG38
  TOP w0.165: DIMM1.12 29.25,168.57 29.25,164.98 29.04,164.77 28.28,164.77 28.12,164.61 28.12,164.28 28.28,164.11 29.11,164.11 29.28,163.95 29.28,163.62 29.11,163.45 28.28,163.45 28.12,163.29 28.12,162.96 28.28,162.79 29.11,162.79 29.28,162.63 29.28,162.3 29.11,162.13 28.28,162.13 28.12,161.97 28.12,161.64 28.28,161.47 29.11,161.47 29.28,161.31 29.28,160.98 29.11,160.81 28.28,160.81 28.12,160.65 28.12,160.32 28.28,160.15 29.11,160.15 29.28,159.99 29.28,159.66 29.11,159.49 28.28,159.49 28.12,159.33 28.12,159 28.28,158.83 29.11,158.83 29.28,158.67 29.28,158.34 29.11,158.17 28.28,158.17 28.12,158.01 28.12,157.67 28.28,157.51 29.11,157.51 29.28,157.34 29.28,157.01 29.11,156.85 28.28,156.85 28.12,156.68 28.12,156.35 28.28,156.19 29.11,156.19 29.28,156.02 29.28,155.69 29.11,155.53 28.66,155.53 28.5,155.36 28.5,155.03 28.66,154.87 29.11,154.87 29.28,154.7 29.28,151.52 29.44,151.35 30.09,151.35 30.25,151.19 30.25,150.88 30.06,150.69 29.44,150.69 29.28,150.53 29.28,150.2 29.44,150.03 30.09,150.03 30.25,149.87 30.25,149.53 30.09,149.37 29.44,149.37 29.28,149.2 29.28,148.03 40.32,136.99 40.32,125.17 48.18,117.32 54.94,117.32 56.14,118.52 56.59,118.52
M_A_DQ3: length 91.6
  TOP w0.089: 58.01,118.87 58.32,118.87 58.43,118.77 59.02,118.77 59.07,118.78 59.09,118.79 59.14,118.8 61.04,118.8 CPU1.AG37
  TOP w0.165: 58.01,118.87 55.78,118.87 54.86,117.95 48.44,117.95 40.96,125.44 40.96,137.25 30.96,147.24 30.96,151.9 30.8,152.07 30.47,152.07 30.3,152.23 30.3,152.56 30.47,152.73 30.8,152.73 30.96,152.89 30.96,153.22 30.8,153.39 30.08,153.39 29.91,153.55 29.91,153.88 30.08,154.05 30.8,154.05 30.96,154.21 30.96,154.54 30.8,154.71 30.08,154.71 29.91,154.87 29.91,155.2 30.08,155.37 30.8,155.37 30.96,155.53 30.96,155.86 30.8,156.03 30.08,156.03 29.91,156.19 29.91,156.52 30.08,156.69 30.8,156.69 30.96,156.85 30.96,157.18 30.8,157.35 30.08,157.35 29.91,157.51 29.91,157.84 30.08,158.01 30.8,158.01 30.96,158.17 30.96,158.51 30.8,158.67 30.08,158.67 29.91,158.84 29.91,159.17 30.08,159.33 30.8,159.33 30.96,159.5 30.96,159.83 30.8,159.99 30.08,159.99 29.91,160.16 29.91,160.49 30.08,160.65 30.8,160.65 30.96,160.82 30.96,161.15 30.8,161.31 30.08,161.31 29.91,161.48 29.91,161.81 30.08,161.97 30.8,161.97 30.96,162.14 30.96,162.47 30.8,162.63 30.08,162.63 29.91,162.8 29.91,163.13 30.08,163.29 30.8,163.29 30.96,163.46 30.96,163.79 30.8,163.95 30.08,163.95 29.91,164.12 29.91,164.45 30.08,164.61 30.8,164.61 30.96,164.78 30.96,165.41 29.57,166.81 29.57,167.57 30.26,168.26 DIMM1.157
M_A_DQ4: length 89.9
  TOP w0.089: CPU1.AE39 60.28,116.29 59.93,115.94 58.87,115.94 58.85,115.95 58.45,115.95 58.03,115.53
  TOP w0.165: 58.03,115.53 55,112.5 47.9,112.5 46.33,112.5 35.53,123.3 35.53,133.16 21.76,146.93 21.76,161.76 21.6,161.93 20.18,161.93 20.02,162.09 20.02,162.42 20.18,162.59 21.6,162.59 21.76,162.75 21.76,163.08 21.6,163.25 20.15,163.25 19.99,163.41 19.99,163.75 20.15,163.91 21.6,163.91 21.76,164.08 21.76,164.41 21.6,164.57 20.15,164.57 19.99,164.74 19.99,165.07 20.15,165.23 21.6,165.23 21.76,165.4 DIMM1.3
M_A_DQ5: length 91.5
  TOP w0.089: 57.68,115.73 58.16,116.2 59.11,116.2 59.18,116.13 59.55,116.13 59.78,116.35 59.78,116.45 60.1,116.78 60.87,116.78 CPU1.AE38
  TOP w0.165: DIMM1.148 22.45,172.37 22.45,170.23 21.87,169.65 21.87,168.27 22.63,167.51 22.63,166.38 22.75,166.27 22.75,151.09 22.91,150.93 23.87,150.93 24.04,150.76 24.04,150.43 23.87,150.27 22.91,150.27 22.75,150.1 22.75,149.77 22.91,149.61 23.87,149.61 24.04,149.44 24.04,148.81 23.87,148.64 22.77,148.64 22.61,148.48 22.61,148.15 22.77,147.98 23.87,147.98 24.04,147.82 24.04,145.55 36.16,133.42 36.16,123.56 46.59,113.14 47.64,113.14 55.09,113.14 57.68,115.73
M_A_DQ6: length 89.4
  TOP w0.089: 57.15,117.81 57.33,117.98 59.16,117.98 59.18,117.96 59.57,117.96 59.9,118.28 CPU1.AG39
  TOP w0.165: DIMM1.10 27.55,168.57 27.55,166.62 26.85,165.91 26.85,165.13 26.85,147.12 27.67,146.29 27.9,146.29 28.41,146.8 28.64,146.8 28.87,146.56 28.87,146.31 28.41,145.84 28.41,145.61 28.64,145.37 28.88,145.37 29.3,145.8 29.54,145.8 29.77,145.57 29.77,145.33 29.28,144.84 29.28,144.61 29.51,144.38 29.75,144.38 30.3,144.93 30.56,144.93 30.79,144.7 30.79,144.46 30.25,143.92 30.25,143.68 30.47,143.46 30.75,143.46 31.26,143.97 31.49,143.97 31.71,143.75 31.71,143.52 31.18,142.98 31.18,142.75 31.4,142.53 31.66,142.53 32.19,143.06 32.43,143.06 32.66,142.83 32.66,142.59 32.12,142.05 32.12,141.81 32.34,141.59 32.57,141.59 33.13,142.15 33.36,142.15 33.59,141.92 33.59,141.68 33.04,141.13 33.04,140.89 33.27,140.66 33.5,140.66 34.06,141.22 34.29,141.22 34.53,140.98 34.53,140.75 33.97,140.19 33.97,139.96 34.2,139.73 34.44,139.73 35,140.28 35.23,140.28 35.46,140.05 35.46,139.81 34.91,139.26 34.91,139.02 39.05,134.88 39.05,124.65 47.65,116.05 48.18,116.05 55.39,116.05 57.15,117.81
M_A_DQ7: length 88.4
  TOP w0.089: CPU1.AG40 59.33,118.24 56.85,118.24 56.68,118.07
  TOP w0.165: 56.68,118.07 55.29,116.68 47.91,116.68 39.69,124.91 39.69,136.72 39.24,137.17 39,137.17 38.44,136.62 38.21,136.62 37.98,136.85 37.98,137.08 38.54,137.64 38.54,137.87 38.3,138.11 38.07,138.11 37.51,137.55 37.28,137.55 37.04,137.78 37.04,138.02 37.6,138.58 37.6,138.81 37.37,139.04 37.13,139.04 36.58,138.48 36.34,138.48 36.11,138.72 36.11,138.95 36.67,139.51 36.67,139.74 28.63,147.78 28.63,148.32 28.46,148.49 27.7,148.49 27.56,148.63 27.56,149.16 27.72,149.32 28.46,149.32 28.63,149.49 28.63,149.82 28.46,149.98 27.7,149.98 27.53,150.15 27.53,150.45 27.7,150.62 28.44,150.62 28.6,150.78 28.6,151.11 28.44,151.28 27.72,151.28 27.56,151.44 27.56,151.77 27.72,151.94 28.46,151.94 28.63,152.1 28.63,152.43 28.46,152.6 27.67,152.6 27.48,152.79 27.48,153.12 27.67,153.31 28.44,153.31 28.61,153.48 28.61,153.8 28.45,153.97 27.65,153.97 27.48,154.13 27.48,165.4 27.87,165.78 27.87,167.41 28.56,168.11 DIMM1.155
M_A_DQ8: length 76.9
  TOP w0.089: CPU1.AJ40 54.88,120.11
  TOP w0.165: DIMM1.16 32.97,168.57 32.97,166.68 32.94,166.65 32.94,163.26 32.99,163.21 32.99,161.31 33.16,161.14 34.49,161.14 34.66,160.98 34.66,160.65 34.49,160.48 33.11,160.48 32.94,160.32 32.94,159.99 33.11,159.82 34.49,159.82 34.66,159.66 34.66,159.33 34.49,159.16 33.11,159.16 32.94,159 32.94,158.67 33.11,158.5 34.49,158.5 34.66,158.34 34.66,158.01 34.49,157.84 33.11,157.84 32.94,157.68 32.94,157.35 33.11,157.18 34.49,157.18 34.66,157.02 34.66,156.69 34.49,156.52 34.1,156.52 33.93,156.36 33.93,156.03 34.1,155.86 34.49,155.86 34.66,155.7 34.66,146.33 42.98,138.01 42.98,126.11 49.23,119.86 54.63,119.86 54.88,120.11
M_A_DQ9: length 80.1
  TOP w0.089: CPU1.AJ37 61.6,120.62 60.02,120.62 59.83,120.43 58.98,120.43 58.96,120.41 58.18,120.41 58.06,120.53 57.91,120.53
  TOP w0.165: DIMM1.161 33.66,168.31 34.56,167.41 34.56,166.4 34.72,166.24 35.17,166.24 35.33,166.08 35.33,165.5 35.17,165.34 33.74,165.34 33.58,165.17 33.58,164.84 33.74,164.68 35.31,164.68 35.48,164.51 35.48,164.18 35.31,164.02 33.74,164.02 33.58,163.85 33.58,163.52 33.74,163.36 35.31,163.36 35.48,163.19 35.48,162.86 35.31,162.7 33.82,162.7 33.65,162.53 33.65,162.2 33.82,162.03 35.13,162.03 35.43,161.73 35.43,153.58 35.29,153.44 35.29,146.59 43.72,138.16 43.72,126.79 43.72,126.79 43.72,126.26 49.46,120.52 57.91,120.52 57.91,120.53
M_A_DQ10: length 78.2
  TOP w0.089: CPU1.AL38 60.49,122.26 60.49,122.26 59.18,122.26 59.1,122.17 58.34,122.17 58.04,122.48 56.72,122.48 56.59,122.61
  TOP w0.165: DIMM1.23 38.76,162.91 41.98,159.69 42.21,159.69 42.84,160.31 43.08,160.31 43.31,160.08 43.31,159.85 42.68,159.22 42.68,158.98 42.92,158.75 43.15,158.75 43.78,159.38 44.01,159.38 44.24,159.14 44.24,158.91 43.62,158.28 43.62,158.05 43.85,157.82 44.08,157.82 44.71,158.44 44.94,158.44 45.18,158.21 45.18,157.98 44.55,157.35 44.55,157.12 44.78,156.88 45.02,156.88 45.64,157.51 45.88,157.51 46.11,157.28 46.11,157.04 45.48,156.42 45.48,156.18 45.72,155.95 45.95,155.95 46.58,156.58 46.81,156.58 47.05,156.34 47.05,156.11 46.42,155.48 46.42,155.25 47.8,153.86 47.8,139.82 47.64,139.66 46.69,139.66 46.53,139.49 46.53,139.16 46.69,139 47.64,139 47.8,138.83 47.8,138.5 47.64,138.34 46.69,138.34 46.53,138.17 46.53,137.84 46.69,137.68 47.64,137.68 47.8,137.51 47.8,137.18 47.64,137.02 46.69,137.02 46.53,136.85 46.53,136.52 46.69,136.36 47.64,136.36 47.8,136.19 47.8,135.65 47.64,135.48 46.69,135.48 46.53,135.32 46.53,127.43 50.41,123.55 50.93,123.55 55.65,123.55 56.59,122.61
M_A_DQ11: length 79.2
  TOP w0.089: CPU1.AL37 61.05,122.45 60.98,122.48 58.93,122.48 58.88,122.43 58.5,122.43 58.04,122.89 57.78,122.89
  TOP w0.165: DIMM1.168 39.61,170.6 38.89,169.89 38.89,168.43 39.54,167.78 39.54,164.75 40.37,163.91 40.37,163.68 39.74,163.05 39.74,162.82 39.97,162.6 40.22,162.6 40.84,163.21 41.07,163.21 41.31,162.98 41.31,162.75 40.68,162.12 40.68,161.89 40.9,161.67 41.16,161.67 41.77,162.28 42.01,162.28 42.24,162.05 42.24,161.81 41.61,161.19 41.61,160.95 41.83,160.73 42.09,160.73 42.71,161.35 42.94,161.35 48.44,155.85 48.44,154.88 48.6,154.72 49.21,154.72 49.38,154.55 49.38,154.22 49.21,154.06 48.62,154.06 48.44,153.87 48.44,153.54 48.63,153.35 49.67,153.35 49.82,153.2 49.82,152.84 49.67,152.69 48.65,152.69 48.46,152.5 48.46,152.19 48.63,152.03 49.67,152.03 49.82,151.88 49.82,151.52 49.67,151.37 48.6,151.37 48.44,151.2 48.44,135.29 47.16,134.02 47.16,127.69 50.67,124.18 55.57,124.18 56.87,122.89 57.78,122.89
M_A_DQ12: length 78
  TOP w0.089: CPU1.AJ39 60.28,119.95 59.93,119.6 59.11,119.6 59.08,119.62 58.43,119.62 58.06,119.25 57.61,119.25
  TOP w0.165: 57.61,119.25 55.4,119.25 54.73,118.59 48.7,118.59 41.71,125.58 41.71,137.48 31.67,147.52 31.67,148.17 31.84,148.33 33.11,148.33 33.27,148.5 33.27,148.83 33.11,148.99 31.84,148.99 31.67,149.16 31.67,149.49 31.84,149.65 33.06,149.65 33.22,149.82 33.22,150.15 33.06,150.31 31.84,150.31 31.67,150.48 31.67,150.81 31.84,150.97 33.06,150.97 33.22,151.14 33.22,151.47 33.06,151.63 31.84,151.63 31.67,151.8 31.67,166.04 31.11,166.6 DIMM1.14
M_A_DQ13: length 79.1
  TOP w0.089: CPU1.AJ38 60.87,120.43 60.1,120.43 59.78,120.11 59.78,120.01 59.55,119.79 59.18,119.79 59.11,119.86 58.29,119.86 58.12,119.68 57.89,119.68
  TOP w0.165: 57.89,119.68 55.24,119.68 54.78,119.22 48.97,119.22 42.34,125.85 42.34,137.75 33.71,146.38 33.71,147.75 34.01,148.06 34.01,152.27 33.85,152.43 32.47,152.43 32.31,152.6 32.31,152.93 32.47,153.09 33.85,153.09 34.01,153.26 34.01,153.59 33.85,153.75 32.47,153.75 32.31,153.92 32.31,154.28 32.45,154.42 33.85,154.42 34.01,154.58 34.01,154.91 33.85,155.08 32.47,155.08 32.31,155.24 32.31,166.46 32.65,166.81 32.65,167.55 31.96,168.24 DIMM1.159
M_A_DQ14: length 76.7
  TOP w0.089: CPU1.AL39 59.88,121.94 59.55,121.61 59.18,121.61 59.08,121.72 57.96,121.72 57.86,121.82 56.21,121.82 56.05,121.98
  TOP w0.165: DIMM1.21 37.06,155.06 37.26,154.86 38.2,154.86 38.37,155.03 38.37,156.6 38.53,156.77 38.86,156.77 39.03,156.6 39.03,155.03 39.19,154.86 39.52,154.86 39.69,155.03 39.69,156.68 39.85,156.84 40.18,156.84 40.35,156.68 40.35,155.03 40.51,154.86 40.84,154.86 41.01,155.03 41.01,156.68 41.17,156.84 41.5,156.84 41.67,156.68 41.67,155.03 41.83,154.86 44.22,154.86 46.53,152.55 46.53,147.01 45.26,145.74 45.26,126.9 49.88,122.28 50.41,122.28 50.41,122.28 50.93,122.28 50.94,122.28 55.75,122.28 56.05,121.98
M_A_DQ15: length 75.6
  TOP w0.089: CPU1.AL40 58.2,121.94 57.99,122.15 56.44,122.15 56.39,122.2
  TOP w0.165: 56.39,122.2 55.68,122.91 51.2,122.91 50.67,122.91 50.67,122.91 50.15,122.91 45.89,127.16 45.89,140.19 46.06,140.36 46.98,140.36 47.14,140.52 47.14,140.86 46.98,141.02 46.03,141.02 45.89,141.16 45.89,141.54 46.03,141.68 46.98,141.68 47.14,141.85 47.14,142.18 46.98,142.34 46.03,142.34 45.89,142.48 45.89,142.86 46.03,143 46.98,143 47.14,143.17 47.14,143.5 46.98,143.66 46.06,143.66 45.89,143.83 45.89,144.17 46.07,144.35 47,144.35 47.17,144.51 47.17,153.6 39.29,161.48 39.06,161.48 38.46,160.88 38.19,160.88 38.02,161.05 38.02,161.38 38.59,161.95 38.59,162.18 37.91,162.85 37.91,167.68 37.76,167.83 37.43,167.83 36.97,168.29 36.97,169.76 37.1,169.89 37.78,169.89 37.91,170.02 DIMM1.166
M_A_DQ16: length 64.9
  TOP w0.089: CPU1.AN40 57.79,123.77 57.3,124.26
  TOP w0.165: 57.3,124.26 55.45,126.11 51.44,126.11 49.07,128.48 49.07,132.64 50.44,134.02 50.44,137.71 50.61,137.88 51.56,137.88 51.73,138.04 51.73,138.37 51.56,138.54 50.61,138.54 50.44,138.7 50.44,139.03 50.61,139.2 51.56,139.2 51.73,139.36 51.73,139.69 51.56,139.86 50.61,139.86 50.44,140.02 50.44,140.35 50.61,140.52 51.56,140.52 51.73,140.68 51.73,141.01 51.56,141.18 50.61,141.18 50.44,141.35 50.44,141.68 50.61,141.84 51.56,141.84 51.73,142.01 51.73,142.34 51.56,142.5 50.79,142.5 50.62,142.67 50.62,143 50.79,143.16 51.56,143.16 51.73,143.33 51.73,155.44 42.89,164.27 42.89,165.87 42.16,166.6 DIMM1.27
M_A_DQ17: length 67.6
  TOP w0.089: CPU1.AN37 61.6,124.28 60.02,124.28 59.83,124.09 59.17,124.09 59.14,124.07 58.13,124.07 57.6,124.6
  TOP w0.165: 57.6,124.6 55.99,126.2 55.99,131.58 53.92,133.65 51.3,133.65 51.14,133.82 51.14,134.15 51.3,134.32 52.26,134.32 52.43,134.48 52.43,134.79 52.24,134.98 51.3,134.98 51.14,135.14 51.14,135.47 51.3,135.64 52.23,135.64 52.36,135.77 52.36,136.16 52.23,136.3 51.42,136.3 51.26,136.46 51.26,136.79 51.42,136.96 52.2,136.96 52.36,137.12 52.36,155.7 43.53,164.53 43.53,166.13 43.02,166.64 43.02,167.28 42.16,168.14 42.16,168.99 41.47,169.68 41.47,171.41 42.58,172.53 DIMM1.172
M_A_DQ18: length 65.5
  TOP w0.089: CPU1.AR38 60.46,125.93 59.97,125.93 59.82,126.09 58.89,126.09 58.53,126.09 58.53,126.09 58.5,126.09 58.28,126.3 58.28,127.18
  TOP w0.165: 58.28,127.18 58.28,134.23 56.59,135.92 56.59,140.67 56.43,140.84 56.15,140.84 55.98,141 55.98,141.33 56.15,141.5 56.43,141.5 56.59,141.66 56.59,141.99 56.43,142.16 55.51,142.16 55.35,142.32 55.35,142.65 55.51,142.82 56.43,142.82 56.59,142.98 56.59,143.31 56.43,143.48 55.36,143.48 55.19,143.64 55.19,143.97 55.36,144.14 56.43,144.14 56.59,144.3 56.59,144.63 56.43,144.8 55.36,144.8 55.19,144.96 55.19,145.29 55.36,145.46 56.43,145.46 56.59,145.62 56.59,145.96 56.43,146.12 55.36,146.12 55.19,146.29 55.19,146.62 55.36,146.78 56.43,146.78 56.59,146.95 56.59,147.28 56.43,147.44 55.36,147.44 55.19,147.61 55.19,147.94 55.36,148.1 56.43,148.1 56.59,148.27 56.59,148.6 56.43,148.76 55.36,148.76 55.19,148.93 55.19,149.26 55.36,149.42 56.43,149.42 56.59,149.59 56.59,149.92 56.43,150.08 55.36,150.08 55.19,150.25 55.19,160.11 48.89,166.41 48.66,166.41 48.27,166.81 48.27,168.57 DIMM1.34
M_A_DQ19: length 66.6
  TOP w0.089: CPU1.AR37 60.9,126.17 60.11,126.17 59.78,126.51 59.78,127.66 58.98,128.46
  TOP w0.165: DIMM1.179 48.96,168.29 49.65,167.59 49.65,166.55 55.83,160.37 55.83,159.07 55.99,158.9 57.06,158.9 57.23,158.74 57.23,158.34 57.06,158.18 55.99,158.18 55.83,158.01 55.83,157.68 55.99,157.52 57.06,157.52 57.23,157.35 57.23,157.02 57.06,156.86 55.99,156.86 55.83,156.69 55.83,156.36 55.99,156.2 57.06,156.2 57.23,156.03 57.23,155.7 57.06,155.54 55.99,155.54 55.83,155.37 55.83,155.04 55.99,154.88 57.06,154.88 57.23,154.71 57.23,154.38 57.06,154.22 55.99,154.22 55.83,154.05 55.83,153.72 55.99,153.55 57.06,153.55 57.23,153.39 57.23,153.06 57.06,152.89 55.99,152.89 55.83,152.73 55.83,152.4 55.99,152.23 57.06,152.23 57.23,152.07 57.23,151.74 57.06,151.57 55.99,151.57 55.83,151.41 55.83,151.08 55.99,150.91 57.06,150.91 57.23,150.75 57.23,136.73 58.75,135.21 58.75,128.69 58.98,128.46
M_A_DQ20: length 65.7
  TOP w0.089: 56.85,123.53 57.1,123.28 58.88,123.28 58.97,123.19 59.81,123.19 60.28,123.67 CPU1.AN39
  TOP w0.165: 56.85,123.53 55.55,124.83 50.93,124.83 47.8,127.95 47.8,133.17 49.15,134.52 49.15,146.5 49.31,146.66 50.27,146.66 50.43,146.83 50.43,147.16 50.27,147.32 49.31,147.32 49.15,147.49 49.15,147.82 49.31,147.98 50.29,147.98 50.46,148.15 50.46,148.48 50.29,148.64 49.42,148.64 49.25,148.81 49.25,149.14 49.42,149.3 50.29,149.3 50.46,149.47 50.46,149.8 50.29,149.96 49.54,149.96 49.38,150.13 49.38,150.46 49.54,150.62 50.29,150.62 50.46,150.79 50.46,154.91 40.46,164.91 DIMM1.25
M_A_DQ21: length 67.1
  TOP w0.089: CPU1.AN38 60.87,124.09 60.1,124.09 59.78,123.77 59.78,123.66 59.55,123.44 59.13,123.44 59.06,123.52 57.43,123.52 57.03,123.92
  TOP w0.165: DIMM1.170 41.15,172.37 41.15,170.33 40.59,169.77 40.59,168.43 41.34,167.68 41.34,166.09 42.26,165.17 42.26,164.01 51.09,155.18 51.09,145.77 50.93,145.6 50.41,145.6 50.24,145.44 50.24,145.13 50.43,144.94 50.93,144.94 51.09,144.78 51.09,144.45 50.93,144.28 49.95,144.28 49.78,144.12 49.78,134.26 48.43,132.91 48.43,128.22 51.17,125.48 55.47,125.48 57.03,123.92
M_A_DQ22: length 64.3
  TOP w0.089: 57.26,127 57.26,126.48 58.24,125.5 58.95,125.5 59.18,125.27 59.55,125.27 59.88,125.6 CPU1.AR39
  TOP w0.165: DIMM1.32 46.41,166.27 46.25,166.1 45.66,166.1 45.5,165.94 45.5,165.61 45.66,165.44 45.97,165.44 46.13,165.28 46.13,164.24 48.01,162.35 48.25,162.35 49.49,163.59 49.74,163.59 49.98,163.36 49.98,163.15 48.71,161.89 48.71,161.65 48.95,161.42 49.18,161.42 50.13,162.36 50.36,162.36 50.59,162.13 50.59,161.9 49.65,160.95 49.65,160.72 49.88,160.49 50.12,160.49 51.06,161.43 51.29,161.43 51.53,161.2 51.53,160.96 50.58,160.02 50.58,159.78 50.82,159.55 51.05,159.55 51.98,160.48 52.22,160.48 52.45,160.25 52.45,160.02 51.52,159.08 51.52,158.85 53.9,156.47 53.9,136.7 57.26,133.34 57.26,127
M_A_DQ23: length 63.1
  TOP w0.089: CPU1.AR40 59.16,125.81 58.39,125.81 57.77,126.43 57.77,127.38
  TOP w0.165: DIMM1.177 47.26,168.28 47.95,167.59 47.95,166 46.97,165.01 46.97,164.74 47.18,164.53 47.42,164.53 48.53,165.64 48.77,165.64 49,165.41 49,165.17 47.8,163.97 47.8,163.74 48.03,163.5 48.26,163.5 49.47,164.71 49.7,164.71 54.53,159.87 54.53,140.24 54.7,140.07 55.77,140.07 55.93,139.91 55.93,139.58 55.77,139.41 54.7,139.41 54.53,139.25 54.53,138.92 54.7,138.75 55.74,138.75 55.91,138.59 55.91,138.26 55.74,138.09 54.7,138.09 54.53,137.93 54.53,137.38 54.7,137.21 55.68,137.21 55.86,137.03 55.86,135.71 57.77,133.8 57.77,127.38
M_A_DQ24: length 56.8
  TOP w0.089: 60.92,131.27 60.92,130.8 61.67,130.05 61.67,128.78 CPU1.AV37
  TOP w0.165: 60.92,131.27 60.92,147.5 60.76,147.66 59.55,147.66 59.39,147.83 59.39,148.16 59.55,148.32 60.76,148.32 60.92,148.49 60.92,148.82 60.76,148.98 59.47,148.98 59.31,149.15 59.31,149.48 59.47,149.64 60.76,149.64 60.92,149.81 60.92,150.14 60.76,150.3 59.47,150.3 59.31,150.47 59.31,150.8 59.47,150.96 60.76,150.96 60.92,151.13 60.92,151.46 60.76,151.62 59.47,151.62 59.31,151.79 59.31,152.12 59.47,152.28 60.69,152.28 60.86,152.45 60.86,152.78 60.69,152.94 59.47,152.94 59.31,153.11 59.31,159.59 52.49,166.41 52.1,166.41 51.67,166.84 51.67,168.57 DIMM1.38
M_A_DQ25: length 55.8
  TOP w0.089: CPU1.AW37 62.11,130.42 61.56,130.98 61.56,131.5
  TOP w0.165: 61.56,131.5 61.56,153.8 61.39,153.96 60.11,153.96 59.94,154.13 59.94,154.46 60.11,154.62 61.43,154.62 61.59,154.79 61.59,155.12 61.43,155.28 60.11,155.28 59.94,155.45 59.94,155.78 60.11,155.94 61.49,155.94 61.66,156.11 61.66,156.44 61.49,156.6 60.11,156.6 59.94,156.77 59.94,157.1 60.11,157.26 61.49,157.26 61.66,157.43 61.66,157.9 61.49,158.06 60.2,158.06 60.04,158.23 60.04,158.53 60.23,158.72 60.29,158.72 60.45,158.89 60.45,159.34 53.26,166.54 53.26,167.43 52.36,168.32 DIMM1.183
M_A_DQ26: length 58.3
  TOP w0.089: CPU1.AU35 63.62,127.75 63.62,128.52 63.94,128.85 64.04,128.85 64.27,129.07 64.27,129.46 64.13,129.59 64.13,130.68 64.39,130.94
  TOP w0.165: 64.39,130.94 66.29,132.84 66.29,146.17 64.78,147.69 64.78,165.06 64.61,165.23 64.25,165.23 64.09,165.06 64.09,163.31 63.9,163.12 63.59,163.12 63.43,163.28 63.43,165.06 63.26,165.23 62.93,165.23 62.77,165.06 62.77,163.31 62.58,163.12 62.27,163.12 62.11,163.28 62.11,165.06 61.94,165.23 61.61,165.23 61.45,165.06 61.45,163.87 61.28,163.7 60.98,163.7 60.79,163.89 60.79,165.06 60.6,165.25 59.12,165.25 57.46,166.91 DIMM1.45
M_A_DQ27: length 57.4
  TOP w0.089: CPU1.AV35 64.1,128.34 64.46,128.7 64.46,129.54 64.32,129.67 64.32,130.27 65.15,131.11
  TOP w0.165: 65.15,131.11 66.98,132.93 66.98,147.24 66.81,147.41 65.95,147.41 65.79,147.57 65.79,147.9 65.95,148.07 66.94,148.07 67.11,148.23 67.11,148.54 66.92,148.73 65.95,148.73 65.79,148.89 65.79,149.22 65.95,149.39 66.71,149.39 66.88,149.56 66.88,149.99 65.41,151.45 65.41,165.72 65.25,165.89 59.39,165.89 58.34,166.94 58.34,167.65 57.59,168.4 57.59,169.53 58.31,170.25 DIMM1.190
M_A_DQ28: length 57.2
  TOP w0.089: 61.19,127.42 60.73,127.88 60.73,128.7 59.63,129.81 59.63,131.27
  TOP w0.102: CPU1.AU38 61.19,127.42
  TOP w0.165: 59.63,131.27 59.63,136.12 59.46,136.28 58.86,136.28 58.7,136.45 58.7,136.78 58.86,136.94 59.46,136.94 59.63,137.11 59.63,137.74 59.46,137.91 58.18,137.91 58.01,138.07 58.01,138.48 58.18,138.64 59.5,138.64 59.65,138.8 59.65,139.15 59.5,139.31 58.18,139.31 58.01,139.47 58.01,139.8 58.18,139.97 59.5,139.97 59.65,140.12 59.65,140.47 59.5,140.63 58.18,140.63 58.01,140.79 58.01,141.12 58.18,141.29 59.5,141.29 59.65,141.44 59.65,141.8 59.5,141.95 58.18,141.95 58.01,142.11 58.01,159.09 50.87,166.23 50.48,166.23 49.97,166.74 49.97,168.57 DIMM1.36
M_A_DQ29: length 57.9
  TOP w0.089: 60.29,131.05 60.29,130.69 60.1,130.51 60.1,129.75 61.03,128.82 61.28,128.82 61.67,128.43 61.67,128.21 62.11,127.77 CPU1.AU37
  TOP w0.165: 60.29,131.05 60.29,142.58 60.12,142.75 58.79,142.75 58.65,142.89 58.65,143.27 58.79,143.41 60.12,143.41 60.29,143.57 60.29,143.9 60.12,144.07 58.84,144.07 58.67,144.23 58.67,144.56 58.84,144.73 60.12,144.73 60.29,144.89 60.29,145.22 60.12,145.39 58.84,145.39 58.67,145.55 58.67,145.88 58.84,146.05 60.12,146.05 60.29,146.21 60.29,146.54 60.12,146.71 58.84,146.71 58.67,146.87 58.67,159.33 51.35,166.65 51.35,167.52 50.66,168.21 DIMM1.181
M_A_DQ30: length 59.5
  TOP w0.089: 63.4,130.91 63.4,130.63 63.54,130.49 63.54,130.17 63.54,128.97 63.43,128.85 63.43,127.02 CPU1.AT35
  TOP w0.165: DIMM1.43 55.76,166.35 63.51,158.61 63.51,142.38 63.67,142.22 64.81,142.22 64.97,142.05 64.97,141.72 64.81,141.56 63.67,141.56 63.5,141.39 63.5,141.07 63.67,140.9 64.81,140.9 64.97,140.73 64.97,140.4 64.81,140.24 63.67,140.24 63.51,140.07 63.51,139.74 63.67,139.58 64.81,139.58 64.97,139.41 64.97,139.08 64.81,138.92 63.67,138.92 63.51,138.75 63.51,138.42 63.67,138.26 64.81,138.26 64.97,138.09 64.97,137.76 64.81,137.6 63.67,137.6 63.51,137.43 63.51,137.1 63.67,136.94 64.81,136.94 64.97,136.77 64.97,136.44 64.81,136.28 63.67,136.28 63.51,136.11 63.51,135.78 63.67,135.62 64.81,135.62 64.97,135.45 64.97,135.12 64.81,134.95 63.67,134.95 63.4,134.69 63.4,130.91
M_A_DQ31: length 56.2
  TOP w0.089: 64.1,131.53 63.94,131.37 63.94,129.51 63.94,129.51 CPU1.AW35
  TOP w0.165: DIMM1.188 56.61,170.5 55.89,169.78 55.89,168.17 56.61,167.45 56.61,166.4 60.53,162.48 62,162.48 62.17,162.32 62.17,161.96 62.33,161.8 62.66,161.8 62.83,161.96 62.83,162.32 62.99,162.48 63.78,162.48 64.14,162.12 64.14,147.42 65.51,146.06 65.51,145.29 65.34,145.13 64.31,145.13 64.14,144.96 64.14,144.63 64.31,144.47 65.47,144.47 65.64,144.3 65.64,143.97 65.47,143.81 64.31,143.81 64.14,143.64 64.14,143.31 64.31,143.15 65.47,143.15 65.64,142.98 65.64,133.07 64.1,131.53
M_A_DQ32: length 61.3
  TOP w0.089: CPU1.AY8 90.83,129.98 92.04,131.19
  TOP w0.165: 92.04,131.19 93.4,132.55 93.4,134.13 93.53,134.26 93.53,141.71 93.87,142.06 94.46,142.06 94.74,142.35 94.74,144.25 94.55,144.44 94.17,144.44 94.01,144.6 94.01,144.93 94.17,145.1 94.58,145.1 94.75,145.26 94.75,145.65 94.58,145.81 93.69,145.81 93.53,145.98 93.53,146.31 93.69,146.47 94.58,146.47 94.75,146.64 94.75,146.97 94.58,147.13 93.69,147.13 93.53,147.3 93.53,147.63 93.69,147.79 94.58,147.79 94.75,147.96 94.75,148.29 94.58,148.45 93.69,148.45 93.53,148.62 93.53,148.95 93.69,149.11 94.58,149.11 94.75,149.28 94.75,149.61 94.58,149.77 93.69,149.77 93.53,149.94 93.53,150.58 94.2,151.25 94.2,151.48 93.75,151.93 93.75,152.17 93.98,152.4 94.21,152.4 94.83,151.78 95.04,151.78 95.34,152.08 95.34,152.31 94.67,152.98 94.67,153.21 94.9,153.45 95.13,153.45 95.81,152.78 96.04,152.78 96.27,153.01 96.27,153.24 95.66,153.85 95.66,154.09 95.9,154.32 96.13,154.32 96.74,153.71 96.97,153.71 97.21,153.94 97.21,154.18 96.73,154.66 96.73,154.89 96.96,155.13 97.19,155.13 97.67,154.64 97.91,154.64 106.43,163.16 106.43,166.79 DIMM1.97
M_A_DQ33: length 64.3
  TOP w0.089: CPU1.AU8 91.34,127.02 91.34,128.85 91.32,128.87 91.32,130.09 91.58,130.35 91.72,130.35 91.94,130.58
  TOP w0.165: 91.94,130.58 94.21,132.84 94.21,133.71 95.38,134.88 95.38,135.32 95.22,135.49 94.33,135.49 94.16,135.65 94.16,135.98 94.33,136.15 95.22,136.15 95.38,136.31 95.38,136.64 95.22,136.81 94.33,136.81 94.16,136.97 94.16,137.3 94.33,137.47 95.22,137.47 95.38,137.63 95.38,137.96 95.22,138.13 94.33,138.13 94.16,138.29 94.16,138.62 94.33,138.79 95.22,138.79 95.38,138.95 95.38,139.28 95.22,139.45 94.33,139.45 94.16,139.61 94.16,139.94 94.33,140.11 95.22,140.11 95.38,140.27 95.38,140.6 95.22,140.77 94.55,140.77 94.39,140.93 94.39,141.21 94.6,141.43 95.22,141.43 95.38,141.59 95.38,151.22 107.16,163 107.16,166.52 107.48,166.83 107.48,167.61 106.9,168.19 106.9,169.13 106.05,169.98 106.05,171.5 107.07,172.53 DIMM1.242
M_A_DQ34: length 61.5
  TOP w0.089: 94.88,131.11 94.11,130.34 93.4,130.34 93.15,130.09 93.15,129.74 93.17,129.71 93.17,128.87 93,128.7 93,128.17 CPU1.AV6
  TOP w0.165: 94.88,131.11 95.35,131.11 99.9,135.67 99.9,136.27 99.36,136.81 99.36,146.13 99.53,146.29 100.04,146.29 100.2,146.46 100.2,146.79 100.04,146.95 98.36,146.95 98.2,147.12 98.2,147.45 98.36,147.61 99.96,147.61 100.18,147.83 100.18,148.11 100.01,148.27 98.36,148.27 98.2,148.44 98.2,148.77 98.36,148.93 99.96,148.93 100.18,149.15 100.18,149.47 100.01,149.63 98.43,149.63 98.3,149.76 98.3,150.17 98.49,150.36 99.94,150.36 100.1,150.52 100.1,151.97 112.12,163.98 112.12,166.17 112.55,166.6 112.55,168.57 DIMM1.104
M_A_DQ35: length 62.4
  TOP w0.089: 94.45,129.81 94.03,129.39 94.03,129.2 93.66,128.83 93.55,128.83 93.21,128.49 93.21,127.06 CPU1.AU6
  TOP w0.165: DIMM1.249 113.56,168.32 112.87,167.63 112.87,163.84 100.84,151.81 100.84,145.66 100.67,145.49 100.19,145.49 100.03,145.33 100.03,145 100.19,144.83 100.67,144.83 100.84,144.67 100.84,144.34 100.67,144.17 100.16,144.17 100,144.01 100,143.68 100.16,143.51 100.67,143.51 100.84,143.35 100.84,143.02 100.67,142.85 100.16,142.85 100,142.69 100,142.36 100.16,142.19 100.67,142.19 100.84,142.03 100.84,141.7 100.67,141.53 100.16,141.53 100,141.37 100,141.04 100.16,140.87 100.67,140.87 100.84,140.71 100.84,140.37 100.67,140.21 100.16,140.21 100,140.04 100,139.71 100.16,139.55 100.67,139.55 100.84,139.38 100.84,139.05 100.67,138.89 100.16,138.89 100,138.72 100,138.39 100.16,138.23 100.67,138.23 100.84,138.06 100.84,137.73 100.67,137.57 100.16,137.57 100,137.4 100,137.07 100.16,136.91 100.67,136.91 100.84,136.74 100.84,135.69 95.91,130.76 95.4,130.76 94.45,129.81
M_A_DQ36: length 62.4
  TOP w0.089: CPU1.AW8 90.42,128.34 90.26,128.5 90.26,130.47 91.25,131.46
  TOP w0.165: DIMM1.95 105.06,166.58 104.9,166.41 103.32,166.41 103.12,166.22 103.12,165.82 103.29,165.66 104.97,165.66 105.13,165.49 105.13,165.16 104.97,165 103.19,165 103.02,164.83 103.02,164.5 103.19,164.34 104.91,164.34 105.13,164.12 105.13,163.84 104.97,163.68 103.19,163.68 103.02,163.51 103.02,163.21 103.21,163.02 103.78,163.02 103.94,162.86 103.94,162.48 101.87,160.42 101.64,160.42 100.9,161.15 100.67,161.15 100.4,160.88 100.4,160.66 101.1,159.96 101.1,159.73 100.87,159.49 100.64,159.49 99.95,160.18 99.73,160.18 99.48,159.94 99.48,159.71 100.17,159.03 100.17,158.79 99.94,158.56 99.7,158.56 99.02,159.25 98.8,159.25 98.55,159 98.55,158.68 98.88,158.35 98.88,158.11 98.65,157.88 98.41,157.88 98.03,158.26 97.8,158.26 92.26,152.72 92.26,132.47 91.25,131.46
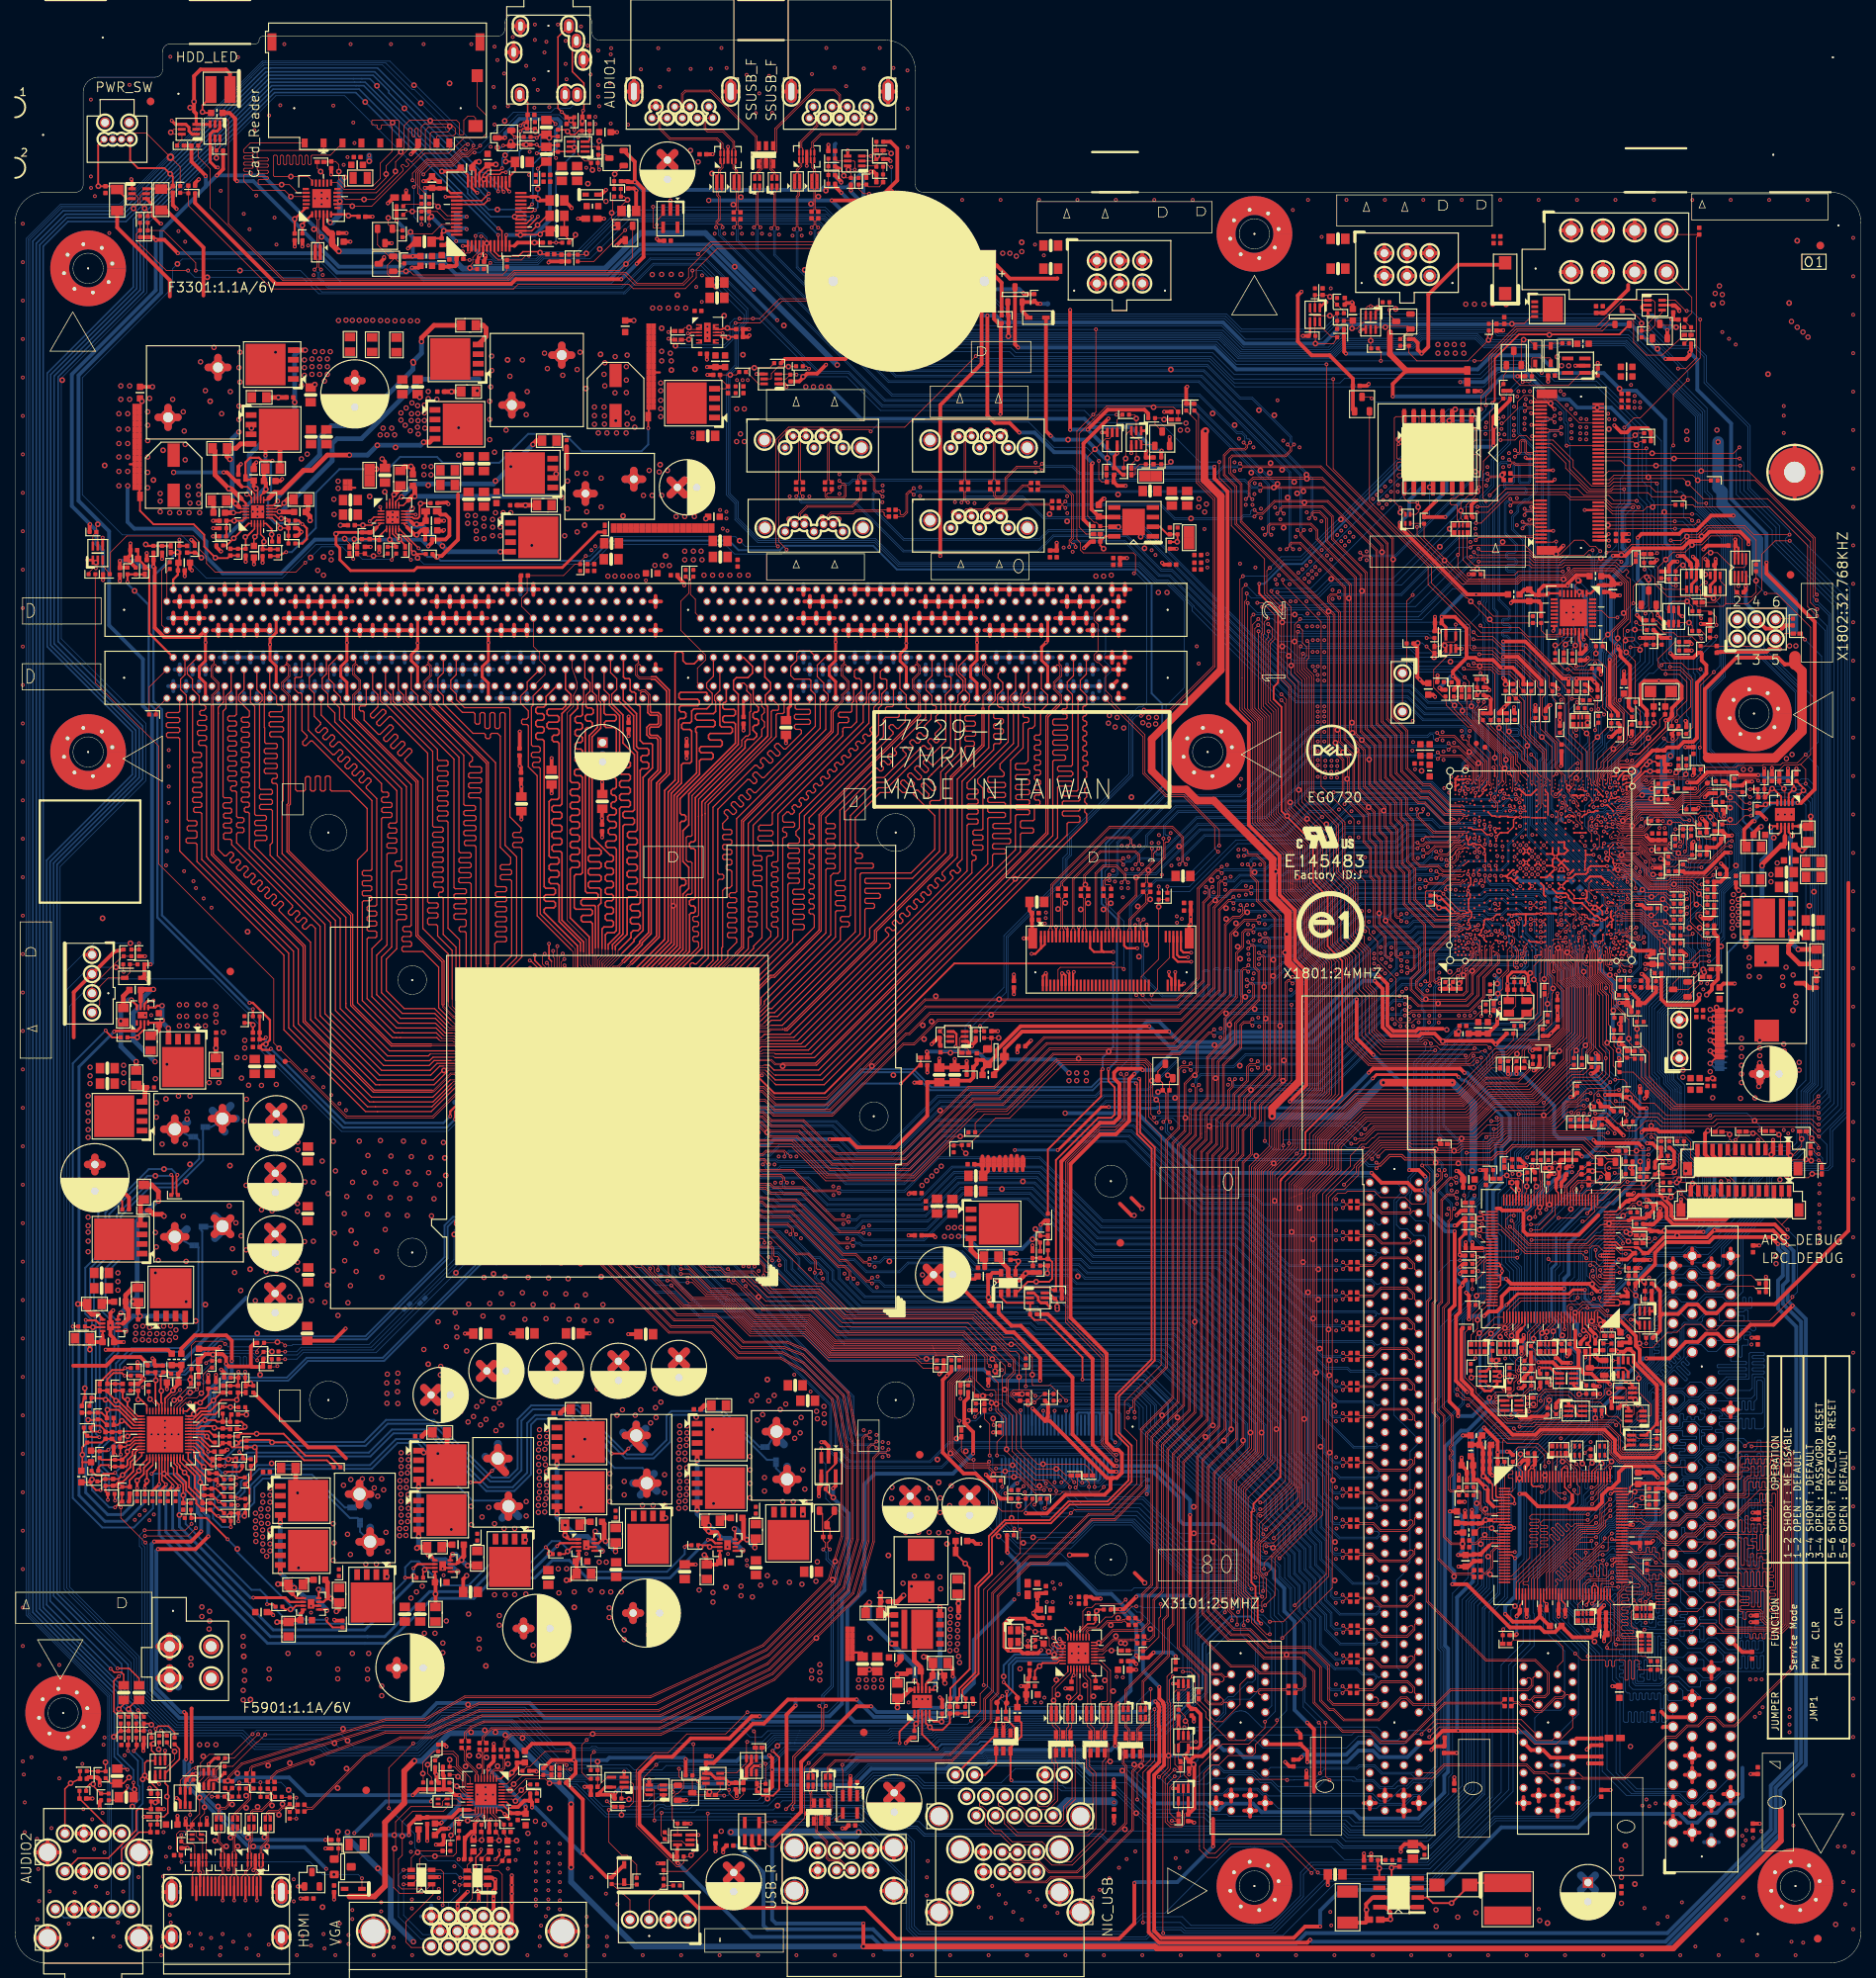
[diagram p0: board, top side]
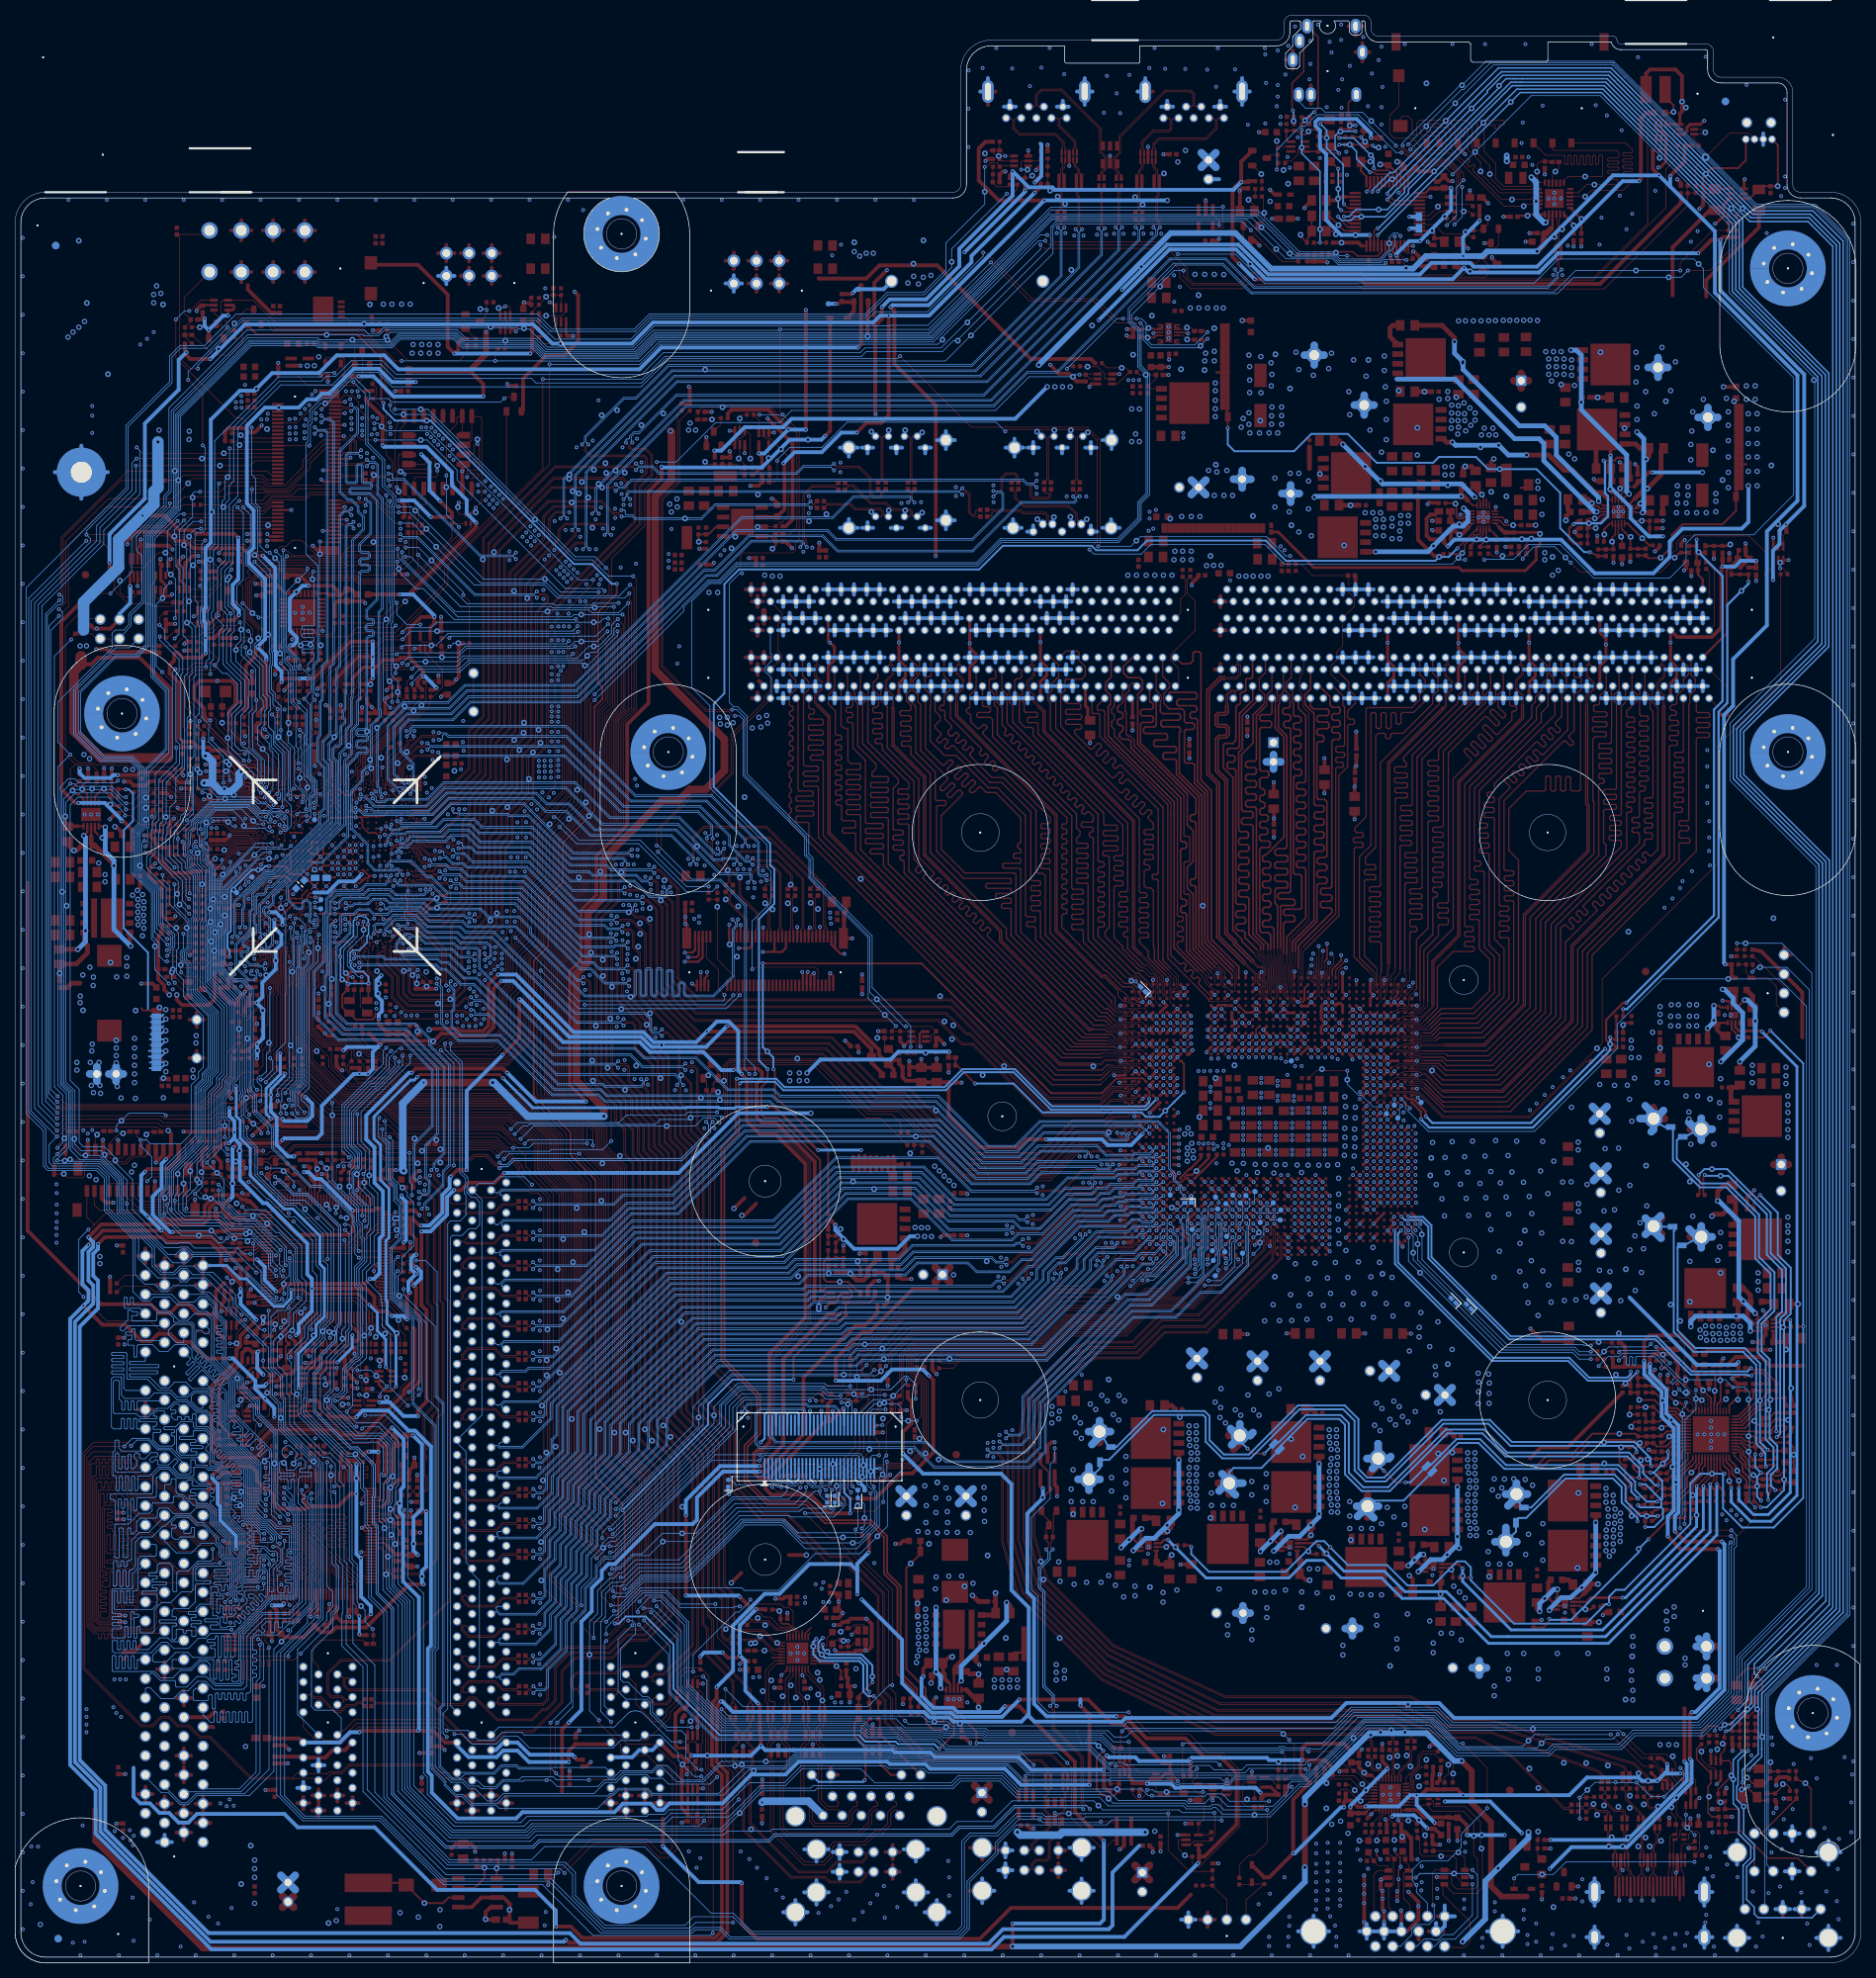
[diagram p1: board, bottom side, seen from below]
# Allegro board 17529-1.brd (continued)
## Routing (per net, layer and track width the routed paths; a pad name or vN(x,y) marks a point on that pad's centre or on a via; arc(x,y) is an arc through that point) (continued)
M_A_DQ37: length 63.2
  TOP w0.089: 91.51,131.17 90.51,130.16 90.51,128.9 90.68,128.73 91.06,128.73 91.15,128.64 91.15,127.75 CPU1.AV8
  TOP w0.165: 91.51,131.17 92.89,132.55 92.89,143.03 93.06,143.2 93.51,143.2 93.68,143.36 93.68,143.69 93.51,143.86 93.06,143.86 92.89,144.02 92.89,152.45 96.83,156.39 97.06,156.39 97.59,155.86 97.82,155.86 98.04,156.08 98.04,156.34 97.53,156.86 97.53,157.09 97.79,157.35 98.02,157.35 98.75,156.62 98.99,156.62 99.49,157.13 99.49,157.14 105.78,163.42 105.78,167.61 105.2,168.19 105.2,169.48 105.03,169.65 103,169.65 102.54,170.1 102.54,171.32 103.33,172.11 103.33,173.05 103.66,173.38 105.06,173.38 DIMM1.240
M_A_DQ38: length 59
  TOP w0.089: 94.73,131.83 94.35,131.83 92.77,130.25 92.77,130.23 92.66,130.12 CPU1.AY6
  TOP w0.165: DIMM1.102 111.01,168.72 110.85,168.57 110.85,166.84 110.85,166.84 110.85,166.73 110.62,166.5 110.62,165.44 110.45,165.27 109,165.27 108.84,165.11 108.84,164.78 109,164.61 110.02,164.61 110.19,164.45 110.19,164.06 110.03,163.91 108.95,163.91 108.78,163.74 108.78,162.45 96.92,150.58 96.92,141.71 97.08,141.54 97.9,141.54 98.07,141.38 98.07,141.05 97.9,140.88 97.08,140.88 96.92,140.72 96.92,140.39 97.08,140.22 97.93,140.22 98.09,140.06 98.09,139.73 97.93,139.56 97.08,139.56 96.92,139.4 96.92,139.07 97.08,138.9 97.93,138.9 98.09,138.74 98.09,138.41 97.93,138.24 97.08,138.24 96.92,138.08 96.92,137.75 97.08,137.58 97.93,137.58 98.09,137.42 98.09,137.09 97.93,136.92 97.08,136.92 96.92,136.76 96.92,136.43 97.08,136.26 97.29,136.26 97.49,136.07 97.49,135.77 97.32,135.6 97.08,135.6 96.92,135.44 96.92,134.02 94.73,131.83
M_A_DQ39: length 60.4
  TOP w0.089: CPU1.AW6 92.66,128.73 92.98,129.05 92.98,129.63 92.96,129.66 92.96,130.17 93.45,130.66 93.8,130.66 94.61,131.47 95.02,131.47 95.17,131.62
  TOP w0.165: 95.17,131.62 97.62,134.07 97.62,134.38 98.73,135.48 98.73,142.18 98.56,142.34 97.7,142.34 97.55,142.49 97.55,142.83 97.73,143 98.56,143 98.73,143.17 98.73,143.5 98.56,143.66 97.73,143.66 97.56,143.83 97.56,144.16 97.73,144.33 98.56,144.33 98.73,144.49 98.73,144.82 98.56,144.99 97.73,144.99 97.56,145.15 97.56,145.48 97.73,145.65 98.56,145.65 98.73,145.81 98.73,146.14 98.56,146.31 97.73,146.31 97.56,146.47 97.56,150.33 109.42,162.18 109.42,162.71 109.42,163.11 109.58,163.27 110.5,163.27 111.25,164.02 111.25,166.67 111.18,166.75 111.18,166.78 111.17,166.79 111.17,167.41 111.86,168.11 111.86,169.47 111.61,169.72 111.19,169.72 110.95,169.96 110.95,170.76 111.11,170.93 DIMM1.247
M_A_DQ40: length 66.1
  TOP w0.089: 95.77,128.94 95.62,128.8 95.29,128.8 94.86,128.36 94.86,128.15 94.49,127.78 CPU1.AV4
  TOP w0.165: DIMM1.108 116.11,166.18 115.95,166.01 115.25,166.01 115.06,165.83 115.06,165.42 115.23,165.26 116.67,165.26 116.87,165.07 116.87,164.76 116.7,164.6 115.08,164.6 114.78,164.3 114.78,162.04 104.32,151.58 104.32,142.05 104.16,141.88 102.96,141.88 102.79,141.72 102.79,141.39 102.96,141.22 104.16,141.22 104.32,141.06 104.32,140.72 104.16,140.56 102.96,140.56 102.79,140.39 102.79,140.06 102.96,139.9 104.16,139.9 104.32,139.73 104.32,139.4 104.16,139.24 102.96,139.24 102.79,139.07 102.79,138.74 102.96,138.58 104.16,138.58 104.32,138.41 104.32,138.08 104.16,137.92 102.96,137.92 102.79,137.75 102.79,137.42 102.96,137.26 104.16,137.26 104.32,137.09 104.32,136.72 104.16,136.55 102.96,136.55 102.79,136.39 102.79,134.92 97.31,129.44 96.27,129.44 95.77,128.94
M_A_DQ41: length 65.8
  TOP w0.089: 95.67,127.42 95.92,127.67 95.92,128.5 96.19,128.78
  TOP w0.102: CPU1.AV3 95.67,127.42
  TOP w0.165: DIMM1.253 116.96,168.38 117.81,167.54 117.81,165.94 117.97,165.77 118.07,165.77 118.24,165.61 118.24,165.3 118.05,165.11 117.89,165.11 117.68,164.9 117.68,164.03 116.77,163.12 116.53,163.12 116.03,163.63 115.75,163.63 115.54,163.42 115.54,163.18 116.07,162.66 116.07,162.42 104.96,151.31 104.96,150.68 105.12,150.51 105.45,150.51 105.64,150.32 105.64,150.02 105.47,149.85 105.12,149.85 104.96,149.69 104.96,149.36 105.12,149.19 105.45,149.19 105.64,149 105.64,148.7 105.47,148.53 105.12,148.53 104.96,148.37 104.96,148.04 105.12,147.87 105.45,147.87 105.64,147.68 105.64,147.37 105.47,147.21 105.12,147.21 104.96,147.04 104.96,146.71 105.12,146.55 105.45,146.55 105.64,146.36 105.64,146.05 105.47,145.89 105.12,145.89 104.96,145.72 104.96,145.39 105.12,145.23 105.45,145.23 105.64,145.04 105.64,144.73 105.47,144.57 105.12,144.57 104.96,144.4 104.96,144.07 105.12,143.91 105.45,143.91 105.64,143.72 105.64,143.41 105.47,143.25 105.12,143.25 104.96,143.08 104.96,142.75 105.12,142.59 105.45,142.59 105.64,142.4 105.64,142.09 105.47,141.93 105.12,141.93 104.96,141.76 104.96,141.43 105.12,141.27 105.45,141.27 105.64,141.08 105.64,140.77 105.47,140.61 105.12,140.61 104.96,140.44 104.96,140.11 105.12,139.95 105.45,139.95 105.64,139.75 105.64,139.45 105.47,139.28 105.12,139.28 104.96,139.12 104.96,138.79 105.12,138.62 105.45,138.62 105.64,138.43 105.64,136.87 103.35,134.59 103.35,134.57 99.87,131.09 99.69,131.09 97.59,128.98 96.39,128.98 96.19,128.78
M_A_DQ42: length 67.1
  TOP w0.089: CPU1.AT3 95.73,125.92 96.58,125.92 96.86,125.65 96.86,125.46 97.05,125.27 97.47,125.27 97.67,125.47 98.34,125.47 98.55,125.68
  TOP w0.165: DIMM1.115 122.39,166.79 122.39,165.42 121.72,164.74 121.72,164.21 122.39,163.53 122.39,163.26 121.61,162.48 121.61,162.25 122.14,161.72 122.14,161.49 121.9,161.26 121.67,161.26 121.15,161.78 120.91,161.78 120.68,161.55 120.68,161.31 121.11,160.89 121.11,160.65 120.87,160.42 120.64,160.42 120.21,160.85 119.98,160.85 115.14,156.01 113.63,156.01 109.73,152.11 109.73,143.18 109.56,143.01 108.61,143.01 108.45,142.85 108.45,142.52 108.61,142.35 109.56,142.35 109.73,142.19 109.73,141.86 109.56,141.69 108.61,141.69 108.45,141.53 108.45,141.2 108.61,141.03 109.56,141.03 109.73,140.87 109.73,140.54 109.56,140.37 108.61,140.37 108.45,140.21 108.45,139.88 108.61,139.71 109.56,139.71 109.73,139.55 109.73,139.22 109.56,139.05 108.61,139.05 108.45,138.89 108.45,135.57 98.55,125.68
M_A_DQ43: length 65.5
  TOP w0.089: 98.7,125.24 98.58,125.12 97.74,125.12 97.7,125.08 96.67,125.08 96.32,125.44 CPU1.AT2
  TOP w0.165: 98.7,125.24 99.57,126.11 100.03,126.11 109.09,135.18 109.09,136.76 109.26,136.93 110.1,136.93 110.29,137.12 110.29,137.42 110.12,137.59 109.26,137.59 109.09,137.76 109.09,138.09 109.28,138.28 110.24,138.28 110.43,138.47 110.43,151.09 110.43,151.09 110.43,151.61 114.11,155.3 115.33,155.3 119.62,159.59 121.13,159.59 123.03,161.49 123.03,166.13 122.96,166.19 122.96,167.56 123.72,168.33 123.72,169.84 123.56,170 123.06,170 122.91,170.15 DIMM1.260
M_A_DQ44: length 64.2
  TOP w0.089: CPU1.AY4 95.64,130.4 96.47,130.4 96.69,130.62
  TOP w0.165: DIMM1.106 114.25,168.57 114.25,166.65 113.51,165.91 113.51,163.59 113,163.07 113,162.84 113.23,162.61 113.23,162.38 113,162.15 112.76,162.15 112.54,162.37 112.3,162.37 112.07,162.14 112.07,161.91 112.35,161.63 112.35,161.4 112.11,161.16 111.88,161.16 111.6,161.44 111.37,161.44 111.13,161.21 111.13,160.97 111.41,160.7 111.41,160.46 111.18,160.23 110.94,160.23 110.67,160.51 110.43,160.51 110.2,160.27 110.2,160.04 110.48,159.76 110.48,159.53 110.24,159.29 110.01,159.29 109.73,159.57 109.5,159.57 109.27,159.34 109.27,159.1 109.54,158.83 109.54,158.59 109.31,158.36 109.08,158.36 108.8,158.64 108.56,158.64 108.33,158.4 108.33,158.17 108.61,157.89 108.61,157.66 108.38,157.43 108.14,157.43 107.86,157.7 107.63,157.7 107.4,157.47 107.4,157.24 107.67,156.96 107.67,156.72 107.44,156.49 107.21,156.49 106.93,156.77 106.7,156.77 106.46,156.54 106.46,156.3 106.74,156.02 106.74,155.79 106.51,155.56 106.27,155.56 106,155.83 105.76,155.83 105.53,155.6 105.53,155.37 105.81,155.09 105.81,154.86 105.57,154.62 105.34,154.62 105.06,154.9 104.83,154.9 104.59,154.67 104.59,154.43 104.87,154.16 104.87,153.92 104.64,153.69 104.4,153.69 104.13,153.97 103.89,153.97 103.66,153.73 103.66,153.5 103.94,153.22 103.94,152.99 103.7,152.75 103.47,152.75 103.19,153.03 102.96,153.03 102.73,152.8 102.73,152.56 103,152.29 103,152.05 102.77,151.82 102.54,151.82 102.26,152.1 102.03,152.1 101.47,151.55 101.47,150.91 101.64,150.75 102.88,150.75 103.05,150.58 103.05,150.25 102.88,150.08 101.64,150.08 101.47,149.92 101.47,149.59 101.64,149.42 101.84,149.42 102.01,149.26 102.01,148.93 101.84,148.76 101.64,148.76 101.47,148.6 101.47,135.41 96.69,130.62
M_A_DQ45: length 65.2
  TOP w0.089: 97.28,130.32 97.13,130.17 95.71,130.17 94.94,129.4 94.94,128.8 CPU1.AW4
  TOP w0.165: DIMM1.251 114.65,170.93 114.38,170.65 114.38,169.84 114.54,169.67 115.07,169.67 115.24,169.51 115.24,168.38 114.57,167.71 114.57,166.23 114.15,165.81 114.15,162.3 103.69,151.84 103.69,149.99 103.23,149.53 103.23,149.05 103.69,148.59 103.69,148.13 103.52,147.96 102.32,147.96 102.16,147.8 102.16,147.47 102.32,147.3 103.52,147.3 103.69,147.14 103.69,146.81 103.52,146.64 102.32,146.64 102.16,146.48 102.16,146.15 102.32,145.98 103.52,145.98 103.69,145.82 103.69,145.49 103.52,145.32 102.32,145.32 102.16,145.16 102.16,144.83 102.32,144.66 103.52,144.66 103.69,144.5 103.69,144.17 103.52,144 102.32,144 102.16,143.84 102.16,143.51 102.32,143.34 103.52,143.34 103.69,143.18 103.69,142.85 103.52,142.68 102.32,142.68 102.16,142.52 102.16,135.19 98.19,131.22 97.28,130.32
M_A_DQ46: length 68.5
  TOP w0.089: CPU1.AT4 94.49,125.96 94.64,126.11 96.7,126.11 96.72,126.09 98.07,126.09 98.59,126.61 98.59,126.67
  TOP w0.165: DIMM1.113 120.36,164.54 116.28,160.46 116.28,160.23 116.51,160 116.51,159.76 116.29,159.54 116.03,159.54 115.81,159.76 115.58,159.76 115.35,159.53 115.35,159.29 115.8,158.84 115.8,158.6 115.57,158.37 115.34,158.37 114.88,158.83 114.64,158.83 114.41,158.59 114.41,158.36 114.79,157.98 114.79,157.75 114.56,157.51 114.32,157.51 113.94,157.89 113.71,157.89 107.18,151.36 107.18,150.72 107.34,150.56 108.24,150.56 108.41,150.39 108.41,150.06 108.24,149.9 107.34,149.9 107.18,149.73 107.18,149.4 107.34,149.24 108.24,149.24 108.41,149.07 108.41,148.74 108.24,148.58 107.34,148.58 107.18,148.41 107.18,148.08 107.34,147.92 108.24,147.92 108.41,147.75 108.41,147.42 108.24,147.25 107.34,147.25 107.18,147.09 107.18,146.76 107.34,146.59 108.24,146.59 108.41,146.43 108.41,146.1 108.24,145.93 107.34,145.93 107.18,145.77 107.18,145.44 107.34,145.27 108.22,145.27 108.41,145.08 108.41,144.75 108.27,144.61 107.34,144.61 107.18,144.45 107.18,136.11 106.58,135.51 98.59,127.53 98.59,126.67
M_A_DQ47: length 64.9
  TOP w0.089: 99.03,126.67 98.12,125.75 97.39,125.75 CPU1.AT1
  TOP w0.165: 99.03,126.67 99.03,127.07 107.55,135.58 107.55,135.58 107.81,135.85 107.81,143.64 108.15,143.98 108.77,143.98 109.04,144.25 109.04,152.33 113.36,156.65 114.88,156.65 117.79,159.56 117.79,159.79 117.36,160.23 117.36,160.46 117.59,160.69 117.82,160.69 118.26,160.26 118.49,160.26 118.73,160.49 118.73,160.73 118.29,161.16 118.29,161.4 118.52,161.63 118.76,161.63 119.19,161.19 119.43,161.19 119.66,161.43 119.66,161.66 119.23,162.1 119.23,162.33 119.46,162.56 119.69,162.56 120.13,162.13 120.36,162.13 120.68,162.44 120.68,162.76 120.23,163.21 120.23,163.52 121.08,164.36 121.08,165.35 121.24,165.52 121.59,165.52 121.76,165.68 121.76,166.02 121.59,166.18 121.35,166.18 121.18,166.35 121.18,167.46 120.42,168.22 120.42,169.29 121.21,170.08 DIMM1.258
M_A_DQ48: length 74.9
  TOP w0.089: CPU1.AP1 99.16,123.77 99.38,123.99
  TOP w0.165: 99.38,123.99 99.95,124.56 101.17,124.56 112.34,135.72 112.34,139.19 112.5,139.36 113.45,139.36 113.61,139.52 113.61,139.85 113.45,140.02 112.48,140.02 112.34,140.16 112.34,140.54 112.48,140.68 114.21,140.68 114.38,140.84 114.38,141.15 114.19,141.34 112.48,141.34 112.34,141.48 112.34,141.86 112.48,142 115.51,142 115.67,142.16 115.67,142.49 115.51,142.66 112.48,142.66 112.34,142.8 112.34,143.18 112.48,143.32 118.61,143.32 122.2,146.9 122.2,152.78 122.03,152.94 121.13,152.94 120.93,153.15 120.93,153.42 121.11,153.6 122.2,153.6 122.36,153.77 122.36,157.37 124.93,159.95 124.93,166.03 125.46,166.56 DIMM1.119
M_A_DQ49: length 75.1
  TOP w0.089: CPU1.AP2 96.7,123.77 97.03,123.44 97.52,123.44 97.6,123.53 99.45,123.53 99.82,123.9 99.97,123.9
  TOP w0.165: DIMM1.264 125.92,172.53 124.77,171.38 124.77,170.52 125.62,169.67 125.62,168.16 126.16,167.61 126.16,166.75 125.57,166.16 125.57,165.67 125.76,165.48 126.86,165.48 127.03,165.32 127.03,164.99 126.86,164.82 125.73,164.82 125.57,164.65 125.57,164.27 125.73,164.1 126.76,164.1 126.95,163.91 126.95,163.63 126.76,163.44 125.73,163.44 125.57,163.28 125.57,162.95 125.73,162.78 126.81,162.78 126.97,162.62 126.97,162.29 126.81,162.12 125.73,162.12 125.57,161.96 125.57,161.63 125.73,161.46 126.66,161.46 126.82,161.29 126.82,160.96 126.66,160.8 125.73,160.8 125.57,160.63 125.57,159.68 125.2,159.31 123.01,157.13 123.01,146.74 112.97,136.69 112.97,135.46 101.41,123.9 99.97,123.9
M_A_DQ50: length 77.2
  TOP w0.089: 99.69,121.87 99.47,121.87 99.29,121.69 97.59,121.69 97.51,121.61 97.05,121.61 96.82,121.84 96.82,121.94 96.5,122.26 95.73,122.26 CPU1.AM3
  TOP w0.165: DIMM1.126 131.25,168.57 131.25,166.68 131.24,166.67 131.24,165.12 131.28,165.08 131.28,161.35 125.85,155.92 125.85,155.29 126.01,155.12 127.14,155.12 127.3,154.96 127.3,154.63 127.14,154.46 126.01,154.46 125.85,154.3 125.85,153.97 126.01,153.8 127.14,153.8 127.3,153.64 127.3,153.31 127.14,153.14 126.01,153.14 125.85,152.98 125.85,152.65 126.01,152.48 127.14,152.48 127.3,152.32 127.3,151.99 127.14,151.82 126.01,151.82 125.85,151.66 125.85,151.33 126.01,151.16 127.14,151.16 127.3,151 127.3,150.67 127.14,150.5 126.01,150.5 125.85,150.34 125.85,144.31 103.41,121.87 99.69,121.87
M_A_DQ51: length 75.9
  TOP w0.089: CPU1.AM2 96.32,121.78 96.67,121.42 97.74,121.42 97.77,121.45 99.73,121.45
  TOP w0.165: 99.73,121.45 103.89,121.45 126.48,144.04 126.48,145.55 126.65,145.71 126.86,145.71 127.03,145.88 127.03,146.21 126.86,146.37 126.65,146.37 126.48,146.54 126.48,146.89 126.65,147.06 127.77,147.06 127.94,147.22 127.94,147.55 127.77,147.72 126.76,147.72 126.59,147.88 126.59,148.22 126.76,148.38 127.77,148.38 127.94,148.55 127.94,148.88 127.77,149.04 126.78,149.04 126.62,149.21 126.62,149.54 126.78,149.7 127.77,149.7 127.94,149.87 127.94,155.22 127.24,155.92 127.24,156.42 131.98,161.15 131.98,166.4 131.57,166.81 131.57,167.41 132.26,168.11 DIMM1.271
M_A_DQ52: length 77.1
  TOP w0.089: CPU1.AP4 95.01,124.29 97.62,124.29 97.66,124.26 98.35,124.26 98.63,124.53
  TOP w0.165: 98.63,124.53 99.68,125.58 100.39,125.58 111.07,136.25 111.07,144.5 111.23,144.66 113.3,144.66 113.46,144.83 113.46,145.16 113.3,145.32 111.23,145.32 111.07,145.49 111.07,145.82 111.23,145.98 111.85,145.98 112.02,146.15 112.02,146.45 111.83,146.65 111.23,146.65 111.07,146.81 111.07,147.14 111.23,147.31 111.32,147.31 111.48,147.47 111.48,147.8 111.32,147.97 111.23,147.97 111.07,148.13 111.07,151.35 114.38,154.66 115.59,154.66 116.33,155.4 116.56,155.4 117.3,154.66 117.68,154.66 117.84,154.83 117.84,155.06 117.06,155.84 117.06,156.08 117.29,156.31 117.53,156.31 118.4,155.44 118.63,155.44 118.86,155.67 118.86,155.91 117.99,156.78 117.99,157.01 118.23,157.24 118.46,157.24 119.33,156.37 119.57,156.37 119.8,156.61 119.8,156.84 118.93,157.71 118.93,157.95 119.16,158.18 119.39,158.18 120.24,157.33 120.48,157.33 120.72,157.58 120.72,157.84 120.04,158.52 120.04,158.75 120.24,158.95 120.54,158.95 121.19,158.3 121.45,158.3 123.66,160.52 123.66,167.03 DIMM1.117
M_A_DQ53: length 76.6
  TOP w0.089: 99.01,124.23 98.78,124 97.56,124 97.48,124.08 97.46,124.09 97.44,124.09 95.54,124.09 95.4,123.95 CPU1.AP3
  TOP w0.165: 99.01,124.23 99.85,125.07 100.78,125.07 111.7,135.99 111.7,143.86 111.87,144.03 118.43,144.03 121.56,147.17 121.56,151.61 118.76,154.42 118.76,154.65 119.09,154.98 119.33,154.98 120.32,153.98 120.56,153.98 120.79,154.22 120.79,154.45 119.78,155.46 119.78,155.69 119.83,155.74 120.02,155.93 120.25,155.93 121.26,154.92 121.56,154.92 121.73,155.08 121.73,155.39 120.72,156.39 120.72,156.63 121.15,157.06 124.3,160.21 124.3,166.29 124.64,166.62 124.64,167.51 125.3,168.18 125.3,169.46 124.45,170.31 124.45,172.37 DIMM1.262
M_A_DQ54: length 77.9
  TOP w0.089: CPU1.AM4 94.49,122.28 94.67,122.45 96.58,122.45 96.77,122.26 97.47,122.26 97.5,122.24 98.59,122.24
  TOP w0.165: 98.59,122.24 99.06,122.71 102.46,122.71 115.48,135.73 115.48,135.96 115.05,136.39 115.05,136.6 115.29,136.84 115.53,136.84 115.94,136.43 116.18,136.43 116.41,136.66 116.41,136.9 115.97,137.34 115.97,137.52 116.25,137.8 116.44,137.8 116.88,137.36 117.11,137.36 117.34,137.6 117.34,137.83 116.93,138.25 116.93,138.48 117.16,138.71 117.4,138.71 117.81,138.3 118.05,138.3 118.28,138.53 118.28,138.77 117.86,139.18 117.86,139.41 118.1,139.65 118.33,139.65 118.75,139.23 118.98,139.23 119.21,139.47 119.21,139.7 118.8,140.11 118.8,140.35 119.03,140.58 119.27,140.58 119.68,140.17 119.91,140.17 120.15,140.4 120.15,140.63 119.73,141.05 119.73,141.28 119.97,141.52 120.2,141.52 120.61,141.1 120.85,141.1 121.08,141.33 121.08,141.57 120.67,141.98 120.67,142.22 120.9,142.45 121.13,142.45 121.55,142.04 121.78,142.04 122.02,142.27 122.02,142.5 121.6,142.92 121.6,143.15 121.83,143.38 122.07,143.38 122.46,142.99 122.7,142.99 122.93,143.22 122.93,143.46 122.54,143.85 122.54,144.08 124.55,146.1 124.55,156.42 128.71,160.59 128.71,166 129.55,166.84 129.55,168.57 DIMM1.124
M_A_DQ55: length 75.3
  TOP w0.089: 99.67,122.3 99.47,122.3 99.1,121.94 CPU1.AM1
  TOP w0.165: DIMM1.269 130.54,170.93 129.95,170.33 129.95,169.8 130.56,169.19 130.56,168.25 129.87,167.56 129.87,166.17 130.1,165.94 130.44,165.94 130.61,165.77 130.61,165.38 130.43,165.2 129.5,165.2 129.35,165.05 129.35,164.59 129.51,164.42 130.48,164.42 130.64,164.26 130.64,163.93 130.48,163.76 129.51,163.76 129.35,163.6 129.35,163.27 129.51,163.1 130.48,163.1 130.64,162.94 130.64,162.61 130.48,162.44 129.51,162.44 129.35,162.28 129.35,161.95 129.51,161.78 130.14,161.78 130.3,161.62 130.3,161.29 130.14,161.12 129.51,161.12 129.35,160.96 129.35,160.32 125.18,156.16 125.18,145.84 124.55,145.2 124.55,144.97 124.97,144.55 124.97,144.32 124.67,144.02 124.43,144.02 124.08,144.37 123.85,144.37 123.61,144.14 123.61,143.9 123.97,143.55 123.97,143.32 102.95,122.3 99.67,122.3
M_A_DQ56: length 86.6
  TOP w0.089: CPU1.AK1 98.72,120.11 98.83,120.22 100.38,120.22 100.49,120.11
  TOP w0.165: DIMM1.130 134.81,163.51 134.45,163.15 134.07,163.15 133.91,162.99 133.91,158.85 133.55,158.5 132.4,158.5 132.23,158.33 132.23,157.85 132.4,157.68 133.95,157.68 134.11,157.52 134.11,157.19 133.95,157.02 132.4,157.02 132.23,156.86 132.23,156.53 132.4,156.36 133.95,156.36 134.11,156.2 134.11,155.87 133.95,155.7 132.4,155.7 132.23,155.54 132.23,155.21 132.4,155.04 133.95,155.04 134.11,154.88 134.11,154.55 133.95,154.38 132.45,154.38 132.28,154.22 132.28,153.89 132.45,153.72 133.95,153.72 134.11,153.56 134.11,153.22 133.95,153.06 132.4,153.06 132.23,152.89 132.23,152.56 132.4,152.4 133.95,152.4 134.11,152.23 134.11,151.9 133.95,151.74 132.4,151.74 132.23,151.57 132.23,147.1 105.24,120.11 100.49,120.11
M_A_DQ57: length 86.8
  TOP w0.089: 100.43,119.63 100.25,119.81 97.41,119.81 97.38,119.79 96.64,119.79 CPU1.AK2
  TOP w0.165: DIMM1.275 135.66,168.38 136.5,167.54 136.5,166.34 135.56,165.4 135.56,162.42 135.39,162.25 134.91,162.25 134.75,162.09 134.75,161.76 134.91,161.59 135.39,161.59 135.56,161.43 135.56,161.1 135.39,160.93 134.91,160.93 134.75,160.77 134.75,160.44 134.91,160.27 135.39,160.27 135.56,160.11 135.56,159.78 135.39,159.61 134.91,159.61 134.75,159.45 134.75,159.12 134.91,158.95 135.39,158.95 135.56,158.79 135.56,158.46 135.39,158.29 134.91,158.29 134.75,158.13 134.75,157.8 134.91,157.63 135.39,157.63 135.56,157.47 135.56,157.14 135.39,156.97 134.91,156.97 134.75,156.81 134.75,156.48 134.91,156.31 135.39,156.31 135.56,156.15 135.56,155.82 135.39,155.65 134.91,155.65 134.75,155.49 134.75,155.16 134.91,154.99 135.39,154.99 135.56,154.83 135.56,154.5 135.39,154.33 134.91,154.33 134.75,154.17 134.75,153.83 134.91,153.67 135.32,153.67 135.48,153.5 135.48,153.17 135.32,153.01 134.91,153.01 134.75,152.84 134.75,151.1 134.58,150.94 133.06,150.94 132.89,150.77 132.89,150.14 133.06,149.97 134.48,149.97 134.65,149.81 134.65,149.48 134.48,149.31 133.06,149.31 132.89,149.15 132.89,146.86 105.66,119.63 100.43,119.63
M_A_DQ58: length 90.2
  TOP w0.089: 99.31,117.86 99.19,117.98 97.54,117.98 97.46,117.91 97.1,117.91 96.69,118.31 96.69,118.42 96.5,118.6 95.73,118.6 CPU1.AH3
  TOP w0.165: 99.31,117.86 100.48,116.69 106.69,116.69 139.06,149.06 139.06,150.56 139.23,150.72 140.6,150.72 140.76,150.89 140.76,151.39 140.6,151.56 138.6,151.56 138.44,151.71 138.44,152.07 138.6,152.22 140.6,152.22 140.76,152.38 140.76,152.71 140.6,152.88 138.6,152.88 138.44,153.03 138.44,153.39 138.6,153.54 140.6,153.54 140.76,153.71 140.76,154.04 140.6,154.2 138.68,154.2 138.53,154.35 138.53,154.71 138.68,154.86 140.35,154.86 140.51,155.03 140.51,166.88 DIMM1.137
M_A_DQ59: length 88.6
  TOP w0.089: 100.4,116.2 98.89,117.72 96.88,117.72 CPU1.AH2
  TOP w0.165: 100.4,116.2 100.56,116.05 106.95,116.05 141.66,150.75 141.66,151.85 141.4,152.11 141.4,152.51 141.66,152.77 141.66,153.17 141.4,153.43 141.4,153.83 141.66,154.09 141.66,154.49 141.4,154.75 141.4,155.15 141.66,155.41 141.66,155.81 141.4,156.07 141.4,156.47 141.66,156.73 141.66,157.36 141.49,157.53 141.36,157.53 141.17,157.72 141.17,158 141.36,158.19 141.64,158.19 141.81,158.35 141.81,158.68 141.64,158.85 141.31,158.85 141.15,159.01 141.15,159.35 141.31,159.51 141.54,159.51 141.71,159.68 141.71,160.01 141.54,160.17 141.31,160.17 141.15,160.34 141.15,160.67 141.31,160.83 141.47,160.83 141.63,161 141.63,161.33 141.47,161.49 141.31,161.49 141.15,161.66 141.15,161.99 141.31,162.15 141.49,162.15 141.66,162.32 141.66,162.65 141.49,162.81 141.31,162.81 141.15,162.98 141.15,163.31 141.31,163.47 141.49,163.47 141.66,163.64 141.66,163.97 141.49,164.13 141.31,164.13 141.15,164.3 141.15,164.63 141.31,164.79 141.47,164.79 141.63,164.96 141.63,165.29 141.47,165.45 141.31,165.45 141.15,165.62 141.15,165.95 141.31,166.11 141.49,166.11 141.66,166.28 141.66,167.46 140.82,168.3 140.82,169.52 141.61,170.31 DIMM1.282
M_A_DQ60: length 88.5
  TOP w0.089: 98.4,120.83 98.17,120.6 97.77,120.6 97.74,120.62 95,120.62 CPU1.AK4
  TOP w0.165: 98.4,120.83 98.65,121.08 104.42,121.08 128.57,145.24 128.57,151.21 128.74,151.37 130.75,151.37 130.91,151.54 130.91,151.87 130.75,152.03 128.74,152.03 128.57,152.2 128.57,152.53 128.74,152.69 130.75,152.69 130.91,152.86 130.91,153.19 130.75,153.35 128.74,153.35 128.57,153.52 128.57,153.85 128.74,154.01 130.75,154.01 130.91,154.18 130.91,154.51 130.75,154.67 128.74,154.67 128.57,154.84 128.57,155.17 128.74,155.33 130.75,155.33 130.91,155.5 130.91,155.83 130.75,155.99 128.74,155.99 128.57,156.16 128.57,156.6 128.74,156.77 130.56,156.77 130.75,156.96 130.75,157.28 130.2,157.82 130.2,158.42 132.61,160.83 132.61,166.42 132.95,166.76 132.95,167.7 133.11,167.86 DIMM1.128
M_A_DQ61: length 87.6
  TOP w0.089: CPU1.AK3 95.73,120.43 97.67,120.43 97.69,120.41 98.56,120.41 98.78,120.62 99.62,120.62
  TOP w0.165: 99.62,120.62 104.86,120.62 129.21,144.97 129.21,146.39 129.37,146.56 130.8,146.56 130.99,146.75 130.99,147 130.77,147.22 129.37,147.22 129.21,147.38 129.21,147.74 129.38,147.9 131.43,147.9 131.6,148.07 131.6,148.42 131.43,148.59 129.37,148.59 129.21,148.76 129.21,149.09 129.37,149.25 131.43,149.25 131.6,149.42 131.6,149.75 131.43,149.91 129.43,149.91 129.26,150.08 129.26,150.41 129.43,150.57 131.43,150.57 131.6,150.74 131.6,158.92 133.25,160.57 133.25,163.76 133.41,163.92 133.85,163.92 134.01,164.09 134.01,164.42 133.85,164.58 133.41,164.58 133.25,164.75 133.25,165.08 133.41,165.24 134.01,165.24 134.18,165.41 134.18,165.74 134.01,165.9 133.52,165.9 133.27,166.15 133.27,167.41 133.96,168.11 DIMM1.273
M_A_DQ62: length 90.6
  TOP w0.089: CPU1.AH4 95,118.8 96.7,118.8 96.87,118.62 97.45,118.62 97.54,118.52 98.84,118.52 98.96,118.64 99.18,118.64
  TOP w0.165: DIMM1.135 139.06,165.88 138.9,165.72 138.54,165.72 138.35,165.53 138.35,165.22 138.52,165.06 138.9,165.06 139.06,164.89 139.06,164.54 138.9,164.37 137.34,164.37 137.17,164.21 137.17,163.74 137.34,163.57 138.98,163.57 139.14,163.41 139.14,163.08 138.98,162.91 137.34,162.91 137.17,162.75 137.17,162.41 137.34,162.25 138.93,162.25 139.09,162.08 139.09,161.75 138.93,161.59 137.34,161.59 137.17,161.42 137.17,161.09 137.34,160.93 138.98,160.93 139.14,160.76 139.14,160.43 138.98,160.27 137.34,160.27 137.17,160.1 137.17,159.77 137.34,159.61 138.7,159.61 138.86,159.44 138.86,159.11 138.7,158.95 137.34,158.95 137.17,158.78 137.17,148.97 106.19,117.98 100.33,117.98 99.67,118.64 99.18,118.64
M_A_DQ63: length 87.3
  TOP w0.089: 100.53,117.32 100.39,117.32 99.42,118.28 CPU1.AH1
  TOP w0.165: 100.53,117.32 100.54,117.32 106.43,117.32 137.81,148.7 137.81,155.34 137.97,155.51 139.61,155.51 139.78,155.67 139.78,156 139.61,156.17 137.97,156.17 137.81,156.33 137.81,156.66 137.97,156.83 139.61,156.83 139.82,157.04 139.82,157.27 139.61,157.49 137.97,157.49 137.81,157.65 137.81,157.98 137.97,158.15 139.61,158.15 139.78,158.31 139.78,167.61 139.09,168.3 139.09,169.28 139.91,170.1 DIMM1.280
M_A_DQS_DN0: length 81.5
  TOP w0.089: CPU1.AF39 59.91,117.37 59.57,117.03 58.99,117.03 58.9,116.94 58.55,116.94 58.09,117.4 57.65,117.4 55.36,115.11 55.15,115.11 55.12,115.07
  TOP w0.102: DIMM1.152 26.33,171.93 26.31,171.79 25.9,171.38 25.9,169.94 26.76,169.08 26.76,168.31 25.97,167.52 25.97,166.17 25.94,166.14 25.94,166.12
  TOP w0.165: 55.12,115.07 47.35,115.07 38.07,124.35 38.07,134.3 25.94,146.43 25.94,166.12
M_A_DQS_DN1: length 69.3
  TOP w0.089: 54.99,121.16 55,121.16 55.03,121.2 58.13,121.2 58.27,121.06 58.27,120.85 58.5,120.62 58.5,120.62 58.53,120.6 58.88,120.6 58.98,120.7 59.08,120.7 59.18,120.7 59.66,120.7 59.74,120.79 59.74,121.06 59.82,121.13 60.18,121.13 CPU1.AK39
  TOP w0.102: 36.11,166.19 36.11,166.22 36.14,166.25 36.14,167.39 35.22,168.31 35.22,169.2 36.11,170.09 36.11,171.35 35.92,171.54 35.87,171.57 35.83,171.59 35.69,171.55 DIMM1.163
  TOP w0.165: 54.99,121.16 49.72,121.16 44.36,126.53 44.36,138.42 35.93,146.85 35.93,153.04 36.11,153.23 36.11,166.19
M_A_DQS_DN2: length 57
  TOP w0.089: 56.44,126.64 56.44,126.62 56.48,126.58 56.48,126.34 57.9,124.92 57.99,124.92 58.29,124.61 58.29,124.51 58.55,124.26 58.91,124.26 59.07,124.34 59.63,124.34 59.97,124.68 CPU1.AP39
  TOP w0.102: DIMM1.174 45.04,171.91 45,171.77 45,171.77 44.87,171.7 44.63,171.46 44.63,170.26 45.46,169.43 45.46,168.39 44.63,167.56 44.63,166.26 44.59,166.23 44.59,166.22
  TOP w0.165: 56.44,126.64 56.44,132.28 53,135.72 53,156.05 44.59,164.45 44.59,166.22
M_A_DQS_DN3: length 49.1
  TOP w0.089: 62.3,132.03 62.3,132.01 62.34,131.97 62.34,131.48 62.45,131.37 62.45,129.88 62.65,129.4 62.65,128.23 CPU1.AU36
  TOP w0.102: 55.07,165.74 55.06,165.76 55.06,165.79 54.79,166.06 54.79,167.46 53.97,168.28 53.97,169.31 54.81,170.15 54.81,171.34 54.59,171.56 54.53,171.59 54.39,171.55 DIMM1.185
  TOP w0.165: 62.3,132.03 62.3,158.51 55.13,165.68 55.07,165.74
M_A_DQS_DN4: length 53.3
  TOP w0.089: CPU1.AW7 91.74,128.06 91.86,127.94 91.99,127.94 92.1,128.05 92.1,129.62 92.22,129.74 92.22,130.4 95.18,133.35 95.18,133.41 95.19,133.42
  TOP w0.102: 108.54,166.12 108.55,166.12 108.6,166.12 108.64,166.16 109.24,166.76 109.24,167.56 110.02,168.35 110.02,169.3 109.21,170.11 109.21,171.42 109.51,171.72 109.6,171.77 109.64,171.91 DIMM1.244
  TOP w0.165: 95.19,133.42 96.02,134.25 96.02,150.96 107.86,162.8 107.86,165.43 108.54,166.12
M_A_DQS_DN5: length 57.3
  TOP w0.102: DIMM1.255 118.99,171.55 119.13,171.59 119.21,171.55 119.22,171.54 119.42,171.34 119.42,170.47 118.59,169.64 118.59,168.37 119.44,167.53 119.44,166.51 119.41,166.48 119.41,166.46 ; 97.97,128.65 97.72,128.4 97.58,128.36 97.4,128.23 97.16,128 96.83,127.63 96.77,127.25 96.77,127.24 96.43,126.9 96.18,126.84 CPU1.AU3
  TOP w0.165: 119.41,166.46 119.41,164.87 106.27,151.73 106.27,136.48 100.31,130.52 99.84,130.52 97.97,128.65
M_A_DQS_DN6: length 67.6
  TOP w0.089: 101.75,123.49 101.73,123.49 101.69,123.46 99.84,123.46 99.6,123.21 98.3,123.21 98.07,123.28 97.72,123.28 97.47,123.19 96.07,123.19 CPU1.AN3
  TOP w0.102: 127.81,165.8 127.81,165.83 127.84,165.86 127.84,167.46 128.77,168.39 128.77,169.38 127.91,170.25 127.91,171.42 128.21,171.72 128.3,171.77 128.34,171.91 DIMM1.266
  TOP w0.165: 127.81,165.8 127.81,160.96 123.65,156.79 123.65,146.47 113.61,136.43 113.61,135.13 101.97,123.49 101.75,123.49
M_A_DQS_DN7: length 78.6
  TOP w0.089: CPU1.AJ3 95.76,119.36 96.3,119.56 96.47,119.57 97.19,119.59 97.24,119.59 97.56,119.6 97.67,119.62 97.98,119.62 98.35,119.39 99.99,119.39 100.52,118.86 101.38,118.86 101.42,118.9
  TOP w0.102: DIMM1.277 137.68,171.53 137.88,171.53 138.12,171.3 138.12,170.1 137.25,169.24 137.25,168.33 138.15,167.44 138.15,166.58 137.89,166.32 137.85,166.32 137.83,166.3
  TOP w0.165: 137.83,166.3 136.27,164.74 136.27,149.34 105.83,118.9 101.42,118.9
M_A_DQS_DP0: length 81.6
  TOP w0.089: CPU1.AF38 60.72,117.63 60.33,117.77 59.03,117.77 58.88,117.78 58.78,117.79 58.6,117.79 58.53,117.78 58.13,117.59 57.57,117.59 55.28,115.3 55.15,115.3 55.11,115.34
  TOP w0.102: 26.21,166.12 26.21,166.14 26.18,166.17 26.18,167.44 26.97,168.23 26.97,169.16 26.1,170.02 26.1,171.3 26.39,171.59 26.53,171.55 DIMM1.153
  TOP w0.165: 55.11,115.34 47.46,115.34 38.34,124.46 38.34,134.41 26.21,146.54 26.21,166.12
M_A_DQS_DP1: length 69.3
  TOP w0.089: CPU1.AK38 60.44,121.38 60.07,121.42 59.16,121.42 58.88,121.45 58.44,121.45 58.23,121.39 55.04,121.39 55,121.43 54.99,121.43
  TOP w0.102: DIMM1.164 35.88,171.91 35.92,171.77 35.93,171.77 36.04,171.71 36.31,171.43 36.31,170.01 35.43,169.12 35.43,168.4 36.35,167.48 36.35,166.25 36.38,166.22 36.38,166.19
  TOP w0.165: 54.99,121.43 49.83,121.43 44.62,126.64 44.62,138.54 36.2,146.96 36.2,152.93 36.38,153.12 36.38,166.19
M_A_DQS_DP2: length 57
  TOP w0.089: CPU1.AP38 60.53,125.08 59.03,125.08 58.92,125.09 58.8,125.11 57.98,125.11 56.67,126.42 56.67,126.6 56.7,126.63 56.7,126.64
  TOP w0.102: DIMM1.175 45.23,171.55 45.09,171.59 44.99,171.54 44.83,171.37 44.83,170.35 45.66,169.52 45.66,168.31 44.83,167.47 44.83,166.26 44.86,166.23 44.86,166.22
  TOP w0.165: 56.7,126.64 56.7,132.39 53.26,135.83 53.26,156.16 44.86,164.56 44.86,166.22
M_A_DQS_DP3: length 49.1
  TOP w0.089: 62.57,132.03 62.57,132.01 62.53,131.97 62.53,131.56 62.64,131.45 62.64,130.45 62.73,130.36 63.14,130.36 63.35,130.15 63.35,130.09 63.35,130.09 63.35,129.74 63.35,129.74 63.35,129.07 62.95,128.66 62.95,128.42 CPU1.AV36
  TOP w0.102: DIMM1.186 54.58,171.91 54.62,171.77 54.71,171.72 55.01,171.43 55.01,170.07 54.17,169.23 54.17,168.37 54.99,167.55 54.99,166.14 55.16,165.97 55.16,165.97 55.2,165.93 55.25,165.93 55.26,165.93
  TOP w0.165: 55.26,165.93 55.4,165.79 62.57,158.62 62.57,132.03
M_A_DQS_DP4: length 53.3
  TOP w0.089: CPU1.AV7 91.74,127.61 91.89,127.75 92.07,127.75 92.29,127.97 92.29,128.13 92.29,128.13 92.29,129.54 92.41,129.66 92.41,130.32 95.31,133.22 95.37,133.22 95.38,133.24
  TOP w0.102: 108.73,165.93 108.73,165.97 109.44,166.68 109.44,167.48 110.23,168.26 110.23,169.38 109.42,170.2 109.42,171.34 109.63,171.56 109.69,171.59 109.83,171.55 DIMM1.245
  TOP w0.165: 108.73,165.93 108.13,165.32 108.13,162.69 96.28,150.85 96.28,134.14 95.38,133.24
M_A_DQS_DP5: length 57.3
  TOP w0.102: CPU1.AU2 96.33,126.51 96.84,127.02 97.45,127.02 98.19,127.76 98.19,128.49 ; 119.68,166.46 119.68,166.48 119.64,166.51 119.64,167.61 118.8,168.46 118.8,169.56 119.63,170.39 119.63,171.42 119.34,171.71 119.22,171.77 119.18,171.91 DIMM1.256
  TOP w0.165: 119.68,166.46 119.68,164.76 106.54,151.62 106.54,136.37 100.42,130.25 99.95,130.25 98.19,128.49
M_A_DQS_DP6: length 67.5
  TOP w0.089: CPU1.AN2 96.46,123 96.79,123 96.86,122.93 96.86,122.63 96.95,122.53 97.53,122.53 97.72,122.43 98.07,122.43 98.35,122.71 98.35,122.88 98.48,123.02 99.67,123.02 99.92,123.27 101.69,123.27 101.73,123.23 101.75,123.23
  TOP w0.102: DIMM1.267 128.53,171.55 128.39,171.59 128.33,171.56 128.11,171.33 128.11,170.33 128.97,169.47 128.97,168.31 128.05,167.38 128.05,165.86 128.08,165.83 128.08,165.8
  TOP w0.165: 101.75,123.23 102.08,123.23 113.87,135.02 113.87,136.32 123.91,146.36 123.91,156.68 128.08,160.85 128.08,165.8
M_A_DQS_DP7: length 78.5
  TOP w0.089: CPU1.AJ2 96.73,119.2 96.9,119.02 96.9,118.9 96.98,118.82 97.62,118.82 97.67,118.77 98.02,118.77 98.45,119.2 99.91,119.2 100.44,118.67 101.32,118.67 101.33,118.67 101.37,118.67 101.41,118.63 101.42,118.63
  TOP w0.102: DIMM1.278 138.01,172.16 138.01,171.72 138.32,171.41 138.32,170.02 137.46,169.15 137.46,168.42 138.35,167.52 138.35,166.49 138.04,166.18 138.04,166.13 138.02,166.12
  TOP w0.165: 101.42,118.63 105.94,118.63 136.54,149.23 136.54,164.63 138.02,166.12
M_A_ODT0: length 47.4
  TOP w0.089: CPU1.AW11 86.51,129.88 86.51,130.44 87.04,130.97
  TOP w0.165: DIMM1.87 98.7,166.68 98.7,166.07 99.03,165.74 99.03,165.23 98.7,164.9 98.7,164.34 99.06,163.98 99.06,163.37 98.7,163.02 98.7,162.13 90.35,153.78 90.35,151.52 90.35,138.45 90.19,138.29 89.75,138.29 89.59,138.12 89.59,137.79 89.75,137.63 90.19,137.63 90.35,137.46 90.35,137.13 90.19,136.97 89.75,136.97 89.59,136.8 89.59,136.47 89.75,136.31 90.19,136.31 90.35,136.14 90.35,135.81 90.19,135.65 89.75,135.65 89.59,135.48 89.59,135.15 89.75,134.99 90.19,134.99 90.35,134.82 90.35,134.27 87.04,130.97
M_A_ODT1: length 50
  TOP w0.089: 86.18,127.13 86.11,127.06 86.09,127.06 86.05,127.03 85.72,127.03 85.68,127.06 83.74,127.06 CPU1.AU14
  TOP w0.165: 86.18,127.13 86.18,127.15 86.29,127.26 86.29,127.45 91.62,132.78 91.62,153.09 100.6,162.07 100.6,164.93 100.77,165.1 101.5,165.1 101.66,165.27 DIMM1.91
M_A_PARITY: length 50
  TOP w0.216: DIMM1.222 89.76,171.68 88.7,171.68 88.29,172.09 88.29,173.06 88.07,173.28 87.46,173.28 87.24,173.06 87.24,156.3 85.87,154.93 85.87,135.26 85.7,135.09 85.7,135.08 82.23,131.61 CPU1.AY15
M_B_A0: length 70.4
  TOP w0.216: CPU1.AL19 v2(79.03,121.48)
  L3 w0.089: 78.58,124.21 78.58,121.93 v2(79.03,121.48)
  L3 w0.191: DIMM2.79 88.83,176.11 88.62,175.9 88.62,175.35 88.84,175.14 89.62,175.14 89.87,174.89 89.87,174.56 89.67,174.37 88.84,174.37 88.62,174.16 88.62,173.65 88.81,173.46 91.26,173.46 91.46,173.25 91.46,172.16 90.68,171.37 90.68,170.09 91.44,169.33 91.44,168.27 90.91,167.74 89.66,167.74 88.62,166.7 88.62,162.97 89.38,162.2 89.38,156.64 82.96,150.21 82.96,137.94 79.21,134.2 79.21,131.92 78.61,131.32 78.61,128.52 78.97,128.17 78.97,124.6 78.58,124.21
M_B_A1: length 71.5
  TOP w0.216: CPU1.AL22 v2(75.37,121.48)
  L3 w0.089: v2(75.37,121.48) 74.95,121.91 74.95,123.46 75.18,123.98 75.18,127.86 74.43,128.62 74.43,131.35 74.92,131.84 74.92,132.36
  L3 w0.191: DIMM2.72 80.41,175.12 80.6,174.93 82.4,174.93 82.52,174.8 82.52,173.48 82.82,173.19 82.82,172.19 81.97,171.34 81.97,170.08 81.41,169.52 81.41,168.27 81.96,167.72 81.96,165.86 83.18,164.64 84.76,164.64 84.95,164.45 84.95,161.14 84.73,160.92 83.12,160.92 82.93,160.73 82.93,160.35 83.12,160.16 84.73,160.16 84.92,159.97 84.92,159.55 84.73,159.36 82.66,159.36 82.47,159.17 82.47,155.24 79.08,151.85 79.08,139.6 74.92,135.44 74.92,132.36
M_B_A2: length 69.2
  TOP w0.216: v2(75.37,122.4) CPU1.AM22
  L3 w0.089: 75.36,132.37 75.44,132.3 75.44,123.91 75.8,123.55 75.8,123.17 v2(75.37,122.4)
  L3 w0.191: 75.36,132.37 75.36,135.25 79.52,139.41 79.52,151.66 82.92,155.06 82.92,157.7 83.79,158.57 85.14,158.57 85.39,158.82 85.39,164.91 85.2,165.1 83.69,165.1 82.26,166.54 82.26,167.73 82.96,168.43 82.96,169.42 82.26,170.12 82.26,171.22 83.11,172.07 83.11,174.9 82.11,175.9 82.11,176.44 81.31,177.24 81.31,177.85 80.41,178.75 DIMM2.216
M_B_A3: length 68.8
  TOP w0.216: v2(74.46,123.31) CPU1.AM23
  L3 w0.089: 74.47,132.36 74.47,131.93 74.24,131.7 74.21,131.7 74.17,131.66 74.17,127.86 74.85,127.18 74.85,125.32 74.86,125.31 74.86,124.96 74.85,124.96 74.85,124.87 74.63,124.65 74.28,124.65 74.03,124.4 74.03,124.05 74.28,123.8 74.37,123.8 74.46,123.71 v2(74.46,123.31)
  L3 w0.191: 74.47,132.36 74.47,135.62 78.63,139.78 78.63,152.03 81.08,154.48 81.08,155.41 81.27,155.6 81.8,155.6 81.99,155.79 81.99,160.05 81.72,160.32 81.24,160.32 81.05,160.51 81.05,160.97 81.24,161.16 81.81,161.16 82,161.35 82,161.52 82.19,161.71 83.73,161.71 83.94,161.92 83.94,162.28 83.75,162.47 82.18,162.47 81.99,162.66 81.99,163.04 82.18,163.23 83.73,163.23 83.94,163.45 83.94,163.8 83.75,163.99 82.18,163.99 81.86,164.31 81.86,165.07 80.56,166.38 80.56,167.73 81.11,168.29 81.11,169.43 80.56,169.99 80.56,171.36 81.23,172.03 81.23,173.94 81.05,174.12 80.39,174.12 80.06,174.45 80.06,175.61 DIMM2.71
M_B_A4: length 67.9
  TOP w0.216: v2(74.43,125.14) CPU1.AP23
  L3 w0.089: v2(74.43,125.14) 73.89,125.68 73.89,132.25 74.03,132.39
  L3 w0.191: DIMM2.214 78.71,179.35 79.55,178.51 79.55,177.37 78.86,176.67 78.86,175.62 79.71,174.77 79.71,172.01 80.26,171.45 80.26,170.87 80.26,170.05 79.71,169.5 79.71,168.22 80.27,167.66 80.27,165.45 80.43,165.29 80.43,164.34 80.75,164.02 81.36,164.02 81.55,163.83 81.55,163.44 81.36,163.25 80.75,163.25 80.56,163.06 80.56,160.07 80.75,159.87 81.36,159.87 81.55,159.68 81.55,159.3 81.36,159.11 80.75,159.11 80.56,158.92 80.56,158.54 80.75,158.35 81.36,158.35 81.55,158.16 81.55,157.78 81.36,157.59 80.75,157.59 80.56,157.4 80.56,157.02 80.75,156.83 81.36,156.83 81.55,156.64 81.55,156.26 81.36,156.06 80.75,156.06 80.56,155.87 80.56,154.6 78.13,152.17 78.13,139.91 74.03,135.81 74.03,132.39
M_B_A5: length 69.8
  TOP w0.216: CPU1.AL23 v2(74.46,122.4)
  L3 w0.089: v2(74.46,122.4) 73.12,123.74 73.12,129.66 73.58,130.13 73.58,130.81
  L3 w0.191: 73.58,130.81 73.58,135.99 77.07,139.48 77.07,140.74 77.26,140.93 77.5,140.93 77.69,141.12 77.69,141.5 77.5,141.69 77.26,141.69 77.07,141.88 77.07,142.26 77.26,142.45 77.5,142.45 77.69,142.64 77.69,143.02 77.5,143.21 77.26,143.21 77.07,143.4 77.07,143.79 77.26,143.98 77.5,143.98 77.69,144.17 77.69,144.55 77.5,144.74 77.26,144.74 77.07,144.93 77.07,145.31 77.26,145.5 77.5,145.5 77.69,145.69 77.69,146.07 77.5,146.26 77.26,146.26 77.07,146.45 77.07,149.53 77.26,149.72 77.5,149.72 77.69,149.91 77.69,150.29 77.5,150.48 77.26,150.48 77.07,150.67 77.07,151.85 80.06,154.84 80.06,158.69 79.71,159.04 79.71,159.52 79.98,159.8 79.98,160.29 79.71,160.57 79.71,161.05 80.09,161.43 80.09,163.41 79.9,163.61 79.2,163.61 79.01,163.8 79.01,164.18 79.2,164.37 79.79,164.37 79.98,164.56 79.98,164.94 79.79,165.13 79.2,165.13 79.01,165.32 79.01,166.4 78.86,166.55 78.86,167.71 79.41,168.26 79.41,169.56 78.86,170.11 78.86,171.49 79.41,172.05 79.41,172.94 78.56,173.79 78.56,176.68 77.86,177.38 DIMM2.213
M_B_A6: length 59.9
  TOP w0.089: CPU1.AW26 72.19,129.25 72.76,129.83 72.76,130.84 v2(72.74,130.85)
  L3 w0.089: v2(72.74,130.85) 73.2,131.31 73.2,134.16 73.14,134.23 73.14,135.08
  L3 w0.191: 73.14,135.08 73.14,136.17 73.4,136.44 75.14,138.17 75.14,139.2 75.39,139.45 76.41,139.45 76.63,139.66 76.63,140.11 76.43,140.3 75.17,140.3 74.98,140.49 74.98,140.87 75.17,141.06 76.43,141.06 76.63,141.25 76.63,141.63 76.43,141.82 75.17,141.82 74.98,142.01 74.98,142.39 75.17,142.58 76.43,142.58 76.63,142.77 76.63,143.15 76.43,143.35 75.17,143.35 74.98,143.54 74.98,143.92 75.17,144.11 76.43,144.11 76.63,144.3 76.63,152.03 79.12,154.53 79.12,154.54 79.13,154.55 79.13,162.39 78.57,162.95 78.57,167.71 78.01,168.27 78.01,169.55 78.56,170.1 78.56,171.47 78.01,172.03 78.01,175.96 DIMM2.69
M_B_A7: length 59.5
  TOP w0.089: CPU1.AY26 72.17,130.41 72.09,130.49 72.09,131.04 72.09,131.29 71.91,131.47 71.91,132.9 v2(72.39,133.38)
  L3 w0.191: DIMM2.211 76.3,179.76 76.3,177.26 76.86,176.7 76.86,175.57 76.57,175.27 76.57,173.29 76.31,173.03 76.31,172.08 76.86,171.52 76.86,170.21 76.31,169.65 76.31,168.22 76.86,167.66 76.86,166.84 76.46,166.43 76.46,155.75 76.65,155.56 77.74,155.56 77.93,155.37 77.93,154.98 77.74,154.79 76.65,154.79 76.46,154.6 76.46,153.24 75.62,152.4 75.62,150.46 75.43,150.27 74.1,150.27 73.91,150.08 73.91,149.64 74.1,149.45 75.43,149.45 75.62,149.26 75.62,148.88 75.43,148.69 74.1,148.69 73.91,148.5 73.91,138.37 72.25,136.71 72.25,133.53 v2(72.39,133.38)
M_B_A8: length 63.3
  TOP w0.089: v2(72.6,132.67) 72.16,132.22 72.16,131.65 72.28,131.53 72.28,130.96 72.28,130.57 72.49,130.35 72.49,129.85 72.35,129.7 72.11,129.7 71.85,129.44 71.85,127.75 CPU1.AU26
  L3 w0.191: v2(72.6,132.67) 72.87,132.93 72.87,133.58 72.69,133.76 72.69,136.53 74.5,138.33 74.5,144.81 74.69,145 75.99,145 76.18,145.19 76.18,145.58 75.99,145.77 74.69,145.77 74.5,145.96 74.5,146.34 74.69,146.53 75.99,146.53 76.18,146.72 76.18,147.1 75.99,147.29 74.69,147.29 74.5,147.48 74.5,147.86 74.69,148.05 75.99,148.05 76.18,148.24 76.18,152.22 76.33,152.36 76.33,152.37 78.68,154.73 78.68,162.2 77.16,163.73 77.16,164.37 77.35,164.56 77.84,164.56 78.03,164.75 78.03,165.13 77.84,165.32 77.35,165.32 77.16,165.51 77.16,167.66 77.71,168.21 77.71,169.53 77.16,170.09 77.16,171.49 77.71,172.05 77.71,173.06 77.43,173.34 77.43,175.26 77.16,175.54 77.16,177.56 DIMM2.68
M_B_A9: length 60.1
  TOP w0.102: v2(71.12,133.73) 71.12,132.94 71.3,132.77 71.3,131.43 71.68,131.04 71.68,130.64 71.59,130.55 71.59,129.98 71.26,129.64 CPU1.AW27
  L3 w0.191: DIMM2.66 75.16,177.56 75.16,174.14 74.47,173.45 74.47,172.18 73.66,171.37 73.66,170.05 74.4,169.32 74.4,168.22 73.73,167.56 73.73,162.51 73.92,162.32 75.38,162.32 75.57,162.13 75.57,161.75 75.38,161.56 73.92,161.56 73.73,161.37 73.73,160.99 73.92,160.8 75.38,160.8 75.57,160.61 75.57,160.22 75.38,160.03 73.92,160.03 73.73,159.84 73.73,159.46 73.92,159.27 75.38,159.27 75.57,159.08 75.57,153.77 72.99,151.19 72.99,138.77 71.12,136.91 v2(71.12,133.73)
M_B_A10: length 67
  TOP w0.216: v2(79.95,125.21) 79.49,124.74 CPU1.AP18
  L3 w0.089: v2(79.95,125.21) 79.96,125.21 80.36,125.61 80.36,134.09 80.59,134.32
  L3 w0.191: DIMM2.225 93.16,177.31 92.46,176.61 92.46,175.61 93.31,174.76 93.31,172.07 93.98,171.4 93.98,170.18 93.31,169.51 93.31,168.21 94.08,167.44 94.08,165.44 93.89,165.25 92.11,165.25 91.92,165.06 91.92,164.1 91.73,163.91 91.35,163.91 91.16,164.1 91.16,165.06 90.97,165.25 90.53,165.25 90.28,165.01 90.28,156.15 84.1,149.97 84.1,137.83 80.59,134.32
M_B_A11: length 63.6
  TOP w0.089: 71.83,129.86 71.59,129.62 71.59,127.76 CPU1.AU27
  TOP w0.102: 71.83,129.86 71.83,130.43 71.89,130.48 71.89,131.16 71.63,131.42 71.63,134.32 v2(71.68,134.37)
  L3 w0.191: DIMM2.210 75.31,178.94 76.01,178.24 76.01,177.21 75.46,176.65 75.46,175.6 75.74,175.31 75.74,173.28 76.01,173.01 76.01,172.1 75.29,171.37 75.29,170.23 76.01,169.5 76.01,168.19 75.45,167.63 75.45,166.58 76.02,166.02 76.02,165.61 75.83,165.42 74.61,165.42 74.42,165.23 74.42,164.85 74.61,164.66 75.83,164.66 76.02,164.47 76.02,164.09 75.83,163.9 74.61,163.9 74.42,163.71 74.42,163.33 74.61,163.14 75.83,163.14 76.02,162.95 76.02,153.59 73.43,151 73.43,138.52 71.68,136.77 v2(71.68,134.37)
M_B_A12: length 62.1
  TOP w0.102: 70.92,132.36 70.92,131.14 70.82,131.04 70.82,130.65 70.92,130.55 70.92,129.04 71.26,128.7 CPU1.AV27
  TOP w0.216: 70.92,132.36 70.57,132.7 v2(70.57,134.68)
  L3 w0.191: DIMM2.65 74.46,174.51 72.98,173.03 72.87,172.66 72.87,172.14 72.03,171.29 72.03,170.03 72.62,169.45 72.62,168.22 72,167.61 72,166.4 73.23,165.18 73.23,158.49 73.42,158.3 74.94,158.3 75.13,158.11 75.13,157.73 74.94,157.54 73.42,157.54 73.23,157.35 73.23,156.97 73.42,156.78 74.94,156.78 75.13,156.59 75.13,156.21 74.94,156.02 73.01,156.02 72.82,155.83 72.82,155.45 73.01,155.26 74.94,155.26 75.13,155.07 75.13,154.68 74.94,154.49 73.42,154.49 73.23,154.3 73.23,152.06 72.54,151.37 72.54,138.96 70.57,136.99 v2(70.57,134.68)
M_B_A13: length 65.7
  TOP w0.216: v2(82.72,126.09) CPU1.AR15
  L3 w0.089: 83.46,130.18 83.15,129.87 83.15,126.52 v2(82.72,126.09)
  L3 w0.191: 83.46,130.18 83.83,130.54 83.83,131.84 87.55,135.56 87.55,148.26 95.66,156.37 95.66,158.22 99.8,162.36 99.8,165.28 100.84,166.32 100.84,167.54 101.68,168.38 101.68,169.42 100.96,170.14 100.96,171.39 100.53,171.82 100.52,171.82 100.11,172.23 100.11,173.95 99.13,174.93 99.13,176.41 98.32,177.22 98.32,178.54 99.11,179.32 DIMM2.232
M_B_A14: length 71
  TOP w0.216: CPU1.AL17 v2(80.86,121.48)
  L3 w0.089: v2(80.86,121.48) 81.28,121.91 81.28,122.57 81.03,122.82 80.73,122.82 80.64,122.91 80.64,123.86 80.46,124.05 80.46,124.4 81.11,125.05 81.11,125.42 81.25,125.56 81.25,130.07 81.74,130.56 81.74,131.33
  L3 w0.191: 81.74,131.33 81.74,133.58 85.47,137.3 85.47,149.25 93.34,157.13 93.34,162.69 94.54,163.88 95.68,163.88 96.3,164.5 96.3,165.67 97.26,166.63 97.26,167.59 98.11,168.44 98.11,169.27 97.3,170.08 97.3,171.19 96.45,172.04 96.45,173.06 95.83,173.69 95.83,176.33 94.92,177.24 94.92,178.43 95.71,179.22 DIMM2.228
M_B_A15: length 66.1
  TOP w0.216: CPU1.AP16 81.32,124.71 v2(81.77,125.14)
  L3 w0.089: v2(81.77,125.14) 81.79,125.16 81.79,125.35 81.83,125.38 81.83,127.75 82.22,128.14
  L3 w0.191: DIMM2.86 97.56,177.56 97.56,173.76 98.32,173 98.32,172.14 99.14,171.32 99.14,170.03 99.81,169.35 99.81,168.44 98.96,167.59 98.96,166.7 98.01,165.75 98.01,163.93 96.78,162.7 96.78,162.43 97.44,161.77 97.44,161.5 97.17,161.23 96.9,161.23 96.24,161.89 95.97,161.89 95.7,161.62 95.7,161.35 96.36,160.69 96.36,160.42 96.09,160.15 95.82,160.15 95.16,160.81 94.89,160.81 94.51,160.43 94.51,156.82 86.51,148.82 86.51,136.19 82.93,132.61 82.93,130.81 82.22,130.1 82.22,128.14
M_B_A16: length 68.3
  TOP w0.216: CPU1.AN18 79.55,123.77 79.94,123.37 v2(79.94,122.4)
  L3 w0.089: v2(79.94,122.4) 80.22,122.67 80.22,124.5 80.86,125.15 80.86,125.52 80.87,125.52 80.87,133.34 81.06,133.52
  L3 w0.191: 81.06,133.52 85.02,137.49 85.02,149.44 91.19,155.6 91.19,155.67 91.2,155.68 91.2,157.4 91.53,157.73 92.34,157.73 92.53,157.92 92.53,158.31 92.34,158.5 91.45,158.5 91.26,158.69 91.26,159.04 91.48,159.26 92.67,159.26 92.86,159.45 92.86,162.83 94.35,164.33 95.47,164.33 95.86,164.72 95.86,167.69 96.57,168.4 96.57,169.34 95.86,170.05 95.86,170.92 95.86,170.92 95.86,171.34 95.01,172.19 95.01,174.66 94.01,175.66 DIMM2.82
M_B_ACT#: length 63.6
  TOP w0.089: CPU1.AU28 70.54,127.42 70.9,127.79 70.9,128.29 70.41,128.78 70.31,128.78 70.3,128.78 70.09,128.78 69.89,128.98 69.89,130.56
  TOP w0.216: 69.89,130.56 69.89,131.28 68.71,132.46 v2(68.71,133.17)
  L3 w0.191: DIMM2.62 71.51,177.71 70.21,176.4 70.21,175.46 67.67,172.92 67.67,172.11 66.85,171.3 66.85,169.98 67.64,169.19 67.64,168.35 66.85,167.56 66.85,166.4 69.85,163.4 69.85,153.87 70.85,152.88 70.85,150.14 70.66,149.95 70.09,149.95 69.9,149.76 69.9,149.38 70.09,149.19 70.66,149.19 70.85,149 70.85,148.62 70.66,148.43 68.9,148.43 68.71,148.24 68.71,147.86 68.9,147.67 70.66,147.67 70.85,147.47 70.85,147.09 70.66,146.9 68.9,146.9 68.71,146.71 v2(68.71,133.17)
M_B_ALERT#: length 55.2
  TOP w0.102: v2(72.62,131.83) 72.62,131.82 72.95,131.49 73.17,130.95 73.17,130.59 CPU1.AY25
  L3 w0.102: DIMM2.208 73.61,178.89 74.37,178.13 74.37,177.14 73.77,176.54 73.77,175.32 73.3,174.59 72.76,173.35 72.61,172.82 72.61,172.28 72.59,172.2 71.78,171.4 71.78,170.76 71.25,169.04 71.25,168.09 71.75,167.59 71.75,165.18 72.14,164.8 72.14,139.12 70.12,137.1 70.12,133.97 72.26,131.83 v2(72.62,131.83)
M_B_BG0: length 60.8
  TOP w0.089: CPU1.AW28 70.34,129.61 70.68,129.95
  TOP w0.102: v2(70.28,132.16) 70.54,131.9 70.54,130.53 70.68,130.39 70.68,129.95
  L3 w0.191: v2(70.28,132.16) 69.2,133.24 69.2,142.8 69.41,143.01 71.1,143.01 71.29,143.2 71.29,143.58 71.1,143.77 69.34,143.77 69.15,143.96 69.15,144.34 69.34,144.53 71.1,144.53 71.29,144.72 71.29,145.1 71.1,145.29 69.34,145.29 69.15,145.48 69.15,145.87 69.34,146.06 71.1,146.06 71.29,146.25 71.29,153.21 70.31,154.19 70.31,164.21 68.55,165.96 68.55,167.63 69.37,168.44 69.37,169.39 68.55,170.21 68.55,171.4 69.44,172.29 69.44,173 72.55,176.11 DIMM2.63
M_B_BG1: length 60.9
  TOP w0.102: CPU1.AY28 70.26,130.25 70.26,131.44 69.7,132 69.7,133.05 v2(70,133.35)
  L3 w0.191: v2(70,133.35) 69.72,133.64 69.72,137.26 71.74,139.28 71.74,139.73 71.55,139.92 70.12,139.92 69.93,140.11 69.93,140.49 70.12,140.68 71.55,140.68 71.74,140.87 71.74,141.25 71.55,141.44 69.84,141.44 69.65,141.63 69.65,142.01 69.84,142.2 71.55,142.2 71.74,142.39 71.74,164.13 70.23,165.63 70.23,167.54 70.95,168.26 70.95,169.53 70.21,170.28 70.21,171.32 71.04,172.16 71.04,173.35 73.46,175.77 73.46,176.45 72.76,177.15 DIMM2.207
M_B_BS0: length 70.1
  TOP w0.216: CPU1.AL18 v2(79.94,121.48)
  L3 w0.089: 80.81,133.9 80.62,133.72 80.62,125.27 79.86,124.51 79.86,122.91 79.52,122.57 79.52,121.91 v2(79.94,121.48)
  L3 w0.191: DIMM2.81 93.16,175.85 94.71,174.3 94.71,172.07 95.56,171.22 95.56,170.16 94.79,169.39 94.79,168.48 95.56,167.71 95.56,166.63 95.21,166.28 95.21,164.96 95.02,164.77 94.17,164.77 92.38,162.98 90.92,162.98 90.75,162.81 90.75,162.37 90.94,162.18 91.96,162.18 92.15,161.99 92.15,161.61 91.96,161.42 90.94,161.42 90.75,161.23 90.75,160.85 90.94,160.66 92.14,160.66 92.33,160.46 92.33,160.08 92.14,159.89 90.94,159.89 90.75,159.7 90.75,155.87 84.58,149.69 84.58,137.67 80.81,133.9
M_B_BS1: length 70.3
  TOP w0.216: CPU1.AM18 v2(79.03,122.4)
  L3 w0.089: 79.48,123.77 79.48,123.09 79.03,122.64 v2(79.03,122.4)
  L3 w0.191: 79.48,123.77 79.38,123.87 79.38,129.41 79.83,129.87 79.83,134.19 83.54,137.9 83.54,150.04 89.84,156.34 89.84,163.32 89.65,163.51 89.26,163.51 89.07,163.7 89.07,164.08 89.26,164.27 89.57,164.27 89.76,164.47 89.76,164.85 89.57,165.04 89.26,165.04 89.07,165.23 89.07,165.61 89.26,165.8 91.5,165.8 92.33,166.62 92.33,167.49 93.01,168.17 93.01,169.44 92.33,170.13 92.33,171.35 93.01,172.03 93.01,173.82 92.16,174.67 92.16,176.62 91.47,177.32 91.47,178.23 92.31,179.08 DIMM2.224
M_B_CKE0: length 55.1
  TOP w0.165: v2(68.04,132.46) 68.12,132.46 69.43,131.16 CPU1.AY29
  L3 w0.152: v2(68.04,132.46) 68.04,150.36 68.33,150.65 70.05,150.65 70.33,150.92 70.33,152.63 69.33,153.63 69.33,162.38 65.28,166.43 65.28,167.41 66.1,168.24 66.1,169.54 65.28,170.36 65.28,171.47 65.99,172.19 65.99,172.9 68.66,175.57 68.66,176.38 69.99,177.71 DIMM2.60
M_B_CKE1: length 57.4
  TOP w0.089: CPU1.AV29 69.01,128.76 69.01,131.06 68.92,131.15
  TOP w0.165: 68.92,131.15 68.58,131.5 v2(68.07,131.5)
  L3 w0.152: v2(68.07,131.5) 67.83,131.5 67.54,131.79 67.54,150.57 67.59,150.62 67.59,161.43 66.95,163.83 64.83,165.95 64.83,166.73 64.95,166.84 64.95,167.51 65.8,168.36 65.8,169.41 64.95,170.26 64.95,171.4 64.26,172.08 64.26,172.92 64.95,173.61 67.99,175.34 68.35,175.7 68.35,176.54 69.36,177.55 DIMM2.203
M_B_CLK0: length 67.7
  TOP w0.216: CPU1.AM20 v2(77.2,122.4)
  L3 w0.089: 76.52,131.02 76.52,130.99 76.45,130.93 76.45,129.53 75.88,128.95 75.88,124.09 76.94,123.03 76.94,122.66 v2(77.2,122.4)
  L3 w0.127: DIMM2.74 82.11,177.63 82.49,177.25 83.23,177.25 83.53,176.95 84.07,176.95 84.29,177.17 85.16,177.17 85.2,177.22 85.23,177.22
  L3 w0.191: 85.23,177.22 85.82,177.22 86.44,176.6 86.44,157.12 85.94,156.62 85.4,156.62 84.48,157.54 84.21,157.54 83.95,157.28 83.95,157 84.67,156.27 84.67,155.36 80.55,151.23 80.55,138.97 76.52,134.94 76.52,131.02
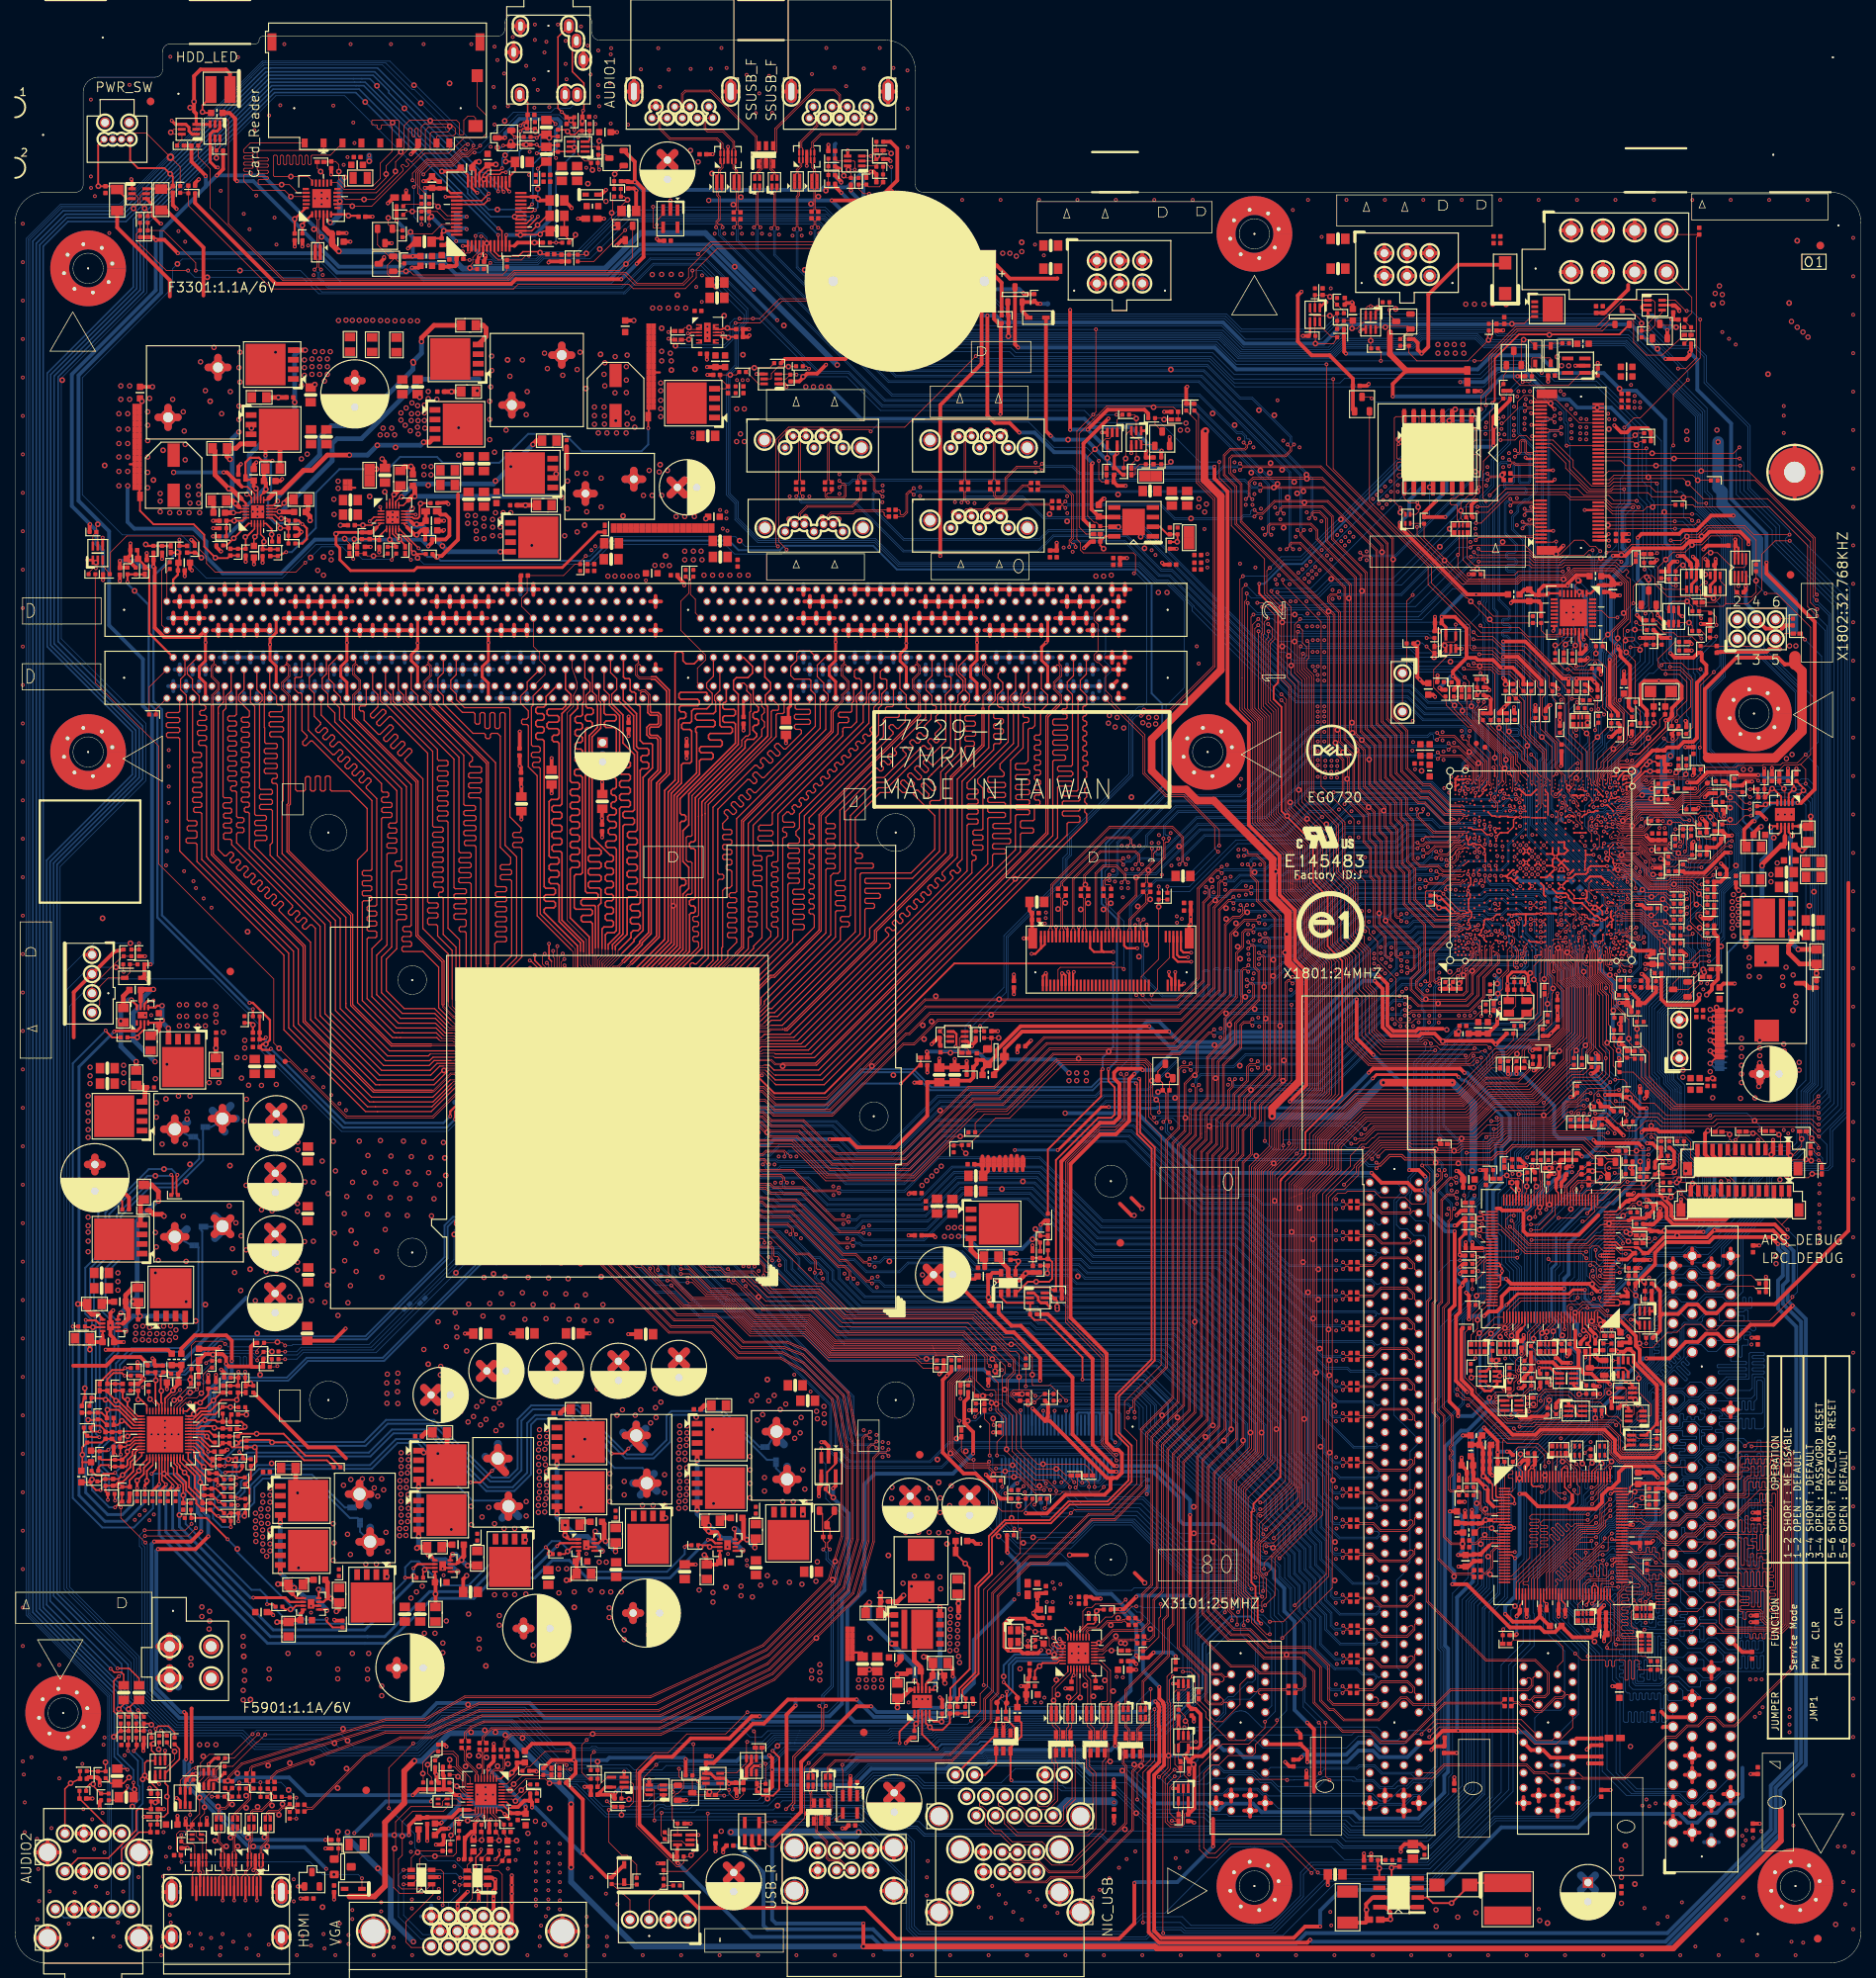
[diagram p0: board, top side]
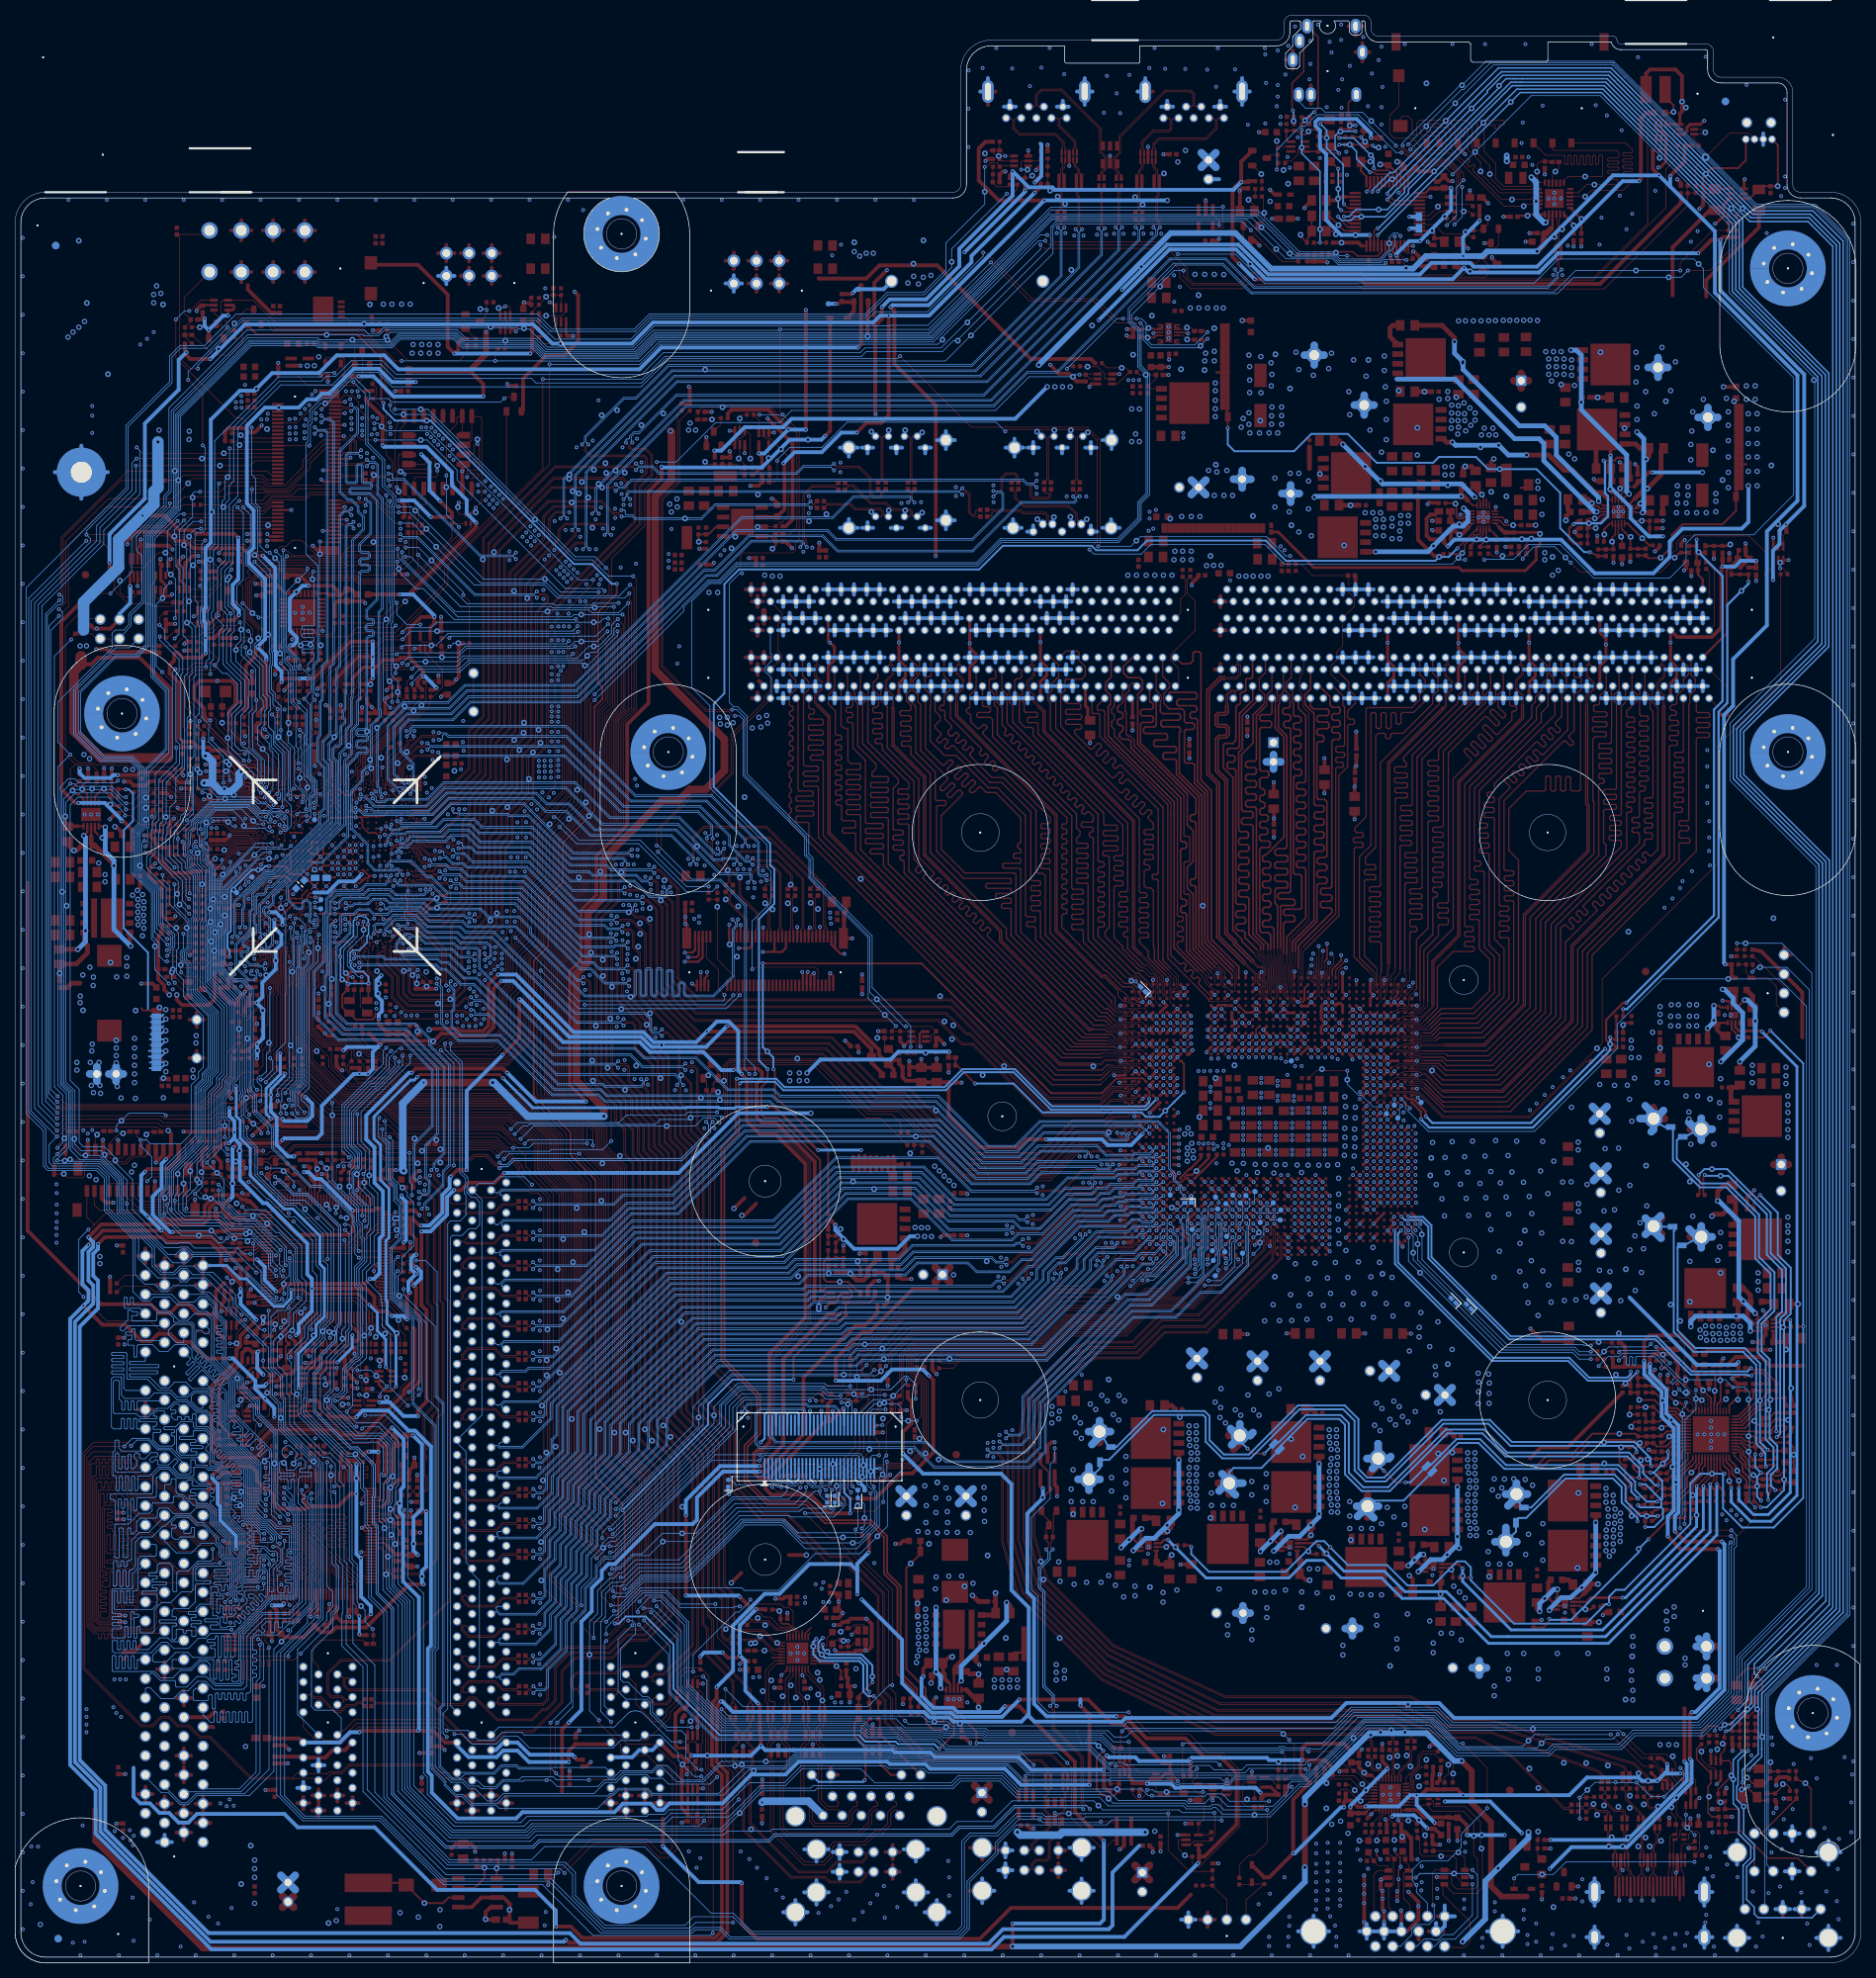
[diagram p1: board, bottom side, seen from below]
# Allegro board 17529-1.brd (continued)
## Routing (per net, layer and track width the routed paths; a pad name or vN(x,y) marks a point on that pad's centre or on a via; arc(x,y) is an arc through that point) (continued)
M_B_CLK1: length 65.6
  TOP w0.216: v2(76.31,125.14) 75.85,124.68 CPU1.AP22
  L3 w0.089: v2(76.31,125.14) 76.67,125.5 76.67,125.81 77.29,126.43 77.29,130.01 77.23,130.07 77.23,130.1
  L3 w0.127: 83.61,178.57 83.58,178.57 83.53,178.62 82.36,178.62 82.03,178.95 82.03,180.47 82.26,180.69 82.26,181.23 DIMM2.218
  L3 w0.191: 77.23,130.1 77.23,134.51 81.37,138.64 81.37,151.05 87.15,156.83 87.15,176.79 85.36,178.57 83.61,178.57
M_B_CLK#0: length 67.7
  TOP w0.216: v2(76.32,122.43) 76.74,122.85 CPU1.AM21
  L3 w0.089: v2(76.32,122.43) 76.66,122.43 76.75,122.52 76.75,122.95 75.69,124.01 75.69,129.03 76.26,129.61 76.26,130.93 76.2,130.99 76.2,131.02
  L3 w0.127: DIMM2.75 82.77,176.11 82.64,176.24 82.64,176.9 82.77,177.02 83.13,177.02 83.44,176.72 84.16,176.72 84.38,176.94 85.16,176.94 85.2,176.9 85.23,176.9
  L3 w0.191: 85.23,176.9 85.69,176.9 86.12,176.47 86.12,157.25 85.81,156.94 85.54,156.94 84.61,157.86 84.08,157.86 83.63,157.41 83.63,156.87 84.36,156.14 84.36,155.49 80.23,151.37 80.23,139.11 76.2,135.07 76.2,131.02
M_B_CLK#1: length 65.6
  TOP w0.216: v2(77.23,125.14) 76.77,124.68 CPU1.AP21
  L3 w0.089: v2(77.23,125.14) 76.86,125.5 76.86,125.73 77.49,126.36 77.49,129.24 77.49,130.01 77.55,130.07 77.55,130.1
  L3 w0.127: DIMM2.219 82.65,180.5 82.48,180.55 82.26,180.33 82.26,179.04 82.46,178.85 83.55,178.85 83.59,178.89 83.61,178.89
  L3 w0.191: 83.61,178.89 85.49,178.89 87.46,176.92 87.46,156.7 81.69,150.92 81.69,138.51 77.55,134.37 77.55,130.1
M_B_CS#0: length 62.9
  TOP w0.165: v2(80.88,124.22) 80.43,124.68 CPU1.AP17
  L3 w0.089: 81.69,128.57 81.53,128.42 81.53,125.5 81.35,125.31 81.35,124.69 v2(80.88,124.22)
  L3 w0.152: 81.69,128.57 81.69,130.07 82.19,130.58 82.19,133.11 85.99,136.91 85.99,149.04 93.96,157.01 93.96,160.69 94.09,160.87 95.94,163.24 96.72,164.01 97.29,165.89 97.58,166.18 97.58,167.48 98.39,168.29 98.39,169.69 97.58,170.49 97.58,171.31 96.73,172.16 96.73,173.74 97.24,174.25 97.24,176.57 96.1,177.71 DIMM2.84
M_B_CS#1: length 63.8
  TOP w0.165: v2(82.69,123.31) CPU1.AN15
  L3 w0.089: v2(82.69,123.31) 83.57,124.19 83.57,127.25 84.48,128.16 84.48,128.7
  L3 w0.152: 84.48,128.7 84.48,131.73 88.14,135.38 88.14,148.11 88.44,148.41 89.37,148.41 89.87,148.91 89.87,149.84 96.37,156.34 96.37,158.14 100.33,162.1 100.33,164.79 102.35,166.81 102.35,167.57 103.22,168.45 103.22,169.65 102.49,170.38 102.49,171.25 101.73,172.01 101.73,174.34 DIMM2.89
M_B_DQ0: length 100.1
  TOP w0.165: CPU1.AE34 v2(64.4,115.99)
  L3 w0.089: 57.08,113.6 58.22,114.73 58.37,114.81 58.5,114.83 58.91,114.83 59.05,114.89 59.36,115.01 59.81,115.28 62.93,115.28 63.15,115.5 63.9,115.5 v2(64.4,115.99) ; DIMM2.5 24,176.19 24.07,176.3 arc(22.95,176.5) 23.43,175.47 23.5,175.43
  L3 w0.102: 23.52,175.13 23.52,175.35 23.5,175.43
  L3 w0.152: 23.52,175.13 23.52,172.11 22.78,171.36 22.78,170.52 23.42,169.88 23.42,168.43 24.23,167.61 24.23,163.25 24.38,163.1 24.99,163.1 25.15,162.94 25.15,162.6 24.99,162.45 24.38,162.45 24.23,162.3 24.23,161.97 24.41,161.79 24.9,161.79 25.06,161.64 25.06,161.3 24.9,161.15 24.41,161.15 24.26,160.99 24.26,160.65 24.41,160.5 24.83,160.5 24.98,160.35 24.98,160 24.83,159.85 24.41,159.85 24.26,159.7 24.26,159.36 24.41,159.2 24.77,159.2 24.92,159.05 24.92,158.71 24.77,158.56 24.41,158.56 24.26,158.4 24.26,158.23 24.6,151.98 24.9,148.16 24.92,147.83 25.13,146.97 25.25,146.71 35.77,136.18 35.77,123.43 45.94,113.26 46.48,113.26 46.48,113.26 55.26,113.26 55.94,113.3 56.53,113.38 56.72,113.42 57.08,113.6
M_B_DQ1: length 98.9
  TOP w0.165: v2(63.48,115.92) 63.48,115.95 63.94,116.42 CPU1.AE35
  L3 w0.089: 24.35,180.83 24.28,180.87 arc(23.8,181.9) 24.92,181.7 24.85,181.59 DIMM2.150 ; 57,114.07 57.26,114.32 57.49,114.53 58.05,114.96 58.36,115.06 58.55,115.09 58.72,115.09 58.95,115.16 59.72,115.57 62.36,115.57 62.66,115.56 62.7,115.57 v2(63.48,115.92)
  L3 w0.102: 24.37,180.53 24.37,180.75 24.35,180.83
  L3 w0.152: 57,114.07 56.58,114 55.37,113.91 46.21,113.91 36.42,123.7 36.42,136.45 25.85,147.03 25.85,163.58 25.91,163.97 25.92,164.18 25.97,164.63 25.97,166.93 25.95,167.49 25.86,167.7 25.65,167.9 25.43,168.14 25.29,168.34 25.17,168.63 25.05,169.16 24.89,169.49 24.51,170.03 24.38,170.34 24.33,170.54 24.33,171.04 24.49,171.42 24.57,171.52 24.79,171.78 24.9,171.94 25.15,172.49 25.15,172.87 25,173.37 24.74,173.78 24.56,174.02 24.43,174.42 24.43,176.2 24.27,176.64 23.58,177.33 23.44,177.6 23.44,177.88 23.58,178.24 24,178.89 24.21,179.36 24.35,180.14 24.37,180.53
M_B_DQ2: length 98.9
  TOP w0.165: CPU1.AH34 v2(64.4,118.74)
  L3 w0.089: 56.6,116.92 57.11,116.92 58.05,117.86 61.09,117.86 61.48,118.25 63.91,118.25 v2(64.4,118.74) ; DIMM2.12 29.95,177.79 30.02,177.9 arc(28.9,178.1) 29.38,177.07 29.45,177.03
  L3 w0.102: 29.45,177.03 29.47,176.95 29.47,176.82
  L3 w0.152: 29.47,176.82 29.25,176.59 29.25,175.15 30.1,174.3 30.1,171.9 29.57,171.37 29.57,170.56 30.4,169.73 30.4,168.2 30.95,167.66 30.95,166.51 30.61,166.17 30.61,155.21 30.76,155.06 31.94,155.06 32.09,154.91 32.09,154.57 31.94,154.41 31.06,154.41 30.91,154.26 30.91,153.92 31.06,153.77 31.94,153.77 32.09,153.61 32.09,153.27 31.94,153.12 31.06,153.12 30.91,152.97 30.91,152.62 31.06,152.47 31.94,152.47 32.09,152.32 32.09,151.98 31.94,151.82 31.09,151.82 30.94,151.67 30.94,151.33 31.09,151.18 31.94,151.18 32.09,151.02 32.09,150.71 31.91,150.52 31.17,150.52 31.01,150.37 31.01,149.99 31.17,149.83 31.94,149.83 32.09,149.68 32.09,145.24 39.45,137.88 39.45,124.73 47.26,116.92 47.8,116.92 48.34,116.92 56.6,116.92
M_B_DQ3: length 97.9
  TOP w0.165: CPU1.AH35 v2(63.48,118.74)
  L3 w0.089: 30.32,179.15 30.3,179.23 30.23,179.27 arc(29.75,180.3) 30.87,180.1 30.8,179.99 DIMM2.157 ; v2(63.48,118.74) 63.02,119.2 61.97,119.2 61.08,118.31 57.93,118.31 57.18,117.56 56.73,117.56
  L3 w0.152: 30.32,179.15 30.32,178.53 30.24,178.45 30.24,177.15 29.55,176.46 29.55,175.43 30.4,174.57 30.4,172.03 30.96,171.48 30.96,170.03 31.82,169.17 31.82,168.22 31.25,167.65 31.25,161.24 31.41,161.09 32.54,161.09 32.69,160.94 32.69,160.59 32.54,160.44 31.83,160.44 31.67,160.29 31.67,159.95 31.83,159.79 32.59,159.79 32.74,159.64 32.74,159.3 32.59,159.15 31.88,159.15 31.72,158.99 31.72,158.65 31.88,158.5 32.65,158.5 32.8,158.35 32.8,158 32.65,157.85 31.93,157.85 31.78,157.7 31.78,157.35 31.93,157.2 32.56,157.2 32.74,157.02 32.74,156.68 32.59,156.53 32.11,156.53 31.95,156.38 31.95,156.03 32.11,155.88 32.59,155.88 32.74,155.73 32.74,145.5 40.09,138.15 40.09,125 47.53,117.56 48.07,117.56 56.73,117.56
M_B_DQ4: length 99.8
  TOP w0.165: CPU1.AD34 v2(64.4,115.08)
  L3 w0.089: DIMM2.3 22.3,176.19 22.37,176.3 arc(21.25,176.5) 21.73,175.47 21.8,175.43 ; v2(64.4,115.08) 63.75,114.61 60.23,114.61 59.65,114.02 58.9,113.23 58.44,112.95 57.64,112.72 57.52,112.64
  L3 w0.102: 21.82,175.13 21.82,175.35 21.8,175.43
  L3 w0.152: 21.82,175.13 21.82,174.98 21.59,174.75 21.6,174.75 21.6,172.09 20.9,171.4 20.9,170.46 21.62,169.74 21.62,168.18 20.98,167.54 20.98,166.7 21.77,165.91 22,165.18 22.06,164.8 22.06,160.67 22.23,160.5 22.49,160.5 22.63,160.36 22.63,160.01 22.48,159.85 22.3,159.85 22.15,159.7 22.15,159.36 22.3,159.21 22.61,159.21 22.76,159.05 22.76,158.72 22.59,158.56 22.17,158.56 22.02,158.41 22.02,158.06 22.17,157.91 22.58,157.91 22.73,157.76 22.73,157.42 22.58,157.26 22.3,157.26 22.15,157.11 22.15,156.77 22.3,156.62 22.62,156.62 22.77,156.46 22.77,153.1 22.82,151.84 22.82,147.8 22.92,147.1 23.72,145.43 34.48,126.56 34.48,122.89 45.41,111.96 47.02,111.96 56.84,111.96 57.52,112.64
M_B_DQ5: length 99.3
  TOP w0.165: CPU1.AD35 63.5,115.09 v2(63.5,115.03)
  L3 w0.089: 22.67,180.53 22.68,180.67 22.65,180.78 22.61,180.85 22.58,180.87 arc(22.1,181.9) 23.22,181.7 23.15,181.59 DIMM2.148 ; 57.31,113.06 57.48,113.1 58.06,113.15 58.3,113.21 58.51,113.32 59.63,114.47 60.1,114.94 62.66,114.94 62.99,114.96 v2(63.5,115.03)
  L3 w0.152: 22.67,180.53 22.65,180.2 22.59,179.84 22.52,179.61 21.96,178.47 21.86,178.15 21.82,177.93 21.82,177.62 21.87,177.38 22,177.16 22.49,176.67 22.59,176.4 22.59,175.97 22.04,173.55 21.95,173.18 21.9,172.69 21.9,172.4 21.93,172.2 22,172 22.14,171.7 22.39,171.29 22.48,171.05 22.48,170.9 22.45,170.69 22.16,169.66 22.04,169.31 21.93,168.92 21.93,168.49 22.03,168.17 22.47,167.35 22.51,167.17 22.53,166.84 22.65,165.95 23.15,162.03 23.37,159.98 23.4,159.35 23.4,159.34 23.88,147.3 23.91,147.09 23.95,146.73 24.07,146.32 24.2,146 35.13,126.83 35.13,123.16 45.67,112.61 46.75,112.61 54.74,112.61 55.46,112.68 56.1,112.77 56.89,112.92 57.31,113.06
M_B_DQ6: length 99.5
  TOP w0.165: CPU1.AG34 v2(64.4,117.82)
  L3 w0.089: v2(64.4,117.82) 63.94,117.37 63.26,117.37 62.92,117.02 59.42,117.02 59.05,116.65 58.01,116.65 56.98,115.62 56.5,115.62 ; 27.75,177.03 27.68,177.07 arc(27.2,178.1) 28.32,177.9 28.25,177.79 DIMM2.10
  L3 w0.102: 27.77,176.79 27.77,176.95 27.75,177.03
  L3 w0.152: 27.77,176.79 27.55,176.57 27.55,174.79 28.4,173.94 28.4,171.98 27.74,171.32 27.74,170.23 28.56,169.41 28.56,168.45 29.25,167.76 29.25,166.69 28.55,165.99 28.55,165.39 28.7,165.23 29.08,165.23 29.24,165.08 29.24,164.74 29.08,164.59 28.73,164.59 28.57,164.43 28.57,164.09 28.73,163.94 29.08,163.94 29.24,163.79 29.24,163.44 29.08,163.29 28.91,163.29 28.75,163.14 28.75,162.8 28.91,162.64 29.06,162.64 29.21,162.49 29.21,162.15 29.06,162 28.85,162 28.7,161.84 28.7,161.5 28.85,161.35 29.01,161.35 29.16,161.2 29.16,160.85 29.01,160.7 28.8,160.7 28.65,160.55 28.65,160.2 28.8,160.05 29.12,160.05 29.27,159.9 29.27,159.56 29.12,159.4 28.83,159.4 28.68,159.25 28.68,158.91 28.83,158.76 29.13,158.76 29.27,158.62 29.27,158.22 29.16,158.11 28.85,158.11 28.7,157.96 28.7,157.61 28.85,157.46 28.98,157.46 29.13,157.31 29.13,157.02 28.93,156.81 28.7,156.81 28.55,156.66 28.55,155.52 27.52,154.5 27.52,147.98 38.05,137.45 38.05,124.3 46.73,115.62 48.34,115.62 48.87,115.62 56.5,115.62
M_B_DQ7: length 98.6
  TOP w0.165: CPU1.AG35 v2(63.48,117.82)
  L3 w0.089: v2(63.48,117.82) 63.23,117.82 62.8,117.4 59.36,117.4 58.9,116.94 57.72,116.94 57.05,116.27 56.55,116.27 ; DIMM2.155 29.1,179.99 29.17,180.1 arc(28.05,180.3) 28.53,179.27 28.6,179.23 28.62,179.15
  L3 w0.152: 28.62,179.15 28.62,178.53 28.54,178.45 28.54,177.13 27.85,176.44 27.85,175.38 28.73,174.5 28.73,172.81 28.73,172.81 28.73,172.24 28.73,172.24 28.73,171.96 29.26,171.42 29.26,169.95 30.1,169.12 30.1,168.27 29.55,167.73 29.55,166.51 29.92,166.14 29.92,153.93 29.77,153.78 28.93,153.78 28.78,153.63 28.78,153.28 28.93,153.13 29.77,153.13 29.92,152.98 29.92,152.64 29.77,152.48 28.96,152.48 28.8,152.33 28.8,151.99 28.96,151.84 29.77,151.84 29.92,151.68 29.92,151.34 29.77,151.19 28.98,151.19 28.83,151.04 28.83,150.69 28.98,150.54 29.77,150.54 29.92,150.39 29.92,146.49 38.7,137.72 38.7,124.57 46.99,116.27 48.07,116.27 48.6,116.27 56.55,116.27
M_B_DQ8: length 88.7
  TOP w0.165: CPU1.AL34 64.86,121.91 64.41,121.47 64.41,121.42 v2(64.41,121.42)
  L3 w0.089: 56.81,119.51 57.25,119.51 57.54,119.8 58.62,120.11 59.99,120.11 60.51,120.62 62.78,120.62 63.19,121.03 64.02,121.03 v2(64.41,121.42) ; DIMM2.16 33.35,177.79 33.42,177.9 arc(32.3,178.1) 32.78,177.07 32.85,177.03
  L3 w0.102: 32.87,176.81 32.87,176.95 32.85,177.03
  L3 w0.152: 32.87,176.81 32.65,176.59 32.65,175.33 33.15,174.83 33.15,173.56 33.5,173.2 33.5,172.11 34.35,171.27 34.35,170.26 33.8,169.72 33.8,168.18 34.37,167.61 34.37,166.3 33.6,165.52 33.6,164.88 33.75,164.72 34.59,164.72 34.75,164.57 34.75,164.23 34.59,164.08 33.75,164.08 33.6,163.92 33.6,163.58 33.75,163.43 34.59,163.43 34.75,163.28 34.75,146.33 42.04,139.04 42.04,125.81 48.34,119.51 56.81,119.51
M_B_DQ9: length 87.9
  TOP w0.165: v2(63.48,121.46) 63.94,121.91 CPU1.AL35
  L3 w0.089: DIMM2.161 34.2,179.99 34.27,180.1 arc(33.15,180.3) 33.63,179.27 33.7,179.23 ; v2(63.48,121.46) 63.26,121.46 62.73,120.92 59.76,120.92 59.52,120.69 58.91,120.62 58.76,120.6 58.07,120.53 57.82,120.29 56.94,120.15
  L3 w0.102: 33.7,179.23 33.72,179.15 33.72,178.93
  L3 w0.152: 33.72,178.93 33.72,177.21 32.95,176.43 32.95,175.85 33.38,175.42 33.38,175.42 34.26,174.54 34.26,173.76 33.81,173.3 33.81,172.24 34.65,171.4 34.65,170.3 35.33,169.62 35.33,168.35 34.67,167.69 34.67,166.81 35.39,166.09 35.39,146.65 40.91,141.13 41.12,141.13 41.59,141.61 41.81,141.61 42.05,141.36 42.05,141.15 41.58,140.68 41.58,140.46 42.68,139.36 42.68,126.07 48.6,120.15 56.94,120.15
M_B_DQ10: length 91.1
  TOP w0.165: CPU1.AK31 v2(68.06,120.57)
  L3 w0.089: DIMM2.23 39.3,176.19 39.37,176.3 arc(38.25,176.5) 38.73,175.47 38.8,175.43 ; 57.02,123.13 57.41,123.52 59.41,123.52 60.05,122.89 64.85,122.89 65.09,122.64 66.33,122.64 67.01,121.97 67.23,121.97 67.6,121.6 67.6,121.03 v2(68.06,120.57)
  L3 w0.102: 38.8,175.43 38.82,175.35 38.82,175.13
  L3 w0.152: 38.82,175.13 38.62,174.93 38.62,172.07 39.45,171.25 39.45,170.33 40.3,169.48 40.3,168.37 39.47,167.54 39.47,160.79 48.27,151.98 48.27,139.55 48.12,139.39 47.19,139.39 47.04,139.24 47.04,138.9 47.19,138.75 48.12,138.75 48.27,138.59 48.27,138.25 48.12,138.1 46.46,138.1 46.3,137.95 46.3,137.6 46.46,137.45 48.12,137.45 48.27,137.3 48.27,136.75 48.12,136.6 45.87,136.6 45.58,136.31 45.58,127.4 49.85,123.13 57.02,123.13
M_B_DQ11: length 90.4
  TOP w0.165: v2(67.13,122.46) 67.6,121.99 CPU1.AL31
  L3 w0.089: 56.91,123.78 64.56,123.78 64.88,123.45 64.88,123.21 65.2,122.89 66.7,122.89 v2(67.13,122.46) ; 39.65,180.83 39.58,180.87 arc(39.1,181.9) 40.22,181.7 40.15,181.59 DIMM2.168
  L3 w0.102: 39.65,180.83 39.67,180.75 39.67,180.53
  L3 w0.152: 56.91,123.78 50.12,123.78 46.23,127.66 46.23,133.6 48.92,136.3 48.92,138.67 49.07,138.82 49.96,138.82 50.11,138.97 50.11,139.31 49.96,139.47 49.07,139.47 48.92,139.62 48.92,139.96 49.07,140.11 49.35,140.11 49.5,140.27 49.5,140.61 49.35,140.76 49.07,140.76 48.92,140.91 48.92,152.25 40.11,161.05 40.11,166.36 39.77,166.71 39.77,167.42 40.63,168.27 40.63,169.66 39.75,170.54 39.75,171.38 38.93,172.2 38.93,174.8 39.59,175.46 39.59,176.72 38.81,177.49 38.81,178.5 39.67,179.36 39.67,180.53
M_B_DQ12: length 89.4
  TOP w0.165: CPU1.AK34 v2(65.31,120.57)
  L3 w0.089: DIMM2.14 31.65,177.79 31.72,177.9 arc(30.6,178.1) 31.08,177.07 31.15,177.03 ; v2(65.31,120.57) 65.31,120.57 64.86,120.12 62.13,120.12 62.04,120.08 59.15,118.86 58.9,118.77 57.82,118.77 57.26,118.21 56.86,118.21
  L3 w0.102: 31.17,176.81 31.17,176.95 31.15,177.03
  L3 w0.152: 56.86,118.21 47.8,118.21 40.74,125.27 40.74,138.5 33.45,145.79 33.45,161.87 33.24,162.09 32.68,162.09 32.3,162.47 32.3,166.29 32.65,166.63 32.65,167.71 32.13,168.23 32.13,169.5 31.27,170.36 31.27,171.45 31.82,172 31.82,174.02 30.96,174.88 30.96,176.61 31.17,176.81
M_B_DQ13: length 88.4
  TOP w0.165: v2(63.45,120.6) 63.87,121.02 CPU1.AK35
  L3 w0.089: 56.86,118.86 57.34,118.86 57.9,119.42 58.53,119.62 60.13,119.62 60.83,120.32 63.17,120.32 v2(63.45,120.6) ; 32.02,179.15 32,179.23 31.93,179.27 arc(31.45,180.3) 32.57,180.1 32.5,179.99 DIMM2.159
  L3 w0.152: 56.86,118.86 48.07,118.86 41.39,125.54 41.39,138.77 34.1,146.06 34.1,162.14 32.98,163.27 32.98,163.29 32.95,163.31 32.95,165.79 32.95,167.65 33.5,168.19 33.5,169.32 32.87,169.95 32.87,171.22 32.13,171.96 32.13,174.71 31.27,175.57 31.27,176.43 31.94,177.1 31.94,178.45 32.02,178.53 32.02,179.15
M_B_DQ14: length 90.8
  TOP w0.165: CPU1.AK32 v2(67.14,120.57)
  L3 w0.089: DIMM2.21 37.6,176.19 37.67,176.3 arc(36.55,176.5) 37.03,175.47 37.1,175.43 ; 57.35,121.83 57.91,122.39 64.65,122.39 65.03,122.01 66.28,122.01 66.7,121.59 66.7,121.3 v2(67.14,120.57)
  L3 w0.102: 37.1,175.43 37.12,175.35 37.12,175.19
  L3 w0.152: 37.12,175.19 36.9,174.97 36.9,172.06 37.77,171.19 37.77,170.08 38.6,169.25 38.6,168.39 37.77,167.57 37.77,166.65 37.49,166.37 37.49,160.92 46.98,151.44 46.98,146.85 46.82,146.69 46.48,146.69 46.33,146.54 46.33,146.2 46.48,146.05 46.82,146.05 46.98,145.89 46.98,145.55 46.82,145.4 46.35,145.4 46.2,145.25 46.2,144.9 46.35,144.75 46.82,144.75 46.98,144.6 46.98,144.25 46.82,144.1 46.1,144.1 45.95,143.95 45.95,143.61 46.1,143.45 46.82,143.45 46.98,143.3 46.98,142.96 46.82,142.81 46.1,142.81 45.95,142.65 45.95,142.31 46.1,142.16 46.82,142.16 46.98,142.01 46.98,141.19 44.28,138.5 44.28,126.86 49.31,121.83 49.85,121.83 49.85,121.83 57.35,121.83
M_B_DQ15: length 90
  TOP w0.165: v2(67.13,121.47) 67.13,121.49 CPU1.AL32
  L3 w0.089: v2(67.13,121.47) 67.13,121.5 66.23,122.4 64.98,122.4 64.75,122.63 59.82,122.63 59.17,123.28 57.9,123.28 57.11,122.48 ; 37.95,180.83 37.88,180.87 arc(37.4,181.9) 38.52,181.7 38.45,181.59 DIMM2.166
  L3 w0.102: 37.95,180.83 37.97,180.75 37.97,180.53
  L3 w0.152: 37.97,180.53 37.97,179.32 37.08,178.44 37.08,177.31 37.89,176.5 37.89,175.53 37.21,174.86 37.21,172.19 38.08,171.32 38.08,170.41 38.9,169.58 38.9,168.26 38.08,167.44 38.08,166.17 38.14,166.11 38.14,161.19 47.62,151.71 47.62,140.92 46.57,139.86 44.93,137.13 44.93,127.13 49.58,122.48 57.11,122.48
M_B_DQ16: length 81.2
  TOP w0.165: CPU1.AP35 v2(63.48,125.14)
  L3 w0.089: 42.2,175.43 42.13,175.47 arc(41.65,176.5) 42.77,176.3 42.7,176.19 DIMM2.27 ; v2(63.48,125.14) 63.32,125.14 62.89,124.71 59.81,124.71 58.75,125.77 57.17,125.77
  L3 w0.102: 42.22,175.13 42.22,175.35 42.2,175.43
  L3 w0.152: 42.22,175.13 41.99,174.9 41.99,174.37 43.06,173.3 43.55,173.3 43.71,173.15 43.71,172.11 44.55,171.26 44.55,169.95 45.42,169.09 45.42,168.38 44.57,167.54 44.57,165.74 44.39,165.56 43.99,165.56 43.84,165.4 43.84,165.09 44.02,164.91 44.39,164.91 44.54,164.76 44.54,162.64 52.6,154.58 52.6,153.94 52.45,153.78 51.98,153.78 51.83,153.63 51.83,153.29 51.98,153.14 52.45,153.14 52.6,152.98 52.6,152.64 52.45,152.49 51.98,152.49 51.83,152.33 51.83,151.99 51.98,151.84 52.45,151.84 52.6,151.69 52.6,151.34 52.45,151.19 51.98,151.19 51.83,151.04 51.83,150.7 51.98,150.54 52.45,150.54 52.6,150.39 52.6,150.05 52.45,149.9 51.98,149.9 51.83,149.74 51.83,149.4 51.98,149.25 52.45,149.25 52.6,149.1 52.6,136.53 48.36,132.28 48.36,128.28 50.87,125.77 57.17,125.77
M_B_DQ17: length 83.2
  TOP w0.165: CPU1.AN34 64.94,123.77 65.31,123.4 v2(65.31,123.38)
  L3 w0.089: 43.05,180.83 42.98,180.87 arc(42.5,181.9) 43.62,181.7 43.55,181.59 DIMM2.172 ; v2(65.31,123.38) 65.31,123.46 65.31,123.47 65.31,123.63 64.82,124.11 64.82,124.43 64.57,124.68 64.22,124.68 63.91,124.99 63.91,125.31 63.66,125.56 59.54,125.56 59.02,126.08 58.22,126.08 57.89,126.42 57.28,126.42
  L3 w0.102: 43.05,180.83 43.07,180.75 43.07,180.53
  L3 w0.152: 43.07,180.53 43.07,179.29 42.16,178.38 42.16,177.55 43.13,176.58 43.13,174.44 44.01,173.56 44.01,172.23 44.85,171.39 44.85,170.51 45.73,169.64 45.73,168.26 44.88,167.41 44.88,166.58 45.22,166.23 45.22,162.88 47.45,160.66 48.01,160.66 48.39,160.27 48.39,159.72 53.25,154.85 53.25,136.26 49.01,132.02 49.01,128.55 51.14,126.42 57.28,126.42
M_B_DQ18: length 85.4
  TOP w0.165: CPU1.AN31 v2(67.14,124.22)
  L3 w0.089: v2(67.14,124.22) 66.66,124.71 66.66,125.31 66.27,125.7 66.05,125.7 64.88,126.87 63.34,126.87 62.77,127.45 ; 48.15,177.03 48.08,177.07 arc(47.6,178.1) 48.72,177.9 48.65,177.79 DIMM2.34
  L3 w0.102: 48.17,176.77 48.17,176.95 48.15,177.03
  L3 w0.152: 48.17,176.77 47.96,176.56 47.96,174.45 48.82,173.58 48.82,172.08 49.65,171.25 49.65,170.14 50.5,169.29 50.5,168.15 49.98,167.63 49.98,164.25 57.23,157 57.23,147.91 57.38,147.75 58.89,147.75 59.04,147.6 59.04,147.26 58.89,147.11 57.38,147.11 57.23,146.95 57.23,146.61 57.38,146.46 58.89,146.46 59.04,146.31 59.04,145.96 58.89,145.81 57.38,145.81 57.23,145.66 57.23,145.32 57.38,145.16 58.89,145.16 59.04,145.01 59.04,144.67 58.89,144.52 57.38,144.52 57.23,144.36 57.23,144.02 57.38,143.87 58.89,143.87 59.04,143.72 59.04,143.37 58.89,143.22 57.38,143.22 57.23,143.07 57.23,142.73 57.38,142.57 58.89,142.57 59.04,142.42 59.04,142.08 58.89,141.93 57.38,141.93 57.23,141.77 57.23,141.43 57.38,141.28 58.89,141.28 59.04,141.13 59.04,130.87 58.55,130.38 58.55,129.56 59.65,128.46 61.76,128.46 62.77,127.45
M_B_DQ19: length 84.6
  TOP w0.165: CPU1.AP31 v2(67.14,125.14)
  L3 w0.089: 63.45,127.37 63.64,127.18 65.02,127.18 65.41,126.8 66.17,126.8 66.7,126.26 66.7,125.63 67.14,125.19 v2(67.14,125.14) ; 49.02,179.15 49,179.23 48.93,179.27 arc(48.45,180.3) 49.57,180.1 49.5,179.99 DIMM2.179
  L3 w0.152: 49.02,179.15 49.02,178.53 48.94,178.45 48.94,177.11 48.26,176.43 48.26,175.03 49.13,174.17 49.13,172.21 49.98,171.36 49.98,170.45 50.8,169.62 50.8,168.25 51.35,167.7 51.35,163.79 58.1,157.04 58.1,155.57 58.25,155.42 59.46,155.42 59.61,155.27 59.61,154.8 59.46,154.65 58.09,154.65 57.94,154.5 57.94,154.15 58.09,154 59.54,154 59.69,153.85 59.69,153.51 59.54,153.35 58.09,153.35 57.94,153.2 57.94,152.86 58.09,152.71 59.54,152.71 59.69,152.55 59.69,152.21 59.54,152.06 58.09,152.06 57.94,151.9 57.94,151.56 58.09,151.41 59.54,151.41 59.69,151.26 59.69,150.91 59.54,150.76 58.09,150.76 57.94,150.61 57.94,150.27 58.09,150.11 59.54,150.11 59.69,149.96 59.69,149.62 59.54,149.47 58.09,149.47 57.94,149.31 57.94,148.97 58.09,148.82 59.54,148.82 59.69,148.67 59.69,130.12 60.37,129.44 61.38,129.44 63.45,127.37
M_B_DQ20: length 82.4
  TOP w0.165: CPU1.AN35 v2(63.48,124.22)
  L3 w0.089: 40.5,175.43 40.43,175.47 arc(39.95,176.5) 41.07,176.3 41,176.19 DIMM2.25 ; 56.93,124.47 57.62,124.47 57.87,124.22 v2(63.48,124.22)
  L3 w0.102: 40.5,175.43 40.52,175.35 40.52,175.13
  L3 w0.152: 56.93,124.47 50.34,124.47 47.06,127.74 47.06,132.82 51.31,137.06 51.31,141.11 51.16,141.26 50.85,141.26 50.7,141.41 50.7,141.75 50.85,141.91 51.16,141.91 51.31,142.06 51.31,142.4 51.16,142.55 50.75,142.55 50.6,142.71 50.6,143.05 50.75,143.2 51.16,143.2 51.31,143.35 51.31,143.7 51.16,143.85 50.69,143.85 50.53,144 50.53,144.34 50.69,144.5 51.16,144.5 51.31,144.65 51.31,144.99 51.16,145.14 50.69,145.14 50.53,145.3 50.53,145.64 50.69,145.79 51.16,145.79 51.31,145.94 51.31,146.29 51.16,146.44 50.69,146.44 50.53,146.59 50.53,146.94 50.69,147.09 51.16,147.09 51.31,147.24 51.31,147.58 51.16,147.74 50.69,147.74 50.53,147.89 50.53,154.42 41.35,163.6 41.35,167.54 42.14,168.33 42.14,169.29 41.33,170.1 41.33,171.4 40.52,172.2 40.52,175.13
M_B_DQ21: length 82.6
  TOP w0.165: CPU1.AP34 64.83,124.68 v2(64.4,124.25)
  L3 w0.089: v2(64.4,124.25) 64.06,124.25 63.66,124.65 63.31,124.65 63.12,124.47 59.55,124.47 58.89,125.12 57.08,125.12 ; 41.35,180.83 41.28,180.87 arc(40.8,181.9) 41.92,181.7 41.85,181.59 DIMM2.170
  L3 w0.102: 41.37,180.53 41.37,180.75 41.35,180.83
  L3 w0.152: 41.37,180.53 41.37,179.34 40.56,178.54 40.56,177.44 41.29,176.72 41.29,174.18 42.16,173.3 42.16,172.16 42.98,171.35 42.98,170.05 43.87,169.16 43.87,168.28 43,167.41 43,166.04 43.03,165 44.01,161.86 51.18,154.69 51.18,149.13 51.96,147.8 51.96,136.8 47.71,132.55 47.71,128.01 50.6,125.12 57.08,125.12
M_B_DQ22: length 84.6
  TOP w0.165: CPU1.AN32 v2(66.23,124.22)
  L3 w0.089: v2(66.23,124.22) 65.78,124.67 65.78,125.28 64.74,126.32 60.41,126.32 59.15,127.58 58.51,127.58 57.98,128.11 ; 46.45,177.03 46.38,177.07 arc(45.9,178.1) 47.02,177.9 46.95,177.79 DIMM2.32
  L3 w0.102: 46.47,176.8 46.47,176.95 46.45,177.03
  L3 w0.152: 57.98,128.11 57.1,128.99 57.1,133.81 55.89,135.01 55.89,140.92 55.74,141.07 55.12,141.07 54.97,141.22 54.97,141.57 55.12,141.72 55.74,141.72 55.89,141.87 55.89,142.21 55.74,142.37 55.12,142.37 54.97,142.52 54.97,142.86 55.12,143.01 55.74,143.01 55.89,143.17 55.89,143.51 55.74,143.66 55.12,143.66 54.97,143.81 54.97,144.16 55.12,144.31 55.74,144.31 55.89,144.46 55.89,144.81 55.74,144.96 55.12,144.96 54.97,145.11 54.97,145.45 55.12,145.61 55.74,145.61 55.89,145.76 55.89,146.1 55.74,146.25 55.12,146.25 54.97,146.41 54.97,146.75 55.12,146.9 55.74,146.9 55.89,147.05 55.89,147.4 55.74,147.55 55.12,147.55 54.97,147.7 54.97,148.04 55.12,148.2 55.74,148.2 55.89,148.35 55.89,148.69 55.74,148.84 55.12,148.84 54.97,149 54.97,149.34 55.12,149.49 55.74,149.49 55.89,149.64 55.89,149.99 55.74,150.14 55.12,150.14 54.97,150.29 54.97,150.63 55.12,150.79 55.74,150.79 55.89,150.94 55.89,151.28 55.74,151.43 55.12,151.43 54.97,151.59 54.97,151.93 55.12,152.08 55.74,152.08 55.89,152.23 55.89,152.58 55.74,152.73 55.12,152.73 54.97,152.88 54.97,153.23 55.12,153.38 55.74,153.38 55.89,153.53 55.89,153.87 55.74,154.03 55.45,154.03 55.3,154.18 55.3,154.52 55.45,154.67 55.74,154.67 55.89,154.83 55.89,156.5 48.18,164.21 48.18,167.79 48.8,168.41 48.8,169.14 47.95,169.98 47.95,171.29 47.12,172.12 47.12,172.15 47.12,172.16 47.12,173.13 46.25,174 46.25,176.57 46.47,176.8
M_B_DQ23: length 84.2
  TOP w0.165: CPU1.AP32 v2(66.23,125.14)
  L3 w0.089: 47.32,179.15 47.3,179.23 47.23,179.27 arc(46.75,180.3) 47.87,180.1 47.8,179.99 DIMM2.177 ; 58.85,128.63 60.04,127.44 60.84,127.44 61.23,127.06 61.23,126.82 61.48,126.57 64.83,126.57 66.23,125.17 v2(66.23,125.14)
  L3 w0.152: 47.32,179.15 47.32,178.53 47.24,178.45 47.24,177.11 46.56,176.43 46.56,175.08 47.43,174.22 47.43,172.24 48.25,171.42 48.25,170.41 49.1,169.56 49.1,168.12 49.67,167.55 49.67,166.66 49.33,166.32 49.33,163.98 56.54,156.77 56.54,140.4 56.69,140.25 58.24,140.25 58.39,140.1 58.39,139.75 58.24,139.6 56.69,139.6 56.54,139.45 56.54,139.11 56.69,138.95 58.24,138.95 58.39,138.8 58.39,138.46 58.24,138.31 56.69,138.31 56.54,138.15 56.54,137.81 56.69,137.66 58.24,137.66 58.39,137.51 58.39,137.16 58.24,137.01 56.69,137.01 56.54,136.86 56.54,136.52 56.69,136.36 58.24,136.36 58.39,136.21 58.39,135.82 58.24,135.66 56.79,135.66 56.64,135.51 56.64,135.22 56.85,135.02 58.24,135.02 58.39,134.86 58.39,131.98 57.63,131.22 57.63,129.85 58.85,128.63
M_B_DQ24: length 69.8
  TOP w0.165: CPU1.AM29 v2(68.97,123.31)
  L3 w0.089: 62.95,130.52 65.77,127.71 66.7,127.71 68.06,126.35 68.06,124.19 68.94,123.31 v2(68.97,123.31) ; 51.55,177.03 51.48,177.07 arc(51,178.1) 52.12,177.9 52.05,177.79 DIMM2.38
  L3 w0.102: 51.57,176.82 51.57,176.95 51.55,177.03
  L3 w0.152: 62.95,130.52 62.01,131.47 62.01,156.99 59.18,159.82 59.18,160.03 59.49,160.34 59.49,160.55 59.24,160.8 59.03,160.8 58.8,160.57 58.58,160.57 58.34,160.81 58.34,161.03 58.57,161.26 58.57,161.47 58.33,161.71 58.11,161.71 57.81,161.41 57.59,161.41 57.35,161.65 57.35,161.87 57.65,162.17 57.65,162.39 57.41,162.63 57.19,162.63 56.89,162.32 56.67,162.32 56.17,162.83 56.17,163.49 55.87,163.79 55.21,163.79 53.72,165.28 53.72,166.49 53.37,166.83 53.37,167.72 53.9,168.25 53.9,169.27 53.05,170.11 53.05,171.36 52.22,172.18 52.22,173.68 51.36,174.55 51.36,176.61 51.57,176.82
M_B_DQ25: length 69.9
  TOP w0.165: CPU1.AM28 v2(69.89,122.4)
  L3 w0.089: v2(69.89,122.4) 69.4,122.88 69.4,123.49 69.08,123.8 68.79,123.8 68.3,124.29 68.3,126.45 66.74,128.02 65.98,128.02 63.82,130.18 ; 52.4,179.23 52.33,179.27 arc(51.85,180.3) 52.97,180.1 52.9,179.99 DIMM2.183
  L3 w0.102: 52.42,178.93 52.42,179.15 52.4,179.23
  L3 w0.14: 63.01,130.98 63.82,130.18
  L3 w0.152: 63.01,130.98 62.66,131.33 62.66,157.25 61.61,159.35 55.8,165.15 54.77,166.7 54.77,167.63 54.2,168.2 54.2,169.65 53.36,170.49 53.36,171.34 54,171.98 54,173.13 53.67,173.46 53.43,173.46 51.66,175.22 51.66,176.48 52.39,177.21 52.39,178.89 52.42,178.93
M_B_DQ26: length 67.2
  TOP w0.165: CPU1.AR29 69.43,125.62 v2(69.86,126.05)
  L3 w0.089: DIMM2.45 58,176.19 58.07,176.3 arc(56.95,176.5) 57.43,175.47 57.5,175.43 ; v2(69.86,126.05) 69.46,126.45 69.46,127.31 69.12,127.64 69.12,128.98 68.77,129.34
  L3 w0.102: 57.52,175.13 57.52,175.35 57.5,175.43
  L3 w0.152: 68.77,129.34 66.21,131.9 66.21,137.73 66.05,137.88 65.72,137.88 65.57,138.04 65.57,138.38 65.72,138.53 66.05,138.53 66.21,138.68 66.21,139.03 66.05,139.18 65.72,139.18 65.57,139.33 65.57,139.67 65.72,139.83 66.05,139.83 66.21,139.98 66.21,140.32 66.05,140.47 65.72,140.47 65.57,140.63 65.57,140.97 65.72,141.12 66.05,141.12 66.21,141.27 66.21,141.62 66.05,141.77 65.72,141.77 65.57,141.92 65.57,142.26 65.72,142.42 66.05,142.42 66.21,142.57 66.21,142.91 66.05,143.06 65.72,143.06 65.57,143.22 65.57,143.56 65.72,143.71 66.05,143.71 66.21,143.86 66.21,144.21 66.05,144.36 65.72,144.36 65.57,144.51 65.57,144.86 65.72,145.01 66.05,145.01 66.21,145.16 66.21,145.5 66.05,145.66 65.72,145.66 65.57,145.81 65.57,146.15 65.72,146.3 66.05,146.3 66.21,146.46 66.21,146.8 66.05,146.95 65.72,146.95 65.57,147.1 65.57,147.45 65.72,147.6 66.05,147.6 66.21,147.75 66.21,148.09 66.05,148.25 65.72,148.25 65.57,148.4 65.57,161.12 60.18,166.52 60.18,167.67 60.86,168.35 60.86,169.29 60.07,170.08 60.07,171.45 59.31,172.21 59.31,173.81 58.68,174.45 57.96,174.45 57.52,174.89 57.52,175.13
M_B_DQ27: length 67.3
  TOP w0.165: CPU1.AR28 70.34,125.63 v2(70.76,126.05)
  L3 w0.089: DIMM2.190 58.85,181.59 58.92,181.7 arc(57.8,181.9) 58.28,180.87 58.35,180.83 ; v2(70.76,126.05) 70.32,126.51 70.32,127.13 70.06,127.4 69.79,127.4 69.48,127.71 69.48,129.15
  L3 w0.102: 58.37,180.53 58.37,180.75 58.35,180.83
  L3 w0.152: 58.37,180.53 58.37,179.36 59.18,178.55 59.18,177.29 59.97,176.5 59.97,175.1 60.86,174.22 60.86,172.11 61.74,171.23 61.74,170.14 62.48,169.39 62.48,168.28 61.7,167.49 61.7,166.45 62.26,165.88 62.48,165.88 62.8,166.2 63.01,166.2 63.26,165.95 63.26,165.74 62.94,165.42 62.94,165.21 63.29,164.85 63.48,164.85 63.84,165.21 64.15,165.21 64.41,164.95 64.41,164.64 64.15,164.38 64.15,163.99 66.22,161.92 66.22,150.88 66.85,150.24 66.85,131.77 69.48,129.15
M_B_DQ28: length 70.6
  TOP w0.165: CPU1.AL29 v2(68.97,121.48)
  L3 w0.089: 49.85,177.03 49.78,177.07 arc(49.3,178.1) 50.42,177.9 50.35,177.79 DIMM2.36 ; 61.07,130.41 64.02,127.45 65.13,127.45 65.48,127.1 66.63,127.1 67.25,126.48 67.25,126.48 67.57,126.16 67.57,123.52 68.97,122.11 v2(68.97,121.48)
  L3 w0.102: 49.87,176.85 49.87,176.95 49.85,177.03
  L3 w0.152: 61.07,130.41 60.55,130.93 60.55,155.88 58.94,158.1 54.88,162.16 54.66,162.16 54.59,162.09 54.37,162.09 54.13,162.33 54.13,162.55 54.2,162.62 54.2,162.84 53.96,163.08 53.75,163.08 53.56,162.89 53.34,162.89 52.42,163.81 52.42,165.76 51.65,166.54 51.65,167.7 52.2,168.25 52.2,169.22 51.35,170.06 51.35,171.21 50.5,172.06 50.5,173.43 49.67,174.26 49.67,176.64 49.87,176.85
M_B_DQ29: length 71.3
  TOP w0.165: CPU1.AL28 v2(69.89,121.48)
  L3 w0.089: 50.72,179.15 50.7,179.23 50.63,179.27 arc(50.15,180.3) 51.27,180.1 51.2,179.99 DIMM2.181 ; v2(69.89,121.48) 67.95,123.83 67.82,124.13 67.82,126.25 66.72,127.36 65.6,127.36 64.27,128.68 62.9,129.26 62.78,129.38
  L3 w0.152: 62.78,129.38 61.28,130.89 61.28,156.24 59.5,158.46 53.07,164.89 53.07,166.57 53.07,166.57 53.07,167.63 52.5,168.2 52.5,169.47 51.67,170.3 51.67,171.4 50.8,172.27 50.8,174.29 49.97,175.12 49.97,176.49 50.64,177.16 50.64,178.45 50.72,178.53 50.72,179.15
M_B_DQ30: length 67.7
  TOP w0.165: v2(69.86,125.14) 69.43,124.71 CPU1.AP29
  L3 w0.089: DIMM2.43 56.3,176.19 56.37,176.3 arc(55.25,176.5) 55.73,175.47 55.8,175.43 ; v2(69.86,125.14) 69.83,125.14 68.98,125.99 68.98,127.06 68.51,127.53 68.51,128.34 68.24,128.61
  L3 w0.102: 55.8,175.43 55.82,175.35 55.82,175.13
  L3 w0.152: 68.24,128.61 67.43,129.42 66.5,129.42 66.23,129.68 66.23,130.25 64.27,132.21 64.27,158.91 63.58,159.61 63.58,159.82 63.78,160.03 63.78,160.25 63.54,160.49 63.32,160.49 63.12,160.28 62.9,160.28 62.66,160.53 62.66,160.74 63.14,161.22 63.14,161.44 62.9,161.68 62.68,161.68 62.2,161.2 61.99,161.2 61.74,161.44 61.74,161.66 62.23,162.14 62.23,162.36 61.98,162.6 61.77,162.6 61.28,162.12 61.07,162.12 60.83,162.36 60.83,162.57 61.31,163.06 61.31,163.27 61.07,163.52 60.85,163.52 60.37,163.03 60.15,163.03 59.84,163.35 59.84,164.57 59.54,164.87 58.8,164.87 58.27,165.4 58.27,167.51 57.48,168.3 57.48,169.47 56.62,170.33 56.62,171.35 57.48,172.21 57.48,172.9 55.82,174.56 55.82,175.13
M_B_DQ31: length 68.5
  TOP w0.165: CPU1.AP28 70.34,124.72 v2(70.76,125.14)
  L3 w0.089: v2(70.76,125.14) 70.31,125.59 69.72,125.59 69.22,126.09 69.22,127.18 68.82,127.58 68.82,128.63 68.69,128.76 ; DIMM2.188 57.15,181.59 57.22,181.7 arc(56.1,181.9) 56.58,180.87 56.65,180.83
  L3 w0.102: 56.67,180.53 56.67,180.75 56.65,180.83
  L3 w0.152: 68.69,128.76 65.56,131.89 65.56,135.15 65.05,135.66 65.05,136.21 65.2,136.36 65.38,136.36 65.53,136.51 65.53,136.85 65.38,137.01 65.07,137.01 64.92,137.16 64.92,160.86 59.87,165.91 59.87,167.58 59.18,168.28 59.18,169.21 58.34,170.05 58.34,171.32 59.01,171.99 59.01,173.23 58.27,173.96 57.38,173.96 56.59,174.75 56.59,176.66 55.85,177.39 55.85,178.55 56.67,179.36 56.67,180.53
M_B_DQ32: length 72.6
  TOP w0.165: v2(85.43,125.14) 85.19,125.14 84.97,125.35 CPU1.AR12
  L3 w0.089: DIMM2.97 107.3,176.19 107.37,176.3 arc(106.25,176.5) 106.73,175.47 106.8,175.43 ; 87.06,128.6 87.06,128.17 85.86,126.97 85.86,125.79 85.43,125.36 v2(85.43,125.14)
  L3 w0.102: 106.8,175.43 106.82,175.35 106.82,175.13
  L3 w0.152: 106.82,175.13 106.93,175.02 106.93,172.02 107.45,171.5 107.45,170.26 106.93,169.74 106.93,168.16 107.45,167.64 107.45,166.63 106.81,165.99 105.34,165.99 104.43,165.08 104.43,160.74 92.79,149.09 92.79,147.73 91.31,146.26 91.31,145.61 91.47,145.46 92.53,145.46 92.68,145.3 92.68,144.96 92.53,144.81 91.47,144.81 91.31,144.66 91.31,144.31 91.47,144.16 92.53,144.16 92.68,144.01 92.68,143.67 92.53,143.51 91.47,143.51 91.31,143.36 91.31,143.02 91.47,142.87 92.58,142.87 92.74,142.71 92.74,142.37 92.58,142.22 91.47,142.22 91.31,142.06 91.31,134.68 87.06,130.42 87.06,128.6
M_B_DQ33: length 72.4
  TOP w0.165: CPU1.AP12 85.32,124.33 85.38,124.33 v2(85.42,124.29)
  L3 w0.089: DIMM2.242 108.15,181.59 108.22,181.7 arc(107.1,181.9) 107.58,180.87 107.65,180.83 ; 89.85,131.43 87.62,129.21 87.62,128.24 86.18,126.8 86.18,125.7 85.87,125.39 85.87,124.74 v2(85.42,124.29)
  L3 w0.102: 107.65,180.83 107.67,180.75 107.67,180.53
  L3 w0.152: 107.67,180.53 107.67,179.29 106.76,178.38 106.76,177.49 107.7,176.56 107.7,174.5 108.48,173.71 108.48,172.21 107.75,171.48 107.75,170.25 108.46,169.54 108.46,168.33 107.75,167.62 107.75,166.42 106.96,165.63 105.9,165.63 105.08,164.82 105.08,160.47 104.6,159.99 104.6,159.97 93.43,148.81 93.43,141.8 92.58,140.34 92.58,134.17 89.85,131.44 89.85,131.43
M_B_DQ34: length 78.1
  TOP w0.165: CPU1.AL13 v2(84.52,121.48)
  L3 w0.089: DIMM2.104 113.25,177.79 113.32,177.9 arc(112.2,178.1) 112.68,177.07 112.75,177.03 ; v2(84.52,121.48) 84.94,121.91 85.61,121.91 85.85,121.67 86.65,121.67 87.82,122.83 87.82,126.37 89.03,127.58 89.03,128.04 89.28,128.29 89.56,128.29 90.45,129.18 91.71,129.18
  L3 w0.102: 112.75,177.03 112.77,176.95 112.77,176.78
  L3 w0.152: 112.77,176.78 112.57,176.58 112.57,175.08 113.42,174.23 113.42,171.97 112.88,171.42 112.88,170.21 113.4,169.69 113.4,168.13 112.88,167.61 112.88,166.62 112.19,165.94 112.19,163.06 96.3,147.18 96.3,146.45 96.46,146.3 96.8,146.3 96.95,146.15 96.95,145.8 96.8,145.65 96.46,145.65 96.3,145.5 96.3,145.16 96.46,145 96.82,145 96.98,144.85 96.98,144.51 96.82,144.36 96.46,144.36 96.3,144.2 96.3,143.86 96.46,143.71 96.72,143.71 96.88,143.56 96.88,143.21 96.72,143.06 96.49,143.06 96.34,142.91 96.34,140.31 97.04,139.61 97.04,134.52 91.71,129.18
M_B_DQ35: length 77.8
  TOP w0.165: CPU1.AL12 v2(85.43,121.48)
  L3 w0.089: DIMM2.249 114.1,179.99 114.17,180.1 arc(113.05,180.3) 113.53,179.27 113.6,179.23 113.62,179.15 ; v2(85.43,121.48) 85.55,121.36 86.69,121.36 88.12,122.79 88.12,125.85 89.91,127.64 89.91,127.98 90.35,128.42 91.1,128.42
  L3 w0.152: 91.1,128.42 91.38,128.42 93.59,130.63 94.14,130.63 97.71,134.2 97.71,140.44 97.19,140.96 97.19,141.64 97.36,141.81 97.54,141.81 97.74,142.01 97.74,147.69 112.84,162.8 112.84,165.67 113.41,166.24 113.79,166.24 114.27,166.72 114.27,167.69 113.73,168.24 113.73,169.48 114.27,170.03 114.27,171.48 113.73,172.02 113.73,174.69 112.87,175.54 112.87,176.42 113.54,177.09 113.54,178.45 113.62,178.53 113.62,179.15
M_B_DQ36: length 74.1
  TOP w0.165: CPU1.AR13 v2(84.52,126.05)
  L3 w0.089: 105.1,175.43 105.03,175.47 arc(104.55,176.5) 105.67,176.3 105.6,176.19 DIMM2.95 ; v2(84.52,126.05) 84.52,126.4 86.17,128.06 86.17,128.73
  L3 w0.102: 105.1,175.43 105.12,175.35 105.12,175.13
  L3 w0.152: 105.12,175.13 105.03,175.03 105.03,172.21 105.75,171.49 105.75,170.14 105.16,169.54 105.16,168.4 104.27,167.51 104.27,166.75 102.41,164.9 102.41,164.6 102.26,164.45 101.83,164.45 101.68,164.3 101.68,163.96 101.83,163.8 102.26,163.8 102.41,163.65 102.41,163 102.26,162.85 101.73,162.85 101.57,162.7 101.57,162.36 101.73,162.2 102.26,162.2 102.41,162.05 102.41,160.55 102.04,160.18 101.82,160.18 101.4,160.6 101.19,160.6 100.86,160.27 100.86,160.05 101.28,159.63 101.28,159.42 100.94,159.08 100.68,159.08 100,159.76 99.79,159.76 99.54,159.51 99.54,159.3 100.22,158.62 100.22,158.41 99.97,158.17 99.76,158.17 99.04,158.89 98.82,158.89 98.58,158.65 98.58,158.43 99.3,157.71 99.3,157.49 99.06,157.25 98.84,157.25 98.17,157.92 97.95,157.92 97.71,157.68 97.71,157.47 98.38,156.79 98.38,156.53 91.49,149.63 91.49,148.27 89.42,146.19 89.42,146.19 89.29,146.06 89.29,145.58 89.44,145.42 89.76,145.42 89.92,145.27 89.92,144.81 89.76,144.66 89.44,144.66 89.29,144.51 89.29,134.85 88.76,134.33 88.76,134.11 86.17,131.52 86.17,128.73
M_B_DQ37: length 75.3
  TOP w0.165: CPU1.AP13 v2(84.52,125.14)
  L3 w0.089: DIMM2.240 106.45,181.59 106.52,181.7 arc(105.4,181.9) 105.88,180.87 105.95,180.83 ; 84.95,126.45 84.95,125.57 v2(84.52,125.14)
  L3 w0.102: 105.95,180.83 105.97,180.75 105.97,180.53
  L3 w0.152: 84.95,126.45 86.69,128.19 86.69,131.07 90.02,134.4 90.02,136.49 90.18,136.64 90.45,136.64 90.6,136.79 90.6,137.25 90.45,137.4 90.14,137.4 89.99,137.56 89.99,137.96 90.14,138.11 90.37,138.11 90.53,138.27 90.53,138.61 90.37,138.76 90.17,138.76 90.02,138.91 90.02,139.26 90.17,139.41 90.48,139.41 90.63,139.56 90.63,139.9 90.48,140.06 90.14,140.06 89.99,140.21 89.99,140.55 90.14,140.7 90.48,140.7 90.63,140.86 90.63,141.2 90.48,141.35 90.14,141.35 89.99,141.5 89.99,141.85 90.14,142 90.48,142 90.63,142.15 90.63,142.5 90.48,142.65 90.16,142.65 90.04,142.76 90.04,143.18 90.16,143.3 90.48,143.3 90.63,143.45 90.63,146.49 92.14,148 92.14,149.36 103.06,160.28 103.06,164.63 104.8,166.37 105.54,166.37 106.05,166.88 106.05,167.77 106.62,168.34 106.62,169.43 106.05,170 106.05,171.46 106.62,172.03 106.62,173.48 105.89,174.22 105.89,176.69 105.16,177.41 105.16,178.54 105.97,179.34 105.97,180.53
M_B_DQ38: length 77
  TOP w0.165: CPU1.AM13 v2(84.52,122.4)
  L3 w0.089: 91.52,130.95 90.59,130.95 88.45,128.81 88.45,127.91 87.24,126.7 87.24,123.6 86.46,122.82 84.94,122.82 v2(84.52,122.4) ; DIMM2.102 111.55,177.79 111.62,177.9 arc(110.5,178.1) 110.98,177.07 111.05,177.03
  L3 w0.102: 111.07,176.78 111.07,176.95 111.05,177.03
  L3 w0.152: 111.07,176.78 110.87,176.58 110.87,175.13 111.7,174.31 111.7,172 110.95,171.25 110.95,170.48 111.71,169.72 111.71,168.2 111,167.49 111,166.16 109.53,164.69 108.55,164.69 108.4,164.53 108.4,164.19 108.55,164.04 109.65,164.04 109.8,163.89 109.8,162.92 95.01,148.12 95.01,139.2 95.16,139.04 95.33,139.04 95.48,138.89 95.48,138.43 95.33,138.28 95.16,138.28 95.01,138.13 95.01,137.67 95.16,137.52 95.36,137.52 95.48,137.4 95.48,136.87 95.36,136.76 95.16,136.76 95.01,136.6 95.01,136.15 95.16,136 95.45,136 95.57,135.88 95.57,135.35 95.45,135.23 95.16,135.23 95.01,135.08 95.01,134.37 91.59,130.95 91.52,130.95
M_B_DQ39: length 76.8
  TOP w0.165: CPU1.AM12 v2(85.43,122.4)
  L3 w0.089: 91.58,130.51 90.57,130.51 88.77,128.71 88.77,127.78 87.51,126.52 87.51,122.9 86.59,121.97 86.06,121.97 85.63,122.4 v2(85.43,122.4) ; DIMM2.247 112.4,179.99 112.47,180.1 arc(111.35,180.3) 111.83,179.27 111.9,179.23 111.92,179.15
  L3 w0.152: 91.58,130.51 92.06,130.51 95.8,134.25 96.06,134.25 96.22,134.41 96.22,139.34 96.06,139.5 95.81,139.5 95.66,139.65 95.66,147.85 111.51,163.7 111.51,166.07 111.88,166.44 112.26,166.44 112.55,166.72 112.55,167.67 112.01,168.2 112.01,169.6 112.57,170.15 112.57,171.53 112.03,172.07 112.03,174.61 111.17,175.47 111.17,176.45 111.84,177.12 111.84,178.45 111.92,178.53 111.92,179.15
M_B_DQ40: length 79.6
  TOP w0.165: CPU1.AP9 89.92,124.07 89.76,124.22 v2(89.46,124.22)
  L3 w0.089: 116.15,177.03 116.08,177.07 arc(115.6,178.1) 116.72,177.9 116.65,177.79 DIMM2.108 ; v2(89.46,124.22) 89.94,124.7 89.94,125.3 90.26,125.63 90.49,125.63 91.41,126.54 92.38,126.54 92.78,126.94 92.78,127.39 95.41,130.02
  L3 w0.102: 116.17,176.83 116.17,176.95 116.15,177.03
  L3 w0.152: 116.17,176.83 115.95,176.61 115.95,175.01 116.82,174.13 116.82,171.94 116.25,171.37 116.25,169.93 116.82,169.36 116.82,168.28 116.28,167.74 116.28,166.06 115.95,165.73 115.95,163 101.17,148.23 101.17,147.58 101.32,147.43 102.15,147.43 102.31,147.27 102.31,146.93 102.15,146.78 101.32,146.78 101.17,146.63 101.17,146.28 101.32,146.13 102.15,146.13 102.31,145.98 102.31,145.64 102.15,145.48 101.32,145.48 101.17,145.33 101.17,144.99 101.32,144.84 102.15,144.84 102.31,144.68 102.31,144.34 102.15,144.19 101.32,144.19 101.17,144.04 101.17,143.69 101.32,143.54 102.15,143.54 102.31,143.39 102.31,143.05 102.15,142.89 101.32,142.89 101.17,142.74 101.17,142.4 101.32,142.25 101.83,142.25 101.98,142.09 101.98,141.75 101.83,141.6 101.35,141.6 101.19,141.45 101.19,134.91 96.66,130.38 95.77,130.38 95.41,130.02
M_B_DQ41: length 78.3
  TOP w0.165: CPU1.AR9 90.08,124.68 90.37,124.97 v2(90.37,125.14)
  L3 w0.089: v2(90.37,125.14) 90.37,125.17 91.49,126.29 92.64,126.29 93.78,127.42 94.94,127.42 95.47,127.95 ; 117,179.23 116.93,179.27 arc(116.45,180.3) 117.57,180.1 117.5,179.99 DIMM2.253
  L3 w0.102: 117,179.23 117.02,179.15
  L3 w0.152: 95.47,127.95 101.84,134.33 101.84,134.93 101.99,135.08 102.16,135.08 102.31,135.23 102.31,135.58 102.16,135.73 101.99,135.73 101.84,135.88 101.84,136.53 101.99,136.68 102.78,136.68 102.93,136.83 102.93,137.18 102.78,137.33 101.99,137.33 101.84,137.48 101.84,137.9 101.99,138.05 102.8,138.05 102.96,138.21 102.96,138.55 102.8,138.7 102.21,138.7 102.06,138.85 102.06,139.2 102.21,139.35 102.8,139.35 102.96,139.5 102.96,139.84 102.8,140 102.23,140 102.08,140.15 102.08,140.49 102.23,140.64 102.8,140.64 102.96,140.8 102.96,149.1 116.69,162.83 116.69,165.46 117.83,166.6 117.83,167.61 117.13,168.32 117.13,169.5 117.73,170.1 117.73,171.45 117.13,172.05 117.13,174.47 116.27,175.32 116.27,176.45 117.02,177.19 117.02,179.15
M_B_DQ42: length 78.2
  TOP w0.165: CPU1.AP7 v2(92.2,124.22)
  L3 w0.089: 122.1,175.43 122.03,175.47 arc(121.55,176.5) 122.67,176.3 122.6,176.19 DIMM2.115 ; v2(92.2,124.22) 92.86,124.65 93.43,124.65 93.62,124.47 96.41,124.47 97.7,125.76 98.4,125.76 99.21,126.57
  L3 w0.102: 122.12,175.13 122.12,175.35 122.1,175.43
  L3 w0.152: 122.12,175.13 122.23,175.02 122.23,171.91 122.75,171.39 122.75,170.24 122.23,169.72 122.23,168.12 122.75,167.6 122.75,166.69 122.5,166.44 122.09,166.44 121.33,165.68 121.33,163.18 107.71,149.56 107.71,148.92 107.86,148.76 108.51,148.76 108.66,148.61 108.66,148.27 108.51,148.12 107.86,148.12 107.71,147.96 107.71,147.62 107.86,147.47 108.94,147.47 109.09,147.32 109.09,146.97 108.94,146.82 107.86,146.82 107.71,146.67 107.71,146.33 107.86,146.17 108.94,146.17 109.09,146.02 109.09,145.68 108.94,145.53 107.86,145.53 107.71,145.37 107.71,141.79 105.83,139.91 105.83,133.18 99.21,126.57
M_B_DQ43: length 77.3
  TOP w0.165: CPU1.AP6 v2(93.12,124.22)
  L3 w0.089: 122.95,180.83 122.88,180.87 arc(122.4,181.9) 123.52,181.7 123.45,181.59 DIMM2.260 ; v2(93.12,124.22) 96.83,124.22 97.73,125.13 98.38,125.13 99.09,125.83 99.29,125.83
  L3 w0.102: 122.97,180.53 122.97,180.75 122.95,180.83
  L3 w0.152: 122.97,180.53 122.97,179.29 122.06,178.38 122.06,177.55 122.89,176.72 122.89,173.81 123.6,173.1 123.6,171.98 123.06,171.45 123.06,170.05 123.62,169.49 123.62,168.25 123.06,167.69 123.06,166.5 121.97,165.41 121.97,162.91 109.74,150.68 109.74,145.47 108.34,141.39 106.48,139.52 106.48,132.84 99.47,125.83 99.29,125.83
M_B_DQ44: length 80.1
  TOP w0.165: CPU1.AP10 v2(88.54,124.22)
  L3 w0.089: 94.35,129.9 92.57,128.12 91.34,128.12 89.03,125.81 89.03,124.71 v2(88.54,124.22) ; DIMM2.106 114.95,177.79 115.02,177.9 arc(113.9,178.1) 114.38,177.07 114.45,177.03
  L3 w0.102: 114.45,177.03 114.47,176.95 114.47,176.73
  L3 w0.152: 94.35,129.9 98.45,134 98.45,140.56 98.6,140.71 98.91,140.71 99.06,140.86 99.06,141.21 98.91,141.36 98.6,141.36 98.45,141.51 98.45,141.85 98.6,142.01 99.68,142.01 99.83,142.16 99.83,142.5 99.68,142.65 98.6,142.65 98.45,142.81 98.45,143.15 98.6,143.3 99.68,143.3 99.83,143.45 99.83,143.8 99.68,143.95 98.6,143.95 98.45,144.1 98.45,144.44 98.6,144.6 99.68,144.6 99.83,144.75 99.83,145.09 99.68,145.24 98.6,145.24 98.45,145.4 98.45,145.74 98.6,145.89 99.68,145.89 99.83,146.04 99.83,146.39 99.68,146.54 98.6,146.54 98.45,146.69 98.45,147.34 113.9,162.79 113.9,165.49 114.58,166.16 114.58,167.66 115.1,168.18 115.1,169.64 114.58,170.16 114.58,171.6 115.12,172.15 115.12,174.18 114.27,175.03 114.27,176.52 114.3,176.55 114.3,176.55 114.47,176.73
M_B_DQ45: length 79.3
  TOP w0.165: CPU1.AR10 89.19,124.68 89.46,124.95 v2(89.46,125.14)
  L3 w0.089: DIMM2.251 115.8,179.99 115.87,180.1 arc(114.75,180.3) 115.23,179.27 115.3,179.23 115.32,179.15 ; v2(89.46,125.14) 89.46,125.9 90.96,127.4 92.31,127.4 95.32,130.42
  L3 w0.152: 115.32,179.15 115.32,178.49 115.24,178.4 115.24,177.06 114.68,176.51 114.68,176.5 114.57,176.39 114.57,175.37 115.43,174.52 115.43,171.98 115.95,171.45 115.95,169.92 115.43,169.4 115.43,168.27 115.97,167.72 115.97,166.65 114.55,165.22 114.55,162.52 100.48,148.46 100.48,139.98 100.33,139.82 99.25,139.82 99.1,139.67 99.1,139.33 99.25,139.18 100.13,139.18 100.28,139.02 100.28,138.68 100.13,138.53 99.25,138.53 99.1,138.38 99.1,138.03 99.25,137.88 100.33,137.88 100.48,137.73 100.48,137.39 100.33,137.23 99.25,137.23 99.1,137.08 99.1,136.71 99.25,136.56 100.38,136.56 100.53,136.41 100.53,136.07 100.38,135.91 99.25,135.91 99.1,135.76 99.1,133.73 96.07,130.71 95.62,130.71 95.32,130.42
M_B_DQ46: length 76.8
  TOP w0.165: CPU1.AR7 v2(92.2,125.14)
  L3 w0.089: 98.25,127.69 96.17,125.6 93.01,125.6 v2(92.2,125.14) ; 120.4,175.43 120.33,175.47 arc(119.85,176.5) 120.97,176.3 120.9,176.19 DIMM2.113
  L3 w0.102: 120.42,175.13 120.42,175.35 120.4,175.43
  L3 w0.152: 98.25,127.69 104.53,133.97 104.53,141.38 104.73,141.58 105.51,141.58 105.66,141.73 105.66,142.08 105.51,142.23 104.73,142.23 104.53,142.43 104.53,142.8 104.68,142.95 105.98,142.95 106.13,143.1 106.13,143.45 105.98,143.6 104.68,143.6 104.53,143.75 104.53,144.09 104.68,144.25 105.54,144.25 105.69,144.4 105.69,144.74 105.54,144.89 104.68,144.89 104.53,145.05 104.53,145.39 104.68,145.54 105.98,145.54 106.38,145.94 106.38,150.06 119.37,163.06 119.37,165.34 120.47,166.44 120.75,166.44 121.05,166.74 121.05,167.6 120.37,168.28 120.37,169.29 121.05,169.97 121.05,171.43 120.42,172.06 120.42,175.13
M_B_DQ47: length 76
  TOP w0.165: CPU1.AR6 v2(93.12,125.14)
  L3 w0.089: v2(93.12,125.14) 93.43,125.14 93.85,124.71 96.04,124.71 97.41,126.08 98.2,126.08 98.79,126.66 98.79,127.18 99.1,127.5 ; DIMM2.258 121.75,181.59 121.82,181.7 arc(120.7,181.9) 121.18,180.87 121.25,180.83
  L3 w0.102: 121.25,180.83 121.27,180.75 121.27,180.53
  L3 w0.152: 99.1,127.5 105.18,133.57 105.18,140.18 107.06,142.06 107.06,149.83 120.02,162.79 120.64,165.85 121.38,166.59 121.38,167.63 121.92,168.18 121.92,169.57 121.38,170.12 121.38,171.41 121.92,171.96 121.92,173.1 120.9,174.12 120.9,175.25 121.19,175.53 121.19,176.72 120.46,177.44 120.46,178.54 121.27,179.34 121.27,180.53
M_B_DQ48: length 88.5
  TOP w0.165: CPU1.AM9 v2(89.46,121.48)
  L3 w0.089: v2(89.46,121.48) 89.71,121.73 89.71,121.76 90.62,122.67 97.11,122.67 97.75,123.31 98.25,123.31 99.15,124.21 99.71,124.21 ; 125.5,175.43 125.43,175.47 arc(124.95,176.5) 126.07,176.3 126,176.19 DIMM2.119
  L3 w0.102: 125.5,175.43 125.52,175.35 125.52,175.16 125.36,175 125.36,174.88
  L3 w0.152: 99.71,124.21 100.69,124.21 108.97,132.49 108.97,132.89 108.46,133.4 108.46,133.93 109.75,135.23 109.97,135.23 110.68,134.52 110.9,134.52 111.14,134.76 111.14,134.98 110.43,135.69 110.43,135.9 110.67,136.15 110.89,136.15 111.68,135.35 111.9,135.35 112.14,135.59 112.14,135.81 111.34,136.6 111.34,136.82 111.59,137.06 111.8,137.06 112.6,136.26 112.82,136.26 113.06,136.51 113.06,136.87 112.4,137.53 112.4,137.75 112.64,137.99 112.86,137.99 113.59,137.26 113.81,137.26 114.65,138.1 122.83,146.28 122.83,160.45 124.39,162.01 124.39,165.09 125.74,166.44 125.75,166.44 126.15,166.84 126.15,167.6 125.63,168.13 125.63,169.69 126.15,170.22 126.15,171.54 125.63,172.06 125.63,173.74 125.36,174 125.36,174.88
M_B_DQ49: length 89.7
  TOP w0.165: CPU1.AL9 v2(89.46,120.57)
  L3 w0.089: DIMM2.264 126.85,181.59 126.92,181.7 arc(125.8,181.9) 126.28,180.87 126.35,180.83 ; 99.55,123.57 99.21,123.57 98.07,122.43 90.72,122.43 89.95,121.66 89.95,121.06 v2(89.46,120.57)
  L3 w0.102: 126.35,180.83 126.37,180.75 126.37,180.53
  L3 w0.152: 126.37,180.53 126.37,179.29 125.46,178.38 125.46,177.55 126.47,176.54 126.47,173.88 127.13,173.23 127.13,172.09 126.48,171.43 126.48,169.94 127.13,169.29 127.13,168.28 126.48,167.62 126.48,166.25 125.04,164.82 125.04,163.86 125.27,163.63 125.27,163.14 125.04,162.91 125.04,161.74 123.7,160.4 123.7,146.23 110.8,133.33 110.58,133.33 109.79,134.12 109.56,134.12 109.33,133.89 109.33,133.66 110.12,132.87 110.12,132.65 101.04,123.57 99.55,123.57
M_B_DQ50: length 87.9
  TOP w0.165: v2(93.12,120.54) 92.66,121 CPU1.AL6
  L3 w0.089: v2(93.12,120.54) 93.32,120.33 98.72,120.33 99.02,120.64 99.63,120.64 ; DIMM2.126 131.95,177.79 132.02,177.9 arc(130.9,178.1) 131.38,177.07 131.45,177.03
  L3 w0.102: 131.47,176.73 131.47,176.95 131.45,177.03
  L3 w0.152: 131.47,176.73 131.27,176.52 131.27,174.42 132.12,173.57 132.12,171.87 131.57,171.32 131.57,170.69 131.58,170.69 131.58,170.05 132.12,169.5 132.12,168.32 131.58,167.77 131.58,166.37 130.82,165.61 130.82,162.71 128.19,160.09 128.19,153.5 128.04,153.35 126.73,153.35 126.58,153.2 126.58,152.85 126.73,152.7 128.04,152.7 128.19,152.55 128.19,152.2 128.04,152.05 126.73,152.05 126.58,151.9 126.58,151.53 126.73,151.38 127.15,151.38 127.3,151.23 127.3,150.88 127.15,150.73 126.73,150.73 126.58,150.58 126.58,145 102.22,120.64 99.63,120.64
M_B_DQ51: length 88.9
  TOP w0.165: CPU1.AL7 v2(91.29,120.57)
  L3 w0.089: DIMM2.271 132.8,179.99 132.87,180.1 arc(131.75,180.3) 132.23,179.27 132.3,179.23 132.32,179.15 ; 99.48,120.09 91.76,120.09 v2(91.29,120.57)
  L3 w0.152: 132.32,179.15 132.32,178.53 132.24,178.45 132.24,177.06 131.57,176.4 131.57,174.62 132.43,173.77 132.43,172.7 132.43,171.99 132.95,171.47 132.95,169.9 132.43,169.38 132.43,168.18 132.95,167.66 132.95,166.53 132.77,166.34 132.77,165.79 132.45,165.47 132.22,165.47 131.46,164.71 131.46,162.45 128.84,159.82 128.84,151.5 127.23,149.89 127.23,144.73 102.59,120.09 99.48,120.09
M_B_DQ52: length 88.6
  TOP w0.165: CPU1.AM10 v2(88.54,122.4)
  L3 w0.089: 123.8,175.43 123.73,175.47 arc(123.25,176.5) 124.37,176.3 124.3,176.19 DIMM2.117 ; 99.27,125.12 98.93,125.12 98.07,124.26 97.53,124.26 97.08,123.8 90.23,123.8 89.94,123.51 89.94,123.22 89.6,122.88 89.03,122.88 v2(88.54,122.4)
  L3 w0.102: 123.82,175.13 123.82,175.35 123.8,175.43
  L3 w0.152: 99.27,125.12 99.67,125.12 107.16,132.61 107.16,134.54 114.91,142.29 115.13,142.29 115.85,141.57 116.07,141.57 116.31,141.81 116.31,142.03 115.59,142.75 115.59,142.97 116.38,143.76 118.41,143.76 121.54,146.89 121.54,154.93 121.39,155.08 120.4,155.08 120.24,155.23 120.24,155.57 120.4,155.73 121.39,155.73 121.54,155.88 121.54,156.22 121.39,156.37 120.29,156.37 120.14,156.53 120.14,156.87 120.29,157.02 121.39,157.02 121.54,157.17 121.54,157.52 121.39,157.67 120.35,157.67 120.19,157.82 120.19,158.16 120.35,158.32 121.39,158.32 121.54,158.47 121.54,160.99 123.08,162.52 123.08,165.65 123.8,166.37 124.21,166.37 124.47,166.64 124.47,167.63 123.93,168.17 123.93,169.77 124.45,170.29 124.45,171.46 123.93,171.98 123.93,175.02 123.82,175.13
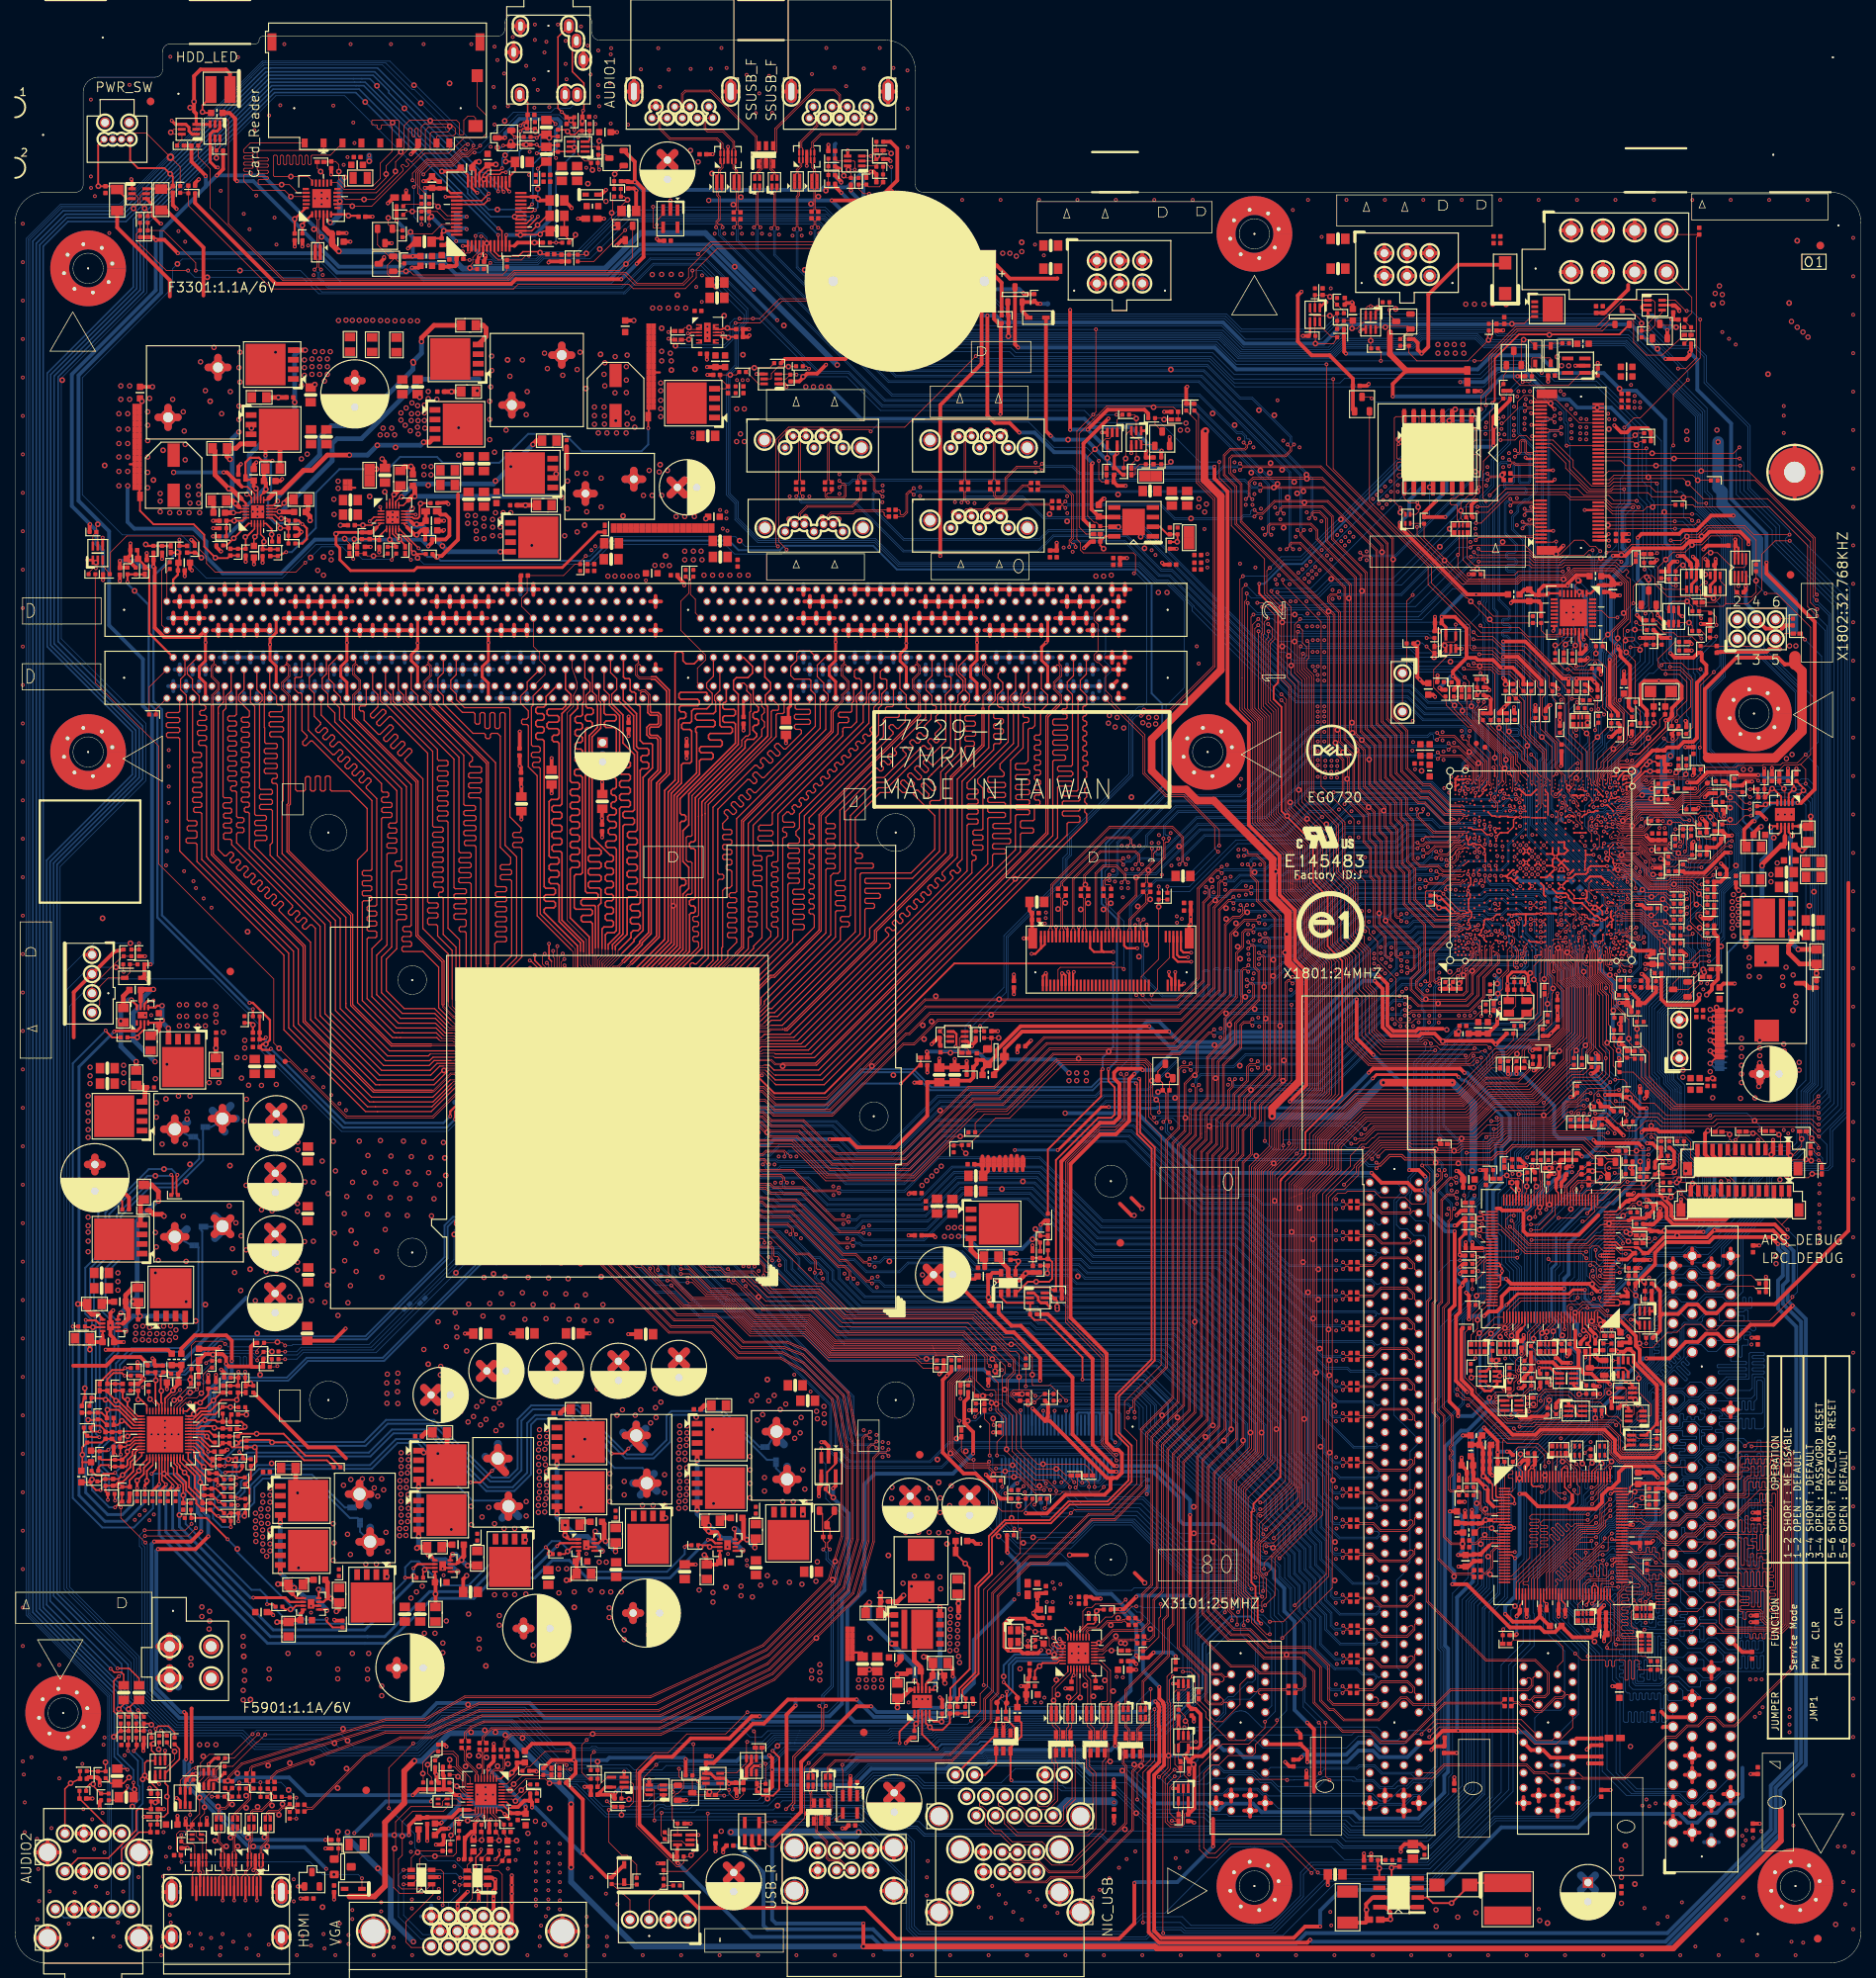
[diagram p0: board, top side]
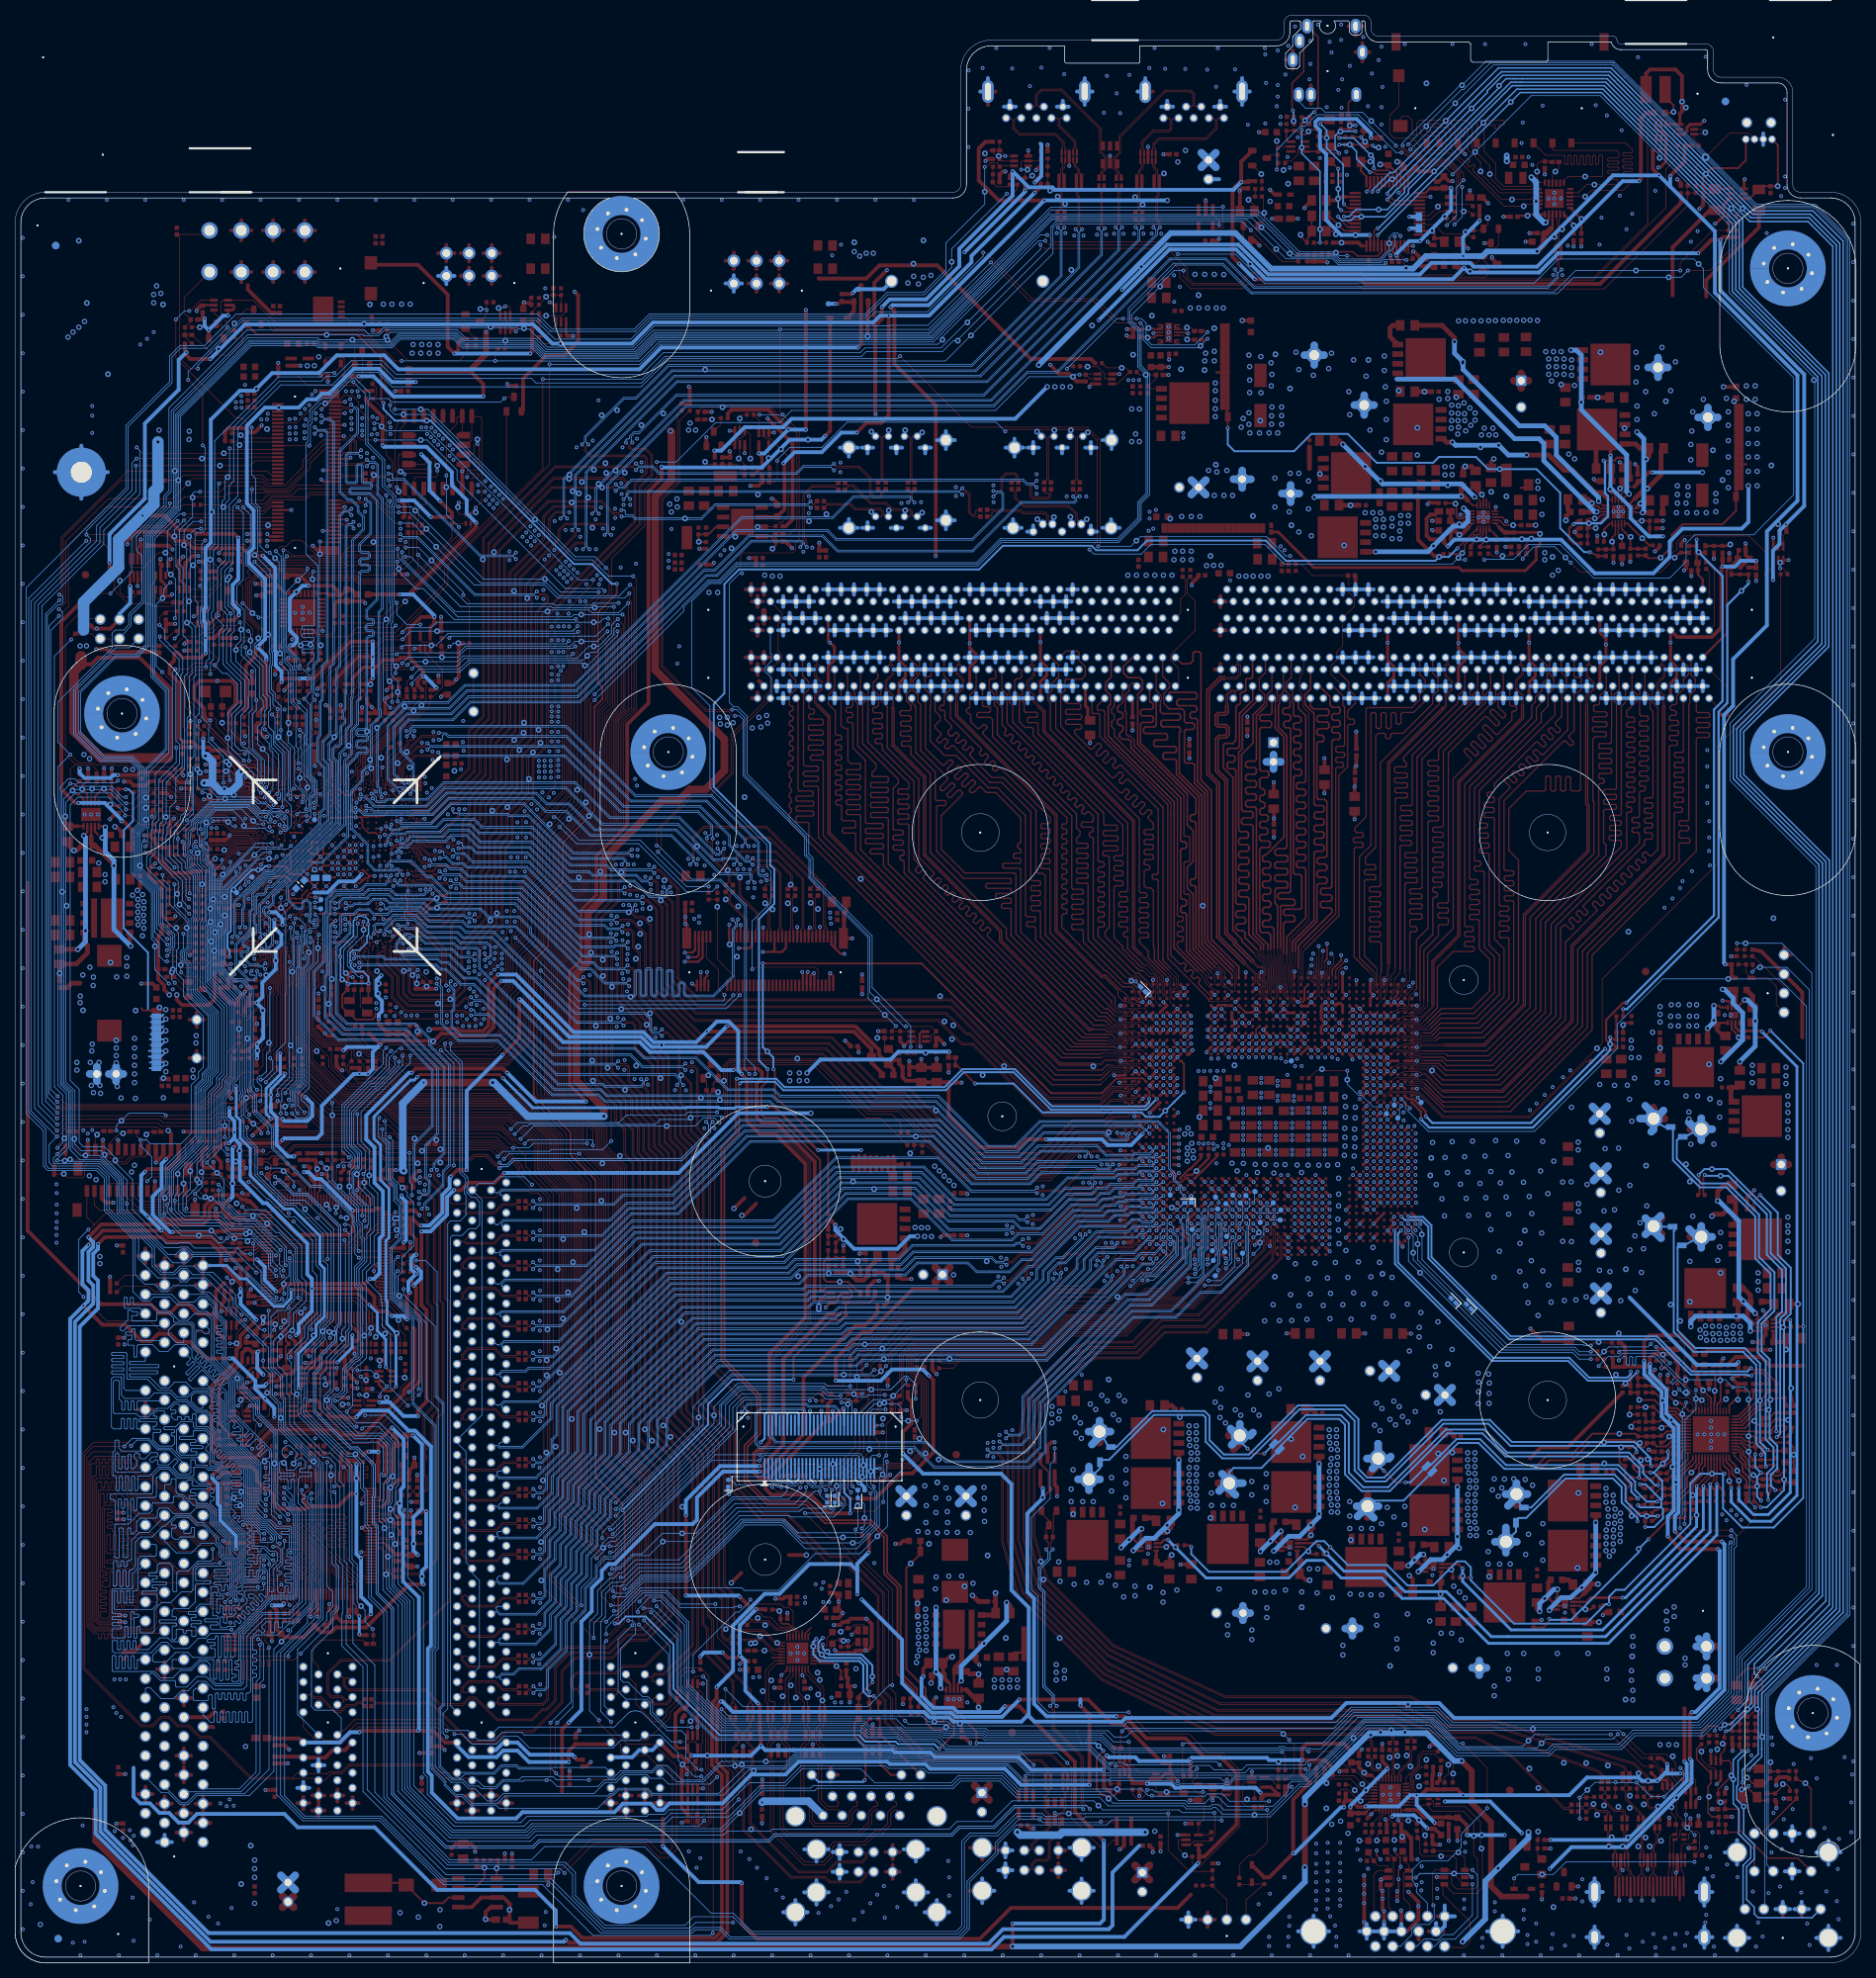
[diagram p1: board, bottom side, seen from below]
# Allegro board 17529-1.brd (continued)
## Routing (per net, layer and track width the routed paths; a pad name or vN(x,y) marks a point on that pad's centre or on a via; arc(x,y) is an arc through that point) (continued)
M_B_DQ53: length 89.9
  TOP w0.165: CPU1.AL10 v2(88.54,121.48)
  L3 w0.089: 124.65,180.83 124.58,180.87 arc(124.1,181.9) 125.22,181.7 125.15,181.59 DIMM2.262 ; 99.07,124.61 98.24,123.78 97.64,123.78 96.77,122.91 90.52,122.91 89.58,121.97 89.03,121.97 v2(88.54,121.48)
  L3 w0.102: 124.65,180.83 124.67,180.75 124.67,180.53
  L3 w0.152: 124.67,180.53 124.67,179.34 123.86,178.54 123.86,177.44 124.59,176.72 124.59,174.24 125.32,173.51 125.32,172.06 124.75,171.49 124.75,170.27 125.3,169.72 125.3,168.2 124.78,167.68 124.78,166.43 123.75,165.4 123.75,162.28 122.19,160.72 122.19,146.55 116.07,140.44 115.86,140.44 115.47,140.83 115.25,140.83 115.01,140.59 115.01,140.37 115.4,139.98 115.4,139.76 115.16,139.52 114.94,139.52 114.49,139.98 114.27,139.98 114.03,139.73 114.03,139.52 114.48,139.06 114.48,138.85 114.03,138.39 113.81,138.39 112.99,139.21 112.77,139.21 107.81,134.25 107.81,132.3 100.13,124.61 99.07,124.61
M_B_DQ54: length 86.5
  TOP w0.165: v2(93.12,121.46) 92.66,121.91 CPU1.AM6
  L3 w0.089: 129.75,177.03 129.68,177.07 arc(129.2,178.1) 130.32,177.9 130.25,177.79 DIMM2.124 ; 99.7,121.95 99.06,121.95 98.57,121.45 96.46,121.45 96.04,121.03 93.76,121.03 93.33,121.46 v2(93.12,121.46)
  L3 w0.102: 129.77,176.73 129.77,176.95 129.75,177.03
  L3 w0.152: 99.7,121.95 101.69,121.95 125.29,145.54 125.29,156.12 125.44,156.27 126.72,156.27 126.87,156.43 126.87,156.77 126.72,156.92 125.44,156.92 125.29,157.07 125.29,157.42 125.44,157.57 126.49,157.57 126.64,157.72 126.64,158.06 126.49,158.22 125.44,158.22 125.29,158.37 125.29,159.02 129.52,163.25 129.52,166.35 129.79,166.62 129.79,167.64 130.42,168.27 130.42,169.43 129.79,170.05 129.79,171.45 130.4,172.05 130.4,174.27 129.57,175.1 129.57,176.52 129.62,176.57 129.62,176.57 129.77,176.73
M_B_DQ55: length 87.5
  TOP w0.165: CPU1.AM7 91.74,121.91 v2(92.2,121.46)
  L3 w0.089: 99.54,121.29 98.99,121.29 98.3,120.6 93.76,120.6 93.39,120.97 92.69,120.97 v2(92.2,121.46) ; 130.6,179.23 130.53,179.27 arc(130.05,180.3) 131.17,180.1 131.1,179.99 DIMM2.269
  L3 w0.102: 130.6,179.23 130.62,179.15
  L3 w0.152: 130.62,179.15 130.62,178.53 130.54,178.45 130.54,177.06 129.92,176.45 129.92,176.44 129.87,176.39 129.87,175.22 130.73,174.37 130.73,172.17 131.25,171.65 131.25,169.85 130.73,169.33 130.73,168.23 131.27,167.69 131.27,166.58 130.99,166.29 130.36,166.29 130.17,166.11 130.17,162.98 127.13,159.94 127.13,158.52 127.52,158.13 127.52,155.63 127.37,155.47 126.09,155.47 125.93,155.32 125.93,145.27 101.95,121.29 99.54,121.29
M_B_DQ56: length 100
  TOP w0.165: v2(92.2,118.74) CPU1.AJ7
  L3 w0.089: 99.68,118.05 96.69,118.05 96.06,117.41 96.05,117.41 96.04,117.4 94.79,117.4 94.78,117.41 94.31,117.88 93.8,117.88 93.37,118.31 92.63,118.31 v2(92.2,118.74) ; DIMM2.130 135.35,177.79 135.42,177.9 arc(134.3,178.1) 134.78,177.07 134.85,177.03
  L3 w0.102: 134.85,177.03 134.87,176.95 134.87,176.73
  L3 w0.152: 134.87,176.73 134.65,176.5 134.65,175.63 135.5,174.78 135.5,171.95 134.98,171.42 134.98,169.95 135.5,169.43 135.5,168.21 134.95,167.66 134.95,162.61 131.91,159.58 131.91,158.93 132.07,158.78 133.71,158.78 133.86,158.62 133.86,158.37 133.62,158.13 132.07,158.13 131.91,157.98 131.91,157.63 132.07,157.48 133.73,157.48 133.88,157.33 133.88,156.98 133.73,156.83 132.07,156.83 131.91,156.68 131.91,156.34 132.07,156.18 133.68,156.18 133.83,156.03 133.83,155.77 133.57,155.5 132.08,155.5 131.91,155.33 131.91,146.29 103.68,118.05 99.68,118.05
M_B_DQ57: length 99.5
  TOP w0.165: CPU1.AH6 v2(92.2,117.82)
  L3 w0.089: 135.7,179.23 135.63,179.27 arc(135.15,180.3) 136.27,180.1 136.2,179.99 DIMM2.275 ; 99.76,117.4 99.44,117.72 97.2,117.72 96.5,117.02 94.82,117.02 94.23,117.6 93.52,117.6 93.34,117.42 92.6,117.42 v2(92.2,117.82)
  L3 w0.102: 135.7,179.23 135.72,179.15 135.72,178.93
  L3 w0.152: 135.72,178.93 135.72,177.14 134.97,176.39 134.97,175.82 135.38,175.42 135.38,175.42 135.8,175 135.8,172.05 136.42,171.43 136.42,170.2 135.8,169.58 135.8,168.37 136.37,167.79 136.37,166.55 135.64,165.81 135.64,162.38 134.71,161.45 134.71,154.89 134.56,154.74 133.32,154.74 133.17,154.58 133.17,154.24 133.32,154.09 134.56,154.09 134.71,153.94 134.71,153.59 134.56,153.44 133.27,153.44 133.12,153.29 133.12,152.95 133.27,152.79 134.29,152.79 134.44,152.64 134.44,152.3 134.29,152.15 132.92,152.15 132.56,151.79 132.56,146.02 103.94,117.4 99.76,117.4
M_B_DQ58: length 101.6
  TOP w0.165: CPU1.AF7 v2(91.29,115.99)
  L3 w0.089: DIMM2.137 141.3,176.19 141.37,176.3 arc(140.25,176.5) 140.73,175.47 140.8,175.43 ; v2(91.29,115.99) 91.77,115.51 92.38,115.51 92.95,114.94 95.39,114.94 95.64,114.68 96.29,114.68 96.7,115.09 98.25,115.09 98.87,114.47 99.2,114.47
  L3 w0.102: 140.8,175.43 140.82,175.35 140.82,175.13
  L3 w0.152: 140.82,175.13 140.9,175.05 140.9,171.9 141.45,171.35 141.45,170.02 140.93,169.5 140.93,168.19 141.45,167.67 141.45,163.52 139.81,161.89 139.81,153.94 139.66,153.79 137.97,153.79 137.82,153.64 137.82,153.29 137.97,153.14 139.52,153.14 139.67,152.99 139.67,152.65 139.52,152.49 137.97,152.49 137.82,152.34 137.82,152.02 138,151.85 138.89,151.85 139.04,151.69 139.04,151.35 138.89,151.2 138,151.2 137.85,151.05 137.81,150.96 137.92,150.68 135.5,144.89 105.07,114.47 99.2,114.47
M_B_DQ59: length 102
  TOP w0.165: CPU1.AE7 v2(91.29,115.08)
  L3 w0.089: DIMM2.282 142.15,181.59 142.22,181.7 arc(141.1,181.9) 141.58,180.87 141.65,180.83 ; 96.93,113.82 95.95,113.82 95.12,114.64 91.72,114.64 v2(91.29,115.08)
  L3 w0.102: 141.67,180.53 141.67,180.75 141.65,180.83
  L3 w0.152: 141.67,180.53 141.67,179.29 140.76,178.38 140.76,177.47 141.73,176.5 141.73,175.26 142.3,174.7 142.3,172.24 141.78,171.72 141.78,170.01 142.37,169.42 142.37,168.28 141.75,167.66 141.75,166.61 142.11,166.24 142.11,163.37 140.46,159.66 140.46,152.48 139.03,149.72 137.64,148.34 136.05,144.52 105.34,113.82 96.93,113.82
M_B_DQ60: length 100.4
  TOP w0.165: CPU1.AH7 v2(91.29,118.74)
  L3 w0.089: v2(91.29,118.74) 91.71,119.16 97.27,119.16 97.67,118.77 99.06,118.77 99.63,119.34 ; DIMM2.128 133.65,177.79 133.72,177.9 arc(132.6,178.1) 133.08,177.07 133.15,177.03
  L3 w0.102: 133.15,177.03 133.17,176.95 133.17,176.73
  L3 w0.152: 99.63,119.34 103.14,119.34 127.89,144.09 127.89,145.11 128.07,145.29 129.08,145.29 129.26,145.47 129.26,145.78 129.11,145.94 128.35,145.94 128.17,146.11 128.17,146.53 128.32,146.69 129.49,146.69 129.64,146.84 129.64,147.09 129.4,147.33 128.22,147.33 128.07,147.49 128.07,147.83 128.22,147.98 129.54,147.98 129.69,148.13 129.69,148.48 129.54,148.63 128.35,148.63 128.19,148.78 128.19,149.17 128.35,149.33 129.39,149.33 129.69,149.63 129.69,157.91 129.84,158.06 130.45,158.06 130.61,158.22 130.61,158.56 130.45,158.71 129.84,158.71 129.69,158.86 129.69,159.51 132.36,162.18 132.36,163.19 132.51,163.35 133.5,163.35 133.65,163.5 133.65,163.84 133.5,163.99 132.51,163.99 132.36,164.15 132.36,164.67 132.51,164.82 133.48,164.82 133.65,165 133.65,165.74 133.25,166.14 133.25,167.67 133.8,168.21 133.8,169.35 133.28,169.87 133.28,171.38 133.8,171.9 133.8,174.31 132.97,175.13 132.97,176.52 133.17,176.73
M_B_DQ61: length 99
  TOP w0.165: CPU1.AJ6 v2(93.12,118.74)
  L3 w0.089: 134.02,179.15 134,179.23 133.93,179.27 arc(133.45,180.3) 134.57,180.1 134.5,179.99 DIMM2.273 ; 99.66,118.7 99.27,118.31 93.78,118.31 93.35,118.74 v2(93.12,118.74)
  L3 w0.152: 99.66,118.7 103.41,118.7 130.34,145.63 130.34,149.26 130.49,149.41 131.11,149.41 131.27,149.57 131.27,149.91 131.11,150.06 130.49,150.06 130.34,150.21 130.34,150.56 130.49,150.71 131.11,150.71 131.27,150.86 131.27,151.2 131.11,151.36 130.49,151.36 130.34,151.51 130.34,151.85 130.49,152 131.11,152 131.27,152.16 131.27,152.5 131.11,152.65 130.49,152.65 130.34,152.8 130.34,153.15 130.49,153.3 131.11,153.3 131.27,153.45 131.27,153.79 131.11,153.95 130.49,153.95 130.34,154.1 130.34,154.44 130.49,154.59 131.11,154.59 131.27,154.75 131.27,155.09 131.11,155.24 130.49,155.24 130.34,155.39 130.34,155.74 130.49,155.89 131.11,155.89 131.27,156.04 131.27,156.39 131.11,156.54 130.49,156.54 130.34,156.69 130.34,157.03 130.49,157.19 131.11,157.19 131.27,157.34 131.27,159.89 134.3,162.93 134.3,166.26 134.65,166.6 134.65,167.74 134.13,168.26 134.13,169.43 134.65,169.95 134.65,171.42 134.11,171.96 134.11,174.5 133.27,175.34 133.27,176.4 133.94,177.06 133.94,178.45 134.02,178.53 134.02,179.15
M_B_DQ62: length 100.8
  TOP w0.165: v2(93.1,115.93) 92.66,116.38 CPU1.AF6
  L3 w0.089: v2(93.1,115.93) 93.57,115.47 94.39,115.47 ; DIMM2.135 139.6,176.19 139.67,176.3 arc(138.55,176.5) 139.03,175.47 139.1,175.43
  L3 w0.102: 139.1,175.43 139.12,175.35 139.12,175.13
  L3 w0.152: 139.12,175.13 139.12,172.16 139.77,171.5 139.77,170.25 139.23,169.71 139.23,169.01 139.23,169.01 139.23,168.44 139.23,168.44 139.23,168.11 139.75,167.59 139.75,164.14 138.1,162.49 138.1,161.29 137.84,161.03 136.7,161.03 136.53,160.86 136.53,160.21 136.68,160.06 138.3,160.06 138.46,159.9 138.46,159.56 138.3,159.41 136.61,159.41 136.46,159.26 136.46,158.91 136.61,158.76 138.1,158.76 138.25,158.61 138.25,158.26 138.1,158.11 136.61,158.11 136.46,157.96 136.46,157.62 136.61,157.46 137.87,157.46 138.02,157.31 138.02,156.97 137.87,156.82 136.61,156.82 136.46,156.66 136.46,150.83 134.22,145.44 104.54,115.76 99.82,115.76 99.73,115.85 94.77,115.85 94.39,115.47
M_B_DQ63: length 100.6
  TOP w0.165: CPU1.AE6 v2(92.2,115.99)
  L3 w0.089: 139.95,180.83 139.88,180.87 arc(139.4,181.9) 140.52,181.7 140.45,181.59 DIMM2.280 ; v2(92.2,115.99) 92.44,115.75 92.48,115.75 93.04,115.19 95.04,115.19 95.38,115.53 96.31,115.53 96.32,115.52
  L3 w0.102: 139.97,180.53 139.97,180.75 139.95,180.83
  L3 w0.152: 96.32,115.52 98.42,115.52 98.83,115.11 104.81,115.11 134.77,145.08 136.02,148.09 137.16,150.68 137.16,150.82 137.16,150.83 137.16,150.83 137.16,154.57 137.31,154.72 138.99,154.72 139.17,154.9 139.17,155.32 138.61,155.88 138.61,156.36 139.17,156.91 139.17,162.23 140.39,163.46 140.39,166.49 140.08,166.81 140.08,167.63 140.6,168.16 140.6,169.66 140.08,170.19 140.08,171.44 140.6,171.97 140.6,172.85 139.89,173.56 139.89,176.67 139.16,177.4 139.16,178.54 139.97,179.34 139.97,180.53
M_B_DQS_DN0: length 99
  TOP w0.178: CPU1.AF34 v2(64.43,116.86)
  L3 w0.089: v2(64.43,116.86) 63.61,116.43 59.58,116.43 59.13,115.97 58.17,115.97 56.83,114.63 56.52,114.63 56.49,114.59
  L3 w0.152: DIMM2.152 25.87,180.93 25.87,179.37 25.04,178.55 25.04,177.27 25.87,176.44 25.87,175.33 26.72,174.48 26.72,172.26 25.86,171.4 25.86,170.13 26.72,169.26 26.72,168.27 27.57,167.42 27.57,165.32 26.59,164.34 26.59,162.49 26.91,162.18 27.18,162.18 27.36,162 27.36,161.71 27.18,161.53 26.91,161.53 26.59,161.21 26.59,160.64 26.91,160.32 27.13,160.32 27.28,160.17 27.28,159.83 27.13,159.67 26.91,159.67 26.57,159.33 26.57,147.5 37.07,137 37.07,123.96 46.44,114.59 56.49,114.59
M_B_DQS_DN1: length 88.7
  TOP w0.178: v2(66.23,120.57) CPU1.AK33
  L3 w0.089: 55.7,120.85 55.73,120.85 55.76,120.89 57.93,120.89 58.49,121.45 61.05,121.45 61.5,121.9 64.53,121.9 65.44,120.99 65.86,120.99 66.11,120.75 v2(66.23,120.57)
  L3 w0.152: DIMM2.163 35.59,180.34 35.92,180.34 36.07,180.19 36.07,179.34 35.22,178.49 35.22,177.35 34.39,176.52 34.39,175.44 35.2,174.63 35.2,172.14 36.07,171.27 36.07,170.18 36.92,169.33 36.92,168.39 36.07,167.53 36.07,166.86 36.04,166.84 36.04,146.95 39.43,143.56 42.61,143.56 43.33,142.84 43.33,126.34 48.82,120.85 55.7,120.85
M_B_DQS_DN2: length 82.7
  TOP w0.178: CPU1.AN33 v2(65.31,124.22)
  L3 w0.089: v2(65.31,124.22) 64.91,124.9 64.87,124.96 64.79,125.1 64.79,125.66 64.59,125.86 59.97,125.86 58.85,126.97 58.03,126.97 57.98,126.92 57.96,126.92
  L3 w0.152: 57.96,126.92 56.52,126.92 56.11,127.33 56.11,133.25 55.91,133.45 52.69,133.45 52.35,133.79 52.35,134.36 52.72,134.73 54.81,134.73 54.97,134.88 54.97,135.91 54.81,136.06 54.21,136.06 53.9,136.38 53.9,136.95 54.21,137.27 54.81,137.27 54.97,137.42 54.97,137.76 54.81,137.92 54.21,137.92 53.9,138.23 53.9,138.81 54.21,139.12 54.81,139.12 54.97,139.27 54.97,139.62 54.81,139.77 54.21,139.77 53.9,140.09 53.9,157.01 48.38,162.53 48.16,162.53 47.62,161.99 47.18,161.99 46.77,162.4 46.77,162.84 47.31,163.38 47.31,163.6 46.27,164.64 46.27,167.58 47.12,168.43 47.12,169.31 46.27,170.16 46.27,171.22 45.42,172.07 45.42,173.78 44.57,174.63 44.57,176.45 43.72,177.3 43.72,178.47 44.57,179.32 44.57,180.5 44.59,180.51 DIMM2.174
M_B_DQS_DN3: length 68.2
  TOP w0.178: v2(69.89,123.31) 69.89,123.5 69.62,123.77 CPU1.AN29
  L3 w0.089: 63.64,131.19 63.68,131.15 63.71,131.15 63.71,131.16 63.73,131.16 64.21,130.68 64.62,130.68 65.14,130.16 65.39,129.91 65.39,129.7 68.55,126.55 68.55,125.48 70.2,123.83 70.2,123.42 70.09,123.31 v2(69.89,123.31)
  L3 w0.152: 63.64,131.19 63.35,131.48 63.35,158.53 56.47,165.4 56.47,167.47 55.62,168.32 55.62,169.67 54.77,170.52 54.77,171.39 55.62,172.23 55.62,173.25 54.14,174.73 53.55,174.73 53.09,175.19 53.09,176.58 53.92,177.42 53.92,178.4 54.77,179.25 54.77,180.3 54.55,180.51 54.35,180.45 DIMM2.185
M_B_DQS_DN4: length 74.9
  TOP w0.178: v2(84.52,123.31) CPU1.AN13
  L3 w0.089: 92.09,132.76 92.05,132.72 92.05,132.65 91.6,132.2 91.16,132.2 87.94,128.99 87.94,128.13 86.77,126.96 86.77,124.83 85.69,123.75 85.58,123.74 85.25,123.74 v2(84.52,123.31)
  L3 w0.152: 92.09,132.76 94.08,134.75 94.08,148.54 107.47,161.93 107.47,163.56 107.32,163.71 106.11,163.71 105.79,164.02 105.79,164.57 106.13,164.91 107.32,164.91 108.29,165.89 108.82,165.89 109.17,166.24 109.17,167.58 110.05,168.45 110.05,169.21 109.2,170.06 109.2,171.41 110,172.22 110,174.09 109.17,174.91 109.17,176.45 108.32,177.3 108.32,178.5 109.17,179.35 109.17,179.61 109.17,179.62 109.17,180.33 109.2,180.57 DIMM2.244
M_B_DQS_DN5: length 78.3
  TOP w0.178: v2(90.37,124.22) CPU1.AR8
  L3 w0.089: 98.14,129.27 98.12,129.25 98.12,129.19 97.94,129 97.69,128.76 97.69,128.76 94.98,126.05 92,126.05 91.51,125.56 91.11,125.56 90.86,125.31 90.86,125.07 v2(90.37,124.22)
  L3 w0.152: 98.14,129.27 103.6,134.73 103.6,146.44 103.92,146.76 105.26,146.76 105.41,146.91 105.41,147.25 105.26,147.41 103.92,147.41 103.6,147.72 103.6,148.6 118.44,163.44 118.44,164.03 118.29,164.18 117.65,164.18 117.34,164.5 117.34,165.07 117.65,165.39 117.89,165.39 119.35,166.84 119.35,167.53 118.55,168.33 118.55,169.49 119.35,170.29 119.35,171.33 118.55,172.13 118.55,174.56 117.68,175.42 117.68,176.53 118.52,177.37 118.52,178.49 119.37,179.34 119.37,180.32 119.2,180.49 119.15,180.51 118.95,180.45 DIMM2.255
M_B_DQS_DN6: length 88
  TOP w0.178: CPU1.AM8 90.83,121.7 90.61,121.48 v2(90.37,121.48)
  L3 w0.089: v2(90.37,121.48) 90.37,121.27 90.52,121.13 90.97,121.13 91.92,122.08 98.31,122.08 99.08,122.85 99.88,122.85 99.94,122.9
  L3 w0.152: 99.94,122.9 101.34,122.9 124.36,145.92 124.36,160.14 126.03,161.82 126.03,162.41 126.68,163.05 127.69,163.05 127.84,163.2 127.84,163.73 127.69,163.88 126.53,163.88 126.21,164.2 126.21,164.77 126.53,165.09 127.67,165.09 127.87,165.29 127.87,167.59 128.72,168.43 128.72,169.02 127.87,169.87 127.87,171.38 128.72,172.23 128.72,173.38 127.87,174.23 127.87,176.47 127.03,177.32 127.03,178.56 127.87,179.4 127.87,180.43 128.15,180.71 128.23,180.76 128.23,181.09 DIMM2.266
M_B_DQS_DN7: length 100.1
  TOP w0.178: CPU1.AG6 92.66,117.18 92.87,116.98 v2(93.12,116.98)
  L3 w0.089: v2(93.12,116.98) 93.01,116.87 93.01,116.69 93.15,116.55 96.59,116.55 97.16,117.12 98.16,117.12 98.61,116.68 100.1,116.68 100.13,116.7
  L3 w0.152: 100.13,116.7 104.17,116.7 133.3,145.84 133.3,148.85 133.62,149.16 134.47,149.16 134.62,149.31 134.62,149.66 134.47,149.81 133.62,149.81 133.3,150.13 133.3,151 133.64,151.35 135.2,151.35 135.36,151.5 135.36,161.06 138.07,163.77 138.07,164.35 137.92,164.5 136.92,164.5 136.6,164.82 136.6,165.39 136.92,165.71 137.92,165.71 138.07,165.86 138.07,167.42 137.22,168.27 137.22,169.28 138.07,170.13 138.07,171.27 137.22,172.12 137.22,174.44 136.37,175.29 136.37,176.57 137.22,177.42 137.22,178.24 138.07,179.09 138.07,180.56 138.05,180.73 137.72,181 137.51,180.99 137.36,180.84 DIMM2.277
M_B_DQS_DP0: length 99
  TOP w0.178: CPU1.AF35 63.94,117.06 63.81,116.93 v2(63.5,116.93)
  L3 w0.089: 56.49,114.87 56.5,114.87 56.56,114.82 56.75,114.82 58.09,116.16 59.05,116.16 59.5,116.62 63.4,116.62 63.5,116.72 v2(63.5,116.93)
  L3 w0.152: DIMM2.153 27.04,179.91 27.17,180.04 27.17,180.61 27.04,180.73 26.28,180.73 26.15,180.6 26.15,179.26 25.32,178.43 25.32,177.38 26.15,176.56 26.15,175.45 27,174.59 27,172.15 26.14,171.28 26.14,170.25 27,169.38 27,168.38 27.85,167.54 27.85,165.2 26.87,164.23 26.87,162.61 27.03,162.46 27.29,162.46 27.64,162.11 27.64,161.59 27.29,161.25 27.03,161.25 26.87,161.1 26.87,160.75 27.03,160.6 27.24,160.6 27.56,160.29 27.56,159.71 27.24,159.4 27.03,159.4 26.85,159.22 26.85,147.62 37.35,137.12 37.35,124.08 46.56,114.87 56.49,114.87
M_B_DQS_DP1: length 88.6
  TOP w0.178: CPU1.AL33 65.77,121.89 v2(66.23,121.44)
  L3 w0.089: 55.73,121.13 55.78,121.08 57.85,121.08 58.41,121.64 60.97,121.64 61.02,121.69 61.42,122.09 64.61,122.09 65.51,121.18 66.14,121.18 66.23,121.27 v2(66.23,121.44)
  L3 w0.152: 55.73,121.13 48.94,121.13 43.61,126.46 43.61,142.95 42.72,143.84 39.55,143.84 36.32,147.07 36.32,166.72 36.35,166.75 36.35,167.42 37.2,168.27 37.2,169.44 36.35,170.29 36.35,171.39 35.48,172.26 35.48,174.74 34.67,175.56 34.67,176.4 35.5,177.23 35.5,178.37 36.35,179.22 36.35,180.34 36.21,180.48 DIMM2.164
M_B_DQS_DP2: length 82.6
  TOP w0.178: CPU1.AP33 65.55,124.68 65.35,124.88 v2(65.35,125.1)
  L3 w0.089: 57.96,127.2 57.98,127.2 58.03,127.16 58.93,127.16 60.04,126.05 64.67,126.05 64.98,125.74 64.98,125.16 65.11,125.02 65.27,125.02 v2(65.35,125.1)
  L3 w0.152: DIMM2.175 45.61,179.91 45.74,180.04 45.74,180.48 45.59,180.63 45.1,180.63 44.85,180.38 44.85,179.2 44,178.35 44,177.42 44.85,176.57 44.85,174.75 45.7,173.9 45.7,172.19 46.55,171.34 46.55,170.28 47.4,169.43 47.4,168.31 46.55,167.47 46.55,164.75 47.59,163.72 47.59,163.27 47.05,162.73 47.05,162.51 47.29,162.27 47.51,162.27 48.05,162.81 48.5,162.81 54.18,157.13 54.18,140.2 54.33,140.05 54.93,140.05 55.24,139.73 55.24,139.16 54.93,138.84 54.33,138.84 54.18,138.69 54.18,138.35 54.33,138.19 54.93,138.19 55.24,137.88 55.24,137.3 54.93,136.99 54.33,136.99 54.18,136.84 54.18,136.49 54.33,136.34 54.93,136.34 55.24,136.02 55.24,134.76 54.93,134.45 52.83,134.45 52.63,134.25 52.63,133.91 52.81,133.73 56.02,133.73 56.39,133.36 56.39,127.45 56.63,127.2 57.96,127.2
M_B_DQS_DP3: length 68.2
  TOP w0.178: v2(70.76,123.31) 70.76,123.35 CPU1.AN28
  L3 w0.089: 63.84,131.39 63.88,131.35 ; 63.92,131.3 63.92,131.23 64.29,130.87 64.7,130.87 65.33,130.24 65.58,129.99 65.58,129.78 68.74,126.63 68.74,125.56 70.39,123.91 70.39,123.69 v2(70.76,123.31)
  L3 w0.152: 63.84,131.39 63.63,131.6 63.63,158.64 56.75,165.52 56.75,167.59 55.9,168.43 55.9,169.78 55.05,170.63 55.05,171.27 55.9,172.12 55.9,173.36 54.25,175.01 53.67,175.01 53.37,175.31 53.37,176.46 54.2,177.3 54.2,178.28 55.05,179.13 55.05,180.41 54.73,180.73 54.73,181.17 DIMM2.186 ; 63.88,131.35 63.92,131.3
M_B_DQS_DP4: length 74.9
  TOP w0.178: v2(85.43,123.31) CPU1.AN12
  L3 w0.089: 92.26,132.53 92.2,132.53 91.68,132.01 91.23,132.01 88.13,128.91 88.13,128.05 86.96,126.88 86.96,124.75 85.91,123.7 85.91,123.44 85.78,123.31 v2(85.43,123.31)
  L3 w0.152: DIMM2.245 110.16,180.53 110.03,180.66 109.59,180.66 109.48,180.54 109.45,180.32 109.45,179.5 109.45,179.5 109.45,179.23 108.6,178.39 108.6,177.42 109.45,176.56 109.45,175.03 110.28,174.2 110.28,172.1 109.48,171.3 109.48,170.18 110.33,169.33 110.33,168.34 109.45,167.46 109.45,166.12 108.94,165.61 108.41,165.61 107.44,164.64 106.25,164.64 106.07,164.46 106.07,164.14 106.22,163.99 107.44,163.99 107.75,163.67 107.75,161.81 94.36,148.42 94.36,134.64 92.26,132.53
M_B_DQS_DP5: length 78.3
  TOP w0.178: v2(91.29,124.22) CPU1.AP8
  L3 w0.089: 98.34,129.07 98.32,129.05 98.26,129.05 95.06,125.86 92.08,125.86 91.72,125.5 91.72,124.97 91.29,124.54 v2(91.29,124.22)
  L3 w0.152: 98.34,129.07 103.88,134.62 103.88,146.33 104.03,146.48 105.37,146.48 105.69,146.8 105.69,147.37 105.37,147.69 104.03,147.69 103.88,147.84 103.88,148.49 118.72,163.33 118.72,164.14 118.41,164.46 117.77,164.46 117.61,164.61 117.61,164.95 117.77,165.11 118.01,165.11 119.63,166.73 119.63,167.64 118.83,168.44 118.83,169.37 119.63,170.17 119.63,171.44 118.83,172.24 118.83,174.67 117.96,175.54 117.96,176.41 118.8,177.25 118.8,178.37 119.65,179.23 119.65,180.43 119.37,180.72 119.29,180.76 119.22,180.97 DIMM2.256
M_B_DQS_DP6: length 88
  TOP w0.178: CPU1.AL8 90.61,121.02 90.37,120.78 v2(90.37,120.57)
  L3 w0.089: v2(90.37,120.57) 90.64,120.94 91.05,120.94 92,121.89 98.39,121.89 99.16,122.66 99.89,122.66 99.92,122.62 99.94,122.62
  L3 w0.152: 99.94,122.62 101.45,122.62 124.64,145.81 124.64,160.02 126.31,161.7 126.31,162.29 126.79,162.77 127.8,162.77 128.12,163.09 128.12,163.84 127.8,164.16 126.64,164.16 126.49,164.31 126.49,164.66 126.64,164.81 127.79,164.81 128.15,165.18 128.15,167.47 129,168.32 129,169.14 128.15,169.99 128.15,171.27 129,172.12 129,173.49 128.15,174.35 128.15,176.59 127.3,177.43 127.3,178.44 128.15,179.28 128.15,180.02 128.15,180.32 128.32,180.49 128.37,180.51 128.57,180.45 DIMM2.267
M_B_DQS_DP7: length 100.1
  TOP w0.178: v2(92.2,116.91) CPU1.AG7
  L3 w0.089: v2(92.2,116.91) 92.96,116.36 96.66,116.36 97.23,116.93 98.08,116.93 98.25,116.76 98.53,116.49 100.03,116.49 100.04,116.48 100.06,116.48 100.12,116.42 100.13,116.42
  L3 w0.152: 100.13,116.42 104.28,116.42 133.58,145.72 133.58,148.73 133.73,148.88 134.58,148.88 134.9,149.2 134.9,149.77 134.58,150.09 133.73,150.09 133.58,150.24 133.58,150.89 133.76,151.07 135.32,151.07 135.64,151.38 135.64,160.95 138.35,163.66 138.35,164.47 138.03,164.78 137.03,164.78 136.88,164.93 136.88,165.28 137.03,165.43 138.03,165.43 138.35,165.74 138.35,167.54 137.5,168.38 137.5,169.17 138.35,170.02 138.35,171.38 137.5,172.23 137.5,174.55 136.65,175.4 136.65,176.45 137.5,177.3 137.5,178.12 138.35,178.97 138.35,180.58 DIMM2.278
M_B_ODT0: length 65.3
  TOP w0.165: CPU1.AM16 v2(81.77,122.4)
  L3 w0.089: v2(81.77,122.4) 81.77,122.59 82.2,123.02 82.2,127.38
  L3 w0.152: 82.2,127.38 82.79,127.97 82.79,129.96 83.31,130.48 83.31,132.24 87.03,135.96 87.03,148.6 95.03,156.61 95.03,158.33 99.25,162.55 99.25,163.74 99.1,163.89 98.68,163.89 98.53,164.04 98.53,164.35 98.68,164.5 99.1,164.5 99.25,164.65 99.25,164.96 99.1,165.11 98.68,165.11 98.53,165.26 98.53,165.53 98.71,165.72 99.1,165.72 99.25,165.87 99.25,167.45 100.1,168.3 100.1,169.21 100.64,169.76 100.64,171.25 99.82,172.07 99.82,173.36 98.26,174.92 DIMM2.87
M_B_ODT1: length 65.8
  TOP w0.165: CPU1.AL16 v2(81.77,121.48)
  L3 w0.089: v2(81.77,121.48) 82.23,121.94 82.23,122.54 82.55,122.86 82.84,122.86 83.81,123.83 83.81,127.09 85.53,128.81 85.53,129.18
  L3 w0.152: 85.53,129.18 85.53,132.01 88.64,135.12 88.64,146.72 90.61,148.69 90.61,149.87 96.96,156.23 96.96,158.03 100.83,161.89 100.83,164.58 102.65,166.4 102.65,167.45 103.53,168.32 103.53,169.59 104.22,170.28 104.22,171.35 103.35,172.21 103.35,174.42 DIMM2.91
M_B_PARITY: length 68.1
  TOP w0.216: CPU1.AL20 v2(78.11,121.48)
  L3 w0.089: 77.69,124.13 77.69,122.16 77.9,121.81 v2(78.11,121.48)
  L3 w0.191: 77.69,124.13 78.61,125.05 78.61,127.64 78.03,128.22 78.03,131.78 78.69,132.44 78.69,134.31 82.45,138.06 82.45,150.67 88.18,156.4 88.18,168.31 87.83,168.66 87.83,171.55 88.14,171.86 88.14,177.37 87.71,177.8 87.71,179.96 89.26,181.51 DIMM2.222
M_VREF_DQ_DIM0: length 1.7
  TOP w0.102: CPU1.AC40 58.86,114.62 v2(58.57,114.34)
  BOTTOM w0.102: TP601.1 58.14,113.91 v2(58.57,114.34)
M_VREF_DQ_DIM1: length 111.9
  TOP w0.305: v2(30.99,126.87) 31.43,126.87 33.68,124.62 33.68,121.97 33.12,121.41 32.7,121.41 C603.1 32.7,120.65 33.66,120.65 v2(33.81,120.81) ; CPU1.AC39 60.28,114.54 59.88,114.14 59.14,114.14 57.52,112.52 v2(57.52,111.88) ; C1209.1 R1204.1 v2(21.72,188.09)
  BOTTOM w0.305: v2(21.72,188.09) 21.72,186.69 v1(21.45,186.42) 18.29,183.26 18.29,166.75 19.42,165.62 19.42,138.44 v2(30.99,126.87) ; v2(57.52,111.88) 56.64,111 43.62,111 v2(33.81,120.81)
MB_REG_PG: length 33
  TOP w0.102: Q2406.3 205.27,77.89 205.13,77.75 205.13,76.69 205.03,76.59 Q2406.6 204.18,76.17 203.81,75.79 202.18,75.79 201.22,74.83 201.22,73.57 201,73.36 199.8,73.36 199.57,73.13 199.57,72.76 199.47,72.65 198.65,72.65 197.92,71.93 197.31,71.93 196.94,72.3 Q2405.6 196.28,73.01 195.4,73.9 195.4,74.27 195.78,74.66 v2(195.78,74.83) ; Q2402.6 194.15,76.87 v2(194.84,76.17) ; U2401.109 201.6,84.48 200.15,83.03 200.15,82.04 199.85,81.74 199.85,79.9 R2469.1 198.75,78.8 v2(198.75,78.31)
  BOTTOM w0.102: v2(198.75,78.31) 196.98,78.31 v1(196.26,77.59) v2(194.84,76.17) 195.78,75.24 v2(195.78,74.83)
MB_REG_PG_1: length 4.5
  TOP w0.102: R2409.1 R2404.2 ; R2404.2 197.32,77.52 Q2402.2 ; R2404.2 198.02,77.76 v2(198.3,77.48)
  BOTTOM w0.102: v2(198.3,77.48) 197.85,77.04 v1(197.61,77.04)
MB_REG_PG_2: length 4
  TOP w0.102: Q2406.5 203.12,77.24 v2(203.08,77.29) R2424.1 202.49,76.72 202.49,77.84 R2415.2
  BOTTOM w0.102: v2(203.08,77.29) 202.97,77.18 v1(202.97,76.4)
MB_REG_PG_3: length 4.2
  TOP w0.102: Q2406.2 206.79,77.24 R2423.1 R2414.2 207.68,75.16 v1(206.76,75.16)
MCLK: length 4.1
  TOP w0.102: RN2401.2 202.76,82.19 203.33,82.75 v1(203.33,83.46) 204,84.13 U2401.115
MDAT: length 4.1
  TOP w0.102: U2401.116 204.4,83.08 v1(204.56,82.92) 204.56,82.9 203.42,81.77 RN2401.1
ME_CNTL: length 5.5
  TOP w0.089: 216.1,147.07 214.94,148.23 213.38,148.23 213.36,148.22 212.74,148.22 212.56,148.39 SB1.BF32
  TOP w0.102: 216.1,147.07 v1(216.36,147.07) 217.16,147.07 R2037.1
ME_CNTL_1: length 34
  TOP w0.102: v2(222.89,129.51) 221.09,127.72 Q2001.B ; R2037.2 218.34,147.19 219.51,146.02 220.92,146.02 221.25,145.69 223.96,145.69 226.53,148.27 v2(226.94,148.27)
  BOTTOM w0.102: v2(226.94,148.27) 226.94,148.27 227.23,147.98 227.23,144.63 224.51,141.91 224.51,137.52 222.9,135.9 222.9,134.27 223.14,134.03 223.14,131.06 v1(223.29,130.91) 223.29,129.92 v2(222.89,129.51)
ME_CNTL_2: length 3.8
  TOP w0.102: Q2001.E 221.48,129.63 v1(223.14,131.29) 224.19,131.29 R2034.2
MEM_REG_PG: length 13.2
  TOP w0.102: Q2405.3 198.85,74.31 200.2,75.67 200.61,75.67 200.91,75.97 200.91,80.98 200.38,81.51 R2470.1 200.73,81.87 v1(200.73,82.49) 200.73,82.92 202.4,84.59 U2401.111
MEM_REG_PG_1: length 7.1
  TOP w0.102: Q2405.5 197.7,73.66 197.89,73.86 197.89,74.73 198.25,75.08 v2(198.5,75.08) 199.22,75.08 R2417.1 R2413.2
  BOTTOM w0.102: v2(198.5,75.08) 198.42,75.01 v1(197.56,75.01)
MEM_REG_PG_2: length 2.8
  TOP w0.102: Q2405.2 199.72,73.66 v2(199.92,73.86) 200.65,73.86 R2412.2
  BOTTOM w0.102: v2(199.92,73.86) 199.97,73.81 v1(200.71,73.81)
MIC1_JD: length 313.2
  TOP w0.102: R2709.2 v2(53.72,229.74) ; v2(52.7,234.7) 52.96,234.95 52.96,236.61 54.47,238.13 57.6,238.13 59.05,239.58 59.5,239.58 v2(59.56,239.64)
  BOTTOM w0.102: AUD1.3 12.7,7.23 12.7,14.36 12.7,14.36 12.7,17.38 12.7,17.39 12.7,29.41 12.7,35.39 1.93,46.16 1.93,227.7 6.18,231.95 13.98,231.95 31.23,249.2 32.88,250.86 48.53,250.86 v1(53.63,245.76) 56.89,242.5 56.89,242.3 59.56,239.64 v2(59.56,239.64) ; v2(52.7,234.7) 52.7,230.76 v2(53.72,229.74)
MIC1_JD/FRONT_JD: length 7.7
  TOP w0.102: R2706.2 51.75,231.46 v1(52.5,231.46) R2709.1 R2710.1 55.79,231.46 56.86,230.39 U2701.44
MIC1_LL: length 4.1
  TOP w0.203: v1(18.01,31.47) 17.84,31.64 R3011.2 R3016.1 L3005.1 R3013.2
MIC1_LL_C: length 3.4
  TOP w0.203: C3007.2 15.93,34.59 14.99,33.66 v1(14.99,33.53) 15.51,33.01 15.51,33.01 15.99,32.52 R3013.1
MIC1_RR: length 4.3
  TOP w0.203: R3015.1 L3006.1 R3014.2 ; R3015.1 13.8,30.65 v1(13.03,29.87) ; R3015.1 R3012.2
MIC1_RR_C: length 3.2
  TOP w0.203: R3014.1 14.85,32.52 13.84,33.53 v1(13.72,33.53) 14.35,34.16 C3008.2
MIC1_VREFO_LL: length 279.4
  TOP w0.203: R3011.1 17.02,32.62 v2(16.25,33.39) ; v2(63.85,228.35) 63.86,228.34 U2701.9
  BOTTOM w0.203: v2(16.25,33.39) 16.25,33.46 14.93,34.78 14.93,36.29 14.94,36.29 14.94,39.42 5.54,48.82 5.54,145.15 16.86,156.47 16.86,163.44 5.69,174.61 5.69,209.59 16.99,220.89 16.99,229.86 34.3,247.17 45.03,247.17 v1(46.28,245.92) v2(63.85,228.35)
MIC1_VREFO_RR: length 281.2
  TOP w0.203: R3012.1 13.75,32.52 13.06,33.22 13.06,37.26 13.67,37.87 v2(13.72,37.87) ; v2(63.88,229.24) 64.01,229.24 64.36,228.88 U2701.10
  BOTTOM w0.203: v2(63.88,229.24) 63.77,229.24 49.9,243.11 v1(49.9,243.2) 45.47,247.62 34.11,247.62 16.54,230.05 16.54,221.08 5.16,209.7 5.16,174.32 16.41,163.07 16.41,156.66 5.08,145.34 5.08,48.51 14.1,39.5 14.1,38.25 v2(13.72,37.87)
MIC2_VREFO: length 31.6
  TOP w0.305: v2(64.92,228.35) 64.86,228.35 U2701.11
  TOP w0.508: v2(64.77,241.2) 64.72,241.2 64.69,241.17 D2901.1
  BOTTOM w0.508: v2(64.92,228.35) v1(66.8,228.35) 68.71,228.35 70.69,230.33 70.69,239.04 71.5,239.85 71.5,242.15 72.1,242.75 72.1,243.29 71.71,243.68 66.67,243.68 64.77,241.78 v2(64.77,241.2)
MUTE: length 303.3
  TOP w0.102: v2(77.22,236.98) 77.03,237.17 R2910.1 77.03,238.89 R2908.1 78.11,238.95 Q2701.C ; v2(53.98,236.35) 55.07,237.44 57.89,237.44 59.1,238.66 59.91,238.66 60.5,239.25 v2(60.73,239.25) ; 20.03,30.04 R3010.1 ; 20.03,30.04 20.03,30.09 19.43,30.68 19.3,30.68 v2(19.3,30.71) ; 20.03,30.04 R3008.1
  BOTTOM w0.102: v2(19.3,30.71) 19.28,30.73 19.28,31.01 15.34,34.94 15.34,36.12 15.34,39.65 5.94,49.05 5.94,144.88 17.27,156.21 17.27,163.82 6.1,175 6.1,209.42 17.16,220.49 17.4,220.73 17.4,229.69 34.47,246.76 43.56,246.76 v1(50.99,239.33) v2(53.98,236.35) ; v2(77.22,236.98) 77.22,239.58 74.1,242.7 73.48,242.7 71.94,244.24 66.44,244.24 61.45,239.25 v2(60.73,239.25)
MUTE_AUDOUT_LL: length 2.6
  TOP w0.102: Q3001.5 19.18,28.04 19,28.22 19,28.22 ; 19,28.22 19,29.1 R3010.2 ; 19,28.22 v1(18.98,28.22)
MUTE_AUDOUT_RR: length 5.8
  TOP w0.102: Q3001.2 19.18,25.53 19.43,25.78 19.94,25.78 21.08,26.92 v1(21.08,27.94) 20.07,28.96 R3008.2
MUTE_FP_OUT_LL: length 2.8
  TOP w0.102: Q2901.2 76.9,240.03 R2908.2 77.09,240.64 v1(77.22,240.77)
MUTE_FP_OUTR_RR: length 4.9
  TOP w0.102: v1(76.33,236.93) 76.14,237.12 R2910.2 75.88,238.12 75.29,238.12 74.42,238.99 74.42,239.65 74.04,240.03 Q2901.5
NGFF_WIFI_PWR_CRL: length 65.3
  TOP w0.102: D6302.K 203,212.01 202.9,212.12 200.58,212.12 200.48,212.01 200.48,209.72 R1712.2 200.52,209.16 200.28,208.91 v2(199.29,208.91) ; SB1.U48 198.31,157.49 197.89,157.91 197.89,159.34 192.99,164.24 192.99,165.72 193.42,166.15 v2(193.42,166.7)
  BOTTOM w0.102: v2(193.42,166.7) v1(193.42,167.94) 193.42,169.37 194.26,170.21 194.26,177.01 194.08,177.19 194.08,179.83 194.21,179.96 194.21,192.65 193.98,192.88 193.98,193.65 195.45,195.12 195.45,198.53 197.66,200.74 197.66,207.29 v2(199.29,208.91)
NGFF_WIFI_PWR_EN: length 16
  TOP w0.102: U6302.D 198.07,212.99 198.07,209.37 198.98,208.46 205.34,208.46 207.01,210.12 U6301.1 208.89,210.12 R6306.2
NPC3063_#8: length 4.1
  TOP w0.508: R5302.2 181.76,5.71 v1(181.81,5.77) 181.81,6.71 181.15,7.37 U5301.8
NPC3063_COMP: length 3.5
  TOP w0.254: U5301.5 v1(180.34,12.5) 180.15,12.69 R5304.1 R5303.1
NPC3063_SWC: length 12.9
  TOP w0.508: R5301.1 178.54,5.31 R5302.1 178.64,6.02 v1(178.64,7.01) 178.59,7.06 178.59,7.78 179.45,8.64 U5301.7 182.37,8.64 183.64,7.37 U5301.1
NPC3063_SWE: length 13.3
  TOP w0.254: L5301.1 192.58,10.57 D5301.K 189.9,7.9 v1(189.89,7.9) 187.43,7.9 186.69,8.64 U5301.2
NPC3063_TCAP: length 6.5
  TOP w0.254: C5301.1 182.11,12.71 v1(181.97,12.57) 181.97,11.2 183.26,9.91 U5301.3
PAD0: length 64
  TOP w0.102: v2(207.91,59.27) 200.52,59.27 200.23,58.98 200.23,58.73 200.33,58.63 201.35,58.63 201.45,58.53 201.45,58.32 201.35,58.22 200.33,58.22 200.23,58.12 200.23,57.92 200.33,57.81 201.29,57.81 201.4,57.71 201.4,57.51 201.29,57.41 200.33,57.41 200.23,57.31 200.23,57.1 200.33,57 201.22,57 201.32,56.9 201.32,56.7 201.22,56.6 200.33,56.6 200.23,56.49 200.23,56.29 200.33,56.19 201.17,56.19 201.27,56.09 201.27,55.88 201.17,55.78 200.33,55.78 200.23,55.68 200.23,55.48 200.33,55.38 201.14,55.38 201.24,55.27 201.24,55.07 201.14,54.97 200.33,54.97 200.23,54.87 200.23,53.52 197.8,51.09 U9501.30
  BOTTOM w0.102: v2(207.91,59.27) 209.3,60.65 209.3,70.22 211.71,72.63 211.71,74.3 213.82,76.4 213.82,77.22 216.12,79.52 216.12,84.79 217.32,85.99 217.32,87 218.67,88.35 SLOT4.111
PAD1: length 65.9
  TOP w0.102: U9501.31 198.24,50.69 201.65,54.1 201.65,54.86 201.75,54.97 202.49,54.97 202.59,55.07 202.59,55.27 202.49,55.37 201.75,55.37 201.65,55.47 201.65,55.68 201.75,55.78 202.49,55.78 202.59,55.88 202.59,56.08 202.49,56.19 201.75,56.19 201.65,56.29 201.65,56.49 201.75,56.59 202.49,56.59 202.59,56.69 202.59,56.9 202.49,57 201.75,57 201.65,57.1 201.65,57.3 201.75,57.4 202.49,57.4 202.59,57.51 202.59,57.71 202.49,57.81 201.75,57.81 201.65,57.91 201.65,58.17 202.02,58.53 v2(207.89,58.53)
  BOTTOM w0.102: v2(207.89,58.53) 209.55,60.2 209.55,70.12 211.96,72.53 211.96,74.17 214.07,76.28 214.07,77.11 216.38,79.42 216.38,84.68 217.58,85.88 217.58,86.89 218.72,88.04 219.58,88.04 220.27,87.35 222.33,87.35 223.32,88.35 SLOT4.112
PAD2: length 64.7
  TOP w0.102: U9501.33 198.45,50.29 203.6,55.44 203.6,55.58 202.85,56.33 202.85,56.47 202.99,56.61 203.14,56.61 203.88,55.87 204.03,55.87 204.17,56.01 204.17,56.16 203.07,57.26 203.07,57.4 203.21,57.55 203.36,57.55 204.46,56.44 204.6,56.44 204.75,56.59 204.75,56.73 203.67,57.81 203.67,57.95 203.81,58.09 203.96,58.09 205.03,57.02 205.18,57.02 205.39,57.23 205.39,57.38 205.01,57.75 205.01,57.9 205.16,58.04 205.3,58.04 205.68,57.66 205.82,57.66 206.18,58.03 208.06,58.03 v2(208.99,58.95)
  BOTTOM w0.102: v2(208.99,58.95) 209.8,59.77 209.8,70.01 212.22,72.42 212.22,74.04 214.33,76.15 214.33,77.01 216.63,79.31 216.63,80.46 216.73,80.56 217.27,80.56 217.37,80.67 217.37,80.87 217.27,80.97 216.73,80.97 216.63,81.07 216.63,81.28 216.73,81.38 217.27,81.38 217.37,81.48 217.37,81.68 217.27,81.78 216.73,81.78 216.63,81.89 216.63,82.09 216.73,82.19 217.27,82.19 217.37,82.29 217.37,82.49 217.27,82.6 216.73,82.6 216.63,82.7 216.63,82.9 216.73,83 217.27,83 217.37,83.1 217.37,83.31 217.27,83.41 216.73,83.41 216.63,83.51 216.63,83.71 216.73,83.82 217.27,83.82 217.37,83.92 217.37,84.12 217.27,84.22 216.73,84.22 216.63,84.32 216.63,84.58 217.83,85.78 217.83,86.61 218.29,87.08 SLOT4.109
PAD3: length 65.6
  TOP w0.102: v2(209.01,58.15) 208.63,57.77 206.49,57.77 198.85,50.13 U9501.34
  BOTTOM w0.102: v2(209.01,58.15) 210.13,59.27 210.13,67.77 214.96,72.59 214.96,76.77 218.03,79.85 218.03,85.04 218.8,85.8 220.29,85.8 221.19,84.9 222.37,84.9 223.6,86.13 225.09,86.13 225.96,87 228.27,87 228.37,87.1 228.37,87.86 228.47,87.96 228.68,87.96 228.78,87.86 228.78,87.1 228.88,87 229.08,87 229.18,87.1 229.18,87.86 229.29,87.96 229.49,87.96 229.59,87.86 229.59,86.61 229.49,86.51 227.49,86.51 SLOT4.108
PAD4: length 63.5
  TOP w0.102: U9501.37 200.05,49.86 199.93,49.98 199.46,49.98 199.34,50.1 199.34,50.26 199.46,50.39 199.93,50.39 200.05,50.51 200.05,50.85 206.72,57.52 208.99,57.52 209.51,58.04 209.51,59.91 v2(210.86,61.26)
  BOTTOM w0.102: v2(210.86,61.26) 210.39,61.73 210.39,62.33 210.49,62.43 211.02,62.43 211.12,62.53 211.12,62.73 211.02,62.84 210.49,62.84 210.39,62.94 210.39,63.14 210.49,63.24 211.02,63.24 211.12,63.34 211.12,63.55 211.02,63.65 210.49,63.65 210.39,63.75 210.39,63.95 210.49,64.05 211.02,64.05 211.12,64.16 211.12,64.36 211.02,64.46 210.49,64.46 210.39,64.56 210.39,66.16 210.49,66.26 211.15,66.26 211.25,66.37 211.25,66.57 211.15,66.67 210.49,66.67 210.39,66.77 210.39,67.64 210.57,67.82 210.71,67.82 211.6,66.93 211.74,66.93 211.88,67.08 211.88,67.22 211,68.11 211,68.25 211.14,68.39 211.29,68.39 211.78,67.9 211.92,67.9 212.07,68.05 212.07,68.19 211.57,68.68 211.57,68.83 211.99,69.24 212.14,69.24 213.15,68.23 213.29,68.23 213.51,68.45 213.51,68.59 212.55,69.55 212.55,69.8 212.7,69.95 212.89,69.95 213.41,69.43 213.55,69.43 213.66,69.54 213.66,69.76 213.16,70.26 213.16,70.41 215.13,72.38 215.21,72.47 215.21,76.67 220.12,81.57 220.12,83.39 219.91,83.59 219.38,83.59 218.95,83.16 218.53,83.16 218.35,83.34 218.35,83.72 SLOT4.105
PAD5: length 67.5
  TOP w0.102: U9501.38 200.45,50.77 206.95,57.26 209.1,57.26 209.76,57.93 209.76,59.41 v2(210.87,60.52)
  BOTTOM w0.102: v2(210.87,60.52) 211.51,61.15 211.51,66.04 213.92,68.45 213.92,70.69 215.46,72.23 215.46,76.56 220.37,81.47 220.37,84.38 220.64,84.65 222.88,84.65 223.06,84.84 223.06,85.24 223.7,85.88 225.17,85.88 225.27,85.78 225.27,84.99 225.4,84.86 228.49,84.86 228.59,84.96 228.59,85.45 228.49,85.55 227.91,85.55 227.81,85.65 227.81,85.95 227.91,86.06 228.49,86.06 228.69,86.26 229,86.26 229.1,86.16 229.1,84.96 230.12,83.94 230.12,83.73 229.91,83.52 229.67,83.52 228.98,84.2 224.57,84.2 SLOT4.106
PAD6: length 64
  TOP w0.102: v2(210.87,59.78) 210.02,58.93 210.02,57.82 209.2,57.01 207.07,57.01 200.85,50.78 U9501.39
  BOTTOM w0.102: SLOT4.103 221.7,82.07 221.8,81.97 222.71,81.97 223.75,83.01 223.75,83.62 222.97,84.39 220.81,84.39 220.62,84.2 220.62,81.36 219.82,80.56 219.82,80.42 220.15,80.09 220.15,79.95 220,79.8 219.86,79.8 219.53,80.13 219.39,80.13 219.25,79.98 219.25,79.84 219.57,79.52 219.57,79.37 219.43,79.23 219.28,79.23 218.96,79.55 218.81,79.55 218.67,79.41 218.67,79.27 219,78.94 219,78.8 218.85,78.65 218.71,78.65 218.38,78.98 218.24,78.98 218.1,78.83 218.1,78.69 218.42,78.37 218.42,78.22 218.28,78.08 218.13,78.08 217.81,78.4 217.66,78.4 217.52,78.26 217.52,78.12 217.85,77.79 217.85,77.65 217.7,77.5 217.56,77.5 217.23,77.83 217.09,77.83 216.95,77.68 216.95,77.54 217.27,77.22 217.27,77.07 217.13,76.93 216.98,76.93 216.66,77.25 216.51,77.25 216.37,77.11 216.37,76.97 216.7,76.64 216.7,76.5 216.55,76.35 216.41,76.35 216.08,76.68 215.94,76.68 215.72,76.46 215.72,72.08 214.95,71.31 214.95,71.17 215.19,70.93 215.19,70.79 215.04,70.64 214.9,70.64 214.66,70.88 214.52,70.88 214.17,70.54 214.17,70.28 214.27,70.18 215.21,70.18 215.32,70.08 215.32,69.88 215.21,69.77 214.27,69.77 214.17,69.67 214.17,69.47 214.27,69.37 214.58,69.37 214.68,69.27 214.68,69.06 214.58,68.96 214.27,68.96 214.17,68.86 214.17,68.35 214.15,68.32 211.76,65.93 211.76,60.67 v2(210.87,59.78)
PAD7: length 63.8
  TOP w0.102: U9501.40 201.25,50.78 207.23,56.76 209.31,56.76 210.27,57.72 210.27,58.43 v2(210.89,59.05)
  BOTTOM w0.102: SLOT4.102 224.49,82.25 227.92,82.25 228.14,82.46 228.14,83.72 228.24,83.82 228.45,83.82 228.55,83.72 228.55,83.46 228.65,83.36 229.31,83.36 229.41,83.26 229.41,83.07 229.3,82.96 228.65,82.96 228.55,82.85 228.55,82.46 228.65,82.36 229.01,82.36 229.11,82.26 229.11,81.69 229.05,81.63 228.4,81.63 228.29,81.53 228.29,80.16 228.17,80.04 227.99,80.04 227.89,80.14 227.89,81.53 227.7,81.71 225.83,81.71 224.92,80.8 223.8,80.8 222.88,81.71 221.34,81.71 220.62,81 220.62,80.06 215.97,75.41 215.97,71.78 215.69,71.5 215.69,69.5 214.41,68.23 214.1,67.92 212.01,65.83 212.01,60.17 v2(210.89,59.05)
PAD8: length 66.9
  TOP w0.102: U9501.43 202.45,51.57 207.14,56.26 v2(208.99,56.26)
  BOTTOM w0.102: SLOT4.100 226.78,79.57 226.88,79.47 228.78,79.47 228.88,79.37 228.88,79.17 228.78,79.06 225.09,79.06 224.99,78.96 224.99,78.76 225.09,78.66 228.78,78.66 228.88,78.56 228.88,78.35 228.78,78.25 225.25,78.25 225.15,78.15 225.15,77.95 225.25,77.85 228.78,77.85 228.88,77.74 228.88,77.54 228.78,77.44 226.22,77.44 224.75,75.97 223.67,75.97 222.91,76.73 221.41,76.73 220.57,75.9 218.5,75.9 216.73,74.13 216.73,71.29 216.45,71.01 216.45,69.19 216.31,69.05 215.79,68.52 214.64,67.38 212.78,65.51 212.78,59.56 211.23,58.02 210.62,58.02 208.99,56.39 v2(208.99,56.26)
PAD9: length 64.5
  TOP w0.102: U9501.44 202.85,51.59 206.83,55.57 208.19,55.57 v2(208.4,55.79)
  BOTTOM w0.102: v2(208.4,55.79) 208.4,54.97 208.64,54.74 208.64,52.78 209.32,52.1 209.32,51.84 209.22,51.74 208.91,51.74 208.81,51.64 208.81,51.44 208.91,51.33 209.22,51.33 209.32,51.23 209.32,49.17 209.02,48.87 208.43,48.87 208.33,48.97 208.33,49.76 208.23,49.86 208.03,49.86 207.92,49.76 207.92,48.97 207.82,48.87 207.57,48.87 207.47,48.97 207.47,50.12 207.57,50.23 208.2,50.23 208.31,50.33 208.31,50.53 208.2,50.63 207.57,50.63 207.47,50.73 207.47,50.94 207.57,51.04 208.28,51.04 208.38,51.14 208.38,51.34 208.28,51.45 207.57,51.45 207.47,51.55 207.47,51.94 207.57,52.04 208.36,52.04 208.46,52.15 208.46,52.35 208.36,52.45 207.57,52.45 207.47,52.55 207.47,52.76 207.57,52.86 208.15,52.86 208.25,52.96 208.25,53.16 208.15,53.26 207.57,53.26 207.47,53.37 207.47,53.57 207.57,53.67 207.98,53.67 208.08,53.77 208.08,54.46 207.75,54.79 207.75,56.51 207.85,56.61 208.74,56.61 208.84,56.71 208.84,56.92 208.74,57.02 207.85,57.02 207.75,57.12 207.75,57.33 207.85,57.43 209.5,57.43 210.34,58.27 211.12,58.27 212.52,59.67 212.52,65.62 214.46,67.56 214.94,68.03 215.61,68.7 216.2,69.29 216.2,71.16 216.48,71.44 216.48,74.24 SLOT4.97
PAD10: length 70.5
  TOP w0.102: U9501.45 203.25,51.63 206.28,54.66 208.58,54.66 209.04,55.12 v2(209.04,55.42)
  BOTTOM w0.102: SLOT4.96 229.34,75.65 229.64,75.95 229.64,77.72 229.74,77.83 231.14,77.83 231.24,77.93 231.24,78.13 231.14,78.23 229.74,78.23 229.64,78.33 229.64,78.54 229.74,78.64 231.14,78.64 231.24,78.74 231.24,78.94 231.14,79.04 229.74,79.04 229.64,79.15 229.64,79.35 229.74,79.45 231.14,79.45 231.24,79.55 231.24,79.76 231.14,79.86 229.74,79.86 229.64,79.96 229.64,80.16 229.74,80.26 231.14,80.26 231.24,80.37 231.24,80.57 231.14,80.67 229.39,80.67 229.24,80.52 229.24,77.24 229.13,77.14 226.52,77.14 225.02,75.65 223.4,75.65 222.5,74.74 221.22,74.74 220.37,75.59 218.59,75.59 216.99,73.99 216.99,71.19 216.7,70.9 216.7,69.08 216.57,68.95 214.82,67.2 213.03,65.41 213.03,59.46 211.33,57.76 210.72,57.76 209.45,56.49 209.45,55.52 209.35,55.42 v2(209.04,55.42)
PAD11: length 63.8
  TOP w0.102: U9501.50 205.25,50.61 209.64,55 v2(209.89,55)
  BOTTOM w0.102: SLOT4.93 219.16,73.45 219.33,73.28 219.78,73.28 220.69,74.19 220.69,74.91 220.27,75.34 218.7,75.34 217.98,74.62 217.98,74.47 218.11,74.34 218.11,74.2 217.97,74.05 217.82,74.05 217.69,74.19 217.55,74.19 217.26,73.9 217.26,73.75 217.36,73.65 218.19,73.65 218.29,73.55 218.29,73.35 218.19,73.25 217.34,73.25 217.24,73.15 217.24,72.83 217.34,72.73 217.64,72.73 217.74,72.63 217.74,72.43 217.64,72.32 217.34,72.32 217.24,72.22 217.24,72.02 217.34,71.92 217.6,71.92 217.7,71.82 217.7,71.61 217.6,71.51 217.34,71.51 217.24,71.41 217.24,70.66 216.96,70.38 216.96,68.98 215.53,67.55 214.57,66.59 213.28,65.3 213.28,59.35 211.44,57.51 210.83,57.51 209.7,56.38 209.7,55.93 210.08,55.55 211.43,55.55 211.58,55.7 211.58,56.57 212.06,57.05 212.32,57.05 212.42,56.95 212.42,55.17 212.32,55.07 210.97,55.07 210.32,54.41 209.66,54.41 209.35,54.1 209.35,53.09 210.39,52.05 210.39,49.17 210.26,49.05 209.91,49.05 209.8,49.15 209.8,52.04 208.89,52.96 208.89,54.61 209.28,55 v2(209.89,55)
PAD12: length 64.1
  TOP w0.102: v2(211.07,56.74) 210.59,56.26 210.59,54.58 210.46,54.46 209.52,54.46 205.65,50.58 U9501.51
  BOTTOM w0.102: v2(211.07,56.74) 211.39,56.74 213.79,59.14 213.79,65.09 215.36,66.66 217.33,68.63 217.47,68.77 217.47,70.13 218.22,70.89 218.22,72.2 218.8,72.77 219.99,72.77 221.39,74.17 222.94,74.17 223.82,73.28 225.25,73.28 225.3,73.23 225.33,73.23 225.96,72.59 225.96,72.56 226.32,72.2 227.63,72.2 228.02,72.59 230.86,72.59 231.01,72.75 231.01,76.81 230.84,76.99 230.35,76.99 230.25,76.89 230.25,74.52 229.9,74.17 229.9,73.15 229.8,73.05 229.6,73.05 229.5,73.15 229.5,74.17 229.39,74.27 229.19,74.27 229.09,74.17 229.09,73.15 228.99,73.05 228.78,73.05 228.68,73.15 228.68,74.17 228.58,74.27 228.38,74.27 228.28,74.17 228.28,73.15 228.17,73.05 227.97,73.05 227.87,73.15 227.87,74.17 227.77,74.27 224.35,74.27 SLOT4.94
PAD13: length 63.6
  TOP w0.102: v2(209.88,53.94) 209.87,53.93 209.38,53.93 206.05,50.6 U9501.52
  BOTTOM w0.102: v2(209.88,53.94) 209.88,53.93 210.27,53.93 211.13,54.79 211.38,54.79 211.48,54.69 211.48,54.41 211.58,54.31 211.79,54.31 211.89,54.41 211.89,54.69 211.99,54.79 212.57,54.79 212.67,54.89 212.67,57.67 214.05,59.04 214.05,60.06 214.15,60.16 214.88,60.16 214.99,60.26 214.99,60.46 214.88,60.57 214.15,60.57 214.05,60.67 214.05,60.87 214.15,60.97 214.96,60.97 215.06,61.07 215.06,61.28 214.96,61.38 214.15,61.38 214.05,61.48 214.05,61.68 214.15,61.78 215.26,61.78 215.37,61.89 215.37,62.09 215.26,62.19 214.15,62.19 214.05,62.29 214.05,62.5 214.15,62.6 215.3,62.6 215.42,62.71 215.42,62.89 215.3,63 214.15,63 214.05,63.11 214.05,63.31 214.15,63.41 215.37,63.41 215.42,63.46 215.42,63.77 215.37,63.82 214.15,63.82 214.05,63.92 214.05,64.12 214.15,64.22 215.32,64.22 215.42,64.32 215.42,64.53 215.32,64.63 214.15,64.63 214.05,64.73 214.05,64.95 214.51,65.42 214.66,65.42 215.09,64.99 215.23,64.99 215.37,65.13 215.37,65.28 214.94,65.7 214.94,65.85 215.09,65.99 215.23,65.99 215.79,65.43 215.94,65.43 216.08,65.57 216.08,65.72 215.52,66.28 215.52,66.46 215.72,66.66 215.86,66.66 216.44,66.08 216.58,66.08 216.72,66.23 216.72,66.37 216.15,66.95 216.15,67.09 216.29,67.23 216.44,67.23 217.01,66.66 217.15,66.66 217.3,66.8 217.3,66.95 216.72,67.52 216.72,67.66 216.87,67.81 217.01,67.81 217.29,67.53 217.44,67.53 217.58,67.67 217.58,67.81 217.3,68.1 217.3,68.24 217.72,68.66 217.72,70.03 218.53,70.84 219.96,70.84 220.09,70.97 220.09,72.48 220.19,72.59 220.45,72.59 220.55,72.48 220.55,71.86 220.65,71.75 220.93,71.75 221.03,71.86 221.03,72.1 221.13,72.2 221.45,72.2 221.56,72.09 221.56,71.87 221.67,71.75 221.95,71.75 222.05,71.86 222.05,72.09 222.14,72.19 222.46,72.19 222.53,72.11 222.53,71.86 222.63,71.75 222.94,71.75 223.37,72.19 223.37,72.52 223.27,72.62 222.86,72.62 222.74,72.74 222.74,72.95 222.84,73.05 223.37,73.05 223.44,73.13 223.44,73.3 223.22,73.53 222.88,73.86 222.46,73.86 SLOT4.91
PAD14: length 64.1
  TOP w0.102: v2(209.89,53.2) 209.13,53.2 206.45,50.52 U9501.53
  BOTTOM w0.102: v2(209.89,53.2) 210.05,53.2 210.82,53.98 211.89,53.98 211.99,53.87 211.99,52.78 212.09,52.68 212.29,52.68 212.4,52.78 212.4,53.01 212.5,53.11 213.16,53.11 213.26,53.21 213.26,53.42 213.16,53.52 212.5,53.52 212.4,53.62 212.4,53.87 212.5,53.98 213.21,53.98 213.31,54.08 213.31,54.4 213.21,54.5 213.03,54.5 212.93,54.6 212.93,54.81 213.03,54.91 213.21,54.91 213.31,55.01 213.31,55.21 213.21,55.31 213.03,55.31 212.93,55.42 212.93,55.62 213.03,55.72 213.21,55.72 213.31,55.82 213.31,56.03 213.21,56.13 213.03,56.13 212.93,56.23 212.93,56.43 213.03,56.53 213.21,56.53 213.31,56.64 213.31,56.84 213.21,56.94 213.03,56.94 212.93,57.04 212.93,57.24 213.03,57.35 213.21,57.35 213.31,57.45 213.31,57.94 213.87,58.5 214.01,58.5 214.3,58.21 214.45,58.21 214.59,58.35 214.59,58.5 214.3,58.79 214.3,58.93 214.44,59.08 214.59,59.08 214.88,58.79 215.02,58.79 215.16,58.93 215.16,59.07 214.87,59.36 214.87,59.51 215.42,60.05 215.42,61.12 215.67,61.37 215.67,64.8 217,66.13 217.44,66.13 217.7,66.4 217.7,67.39 217.97,67.67 217.97,69.85 218.71,70.58 220.14,70.58 220.42,70.86 220.42,71.37 220.55,71.5 222.12,71.5 222.76,70.86 224.23,70.86 224.33,70.76 224.33,70.56 224.23,70.46 223.01,70.46 222.91,70.35 222.91,70.15 223.01,70.05 223.27,70.05 223.37,69.95 223.37,69.74 223.27,69.64 223.01,69.64 222.91,69.54 222.91,68.63 223.24,68.3 224.97,68.3 225.76,69.09 225.76,70 225.65,70.1 224.84,70.1 224.74,70.2 224.74,70.41 224.84,70.51 225.65,70.51 225.76,70.61 225.76,70.81 225.65,70.91 225.46,70.91 225.24,71.13 225.24,71.37 225.38,71.5 227.54,71.5 227.61,71.57 227.61,71.75 227.47,71.9 225.35,71.9 225.24,72 225.24,72.14 225.35,72.24 225.61,72.24 225.71,72.34 225.71,72.49 225.22,72.97 224.39,72.97 224.24,72.82 SLOT4.90
PAD15: length 64
  TOP w0.102: U9501.54 206.84,48.75 206.84,50.55 207.83,51.54 208.05,51.54 208.23,51.36 208.23,51.1 208.33,51.01 208.56,51.01 208.64,51.08 208.64,52.32 208.74,52.43 208.94,52.43 209.04,52.32 209.04,51.1 209.14,51 209.37,51 209.47,51.1 209.47,52.65 209.58,52.76 209.86,52.76 209.93,52.68 209.93,51.28 210.03,51.18 210.31,51.18 210.41,51.28 v2(210.41,52.68)
  BOTTOM w0.102: SLOT4.87 222.55,70.57 222.66,70.46 222.66,67.71 222.06,67.11 220.09,67.11 219.99,67.21 219.99,67.46 220.09,67.56 220.68,67.56 220.78,67.67 220.78,67.87 220.68,67.97 219.27,67.97 219.17,68.07 219.17,68.22 219.33,68.38 220.75,68.38 220.85,68.48 220.85,68.68 220.75,68.78 220.17,68.78 220.07,68.88 220.07,69.06 220.17,69.16 222.17,69.16 222.28,69.27 222.28,69.52 222.2,69.6 220.5,69.6 220.42,69.67 220.42,70.28 220.38,70.32 218.81,70.32 218.23,69.74 218.23,67.56 217.95,67.28 217.95,66.29 217.54,65.88 217.32,65.88 217.32,65.88 217.11,65.88 215.93,64.7 215.93,61.26 215.67,61.01 215.67,59 213.58,56.91 213.58,52.83 213.47,52.73 212.85,52.73 212.75,52.63 212.75,52.43 212.85,52.32 213.47,52.32 213.58,52.22 213.58,51.09 213.46,50.98 213.11,50.98 213.06,51.03 213.06,51.83 212.95,51.93 212.64,51.93 212.52,51.82 212.52,51.08 212.42,50.98 212.22,50.98 212.12,51.08 212.12,51.74 212.01,51.84 211.88,51.84 211.6,52.13 211.6,53.61 211.49,53.72 210.95,53.72 210.41,53.19 v2(210.41,52.68)
PAD16: length 63.9
  TOP w0.102: SLOT4.63 222,55.63 224.62,55.63 225.88,56.9 227.71,56.9 227.84,57.02 227.84,58.34 228.04,58.55 228.18,58.55 228.29,58.45 228.29,57.02 228.39,56.92 228.59,56.92 228.69,57.02 228.69,58.98 228.79,59.08 229,59.08 229.1,58.98 229.1,57.02 229.2,56.92 229.4,56.92 229.51,57.02 229.51,57.91 229.61,58.01 229.81,58.01 229.91,57.91 229.91,57.02 230.01,56.92 230.22,56.92 230.32,57.02 230.32,57.91 230.42,58.01 230.62,58.01 230.72,57.91 230.72,57.02 230.83,56.92 231.03,56.92 231.13,57.02 231.13,57.34 231.23,57.44 231.72,57.44 231.83,57.54 231.83,57.74 231.72,57.84 231.23,57.84 231.13,57.95 231.13,58.15 231.23,58.25 231.72,58.25 231.83,58.35 231.83,58.56 231.72,58.66 231.23,58.66 231.13,58.76 231.13,58.96 231.23,59.06 231.72,59.06 231.83,59.16 231.83,59.37 231.72,59.47 231.23,59.47 231.13,59.57 231.13,59.87 231.23,59.97 232.16,59.97 232.21,59.92 232.21,52.32 231.98,52.1 231.1,52.1 231,52.2 231,52.76 231.1,52.86 231.78,52.86 231.88,52.96 231.88,53.16 231.78,53.26 231.1,53.26 231,53.37 231,53.62 230.89,53.72 230.69,53.72 230.59,53.62 230.59,52.2 230.49,52.1 227.91,52.1 227.81,52.2 227.81,53.64 227.66,53.8 226.29,53.8 225.22,52.72 223.74,52.72 222.64,51.63 220.48,51.63 219.69,52.42 216.07,52.42 R9203.1 214.59,52.77 213.47,53.89 U9501.74
PAD17: length 64.6
  TOP w0.102: U9501.75 213.47,54.29 214.24,53.52 216.31,53.52 v2(216.92,52.91)
  BOTTOM w0.102: SLOT4.64 225.51,55.33 225.32,55.14 225.32,53.85 225.43,53.75 227.33,53.75 227.74,53.34 227.74,52.19 228.47,51.45 228.47,49.58 228.63,49.43 231.01,49.43 231.19,49.25 231.19,46.29 231.09,46.18 230.05,46.18 229.95,46.08 229.95,45.88 230.05,45.78 231.09,45.78 231.19,45.68 231.19,45.47 231.09,45.37 230.05,45.37 229.95,45.27 229.95,45.07 230.05,44.96 231.09,44.96 231.19,44.86 231.19,44.66 231.09,44.56 230.05,44.56 229.95,44.46 229.95,44.25 230.05,44.15 231.09,44.15 231.19,44.05 231.19,43.13 231.01,42.95 229.61,42.95 229.51,43.05 229.51,44.39 229.41,44.49 229.2,44.49 229.1,44.39 229.1,43.1 229,43 228.8,43 228.7,43.1 228.7,46.3 228.6,46.41 228.39,46.41 228.29,46.3 228.29,46.17 228.19,46.07 227.74,46.07 227.63,45.97 227.63,45.77 227.74,45.66 228.19,45.66 228.29,45.56 228.29,43 228.19,42.9 227.99,42.9 227.88,43 227.88,44.39 227.78,44.49 227.58,44.49 227.48,44.39 227.48,43.71 227.38,43.61 225.86,43.61 225.6,43.87 225.6,46.66 224.64,47.62 223.42,47.62 222.02,49.02 220.75,49.02 220.5,49.28 220.5,52.07 219.79,52.78 217.04,52.78 v2(216.92,52.91)
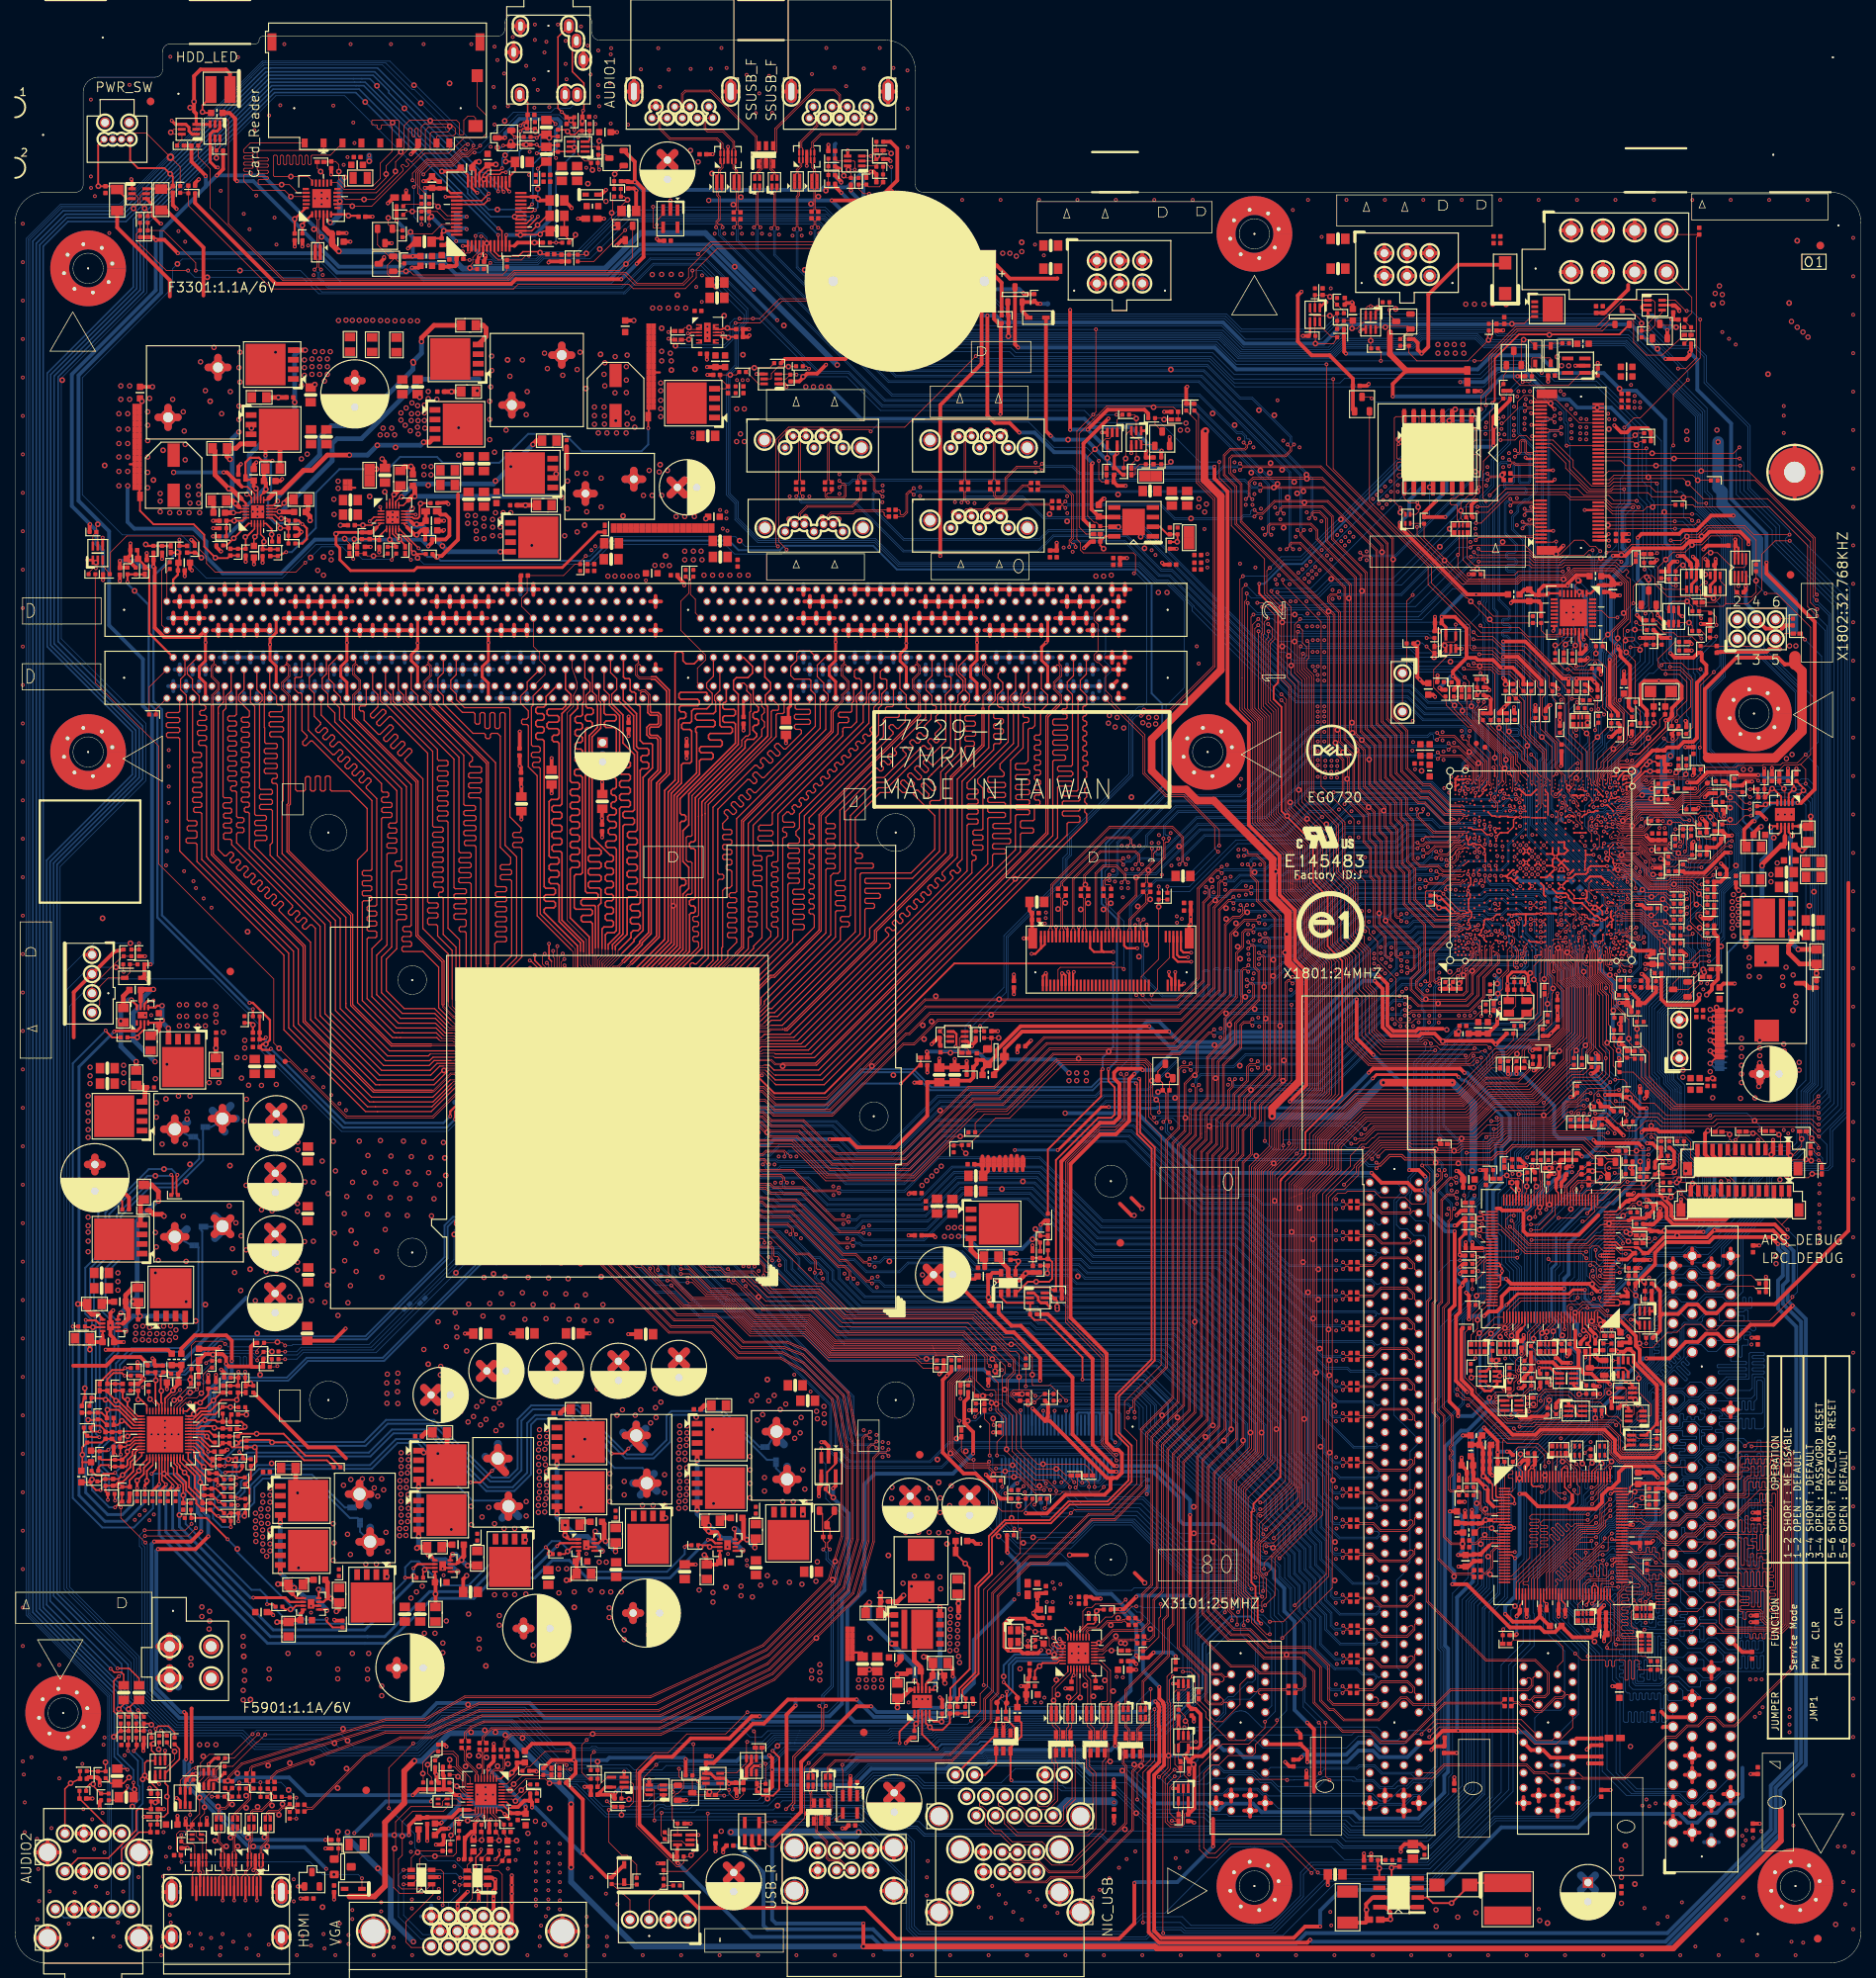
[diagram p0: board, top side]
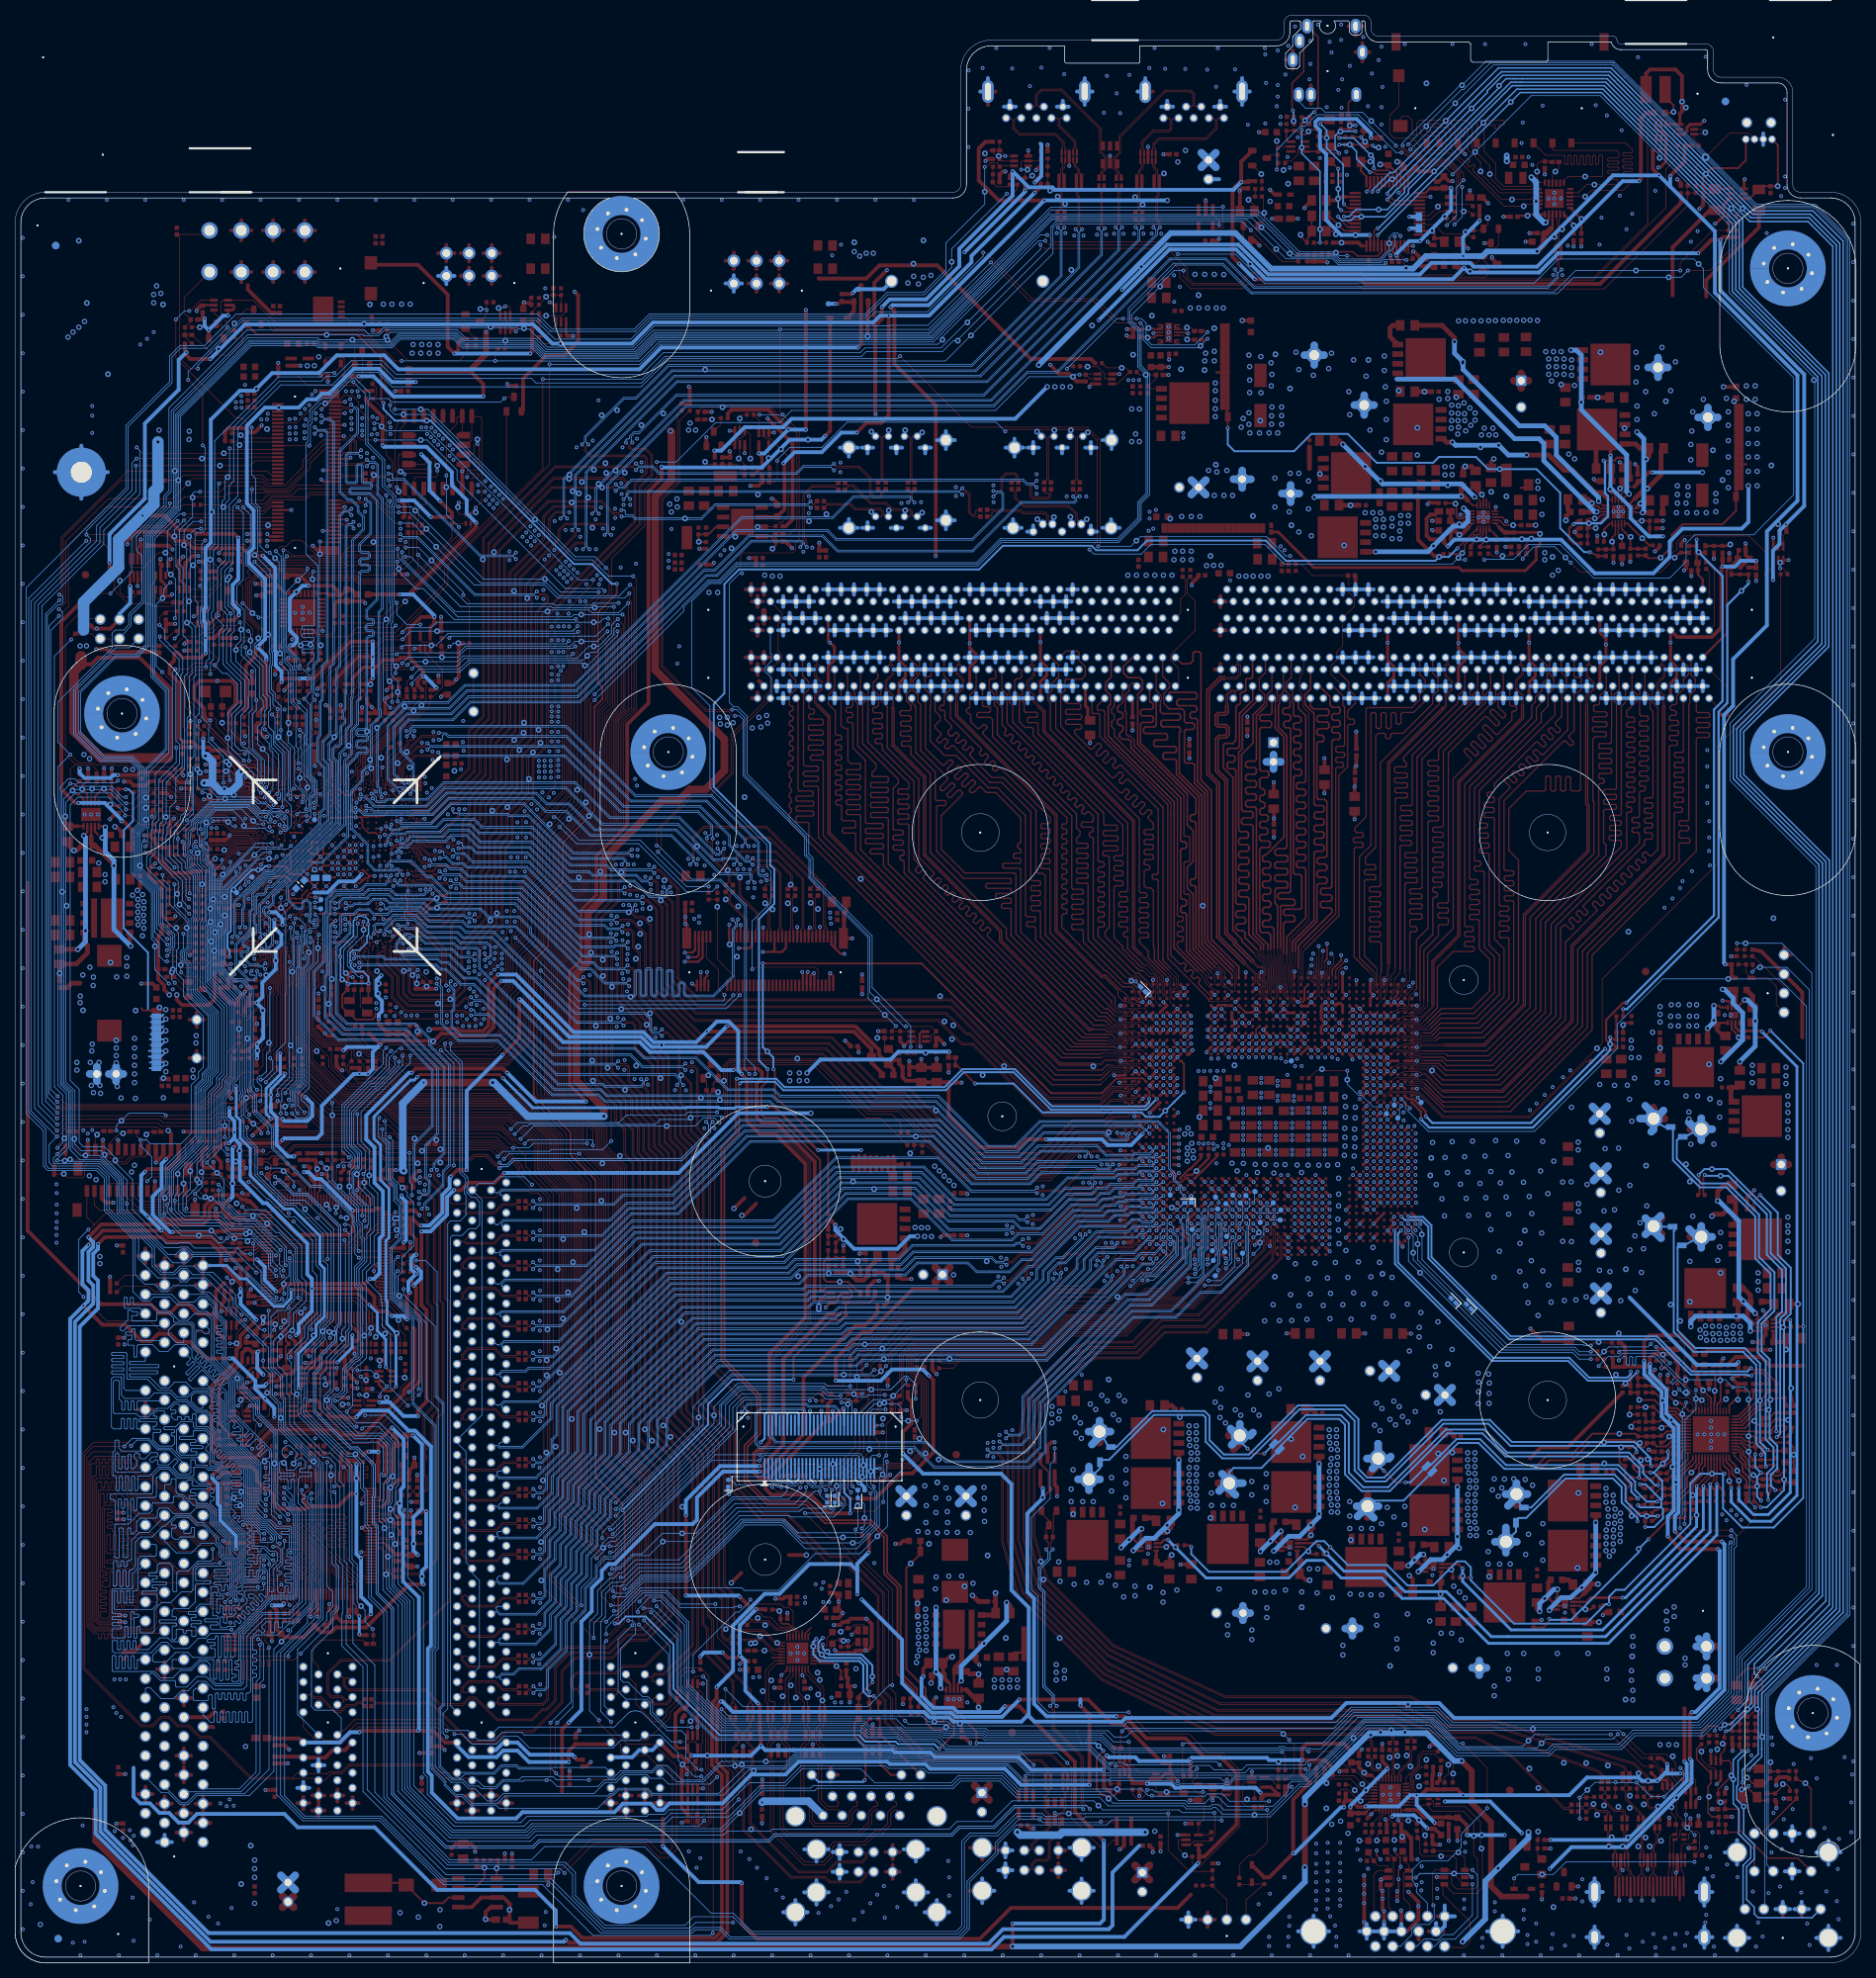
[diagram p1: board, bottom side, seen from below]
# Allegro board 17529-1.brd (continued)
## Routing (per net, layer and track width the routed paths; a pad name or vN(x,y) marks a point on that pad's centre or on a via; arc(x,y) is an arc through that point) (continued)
PAD18: length 65.7
  TOP w0.102: SLOT4.61 219.51,54.41 222.28,54.41 223.24,55.38 224.82,55.38 226.09,56.64 230.13,56.64 230.23,56.54 230.23,56.17 230.13,56.07 229.59,56.07 229.49,55.97 229.49,55.76 229.59,55.66 230.13,55.66 230.23,55.56 230.23,54.64 230.34,54.53 230.54,54.53 230.64,54.64 230.64,56.54 230.74,56.64 230.95,56.64 231.05,56.54 231.05,54.64 231.15,54.53 231.35,54.53 231.45,54.64 231.45,56.54 231.56,56.64 231.7,56.64 231.9,56.44 231.9,54.25 231.75,54.1 230.32,54.1 230.22,54 230.22,52.58 230.12,52.48 229.91,52.48 229.81,52.58 229.81,54 229.71,54.1 229.51,54.1 229.41,54 229.41,52.58 229.3,52.48 229.1,52.48 229,52.58 229,54.67 229.1,54.77 229.79,54.77 229.9,54.87 229.9,55.07 229.79,55.18 229.1,55.18 229,55.28 229,56.08 228.9,56.18 228.69,56.18 228.59,56.08 228.59,52.63 228.49,52.53 228.29,52.53 228.19,52.63 228.19,56.08 228.08,56.18 227.88,56.18 227.78,56.08 227.78,54.18 227.68,54.08 226.21,54.08 225.12,52.98 223.47,52.98 222.37,51.88 220.58,51.88 219.8,52.67 217.89,52.67 216.57,53.99 214.13,53.99 213.43,54.69 U9501.76
PAD19: length 65.4
  TOP w0.102: v2(217.88,54.69) 217.88,53.51 217.78,53.41 217.51,53.41 217.37,53.55 217.37,54.08 217.2,54.25 216.94,54.25 216.84,54.36 216.84,54.84 216.74,54.94 216.53,54.94 216.43,54.84 216.43,54.36 216.33,54.25 216.13,54.25 216.03,54.36 216.03,54.84 215.93,54.94 215.72,54.94 215.62,54.84 215.62,54.36 215.52,54.25 214.22,54.25 213.39,55.09 U9501.77
  BOTTOM w0.102: v2(217.88,54.69) 217.88,53.31 218.11,53.09 219.84,53.09 219.89,53.04 221.18,51.75 222.43,51.75 222.63,51.54 222.63,49.15 222.73,49.05 223.05,49.05 223.15,49.15 223.15,52.36 223.6,52.81 224.89,52.81 225.22,52.48 225.22,51.66 225.32,51.56 226.24,51.56 226.34,51.46 226.34,51.26 226.24,51.15 225.32,51.15 225.22,51.05 225.22,50.85 225.32,50.75 225.78,50.75 225.88,50.65 225.88,50.44 225.78,50.34 224.08,50.34 223.98,50.24 223.98,50.04 224.08,49.94 225.78,49.94 225.88,49.83 225.88,49.63 225.78,49.53 225.32,49.53 225.22,49.43 225.22,49.22 225.32,49.12 227.13,49.12 227.23,49.02 227.23,48.82 227.13,48.72 225.32,48.72 225.22,48.61 225.22,47.4 225.91,46.71 230.84,46.71 230.94,46.81 230.94,49.07 230.84,49.17 230.58,49.17 230.48,49.07 230.48,47.65 230.38,47.55 230.17,47.55 230.07,47.65 230.07,49.07 229.97,49.17 229.77,49.17 229.67,49.07 229.67,47.65 229.57,47.55 229.36,47.55 229.26,47.65 229.26,49.07 229.16,49.17 228.96,49.17 228.85,49.07 228.85,47.65 228.75,47.55 228.55,47.55 228.45,47.65 228.45,49.07 228.35,49.17 227.94,49.17 227.79,49.32 227.79,51.77 SLOT4.60
PAD20: length 66.3
  TOP w0.102: SLOT4.57 219.3,51.38 222.75,51.38 223.84,52.47 224.67,52.47 225.58,51.56 228.04,51.56 228.19,51.41 228.19,49.83 228.35,49.68 228.52,49.68 228.63,49.78 228.63,51.59 228.78,51.74 228.93,51.74 229.03,51.64 229.03,49.83 229.18,49.68 229.34,49.68 229.44,49.78 229.44,51.59 229.59,51.74 229.74,51.74 229.84,51.64 229.84,49.83 230,49.68 230.15,49.68 230.25,49.78 230.25,51.59 230.4,51.74 230.56,51.74 230.66,51.64 230.66,49.83 230.81,49.68 230.96,49.68 231.06,49.78 231.06,51.59 231.22,51.74 231.37,51.74 231.47,51.64 231.47,49.83 231.62,49.68 232.36,49.68 232.46,49.78 232.46,50.36 232.36,50.46 231.98,50.46 231.88,50.56 231.88,50.77 231.98,50.87 232.36,50.87 232.46,50.97 232.46,51.17 232.36,51.27 231.98,51.27 231.88,51.38 231.88,51.58 231.98,51.68 232.36,51.68 232.46,51.78 232.46,60.15 232.13,60.48 229.29,60.48 227.58,58.78 225.93,58.78 224.79,57.63 223.58,57.63 222.25,56.3 221.05,56.3 219.93,55.19 218.16,55.19 217.05,56.29 U9501.80
PAD21: length 63.9
  TOP w0.102: SLOT4.58 224.61,51.15 227.44,51.15 227.79,50.8 227.79,49.53 227.89,49.43 231.24,49.43 231.5,49.17 231.5,45.82 231.78,45.54 232.51,45.54 232.71,45.75 232.71,46.3 232.61,46.4 232.05,46.4 231.95,46.5 231.95,46.7 232.05,46.8 232.61,46.8 232.71,46.91 232.71,47.11 232.61,47.21 232.05,47.21 231.95,47.31 231.95,47.52 232.05,47.62 232.61,47.62 232.71,47.72 232.71,47.92 232.61,48.02 232.05,48.02 231.95,48.12 231.95,48.33 232.05,48.43 232.61,48.43 232.71,48.53 232.71,48.73 232.61,48.84 232.05,48.84 231.95,48.94 231.95,49.14 232.05,49.24 232.61,49.24 232.71,49.34 232.71,61.95 232.61,62.05 232.36,62.05 232.26,61.95 232.26,60.88 232.16,60.78 231.98,60.78 231.85,60.91 231.85,61.95 231.75,62.05 231.55,62.05 231.44,61.95 231.44,60.88 231.34,60.78 231.17,60.78 231.04,60.91 231.04,61.95 230.94,62.05 230.73,62.05 230.63,61.95 230.63,60.88 230.53,60.78 229.23,60.78 227.48,59.03 225.83,59.03 224.68,57.89 223.47,57.89 222.14,56.56 220.89,56.56 219.78,55.44 218.26,55.44 217.01,56.69 U9501.81
PAD22: length 64.6
  TOP w0.102: U9501.82 217.07,57.09 218.47,55.69 219.67,55.69 220.79,56.81 222.04,56.81 223.37,58.14 224.58,58.14 225.72,59.28 227.37,59.28 230.57,62.48 232.87,62.48 232.97,62.38 232.97,45.42 232.74,45.19 231.67,45.19 231.24,45.62 231.24,49.05 231.11,49.17 230.86,49.17 230.76,49.07 230.76,47.12 230.66,47.02 230.45,47.02 230.35,47.12 230.35,49.07 230.25,49.17 230.05,49.17 229.95,49.07 229.95,47.12 229.84,47.02 229.64,47.02 229.54,47.12 229.54,49.07 229.44,49.17 225.43,49.17 224.36,50.25 SLOT4.55
PAD23: length 64.9
  TOP w0.102: U9501.83 213.21,57.49 213.27,57.43 215.34,57.43 215.64,57.73 219.98,57.73 221.15,58.89 222.27,58.89 223.55,60.17 224.99,60.17 226.32,61.5 228.96,61.5 229.18,61.72 229.18,63.5 229.29,63.6 229.62,63.6 229.72,63.5 229.72,62.87 229.82,62.76 230.03,62.76 230.13,62.87 230.13,63.5 230.23,63.6 230.43,63.6 230.53,63.5 230.53,62.87 230.64,62.76 230.84,62.76 230.94,62.87 230.94,63.5 231.04,63.6 231.25,63.6 231.35,63.5 231.35,62.87 231.45,62.76 231.65,62.76 231.75,62.87 231.75,63.5 231.86,63.6 232.06,63.6 232.16,63.5 232.16,62.87 232.26,62.76 232.47,62.76 232.57,62.87 232.57,63.5 232.67,63.6 232.99,63.6 233.22,63.37 233.22,45.31 232.85,44.93 231.52,44.93 230.99,45.47 230.99,46.41 230.73,46.66 228.24,46.66 228.07,46.84 228.07,47.09 228.17,47.19 229.11,47.19 229.21,47.3 229.21,47.5 229.11,47.6 228.17,47.6 228.07,47.7 228.07,47.9 228.17,48.01 229.13,48.01 229.24,48.11 229.24,48.31 229.13,48.41 228.17,48.41 227.69,48.89 224.33,48.89 SLOT4.54
PAD24: length 63.9
  TOP w0.102: SLOT4.49 222.38,46.44 223.6,47.65 224.59,47.65 225.57,48.63 227.59,48.63 227.81,48.41 227.81,46.69 228.09,46.41 228.35,46.41 228.45,46.3 228.45,45.49 228.55,45.39 228.75,45.39 228.85,45.49 228.85,46.3 228.96,46.41 230.63,46.41 230.73,46.3 230.73,45.34 231.39,44.68 232.95,44.68 233.48,45.2 233.48,63.71 233.15,64.03 229.15,64.03 228.75,63.63 228.75,61.9 228.6,61.75 226.21,61.75 224.89,60.43 223.45,60.43 222.17,59.15 221.05,59.15 219.88,57.98 215.22,57.98 214.86,58.35 213.27,58.35 213.21,58.29 U9501.85
PAD25: length 64
  TOP w0.102: U9501.86 215.1,58.69 215.55,58.23 219.77,58.23 220.94,59.4 222.06,59.4 223.34,60.68 224.78,60.68 226.11,62 228.4,62 228.5,62.11 228.5,63.81 229.05,64.36 229.42,64.36 229.52,64.47 229.52,65.56 229.62,65.66 229.82,65.66 229.92,65.56 229.92,64.47 230.03,64.36 230.33,64.36 230.43,64.47 230.43,65.58 230.53,65.68 230.73,65.68 230.84,65.58 230.84,64.47 230.94,64.36 231.14,64.36 231.24,64.47 231.24,65.58 231.34,65.68 231.55,65.68 231.65,65.58 231.65,64.47 231.75,64.36 231.95,64.36 232.05,64.47 232.05,65.58 232.16,65.68 232.36,65.68 232.46,65.58 232.46,64.47 232.56,64.36 232.77,64.36 232.87,64.47 232.87,65.58 232.97,65.68 233.17,65.68 233.27,65.58 233.27,64.47 233.38,64.36 233.63,64.36 233.73,64.26 233.73,44.78 233.32,44.37 227.57,44.37 SLOT4.48
PAD26: length 64.3
  TOP w0.102: SLOT4.45 221.85,43.9 222.78,44.83 224.66,44.83 225.63,43.87 233.53,43.87 234.24,44.57 234.24,66.17 233.45,66.95 228.14,66.95 227.99,66.8 227.99,64.54 227.76,64.31 226.19,64.31 224.76,62.88 223.53,62.88 222.21,61.56 220.97,61.56 219.81,60.39 218.4,60.39 217.5,59.49 U9501.88
PAD27: length 66.1
  TOP w0.102: SLOT4.46 224.6,43.54 229.21,43.54 229.31,43.43 229.31,42.93 229.42,42.82 229.62,42.82 229.72,42.93 229.72,43.43 229.82,43.54 230.03,43.54 230.13,43.43 230.13,42.93 230.23,42.82 230.43,42.82 230.53,42.93 230.53,43.43 230.64,43.54 230.84,43.54 230.94,43.43 230.94,42.93 231.04,42.82 231.24,42.82 231.35,42.93 231.35,43.43 231.45,43.54 231.65,43.54 231.75,43.43 231.75,42.93 231.85,42.82 232.06,42.82 232.16,42.93 232.16,43.43 232.26,43.54 232.46,43.54 232.57,43.43 232.57,42.93 232.67,42.82 232.87,42.82 232.97,42.93 232.97,43.43 233.07,43.54 233.56,43.54 234.49,44.46 234.49,66.78 233.73,67.54 228.07,67.54 227.74,67.21 227.74,65.49 227.74,64.72 227.58,64.57 226.09,64.57 224.65,63.14 223.43,63.14 222.14,61.85 220.9,61.85 219.7,60.65 218.28,60.65 217.52,59.89 U9501.89
PAD28: length 63.9
  TOP w0.102: U9501.98 210.45,63.24 209.27,62.07 209.27,61.42 v2(208.48,60.63)
  BOTTOM w0.102: v2(208.48,60.63) 208.09,60.23 208.09,60.14 207.21,59.27 207.21,48.67 207.32,48.57 210.03,48.57 210.13,48.57 215.16,43.54 218.19,43.54 218.82,42.9 219.76,42.9 221.11,41.55 223.06,41.55 223.88,42.37 224.61,42.37 225.99,40.99 230.91,40.99 231.14,41.22 231.14,42.49 231.04,42.6 230.56,42.6 230.46,42.49 230.46,41.48 230.35,41.38 230.15,41.38 230.05,41.48 230.05,42.49 229.95,42.6 229.75,42.6 229.64,42.49 229.64,41.5 229.54,41.4 229.34,41.4 229.24,41.5 229.24,42.49 229.14,42.6 228.93,42.6 228.83,42.49 228.83,41.55 228.73,41.45 228.53,41.45 228.42,41.55 228.42,42.49 228.32,42.6 228.12,42.6 228.02,42.49 228.02,41.5 227.92,41.4 226.41,41.4 224.86,42.95 223.8,42.95 223.29,42.44 221.88,42.44 SLOT4.43
PAD29: length 63.6
  TOP w0.102: v2(208.45,61.37) 209.02,61.93 209.02,62.17 210.05,63.2 U9501.99
  BOTTOM w0.102: v2(208.45,61.37) 207.83,60.75 207.83,60.25 206.96,59.38 206.96,48.56 207.21,48.31 210.03,48.31 214.91,43.43 214.91,40.61 215.16,40.36 215.42,40.36 215.52,40.46 215.52,43.1 215.62,43.21 215.82,43.21 215.93,43.1 215.93,40.46 216.03,40.36 216.23,40.36 216.33,40.46 216.33,43.1 216.43,43.21 216.64,43.21 216.74,43.1 216.74,40.46 216.84,40.36 217.04,40.36 217.14,40.46 217.14,43.1 217.25,43.21 217.45,43.21 217.55,43.1 217.55,42.85 217.65,42.75 218.52,42.75 218.62,42.65 218.62,42.44 218.52,42.34 217.65,42.34 217.55,42.24 217.55,42.04 217.65,41.94 218.08,41.94 218.19,41.83 218.19,41.63 218.08,41.53 217.65,41.53 217.55,41.43 217.55,40.46 217.65,40.36 220.49,40.36 221.15,41.02 222.76,41.02 224.03,39.75 225.63,39.75 225.83,39.95 225.83,40.61 225.09,41.36 SLOT4.42
PAD30: length 65.7
  TOP w0.102: U9501.100 209.65,63.29 v2(208.46,62.1)
  BOTTOM w0.102: SLOT4.39 223.11,40.09 223.24,39.95 223.24,39.01 223.14,38.91 220.81,38.91 219.63,40.09 217.88,40.09 217.78,39.98 217.78,37.59 217.67,37.49 217.47,37.49 217.37,37.59 217.37,39.98 217.27,40.09 217.06,40.09 216.96,39.98 216.96,37.39 216.86,37.29 216.66,37.29 216.56,37.39 216.56,39.98 216.45,40.09 216.25,40.09 216.15,39.98 216.15,37.49 216.05,37.39 215.85,37.39 215.74,37.49 215.74,39.98 215.64,40.09 215.44,40.09 215.34,39.98 215.34,38.24 215.24,38.14 214.88,38.14 214.78,38.04 214.78,37.84 214.88,37.74 215.24,37.74 215.34,37.63 215.34,37.29 215.24,37.19 214.53,37.19 214.4,37.31 214.4,38.6 214.5,38.7 214.83,38.7 214.93,38.8 214.93,39 214.83,39.1 214.5,39.1 214.4,39.21 214.4,39.41 214.5,39.51 214.83,39.51 214.93,39.61 214.93,39.82 214.83,39.92 214.5,39.92 214.4,40.02 214.4,43.56 214.4,43.57 214.4,43.58 209.92,48.06 207.1,48.06 206.71,48.46 206.71,59.48 207.58,60.35 207.58,61.22 v2(208.46,62.1)
PAD31: length 72.9
  TOP w0.102: U9501.101 209.25,63.27 208.82,62.84 v2(208.4,62.84)
  BOTTOM w0.102: v2(208.4,62.84) 207.32,61.77 207.32,60.46 206.45,59.59 206.45,47.7 207.87,46.28 211.33,46.28 214.15,43.46 214.15,37.06 214.3,36.91 217.47,36.91 218.26,37.69 218.26,39.49 218.6,39.83 219.53,39.83 220.7,38.66 222.15,38.66 223.14,37.67 224.74,37.67 225.58,38.51 231.04,38.51 231.17,38.63 231.17,40.53 231.09,40.61 230.8,40.61 230.69,40.51 230.69,38.99 230.59,38.89 230.39,38.89 230.29,38.99 230.29,40.49 230.19,40.59 229.98,40.59 229.88,40.49 229.88,38.99 229.78,38.89 229.58,38.89 229.48,38.99 229.48,40.49 229.37,40.59 229.17,40.59 229.07,40.49 229.07,38.99 228.97,38.89 228.76,38.89 228.66,38.99 228.66,40.49 228.56,40.59 228.36,40.59 228.26,40.49 228.26,38.99 228.15,38.89 227.95,38.89 227.85,38.99 227.85,39.98 227.75,40.09 SLOT4.40
PC_SPKR_DET_PD: length 3
  TOP w0.102: U2401.54 200.8,102.31 v1(201.09,102.61) 200.91,102.78 R2449.2
PCBE0#: length 64.8
  TOP w0.102: U9501.46 203.65,49.78 203.91,50.04 203.91,50.18 203.65,50.44 203.65,50.59 203.79,50.73 203.93,50.73 204.2,50.47 204.34,50.47 204.48,50.61 204.48,50.75 203.71,51.53 203.71,51.67 203.86,51.81 204,51.81 204.77,51.04 204.92,51.04 205.06,51.19 205.06,51.33 204.29,52.1 204.29,52.24 204.43,52.39 204.58,52.39 205.35,51.62 205.49,51.62 205.63,51.76 205.63,51.9 204.86,52.68 204.86,52.82 205.01,52.96 205.15,52.96 205.92,52.19 206.07,52.19 206.21,52.34 206.21,52.48 205.44,53.25 205.44,53.39 205.58,53.54 205.73,53.54 206.5,52.77 206.64,52.77 206.78,52.91 206.78,53.06 206.03,53.81 206.03,53.96 206.17,54.1 206.31,54.1 207.07,53.34 207.22,53.34 207.65,53.77 v2(207.65,54.23)
  BOTTOM w0.102: v2(207.65,54.23) 207.49,54.38 207.49,57.56 207.65,57.71 209.37,57.71 210.19,58.52 211.02,58.52 212.27,59.78 212.27,65.72 214.28,67.74 214.85,68.31 215.14,68.59 215.94,69.4 215.94,71.26 216.23,71.55 216.23,75.26 216.41,75.44 216.55,75.44 216.87,75.13 217.01,75.13 217.16,75.27 217.16,75.41 216.84,75.73 216.84,75.87 216.99,76.02 217.13,76.02 217.44,75.7 217.59,75.7 217.73,75.85 217.73,75.99 217.42,76.3 217.42,76.5 219.21,78.29 219.4,78.29 220.76,76.93 220.9,76.93 221.05,77.08 221.05,77.22 219.69,78.58 219.69,78.72 219.83,78.86 219.98,78.86 221.13,77.71 221.27,77.71 221.42,77.86 221.42,78 220.27,79.15 220.27,79.3 220.41,79.44 220.55,79.44 221.02,78.97 221.16,78.97 221.31,79.12 221.31,79.26 220.84,79.73 220.84,79.87 221.69,80.73 SLOT4.99
PCBE1#: length 65.4
  TOP w0.102: v2(210.13,56.11) 210.13,55.85 204.85,50.57 U9501.49
  BOTTOM w0.102: v2(210.13,56.11) 210.13,56.46 210.93,57.25 211.54,57.25 213.54,59.25 213.54,65.2 215.18,66.84 216.96,68.62 217.21,68.87 217.21,70.24 217.97,70.99 217.97,72.3 218.69,73.03 219.88,73.03 221.28,74.42 222.58,74.42 223.47,75.31 225.6,75.31 226.31,74.59 229.51,74.59 229.95,75.02 229.95,77.34 230.05,77.44 231.01,77.44 231.27,77.19 231.27,70.84 230.99,70.57 230.06,70.57 229.96,70.67 229.96,71.86 229.86,71.96 229.66,71.96 229.56,71.86 229.56,70.67 229.45,70.57 229.25,70.57 229.15,70.67 229.15,71.86 229.05,71.96 228.85,71.96 228.74,71.86 228.74,70.67 228.64,70.57 228.44,70.57 228.34,70.67 228.34,71.86 228.24,71.96 228.03,71.96 227.93,71.86 227.93,70.67 227.83,70.57 SLOT4.88
PCBE2#: length 64.5
  TOP w0.102: U9501.69 213.67,51.89 215.9,49.66 v2(215.9,48.74)
  BOTTOM w0.102: SLOT4.66 224.24,55.74 222.68,54.18 220.68,54.18 219.39,55.46 217.69,55.46 217.07,54.84 217.07,53.82 216.12,52.87 216.12,52.55 216.22,52.45 219.66,52.45 220.14,51.97 220.14,50.61 220.04,50.51 218.26,50.51 218.16,50.41 218.16,50.21 218.26,50.11 220.04,50.11 220.18,49.97 220.18,47.69 221.07,46.8 223,46.8 223.24,46.56 223.24,45.84 223.14,45.73 222.76,45.73 222.66,45.63 222.66,45.43 222.76,45.33 224.84,45.33 224.94,45.23 224.94,45.02 224.84,44.92 222.76,44.92 222.66,44.82 222.66,44.62 222.76,44.51 223.14,44.51 223.24,44.41 223.24,42.8 223.14,42.7 222.91,42.7 222.71,42.9 222.71,43.99 222.61,44.09 221.88,44.09 221.78,43.99 221.78,43.66 221.68,43.56 221.48,43.56 221.38,43.66 221.38,43.87 221.27,43.97 220.75,43.97 220.65,43.87 220.65,43.23 220.55,43.13 220.21,43.13 220.1,43.23 220.1,44.31 220.21,44.41 220.65,44.41 220.75,44.51 220.75,44.71 220.65,44.82 219.48,44.82 219.38,44.92 219.38,45.12 219.48,45.22 220.65,45.22 220.75,45.32 220.75,45.53 220.65,45.63 220.21,45.63 220.1,45.73 220.1,45.93 220.21,46.04 221.01,46.04 221.11,46.14 221.11,46.34 221.01,46.44 220.21,46.44 220.1,46.54 220.1,46.87 219.58,47.4 218.26,47.4 218.14,47.52 218.14,49.63 218.06,49.71 217.35,49.71 217.16,49.52 217.16,49.03 216.87,48.74 v2(215.9,48.74)
PCBE3#: length 68.2
  TOP w0.102: SLOT4.52 225.48,47.71 225.3,47.52 225.3,44.88 226.06,44.12 233.43,44.12 233.98,44.67 233.98,65.86 233.88,65.96 233.39,65.96 233.28,66.07 233.28,66.52 233.18,66.62 232.98,66.62 232.88,66.52 232.88,66.07 232.78,65.96 232.57,65.96 232.47,66.07 232.47,66.52 232.37,66.62 232.17,66.62 232.07,66.52 232.07,66.07 231.96,65.96 231.76,65.96 231.66,66.07 231.66,66.52 231.56,66.62 231.35,66.62 231.25,66.52 231.25,66.07 231.15,65.96 230.95,65.96 230.85,66.07 230.85,66.52 230.74,66.62 230.54,66.62 230.44,66.52 230.44,66.07 230.34,65.96 230.13,65.96 230.03,66.07 230.03,66.52 229.93,66.62 229.73,66.62 229.63,66.52 229.63,66.07 229.53,65.96 229.32,65.96 229.22,66.07 229.22,66.52 229.12,66.62 228.92,66.62 228.81,66.52 228.81,66.07 228.71,65.96 228.35,65.96 228.24,65.86 228.24,65.56 228.35,65.46 229.08,65.46 229.18,65.36 229.18,65.15 229.08,65.05 228.35,65.05 228.24,64.95 228.24,64.19 227.96,63.91 226.14,63.91 224.86,62.63 223.64,62.63 222.32,61.31 222.11,61.31 221.08,61.31 219.91,60.14 218.51,60.14 217.46,59.09 U9501.87
PCH_CPU_BCLK_DN: length 118.3
  TOP w0.102: CPU1.W4 v2(94.03,109.59) ; SB1.C8 191.18,136.3 190.98,136.3 190.83,136.14 189.48,136.14 187.17,133.83 187.17,129.62 187.03,129.47 v2(187.03,129.16)
  BOTTOM w0.102: v2(187.03,129.16) 186.69,129.16 186.11,128.57 186.11,127.36 ; v1(186.49,127.36) 186.11,127.36 ; 186.11,127.36 186.11,126.09 186.39,125.81 186.39,123.72 185.13,122.47 179.9,122.47 172.73,115.3 166.61,115.3 165.8,114.49 143.98,114.49 143.22,113.73 122.3,113.73 115.67,107.1 111.48,107.1 108.05,110.53 95.26,110.53 94.67,109.93 94.37,109.93 v2(94.03,109.59)
PCH_CPU_BCLK_DP: length 118.2
  TOP w0.102: v2(186.41,129.72) 186.56,129.57 186.82,129.57 186.96,129.71 186.96,133.92 189.39,136.36 190.74,136.36 190.88,136.5 SB1.B8 ; v2(94.03,110.51) 94.03,110.39 93.69,110.05 CPU1.W5
  BOTTOM w0.102: v2(186.41,129.72) 186.56,129.56 186.56,129.34 185.89,128.66 185.89,126 186.17,125.72 186.17,123.81 185.04,122.68 179.81,122.68 172.64,115.52 166.52,115.52 165.71,114.71 151.08,114.71 ; v2(94.03,110.51) 94.39,110.15 94.58,110.15 95.18,110.75 108.14,110.75 111.57,107.32 115.58,107.32 122.21,113.94 143.13,113.94 143.89,114.71 151.08,114.71 ; 151.08,114.71 v1(151.08,115.09)
PCH_CPU_NSSC_CLK_DN: length 126
  TOP w0.102: SB1.C6 191.45,135.91 v2(191.87,135.49) ; v2(89.46,101.36) CPU1.J9
  BOTTOM w0.102: 152.11,117.56 149.82,115.28 143.73,115.28 142.88,114.43 122.01,114.43 115.38,107.8 111.77,107.8 108.5,111.08 92.97,111.08 91.52,109.63 91.52,104.9 90.88,104.27 90.88,103.43 89.94,102.48 89.94,101.84 v2(89.46,101.36) ; 152.11,117.56 v1(152.37,117.3) ; 152.11,117.56 154.01,119.47 160.87,119.47 162.15,120.75 172.08,120.75 182.73,131.39 182.73,133.71 183.02,134 185.43,134 186.06,134.62 189.79,134.62 190.68,135.51 191.85,135.51 v2(191.87,135.49)
PCH_CPU_NSSC_CLK_DP: length 125.9
  TOP w0.102: v2(192.4,135.9) 192.21,136.09 SB1.D7 ; v2(89.46,102.28) CPU1.K9
  BOTTOM w0.102: v2(89.46,102.28) 89.72,102.54 89.72,102.57 90.67,103.52 90.67,104.36 91.3,104.99 91.3,109.71 92.88,111.29 108.59,111.29 111.86,108.02 115.29,108.02 121.92,114.64 142.79,114.64 143.64,115.49 149.73,115.49 150.56,116.32 ; 150.56,116.32 153.92,119.68 160.78,119.68 162.06,120.96 171.99,120.96 182.51,131.48 182.51,133.8 182.93,134.21 185.34,134.21 185.97,134.84 189.7,134.84 190.59,135.72 191.48,135.72 191.69,135.94 192.36,135.94 v2(192.4,135.9) ; 150.56,116.32 v1(150.29,116.59)
PCH_CPU_PCIBCLK_DN: length 116.7
  TOP w0.102: SB1.B6 190.61,135.88 189.8,135.88 187.44,133.52 187.44,129.73 187.69,129.48 188.22,129.48 v2(188.29,129.41) ; v2(96.77,109.59) CPU1.W2
  BOTTOM w0.102: v2(188.29,129.41) 187.73,128.86 187.73,126.8 ; 187.73,126.8 187.73,124.08 185.42,121.77 180.24,121.77 173.08,114.6 166.9,114.6 166.04,113.74 144.25,113.74 143.54,113.03 122.59,113.03 115.96,106.4 111.19,106.4 107.99,109.6 100.11,109.6 99.14,108.63 97.05,108.63 96.77,108.91 v2(96.77,109.59) ; 187.73,126.8 v1(188.11,126.8)
PCH_CPU_PCIBCLK_DP: length 116.6
  TOP w0.102: v2(97.69,109.59) 97.36,109.59 97.23,109.73 CPU1.W1 ; SB1.A6 190.32,135.66 189.89,135.66 187.66,133.43 187.66,129.82 187.78,129.69 187.93,129.69 188.26,130.02 v2(188.26,130.1)
  BOTTOM w0.102: 99.68,109.48 99.05,108.85 97.14,108.85 96.99,109 96.99,109.18 97.21,109.4 97.21,109.55 97.33,109.68 97.61,109.68 v2(97.69,109.59) ; 99.68,109.48 v1(99.42,109.75) ; 99.68,109.48 100.02,109.82 108.08,109.82 111.28,106.62 115.87,106.62 122.5,113.25 143.45,113.25 144.16,113.96 165.95,113.96 166.81,114.82 172.99,114.82 180.15,121.98 185.33,121.98 187.52,124.17 187.52,128.95 187.76,129.19 187.76,129.97 187.88,130.1 v2(188.26,130.1)
PCH_DPWROK: length 342
  TOP w0.102: v2(193.12,190.27) 193.78,190.27 197.54,194.03 204.92,194.03 205.58,193.37 210.08,193.37 211.1,192.35 v2(213.87,192.35) ; v2(162.81,180.97) 162.81,180.19 162.51,179.88 162.51,165.83 164.21,164.13 164.21,150.84 168.28,146.77 168.28,142.84 168.28,141.6 170.31,139.58 170.31,133.03 171.81,131.53 171.81,115.54 166.42,110.15 166.42,107.7 163.75,105.04 163.75,67.85 159.97,64.06 159.97,46.36 v2(159.93,46.32) ; SB1.AW41 208.83,152.82 208.72,152.71 208.72,152.74 v2(208.68,152.74) ; R2612.2 86.23,16.91 U2602.4 R2619.1 87.38,18.41 86.87,18.92 86.87,21.83 87.39,22.35 87.59,22.35 88.37,23.13 88.37,24.03 87.76,24.64 v2(87.76,25.65)
  BOTTOM w0.102: v2(162.81,180.97) 163.42,180.37 172.26,180.37 173.96,182.07 183.26,182.07 v1(188.34,187.15) 191.47,190.27 v2(193.12,190.27) ; v2(208.68,152.74) 208.68,159.81 209.85,160.99 209.85,162.74 210.49,163.37 210.49,165.3 210.24,165.56 210.24,167.2 210.74,167.71 210.74,171.54 212.37,173.17 212.37,174.27 211.38,175.26 211.38,182.69 213.41,184.72 213.54,184.85 213.54,186.55 212.9,187.18 212.9,191.39 v2(213.87,192.35) ; v2(87.76,25.65) 88.06,25.35 99.26,25.35 102,28.09 120.97,28.09 122.22,29.34 127.1,29.34 127.43,29.67 131.4,29.67 132.26,30.53 150.68,30.53 156.54,36.39 156.54,42.94 v2(159.93,46.32)
PCH_HEATSINK_DET: length 84.7
  TOP w0.102: HS1901.2 HS1901.1 183.96,171 R1904.1 183.96,179.97 v2(184.76,180.77) ; SB1.AN37 205.78,150.95 205.47,150.95 v2(205.43,150.91) ; v2(209.55,186.56) 208.91,187.2 208.18,187.2 207.37,188.01 206.12,188.01 203.99,185.88 201.05,185.88 199.58,187.35 192.68,187.35 v2(192.38,187.05)
  BOTTOM w0.102: v2(209.55,186.56) 208.81,185.83 208.81,173.71 208.36,173.22 208.36,172.31 207.37,171.32 207.37,170.97 207.26,170.87 207.26,166.73 205.61,165.07 205.61,161.05 205.49,160.93 205.49,156.73 204.77,156.01 204.77,154.74 205.19,154.32 205.19,153.96 204.95,153.72 204.95,153.14 204.91,153.1 204.91,151.43 v2(205.43,150.91) ; v2(192.38,187.05) 190.65,187.05 v1(188.95,185.34) 184.76,181.15 v2(184.76,180.77)
PCH_INTRUDER_N: length 26.7
  TOP w0.102: R1507.1 214.17,176.15 v1(214.12,176.2) 214.07,176.15 213.28,176.15 v2(213.16,176.02) ; SB1.BB44 210.41,154.6 210.42,154.62 v2(210.42,154.64)
  BOTTOM w0.102: v2(210.42,154.64) 209.93,155.13 209.93,160.01 210.41,160.49 210.41,161.16 211.44,162.19 211.44,163.2 211,163.64 211,165.48 210.72,165.76 210.72,167 211.23,167.51 211.23,171.34 212.88,172.99 v1(212.88,174.75) 212.88,175.67 213.11,175.9 213.11,175.97 v2(213.16,176.02)
PCH_JTAG_TCK: length 163.6
  TOP w0.089: 204.27,131.11 204.27,131.32 203.98,131.6 203.98,134.3 SB1.AJ3
  TOP w0.102: v2(164.97,49.15) 164.97,50.85 164.71,51.11 164.71,51.24 164.4,51.56 164.4,55.49 164.99,56.08 165.06,56.08 169.85,60.88 169.85,62.14 169.88,62.17 169.88,62.74 169.93,62.79 169.93,101.62 169.93,102.4 173.16,105.63 173.16,108.2 173.16,108.69 177.3,112.84 177.85,113.39 191.4,113.39 191.93,113.92 191.93,113.92 194.39,116.38 195.17,116.38 195.17,116.38 195.91,116.38 196.42,116.38 196.42,116.38 198.69,116.38 200.3,118 200.3,118.45 R2011.1 200.62,119.74 C2001.1 200.03,120.38 200.03,120.73 200.56,121.26 203.24,121.26 205.23,123.25 205.23,128.85 204.27,129.82 204.27,131.11
  BOTTOM w0.102: XDP1.55 131.42,63.22 130.33,62.13 130.33,58.06 132.16,56.24 v1(134.57,56.24) 140.27,56.24 142.44,58.41 147.78,58.41 155.19,51 161.09,51 163.25,48.84 164.67,48.84 v2(164.97,49.15)
PCH_JTAG_TDI: length 152.7
  TOP w0.089: 203.81,131.04 203.81,131.2 203.6,131.41 203.6,133.66 SB1.AH2
  TOP w0.102: 203.81,131.04 203.81,129.46 204.77,128.5 204.77,123.44 203.05,121.72 200.33,121.72 199.21,120.6 199.21,119.9 R2026.1 197.87,118.55 197.87,117.37 197.54,117.04 194.6,117.04 194.6,117.04 194.41,117.04 191.21,113.84 177.64,113.84 172.67,108.87 172.67,105.79 169.47,102.59 169.47,101.43 169.47,101.43 169.47,62.98 169.42,62.93 169.42,62.36 164.92,57.86 164.92,56.71 v2(165,56.63) ; v2(129.03,75.06) 128.14,75.06 R411.2
  BOTTOM w0.102: v2(129.03,75.06) 131.25,75.06 131.55,74.75 132.7,74.75 v1(133.12,75.17) 133.31,75.36 136.58,75.36 137.21,76 148.27,76 150.62,73.65 150.62,71.01 v2(165,56.63)
PCH_JTAG_TDO: length 160.2
  TOP w0.089: SB1.AH3 203.79,133.99 203.79,131.5 204.02,131.27 204.02,131.17
  TOP w0.102: R410.2 v2(124.97,74.55) ; 204.02,131.17 204.02,129.76 205,128.78 205,123.35 203.14,121.49 200.43,121.49 199.52,120.57 R2024.1 200.08,118.61 200.08,118.1 198.79,116.81 194.5,116.81 191.7,114.02 191.3,113.61 177.76,113.61 177.08,112.93 172.9,108.75 172.9,105.7 169.7,102.5 169.7,101.53 169.7,62.89 169.65,62.84 169.65,62.26 169.62,62.24 169.62,61.54 v2(165.35,57.28)
  BOTTOM w0.102: v2(165.35,57.28) 164.92,57.28 150.85,71.35 150.85,73.74 148.37,76.23 137.12,76.23 136.66,75.77 v1(130.81,75.77) 128.21,75.77 126.45,77.53 126.01,77.53 124.97,76.49 v2(124.97,74.55)
PCH_JTAG_TMS: length 172.8
  TOP w0.089: SB1.AJ4 204.29,134.59 204.29,134.13 204.17,134.02 204.17,131.76 204.36,131.58 204.36,131.55
  TOP w0.102: v2(164.85,46.51) 164.85,47.01 164.8,47.06 164.8,47.7 165.4,48.31 165.4,50.74 164.94,51.21 164.94,51.34 164.62,51.66 164.62,55.39 165.09,55.85 165.15,55.85 170.02,60.72 170.15,60.86 170.15,101.72 170.15,102.31 173.38,105.54 173.38,108.3 173.38,108.59 177.95,113.16 191.49,113.16 192.16,113.83 194.49,116.15 195.08,116.15 195.82,116.15 196.32,116.15 199.71,116.15 202.18,118.63 202.18,120.59 R2028.1 202.63,121.03 203.33,121.03 205.46,123.16 205.46,128.96 204.55,129.87 204.55,131.36 204.36,131.55 ; v2(126.71,66.49) 126.7,66.49 126.7,66.5 126.69,66.5 126.16,66.5 125.09,67.56 R412.2
  BOTTOM w0.102: v2(126.71,66.49) 126.7,66.49 126.7,65.2 128.69,63.21 128.69,57.7 v1(130.01,56.38) 132.31,54.08 138.24,54.08 143.1,49.23 147.6,49.23 147.93,49.56 161.32,49.56 164.36,46.51 v2(164.85,46.51)
PCH_JTAGX: length 22.3
  TOP w0.102: R2008.1 R2021.1 197.57,119.16 v1(198.54,120.13) 198.54,120.43 200.05,121.95 202.95,121.95 204.55,123.54 204.55,128.4 203.48,129.46 203.48,130.28 202.95,130.81 202.95,132.08 203.15,132.29 203.15,134.31 SB1.AH4
PCH_PECI: length 11.6
  TOP w0.102: SB1.AF2 202.94,133.76 202.94,132.46 202.74,132.26 202.74,130.62 203.23,130.14 203.23,128.86 v1(203.31,128.78) 203.31,128.22 203.19,128.1 203.19,127.37 203.12,127.3 203.12,124.11 203.05,124.04 203.05,124.03 202.94,123.93 202.94,123.93 202.39,123.38 R1708.1
PCH_PME_N: length 144.4
  TOP w0.102: v2(207.9,40.51) 215.58,40.51 R9202.2 ; v2(218.67,105.77) 218.48,105.96 R1508.2 ; SB1.BE36 212.01,150.59 212.24,150.36 212.53,150.36 212.66,150.23 214.1,150.23 215.02,151.15 v2(215.02,151.19)
  BOTTOM w0.102: v2(215.02,151.19) 215.02,151.25 215.13,151.35 218.02,151.35 218.82,150.55 218.82,148.84 219.46,148.21 219.46,147.67 218.92,147.13 218.92,145.71 218.16,144.95 218.16,137.29 218.44,137.01 218.44,129.79 215.67,127.02 215.67,126.98 215.59,126.91 215.37,126.68 215.37,117.07 216.01,116.42 216.01,116.27 216.01,115.49 217.09,114.41 217.09,107.34 v2(218.67,105.77) v1(217.31,104.41) 216.41,103.5 216.41,100.95 214.41,98.96 211.15,98.96 206.69,94.5 206.69,90.4 206.1,89.8 206.1,87.68 207.82,85.95 207.82,84.23 209.88,82.17 209.88,78.77 208.65,77.53 208.65,74.98 208.25,74.58 208.25,70.9 203.29,65.94 203.29,45.47 207.9,40.86 v2(207.9,40.51)
PCH_PS_ON_N: length 104.4
  TOP w0.089: v2(206.55,158.52) 206.22,158.52 205.35,157.65 205.35,156.67 205.53,156.5 205.53,155.52 205.51,155.48 205.49,155.46 205.47,155.42 205.47,155.22 205.32,155.08
  TOP w0.102: R2023.1 230.15,188.01 228.52,189.64 223.77,189.64 222.55,188.42 221.18,188.42 220.22,187.45 213.66,187.45 212.69,186.49 210.49,186.49 v2(210.36,186.36) ; SB1.AP41 206.67,153.25 206.45,153.46 206.45,153.58 206.2,153.83 206.19,153.83 206.17,153.85 206.07,153.85 205.93,153.99 205.8,153.99 205.62,154.17 205.62,154.34 205.22,154.74 205.22,154.97 205.32,155.08 ; v2(222.76,217.17) 222.76,212.09 214.83,204.17 214,204.17 v2(212.72,202.9) ; U4301.6 219.45,219.73 220.87,218.31 v2(220.98,218.31)
  BOTTOM w0.102: v2(222.76,217.17) 221.62,218.31 v2(220.98,218.31) ; v2(212.72,202.9) 212.72,196.67 212.22,196.16 212.22,192.89 211.63,192.3 211.63,187.25 210.82,186.44 210.44,186.44 v2(210.36,186.36) v1(209.63,185.63) 209.12,185.12 209.12,173.59 208.66,173.1 208.66,172.19 207.67,171.2 207.67,170.85 207.57,170.75 207.57,166.6 206.88,165.91 206.88,160.78 206.55,160.45 v2(206.55,158.52)
PCH_PS_ON_N_EXTD1: length 8
  TOP w0.102: U2002.1 227.32,181.43 C2004.1 228.23,180.52 229.54,180.52 230.15,181.13 v1(230.15,182.65) R2023.2
PCH_PWROK: length 344.9
  TOP w0.102: SB1.AY42 210.1,153.53 210.11,153.54 v2(210.17,153.54) ; v2(162.69,182.12) 162.2,181.64 162.2,169.8 162.2,165.7 163.91,164 163.91,150.72 167.98,146.65 167.98,142.96 167.98,141.48 170,139.45 170,132.9 171.5,131.4 171.5,115.66 166.12,110.28 166.12,107.83 163.45,105.16 163.45,67.98 159.41,63.94 159.41,48.01 v2(159.54,47.88) ; v2(214.6,192.37) 214.46,192.37 214.05,192.79 211.05,192.79 210.13,193.7 205.68,193.7 205.05,194.34 197.31,194.34 194.67,191.69 v2(193.27,191.69) ; R4016.2 76.11,27.47 v2(76.52,27.88) ; v2(212.12,166.87) 212.67,167.43 DB2001.1
  BOTTOM w0.102: v2(214.6,192.37) 213.84,191.61 213.84,182.79 214.68,181.95 214.68,179.74 213.72,178.77 213.72,174.5 214.1,174.12 214.1,172.85 212.19,170.94 212.19,166.94 v2(212.12,166.87) 212.12,165.52 212.6,165.04 212.6,160.44 211.04,158.89 211.04,155.82 211.25,155.61 211.25,154.94 210.85,154.54 210.85,154.44 210.6,154.19 210.6,153.98 v2(210.17,153.54) ; v2(162.69,182.12) 164.13,180.67 172.09,180.67 173.79,182.37 182.5,182.37 v1(189.64,189.51) 191.77,191.64 193.22,191.64 v2(193.27,191.69) ; v2(76.52,27.88) 76.58,27.81 98.87,27.81 100.54,29.48 102.28,29.48 115.88,29.48 116.17,29.77 121.36,29.77 121.77,30.18 126.75,30.18 127.08,30.51 131.05,30.51 131.91,31.37 150.33,31.37 155.52,36.56 155.52,44.65 158.75,47.88 v2(159.54,47.88)
PCH_PWROK_EC: length 4.7
  TOP w0.102: R2439.1 197.02,106.2 C2413.1 R2442.1 197.9,105.12 198.8,104.22 v1(198.81,104.22) 199.66,104.22 R2433.1
PCH_RTCRST_DOWN: length 2.3
  TOP w0.102: JMP1.6 232.83,177.63 R2035.1
PCH_RTCRST_N: length 72.8
  TOP w0.102: v2(236.6,174.88) 236.6,175.02 R2036.2 ; R9919.1 236.79,109.66 v1(237.49,108.97) 238.4,108.05 v2(238.4,107.7)
  BOTTOM w0.102: v2(238.4,107.7) 237.72,108.38 237.72,114.68 238.81,115.77 238.81,172.67 v2(236.6,174.88)
PCH_RTCRST_PULLUP: length 46.6
  TOP w0.102: v2(211.48,156) 211.62,155.86 SB1.BE47 ; v2(214.27,177.16) 214.71,176.73 216.98,176.73 217.94,175.78 219.27,175.78 219.79,175.26 221.69,175.26 222.81,174.14 R2040.1 C2006.1 224.98,173.99 230.62,173.99 231.64,175.01 JMP1.5 233.27,175.01 233.93,175.67 R2036.1
  BOTTOM w0.102: v2(211.48,156) 211.48,159.03 213.08,160.64 213.08,165.24 212.67,165.65 212.67,169.88 214.81,172.01 v1(214.81,173.51) 214.81,174.09 214.2,174.7 214.2,177.09 v2(214.27,177.16)
PCH_RTCX1: length 15.5
  TOP w0.102: X1802.1 218.92,167.87 218.14,167.09 R1814.1 218.14,165 C1803.1 217.4,164.26 217.4,163.37 v1(215.9,161.87) 214.3,160.27 213.33,160.27 210.02,156.96 SB1.BA49
PCH_RTCX2: length 15.3
  TOP w0.102: X1802.2 216.62,167.59 R1814.2 216.62,164.97 C1804.1 216.6,163.91 v1(216.64,163.88) 216.64,163.45 213.84,160.66 213.4,160.66 209.77,157.03 209.77,156.68 210.13,156.32 SB1.BA48
PCH_SATA_LED_N: length 245.9
  TOP w0.102: v2(173.35,211.25) 173.35,197.99 186.79,184.55 186.79,182.14 192.33,176.61 192.33,173.79 192.68,173.43 195.27,173.43 196.54,172.16 198.41,172.16 201.24,169.33 201.24,168.62 R1704.1 201.63,167.93 201.63,163.09 203.59,161.12 203.59,157.9 204.43,157.07 SB1.AK48 ; U6401.2 26.42,243.46 26.67,243.71 27.94,243.71 28.19,243.46 28.19,229.84 35.48,222.55 65.17,222.55 66.03,223.42 80.75,223.42 82.19,221.97 88.24,221.97 89.03,222.76 89.03,223.9 92.18,227.05 107.29,227.05 v2(107.82,227.58)
  BOTTOM w0.102: v2(173.35,211.25) 161.42,211.25 158.76,213.91 122.01,213.91 v1(121.41,214.5) 121.41,214.88 108.71,227.58 v2(107.82,227.58)
PCH_SATA_LED_NMOS: length 4.5
  TOP w0.102: R6416.1 27.07,239.98 U6401.6 ; R6416.1 v1(26.61,238.53) ; R6416.1 26.42,239.71 U6401.5
PCH_SIO_DPWROK: length 216.5
  TOP w0.102: U2602.1 88.66,15.61 88.14,16.13 86.12,16.13 R2612.1 85.39,16.85 85.39,19.76 v2(85.46,19.82) ; R2475.1 211.91,97.66 211.91,97.67 U2401.28 210.62,97.54 209.58,97.54 207.57,95.53 v2(200.46,95.53)
  BOTTOM w0.102: v2(85.46,19.82) 85.5,19.86 89.76,19.86 90.12,20.22 100.23,20.22 v1(100.8,20.79) 101.42,21.41 112.2,21.41 114.93,18.68 119.5,18.68 120.52,17.67 143.89,17.67 144.16,17.4 149.85,17.4 150.35,16.89 150.36,16.89 175.08,16.89 175.9,16.07 186.76,16.07 193.34,22.65 193.34,47.24 194.68,48.58 195.38,49.28 195.38,55.6 195.38,55.6 195.38,57.24 195.38,57.24 195.38,57.99 195.88,58.5 195.88,61.24 195.76,61.36 195.76,64.54 195.33,64.97 195.33,68.08 196.05,68.81 199.33,68.81 203.66,73.14 203.66,77.57 202.84,78.39 202.84,79.93 200.81,81.96 200.81,83.62 200.34,84.09 200.34,95.42 v2(200.46,95.53)
PCH_SLP_A_N: length 124
  TOP w0.089: SB1.BE40 212.1,152.28 212.16,152.35 212.79,152.35 213.04,152.59 213.52,152.59 213.62,152.69
  TOP w0.102: R2420.1 v2(211.04,83.64) ; v2(230.43,156.24) 230.12,156.54 227.34,156.54 R2051.1 226.83,156.92 223.88,156.92 222.51,155.55 222.5,155.55 222.5,155.01 222.15,154.66 220.57,154.66 219.18,153.27 214.2,153.27 213.62,152.69 ; v2(238.43,106.05) 238.53,106.05 238.84,105.77 R9916.1
  BOTTOM w0.102: v2(211.04,83.64) 211.47,83.64 214.86,87.03 214.86,88.29 217.82,91.25 219.53,91.25 220.37,92.09 222.2,92.09 223.04,91.25 224.61,91.25 225.57,92.21 225.57,94.54 230.23,99.19 230.23,103.17 230.23,103.43 232.72,105.92 236.47,105.92 v1(236.73,106.17) 236.85,106.05 v2(238.43,106.05) 238.43,106.22 236.93,107.72 236.93,115.01 238.02,116.1 238.02,155.42 236.98,156.46 236.09,156.46 235.59,155.96 230.71,155.96 v2(230.43,156.24)
PCH_SRTCRSTB_PULLUP: length 25.7
  TOP w0.102: R2042.2 R2043.1 C2007.1 214.95,174.21 214.6,173.86 v2(213.54,173.86) ; v2(210.82,155.32) 210.82,155.32 211.04,155.32 211.2,155.47 SB1.BD46
  BOTTOM w0.102: v2(213.54,173.86) 213.54,172.97 211.71,171.14 211.71,167.31 211.2,166.8 211.2,165.96 211.48,165.68 211.48,163.8 211.94,163.35 211.94,161.09 v1(211.27,160.42) 210.52,159.66 210.52,155.62 v2(210.82,155.32)
PCH_SYSPWROK: length 260.1
  TOP w0.102: v2(128.04,36.7) 128.04,49.35 132.88,54.19 v2(132.88,57.27) ; U2404.6 212.38,71.61 211.78,72.21 210.64,72.21 210.36,72.49 210.36,73.28 209.55,74.09 206.23,74.09 205.31,75.01 202.64,75.01 202.16,74.53 202.16,73.99 202.08,73.91 202.08,73.75 201.2,72.87 v2(200.15,72.87) ; v2(197.97,104.27) 197.09,105.14 R2439.2 ; SB1.AU3 208,134.09 208.2,133.89 208.2,133.56 208.36,133.41 208.36,131.73 208.35,131.72 208.35,130.38 209.37,129.35 209.37,128.4 209.91,127.86 209.91,121.33 210.77,120.47 210.77,117.2 209.65,116.08 209.25,116.08 206.69,116.08 R2003.1 206.26,115.89 202.54,112.17 v2(198.75,112.17) ; v2(148.34,21.59) 148.34,25.1 150.11,26.87 v2(150.11,36.2)
  BOTTOM w0.102: v2(128.04,36.7) 128.44,36.7 131.29,33.86 147.78,33.86 v2(150.11,36.2) ; v2(148.34,21.59) 150.16,19.76 157.33,19.76 157.94,19.15 157.94,19.15 158.21,18.88 158.23,18.87 175.9,18.87 176.72,18.05 185.94,18.05 191.31,23.42 191.31,48.01 193.4,50.1 193.4,56.42 193.4,58.81 193.9,59.32 193.9,60.42 193.7,60.62 193.7,62.83 193.32,63.21 193.32,68.89 195.8,71.37 198.89,71.37 200.15,72.64 v2(200.15,72.87) 199.39,73.63 199.39,78.28 198.68,78.99 198.5,78.99 197.59,79.91 197.59,89.46 198.06,89.93 198.06,91.51 197.03,92.54 197.03,96.18 196.55,96.67 196.55,101.22 197.87,102.54 v1(197.87,103.12) 197.87,104.17 v2(197.97,104.27) 197.69,104.55 197.69,107.3 198.75,108.36 v2(198.75,112.17) ; v2(132.88,57.27) 132.59,57.56 R9905.1
PCH_SYSPWROK_EXTD1: length 10.5
  TOP w0.102: 214.71,75.34 U2403.2 ; 214.71,75.34 216.28,73.76 216.28,72.39 216.15,72.26 U2404.2 ; 214.71,75.34 214.63,75.41 v1(214.63,77.24) 214.63,77.85 213.22,79.26 U2402.4
PCH_SYSPWROK_EXTD2: length 7.6
  TOP w0.102: U2404.5 213.74,72.26 214,72.52 214,74.07 213.89,74.17 213.18,74.17 212.94,74.41 212.94,75.87 212.82,75.99 U2403.4 211.5,75.34 v1(210.69,75.34)
PCH_SYSPWROK_EXTD3: length 4.8
  TOP w0.102: U2404.1 214.52,71.61 214.38,71.75 214.38,72.64 214.65,72.91 U2404.3 215.19,73.33 214.9,73.62 v2(214.52,73.62)
  BOTTOM w0.102: v1(214.17,74.4) 214.17,73.97 v2(214.52,73.62)
PCH_WAKE_N: length 410
  TOP w0.089: 210.95,157.02 210.87,156.94 210.87,156.69 211.01,156.54 SB1.BB47
  TOP w0.102: v2(217.04,195.5) 216.87,195.68 211.28,195.68 210.77,195.17 208.43,195.17 207.49,196.1 207.49,196.14 205.97,197.66 205.97,198.57 203.29,201.25 NGFF1.55 200.33,201.25 199.75,201.83 198.86,201.83 198.28,201.25 v2(196.37,201.25) ; 196.8,69.09 197.24,68.66 201.27,68.66 202.71,67.22 202.71,66.18 v2(202.73,66.15) ; 196.8,69.09 192.23,73.66 v2(192.05,73.66) ; 196.8,69.09 196.67,68.97 196.67,66.51 196.69,66.5 196.69,66.42 R9512.1 196.9,66.21 U9501.1 ; v2(191.77,119.89) 191.59,120.07 180.47,120.07 178.03,122.5 178.03,127.61 177.22,128.43 177.22,133.15 175.26,135.1 175.26,141.63 173.33,143.56 173.33,148.82 v2(172.01,150.14) 169.16,152.98 169.16,168.94 168.17,169.93 168.17,178.99 166.07,181.1 v2(166.07,181.31) ; R6202.2 v2(151.18,142.24) ; v2(218.19,170.33) 218.24,170.28 219.99,170.28 221.01,169.27 221.01,166.82 219.7,165.52 219.7,164.84 219.01,164.14 R2014.1 218.92,163.45 213.93,158.46 213.61,158.46 213.39,158.24 212.17,158.24 210.95,157.02 ; SLOT1.B11 162.54,29.4 160.46,29.4 157.4,32.45 157.4,33.15 155.98,34.57 155.98,34.72 155.98,37.82 155.32,38.48 v2(154.37,38.48) ; v2(186.95,30.71) 187.05,30.71 188,31.66 198.84,31.66 201.1,29.4 203.18,29.4 SLOT3.B11 ; v2(146.81,48.01) 146.23,47.42 142.8,47.42 142.44,47.07 142.44,47.07 142.32,46.94 141.63,46.94 141.15,46.46 141.15,44.53 140.36,43.74 U3101.21
  BOTTOM w0.102: v2(196.37,201.25) v1(190.37,201.25) 189.53,201.25 185.57,197.29 185.57,195.95 171.26,181.64 166.4,181.64 v2(166.07,181.31) ; v2(202.73,66.15) 202.81,66.08 202.81,49.82 202.02,49.03 202.02,47.06 202.78,46.3 202.78,45.29 206.67,41.4 206.67,32.86 206.2,32.4 206.18,32.4 SLOT3.B11 ; SLOT1.B11 176.7,30.12 177.04,30.45 179.65,30.45 180.7,29.41 180.77,29.41 180.78,29.4 181.38,29.4 181.39,29.41 182.78,29.41 183.26,29.89 183.35,29.89 SLOT2.B11 184.17,30.71 186.95,30.71 v2(186.95,30.71) ; v2(146.81,48.01) 146.81,47.84 148.3,46.35 148.72,46.35 154.37,40.7 v2(154.37,38.48) ; v2(217.04,195.5) 217.14,195.4 217.14,187.27 217.78,186.63 217.78,178.71 218.05,178.45 218.05,177.69 217.78,177.42 217.78,172.27 217.86,172.19 217.86,172.19 218.19,171.86 v2(218.19,170.33) ; v2(151.18,142.24) 151.84,141.58 155.27,141.58 161.59,147.9 169.77,147.9 v2(172.01,150.14) ; v2(191.77,119.89) 191.77,118.94 198.27,112.44 198.27,108.56 197.18,107.47 197.18,102.81 196.06,101.69 196.06,96.47 196.55,95.98 196.55,92.34 197.57,91.31 197.57,90.13 195.61,88.16 195.61,87.33 195.47,87.19 195.47,84.14 194.37,83.05 194.37,75.98 v2(192.05,73.66)
PCH_XDP_PRDY_R_N: length 144.7
  TOP w0.089: SB1.AM5 205.5,134.84 205.47,134.82 205.47,134.5 205.35,134.38 205.35,133.64 205.16,133.46 205.16,132.37 205.71,131.81
  TOP w0.102: 205.71,131.81 205.71,130.3 207.06,128.96 207.06,122.49 205.23,120.66 205.23,119.22 200.57,114.55 195.66,114.55 195.15,114.55 193.76,113.16 193.76,113.16 192.15,111.56 178.61,111.56 174.99,107.93 174.99,104.87 171.75,101.64 171.75,101.39 171.75,59.2 166.24,53.69 166.24,53.67 166.11,53.53 166.11,52.12 v2(165.37,51.39) ; R9902.1 140.44,64.35 140.44,63.07 v2(140.18,62.81)
  BOTTOM w0.102: v2(165.37,51.39) 165.08,51.39 164.42,52.04 164.03,52.04 162.25,53.82 160.22,53.82 v1(158.37,55.68) 154.64,55.68 149.05,61.26 141.73,61.26 v2(140.18,62.81)
PCH_XDP_PREQ_R_N: length 140.6
  TOP w0.089: 205.48,131.44 205.48,131.71 204.97,132.22 204.97,133.54 205.09,133.65 SB1.AL2
  TOP w0.102: 205.48,131.44 205.48,130.23 206.83,128.88 206.83,122.59 205,120.76 205,119.32 200.47,114.78 195.75,114.78 195.25,114.78 195.25,114.78 195.06,114.78 193.53,113.26 192.06,111.79 178.52,111.79 174.76,108.02 174.76,104.97 171.53,101.74 171.53,101.3 171.53,59.3 166.01,53.79 166.01,53.76 165.1,52.85 v2(165.1,52.07) ; v2(141.96,62.92) 141.96,63.5 141.52,63.94 R9901.1
  BOTTOM w0.102: v2(165.1,52.07) 164.72,52.07 164.52,52.27 164.12,52.27 162.34,54.05 161.14,54.05 158.42,56.77 v1(155.83,56.77) 153.95,56.77 149.12,61.59 142.7,61.59 141.96,62.33 v2(141.96,62.92)
PCI_CLK1: length 64.3
  TOP w0.102: v2(207.51,67.39) 208.01,67.88 R9508.2
  BOTTOM w0.102: SLOT4.32 226.78,36.21 226.62,36.37 226.16,36.37 224.71,34.92 223.06,34.92 222.01,35.97 221.13,35.97 219.88,37.21 218.82,37.21 217.75,36.14 213.84,36.14 213.35,36.63 213.35,43.18 210.99,45.54 207.57,45.54 205.58,47.53 205.58,59.76 206.59,60.76 206.59,63.95 206.25,64.29 204.93,64.29 204.83,64.39 204.83,64.67 204.99,64.83 206.27,64.83 206.38,64.93 206.38,65.24 206.27,65.34 205.71,65.34 205.61,65.44 205.61,66.24 206.08,66.71 206.36,66.71 206.68,66.4 206.91,66.4 207.01,66.5 207.01,66.78 206.65,67.14 206.65,67.32 207.68,68.35 208.18,68.35 208.71,67.82 208.71,67.23 208.26,66.78 208.12,66.78 v2(207.51,67.39)
PCI_R_CLKN: length 7.2
  TOP w0.102: U9501.9 195.98,59.49 195.89,59.4 195.52,59.4 194.67,59.4 194.67,59.4 194.42,59.4 194.12,59.7 ; v1(194.39,59.97) 194.12,59.7 ; 194.12,59.7 193.8,60.02 193.8,62.18 193.57,62.41 193.26,62.41 R9502.1
PCI_R_CLKP: length 7.2
  TOP w0.102: U9501.10 195.98,59.09 195.89,59.18 195.43,59.18 194.34,59.18 193.59,59.93 193.59,60.73 ; 193.59,60.73 193.59,62.09 193.48,62.19 193.19,62.19 R9503.1 ; 193.59,60.73 v1(193.22,60.73)
PCIAUX_GATE: length 3.4
  TOP w0.102: R2432.1 193.08,88.02 v1(193.21,88.15) 193.52,88.47 U2401.92
PCICLK0: length 3
  TOP w0.102: v1(208.47,66.07) 208.47,66.08 ; 208.47,66.08 208.44,66.08 208.28,66.24 R9508.1 ; 208.47,66.08 208.05,65.66 U9501.104
PCICLK_SEL: length 4.6
  TOP w0.102: R9509.1 199.14,67.36 v1(199.01,67.23) 199.01,66.8 198.45,66.24 198.45,65.73 199.01,65.18 199.02,65.18 199.25,64.95 U9501.126
PCIE_RCOMP_N: length 4.4
  TOP w0.152: 189.85,138.67 190.54,138.67 190.6,138.73 SB1.B12
  TOP w0.305: R1513.1 187.51,140.17 v1(188.24,139.45) 189.08,139.45 189.85,138.67
PCIE_RCOMP_P: length 4.2
  TOP w0.152: SB1.A13 190.31,138.93 189.99,139.24
  TOP w0.305: 189.99,139.24 188.62,140.61 188.37,140.61 188.26,140.72 v1(188.26,140.72) 187.92,141.06 R1513.2
PCIE_RX_CON_N5: length 7.5
  TOP w0.102: v1(145.82,45.58) 145.82,45.21 ; 145.82,45.21 146.23,45.21 146.41,45.4 146.62,45.4 C3109.1 ; 145.82,45.21 144.35,45.21 143.29,44.16 141.85,44.16 141.56,43.88 U3101.18
PCIE_RX_CON_N6: length 6.4
  TOP w0.102: C9503.1 194.1,51.56 194.35,51.56 195.11,52.31 195.11,53.7 ; U9501.20 196.19,55.09 196.09,55 195.71,55 195.11,54.39 195.11,53.7 ; v1(194.72,53.7) 195.11,53.7
PCIE_RX_CON_P5: length 7.4
  TOP w0.102: 144.86,45 144.44,45 143.38,43.94 141.94,43.94 141.78,43.79 141.78,43.6 141.96,43.42 U3101.17 ; 144.86,45 v1(144.86,44.63) ; 144.86,45 146.32,45 146.5,45.18 146.7,45.18 C3110.1
PCIE_RX_CON_P6: length 6.3
  TOP w0.102: 194.72,51.61 194.44,51.34 194.1,51.34 C9504.1 ; 194.72,51.61 v1(194.98,51.35) ; 194.72,51.61 195.33,52.22 195.33,54.3 195.8,54.78 196.04,54.78 196.13,54.69 U9501.21
PCIE_RX_PCH_N5: length 130.2
  TOP w0.102: 158.83,121.03 159.82,122.02 159.82,124.81 162.05,127.04 162.05,131.19 162.34,131.48 162.67,131.48 v2(163.03,131.84) ; 158.83,121.03 v1(158.55,121.31) ; 158.83,121.03 157.52,119.72 157.52,114.29 155.93,112.7 155.93,109.4 154.37,107.84 154.37,73.72 150.16,69.52 150.16,50.01 148.88,48.73 148.88,45.4 148.72,45.24 148.42,45.24 C3109.2 ; v2(193.09,143.05) 192.8,142.77 SB1.F20
  BOTTOM w0.102: v2(193.09,143.05) 193.34,142.8 193.34,142.65 193.22,142.52 188.82,142.52 187.08,140.78 177.53,140.78 169.06,132.31 167.54,132.31 166.67,131.44 163.43,131.44 v2(163.03,131.84)
PCIE_RX_PCH_N6: length 120.4
  TOP w0.102: v2(194.97,143.69) 194.72,143.43 194.72,143.23 194.96,142.99 SB1.K21 ; v2(190.52,103.1) 190,103.62 189.75,103.62 187.96,101.83 187.96,87.52 187.53,87.09 187.53,72.82 188.3,72.05 188.3,53.4 190.18,51.53 192.51,51.53 C9503.2
  BOTTOM w0.102: 190.94,108.67 188.96,110.66 188.96,117.91 192.94,121.88 201.31,121.88 204.57,125.15 204.57,131.06 203.3,132.33 203.3,138.63 202.94,138.99 202.94,140.62 201.76,141.8 198.48,141.8 197.66,142.62 195.11,142.62 194.71,143.03 194.71,143.42 v2(194.97,143.69) ; 190.94,108.67 v1(191.21,108.94) ; 190.94,108.67 191.36,108.25 191.36,103.65 191.06,103.35 190.77,103.35 v2(190.52,103.1)
PCIE_RX_PCH_N7: length 141.7
  TOP w0.102: v2(194.85,145) 195.11,144.75 SB1.L24 ; v2(164.41,133.48) 164.72,133.17 165,133.17 165.24,132.93 165.24,117.77 161.93,114.45 161.93,112.46 160.34,110.87 160.34,107.58 159.28,106.52 159.28,102.82 159.28,102.62 159.28,70.86 154.57,66.15 154.57,42 158.33,38.24 159.5,38.24 159.94,37.8 160.11,37.8 SLOT1.A17
  BOTTOM w0.102: 167.87,133.15 164.74,133.15 v2(164.41,133.48) ; 167.87,133.15 v1(167.87,133.52) ; 167.87,133.15 168.91,133.15 177.24,141.48 186.79,141.48 188.93,143.61 189.51,143.61 191.6,145.71 194.4,145.71 194.67,145.44 194.67,145.19 v2(194.85,145)
PCIE_RX_PCH_N8: length 68.5
  TOP w0.102: NGFF1.43 200.8,198.25 200.66,198.11 198.41,198.11 198.17,198.35 197.81,198.35 v2(197.5,198.66) ; v2(192.78,143.76) 192.78,144.38 SB1.F24
  BOTTOM w0.102: 197.21,158.14 198.02,157.33 198.02,156.21 199.44,154.79 199.44,152.27 199.44,152.27 199.44,149.98 197.26,147.81 197.26,145.38 196.39,144.5 193.93,144.5 193.78,144.65 193.28,144.65 193.03,144.4 193.03,144.01 v2(192.78,143.76) ; 197.21,158.14 v1(196.93,157.86) ; 197.21,158.14 196.81,158.53 196.81,163.51 195.62,164.71 195.62,165.57 195.81,165.76 195.81,178.46 195.35,178.92 195.35,193.57 195.97,194.19 195.97,197.98 196.38,198.39 197.24,198.39 197.5,198.65 v2(197.5,198.66)
PCIE_RX_PCH_N9: length 199.1
  TOP w0.102: SLOT3.A17 200.81,37.82 200.63,37.65 200.63,36.6 200.01,35.98 189.8,35.98 187.86,34.04 184.78,34.04 183.9,34.92 183.24,34.92 180.32,32 175.62,32 174.26,33.36 173.72,33.36 172.47,34.61 172.47,39.01 170.59,40.89 165.31,40.89 162.97,43.24 160.74,43.24 157.61,46.38 157.61,65.56 161.35,69.3 161.35,103.69 161.35,103.78 161.35,105.93 162.22,106.8 162.22,110.09 163.8,111.68 163.8,113.64 167.12,116.95 167.12,117.22 167.12,131.82 167.12,138.29 165.09,140.32 165.09,145.3 164.08,146.32 v2(162.45,146.32) ; v2(193.57,150.93) SB1.G36
  BOTTOM w0.102: 178.92,153.07 186.32,153.07 188.91,150.48 193.1,150.48 193.55,150.93 v2(193.57,150.93) ; 178.92,153.07 176.77,153.07 170.24,146.55 162.68,146.55 v2(162.45,146.32) ; 178.92,153.07 v1(178.92,152.73)
PCIE_RX_PCH_N21: length 67.4
  TOP w0.102: v2(150.28,147.28) 150.28,145.53 148.09,143.34 148.09,141.09 145.75,138.74 145.75,136.69 145.61,136.55 NGFF2.41 ; v2(196.75,153.9) 197.6,153.9 SB1.T43
  BOTTOM w0.102: 169.44,155.28 170.02,155.87 187.29,155.87 189.48,153.67 194.77,153.67 195.11,153.33 196.18,153.33 v2(196.75,153.9) ; 169.44,155.28 165.4,151.24 156.25,151.24 153.79,148.79 153.79,148.79 153.4,148.39 153.4,148.39 151.37,146.37 150.94,146.37 150.63,146.68 150.63,146.91 150.62,146.92 150.62,146.94 150.29,147.28 v2(150.28,147.28) ; 169.44,155.28 v1(169.7,155.02)
PCIE_RX_PCH_N22: length 73.5
  TOP w0.102: SB1.U40 198.34,152.29 197.62,152.29 v2(197.61,152.27) ; v2(147.13,142.78) 146.86,143.05 146.86,143.85 145.63,145.07 143.8,145.07 142.75,144.02 142.75,136.69 142.61,136.55 NGFF2.29
  BOTTOM w0.102: 148.18,143.81 150.85,143.81 156.67,149.63 167.41,149.63 170.83,153.05 173.75,153.05 175.17,154.47 186.91,154.47 189.3,152.08 196.62,152.08 197.01,152.46 197.43,152.46 v2(197.61,152.27) ; 148.18,143.81 v1(148.18,143.43) ; 148.18,143.81 146.91,143.81 146.8,143.71 146.8,143.1 v2(147.13,142.78)
PCIE_RX_PCH_N23: length 77.2
  TOP w0.102: SB1.W43 199.17,153.8 v2(198.42,153.8) ; NGFF2.17 139.61,136.55 139.75,136.69 139.75,143.28 143.45,146.98 148.15,146.98 148.68,146.44 148.68,145.46 v2(148.98,145.16)
  BOTTOM w0.102: 167.88,151.83 171.22,155.17 187.15,155.17 189.57,152.74 196.52,152.74 197.77,154 198.22,154 v2(198.42,153.8) ; 167.88,151.83 v1(168.15,151.56) ; 167.88,151.83 166.4,150.34 156.39,150.34 151.72,145.67 150.6,145.67 150.43,145.83 148.83,145.83 148.67,145.68 148.67,145.47 v2(148.98,145.16)
PCIE_RX_PCH_N24: length 83.2
  TOP w0.102: SB1.Y40 199.14,152.18 v2(199.01,152.04) ; NGFF2.5 136.61,136.55 136.75,136.69 136.75,136.98 136.94,137.17 136.94,142.51 144.64,150.2 153.02,150.2 154.45,148.78 154.45,145.49 v2(154.77,145.16)
  BOTTOM w0.102: v2(154.77,145.16) 154.45,145.49 154.45,146.04 157.29,148.88 167.98,148.88 170.54,151.43 ; 170.54,151.43 171.16,152.06 173.88,152.06 175.59,153.77 186.62,153.77 188.76,151.63 197.9,151.63 198.54,152.26 198.79,152.26 v2(199.01,152.04) ; 170.54,151.43 v1(170.79,151.18)
PCIE_RX_PCH_P5: length 130.3
  TOP w0.102: v2(193.81,143.06) 193.54,142.79 SB1.G20 ; 162.27,127.66 162.27,126.95 160.03,124.72 160.03,121.93 157.73,119.63 157.73,114.2 156.15,112.61 156.15,109.31 154.58,107.75 154.58,73.63 150.38,69.43 150.38,49.92 149.1,48.64 149.1,45.31 148.81,45.03 148.47,45.03 C3110.2 ; 162.27,127.66 v1(162.64,127.66) ; 162.27,127.66 162.27,131.1 162.43,131.27 162.73,131.27 v2(163.02,130.98)
  BOTTOM w0.102: v2(163.02,130.98) 163.27,131.23 166.76,131.23 167.63,132.09 169.15,132.09 177.62,140.56 187.17,140.56 188.91,142.3 193.31,142.3 193.56,142.56 193.56,142.81 v2(193.81,143.06)
PCIE_RX_PCH_P6: length 120.4
  TOP w0.102: SB1.J21 194.28,143.68 v2(194.31,143.71) ; C9504.2 192.56,51.31 190.09,51.31 188.99,52.41 188.09,53.31 188.09,71.96 187.31,72.73 187.31,87.18 187.74,87.61 187.74,101.92 189.66,103.83 v2(190.5,103.83)
  BOTTOM w0.102: v2(194.31,143.71) 194.49,143.53 194.49,142.94 195.02,142.41 197.57,142.41 198.39,141.58 201.67,141.58 202.73,140.53 202.73,138.9 203.09,138.54 203.09,132.24 204.36,130.97 204.36,125.24 201.22,122.1 192.85,122.1 188.75,118 188.75,110.57 191.15,108.17 191.15,105.66 ; 191.15,105.66 191.15,103.74 190.97,103.56 190.77,103.56 v2(190.5,103.83) ; 191.15,105.66 v1(190.78,105.66)
PCIE_RX_PCH_P7: length 141.6
  TOP w0.102: SB1.J24 194.35,144.81 v2(194.22,144.94) ; v2(164.41,132.69) 164.68,132.96 164.91,132.96 165.02,132.84 165.02,117.86 161.71,114.54 161.71,112.55 160.12,110.96 160.12,107.67 159.07,106.61 159.07,102.72 159.07,102.62 159.07,70.95 154.36,66.24 154.36,41.91 158.24,38.02 159.41,38.02 159.82,37.62 159.82,37.39 159.55,37.12 SLOT1.A16
  BOTTOM w0.102: v2(164.41,132.69) 164.65,132.93 166.32,132.93 ; v1(166.32,132.56) 166.32,132.93 ; 166.32,132.93 169,132.93 177.33,141.26 186.88,141.26 189.02,143.4 189.6,143.4 191.69,145.49 194.31,145.49 194.45,145.35 194.45,145.17 v2(194.22,144.94)
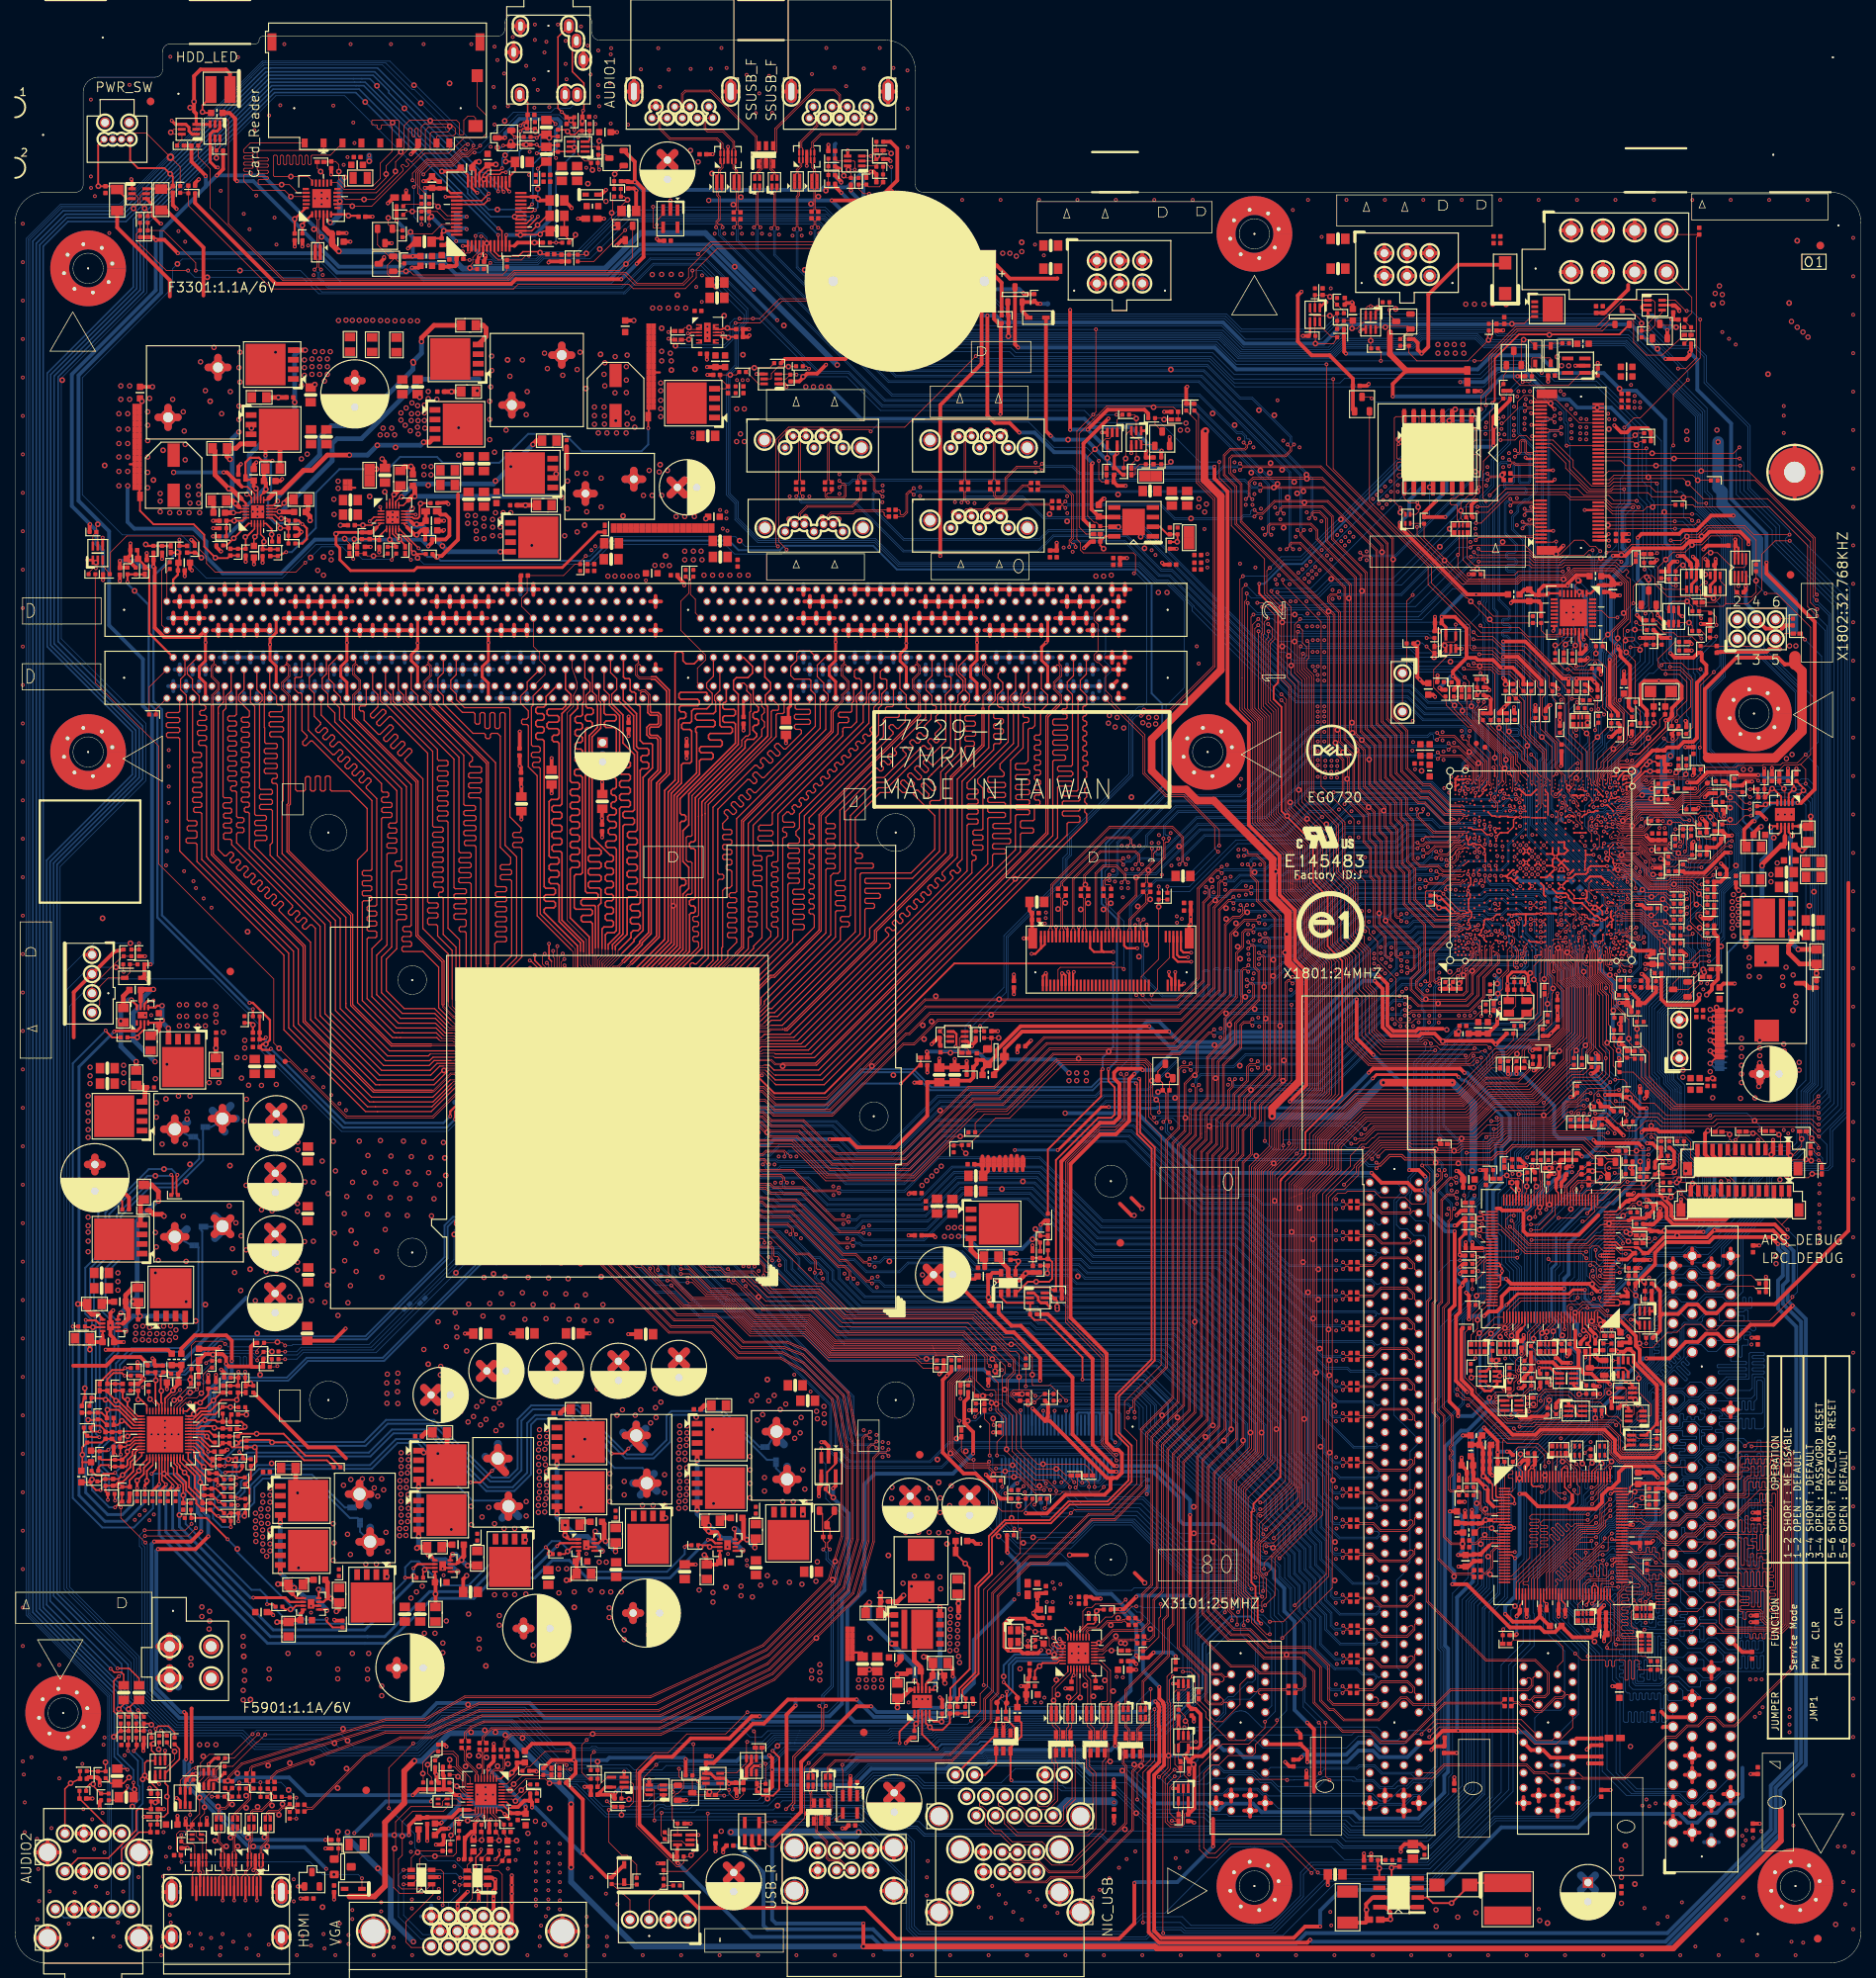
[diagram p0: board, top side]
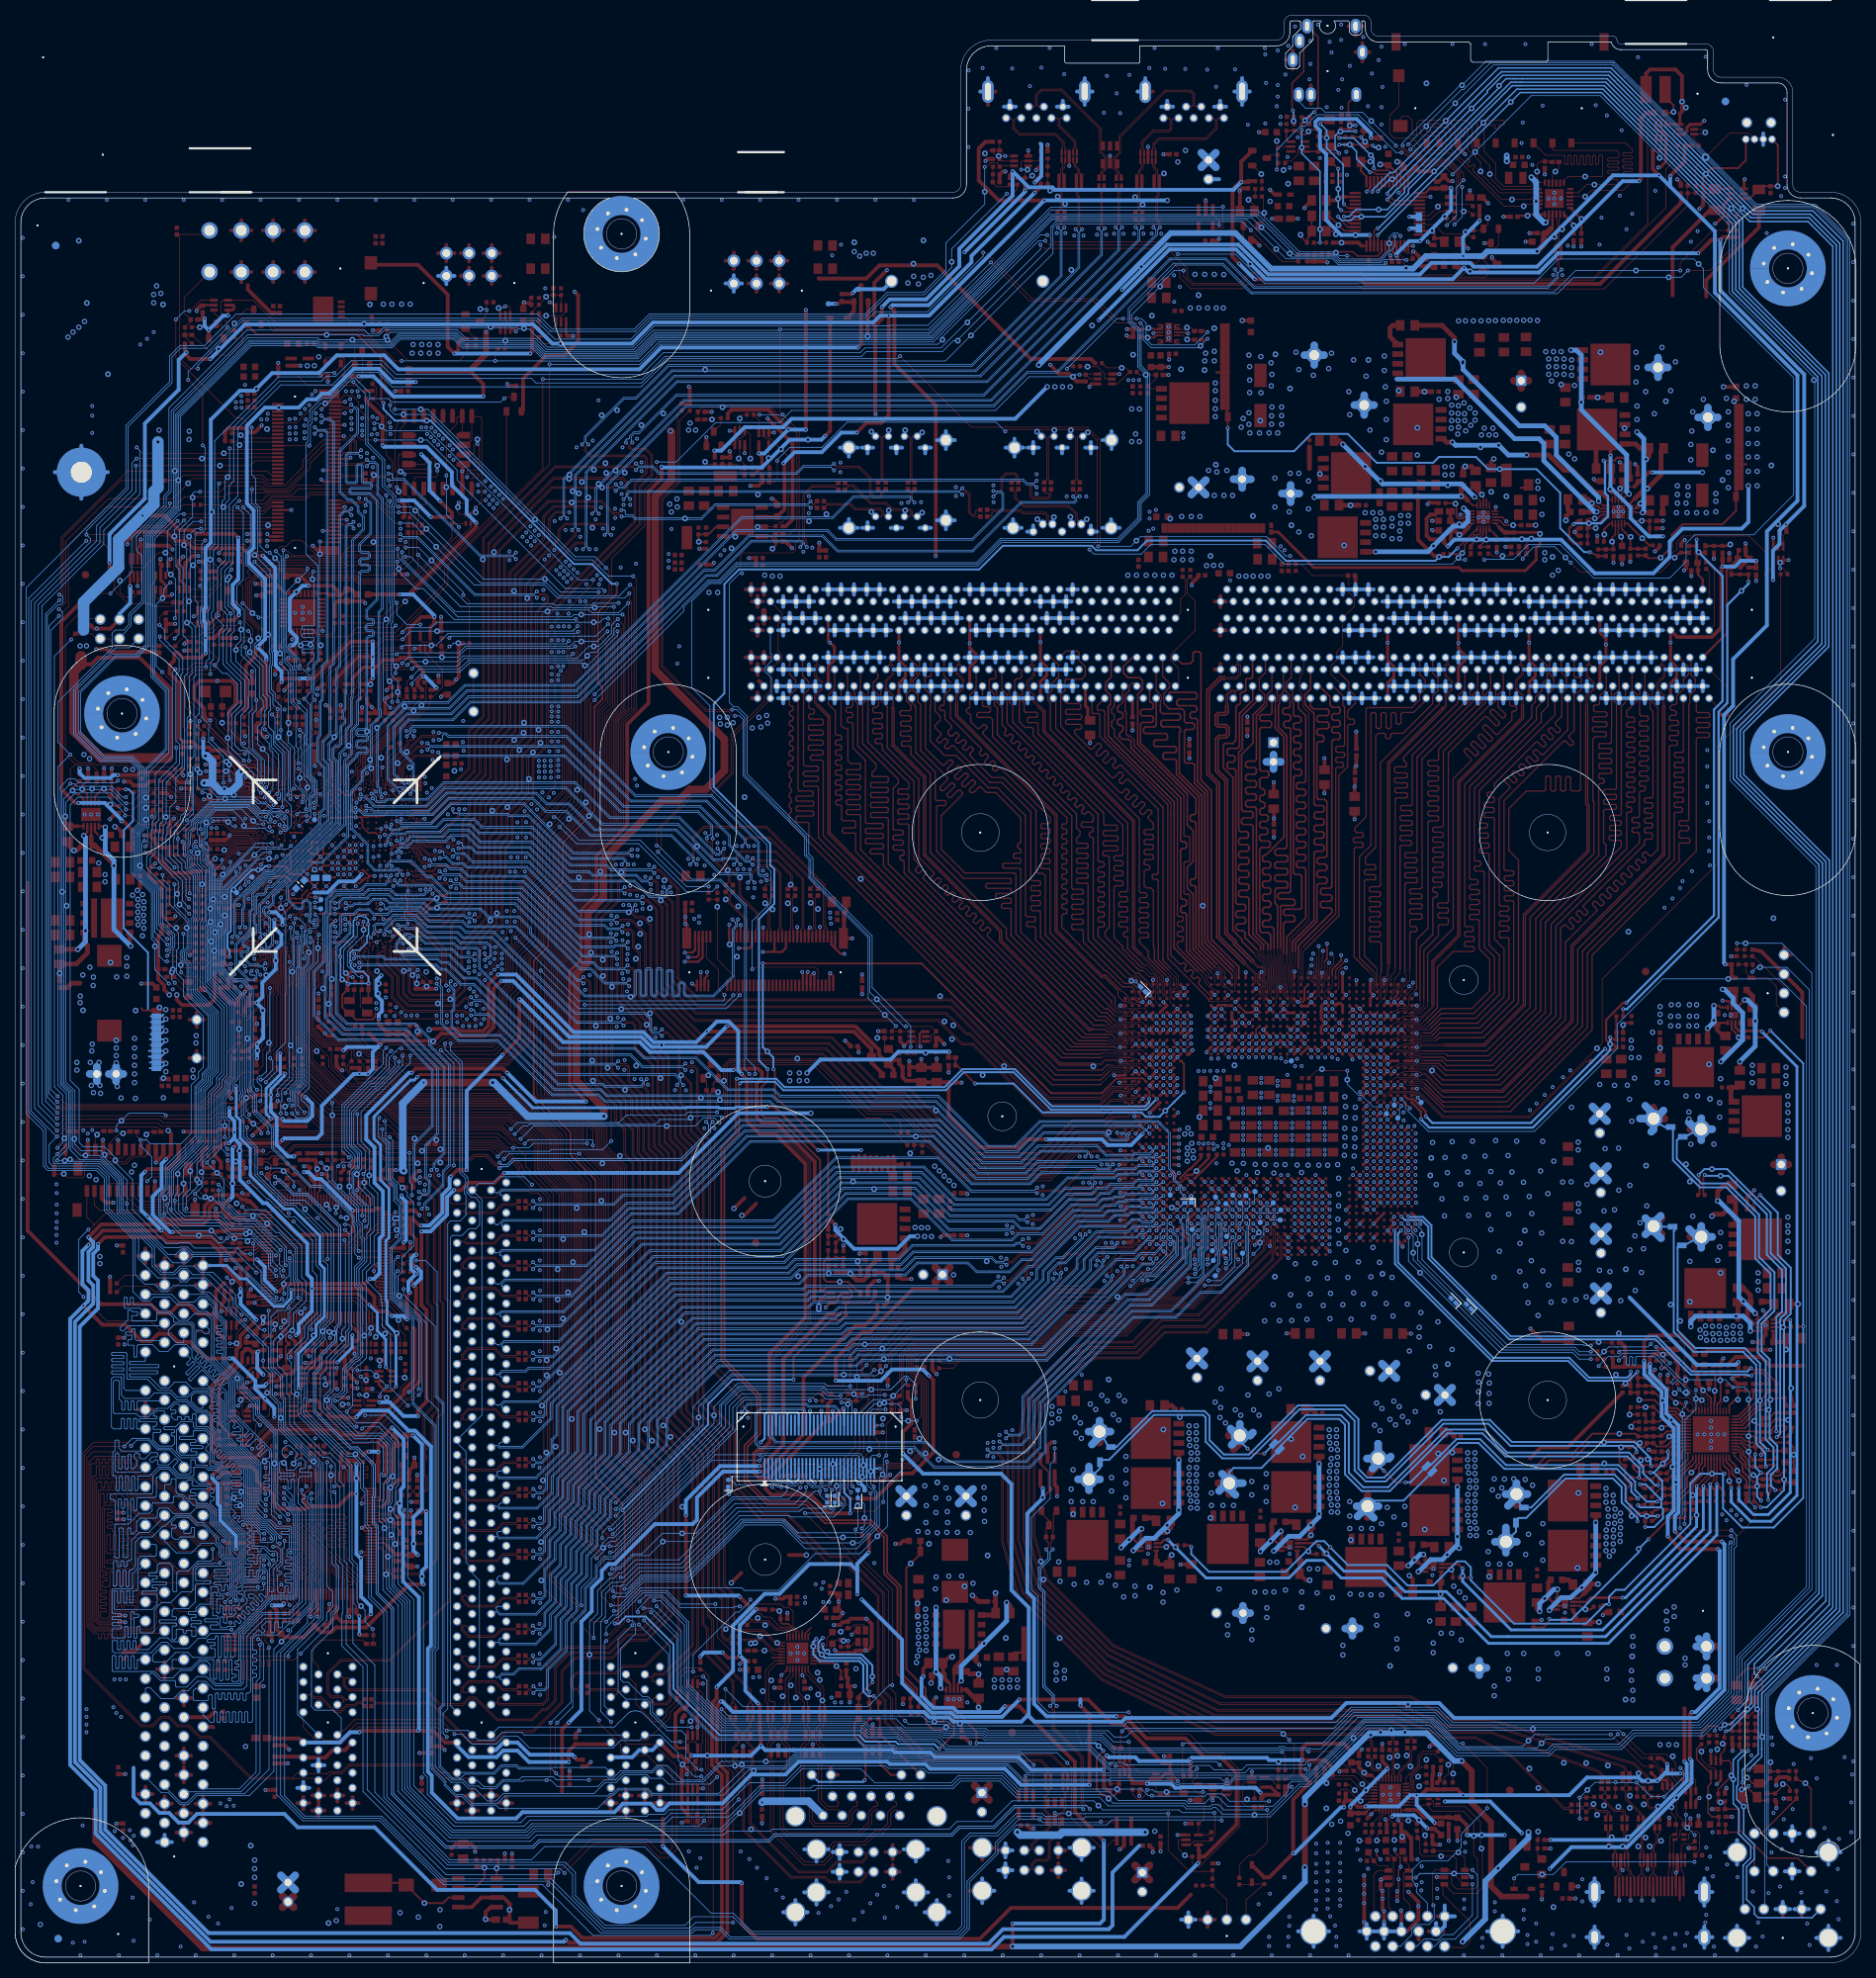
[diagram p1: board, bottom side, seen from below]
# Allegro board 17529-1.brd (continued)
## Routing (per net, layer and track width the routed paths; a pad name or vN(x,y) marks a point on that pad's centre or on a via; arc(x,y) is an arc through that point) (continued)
PCIE_RX_PCH_P8: length 68.4
  TOP w0.102: v2(197.51,197.79) 197.51,197.8 197.85,198.13 198.08,198.13 198.32,197.89 200.66,197.89 200.8,197.75 NGFF1.41 ; v2(193.54,143.76) 193.32,143.99 193.32,144.15 SB1.G24
  BOTTOM w0.102: v2(193.54,143.76) 193.24,144.06 193.24,144.31 193.37,144.44 193.69,144.44 193.84,144.28 196.47,144.28 197.48,145.29 197.48,147.72 199.65,149.89 199.65,152.36 199.65,152.36 199.65,154.88 198.23,156.3 198.23,157.42 197.03,158.62 197.03,163.6 195.83,164.8 195.83,165.48 196.02,165.67 196.02,178.55 195.57,179.01 195.57,193.48 196.19,194.1 196.19,196.62 ; v2(197.51,197.79) 197.51,197.8 197.14,198.17 196.47,198.17 196.19,197.89 196.19,196.62 ; 196.19,196.62 v1(196.57,196.62)
PCIE_RX_PCH_P9: length 199.3
  TOP w0.102: SB1.F36 192.9,151.12 v2(192.94,151.16) ; SLOT3.A16 199.95,37.67 200.23,37.67 200.42,37.48 200.42,36.69 199.92,36.2 189.71,36.2 187.77,34.25 184.87,34.25 183.99,35.14 183.15,35.14 180.23,32.22 175.71,32.22 174.35,33.57 173.81,33.57 172.68,34.7 172.68,39.1 170.68,41.11 165.4,41.11 163.05,43.46 160.83,43.46 157.82,46.47 157.82,65.47 161.57,69.22 161.57,103.69 161.57,103.78 161.57,105.84 162.43,106.71 162.43,110.01 164.02,111.59 164.02,113.55 167.34,116.86 167.34,117.22 167.33,131.82 167.33,138.38 165.3,140.41 165.3,145.39 164.17,146.53 163.07,146.53 162.97,146.63 162.97,146.99 162.82,147.14 v2(162.46,147.14)
  BOTTOM w0.102: 173.61,150.22 170.15,146.76 162.83,146.76 v2(162.46,147.14) ; 173.61,150.22 176.68,153.29 186.41,153.29 189,150.7 193.01,150.7 193.12,150.81 193.12,150.97 v2(192.94,151.16) ; 173.61,150.22 v1(173.34,150.48)
PCIE_RX_PCH_P21: length 67.3
  TOP w0.102: SB1.R44 197.1,154.3 v2(196.88,154.52) ; v2(151.15,147.27) 151.15,147.27 150.5,146.62 150.5,145.44 148.31,143.25 148.31,141 145.97,138.65 145.97,136.69 146.11,136.55 NGFF2.43
  BOTTOM w0.102: v2(151.15,147.27) 150.84,146.97 150.84,146.77 151.03,146.58 151.28,146.58 153.31,148.61 153.31,148.61 153.58,148.88 153.58,148.88 156.16,151.46 165.31,151.46 169.93,156.08 176.07,156.08 ; v1(176.07,156.46) 176.07,156.08 ; 176.07,156.08 187.38,156.08 189.57,153.89 194.86,153.89 195.2,153.54 196.09,153.54 196.29,153.74 196.29,154.13 196.68,154.52 v2(196.88,154.52)
PCIE_RX_PCH_P22: length 73.6
  TOP w0.102: SB1.U41 198.29,152.83 198.29,152.62 198.17,152.5 198.01,152.5 v2(197.59,152.92) ; v2(146.27,142.78) 146.64,143.15 146.64,143.76 145.54,144.86 143.89,144.86 142.97,143.93 142.97,136.69 143.11,136.55 NGFF2.31
  BOTTOM w0.102: v2(146.27,142.78) 146.59,143.1 146.59,143.8 146.82,144.03 149.81,144.03 ; 149.81,144.03 v1(149.81,144.4) ; 149.81,144.03 150.76,144.03 156.58,149.85 167.32,149.85 170.74,153.26 173.66,153.26 175.08,154.69 186.99,154.69 189.39,152.29 196.53,152.29 196.92,152.67 197.34,152.67 v2(197.59,152.92)
PCIE_RX_PCH_P23: length 77.1
  TOP w0.102: NGFF2.19 140.11,136.55 139.97,136.69 139.97,143.19 143.54,146.76 148.06,146.76 148.46,146.35 148.46,145.5 v2(148.12,145.16) ; v2(198.34,154.43) 198.4,154.43 198.82,154.01 199,154.01 199.11,154.13 SB1.W44
  BOTTOM w0.102: 168.83,153.09 171.13,155.38 187.24,155.38 189.66,152.96 196.43,152.96 197.68,154.22 198.13,154.22 v2(198.34,154.43) ; 168.83,153.09 166.31,150.56 156.3,150.56 151.63,145.88 150.69,145.88 150.52,146.05 148.74,146.05 148.46,145.77 148.46,145.49 v2(148.12,145.16) ; 168.83,153.09 v1(168.55,153.37)
PCIE_RX_PCH_P24: length 83.3
  TOP w0.102: 154.23,147.55 154.23,148.69 152.93,149.99 144.73,149.99 137.16,142.42 137.16,137.08 136.97,136.89 136.97,136.69 137.11,136.55 NGFF2.7 ; 154.23,147.55 154.23,145.49 v2(153.91,145.16) ; 154.23,147.55 v1(153.86,147.55) ; SB1.Y41 199.59,152.82 199.59,152.53 199.46,152.4 199.29,152.4 v2(199,152.68)
  BOTTOM w0.102: v2(153.91,145.16) 154.23,145.49 154.23,146.13 157.2,149.1 167.89,149.1 171.07,152.27 173.79,152.27 175.5,153.99 186.7,153.99 188.85,151.84 197.82,151.84 198.45,152.48 198.8,152.48 v2(199,152.68)
PCIE_SLOT1_PRSNT_N: length 209.1
  TOP w0.102: SB1.BB26 210.29,145.86 v2(210.29,146.76) ; v2(194.49,109.12) 194.69,109.32 195.91,109.32 196.84,110.25 203.68,110.25 205.4,111.97 205.92,111.97 206.17,112.22 206.17,112.4 206.55,112.78 207.47,112.78 208.71,114.02 208.71,114.71 209.27,115.27 211.51,115.27 211.61,115.37 v2(212.01,115.37) ; R9401.1 156.46,37.85 156.46,38.02 155.5,38.99 153.61,38.99 R1506.2 153.23,38.8 152.27,37.85 152.27,34.39 152.4,34.26 152.4,25.75 v2(151.21,24.56)
  BOTTOM w0.102: v2(194.49,109.12) 194.09,108.72 194.09,103.74 v1(192.8,102.45) 192.15,101.8 192.15,101.32 191.33,100.49 191.33,94.75 192.84,93.24 192.84,91.31 193.38,90.77 193.38,88.28 189.64,84.53 189.64,74.65 188.06,73.07 188.06,41.53 188.47,41.12 188.47,25.98 186.35,23.86 184.89,23.86 184.09,23.06 183.24,23.06 181.57,21.4 180.43,21.4 179.46,22.36 167.47,22.36 165.99,23.84 164.56,23.84 163.98,24.42 163.56,24.84 160.46,24.84 160,24.38 158.37,24.38 157.61,23.62 152.15,23.62 v2(151.21,24.56) ; v2(212.01,115.37) 212.52,115.87 212.52,128.7 213.87,130.05 214.99,130.05 216.41,131.47 216.41,136.14 216.06,136.5 216.06,141.88 216.01,141.93 211.18,146.76 v2(210.29,146.76)
PCIE_SLOT1_PRSNT_N_R: length 12.7
  TOP w0.102: SLOT1.B17 161.93,36.79 161.93,34.16 159.64,31.88 158.66,31.88 157.89,32.65 157.89,33.35 156.46,34.77 156.46,34.92
PCIE_SLOT2_PRSNT_N: length 69.7
  TOP w0.102: v2(210.06,147.96) 209.96,147.96 209.86,147.85 SB1.BA30 ; v2(211.46,109.6) 210.31,110.74 R1806.2 208.94,109.94 196.96,109.94 196.04,109.02 195.17,109.02 194.67,108.51 191.03,108.51 190.72,108.2 R9301.1
  BOTTOM w0.102: v2(211.46,109.6) 211.46,109.86 v1(212.5,110.9) 213.21,111.62 213.34,111.62 213.79,112.06 213.79,113.85 214.02,114.08 214.02,114.54 213.87,114.69 213.87,115.17 213.97,115.27 213.97,127.35 214.31,127.69 214.31,127.82 217.42,130.94 217.42,136.57 217.12,136.87 217.12,141.34 217.12,141.8 217.12,143.04 212.2,147.96 v2(210.06,147.96)
PCIE_SLOT2_PRSNT_N_R: length 92.2
  TOP w0.102: v2(175.67,102.84) 177.3,104.48 177.3,105.23 180.44,108.37 184.42,108.37 184.58,108.2 R9301.2
  BOTTOM w0.102: SLOT2.B17 182.63,39.07 182.63,50.55 183.58,51.5 SLOT2.B31 184.4,52.94 184.4,67.56 185.58,68.74 SLOT2.B48 184.3,70.4 184.3,70.42 183.33,71.4 183.28,71.4 182.3,72.38 182.3,100.84 SLOT2.B81 182.66,103.04 180.81,103.04 179.96,103.89 176.71,103.89 v2(175.67,102.84)
PCIE_SLOT4_PRSNT_N: length 120.9
  TOP w0.102: SB1.BF29 212.74,147.09 214.57,147.09 214.62,147.04 214.63,147.04 214.88,146.79 214.88,146.17 v2(215.55,145.5) ; v2(196.72,44.09) 196.72,44.07 196.66,44.01 R1505.2 R9402.1
  BOTTOM w0.102: v2(215.55,145.5) 215.55,144.99 217.35,143.19 217.35,136.93 217.63,136.65 217.63,130.63 214.61,127.62 214.61,127.56 214.27,127.22 214.27,115.15 214.17,115.05 214.17,114.82 214.33,114.67 214.33,113.95 214.1,113.72 214.1,111.94 214.02,111.86 214.02,111.75 213.8,111.54 213.8,109.18 212.29,107.66 212.29,104.08 210.11,101.9 210.09,101.9 208.31,100.12 207.03,100.12 203.26,96.36 203.26,92.84 202.67,92.25 202.67,85.23 203.73,84.17 203.73,82.64 206.11,80.27 206.11,75.76 206.22,75.65 206.22,72.54 199.47,65.79 199.47,53.33 198.78,52.65 198.78,47.65 v1(198.27,47.14) 197.74,46.61 197.74,45.11 v2(196.72,44.09)
PCIE_SLOT4_PRSNT_N_R: length 11.6
  TOP w0.102: SLOT3.B17 203.9,39.18 204.6,39.88 204.6,41.78 203.71,42.67 198.06,42.67 R9402.2
PCIE_TX_CON_N5: length 6.8
  TOP w0.102: 145.52,42.8 145.11,42.8 143.76,41.45 143.26,41.45 143.16,41.54 U3101.14 ; 145.52,42.8 v1(145.52,43.18) ; 145.52,42.8 147.45,42.8 148.01,42.8 C3115.1
PCIE_TX_CON_N6: length 5.5
  TOP w0.102: 193.48,55.61 193.85,55.98 195.89,55.98 195.98,55.89 U9501.18 ; 193.48,55.61 193.17,55.3 192.6,55.3 C9501.1 ; 193.48,55.61 v1(193.75,55.35)
PCIE_TX_CON_N7: length 5.5
  TOP w0.102: C9402.2 168,36.23 164.52,36.23 164.1,35.82 163.86,35.82 SLOT1.B15
PCIE_TX_CON_N8: length 4.2
  TOP w0.102: C6305.1 197.92,196.61 200.66,196.61 200.8,196.75 NGFF1.37
PCIE_TX_CON_N9: length 9.8
  TOP w0.102: C9407.2 198.14,34.49 198.79,34.49 199.14,34.14 200.18,34.14 200.98,33.34 201.72,33.34 203.53,35.15 204.47,35.15 204.85,35.54 204.85,35.71 204.7,35.86 SLOT3.B15
PCIE_TX_CON_N21: length 7.4
  TOP w0.102: v1(148.41,139.62) 148.68,139.36 ; 148.68,139.36 147.25,137.93 147.25,136.69 147.11,136.55 NGFF2.47 ; 148.68,139.36 149.45,140.13 149.45,141.21 C6211.2
PCIE_TX_CON_N22: length 6
  TOP w0.102: v1(143.87,139.22) 144.25,139.22 ; 144.25,139.22 144.25,140.65 C6209.2 ; 144.25,139.22 144.25,136.69 144.11,136.55 NGFF2.35
PCIE_TX_CON_N23: length 6
  TOP w0.102: v1(140.87,139.22) 141.25,139.22 ; 141.25,139.22 141.25,140.67 C6207.2 ; 141.25,139.22 141.25,136.69 141.11,136.55 NGFF2.23
PCIE_TX_CON_N24: length 6
  TOP w0.102: C6202.2 138.25,140.68 138.25,139.27 ; v1(137.87,139.27) 138.25,139.27 ; 138.25,139.27 138.25,136.69 138.11,136.55 NGFF2.11
PCIE_TX_CON_P5: length 6.8
  TOP w0.102: C3116.1 148.01,42.58 147.54,42.58 147.54,42.58 146.74,42.58 ; 146.74,42.58 145.2,42.58 143.85,41.24 143.22,41.24 143.13,41.14 U3101.13 ; 146.74,42.58 v1(146.74,42.21)
PCIE_TX_CON_P6: length 5.5
  TOP w0.102: U9501.17 195.98,56.29 195.89,56.2 194.28,56.2 ; v1(194.28,56.57) 194.28,56.2 ; 194.28,56.2 193.76,56.2 193.08,55.52 192.55,55.52 C9502.1
PCIE_TX_CON_P7: length 5.4
  TOP w0.102: SLOT1.B14 164.5,35.5 164.38,35.62 164.38,35.79 164.61,36.02 168.01,36.02 C9401.2
PCIE_TX_CON_P8: length 4.3
  TOP w0.102: NGFF1.35 200.8,196.25 200.66,196.39 198.11,196.39 C6306.1
PCIE_TX_CON_P9: length 9.7
  TOP w0.102: C9406.2 198.14,34.27 198.7,34.27 199.05,33.92 200.09,33.92 200.89,33.12 201.81,33.12 203.62,34.94 204.56,34.94 205.06,35.44 205.26,35.44 SLOT3.B14
PCIE_TX_CON_P21: length 7.4
  TOP w0.102: C6212.2 149.67,141.15 149.67,140.54 ; v1(150.06,140.54) 149.67,140.54 ; 149.67,140.54 149.67,140.04 147.47,137.84 147.47,136.69 147.61,136.55 NGFF2.49
PCIE_TX_CON_P22: length 6
  TOP w0.102: 144.47,140.03 144.47,136.69 144.61,136.55 NGFF2.37 ; 144.47,140.03 v1(144.86,140.03) ; 144.47,140.03 144.47,140.62 C6210.2
PCIE_TX_CON_P23: length 6
  TOP w0.102: 141.47,140.03 141.47,136.69 141.61,136.55 NGFF2.25 ; 141.47,140.03 141.47,140.64 C6208.2 ; 141.47,140.03 v1(141.86,140.03)
PCIE_TX_CON_P24: length 6
  TOP w0.102: NGFF2.13 138.61,136.55 138.47,136.69 138.47,140.08 ; v1(138.84,140.08) 138.47,140.08 ; 138.47,140.08 138.47,140.64 C6204.2
PCIE_TX_PCH_N5: length 131.9
  TOP w0.102: C3115.2 149.63,42.75 149.9,42.75 150.43,43.28 150.43,44.12 ; 150.43,44.12 150.43,48.02 151.56,49.15 151.56,68.5 155.85,72.8 155.85,107.35 157.33,108.82 157.33,109.8 157.33,112.12 158.92,113.71 158.92,119.14 161.21,121.44 161.21,124.23 164.31,127.33 164.31,130.96 163.71,131.56 163.71,134.26 163.57,134.39 163.35,134.39 v2(163.01,134.05) ; 150.43,44.12 v1(150.06,44.12) ; 190.88,143.13 190.85,143.09 189.4,143.09 188.86,142.56 186.8,142.56 v2(186.44,142.19)
  BOTTOM w0.102: v2(186.44,142.19) 186.11,142.51 185.31,142.51 184.76,141.96 176.99,141.96 169.19,134.16 164.82,134.16 164.63,134.35 163.31,134.35 v2(163.01,134.05)
PCIE_TX_PCH_N6: length 120
  TOP w0.102: SB1.D21 191.87,143.18 191.56,142.86 191.42,142.86 191.09,142.53 190,142.53 189.73,142.26 v2(189.73,141.86) ; v2(190.61,101.9) 190.22,101.61 189.24,101.61 188.48,100.85 188.48,87.36 188.01,86.89 188.01,73.02 188.79,72.25 188.79,56.32 189.83,55.28 191.01,55.28 C9501.2
  BOTTOM w0.102: v1(190.22,107.31) 189.84,107.31 ; 189.84,107.31 189.84,103.76 189.36,103.28 189.36,101.98 189.71,101.63 190.22,101.63 v2(190.61,101.9) ; 189.84,107.31 189.84,108.05 188.26,109.63 188.26,118.2 192.66,122.59 200.77,122.59 203.11,124.93 203.11,130.44 202.84,130.71 202.84,138.28 202.43,138.68 202.43,140.34 201.46,141.31 197.95,141.31 197.32,141.95 194.34,141.95 193.64,141.25 190,141.25 189.73,141.51 v2(189.73,141.86)
PCIE_TX_PCH_N7: length 147.5
  TOP w0.102: v2(187.9,143.35) 188.27,143.73 188.58,143.73 188.72,143.59 190.8,143.59 190.85,143.55 191.25,143.55 SB1.C23 ; v2(164.51,135.08) 164.82,135.38 165.51,135.38 165.72,135.17 165.72,117.57 162.41,114.25 162.41,112.66 162.41,112.26 160.82,110.67 160.82,107.38 159.83,106.38 159.83,103.2 159.83,102.96 159.83,102.81 159.83,70.55 156.18,66.9 156.18,60.27 ; 156.18,60.27 v1(155.8,60.27) ; 156.18,60.27 156.18,43.59 160.68,39.09 163.58,39.09 164.49,38.18 169.73,38.18 170.38,37.52 170.38,36.58 170.04,36.24 169.56,36.24 C9402.1
  BOTTOM w0.102: v2(187.9,143.35) 187.55,143.7 185.3,143.7 184.4,142.8 176.84,142.8 169.39,135.36 164.8,135.36 164.51,135.07 v2(164.51,135.08)
PCIE_TX_PCH_N8: length 75.3
  TOP w0.102: C6305.2 196.45,196.51 194.88,196.51 194.64,196.75 v2(194.64,196.81) ; v2(177.81,186.38) 178.13,186.06 179.05,186.06 179.41,185.7 179.41,163.52 181.25,161.67 181.25,156.7 184.06,153.89 184.06,151.85 184.91,151 184.91,145.87 185.74,145.05 188.15,145.05 188.81,144.39 191.02,144.39 SB1.B24
  BOTTOM w0.102: 180.7,186.06 178.13,186.06 v2(177.81,186.38) ; 180.7,186.06 182.45,186.06 192.56,196.16 194.03,196.16 194.13,196.27 194.13,196.71 194.23,196.81 v2(194.64,196.81) ; 180.7,186.06 v1(180.7,186.44)
PCIE_TX_PCH_N9: length 191
  TOP w0.102: 163.49,144.12 v1(163.86,144.12) ; 163.49,144.12 163.49,143.74 164.34,142.89 164.34,140.39 166.64,138.09 166.64,117.18 163.32,113.87 163.32,113.04 163.32,111.88 161.73,110.29 161.73,107 160.85,106.11 160.85,70.17 157.1,66.42 157.1,46.2 160.54,42.76 160.94,42.76 162.76,42.76 165.11,40.41 170,40.41 171.81,38.61 171.81,34.44 175.55,30.7 179.16,30.7 180.56,29.3 183.81,29.3 188.94,34.44 196.53,34.44 C9407.1 ; 163.49,144.12 163.49,144.83 v2(163.82,145.16) ; v2(186.14,152.48) 186.14,152.11 186.03,151.99 185.66,151.99 185.54,151.87 185.54,151.52 187.52,149.54 191.56,149.54 SB1.C34
  BOTTOM w0.102: v2(186.14,152.48) 186.14,152.06 186.03,151.94 185.5,151.94 185.24,151.69 178.93,151.69 178.73,151.49 176.17,151.49 170.54,145.85 163.63,145.85 163.47,145.68 163.47,145.51 v2(163.82,145.16)
PCIE_TX_PCH_N21: length 57.5
  TOP w0.102: v2(151.79,148.58) 151.79,146.04 149.49,143.75 149.49,142.81 C6211.1 ; v2(188.07,159.97) 188.41,159.63 191.19,159.63 192.88,157.94 192.88,156.05 193.11,155.83 SB1.G47
  BOTTOM w0.102: v2(151.79,148.58) 151.79,150.34 153.69,152.25 163.89,152.25 171.27,159.63 175.54,159.63 ; v2(188.07,159.97) 187.73,159.63 175.54,159.63 ; 175.54,159.63 v1(175.54,159.99)
PCIE_TX_PCH_N22: length 69.4
  TOP w0.102: SB1.H47 193.92,155.79 194.17,156.04 194.17,156.06 194.17,156.14 194.53,156.5 194.53,158.78 192.22,161.1 v2(192.22,162.1) ; C6209.1 143.87,143 v2(144.65,143.79)
  BOTTOM w0.102: v1(176.73,163.91) 176.73,163.54 ; 176.73,163.54 191.48,163.54 191.87,163.15 191.87,162.44 v2(192.22,162.1) ; 176.73,163.54 171.15,163.54 161.96,154.34 151.88,154.34 145.62,148.08 145.62,143.97 145.44,143.79 v2(144.65,143.79)
PCIE_TX_PCH_N23: length 65.3
  TOP w0.102: SB1.G49 193.34,156.85 193.34,158.3 190.82,160.82 189.85,160.82 v2(189.49,161.18) ; v2(146.48,145.98) 146.28,145.78 143.29,145.78 141.27,143.76 141.27,142.3 C6207.1
  BOTTOM w0.102: 174.55,160.87 189.17,160.87 v2(189.49,161.18) ; 174.55,160.87 171.42,160.87 163.5,152.95 153.4,152.95 149.45,149 149.45,147.75 147.38,145.68 146.78,145.68 v2(146.48,145.98) ; 174.55,160.87 v1(174.55,161.24)
PCIE_TX_PCH_N24: length 72.9
  TOP w0.102: SB1.G46 193.3,155.3 193.45,155.45 193.45,156.19 193.45,156.2 193.45,156.43 193.84,156.81 193.84,158.36 190.19,162 188.32,162 v2(187.96,161.63) ; v2(147.9,147.57) 147.62,147.85 147.62,148.44 147.26,148.81 144.23,148.81 138.25,142.82 138.25,142.33 C6202.1
  BOTTOM w0.102: 178.03,161.98 171.19,161.98 162.64,153.43 152.64,153.43 147.57,148.36 147.57,147.9 v2(147.9,147.57) ; 178.03,161.98 186.77,161.98 187.12,162.33 187.39,162.33 187.5,162.22 187.5,161.77 187.64,161.63 v2(187.96,161.63) ; 178.03,161.98 v1(178.03,161.59)
PCIE_TX_PCH_P5: length 132
  TOP w0.102: v2(163.01,134.91) 163.31,134.61 163.66,134.61 163.93,134.35 163.93,131.65 164.53,131.05 164.53,127.24 163.6,126.31 ; C3116.2 149.53,42.53 149.99,42.53 150.65,43.19 150.65,47.93 151.78,49.06 151.78,68.41 156.07,72.71 156.07,107.26 157.54,108.73 157.54,109.89 157.54,112.03 159.13,113.62 159.13,119.05 161.43,121.35 161.43,124.14 163.6,126.31 ; 163.6,126.31 v1(163.87,126.05) ; v2(186.44,143.05) 186.84,142.77 188.77,142.77 189.31,143.31 190.37,143.31 SB1.A22
  BOTTOM w0.102: v2(163.01,134.91) 163.35,134.57 164.72,134.57 164.91,134.38 169.1,134.38 176.9,142.18 184.67,142.18 185.22,142.73 186,142.73 v2(186.44,143.05)
PCIE_TX_PCH_P6: length 120
  TOP w0.102: C9502.2 191.01,55.49 189.92,55.49 189,56.41 189,72.34 188.23,73.11 188.23,86.8 188.7,87.27 188.7,100.76 189.33,101.4 190.26,101.4 v2(190.6,101.05) ; SB1.C21 191.35,143.1 191,142.75 189.92,142.75 189.56,142.39 189.28,142.39 189.1,142.21 v2(189.1,141.86)
  BOTTOM w0.102: v2(189.1,141.86) 189.1,141.84 189.91,141.03 193.73,141.03 194.43,141.73 197.23,141.73 197.86,141.1 201.37,141.1 202.22,140.25 202.22,138.59 202.62,138.19 202.62,130.62 202.9,130.35 202.9,125.02 200.68,122.81 192.57,122.81 188.05,118.29 188.05,109.54 188.57,109.02 ; 188.57,109.02 189.62,107.96 189.62,103.85 189.14,103.37 189.14,101.89 189.62,101.41 190.24,101.41 v2(190.6,101.05) ; 188.57,109.02 v1(188.3,108.75)
PCIE_TX_PCH_P7: length 147.6
  TOP w0.102: C9401.1 169.56,36.02 170.13,36.02 170.6,36.49 170.6,37.61 169.82,38.4 164.58,38.4 163.67,39.31 160.77,39.31 156.4,43.68 156.4,66.81 160.05,70.46 160.05,102.81 160.05,102.96 160.05,106.29 161.04,107.29 161.04,110.58 162.62,112.17 162.62,112.75 162.62,114.16 165.94,117.48 165.94,135.26 165.6,135.6 164.85,135.6 v2(164.51,135.93) ; v2(187.88,144.27) 188.21,143.94 188.67,143.94 188.81,143.81 SB1.B23
  BOTTOM w0.102: v1(168.1,135.94) 168.1,135.57 ; 168.1,135.57 164.87,135.57 v2(164.51,135.93) ; 168.1,135.57 169.3,135.57 176.75,143.01 184.31,143.01 185.21,143.91 187.52,143.91 v2(187.88,144.27)
PCIE_TX_PCH_P8: length 75.3
  TOP w0.102: SB1.C24 191.5,144.17 188.72,144.17 188.06,144.83 185.65,144.83 184.7,145.78 184.7,150.91 183.85,151.76 183.85,153.8 181.04,156.61 181.04,161.58 179.19,163.43 179.19,185.61 178.96,185.84 178.13,185.84 v2(177.81,185.52) ; C6306.2 196.45,196.3 194.99,196.3 v2(194.64,195.95)
  BOTTOM w0.102: v2(177.81,185.52) 178.13,185.84 182.17,185.84 ; v1(182.17,185.47) 182.17,185.84 ; 182.17,185.84 182.54,185.84 192.65,195.95 v2(194.64,195.95)
PCIE_TX_PCH_P9: length 191.1
  TOP w0.102: C9406.1 196.63,34.22 189.03,34.22 183.9,29.08 180.47,29.08 179.07,30.48 175.46,30.48 171.59,34.35 171.59,38.52 169.91,40.2 165.03,40.2 162.68,42.55 161.03,42.55 160.45,42.54 156.88,46.11 156.88,66.51 160.63,70.26 160.63,106.2 161.52,107.09 161.52,110.38 163.11,111.97 163.11,112.95 163.11,113.96 166.42,117.27 166.42,138 164.12,140.3 164.12,142.8 163.27,143.65 163.27,144.84 v2(162.95,145.16) ; SB1.D34 191.96,149.33 187.43,149.33 185.32,151.43 v2(185.32,152.47)
  BOTTOM w0.102: v2(162.95,145.16) 163.25,145.46 163.25,145.77 163.54,146.06 170.45,146.06 176.08,151.7 178.64,151.7 178.84,151.9 180.92,151.9 ; 180.92,151.9 v1(180.92,152.27) ; 180.92,151.9 185.15,151.9 185.32,152.07 v2(185.32,152.47)
PCIE_TX_PCH_P21: length 57.5
  TOP w0.102: v2(188.07,159.12) 188.36,159.41 191.1,159.41 192.66,157.85 192.66,155.92 SB1.F46 ; C6212.1 149.71,142.78 149.71,143.66 152.01,145.95 152.01,148.02 152.12,148.13 152.43,148.13 152.54,148.25 v2(152.54,148.61)
  BOTTOM w0.102: v2(188.07,159.12) 187.78,159.41 178.99,159.41 ; 178.99,159.41 171.36,159.41 163.98,152.03 153.78,152.03 152.01,150.25 152.01,149.16 152.13,149.04 152.38,149.04 152.54,148.88 v2(152.54,148.61) ; 178.99,159.41 v1(178.99,159.03)
PCIE_TX_PCH_P22: length 69.3
  TOP w0.102: v2(144.65,143.05) 144.6,143.1 144.27,143.1 144.08,142.91 144.08,142.61 144.2,142.49 144.75,142.49 144.88,142.37 C6210.1 ; SB1.H48 194.32,156.59 194.32,158.69 192.2,160.81 192,161.01 192,161.46 191.84,161.62 191.44,161.62 191.3,161.76 v2(191.3,162.1)
  BOTTOM w0.102: v1(174.8,162.94) 174.8,163.32 ; 174.8,163.32 171.24,163.32 162.04,154.13 151.97,154.13 145.83,147.99 145.83,143.88 145.53,143.57 145.1,143.57 144.65,143.13 v2(144.65,143.05) ; 174.8,163.32 191.39,163.32 191.65,163.06 191.65,162.44 v2(191.3,162.1)
PCIE_TX_PCH_P23: length 65.3
  TOP w0.102: v2(189.49,160.33) 189.76,160.6 190.73,160.6 193.13,158.21 193.13,156.36 SB1.G48 ; v2(146.48,145.12) 146.48,145.27 146.18,145.57 143.38,145.57 141.48,143.67 141.48,142.3 C6208.1
  BOTTOM w0.102: 177.34,160.66 171.51,160.66 163.59,152.73 153.49,152.73 149.67,148.91 149.67,147.66 147.47,145.47 146.83,145.47 v2(146.48,145.12) ; 177.34,160.66 v1(177.34,160.27) ; 177.34,160.66 189.16,160.66 v2(189.49,160.33)
PCIE_TX_PCH_P24: length 72.8
  TOP w0.102: SB1.G45 193.51,155.21 193.66,155.36 193.66,156.1 193.67,156.11 193.67,156.34 194.05,156.72 194.05,158.45 190.28,162.22 188.3,162.22 187.98,162.54 v2(187.98,162.55) ; C6204.1 138.47,142.37 138.47,142.73 144.32,148.59 147.17,148.59 147.41,148.35 147.41,147.95 v2(147.03,147.57)
  BOTTOM w0.102: 176.78,162.19 186.68,162.19 187.03,162.55 v2(187.98,162.55) ; 176.78,162.19 v1(176.78,162.56) ; 176.78,162.19 171.1,162.19 162.55,153.64 152.55,153.64 147.36,148.45 147.36,147.9 v2(147.03,147.57)
PCIRST1#: length 8.3
  TOP w0.102: R2406.1 202.26,105.68 202.26,105.04 R2401.1 202.16,104.94 202.16,101.96 202,101.79 U2401.51 202,100.1 201.6,99.7 v2(201.6,99.09)
  BOTTOM w0.102: v1(201.55,99.85) 201.6,99.8 v2(201.6,99.09)
PCIRST2#: length 9.8
  TOP w0.102: R2407.1 200.67,106.12 201.66,106.12 R2410.1 201.8,105.98 201.8,104.68 201.85,104.63 201.85,103.38 201.88,103.35 201.88,102.11 201.6,101.83 U2401.52 201.6,100.1 200.94,99.44 v2(200.94,98.58)
  BOTTOM w0.102: v1(200.19,98.43) 200.79,98.43 v2(200.94,98.58)
PCIRST#: length 69.3
  TOP w0.102: v2(204.85,62.08) 203.97,62.08 203.65,62.4 U9501.115 203.65,65.35 203.84,65.54 RN9505.2
  BOTTOM w0.102: v2(204.85,62.08) 205.36,61.57 205.36,60.94 204.8,60.38 204.8,47.27 207.26,44.81 207.85,44.81 209.32,43.33 212.16,43.33 212.62,42.87 212.62,41.4 212.52,41.3 212.17,41.3 212.06,41.19 212.06,40.89 212.17,40.79 212.52,40.79 212.62,40.69 212.62,40.38 212.52,40.28 212.17,40.28 212.06,40.18 212.06,39.87 212.17,39.77 212.52,39.77 212.62,39.67 212.62,39.37 212.52,39.26 212.17,39.26 212.06,39.16 212.06,38.86 212.17,38.76 212.52,38.76 212.62,38.65 212.62,38.35 212.52,38.25 212.17,38.25 212.06,38.15 212.06,37.84 212.17,37.74 212.52,37.74 212.62,37.64 212.62,31.96 212.8,31.78 213.14,31.78 213.24,31.88 213.24,33.1 213.34,33.2 213.54,33.2 213.64,33.1 213.64,31.88 213.74,31.78 213.95,31.78 214.05,31.88 214.05,33.1 214.15,33.2 214.35,33.2 214.46,33.1 214.46,31.88 214.56,31.78 214.76,31.78 214.86,31.88 214.86,33.1 214.96,33.2 215.17,33.2 215.27,33.1 215.27,31.88 215.37,31.78 215.57,31.78 215.68,31.88 215.68,33.1 215.78,33.2 215.98,33.2 216.08,33.1 216.08,31.88 216.18,31.78 216.39,31.78 216.49,31.88 216.49,33.1 216.59,33.2 216.79,33.2 216.89,33.1 216.89,31.88 217,31.78 217.2,31.78 217.3,31.88 217.3,33.1 217.4,33.2 217.61,33.2 217.71,33.1 217.71,31.88 217.81,31.78 218.16,31.78 219.16,32.77 SLOT4.29
PCM_CLK: length 63
  TOP w0.102: v2(220.93,141.35) 220.61,141.03 R2033.1 ; v2(219.43,189.53) 213.01,189.53 212.99,189.51 212.22,189.51 212.22,189.5 NGFF1.8
  BOTTOM w0.102: v2(220.93,141.35) 220.93,143.43 221.97,144.48 221.97,145.21 223.09,146.32 223.09,148.53 222.96,148.65 222.96,149.58 221.76,150.78 221.76,151.21 220.62,152.35 220.62,156.77 220.9,157.05 220.9,158.88 220.37,159.41 220.37,169.91 220.14,170.14 220.14,176.55 220.84,177.25 220.84,188.33 v1(221.01,188.49) 221.01,188.67 220.14,189.53 v2(219.43,189.53)
PCM_CLK_PCH: length 11.5
  TOP w0.089: 210.97,141.86 212.57,141.86
  TOP w0.102: 212.57,141.86 213.43,141.86 213.77,141.53 214.82,141.53 v1(215.11,141.82) 215.47,141.47 218.22,141.47 218.66,141.03 R2033.2 ; SB1.AV18 208.71,141.74 208.83,141.86 210.97,141.86
PCM_IN: length 65.4
  TOP w0.102: R2032.1 220.4,139.98 v2(221.01,140.59) ; NGFF1.12 209.29,190.48 212.59,190.48 212.61,190.5 v2(219.41,190.5)
  BOTTOM w0.102: 221.67,187.37 v1(221.68,187.37) ; 221.67,187.37 221.67,189.28 220.45,190.5 v2(219.41,190.5) ; 221.67,187.37 221.67,187.2 221.33,186.86 221.33,177.05 220.62,176.35 220.62,170.34 220.98,169.99 220.98,164.8 221.26,164.52 221.26,156.39 221.49,156.16 221.49,152.17 222.12,151.54 222.12,151.13 223.45,149.81 223.45,148.85 223.57,148.73 223.57,146.12 222.45,145.01 222.45,144.28 221.41,143.23 221.41,140.99 v2(221.01,140.59)
PCM_IN_PCH: length 11.1
  TOP w0.102: R2032.2 219.25,139.98 217.98,141.25 217.2,141.25 216.83,140.88 v1(216.33,140.88) 216.24,140.97 213.77,140.97 213.38,141.35 211.57,141.35 211.42,141.5 SB1.AW18
PCM_OUT: length 75
  TOP w0.102: v2(224.87,175.29) 224.73,175.15 R6301.2 223.79,175.15 222.91,176.02 R6319.2 222.59,175.35 v2(222.91,175.03) ; v2(221.69,190.63) 221.34,190.98 209.66,190.98 209.29,190.98 NGFF1.14 ; v2(221,138.66) 220.21,137.87 R2031.1
  BOTTOM w0.102: v2(221,138.66) 222.44,140.11 222.44,142.9 225.02,145.47 225.02,149.33 224.89,149.45 224.89,150.47 224.51,150.86 224.51,156.18 222.27,158.42 222.27,161.06 222.73,161.52 222.73,170.28 222.33,170.69 222.33,172.26 224.87,174.8 v2(224.87,175.29) ; v2(221.69,190.63) 222.94,189.38 v1(222.94,188.52) 222.94,187.91 222.74,187.72 222.74,184.57 222.33,184.15 222.33,175.61 v2(222.91,175.03)
PCM_OUT_C: length 2.7
  TOP w0.102: R6319.1 221.7,176.7 v1(221.28,177.11) 220.03,177.11 Q6301.3
PCM_OUT_PCH: length 12.2
  TOP w0.089: 212.66,139.98 212.35,139.67 211.63,139.67 211.62,139.68 210.37,139.68 210.19,139.87 210.19,140.81 SB1.BA17
  TOP w0.102: R2031.2 218.21,138.94 v1(218.21,139.33) 217.47,140.06 215.77,140.06 215.77,140.07 215.65,140.07 215.27,140.44 213.97,140.44 213.51,139.98 212.66,139.98
PCM_SYNC: length 74.4
  TOP w0.102: v2(224.9,176.8) 224.9,177.84 224.35,178.4 R6302.2 223.84,178.64 R6320.2 222.62,177.97 v2(222.88,177.7) ; NGFF1.10 212.79,190 212.81,190.02 222,190.02 v2(222.53,190.55) ; R2029.1 220.48,138.94 v2(221.04,139.5)
  BOTTOM w0.102: v2(224.9,176.8) 224.23,176.12 224.23,174.88 221.84,172.49 221.84,170.49 222.09,170.24 222.09,161.74 221.92,161.57 221.92,158.09 224.03,155.98 224.03,150.66 224.41,150.27 224.41,149.25 224.54,149.13 224.54,145.68 221.89,143.03 221.89,140.35 v2(221.04,139.5) ; v2(222.88,177.7) 222.81,177.77 222.81,182.88 v1(223.42,183.49) 223.88,183.95 223.88,189.21 222.53,190.55 v2(222.53,190.55)
PCM_SYNC_C: length 4.8
  TOP w0.102: R6320.1 221.73,179.24 v1(221.03,179.93) 219.13,179.93 218.6,179.41 Q6301.6
PCM_SYNC_PCH: length 8.8
  TOP w0.102: SB1.BE16 212.68,140.44 212.93,140.18 213.34,140.18 213.79,140.64 215.48,140.64 215.86,140.27 217.52,140.27 v1(217.82,140.57) 217.88,140.57 219.28,139.17 R2029.2
PDVSEL#: length 63.9
  TOP w0.102: U9501.66 213.22,50.69 213.49,50.42 213.49,50.11 213.28,49.91 212.78,49.91 212.65,49.78 212.65,49.32 212.12,48.79 212.12,43.13 212.35,42.9 214.47,42.9 214.78,43.22 RN9506.1 215.01,43.66 v2(215.39,44.04)
  BOTTOM w0.102: SLOT4.74 224.24,63.14 224.16,63.22 223.6,63.22 223.37,63.45 223.37,63.88 223.27,63.98 222.83,63.98 222.73,63.88 222.73,62.19 222.45,61.91 221.88,61.91 220.44,60.47 218.73,60.47 217.93,59.67 217.93,58.17 215.77,56.01 215.77,53.96 215.1,53.29 215.1,49.68 214.71,49.29 214.71,48.4 214.38,48.07 214.38,47.37 214.5,47.25 215.22,47.25 215.32,47.15 215.32,46.13 215.42,46.02 215.62,46.02 215.73,46.13 215.73,47.15 215.83,47.25 216.03,47.25 216.13,47.15 216.13,46.1 216.23,46 216.44,46 216.54,46.1 216.54,47.15 216.64,47.25 216.84,47.25 216.95,47.15 216.95,46.33 217.05,46.23 217.25,46.23 217.35,46.33 217.35,47.98 217.25,48.08 216.56,48.08 216.46,48.18 216.46,48.38 216.56,48.48 217.25,48.48 217.35,48.59 217.35,48.87 217.45,48.97 217.75,48.97 217.88,48.84 217.88,45.97 217.78,45.87 217.27,45.87 217.17,45.77 217.17,45.57 217.27,45.47 218.85,45.47 218.95,45.36 218.95,45.16 218.85,45.06 217.27,45.06 217.17,44.96 217.17,44.75 217.27,44.65 218.14,44.65 218.24,44.55 218.24,44.3 217.98,44.04 v2(215.39,44.04)
PECI_CPU: length 287.4
  TOP w0.102: CPU1.G7 v2(91.29,98.62) ; v2(139.45,62.86) 139.45,63.05 138.01,64.49 134.93,64.49 131.8,67.62 131.8,72.34 130.51,73.64 130.51,77.55 130.86,77.9 130.86,78.9 125.71,84.05 109.02,84.05 105.64,87.43 99.26,87.43 99.24,87.45 99.22,87.45 96.51,90.17 v2(96.24,90.17) ; R2428.1 214.44,99.45 v2(213.97,99.92) ; v2(172.21,11.94) 167.77,16.38 160.53,16.38 158.62,14.48 157.86,14.48 157.12,15.21 157.12,25.04 158.24,26.16 159.13,26.16 160.37,27.4 163.56,27.4 163.98,27.82 163.98,28.87 166.81,31.7 v2(166.81,32.07)
  BOTTOM w0.102: v2(213.97,99.92) 213.97,99.92 213.56,99.52 210.92,99.52 206.13,94.73 206.13,90.63 205.54,90.03 205.54,87.45 207.26,85.72 207.26,84 209.32,81.94 209.32,79 208.09,77.77 208.09,75.21 207.7,74.81 207.7,71.14 203.38,66.82 202.92,66.82 202.58,66.82 201.68,65.92 201.68,63.45 201.07,62.84 201.07,52.96 200.67,52.56 200.67,46.26 200.8,46.13 200.8,41.89 198.02,39.11 198.02,22.65 187.02,11.66 172.49,11.66 v2(172.21,11.94) ; v2(96.24,90.17) 96.14,90.17 95.12,91.19 93.82,91.19 90.86,94.15 90.86,95.14 91.11,95.4 91.42,95.4 91.72,95.7 91.72,98.19 v2(91.29,98.62) ; v2(166.81,32.07) 168.07,33.32 v1(168.07,40.72) 168.07,45.09 167.01,46.14 167.01,49.19 165.38,50.83 164.85,50.83 164.19,51.49 163.8,51.49 162.02,53.26 161.16,53.26 156.26,53.26 148.82,60.71 140.94,60.71 139.45,62.2 v2(139.45,62.86)
PECI_EC: length 3.1
  TOP w0.102: U2401.30 212.31,98.47 v1(212.57,98.73) 213.03,99.19 R2428.2
PECI_READY: length 5.7
  TOP w0.102: R2430.2 215.14,99.95 v1(214.71,100.38) 213.82,100.38 213.13,99.69 212.72,99.69 211.9,98.87 U2401.31
PEG_CLK1_PCH: length 103.7
  TOP w0.102: NGFF1.47 200.8,199.25 200.66,199.39 199.8,199.39 199.57,199.62 199.57,200.98 199.45,201.1 199.19,201.1 199.09,201 199.09,199.62 198.86,199.39 198.62,199.39 v2(198.27,199.04) ; v2(204.38,137.82) 204.38,137.76 204.06,137.44 203.89,137.44 203.71,137.61 SB1.AH10
  BOTTOM w0.102: 197.41,168.96 197.41,175.01 197.18,175.23 196.75,175.23 196.51,175.48 196.51,175.93 196.73,176.16 197.41,176.16 197.52,176.28 197.52,176.59 197.37,176.75 196.73,176.75 196.51,176.97 196.51,177.46 196.72,177.67 197.31,177.67 197.41,177.77 197.41,178.74 196.05,180.1 196.05,193.28 197.06,194.29 199.55,194.29 199.64,194.38 199.64,194.65 199.51,194.78 196.99,194.78 196.76,195 196.76,195.47 196.99,195.69 197.89,195.69 198.02,195.82 198.02,197.87 198.25,198.09 198.7,198.09 198.93,197.87 198.93,195.82 199.03,195.72 200.03,195.72 200.13,195.82 200.13,199.19 199.92,199.39 198.62,199.39 v2(198.27,199.04) ; 197.41,168.96 v1(197.03,168.96) ; 197.41,168.96 197.41,163.12 197.64,162.89 198.6,162.89 198.73,162.76 198.73,162.41 198.63,162.31 197.54,162.31 197.31,162.08 197.31,161.62 197.54,161.39 198.63,161.39 198.73,161.29 198.73,160.8 198.63,160.7 197.59,160.7 197.36,160.47 197.36,160.01 197.59,159.78 198.63,159.78 198.73,159.68 198.73,159.41 199.91,158.23 199.91,148.96 199.91,148.78 203.36,145.33 204.69,145.33 207.9,142.11 207.9,140.61 206.69,139.4 206.26,139.4 206.07,139.59 206.07,140.25 205.84,140.47 205.27,140.47 204.86,140.06 204.86,138.19 204.99,138.06 204.99,137.74 204.86,137.61 204.59,137.61 204.38,137.82 v2(204.38,137.82)
PEG_CLK1_PCH#: length 103.7
  TOP w0.102: v2(204.43,137.19) 204.01,137.19 SB1.AH9 ; NGFF1.49 200.8,199.75 200.66,199.61 199.89,199.61 199.79,199.71 199.79,201.07 199.54,201.32 199.1,201.32 198.88,201.09 198.88,199.71 198.77,199.61 198.57,199.61 v2(198.27,199.91)
  BOTTOM w0.102: v2(198.27,199.91) 198.57,199.61 200.01,199.61 200.34,199.28 200.34,195.73 200.11,195.5 198.94,195.5 198.72,195.73 198.72,197.78 198.62,197.88 198.34,197.88 198.23,197.78 198.23,195.73 197.98,195.48 197.08,195.48 196.98,195.38 196.98,195.09 197.08,194.99 199.6,194.99 199.86,194.74 199.86,194.29 199.64,194.08 197.15,194.08 196.27,193.19 196.27,187.78 ; v2(204.43,137.19) 204.63,137.39 204.95,137.39 205.21,137.65 205.21,138.15 205.08,138.28 205.08,139.97 205.36,140.26 205.75,140.26 205.85,140.16 205.85,139.5 206.17,139.19 206.78,139.19 208.11,140.52 208.11,142.2 204.77,145.54 203.45,145.54 200.13,148.87 200.13,158.32 198.95,159.5 198.95,159.77 198.72,160 197.68,160 197.57,160.1 197.57,160.38 197.68,160.48 198.72,160.48 198.95,160.71 198.95,161.38 198.72,161.61 197.62,161.61 197.52,161.71 197.52,161.99 197.62,162.09 198.72,162.09 198.95,162.32 198.95,162.85 198.69,163.11 197.73,163.11 197.62,163.21 197.62,175.1 197.27,175.45 196.84,175.45 196.72,175.56 196.72,175.84 196.82,175.95 197.5,175.95 197.74,176.19 197.74,176.68 197.46,176.96 196.82,176.96 196.72,177.06 196.72,177.37 196.81,177.46 197.4,177.46 197.62,177.68 197.62,178.83 196.27,180.19 196.27,187.78 ; 196.27,187.78 v1(196.65,187.78)
PEG_CLK2_PCH: length 145.4
  TOP w0.102: v2(162.81,129.93) 163.16,129.58 163.51,129.58 163.83,129.26 163.83,127.53 160.73,124.43 160.73,121.64 158.43,119.34 158.43,113.91 156.84,112.32 156.84,109.6 156.85,109.6 156.85,109.02 155.35,107.53 155.35,72.97 151.08,68.7 151.08,49.58 149.95,48.45 149.95,44.85 148.91,43.81 145.16,43.81 143.38,42.04 143.13,42.04 143.04,41.94 U3101.15 ; v2(201.71,140.07) 201.84,140.2 SB1.AE15
  BOTTOM w0.102: 166.56,130.16 165.98,129.58 163.16,129.58 v2(162.81,129.93) ; 166.56,130.16 167.86,131.46 169.23,131.46 177.85,140.08 187.96,140.08 188.56,140.68 193.96,140.68 194.6,141.31 197.06,141.31 197.57,140.8 200.72,140.8 201.45,140.07 v2(201.71,140.07) ; 166.56,130.16 v1(166.29,130.43)
PEG_CLK2_PCH#: length 145.3
  TOP w0.102: v2(201.71,139.31) 201.97,139.57 202.14,139.57 SB1.AE14 ; U3101.16 143.08,42.34 143.17,42.25 143.29,42.25 145.07,44.03 148.82,44.03 149.73,44.94 149.73,48.54 150.86,49.67 150.86,68.79 155.13,73.06 155.13,107.62 156.63,109.11 156.63,109.51 156.63,112.41 158.22,114 158.22,119.43 160.52,121.73 160.52,124.52 163.61,127.62 163.61,129.17 163.42,129.36 163.11,129.36 v2(162.81,129.06)
  BOTTOM w0.102: v2(201.71,139.31) 201.3,139.31 201.17,139.45 201.17,140.05 200.63,140.59 197.48,140.59 196.97,141.1 194.69,141.1 194.05,140.46 188.65,140.46 188.05,139.87 177.94,139.87 169.32,131.24 167.95,131.24 166.07,129.36 165.1,129.36 ; 165.1,129.36 163.11,129.36 v2(162.81,129.06) ; 165.1,129.36 v1(165.1,128.98)
PEG_CLK3_PCH: length 102.3
  TOP w0.102: v2(201.67,136.27) 201.77,136.17 202.06,136.17 SB1.AE7 ; v2(149.19,137.9) 148.83,137.54 148.83,136.59 149.11,136.31 NGFF2.55
  BOTTOM w0.102: 149.19,134.59 v1(149.56,134.59) ; 149.19,134.59 149.19,136.66 148.76,137.1 148.76,137.46 v2(149.19,137.9) ; 149.19,134.59 149.19,130.42 151.71,127.89 155.31,127.89 155.42,127.99 155.42,129.39 155.64,129.62 156.1,129.62 156.33,129.39 156.33,127.99 156.43,127.89 156.89,127.89 156.99,127.99 156.99,131.04 157.22,131.27 157.68,131.27 157.91,131.04 157.91,128.02 158.03,127.89 158.29,127.89 158.39,127.99 158.39,131.27 158.62,131.5 159.07,131.5 159.3,131.27 159.3,128.02 159.43,127.89 159.68,127.89 159.79,127.99 159.79,131.27 160.01,131.5 160.47,131.5 160.7,131.27 160.7,128.02 160.83,127.89 161.08,127.89 161.18,127.99 161.18,131.04 161.41,131.27 161.87,131.27 162.1,131.04 162.1,128.02 162.22,127.89 168.63,127.89 177.79,137.05 184.11,137.05 184.82,137.76 189.22,137.76 190.65,139.19 194.31,139.19 194.81,138.68 196.54,138.68 197.14,139.28 198.71,139.28 199.31,138.68 200.7,138.68 201.06,138.32 201.06,136.23 201.29,136 201.47,136 201.67,136.2 v2(201.67,136.27)
PEG_CLK3_PCH#: length 102.2
  TOP w0.102: SB1.AE6 202,135.63 201.79,135.63 v2(201.67,135.51) ; v2(148.44,137.9) 148.61,137.72 NGFF2.53
  BOTTOM w0.102: v2(148.44,137.9) 148.54,137.79 148.54,137.01 148.97,136.57 148.97,132.97 ; v1(148.56,132.97) 148.97,132.97 ; 148.97,132.97 148.97,130.33 151.63,127.67 155.4,127.67 155.63,127.9 155.63,129.3 155.73,129.4 156.01,129.4 156.12,129.3 156.12,127.9 156.34,127.67 156.98,127.67 157.21,127.9 157.21,130.95 157.31,131.05 157.59,131.05 157.69,130.95 157.69,127.93 157.94,127.67 158.38,127.67 158.6,127.9 158.6,131.18 158.71,131.28 158.99,131.28 159.09,131.18 159.09,127.93 159.34,127.67 159.77,127.67 160,127.9 160,131.18 160.1,131.28 160.38,131.28 160.48,131.18 160.48,127.93 160.74,127.67 161.17,127.67 161.4,127.9 161.4,130.95 161.5,131.05 161.78,131.05 161.88,130.95 161.88,127.93 162.13,127.67 168.72,127.67 177.88,136.83 184.2,136.83 184.91,137.54 189.31,137.54 190.74,138.98 194.22,138.98 194.72,138.47 196.63,138.47 197.23,139.06 198.62,139.06 199.22,138.47 200.61,138.47 200.85,138.23 200.85,136.14 201.47,135.51 v2(201.67,135.51)
PEG_CLK8_PCH: length 157.1
  TOP w0.102: v2(168.87,130.29) 168.55,129.96 168.26,129.96 167.89,129.6 167.89,116.74 164.5,113.35 164.5,111.39 163.32,110.21 163.32,106.91 162.22,105.81 162.22,68.59 158.41,64.78 158.41,46.65 161.11,43.94 163.25,43.94 165.6,41.59 171.18,41.59 173.52,39.25 173.52,34.73 174.2,34.06 180.02,34.06 180.35,34.39 180.55,34.39 SLOT2.A13 ; SB1.AC15 200.83,139.9 200.48,139.9 v2(200.3,140.08)
  BOTTOM w0.102: v2(168.87,130.29) 169.19,129.96 169.61,129.96 175.77,136.12 175.77,136.75 177.35,138.34 180.31,138.34 ; v2(200.3,140.08) 200.03,139.81 199.43,139.81 199.17,140.07 197.37,140.07 196.76,140.68 194.98,140.68 194.47,140.17 189.9,140.17 189.11,139.38 182.41,139.38 181.37,138.34 180.31,138.34 ; v1(180.31,138.71) 180.31,138.34
PEG_CLK8_PCH#: length 157.1
  TOP w0.102: v2(168.87,129.42) 168.55,129.75 168.35,129.75 168.11,129.51 168.11,116.65 164.72,113.26 164.72,111.3 163.54,110.12 163.54,106.82 162.43,105.72 162.43,68.5 158.62,64.69 158.62,46.74 161.2,44.16 163.34,44.16 165.69,41.81 171.27,41.81 173.74,39.34 173.74,34.82 174.29,34.27 179.93,34.27 180.21,34.55 180.21,34.85 179.94,35.12 SLOT2.A14 ; v2(200.3,139.32) 200.67,139.69 200.87,139.69 SB1.AC14
  BOTTOM w0.102: 181.18,138.13 177.44,138.13 175.98,136.66 175.98,136.03 169.7,129.75 169.19,129.75 v2(168.87,129.42) ; 181.18,138.13 181.46,138.13 182.5,139.17 189.2,139.17 189.99,139.95 194.56,139.95 195.07,140.46 196.67,140.46 197.28,139.85 199.08,139.85 199.34,139.59 200.03,139.59 v2(200.3,139.32) ; 181.18,138.13 v1(181.18,137.74)
PEG_CLK9_PCH: length 137.4
  TOP w0.102: v2(164.28,119.15) 164.28,119.15 163.95,118.82 163.17,118.82 162.8,118.45 162.8,116.62 161.01,114.83 161.01,112.84 159.42,111.25 159.42,107.95 158.19,106.72 158.19,102.62 158.19,102.53 158.19,71.3 153.66,66.76 153.66,41.62 157.29,37.98 157.29,34.66 157.85,34.1 159.5,34.1 159.84,34.44 160.12,34.44 SLOT1.A13 ; v2(198.5,132.18) 198.5,132.21 198.73,132.44 198.73,133.7 198.58,133.85 198.58,134.05 SB1.U3
  BOTTOM w0.102: v2(164.28,119.15) 164.55,118.87 167.72,118.87 ; 167.72,118.87 v1(167.72,119.25) ; 167.72,118.87 172.74,118.87 173.03,119.16 173.06,119.16 183.32,129.43 185.03,129.43 187.02,131.42 187.73,131.42 188.3,131.99 198.31,131.99 v2(198.5,132.18)
PEG_CLK9_PCH#: length 137.4
  TOP w0.102: SB1.U2 198.51,133.61 198.51,132.81 198.07,132.36 198.07,131.72 198.27,131.52 198.53,131.52 v2(198.53,131.52) ; v2(164.29,118.29) 164.28,118.29 164.28,118.28 164.27,118.28 163.95,118.61 163.26,118.61 163.01,118.36 163.01,116.53 161.23,114.74 161.23,112.75 159.64,111.16 159.64,107.87 158.41,106.63 158.41,102.62 158.41,102.53 158.41,71.21 153.87,66.68 153.87,41.71 157.51,38.07 157.51,34.75 157.94,34.32 159.41,34.32 159.72,34.62 159.72,34.77 159.37,35.12 SLOT1.A14
  BOTTOM w0.102: 165.68,118.66 172.83,118.66 173.12,118.94 173.15,118.94 183.41,129.21 185.11,129.21 187.11,131.2 187.82,131.2 188.39,131.78 198.27,131.78 198.53,131.52 v2(198.53,131.52) ; 165.68,118.66 v1(165.68,118.29) ; 165.68,118.66 164.66,118.66 v2(164.29,118.29)
PEG_CLK10_PCH: length 95.4
  TOP w0.102: SB1.AC11 201.09,137.88 200.44,137.88 v2(200.36,137.96) ; R9503.2 191.49,62.22 191.26,62.22 R9505.1 190.44,62.23 189.75,62.23 189.48,62.5 189.48,64.21 189.85,64.58 189.85,66.28 189.56,66.57 189.56,66.99 189.85,67.28 189.85,67.52 189.56,67.81 189.56,68.23 189.85,68.52 189.85,72.22 188.71,73.37 188.71,86.6 189.4,87.29 189.4,98.03 189.74,98.37 189.74,99.42 v2(189.48,99.67)
  BOTTOM w0.102: 189.1,121.79 189.1,122.2 191.11,124.21 200.1,124.21 201.43,125.54 201.43,134.23 199.62,136.04 199.62,137.41 199.86,137.66 200.05,137.66 v2(200.36,137.96) ; 189.1,121.79 189.1,121.32 186.49,118.7 186.49,105.36 187.31,104.53 187.31,102.73 189.75,100.29 189.75,99.94 v2(189.48,99.67) ; 189.1,121.79 v1(188.72,121.79)
PEG_CLK10_PCH#: length 95.3
  TOP w0.102: v2(190.25,99.67) 189.95,99.38 189.95,98.29 189.61,97.94 189.61,87.2 188.92,86.51 188.92,73.46 190.07,72.31 190.07,68.44 189.78,68.14 189.78,67.9 190.07,67.61 190.07,67.19 189.78,66.9 189.78,66.66 190.07,66.37 190.07,64.49 189.7,64.12 189.7,62.59 189.84,62.45 190.45,62.45 R9504.1 191.27,62.43 191.48,62.43 R9502.2 ; v2(200.36,137.2) 200.36,137.32 200.71,137.67 200.91,137.67 201.12,137.46 SB1.AC9
  BOTTOM w0.102: v2(200.36,137.2) 200.12,137.44 199.95,137.44 199.83,137.33 199.83,136.13 201.65,134.32 201.65,125.45 200.19,123.99 191.2,123.99 190.55,123.34 ; v2(190.25,99.67) 189.97,99.95 189.97,100.38 187.53,102.82 187.53,104.62 186.7,105.45 186.7,118.61 189.32,121.23 189.32,122.11 190.55,123.34 ; 190.55,123.34 v1(190.82,123.08)
PEG_CLK11_PCH: length 130.3
  TOP w0.102: SLOT3.A13 200.59,34.53 200.54,34.66 200.61,34.79 200.87,35.05 202.26,35.05 202.78,35.57 202.78,38.32 201,40.09 194.53,40.09 186.83,47.79 186.83,87.38 187.26,87.81 187.26,102.2 188.68,103.62 188.68,104.49 188.97,104.78 v2(188.98,104.78) ; v2(201.63,137.72) 202.09,137.72 SB1.AE11
  BOTTOM w0.102: 187.4,107.52 187.4,118.32 192.37,123.29 200.48,123.29 202.41,125.22 202.41,137.14 202.15,137.39 201.95,137.39 v2(201.63,137.72) ; 187.4,107.52 187.4,107.01 188.73,105.68 188.73,105.02 v2(188.98,104.78) ; 187.4,107.52 v1(187.78,107.52)
PEG_CLK11_PCH#: length 130.3
  TOP w0.102: v2(188.23,104.78) 188.47,104.54 188.47,103.71 187.05,102.29 187.05,87.9 186.61,87.47 186.61,47.7 194.44,39.88 200.91,39.88 202.56,38.23 202.56,35.66 202.17,35.27 200.78,35.27 200.43,34.92 200.35,34.76 200.35,34.76 200.21,34.71 SLOT3.A14 ; SB1.AE9 202.28,137.38 202.17,137.49 202.01,137.49 201.67,137.15 v2(201.67,136.96)
  BOTTOM w0.102: v2(201.67,136.96) 201.89,137.18 202.06,137.18 202.2,137.05 202.2,125.31 200.39,123.51 192.28,123.51 187.19,118.41 187.19,106.92 188.06,106.04 ; v1(187.78,105.77) 188.06,106.04 ; 188.06,106.04 188.52,105.59 188.52,105.07 v2(188.23,104.78)
PEG_CLKREQ1_PCH#: length 87.8
  TOP w0.102: SB1.BE31 211.76,147.83 212.09,147.5 214.74,147.5 214.79,147.45 214.8,147.45 215.29,146.96 215.29,146.71 216.2,145.8 216.2,145.36 216.41,145.16 217.81,145.16 218.08,144.88 219.53,144.88 219.8,145.15 R1801.1 220.88,144.77 v2(222.92,144.77) ; NGFF1.53 203.11,200.75 205.49,198.37 205.49,197.46 208.2,194.74 210.9,194.74 211.35,195.2 216.08,195.2 216.87,194.41 v2(219.56,194.41)
  BOTTOM w0.102: v2(222.92,144.77) 224.05,145.9 224.05,148.93 223.93,149.05 223.93,150.07 223.55,150.46 223.55,152.7 222.76,153.49 222.76,156.57 221.6,157.72 221.6,170.04 221.18,170.47 221.18,174.84 221.81,175.47 221.81,184.39 222.26,184.85 222.26,189.37 220.55,191.08 v1(220.55,193.65) 220.55,194.16 220.29,194.41 v2(219.56,194.41)
PEG_CLKREQ2_PCH#: length 176
  TOP w0.102: v2(207.54,147.62) 207.49,147.62 SB1.AR32 ; v2(165.86,45.09) 167.65,45.09 173.63,51.07 173.63,101.19 174.66,102.21 175.68,102.21 177.61,104.14 177.61,105.1 180.57,108.06 184.29,108.06 184.68,107.67 190.62,107.67 191.16,108.2 194.79,108.2 195.3,108.71 196.16,108.71 197.09,109.64 210.5,109.64 v2(210.57,109.7) ; v2(151.43,47.42) 151.43,45.79 151.21,45.57 151.21,43.07 149.35,41.21 R1803.1 149.03,41.27 R3102.2
  BOTTOM w0.102: v2(210.57,109.7) 210.57,110.36 212.63,112.43 212.63,114.43 213.26,115.06 213.26,115.43 213.36,115.53 213.36,127.6 213.65,127.89 213.79,127.89 214.05,128.14 214.05,128.19 214.17,128.32 215.96,130.11 217.02,131.17 217.02,136.4 216.7,136.72 216.7,142.54 216.7,142.88 213.91,145.67 213.11,145.67 v1(212.37,146.41) 211.58,147.19 207.98,147.19 v2(207.54,147.62) ; v2(151.43,47.42) 156.08,47.42 157.86,49.2 161.24,49.2 164.47,45.97 164.97,45.97 v2(165.86,45.09)
PEG_CLKREQ3_PCH#: length 143.9
  TOP w0.089: 212.08,147.96 211.9,148.14 211.15,148.14 SB1.BB30
  TOP w0.102: v2(180.19,106.55) 181.09,107.45 184.04,107.45 184.43,107.06 190.88,107.06 191.41,107.59 195.04,107.59 195.55,108.1 196.57,108.1 197.5,109.03 207.54,109.03 208.74,107.82 212.41,107.82 R1805.1 v1(214.33,107.31) 215.72,107.31 215.95,107.55 v2(215.95,107.56) ; NGFF2.52 148.36,128.4 148.87,127.89 149.02,127.89 v2(149.08,127.89) ; v2(216.66,145.75) 216.56,145.75 215.49,146.81 215.49,147.04 214.88,147.65 214.88,147.65 214.7,147.83 212.58,147.83 212.45,147.96 212.08,147.96 ; v2(165.2,108.61) 165.2,113.06 168.73,116.59 v2(168.73,126.62)
  BOTTOM w0.102: v2(165.2,108.61) 166.32,107.49 173.1,107.49 173.34,107.25 179.49,107.25 v2(180.19,106.55) ; v2(215.95,107.56) 216.26,107.86 216.26,108.52 215.7,109.07 215.7,111.22 216.2,111.73 216.2,114.18 215.23,115.16 215.23,116.09 214.58,116.74 214.58,127.09 214.92,127.43 214.92,127.49 215.11,127.69 215.11,127.74 217.83,130.46 217.83,136.76 217.55,137.04 217.55,144.42 216.66,145.31 v2(216.66,145.75) ; v2(149.08,127.89) 149.08,127.76 150.22,126.62 v2(168.73,126.62)
PEG_CLKREQ8_PCH#: length 205.6
  TOP w0.089: 202.43,156.34 202.45,156.32 202.45,155.96 202.32,155.83 202.29,155.83 202.14,155.69 202.14,155.59 201.93,155.37 201.93,154.81
  TOP w0.102: 202.43,156.34 202.13,156.64 202.13,160.09 199.95,162.28 199.95,167.53 R1807.1 198.83,168.64 198.83,169.49 197.69,170.64 196.2,170.64 195.21,171.62 192.96,171.62 v2(192.83,171.75) ; SB1.AE41 201.93,153.2 201.93,154.81 ; v2(169.95,173.99) 169.8,173.84 169.8,170.76 170.79,169.77 170.79,154.13 174.65,150.27 174.65,149.37 174.65,144.11 176.58,142.18 176.58,135.65 178.54,133.69 178.54,128.98 179.35,128.16 179.35,127.47 179.35,123.05 181.01,121.39 186.31,121.39 v2(186.44,121.51)
  BOTTOM w0.102: v2(192.83,171.75) 192.04,172.54 v1(187.58,172.54) 185.5,172.54 184.33,173.71 170.23,173.71 v2(169.95,173.99) ; v2(186.44,121.51) 186.44,120.55 184.91,119.02 184.91,104.55 184.15,103.79 184.15,102.57 184.3,102.42 184.3,101.82 183.7,101.22 183.26,101.22 182.6,100.56 182.6,97.54 183.11,97.03 184.02,97.03 184.91,96.14 186.18,96.14 186.44,95.89 186.44,33.98 SLOT2.B12
PEG_CLKREQ9_PCH#: length 205.7
  TOP w0.102: v2(193.56,172.94) 193.57,172.92 195.35,172.92 196.42,171.86 198.29,171.86 200.94,169.2 200.94,168.59 R1809.1 200.3,167.96 200.3,162.35 202.39,160.27 202.39,156.69 SB1.AF48 ; v2(165.86,42.55) 163.45,44.96 163.45,47.96 162.39,49.02 162.39,62.59 166.22,66.42 166.22,104.44 169.52,107.75 169.52,110.2 174.04,114.72 174.04,132.35 172.47,133.92 172.47,140.47 170.51,142.43 170.51,147.6 166.37,151.74 166.37,165.35 165.33,166.4 165.33,174.85 165.68,175.21 v2(165.68,175.97)
  BOTTOM w0.102: v2(165.86,42.55) 166.12,42.29 166.12,33.98 SLOT1.B12 ; v2(165.68,175.97) 167.03,174.62 v1(169.14,174.62) 169.96,174.62 170.57,174.02 184.45,174.02 185.34,173.13 193.37,173.13 v2(193.56,172.94)
PEG_CLKREQ10_PCH#: length 17.5
  TOP w0.102: R1810.1 197.29,168.11 198.32,167.08 R1808.2 198.53,167.11 199.09,166.55 199.09,162.18 199.9,161.37 v1(199.9,160.86) 199.9,158.91 200.96,157.84 200.96,157.05 201.43,156.58 201.43,153.15 SB1.AC41
PEG_CLKREQ11_PCH#: length 230
  TOP w0.102: SB1.AC39 201.7,152.66 201.7,155.42 201.93,155.65 201.93,159.87 199.49,162.3 199.49,166.78 198.16,168.11 R1811.1 198.53,168.57 198.53,169.28 197.5,170.31 196.1,170.31 195.16,171.25 192.41,171.25 v2(192.13,171.53) ; v2(170.26,173.02) 170.1,172.87 170.1,170.88 171.09,169.89 171.09,154.25 174.96,150.39 174.96,149.49 174.96,144.24 176.89,142.31 176.89,135.77 178.84,133.82 178.84,129.1 179.65,128.29 179.65,127.34 179.65,127.34 179.65,123.18 181.14,121.69 185.95,121.69 186.26,122 186.66,122 v2(187.17,121.49) ; v2(186.94,29.84) 188.28,31.18 198.59,31.18 200.86,28.91 203.72,28.91 205.9,31.1 SLOT3.B12
  BOTTOM w0.102: v2(186.94,29.84) 187.43,30.33 187.43,32.97 186.82,33.58 186.82,97.66 186.44,98.04 185.17,98.04 184.4,98.81 184.4,101.49 184.61,101.69 184.61,102.55 184.45,102.7 184.45,103.66 185.22,104.43 185.22,118.8 187.17,120.75 v2(187.17,121.49) ; v2(170.26,173.02) 170.56,172.72 184.78,172.72 185.55,171.96 v1(189.74,171.96) 191.69,171.96 v2(192.13,171.53)
PEG_RCOMP_CPU: length 7.6
  TOP w0.203: 89.03,104.12 89.12,104.12 89.42,103.82 89.42,103.55 89.77,103.21 91.27,103.21 CPU1.L7
  TOP w0.305: 89.03,104.12 88.43,104.12 86.22,106.33 R301.2
PEG_RX_CPU_N0: length 126
  TOP w0.102: CPU1.B7 91.31,94.07 91.31,93.37 92.1,92.58 95.38,92.58 95.76,92.96 97.24,92.96 97.47,92.74 97.47,92.32 v2(97.75,92.04)
  BOTTOM w0.102: SLOT2.A17 180.27,37.71 180.13,37.76 180.07,37.89 179.69,38.26 178.14,38.26 177.42,38.99 174.47,38.99 171.96,41.5 171.96,45.45 170.56,46.85 170.56,50.15 169.23,51.48 169.23,54.14 167.86,55.5 167.86,57.51 166.12,59.26 166.12,61.37 159.17,68.32 159.17,71.77 151.22,79.72 133.3,79.72 132.56,80.45 107.99,80.45 97.5,90.94 97.5,91.79 v2(97.75,92.04)
PEG_RX_CPU_N1: length 120.9
  TOP w0.102: v2(93.12,94.96) 92.66,95.42 CPU1.C6
  BOTTOM w0.102: SLOT2.A22 179.85,42.88 180.01,42.72 180.01,42.47 179.79,42.25 175.22,42.25 173.35,44.12 173.35,46.03 171.96,47.43 171.96,50.73 170.62,52.06 170.62,54.72 169.26,56.08 169.26,58.09 167.51,59.84 167.51,62 161.67,67.84 161.67,71.25 151.8,81.11 133.88,81.11 133.14,81.85 109.72,81.85 98.51,93.05 96.05,93.05 95.25,93.85 93.37,93.85 92.61,94.62 92.61,94.79 92.78,94.96 v2(93.12,94.96)
PEG_RX_CPU_N2: length 118.4
  TOP w0.102: v2(94.03,95.88) CPU1.D5
  BOTTOM w0.102: SLOT2.A26 180.24,47.12 180.39,46.96 180.39,46.71 179.87,46.19 175.17,46.19 173.36,48.01 173.36,51.31 172.02,52.64 172.02,55.3 170.66,56.66 170.66,58.67 168.91,60.42 168.91,62.58 164.12,67.37 164.12,71.34 152.95,82.51 134.45,82.51 133.72,83.25 110.3,83.25 101.96,91.59 101.96,92.86 100.88,93.94 96.11,93.94 94.41,95.65 94.26,95.65 v2(94.03,95.88)
PEG_RX_CPU_N3: length 114.1
  TOP w0.102: v2(94.94,96.79) 94.94,97.1 94.8,97.25 CPU1.E4
  BOTTOM w0.102: v2(94.94,96.79) 95.73,96.01 100.81,96.01 103.73,93.09 103.73,91.79 110.88,84.65 134.3,84.65 135.03,83.91 153.73,83.91 166.12,71.53 166.12,67.35 170.31,63.16 170.31,61 172.06,59.25 172.06,57.24 173.42,55.88 173.42,53.71 176.87,50.25 179.92,50.25 180.29,50.62 180.29,50.87 180.03,51.12 SLOT2.A30
PEG_RX_CPU_N4: length 112.5
  TOP w0.102: CPU1.F5 93.57,97.81 93.47,97.71 v2(93.12,97.71)
  BOTTOM w0.102: SLOT2.A36 180.1,57.01 180.29,56.82 180.29,56.59 179.96,56.26 175.11,56.26 173.45,57.91 173.45,59.83 171.7,61.58 171.7,63.74 168.03,67.41 168.03,71.79 154.52,85.31 135.61,85.31 134.88,86.04 111.51,86.04 107.51,90.05 107.51,91.22 106.12,92.61 105.23,92.61 101.1,96.74 96.86,96.74 96.14,97.46 93.36,97.46 93.12,97.7 v2(93.12,97.71)
PEG_RX_CPU_N5: length 110.3
  TOP w0.102: CPU1.G4 v2(94.03,98.62)
  BOTTOM w0.102: SLOT2.A40 179.91,60.71 180.06,60.55 180.06,60.35 179.91,60.2 175.06,60.2 173.1,62.15 173.1,64.32 169.72,67.7 169.72,72.9 155.87,86.75 139.16,86.75 138.47,87.44 112.09,87.44 109.05,90.48 109.05,91.68 103.3,97.43 97.3,97.43 96.38,98.35 95.32,98.35 94.98,98.02 93.83,98.02 93.57,98.28 93.57,98.5 93.69,98.62 v2(94.03,98.62)
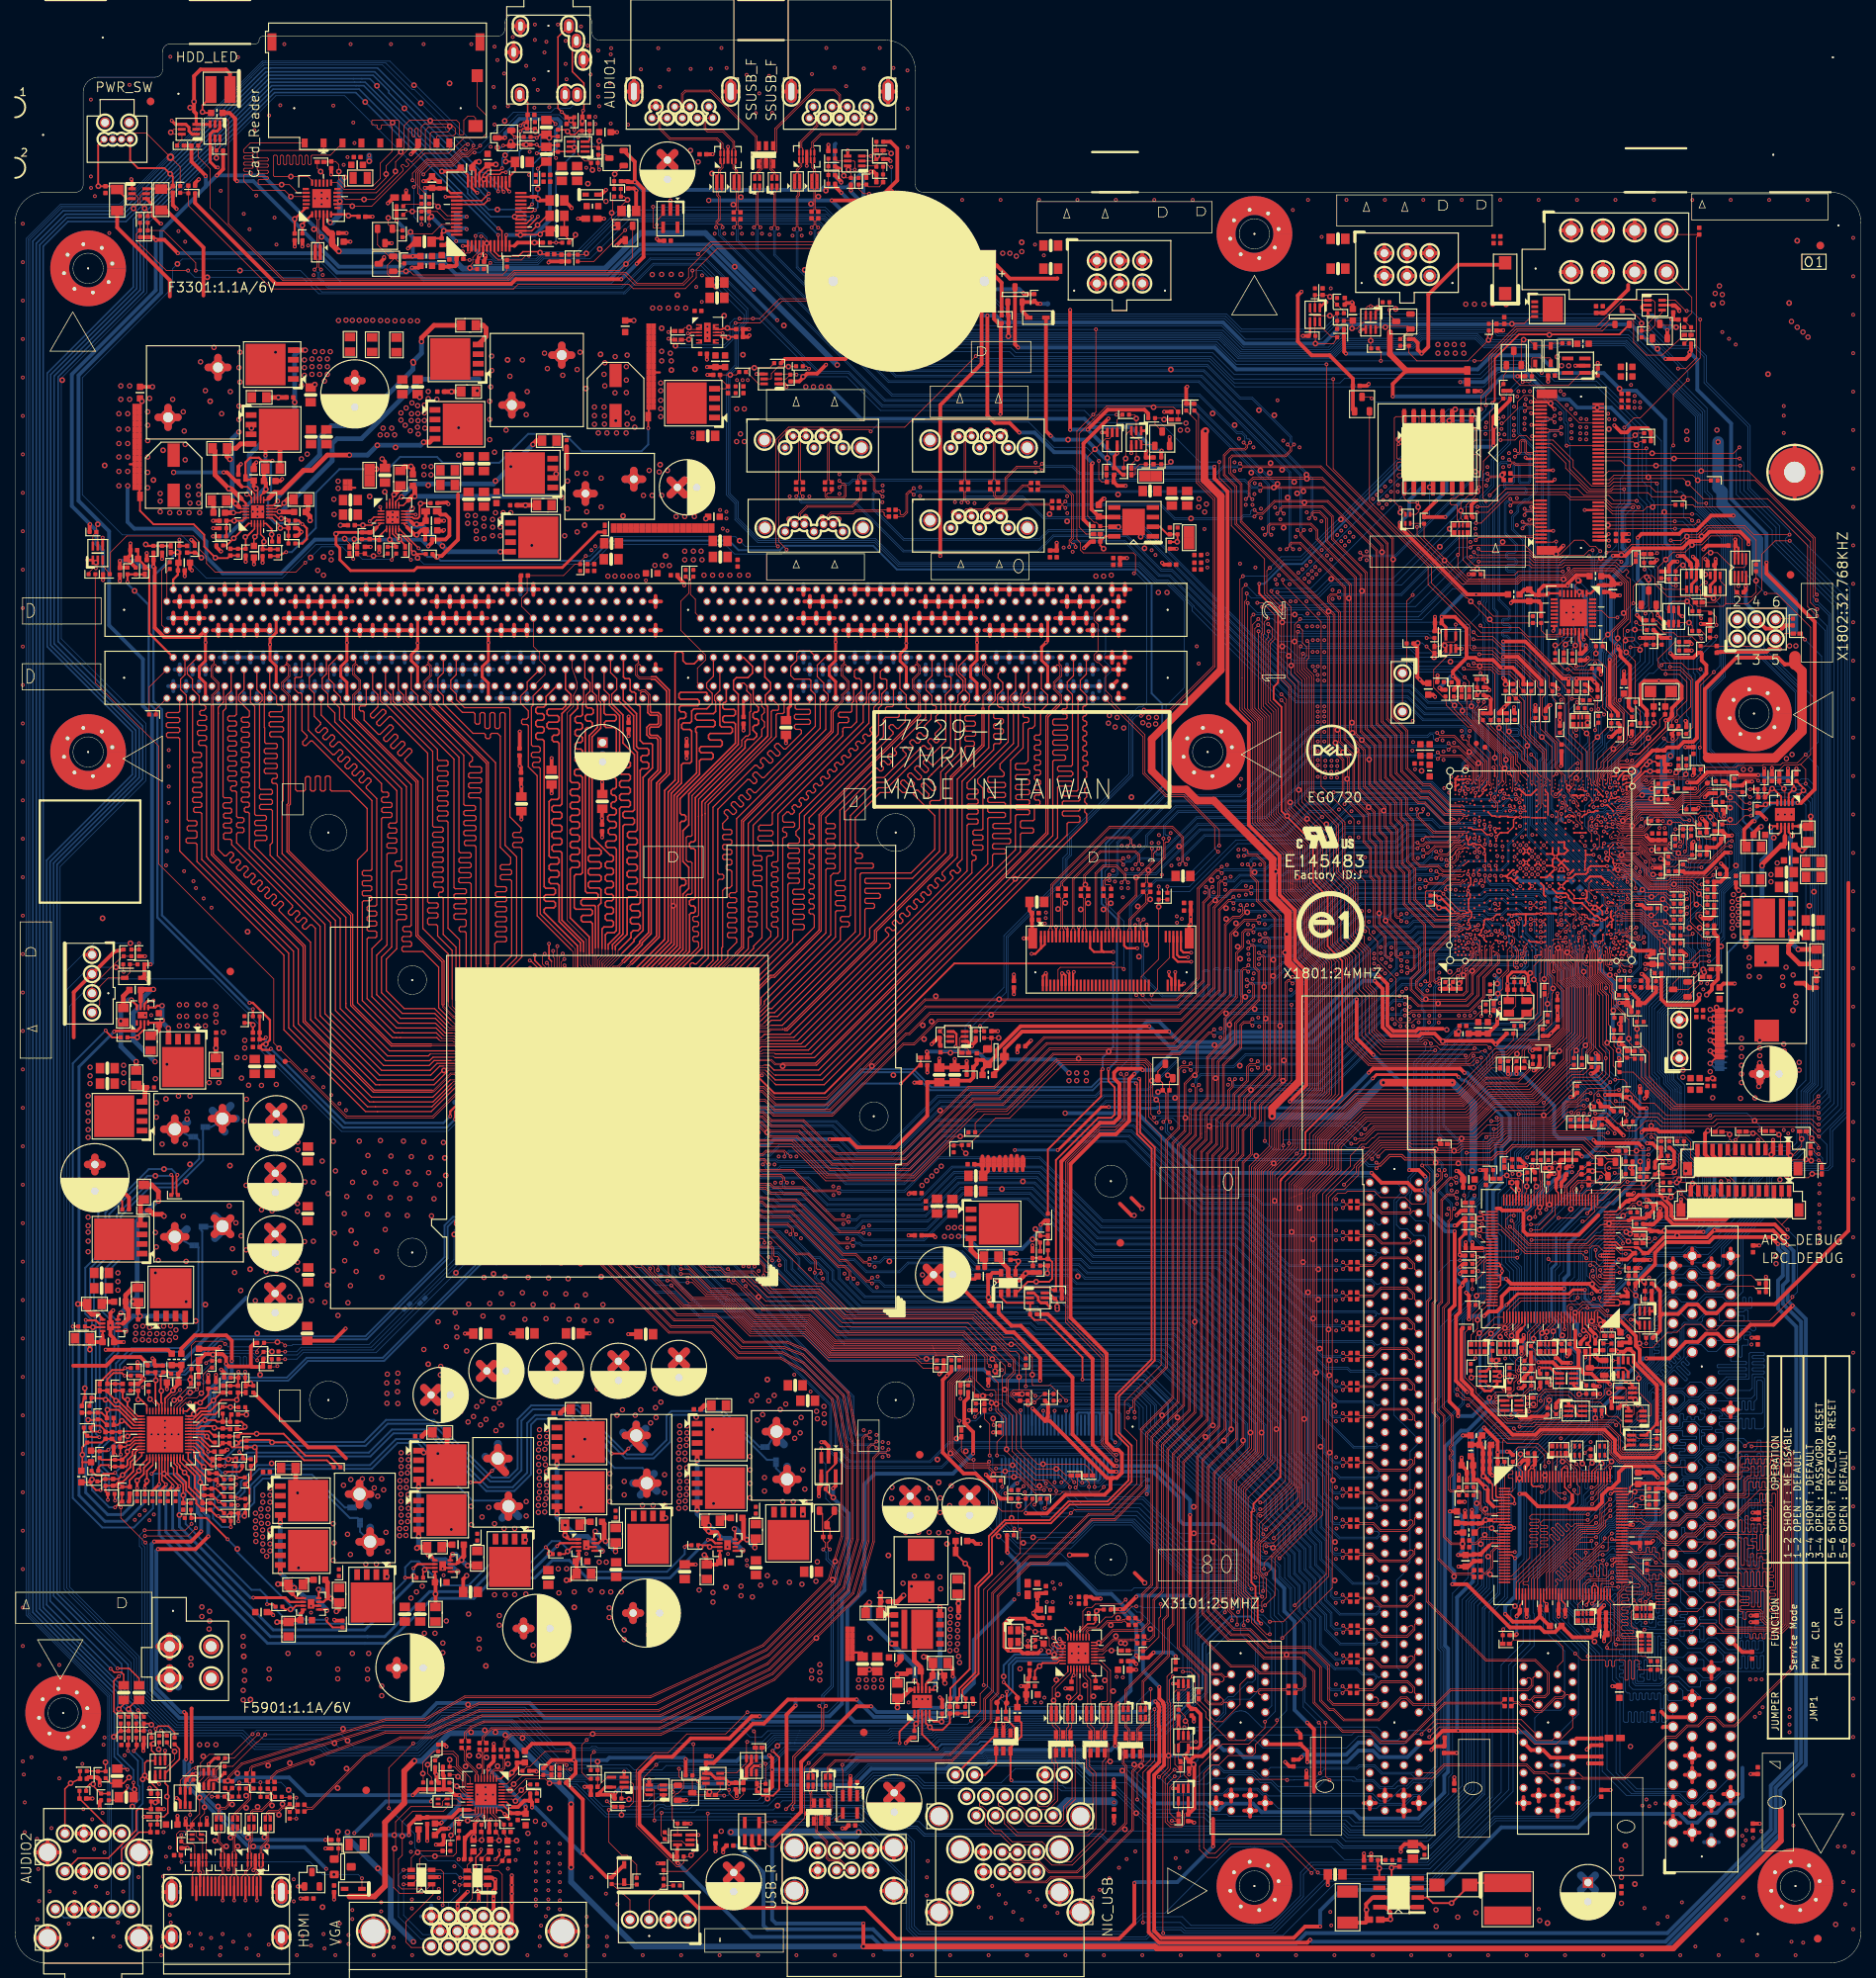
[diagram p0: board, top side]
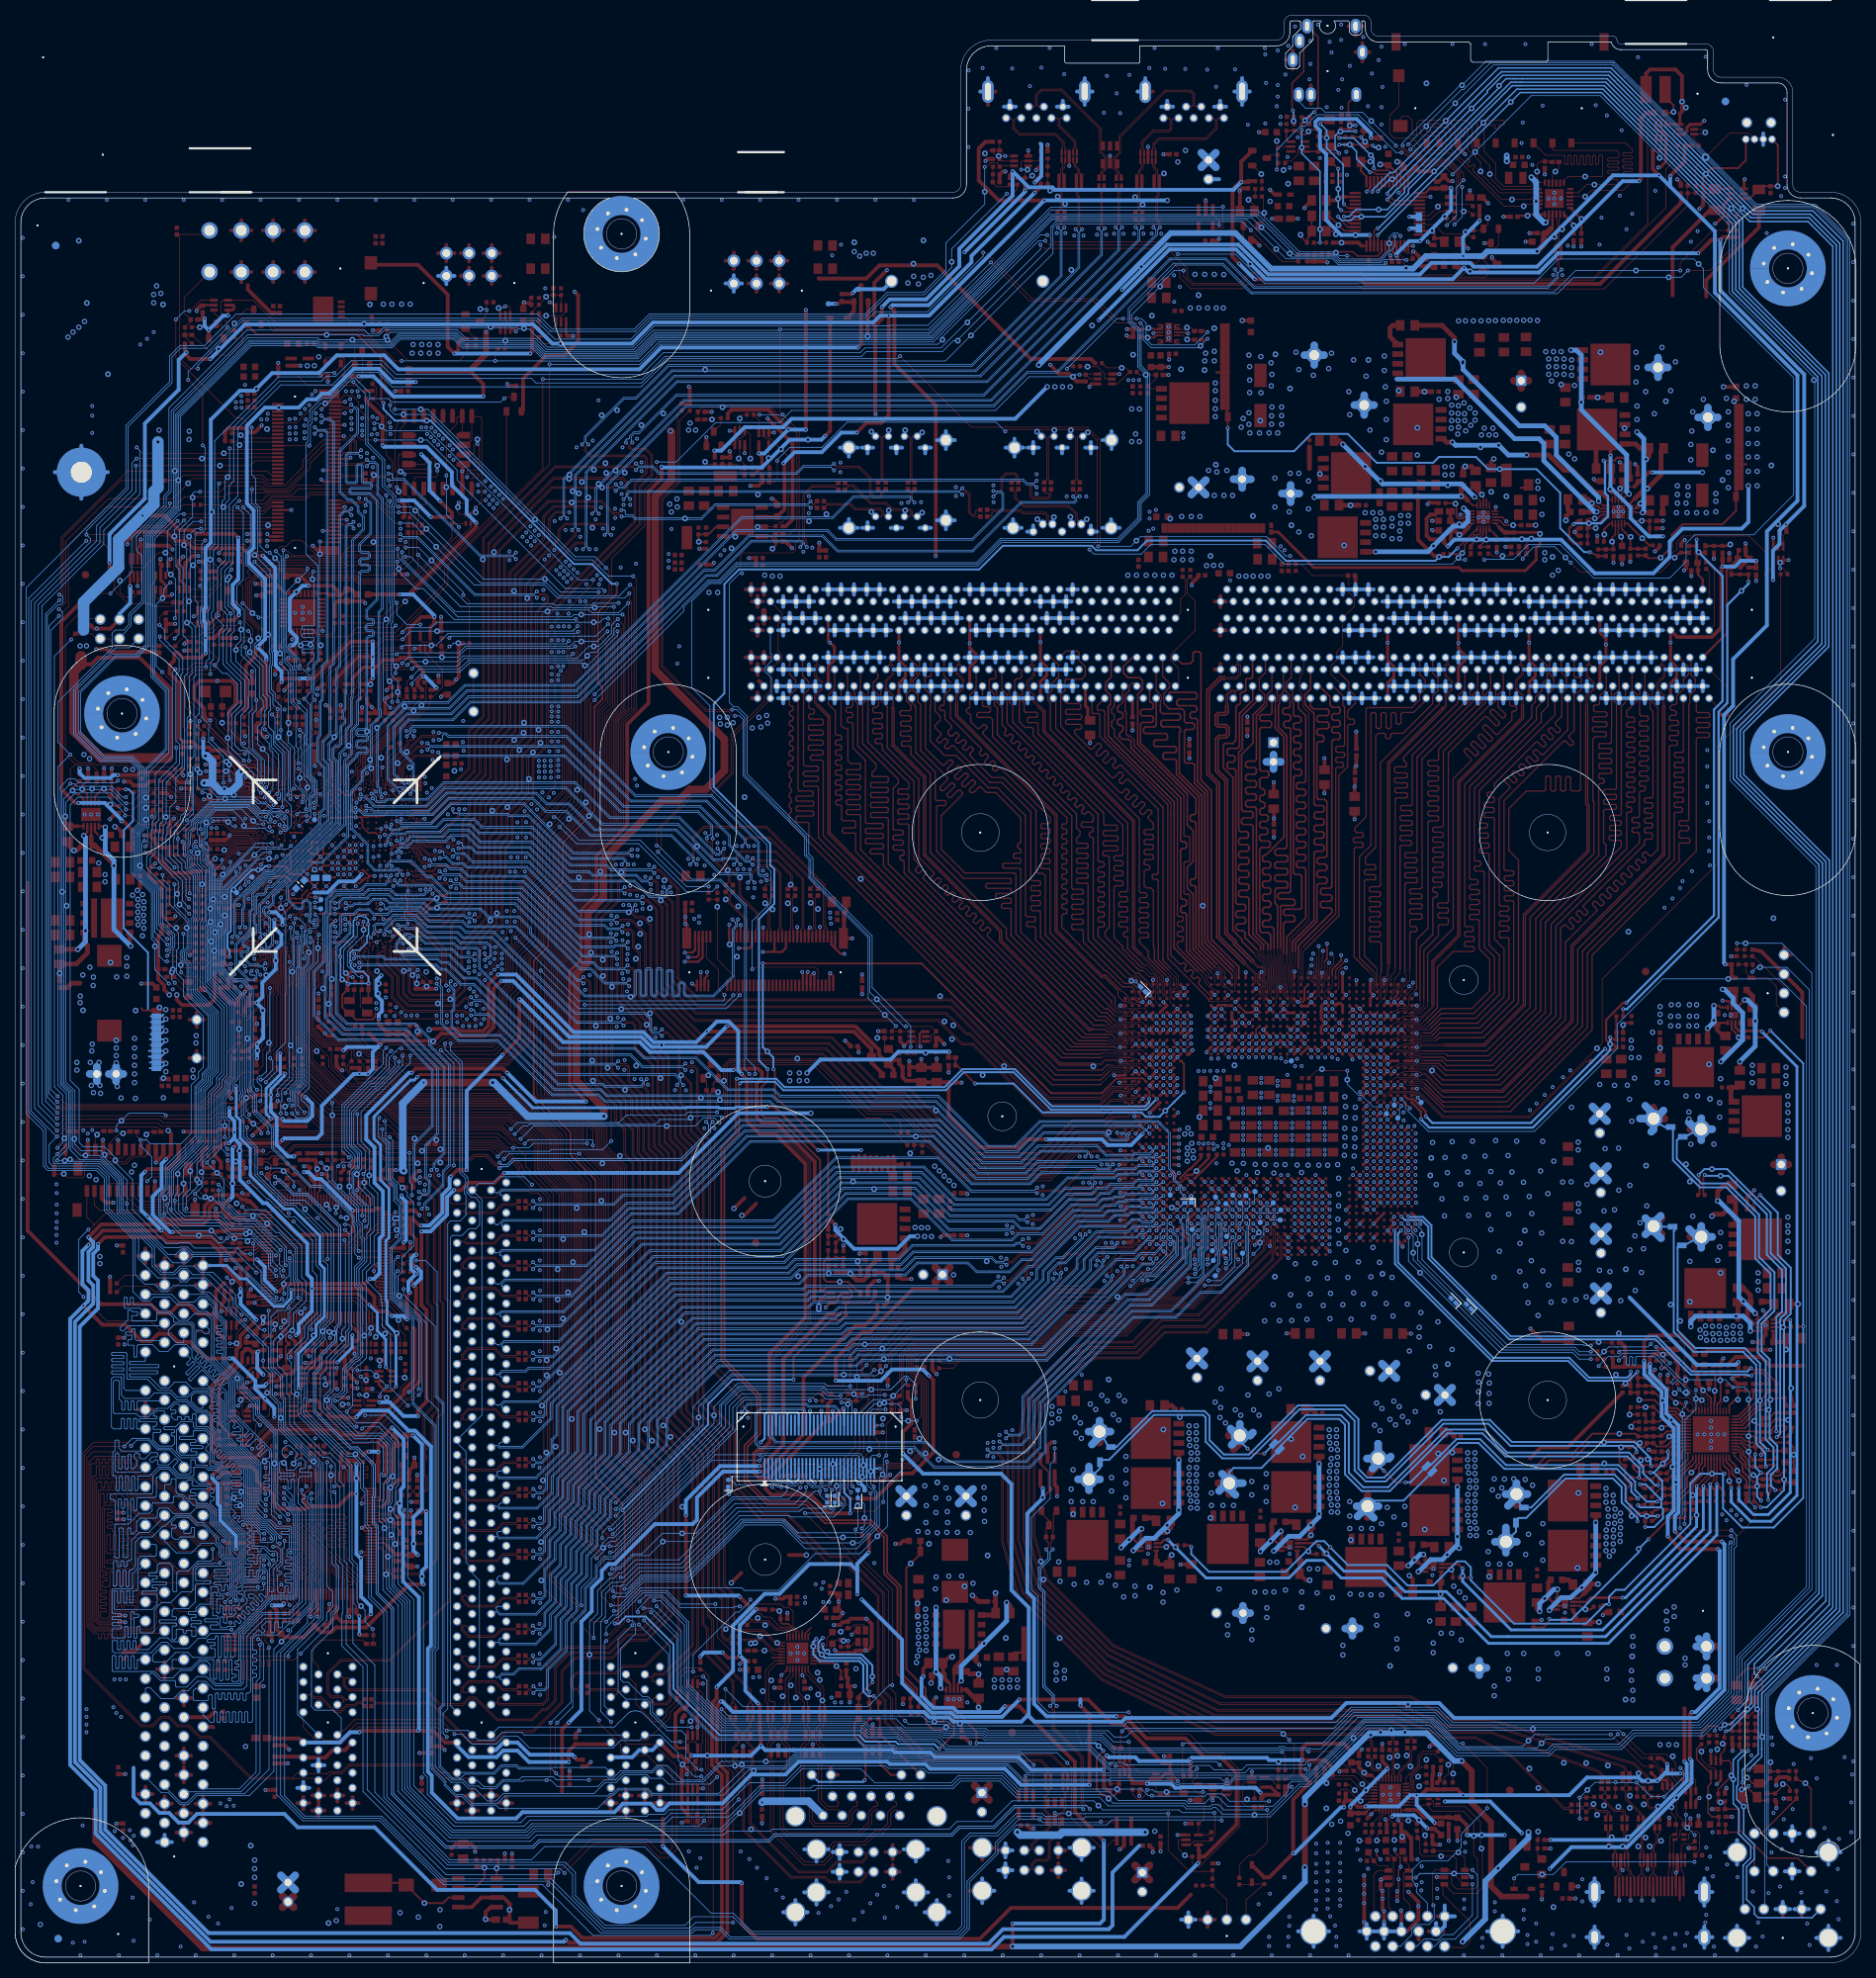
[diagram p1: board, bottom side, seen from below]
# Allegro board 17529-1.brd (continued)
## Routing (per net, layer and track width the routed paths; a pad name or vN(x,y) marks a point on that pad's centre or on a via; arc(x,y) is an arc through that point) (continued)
PEG_RX_CPU_N6: length 107.7
  TOP w0.102: CPU1.H5 93.57,99.67 93.44,99.54 v2(93.12,99.54)
  BOTTOM w0.102: SLOT2.A44 180.12,64.99 180.29,64.82 180.29,64.54 179.96,64.21 175.18,64.21 171.72,67.68 171.72,73.44 156.77,88.39 139.5,88.39 139.05,88.84 113.45,88.84 110.12,92.16 109.56,92.16 103.59,98.13 99.48,98.13 98.72,98.89 96.95,98.89 96.56,99.29 93.36,99.29 v2(93.12,99.54)
PEG_RX_CPU_N7: length 104.7
  TOP w0.102: CPU1.J4 v2(94.03,100.45)
  BOTTOM w0.102: SLOT2.A48 179.91,68.7 180.06,68.55 180.06,68.4 179.92,68.26 176.98,68.26 173.25,71.98 173.25,73.95 157.32,89.88 140.36,89.88 139.24,91 126.38,91 124.77,92.61 118.01,92.61 116.84,91.44 112.57,91.44 110.99,93.03 109.69,93.03 103.88,98.84 100.2,98.84 99.52,99.53 97.43,99.53 96.89,100.08 95.24,100.08 95.06,99.9 93.78,99.9 93.57,100.11 93.57,100.11 93.57,100.3 93.72,100.45 v2(94.03,100.45)
PEG_RX_CPU_N8: length 100.4
  TOP w0.102: CPU1.K5 93.57,101.47 93.47,101.36 v2(93.12,101.36)
  BOTTOM w0.102: v2(93.12,101.36) 93.34,101.14 95.2,101.14 95.41,100.93 97.08,100.93 97.29,100.71 98.13,100.71 98.62,100.23 99.99,100.23 100.66,99.56 104.15,99.56 109.64,94.07 125.29,94.07 126.96,92.39 140.66,92.39 141.78,91.27 157.9,91.27 174.9,74.28 179.41,74.28 180.01,73.69 180.21,73.69 SLOT2.A53
PEG_RX_CPU_N9: length 103.4
  TOP w0.102: CPU1.L4 v2(94.03,102.28)
  BOTTOM w0.102: v2(94.03,102.28) 93.79,102.28 93.66,102.15 93.66,101.93 93.87,101.73 97.27,101.73 97.65,101.35 98.72,101.35 98.98,101.08 100.25,101.08 101.04,100.29 104.41,100.29 108.24,96.46 111.44,96.46 112.27,95.63 120.09,95.63 125.55,101.09 133.94,101.09 142.36,92.67 159.4,92.67 173.38,78.69 176.17,78.69 176.57,78.29 179.68,78.29 180.05,77.92 180.13,77.76 180.27,77.71 SLOT2.A57
PEG_RX_CPU_N10: length 102.2
  TOP w0.102: v2(93.12,103.19) 93.44,103.19 93.57,103.33 CPU1.M5
  BOTTOM w0.102: SLOT2.A61 180.16,81.66 179.99,81.66 179.41,82.23 172.15,82.23 160.15,94.23 142.81,94.23 134.56,102.49 124.97,102.49 120.62,98.13 112,98.13 111.04,97.17 108.52,97.17 104.7,100.99 101.32,100.99 100.53,101.78 99.39,101.78 98.68,102.49 95.68,102.49 95.2,102.97 93.34,102.97 v2(93.12,103.19)
PEG_RX_CPU_N11: length 99.8
  TOP w0.102: v2(94.03,104.11) CPU1.N4
  BOTTOM w0.102: v2(94.03,104.11) 93.81,104.11 93.69,103.98 93.69,103.66 93.81,103.53 95.73,103.53 96.27,103 99.29,103 99.81,102.48 100.79,102.48 100.96,102.48 101.74,101.7 105.03,101.7 107.12,99.61 120.11,99.61 124.39,103.89 135.14,103.89 143.14,95.89 161.8,95.89 171.51,86.17 179.79,86.17 180.07,85.89 180.13,85.76 180.27,85.71 SLOT2.A65
PEG_RX_CPU_N12: length 98.8
  TOP w0.102: v2(93.12,105.02) 93.44,105.02 93.57,105.16 CPU1.P5
  BOTTOM w0.102: SLOT2.A69 180.18,89.67 179.97,89.7 179.31,90.36 169.35,90.36 162.37,97.35 143.65,97.35 135.72,105.28 123.81,105.28 119.53,101 107.73,101 104.89,103.85 98.72,103.85 98.22,104.35 95.69,104.35 95.28,104.76 93.38,104.76 93.32,104.82 93.27,104.87 v2(93.12,105.02)
PEG_RX_CPU_N13: length 98.5
  TOP w0.102: CPU1.R4 v2(94.03,105.94)
  BOTTOM w0.102: v2(94.03,105.94) 93.69,105.94 93.57,105.82 93.57,105.58 93.69,105.46 95.53,105.46 95.96,105.03 98.41,105.03 98.89,104.55 108.38,104.55 109.85,103.07 117.5,103.07 123.09,108.66 146.86,108.66 156.4,99.12 162.57,99.12 167.4,94.28 179.69,94.28 180.05,93.92 180.42,93.79 SLOT2.A73
PEG_RX_CPU_N14: length 97.5
  TOP w0.102: CPU1.T5 93.57,106.98 93.44,106.85 v2(93.12,106.85)
  BOTTOM w0.102: SLOT2.A77 180.4,97.56 180.15,97.56 179.48,98.23 165.43,98.23 163.15,100.52 157.14,100.52 147.6,110.06 122.27,110.06 116.69,104.47 115.53,104.47 110.44,104.47 108.89,106.02 100.84,106.02 100.65,106.21 95.72,106.21 95.34,106.59 93.37,106.59 v2(93.12,106.85)
PEG_RX_CPU_N15: length 96.8
  TOP w0.102: CPU1.U4 v2(94.03,107.77)
  BOTTOM w0.102: SLOT2.A81 180.36,101.76 180.21,101.76 179.71,102.26 157.37,102.26 148.17,111.47 121.71,111.47 116.11,105.87 111.02,105.87 108.81,108.08 100.97,108.08 99.72,106.83 96.32,106.83 96.12,107.02 94.04,107.02 93.69,107.37 93.69,107.62 93.84,107.77 v2(94.03,107.77)
PEG_RX_CPU_P0: length 126.1
  TOP w0.102: CPU1.B8 91.1,94.24 91.1,93.28 92.01,92.37 95.47,92.37 95.85,92.75 97.15,92.75 97.25,92.65 97.25,92.3 v2(96.99,92.04)
  BOTTOM w0.102: v2(96.99,92.04) 97.28,91.75 97.28,90.86 107.9,80.24 132.47,80.24 133.21,79.5 151.13,79.5 158.95,71.68 158.95,68.23 165.9,61.28 165.9,59.17 167.65,57.42 167.65,55.41 169.01,54.05 169.01,51.39 170.35,50.06 170.35,46.76 171.74,45.36 171.74,41.41 174.38,38.77 174.56,38.77 174.56,38.77 177.33,38.77 178.05,38.05 179.6,38.05 179.89,37.76 179.94,37.66 179.89,37.53 SLOT2.A16
PEG_RX_CPU_P1: length 120.8
  TOP w0.102: v2(92.2,94.96) CPU1.C7
  BOTTOM w0.102: SLOT2.A21 180.59,42.37 180.21,42.37 179.88,42.04 175.13,42.04 173.14,44.03 173.14,45.94 171.74,47.34 171.74,50.64 170.41,51.97 170.41,54.63 169.05,55.99 169.05,58 167.3,59.75 167.3,61.91 161.46,67.75 161.46,71.16 151.71,80.9 133.79,80.9 133.05,81.64 109.63,81.64 98.42,92.84 95.96,92.84 95.16,93.64 93.28,93.64 92.39,94.53 92.39,94.77 v2(92.2,94.96)
PEG_RX_CPU_P2: length 118.5
  TOP w0.102: v2(93.12,95.88) 92.66,96.34 CPU1.D6
  BOTTOM w0.102: SLOT2.A25 180.54,46.39 180.38,46.39 179.96,45.97 175.08,45.97 173.14,47.92 173.14,51.22 171.81,52.55 171.81,55.21 170.44,56.57 170.44,58.58 168.69,60.33 168.69,62.49 163.91,67.28 163.91,71.25 152.86,82.3 134.36,82.3 133.63,83.03 110.21,83.03 101.74,91.5 101.74,92.77 100.79,93.73 96.02,93.73 94.34,95.41 93.58,95.41 v2(93.12,95.88)
PEG_RX_CPU_P3: length 114.1
  TOP w0.102: v2(94.03,96.79) CPU1.E5
  BOTTOM w0.102: v2(94.03,96.79) 94.87,96.32 95.11,96.32 95.64,95.8 100.72,95.8 103.52,93 103.52,91.7 110.79,84.43 134.21,84.43 134.94,83.69 153.64,83.69 165.9,71.44 165.9,67.26 170.09,63.07 170.09,60.91 171.84,59.16 171.84,57.15 173.2,55.79 173.2,53.62 176.78,50.04 180.01,50.04 180.35,50.38 180.56,50.38 SLOT2.A29
PEG_RX_CPU_P4: length 112.6
  TOP w0.102: CPU1.F6 v2(92.2,97.71)
  BOTTOM w0.102: v2(92.2,97.71) 92.96,97.25 96.05,97.25 96.78,96.52 101.01,96.52 105.14,92.39 106.03,92.39 107.29,91.13 107.29,89.96 111.42,85.83 134.79,85.83 135.52,85.09 154.43,85.09 167.82,71.7 167.82,67.32 171.49,63.65 171.49,61.49 173.24,59.74 173.24,57.82 175.02,56.05 180.05,56.05 180.38,56.38 180.57,56.38 SLOT2.A35
PEG_RX_CPU_P5: length 110.2
  TOP w0.102: CPU1.G5 v2(93.12,98.62)
  BOTTOM w0.102: v2(93.12,98.62) 93.36,98.38 93.36,98.19 93.74,97.8 95.07,97.8 95.4,98.13 96.29,98.13 97.21,97.22 103.22,97.22 108.84,91.59 108.84,90.39 112,87.22 138.38,87.22 139.07,86.54 155.78,86.54 169.51,72.81 169.51,67.61 172.89,64.23 172.89,62.07 174.97,59.98 180,59.98 180.39,60.38 180.57,60.38 SLOT2.A39
PEG_RX_CPU_P6: length 107.8
  TOP w0.102: CPU1.H6 v2(92.2,99.54)
  BOTTOM w0.102: v2(92.2,99.54) 92.99,99.07 96.47,99.07 96.86,98.68 98.63,98.68 99.39,97.92 103.5,97.92 109.47,91.95 110.03,91.95 113.36,88.62 138.96,88.62 139.41,88.18 156.68,88.18 171.5,73.36 171.5,67.59 175.09,64 180.05,64 180.4,64.35 180.57,64.37 SLOT2.A43
PEG_RX_CPU_P7: length 104.6
  TOP w0.102: CPU1.J5 v2(93.12,100.45)
  BOTTOM w0.102: SLOT2.A47 180.56,68.38 180.34,68.38 180.01,68.05 176.89,68.05 173.04,71.89 173.04,73.86 157.23,89.66 140.27,89.66 139.15,90.78 126.29,90.78 124.68,92.39 118.1,92.39 116.93,91.22 112.48,91.22 110.9,92.81 109.6,92.81 103.79,98.63 100.12,98.63 99.43,99.32 97.34,99.32 96.8,99.86 95.33,99.86 95.15,99.68 93.69,99.68 93.48,99.89 93.48,99.89 93.36,100.02 93.36,100.21 v2(93.12,100.45)
PEG_RX_CPU_P8: length 100.4
  TOP w0.102: CPU1.K6 v2(92.2,101.36)
  BOTTOM w0.102: SLOT2.A52 179.6,73.38 179.69,73.56 179.67,73.73 179.32,74.07 174.81,74.07 157.81,91.06 141.69,91.06 140.57,92.18 126.87,92.18 125.2,93.85 109.55,93.85 104.06,99.34 100.57,99.34 99.9,100.01 98.53,100.01 98.04,100.5 97.2,100.5 96.99,100.71 95.32,100.71 95.11,100.93 92.99,100.93 v2(92.2,101.36)
PEG_RX_CPU_P9: length 103.4
  TOP w0.102: CPU1.L5 v2(93.12,102.28)
  BOTTOM w0.102: v2(93.12,102.28) 93.3,102.28 93.45,102.13 93.45,101.84 93.78,101.51 97.18,101.51 97.56,101.13 98.63,101.13 98.89,100.87 100.16,100.87 100.95,100.08 104.32,100.08 108.15,96.24 111.35,96.24 112.18,95.42 120.18,95.42 125.64,100.88 133.85,100.88 142.27,92.46 159.31,92.46 173.29,78.47 176.08,78.47 176.48,78.08 179.59,78.08 179.87,77.79 179.94,77.66 179.94,77.66 179.89,77.53 SLOT2.A56
PEG_RX_CPU_P10: length 102.3
  TOP w0.102: v2(92.2,103.19) CPU1.M6
  BOTTOM w0.102: SLOT2.A60 179.5,81.33 179.68,81.51 179.68,81.66 179.32,82.02 172.06,82.02 160.06,94.02 142.72,94.02 134.47,102.27 125.06,102.27 120.71,97.92 112.09,97.92 111.12,96.95 108.43,96.95 104.61,100.77 101.23,100.77 100.44,101.56 99.3,101.56 98.59,102.27 95.59,102.27 95.11,102.76 92.96,102.76 v2(92.2,103.19)
PEG_RX_CPU_P11: length 99.8
  TOP w0.102: v2(93.12,104.11) CPU1.N5
  BOTTOM w0.102: SLOT2.A64 179.89,85.53 179.94,85.66 179.89,85.76 179.7,85.95 171.42,85.95 161.71,95.67 143.05,95.67 135.05,103.67 124.48,103.67 120.2,99.39 107.03,99.39 104.94,101.49 101.65,101.49 100.88,102.26 99.72,102.26 99.2,102.78 96.18,102.78 95.64,103.32 93.72,103.32 93.47,103.57 93.47,103.75 v2(93.12,104.11)
PEG_RX_CPU_P12: length 98.9
  TOP w0.102: CPU1.P6 v2(92.2,105.02)
  BOTTOM w0.102: SLOT2.A68 179.55,89.36 179.68,89.48 179.68,89.69 179.22,90.14 169.26,90.14 162.28,97.13 143.56,97.13 135.63,105.07 123.9,105.07 119.62,100.79 107.64,100.79 104.8,103.63 98.63,103.63 98.13,104.13 95.6,104.13 95.19,104.54 93.04,104.54 v2(92.2,105.02)
PEG_RX_CPU_P13: length 98.4
  TOP w0.102: CPU1.R5 v2(93.12,105.94)
  BOTTOM w0.102: v2(93.12,105.94) 93.36,105.7 93.36,105.49 93.6,105.25 95.44,105.25 95.87,104.82 98.32,104.82 98.8,104.33 108.29,104.33 109.76,102.86 117.59,102.86 123.18,108.45 146.77,108.45 156.31,98.91 162.48,98.91 167.31,94.07 179.6,94.07 179.87,93.79 179.94,93.66 179.89,93.53 SLOT2.A72
PEG_RX_CPU_P14: length 97.4
  TOP w0.102: CPU1.T6 v2(92.2,106.85)
  BOTTOM w0.102: v2(92.2,106.85) 92.99,106.38 95.25,106.38 95.63,106 100.56,106 100.75,105.8 108.8,105.8 110.35,104.26 115.44,104.26 116.78,104.26 122.36,109.84 147.51,109.84 157.05,100.3 163.06,100.3 165.34,98.02 179.39,98.02 179.68,97.73 179.68,97.49 179.55,97.35 SLOT2.A76
PEG_RX_CPU_P15: length 96.8
  TOP w0.102: CPU1.U5 v2(93.12,107.77)
  BOTTOM w0.102: v2(93.12,107.77) 93.2,107.77 93.48,107.49 93.48,107.28 93.95,106.81 96.03,106.81 96.23,106.62 99.81,106.62 101.06,107.86 108.72,107.86 110.93,105.65 116.2,105.65 121.8,111.25 148.08,111.25 157.28,102.04 179.62,102.04 179.89,101.77 179.89,101.65 179.82,101.49 SLOT2.A80
PEG_TX_CON_N0: length 10.1
  TOP w0.102: C9304.2 177.71,36 179.56,36 180.61,37.05 184.03,37.05 184.77,36.32 184.77,35.86 184.65,35.74 184.34,35.74 SLOT2.B15
PEG_TX_CON_N1: length 10
  TOP w0.102: SLOT2.B20 185.13,40.89 185.04,40.72 185.04,40.01 184.05,39.02 180.56,39.02 179.52,40.07 177.77,40.07 C9302.2
PEG_TX_CON_N2: length 9.9
  TOP w0.102: C9303.2 177.8,44 179.58,44 180.56,43.02 184.05,43.02 185.04,44.01 185.04,44.72 185.13,44.89 SLOT2.B24
PEG_TX_CON_N3: length 10.1
  TOP w0.102: SLOT2.B28 185.13,48.89 185.04,48.72 185.04,48.01 184.05,47.02 180.56,47.02 179.5,48.08 177.74,48.08 C9308.2
PEG_TX_CON_N4: length 9.9
  TOP w0.102: SLOT2.B34 185.15,54.9 185.04,54.69 185.04,54.01 184.05,53.02 180.27,53.02 179.41,53.88 177.74,53.88 C9313.2
PEG_TX_CON_N5: length 10
  TOP w0.102: C9315.2 177.69,57.96 179.5,57.96 180.44,57.02 184.05,57.02 184.99,57.96 184.99,58.67 185.07,58.86 SLOT2.B38
PEG_TX_CON_N6: length 10
  TOP w0.102: C9317.2 177.69,62.03 179.35,62.03 180.35,61.02 184.05,61.02 184.99,61.96 184.99,62.69 185.07,62.86 SLOT2.B42
PEG_TX_CON_N7: length 10
  TOP w0.102: SLOT2.B46 185.07,66.86 184.99,66.78 184.99,65.96 184.05,65.02 180.31,65.02 179.32,66.01 177.74,66.01 C9319.2
PEG_TX_CON_N8: length 10
  TOP w0.102: C9321.2 177.73,72.07 179.62,72.07 180.61,73.05 184.03,73.05 184.77,72.32 184.77,71.86 184.65,71.74 184.34,71.74 SLOT2.B51
PEG_TX_CON_N9: length 10
  TOP w0.102: SLOT2.B55 184.34,75.74 184.65,75.74 184.77,75.86 184.77,76.32 184.03,77.05 180.61,77.05 179.61,76.06 177.75,76.06 C9323.2
PEG_TX_CON_N10: length 10
  TOP w0.102: SLOT2.B59 184.34,79.74 184.65,79.74 184.77,79.86 184.77,80.32 184.03,81.05 180.61,81.05 179.6,80.05 177.77,80.05 C9325.2
PEG_TX_CON_N11: length 10
  TOP w0.102: C9328.2 177.77,84.06 179.61,84.06 180.61,85.05 184.03,85.05 184.77,84.32 184.77,83.86 184.65,83.74 184.34,83.74 SLOT2.B63
PEG_TX_CON_N12: length 10
  TOP w0.102: C9331.2 177.73,88.05 179.6,88.05 180.61,89.05 184.03,89.05 184.77,88.32 184.77,87.86 184.65,87.74 184.34,87.74 SLOT2.B67
PEG_TX_CON_N13: length 10
  TOP w0.102: SLOT2.B71 184.34,91.74 184.65,91.74 184.77,91.86 184.77,92.32 184.03,93.05 180.61,93.05 179.59,92.04 177.77,92.04 C9334.2
PEG_TX_CON_N14: length 9
  TOP w0.102: C9336.2 177.75,96.21 179.73,96.21 180.73,95.21 184.34,95.21 184.51,95.39 184.51,95.6 184.39,95.71 SLOT2.B75
PEG_TX_CON_N15: length 9
  TOP w0.102: C9338.2 177.75,100.34 179.59,100.34 180.72,99.21 184.34,99.21 184.51,99.39 184.51,99.6 184.39,99.71 SLOT2.B79
PEG_TX_CON_P0: length 10.1
  TOP w0.102: C9301.2 177.71,36.22 179.47,36.22 180.52,37.27 184.12,37.27 184.99,36.41 184.99,35.71 SLOT2.B14
PEG_TX_CON_P1: length 10
  TOP w0.102: C9305.2 177.77,40.28 179.61,40.28 180.65,39.24 183.96,39.24 184.82,40.1 184.82,40.4 184.71,40.54 184.5,40.58 SLOT2.B19
PEG_TX_CON_P2: length 10
  TOP w0.102: SLOT2.B23 184.5,44.58 184.71,44.54 184.82,44.4 184.82,44.1 183.96,43.24 180.65,43.24 179.67,44.22 177.8,44.22 C9306.2
PEG_TX_CON_P3: length 10.1
  TOP w0.102: C9307.2 177.39,48.62 177.72,48.3 179.59,48.3 180.65,47.24 183.96,47.24 184.82,48.1 184.82,48.4 184.71,48.54 184.5,48.58 SLOT2.B27
PEG_TX_CON_P4: length 10
  TOP w0.102: C9309.2 177.73,54.1 179.5,54.1 180.36,53.24 183.96,53.24 184.82,54.1 184.82,54.4 184.71,54.54 184.5,54.58 SLOT2.B33
PEG_TX_CON_P5: length 9.9
  TOP w0.102: C9314.2 177.77,58.18 179.59,58.18 180.53,57.24 183.96,57.24 184.77,58.05 184.77,58.38 184.64,58.52 184.44,58.55 SLOT2.B37
PEG_TX_CON_P6: length 10
  TOP w0.102: C9316.2 177.76,62.24 179.44,62.24 180.44,61.24 183.96,61.24 184.77,62.05 184.77,62.38 184.64,62.52 184.44,62.55 SLOT2.B41
PEG_TX_CON_P7: length 9.9
  TOP w0.102: C9318.2 177.76,66.23 179.41,66.23 180.4,65.24 183.96,65.24 184.77,66.05 184.77,66.38 184.64,66.52 184.44,66.55 SLOT2.B45
PEG_TX_CON_P8: length 10
  TOP w0.102: C9320.2 177.73,72.29 179.53,72.29 180.52,73.27 184.12,73.27 184.99,72.41 184.99,71.71 SLOT2.B50
PEG_TX_CON_P9: length 10
  TOP w0.102: SLOT2.B54 184.99,75.71 184.99,76.41 184.12,77.27 180.52,77.27 179.52,76.27 177.75,76.27 C9322.2
PEG_TX_CON_P10: length 10
  TOP w0.102: SLOT2.B58 184.99,79.71 184.99,80.41 184.12,81.27 180.52,81.27 179.51,80.26 177.77,80.26 C9324.2
PEG_TX_CON_P11: length 10
  TOP w0.102: SLOT2.B62 184.99,83.71 184.99,84.41 184.12,85.27 180.52,85.27 179.52,84.28 177.77,84.28 C9326.2
PEG_TX_CON_P12: length 10
  TOP w0.102: SLOT2.B66 184.99,87.71 184.99,88.41 184.12,89.27 180.52,89.27 179.51,88.26 177.73,88.26 C9329.2
PEG_TX_CON_P13: length 10
  TOP w0.102: SLOT2.B70 184.99,91.71 184.99,92.41 184.12,93.27 180.52,93.27 179.5,92.25 177.77,92.25 C9332.2
PEG_TX_CON_P14: length 8.9
  TOP w0.102: C9335.2 177.75,96 179.64,96 180.64,95 184.43,95 184.81,95.38 185.06,95.38 SLOT2.B74
PEG_TX_CON_P15: length 9
  TOP w0.102: SLOT2.B78 185.06,99.38 184.81,99.38 184.43,99 180.63,99 179.5,100.13 177.77,100.13 C9337.2
PEG_TX_CPU_N0: length 120.2
  TOP w0.102: C9304.1 176.2,35.95 175.78,35.95 v2(175.48,35.65) ; CPU1.A6 v2(93.09,93.09)
  BOTTOM w0.102: v1(157.35,69.52) 157.75,69.52 ; 157.75,69.52 157.75,68.44 165.2,60.99 165.2,58.88 166.95,57.13 166.95,55.12 168.31,53.76 168.31,51.1 169.65,49.77 169.65,46.47 171.04,45.07 171.04,41.12 173.52,38.65 173.52,36.41 173.96,35.97 175.16,35.97 v2(175.48,35.65) ; 157.75,69.52 157.75,71.9 150.86,78.79 132.74,78.79 131.99,79.54 107.61,79.54 94.91,92.24 93.66,92.24 93.42,92.48 93.42,92.76 v2(93.09,93.09)
PEG_TX_CPU_N1: length 117.4
  TOP w0.102: C9302.1 176.26,40.02 175.84,40.02 v2(175.54,39.72) ; CPU1.B5 94.07,94.01 94.78,94.01 95.27,93.51 97.5,93.51 98.93,92.08 v2(98.93,90.81)
  BOTTOM w0.102: 160.17,69.01 160.17,71.45 151.42,80.2 133.5,80.2 132.76,80.94 108.21,80.94 99.06,90.09 99,90.15 99,90.74 v2(98.93,90.81) ; 160.17,69.01 160.17,67.99 166.6,61.57 166.6,59.46 168.35,57.71 168.35,55.7 169.71,54.34 169.71,51.68 171.04,50.35 171.04,47.05 172.44,45.65 172.44,42.06 174.5,40.01 175.25,40.01 v2(175.54,39.72) ; 160.17,69.01 v1(159.79,69.01)
PEG_TX_CPU_N2: length 114.6
  TOP w0.102: C9303.1 176.24,44 175.92,44 v2(175.57,43.65) ; v2(100.08,92.84) 100.08,94.39 99.97,94.49 96.3,94.49 95.87,94.92 94.99,94.92 CPU1.C4
  BOTTOM w0.102: 162.71,69.04 162.71,67.48 168,62.2 168,60.04 169.74,58.29 169.74,56.28 171.11,54.92 171.11,52.26 172.44,50.93 172.44,47.63 173.86,46.2 173.86,44.53 174.39,43.99 175.23,43.99 v2(175.57,43.65) ; 162.71,69.04 v1(162.33,69.04) ; 162.71,69.04 162.71,71.17 152.28,81.6 134.08,81.6 133.34,82.33 109.92,82.33 100.32,91.93 100.11,92.14 100.11,92.8 v2(100.08,92.84)
PEG_TX_CPU_N3: length 110.9
  TOP w0.102: v2(98.3,95.14) 97.77,95.67 96.75,95.67 96.56,95.86 95.88,95.86 CPU1.D3 ; v2(175.49,47.72) 175.84,48.07 176.16,48.07 C9308.1
  BOTTOM w0.102: v1(164.77,70.08) 165.14,70.08 ; 165.14,70.08 165.14,67.03 169.39,62.78 169.39,60.62 171.14,58.87 171.14,56.86 172.5,55.5 172.5,53.3 173.86,51.94 173.86,48.46 174.29,48.03 175.18,48.03 v2(175.49,47.72) ; 165.14,70.08 165.14,71 153.15,82.99 134.65,82.99 133.92,83.73 110.5,83.73 102.59,91.64 102.59,92.91 101.1,94.4 98.72,94.4 98.46,94.65 98.46,94.98 v2(98.3,95.14)
PEG_TX_CPU_N4: length 106
  TOP w0.102: v2(175.5,53.53) 175.85,53.88 176.17,53.88 C9313.1 ; v2(105.7,91.21) 105.7,92.68 104.81,93.57 103.22,93.57 99.98,96.81 97.16,96.81 CPU1.E2
  BOTTOM w0.102: v1(166.73,70.54) 167.09,70.54 ; 167.09,70.54 167.09,67.05 170.79,63.36 170.79,61.2 172.54,59.45 172.54,57.53 173.9,56.17 173.9,54.39 174.4,53.9 175.14,53.9 v2(175.5,53.53) ; 167.09,70.54 167.09,71.23 153.93,84.39 135.23,84.39 134.5,85.13 111.08,85.13 105.7,90.5 v2(105.7,91.21)
PEG_TX_CPU_N5: length 105.2
  TOP w0.102: v2(175.49,57.66) 175.82,57.98 176.18,57.98 C9315.1 ; CPU1.F3 95.41,98.16 96,97.58 97.56,97.58 97.62,97.51 102.08,97.51 102.69,96.9 102.69,96.47 v2(102.49,96.27)
  BOTTOM w0.102: 156.21,84.99 155.41,85.79 135.81,85.79 135.08,86.53 111.71,86.53 107.99,90.25 107.99,91.42 106.32,93.09 105.46,93.09 102.78,95.77 102.78,95.97 v2(102.49,96.27) ; 156.21,84.99 v1(155.94,84.72) ; 156.21,84.99 168.71,72.49 168.71,67.42 172.19,63.94 172.19,61.78 173.93,60.03 173.93,58.34 174.36,57.92 175.03,57.92 v2(175.49,57.66)
PEG_TX_CPU_N6: length 101.8
  TOP w0.102: v2(110.01,90.45) 110.22,90.66 110.22,91.3 109.58,91.95 108.79,91.95 102.27,98.46 98.59,98.46 98.34,98.72 97.81,98.72 97.59,98.49 96.91,98.49 96.33,99.08 CPU1.G2 ; C9317.1 176.19,62.04 175.82,62.04 v2(175.49,61.71)
  BOTTOM w0.102: 170.79,71.88 170.79,72.87 156.18,87.48 139.12,87.48 138.67,87.92 112.29,87.92 110.36,89.85 110.36,90.09 110.01,90.44 v2(110.01,90.45) ; 170.79,71.88 170.79,67.31 173.65,64.45 173.65,62.62 174.29,61.98 175.23,61.98 v2(175.49,61.71) ; 170.79,71.88 v1(170.41,71.88)
PEG_TX_CPU_N7: length 99.3
  TOP w0.102: C9319.1 176.21,66 175.84,66 v2(175.52,65.68) ; CPU1.H3 95.41,99.99 96,99.41 97.53,99.41 97.62,99.32 98.67,99.32 98.82,99.16 102.18,99.16 102.18,99.16 102.56,99.16 108.99,92.74 109.78,92.74 112.51,90 112.9,90 v2(113.28,89.79)
  BOTTOM w0.102: v1(172.57,68.22) 172.94,68.22 ; 172.94,68.22 172.94,67.42 174.37,65.99 175.2,65.99 v2(175.52,65.68) ; 172.94,68.22 172.94,69.07 172.28,69.73 172.28,73.59 156.92,88.94 139.79,88.94 139.41,89.32 114.9,89.32 114.21,90 113.67,90 v2(113.28,89.79)
PEG_TX_CPU_N8: length 95.1
  TOP w0.102: v2(175.5,71.72) 175.85,72.07 176.17,72.07 C9321.1 ; CPU1.J2 96.33,100.91 96.91,100.32 97.56,100.32 97.71,100.47 98.68,100.47 99.29,99.86 102.75,99.86 102.75,99.86 103.03,99.86 109.37,93.52 111.1,93.52 112.13,92.49 112.71,92.49 v2(112.95,92.25)
  BOTTOM w0.102: 140.76,91 141.4,90.36 157.52,90.36 173.79,74.1 173.79,72.47 174.22,72.03 175.19,72.03 v2(175.5,71.72) ; 140.76,91 140.28,91.48 126.58,91.48 124.97,93.09 115.57,93.09 ; 140.76,91 v1(140.49,90.73) ; v1(115.57,92.71) 115.57,93.09 ; 115.57,93.09 114.96,93.09 114.37,92.5 113.39,92.5 v2(112.95,92.25)
PEG_TX_CPU_N9: length 92.8
  TOP w0.102: CPU1.K3 95.41,101.82 96,101.24 97.53,101.24 97.77,101 99.35,101 99.64,100.71 103.2,100.71 108.9,95.02 110.5,95.02 v2(110.77,94.75) ; v2(175.52,75.71) 175.84,76.03 176.22,76.03 C9323.1
  BOTTOM w0.102: 172.28,78.27 158.79,91.76 141.98,91.76 140.86,92.88 127.16,92.88 125.32,94.72 111.89,94.72 111.61,95 111.02,95 v2(110.77,94.75) ; 172.28,78.27 v1(172.01,78) ; 172.28,78.27 173.3,77.24 174.5,76.04 175.18,76.04 v2(175.52,75.71)
PEG_TX_CPU_N10: length 94.8
  TOP w0.102: v2(175.54,79.7) 175.89,80.05 176.21,80.05 C9325.1 ; CPU1.L2 96.33,102.74 96.91,102.15 97.7,102.15 97.82,102.27 99.19,102.27 99.86,101.6 103.83,101.6 108.97,96.47 v2(112.17,96.47)
  BOTTOM w0.102: 173.74,80.01 v1(173.74,79.64) ; 173.74,80.01 172.79,80.01 159.55,93.26 142.46,93.26 134.14,101.57 125.35,101.57 120.55,96.77 112.47,96.77 v2(112.17,96.47) ; 173.74,80.01 175.23,80.01 v2(175.54,79.7)
PEG_TX_CPU_N11: length 94.2
  TOP w0.102: CPU1.M3 95.41,103.65 96,103.07 97.51,103.07 97.79,102.78 99.8,102.78 100.22,102.36 104.06,102.36 108.32,98.11 109.86,98.11 v2(110.19,97.92) ; C9328.1 176.21,84.06 175.89,84.06 v2(175.54,83.71)
  BOTTOM w0.102: v2(175.54,83.71) 175.18,84.07 173.63,84.07 ; 173.63,84.07 171.83,84.07 161.04,94.87 142.86,94.87 134.76,102.97 124.77,102.97 120.42,98.62 111.8,98.62 111.28,98.09 110.57,98.09 v2(110.19,97.92) ; 173.63,84.07 v1(173.63,83.7)
PEG_TX_CPU_N12: length 92.3
  TOP w0.102: C9331.1 176.17,88.05 175.85,88.05 v2(175.5,87.7) ; CPU1.N2 96.33,104.56 96.91,103.98 101.2,103.98 101.51,103.67 101.51,103.38 v2(101.24,103.11)
  BOTTOM w0.102: v2(175.5,87.7) 175.17,88.03 172.29,88.03 ; 172.29,88.03 170.38,88.03 169.02,89.39 161.99,96.43 143.27,96.43 135.34,104.37 124.19,104.37 119.91,100.09 107.33,100.09 105.18,102.23 101.75,102.23 101.49,102.5 101.49,102.86 v2(101.24,103.11) ; 172.29,88.03 v1(172.29,87.67)
PEG_TX_CPU_N13: length 91.3
  TOP w0.102: C9334.1 176.21,92.04 175.89,92.04 v2(175.54,91.69) ; CPU1.P3 95.41,105.48 96,104.9 97.53,104.9 97.78,104.65 102.84,104.65 105.56,101.93 108.71,101.93 v2(108.92,101.73)
  BOTTOM w0.102: 172.29,92.02 v1(172.29,91.65) ; 172.29,92.02 175.21,92.02 v2(175.54,91.69) ; 172.29,92.02 168.37,92.02 162.44,97.96 143.73,97.96 135.4,106.28 122.03,106.28 117.61,101.87 109.06,101.87 v2(108.92,101.73)
PEG_TX_CPU_N14: length 91.1
  TOP w0.102: CPU1.R1 97,106.39 96.89,106.29 96.89,106.13 97,106.03 97.68,106.03 97.95,106.3 99.06,106.3 99.3,106.06 99.3,105.68 99.46,105.52 v2(99.66,105.52) ; v2(175.52,96.56) 175.87,96.21 176.19,96.21 C9336.1
  BOTTOM w0.102: 168.76,96.23 166.45,96.23 162.86,99.82 156.84,99.82 147.31,109.36 122.56,109.36 116.98,103.77 115.24,103.77 110.15,103.77 108.6,105.32 101.13,105.32 100.82,105.01 99.52,105.01 99.36,105.17 99.36,105.38 99.5,105.52 v2(99.66,105.52) ; 168.76,96.23 175.18,96.23 v2(175.52,96.56) ; 168.76,96.23 v1(168.76,96.6)
PEG_TX_CPU_N15: length 90.9
  TOP w0.102: v2(175.53,100.68) 175.88,100.33 176.2,100.33 C9338.1 ; CPU1.T3 95.41,107.31 96,106.72 98.89,106.72 99.32,107.16 101.6,107.16 101.71,107.06 v2(101.71,106.56)
  BOTTOM w0.102: 166.5,100.34 v1(166.5,100.71) ; 166.5,100.34 175.19,100.34 v2(175.53,100.68) ; 166.5,100.34 164.91,100.34 163.69,101.56 157.66,101.56 157.08,101.56 147.88,110.77 122,110.77 116.4,105.17 115.82,105.17 110.73,105.17 108.52,107.38 102.26,107.38 102.01,107.13 102.01,106.86 v2(101.71,106.56)
PEG_TX_CPU_P0: length 120.1
  TOP w0.102: CPU1.A5 93.57,93.22 93.7,93.09 v2(93.98,93.09) ; C9301.1 176.1,36.17 175.88,36.17 v2(175.48,36.57)
  BOTTOM w0.102: 157.96,71.02 v1(158.34,71.02) ; 157.96,71.02 157.96,71.99 150.95,79.01 132.83,79.01 132.08,79.76 107.7,79.76 95,92.46 93.75,92.46 93.64,92.57 93.64,92.75 v2(93.98,93.09) ; 157.96,71.02 157.96,68.53 165.42,61.08 165.42,58.97 167.17,57.22 167.17,55.21 168.53,53.85 168.53,51.19 169.86,49.86 169.86,46.56 171.26,45.16 171.26,41.21 173.74,38.74 173.74,36.5 174.05,36.18 175.09,36.18 v2(175.48,36.57)
PEG_TX_CPU_P1: length 117.3
  TOP w0.102: C9305.1 176.16,40.23 175.94,40.23 v2(175.54,40.63) ; v2(99.69,90.81) 99.69,91.14 99.57,91.26 99.28,91.26 99.15,91.39 99.15,92.16 97.59,93.73 95.36,93.73 94.87,94.22 94.77,94.22 CPU1.B4
  BOTTOM w0.102: v1(160.76,70.51) 160.39,70.51 ; 160.39,70.51 160.39,71.54 151.51,80.42 133.59,80.42 132.85,81.15 108.3,81.15 99.21,90.24 99.21,90.45 99.57,90.81 v2(99.69,90.81) ; 160.39,70.51 160.39,68.08 166.81,61.66 166.81,59.55 168.56,57.8 168.56,55.79 169.93,54.43 169.93,51.77 171.26,50.44 171.26,47.14 172.66,45.74 172.66,42.15 174.59,40.22 175.43,40.22 175.54,40.34 v2(175.54,40.63)
PEG_TX_CPU_P2: length 114.5
  TOP w0.102: CPU1.C3 95.68,95.14 95.96,95.14 96.39,94.71 100.06,94.71 100.29,94.48 100.29,93.46 100.43,93.32 100.84,93.32 100.97,93.19 v2(100.97,92.84) ; C9306.1 176.24,44.22 175.92,44.22 v2(175.57,44.57)
  BOTTOM w0.102: v2(175.57,44.57) 175.21,44.21 174.48,44.21 174.08,44.62 174.08,46.29 172.66,47.72 172.66,51.02 171.32,52.35 171.32,55.01 169.96,56.37 169.96,58.38 168.21,60.13 168.21,62.29 162.93,67.57 162.93,70.08 ; 162.93,70.08 162.93,71.26 152.37,81.81 134.16,81.81 133.43,82.55 110.01,82.55 100.47,92.09 100.33,92.23 100.33,92.46 100.71,92.84 v2(100.97,92.84) ; 162.93,70.08 v1(163.3,70.08)
PEG_TX_CPU_P3: length 110.8
  TOP w0.102: v2(175.49,48.63) 175.84,48.28 176.16,48.28 C9307.1 ; CPU1.D2 96.39,96.34 96.84,95.89 97.86,95.89 98.06,95.68 98.88,95.68 99.06,95.5 v2(99.06,95.17)
  BOTTOM w0.102: 174.08,50.55 174.08,48.55 174.38,48.25 175.11,48.25 v2(175.49,48.63) ; 174.08,50.55 v1(174.45,50.55) ; 174.08,50.55 174.08,52.03 172.72,53.39 172.72,55.59 171.36,56.95 171.36,58.96 169.61,60.71 169.61,62.87 165.35,67.12 165.35,71.09 153.24,83.21 134.74,83.21 134.01,83.95 110.59,83.95 102.81,91.73 102.81,93 101.19,94.61 98.81,94.61 98.68,94.74 98.68,94.92 98.93,95.17 v2(99.06,95.17)
PEG_TX_CPU_P4: length 106
  TOP w0.102: v2(106.55,91.14) 106.55,91.54 106.43,91.67 106.05,91.67 105.92,91.8 105.92,92.77 104.9,93.79 103.31,93.79 100.07,97.03 97.45,97.03 CPU1.E1 ; v2(175.5,54.45) 175.85,54.1 176.17,54.1 C9309.1
  BOTTOM w0.102: v2(175.5,54.45) 175.17,54.11 174.48,54.11 174.12,54.48 174.12,55.63 ; 174.12,55.63 174.12,56.26 172.75,57.62 172.75,59.54 171.01,61.29 171.01,63.45 167.31,67.14 167.31,71.32 154.02,84.61 135.32,84.61 134.59,85.34 111.17,85.34 105.92,90.59 105.92,90.78 106.27,91.14 v2(106.55,91.14) ; 174.12,55.63 v1(174.49,55.63)
PEG_TX_CPU_P5: length 105.1
  TOP w0.102: v2(103.25,96.27) 102.91,96.61 102.91,96.99 102.17,97.73 97.71,97.73 97.65,97.8 96.09,97.8 95.98,97.9 95.98,98.06 96.09,98.16 CPU1.F2 ; C9314.1 176.14,58.2 175.87,58.2 v2(175.49,58.57)
  BOTTOM w0.102: 137.77,86 155.5,86 168.92,72.58 168.92,67.51 172.4,64.03 172.4,61.87 174.15,60.12 174.15,58.43 174.45,58.14 175.06,58.14 v2(175.49,58.57) ; 137.77,86 135.9,86 135.17,86.74 111.8,86.74 108.2,90.34 108.2,91.51 106.41,93.31 105.55,93.31 103,95.86 103,96.01 v2(103.25,96.27) ; 137.77,86 v1(137.77,86.39)
PEG_TX_CPU_P6: length 101.7
  TOP w0.102: C9316.1 176.14,62.25 175.87,62.25 v2(175.49,62.63) ; v2(110.85,90.41) 110.44,90.82 110.44,91.39 109.67,92.16 108.88,92.16 102.36,98.68 98.68,98.68 98.42,98.93 97.72,98.93 97.5,98.71 97,98.71 96.89,98.82 96.89,98.97 97,99.08 97,99.08 CPU1.G1
  BOTTOM w0.102: 173.86,63.78 173.86,62.71 174.38,62.19 175.06,62.19 v2(175.49,62.63) ; 173.86,63.78 v1(174.23,63.78) ; 173.86,63.78 173.86,64.54 171.01,67.4 171.01,72.96 156.27,87.69 139.21,87.69 138.76,88.14 112.38,88.14 110.58,89.94 110.58,90.14 v2(110.85,90.41)
PEG_TX_CPU_P7: length 99.3
  TOP w0.102: v2(113.28,90.55) 112.95,90.22 112.6,90.22 109.87,92.95 109.08,92.95 102.65,99.38 102.27,99.38 102.27,99.38 98.91,99.38 98.75,99.53 97.71,99.53 97.62,99.62 96.09,99.62 95.98,99.73 95.98,99.88 96.09,99.99 96.09,99.99 CPU1.H2 ; C9318.1 176.16,66.22 175.89,66.22 v2(175.52,66.59)
  BOTTOM w0.102: v2(175.52,66.59) 175.13,66.21 174.46,66.21 173.51,67.16 ; v2(113.28,90.55) 113.61,90.22 114.3,90.22 114.99,89.53 139.5,89.53 139.88,89.15 157.01,89.15 172.49,73.68 172.49,69.82 173.15,69.16 173.15,67.51 173.51,67.16 ; 173.51,67.16 v1(173.79,67.44)
PEG_TX_CPU_P8: length 94.6
  TOP w0.102: C9320.1 176.17,72.29 175.85,72.29 v2(175.5,72.63) ; CPU1.J1 97,100.91 97,100.91 96.89,100.8 96.89,100.65 97,100.54 97.48,100.54 97.62,100.69 98.77,100.69 99.38,100.08 102.84,100.08 102.84,100.08 103.12,100.08 109.46,93.74 111.19,93.74 112.22,92.71 112.62,92.71 v2(112.97,93.06)
  BOTTOM w0.102: 174,73.63 174,74.19 157.61,90.58 141.49,90.58 140.37,91.69 126.67,91.69 125.06,93.31 114.87,93.31 114.28,92.71 113.31,92.71 v2(112.97,93.06) ; 174,73.63 174,72.56 174.31,72.25 175.12,72.25 v2(175.5,72.63) ; 174,73.63 v1(174.37,73.63)
PEG_TX_CPU_P9: length 92.7
  TOP w0.102: CPU1.K2 96.23,101.82 96.09,101.82 95.98,101.71 95.98,101.56 96.09,101.45 97.62,101.45 97.86,101.22 99.44,101.22 99.73,100.93 103.29,100.93 108.98,95.23 110.39,95.23 v2(110.77,95.61) ; v2(175.52,76.62) 175.89,76.25 176.16,76.25 C9322.1
  BOTTOM w0.102: v2(175.52,76.62) 175.16,76.26 174.59,76.26 173.47,77.38 ; v1(173.74,77.65) 173.47,77.38 ; 173.47,77.38 158.88,91.97 142.07,91.97 140.95,93.09 127.25,93.09 125.41,94.93 111.98,94.93 111.7,95.21 111.17,95.21 v2(110.77,95.61)
PEG_TX_CPU_P10: length 94.8
  TOP w0.102: CPU1.L1 97.09,102.74 97.09,102.74 97,102.74 96.89,102.63 96.89,102.48 97,102.37 97.61,102.37 97.73,102.49 99.28,102.49 99.95,101.82 103.92,101.82 109.05,96.69 111.62,96.69 112.17,97.23 v2(112.16,97.23) ; v2(175.54,80.61) 175.89,80.26 176.21,80.26 C9324.1
  BOTTOM w0.102: 172.2,80.91 v1(172.47,81.18) ; 172.2,80.91 172.88,80.23 175.16,80.23 v2(175.54,80.61) ; 172.2,80.91 159.64,93.47 142.55,93.47 134.23,101.79 125.26,101.79 120.46,96.99 112.41,96.99 112.17,97.23 112.17,97.23 v2(112.16,97.23)
PEG_TX_CPU_P11: length 94.1
  TOP w0.102: CPU1.M2 96.09,103.65 95.98,103.54 95.98,103.39 96.09,103.28 97.6,103.28 97.88,103 99.89,103 100.31,102.58 104.15,102.58 108.41,98.32 109.86,98.32 v2(110.19,98.65) ; v2(175.54,84.62) 175.89,84.28 176.21,84.28 C9326.1
  BOTTOM w0.102: v2(110.19,98.65) 110.53,98.31 111.19,98.31 111.71,98.83 120.33,98.83 124.68,103.19 134.85,103.19 142.95,95.08 161.13,95.08 171.32,84.89 ; 171.32,84.89 v1(171.59,85.15) ; 171.32,84.89 171.92,84.29 175.21,84.29 v2(175.54,84.62)
PEG_TX_CPU_P12: length 92.3
  TOP w0.102: v2(175.5,88.61) 175.85,88.26 176.17,88.26 C9329.1 ; CPU1.N1 97,104.56 97,104.57 96.89,104.46 96.89,104.3 97,104.2 101.29,104.2 101.73,103.76 101.73,103.43 v2(102.05,103.11)
  BOTTOM w0.102: v2(175.5,88.61) 175.14,88.25 170.92,88.25 ; v2(102.05,103.11) 101.84,103.11 101.7,102.97 101.7,102.59 101.84,102.45 105.27,102.45 107.42,100.3 119.82,100.3 124.1,104.58 135.43,104.58 143.36,96.65 162.08,96.65 170.47,88.25 170.92,88.25 ; 170.92,88.25 v1(170.92,88.62)
PEG_TX_CPU_P13: length 91.2
  TOP w0.102: v2(108.89,102.46) 108.57,102.15 105.65,102.15 102.93,104.86 97.87,104.86 97.62,105.11 96.09,105.11 95.98,105.22 95.98,105.37 96.09,105.48 CPU1.P2 ; C9332.1 176.21,92.25 175.89,92.25 v2(175.54,92.6)
  BOTTOM w0.102: v2(108.89,102.46) 109.27,102.08 117.53,102.08 121.94,106.5 135.49,106.5 143.82,98.17 162.53,98.17 168.46,92.24 170.26,92.24 ; 170.26,92.24 175.18,92.24 v2(175.54,92.6) ; 170.26,92.24 v1(170.26,92.61)
PEG_TX_CPU_P14: length 91.2
  TOP w0.102: CPU1.R2 96.33,106.39 96.91,105.81 97.77,105.81 98.04,106.08 98.97,106.08 99.09,105.97 99.09,105.76 v2(98.85,105.52) ; C9335.1 176.19,96 175.87,96 v2(175.52,95.65)
  BOTTOM w0.102: v2(98.85,105.52) 99,105.52 99.15,105.37 99.15,105.08 99.43,104.8 100.91,104.8 101.22,105.11 108.51,105.11 110.06,103.56 115.15,103.56 117.07,103.56 122.65,109.14 147.22,109.14 156.76,99.61 162.77,99.61 166.36,96.01 171.55,96.01 ; 171.55,96.01 v1(171.55,95.64) ; 171.55,96.01 175.16,96.01 v2(175.52,95.65)
PEG_TX_CPU_P15: length 91
  TOP w0.102: v2(102.52,106.56) 102.51,106.56 101.69,107.38 99.23,107.38 98.8,106.94 96.09,106.94 95.98,107.05 95.98,107.2 96.09,107.31 CPU1.T2 ; v2(175.53,99.76) 175.88,100.11 176.2,100.11 C9337.1
  BOTTOM w0.102: v1(169.77,99.76) 169.77,100.12 ; 169.77,100.12 175.17,100.12 v2(175.53,99.76) ; 169.77,100.12 164.82,100.12 163.6,101.35 157.75,101.35 156.99,101.35 147.79,110.55 122.09,110.55 116.49,104.95 115.73,104.95 110.64,104.95 108.43,107.16 102.35,107.16 102.22,107.04 102.22,106.86 v2(102.52,106.56)
PF_MIC2_LL: length 18.3
  TOP w0.203: R2902.2 v2(71.5,227.33) R2901.2 ; FL2901.1 v2(73.91,242.24)
  BOTTOM w0.203: v2(73.91,242.24) v1(73.91,239.9) 73.91,239.14 71.5,236.73 v1(71.5,229.11) v2(71.5,227.33)
PFRAME#: length 65.6
  TOP w0.102: v2(216.26,47.68) 216.26,46.93 RN9504.1 218.06,46.84 218.19,46.96 218.19,47.22 218.08,47.32 216.97,47.32 216.87,47.42 216.87,47.62 216.97,47.73 218.57,47.73 218.67,47.83 218.67,48.03 218.57,48.13 216.97,48.13 216.87,48.23 216.87,48.44 216.97,48.54 218.08,48.54 218.19,48.64 218.19,48.84 218.08,48.95 216.97,48.95 216.87,49.05 216.87,49.25 216.97,49.35 218.08,49.35 218.19,49.45 218.19,49.66 218.08,49.76 216.97,49.76 216.87,49.86 216.87,50.06 216.97,50.16 218.08,50.16 218.19,50.27 218.19,50.82 217.62,51.38 217.37,51.38 217.27,51.28 217.27,50.72 217.17,50.62 216.96,50.62 216.86,50.72 216.86,51.28 216.76,51.38 216.56,51.38 216.45,51.28 216.45,50.7 216.35,50.6 216.15,50.6 216.05,50.7 216.05,51.28 215.95,51.38 215.39,51.38 214.09,52.69 U9501.71
  BOTTOM w0.102: v2(216.26,47.68) 215.47,48.47 215.47,48.97 215.86,49.36 215.86,49.87 215.96,49.97 216.22,49.97 216.32,49.87 216.32,49.28 216.42,49.17 216.62,49.17 216.73,49.28 216.73,49.87 216.83,49.97 217.6,49.97 217.7,50.07 217.7,50.27 217.6,50.38 215.96,50.38 215.86,50.48 215.86,50.68 215.96,50.78 217.6,50.78 217.7,50.88 217.7,51.09 217.6,51.19 215.96,51.19 215.86,51.29 215.86,51.49 215.96,51.6 217.6,51.6 217.7,51.7 217.7,51.9 217.6,52 215.96,52 215.86,52.1 215.86,52.98 216.76,53.88 216.76,54.9 217.45,55.58 217.45,56.16 219.15,57.87 220.04,57.87 221.06,58.88 222.67,58.88 223.34,58.21 223.34,57.96 223.24,57.86 222.81,57.86 222.71,57.76 222.71,57.55 222.81,57.45 223.19,57.45 223.29,57.35 223.29,56.31 222.96,55.99 222.42,55.99 222.13,56.28 220.4,56.28 220.29,56.38 220.29,57.48 220.37,57.56 220.62,57.56 220.73,57.45 220.73,56.97 220.95,56.74 221.62,56.74 221.7,56.83 SLOT4.67
PGNT0#: length 67.8
  TOP w0.102: RN9505.4 204.99,66.66 206.45,65.21 U9501.108 206.45,63.25 206.82,62.87 206.82,62.02 206.7,61.9 206.43,61.9 206.1,62.22 v2(206.1,62.48)
  BOTTOM w0.102: v2(206.1,62.48) 206.1,61.95 206,61.85 205.77,61.85 205.66,61.75 205.66,61.44 205.77,61.34 206,61.34 206.1,61.24 206.1,60.97 205.1,59.96 205.1,47.33 207.37,45.06 208.59,45.06 208.69,44.96 208.69,44.4 208.79,44.3 209.1,44.3 209.2,44.4 209.2,44.96 209.3,45.06 209.6,45.06 209.7,44.96 209.7,43.71 209.8,43.61 210.11,43.61 210.21,43.71 210.21,44.96 210.31,45.06 210.79,45.06 211.38,44.47 211.38,44.32 211.01,43.95 211.01,43.81 211.22,43.59 211.37,43.59 211.74,43.96 211.88,43.96 212.87,42.98 212.87,35.9 213.11,35.66 213.36,35.66 213.46,35.56 213.46,34.77 213.56,34.67 213.77,34.67 213.87,34.77 213.87,35.56 213.97,35.66 214.17,35.66 214.27,35.56 214.27,34.9 214.44,34.74 214.58,34.74 214.68,34.84 214.68,35.56 214.78,35.66 214.99,35.66 215.09,35.56 215.09,34.9 215.19,34.8 215.39,34.8 215.49,34.9 215.49,35.56 215.6,35.66 215.8,35.66 215.9,35.56 215.9,34.9 216,34.8 216.21,34.8 216.31,34.9 216.31,35.56 216.41,35.66 216.61,35.66 216.71,35.56 216.71,34.9 216.81,34.8 217.02,34.8 217.12,34.9 217.12,35.56 217.22,35.66 217.42,35.66 217.53,35.56 217.53,33.66 217.63,33.55 217.83,33.55 217.93,33.66 217.93,35.31 218.06,35.43 218.34,35.43 218.44,35.33 218.44,34.8 218.57,34.67 220.34,34.67 220.47,34.8 220.47,35.94 220.14,36.28 SLOT4.33
PGNT1#: length 3.6
  TOP w0.102: RN9501.1 209.48,66.27 v1(209.74,66.01) 209.7,65.97 209.47,65.97 208.68,65.18 208.67,65.18 208.57,65.07 208.57,65.07 208.45,64.95 U9501.103
PINTA_N: length 40.4
  TOP w0.102: RN9506.2 212.07,42.57 v2(211.86,42.77) 211.86,48.9 212.39,49.43 U9501.65
  BOTTOM w0.102: v2(211.86,42.77) 211.73,42.77 211.18,42.22 211.18,37.39 211.63,36.93 211.63,25.12 214.15,22.61 221.4,22.61 SLOT4.11
PINTB_N: length 45.1
  TOP w0.102: U9501.63 210.45,47.92 210.9,47.47 210.9,43.99 210.97,43.91 210.97,42.57 210.44,42.04 v2(210.44,41.66) 210.68,41.42 RN9506.4
  BOTTOM w0.102: v2(210.44,41.66) 210.44,25.58 213.67,22.35 220.09,22.35 221.29,21.15 222.06,21.15 223.84,22.93 224.24,23.33 SLOT4.14
PINTC_N: length 35.6
  TOP w0.102: RN9506.3 v2(211.63,42.07) 211.38,42.32 211.38,47.55 210.85,48.08 U9501.64
  BOTTOM w0.102: v2(211.63,42.07) 211.63,37.69 212.14,37.19 212.14,25.22 214.38,22.99 218.57,22.99 SLOT4.13
PINTD_N: length 65.9
  TOP w0.102: v2(204.85,61.34) 204.34,61.34 203.25,62.44 U9501.116 203.25,66.76 203.19,66.82 RN9505.1
  BOTTOM w0.102: SLOT4.16 226.78,24.6 224.66,22.48 223.75,22.48 222.17,20.9 221.17,20.9 219.96,22.1 213.03,22.1 209.8,25.33 209.8,41.45 v1(208.79,42.46) 207.47,43.78 207.47,44.24 204.55,47.16 204.55,60.49 204.85,60.79 v2(204.85,61.34)
PIRDY#: length 64.5
  TOP w0.102: U9501.70 214.05,52.29 216.33,50.01 216.33,48.5 v2(215.52,47.68) RN9504.2
  BOTTOM w0.102: v2(215.52,47.68) 215.52,47.83 215.21,48.13 215.21,49.08 215.61,49.47 215.61,53.08 216.46,53.93 216.46,54.95 217.09,55.59 217.09,56.16 219.1,58.17 219.93,58.17 220.9,59.14 222.78,59.14 224.18,57.73 224.43,57.73 225.88,56.29 227.41,56.29 228.09,55.6 228.09,52.42 228.62,51.89 228.82,51.89 228.93,51.79 228.93,49.81 229.03,49.71 229.23,49.71 229.33,49.81 229.33,51.79 229.43,51.89 229.64,51.89 229.74,51.79 229.74,49.83 229.84,49.73 230.04,49.73 230.15,49.83 230.15,51.79 230.25,51.89 230.45,51.89 230.55,51.79 230.55,49.94 230.65,49.83 230.91,49.83 230.99,49.91 230.99,53.01 230.86,53.14 230.55,53.14 230.44,53.04 230.44,52.45 230.34,52.35 230.14,52.35 230.04,52.45 230.04,53.04 229.94,53.14 229.73,53.14 229.63,53.04 229.63,52.45 229.53,52.35 229.33,52.35 229.23,52.45 229.23,53.04 229.12,53.14 228.83,53.14 228.61,53.35 228.61,55.84 227.56,56.9 226.34,56.9 224.24,59 SLOT4.70
PIRQA_N: length 17.5
  TOP w0.102: SB1.T45 197.9,155.1 197.99,155.19 197.99,156.61 198.08,156.69 198.08,157.39 197.69,157.79 197.69,159.25 192.68,164.26 192.68,165.89 v1(192.51,166.07) 192.51,166.79 R1902.1 R1917.1 R9112.2
PLOCK#: length 67.4
  TOP w0.102: v2(211.91,49.68) 211.88,49.71 210.15,49.71 210.05,49.61 U9501.62 210.05,47.98 208.39,46.33 RN9503.1
  BOTTOM w0.102: SLOT4.78 225.22,64.22 225.32,64.11 225.32,61.7 225.53,61.49 227.76,61.49 227.91,61.35 227.91,59.82 228.02,59.72 228.27,59.72 228.32,59.77 228.32,61.21 228.42,61.32 228.62,61.32 228.72,61.21 228.72,58.65 228.82,58.55 229.03,58.55 229.13,58.65 229.13,61.21 229.23,61.32 229.43,61.32 229.54,61.21 229.54,60.15 229.64,60.05 229.84,60.05 229.94,60.15 229.94,61.21 230.04,61.32 230.25,61.32 230.35,61.21 230.35,58.65 230.48,58.52 230.62,58.52 230.76,58.65 230.76,61.02 230.95,61.21 231.24,61.21 231.39,61.37 231.39,61.82 231.27,61.95 226.03,61.95 225.81,62.18 225.81,64.34 224.87,65.27 223.75,65.27 222.52,64.05 220.49,64.05 219.71,63.27 218.36,63.27 218.18,63.09 218.18,62.72 218.08,62.62 217.81,62.62 217.7,62.52 217.7,62.21 217.81,62.11 218.08,62.11 218.18,62.01 218.18,61.71 218.08,61.6 217.81,61.6 217.7,61.5 217.7,61.2 217.81,61.1 218.08,61.1 218.18,60.99 218.18,60.68 217.42,59.92 217.42,58.38 215.26,56.22 215.26,54.51 214.59,53.84 214.59,50.62 213.65,49.68 v2(211.91,49.68)
PLTRST#_PCH: length 45.6
  TOP w0.102: SB1.AV29 208.79,147.42 v2(208.79,147.7) ; R1516.1 212.58,112.55 v2(213.04,112.08) 212.96,112 R1504.1
  BOTTOM w0.102: v2(213.04,112.08) 213.04,112.26 213.46,112.67 v1(213.46,114.31) 213.56,114.41 213.56,115.3 213.66,115.4 213.66,127.47 214.25,128.06 214.25,128.07 214.26,128.07 214.26,128.12 217.22,131.08 217.22,136.48 216.9,136.8 216.9,142.63 216.9,142.97 212.42,147.45 209.04,147.45 v2(208.79,147.7)
PLTRST#_SIO: length 32.3
  TOP w0.102: v2(202.69,93.01) 203.05,92.66 208.84,92.66 209.43,92.07 U2401.14 ; R1504.2 213.85,110.93 v2(213.33,110.41)
  BOTTOM w0.102: v2(213.33,110.41) 213.36,110.38 213.36,109.16 211.99,107.79 211.99,104.21 209.99,102.21 209.96,102.21 208.18,100.42 206.47,100.42 v1(205.66,99.62) 205.66,99.31 202.69,96.34 v2(202.69,93.01)
PLTRST_BUF_LAN_N: length 109.4
  TOP w0.102: U4001.1 188.5,173.06 R4008.1 187.49,173.06 v2(186.59,173.96) ; v2(194.94,120.93) 194.56,121.31 188.29,121.31 187.29,122.3 186.13,122.3 185.83,122 181.27,122 179.96,123.31 179.96,127.21 179.96,128.42 179.15,129.23 179.15,133.95 178.36,134.73 178.36,135.64 177.5,136.5 177.5,142.56 175.79,144.26 175.79,150.49 175.79,150.74 171.7,154.83 171.7,169.64 171.7,170.14 170.71,171.14 170.71,172.14 171.02,172.44 171.02,174.47 170.81,174.68 v2(170.81,174.7) ; v2(199.87,106.43) 199.9,106.43 200.46,106.98 200.65,106.98 R2407.2
  BOTTOM w0.102: v2(170.81,174.7) 170.81,174.68 171.17,174.32 184.58,174.32 184.63,174.27 185.27,174.27 v1(185.42,174.42) 186.03,174.42 186.49,173.96 v2(186.59,173.96) ; v2(194.94,120.93) 195.33,120.55 195.33,118.79 200.79,113.33 200.79,107.34 v2(199.87,106.43)
PLTRST_BUF_PCI_N: length 159.3
  TOP w0.102: U4004.1 155.08,36.46 154.66,36.04 153.52,36.04 153.14,35.66 153.14,29.03 153.31,28.85 153.31,26.24 153.84,25.72 R4009.1 154.05,24.64 152.64,23.23 152.64,19.78 153.69,18.73 ; v2(203.58,105.74) 203.53,105.74 203.12,105.33 203.12,105.04 R2401.2 ; v2(152.91,18.8) 152.97,18.73 153.69,18.73 ; R4010.1 153.69,18.73
  BOTTOM w0.102: v2(152.91,18.8) 153.62,18.09 153.63,18.09 175.57,18.09 176.4,17.26 186.27,17.26 192.15,23.14 192.15,47.74 194.18,49.77 194.18,56.1 194.18,56.75 194.18,56.75 194.18,58.49 194.69,58.99 194.69,60.74 194.49,60.95 194.49,63.15 194.13,63.51 194.13,68.58 195.55,70 198.63,70 202.41,73.79 202.41,74.58 201.88,75.11 201.32,75.11 200.74,75.69 200.74,78.48 199.13,80.09 198.96,80.09 198.68,80.36 198.68,89.01 199.15,89.48 199.15,91.96 198.15,92.96 198.15,95.6 198.41,95.87 198.41,97.52 198.88,97.99 198.88,99.78 202.69,103.59 202.69,104.9 v1(202.8,105.01) 203.53,105.74 v2(203.58,105.74)
PLTRST_CPU_N: length 232.9
  TOP w0.102: R9910.1 C403.1 132.72,74.17 132.43,74.17 131.6,75 131.6,75.36 131.93,75.69 132.72,75.69 ; SB1.AG5 203.46,135.3 204.66,135.3 204.87,135.51 v2(204.98,135.51) ; v2(169.16,47.24) 173.33,51.41 173.33,101.42 177,105.09 177,105.36 180.33,108.69 190.78,108.69 190.9,108.81 193.17,108.81 193.98,109.63 195.78,109.63 196.71,110.55 203.34,110.55 205.19,112.4 v2(205.74,112.4) ; 132.72,75.69 v1(132.72,77.42) 132.72,80.38 132.28,80.82 131.53,80.82 126.73,85.62 109.73,85.62 106.32,89.03 100.05,89.03 97.64,91.44 94.49,91.44 v2(94.23,91.69) ; 132.72,75.69 134.09,75.69 134.85,74.93 v2(134.87,74.93) ; v2(92.2,96.79) CPU1.E7
  BOTTOM w0.102: v2(94.23,91.69) 93.7,91.69 91.77,93.62 91.77,95.14 92.02,95.4 92.33,95.4 92.63,95.7 92.63,96.36 v2(92.2,96.79) ; v2(134.87,74.93) 136.58,74.93 137.34,75.69 148.15,75.69 150.09,73.75 150.09,70.93 164.82,56.2 165.57,56.2 166.42,55.35 166.42,54.86 167.83,53.45 167.83,50.9 169.16,49.57 v2(169.16,47.24) ; v2(205.74,112.4) 206.63,113.29 206.63,114.88 205.49,116.02 205.49,131.19 204.57,132.11 204.57,135.1 v2(204.98,135.51)
PLTRST_LAN_N: length 384.9
  TOP w0.102: R9111.1 195.41,177.97 193.65,179.73 v2(193.55,179.73) ; v2(165.86,43.43) 165.43,43.43 163.83,45.03 163.83,48.01 162.69,49.14 162.69,62.46 166.52,66.29 166.52,104.04 v2(169.43,106.95) 169.82,107.34 169.82,110.07 174.52,114.76 v2(174.52,131.15) 174.52,132.3 172.77,134.05 172.77,140.6 170.81,142.56 170.81,147.73 166.67,151.87 166.67,165.56 165.63,166.6 165.63,174.52 166.17,175.06 166.17,176.4 165.64,176.93 v2(165.64,176.94) ; NGFF2.50 147.86,128.26 148.21,127.91 v2(148.21,127.89) ; U3101.19 141.16,43.82 141.71,44.37 142.87,44.37 143.61,45.11 143.61,45.16 144.15,45.69 144.98,45.69 145.52,46.23 146.77,46.23 147.66,47.12 v2(148.21,47.12) ; v2(205.1,200.5) NGFF1.52 ; Q9101.D 179.13,206.95 v2(179.32,206.76) ; v2(179.39,106.23) 179.39,106.4 180.75,107.76 184.16,107.76 184.56,107.37 190.75,107.37 191.28,107.9 194.92,107.9 195.43,108.41 196.44,108.41 197.37,109.33 209.82,109.33 210.31,108.84 215.09,108.84 215.82,109.58 216.74,109.58 217.22,109.09 220.84,109.09 221.49,108.45 221.49,106.47 223.61,104.35 226.18,104.35 227.53,103 231.41,103 231.52,102.9 LPC1.4 ; v2(186.6,175.09) R4002.1 R4008.2 188.25,173.95 188.85,174.55 190.25,174.55 190.44,174.74 U4001.4 v2(190.44,176.87)
  BOTTOM w0.102: v2(165.86,43.43) 165.86,44.3 164.49,45.67 164.25,45.67 161.03,48.9 157.99,48.9 156.06,46.96 149,46.96 148.84,47.12 v2(148.21,47.12) ; v2(186.6,175.09) 186.36,175.34 167.23,175.34 165.64,176.93 v2(165.64,176.94) ; v2(179.32,206.76) 179.83,206.25 194.18,206.25 194.67,206.73 197.13,206.73 ; v2(174.52,131.15) 169.48,126.11 149.99,126.11 v2(148.21,127.89) ; 197.13,206.73 197.36,206.5 197.36,200.86 195.15,198.65 195.15,195.28 193.68,193.8 193.68,192.76 193.9,192.53 193.9,180.09 v2(193.55,179.73) 193.55,178.21 192.21,176.87 v2(190.44,176.87) ; 197.13,206.73 197.13,207.49 199.01,209.37 199.48,209.37 202.75,206.1 v1(203,206.1) 203.61,206.1 204.72,204.98 204.72,203.53 204.97,203.29 204.97,200.64 v2(205.1,200.5) ; v2(169.43,106.95) 178.67,106.95 v2(179.39,106.23)
PLTRST_PCI_N: length 106.5
  TOP w0.102: v2(201.8,62.23) 202.31,62.23 202.85,62.77 U9501.117 ; U4007.4 153.78,19.64 R4010.2 154.04,19.62 154.25,19.41 154.25,18.45 154.09,18.29 152.81,18.29 152.33,18.76 152.33,23.68 v2(153.29,24.64) ; v2(185.93,30.23) 185.93,30.3 187.77,32.14 199.12,32.14 201.15,30.12 SLOT3.A11
  BOTTOM w0.102: v2(153.29,24.64) 154.2,24.64 v1(155.78,26.21) 156.34,26.77 156.34,27.72 158.74,30.12 SLOT1.A11 161.48,29.4 163.96,29.4 164.96,28.4 175.98,28.4 177.56,29.97 179.32,29.97 180.37,28.93 180.57,28.93 180.58,28.91 181.58,28.91 181.59,28.93 183.61,28.93 184.91,30.23 v2(185.93,30.23) ; v2(201.8,62.23) 201.63,62.05 201.63,52.73 201.23,52.33 201.23,46.74 201.99,45.98 201.99,44.07 204.83,41.24 204.83,33.88 204.34,33.4 201.93,33.4 200.89,32.36 200.89,30.63 SLOT3.A11
PLTRST_PCON_N: length 5.7
  TOP w0.102: U4006.1 155.08,31.57 v1(154.7,31.95) 154.7,32.56 R4004.1 153.78,33.48 U4004.4
PLTRST_PEG_N: length 36.9
  TOP w0.102: v2(156.08,29.21) 154.05,29.21 153.78,28.94 U4006.4 153.78,26.88 R4009.2 154.24,26.61 154.56,26.29 154.56,24.81 155.08,24.29 U4007.1
  BOTTOM w0.102: SLOT2.A11 180.03,31.17 164.79,31.17 162.99,32.96 162.74,33.13 162.64,33.17 162.6,33.21 162.56,33.21 162.46,33.25 162.16,33.31 161.86,33.31 161.56,33.25 161.46,33.21 161.35,33.21 160.97,32.95 157.23,29.21 v2(156.08,29.21)
PM_DOWN_CPU: length 48.6
  TOP w0.102: R421.2 129.67,79.3 v1(129.17,79.8) 128.07,80.9 127.18,81.79 127.17,81.79 125.48,83.49 108.79,83.49 105.41,86.87 99.35,86.87 99.01,86.87 96.57,89.31 v2(96.57,89.46) ; v2(91.29,95.88) CPU1.D8
  BOTTOM w0.102: v2(91.29,95.88) 90.86,95.45 90.86,95.43 90.65,95.23 90.65,93.75 93.47,90.93 94.87,90.93 96.06,89.74 96.09,89.74 96.37,89.46 v2(96.57,89.46)
PM_DOWN_PCH: length 142.8
  TOP w0.102: SB1.AE2 202.23,132.79 201.7,132.26 201.7,130.86 201.55,130.71 201.55,129.77 201.7,129.62 201.7,125.27 200.89,124.46 200.89,124.13 197.1,120.35 195.84,120.35 195.25,119.76 195.25,119.61 193.54,117.91 192.05,116.41 192.05,116.19 190.76,114.91 177.18,114.91 171.6,109.33 171.6,106.23 168.4,103.03 168.4,100.99 168.4,63.42 164.92,59.94 v2(164.59,59.94) ; v2(130.43,78.36) 130.05,78.36 R421.1
  BOTTOM w0.102: v2(164.59,59.94) 153.64,70.89 v1(153.64,72.09) 153.64,73.52 149.34,77.83 130.96,77.83 v2(130.43,78.36)
PM_SYNC_CPU: length 185.3
  TOP w0.102: v2(94.97,90.22) 95.01,90.18 95.21,90.18 98.86,86.54 105.42,86.54 108.69,83.26 125.38,83.26 127.08,81.56 128.5,80.15 128.5,79.25 v2(128.88,78.87) ; R1711.2 201.99,124.37 197.35,119.74 196.15,119.74 195.86,119.45 195.86,119.36 192.66,116.16 192.66,115.94 191.02,114.3 177.43,114.3 172.21,109.08 172.21,105.98 169.01,102.78 169.01,101.24 169.01,101.24 169.01,63.17 164.92,59.08 v2(164.6,59.08) ; v2(91.29,96.79) CPU1.E8
  BOTTOM w0.102: v2(128.88,78.87) v1(129.54,78.21) 130.15,77.6 149.24,77.6 153.03,73.8 153.03,71.12 164.14,60.02 164.14,59.54 v2(164.6,59.08) ; v2(91.29,96.79) 91.29,96.71 90.45,95.88 90.45,93.57 93.32,90.7 94.48,90.7 v2(94.97,90.22)
PM_SYNC_PCH: length 9.4
  TOP w0.102: 202.54,126.75 202.54,125.31 R1711.1 ; 202.54,126.75 v1(202.56,126.75) ; 202.54,126.75 202.54,127.51 202.63,127.6 202.63,128.04 202.72,128.14 202.72,130.25 202.54,130.44 202.54,132.36 202.66,132.49 202.66,134.09 SB1.AF3
PME_N: length 65.8
  TOP w0.102: v2(206.24,40.88) 207.11,40.01 210.13,40.01 210.23,39.9 210.23,39.27 210.33,39.17 210.53,39.17 210.63,39.27 210.63,39.9 210.73,40.01 210.94,40.01 211.04,39.9 211.04,39.27 211.14,39.17 211.34,39.17 211.45,39.27 211.45,39.9 211.55,40.01 212.71,40.01 212.82,39.9 212.82,37.47 212.92,37.36 213.12,37.36 213.22,37.47 213.22,39.9 213.32,40.01 213.53,40.01 213.63,39.9 213.63,37.62 213.76,37.49 213.95,37.49 214.03,37.57 214.03,39.9 214.14,40.01 214.53,40.01 214.66,39.88 214.66,38.81 214.73,38.73 R9201.2 ; U9501.2 197.89,62.29 197.99,62.39 197.99,63.95 197.89,64.05 197.49,64.05 197.38,64.15 197.38,64.45 197.49,64.55 197.89,64.55 197.99,64.66 197.99,64.96 197.89,65.06 197.49,65.06 197.38,65.16 197.38,65.47 197.49,65.57 197.89,65.57 197.99,65.67 R9501.1 198.45,66.69 198.45,67.92 198.7,68.17 201.07,68.17 202.18,67.06 202.18,65.66 v2(202.23,65.61)
  BOTTOM w0.102: v2(202.23,65.61) v1(202.23,64.44) 202.23,61.26 202.11,61.14 202.11,52.78 201.54,52.2 201.54,46.86 202.3,46.1 202.3,44.82 v2(206.24,40.88)
PME_N_1: length 3.2
  TOP w0.102: R9202.1 R9201.1 219.08,38.73 SLOT4.37
POL1_SDA: length 12.1
  TOP w0.102: R5901.2 55.03,24.52 54.53,25.02 v1(54.53,26.19) 55.11,26.76 R5908.1 56.38,27.61 57.85,27.61 58.32,27.14 58.32,26.01 59.55,24.78 59.55,23.37 59.66,23.25 U5901.10
POL2_SCL: length 12.5
  TOP w0.102: R5902.2 53.95,24.71 53.9,24.77 v1(53.9,25.02) 53.9,26.49 55.36,27.95 R5909.1 57.95,27.95 58.55,27.36 58.55,26.1 59.64,25.02 59.64,25 60.13,24.5 U5901.9
PPAR: length 68.2
  TOP w0.102: RN9503.2 207.74,46.66 207.85,46.76 208.38,46.76 209.65,48.03 U9501.61 209.65,50.04 209.75,50.14 211.12,50.14 v2(211.13,50.14)
  BOTTOM w0.102: SLOT4.85 218.48,68.62 218.48,68.39 218.8,68.07 218.8,67.77 218.21,67.18 218.21,65.73 218.11,65.62 217.42,65.62 217.21,65.62 216.18,64.59 216.18,61.09 215.93,60.84 215.93,58.9 213.83,56.8 213.83,50.94 213.59,50.7 212.14,50.7 211.81,51.03 211.81,51.56 211.29,52.08 210.93,52.08 210.64,51.79 210.64,48.51 210.82,48.33 210.97,48.33 211.44,48.81 211.59,48.81 211.73,48.67 211.73,48.52 211.25,48.05 211.25,47.9 211.4,47.76 211.54,47.76 212.58,48.79 212.98,48.79 213.16,48.62 213.16,48.39 212.95,48.18 212.54,48.18 211.83,47.47 211.83,47.33 211.97,47.18 212.12,47.18 212.59,47.66 212.74,47.66 212.88,47.52 212.88,47.37 212.4,46.9 212.4,46.75 212.55,46.61 212.69,46.61 213.17,47.09 213.31,47.09 213.46,46.94 213.46,46.8 212.98,46.32 212.98,46.18 213.12,46.03 213.27,46.03 213.75,46.51 213.89,46.51 214.03,46.37 214.03,46.22 213.55,45.75 213.55,45.6 213.7,45.46 213.84,45.46 214.32,45.94 214.46,45.94 214.61,45.79 214.61,45.65 214.13,45.17 214.13,45.03 214.29,44.87 214.44,44.87 214.75,45.18 214.89,45.18 215.04,45.03 215.04,44.83 214.91,44.7 214.91,44.53 214.96,44.48 215.9,44.48 216.08,44.3 216.76,44.3 216.89,44.42 216.89,45.59 216.76,45.72 216.56,45.72 216.46,45.62 216.46,45.03 216.34,44.91 216.07,44.91 216,44.98 216,45.62 215.87,45.75 215.29,45.75 214.79,46.24 214.79,46.39 214.99,46.59 214.99,46.73 214.78,46.95 214.63,46.95 214.43,46.75 214.29,46.75 213.33,47.7 213.33,48.03 213.69,48.39 213.69,49.1 213.54,49.25 211.23,49.25 211.13,49.35 v2(211.13,50.14)
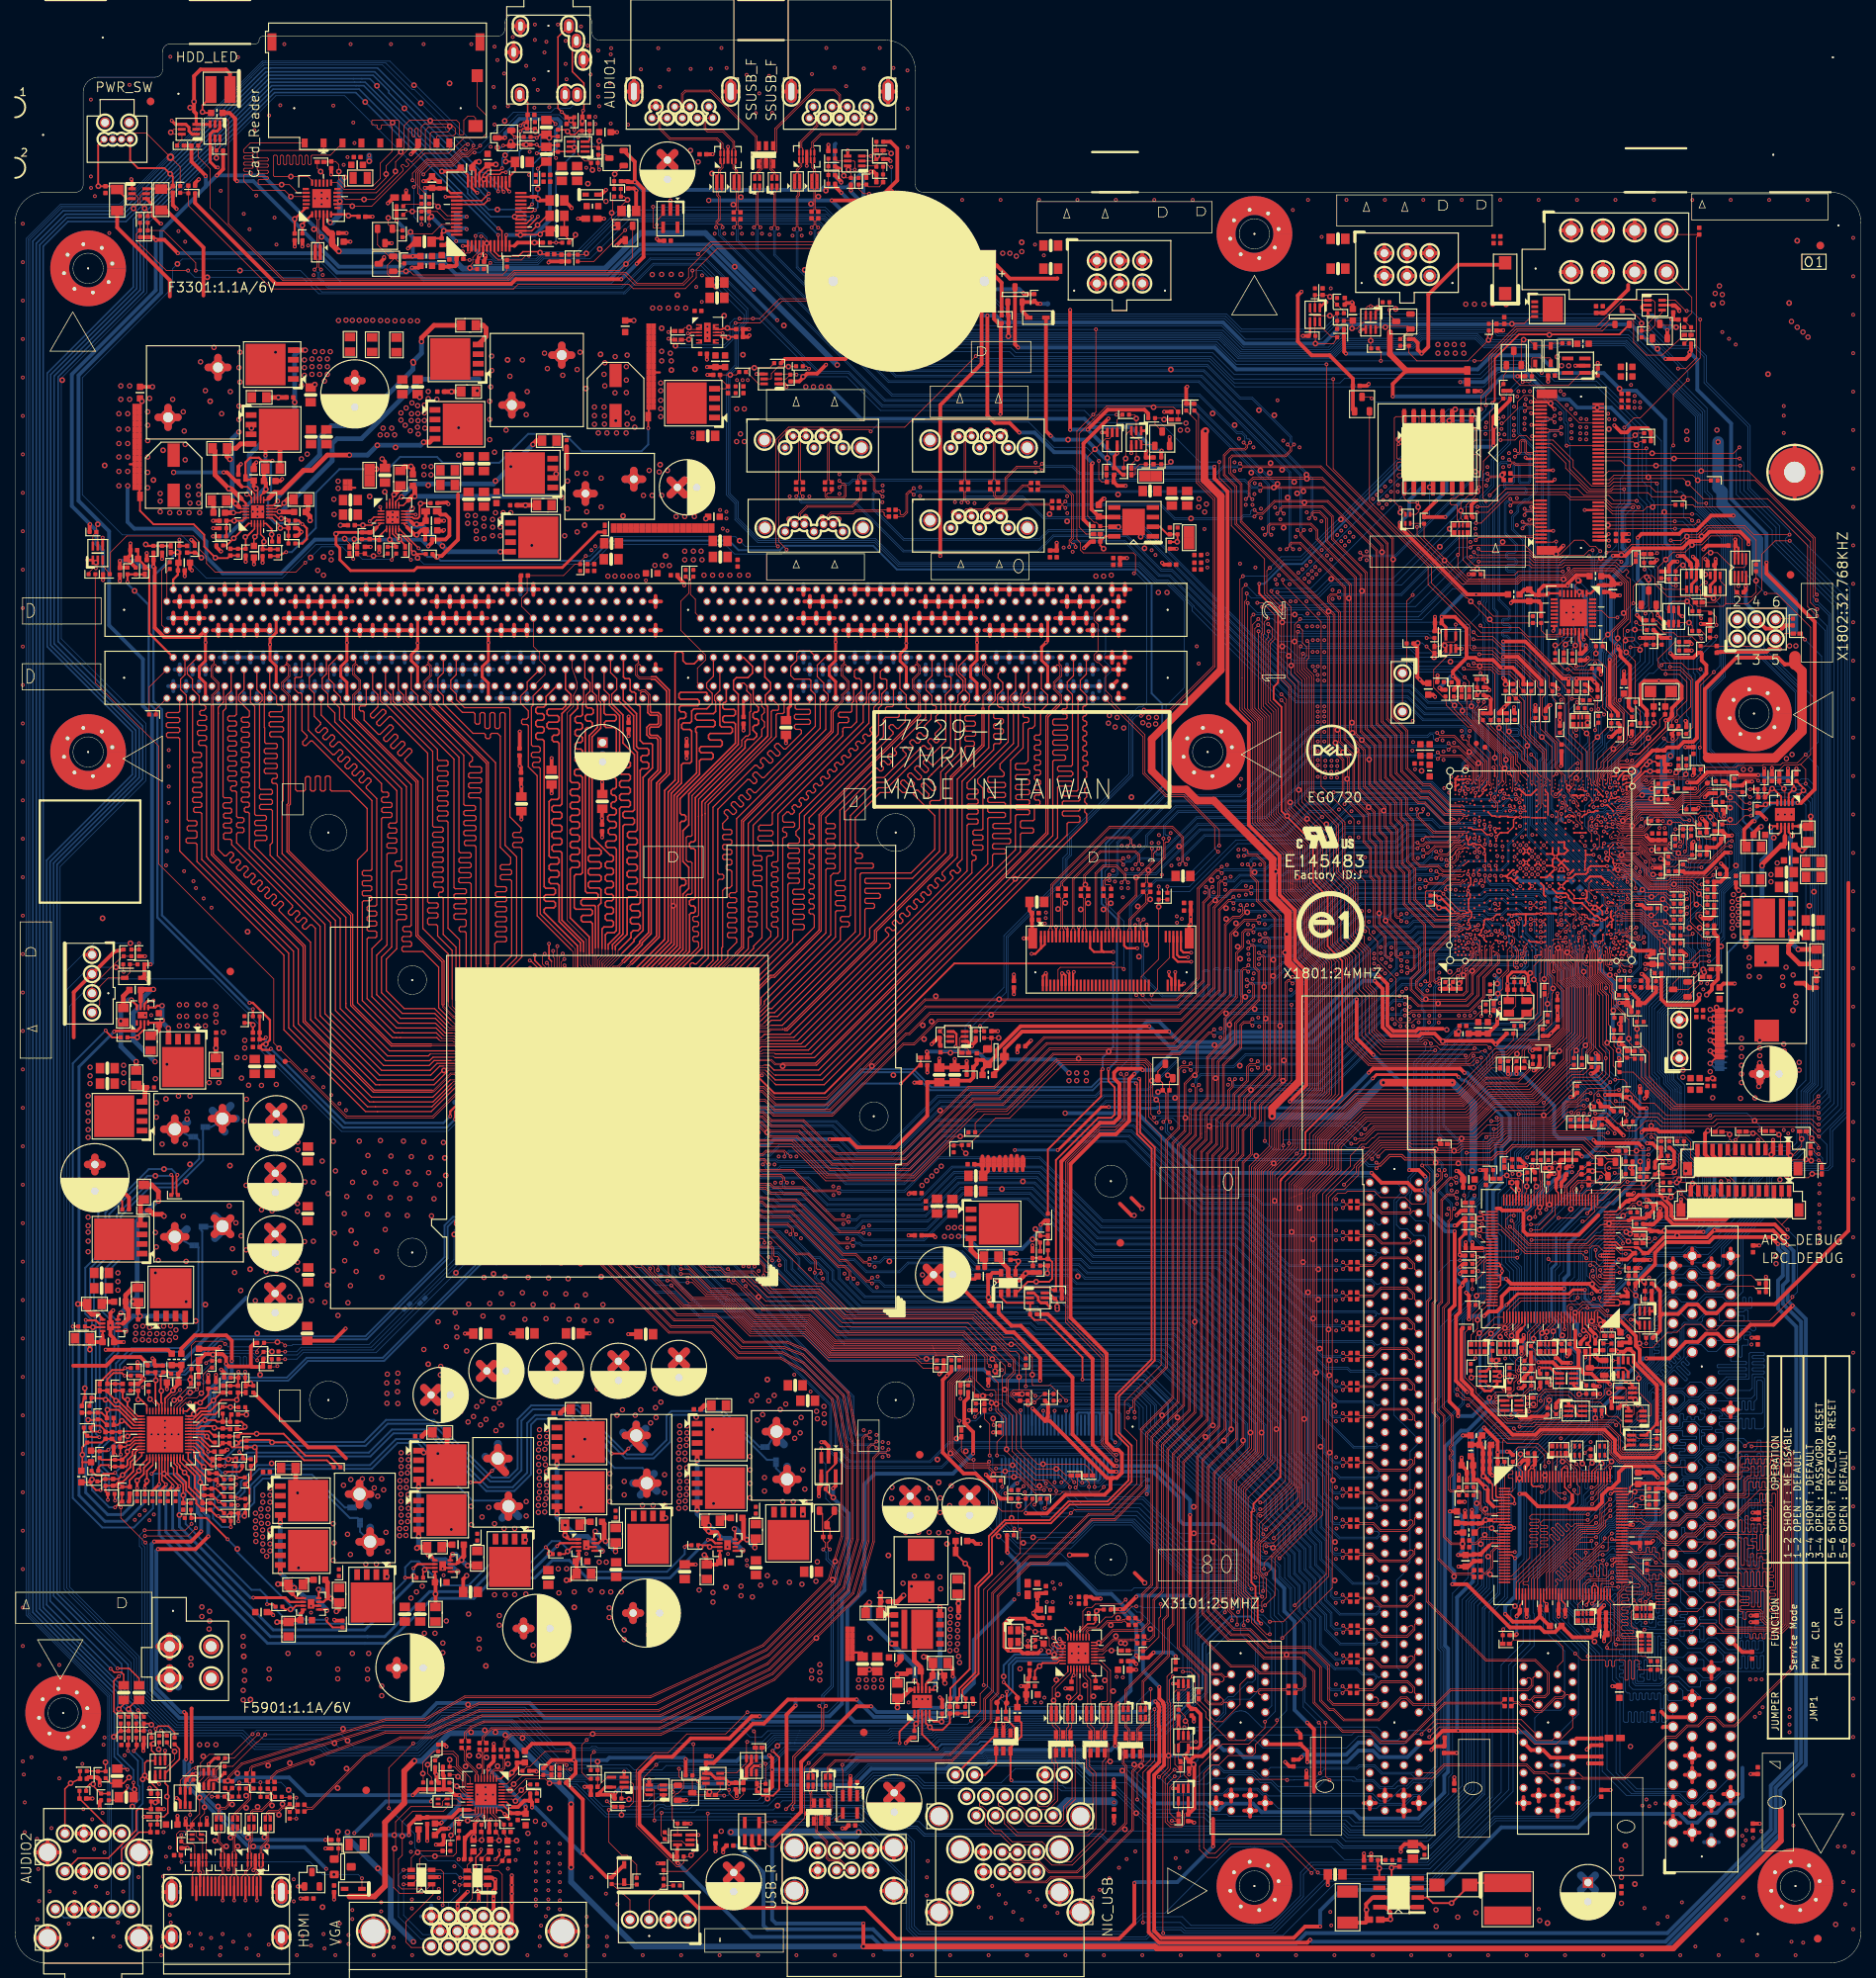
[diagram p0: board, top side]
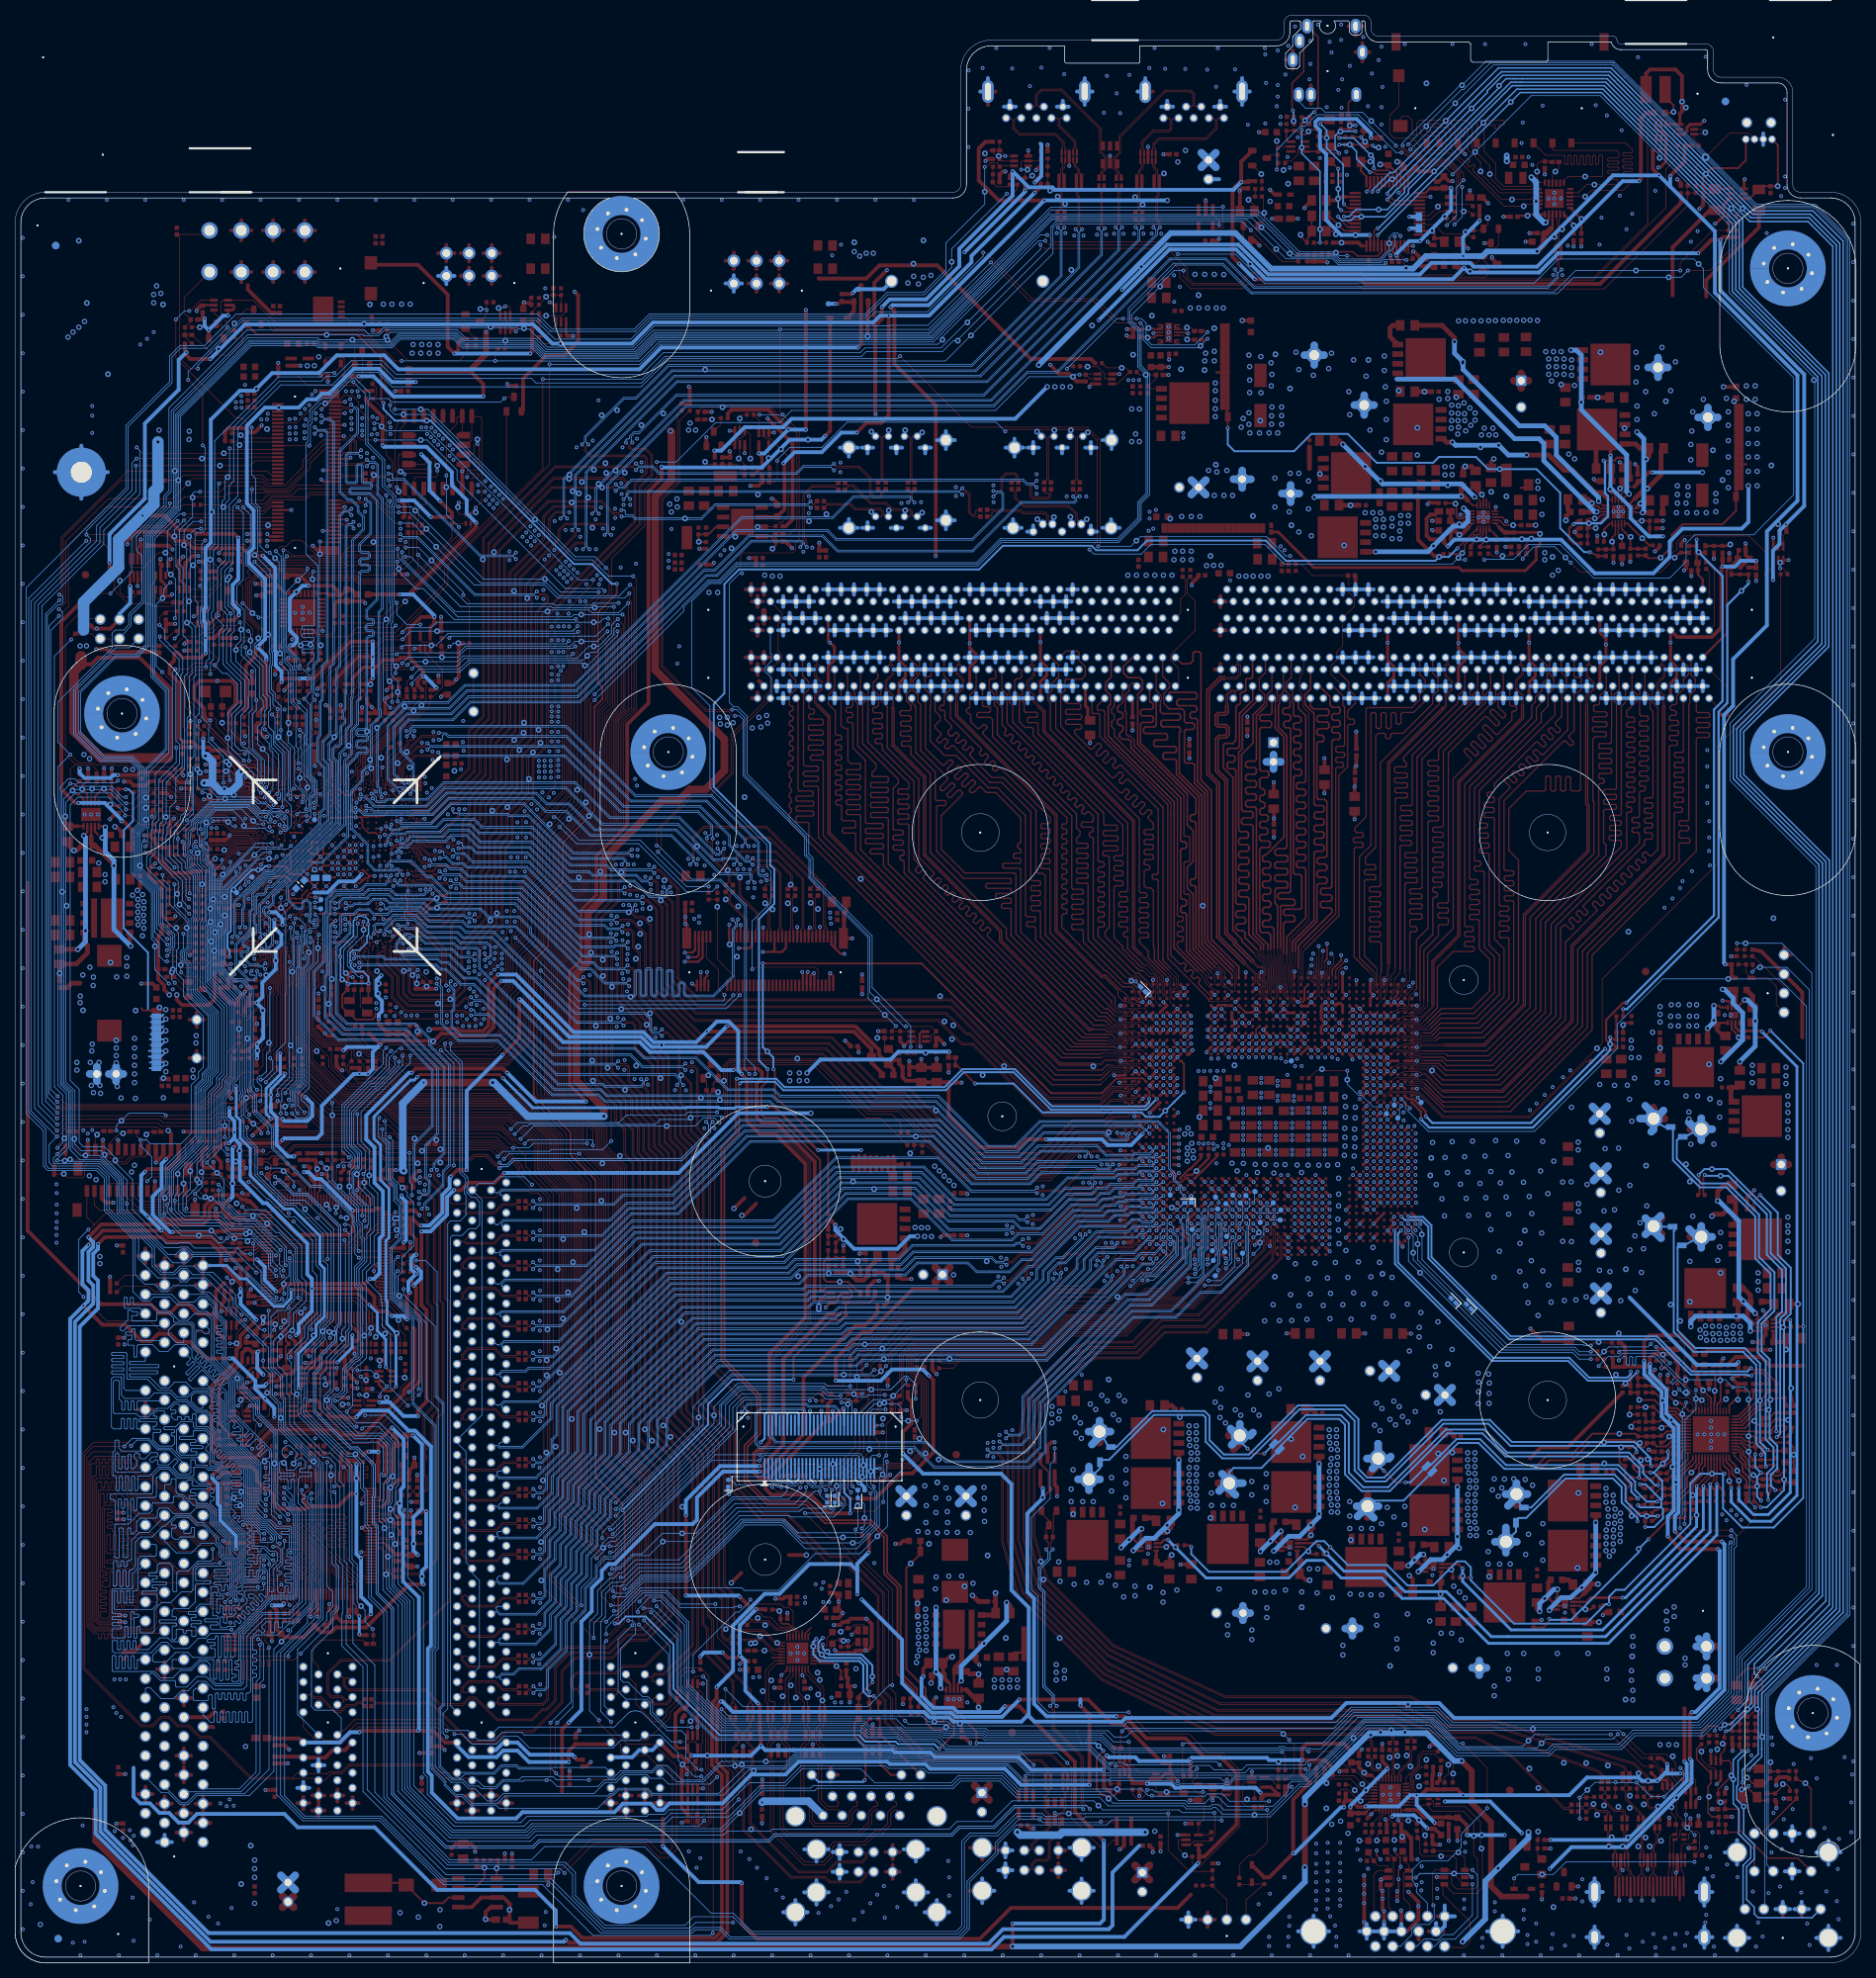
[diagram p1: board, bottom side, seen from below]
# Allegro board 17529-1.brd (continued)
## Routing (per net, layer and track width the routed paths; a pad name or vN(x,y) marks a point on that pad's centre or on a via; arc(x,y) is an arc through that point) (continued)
PPERR#: length 68.6
  TOP w0.102: v2(211.13,51.63) 210.25,50.75 208,50.75 207.25,50 U9501.55 207.25,48.01 206.59,47.36 RN9503.4
  BOTTOM w0.102: v2(211.13,51.63) 211.56,51.2 211.56,50.92 212.03,50.44 213.69,50.44 214.08,50.83 214.08,56.69 216.18,58.79 216.18,60.74 216.43,60.99 216.43,64.49 217.32,65.37 218.33,65.37 218.74,65.79 220.07,65.79 220.17,65.89 220.17,66.37 220.27,66.48 220.67,66.48 220.78,66.37 220.78,64.82 221.04,64.56 222.29,64.56 223.09,65.35 223.09,65.61 222.49,66.21 222.49,66.35 222.75,66.62 222.89,66.62 223.7,65.81 225.07,65.81 225.17,65.91 225.17,66.37 225.27,66.47 225.5,66.47 225.81,66.17 226.01,66.17 226.19,66.34 226.19,66.55 225.86,66.88 225.27,66.88 225.17,66.98 225.17,67.31 225.3,67.44 226.01,67.44 226.83,66.62 227.35,66.62 227.51,66.78 227.51,67.16 227.74,67.39 228.02,67.39 228.27,67.14 228.27,66.75 227.94,66.42 227.94,65.71 228.37,65.28 228.57,65.28 228.67,65.38 228.67,67.11 228.77,67.21 228.98,67.21 229.08,67.11 229.08,65.38 229.18,65.28 229.38,65.28 229.49,65.38 229.49,66.86 229.59,66.96 229.79,66.96 229.89,66.86 229.89,65.38 229.99,65.28 230.2,65.28 230.3,65.38 230.3,67.23 230.43,67.36 230.63,67.36 230.76,67.23 230.76,65.05 230.58,64.87 227.39,64.87 SLOT4.80
PREQ0#: length 65.3
  TOP w0.102: RN9502.1 206.18,66.12 v2(206.38,65.92) 206.85,65.45 U9501.107
  BOTTOM w0.102: v2(206.38,65.92) 207.17,65.13 208.08,65.13 208.18,65.23 208.18,66.02 208.48,66.32 208.86,66.32 209.04,66.14 209.04,64.82 208.94,64.72 207.17,64.72 207.07,64.62 207.07,64.41 207.17,64.31 208.94,64.31 209.04,64.21 209.04,64.01 208.94,63.91 208.03,63.91 207.93,63.8 207.93,62.76 207.83,62.66 207.63,62.66 207.53,62.76 207.53,63.8 207.43,63.91 207.17,63.91 207.07,63.8 207.07,60.56 206.06,59.56 206.06,47.73 207.77,46.02 211.19,46.02 213.84,43.38 213.84,37.01 214.22,36.63 217.55,36.63 218.77,37.85 219.93,37.85 221.33,36.45 222.68,36.45 222.81,36.58 222.81,37.19 222.94,37.31 224.79,37.31 225.73,38.25 226.07,38.25 SLOT4.36
PREQ1#: length 4.7
  TOP w0.102: U9501.102 208.85,64.96 209.17,65.28 210.1,65.28 211.04,66.22 v1(211.04,66.26) 210.2,67.09 RN9501.2
PROC_TRIGIN_CPU: length 181.8
  TOP w0.102: R2201.2 203.33,118.57 200.2,115.44 196.03,115.44 195.52,115.44 194.78,115.44 192.87,113.53 191.79,112.45 178.24,112.45 174.1,108.3 174.1,105.24 170.87,102.01 170.87,101.02 170.87,60.02 166.35,55.5 165.23,55.5 164.98,55.25 164.98,54.6 v2(165.35,54.23) ; CPU1.D1 99.37,96.34 105.94,89.76 106.7,89.76 110.13,86.33 127.02,86.33 130.68,82.68 131.77,82.68 134.46,79.98 v1(134.46,77.72) 134.46,76.4 134.56,76.3 136.93,76.3 v2(138.94,74.3)
  BOTTOM w0.102: v2(138.94,74.3) 139.01,74.37 147.6,74.37 148.6,73.37 148.6,70.55 164.92,54.23 v2(165.35,54.23)
PROC_TRIGIN_PCH: length 16.7
  TOP w0.089: 204.98,130.1 204.98,131.57 204.57,131.97 204.57,133.67 204.65,133.75 204.65,134.37 SB1.AK3
  TOP w0.102: 204.98,130.1 206.17,128.9 206.17,122.86 204.14,120.83 v1(204.14,120.5) 203.34,119.7 R2201.1
PROC_TRIGOUT_CPU: length 44.5
  TOP w0.102: CPU1.B3 95.71,94.2 97.82,94.2 102.62,89.41 106.55,89.41 109.98,85.98 126.88,85.98 131.12,81.74 v1(131.67,81.74) 132.2,81.74 133.6,80.34 R901.2
PROC_TRIGOUT_PCH: length 151.6
  TOP w0.102: SB1.AK2 204.37,133.84 204.37,131.84 204.75,131.46 204.75,130 205.82,128.93 205.82,123.01 202.54,119.74 202.54,118.49 200.06,116.01 199.85,115.8 196.17,115.8 195.67,115.8 195.67,115.8 194.93,115.8 194.93,115.8 194.64,115.8 192.52,113.68 191.64,112.8 178.1,112.8 173.74,108.45 173.74,105.39 170.51,102.16 170.51,100.87 170.51,60.27 v2(166.37,56.13) ; v2(133.6,76.2) R901.1
  BOTTOM w0.102: v2(133.6,76.2) 136.59,76.2 136.97,76.58 148.51,76.58 151.61,73.48 v1(151.61,72.36) 151.61,71.3 165.2,57.71 165.53,57.71 166.37,56.87 v2(166.37,56.13)
PROCHOT#_CPU: length 34.2
  TOP w0.102: v2(59.8,95.86) 60.28,96.34 CPU1.C39 ; R409.2 v2(35.69,79.78)
  BOTTOM w0.102: v2(35.69,79.78) 37.24,79.78 38.1,80.64 47.71,80.64 v1(58.27,91.21) 59.8,92.74 v2(59.8,95.86)
PROCHOT#_CPU_R: length 384.6
  TOP w0.102: v2(13.97,60.2) 13.97,58.8 v2(17.22,55.55) ; v2(16.89,76.07) 17.02,76.07 17.34,76.39 PR4461.1 ; v2(34.67,78.87) 34.57,78.77 R404.2 33.92,79.02 R409.1 ; v2(149.1,5.33) 149.1,25.17 150.62,26.7 v2(150.62,33.53) ; v2(213.14,103.22) 213.17,103.25 215.07,103.25 R2458.2
  BOTTOM w0.102: v2(13.97,60.2) 14.73,60.96 14.73,75.44 15.37,76.07 v2(16.89,76.07) 17.88,77.06 v1(23.14,77.06) 23.7,77.06 27.2,80.57 31.49,80.57 31.9,80.16 33.38,80.16 v2(34.67,78.87) ; v2(17.22,55.55) 17.48,55.3 17.48,35.83 21.5,31.8 21.96,31.8 54,31.8 55.98,33.78 67.4,33.78 69.38,31.8 96.97,31.8 97.45,31.32 120.19,31.32 120.75,31.88 123.34,31.88 123.67,32.21 123.68,32.21 124.08,32.61 149.71,32.61 v2(150.62,33.53) ; v2(149.1,5.33) 154.05,5.33 154.79,4.6 166.13,4.6 170.31,8.77 170.31,11.68 171.55,12.93 186.82,12.93 196.44,22.55 196.44,39.34 199.35,42.25 199.35,52.72 199.82,53.19 199.82,65.58 206.63,72.39 206.63,75.22 207.05,75.64 207.05,80.72 205.28,82.49 205.28,83.95 203.61,85.62 203.61,91.55 204.2,92.15 204.2,95.8 207.01,98.6 208.14,98.6 210.5,100.97 210.72,100.97 212.97,103.22 v2(213.14,103.22)
PROCHOT#_EC: length 10.5
  TOP w0.102: v1(214.82,105.91) R2460.1 R2458.1 214.69,103.76 213.07,103.76 212.12,102.81 211.39,102.81 210.33,101.75 208.22,101.75 208,101.53 U2401.36
PROCHOT#_IMVP: length 3
  TOP w0.102: PR4461.2 17.65,74.68 v1(17.83,74.5) 18.61,73.72 PU4401.10
PS_ON_N: length 11.9
  TOP w0.102: ATX3.8 221.65,220.1 221.65,218.03 C4306.1 220.79,216.88 221.51,216.15 R4303.2 R4302.2 221.55,214.88 R4305.2
PSERR#: length 67.6
  TOP w0.102: RN9503.3 207.24,47.6 207.65,48.01 U9501.56 207.65,49.96 208.15,50.47 210.7,50.47 v2(211.12,50.89)
  BOTTOM w0.102: v2(211.12,50.89) 211.83,50.19 213.8,50.19 214.34,50.73 214.34,56.59 216.43,58.68 216.43,60.63 216.72,60.92 216.72,64.42 217.42,65.12 218.48,65.12 218.87,65.51 220.24,65.51 220.37,65.38 220.37,64.47 220.53,64.3 222.42,64.3 223.64,65.53 225.05,65.53 226.24,64.33 227.69,64.33 227.79,64.23 227.79,62.51 227.89,62.41 228.09,62.41 228.19,62.51 228.19,64.23 228.3,64.33 228.5,64.33 228.6,64.23 228.6,62.51 228.7,62.41 228.9,62.41 229.01,62.51 229.01,64.23 229.11,64.33 229.31,64.33 229.41,64.23 229.41,62.51 229.51,62.41 229.72,62.41 229.82,62.51 229.82,64.23 229.92,64.33 230.12,64.33 230.23,64.23 230.23,62.51 230.33,62.41 230.53,62.41 230.63,62.51 230.63,64.23 230.73,64.33 230.99,64.33 231.09,64.44 231.09,67.44 230.81,67.72 230.81,68.99 230.7,69.09 230.4,69.09 230.3,68.99 230.3,68.05 229.89,67.64 227.16,67.64 SLOT4.84
PSPWRGD: length 185.4
  TOP w0.102: v2(104.95,210.67) 104.62,211 R4207.2 ; ATX3.4 218.84,228.41 C4307.1 222.25,228.03 222.25,212.09 220.85,210.69 v2(219.84,210.69) ; R4201.1 86.61,215.65 86.49,215.52 v2(86.36,215.52) ; v2(95.76,217.3) v2(97.54,217.3) 98.42,217.3 101.04,219.92 109.55,219.92 115.65,226.01 v2(116.03,226.01)
  BOTTOM w0.102: v2(104.95,210.67) 104.67,210.95 104.67,210.95 104.6,211.02 104.6,211.02 98.32,217.3 v2(97.54,217.3) ; v2(116.03,226.01) 116.03,225.56 123.39,218.2 130.29,218.2 131.19,217.3 159.89,217.3 162.61,214.58 172.67,214.58 175.13,217.04 213.92,217.04 219.84,211.12 v2(219.84,210.69) ; v2(86.36,215.52) 88.06,213.82 93.75,213.82 94.49,214.55 94.49,216.7 95.09,217.3 v2(95.76,217.3)
PSTOP#: length 64.3
  TOP w0.102: v2(213.94,47.93) 214.36,47.51 RN9504.4 214.05,46.84 213.66,46.46 213.66,44.53 213.94,44.25 214.3,44.25 214.4,44.15 214.4,43.26 214.3,43.15 212.47,43.15 212.37,43.26 212.37,43.46 212.47,43.56 213.84,43.56 213.94,43.66 213.94,43.87 213.84,43.97 212.47,43.97 212.37,44.07 212.37,44.48 212.47,44.58 213.11,44.58 213.21,44.68 213.21,44.88 213.11,44.98 212.47,44.98 212.37,45.09 212.37,45.29 212.47,45.39 213.11,45.39 213.21,45.49 213.21,45.69 213.11,45.8 212.47,45.8 212.37,45.9 212.37,46.1 212.47,46.2 213.11,46.2 213.21,46.3 213.21,46.51 213.11,46.61 212.47,46.61 212.37,46.71 212.37,46.91 212.47,47.02 213.39,47.02 213.49,47.12 213.49,47.32 213.39,47.42 212.47,47.42 212.37,47.52 212.37,47.73 212.47,47.83 213.21,47.83 213.31,47.93 213.31,48.13 213.21,48.23 212.47,48.23 212.37,48.34 212.37,48.59 212.47,48.69 215.11,48.69 215.21,48.79 215.21,49 215.11,49.1 213,49.1 212.9,49.2 212.9,49.45 213.06,49.61 214.68,49.61 214.81,49.73 214.81,49.94 214.66,50.09 213.89,50.09 213.79,50.19 213.79,50.95 213.65,51.09 U9501.67
  BOTTOM w0.102: v2(213.94,47.93) 213.94,48.67 214.05,48.77 214.35,48.77 214.45,48.87 214.45,49.08 214.35,49.18 214.05,49.18 213.94,49.28 213.94,49.62 214.14,49.81 214.29,49.81 214.52,49.58 214.64,49.58 214.8,49.74 214.8,49.87 214.57,50.1 214.57,50.25 214.85,50.52 214.85,53.4 215.52,54.07 215.52,56.12 217.68,58.28 217.68,59.77 218.63,60.72 219.91,60.72 220.06,60.88 220.06,61.19 220.16,61.29 220.86,61.29 221.02,61.46 221.02,61.6 220.92,61.7 220.19,61.7 220.09,61.8 220.09,62.01 220.19,62.11 220.73,62.11 220.83,62.21 220.83,62.41 220.63,62.61 218.64,62.61 218.52,62.74 218.52,62.94 218.6,63.02 220.47,63.02 220.62,63.17 220.62,63.4 220.52,63.5 220.52,63.7 220.62,63.8 221.19,63.8 221.7,63.29 SLOT4.75
PTRDY#: length 65.3
  TOP w0.102: U9501.68 213.69,51.49 215.47,49.71 215.47,48.56 214.81,47.9 v2(214.81,47.89) 215.01,47.68 RN9504.3
  BOTTOM w0.102: SLOT4.71 221.7,61.35 222.01,61.66 222.98,61.66 223.09,61.55 223.09,60.86 223.17,60.77 225.79,60.77 225.88,60.68 225.88,59.8 226.26,59.41 227.6,59.41 229.02,57.99 230.73,57.99 230.84,57.89 230.84,53.62 230.73,53.52 230.35,53.52 230.25,53.62 230.25,57.4 230.17,57.48 229.79,57.48 229.69,57.38 229.69,53.67 229.59,53.57 229.24,53.57 229.13,53.67 229.13,57.38 229.03,57.48 228.83,57.48 228.73,57.38 228.73,56.79 228.63,56.69 228.37,56.69 227.97,57.1 227.97,58.22 227.42,58.77 225.41,58.77 225.2,58.98 225.2,59.79 224.89,60.1 223.8,60.1 223.09,59.39 220.8,59.39 219.97,60.21 218.84,60.21 218.19,59.56 218.19,58.07 216.08,55.96 216.08,53.91 215.35,53.19 215.35,49.58 214.96,49.18 214.96,48.04 v2(214.81,47.89)
PULSAR_38D4M_REFCLK: length 131.9
  TOP w0.102: NGFF1.64 206.79,203.5 203.71,206.58 202.71,206.58 202.7,206.58 201.05,206.58 200.49,207.14 199.44,207.14 198.63,206.32 198.63,205.41 196.67,203.45 v2(196.52,203.45) ; v2(167.59,182.78) 167.59,182.3 172.64,177.24 172.64,155.5 176.99,151.16 176.99,144.42 178.46,142.95 178.46,137.11 178.99,136.58 178.99,136.09 180.11,134.98 180.11,132.49 182.55,130.05 182.55,124.64 182.93,124.26 184.63,124.26 185.14,124.76 192.74,124.76 193.74,125.77 R6304.2 195.33,125.77 R1815.2
  BOTTOM w0.102: v2(196.52,203.45) 195.99,203.45 v1(195.57,203.03) 195.02,202.49 189.26,202.49 169.54,182.78 v2(167.59,182.78)
PW_CLEAR: length 92
  TOP w0.102: v2(194.41,165.88) 194.02,165.88 193.6,165.46 193.6,164.78 194.03,164.35 R2041.2 194.03,164.07 198.37,159.73 198.37,158.37 198.78,157.97 198.78,156.3 SB1.V48 ; v2(194.94,193.95) 196.29,195.3 206.78,195.3 207.8,194.28 215.85,194.28 216.38,193.75 221.59,193.75 222.45,192.89 v2(223.55,192.89)
  BOTTOM w0.102: JMP1.3 228.68,176.73 228.68,178.1 226.95,179.82 226.95,179.91 226.95,179.91 226.95,189.08 223.55,192.48 v2(223.55,192.89) ; v2(194.41,165.88) 195.33,166.79 195.33,177.16 v1(194.94,177.55) 194.87,177.62 194.87,193.88 v2(194.94,193.95)
PWR2_PRSN_1: length 4.5
  TOP w0.102: Q2401.2 204.14,72.93 R2408.1 202.87,73.34 R2402.2 202.56,73.71 202.79,73.94 v1(202.79,74.37)
PWR2_PRSN_2: length 11.2
  TOP w0.102: R2403.2 208.29,73.58 Q2401.6 ; R2403.2 208.91,72.96 208.91,72.03 v1(208.89,72.01) 208.91,71.98 208.91,71.88 209.07,71.73 211.58,71.73 212.22,71.1 212.22,70.13 213.26,69.09 U2405.2 ; R2403.2 208.76,72.93 Q2401.5
PWR2_PRSNT: length 28.8
  TOP w0.102: U2401.108 201.2,84.59 199.92,83.31 199.92,82.14 199.62,81.83 199.62,80.39 199.26,80.04 198.8,80.04 198.32,79.55 198.32,78.09 198.73,77.68 ; Q2401.3 204.62,72.28 204.09,71.75 200.62,71.75 200.46,71.6 197.31,71.6 194.89,74.02 v1(194.89,74.68) 195.02,74.68 195.76,75.41 197.85,75.41 198.15,75.7 198.15,76.71 198.73,77.29 198.73,77.68 ; 198.73,77.68 198.79,77.68 199.53,78.42 R2465.1
PWR_1D0V: length 51.5
  TOP w0.254: PR5122.1 226.06,119.76 ; PR5121.1 226.06,120.52 ; PR5118.1 226.06,122.81 ; PR5119.1 226.06,124.33 ; PR5120.1 226.06,122.05 ; PR5133.1 226.06,125.09 ; PR5123.1 225.93,121.28 ; PR5134.1 227.05,125.86 227.33,126.14 ; PR5117.1 225.93,123.57
  TOP w0.305: v2(229.37,155.08) 229.41,155.12 PR5114.1 230.37,154.13 PC5108.1
  TOP w1.016: 230.66,116.52 PT5101.1 ; PT5101.1 230.66,118.43 ; PT5101.1 231.61,117.47 ; PT5101.1 229.7,117.47
  BOTTOM w0.254: PR5117.1 226.06,123.57 ; PR5120.1 226.19,122.05 ; PR5123.1 226.06,121.28 ; v2(229.37,155.08) 228.97,155.08 228.42,154.53 228.42,150.9 229.64,149.68 229.64,136.73 226.44,133.53 226.44,126.09 ; PR5118.1 225.93,122.81 226.06,122.68 ; PR5119.1 226.06,124.33 ; PR5135.1 226.19,118.24 ; PR5132.1 226.19,119 ; PR5122.1 226.31,119.76 ; PR5121.1 226.31,120.52 ; PR5133.1 226.09,125.09
  BOTTOM w1.016: PT5101.1 230.66,118.43 ; PT5101.1 229.7,117.47 ; PT5101.1 230.66,116.52 ; PT5101.1 231.61,117.47
  vias: v1(228.07,125.86) v1(230.63,121.92) v1(235.03,125.88) v3(228.22,122.17) v3(228.22,120.9) v3(228.22,119.76) v3(228.22,118.62) v3(228.22,117.47) v3(228.22,116.33) v3(230.5,115.82) v3(230.63,120.9) v3(230.63,119.89) v3(230.63,118.95) v3(233.81,121.41) v3(233.87,120.51)
PWR_1D0V_BOOT: length 3.6
  TOP w0.305: PU5101.10 235.73,150.22
  TOP w0.508: 235.73,150.22 236.86,150.22 PR5110.2 237.36,150.48 v1(237.36,151.51)
PWR_1D0V_BOOT_R: length 2.9
  TOP w0.635: 236.23,147.04 235.82,147.04 PC5106.2 ; 236.23,147.04 v1(236.23,147.01) ; 236.23,147.04 236.29,147.04 237.04,147.79 PR5110.1
PWR_1D0V_CS: length 3.6
  TOP w0.254: PR5111.1 234.53,156.18 235.14,155.56 v1(235.14,155.11) 235.08,155.11 234.46,154.49 234.46,153.99 234.45,153.98 234.45,153.56 234.46,153.55 PU5101.2
PWR_1D0V_FB: length 6.1
  TOP w0.254: PU5101.4 233.46,154.15 232.44,155.17 v1(232.27,155.17) 232.27,155.15 231.91,154.8 231.91,154.63 PC5108.2 231.25,154.13 PR5114.2 231.25,156.17 PR5116.1
PWR_1D0V_LGATE: length 19.9
  TOP w0.305: v3(232.08,150.08) 232.22,150.22 PU5101.6
  TOP w0.635: PU5102.8 228.85,134.49 v3(228.73,134.37)
  BOTTOM w0.635: v3(232.08,150.08) 232.08,146.84 230.94,145.69 v1(230.94,144.98) 230.94,136.58 v3(228.73,134.37)
PWR_1D0V_PG: length 4
  TOP w0.254: PU5101.1 234.96,153.77 235.62,154.43 235.9,154.43 v1(236.4,154.93) 236.4,155.25 PR5107.2
PWR_1D0V_PHASE: length 9.4
  TOP w0.305: 233.96,148.88 PU5101.8
  TOP w0.635: 235.43,129.46 236.52,129.46 237.12,128.87 PR5109.2 ; 233.96,148.88 233.96,147.92 PC5106.1 233.42,147.64 230.94,145.16
  vias: v1(231.39,132.21) v3(229.24,132.84) v3(229.24,131.7) v3(229.24,130.38) v3(230.58,130.3) v3(233.65,130.28) v3(233.68,129.16) v3(234.11,131.57) v3(235.05,130.56)
PWR_1D0V_RF: length 2.9
  TOP w0.254: PR5112.1 231.19,152.87 v1(231.4,153.08) 231.64,153.31 PU5101.5
PWR_1D0V_SNB:
  vias: v1(227.48,145.01)
PWR_1D0V_UGATE: length 19.4
  TOP w0.305: PU5101.9 234.46,149.44 v3(234.93,148.97)
  TOP w0.635: v3(235.71,133.93) PR5108.2
  BOTTOM w0.635: v3(234.93,148.97) 234.7,148.73 v1(234.7,136.4) 234.7,134.95 v3(235.71,133.93)
PWR_1D0V_UGATE_R: length 9.5
  TOP w0.635: 238.12,130.78 238.13,130.73 238.13,130.73 238.14,130.31 238.14,129.77 PR5109.1 ; 238.12,130.78 238.12,131.98 PR5108.1 235.91,132 234.44,133.48 234.44,134.44 234.87,134.87 PU5102.1 ; 238.12,130.78 v1(238.12,130.77)
PWR_1D0V_VCC: length 1.3
  TOP w0.305: 233.04,149.1 233.46,149.51 PU5101.7
  vias: v1(232.49,148.69)
PWR_2D5V:
  vias: v1(155.45,190.88)
PWR_2D5V_EN: length 4.3
  TOP w0.254: PR5204.2 PC5205.1 ; PC5205.1 144.13,188.52 PU5201.8 ; PC5205.1 143.45,187.34 v1(143.89,186.89)
PWR_2D5V_FB: length 5.7
  TOP w0.254: PR5206.1 153.58,187.77 v1(153.62,187.81) 153.67,187.86 PR5205.2 PC5206.1 152.34,188.79 151.33,189.79 PU5201.2
PWR_2D5V_VIN:
  vias: v1(145.8,194.06)
PWR_3D3V: length 22
  TOP w0.305: PG4902.2 83.77,204.72 PR4918.2 PR4901.2 PR4902.2 PR4903.2 PR4904.2 PR4906.2 PR4905.2 PR4920.2 PR4922.2 PR4924.2 PR4908.2 PR4910.2 PR4912.2 PR4914.2 PR4916.2
  TOP w1.016: PL4901.1 73.56,212.47 ; PL4901.1 72.26,213.76 ; PL4901.1 72.26,211.17 ; PL4901.1 70.97,212.47
  BOTTOM w1.016: 70.97,212.47 PL4901.1 ; PL4901.1 72.26,211.17 ; PL4901.1 72.26,213.76 ; PL4901.1 73.56,212.47
  vias: v1(75.46,208.05) v1(77.39,212.57) v3(69.98,212.72) v3(70.36,210.69) v3(72.39,209.8) v3(74.3,210.57) v3(74.68,212.85) v3(77.85,209.93) v3(77.96,211.46) v3(77.95,208.41) v3(79.32,212.27) v3(79.3,207.49) v3(80.8,210.95) v3(80.8,209.17) v3(80.8,207.52) v3(80.9,212.47)
PWR_3D3V_SN: length 2.3
  TOP w0.635: PC4911.1 v1(57.68,207.65) PR4950.2
PWR_3V_BOOT2: length 3.7
  TOP w0.203: v1(35.56,192.91) 35.18,192.53 34.8,192.53 34.44,192.17 PU4902.9
  TOP w0.635: PR4942.2 36.04,193.4 v1(35.56,192.91)
PWR_3V_BOOT2_R: length 3.1
  TOP w0.635: PR4942.1 38.73,192.07 PC4907.2 38.99,191.16 v1(38.99,190.63)
PWR_3V_CS2: length 3
  TOP w0.203: PU4902.5 33.17,190.22 33.27,190.12
  TOP w0.254: PR4952.1 33.97,188.71 v1(33.91,188.77) 33.91,189.48 33.27,190.12
PWR_3V_EN2: length 5.3
  TOP w0.203: PU4902.6 33.95,190.97 35.05,189.87 v1(35.05,189.61) PC4918.1 PR4961.1 PR4959.2
PWR_3V_FB2: length 5.7
  TOP w0.203: PU4902.4 32.45,188.78 32.89,188.34
  TOP w0.254: PR4954.2 PC4914.2 PR4956.1 32.72,187.63 v1(32.89,187.81) 32.89,188.34
PWR_3V_FB2_A: length 64.6
  TOP w0.254: v2(35.81,186.44) 35.8,186.42 PR4954.1 PC4914.1 ; PG4902.1 v2(83.69,202.82)
  BOTTOM w0.254: v2(35.81,186.44) 36.58,186.44 39.75,189.61 39.75,194.28 42.88,197.4 v1(47.75,197.4) 49.28,197.4 50.88,199.01 55.78,199.01 56.54,198.25 64.01,198.25 67.82,202.06 72.64,202.06 74.93,199.77 82.8,199.77 83.69,200.66 v2(83.69,202.82)
PWR_3V_LGATE2: length 26
  TOP w0.203: PU4902.11 33.3,193.32 33.53,193.55
  TOP w0.635: v3(44.2,199.26) 41.27,199.26 39.24,197.23 38.1,197.23 35.18,194.31 34.29,194.31 33.53,193.55 ; v3(54,200.96) 54.79,200.96 55.24,201.42 PU4904.4
  BOTTOM w0.635: v3(44.2,199.26) 46.58,199.26 v1(47.88,200.56) 53.59,200.56 v3(54,200.96)
PWR_3V_PHASE2: length 48.7
  TOP w0.203: v3(34.92,191.77) PU4902.8
  TOP w0.635: PC4907.1 34.95,191.74 v3(34.92,191.77)
  TOP w1.016: PL4901.2 66.96,205.87 ; PL4901.2 65.66,204.57 ; PL4901.2 65.66,207.16 ; PL4901.2 64.37,205.87
  BOTTOM w0.635: 61.34,209.3 53.64,209.3 45.77,201.42 42.55,201.42 41.91,200.79 41.91,198.5 35.18,191.77 v3(34.92,191.77)
  BOTTOM w1.016: PL4901.2 66.96,205.87 ; PL4901.2 65.66,204.57 ; PL4901.2 65.66,207.16 ; PL4901.2 64.37,205.87
  vias: v1(58.62,202.87) v1(61.09,207.77) v1(65.1,211.84) v3(62.74,206.38) v3(62.74,203.96) v3(62.74,201.29) v3(62.87,208.28) v3(62.99,212.34) v3(62.99,210.44) v3(64.9,202.56) v3(65.41,209.68) v3(67.06,211.84) v3(67.56,204.6) v3(67.69,207.65)
PWR_3V_UGATE2: length 38.7
  TOP w0.203: PU4902.10 34.07,192.57 v3(34.67,193.17)
  TOP w0.635: PR4944.1 55.37,216.41 53.72,214.76 v3(53.72,214.25)
  BOTTOM w0.635: v3(34.67,193.17) 34.67,193.68 40.26,199.26 40.26,201.6 41.78,203.12 45.14,203.12 52.6,210.59 v1(52.6,211.6) 53.72,212.72 v3(53.72,214.25)
PWR_3V_UGATE2R: length 4.1
  TOP w0.635: PR4944.2 61.89,216.41 62.25,216.05 62.25,214.9 PU4901.4
PWR_5V: length 34.8
  TOP w0.203: PU4902.14 31.65,194.15 30.73,195.07 29.97,195.07
  TOP w0.305: PG4901.2 16.43,194.18 PR4934.1 PR4933.1 PR4936.1 PR4945.1 PR4946.1 PR4947.1 PR4948.1 PR4949.1 PR4929.1 PR4927.1 PR4925.1 PR4940.1 PR4939.1 PR4938.1 PR4937.1
  TOP w0.508: 29.97,195.07 29.51,195.53 PC4913.1 29.2,195.8 28.02,196.98 v2(27.56,196.98)
  TOP w1.016: PL4902.2 20.22,205.54 ; PL4902.2 20.22,202.95 ; PL4902.2 21.52,204.24 ; PL4902.2 18.92,204.24
  BOTTOM w0.508: v2(27.56,196.98) v3(20.95,196.98)
  BOTTOM w1.016: PL4902.2 21.52,204.24 ; PL4902.2 20.22,205.54 ; PL4902.2 20.22,202.95 ; PL4902.2 18.92,204.24
  vias: v1(16.76,206.38) v1(18.29,195.96) v1(19.56,199.9) v3(17.53,204.98) v3(17.53,203.2) v3(17.53,201.17) v3(17.53,199.01) v3(17.53,196.98) v3(17.53,194.94) v3(17.78,206.76) v3(20.83,206.63) v3(22.23,204.98) v3(22.35,202.44) v3(22.48,200.66) v3(22.48,198.63)
PWR_5V3D3V_LDO3: length 3.2
  TOP w0.203: PU4902.3 32.05,188.82 v1(31.7,188.47) 31.57,188.34 PC4916.1
PWR_5V3D3V_VIN: length 27.7
  TOP w0.508: v2(33.1,199.19) 33.1,200.13 ; PR4960.1 v2(26.16,188.52)
  TOP w0.635: PR4932.1 35.05,204.91
  TOP w1.016: PT4901.1 44.91,210.04 ; PT4901.1 43.95,209.09 ; PT4901.1 44.91,208.14 ; PT4901.1 45.86,209.09
  BOTTOM w0.508: v2(33.1,199.19) 33.1,195 30.44,192.34 30.44,190.92 28.04,188.52 v2(26.16,188.52)
  vias: v1(52.66,211.43)
PWR_5V_BOOT1: length 3
  TOP w0.203: 29.59,192.41 29.83,192.17 PU4902.17
  TOP w0.635: 29.59,192.41 v1(29.15,192.85) 28.73,193.27 PR4943.1
PWR_5V_BOOT1_R: length 1.7
  TOP w0.635: PC4908.1 26.21,193.04 PR4943.2
PWR_5V_CS1: length 5
  TOP w0.203: PU4902.1 30.86,190.22
  TOP w0.254: PR4953.1 27.97,187.32 v1(28.91,188.27) 30.86,190.22
PWR_5V_EN1: length 4.8
  TOP w0.203: 30.05,190.58 30.44,190.97 PU4902.20
  TOP w0.254: PR4960.2 27.93,188.54 PR4962.1 PC4919.1 v1(28.96,190.58) 30.05,190.58
PWR_5V_FB1: length 6
  TOP w0.203: PU4902.2 31.65,189.52 31.37,189.23
  TOP w0.254: 31.37,189.23 30.61,188.47 30.45,188.47 v1(30.43,188.44) 30.48,188.39 PR4957.1 PR4955.2 PC4915.2
PWR_5V_FB1_A: length 18.2
  TOP w0.254: PR4955.1 PC4915.1 28.11,185.65 26.52,185.65 v1(26.47,185.7) 24.99,187.17 24.99,188.72 23.6,190.12 18.29,190.12 16.51,191.9 PG4901.1
PWR_5V_LGATE1: length 25.4
  TOP w0.203: v3(30.63,194.11) 30.81,194.11 31.25,193.66 PU4902.15
  TOP w0.635: PU4905.4 v3(38.35,213.13)
  BOTTOM w0.635: v3(38.35,213.13) 37.62,213.13 36.96,212.47 v1(36.96,206.25) 36.96,205.26 30.96,199.26 30.96,194.44 v3(30.63,194.11)
PWR_5V_PHASE1: length 24.3
  TOP w0.203: v3(28.85,191.64) 29.72,191.64 29.84,191.77 PU4902.18
  TOP w0.635: PC4908.2 v3(28.85,191.64)
  TOP w1.016: PL4902.1 28.12,210.84 ; PL4902.1 26.82,212.14 ; PL4902.1 25.52,210.84 ; PL4902.1 26.82,209.55
  BOTTOM w0.635: v3(29.59,202.31) 28.7,201.42 28.7,191.8 v3(28.85,191.64)
  BOTTOM w1.016: PL4902.1 28.12,210.84 ; PL4902.1 25.52,210.84 ; PL4902.1 26.82,212.14 ; PL4902.1 26.82,209.55
  vias: v1(25.78,206.38) v1(31.24,202.82) v1(34.42,212.85) v3(24.51,211.58) v3(25.15,207.77) v3(26.29,213.49) v3(27.3,204.72) v3(28.45,207.65) v3(29.59,210.82) v3(29.59,205.74) v3(29.59,203.96) v3(29.72,212.85) v3(29.72,208.91)
PWR_5V_SN: length 2.7
  TOP w0.635: PC4912.1 v1(34.8,206.88) PR4951.2
PWR_5V_UGATE1: length 9.6
  TOP w0.305: 29.91,193.48 30.5,192.89 PU4902.16
  TOP w0.635: 29.91,193.48 28.57,194.82 v1(28.24,194.82) 26.42,196.65 26.42,199.82 PR4941.2
PWR_5V_UGATE1R: length 5
  TOP w0.635: PU4903.4 29.79,200.74 29.21,200.15 PR4941.1 28.02,199.09 v1(28.4,198.7)
PWR_12V_DUAL_1D0V:
  vias: v1(237.19,139.7) v1(237.79,141.55)
PWR_BTNJ_C: length 12.5
  TOP w0.102: PWRSW1.S2 14.86,241.81 17.35,241.81 v4(20.54,238.62) 21.82,237.34 R6405.1
PWR_DDR4_BT: length 3.1
  TOP w0.203: v1(50.1,194.03) 49.91,193.84 PU5001.18
  TOP w0.635: PR5007.1 50.93,194.86 v1(50.1,194.03)
PWR_DDR4_BT1: length 2.8
  TOP w0.635: PR5007.2 51.48,197.73 52.32,197.73 ; 52.32,197.73 52.58,197.48 PC5008.1 ; 52.32,197.73 v1(52.32,197.76)
PWR_DDR4_CS: length 5.3
  TOP w0.203: PU5001.13 52.32,191.06
  TOP w0.254: 52.32,191.06 52.52,191.06 52.7,190.88 53.21,190.88 53.47,191.13 53.47,192.71 v1(53.59,192.84) 53.67,192.91 PR5003.1
PWR_DDR4_FB: length 5.2
  TOP w0.203: 48.48,188.88 PU5001.6
  TOP w0.254: v1(44.83,188.15) PR5024.2 PC5013.2 48.01,188.15 PR5025.1 48.13,188.53 48.48,188.88
PWR_DDR4_LDOIN: length 0.8
  TOP w0.203: PU5001.19 49.51,193.45
  vias: v1(48.87,194.4)
PWR_DDR4_LG: length 18.4
  TOP w0.203: PU5001.15 52.13,191.86 v3(52.5,192.23)
  TOP w0.635: PU5003.4 v3(64.14,186.49)
  BOTTOM w0.635: v3(52.5,192.23) 51.94,191.67 51.94,190.5 52.58,189.87 53.88,189.87 v1(56.49,187.25) 57.25,186.49 v3(64.14,186.49)
PWR_DDR4_LX: length 35.6
  TOP w0.203: PU5001.16 51.31,192.61 51.97,193.27
  TOP w0.635: PC5008.2 52.83,194.94 v3(52.83,193.8) 52.5,193.8 51.97,193.27 ; PR5004.2 72.9,197.49
  TOP w1.016: PL5001.1 76.53,194.17 ; PL5001.1 75.39,193.03 ; PL5001.1 75.39,195.32 ; PL5001.1 74.24,194.17
  BOTTOM w0.635: v3(52.83,193.8) 72.14,193.8 v3(72.26,193.68)
  BOTTOM w1.016: PL5001.1 76.53,194.17 ; PL5001.1 74.24,194.17 ; PL5001.1 75.39,193.03 ; PL5001.1 75.39,195.32
  vias: v1(68.3,187.32) v1(71.53,196.77) v1(75.29,189.99) v3(72.64,188.59) v3(73.03,195.83) v3(73.03,192.15) v3(74.3,196.85) v3(74.3,189.1) v3(75.44,196.85) v3(75.56,191.77) v3(77.47,196.22) v3(77.47,192.41)
PWR_DDR4_UG: length 23.2
  TOP w0.203: v3(51.08,193.73) 50.98,193.62 50.82,193.62 50.31,193.11 PU5001.17
  TOP w0.635: PR5005.2 68.96,201.17 v3(68.45,200.66)
  BOTTOM w0.635: v3(68.45,200.66) v1(65.53,197.74) 63.25,195.45 52.81,195.45 v3(51.08,193.73)
PWR_DDR4_VDDQ: length 47.9
  TOP w0.203: PU5001.5 47.8,189.69
  TOP w0.381: PR5024.1 42.61,189.04 v1(42.42,188.85) 42.42,187.45 42.93,186.94 42.93,185.42 44.35,184 52.73,184 53.14,184.4 72.34,184.4 77.03,189.09 PR5019.1
  TOP w0.508: PR5024.1 PC5013.1 47.14,189.04 47.8,189.69
PWR_DDR4_VTTREF: length 3.7
  TOP w0.203: PC5015.1 v1(45.97,189.99) 47.12,189.99 47.78,190.66 PU5001.4
PWR_GT_BST1: length 4.6
  TOP w0.305: PU4602.1 11.57,85.11 10.97,85.7
  TOP w0.635: v1(8.29,87.07) PR4601.1 9.53,86.31 10.13,85.7 10.97,85.7
PWR_GT_BST1_R: length 1.8
  TOP w0.635: PC4603.1 11.76,87.38 PR4601.2
PWR_GT_BST2_R: length 2.7
  TOP w0.635: PR4608.2 14.3,127.76 PC4608.1
PWR_GT_COMP: length 5.3
  TOP w0.203: PU4401.18 15.37,70.65
  TOP w0.254: PC4419.2 PC4418.2 13.56,71.09 v1(14.1,71.63) 14.39,71.63 15.37,70.65
PWR_GT_COMP_A: length 2.4
  TOP w0.254: PC4417.1 9.07,74.54 PR4439.2 v1(9.21,75.95)
PWR_GT_COMP_R: length 2.8
  TOP w0.254: v1(9.65,71.75) 10.86,71.75 PR4440.2 11.37,71.82 12.09,71.09 PC4418.1
PWR_GT_CSCOMP: length 52.3
  TOP w0.203: PU4401.19 13.8,70.25 PR4457.2
  TOP w0.254: PR4457.2 12.73,70.17 PC4425.1 PC4424.1 11.94,70.3 11.25,70.99 10.22,70.99 PR4451.1 9.97,70.42 10.19,70.21 11.15,70.21 v2(11.18,70.23) ; PR4455.1 20.83,101.66 20.83,103.95 v2(20.64,104.14)
  BOTTOM w0.254: v2(20.64,104.14) 20.51,104.01 v1(18.54,104.01) 17.51,104.01 12.44,98.94 12.44,93.59 10.41,91.57 10.41,86.09 11.18,85.33 v2(11.18,70.23)
PWR_GT_CSN1: length 49.2
  TOP w0.203: PU4401.24 16.18,68.25 15.49,67.56
  TOP w0.254: PR4459.2 10.99,65.45 11.33,65.79 12.36,65.79 v2(12.55,65.6) PR4443.2 PC4420.2 14.64,65.6 14.86,65.81 14.86,66.42 15.49,67.06 15.49,67.56
  BOTTOM w0.254: v1(25.15,87) 24.74,87 ; 24.74,87 24.74,83.39 22.1,80.75 15.57,80.75 13.84,79.02 13.84,68.62 12.85,67.63 12.85,67.6 12.7,67.44 12.7,67.44 12.62,67.36 12.62,65.7 12.55,65.62 v2(12.55,65.6) ; 24.74,87 24.74,96.67 24.61,96.8 24.61,97.26 PG4602.2
PWR_GT_CSN2: length 68.5
  TOP w0.203: PU4401.26 16.75,67.04 15.94,66.23
  TOP w0.254: v2(12.26,61.19) PR4460.2 11.94,62.29 PR4446.2 PC4421.2 13.14,63.06 13.64,63.55 14.22,63.55 15.62,64.95 15.62,65.91 15.94,66.23
  BOTTOM w0.254: PG4604.2 24.84,106.06 22.32,103.54 ; 22.32,103.54 21.27,102.49 17.78,102.49 13.97,98.68 13.97,93.09 11.94,91.06 11.94,86.37 13.63,84.68 13.63,80.6 12.57,79.55 12.57,69.15 11.56,68.13 11.56,65.53 12.41,64.68 12.41,62.19 12.26,62.04 v2(12.26,61.19) ; 22.32,103.54 v1(22.61,103.25)
PWR_GT_CSP1: length 38.6
  TOP w0.254: v2(12.32,67.82) 12.13,67.63 PR4444.1 10.1,67.63 PR4449.2
  BOTTOM w0.254: v2(12.32,67.82) 13.33,68.83 13.33,79.23 15.36,81.25 21.89,81.25 24.23,83.6 24.23,84.84 ; 24.23,84.84 24.23,94.56 PG4601.2 ; 24.23,84.84 v1(23.88,84.84)
PWR_GT_CSP1_IC: length 6.8
  TOP w0.203: PU4401.23 15.86,68.65 15.26,68.05 15.24,68.05
  TOP w0.254: PR4444.2 11.43,66.48 PR4443.1 PC4420.1 14.83,67.17 v1(14.83,67.56) 14.99,67.72 14.99,67.79 15.24,68.05
PWR_GT_CSP2: length 60.1
  TOP w0.254: PR4453.2 9.84,63.5 PR4448.1 9.97,63.19 10.68,62.48 v2(11.3,62.48)
  BOTTOM w0.254: 23.36,105.29 21.06,103 17.57,103 13.46,98.89 13.46,93.3 11.43,91.27 11.43,86.16 13.12,84.47 13.12,80.81 12.06,79.76 12.06,69.36 11.05,68.34 11.05,65.32 11.9,64.47 11.9,63.08 v2(11.3,62.48) ; 23.36,105.29 24.33,106.27 24.33,108.69 PG4603.2 ; 23.36,105.29 v1(23.11,105.54)
PWR_GT_CSP2_IC: length 8.4
  TOP w0.203: 15.88,67.31 15.88,67.45 16.28,67.85 PU4401.25
  TOP w0.254: PR4448.2 11.3,63.63 11.62,63.94 PR4446.1 PC4421.1 13.68,63.94 v1(14.2,64.47) 15.24,65.51 15.24,66.17 15.88,66.8 15.88,67.31
PWR_GT_CSREF: length 15.5
  TOP w0.203: PU4401.22 15.8,69.05 15.15,68.4 14.79,68.4 14.59,68.2
  TOP w0.254: PR4460.1 13.14,61.15 v2(13.21,61.09) ; v2(13.21,64.77) 13.08,64.64 11.68,64.64 11.43,64.39 10.73,64.39 PR4459.1 ; 14.59,68.2 PC4427.1 13.91,67.25 v2(13.97,67.18)
  BOTTOM w0.254: v2(13.97,67.18) 13.97,65.53 v2(13.21,64.77) 13.72,64.26 v1(13.72,62.99) 13.72,61.59 v2(13.21,61.09)
PWR_GT_CSSUM: length 13.1
  TOP w0.203: PU4401.21 15.73,69.45 15.21,68.94 14.83,68.94
  TOP w0.254: 8.89,66.17 v1(8.89,67.16) 8.89,68.14 PR4452.2 11.46,68.77 PC4424.2 PC4425.2 13.32,68.76 14.66,68.76 14.83,68.94 ; 8.89,66.17 PR4449.1 ; 8.89,66.17 8.89,65.15 PR4453.1
PWR_GT_DOUT: length 9.1
  TOP w0.203: PU4401.16 15.88,71.45
  TOP w0.254: PR4442.1 10.08,74.66 PR4439.1 11.81,74.55 v1(11.94,74.42) 12.27,74.42 13.16,73.53 13.79,73.53 15.88,71.45
PWR_GT_EN1: length 2.4
  TOP w0.254: PU4602.3 v1(10.29,84) 9.33,84 PR4606.2
PWR_GT_EN2: length 3.6
  TOP w0.254: PR4612.2 v1(16.15,122.3) 16.15,122.48 17.09,123.41 PU4605.3
PWR_GT_FB: length 10.1
  TOP w0.203: PU4401.17 15.69,71.05
  TOP w0.254: PC4417.2 PR4442.2 PR4440.1 11.43,72.71 PC4419.1 12.13,73.02 v1(12.19,73.09) 13.65,73.09 15.69,71.05
PWR_GT_HG1: length 21.5
  TOP w0.305: v3(13.97,85.85) 13.6,85.48 PU4602.8
  TOP w0.635: v3(18.95,100.69) 18.95,101.93 18.06,102.82 PR4604.1
  BOTTOM w0.635: v3(18.95,100.69) 18.77,100.69 16.13,98.04 16.13,88.01 v1(15.53,87.41) v3(13.97,85.85)
PWR_GT_HG1_R: length 3.6
  TOP w0.635: PR4604.2 16.57,100.44 PR4603.1 16.57,97.74 PU4601.4
PWR_GT_HG2: length 12.3
  TOP w0.305: PU4605.8 16.09,126.53 v3(15.37,127.25)
  TOP w0.635: PR4610.1 v3(16,119.1)
  BOTTOM w0.635: v3(16,119.1) 13.97,121.13 v1(13.97,124.46) 13.97,126.24 14.99,127.25 v3(15.37,127.25)
PWR_GT_HG2_R: length 3.8
  TOP w0.635: PU4604.4 17.17,114.18 17.17,115.4 PR4609.1 16.31,115.7 PR4610.2
PWR_GT_ILIM: length 3.2
  TOP w0.203: v1(14.86,69.6) 15.03,69.6 15.28,69.85 PU4401.20
  TOP w0.254: PR4457.1 13.79,69.28 14.11,69.6 v1(14.86,69.6)
PWR_GT_IOUT: length 4.4
  TOP w0.203: PU4401.13 17.41,73.65
  TOP w0.254: PR4458.1 PC4426.1 v1(16.26,74.42) 16.64,74.42 17.41,73.65
PWR_GT_LG1: length 12.7
  TOP w0.305: PU4602.5 v3(14.61,83.5)
  TOP w0.635: PU4603.4 v3(22.48,84.07)
  BOTTOM w0.635: v3(22.48,84.07) 22.48,84.84 21.84,85.47 v1(16.51,85.47) 15.54,85.47 14.61,84.53 v3(14.61,83.5)
PWR_GT_LG2: length 6.7
  TOP w0.305: v3(19.43,126.49) 18.77,126.49 18.54,126.26 PU4605.5
  TOP w0.635: v3(20.26,123.51) 20.27,123.49 PU4606.4
  BOTTOM w0.635: v3(19.43,126.49) v1(19.43,124.56) 19.43,124.33 v3(20.26,123.51)
PWR_GT_PWM1: length 41.2
  TOP w0.203: PU4401.28 17.81,66.22
  TOP w0.254: v1(16.13,63.73) 17.02,64.62 17.02,65.43 17.81,66.22
  TOP w0.305: v2(9.33,84.96) 9.39,84.91 10.67,84.91 11.08,84.5 PU4602.2
  TOP w0.381: v1(16.13,63.73) v2(16.13,62.74) PR4465.1
  BOTTOM w0.381: v2(16.13,62.74) 16.13,61.19 14.19,59.25 12.23,59.25 9.33,62.14 v2(9.33,84.96)
PWR_GT_PWM2: length 85.9
  TOP w0.203: PU4401.29 18.21,65.81 18.07,65.67
  TOP w0.254: 18.07,65.67 17.42,65.02 v1(17.42,63.69)
  TOP w0.305: 16.59,123.65 PU4605.2
  TOP w0.381: PR4441.1 v2(17.14,62.74) 17.14,63.12 17.4,63.37 17.4,63.67 v1(17.42,63.69) ; 16.59,123.65 16.1,123.16 13.18,123.16 v2(13.08,123.06)
  BOTTOM w0.381: v2(13.08,123.06) 8.45,118.43 8.45,61.77 11.86,58.36 14.59,58.36 17.14,60.91 v2(17.14,62.74)
PWR_GT_SNB1: length 1.4
  TOP w0.635: PR4605.2 PC4605.1
PWR_GT_SNB2: length 2.5
  TOP w0.635: PR4611.2 v1(26.54,120.9) 26.57,120.93 PC4610.1
PWR_GT_SW1: length 24.3
  TOP w0.305: 14.27,84.5 PU4602.7
  TOP w0.635: v3(19.68,98.68) 19.43,98.93 18.29,98.93 17.78,99.44 PR4603.2 ; PR4605.1 15.52,89.23 15.52,89.15 14.61,88.24 PC4603.2 14.61,86.69 14.99,86.31 14.99,85.22 14.27,84.5
  TOP w1.016: 21.11,94.5 PL4601.1 ; PL4601.1 19.66,95.95 ; PL4601.1 22.56,95.95 ; PL4601.1 21.11,97.4
  BOTTOM w0.254: PG4601.1 21.17,96.01 PL4601.1
  BOTTOM w1.016: 22.71,96.98 21.68,95.95 PL4601.1 ; 19.66,95.95 PL4601.1 ; PL4601.1 21.11,94.5 ; PL4601.1 21.11,97.4
  vias: v1(18.54,91.19) v1(22.61,87.38) v3(18.54,96.52) v3(18.67,94.61) v3(18.92,92.84) v3(22.23,98.68) v3(22.61,92.71)
PWR_GT_SW2: length 30.6
  TOP w0.305: 16.59,127.08 PU4605.7
  TOP w0.635: 16.59,127.08 16.59,128.53 PC4608.2 16.71,128.65 v3(18.29,128.65)
  TOP w1.016: PL4602.1 21.11,111.62 ; PL4602.1 21.11,108.72 ; PL4602.1 22.56,110.17 ; PL4602.1 19.66,110.17
  BOTTOM w0.254: PG4603.1 21.17,110.24 PL4602.1
  BOTTOM w0.635: v3(18.5,119.09) 15.62,121.97 15.62,125.55 16.89,126.82 16.89,127.51 18.03,128.65 v3(18.29,128.65)
  BOTTOM w1.016: PL4602.1 21.83,110.17 22.76,111.1 ; PL4602.1 19.66,110.17 ; PL4602.1 21.11,108.72 ; PL4602.1 21.11,111.62
  vias: v1(19.94,114.17) v1(20.07,118.75) v1(26.8,117.86) v3(18.54,116.84) v3(18.67,113.67) v3(18.67,111.76) v3(19.43,108.2) v3(21.59,114.55) v3(22.48,108.2) v3(22.73,112.45) v3(22.73,111.51) v3(23.11,114.55) v3(25.65,116.33) v3(26.92,116.33)
PWR_GT_TCP: length 49
  TOP w0.254: v2(21.45,104.14) 21.34,104.03 21.34,101.66 PR4455.2 ; v2(11.13,69.47) 10.16,69.47 10.1,69.53 9.65,69.53 PR4452.1 9.08,70.1 PR4451.2
  BOTTOM w0.254: v2(21.45,104.14) 20.69,104.9 v1(19.68,104.9) 17.68,104.9 11.93,99.15 11.93,93.8 9.91,91.78 9.91,85.88 10.67,85.12 10.67,69.93 v2(11.13,69.47)
PWR_GT_TSNS: length 5.9
  TOP w0.203: PU4401.27 17.41,66.54 17.02,66.15
  TOP w0.254: 17.02,66.15 16.51,65.64 16.51,65.19 v1(16.36,65.03) 16.36,65 15.11,63.75 PC4428.1 PR4463.1
PWR_GT_TSNS_R: length 49.6
  TOP w0.254: PR4463.2 14.1,61.02 PR4467.1 13.97,60.96 v2(13.21,60.2) ; PR4468.1 14.16,100.65 v2(13.34,101.47)
  BOTTOM w0.254: v2(13.34,101.47) 10.99,99.12 10.99,93.58 9.27,91.86 9.27,85.79 10.16,84.9 v1(10.16,63.88) 10.16,62.48 12.45,60.2 v2(13.21,60.2)
PWR_GT_VCC1: length 4.9
  TOP w0.305: PU4602.4 11.57,82.94 11.56,82.93
  TOP w0.508: 11.56,82.93 PC4604.2 10.36,82.04 PR4602.2 9.86,81.08 v1(9.88,81.05)
PWR_GT_VCC2: length 3.6
  TOP w0.305: PU4605.4 18.75,124.23 PC4609.2
  TOP w0.508: PR4607.2 18.24,122.5 19,123.27 PC4609.2
PWR_GT_VSN: length 6
  TOP w0.203: 14.86,73.61 16.22,72.25 PU4401.14
  TOP w0.254: PR4450.2 PC4423.2 14.22,74.68 14.48,74.42 v1(14.86,74.42) 14.86,73.61
PWR_GT_VSP: length 7.2
  TOP w0.203: PU4401.15 16.08,71.85
  TOP w0.254: 16.08,71.85 13.64,74.3 v1(13.34,74.3) 12.19,75.44 PC4422.1 PR4447.2
PWR_LED_G: length 14.3
  TOP w0.254: Q6401.6 19.26,234.46 R6409.1 20.46,234.42 C6402.1 20.85,236.07 v1(20.5,236.42) 19.74,237.19 16.23,237.19 15.2,238.21 PWRSW1.L2
PWR_LED_Y: length 11.7
  TOP w0.254: PWRSW1.L1 10.97,240.22 10.97,234.82 v1(11,234.8) 11.01,234.78 C6403.1 13.07,234.78 R6413.2 14.7,233.16 Q6401.3
PWR_PSYS: length 6.5
  TOP w0.203: PU4401.8 19.41,73.96
  TOP w0.254: PR4462.1 20.45,78.04 PR4471.1 19.25,77.74 19.25,75.67 v1(19.33,75.59) 19.3,75.56 19.3,74.07 19.41,73.96
PWR_RT6575_LDO5: length 3.9
  TOP w0.203: v1(31.83,194.84) 32.05,194.62 PU4902.13
  TOP w0.305: PC4917.1 31.43,196.01 PG4903.1
  TOP w0.508: PC4917.1 31.55,195.13 v1(31.83,194.84)
PWR_RT6575_PG: length 2.9
  TOP w0.203: PR4958.1 35.88,190.88 v1(35.18,190.88) 34.8,190.88 34.31,191.37 PU4902.7
PWR_RT6575_VIN: length 4.6
  TOP w0.203: PU4902.12 32.45,193.9 32.88,194.32
  TOP w0.508: 32.88,194.32 33.15,194.59 v1(33.15,194.74) 33.15,195.58 PC4906.1 32.89,197.31 PR4932.2
PWR_V_12V_CPU_S0_VSA: length 5.7
  TOP w0.305: PR4705.1 PR4706.1 ; PR4705.1 PR4704.1 PR4703.1 PR4702.1 PR4701.1 ; PR4705.1 111.96,41.02 PC4703.1
  vias: v1(113.03,42.93)
PWR_VCCIO_DRV: length 8
  TOP w0.584: 132.11,90.23 131.8,90.23 131.29,90.75 PU4801.5 131.29,91.72 130,93.01 PR4810.2
  TOP w0.635: 132.11,90.23 132.74,90.23 133.26,90.75 133.26,90.79 v1(133.58,91.11) 133.69,91.22 PC4807.1 PR4811.1
PWR_VCCIO_DRV_R: length 5.1
  TOP w0.635: PU4802.4 126.36,94.18 127.2,93.34 PR4810.1 128.18,93.23 PC4806.1
PWR_VCCIO_FB: length 12.9
  TOP w0.254: PU4801.3 132.35,88.49 133.88,90.02 v1(134.98,90.02) 136.7,90.02 137.08,90.4 137.08,92.64 136.7,93.03 PC4812.2 ; PC4807.2 134.54,93.1 PR4816.1 PC4811.2 135.64,93.03 PC4812.2 ; PR4814.2 PC4812.2
PWR_VCCIO_FB1: length 3.2
  TOP w0.254: PR4814.1 PR4812.1 PR4813.1 135.51,96.34 v1(134.87,96.98)
PWR_VCCIO_FB2: length 2.3
  TOP w0.254: v1(134.49,95.63) 135.06,95.63 PR4813.2 PC4811.1
PWR_VCCIO_FB3: length 2.1
  TOP w0.254: PR4811.2 PC4812.1 136.53,91.21 v1(136.45,91.14)
PWR_VCCIO_SS: length 2.8
  TOP w0.254: PU4801.4 132.25,91.96 132.61,92.33 v1(132.61,92.71) 132.42,92.9 PC4805.1
PWR_VCCIO_VCC: length 5.9
  TOP w0.508: PU4801.6 129.21,91.19 PC4804.1 128.63,90.6 128.63,88.01 v1(128.68,87.96) 128.68,87.29 PR4808.2
PWR_VCCIO_VCCSA_EN: length 324.2
  TOP w0.254: v2(195.3,206.15) 195.61,206.45 195.61,212.03 198.79,215.21 212.08,215.21 D4303.2 ; v2(121.84,28.29) 121.82,28.29 119.9,30.22 119.9,32.34 119.89,32.35 PU4701.3 ; v2(164.72,44.83) 164.26,45.29 164.26,48.19 163.97,48.48 163.97,49.73 163.43,50.27 163.43,59.54 v2(163.7,59.82) 163.7,60.66 167.26,64.22 167.26,103.33 167.36,103.43 167.36,103.55 170.56,106.76 170.56,109.77 175.44,114.64 175.44,132.42 173.51,134.35 173.51,140.91 171.58,142.84 171.58,148.03 167.41,152.2 167.41,165.96 166.37,167 166.37,168.61 166.95,169.19 166.95,178.49 164.47,180.97 v2(164.47,182.25) ; v2(141.1,77.09) 141.1,80.02 136.16,84.96 134.75,84.96 134.18,85.53 R4801.2 134.19,85.74 U4801.3 131.06,87.23 130.34,87.96 PU4801.1
  BOTTOM w0.254: v2(164.47,182.25) 165.13,182.25 167.74,184.86 170.13,184.86 189.08,203.81 v1(189.59,203.81) 193.78,203.81 195.3,205.33 v2(195.3,206.15) ; v2(163.7,59.82) 152.4,71.12 152.4,73.83 149.14,77.09 v2(141.1,77.09) ; v2(121.84,28.29) 121.86,28.29 122.48,28.91 127.28,28.91 127.61,29.24 131.58,29.24 132.44,30.1 150.86,30.1 156.97,36.21 156.97,42.1 160.65,45.77 163.26,45.77 164.2,44.83 v2(164.72,44.83)
PWR_VCCIO_VIN: length 8.9
  TOP w0.457: PR4801.1 126.86,105.49 PC4803.1
  TOP w0.508: PR4809.1 131.67,104.75 ; PR4802.1 128.63,104.67 PC4801.1 127.86,104.11 PR4801.1 ; PR4806.1 130.91,104.65 ; PR4805.1 133.2,104.75 ; PR4807.1 132.44,104.67 ; PR4803.1 129.39,104.75 ; PR4804.1 130.15,104.75
  vias: v1(130.45,102.26) v1(133.22,103.28)
PWR_VCCSA_BOOT: length 3.9
  TOP w0.305: 118.36,36.09 PU4701.10
  TOP w0.635: 118.36,36.09 118.26,36.09 117.17,35 PR4709.1 v1(116.64,33.76)
PWR_VCCSA_BOOT_R: length 2.9
  TOP w0.635: PC4704.2 117.86,38.2 116.67,38.2 v1(116.64,38.16) PR4709.2
PWR_VCCSA_CS: length 2.5
  TOP w0.254: PR4708.2 118.87,31.37 v1(119.1,31.6) 119.39,31.88 PU4701.2
PWR_VCCSA_FB: length 8.5
  TOP w0.254: PU4701.4 120.39,31.68 v1(120.93,31.14) 121.28,30.78 122.61,30.78 123.57,31.75 PC4708.2 PR4714.2 PR4716.1
PWR_VCCSA_FB1: length 22.1
  TOP w0.254: PG4701.2 v1(125.61,52.78) 126.19,52.2 126.19,38.81 123.63,36.26 PR4715.1 123.57,34.86 PC4708.1
PWR_VCCSA_LG: length 12.8
  TOP w0.305: PU4701.6 121.44,36.09 v3(121.67,36.32)
  TOP w0.635: PU4702.8 v3(122.26,46.96)
  BOTTOM w0.635: v3(121.67,36.32) 121.67,37.86 v1(122.26,38.46) v3(122.26,46.96)
PWR_VCCSA_PG: length 31
  TOP w0.254: v2(100.14,28.02) 101.02,27.14 101.02,22.91 100.2,22.1 98.74,22.1 R4006.1 ; v2(116.92,29.05) 116.92,30.56 118.89,32.53 PU4701.1
  BOTTOM w0.254: v2(100.14,28.02) v1(100.79,28.67) 101.17,29.05 102.46,29.05 v2(116.92,29.05)
PWR_VCCSA_PHASE: length 11.2
  TOP w0.305: PC4704.1 119.89,38.35 PU4701.8
  TOP w0.635: v3(117.45,48.56) 116.64,47.75 PR4710.1 ; PU4702.9 119.89,44.05 119.19,43.35 118.86,43.01 118.85,43 118.86,40.98 118.86,39.94 119.71,39.09 PC4704.1
  vias: v1(118.49,49.76) v1(120.9,47.93) v3(117.37,50.16) v3(118.87,51.11) v3(120.57,51.1) v3(122.25,51) v3(122.35,49.43)
PWR_VCCSA_RF: length 3.5
  TOP w0.254: PR4711.1 122.56,31.95 v1(122.48,31.88) 121.44,31.88 120.89,32.43 PU4701.5
PWR_VCCSA_SNB: length 2.3
  TOP w0.635: PC4707.1 v1(124.71,47.5) 124.71,48.64 PR4713.2
PWR_VCCSA_UG: length 15.8
  TOP w0.305: PU4701.9 119.39,36.82 v3(118.94,37.27)
  TOP w0.635: PR4707.2 112.45,47.14 v3(112.93,47.62)
  BOTTOM w0.635: v3(118.94,37.27) 118.94,39.18 v1(115.9,42.21) 112.93,45.19 v3(112.93,47.62)
PWR_VCCSA_UG_R: length 4.7
  TOP w0.635: PU4702.1 114.63,45.97 PR4707.1 114.38,47.64 PR4710.2 114.4,47.84 v1(114.4,48.9)
PWR_VCCSA_VCC: length 5.5
  TOP w0.305: 120.65,37.08 120.39,36.82 PU4701.7
  TOP w0.508: 120.65,37.08 121.28,37.72 PC4706.1 121.34,38.02 PR4712.1 120.52,40.44 v1(120.11,40.44)
PWR_VCORE_BST1: length 4.5
  TOP w0.305: 36.67,48.75 37.23,48.2 PU4502.1
  TOP w0.635: 36.67,48.75 36.12,49.31 PR4501.1 36.04,50.06 v1(34.75,50.06)
PWR_VCORE_BST1_R: length 1.7
  TOP w0.635: PR4501.2 38.68,50.62 PC4503.1
PWR_VCORE_BST2: length 3.6
  TOP w0.305: PU4506.1 54.99,53.71
  TOP w0.635: 54.99,53.71 54.46,54.24 PR4507.1 53.24,54.94 v1(53.11,54.81)
PWR_VCORE_BST2_R: length 1.5
  TOP w0.635: PR4507.2 56.69,55.24 PC4508.1
PWR_VCORE_BST3: length 3.4
  TOP w0.305: PU4510.1 73.24,55.97 72.95,56.26
  TOP w0.635: PR4514.1 v1(72.69,56.52) 72.95,56.26
PWR_VCORE_BST3_R: length 1.6
  TOP w0.635: PC4513.1 75.01,58.29 PR4514.2
PWR_VCORE_BST4: length 3.8
  TOP w0.305: 92.79,56.87 93.16,56.5 PU4514.1
  TOP w0.635: PR4520.1 91.24,57.48 v1(91.67,57.05) 91.85,56.87 92.79,56.87
PWR_VCORE_BST4_R: length 1.6
  TOP w0.635: PC4518.1 93.55,58.8 PR4520.2
PWR_VCORE_COMP: length 5.8
  TOP w0.203: 24.45,70.8 24.3,70.65 PU4401.48
  TOP w0.254: 24.45,70.8 24.57,70.92 26.13,70.92 v1(26.34,70.71) 26.43,70.62 PC4406.2 28.35,70.62 PC4405.2
PWR_VCORE_COMP_A: length 2.2
  TOP w0.254: PC4404.1 30.56,72.47 v1(30.57,72.45) 30.57,73.27 PR4407.2
PWR_VCORE_COMP_R: length 2.7
  TOP w0.254: PR4408.2 29.33,71.51 29.94,71.51 30.37,71.08 v1(30.37,70.85) 30.37,70.77 30.14,70.54 29.33,70.54 PC4405.1
PWR_VCORE_CSCOMP: length 22.4
  TOP w0.203: 24.28,70.25 PU4401.47
  TOP w0.254: PR4431.1 41.49,67.03 38.38,67.03 35.48,69.93 v1(31.93,69.93) 29.81,69.93 PR4427.1 PC4415.1 PC4413.1 26.49,69.58 PR4433.2 26.25,69.66 25.66,70.25 24.28,70.25
PWR_VCORE_CSN1: length 34.6
  TOP w0.203: PU4401.36 21.01,66.01 21.41,65.61 21.41,64.69
  TOP w0.254: PR4435.2 27.43,58.42 26.92,58.93 26.92,58.99 v2(26.86,59.05) 26.63,59.05 PR4412.2 PC4407.2 24.64,60.01 24.63,60.01 23.94,60.7 23.94,61.15 22.61,62.48 22.61,63.5 21.41,64.69
  BOTTOM w0.254: v2(26.86,59.05) v1(28.32,59.05) 29.12,59.05 31.11,61.05 31.11,63.08 32.56,64.52 39.24,64.52 43.59,60.17 PG4502.2
PWR_VCORE_CSN2: length 45.8
  TOP w0.203: PU4401.38 21.81,66.22 22.47,65.57
  TOP w0.254: PR4436.2 27.46,60.55 27.05,60.96 v2(26.92,60.96) 26.1,61.79 PC4408.2 PR4415.2 24.73,61.79 23.75,62.77 23.75,64.38 22.57,65.57 22.47,65.57
  BOTTOM w0.254: PG4504.2 56.79,65.87 55.61,67.05 ; 55.61,67.05 53.44,69.22 50.34,69.22 46.91,65.79 32.03,65.79 29.84,63.6 29.84,62.48 28.32,60.96 v2(26.92,60.96) ; 55.61,67.05 v1(55.88,67.31)
PWR_VCORE_CSN3: length 74.5
  TOP w0.203: 22.99,66.42 22.88,66.53 PU4401.40
  TOP w0.254: 22.99,66.42 25.59,63.82 PR4419.2 PC4410.2 26.8,63.64 v2(26.8,63.12) 27.24,63.12 PR4437.2
  BOTTOM w0.254: v1(29.08,66.42) 29.36,66.15 ; 29.36,66.15 28.78,65.56 28.78,64.7 27.19,63.12 v2(26.8,63.12) ; 29.36,66.15 30.65,67.44 46.76,67.44 49.81,70.48 54.86,70.48 62.48,62.87 65.79,62.87 67.69,64.77 67.69,71.33 68.75,72.39 73.36,72.39 76.95,68.8 PG4506.2
PWR_VCORE_CSN4: length 102.2
  TOP w0.203: 24.42,67.47 23.64,68.25 PU4401.42
  TOP w0.254: PR4438.2 29.02,65.79 27.98,65.79 27.84,65.65 v2(27.69,65.65) 27.61,65.72 PR4422.2 PC4412.2 25.76,65.72 24.42,67.06 24.42,67.47
  BOTTOM w0.254: v2(27.69,65.65) 27.81,65.77 27.81,66.71 29.51,68.41 ; 29.51,68.41 29.93,68.83 46.12,68.83 49.04,71.75 55.39,71.75 63.01,64.14 65.26,64.14 66.42,65.3 66.42,71.86 68.22,73.66 74.42,73.66 80.9,67.18 84.2,67.18 86.11,69.09 86.11,72.27 86.76,72.92 93.66,72.92 98.41,68.17 PG4508.2 ; 29.51,68.41 v1(29.21,68.71)
PWR_VCORE_CSP1: length 24.5
  TOP w0.254: PR4414.1 PR4426.2 v2(29.53,58.36)
  BOTTOM w0.254: 30.08,59.29 29.53,58.74 v2(29.53,58.36) ; 30.08,59.29 v1(30.31,59.05) ; 30.08,59.29 31.62,60.84 31.62,62.87 32.77,64.01 39.03,64.01 43.23,59.81 44.24,58.8 45.26,58.8 PG4501.2
PWR_VCORE_CSP1_IC: length 10.8
  TOP w0.203: 21.77,65.64 21.77,65.72 21.41,66.08 PU4401.37
  TOP w0.254: 21.77,65.64 21.77,65.43 v1(22.39,64.8) 22.99,64.21 22.99,62.87 24.77,61.09 PC4407.1 PR4412.1 26.02,60.77 26.97,59.82 27.24,59.82 27.62,59.44 PR4414.2
PWR_VCORE_CSP2: length 34.8
  TOP w0.254: PR4429.2 29.48,61.33 v2(29.46,61.34) 29.21,61.59 PR4417.1
  BOTTOM w0.254: v2(29.46,61.34) 29.46,61.38 30.35,62.27 30.35,63.39 32.24,65.28 47.12,65.28 50.55,68.71 53.23,68.71 54.26,67.68 ; v1(54.01,67.44) 54.26,67.68 ; 54.26,67.68 56.43,65.51 PG4503.2
PWR_VCORE_CSP2_IC: length 8.3
  TOP w0.203: PU4401.39 22.21,66.56 22.73,66.04
  TOP w0.254: 22.73,66.04 24.45,64.32 v1(24.45,63.53) 25.02,62.97 PR4415.1 PC4408.1 26.54,62.67 PR4417.2
PWR_VCORE_CSP3: length 65.6
  TOP w0.254: PR4421.1 29.02,63.88 29.28,64.14 v2(29.34,64.14) 29.97,64.14 29.98,64.15 PR4432.2
  BOTTOM w0.254: 75.56,69.47 76.62,68.41 PG4505.2 ; 75.56,69.47 73.15,71.88 68.96,71.88 68.2,71.12 68.2,64.56 66,62.36 62.27,62.36 54.65,69.98 50.02,69.98 46.97,66.93 30.86,66.93 29.29,65.35 29.29,64.19 v2(29.34,64.14) ; 75.56,69.47 v1(75.31,69.22)
PWR_VCORE_CSP3_IC: length 6.9
  TOP w0.203: PU4401.41 23.46,67.85 23.69,67.63
  TOP w0.254: 23.69,67.63 23.69,66.79 v1(24.92,65.56) 25.65,64.82 PR4419.1 PC4410.1 26.8,64.71 PR4421.2
PWR_VCORE_CSP4: length 95.4
  TOP w0.254: PR4434.2 30.23,66.56 PR4425.1 30.11,67.04 v2(29.64,67.51)
  BOTTOM w0.254: v1(90.04,72.14) 90.04,72.42 ; 90.04,72.42 93.45,72.42 99.39,66.47 PG4507.2 ; 90.04,72.42 86.97,72.42 86.61,72.06 86.61,68.88 84.41,66.67 80.69,66.67 74.21,73.15 68.43,73.15 66.93,71.65 66.93,65.09 65.47,63.63 62.8,63.63 55.18,71.25 49.25,71.25 46.33,68.33 30.14,68.33 29.64,67.82 v2(29.64,67.51)
PWR_VCORE_CSP4_IC: length 7.4
  TOP w0.203: 24.13,68.45 23.93,68.65 PU4401.43
  TOP w0.254: 24.13,68.45 24.89,67.69 24.89,67.44 25.72,66.61 PC4412.1 PR4422.1 27.98,66.61 28.04,66.55 v1(28.19,66.55) 28.32,66.67 PR4425.2
PWR_VCORE_CSREF: length 30.1
  TOP w0.203: PU4401.44 24.3,69.05 24.77,68.58
  TOP w0.254: v2(27.78,64.79) 27.88,64.88 28.15,64.88 28.17,64.9 29.65,64.9 30.04,65.28 PR4438.1 ; PR4435.1 v2(28.51,57.59) ; 24.77,68.58 25.5,67.84 v2(25.5,67.56) PC4416.1 ; v2(29.46,60.48) 29.39,60.55 PR4436.1 ; PR4437.1 28.83,62.74 29.21,63.12 v2(29.21,63.25)
  BOTTOM w0.254: v2(29.46,60.48) 29.18,60.2 26.39,60.2 ; 26.39,61.18 26.26,61.31 26.26,63.69 27.36,64.79 ; 26.39,61.18 26.39,60.2 ; 26.39,61.18 28.46,63.25 v2(29.21,63.25) ; 26.39,60.2 26.16,59.97 26.16,58.74 27.31,57.59 v2(28.51,57.59) ; 27.36,64.79 v1(26.18,65.97) 25.5,66.65 v2(25.5,67.56) ; 27.36,64.79 v2(27.78,64.79)
PWR_VCORE_CSSUM: length 19.9
  TOP w0.203: 24.67,69.3 24.52,69.45 PU4401.45
  TOP w0.254: 24.67,69.3 24.67,69.29 25.71,68.25 26.99,68.25 PC4413.2 PC4415.2 28.32,68.5 28.69,68.14 PR4428.2 v1(31.69,68.14) 31.92,67.91 31.92,66.23 31.35,65.67 PR4434.1 31.17,63.93 30.49,63.26 PR4432.1 30.99,62.65 30.99,60.97 PR4429.1 30.45,59.47 PR4426.1
PWR_VCORE_DOUT: length 7.5
  TOP w0.203: 24.06,71.81 23.71,71.45 PU4401.50
  TOP w0.254: PR4407.1 28.48,73.43 v1(28.46,73.45) 28.44,73.47 PR4409.1 26.43,72.47 24.72,72.47 24.06,71.81
PWR_VCORE_DRVON: length 186.2
  TOP w0.203: v2(18.03,64.64) 18.61,65.22 PU4401.30
  TOP w0.254: PR4512.1 v2(51.56,50.9) ; PR4506.1 34.1,47.4 v2(33.3,47.4) ; PR4606.1 v2(7.62,84.1) ; v2(11.97,123.22) 11.97,123.16 12.83,122.3 PR4612.1 ; v2(88.52,54.97) 88.75,55.19 PR4524.1 ; PR4518.1 v2(70.15,54.93)
  BOTTOM w0.254: v2(88.52,54.97) 88.52,54.03 86.18,51.69 76.02,51.69 71.98,55.73 70.94,55.73 v2(70.15,54.93) 70.15,54.91 67.82,52.58 62.64,52.58 59.94,49.89 56.54,49.89 53.37,53.06 52.35,53.06 51.56,52.27 v2(51.56,50.9) 51.56,50.55 45.85,44.83 36.32,44.83 33.76,47.4 v2(33.3,47.4) 33.3,48.39 32.38,49.3 31.24,49.3 22.54,58 22.54,63.33 21.23,64.64 v1(19.68,64.64) v2(18.03,64.64) 18.22,64.45 18.22,60.06 15.7,57.53 11.52,57.53 7.62,61.43 v2(7.62,84.1) 7.62,118.87 v2(11.97,123.22)
PWR_VCORE_EN1: length 3.1
  TOP w0.254: PU4502.3 37.11,47.2 36.63,46.71 v1(36.4,46.71) 35.67,46.71 PR4506.2
PWR_VCORE_EN2: length 2.6
  TOP w0.254: PR4512.2 53.94,51.75 v1(54.14,51.96) 54.39,52.2 PU4506.3
PWR_VCORE_EN3: length 2.9
  TOP w0.254: PR4518.2 72.67,54.03 v1(73.03,54.38) 73.61,54.97 PU4510.3
PWR_VCORE_EN4: length 2.9
  TOP w0.254: PR4524.2 91.59,55.19 v1(91.82,54.96) PU4514.3
PWR_VCORE_FB: length 8
  TOP w0.203: PU4401.49 23.97,71.05 24.37,71.45
  TOP w0.254: PC4406.1 27.45,71.52 26.67,71.52 26.47,71.73 v1(25.07,71.73) 24.65,71.73 24.37,71.45 ; PC4406.1 27.46,72.56 PR4409.2 ; PC4406.1 28.42,71.51 PR4408.1 28.44,72.31 PC4404.2
PWR_VCORE_HG1: length 6.7
  TOP w0.305: v3(40.11,49.35) 40.13,49.33 PU4502.8
  TOP w0.635: v3(42.47,46.44) 42.82,46.8 PR4504.1
  BOTTOM w0.635: v3(40.11,49.35) 40.59,49.35 v1(41.8,48.14) 42.47,47.47 v3(42.47,46.44)
PWR_VCORE_HG2: length 4.8
  TOP w0.305: v3(57.84,53.98) 57.53,53.67 PU4506.8
  TOP w0.635: PR4510.1 v3(59.82,52.5)
  BOTTOM w0.635: v3(57.84,53.98) 58.27,53.98 v1(59.02,53.23) 59.74,52.5 v3(59.82,52.5)
PWR_VCORE_HG3: length 6.1
  TOP w0.305: PU4510.8 76.53,56.9 v3(76.68,57.05)
  TOP w0.635: PR4516.1 v3(79.38,54.37)
  BOTTOM w0.635: v3(76.68,57.05) 76.73,57.05 v1(78.05,55.73) 79.38,54.41 v3(79.38,54.37)
PWR_VCORE_HG4: length 6.4
  TOP w0.305: v3(95.07,57.35) 95.19,57.23 PU4514.8
  TOP w0.635: v3(97.79,54.88) 97.79,55.93 PR4522.1
  BOTTOM w0.635: v3(95.07,57.35) 95.31,57.35 v1(96.75,55.92) v3(97.79,54.88)
PWR_VCORE_ILIM: length 4
  TOP w0.203: 25.53,69.34 25.33,69.53 v1(25.33,69.56) 25.31,69.56 25.02,69.85 PU4401.46
  TOP w0.254: PR4433.1 26.1,68.77 25.53,69.34
PWR_VCORE_IOUT: length 6
  TOP w0.203: PU4401.1 22.71,72.91
  TOP w0.254: 22.71,72.91 23.81,74.02 v1(24.46,74.02) 25.53,75.08 PC4414.1 PR4430.1
PWR_VCORE_LG1: length 17.9
  TOP w0.305: v3(41.17,46.58) 41.06,46.7 PU4502.5
  TOP w0.635: PU4504.4 v3(35.05,51.59) ; PU4503.4 v3(35.05,58.19)
  BOTTOM w0.635: v3(35.05,58.19) v3(35.05,51.59) v1(36.89,49.57) 38.4,48.26 39.62,48.26 41.17,46.71 v3(41.17,46.58)
PWR_VCORE_LG2: length 17.2
  TOP w0.305: PU4506.5 v3(58.51,51.7)
  TOP w0.635: PU4507.4 v3(53.34,62.89) ; PU4508.4 v3(53.34,56.34)
  BOTTOM w0.635: v3(53.34,62.89) v3(53.34,56.34) 53.34,55.27 v1(54.69,53.92) 55.32,53.29 56.87,53.29 58.46,51.7 v3(58.51,51.7)
PWR_VCORE_LG3: length 18
  TOP w0.305: v3(77.62,54.43) 77.43,54.43 77.4,54.47 PU4510.5
  TOP w0.635: PU4512.4 v3(71.63,59.33) ; PU4511.4 v3(71.63,65.94)
  BOTTOM w0.635: v3(77.62,54.43) 77.57,54.43 75.64,56.36 74.19,56.36 v1(72.71,57.85) 71.63,58.93 v3(71.63,59.33) v3(71.63,65.94)
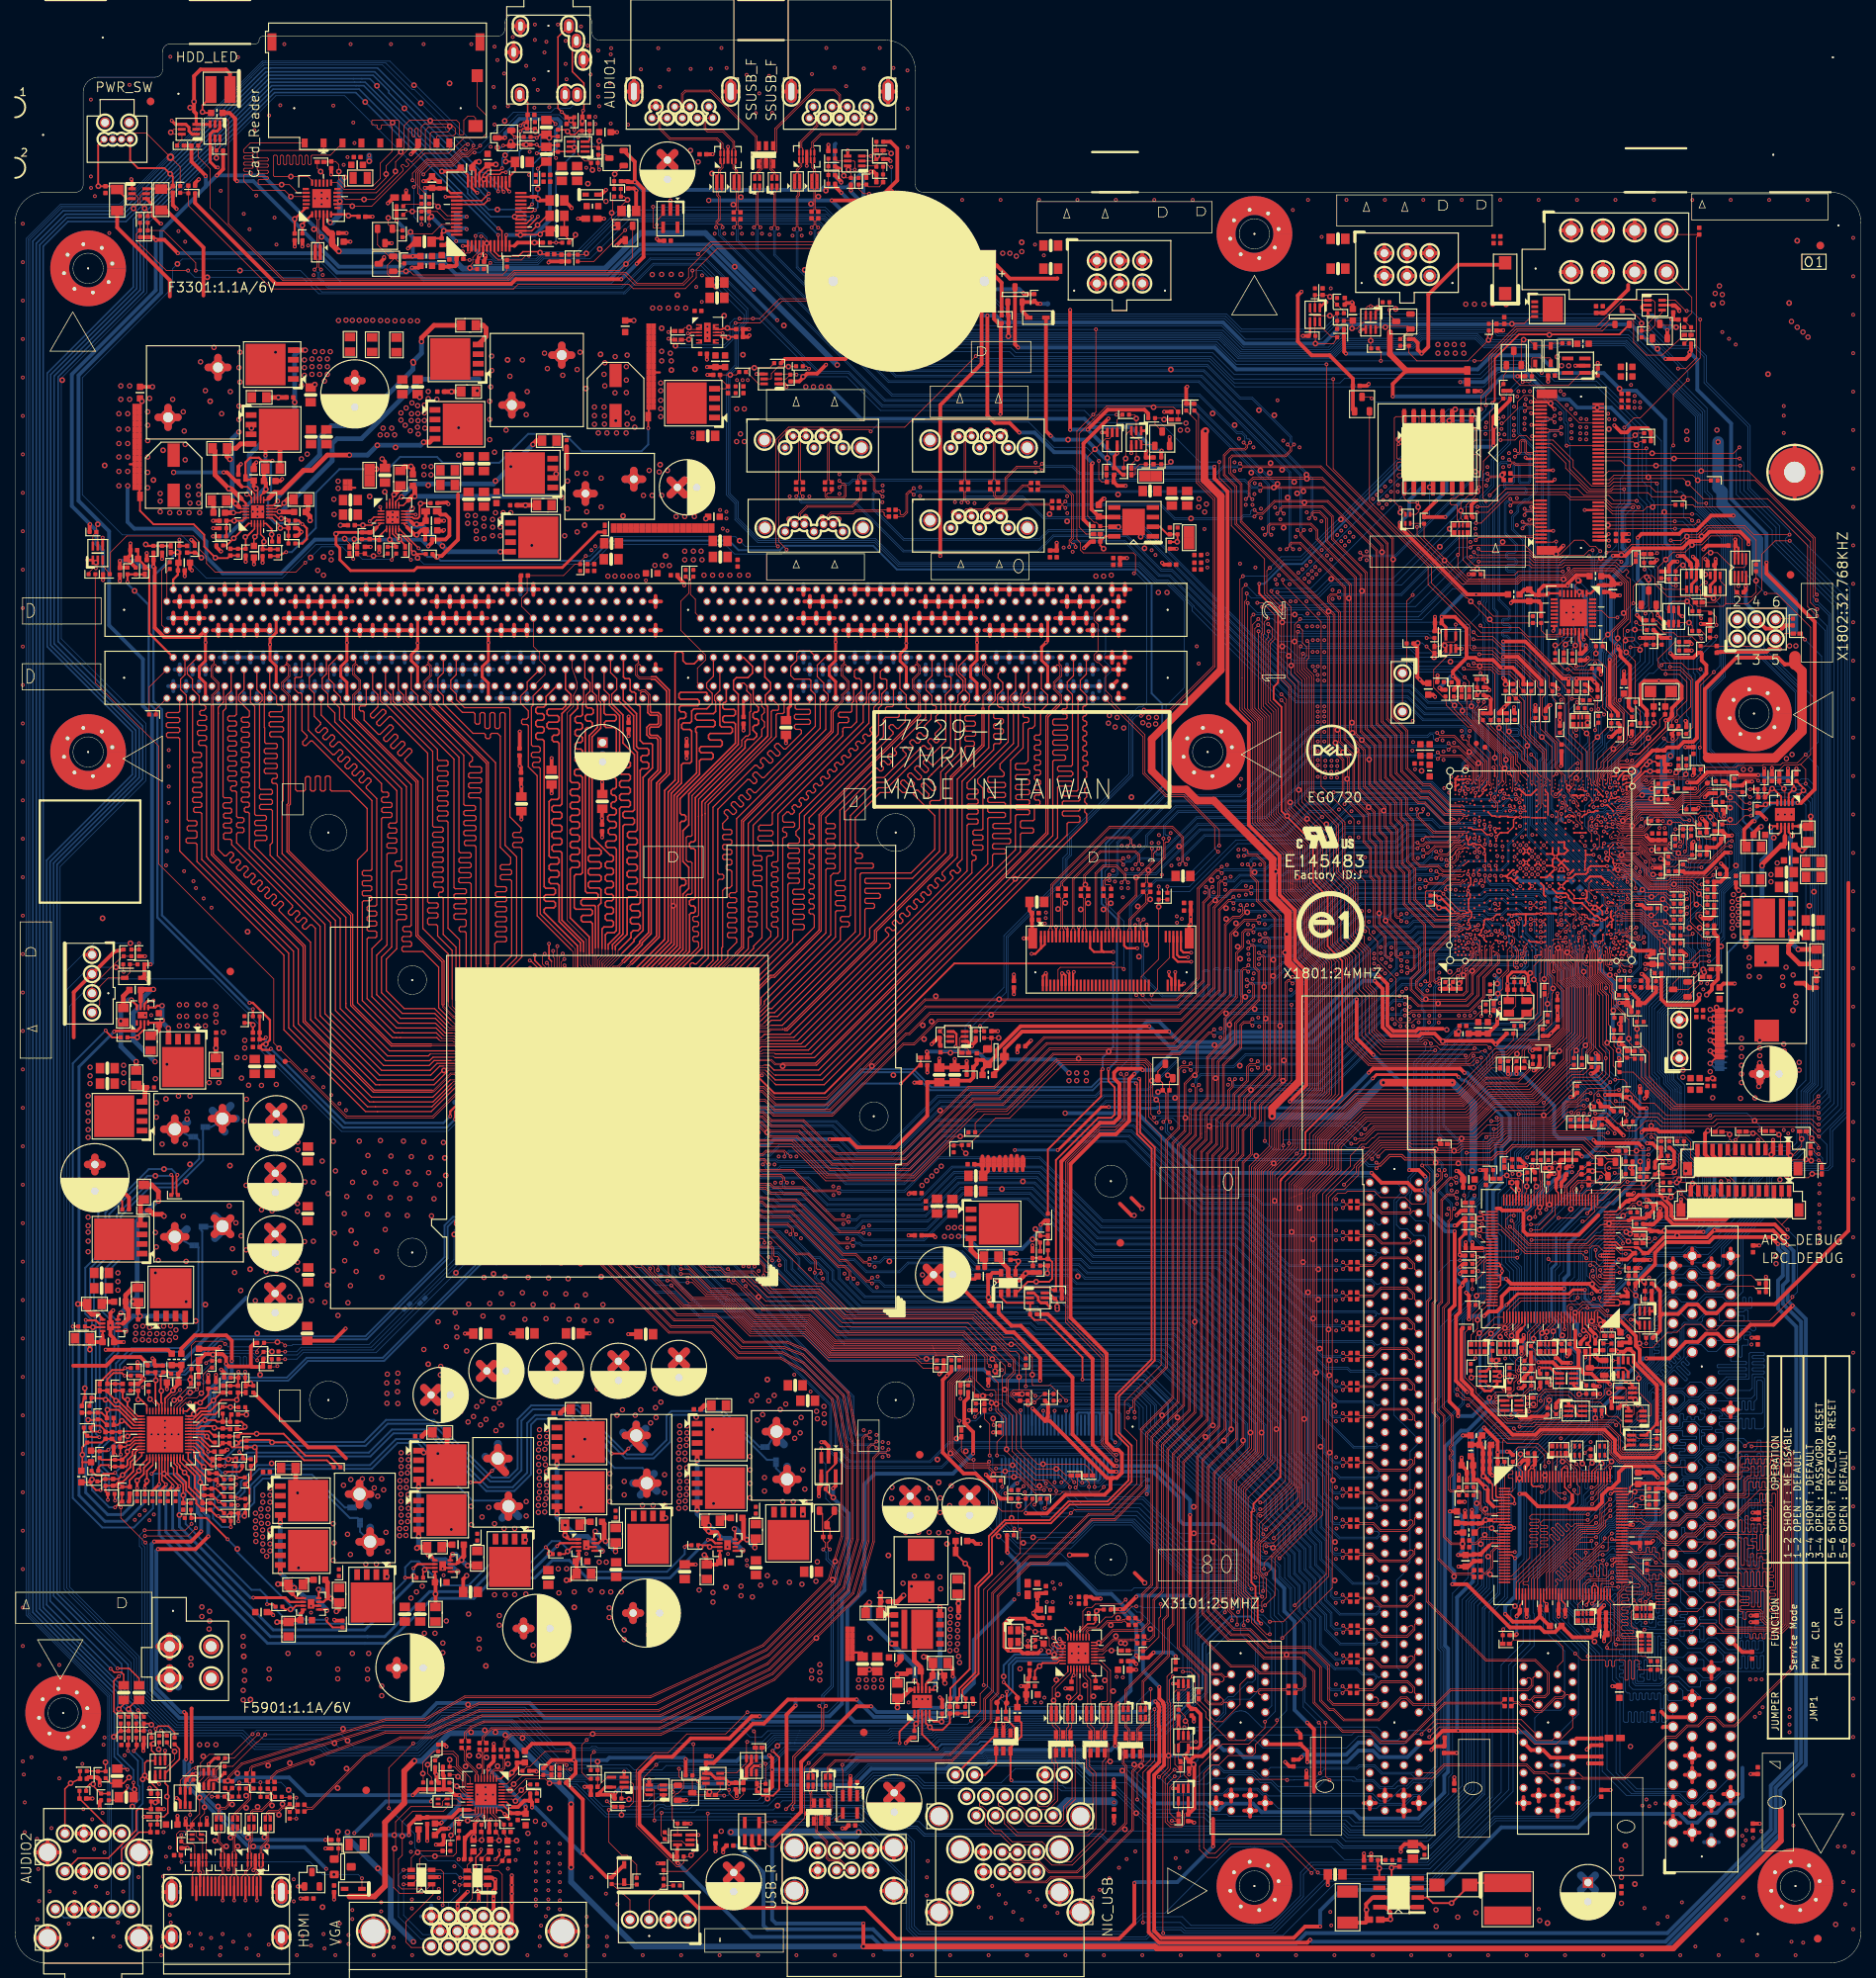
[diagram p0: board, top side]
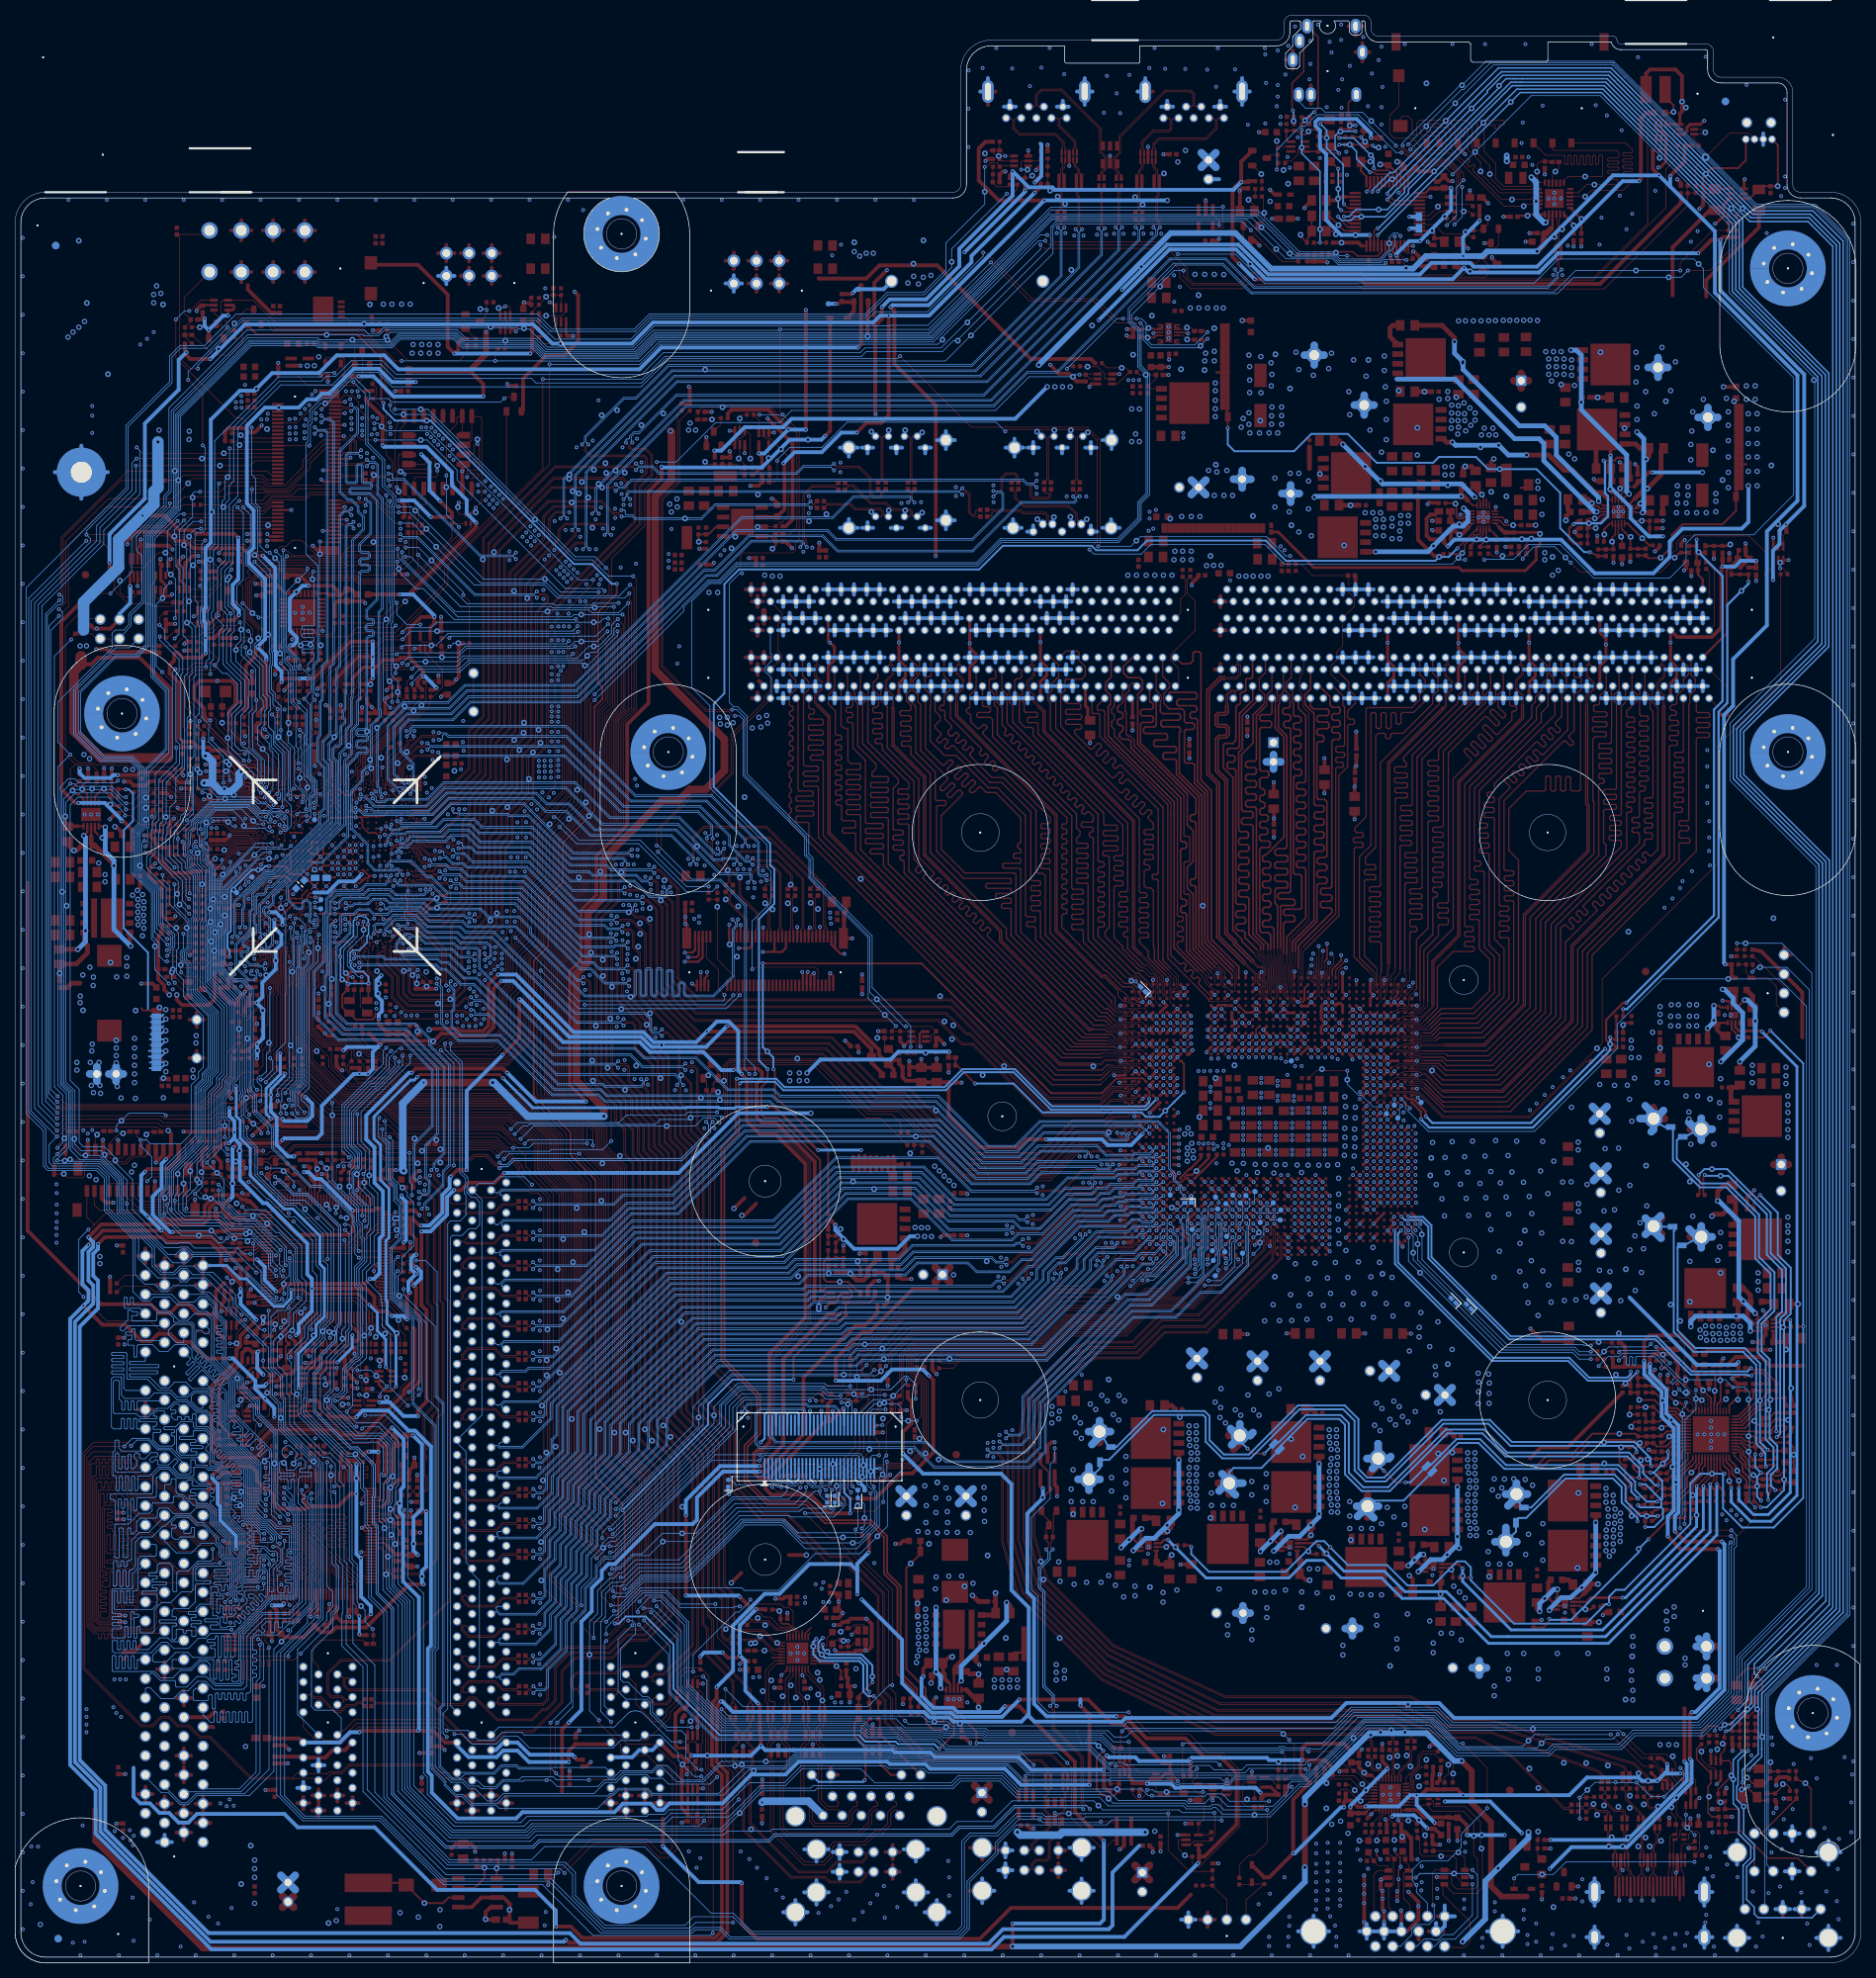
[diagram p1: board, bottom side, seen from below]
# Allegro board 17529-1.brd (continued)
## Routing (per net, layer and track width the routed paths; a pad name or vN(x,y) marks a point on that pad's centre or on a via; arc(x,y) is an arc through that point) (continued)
PWR_VCORE_LG4: length 18.1
  TOP w0.305: v3(96.19,54.48) 96.17,54.46 PU4514.5
  TOP w0.635: PU4516.4 v3(90.17,66.45) ; PU4515.4 v3(90.17,59.84)
  BOTTOM w0.635: v3(90.17,66.45) v3(90.17,59.84) 90.17,59.36 v1(91.71,57.82) 93.42,56.11 94.56,56.11 v3(96.19,54.48)
PWR_VCORE_PWM1: length 31.5
  TOP w0.203: PU4401.34 20.21,64.5 v2(21.72,62.99)
  TOP w0.305: PU4502.2 36.28,47.7 36.1,47.87
  TOP w0.381: v2(31.5,48.26) 35.71,48.26 36.1,47.87 ; v2(21.72,62.99) 21.21,62.48 PR4413.1
  BOTTOM w0.381: v2(21.72,62.99) v1(21.72,59.18) 21.72,57.66 31.12,48.26 v2(31.5,48.26)
PWR_VCORE_PWM2: length 56
  TOP w0.203: PU4401.33 19.81,64.26 20.83,63.25 v2(20.83,62.99)
  TOP w0.305: PU4506.2 53.21,52.7 v2(52.65,52.15)
  TOP w0.381: PR4424.1 20.19,62.36 v2(20.83,62.99)
  BOTTOM w0.381: v2(52.65,52.15) v1(52.65,51.13) 52.65,50.42 46.24,44.01 34.11,44.01 20.83,57.29 v2(20.83,62.99)
PWR_VCORE_PWM3: length 77.1
  TOP w0.203: v2(19.94,63.25) 19.41,63.77 PU4401.32
  TOP w0.305: v2(71.64,55.08) 72.03,55.47 PU4510.2
  TOP w0.381: v2(19.94,63.25) 19.94,63.12 19.18,62.36 PR4456.1
  BOTTOM w0.381: v2(19.94,63.25) 19.94,56.92 33.74,43.12 46.58,43.12 46.58,43.12 48.86,43.12 54.8,49.06 60.29,49.06 62.98,51.75 68.31,51.75 v1(70.64,54.08) v2(71.64,55.08)
PWR_VCORE_PWM4: length 99.8
  TOP w0.203: v2(19.05,63.25) 19.05,66.75 PU4401.31
  TOP w0.305: v2(91.59,55.91) 92.1,55.91 92.54,55.46 PU4514.2
  TOP w0.381: PR4403.1 18.16,62.36 v2(19.05,63.25)
  BOTTOM w0.381: v2(91.59,55.91) v1(90.62,54.93) 86.55,50.86 75.6,50.86 73.28,53.19 71.01,53.19 68.68,50.86 63.35,50.86 60.65,48.17 55.17,48.17 49.22,42.23 46.21,42.23 33.38,42.23 19.05,56.55 v2(19.05,63.25)
PWR_VCORE_SCLK: length 4.8
  TOP w0.102: PU4401.5 20.61,73.95 v1(21.03,74.37) 21.11,74.45 21.23,74.45 23.24,76.45 PR4411.1
PWR_VCORE_SDIO: length 8.6
  TOP w0.102: PR4410.1 25.76,78.68 24.89,77.81 24.89,75.56 v1(24.61,75.29) 24,74.68 22.68,74.68 21.41,73.41 PU4401.3
PWR_VCORE_SNB1:
  vias: v1(33.91,66.01)
PWR_VCORE_SNB2: length 1.6
  TOP w0.635: PR4511.2 54.29,70.1 PC4510.1
PWR_VCORE_SNB3: length 1.6
  TOP w0.635: PR4517.2 72.58,73.15 PC4515.1
PWR_VCORE_SNB4: length 1.6
  TOP w0.635: PR4523.2 91.12,73.66 PC4520.1
PWR_VCORE_SW1: length 25.9
  TOP w0.305: 41.3,48.21 40.79,47.7 PU4502.7
  TOP w0.635: PC4503.2 41.3,50.27 41.3,48.21 ; PU4503.5 37.08,62.69 PR4505.1
  TOP w1.016: 45.48,55.65 PL4501.1 ; PL4501.1 48.38,55.65 ; PL4501.1 46.93,57.1 ; PL4501.1 46.93,54.2
  BOTTOM w0.254: PL4501.1 45.59,56.99 PG4501.1
  BOTTOM w1.016: PL4501.1 48.38,55.65 ; PL4501.1 46.93,54.2 ; PL4501.1 46.93,57.54 ; PL4501.1 45.48,55.65
  vias: v1(37.34,62.1) v1(37.47,52.2) v1(49.15,51.05) v3(42.04,58.04) v3(42.04,53.21) v3(42.16,55.5) v3(43.94,56.64) v3(44.32,53.98) v3(46.35,52.7) v3(47.75,52.7) v3(49.02,56.9) v3(49.28,54.36) v3(49.28,52.7)
PWR_VCORE_SW2: length 30.8
  TOP w0.305: 58.55,52.96 58.55,52.93 58.32,52.7 PU4506.7
  TOP w0.635: 58.55,52.96 59.31,53.72 PC4508.2 ; PR4511.1 57.1,65.66
  TOP w1.016: PL4502.1 66.66,60.35 ; PL4502.1 63.77,60.35 ; PL4502.1 65.22,58.9 ; PL4502.1 65.22,61.8
  BOTTOM w0.254: PL4502.1 64.48,61.09 60.45,61.09 PG4503.1
  BOTTOM w1.016: 63.77,60.35 PL4502.1 ; PL4502.1 65.22,60.34 ; PL4502.1 66.66,60.35 ; 66.55,59 65.22,60.34 ; 65.22,60.34 65.22,59.63 64.39,58.8
  vias: v1(55.12,63.75) v1(57.66,57.28) v1(67.44,55.88) v3(60.29,60.33) v3(60.33,57.91) v3(61.72,58.93) v3(62.61,60.2) v3(63.37,58.04) v3(64.64,57.4) v3(66.04,57.4) v3(67.56,60.96) v3(67.56,59.05) v3(67.56,57.4)
PWR_VCORE_SW3: length 25.5
  TOP w0.305: PU4510.7 77.14,55.47 77.88,56.21
  TOP w0.635: PC4513.2 77.88,58.01 77.88,56.21
  TOP w1.016: PL4503.1 84.95,63.4 ; PL4503.1 83.5,61.95 ; PL4503.1 83.5,64.85 ; PL4503.1 82.06,63.4
  BOTTOM w0.254: 83.5,63.69 83.5,64.83 82.93,65.41 79.25,65.41 PG4505.1
  BOTTOM w1.016: PL4503.1 81.69,63.4 ; PL4503.1 83.8,63.4 84.84,62.36 ; PL4503.1 83.5,63.69 84.45,64.64 ; PL4503.1 83.5,62.68 82.68,61.85
  vias: v1(73.79,66.93) v1(74.8,60.2) v1(85.98,58.8) v3(78.61,64.64) v3(78.61,62.87) v3(78.61,60.96) v3(80.52,63.63) v3(80.52,61.85) v3(82.93,60.45) v3(84.33,60.45) v3(85.85,64.52) v3(85.85,62.1) v3(85.85,60.45)
PWR_VCORE_SW4: length 18.5
  TOP w0.305: PU4514.7 95.61,55.46 96.29,56.15
  TOP w0.635: 96.29,56.15 96.29,58.65 PC4518.2
  TOP w1.016: 100.6,63.91 PL4504.1 ; PL4504.1 102.05,65.35 ; PL4504.1 103.49,63.91 ; PL4504.1 102.05,62.46
  BOTTOM w0.254: PL4504.1 100.58,65.37 PG4507.1
  BOTTOM w1.016: PL4504.1 102.05,65.6 ; PL4504.1 103.49,63.91 ; PL4504.1 102.05,62.46 ; PL4504.1 100.6,63.91
  vias: v1(92.2,70.48) v1(92.33,60.71) v1(104.14,59.31) v3(97.16,66.93) v3(97.16,65.15) v3(97.16,63.37) v3(97.16,61.47) v3(99.06,64.14) v3(99.06,62.36) v3(101.47,60.96) v3(102.87,60.96) v3(104.14,65.15) v3(104.39,62.61) v3(104.39,60.96)
PWR_VCORE_TCP: length 14.3
  TOP w0.254: PR4431.2 41.21,66.42 38.2,66.42 35.84,68.78 v1(33.96,68.78) 33.63,69.11 30.7,69.11 PR4428.1 29.79,69.02 PR4427.2
PWR_VCORE_TSNS: length 7.7
  TOP w0.203: PU4401.35 20.61,65.71 20.95,65.37 20.95,64.52
  TOP w0.254: PR4464.1 PC4429.1 v1(22.23,61.8) 22.23,63.25 20.95,64.52
PWR_VCORE_TSNS_R: length 27.6
  TOP w0.254: v2(28.09,55.98) 25.27,58.8 PR4469.1 23.24,58.86 PR4464.2 ; PR4466.1 41.97,44.34 41.2,45.11 v2(41.2,45.47)
  BOTTOM w0.254: v2(28.09,55.98) v1(29.37,54.7) 29.37,54.27 38.3,45.34 41.07,45.34 v2(41.2,45.47)
PWR_VCORE_VCC: length 8.3
  TOP w0.203: PU4401.7 19.81,74.04
  TOP w0.254: 19.81,74.04 19.81,74.6 v1(20.87,75.65)
  TOP w0.508: PR4401.2 PR4470.2 21.97,78.3 PR4462.2 21.59,77.79 PC4402.1 21.59,76.49 20.87,75.76 v1(20.87,75.65)
PWR_VCORE_VCC1: length 4.8
  TOP w0.305: PU4502.4 38.1,46.47 37.97,46.34
  TOP w0.508: 37.97,46.34 37.72,46.09 PC4504.2 36.37,45.29 PR4502.2 36.12,45.03 v1(34.62,45.03)
PWR_VCORE_VCC2: length 4.7
  TOP w0.305: PU4506.4 55.5,51.18
  TOP w0.508: PR4508.2 v1(55.58,48.74) 55.58,50.22 PC4509.2 55.5,50.29 55.5,51.18
PWR_VCORE_VCC3: length 4.9
  TOP w0.305: 74.5,54.1 PU4510.4
  TOP w0.508: v1(72.87,50.57) 73.36,50.57 PR4513.2 74.22,52.96 PC4514.2 74.5,53.44 74.5,54.1
PWR_VCORE_VCC4: length 4.7
  TOP w0.305: 93.16,53.91 PU4514.4
  TOP w0.508: 93.16,53.91 93.16,53.03 PC4519.2 92.79,52.65 PR4519.2 91.39,52.7 91.39,53.62 v1(91.11,53.9)
PWR_VCORE_VRMP: length 6.4
  TOP w0.203: PU4401.9 19.01,73.78
  TOP w0.254: 19.01,73.78 18.54,74.25 18.54,76.94 v1(18.59,76.99) 18.59,77.99 PC4403.1 PR4402.2
PWR_VCORE_VSN: length 6.9
  TOP w0.203: PU4401.52 23.23,72.25 23.43,72.45
  TOP w0.254: PR4420.2 PC4411.2 27.25,75.37 v1(26.2,74.33) 25.18,73.3 24.28,73.3 23.43,72.45
PWR_VCORE_VSP: length 9.5
  TOP w0.203: PU4401.51 23.54,71.85 23.79,72.1
  TOP w0.254: 23.79,72.1 24.59,72.9 25.78,72.9 27.28,74.4 v1(29.3,74.4) 29.46,74.56 PC4409.1 PR4418.2
PWR_VDDQ: length 19.9
  TOP w1.016: PT5001.1 88.51,194.04 ; PT5001.1 86.6,195.95 ; PT5001.1 86.6,194.04 ; PT5001.1 88.51,195.95 ; 81.79,194.93 PL5001.2 ; PL5001.2 81.79,197.22 ; PL5001.2 82.93,196.07 ; PL5001.2 80.64,196.07
  BOTTOM w1.016: PT5001.1 88.51,195.95 ; PT5001.1 86.6,194.04 ; PT5001.1 88.51,194.04 ; PT5001.1 86.6,195.95 ; PL5001.2 81.79,197.22 ; PL5001.2 82.93,196.07 ; PL5001.2 81.79,194.93 ; PL5001.2 80.64,196.07
  vias: v1(80.37,191.21) v1(85.27,197.99) v1(91.31,190.86) v3(83.06,193.93) v3(83.82,197.23) v3(84.2,193.93) v3(85.14,197.03) v3(85.47,193.93) v3(86.23,197.23) v3(87.38,191.13) v3(88.52,191.13) v3(89.79,191.13)
PWR_VDDQ_PG: length 214.4
  TOP w0.203: PU5001.10 50.78,189.51 v2(53.34,186.94)
  TOP w0.254: U4801.2 133.6,87.88 133.43,88.06 133.43,88.84 133.86,89.28 136.78,89.28 137.16,88.9 R4802.2 137.59,89.01 137.59,106.1 143.18,111.68 144.93,111.68 145.35,112.1 145.35,115.71 144.53,116.54 v2(144.53,118.11)
  BOTTOM w0.254: v2(53.34,186.94) 54.48,185.8 v1(55.75,185.8) 56.26,185.29 76,185.29 78.66,187.96 94.36,187.96 95.63,186.69 101.09,186.69 101.68,187.27 113.44,187.27 116.56,184.15 148.3,184.15 150.24,182.21 150.24,167.77 151.64,166.37 151.64,155.4 144.18,147.94 144.18,145.07 143.64,144.53 143.64,139.98 145.67,137.95 145.67,119.25 v2(144.53,118.11)
PWR_VDDQ_PG_ISOLATE: length 4.3
  TOP w0.254: U4801.6 136.7,88.53 R4803.1 ; R4803.1 137.74,87.49 v1(137.74,86.77) ; R4803.1 136.78,87.76 136.65,87.88 U4801.5
PWR_VDDQ_S3_EN: length 3.8
  TOP w0.203: PU5001.7 49.51,188.1 v1(49.53,188.08) ; R5001.1 R5002.1
  TOP w0.254: v1(49.53,188.08) 50.37,187.25 R5002.1
PWR_VDDQ_S5_EN: length 3.1
  TOP w0.203: v1(50.8,188.11) 50.65,188.11 49.91,188.85 PU5001.8
  TOP w0.254: v1(50.8,188.11) 51.56,187.35 R5003.2
PWR_VDDQ_SNB: length 2.7
  TOP w0.635: PR5016.2 v1(67.46,192.63) PC5014.1
PWR_VDDQ_TON: length 6.2
  TOP w0.203: PU5001.9 50.31,188.96 50.55,188.72 51.09,188.72 52.37,187.44 52.37,186.64 v1(52.7,186.31)
  TOP w0.254: PR5009.2 52.83,186.18 v1(52.7,186.31)
PWR_VDDQ_VDDP: length 4.5
  TOP w0.203: PU5001.12 52.17,190.66 52.32,190.5
  TOP w0.508: PR5002.1 PC5002.1 53.82,190.12 v1(53.09,190.12) 52.7,190.12 52.32,190.5
PWR_VDDQ_VIN: length 10.3
  TOP w0.508: PR5009.1 55.44,185.93 56.39,185.93 58.55,188.09 58.55,194.06
  vias: v1(63.5,195.83)
PWR_VDDQ_VIOP: length 5
  TOP w0.203: 51.82,189.74 51.46,190.09 PU5001.11
  TOP w0.508: PR5001.2 54.22,189.24 PC5001.1 53.67,189.31 v1(53.09,188.72) 52.83,188.72 51.82,189.74
PWR_VTT: length 1.5
  TOP w0.305: 44.96,194.94 PG5005.2 PG5006.2
  vias: v1(46.86,193.8)
PWRBTN_N: length 594.7
  TOP w0.102: R6401.2 22.9,232.24 33.94,221.21 65.86,221.21 66.48,221.82 81.16,221.82 81.71,221.26 88.59,221.26 90.04,222.71 90.04,223.77 92.84,226.57 107.95,226.57 v2(108.46,227.08) ; R6401.2 C6401.1 ; R6401.2 22.83,233.92 R6405.2 ; v2(226.54,103.3) 225.98,103.87 223.41,103.87 223.39,103.89 221.78,103.89 221.77,103.87 220.43,103.87 220.42,103.89 219.44,103.89 219.28,103.72 216.99,103.72 215.55,102.29 212.78,102.29 210.32,99.82 209.04,99.82 208.8,100.07 ; v2(217.65,171.5) 217.91,171.75 220.32,171.75 221.1,170.97 v2(222.81,170.97) ; 208.8,100.07 208.8,99.28 207.51,97.99 v2(207.21,97.99) ; 208.8,100.07 U2401.34 ; v2(165.23,31.88) 165.23,31.06 163.08,28.91 159.58,28.91 159.06,28.4 159.01,28.4 156.57,25.95 156.57,15.45 156.57,14.98 157.63,13.92 158.85,13.92 160.68,15.75 167.51,15.75 v2(171.39,11.87) ; v2(227.43,108.76) 227.91,109.25 227.91,109.84 R9920.1 ; SB1.BE46 212.19,155.24 v2(212.49,154.94)
  BOTTOM w0.102: v2(108.46,227.08) 108.46,226.44 v1(118.11,216.79) 118.24,216.79 121.6,213.42 131.67,213.42 132.3,212.79 158.3,212.79 161.18,209.91 193.62,209.91 195.45,211.73 199.56,211.73 201.64,209.65 202.87,209.65 203.48,209.04 209.04,209.04 215.06,203.02 215.06,203 215.11,202.95 215.11,195.84 215.7,195.25 215.7,193.39 216.18,192.91 216.18,185.41 217.25,184.34 217.25,178.56 217.56,178.25 217.56,177.89 216.48,176.81 216.48,176.57 217.02,176.04 217.02,172.14 v2(217.65,171.5) 216.56,170.41 215.98,170.41 214.6,169.04 214.6,166.45 215.85,165.2 215.85,160.15 214,158.29 213.59,158.29 212.49,157.2 v2(212.49,154.94) ; v2(165.23,31.88) 166.6,33.25 166.6,45.09 165.97,45.71 165.97,48.76 164.95,49.79 163.86,49.79 163.75,49.9 163.23,49.9 161.39,51.74 155.58,51.74 148.2,59.12 141.73,59.12 141.54,58.93 135.76,58.93 134.26,60.43 134.26,61.15 134.93,61.82 134.93,62.71 134.86,62.79 134.86,63.25 134.95,63.34 134.95,65.31 XDP1.41 ; v2(171.39,11.87) 171.96,12.45 187.02,12.45 197.46,22.89 197.46,39.34 200.24,42.13 200.24,45.9 200.11,46.03 200.11,52.79 200.51,53.19 200.51,63.08 201.12,63.68 201.12,66.15 202.35,67.38 203.15,67.38 207.14,71.37 207.14,75.05 207.53,75.44 207.53,79.37 208.01,79.86 208.01,80.44 205.77,82.69 205.77,84.15 204.09,85.82 204.09,90.83 204.69,91.43 204.69,95.47 v2(207.21,97.99) ; v2(226.54,103.3) 225.93,103.91 225.93,106.5 227.43,108 v2(227.43,108.76) 226.62,108.76 226.11,108.25 222.07,108.25 220.73,109.6 220.73,116 219.76,116.97 219.76,117.72 219.12,118.35 219.12,125.1 221.76,127.73 221.76,129.92 222.66,130.81 222.66,133.83 222.42,134.07 222.42,136.1 224.03,137.72 224.03,142.11 226.62,144.7 226.62,146.2 225.98,146.84 225.98,149.73 225.86,149.85 225.86,150.87 225.48,151.26 225.48,157.1 223.22,159.36 223.22,168.43 223.22,170.56 v2(222.81,170.97)
PWRBTN_N_CN: length 4.1
  TOP w0.102: APS1.4 231.4,108.43 230.2,109.63 v1(229.74,109.63) 229.69,109.63 229.46,109.86 R9920.2
PWRGD_PS: length 13.3
  TOP w0.203: U2401.123 207.2,83.74 v1(207.37,83.57) 207.59,83.57 208.22,82.94 208.22,82.82
  TOP w0.254: U2402.3 213.22,78.14 212.73,78.64 Q2407.D 208.17,79.72 208.22,79.77 208.22,81.43 R2435.2 208.22,82.19 208.22,82.82
PWRGD_VPP: length 16.8
  TOP w0.102: U4010.2 145.03,201.8 144.65,201.42 144.15,201.42 v1(142.75,200.03) 141.78,199.06 141.78,191.21 142.62,190.37 142.94,190.37 PR5202.2 143.52,189.79 PU5201.7
Q82_B: length 16
  TOP w0.102: R2718.2 65.02,223.65 64.44,223.06 52.66,223.06 52.17,223.55 v1(51.66,223.55) Q2703.B
Q83_B: length 3.1
  TOP w0.102: v1(49.33,230.61) 49.33,229.72 Q2704.B 50.11,228.94 R2719.2
Q84_B: length 47.1
  TOP w0.102: R2717.2 50.9,224.6 Q2703.E ; Q2703.E 49.97,225.11 49.23,224.36 49.23,223.22 49.66,222.78 65.07,222.78 65.94,223.65 79.88,223.65 v1(80.75,224.51) 81.63,225.39 Q2702.B ; Q2703.E 49.43,225.52 47.91,227.04 Q2704.E
Q84_E: length 4.3
  TOP w0.102: R2715.1 78.99,233.24 78.99,231.39 v1(78.87,231.27) 78.87,230.35 Q2702.E
Q84_E2: length 3.9
  TOP w0.102: C2722.1 80.16,232.21 v1(80.95,232.99) 80.52,233.43 R2715.2 R2716.1
Q85_B: length 3.6
  TOP w0.102: R2716.2 R2714.1 79.18,236.32 v1(79.26,236.4) 80.39,237.52 Q2701.B
RED_CRT: length 11.9
  TOP w0.102: VGA1.1 64.39,6.36 64.39,11.68 63.87,12.2 EU5901.3 62.46,12.67 62.61,12.83 63.79,12.83 64.4,13.44 C5921.1 64.4,13.62 64.69,13.91 64.69,13.92 65.1,14.33 L5903.2
REQ64B_N1: length 4.2
  TOP w0.102: R9205.2 230.57,89.8 229.49,90.89 SLOT4.116
RP_AUDOUT_L: length 8.7
  TOP w0.203: L3003.2 C3006.1 16.38,17.27 14.08,14.97 AUD1.22
RP_AUDOUT_R: length 17.3
  TOP w0.203: L3004.2 C3005.1 16.26,20.32 16,20.07 16,17.54 13.62,15.16 13.62,15.15 12.32,13.84 8.32,13.84 AUD1.25
RP_LINE1_L: length 8.5
  TOP w0.203: L3001.2 C3004.1 13.13,17.1 AUD1.32
RP_LINE1_R: length 9.4
  TOP w0.203: L3002.2 C3003.1 v1(7.34,23.75) 6.58,22.99 AUD1.35
RP_MIC1_L: length 24.8
  TOP w0.203: v2(15.68,28) 16.07,28.38 C3010.1 16,28.89 L3005.2
  BOTTOM w0.203: v2(15.68,28) 16.87,26.82 v1(16.87,24.26) 16.87,21.06 16.15,20.35 16.15,17.04 15.95,16.84 15.95,16.83 14.55,15.43 14.55,13.89 15.55,12.9 15.55,12.9 15.57,12.88 15.57,7.34 AUD1.2
RP_MIC1_R: length 35.2
  TOP w0.203: L3006.2 14.99,28.89 C3009.1 v2(14.92,28.02)
  BOTTOM w0.203: v2(14.92,28.02) 16.24,26.7 16.24,23.5 16.41,23.32 16.41,21.59 v1(15.49,20.68) 15.49,17.02 14.1,15.62 14.1,13.7 15.11,12.69 15.11,8.38 14.1,7.37 14.1,6.48 13.59,5.97 6.46,5.97 AUD1.5
RREF: length 4.6
  TOP w0.102: R9506.1 193.65,57.58 195.07,57.58 v1(195.2,57.45) 195.96,56.69 U9501.16
RSMRST_SIO_N: length 321.3
  TOP w0.089: SB1.BA47 210.51,156.02 210.51,156.43 210.49,156.45 210.49,157.14 210.57,157.21
  TOP w0.102: R2434.1 R2474.1 195.19,104.98 195.19,105.06 195.19,105.06 194.78,105.46 186.08,105.46 v2(186,105.38) 186,105.31 187.02,104.29 187.02,103.43 186.51,102.92 186.51,100.56 186.26,100.3 184.61,100.3 183.77,101.14 180.52,101.14 179.7,101.96 176.12,101.96 175.89,101.73 174.86,101.73 174.12,100.99 174.12,49.53 v2(167.51,42.93) ; 210.57,157.21 212.23,158.88 v2(213.08,158.88) ; v2(187.73,120.6) 187.66,120.6 187.6,120.55 182.94,120.55 180.67,120.55 178.51,122.7 178.51,127.81 177.7,128.63 177.7,133.35 175.74,135.3 175.74,141.83 173.81,143.76 173.81,149.02 169.65,153.18 169.65,169.29 168.66,170.28 168.66,179.19 166.85,181 166.85,181.15 v2(166.85,181.15) ; R9906.1 136.4,60.45 136.11,60.17 v2(136.11,60.08) ; v2(214.36,193.21) 214.3,193.27 211.33,193.27 210.67,193.93 207.39,193.93 206.5,194.82 197.11,194.82 194.72,192.43 v2(193.32,192.43) ; U6305.G 214.97,178.86 v2(215.52,178.31)
  BOTTOM w0.102: v2(136.11,60.08) 139.87,60.08 140.28,59.66 148.34,59.66 155.78,52.22 161.59,52.22 163.43,50.38 164.23,50.38 164.34,50.27 165.15,50.27 166.45,48.96 166.45,45.91 167.51,44.85 v2(167.51,42.93) ; v2(166.85,181.15) 171.88,181.15 173.59,182.85 182.04,182.85 v1(191.11,191.92) 191.62,192.43 193.32,192.43 v2(193.32,192.43) ; v2(187.73,120.6) 187.7,120.6 186,118.9 v2(186,105.38) ; v2(213.08,158.88) 213.08,159.85 213.43,160.2 214.22,160.2 214.93,160.91 214.93,164.75 213.64,166.05 213.64,169.44 216.05,171.85 216.05,175.64 215.52,176.17 v2(215.52,178.31) 215.52,178.38 216.28,179.15 216.28,183.94 215.19,185.04 215.19,192.47 214.45,193.21 v2(214.36,193.21)
RSMRST_SIO_N_1: length 6
  TOP w0.102: R2434.2 196.71,104.07 v1(197.19,104.07) 197.6,103.66 198.9,103.66 199.23,103.33 199.23,101.93 199.2,101.9 U2401.58
RST_SEL: length 4
  TOP w0.102: R9510.1 215.26,61.62 v1(215.09,61.45) 214.22,61.45 213.46,60.69 U9501.91
RTCRST_N_CN: length 10.3
  TOP w0.102: R9919.2 235.9,109.16 v1(236.17,108.89) 236.17,107.9 234.65,106.38 229.9,106.38 229.4,106.87 APS1.6
RTL_ISOLATE_N: length 5.9
  TOP w0.203: R3106.1 142.81,45.02 142.6,44.81 141.79,44.81 140.76,43.78 U3101.20
  TOP w0.305: R3103.2 143.15,46.69 v1(142.97,46.5) 142.81,46.34 R3106.1
S0_5V_EN: length 2.6
  TOP w0.102: R4201.2 88.54,216.12 v1(89.09,216.12) 89.34,215.87 U4201.3
S3_QUK: length 16.3
  TOP w0.102: U4003.G 87.57,23.51 ; 87.57,23.51 U4002.3 85.06,23.51 84.96,23.41 84.96,22.99 85.09,22.86 U4002.2 ; 87.57,23.51 86.96,22.9 v2(86.96,22.58) ; v2(94.36,22.86) 94.36,22.4 95.17,21.59 95.59,21.59 96.29,22.29 R4001.2
  BOTTOM w0.102: v2(86.96,22.58) v1(91.8,22.58) 93.31,22.58 93.59,22.86 v2(94.36,22.86)
S4_VPP_OR: length 3.4
  TOP w0.102: Q4002.5 148.21,198.93 v1(148.34,198.81) 147.57,198.04 R4021.1
S4_VPP_OR_R: length 6.3
  TOP w0.102: R4021.2 147.98,196.66 148.08,196.76 148.08,197.49 148.65,198.06 R4023.1 C4010.1 R4022.1 152.46,198.06 v1(152.78,198.37)
SATA_LED_OUT: length 15.8
  TOP w0.406: U6401.3 25.73,242.97 U6402.3 23.93,244.4
  TOP w0.508: 23.93,244.4 23.65,244.68 v1(23.65,245.97) 23.65,249.35 24.51,250.22 27.86,250.22 28.41,249.67 LED1.K
SATA_RX_CON_N0: length 12.5
  TOP w0.102: C6004.2 133.89,195.1 133.25,195.1 130.94,192.79 128.91,192.79 128.07,191.95 125.81,191.95 125.6,191.74 125.6,191.29 125.75,191.14 SATA1.5
  BOTTOM w0.102: v1(126.33,191.96) 126.45,191.84 SATA1.5
SATA_RX_CON_N1: length 7.7
  TOP w0.102: SATA4.5 103.98,201.74 103.8,201.57 103.8,195.98 C6008.2
  BOTTOM w0.102: v1(104.43,202.56) 104.54,202.44 SATA4.5
SATA_RX_CON_N2: length 12.9
  TOP w0.102: SATA2.3 103.8,190.67 103.8,191.43 104.75,192.38 110.72,192.38 111.89,193.55 111.89,194.37 C6012.2
  BOTTOM w0.102: v1(104.5,191.1) 104.5,191.06 104.33,190.89 SATA2.3
SATA_RX_CON_N3: length 7.8
  TOP w0.102: C6016.2 125.68,195.95 125.68,201.57 125.84,201.74 SATA3.5
  BOTTOM w0.102: SATA3.5 126.45,202.44 v1(126.33,202.56)
SATA_RX_CON_P0: length 12.6
  TOP w0.102: C6003.2 133.88,195.32 133.16,195.32 130.85,193 128.82,193 127.98,192.16 125.72,192.16 125.39,191.83 125.39,191.27 125.25,191.14 SATA1.6
  BOTTOM w0.102: v1(124.1,191.65) 124.61,191.14 SATA1.6
SATA_RX_CON_P1: length 7.7
  TOP w0.102: SATA4.6 103.42,201.74 103.59,201.57 103.59,195.98 C6007.2
  BOTTOM w0.102: SATA4.6 102.71,201.74 v1(102.2,202.25)
SATA_RX_CON_P2: length 12.8
  TOP w0.102: C6011.2 111.67,194.46 111.67,193.64 110.63,192.6 104.66,192.6 103.59,191.52 103.59,190.67 SATA2.2
  BOTTOM w0.102: SATA2.2 102.98,190.14 v1(102.34,190.78)
SATA_RX_CON_P3: length 7.8
  TOP w0.102: SATA3.6 125.34,201.74 125.46,201.61 125.46,196.01 C6015.2
  BOTTOM w0.102: SATA3.6 124.61,201.74 v1(124.1,202.25)
SATA_RX_PCH_N0: length 87.1
  TOP w0.102: SB1.C45 191.49,154.72 v2(191.73,154.49) ; C6004.1 135.53,195.03 138.55,195.03 139.66,193.92 139.66,188.33 139.34,188.01 v2(139.34,187.1)
  BOTTOM w0.102: v1(191.83,157.99) 191.46,157.99 ; 191.46,157.99 191.46,155.83 191.6,155.7 191.6,154.62 v2(191.73,154.49) ; 191.46,157.99 191.46,158.42 193.17,160.13 193.17,163.2 191.99,164.38 186.18,164.38 183.83,166.73 169.4,166.73 152.68,183.45 151.27,183.45 146.73,188 139.97,188 139.66,187.69 139.66,187.42 v2(139.34,187.1)
SATA_RX_PCH_N1: length 116.1
  TOP w0.102: C6008.1 103.8,194.42 103.8,194.13 v2(104.13,193.81) ; v2(192.08,155.08) 191.72,155.45 SB1.D46
  BOTTOM w0.102: 149.03,186.68 147.02,188.7 137.21,188.7 135.21,186.69 117.47,186.69 111.05,193.12 104.01,193.12 103.89,193.24 103.89,193.57 v2(104.13,193.81) ; 149.03,186.68 151.56,184.15 152.97,184.15 169.69,167.43 184.12,167.43 186.38,165.16 192.21,165.16 194.02,163.36 194.02,157.09 192.08,155.15 v2(192.08,155.08) ; 149.03,186.68 v1(149.3,186.94)
SATA_RX_PCH_N2: length 114.4
  TOP w0.102: v2(114.68,193.78) 114.16,194.3 113.79,194.3 113.46,194.63 113.46,196.19 112.97,196.68 111.84,196.68 111.64,196.48 111.64,196.27 C6012.1 ; v2(193.06,154.62) 193.06,154.15 SB1.F44
  BOTTOM w0.102: v2(114.68,193.78) 114.16,194.3 113.74,194.3 113.54,194.09 113.54,192.2 117.5,188.24 135.41,188.24 136.56,189.4 145.85,189.4 ; 145.85,189.4 148.71,189.4 169.87,168.24 184.3,168.24 186.64,165.9 192.47,165.9 194.84,163.53 194.84,156.4 v2(193.06,154.62) ; 145.85,189.4 v1(145.85,189.76)
SATA_RX_PCH_N3: length 98.1
  TOP w0.102: C6016.1 125.6,194.37 125.6,193.15 125.74,193 v2(125.97,193) ; SB1.L41 195.47,152.72 195.65,152.72 195.76,152.84 195.76,153.2 195.07,153.89 v2(195.07,154.56)
  BOTTOM w0.102: v2(125.97,193) 125.65,193.32 125.65,193.51 125.77,193.64 133.13,193.64 135.89,190.88 139.06,190.88 ; v2(195.07,154.56) 195.07,154.56 195.53,154.56 195.64,154.67 195.64,155.16 196,155.52 196,163.16 192.7,166.46 186.76,166.46 184.5,168.72 170.07,168.72 147.91,190.88 139.06,190.88 ; 139.06,190.88 v1(139.06,190.51)
SATA_RX_PCH_P0: length 87.1
  TOP w0.102: SB1.C46 191.21,155.16 v2(190.96,154.9) ; v2(140.2,187.1) 140.2,187.41 140.06,187.55 139.75,187.55 139.56,187.74 139.56,187.92 139.88,188.24 139.88,194 138.64,195.24 135.53,195.24 C6003.1
  BOTTOM w0.102: v2(140.2,187.1) 139.88,187.42 139.88,187.6 140.06,187.78 146.64,187.78 151.18,183.24 152.59,183.24 169.31,166.52 183.74,166.52 186.09,164.16 191.9,164.16 192.95,163.11 192.95,160.22 192.49,159.76 ; 192.49,159.76 191.24,158.51 191.24,155.74 191.38,155.61 191.38,155.03 191.25,154.9 v2(190.96,154.9) ; 192.49,159.76 v1(192.23,160.02)
SATA_RX_PCH_P1: length 116
  TOP w0.102: C6007.1 103.59,194.42 103.59,194.13 v2(103.26,193.81) ; v2(191.99,155.97) 191.5,155.97 SB1.C47
  BOTTOM w0.102: v2(103.26,193.81) 103.55,193.81 103.67,193.69 103.67,193.15 103.92,192.9 110.96,192.9 117.38,186.48 135.3,186.48 137.3,188.48 146.93,188.48 151.47,183.93 152.88,183.93 169.6,167.21 184.03,167.21 186.29,164.95 192.12,164.95 193.8,163.27 193.8,158.55 ; v1(193.43,158.55) 193.8,158.55 ; 193.8,158.55 193.8,157.18 192.41,155.78 192.19,155.78 v2(191.99,155.97)
SATA_RX_PCH_P2: length 114.5
  TOP w0.102: v2(192.74,155.18) 192.74,154.93 SB1.E45 ; C6011.1 111.42,195.69 111.42,196.57 111.75,196.9 113.06,196.9 113.68,196.28 113.68,194.72 113.88,194.51 v2(114.68,194.51)
  BOTTOM w0.102: v2(114.68,194.51) 113.65,194.51 113.32,194.18 113.32,192.11 117.41,188.02 135.5,188.02 136.65,189.18 148.62,189.18 149.06,188.74 ; 149.06,188.74 v1(148.79,188.47) ; 149.06,188.74 169.78,168.02 184.21,168.02 186.55,165.68 192.38,165.68 194.62,163.44 194.62,156.49 193.45,155.32 193.29,155.32 193.17,155.45 193.01,155.45 v2(192.74,155.18)
SATA_RX_PCH_P3: length 98.2
  TOP w0.102: v2(125.11,193) 125.38,193.27 125.38,194.47 C6015.1 ; v2(195.57,154.05) 195.57,153.7 195.98,153.29 195.98,152.23 SB1.M40
  BOTTOM w0.102: v2(125.11,193) 125.44,193.33 125.44,193.6 125.68,193.85 133.22,193.85 135.98,191.1 136.75,191.1 ; 136.75,191.1 v1(136.75,191.47) ; 136.75,191.1 148,191.1 170.16,168.94 184.59,168.94 186.85,166.67 192.79,166.67 196.22,163.25 196.22,155.43 195.86,155.07 195.86,154.58 195.62,154.34 195.57,154.29 v2(195.57,154.05)
SATA_TX_CON_N0: length 10.5
  TOP w0.102: SATA1.3 129.01,191.14 129.2,191.32 129.2,191.81 129.61,192.23 132.89,192.23 133.51,192.86 136.79,192.86 C6001.2
  BOTTOM w0.102: SATA1.3 128.52,191.18 v1(128.52,191.96)
SATA_TX_CON_N1: length 7.7
  TOP w0.102: SATA4.3 107.25,201.74 107.4,201.59 107.4,195.98 C6006.2
  BOTTOM w0.102: SATA4.3 106.62,201.78 v1(106.62,202.56)
SATA_TX_CON_N2: length 10.8
  TOP w0.102: SATA2.5 107.4,190.67 107.4,191.29 107.82,191.72 110.74,191.72 111.05,192.02 C6010.2
  BOTTOM w0.102: v1(106.68,191.06) 106.73,191.06 106.87,190.92 SATA2.5
SATA_TX_CON_N3: length 7.7
  TOP w0.102: C6014.2 129.3,196.04 129.3,201.59 129.15,201.74 SATA3.3
  BOTTOM w0.102: SATA3.3 128.52,201.78 v1(128.52,202.56)
SATA_TX_CON_P0: length 10.4
  TOP w0.102: C6002.2 136.73,192.64 133.6,192.64 132.98,192.01 129.7,192.01 129.41,191.72 129.41,191.26 129.53,191.14 SATA1.2
  BOTTOM w0.102: v1(130.8,191.75) 130.26,191.21 SATA1.2
SATA_TX_CON_P1: length 7.7
  TOP w0.102: C6005.2 107.61,195.98 107.61,201.59 107.76,201.74 SATA4.2
  BOTTOM w0.102: SATA4.2 108.35,201.81 v1(108.9,202.35)
SATA_TX_CON_P2: length 10.9
  TOP w0.102: SATA2.6 107.61,190.67 107.61,191.2 107.91,191.5 110.83,191.5 111.14,191.81 114.69,191.81 114.88,191.62 114.88,191.31 115.06,191.13 C6009.2
  BOTTOM w0.102: v1(108.87,190.78) 108.78,190.78 SATA2.6
SATA_TX_CON_P3: length 7.8
  TOP w0.102: SATA3.2 129.65,201.74 129.51,201.6 129.51,196.05 C6013.2
  BOTTOM w0.102: v1(130.8,202.35) 130.26,201.81 SATA3.2
SATA_TX_PCH_N0: length 90.2
  TOP w0.102: v2(163.84,192) 164.2,191.64 164.85,191.64 166.46,193.26 168.22,193.26 ; 168.22,193.26 v1(168.22,193.65) ; 168.22,193.26 173.56,193.26 180.11,186.71 180.11,163.81 181.95,161.96 181.95,156.99 185.52,153.42 186.41,153.42 189.09,150.74 190.48,150.74 190.88,151.14 SB1.B38 ; C6001.1 138.32,192.83 138.53,192.83 v2(138.84,193.14)
  BOTTOM w0.102: v2(138.84,193.14) 139.16,192.81 151.49,192.81 152.06,192.24 153.33,190.97 161.96,190.97 162.35,191.35 163.2,191.35 163.35,191.5 163.35,191.87 163.48,192 v2(163.84,192)
SATA_TX_PCH_N1: length 125.1
  TOP w0.102: C6006.1 107.06,193.77 107.37,193.46 109.5,193.46 109.86,193.81 109.86,195.29 109.6,195.54 109.29,195.54 v2(108.97,195.87) ; v2(164.59,195.4) 164.92,195.07 166.88,195.07 ; v1(166.88,195.45) 166.88,195.07 ; 166.88,195.07 173.06,195.07 180.81,187.33 180.81,164.1 182.65,162.25 182.65,157.28 185.81,154.11 186.81,154.11 189.03,151.89 191.38,151.89 191.51,151.76 SB1.C39
  BOTTOM w0.102: v2(108.97,195.87) 109.29,195.54 110.17,195.54 110.69,196.06 162.59,196.06 163.58,195.07 164.27,195.07 v2(164.59,195.4)
SATA_TX_PCH_N2: length 116.9
  TOP w0.102: 169.09,196.09 v1(169.09,195.71) ; 169.09,196.09 172.73,196.09 181.29,187.53 181.29,164.33 183.17,162.45 183.17,157.44 185.89,154.72 186.88,154.72 189.42,152.18 191.04,152.18 SB1.B40 ; 169.09,196.09 163.7,196.09 163.24,195.62 163.24,193.74 v2(163.56,193.42) ; v2(118.78,194.88) 118.46,194.56 118.32,194.56 118.18,194.56 117.77,194.15 117.77,191.76 117.36,191.35 117.13,191.35 116.99,191.49 116.99,191.9 116.87,192.02 C6010.1
  BOTTOM w0.102: v2(163.56,193.42) 163.56,193.45 163.23,193.77 163.23,194.17 162.85,194.55 119.11,194.55 v2(118.78,194.88)
SATA_TX_PCH_N3: length 102.6
  TOP w0.102: 164.62,197.61 172.55,197.61 181.99,188.17 181.99,164.67 183.88,162.78 183.88,157.8 186.09,155.59 186.98,155.59 189.77,152.8 191,152.8 SB1.B41 ; 164.62,197.61 v1(164.62,197.23) ; 164.62,197.61 162.25,197.61 v2(161.93,197.29) ; v2(135.74,197.24) 135.41,197.57 132.47,197.57 131.08,196.18 131.08,194.2 130.47,193.59 129.63,193.59 129.36,193.86 129.36,194.3 C6014.1
  BOTTOM w0.102: v2(161.93,197.29) 161.6,197.61 159.77,197.61 158.88,196.72 140.66,196.72 139.74,197.65 136.15,197.65 v2(135.74,197.24)
SATA_TX_PCH_P0: length 90.1
  TOP w0.102: 175.51,191 179.89,186.62 179.89,163.72 181.74,161.87 181.74,156.9 185.43,153.2 186.32,153.2 189,150.52 190.57,150.52 191.35,151.3 SB1.C38 ; 175.51,191 173.47,193.04 166.55,193.04 164.94,191.43 164.12,191.43 v2(163.83,191.14) ; 175.51,191 v1(175.26,190.75) ; v2(138.84,192.27) 138.49,192.61 138.32,192.61 C6002.1
  BOTTOM w0.102: v2(163.83,191.14) 162.44,191.14 162.05,190.75 153.24,190.75 151.84,192.15 151.4,192.6 139.16,192.6 v2(138.84,192.27)
SATA_TX_PCH_P1: length 125.1
  TOP w0.102: 170.31,194.86 172.97,194.86 180.59,187.24 180.59,164.01 182.44,162.16 182.44,157.19 185.72,153.9 186.72,153.9 188.94,151.68 191.29,151.68 191.44,151.53 191.97,151.53 SB1.D39 ; 170.31,194.86 v1(170.31,194.49) ; 170.31,194.86 164.92,194.86 v2(164.59,194.53) ; v2(108.97,195) 109.29,195.33 109.51,195.33 109.64,195.2 109.64,193.9 109.41,193.68 107.46,193.68 107.28,193.86 107.28,194.07 107.42,194.21 107.8,194.21 107.95,194.36 C6005.1
  BOTTOM w0.102: v2(164.59,194.53) 164.27,194.86 163.49,194.86 162.5,195.85 110.78,195.85 110.26,195.33 109.29,195.33 v2(108.97,195)
SATA_TX_PCH_P2: length 116.9
  TOP w0.102: v2(162.69,193.45) 162.7,193.45 163.02,193.77 163.02,195.71 163.61,196.3 170.71,196.3 ; 170.71,196.3 v1(170.71,196.67) ; 170.71,196.3 172.82,196.3 181.5,187.62 181.5,164.42 183.39,162.54 183.39,157.53 185.98,154.94 186.97,154.94 189.51,152.4 191.28,152.4 191.54,152.38 SB1.C40 ; v2(118.78,194.02) 118.46,194.34 118.32,194.34 118.27,194.34 117.98,194.06 117.98,191.67 117.45,191.13 C6009.1
  BOTTOM w0.102: v2(118.78,194.02) 119.1,194.34 162.76,194.34 163.02,194.08 163.02,193.77 v2(162.69,193.45)
SATA_TX_PCH_P3: length 102.7
  TOP w0.102: SB1.C41 191.29,153.01 189.86,153.01 187.07,155.8 186.18,155.8 184.1,157.89 184.1,162.87 182.2,164.76 182.2,188.26 172.64,197.83 165.96,197.83 ; v2(161.93,198.15) 162.25,197.83 165.96,197.83 ; 165.96,197.83 v1(165.96,198.2) ; C6013.1 129.57,194.41 129.57,193.95 129.72,193.8 130.38,193.8 130.86,194.29 130.86,196.27 132.38,197.79 135.43,197.79 v2(135.74,198.11)
  BOTTOM w0.102: v2(135.74,198.11) 136.17,197.87 139.83,197.87 140.75,196.94 158.79,196.94 159.68,197.83 161.6,197.83 v2(161.93,198.15)
SB3V_CT2: length 2.9
  TOP w0.203: 93.33,214.89 93.15,215.07 U4201.10
  TOP w0.254: C4202.1 94.38,214.88 v1(94.28,214.78) 93.43,214.78 93.33,214.89
SB3V_EN: length 2.6
  TOP w0.102: U4201.5 89.59,215.07 v1(89.07,214.54) 89.03,214.5 R4202.2
SB5V_CT1: length 2.8
  TOP w0.203: 93.43,215.87 U4201.12
  TOP w0.254: 93.43,215.87 93.55,215.98 94.09,215.98 v1(94.16,216.05) 94.31,215.9 C4201.1
SD_CD_BD: length 30.8
  TOP w0.102: SD1.10 60.87,243.78 60.6,244.04 59.84,244.04 59.31,243.51 59.31,241.68 59.21,241.58 58.83,241.58 58.72,241.68 58.72,243.13 58.34,243.51 52.15,243.51 51.41,242.77 51.41,239.85 49.05,237.49 v1(49.05,236.4) 49.05,235.91 47.5,234.37 43.48,234.37 43.21,234.65 43.21,234.65 43.1,234.75 43.1,234.75 42.58,235.27 U3301.13
SD_CLK_BD: length 28.6
  TOP w0.102: SD1.5 50.77,243.41 50.65,243.54 47.24,243.54 47.14,243.43 47.14,243 47.24,242.9 47.79,242.9 47.89,242.8 47.89,242.47 47.99,242.37 48.29,242.37 48.4,242.47 48.4,242.8 48.5,242.9 49.56,242.9 49.81,242.65 49.81,239.37 48.29,237.85 48.29,235.81 47.24,234.77 43.74,234.77 42.8,235.71 v1(42.8,236.73) 42.8,237.64 42.38,238.06 C3305.1 40.89,238.06 R3301.1
SD_CMD_BD: length 31.4
  TOP w0.102: SD1.2 41.66,238.89 39.24,238.89 39.14,238.79 39.14,237.75 39.02,237.63 38.85,237.63 38.73,237.75 38.73,238.74 38.59,238.89 38.43,238.89 38.33,238.79 38.33,237.75 38.21,237.63 38.04,237.63 37.92,237.75 37.92,238.74 37.78,238.89 37.62,238.89 37.52,238.79 37.52,237.75 37.4,237.63 37.23,237.63 37.11,237.75 37.11,238.74 36.96,238.89 36.8,238.89 36.7,238.79 36.7,237.75 36.58,237.63 36.42,237.63 36.3,237.75 36.3,238.74 36.15,238.89 35.99,238.89 35.89,238.79 35.89,237.75 35.77,237.63 35.6,237.63 35.48,237.75 35.48,238.74 35.34,238.89 35.18,238.89 35.08,238.79 35.08,237.75 34.96,237.63 34.79,237.63 34.67,237.75 34.67,238.74 34.53,238.89 34.26,238.89 34.16,238.79 34.16,236.17 34.26,236.07 v1(36.45,236.07) 38.71,236.07 39.26,235.51 U3301.18
SD_DATA0_BD: length 30.5
  TOP w0.102: U3301.11 47.74,233.92 50.29,236.47 50.29,236.73 v1(50.27,236.75) 50.29,236.78 50.29,238 51.99,239.7 51.99,242.34 52.1,242.44 52.34,242.44 52.46,242.32 52.46,241.42 52.58,241.3 52.75,241.3 52.87,241.42 52.87,242.32 52.99,242.44 53.16,242.44 53.28,242.32 53.28,241.42 53.39,241.3 53.56,241.3 53.68,241.42 53.68,242.62 54.09,243.03 57.58,243.03 58.19,242.42 58.19,241.71 57.96,241.48 55.85,241.48 55.7,241.32 SD1.7
SD_DATA1_BD: length 31
  TOP w0.102: U3301.10 43.26,233.42 43.64,233.04 v1(46.13,233.04) 47.5,233.04 51.3,236.84 51.3,237.11 51.03,237.38 51.03,237.52 51.18,237.66 51.32,237.66 51.63,237.35 51.8,237.35 52.03,237.58 52.03,237.75 51.69,238.09 51.69,238.23 51.83,238.37 51.98,238.37 52.32,238.03 52.49,238.03 54.23,239.78 54.23,242.19 54.61,242.57 57.23,242.57 57.4,242.39 57.4,242.19 57.17,241.95 55.07,241.95 54.86,241.75 54.86,239.75 55.07,239.55 57.12,239.55 57.4,239.82 SD1.8
SD_DATA2_BD: length 30.5
  TOP w0.102: U3301.21 v1(36.45,233.42) 35.63,234.24 31.45,234.24 30.2,235.48 30.2,236.23 30.32,236.35 31.22,236.35 31.34,236.47 31.34,236.64 31.22,236.76 30.32,236.76 30.2,236.88 30.2,237.04 30.32,237.16 31.35,237.16 31.47,237.28 31.47,237.45 31.35,237.57 30.32,237.57 30.2,237.69 30.2,237.86 30.32,237.98 31.35,237.98 31.47,238.1 31.47,238.26 31.35,238.38 30.32,238.38 30.2,238.5 30.2,238.67 30.32,238.79 31.35,238.79 31.47,238.91 31.47,239.08 31.35,239.2 30.32,239.2 30.2,239.31 30.2,239.62 31.08,240.5 SD1.9
SD_DATA3_BD: length 31.3
  TOP w0.102: U3301.20 37.35,233.92 36.27,235 v1(35.23,235) 32.23,235 32.13,235.1 32.13,235.57 32.23,235.68 33.36,235.68 33.48,235.79 33.48,235.96 33.36,236.08 32.15,236.08 32,236.23 32,236.39 32.11,236.49 33.36,236.49 33.48,236.61 33.48,236.78 33.36,236.89 32.15,236.89 32,237.04 32,237.2 32.11,237.3 33.36,237.3 33.48,237.42 33.48,237.59 33.36,237.71 32.15,237.71 32,237.85 32,238.01 32.11,238.11 33.36,238.11 33.48,238.23 33.48,238.4 33.36,238.52 32.15,238.52 32,238.66 32,239.27 32.26,239.52 40.59,239.52 40.77,239.71 SD1.1
SD_RCOMP: length 1.1
  TOP w0.102: SB1.BE4 211.91,134.88 SB1.BE5 212.43,135.03 v2(212.47,135.07)
  vias: v1(212.55,133.48) v2(212.37,132.68)
SD_WP_BD: length 32
  TOP w0.102: U3301.8 44.31,232.42 v1(44.58,232.16) 47.14,232.16 54.13,239.14 57.3,239.14 59.29,241.13 61.68,241.13 62.28,241.73 62.28,244.17 61.09,245.36 SD1.11
SIO_GREEN: length 321.1
  TOP w0.102: v2(212.53,95.07) 212.53,95.39 211.86,96.07 U2401.24 208.79,96.07 207.77,95.05 200.17,95.05 198.15,97.07 198.15,97.76 v2(197.83,98.08) ; U2401.2 209.66,87.27 209.45,87.48 v2(209.45,87.91) ; R6414.2 R6412.2 19.6,228.94 23.88,224.66 v2(23.88,223.65) ; v2(167.39,167.64) 168.07,166.95 168.07,152.47 172.24,148.31 172.24,143.11 174.17,141.18 174.17,134.63 176.1,132.7 176.1,121.74 179,118.85 192.38,118.85 193.17,119.63 v2(193.8,119.63)
  BOTTOM w0.102: v2(212.53,95.07) 212.53,95.06 212.45,94.97 212.45,92.34 211.48,91.38 211.48,89.94 v2(209.45,87.91) ; v2(23.88,223.65) v1(29.72,223.65) 37.72,223.65 40.55,220.81 80.54,220.81 84.32,224.6 90.87,224.6 96.85,218.62 96.85,216.83 95.61,215.58 95.61,210.92 94.49,209.8 94.49,194.18 95.61,193.07 95.61,190.91 98.3,188.21 113.75,188.21 116.93,185.04 148.67,185.04 150.96,182.75 152.39,182.75 155.83,179.31 155.83,179.2 v2(167.39,167.64) ; v2(193.8,119.63) 193.8,118.48 196.46,115.82 196.72,115.82 199.77,112.78 199.77,107.94 198.73,106.9 198.73,106.51 198.73,105.16 199.46,104.43 199.46,101.79 197.69,100.02 197.69,98.22 v2(197.83,98.08)
SIO_GREEN_1: length 4
  TOP w0.102: Q6401.5 16.76,233.81 16.54,233.58 16.54,232.46 v1(17.12,231.87) 17.53,231.47 R6414.1
SIO_PECI_REQ_N: length 107.4
  TOP w0.089: SB1.BF36 212.58,150.59 212.74,150.43 214.01,150.43 214.5,150.92
  TOP w0.102: 214.5,150.92 214.5,151.27 215.03,151.8 222.5,151.8 222.91,152.22 224.08,152.22 224.64,151.67 224.64,151.38 225.06,150.96 225.56,150.46 R2002.1 227.52,150.46 228.68,151.61 v2(229.46,151.61) ; v2(212.9,93.7) 212.24,93.7 211.48,94.46 U2401.20
  BOTTOM w0.102: v2(212.9,93.7) 213.79,93.7 214.55,94.46 220.28,94.46 220.98,95.16 222.42,95.16 222.5,95.08 224.04,95.08 228.48,99.52 228.48,103.51 230.76,105.79 v1(230.76,106.05) 230.76,106.43 232.21,107.87 235,107.87 235.53,108.41 235.53,115.44 236.73,116.64 236.73,153.01 235.69,154.05 231.67,154.05 229.46,151.84 v2(229.46,151.61)
SIO_PS_ON_N: length 187.7
  TOP w0.102: v2(201.29,105.28) 201.5,105.08 201.5,104.55 201.55,104.5 201.55,103.38 201.63,103.3 201.63,103.28 201.65,103.26 201.65,102.24 201.2,101.78 U2401.53 ; R4302.1 217.74,212.47 215.65,212.47 213.95,214.16 213.95,217.02 213.61,217.36 210.96,217.36 209.55,215.95 198.48,215.95 194.87,212.33 194.87,208.13 193.8,207.06 v2(193.8,205.31) ; v2(165.86,184.35) 165.47,183.96 165.47,181.01 167.69,178.79 167.69,169.67 168.68,168.68 168.68,152.72 172.85,148.56 172.85,143.36 174.78,141.43 174.78,134.9 176.73,132.94 176.73,121.97 179.25,119.46 191.95,119.46 192.25,119.76 192.25,119.97 192.61,120.32 193.59,120.32 193.8,120.52 v2(194.31,120.52)
  BOTTOM w0.102: v2(201.29,105.28) 200.79,105.79 199.77,105.79 199.46,106.11 199.44,106.12 199.44,106.61 200.48,107.65 200.48,113.17 197.12,116.54 196.83,116.54 194.92,118.45 194.92,119.91 v2(194.31,120.52) ; v2(165.86,184.35) 167.34,185.83 169.95,185.83 189.43,205.31 v1(190.37,205.31) v2(193.8,205.31)
SIO_SMBCLK1: length 3.9
  TOP w0.102: R2425.1 193.38,97.64 v2(193.9,97.64) 194.28,97.27 U2401.70
  BOTTOM w0.102: v1(193.83,98.4) 193.83,97.71 v2(193.9,97.64)
SIO_SMBCLK2: length 3.9
  TOP w0.102: R2426.2 214.08,96.37 213.21,96.37 v1(212.98,96.6) 212.71,96.87 U2401.26
SIO_SMBDAT1: length 3
  TOP w0.102: U2401.72 193.98,96.47 v1(193.57,96.88) 193.04,97.41 R2427.1
SIO_SMBDAT2: length 4.1
  TOP w0.102: U2401.25 212.15,96.47 v1(213.26,95.35) 213.49,95.12 R2422.2
SIO_SPKR: length 6.6
  TOP w0.102: U2401.125 208,84.54 208.38,84.15 208.66,84.15 v2(208.88,83.93) 208.88,83.91 209.52,83.26 209.52,82.28 R2453.1 R2452.2
  BOTTOM w0.102: v1(208.42,84.8) 208.42,84.39 v2(208.88,83.93)
SIO_YELLOW: length 309.6
  TOP w0.102: v2(197.61,97.28) 200.08,94.82 208.06,94.82 208.9,95.67 U2401.23 ; v2(193.28,119.11) 192.79,118.62 178.9,118.62 175.87,121.65 175.87,132.6 173.94,134.53 173.94,141.09 172.01,143.02 172.01,148.21 167.84,152.38 167.84,166.42 v2(167.39,166.88) ; R6411.2 R6410.2 16,228.43 16,227.63 19.99,223.65 v2(22.86,223.65)
  BOTTOM w0.102: v2(193.28,119.11) 193.28,118.54 196.23,115.6 196.37,115.6 199.54,112.42 199.54,108.04 198.5,106.99 198.5,106.61 198.5,106.61 198.5,106.02 198.5,105.72 198.5,105.72 198.5,105.03 199.23,104.3 199.23,101.89 197.33,99.99 197.33,97.56 v2(197.61,97.28) ; v2(22.86,223.65) 23.75,222.76 v1(25.4,222.76) 37.96,222.76 40.13,220.59 80.44,220.59 80.63,220.59 84.42,224.37 90.59,224.37 96.62,218.34 96.62,216.92 95.38,215.68 95.38,211.02 94.26,209.9 94.26,194.09 95.38,192.97 95.38,190.81 98.23,187.96 113.68,187.96 116.83,184.81 148.58,184.81 150.86,182.52 152.29,182.52 155.6,179.22 155.6,178.66 v2(167.39,166.88)
SIO_YELLOW_1: length 4.1
  TOP w0.102: R6411.1 16.51,231 v1(15.65,231.86) 16.26,232.46 16.26,233.31 15.76,233.81 Q6401.2
SKL_CNL_N: length 13.6
  TOP w0.102: v2(67.89,117.91) 72,117.91 R422.2 ; CPU1.AB36 63.04,113.71 v2(63.5,113.24)
  BOTTOM w0.102: v2(63.5,113.24) 63.61,113.14 64.5,113.14 66,114.65 66.41,114.65 67.89,116.14 v1(67.89,116.71) v2(67.89,117.91)
SKL_PCUDEBUG_0: length 85.1
  TOP w0.102: v2(128.75,66.24) 128.56,66.05 125.93,66.05 124,67.98 124,76.49 125.73,78.22 125.73,80.11 124.69,81.15 121.42,81.15 121.42,81.15 108,81.15 104.67,84.48 97.52,84.48 94.05,87.95 89.6,87.95 86.36,91.19 v2(86.36,92.33) ; R9913.1 134.49,61.04 133.15,59.69 130.45,59.69 v2(129.24,60.91) ; v2(83.97,99.55) 84.42,99.99 CPU1.H15
  BOTTOM w0.102: v2(86.36,92.33) 86.11,92.33 TP404.1 85.18,93.61 85.18,94.4 85.17,94.41 85.17,95.89 85.3,96.02 85.3,98.78 85.05,99.04 84.49,99.04 v2(83.97,99.55) ; v2(129.24,60.91) 129.24,63.83 128.75,64.31 v2(128.75,66.24)
SKL_PCUDEBUG_1: length 4.7
  TOP w0.102: CPU1.F15 v2(83.99,97.72)
  BOTTOM w0.102: TP405.1 84.07,94.34 84.42,94.68 84.42,96.99 83.99,97.42 v2(83.99,97.72)
SKL_PCUDEBUG_2: length 2.7
  TOP w0.102: CPU1.F16 v2(83.06,97.71)
  BOTTOM w0.102: v2(83.06,97.71) 83.54,97.22 83.54,96.32 TP406.1
SKL_PCUDEBUG_3: length 57.1
  TOP w0.102: v2(86.74,89.53) 89.09,87.19 93.84,87.19 97.3,83.73 104.45,83.73 107.71,80.47 121.71,80.47 123.99,80.47 R423.1 ; CPU1.H16 v2(83.06,99.54)
  BOTTOM w0.102: v2(83.06,99.54) 82.58,99.05 82.58,97.55 82.26,97.24 81.97,97.24 81.36,96.63 81.36,94.16 TP407.1 81.74,92.5 84.71,89.53 v2(86.74,89.53)
SKL_PCUDEBUG_4: length 52.6
  TOP w0.102: v2(80.31,95.86) 80.37,95.81 80.37,95.28 80.7,94.95 80.7,93.95 82.12,92.53 82.52,92.53 88.33,86.73 93.65,86.73 97.19,83.19 104.34,83.19 107.52,80.01 119.02,80.01 119.79,79.25 121.48,79.25 R424.1 ; CPU1.F19 80.77,98.13 v2(80.33,97.69)
  BOTTOM w0.102: v2(80.31,95.86) 80.24,95.86 79.58,96.52 v1(79.58,96.52) 79.58,96.93 v2(80.33,97.69)
SKL_PCUDEBUG_5: length 3
  TOP w0.102: v2(81.25,99.52) 81.69,99.96 CPU1.H18
  BOTTOM w0.102: v2(81.25,99.52) 80.78,99.98 80.78,100.88 TP408.1
SKL_PCUDEBUG_6: length 2.6
  TOP w0.102: CPU1.G21 78.92,99.08 v2(78.46,98.61)
  BOTTOM w0.102: TP409.1 78.02,98.18 v2(78.46,98.61)
SKL_PCUDEBUG_7: length 2.8
  TOP w0.102: CPU1.H20 v2(79.38,99.52)
  BOTTOM w0.102: TP410.1 78.13,99.98 78.95,99.98 79.38,99.55 v2(79.38,99.52)
SKL_PCUDEBUG_8: length 2.8
  TOP w0.102: CPU1.G16 v2(83.06,98.62)
  BOTTOM w0.102: v2(83.06,98.62) 83.49,99.06 83.49,100.04 83.8,100.34 TP411.1
SKL_PCUDEBUG_9: length 51.8
  TOP w0.102: CPU1.E16 83.51,97.24 v2(83.07,96.79) ; R425.1 123.18,80.24 121.8,80.24 121.59,80.24 121.18,79.83 v1(120.47,79.83) 119.74,79.83 119.33,80.24 107.62,80.24 104.42,83.44 97.26,83.44 93.75,86.96 88.43,86.96 83.95,91.44 v2(83.95,91.77)
  BOTTOM w0.102: v2(83.07,96.79) 82.63,96.35 82.63,95.71 83.19,95.15 83.19,92.53 v2(83.95,91.77)
SKL_PCUDEBUG_10: length 3.7
  TOP w0.102: v2(82.12,97.71) 82.57,98.16 CPU1.F17
  BOTTOM w0.102: TP412.1 81.71,100.08 81.71,98.11 v2(82.12,97.71)
SKL_PCUDEBUG_11: length 2.9
  TOP w0.102: CPU1.H17 v2(82.14,99.54)
  BOTTOM w0.102: TP413.1 82.6,101.02 82.6,99.99 v2(82.14,99.54)
SKL_PCUDEBUG_12: length 4.6
  TOP w0.102: CPU1.G20 v2(80.3,99.52)
  BOTTOM w0.102: v2(80.3,99.52) 79.86,99.09 77.13,99.09 76.71,99.5 TP414.1
SKL_PCUDEBUG_13: length 1.4
  TOP w0.102: v2(79.4,98.62) CPU1.F20
  BOTTOM w0.102: TP415.1 79.4,98.62 v2(79.4,98.62)
SKL_PCUDEBUG_14: length 53.3
  TOP w0.102: v2(78.49,97.68) 78.94,98.14 CPU1.F21 ; R426.1 120.02,78.59 119.05,79.55 107.57,79.55 104.28,82.84 97.12,82.84 93.47,86.49 88.16,86.49 82.75,91.9 82.09,91.9 v2(80.29,93.7)
  BOTTOM w0.102: v2(80.29,93.7) 80.26,93.7 79.45,94.51 79.45,95.18 ; v2(78.49,97.68) 78.94,97.22 78.94,96.21 79.45,95.71 79.45,95.18 ; 79.45,95.18 v1(79.44,95.18)
SKL_PCUDEBUG_15: length 2.2
  TOP w0.102: CPU1.H19 80.77,99.99 v2(80.31,100.45)
  BOTTOM w0.102: v2(80.31,100.45) 80.17,100.6 80.17,101.89 TP416.1
SKL_PCUSTB_0_DN: length 82.5
  TOP w0.102: CPU1.E14 84.87,97.72 v2(84.87,97.74)
  BOTTOM w0.102: v1(124.46,69.29) 124.46,68.92 ; 124.46,68.92 143.34,68.92 143.92,69.5 XDP1.6 ; 124.46,68.92 123.48,68.92 120.9,66.34 110.41,66.34 108.61,68.14 108.61,74.05 96.43,86.23 91.24,86.23 84.98,92.49 84.98,94.15 84.87,94.26 v2(84.87,97.74)
SKL_PCUSTB_0_DP: length 84.4
  TOP w0.102: v2(84.87,98.6) 85.31,98.16 CPU1.F14
  BOTTOM w0.102: 121.65,66.79 120.99,66.13 110.32,66.13 108.39,68.05 108.39,73.96 96.34,86.02 91.15,86.02 84.76,92.4 84.76,94.06 84.65,94.17 84.65,97.34 84.44,97.55 84.44,98.17 v2(84.87,98.6) ; 121.65,66.79 v1(121.92,66.52) ; 121.65,66.79 123.57,68.71 143.43,68.71 144.42,69.69 XDP1.4
SKL_PCUSTB_1_DN: length 102.1
  TOP w0.102: v2(81.25,98.6) 81.69,99.04 CPU1.G18
  BOTTOM w0.102: 125.68,68.01 125.16,68.01 122.54,65.39 109.82,65.39 107.7,67.51 107.7,73.67 96.16,85.2 90.51,85.2 87.2,88.52 84.53,88.52 80.94,92.11 80.94,97.42 80.82,97.55 80.82,98.17 v2(81.25,98.6) ; 125.68,68.01 145.61,68.01 146.18,68.58 146.18,72.59 145.48,73.29 139.79,73.29 139.56,73.06 139.56,72.74 139.42,72.6 XDP1.24 ; 125.68,68.01 v1(125.68,67.61)
SKL_PCUSTB_1_DP: length 99.5
  TOP w0.102: CPU1.F18 v2(81.25,97.72)
  BOTTOM w0.102: 123.91,67.07 122.45,65.6 109.91,65.6 107.91,67.6 107.91,73.76 96.25,85.42 90.6,85.42 87.29,88.73 84.62,88.73 81.15,92.2 81.15,97.63 v2(81.25,97.72) ; 123.91,67.07 125.07,68.22 145.52,68.22 145.96,68.67 145.96,72.5 145.39,73.08 139.88,73.08 139.78,72.97 139.78,72.74 139.92,72.6 XDP1.22 ; 123.91,67.07 v1(123.65,67.34)
SLP_A_N_CN: length 15.2
  TOP w0.102: R9916.2 238.14,104.25 238.12,104.27 v1(237.57,104.27) 237.06,103.76 235.08,103.76 234.82,104.01 234.82,105.28 234.52,105.59 229.34,105.59 228.42,106.5 226.9,106.5 226.4,107 APS1.9
SLP_S0_N: length 66
  TOP w0.102: v2(222.71,160.6) 222.83,160.73 222.83,168.86 v2(224.56,170.59) ; SB1.BC28 211.21,146.45 214,146.45 215.78,144.66 215.78,143.75 216.29,143.24 218.1,143.24 218.46,143.61 223.61,143.61 224.68,144.68 v2(224.89,144.68) ; U2003.3 225.39,180.47 224.7,179.78 R2048.1 223.02,180.07 222.78,180.31 222.78,181.41 222.68,181.51 U2001.6 223.18,182.42 v2(223.49,182.42)
  BOTTOM w0.102: v2(224.56,170.59) 225.35,171.37 225.35,179.24 225.35,179.25 225.35,179.5 v1(224.51,180.34) 224.37,180.48 224.37,181.55 v2(223.49,182.42) ; v2(222.71,160.6) 222.71,158.67 224.99,156.38 224.99,151.06 225.38,150.67 225.38,149.65 225.5,149.53 225.5,146.64 226.14,146 226.14,144.93 225.88,144.68 v2(224.89,144.68)
SLP_S0_N_EXTD1: length 21.8
  TOP w0.102: U2002.6 228.32,188.12 227.85,188.58 224.16,188.58 222.98,187.4 221.74,187.4 220.78,186.44 219.2,186.44 v1(218.21,185.45) 217.14,184.38 217.14,182.4 218.03,181.51 U2001.4
SLP_S0_N_EXTD2: length 10.9
  TOP w0.102: U2002.5 228.82,184.67 228.55,184.4 227,184.4 225.04,186.36 v1(224.13,186.36) 223.67,186.36 223.01,185.7 223.01,184.02 223.67,183.36 U2003.6
SLP_S0_PLT_N: length 409.4
  TOP w0.102: 226.16,179.63 226.12,179.67 226.12,181.93 225.39,182.66 U2003.4 ; 226.16,179.63 229.08,179.63 230.89,181.43 230.89,186.16 232.66,187.93 v2(234.59,187.93) ; 226.16,179.63 225.81,179.27 222.43,179.27 222.14,179.57 R2048.2 221.37,180.54 218.44,180.54 216.79,182.19 216.79,182.93 216.38,183.34 215.34,183.34 213.92,181.92 v2(213.92,179.68) ; v2(96.77,29.21) 96.68,29.12 U4005.6 96.68,26.43 95.4,25.15 93.31,25.15 U4008.6 ; v2(211.81,177.8) 210.64,177.8 209.76,178.68 U9101.29 ; v2(151.76,3.94) 151.72,3.98 151.72,24.6 152.6,25.48 152.6,25.53 152.7,25.63 152.7,34.39 152.6,34.49 152.6,37.41 v2(153.03,37.85) 154.18,37.85 154.43,37.59 U4004.2 ; U2402.6 v2(211.21,79.6)
  BOTTOM w0.102: v2(151.76,3.94) 152.07,3.63 167.59,3.63 174.29,10.34 187.35,10.34 195.8,18.79 205.96,18.79 209.42,22.25 209.42,40.87 205.35,44.94 205.35,45.92 204.24,47.03 204.24,65.6 209.17,70.53 209.17,73.74 210.29,74.85 210.29,77.78 211.21,78.71 v2(211.21,79.6) 211.21,81.55 218.31,88.65 219.47,88.65 220.33,89.51 223.07,89.51 223.87,88.71 224.61,88.71 225.58,89.68 226.85,89.68 228.12,90.95 228.12,95.76 231.9,99.55 231.9,103.81 233.1,105 239.55,105 239.95,105.41 239.95,110.21 242.21,112.47 242.21,180.31 v2(234.59,187.93) ; v2(213.92,179.68) v1(212.63,178.38) 212.32,178.08 212.09,178.08 v2(211.81,177.8) ; v2(153.03,37.85) 152.53,37.34 152.53,34.82 149.96,32.26 127.57,32.26 126.38,31.06 121.4,31.06 120.99,30.66 115.8,30.66 115.51,30.37 103.62,30.37 99.97,30.37 98.81,29.21 v2(96.77,29.21)
SLP_S3_N: length 766.7
  TOP w0.102: v2(238.46,109.19) 238.42,109.19 237.13,110.49 225.27,110.49 224.73,109.94 R9917.1 ; v2(234.57,188.75) 229.84,188.75 228.65,189.94 223.61,189.94 222.49,188.82 222.48,188.82 222.38,188.72 221.01,188.72 220.27,187.99 v2(218.87,187.99) ; v2(216.46,155.96) 216.27,155.96 215.84,155.52 215.14,155.52 213.31,153.7 213.03,153.7 212.79,153.46 SB1.BF42 ; R4216.2 180.54,212.97 v2(180.54,211.71) ; v2(210.49,86.18) 210.21,86.18 209.4,87 207.24,87 206.4,86.15 U2401.121 ; v2(219.56,181.99) 219.07,181.99 218.63,182.44 R2046.1 218.52,182.99 R2049.1 ; v2(49.78,185.42) 49.86,185.5 R5002.2 ; v2(215.9,216.15) 215.9,216.71 216.79,217.6 216.79,219.46 216.52,219.73 U4301.1 212.54,219.73 209.06,216.25 198.35,216.25 193.81,211.71 v2(192.91,211.71) ; v2(107.57,228.35) 106.68,227.46 91.95,227.46 v2(90.3,225.81) ; U4002.5 84.43,22.86 84.51,22.78 v2(84.51,18.82)
  BOTTOM w0.102: v2(49.78,185.42) 49.71,185.5 45.9,185.5 43.94,187.45 39.75,187.45 35.31,183.01 25.27,183.01 23.11,185.17 23.11,187.58 21.97,188.72 14.17,188.72 8.89,194.01 8.89,209.47 20.83,221.41 20.83,223.9 v1(21.45,224.53) 22.1,225.17 40.01,225.17 43.18,222 78.87,222 82.68,225.81 v2(90.3,225.81) ; v2(218.87,187.99) 219.33,187.53 219.33,182.22 v2(219.56,181.99) 219.33,181.76 219.33,179.28 219.54,179.07 219.54,177.07 219.33,176.85 219.33,164.59 218.41,163.68 218.41,161.36 216.46,159.41 v2(216.46,155.96) ; v2(215.9,216.15) 218.68,213.37 222.14,213.37 223.27,212.24 223.27,208.81 229.06,203.02 229.06,194.77 234.57,189.26 v2(234.57,188.75) 234.06,188.24 234.06,187.76 241.91,179.91 241.91,112.6 238.51,109.19 v2(238.46,109.19) 239.5,108.15 239.5,105.77 239.04,105.31 232.97,105.31 231.6,103.94 231.6,99.7 227.69,95.79 227.69,93.06 226.42,91.79 226.41,91.79 225.14,90.52 222.61,90.52 222.07,89.98 221.33,89.98 220.79,90.52 218.79,90.52 215.77,87.5 215.77,86.55 211.29,82.06 ; v2(107.57,228.35) 108.48,228.35 122.17,214.66 122.62,214.21 158.89,214.21 161.42,211.68 174.39,211.68 174.42,211.71 v2(180.54,211.71) v2(192.91,211.71) ; 211.29,82.06 210.54,82.8 210.54,86.13 v2(210.49,86.18) ; 211.29,82.06 210.52,81.29 210.52,78.54 209.98,78 209.98,74.98 208.86,73.86 208.86,70.65 203.9,65.69 203.9,46.73 204.46,46.17 204.46,45.4 208.91,40.94 208.91,22.17 205.83,19.09 195.68,19.09 187.38,10.79 173.43,10.79 166.57,3.94 154.51,3.94 154.08,4.37 150.82,4.37 149.58,3.12 119.19,3.12 117.86,4.45 117.86,10.66 114.09,14.42 114.09,15.77 111.62,18.24 99.7,18.24 99.04,18.89 84.58,18.89 v2(84.51,18.82)
SLP_S3_N_CN: length 3.5
  TOP w0.102: R9917.2 226.29,109.83 v1(226.64,109.47) 226.64,108.89 227.4,108.14 APS1.8
SLP_S3_N_EXTD1: length 4
  TOP w0.102: R2046.2 R2047.2 219.52,184.14 220.09,184.71 v1(220.48,184.71) 220.96,184.22 U2001.3
SLP_S3_N_R: length 2.5
  TOP w0.102: Q4202.5 v1(179.2,214.38) 179.2,213.42 R4216.1
SLP_S3_N_R_1: length 4.4
  TOP w0.102: Q4202.1 179.85,218.66 179.58,218.93 v2(179.2,218.93) 178.8,218.93 178.56,218.69 178.56,217.73 Q4202.3
  BOTTOM w0.102: v2(179.2,218.93) 179.44,218.69 v1(180.09,218.69)
SLP_S4_N: length 687
  TOP w0.102: R9918.1 237.45,107.91 237.79,107.57 237.79,107.21 238.12,106.88 v2(238.4,106.88) ; v2(84.33,232.08) 84.33,229.36 84.43,229.26 85.56,229.26 U3801.4 ; U3201.4 v2(108.55,18.95) ; R809.2 126.05,120.61 v2(125.6,121.06) ; U4010.1 145.68,203.91 R4020.1 v2(145.59,204.6) ; U2401.69 196.11,97.67 199.75,94.03 207.65,94.03 v2(207.7,93.98) ; v2(142.88,215.87) 142.88,204.95 v2(142.52,204.6) 140.36,202.44 140.36,188.14 140.84,187.66 140.84,186.7 141.21,186.33 147.83,186.33 148.11,186.06 148.11,183.85 v2(147.9,183.64) ; v2(100.46,18.67) 99.44,18.67 99.31,18.54 U3901.4 ; SB1.BE42 212.15,153.49 212.34,153.69 212.7,153.69 212.95,153.94 213.27,153.94 215.14,155.8 215.75,155.8 216.03,156.08 216.03,156.14 216.36,156.46 219.25,156.46 219.3,156.41 222.02,156.41 222.82,157.21 R2050.1 223.08,157.99 227.48,157.99 227.74,158.24 230.98,158.24 231,158.25 231.1,158.34 231.1,158.34 233.4,158.34 233.65,158.6 235.61,158.6 v2(236.7,159.69) ; U2401.122 206.8,86.07 207.29,86.56 v2(207.85,86.56) 209.43,86.56 210.35,85.64 212.63,85.64 212.64,85.63 v2(214.07,85.63)
  BOTTOM w0.102: v2(125.6,121.06) 125.6,123.8 130.71,128.91 130.71,135.74 138.52,143.55 138.52,146.01 139.09,146.58 139.09,148.97 147.24,157.12 147.24,164.74 148.49,165.99 149,165.99 149.58,166.57 149.58,182.26 148.2,183.64 v2(147.9,183.64) ; 142.88,215.86 123.25,215.86 107.09,232.03 84.38,232.03 v2(84.33,232.08) ; 142.88,215.86 142.99,215.75 159.66,215.75 162.2,213.21 173.76,213.21 175.23,214.68 184.43,214.68 185.55,215.8 195.17,215.8 195.96,215.01 197.82,215.01 197.96,215.15 v1(202.82,215.15) 213.27,215.15 223.37,205.05 223.37,194.41 224.03,193.75 224.03,192.43 227.97,188.49 227.97,186.69 227.25,185.98 227.25,180.03 227.25,179.95 228.98,178.22 228.98,176.85 229.6,176.15 230.76,176.15 231.19,175.72 231.19,173.78 238.33,166.65 238.33,161.32 v2(236.7,159.69) 238.33,158.06 238.33,115.97 237.24,114.88 237.24,108.05 v2(238.4,106.88) 238.94,106.35 238.94,105.76 238.79,105.61 232.84,105.61 230.53,103.3 230.53,99.07 225.88,94.41 225.88,92.09 224.74,90.95 222.91,90.95 222.07,91.79 221.33,91.79 220.49,90.95 218.28,90.95 215.16,87.83 215.16,86.73 v2(214.07,85.63) ; 142.88,215.86 v2(142.88,215.87) ; v2(207.7,93.98) 207.25,93.54 207.25,90.17 207.06,89.97 207.06,87.65 207.85,86.86 v2(207.85,86.56) 208.18,86.23 209.27,86.23 210.19,85.32 210.19,78.64 208.95,77.41 208.95,74.85 208.56,74.46 208.56,70.78 203.59,65.81 203.59,45.59 208.38,40.8 208.38,22.07 205.71,19.4 195.55,19.4 187.25,11.1 173.14,11.1 166.28,4.24 154.64,4.24 154.21,4.67 150.95,4.67 150.7,4.67 149.45,3.43 119.31,3.43 118.16,4.58 118.16,10.78 114.39,14.55 114.39,15.89 111.33,18.95 v2(108.55,18.95) 108.14,18.54 100.58,18.54 v2(100.46,18.67) ; v2(142.52,204.6) 142.52,204.6 v2(145.59,204.6)
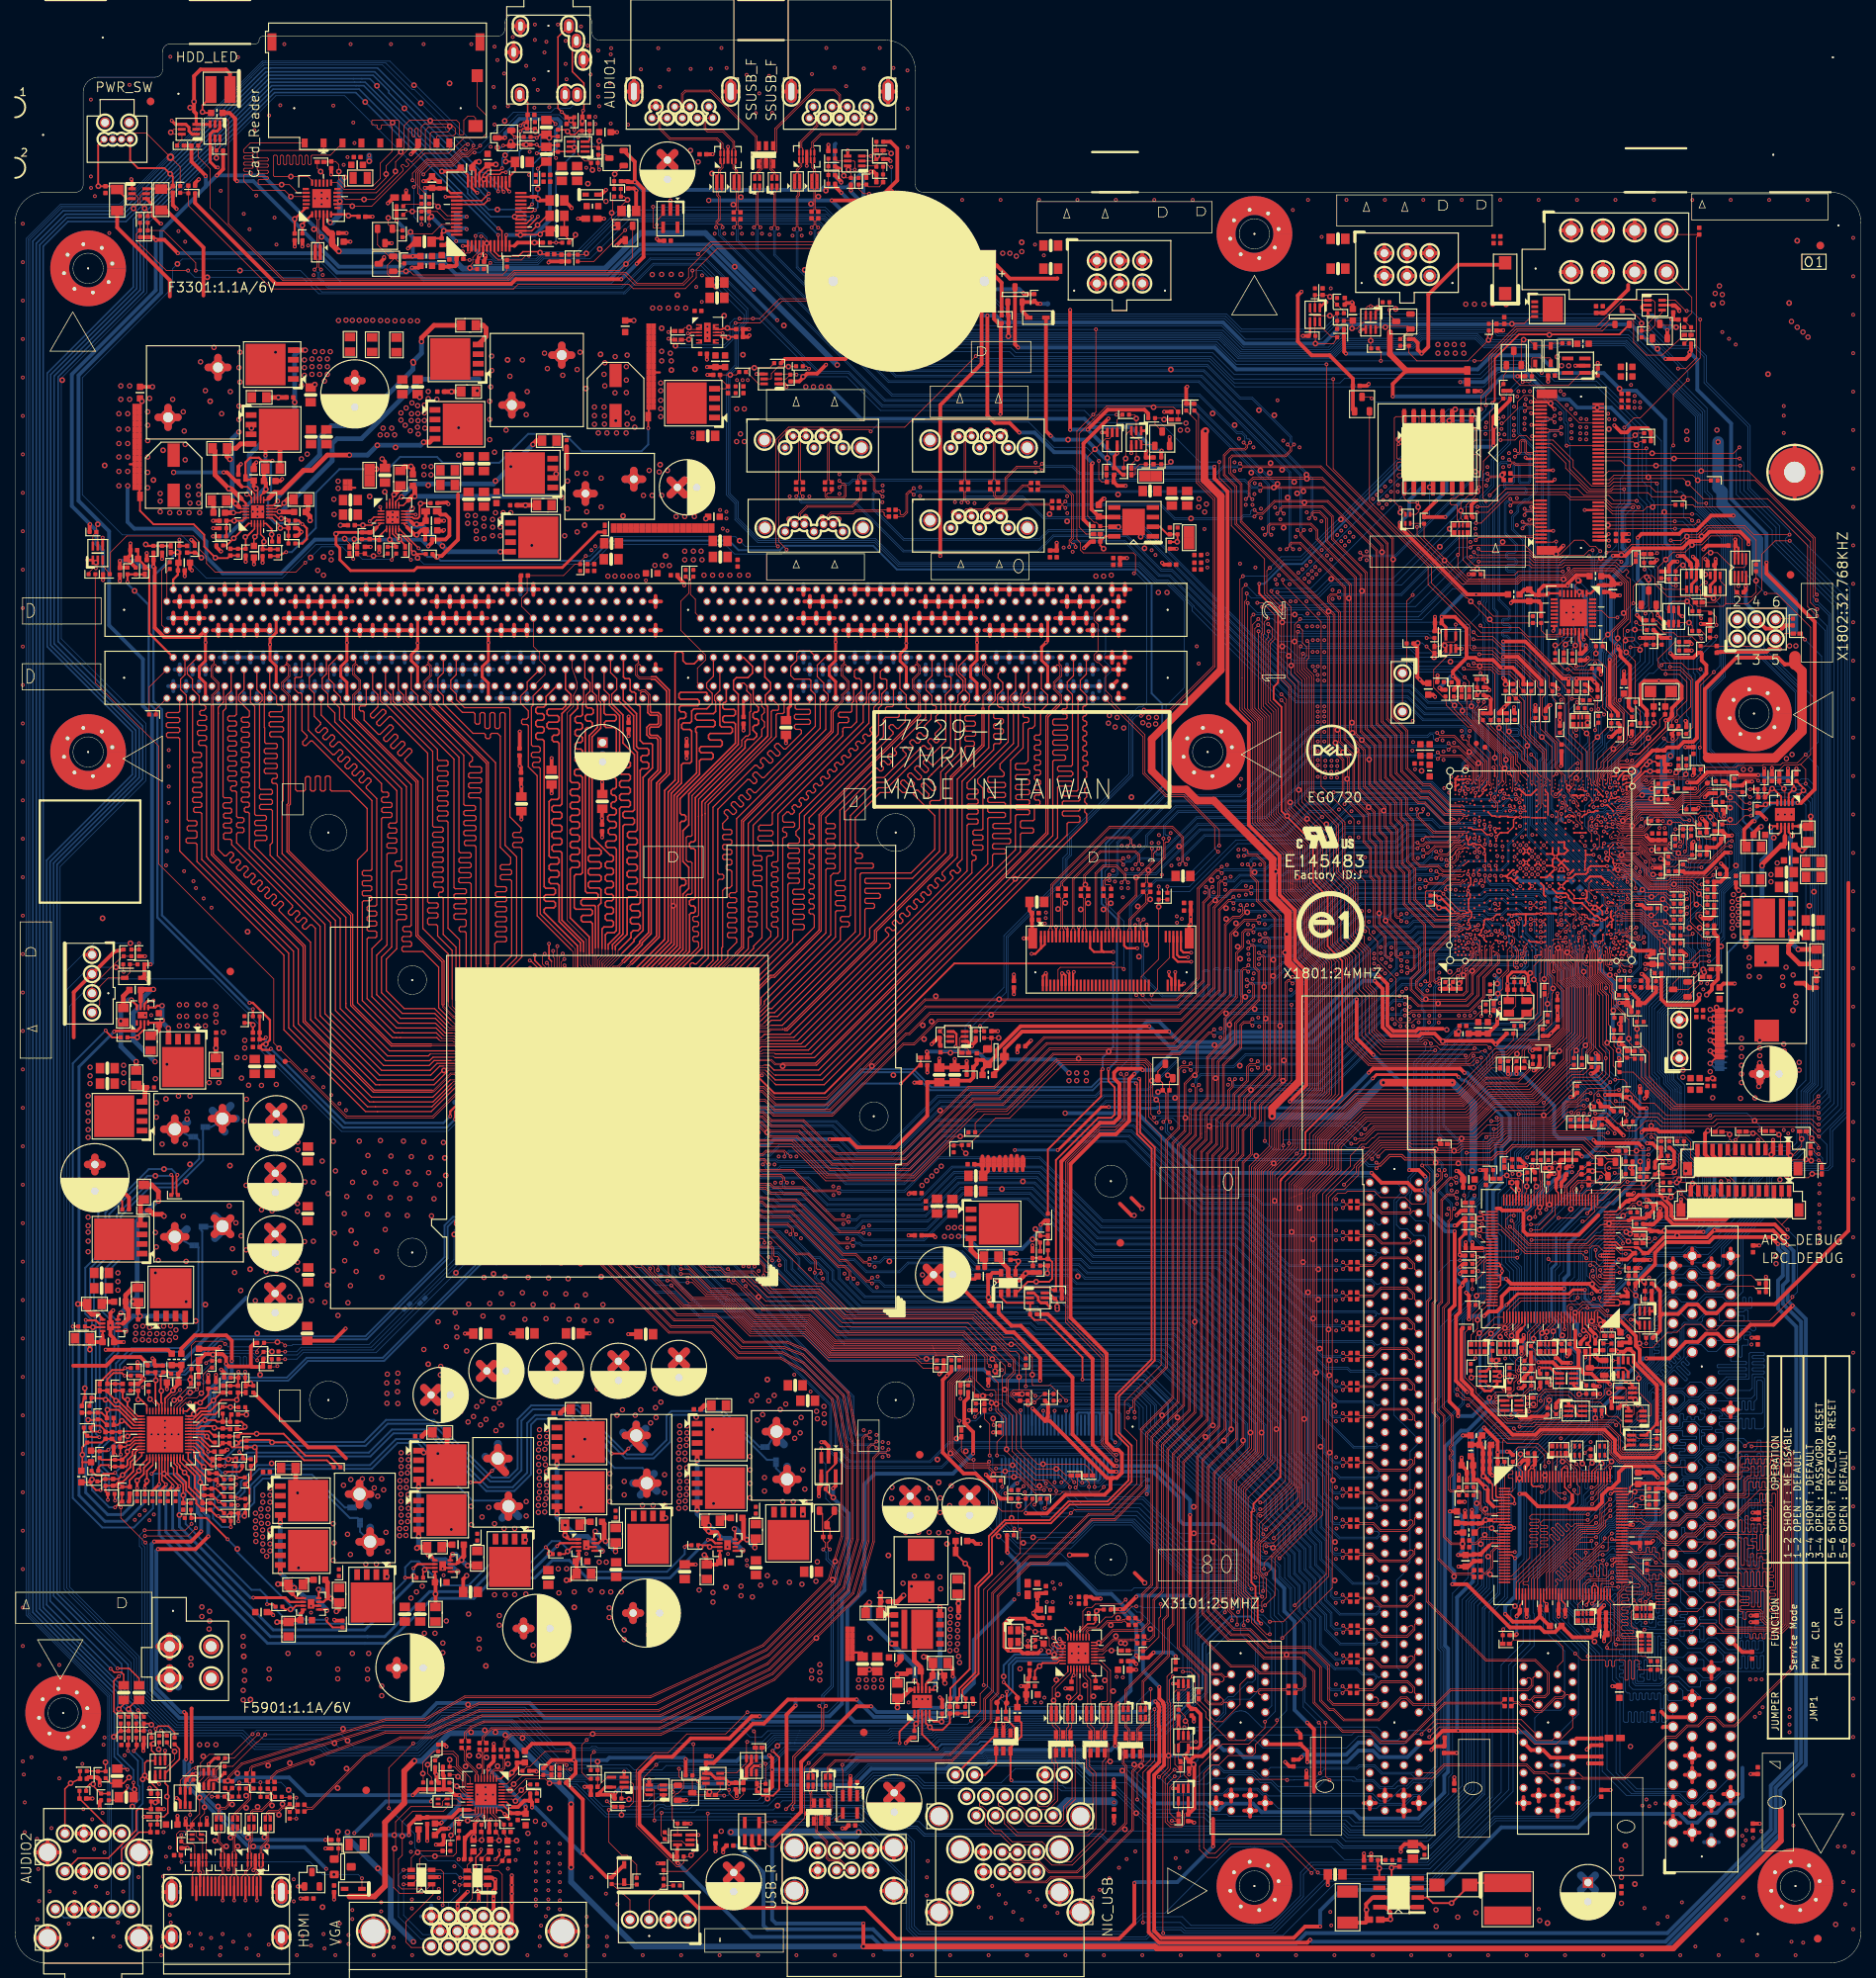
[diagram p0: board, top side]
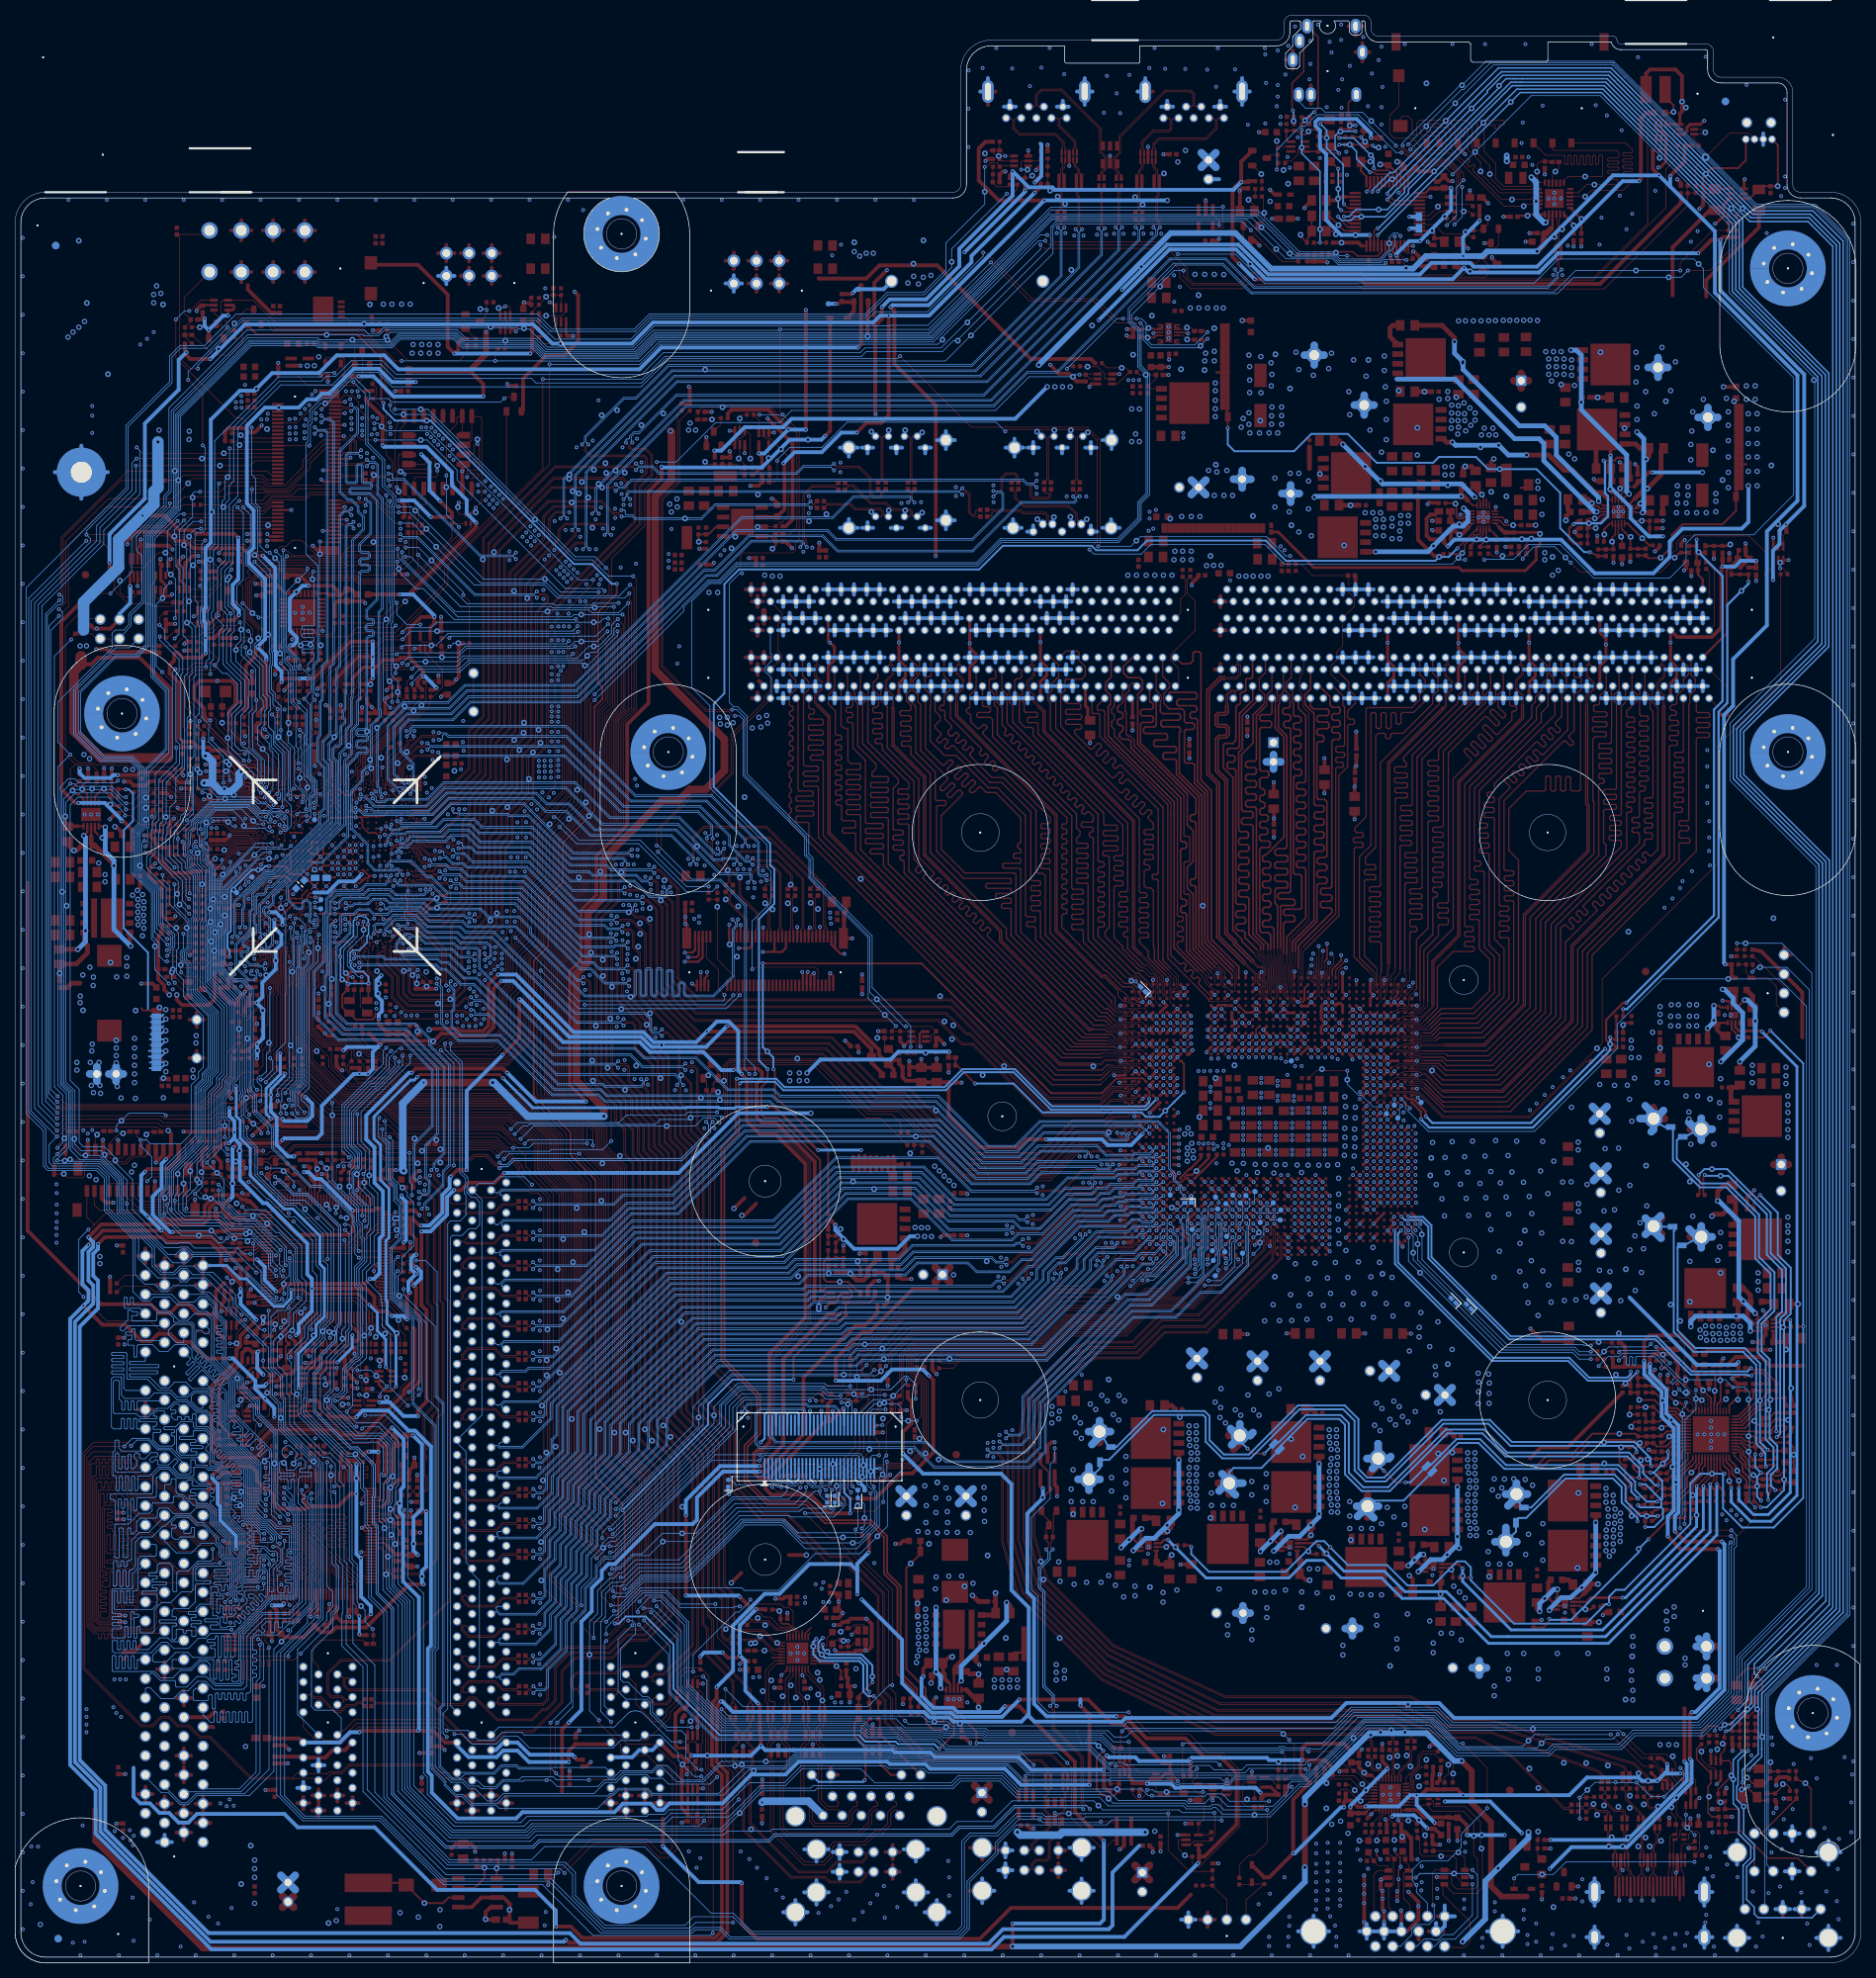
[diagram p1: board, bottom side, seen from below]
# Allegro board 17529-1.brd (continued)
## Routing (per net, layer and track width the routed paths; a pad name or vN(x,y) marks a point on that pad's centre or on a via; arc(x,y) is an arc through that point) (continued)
SLP_S4_N_CN: length 11.2
  TOP w0.102: R9918.2 237.34,106.2 237.44,106.1 v1(237.44,106.02) 237.35,106.11 235.01,106.11 234.8,105.89 229.46,105.89 228.4,106.96 APS1.7
SLP_S4_N_SFR: length 5.7
  TOP w0.102: C806.1 122.39,120.27 v1(123.65,120.27) R809.1 124.84,120.59 124.84,122.17 125.09,122.43 Q802.2
SLP_S4_N_SFR_1: length 106
  TOP w0.102: 122.91,122.47 R810.1 122.87,123.75 v2(126.24,123.75) ; 122.91,122.47 122.91,121.87 123,121.78 Q802.6 ; 122.91,122.47 122.95,122.43 Q802.5 ; v2(149.22,165.62) 152.62,165.62 158.39,171.39 158.39,193.37 156.16,195.61 156.16,203.8 R807.2
  BOTTOM w0.102: v2(149.22,165.62) 148.6,165.62 147.55,164.57 147.55,157 139.4,148.84 139.4,146.46 138.82,145.89 138.82,143.42 131.01,135.61 131.01,128.27 v1(130.09,127.34) 126.49,123.75 v2(126.24,123.75)
SLP_S4_N_SFR_2: length 101.1
  TOP w0.102: R804.2 156.44,204.58 156.44,195.71 158.62,193.52 158.62,171.3 152.7,165.38 149.66,165.38 149.07,164.8 v2(148.84,164.8) ; v2(127.56,123.8) 128.09,123.27 R805.1 R806.1 126.95,123.08 Q802.3
  BOTTOM w0.102: v2(127.56,123.8) v1(129.03,125.28) 131.24,127.48 131.24,135.52 139.05,143.33 139.05,145.79 139.62,146.36 139.62,148.75 147.78,156.9 147.78,164.34 148.23,164.8 v2(148.84,164.8)
SLP_S4_N_SFR_G: length 5.3
  TOP w0.102: C802.1 129.06,121.28 Q801.G 127.98,120.21 C803.1 ; C802.1 v1(130.02,122.24) ; C802.1 R805.2
SLP_S4_VPP_N: length 2.9
  TOP w0.102: Q4002.2 v1(148.21,204.09) 148.21,204.37 147.98,204.6 R4020.2
SLP_SUSB: length 353.2
  TOP w0.089: 213.3,152.12 213.16,152.12 212.94,151.9 212.16,151.9 212.08,151.98 211.61,151.98 SB1.BD39
  TOP w0.102: v2(86.36,214.63) 86.49,214.5 R4202.1 ; v2(236.7,155.83) 236.7,157.71 236.04,158.37 ; v2(95.23,216.71) 95.23,216.7 95.25,216.72 98.49,216.72 101.37,219.61 109.88,219.61 v2(115,224.73) ; 236.04,158.37 237.36,159.69 237.36,176.5 232.89,180.97 v2(231.39,180.97) ; 236.04,158.37 235.81,158.37 235.74,158.29 233.86,158.29 233.22,157.66 R5101.1 ; U2401.71 196.48,96.87 199.62,93.73 207.11,93.73 v2(207.72,93.12) ; v2(229.36,154.05) 228.69,154.72 R2053.1 228.18,154.86 226.53,154.86 226.13,155.27 223.65,155.27 222.52,154.14 220.63,154.14 219.34,152.85 214.39,152.85 213.65,152.12 213.3,152.12
  BOTTOM w0.102: v2(229.36,154.05) 229.79,154.05 231.23,155.49 235.85,155.49 236.19,155.83 v2(236.7,155.83) 237.79,154.74 237.79,116.19 236.7,115.1 236.7,107.42 235.43,106.15 232.62,106.15 229.97,103.5 229.97,99.36 223.13,92.52 221.33,92.52 220.52,93.33 215.73,93.33 210.11,87.71 210.11,87.64 209.6,87.13 208.75,87.13 207.98,87.91 207.98,89.23 207.57,89.64 207.57,92.96 v2(207.72,93.12) ; v2(86.36,214.63) v1(87.29,213.7) 87.55,213.44 93.8,213.44 94.87,214.5 94.87,216.34 95.23,216.7 v2(95.23,216.71) ; v2(115,224.73) 123.32,216.41 128.33,216.41 128.38,216.36 159.5,216.36 162.35,213.51 173.63,213.51 176.02,215.9 177.49,215.9 177.7,216.1 195.3,216.1 196.09,215.32 197.36,215.32 197.82,215.77 213.35,215.77 223.67,205.45 223.67,194.54 224.33,193.88 224.33,192.56 228.6,188.29 228.6,183.77 v2(231.39,180.97)
SLP_WLAN_N: length 78.7
  TOP w0.102: v2(215.6,156.26) 215.3,156.26 213.19,154.14 212.79,154.14 212.54,153.89 212.26,153.89 212.09,153.72 211.82,153.72 SB1.BD42 ; v2(201.8,210.11) 200.94,210.97 D6301.K ; v2(218.77,171.27) 220.12,171.27 221.79,169.6 221.79,163.28 R2052.1 220.92,162.43 R2044.1 219.85,162.38 219.85,161.89 219.3,161.34 218.44,161.34 v2(217.97,161.81)
  BOTTOM w0.102: v2(215.6,156.26) 215.7,156.36 v1(215.7,158.37) 215.7,159.26 217.97,161.53 v2(217.97,161.81) ; v2(201.8,210.11) 201.88,210.19 203.02,210.19 203.61,209.59 209.17,209.59 217.63,201.14 217.63,187.47 218.26,186.84 218.26,178.91 218.53,178.65 218.53,177.49 218.31,177.27 218.31,172.42 218.77,171.96 v2(218.77,171.27)
SM_DRAMRST#: length 244.2
  TOP w0.089: SB1.BB46 210.74,155.91 210.74,156.53 210.68,156.59 210.68,157.04 210.76,157.11
  TOP w0.102: 210.76,157.11 212.09,158.45 213.31,158.45 v2(213.75,158.89) ; v2(75.44,185.93) 74.7,185.19 R1104.2 74,184.85 72.49,183.34 C1108.1 67.69,183.25 67.69,181.1 66.97,180.39 66.97,179.24 DIMM2.58 68.51,173.98 69.34,173.15 69.34,172.14 70.04,171.43 70.04,170.26 DIMM1.58 ; v2(100.84,187.2) 100.58,187.45 100.58,201.29 102.23,202.95 117.6,202.95 v2(127,212.34)
  BOTTOM w0.102: v2(127,212.34) 127.34,212 157.97,212 161.19,208.79 175.13,208.79 175.77,209.42 193.82,209.42 195.65,211.25 199.36,211.25 202.08,208.53 208.86,208.53 214.58,202.82 214.58,193.82 215.7,192.71 215.7,185.21 216.76,184.14 216.76,178.95 216,178.18 216,176.37 216.53,175.84 216.53,171.65 214.12,169.24 214.12,166.25 215.36,165.01 215.36,160.49 v2(213.75,158.89) ; v2(75.44,185.93) 76.02,185.93 78.56,188.47 95.25,188.47 v1(95.77,187.94) 96.52,187.2 v2(100.84,187.2)
SM_PGCNTL: length 106.4
  TOP w0.089: CPU1.AC36 62.47,115.18 61.46,115.18 61.46,115.18
  TOP w0.102: 61.46,115.18 59.12,115.18 59.06,115.11 58.93,115.06 58.34,115.06 55.18,111.9 43.86,111.9 v1(34.89,120.87) 34.19,121.57 34.19,130.02 19,145.21 19,160.78 10.59,169.19 10.59,183.64 R416.2
SMB_CLK_MAIN: length 402.3
  TOP w0.102: v2(159.03,146.84) 158.57,147.29 158.57,150.02 154.47,154.13 152.12,154.13 149.1,157.15 149.1,162.05 144.16,166.99 DIMM1.141 ; v2(192.65,89.05) R2461.1 193.19,90.25 194.18,91.24 194.18,92.51 194.53,92.87 U2401.81 ; v2(72.9,26.14) 72.67,26.37 71.54,26.37 R5911.2 ; v2(173.75,24.14) 173.23,24.66 v2(173.23,31.75) ; v2(145.57,67.16) 145.31,67.16 143.85,68.62 143.85,80.18 139.09,84.94 139.09,105.76 143.36,110.03 145.39,110.03 146.76,111.4 146.76,117.3 v2(146.94,117.47)
  BOTTOM w0.102: XDP1.53 131.92,66.89 132.33,67.31 145.41,67.31 v2(145.57,67.16) 151.45,67.16 164.92,53.7 166.09,53.7 167.28,52.5 167.28,51.01 168.73,49.56 168.73,46.66 170.51,44.88 170.51,34.47 v2(173.23,31.75) ; DIMM1.141 144.16,167.62 144.02,167.76 144.02,169.82 144.85,170.64 144.85,171.21 144.02,172.04 144.02,172.94 144.16,173.08 DIMM2.141 ; v2(192.65,89.05) 192.65,88.3 188.47,84.12 188.47,74.8 187.53,73.86 187.53,34.09 187.83,33.79 187.96,33.65 187.96,25.91 186.22,24.17 185.19,24.17 185.17,24.18 184.77,24.18 183.96,23.37 182.75,23.37 182.42,23.04 180.42,23.04 179.45,24 176.83,24 176.7,24.14 v2(173.75,24.14) 173.16,24.14 172.34,23.32 166.95,23.32 166.1,24.17 164.67,24.17 164.58,24.26 163.69,25.15 159.76,25.15 159.06,25.84 158.46,25.84 156.54,23.93 152.98,23.93 150.88,26.04 v1(148.84,26.04) 142.25,26.04 140.97,27.31 140.8,27.48 128.33,27.48 128,27.15 123.3,27.15 122.69,26.54 111.66,26.54 109.92,24.79 73.56,24.79 72.9,25.45 v2(72.9,26.14) ; v2(159.03,146.84) 155.17,142.98 150.85,142.98 147.57,139.71 147.57,118.11 v2(146.94,117.47)
SMB_CLK_RESUME: length 253.6
  TOP w0.102: SLOT2.B5 183.84,24.38 187.3,24.38 188.96,26.04 199.75,26.04 200.75,25.04 202.16,25.04 203.08,24.12 SLOT3.B5 204.16,24.38 207.07,24.38 207.17,24.28 212.85,24.28 218.28,29.72 219.6,29.72 221.09,31.21 222.55,31.21 223.69,32.35 224.66,32.35 225.8,31.21 227.38,31.21 235.03,38.86 235.03,67.39 233.6,68.81 229.18,68.81 v2(228.68,68.3) ; v2(214.8,144.17) 214.8,144.78 213.82,145.76 211.83,145.76 SB1.BE26 ; v2(193.42,91.44) 193.42,91.44 193.32,91.34 R2437.1 192.65,91.38 194.53,93.26 U2401.80 198.51,93.26 v2(198.58,93.19) ; SLOT1.B5 163.4,24.26 168.06,24.26 v2(168.15,24.17) ; v2(190.63,75.06) 191.43,74.42 192.15,74.42 197.44,69.14 201.26,69.14 201.92,69.8 209.76,69.8 210.82,68.74 210.82,67.46 210.82,67.46 210.82,67.27 212.03,66.07 218.34,66.07 218.92,65.49 SLOT4.79
  BOTTOM w0.102: v2(198.58,93.19) 199.09,93.7 199.09,97.33 199.42,97.66 199.42,98.51 203.42,102.51 204.97,102.51 210.08,107.63 210.08,110.31 212.33,112.55 212.33,114.59 212.93,115.2 212.93,115.53 213.06,115.65 213.06,127.91 213.03,127.93 213.03,128.63 214.04,129.64 215.16,129.64 216.82,131.3 216.82,136.31 216.49,136.63 216.49,142.14 214.8,143.83 v2(214.8,144.17) ; SLOT4.79 221.7,65.96 223.54,67.8 225.15,67.8 226.44,69.09 227.89,69.09 v2(228.68,68.3) ; v2(168.15,24.17) 169.07,24.17 169.09,24.18 172.44,24.18 172.87,24.61 176.96,24.61 177.34,24.23 179.55,24.23 180.51,23.27 182.04,23.27 182.9,24.12 SLOT2.B5 ; v2(193.42,91.44) 193.7,91.16 193.7,88.16 190.2,84.66 190.2,75.49 v2(190.63,75.06)
SMB_DATA_MAIN: length 406.3
  TOP w0.102: v2(172.49,25.04) 172.59,25.15 172.59,31.5 v2(172.34,31.75) ; U2401.79 194.45,93.66 193.17,92.38 R2459.1 192.58,92.38 192.13,92.84 v2(191.01,92.84) ; v2(159.18,147.65) 159.18,149.74 154.56,154.36 152.22,154.36 149.35,157.22 149.35,162.31 144.94,166.72 144.94,167.36 144.16,168.13 DIMM1.285 143.24,171.84 143.03,171.84 142.63,172.24 142.63,172.85 143.15,173.37 143.15,176.9 142.62,177.42 142.62,178.37 DIMM2.285 ; v2(145.59,66.4) 145.59,66.52 143.62,68.49 143.62,79.9 138.86,84.66 138.86,105.86 143.44,110.44 145.47,110.44 146.53,111.5 146.53,117.12 v2(146.18,117.47) ; v2(73.41,25.58) 72.1,25.58 R5912.2
  BOTTOM w0.102: v2(191.01,92.84) 189.74,92.84 188.21,91.31 188.21,74.87 187.3,73.96 187.3,34.18 187.3,33.99 187.73,33.56 187.73,26 186.13,24.4 185.28,24.4 185.27,24.41 185.09,24.41 184.56,24.94 180.63,24.94 179.64,25.93 177.75,25.93 177.42,25.6 173.05,25.6 v2(172.49,25.04) 172.09,24.64 165.8,24.64 165.56,24.4 164.96,24.4 163.98,25.38 159.85,25.38 159.15,26.07 157.77,26.07 155.85,24.16 153.14,24.16 150.67,26.62 v1(144.75,26.62) 141.99,26.62 140.9,27.71 128.24,27.71 127.91,27.38 123.21,27.38 122.59,26.77 111.57,26.77 109.9,25.1 81.46,25.1 80.85,25.7 73.53,25.7 v2(73.41,25.58) ; v2(172.34,31.75) 170.28,33.81 170.28,44.79 168.5,46.57 168.5,49.46 167.06,50.91 167.06,52.3 165.96,53.39 164.9,53.39 151.89,66.4 145.59,66.4 v2(145.59,66.4) 145.59,66.47 145.01,67.06 132.59,67.06 132.42,66.89 XDP1.51 ; v2(146.18,117.47) 146.18,118.36 147.32,119.51 147.32,139.77 150.75,143.21 154.53,143.21 158.98,147.65 v2(159.18,147.65)
SMB_DATA_RESUME: length 247.8
  TOP w0.102: v2(190.63,75.82) 191.77,74.68 192.22,74.68 197.53,69.37 201.17,69.37 201.83,70.03 209.95,70.03 211.05,68.93 211.05,67.36 212.12,66.29 218.7,66.29 SLOT4.81 ; v2(193.4,93.28) 193.36,93.28 193.17,93.47 R2436.1 193.13,93.98 194.08,93.98 194.16,94.06 U2401.78 v2(198.58,94.06) ; v2(229.57,68.25) 233.68,68.25 234.8,67.13 234.8,38.95 227.28,31.44 225.9,31.44 224.76,32.58 223.6,32.58 222.45,31.44 221,31.44 219.53,29.97 218.21,29.97 212.75,24.51 207.26,24.51 206.65,25.12 SLOT3.B6 205.8,25.02 202.69,25.02 202.44,25.27 200.85,25.27 199.85,26.27 188.86,26.27 187.71,25.12 SLOT2.B6 ; v2(214.27,144.7) 214.27,144.91 213.62,145.56 212.33,145.56 SB1.BF26
  BOTTOM w0.102: v2(190.63,75.82) 190.63,84.72 193.93,88.02 193.93,92.75 v2(193.4,93.28) ; v2(198.58,94.06) 198.72,94.2 198.72,97.4 199.19,97.87 199.19,98.6 203.33,102.74 204.88,102.74 209.85,107.72 209.85,110.22 209.85,110.22 209.85,110.41 212.1,112.65 212.1,114.69 212.7,115.29 212.7,115.62 212.83,115.75 212.83,127.94 212.78,127.99 212.78,128.66 213.96,129.84 215.07,129.84 216.61,131.39 216.61,136.23 216.28,136.56 216.28,142.07 214.27,144.08 v2(214.27,144.7) ; v2(229.57,68.25) 228.5,69.32 226.35,69.32 225.06,68.03 223.35,68.03 222.08,66.76 SLOT4.81 ; SLOT1.B6 165.97,25.83 177.32,25.83 177.65,26.16 179.73,26.16 180.72,25.17 185.53,25.17 SLOT2.B6
SMBALERT_N: length 14.7
  TOP w0.102: R2316.1 R2314.1 223.01,140.84 v1(222.59,141.26) 221.53,142.32 219.86,142.32 219.52,141.98 218.93,141.98 218.68,142.24 216.1,142.24 214.8,143.53 214.54,143.53 213.71,144.36 212.86,144.36 212.52,144.7 212.37,144.7 212.07,145 SB1.BE25
SML0ALERT#: length 18.8
  TOP w0.102: SB1.BF24 212.47,144.47 212.77,144.16 213.62,144.16 214.46,143.33 214.72,143.33 216.01,142.03 218.56,142.03 218.84,141.75 219.62,141.75 219.92,142.06 220.11,142.06 220.11,142.06 221.21,142.06 221.96,141.31 221.96,140.18 v1(222.27,139.87) 222.76,139.87 223.7,138.93 R2323.1 222.33,138.79 222.2,138.66 222.2,138.07 223.16,137.11 R2321.1
SML0CLK_PCH: length 12.8
  TOP w0.102: 219.29,142.55 219.18,142.44 216.18,142.44 214.89,143.73 214.62,143.73 213.79,144.57 212.99,144.57 212.56,145 SB1.BF25 ; 219.29,142.55 219.54,142.79 221.63,142.79 222,142.43 222,142.42 222.25,142.16 222.26,142.16 222.56,141.86 R2009.1 ; 219.29,142.55 v1(219.29,142.54)
SML0DATA_PCH: length 17.8
  TOP w0.102: R2010.1 223.38,136.09 v1(222.68,136.8) 222.22,136.8 221.5,137.52 221.5,141.39 221.11,141.78 219.97,141.78 219.71,141.53 218.77,141.53 218.47,141.83 215.93,141.83 214.63,143.12 214.37,143.12 213.54,143.96 212.69,143.96 212.53,144.12 211.95,144.12 SB1.BE24
SMLICLK_PCH: length 77.6
  TOP w0.102: v2(215.98,95.76) 215.6,96.14 R2426.1 ; SB1.BF27 213.96,146.19 215.58,144.58 215.58,143.66 216.25,142.99 218.48,142.99 218.87,143.38 224.12,143.38 v2(224.5,143.76) 224.63,143.89 R2012.1
  BOTTOM w0.102: v2(215.98,95.76) 216.56,95.17 217.17,95.17 218.13,96.14 v1(219.71,96.14) 222,96.14 223.65,97.79 224.03,97.79 225.03,98.79 225.03,101.41 224.13,102.3 224.13,105.31 220.24,109.19 220.24,114.9 220.24,115.8 219.27,116.77 219.27,117.52 218.47,118.33 218.47,125.12 221.28,127.93 221.28,131.86 221.84,132.43 221.84,133.63 221.26,134.22 221.26,137.61 223.55,139.9 223.55,142.31 224.5,143.26 v2(224.5,143.76)
SMLIDATA_PCH: length 74.4
  TOP w0.102: R2013.1 223.31,142.88 v2(222.95,142.52) 222.41,142.52 221.8,143.13 219,143.13 218.53,142.67 216.25,142.67 215.38,143.54 215.38,144.33 215.38,144.49 213.9,145.96 212.11,145.96 SB1.BE27 ; v2(216.79,95.76) 216.15,95.12 R2422.1
  BOTTOM w0.102: v2(222.95,142.52) 222.92,142.49 222.92,139.72 221.03,137.83 221.03,134.12 221.62,133.54 221.62,132.52 221.05,131.95 221.05,128.03 218.24,125.22 218.24,118.23 219.04,117.42 219.04,116.67 220.02,115.7 220.02,114.99 220.01,114.99 220.01,108.92 223.9,105.03 223.9,102.21 224.8,101.31 224.8,98.88 224.44,98.52 223.87,98.52 222.12,96.77 v1(218.06,96.77) 217.04,95.76 v2(216.79,95.76)
SP_CTS_N: length 5.1
  TOP w0.102: RN2403.3 196.98,82.12 196.37,82.73 v1(196.32,82.73) 196.32,83.11 196.9,83.69 197.54,83.69 198.4,84.55 U2401.101
SP_DCD_N: length 6.7
  TOP w0.102: RN2402.4 192.47,82.97 193.32,83.82 v1(193.32,84.96) 193.32,85.6 194.59,86.87 U2401.96
SP_DSR_N: length 5.8
  TOP w0.102: U2401.97 195.66,85.32 v1(193.56,83.22) 193.12,82.78 RN2402.3
SP_DTR_N: length 5.6
  TOP w0.102: RN2403.2 197.48,82.45 197.08,82.85 v2(197.08,83.11) 197.08,83.29 197.26,83.46 197.82,83.46 198.8,84.45 U2401.102
  BOTTOM w0.102: v1(196.95,83.9) 197.08,83.77 v2(197.08,83.11)
SP_RI_N: length 4.3
  TOP w0.102: U2401.103 199.2,84.52 197.84,83.16 v1(197.84,82.89) 198.13,82.59 RN2403.1
SP_RTS_N: length 5.6
  TOP w0.102: U2401.99 197.6,84.59 197.16,84.15 196.09,84.15 v1(195.1,83.16) 194.27,82.33 RN2402.1
SP_RXD_N: length 39.2
  TOP w0.102: R6802.1 217.12,102.11 217.09,102.13 v2(217.09,102.11) ; v2(208.43,88.45) 208.43,88.44 208.41,88.42 205.93,88.42 205.37,87.86 198.86,87.86 197.2,86.2 U2401.98 197.2,84.6 196.97,84.38 195.53,84.38 193.62,82.47 RN2402.2
  BOTTOM w0.102: v2(208.43,88.45) 208.48,88.5 v1(208.48,89.71) 208.48,90.12 207.8,90.81 207.8,92.56 208.15,92.91 208.15,94.61 209.55,96.01 209.83,96.01 212.15,98.32 214.68,98.32 217.09,100.74 v2(217.09,102.11)
SP_RXD_N_CON: length 4.1
  TOP w0.102: R6802.2 218.76,101.29 v1(218.86,101.19) 219.81,102.13 221.41,102.13 221.52,102.03 LPC1.14
SP_TXD_N: length 3.8
  TOP w0.102: Q2402.3 195.92,78.73 v2(195.81,78.84) 195.21,79.44 R2473.1 195.21,80.8 R2429.2
  BOTTOM w0.102: v1(195.81,79.6) v2(195.81,78.84)
SP_TXD_N_1: length 2.6
  TOP w0.102: R2405.2 192.43,77.42 v1(192.51,77.34) 192.68,77.52 Q2402.5
SP_TXD_SIO: length 37.5
  TOP w0.102: v2(217.09,102.84) 217.14,102.84 217.42,103.12 R6801.1 ; v2(206.58,87.91) 206.12,87.45 199.09,87.45 198,86.36 U2401.100 198,84.59 197.33,83.92 196.67,83.92 195.3,82.55 R2429.1
  BOTTOM w0.102: v2(217.09,102.84) 216.66,102.41 216.66,100.74 214.6,98.68 211.68,98.68 v1(210.7,97.7) 209.52,96.52 209.09,96.52 206.95,94.37 206.95,90.29 206.58,89.92 v2(206.58,87.91)
SP_TXD_SIO_CON: length 4.6
  TOP w0.102: LPC1.13 222.52,102.6 222,103.12 v1(219.66,103.12) R6801.2
SPEED_100*_CON: length 11.9
  TOP w0.267: R3201.1 132.13,31.12 132.13,29.66 131.81,29.34 130.1,29.34 129.68,28.92 EU3202.4 129.68,26.3 128.22,24.84 RJ45R1.19
SPEED_100_N: length 17.3
  TOP w0.203: v2(137.23,42.95) 137.64,42.54 137.64,42.36 138.06,41.94 U3101.26
  TOP w0.267: R3201.2 130.96,34.24 TP3102.1 131.08,34.36 v2(131.08,35.82)
  BOTTOM w0.267: v2(131.08,35.82) 131.37,36.1 131.37,39.42 132.26,40.31 136.93,40.31 v1(137.36,40.74) 137.82,41.2 137.82,42.37 137.6,42.58 v2(137.23,42.95)
SPEED_1000*_CON: length 9.8
  TOP w0.267: R3202.1 129.68,32.01 EU3202.3 129.68,30.22 RJ45R1.20
SPEED_1000_N: length 17.6
  TOP w0.203: v2(138.08,42.83) 138.48,42.43 U3101.25
  TOP w0.267: R3202.2 129.9,34.29 TP3103.1 129.79,34.55 v2(130.5,35.25)
  BOTTOM w0.267: v2(130.5,35.25) 131.24,35.25 131.88,35.88 131.88,39.33 132.43,39.89 137.6,39.89 138.48,40.77 v1(138.48,41.83) 138.48,42.43 v2(138.08,42.83)
SPI_CLK_PCH: length 65.1
  TOP w0.102: SB1.AW47 208.82,155.71 208.81,155.71 208.59,155.93 208.59,161.4 v1(209.19,162) 210.49,163.3 210.49,165.25 209.88,165.86 209.88,169.17 208.64,170.41 206,170.41 205.47,170.94 v2(205.23,170.94) 204.84,170.94 R9107.1 ; RN2502.7 191.39,189.02 191.39,185.42 192.61,184.2 193.05,184.2 R1515.1 193.87,183.39 198.17,183.39 198.65,183.87 v2(204.6,183.87)
  BOTTOM w0.102: v2(204.6,183.87) 204.7,183.77 v1(204.7,182.85) 204.48,182.64 204.48,176.79 204.59,176.69 205.94,176.69 206.04,176.59 206.04,176.28 205.94,176.18 204.59,176.18 204.48,176.08 204.48,175.78 204.59,175.67 205.94,175.67 206.04,175.57 206.04,175.27 205.94,175.17 204.59,175.17 204.48,175.07 204.48,174.76 204.59,174.66 205.94,174.66 206.04,174.56 206.04,174.25 205.94,174.15 204.59,174.15 204.48,174.05 204.48,173.74 204.59,173.64 205.94,173.64 206.04,173.54 206.04,173.24 205.94,173.13 204.59,173.13 204.48,173.03 204.48,172.45 205.23,171.7 v2(205.23,170.94)
SPI_CLK_ROM1: length 19.6
  TOP w0.102: RN2502.2 191.37,190.01 191.37,190.67 191.11,190.93 191.11,192.91 192.52,194.33 U2502.16 192.52,196.74 v2(192.52,196.75) 192.41,196.85 189.02,196.85 188.91,196.96 188.91,197.24 189.05,197.38 193.17,197.38 193.32,197.54 193.32,199.23 193.22,199.34 SSKT1.6
  BOTTOM w0.102: v2(192.52,196.75) 192.85,197.08 v1(193.05,197.08)
SPI_CLK_TPM: length 3.8
  TOP w0.102: R9107.2 v1(203.58,174.12) 204.04,174.12 205.24,175.32 U9101.19
SPI_CS_PCH_N0: length 81.4
  TOP w0.102: v2(186.99,196.57) 186.99,201.98 185.6,203.38 185.6,204.22 185.47,204.34 U2502.7 184.9,201.91 U2501.1 ; v2(185.33,189.76) 185.34,189.76 185.34,188.77 191.67,182.45 198.56,182.45 199.04,182.93 204.96,182.93 206.13,184.1 211.3,184.1 212.98,182.41 212.98,177.65 211.18,175.84 211.18,173.01 211.46,172.73 211.46,166.55 212.75,165.26 212.75,161.74 209.65,158.65 209.65,158.04 209.16,157.55 209.16,156.43 209.24,156.35 209.24,155.95 209.48,155.71 SB1.AY47
  BOTTOM w0.102: v2(186.99,196.57) v1(186.99,195.02) 186.99,191.42 v2(185.33,189.76)
SPI_CS_PCH_N2: length 26.9
  TOP w0.102: R9108.1 205.5,171.42 205.67,171.42 206.2,170.89 208.32,170.89 R9113.2 208.47,171.36 v2(208.88,171.77) ; v2(206.02,153.4) 206.36,153.06 206.36,152.79 206.97,152.18 SB1.AT40
  BOTTOM w0.102: v2(206.02,153.4) 206.02,154.71 207.06,155.75 207.06,160.45 207.87,161.26 v1(207.87,163.91) 207.87,170.62 208.88,171.62 v2(208.88,171.77)
SPI_HOLD_PCH: length 61.6
  TOP w0.089: 209.56,157.13 209.56,156.61 209.88,156.29 209.88,155.59 SB1.BA46
  TOP w0.102: RN2502.8 191.95,188.94 191.95,185.65 192.89,184.71 200.14,184.71 200.47,184.38 203.99,184.38 204.57,184.38 204.88,184.69 211.53,184.69 212.45,183.77 212.59,183.77 212.94,184.12 213.08,184.12 213.3,183.9 213.3,183.76 212.95,183.41 212.95,183.27 213.17,183.05 213.31,183.05 213.49,182.87 213.49,177.19 212.6,176.3 212.6,175.3 212.7,175.2 213.92,175.2 214.02,175.09 214.02,174.79 213.92,174.69 212.7,174.69 212.6,174.59 212.6,173.58 v1(212.98,173.2) 214.19,172 R2317.1 214.19,166.05 214.82,165.42 R2331.1 214.82,162.65 213.77,161.59 213.44,161.59 210.54,158.7 210.54,158.11 209.56,157.13
SPI_HOLD_ROM1: length 20.9
  TOP w0.102: SSKT1.7 192.4,200.61 193.09,201.29 193.09,202.46 192.84,203.02 192.52,203.34 U2502.1 192.71,204.34 193.23,203.82 193.8,202.51 193.8,197.34 193.53,197.07 v2(193.53,195.01) 193.33,194.37 193,193.81 191.81,192.62 R2502.2 192.04,190.81 RN2502.1
  BOTTOM w0.102: v1(193.29,194.44) 193.29,194.77 v2(193.53,195.01)
SPI_SI_PCH: length 274.2
  TOP w0.102: v2(163.46,49.41) 163,49.87 163,61.47 166.83,65.3 166.83,103.63 170.13,106.93 170.13,109.94 175.01,114.82 175.01,132.24 173.08,134.17 173.08,140.73 171.15,142.66 171.15,147.85 166.98,152.02 166.98,165.78 165.94,166.83 165.94,174.35 166.52,174.93 166.52,178.13 164.92,179.73 v2(164.21,179.73) ; v2(205.35,184.26) 205.35,183.97 204.77,183.39 198.85,183.39 198.37,182.91 193.49,182.91 192.13,182.91 190.73,184.3 v2(190.73,186.08) 190.88,186.24 RN2502.6 ; SB1.AU41 208.12,152.96 208.45,153.29 208.59,153.29 209.12,153.82 v2(209.15,153.82) ; 131.7,62.48 131.34,62.48 v2(130.9,62.04) ; R9106.1 205.87,171.87 v2(206.38,171.37) 207.41,171.37 208.26,172.21 209.3,172.21 210.36,171.14 210.36,166.06 211.01,165.41 R2325.1 R2326.1 211.01,163.83 v2(211.01,163.02)
  BOTTOM w0.102: v2(190.73,186.08) 184.28,179.63 172.85,179.63 172.64,179.43 167.87,179.43 167.62,179.68 164.26,179.68 v2(164.21,179.73) ; v2(205.35,184.26) 205.44,184.18 205.44,183.9 v1(206.61,182.72) 208.13,181.2 208.13,173.99 206.38,172.24 v2(206.38,171.37) ; v2(211.01,163.02) 210.16,162.17 210.16,160.71 209.18,159.73 209.18,154.87 208.94,154.64 208.94,154.04 v2(209.15,153.82) ; v2(163.46,49.41) 163.3,49.41 163.29,49.41 163.03,49.41 161.19,51.26 155.37,51.26 148,58.63 142.34,58.63 140.55,56.84 132.03,56.84 130.92,57.95 130.92,61.99 130.89,62.03 130.89,62.04 v2(130.9,62.04)
SPI_SI_ROM1: length 20
  TOP w0.102: RN2502.3 190.88,190.47 190.63,190.73 190.63,192.61 190.53,192.71 189.84,192.71 189.74,192.81 189.74,193.4 189.87,193.52 190.42,193.52 191.25,194.35 U2502.15 191.25,196.18 191.07,196.37 188.39,196.37 188.19,196.57 v2(188.19,197.21) v1(188.19,197.86) 188.49,198.16 188.49,198.84 188.61,198.96 188.78,198.96 188.9,198.84 188.9,198.16 189.02,198.04 189.19,198.04 189.31,198.16 189.31,198.84 189.42,198.96 189.59,198.96 189.71,198.84 189.71,198.16 189.83,198.04 U2501.5
  BOTTOM w0.102: v1(188.19,197.86) v2(188.19,197.21)
SPI_SI_TPM: length 3
  TOP w0.102: R9106.2 205.87,173.72 v1(206.25,174.1) 206.24,174.11 U9101.21
SPI_SO_PCH: length 65.6
  TOP w0.089: SB1.BA45 209.24,155.51 209.24,155.68 209.05,155.87 209.05,156.27 208.97,156.35 208.97,157.77 209.04,157.85
  TOP w0.102: RN2501.1 183.77,189.71 191.26,182.22 198.65,182.22 199.14,182.7 205.05,182.7 206.22,183.87 211.2,183.87 212.75,182.32 212.75,177.74 v1(210.56,175.54) 209.87,174.85 R9105.1 211.23,172.63 211.23,166.45 211.36,166.32 212.54,165.14 212.54,162.32 212.09,161.86 ; 212.09,161.86 209.04,158.82 209.04,157.85 ; 212.09,161.86 R2328.1
SPI_SO_ROM1: length 19.6
  TOP w0.102: RN2501.4 183.77,191.64 v2(183.12,192.29) 182.32,193.09 182.32,204.14 182.52,204.34 U2502.8 183.63,201.23 184.26,200.61 SSKT1.2
  BOTTOM w0.102: v1(183.12,191.69) v2(183.12,192.29)
SPI_SO_TPM: length 3.3
  TOP w0.102: U9101.24 207.74,175.48 208.98,174.24 R9105.2 v1(208.98,173.05)
SPI_WP_PCH: length 64.5
  TOP w0.089: 209.37,157.2 209.37,156.54 209.48,156.42 SB1.AY48
  TOP w0.102: RN2501.2 186.21,190.23 R2501.2 186.26,188.32 191.9,182.68 193.59,182.68 198.47,182.68 198.95,183.16 204.86,183.16 206.03,184.33 211.39,184.33 213.21,182.51 213.21,177.55 211.86,176.2 v1(211.86,175.06) 211.86,174.65 211.4,174.19 211.4,173.1 211.68,172.82 211.68,166.69 213.72,164.66 R2313.1 R2332.1 213.53,163.64 213.11,163.22 213.11,161.72 210.03,158.65 210.03,157.97 209.37,157.3 209.37,157.2
SPI_WP_ROM1: length 20.7
  TOP w0.102: RN2501.3 185.19,191.43 185.57,191.81 185.57,192.76 v2(185.37,192.96) 184.25,192.96 183.63,193.58 U2502.9 183.63,196.17 183.54,196.27 182.88,196.27 182.7,196.45 182.7,196.65 182.85,196.81 184.2,196.81 184.28,196.88 184.28,197.16 184.16,197.28 182.88,197.28 182.68,197.49 182.68,198.21 182.8,198.33 183.32,198.33 183.44,198.45 183.44,198.62 183.32,198.74 182.8,198.74 182.68,198.85 182.68,200.52 v2(182.88,200.72) 183.17,200.72 183.34,200.56 183.34,199.59 183.59,199.34 SSKT1.3
  BOTTOM w0.102: v2(182.88,200.72) v1(182.88,201.34) ; v2(185.37,192.96) 185.47,192.86 v1(185.47,192.38)
SPKR: length 196.4
  TOP w0.102: SB1.AW29 209.42,147.51 209.42,148.97 208.94,149.45 208.94,149.41 v2(208.92,149.41) ; R2702.2 76.52,224.85 v2(80.64,228.98) ; v2(210.06,164.97) 209.8,165.23 209.14,165.23 208.86,165.51 208.86,166.83 208.74,166.95 208.74,167.02 207.81,167.94 207.63,167.94 R2304.1 R2302.1 206.43,168.12 205.97,168.58 205.97,169.76 205.55,170.18 204.74,170.18 199.15,175.77 193.8,175.77 187.22,182.35 187.22,184.48 174.24,197.46 v2(174.24,209.3)
  BOTTOM w0.102: v2(174.24,209.3) 161.11,209.3 158.1,212.31 132.1,212.31 131.47,212.94 121.4,212.94 119.97,214.38 v1(119.38,214.38) 119.38,214.5 107.06,226.82 107.06,229.44 106.38,230.12 81.79,230.12 v2(80.64,228.98) ; v2(210.06,164.97) 209.65,164.57 209.65,161.26 208.36,159.97 208.36,153.75 207.52,152.91 207.52,150.2 208.19,149.53 208.8,149.53 v2(208.92,149.41)
SSD_PEDET: length 138.3
  TOP w0.102: v2(150.24,127.91) 151.03,128.7 151.03,131.24 152.61,132.82 NGFF2.69 ; v2(169.65,176.66) 170.18,176.12 170.18,174.45 170.71,173.91 170.71,172.77 170.41,172.47 170.41,171.01 171.4,170.02 171.4,169.77 171.4,154.7 175.49,150.61 175.49,144.14 177.19,142.43 177.19,136.14 v2(177.85,135.48) ; v2(192.79,174.93) 192.86,174.85 195.33,174.85 196.7,173.48 199.02,173.48 199.05,173.46 199.33,173.46 202.77,170.02 202.77,168.58 203.23,168.12 R1705.1 203.23,167.23 203.63,166.82 203.63,161.95 204.42,161.16 C1701.1 204.76,161 206.98,158.78 206.98,157.53 206.03,156.57 206.03,155.63 205.72,155.32 SB1.AM46
  BOTTOM w0.102: v2(192.79,174.93) 191.72,176 v1(188.21,176) 170.31,176 v2(169.65,176.66) ; v2(177.85,135.48) 169.49,127.13 150.42,127.13 150.24,127.3 v2(150.24,127.91)
SSD_PEWAKE_N: length 13.5
  TOP w0.102: R6203.1 R6202.1 v1(151.18,139.57) 151.18,132.63 148.86,130.32 NGFF2.54
SUS_ACK_EN_N: length 334.8
  TOP w0.102: Q3801.1 113.74,237.47 R3817.2 113.86,237.55 114.17,237.87 115.09,237.87 115.62,237.34 v2(115.82,237.34) ; v2(211.65,71.06) 211.28,71.42 200.72,71.42 200.59,71.3 197.19,71.3 193.09,75.39 193.09,75.95 191.69,77.35 191.69,83.33 R2419.1 192.74,84.37 192.74,85.67 194.23,87.17 194.23,87.45 194.45,87.67 U2401.94
  BOTTOM w0.102: v2(115.82,237.34) v1(115.82,234.06) 115.82,232.41 120.95,227.28 120.95,223.73 123.93,220.75 128.75,220.75 131.6,217.91 160.15,217.91 162.15,215.9 172.97,215.9 174.98,217.91 214.78,217.91 218.95,213.74 222.2,213.74 223.57,212.37 223.57,208.94 229.36,203.15 229.36,194.89 242.53,181.73 242.53,112.23 240.26,109.96 240.26,105.28 239.67,104.7 233.22,104.7 232.21,103.68 232.21,99.42 228.42,95.64 228.42,88.71 227.15,87.44 226.25,87.44 225.71,87.98 223.54,87.98 222.55,87 220.6,87 219.71,86.11 218.67,86.11 217.73,85.17 217.73,79.98 214.63,76.88 214.63,75.97 212.52,73.86 212.52,71.93 v2(211.65,71.06)
SUS_PWR_ACK: length 201.9
  TOP w0.102: SB1.BE35 212.29,149.56 215.24,149.56 215.88,150.19 215.88,150.54 R2004.1 216.74,151.4 220.1,151.4 220.51,151 v2(221.33,151) ; R3817.1 R3813.2 C3807.1 114.26,234.72 112.81,234.72 R3818.2 R3815.1 111.51,234.44 112.14,233.81 v2(112.9,233.81) ; v2(221.13,209.19) 219.2,207.26 v2(219.2,200.53)
  BOTTOM w0.102: v2(112.9,233.81) 120.19,226.52 v1(120.19,224.79) 120.19,224.06 123.81,220.45 128.63,220.45 131.47,217.6 160.02,217.6 162.03,215.6 173.18,215.6 174.93,217.35 214.05,217.35 221.13,210.26 v2(221.13,209.19) ; v2(219.2,200.53) 218.9,200.23 218.9,189.39 219.23,189.05 219.94,189.05 220.22,188.77 220.22,180.14 219.85,179.77 219.85,176.94 219.66,176.75 219.66,165.13 220.12,164.67 220.12,158.38 220.52,157.98 220.52,157.49 220.42,157.39 220.42,151.9 v2(221.33,151)
SUS_PWR_ACK_5V_DUAL: length 4.4
  TOP w0.102: v1(107.18,234.21) 107.51,234.54 R3816.1 R3807.2 R3812.1 R3808.1
SUS_PWR_ACK_5V_DUAL_L: length 5.7
  TOP w0.102: v2(111,236.98) 111,238.02 110.9,238.12 Q3801.5 108.7,238.12 R3808.2 C3806.1
  BOTTOM w0.102: v2(111,236.98) v1(110.16,236.98)
SUS_PWR_ACK_BJT: length 4.8
  TOP w0.102: Q3801.2 113.6,238.12 R3809.1 114.74,239.27 R3814.2 115.39,239.52 115.8,239.12 v1(115.81,239.12)
SUS_PWR_ACK_BJT_L: length 4.2
  TOP w0.102: R3810.1 R3814.1 v2(113.11,238.78) Q3801.3
  BOTTOM w0.102: v2(113.11,238.78) v1(113.99,238.78)
SUS_PWR_ACK_R: length 3.8
  TOP w0.102: R3811.2 110.49,236.45 110.06,236.88 Q3801.6 ; R3811.2 R3815.2 ; R3811.2 109.84,235.9 v1(109.55,236.19)
SUS_WARNB: length 88.6
  TOP w0.089: SB1.BC37 211.35,151 211.61,150.74 211.61,150.48 211.76,150.34 211.89,150.34 211.9,150.33
  TOP w0.102: R2438.1 191.71,101.28 v2(191.54,101.45) ; v2(215.93,106.81) 215.85,106.73 213.23,106.73 213.11,106.86 210.68,106.86 210.3,107.24 208.89,107.24 207.41,108.72 197.62,108.72 196.7,107.8 195.68,107.8 194.94,107.06 v2(191.87,107.06) ; 211.9,150.33 211.98,150.33 212.16,150.15 212.45,150.15 212.58,150.02 212.58,149.99 214.69,149.99 v2(214.92,150.21) ; v2(217.83,150.9) 217.79,150.94 R2004.2
  BOTTOM w0.102: v2(191.87,107.06) 191.87,103.19 191.54,102.86 v2(191.54,101.45) ; v2(214.92,150.21) 215.29,150.21 v1(215.84,150.77) 216.03,150.96 217.78,150.96 v2(217.83,150.9) 217.86,150.9 218.59,150.17 218.59,148.77 219.25,148.11 219.25,147.75 218.67,147.17 218.67,145.75 217.96,145.03 217.96,137.21 218.24,136.93 218.24,129.97 215.5,127.24 215.5,127.21 215.11,126.82 215.11,116.96 215.76,116.31 215.76,115.38 216.76,114.38 216.76,110.92 216.84,110.85 216.84,110.39 216.76,110.31 216.76,107.65 v2(215.93,106.81)
SUS_WARNB_R: length 4.3
  TOP w0.102: R2438.2 192.6,99.94 192.61,99.92 192.61,99.45 C2412.1 192.6,99.3 v1(193.52,98.37) 193.93,98.37 194.24,98.07 U2401.68
SUSCLK: length 36.6
  TOP w0.102: v2(215.39,184.15) 215.33,184.21 R2030.1 R1822.1 214.31,186.18 R1818.1 ; v2(211.52,154.6) 211.89,154.97 SB1.BE45
  BOTTOM w0.102: v2(215.39,184.15) 215.7,183.85 v1(215.7,183.13) 215.7,182.73 215.8,182.63 215.8,179.81 215.8,179.35 215.04,178.58 215.04,175.97 215.49,175.52 215.49,171.97 213.16,169.64 213.16,165.85 214.17,164.83 214.17,160.98 213.74,160.55 213.5,160.55 211.96,159.02 211.96,155.04 v2(211.52,154.6)
SUSCLK_SIO: length 167.6
  TOP w0.102: v2(198.12,98.76) 198.07,98.76 198.02,98.81 197.61,98.81 197.08,98.27 197.08,97.2 199.82,94.46 208.2,94.46 208.48,94.74 209.3,94.74 209.97,94.06 U2401.19 ; R1818.2 213.6,184.58 212.14,184.58 211.68,185.05 204.74,185.05 204.43,184.74 204.13,184.74 204.13,184.74 200.61,184.74 200.18,185.17 193.5,185.17 v2(193.47,185.19) ; v2(192.94,120.88) 192.76,120.7 188.39,120.7 187.96,121.13 187.51,121.13 187.4,121.03 182.74,121.03 182.74,121.03 180.87,121.03 178.99,122.9 178.99,127.61 178.99,128.01 178.18,128.83 178.18,133.55 176.23,135.5 176.23,142.03 174.29,143.96 174.29,149.22 170.13,153.38 170.13,169.49 169.14,170.48 169.14,176.86 v2(169.88,177.6)
  BOTTOM w0.102: v2(198.12,98.76) 198.12,99.95 199.81,101.64 199.81,104.58 199.09,105.31 199.09,106.36 199.09,106.75 200.13,107.79 200.13,113.02 196.97,116.18 196.61,116.18 194.56,118.23 194.56,119.56 193.25,120.88 v2(192.94,120.88) ; v2(193.47,185.19) 193.47,184.43 v1(193.27,184.23) 193.27,183.87 191.01,181.61 190.04,181.61 185.95,177.52 169.95,177.52 v2(169.88,177.6)
SUSCLK_WIFI: length 21.8
  TOP w0.102: v2(217.07,186.31) 216.94,186.18 R1822.2 ; v2(215.65,200.15) 215.49,200 NGFF1.50
  BOTTOM w0.102: v2(215.65,200.15) 215.65,196.6 v1(215.9,196.34) 216.28,195.96 216.28,193.49 216.66,193.11 216.66,186.72 v2(217.07,186.31)
SYS_FAN2_TACH_SIO: length 9.5
  TOP w0.102: v2(207.14,102.62) 207.14,102.22 206.8,101.88 U2401.39 ; v2(210.73,105.03) 212.03,105.03 R2462.1
  BOTTOM w0.102: v2(210.73,105.03) 208.91,105.03 v1(208.52,104.63) 207.14,103.25 v2(207.14,102.62)
SYS_FAN_CTRL_CONN: length 9.3
  TOP w0.102: R2614.2 80.84,10.35 D2602.A 80.26,10.41 R2616.2 81.28,8.32 FANS1.4
SYS_FAN_CTRL_SIO: length 220.7
  TOP w0.102: R2614.1 82.17,12.95 80.9,14.22 80.21,14.22 78.49,15.95 v2(78.49,20.22) ; U2401.48 203.2,99.31 201.47,97.59 v2(200.38,97.59)
  BOTTOM w0.102: v2(78.49,20.22) 84.2,20.22 84.89,20.9 85.8,20.9 86,20.71 89.02,20.71 89.42,21.11 98.86,21.11 v1(99.46,21.71) 100,22.25 111.55,22.25 113.68,24.38 119.16,24.38 120.11,23.43 138.49,23.43 138.84,23.09 145.35,23.09 150.7,17.73 150.71,17.73 175.42,17.73 176.25,16.9 186.41,16.9 192.51,23 192.51,47.59 194.33,49.42 194.54,49.62 194.54,55.95 194.54,56.9 194.54,58.34 195.05,58.85 195.05,60.89 194.84,61.09 194.84,63.3 194.49,63.66 194.49,68.43 195.7,69.65 198.98,69.65 202.82,73.49 202.82,74.78 201.91,75.69 201.91,79.46 201.9,79.47 201.9,79.68 199.96,81.63 199.96,83.23 199.5,83.68 199.5,97.19 199.91,97.59 v2(200.38,97.59)
SYS_FAN_TACH_1: length 6.6
  TOP w0.102: FANS1.3 83.82,8.32 R2618.1 87,10.22
SYS_FAN_TACH_SIO: length 241.8
  TOP w0.102: v2(91.57,19.74) 91.57,14.89 88.77,12.09 85.89,12.09 R2617.1 R2618.2 ; v2(211.46,104.39) 211.58,104.27 R2476.1 212,103.35 211.23,103.35 209.98,102.11 207.78,102.11 207.2,101.53 U2401.38
  BOTTOM w0.102: v2(211.46,104.39) 210.27,103.21 210.27,103 209.84,102.57 209.82,102.57 208.03,100.78 205.71,100.78 201.87,96.94 201.87,85.01 203.02,83.85 203.02,82.35 204.37,81 204.37,79.02 205.38,78 205.38,74.58 205.51,74.45 205.51,72.84 199.96,67.28 199.12,67.28 197.97,66.14 197.97,66.01 197.97,62.92 197.41,62.36 197.41,57.87 196.9,57.36 196.9,48.4 194.87,46.37 194.87,21.98 186.52,13.64 175.72,13.64 173.99,15.37 163.82,15.37 163.31,15.37 163.05,15.32 160.74,15.32 152.01,6.58 149.08,6.58 146.64,4.14 119.61,4.14 118.87,4.87 118.87,16.06 117.78,17.16 114.23,17.16 111.64,19.74 108.23,19.74 107.87,19.38 106.37,19.38 106.02,19.74 v1(104.72,19.74) 103.09,19.74 103.05,19.7 102.53,19.7 102.49,19.74 v2(91.57,19.74)
SYS_THERMDA+: length 83
  TOP w0.127: Q2409.E 152.59,116.45 C2427.1 152.4,115.13 152.4,111.41 v2(152.67,111.14) ; v2(179.94,105.75) 180.12,105.57 180.38,105.57 181.64,106.83 183.36,106.83 183.82,106.38 195.14,106.38 195.94,107.18 196.95,107.18 197.88,108.1 207.15,108.1 208.64,106.62 210.04,106.62 210.42,106.23 211.17,106.23 Q2403.B 210.6,105.85 210.19,105.44 210.19,104.72 210.57,104.34 Q2403.C 210.3,103.95 209.72,104.53 208.89,104.53 208.71,104.71 C2403.1 207.52,104.2 C2402.1 206.81,104.2 205.14,102.53 205.14,101.85 205.2,101.79 U2401.43
  BOTTOM w0.127: 164.06,106.3 178.19,106.3 178.99,105.5 179.69,105.5 v2(179.94,105.75) ; 164.06,106.3 155.96,106.3 152.33,109.93 152.33,110.8 v2(152.67,111.14) ; 164.06,106.3 v1(164.06,106.65)
SYS_THERMDA-: length 80.4
  TOP w0.127: U2401.44 204.8,101.79 204.86,101.85 204.86,102.65 206.59,104.38 206.59,104.57 207.09,105.07 C2402.2 207.52,105.09 C2403.2 209.33,105.6 Q2403.E 209.16,106.27 209.14,106.27 209.08,106.34 208.52,106.34 207.03,107.82 198,107.82 197.07,106.9 196.05,106.9 195.25,106.1 183.7,106.1 183.25,106.55 181.75,106.55 180.49,105.29 180.24,105.29 v2(179.96,105.02) ; Q2409.C 151.07,117.82 Q2409.B 151.7,116.27 C2427.2 152.12,114.9 152.12,111.48 v2(151.79,111.14)
  BOTTOM w0.127: 166.37,106.02 155.84,106.02 152.05,109.81 152.05,110.88 v2(151.79,111.14) ; 166.37,106.02 178.07,106.02 178.87,105.22 179.77,105.22 179.96,105.03 v2(179.96,105.02) ; 166.37,106.02 v1(166.37,105.66)
TEST_EN: length 3.7
  TOP w0.102: R9507.1 214.35,60.55 v1(214.25,60.45) 214.09,60.29 U9501.90
TH_SET: length 6.2
  TOP w0.254: v1(108.15,61.49) 107.15,62.5 R2611.1 107.34,62.83 107.34,64.85 108.47,65.97 U2601.1
THERMTRIP#_CPU: length 179.6
  TOP w0.102: v2(164.59,60.83) 165.02,60.83 167.92,63.73 167.92,103.25 171.12,106.45 171.12,109.53 176.98,115.39 190.56,115.39 191.57,116.39 191.57,116.61 193.34,118.39 194.77,119.81 194.77,119.96 195.64,120.83 196.9,120.83 198.06,121.98 R1703.1 198.18,122.94 R1710.2 ; v2(131.44,78.99) 131.44,79.12 v1(129.36,81.2) 125.96,84.61 109.31,84.61 105.9,88.01 99.45,88.01 97.98,89.48 97.71,89.48 96.52,90.68 91.91,90.68 88.63,93.96 88.63,95.79 CPU1.D11
  BOTTOM w0.102: v2(131.44,78.99) 132.13,78.31 149.54,78.31 154.38,73.46 154.38,71.04 v2(164.59,60.83)
THERMTRIP#_PCH: length 12.3
  TOP w0.102: R1710.1 199.57,123.83 201.22,125.47 201.22,129.49 v1(200.77,129.95) 200.77,131.76 201.93,132.92 201.93,133.97 SB1.AD3
TMIN_SHIFT: length 16.3
  TOP w0.102: R2306.2 220.61,107.53 219.94,106.86 219.94,105.07 v1(219.37,104.5) 219.08,104.2 R2446.2 R2431.1 215.35,102.77 212.58,102.77 212.27,102.46 211.54,102.46 209.9,100.81 U2401.33
TMIN_SHIFT_PCH: length 52.9
  TOP w0.089: 213.38,148.65 212.88,148.65 212.7,148.83 211.85,148.83 211.66,149.02 SB1.BD33
  TOP w0.102: R2306.1 219.28,108.58 219.27,108.6 219.14,108.6 219.13,108.58 218.68,108.58 R2309.1 R2307.1 217.03,108.6 216.5,109.13 v2(216.29,109.13) ; 213.38,148.65 213.48,148.74 215.14,148.74 215.98,147.9 218.77,147.9 v2(218.8,147.93)
  BOTTOM w0.102: v2(218.8,147.93) 218.44,147.57 218.44,145.8 217.75,145.12 217.75,137.12 218.03,136.84 218.03,130.15 215.22,127.34 215.22,127.31 215.22,127.25 214.88,126.92 214.88,116.86 215.53,116.22 215.53,115.29 216.51,114.31 216.51,111.6 216.28,111.37 v1(216.28,110.62) 216.28,109.13 v2(216.29,109.13)
TP0: length 3.2
  TOP w0.102: RN9502.2 206.83,66.35 v1(207.19,65.99) 207.65,65.53 U9501.105
TP1: length 4.1
  TOP w0.102: U9501.109 206.05,65.22 205.01,66.26 v1(204.56,66.26) 204.34,66.48 RN9505.3
TP_CPU1_AB35: length 33.3
  TOP w0.089: CPU1.AB35 63.58,114.07 63.07,114.07 62.67,114.47 62.67,114.58 62.26,114.98 61.5,114.98 61.49,114.98
  TOP w0.102: 61.49,114.98 59.21,114.98 59.05,114.83 58.44,114.83 55.28,111.67 43.76,111.67 36.31,119.13 TP902.1
TP_CPU1_AB37: length 1.7
  TOP w0.102: v2(62.59,113.22) 62.11,113.69 CPU1.AB37
  BOTTOM w0.102: v2(62.59,113.22) 62.59,112.35 TP904.1
TP_CPU1_AB38: length 2.5
  TOP w0.102: CPU1.AB38 v2(60.74,113.25)
  BOTTOM w0.102: TP905.1 60.99,111.87 60.99,112.87 60.74,113.12 v2(60.74,113.25)
TP_CPU1_AC37: length 1.5
  TOP w0.102: CPU1.AC37 62.09,114.62 61.65,114.18 v2(61.65,114.13)
  BOTTOM w0.102: TP901.1 61.68,114.11 v2(61.65,114.13)
TP_CPU1_AJ22: length 1.9
  TOP w0.102: v2(76.02,119.08) 75.83,119.27 CPU1.AJ22
  BOTTOM w0.102: TP906.1 75.41,119.08 v2(76.02,119.08)
TP_CPU1_D15: length 5.9
  TOP w0.102: v2(84.96,91.57) 84.96,95.8 CPU1.D15
  BOTTOM w0.102: TP907.1 84.96,91.19 v2(84.96,91.57)
TP_CPU1_L8: length 1.5
  TOP w0.102: v2(91.29,102.28) CPU1.L8
  BOTTOM w0.102: TP903.1 91.31,102.25 v2(91.29,102.28)
TP_DIMM1_PIN1: length 2.8
  TOP w0.102: DIMM1.1 18.61,165.67 R1102.1
TP_DIMM1_PIN145: length 6.9
  TOP w0.102: DIMM1.145 20.05,170.93 17.72,168.59 R1102.2
TP_DIMM2_PIN1: length 9.7
  TOP w0.102: DIMM2.1 19.37,176.79 19.37,184.03 R1202.1
TP_DIMM2_PIN145: length 4.5
  TOP w0.102: R1202.2 20.43,184.21 20.06,183.84 DIMM2.145
TP_PCH_AH14: length 1.5
  TOP w0.102: SB1.AH14 204.3,139.44 v2(204.36,139.5)
  BOTTOM w0.102: v2(204.36,139.5) 204.16,139.29 TP2202.1
TP_PCH_AH15: length 1.6
  TOP w0.102: v2(204.36,140.16) 203.77,140.16 SB1.AH15
  BOTTOM w0.102: TP2201.1 203.94,140.16 v2(204.36,140.16)
TP_RSVD3_BC1: length 3.8
  TOP w0.102: v2(213.61,131.7) 212.71,131.7 211.23,133.19 SB1.BC1
  BOTTOM w0.102: v2(213.61,131.7) 213.64,131.7 TP1506.1
TP_SLP_LAN_N: length 14.2
  TOP w0.102: R2054.1 223.95,156.16 TP2001.1 222.16,154.37 220.57,154.37 219.25,153.06 214.3,153.06 213.64,152.39 213.12,152.39 212.88,152.14 212.32,152.14 SB1.BF40
TP_VCCPHY_SENSE: length 6.3
  TOP w0.102: SB1.K47 194.81,155.74 194.81,159.13 193.17,160.78 TP2101.1
TP_VSS_AL37: length 2.4
  TOP w0.102: SB1.AL37 204.69,150.66 204.39,150.96 204.39,151.83 v2(204.41,151.85)
  BOTTOM w0.102: TP1501.1 204.42,151.84 v2(204.41,151.85)
TP_VSSPHY_SENSE: length 6
  TOP w0.102: TP2102.1 195.02,159.95 195.02,155.94 195.17,155.79 195.17,155.23 SB1.K46
TPEV_CFG_RCOMP: length 4.4
  TOP w0.305: R418.1 85.14,106.57 87.13,104.58 87.16,104.58 CPU1.M11
TPM_CS: length 3.3
  TOP w0.102: R9108.2 204.72,173.99 v1(204.95,174.22) 205.74,175.01 U9101.20
TPM_PIRQ: length 19.8
  TOP w0.102: U9101.18 204.74,175.51 204.48,175.25 200.03,175.25 198.8,176.48 193.95,176.48 v2(193.7,176.73) ; v2(193.73,170.43) 194.15,169.99 R9112.1
  BOTTOM w0.102: v2(193.7,176.73) 194.03,176.4 194.03,171.78 v1(193.62,171.37) 193.62,170.51 193.73,170.41 v2(193.73,170.43)
TPM_PP: length 1.9
  TOP w0.102: TP9106.1 206.24,182.11 U9101.4
TPM_RST_R: length 45.1
  TOP w0.102: U9101.17 203.87,175.51 202.31,175.51 201.73,176.1 R9110.2 R9111.2 195.29,177.08 v1(192.44,179.92) 191.95,180.42 191.79,180.42 179.04,193.17 Q9101.S
TPM_VDD_P8: length 29.2
  TOP w0.305: U9101.22 206.74,174.74 206.91,174.57 206.91,173.06 C9103.1 ; 202.7,180.99 U9101.8
  TOP w0.508: C9102.1 202.5,180.78 202.7,180.99 ; C9102.1 201.42,181.36 202.06,181.99 v2(205.23,181.99) 205.23,182.25 206.38,183.39 208.03,183.39 R9104.2 ; C9102.1 200.85,180.78 C9101.1 199.52,181.48 R9101.2 ; C9103.1 207.14,173.04 207.65,173.55 v2(207.65,174.12)
  BOTTOM w0.508: v2(207.65,174.12) 207.25,174.12 206.76,174.62 206.76,175.14 207.7,176.08 207.7,180.29 v1(206.81,181.18) 205.99,181.99 v2(205.23,181.99)
TRST_N: length 4
  TOP w0.203: U2401.124 207.6,84.38 208.24,83.73
  TOP w0.508: 208.24,83.73 208.24,83.67 208.89,83.02 v1(208.89,82.78) R2450.2
TS_CRIT#: length 88.2
  TOP w0.102: U2602.2 90.14,16.26 90.22,16.18 90.22,15.09 v1(89.36,14.22) 89.18,14.05 R2613.2 88.38,13.26 87.82,12.7 87.44,12.7 82.09,18.05 82.09,25.27 82.12,25.3 82.12,25.48 84.43,27.79 86.33,27.79 88.8,30.25 93.93,30.25 v2(96.8,33.12) ; U2601.3 v2(106.57,68.02)
  BOTTOM w0.102: v2(106.57,68.02) 106.57,66.48 107.16,65.89 107.16,61.37 109.65,58.88 109.65,49.3 108.76,48.41 108.76,34.46 107.42,33.12 v2(96.8,33.12)
U1.1: length 3.1
  TOP w0.305: U3301.1 37.97,229.79 v1(37.97,229.62) R3302.1
U1.6: length 3.8
  TOP w0.305: U3301.6 43.88,231.08 v1(44.07,230.89) 45.28,230.89 C3304.1
U1.15: length 3.1
  TOP w0.102: R3301.2 39.94,237.17 v1(40.39,236.73) 40.76,236.35 U3301.15
U1.24: length 4
  TOP w0.305: C3303.1 v1(36.96,230.46) U3301.24
UART0_RX: length 4.5
  TOP w0.102: v2(214.2,142.01) 214.2,142.78 213.69,143.29 213.69,143.31 213.24,143.75 212.71,143.75 212.54,143.58 212.14,143.58 211.91,143.81 SB1.BE23
  BOTTOM w0.102: v2(214.2,142.01) 214.73,141.48 TP1505.1
UART0_TX: length 6.1
  TOP w0.102: v2(213.62,142.44) 213.62,143.07 213.48,143.2 213.48,143.23 213.16,143.55 212.79,143.55 212.62,143.38 211.79,143.38 210.74,144.42 SB1.BB24
  BOTTOM w0.102: TP1504.1 213.08,143.51 213.62,142.97 v2(213.62,142.44)
UART_BT_WAKE_N: length 78.2
  TOP w0.089: SB1.BE32 211.98,148.39 212.22,148.15 212.53,148.15 212.66,148.02 213.46,148.02 213.46,148.03
  TOP w0.102: 213.46,148.03 214.61,148.03 214.86,148.03 215.7,147.19 215.7,146.9 216.14,146.46 218.27,146.46 R2007.1 218.94,145.8 220.83,145.8 221.21,145.41 224,145.41 226.13,147.54 v2(226.79,147.54) ; NGFF1.20 210.14,192.5 211.18,191.47 217.73,191.47 v1(218.01,191.74) 218.29,191.47 v2(221.69,191.47)
  BOTTOM w0.102: v2(221.69,191.47) 222.3,191.47 225.58,188.19 225.58,179.34 225.58,170.11 223.7,168.23 223.7,159.97 226.34,157.33 226.34,150.05 226.51,149.89 226.51,147.83 v2(226.79,147.54)
USB2_COMP: length 6.9
  TOP w0.127: R1609.1 190.07,129.77 v2(190.72,130.42) 191.34,131.04 191.34,131.47 192.8,132.93 192.8,133.36 192.68,133.48 192.68,134.07 SB1.F4
  BOTTOM w0.127: v1(190.89,129.41) 190.89,130.23 190.72,130.4 v2(190.72,130.42)
USB2_ID: length 6.5
  TOP w0.102: R1611.1 191.31,129.84 191.31,130.58 191.82,131.09 v2(191.82,131.27) 193.12,132.57 193.12,133.35 192.89,133.57 192.89,133.98 SB1.G3
  BOTTOM w0.102: v2(191.82,131.27) 191.82,131.23 191.96,131.09 v1(192.61,131.09)
USB2_VBUSSENSE: length 6.6
  TOP w0.102: SB1.F3 192.39,133.47 192.58,133.27 192.58,133.02 v2(190.78,131.22) 189.18,129.62 R1610.1
  BOTTOM w0.102: v2(190.78,131.22) 191.46,130.54 v1(191.47,130.54)
USB30_RX_CON_N1: length 16
  TOP w0.102: R3804.4 92.76,236.17 92.98,236.39 92.98,236.95 93.36,237.33 93.36,237.73 93.23,237.85 EU3801.1 EU3801.10 93.23,239.67 93.37,239.8 93.37,240.34 92.75,240.96 86.52,240.96 85.09,242.39 85.09,243.58 84.88,243.8 USB3F1.5
USB30_RX_CON_N2: length 9.8
  TOP w0.102: R3806.4 103.05,236.27 103.27,236.49 103.27,237 103.78,237.51 103.78,237.83 103.65,237.96 EU3802.1 EU3802.10 103.65,239.77 103.78,239.9 103.78,240.71 105.89,242.82 105.89,243.66 105.75,243.8 USB3F2.5
USB30_RX_CON_P1: length 16
  TOP w0.102: R3804.3 93.42,236.17 93.2,236.39 93.2,236.86 93.57,237.24 93.57,237.72 93.71,237.86 EU3801.2 EU3801.9 93.71,239.67 93.58,239.8 93.58,240.43 92.84,241.17 86.61,241.17 85.31,242.48 85.31,243.55 85.56,243.8 USB3F1.6
USB30_RX_CON_P2: length 9.8
  TOP w0.102: USB3F2.6 106.25,243.8 106.11,243.66 106.11,242.73 104,240.62 104,239.9 104.13,239.77 EU3802.9 EU3802.2 104.13,237.93 104,237.8 104,237.42 103.49,236.91 103.49,236.52 103.71,236.3 R3806.3
USB30_RX_PCH_N1: length 170.6
  TOP w0.089: SB1.D11 191.89,138.33 191.76,138.46 191.44,138.46 191.28,138.3 190.87,138.3 190.49,137.93 189.27,137.93 189.26,137.93
  TOP w0.102: v2(166.85,191.52) 167.17,191.84 167.17,192.22 167.51,192.56 172.87,192.56 174.24,191.19 174.24,188.21 178.71,183.75 178.71,163.12 180.56,161.28 180.56,156.41 183.32,153.64 183.32,151.45 184.18,150.6 184.18,145.59 185.14,144.63 185.14,140.54 187.74,137.93 189.26,137.93 ; R3804.1 92.76,233.55 92.98,233.33 92.98,230.47 92.66,230.15 v2(92.66,229.36)
  BOTTOM w0.102: 166.66,195.24 167.12,194.78 167.12,191.79 v2(166.85,191.52) ; 166.66,195.24 v1(166.4,194.97) ; 166.66,195.24 155.52,206.38 114.94,206.38 92.98,228.33 92.98,229.04 v2(92.66,229.36)
USB30_RX_PCH_N2: length 163.6
  TOP w0.102: SB1.B9 190.88,137.22 190.72,137.38 189.77,137.38 189.45,137.06 187.63,137.06 184.43,140.26 184.43,144.35 183.48,145.3 183.48,150.31 182.63,151.16 182.63,153.35 179.86,156.12 179.86,160.94 178.01,162.78 178.01,183.43 173.48,187.96 173.48,190.88 172.5,191.86 171.61,191.86 171.36,191.61 171.36,191.2 v2(171.04,190.88) ; R3806.1 103.05,234.26 103.17,234.14 103.37,234.14 103.49,234.01 103.49,233.69 103.27,233.47 103.27,229.43 v2(102.95,229.11)
  BOTTOM w0.102: 171.03,196.38 157.11,210.3 116.98,210.3 103.27,224.01 103.27,228.78 v2(102.95,229.11) ; 171.03,196.38 v1(170.76,196.11) ; 171.03,196.38 171.36,196.05 171.36,191.2 v2(171.04,190.88)
USB30_RX_PCH_P1: length 170.5
  TOP w0.089: SB1.C11 191.49,138.24 191.36,138.11 190.94,138.11 190.57,137.74 189.29,137.74 189.27,137.72 189.26,137.72
  TOP w0.102: v2(93.52,229.36) 93.52,229.62 93.4,229.74 92.99,229.74 92.88,229.86 92.88,230.06 93.2,230.38 93.2,233.42 92.98,233.64 92.98,233.97 93.11,234.1 93.31,234.1 93.42,234.21 R3804.2 ; v2(167.71,191.52) 167.39,191.84 167.39,192.13 167.6,192.34 172.78,192.34 174.03,191.1 174.03,188.12 178.49,183.66 178.49,163.03 180.34,161.19 180.34,156.32 183.11,153.55 183.11,151.36 183.96,150.51 183.96,145.5 184.92,144.54 184.92,140.45 187.65,137.72 189.26,137.72
  BOTTOM w0.102: v2(167.71,191.52) 167.34,191.89 167.34,194.87 165.58,196.62 ; v2(93.52,229.36) 93.2,229.04 93.2,228.42 115.02,206.59 155.61,206.59 165.58,196.62 ; 165.58,196.62 v1(165.86,196.9)
USB30_RX_PCH_P2: length 163.5
  TOP w0.102: R3806.2 103.71,233.6 103.49,233.38 103.49,229.43 v2(103.81,229.11) ; SB1.C9 191.47,137.22 191.24,136.98 190.8,136.98 190.63,137.16 189.86,137.16 189.54,136.84 187.54,136.84 184.21,140.17 184.21,144.26 183.26,145.21 183.26,150.22 182.41,151.07 182.41,153.26 179.64,156.03 179.64,160.85 177.8,162.69 177.8,183.34 173.27,187.87 173.27,190.79 172.41,191.64 171.7,191.64 171.58,191.52 171.58,191.2 v2(171.9,190.88)
  BOTTOM w0.102: 104.12,223.47 117.07,210.52 157.2,210.52 171.58,196.14 171.58,191.2 v2(171.9,190.88) ; 104.12,223.47 103.49,224.1 103.49,228.78 v2(103.81,229.11) ; 104.12,223.47 v1(104.38,223.74)
USB30_TX_CMC_N1: length 4
  TOP w0.102: 95.33,232.36 95.33,234.13 95.05,234.42 R3801.1 ; 95.33,232.36 v1(94.95,232.36) ; 95.33,232.36 95.33,231.67 C3802.2
USB30_TX_CMC_N2: length 4
  TOP w0.102: 105.59,232.46 105.59,234.31 105.33,234.57 R3802.1 ; 105.59,232.46 v1(105.21,232.46) ; 105.59,232.46 105.59,231.74 C3804.2
USB30_TX_CMC_P1: length 4
  TOP w0.102: 95.55,233.35 95.55,231.67 C3801.2 ; 95.55,233.35 95.55,234.13 95.71,234.29 R3801.2 ; 95.55,233.35 v1(95.94,233.35)
USB30_TX_CMC_P2: length 4
  TOP w0.102: 105.81,233.43 105.81,234.39 105.99,234.57 R3802.2 ; 105.81,233.43 105.81,231.79 C3803.2 ; 105.81,233.43 v1(106.18,233.43)
USB30_TX_CON_N1: length 11.7
  TOP w0.102: USB3F1.8 90.85,243.8 91.09,243.55 91.09,242.36 91.48,241.97 93.51,241.97 94.89,240.6 94.89,239.8 94.75,239.67 EU3801.7 EU3801.4 94.75,237.81 94.89,237.68 94.89,237.17 95.27,236.78 95.27,236.42 95.05,236.19 R3801.4
USB30_TX_CON_N2: length 14.3
  TOP w0.102: USB3F2.8 111.67,243.8 111.89,243.58 111.89,242.47 111.18,241.76 106.45,241.76 105.3,240.61 105.3,239.9 105.17,239.77 EU3802.7 EU3802.4 105.17,237.96 105.3,237.83 105.3,237.24 105.54,237.01 105.54,236.47 105.33,236.27 R3802.4
USB30_TX_CON_P1: length 11.7
  TOP w0.102: USB3F1.9 91.53,243.8 91.31,243.58 91.31,242.45 91.57,242.19 93.6,242.19 95.1,240.69 95.1,239.8 95.23,239.67 EU3801.6 EU3801.5 95.23,237.8 95.1,237.67 95.1,237.26 95.48,236.87 95.48,236.42 95.71,236.19 R3801.3
USB30_TX_CON_P2: length 14.3
  TOP w0.102: R3802.3 105.99,236.3 105.75,236.54 105.75,237.1 105.52,237.33 105.52,237.82 105.65,237.96 EU3802.5 EU3802.6 105.65,239.77 105.52,239.9 105.52,240.52 106.54,241.54 111.27,241.54 112.11,242.38 112.11,243.55 112.35,243.8 USB3F2.9
USB30_TX_PCH_N1: length 179.2
  TOP w0.102: C3802.1 95.33,230.1 95.33,229.69 v2(95.01,229.36) ; v2(193.43,137.16) 193.24,136.98 SB1.F9 ; v2(181.91,132.54) 181.69,132.77 181.36,132.77 181.01,133.11 181.01,135.58 179.54,137.05 179.54,143 179.07,143.47 179.07,147.25 178.18,148.14 178.18,151.46 175.44,154.21 175.44,158.94 173.55,160.83 173.55,177.84 161.26,190.12 161.26,195.05 159.73,196.58 159.73,199.28 160.6,200.15 162.55,200.15 162.73,200.33 162.73,200.6 v2(162.41,200.91)
  BOTTOM w0.102: v2(193.43,137.16) 192.61,137.16 192.29,136.84 190.89,136.84 189.65,135.6 185.74,135.6 185.05,134.91 181.6,134.91 181.03,134.34 181.03,133.04 181.35,132.72 181.74,132.72 v2(181.91,132.54) ; v2(95.01,229.36) 95.33,229.04 95.33,227.63 115.89,207.07 156.52,207.07 158.57,205.03 ; v2(162.41,200.91) 162.56,201.07 162.56,201.67 162.13,202.11 161.49,202.11 158.57,205.03 ; v1(158.31,204.76) 158.57,205.03
USB30_TX_PCH_N2: length 176.6
  TOP w0.102: SB1.C3 191.89,134.14 v2(192.01,134.02) ; v2(168.21,200.66) 168.53,200.34 168.53,199.9 167.89,199.26 160.86,199.26 160.46,198.87 160.46,196.86 161.96,195.36 161.96,190.41 174.26,178.12 174.26,161.11 176.14,159.23 176.14,154.5 178.88,151.75 178.88,148.5 179.77,147.61 179.77,143.76 180.24,143.29 180.24,137.36 182.41,135.19 182.41,133.11 182.66,132.85 182.88,132.85 v2(183.24,132.49) ; C3804.1 105.62,230.21 105.62,229.66 v2(105.3,229.34)
  BOTTOM w0.102: v2(168.21,200.66) 168.53,200.98 168.53,201.62 164.69,205.46 ; v2(105.3,229.34) 105.62,229.01 105.62,222.88 117.5,211 157.56,211 161.89,206.67 163.49,206.67 164.69,205.46 ; v1(164.43,205.19) 164.69,205.46 ; v2(192.01,134.02) 190.76,134.02 190.6,133.86 186.28,133.86 185.63,133.21 185.24,132.82 183.56,132.82 v2(183.24,132.49)
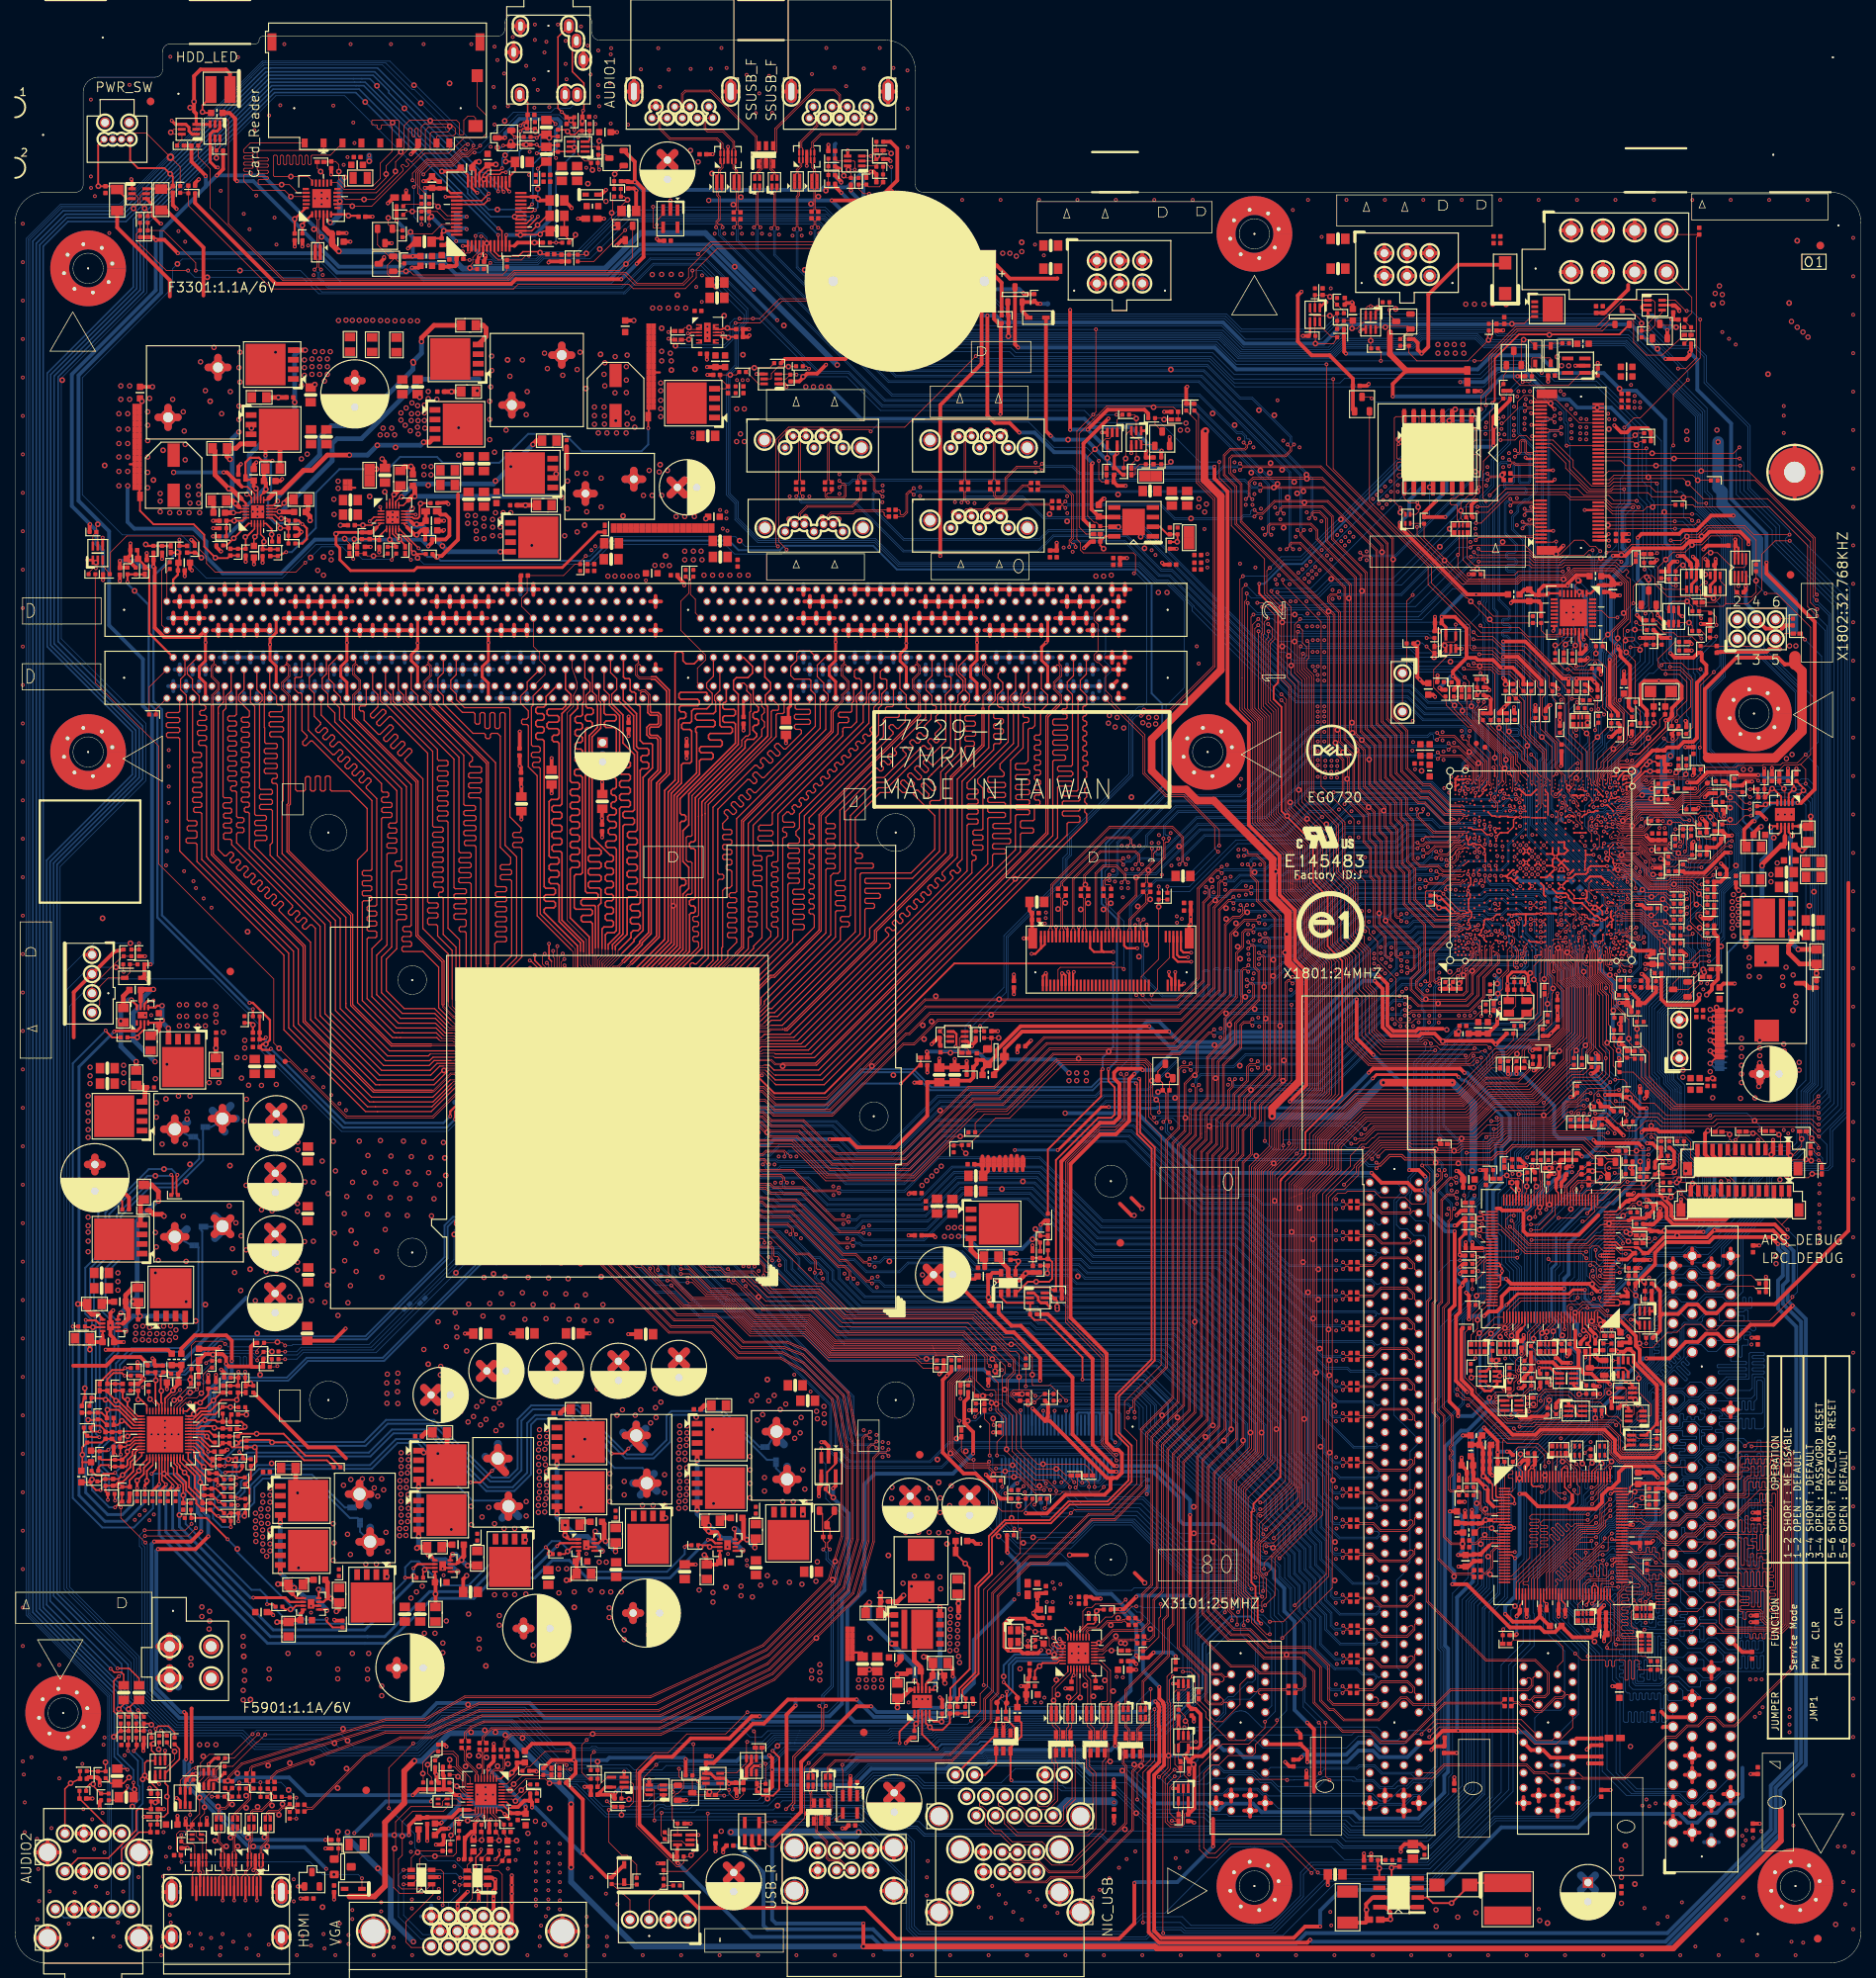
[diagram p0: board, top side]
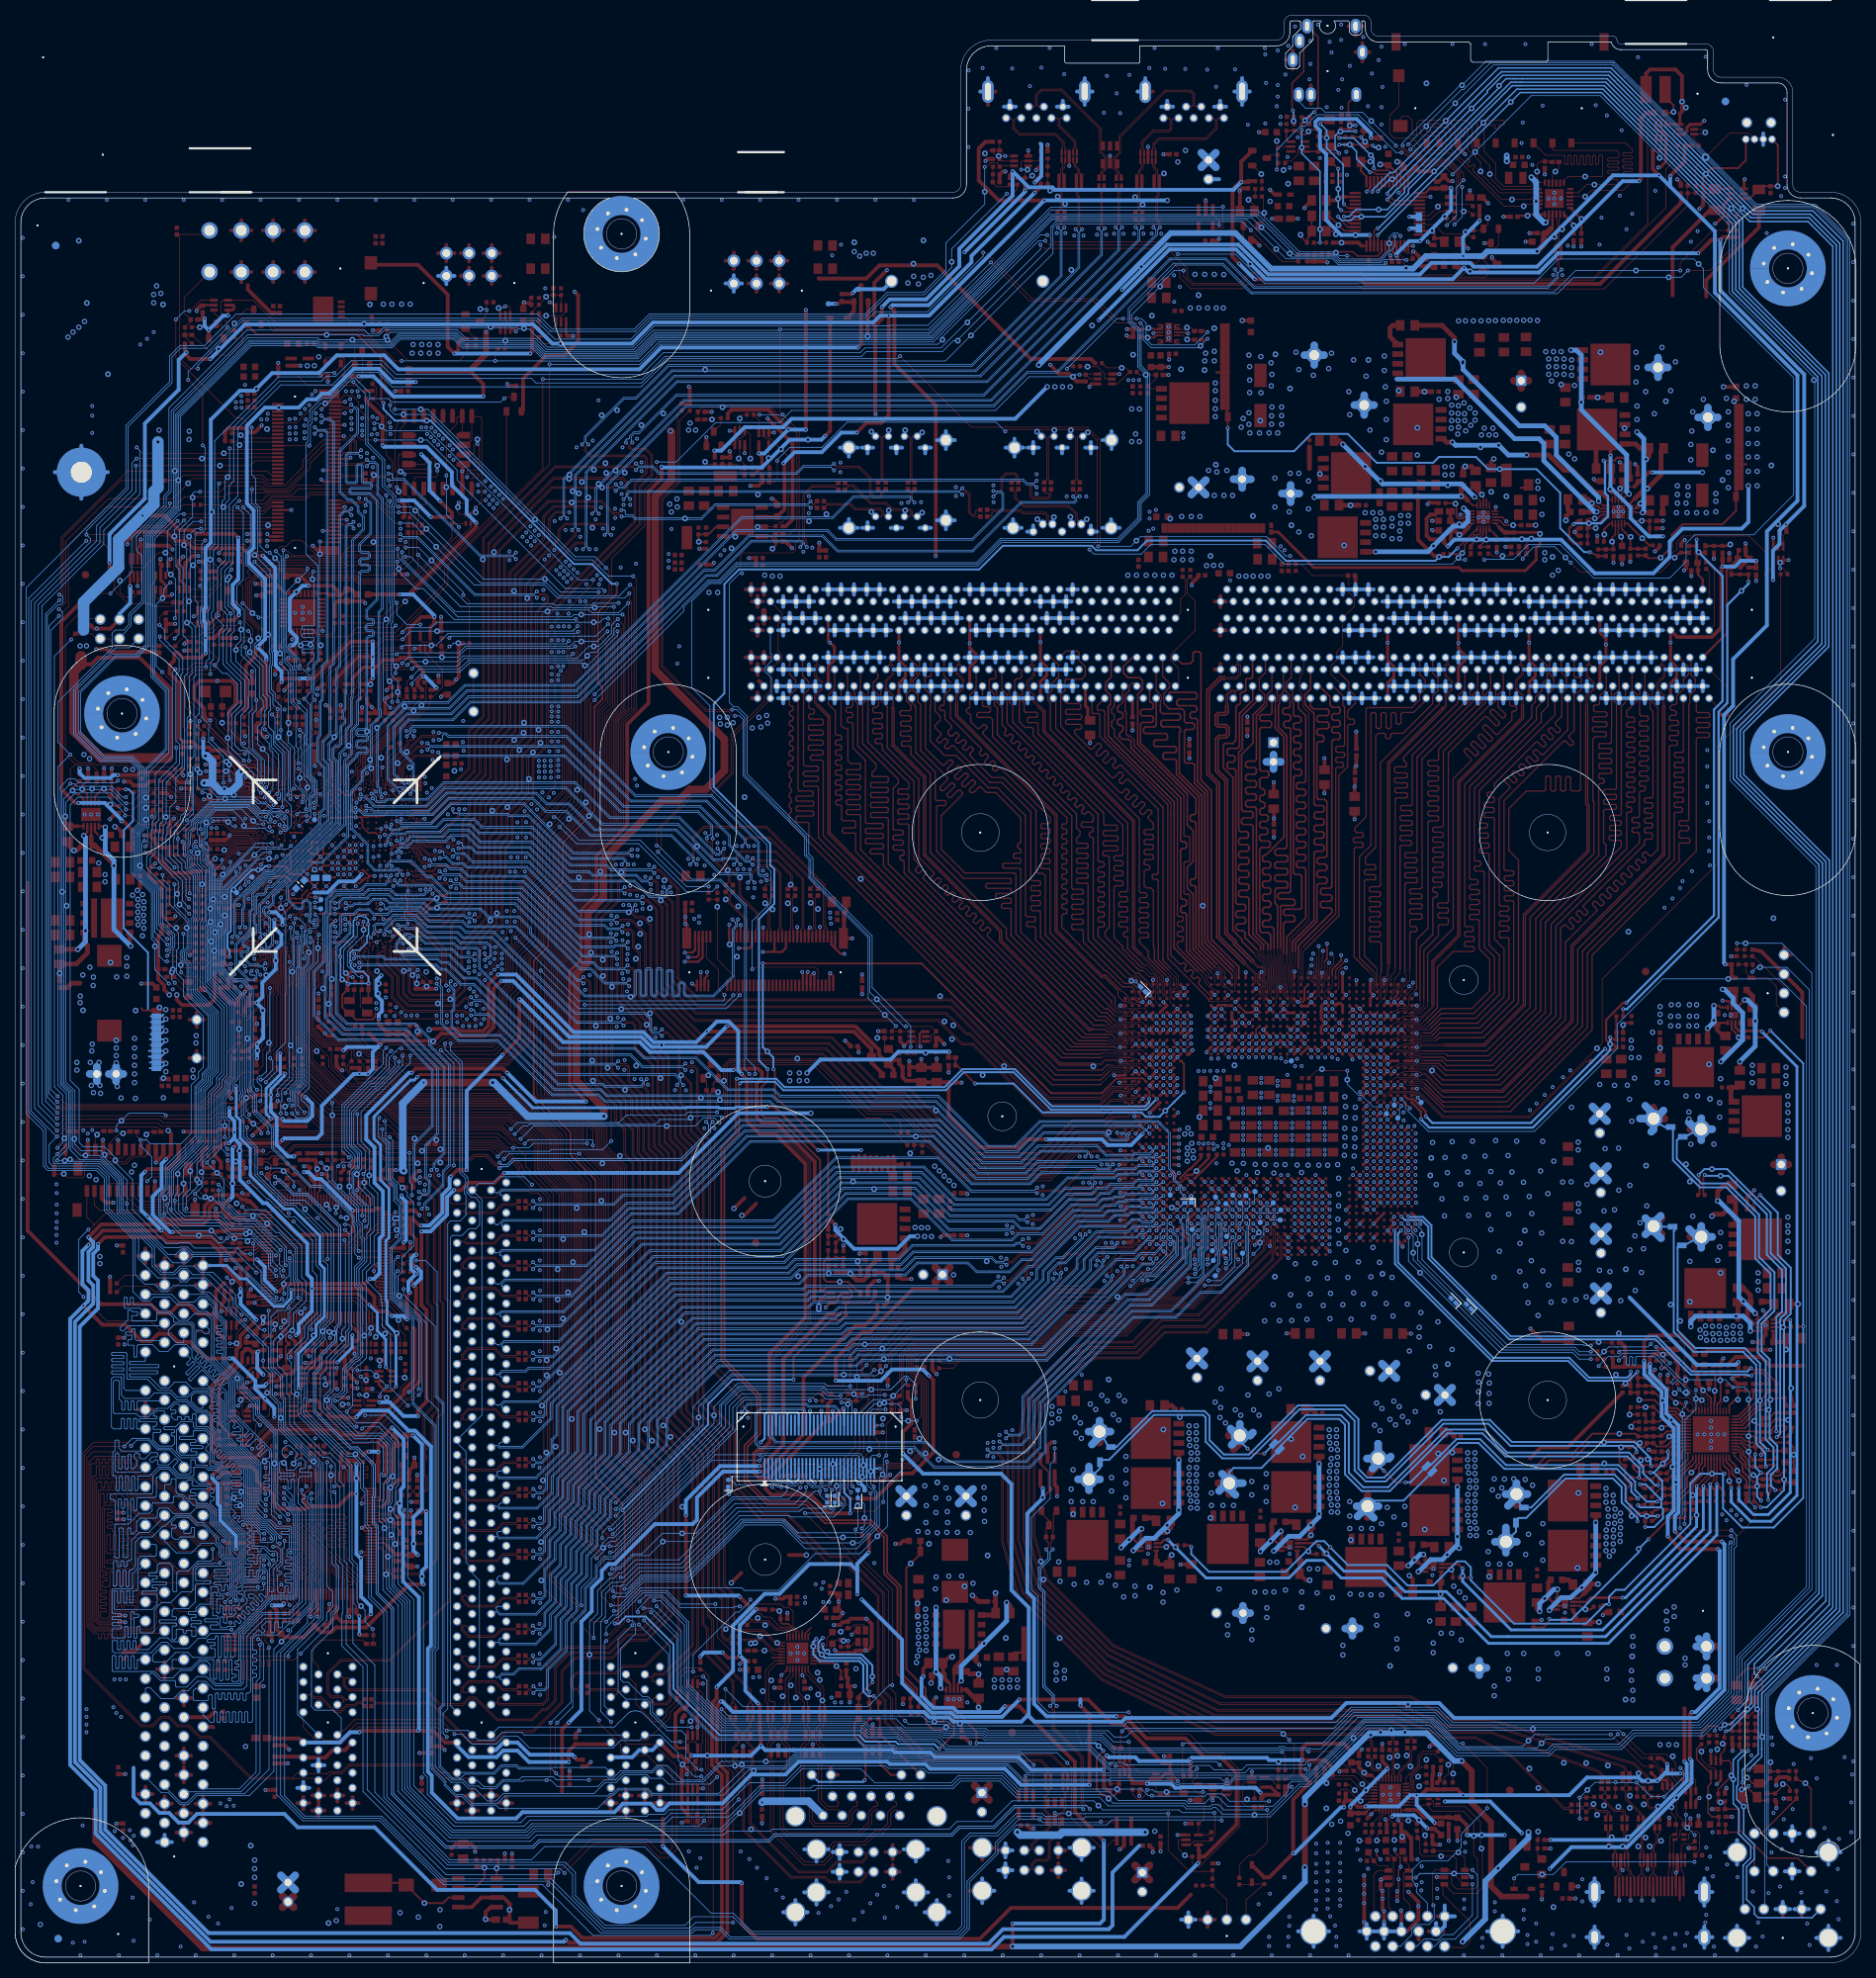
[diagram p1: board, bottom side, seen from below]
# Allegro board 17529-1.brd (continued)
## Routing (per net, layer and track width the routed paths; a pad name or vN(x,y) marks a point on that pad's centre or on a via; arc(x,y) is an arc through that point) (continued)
USB30_TX_PCH_P1: length 179.2
  TOP w0.102: v2(193.27,136.53) 193.17,136.63 192.92,136.63 SB1.F7 ; C3801.1 95.55,230.1 95.55,229.69 v2(95.87,229.36) ; v2(181.91,133.4) 181.91,133.1 181.8,132.98 181.44,132.98 181.23,133.2 181.23,135.67 179.76,137.14 179.76,143.09 179.29,143.56 179.29,147.34 178.4,148.23 178.4,151.55 175.65,154.3 175.65,159.03 173.76,160.92 173.76,177.93 161.48,190.21 161.48,195.14 159.94,196.67 159.94,199.19 160.69,199.94 162.64,199.94 162.94,200.24 162.94,200.6 v2(163.26,200.91)
  BOTTOM w0.102: v2(181.91,133.4) 181.91,133.17 181.67,132.93 181.44,132.93 181.24,133.13 181.24,134.25 181.69,134.7 185.14,134.7 185.83,135.38 189.74,135.38 190.98,136.63 192.38,136.63 192.7,136.95 193,136.95 193.27,136.67 v2(193.27,136.53) ; v2(95.87,229.36) 95.55,229.04 95.55,227.72 115.98,207.29 156.61,207.29 160.95,202.96 ; 160.95,202.96 161.58,202.32 162.22,202.32 162.78,201.76 162.78,201.5 162.89,201.38 163.13,201.38 163.26,201.26 v2(163.26,200.91) ; 160.95,202.96 v1(161.21,203.23)
USB30_TX_PCH_P2: length 176.7
  TOP w0.102: v2(183.24,133.36) 182.95,133.07 182.75,133.07 182.63,133.2 182.63,135.28 180.45,137.45 180.45,143.38 179.98,143.85 179.98,147.7 179.1,148.59 179.1,151.84 176.35,154.59 176.35,159.32 174.47,161.2 174.47,178.21 162.18,190.5 162.18,195.45 160.68,196.95 160.68,198.78 160.95,199.05 167.98,199.05 168.74,199.81 168.74,200.34 v2(169.06,200.66) ; v2(192.12,134.87) 191.77,134.53 SB1.D4 ; v2(106.16,229.34) 105.84,229.66 105.84,230.21 C3803.1
  BOTTOM w0.102: v2(106.16,229.34) 105.84,229.01 105.84,222.97 117.59,211.21 157.65,211.21 161.98,206.88 163.58,206.88 166.19,204.27 ; 166.19,204.27 168.74,201.71 168.74,200.98 v2(169.06,200.66) ; 166.19,204.27 v1(166.46,204.53) ; v2(183.24,133.36) 183.56,133.03 185.15,133.03 185.54,133.43 186.19,134.07 190.51,134.07 190.67,134.24 191.44,134.24 191.64,134.44 191.64,134.72 191.8,134.87 v2(192.12,134.87)
USB_CON_PN1: length 20.8
  TOP w0.102: TR3801.4 97.77,236.2 98.01,236.44 98.01,236.62 98.55,237.16 98.55,237.5 EU3803.1 98.55,237.99 98.55,238.48 97.87,239.17 97.87,241.3 91.9,247.27 88.65,247.27 88.31,246.93 88.31,245.45 88.46,245.3 USB3F1.2
USB_CON_PN2: length 20.8
  TOP w0.102: TR3802.4 100.05,236.17 100.27,236.39 100.27,236.53 99.94,236.87 99.76,237.05 99.76,238.7 100.44,239.38 100.44,239.9 EU3803.4 100.44,240.36 100.44,242.43 105.64,247.62 108.36,247.62 109.11,246.87 109.11,245.48 109.28,245.3 USB3F2.2
USB_CON_PN5: length 37.7
  TOP w0.102: TR3202.4 149.43,32.13 149.21,31.91 149.21,31.56 148.48,30.82 148.48,30.22 EU3204.4 148.48,29.72 148.48,29.1 149.2,28.37 149.2,26.64 147.83,25.27 147.83,19.79 ; v1(148.21,19.79) 147.83,19.79 ; 147.83,19.79 147.83,17.58 141.45,11.2 136.98,11.2 136.36,10.58 132.24,10.58 131.39,11.43 131.39,11.84 131.2,12.03 RJ45R1.2
USB_CON_PN6: length 35.9
  TOP w0.102: 146.83,27.59 146.6,27.36 146.6,26.4 146.94,26.06 146.94,18.41 146.44,17.92 ; 146.83,27.59 146.6,27.83 146.6,28.38 147.32,29.11 147.32,30.89 146.92,31.28 146.92,31.91 147.14,32.13 TR3201.4 ; 146.83,27.59 EU3204.1 ; RJ45R1.6 131.22,14.65 131.39,14.48 131.39,13.84 131.99,13.25 135.29,13.25 136.63,11.9 140.42,11.9 146.44,17.92 ; 146.44,17.92 v1(146.71,17.65)
USB_CON_PN7: length 11.1
  TOP w0.102: USB2R1.6 109.32,14.86 109.48,15.02 109.48,15.56 107.06,17.98 107.06,19.48 107.73,20.16 107.73,20.9 EU3901.4 107.73,21.36 107.73,21.91 107.33,22.31 107.33,22.77 107.12,22.98 TR3902.3
USB_CON_PN8: length 5
  TOP w0.102: v1(39.5,229.11) 39.9,229.11 ; 39.9,229.11 39.9,230.37 39.76,230.51 U3301.2 ; 39.9,229.11 39.9,227.36 39.67,227.13 R3303.2
USB_CON_PN9: length 14.9
  TOP w0.102: TR3901.3 104.83,22.85 105.05,22.63 105.05,22.4 105.11,22.34 105.11,20.17 105.85,19.42 105.85,19 EU3901.1 105.85,18.49 105.85,17.28 107.19,15.95 107.19,13.84 107.57,13.46 108.97,13.46 109.48,12.95 109.48,12.4 109.32,12.24 USB2R1.2
USB_CON_PP1: length 21.5
  TOP w0.102: USB3F1.3 87.95,245.3 88.09,245.45 88.09,247.02 88.56,247.48 91.81,247.48 91.81,247.49 91.99,247.49 98.08,241.39 98.08,240.36 EU3803.6 98.08,239.9 98.08,239.26 98.77,238.57 98.77,237.07 98.23,236.53 98.23,236.39 98.42,236.2 TR3801.3
USB_CON_PP2: length 20
  TOP w0.102: USB3F2.3 108.65,245.3 108.89,245.54 108.89,246.78 108.27,247.41 105.73,247.41 100.66,242.34 100.66,239.29 99.97,238.61 99.97,237.98 EU3803.3 99.97,237.51 99.97,237.13 100.09,237.02 100.49,236.62 100.49,236.57 100.49,236.57 100.49,236.37 100.71,236.15 TR3802.3
USB_CON_PP5: length 37
  TOP w0.102: 148.2,25.95 148.98,26.73 148.98,27.33 EU3204.3 148.98,27.84 148.98,28.28 148.26,29.01 148.26,30.91 148.99,31.65 148.99,31.96 148.78,32.17 TR3202.3 ; 148.2,25.95 147.61,25.36 147.61,17.67 141.36,11.42 136.89,11.42 136.27,10.79 132.33,10.79 131.61,11.52 131.61,11.85 131.79,12.03 RJ45R1.3 ; 148.2,25.95 v1(147.93,26.21)
USB_CON_PP6: length 35.2
  TOP w0.102: TR3201.3 146.49,32.12 146.71,31.9 146.71,31.19 147.1,30.8 147.1,30.25 EU3204.6 147.1,29.7 147.1,29.2 146.38,28.47 146.38,26.31 146.72,25.97 146.72,25.4 ; 146.72,25.4 v1(146.35,25.4) ; 146.72,25.4 146.72,18.5 140.33,12.12 136.72,12.12 135.38,13.46 132.08,13.46 131.61,13.93 131.61,14.46 131.8,14.65 RJ45R1.7
USB_CON_PP7: length 11.1
  TOP w0.102: USB2R1.7 109.85,14.86 109.7,15.02 109.7,15.65 107.27,18.07 107.27,18.52 EU3901.3 107.27,18.97 107.27,19.39 107.95,20.07 107.95,22 107.55,22.4 107.55,22.77 107.77,22.98 TR3902.4
USB_CON_PP8: length 5
  TOP w0.102: v1(40.51,228.09) 40.12,228.09 ; 40.12,228.09 40.12,227.34 40.34,227.13 R3303.1 ; 40.12,228.09 40.12,230.37 40.26,230.51 U3301.3
USB_CON_PP9: length 15
  TOP w0.102: TR3901.4 105.48,22.85 105.26,22.63 105.26,22.49 105.32,22.43 105.32,21.43 105.6,21.15 EU3901.6 105.32,20.85 105.32,20.26 106.07,19.51 106.07,17.37 107.4,16.04 107.4,13.93 107.66,13.68 109.06,13.68 109.7,13.04 109.7,12.4 109.86,12.24 USB2R1.3
USB_OC0_R_N: length 194.3
  TOP w0.102: v2(204.38,166.92) 204.22,166.75 R1602.1 ; SB1.AH36 204.02,150.87 204.02,151.53 203.97,151.57 203.97,152.01 204.02,152.05 204.02,152.19 v2(204.48,152.65) ; v2(84.84,229.69) 84.84,230.25 85.66,231.08 U3801.3
  BOTTOM w0.102: v2(204.48,152.65) 204.09,153.04 204.09,153.49 204.09,153.5 204.09,156.19 204.84,156.94 204.84,161.04 204.81,161.07 204.81,166.49 v2(204.38,166.92) 204.67,167.21 204.67,171.58 204,172.25 204,184.66 205.56,186.22 205.56,200.76 205.31,201.02 205.31,203.5 205.05,203.76 205.05,205.16 203.38,206.83 202.45,206.83 199.1,210.19 196.06,210.19 194.16,208.28 179.17,208.28 179.12,208.23 178.76,208.23 178.71,208.28 161.26,208.28 157.85,211.7 121.02,211.7 v1(117.64,215.07) 106.81,225.91 106.81,229.34 106.32,229.82 84.96,229.82 v2(84.84,229.69)
USB_OC1_R_N: length 314.9
  TOP w0.102: v2(104.9,26.42) 104.34,25.86 104.34,19.13 100.58,15.37 99.69,15.37 98.81,16.26 U3901.3 ; v2(208.08,185.9) 207.92,185.9 207.82,185.8 204.56,185.8 204.15,185.4 200.89,185.4 200.23,186.06 193.23,186.06 v2(192.85,186.43) ; v2(162.94,179.71) 162.94,165.72 164.31,164.36 164.44,164.22 164.44,150.94 168.51,146.87 168.51,142.74 168.51,141.7 170.54,139.67 170.54,133.12 172.11,131.55 172.11,115.52 166.67,110.08 166.67,107.63 163.98,104.94 163.98,67.63 160.27,63.92 160.27,46.58 160.86,46 v2(160.86,45.26) ; SB1.AL40 204.96,152.72 204.89,152.79 204.89,152.94 v2(204.52,153.31) ; v2(205.8,167.06) 207.07,167.06 R1603.1
  BOTTOM w0.102: v2(204.52,153.31) 204.33,153.51 204.33,156.14 205.04,156.85 205.04,166.29 v2(205.8,167.06) 204.9,167.96 204.9,169.98 205.86,170.93 206.55,170.93 206.81,171.19 206.81,172.34 208.36,173.89 208.36,185.62 v2(208.08,185.9) ; v2(160.86,45.26) 157.4,41.81 157.4,35.81 151.26,29.67 132.62,29.67 131.76,28.81 127.79,28.81 127.46,28.47 122.76,28.47 122.14,27.86 111.12,27.86 111.02,27.76 106.25,27.76 v2(104.9,26.42) ; v2(192.85,186.43) 192.86,186.42 192.86,185.6 185.85,178.59 v1(173.63,178.59) 173.43,178.79 168.12,178.79 167.77,178.44 164.21,178.44 v2(162.94,179.71)
USB_OC2_R_N: length 12.6
  TOP w0.102: SB1.AJ44 203.89,154 203.48,154 203.02,154.46 203.02,155.15 203.15,155.27 203.15,160.68 v1(201.83,162) 200.96,162.86 R1605.1
USB_OC3_R_N: length 296.5
  TOP w0.102: v2(193.42,186.9) 193.42,186.9 193.42,186.89 193.42,186.89 193.78,186.54 200.07,186.54 200.96,185.65 204.08,185.65 204.46,186.03 207.42,186.03 208.08,186.69 v2(208.53,186.69) ; U3201.3 109.41,25.46 109.35,25.53 v2(109.35,26.16) ; v2(163.7,178.18) 163.37,177.85 163.37,165.61 164.4,164.59 164.67,164.32 164.67,151.03 168.74,146.96 168.74,142.65 168.74,141.79 170.76,139.77 170.76,133.22 172.34,131.64 172.34,115.42 166.95,110.04 166.95,109.85 166.95,107.59 164.21,104.85 164.21,67.53 160.53,63.85 160.53,46.65 161.54,45.64 v2(161.54,44.7) ; R1604.1 206.62,166.5 206.51,166.6 v2(206.48,166.6) ; v2(204.76,154.14) 204.76,153.68 204.95,153.49 204.95,153.17 205.19,152.93 SB1.AL41
  BOTTOM w0.102: v2(163.7,178.18) v1(169.16,178.18) 170.15,178.18 170.46,177.88 185.5,177.88 193.42,185.8 193.42,186.9 v2(193.42,186.9) ; v2(109.35,26.16) 110.72,27.53 111.12,27.53 111.21,27.63 122.24,27.63 122.85,28.24 127.55,28.24 127.88,28.58 131.85,28.58 132.72,29.44 151.36,29.44 157.63,35.71 157.63,40.79 v2(161.54,44.7) ; v2(208.53,186.69) 208.58,186.64 208.58,173.8 208.13,173.31 207.14,172.31 207.14,171.07 206.88,170.81 206.88,167 v2(206.48,166.6) 205.41,165.53 205.41,161.14 205.24,160.97 205.24,156.77 204.53,156.06 204.53,154.37 v2(204.76,154.14)
USB_OC4_R_N: length 8.6
  TOP w0.102: RN1601.3 207.16,163.07 v1(207.75,162.48) 208.1,162.13 208.1,156.58 208.28,156.4 208.28,155.8 SB1.AV47
USB_OC5_R_N: length 15.2
  TOP w0.102: SB1.AR35 207.14,150.23 206.36,151.02 206.36,151.57 205.55,152.38 v2(205.55,152.46) ; v2(206.38,162.18) 205.89,162.66 205.89,163.56 RN1601.1
  BOTTOM w0.102: v2(205.55,152.46) 205.56,152.47 205.56,153.6 205.8,153.83 205.8,154.87 206.38,155.45 v1(206.38,156.59) 206.38,157.23 206.12,157.48 206.12,160.4 206.25,160.53 206.25,162.05 v2(206.38,162.18)
USB_OC6_R_N: length 15.2
  TOP w0.102: v2(206.73,151.78) 206.74,151.78 206.84,151.68 206.84,150.99 SB1.AR37 ; RN1601.2 206.66,163.22 v2(206.38,162.94)
  BOTTOM w0.102: v2(206.38,162.94) 205.82,162.38 205.82,160.97 205.79,160.94 205.79,156.45 205.36,156.02 v1(205.36,155.32) 205.49,155.19 205.49,153.97 205.15,153.64 205.15,153.05 205.12,153.01 205.12,152.28 205.38,152.02 206.5,152.02 v2(206.73,151.78)
USB_PCH_PN1: length 186.4
  TOP w0.102: SB1.J3 194.27,134.29 194.27,132.33 192.54,130.59 192.54,128.15 191.69,127.3 185.98,127.3 184.65,128.64 184.65,129.98 185.76,131.1 185.76,134.12 181.89,138 181.89,143.93 181.38,144.43 181.38,148.74 180.49,149.63 180.49,152.52 177.76,155.25 177.76,159.89 175.9,161.76 175.9,181.79 169.94,187.74 168.67,187.74 168.4,187.48 168.4,187.14 v2(168.08,186.82) ; TR3801.1 97.77,234.18 97.99,233.95 97.99,229.69 v2(97.66,229.36)
  BOTTOM w0.102: 167.75,197.57 168.4,196.93 168.4,187.14 v2(168.08,186.82) ; 167.75,197.57 v1(167.49,197.31) ; 167.75,197.57 156.46,208.86 115.44,208.86 97.99,226.32 97.99,229.04 v2(97.66,229.36)
USB_PCH_PN2: length 170.2
  TOP w0.102: v2(99.95,229.24) 100.28,229.57 100.28,233.95 100.05,234.18 TR3802.1 ; v2(183.24,137.68) 183.24,137.79 182.99,138.04 182.66,138.04 182.38,138.32 182.38,144.11 181.86,144.63 181.86,149.28 180.99,150.15 180.99,152.71 178.24,155.45 178.24,160.24 176.4,162.08 176.4,182.07 169.84,188.63 169.84,189.03 v2(169.51,189.36) ; SB1.N13 v2(195.71,139.18)
  BOTTOM w0.102: v2(169.51,189.36) 169.84,189.68 169.84,194.21 ; v2(195.71,139.18) 194.73,139.18 194.47,139.44 190.41,139.44 189.28,138.3 184.69,138.3 184.39,138 183.55,138 183.24,137.69 v2(183.24,137.68) ; 169.84,194.21 v1(169.47,194.21) ; 169.84,194.21 169.84,196.56 156.79,209.6 116.36,209.6 100.27,225.68 100.27,228.91 v2(99.95,229.24)
USB_PCH_PN5: length 134.6
  TOP w0.102: SB1.M1 195.6,133.2 195.71,133.3 195.86,133.3 195.99,133.16 195.99,132.22 194.03,130.25 194.03,127.66 192.25,125.88 184.57,125.88 184.3,125.61 184.07,125.61 183.72,125.96 v2(183.72,125.95) ; v2(161.26,116.79) 161.02,116.55 161.02,115.74 160.53,115.24 160.53,113.04 158.94,111.45 158.94,110.47 158.94,110.47 158.94,108.15 157.71,106.92 157.71,102.62 157.71,102.53 157.71,71.73 153.17,67.2 153.17,44.69 152.6,44.12 152.6,40.54 149.21,37.14 149.21,34.34 149.43,34.13 TR3202.1
  BOTTOM w0.102: 167.61,116.22 172.15,116.22 181.37,125.44 183.13,125.44 183.24,125.54 183.24,125.84 183.36,125.96 183.72,125.96 v2(183.72,125.95) ; 167.61,116.22 v1(167.61,116.59) ; 167.61,116.22 166.23,116.22 165.97,115.95 161.29,115.95 161.02,116.22 161.02,116.55 v2(161.26,116.79)
USB_PCH_PN6: length 137.7
  TOP w0.102: v2(163.57,123.87) 163.26,124.18 162.46,124.18 162.14,123.86 162.14,120.94 159.83,118.63 159.83,113.33 158.24,111.74 158.24,110.18 158.24,108.44 156.93,107.14 156.93,72.25 152.48,67.79 152.48,45.85 151.9,45.28 151.9,40.98 146.92,36 146.92,34.34 147.14,34.13 TR3201.1 ; v2(194.42,136.27) 194.8,136.27 SB1.K7
  BOTTOM w0.102: v2(163.57,123.87) 163.89,124.19 167.23,124.19 ; v1(167.23,123.83) 167.23,124.19 ; 167.23,124.19 169.81,124.19 181.01,135.39 184.85,135.39 185.54,136.08 189.55,136.08 191.26,137.79 193.7,137.79 194.93,136.56 194.93,136.39 194.81,136.27 v2(194.42,136.27)
USB_PCH_PN7: length 175.7
  TOP w0.102: v2(155.68,116) 155.98,115.7 155.98,113.74 155.23,112.99 155.23,109.69 153.63,108.09 153.63,74.18 149.47,70.02 149.47,62.83 145.34,58.7 142.27,58.7 136.49,52.92 134.2,52.92 129.81,48.53 129.81,35.68 128.89,34.77 128.89,31.92 123.81,26.84 108.37,26.84 107.33,25.8 107.33,25.04 107.12,24.82 TR3902.2 ; SB1.L4 195.17,134.37 195.17,134.21 194.99,134.03 194.99,132.08 193.28,130.37 193.28,127.9 191.97,126.59 185.55,126.59 184.52,127.62 v2(183.75,127.62)
  BOTTOM w0.102: v2(183.75,127.62) 183.4,127.28 182.17,127.28 172.39,117.5 156.7,117.5 156.22,117.03 ; 156.22,117.03 v1(155.96,117.3) ; 156.22,117.03 155.98,116.79 155.98,116.33 155.68,116.03 v2(155.68,116)
USB_PCH_PN8: length 240
  TOP w0.102: v2(165.2,188.72) 165.54,189.07 165.54,189.92 165.87,190.25 171.32,190.25 172.21,189.36 172.21,188.21 177.31,183.11 177.31,162.46 179.16,160.62 179.16,155.83 181.93,153.06 181.93,150.69 182.78,149.83 182.78,145.01 183.72,144.07 183.72,139.95 186.46,137.21 186.46,130.81 185.34,129.69 185.34,128.93 186.26,128.02 191.39,128.02 191.8,128.43 191.8,130.65 193.67,132.51 193.67,133.35 193.47,133.55 193.47,133.84 193.45,133.86 193.45,134.48 SB1.G4 ; R3303.3 39.67,225.25 39.92,225 39.92,224.12 v2(39.57,223.77)
  BOTTOM w0.102: 163.68,197.21 165.6,195.29 165.6,188.89 165.43,188.72 v2(165.2,188.72) ; 163.68,197.21 v1(163.41,196.94) ; 163.68,197.21 155.23,205.65 114.59,205.65 110.15,210.1 106.21,210.1 91.22,225.08 84.04,225.08 80.25,221.3 41.38,221.3 39.99,222.69 39.99,223.35 v2(39.57,223.77)
USB_PCH_PN9: length 182.4
  TOP w0.102: SB1.M6 196.04,135.77 196.29,136.02 v2(196.6,136.02) ; v2(158.5,123.36) 158.18,123.04 157.79,123.04 156.12,121.37 156.12,117.82 154.53,116.23 154.53,109.98 152.93,108.38 152.93,74.73 148.77,70.56 148.77,63.12 145.05,59.4 141.9,59.4 136.31,53.81 134.02,53.81 129.11,48.9 129.11,35.97 128.05,34.92 128.05,32.12 123.58,27.64 106.97,27.64 105.05,25.72 105.05,25.17 104.83,24.95 TR3901.2
  BOTTOM w0.102: 160.35,125.22 159.93,124.8 159.93,123.4 159.55,123.01 158.85,123.01 v2(158.5,123.36) ; 160.35,125.22 v1(160.08,125.49) ; 160.35,125.22 160.73,125.6 169.93,125.6 180.64,136.32 184.4,136.32 185.11,137.03 189.43,137.03 190.96,138.56 194.06,138.56 195.2,137.41 196.29,137.41 196.6,137.11 v2(196.6,136.02)
USB_PCH_PN14: length 100.4
  TOP w0.102: NGFF1.5 200.8,188.75 200.63,188.58 193.31,188.58 193.09,188.8 v2(193.09,188.8) ; SB1.E5 192.45,135.32 192.72,135.04 v2(192.72,134.67) ; v2(175.04,181.26) 174.72,180.93 173.9,180.93 173.49,180.53 173.49,179.89 174.98,178.41 174.98,161.38 176.85,159.51 176.85,154.77 179.58,152.04 179.58,149.02 180.47,148.13 180.47,144.05 180.94,143.58 180.94,137.65 184.85,133.74 184.85,131.53 184.58,131.27 184.33,131.27 v2(184.02,131.57)
  BOTTOM w0.102: 178.05,180.92 175.37,180.92 v2(175.04,181.26) ; 178.05,180.92 v1(178.05,181.31) ; 178.05,180.92 183.18,180.92 190.77,188.51 192.8,188.51 193.09,188.8 v2(193.09,188.8) ; v2(192.72,134.67) 192.95,134.9 193.19,134.9 193.47,134.62 193.47,134.01 192.77,133.31 186.57,133.31 184.5,131.24 184.35,131.24 v2(184.02,131.57)
USB_PCH_PP1: length 185.8
  TOP w0.102: 174.23,183.15 v1(173.97,182.89) ; 174.23,183.15 175.68,181.7 175.68,161.67 177.55,159.8 177.55,155.16 180.28,152.43 180.28,149.54 181.17,148.65 181.17,144.34 181.67,143.84 181.67,137.91 185.55,134.04 185.55,131.19 184.43,130.07 184.43,128.55 185.89,127.09 191.78,127.09 192.76,128.06 192.76,130.51 194.49,132.24 194.49,133.81 SB1.J2 ; 174.23,183.15 169.85,187.53 168.76,187.53 168.62,187.39 168.62,187.14 v2(168.94,186.82) ; v2(98.53,229.36) 98.21,229.68 98.21,233.97 98.42,234.18 TR3801.2
  BOTTOM w0.102: v2(168.94,186.82) 168.62,187.14 168.62,197.02 156.55,209.08 115.53,209.08 98.2,226.41 98.2,229.04 v2(98.53,229.36)
USB_PCH_PP2: length 170.9
  TOP w0.102: v2(195.63,139.99) 196,139.62 196.16,139.62 196.29,139.75 196.29,140.05 SB1.N15 ; v2(170.38,189.36) 170.05,189.03 170.05,188.72 176.61,182.16 176.61,162.17 178.46,160.33 178.46,155.54 181.2,152.79 181.2,150.24 182.08,149.36 182.08,144.72 182.6,144.2 182.6,138.41 182.75,138.25 183.01,138.25 183.23,138.48 v2(183.23,138.6) ; TR3802.2 100.71,234.18 100.5,233.97 100.5,229.55 v2(100.81,229.24)
  BOTTOM w0.102: v2(183.23,138.6) 183.61,138.22 184.3,138.22 184.6,138.52 189.19,138.52 190.32,139.65 194.56,139.65 194.82,139.39 195.05,139.39 195.2,139.55 195.2,139.88 195.31,139.99 v2(195.63,139.99) ; v2(170.38,189.36) 170.05,189.68 170.05,192.99 ; 170.05,192.99 170.05,196.65 156.88,209.82 116.45,209.82 100.49,225.77 100.49,228.91 v2(100.81,229.24) ; 170.05,192.99 v1(170.43,192.99)
USB_PCH_PP5: length 135.4
  TOP w0.102: v2(183.72,125.21) 183.72,125.23 183.88,125.39 184.39,125.39 184.66,125.67 192.34,125.67 194.25,127.58 194.25,130.16 196.21,132.13 196.21,133.25 195.95,133.52 195.83,133.52 SB1.L2 ; v2(160.53,116.79) 160.81,116.51 160.81,115.82 160.31,115.33 160.31,113.13 158.72,111.54 158.72,110.38 158.72,108.24 157.49,107.01 157.49,102.61 157.49,102.53 157.49,71.82 152.96,67.29 152.96,44.78 152.39,44.21 152.39,40.63 148.99,37.23 148.99,34.34 148.78,34.13 TR3202.2
  BOTTOM w0.102: v2(160.53,116.79) 160.81,116.51 160.81,116.13 161.2,115.74 163.37,115.74 ; 163.37,115.74 166.06,115.74 166.32,116 172.24,116 181.46,125.23 183.72,125.23 v2(183.72,125.21) ; 163.37,115.74 v1(163.37,115.37)
USB_PCH_PP6: length 138.5
  TOP w0.102: SB1.K6 195.01,135.7 v2(195.2,135.89) ; v2(163.57,124.73) 163.23,124.4 162.37,124.4 161.93,123.95 161.93,121.03 159.61,118.72 159.61,113.42 158.03,111.83 158.03,110.09 158.03,108.53 156.72,107.23 156.72,72.34 152.26,67.88 152.26,45.94 151.69,45.37 151.69,41.07 146.71,36.09 146.71,34.34 146.49,34.13 TR3201.2
  BOTTOM w0.102: 165.33,124.41 v1(165.33,124.79) ; 165.33,124.41 169.72,124.41 180.92,135.61 184.76,135.61 185.45,136.3 189.46,136.3 191.17,138.01 193.79,138.01 195.15,136.65 195.15,135.94 v2(195.2,135.89) ; 165.33,124.41 163.89,124.41 v2(163.57,124.73)
USB_PCH_PP7: length 175.7
  TOP w0.102: TR3902.1 107.77,24.82 107.55,25.04 107.55,25.71 108.46,26.62 123.9,26.62 129.11,31.83 129.11,34.68 130.02,35.59 130.02,48.44 134.29,52.7 136.58,52.7 142.35,58.48 145.43,58.48 149.68,62.74 149.68,69.93 153.85,74.09 153.85,108 155.45,109.6 155.45,112.9 156.2,113.65 156.2,115.73 v2(156.5,116.03) ; SB1.L3 195.4,134.14 195.21,133.94 195.21,131.99 193.5,130.28 193.5,127.81 192.06,126.38 185.46,126.38 184.43,127.4 184.22,127.4 184.1,127.28 184.1,126.81 184,126.71 v2(183.73,126.71)
  BOTTOM w0.102: 158.7,117.29 172.48,117.29 182.26,127.06 183.38,127.06 183.73,126.71 v2(183.73,126.71) ; 158.7,117.29 v1(158.7,116.92) ; 158.7,117.29 156.79,117.29 156.19,116.7 156.19,116.33 v2(156.5,116.03)
USB_PCH_PP8: length 240.1
  TOP w0.102: v2(40.44,223.77) 40.14,224.07 40.14,225.05 40.34,225.25 R3303.4 ; v2(166.06,188.72) 165.76,189.02 165.76,189.83 165.96,190.03 167.69,190.03 ; 167.69,190.03 171.23,190.03 172,189.27 172,188.12 177.1,183.02 177.1,162.37 178.94,160.53 178.94,155.74 181.71,152.97 181.71,150.6 182.56,149.74 182.56,144.92 183.5,143.98 183.5,139.86 186.25,137.12 186.25,130.9 185.13,129.78 185.13,128.84 186.17,127.8 191.48,127.8 192.02,128.34 192.02,130.56 193.89,132.42 193.89,133.44 193.69,133.64 193.69,133.93 193.66,133.95 193.66,134.99 SB1.G5 ; 167.69,190.03 v1(167.69,189.66)
  BOTTOM w0.102: v2(166.06,188.72) 165.81,188.97 165.81,195.38 155.32,205.87 114.68,205.87 110.24,210.31 106.3,210.31 91.31,225.3 83.95,225.3 80.16,221.51 41.47,221.51 40.21,222.78 40.21,223.4 v2(40.44,223.77)
USB_PCH_PP9: length 182.5
  TOP w0.102: v2(158.5,122.5) 158.18,122.82 157.88,122.82 156.34,121.28 156.34,117.73 154.75,116.14 154.75,109.89 153.15,108.29 153.15,74.64 148.98,70.47 148.98,63.03 145.14,59.18 141.99,59.18 136.4,53.59 134.11,53.59 129.32,48.81 129.32,35.88 128.27,34.83 128.27,32.03 123.67,27.43 107.06,27.43 105.26,25.63 105.26,25.17 105.48,24.95 TR3901.1 ; SB1.N8 196.23,136.26 196.04,136.07 195.83,136.07 195.71,136.2 v2(195.71,136.4)
  BOTTOM w0.102: v2(195.71,136.4) 195.93,136.18 196.1,136.18 196.38,136.46 196.38,137.02 196.2,137.2 195.11,137.2 193.97,138.34 191.05,138.34 189.52,136.82 185.2,136.82 184.49,136.11 180.73,136.11 170.02,125.39 160.82,125.39 160.15,124.71 160.15,123.98 ; 160.15,123.98 160.15,123.31 159.64,122.8 158.8,122.8 v2(158.5,122.5) ; 160.15,123.98 v1(160.53,123.98)
USB_PCH_PP14: length 100.4
  TOP w0.102: v2(193.04,135.36) 192.99,135.4 SB1.F6 ; v2(193.09,188.01) 193.44,188.37 200.69,188.37 200.8,188.25 NGFF1.3 ; v2(184.02,130.81) 184.26,131.05 184.67,131.05 185.06,131.44 185.06,133.83 181.15,137.74 181.15,143.67 180.68,144.14 180.68,148.22 179.79,149.11 179.79,152.13 177.06,154.86 177.06,159.6 175.2,161.47 175.2,178.5 173.71,179.98 173.71,180.44 173.99,180.72 174.72,180.72 v2(175.04,180.39)
  BOTTOM w0.102: 176.3,180.71 183.27,180.71 190.86,188.29 192.81,188.29 v2(193.09,188.01) ; 176.3,180.71 175.36,180.71 v2(175.04,180.39) ; 176.3,180.71 v1(176.3,180.34) ; v2(193.04,135.36) 193.39,135.01 193.69,134.71 193.69,133.92 192.86,133.1 186.66,133.1 184.59,131.03 184.24,131.03 v2(184.02,130.81)
V_CPU_ST_PLL: length 665.9
  TOP w0.203: 213.23,98.12 213.18,98.07 U2401.29
  TOP w0.508: Q801.S 129.79,119.99 129.79,120.66 132.91,123.77 v2(149.93,123.77) ; Q801.S 127.89,118.08 127.89,117.35 ; Q801.S 127.98,119.32 C803.2 127.13,118.81 C805.1 R808.1 126.68,117.03 126.24,116.59 124.41,116.59 C804.1 C1032.1 120.64,116.38 C1033.1 120.59,111.95 116.41,107.77 111.3,107.77 110.24,108.84 v2(107.7,108.84) ; R2028.2 200.79,120.78 v2(200.58,120.57) ; R2024.2 R2026.2 v2(198.48,117.47) ; v2(24.59,57.02) 23.24,55.68 v2(18.39,55.68) ; R2430.1 216.57,100.14 215.87,100.84 v2(215.65,100.84) ; R2430.1 217.03,100.41 217.66,100.41 218.31,99.75 218.31,98.46 219.2,97.57 232.63,97.57 v2(234.31,95.89) ; R2430.1 216.57,99.48 C2411.1 215.52,98.42 213.72,98.42 213.41,98.12 213.23,98.12 ; v2(171.2,3.05) 170.81,2.67 151.24,2.67 149.86,4.05 149.86,25.15 151.26,26.54 151.26,31.23 151.18,31.31 151.18,33.19 151.26,33.26 151.26,33.79 151.13,33.92 151.13,34.16 v2(150.75,34.54) ; 31.28,78.82 28.24,78.82 v2(27.89,79.17) 27.89,79.98 27.42,80.45 PR4404.1 25.13,80.45 PC4401.1 24.19,79.51 PR4405.1 24.26,78.42 PR4406.1 ; 31.28,78.82 31.33,78.77 R404.1 32.78,79.78 R401.1 ; 31.28,78.82 31.17,78.93 31.17,81.43 31.67,81.94 R403.1 ; v2(179.73,129.77) 180.77,128.73 180.77,123.64 181.91,122.5 185.6,122.5 185.9,122.81 187.65,122.81 188.62,121.84 195.25,121.84 v2(195.73,121.36) 197.17,122.8 R1703.2 ; R402.2 125.98,74.66 125.48,74.16 125.48,71.32 126.64,70.16 v2(126.64,67.32) ; v2(215.11,107.8) 214.58,108.33 209.07,108.33 v2(208.67,108.72) ; R2021.2 v2(197.36,117.47)
  BOTTOM w0.508: v2(171.2,3.05) 171.45,2.79 218.18,2.79 232.73,17.34 232.73,23.17 236.09,26.53 236.09,84.71 233.68,87.12 233.68,89.53 234.31,90.17 234.31,93.97 233.68,94.61 233.68,95.25 v2(234.31,95.89) ; v2(179.73,129.77) 178.16,129.77 170.76,122.37 161.2,122.37 159.87,121.04 152.66,121.04 v2(149.93,123.77) ; 196.06,121.03 196.72,120.37 196.72,118.11 v2(197.36,117.47) v2(198.48,117.47) 199.24,117.47 203.45,113.26 203.45,109.6 204.09,108.97 208.43,108.97 v2(208.67,108.72) ; 196.06,121.03 v2(195.73,121.36) ; 196.06,121.03 200.13,121.03 v2(200.58,120.57) ; v2(150.75,34.54) 150.5,34.54 149.12,33.17 123.85,33.17 123.44,32.77 123.11,32.44 120.52,32.44 119.96,31.88 110.97,31.88 110.11,32.74 ; v2(107.7,108.84) 100.33,108.84 99.57,108.08 96.46,108.08 v2(94.94,109.59) ; v2(18.39,55.68) 18.03,55.32 18.03,36.06 21.73,32.36 53.77,32.36 55.75,34.34 68.02,34.34 70,32.36 97.2,32.36 97.69,31.88 109.25,31.88 110.11,32.74 ; v2(24.59,57.02) 24.59,59.04 24.1,59.52 24.1,71.02 25.7,72.62 25.7,75.75 27.89,77.94 v2(27.89,79.17) ; 110.11,32.74 110.01,32.84 110.01,46.96 112.29,49.25 112.29,63.27 113.67,64.64 123.96,64.64 v2(126.64,67.32) ; v2(215.11,107.8) 215.26,107.65 v1(215.26,103) 215.26,101.22 v2(215.65,100.84)
V_SM_VREF_CNT: length 38.1
  TOP w0.305: v2(33.15,122.3) 32.89,122.05 C601.1 C602.1 R601.1 ; CPU1.AB40 58.15,112.49 v2(58.15,111.48)
  BOTTOM w0.305: v2(58.15,111.48) 57.06,110.39 43.36,110.39 33.15,120.61 v1(33.15,121.41) v2(33.15,122.3)
V_VCC3P3_EN: length 6.6
  TOP w0.102: R4204.2 95.34,209.85 v1(94.54,209.85) C4209.1 93.18,209.4 C4210.1 93.92,208.03 Q4201.4
V_VCC3P3_EN_R: length 7.3
  TOP w0.102: R4203.2 99.73,210.79 v1(97.71,210.79) 97.17,210.79 R4204.1 96.72,210.24 98.29,208.67 U4202.6
VCORE_VCC_SEN: length 45.9
  TOP w0.254: PR4416.2 PR4418.1 30.42,76.33 R802.1 v2(30.42,78.13) ; CPU1.C38 61.2,96.36 v2(60.77,96.79)
  BOTTOM w0.254: 32.38,77.34 30.89,77.34 30.42,77.82 v2(30.42,78.13) ; 32.38,77.34 v1(32.38,77.72) ; 32.38,77.34 35.92,77.34 38.53,79.96 48.61,79.96 61.19,92.54 61.19,96.37 v2(60.77,96.79)
VCORE_VSS_SEN: length 49.3
  TOP w0.254: R802.2 29.46,77.28 PC4409.2 PR4420.1 PC4411.1 ; R802.2 PR4423.1 ; R802.2 v2(29.53,78.13) ; v2(61.66,96.79) CPU1.D38
  BOTTOM w0.254: 31.11,76.94 v1(31.11,76.58) ; 31.11,76.94 36.08,76.94 38.7,79.55 48.78,79.55 61.59,92.37 61.59,96.73 v2(61.66,96.79) ; 31.11,76.94 30.72,76.94 v2(29.53,78.13)
VCTRL_VCC_EN: length 232.9
  TOP w0.102: v2(103.29,209.89) R4206.2 ; R4206.2 101.92,209.32 U4202.2 ; R4206.2 102.41,209.97 U4202.3 ; v2(201.68,74.27) 201.68,74.85 202.31,75.49 205.51,75.49 206.43,74.57 209.6,74.57 210.13,75.11 210.13,75.74 210.29,75.9 210.92,75.9 211.37,76.34 211.37,76.85 210.56,77.65 Q2407.G ; v2(159.18,198.35) 159.18,196.29 160.78,194.69 160.78,189.92 165.17,185.54 165.17,180.89 167.39,178.66 167.39,169.54 168.38,168.55 168.38,152.6 172.54,148.43 172.54,143.24 174.47,141.31 174.47,134.77 176.43,132.82 176.43,121.85 179.12,119.15 192.08,119.15 192.79,119.86 v2(192.79,119.89)
  BOTTOM w0.102: v2(103.29,209.89) 103.89,209.89 v1(104.17,209.61) 109.95,209.61 114.4,205.16 141.35,205.16 142.95,203.56 151.41,203.56 156.62,198.35 v2(159.18,198.35) ; v2(192.79,119.89) 192.79,118.61 196.1,115.29 196.24,115.29 199.24,112.29 199.24,108.16 198.2,107.12 198.2,106.92 198.2,106.86 198.2,106.02 198.19,105.57 198.2,105.56 198.2,104.9 198.63,104.47 198.63,102.62 197.03,101.02 197.03,96.87 197.51,96.39 197.51,92.74 198.54,91.71 198.54,89.73 198.07,89.26 198.07,80.11 198.7,79.48 198.88,79.48 200.13,78.23 200.13,75.39 201.24,74.27 v2(201.68,74.27)
VGA1_DETECT: length 15
  TOP w0.102: R1701.2 R1706.1 190.2,167.2 191.33,166.07 v1(191.33,165.47) 191.31,165.47 191.31,165.06 196.47,159.9 196.47,158.45 196.67,158.24 196.67,156.2 SB1.P48
VGA_CABLE_DET_N: length 348.9
  TOP w0.102: v2(191.52,171.04) 191.64,170.92 195.06,170.92 195.61,170.37 195.61,164.78 R1502.1 195.07,163.47 198.57,159.97 198.57,158.75 198.98,158.35 198.98,157.17 SB1.Y48 ; v2(49.4,20.45) 49.4,25.78 v2(52.63,29.01) ; v2(160.96,46.86) 160.76,47.07 160.76,63.75 164.44,67.44 164.44,104.75 167.18,107.49 167.18,109.95 172.57,115.33 172.57,131.74 170.99,133.31 170.99,139.86 168.97,141.89 168.97,142.09 168.97,142.09 168.97,142.55 168.97,147.06 164.9,151.13 164.9,164.41 164.5,164.81 163.6,165.71 163.6,176.86 v2(164.34,177.6) ; v2(58.75,10.3) EU5901.6
  BOTTOM w0.102: v2(49.4,20.45) 52.83,17.02 52.83,15.24 54.61,13.46 58.12,13.46 59.28,12.29 59.28,10.83 v2(58.75,10.3) 58.75,9.35 57.31,7.91 VGA1.4 ; v2(160.96,46.86) 159.86,46.86 156.31,43.32 156.31,36.49 150.58,30.76 132.17,30.76 131.31,29.9 127.34,29.9 127,29.57 122.12,29.57 120.87,28.32 101.91,28.32 99.19,25.6 88.72,25.6 88.24,26.09 86.08,26.09 85.5,25.5 81.84,25.5 81.18,26.16 73.56,26.16 72.9,26.82 72.11,26.82 66.5,32.44 56.54,32.44 53.11,29.01 v2(52.63,29.01) ; v2(191.52,171.04) 191.24,171.32 185.67,171.32 184.61,172.39 169.75,172.39 168.15,173.98 v1(167.51,173.98) 166.87,173.98 165.18,175.68 165.18,176.76 v2(164.34,177.6)
VIDALERT#_CPU: length 34.8
  TOP w0.102: v2(35.69,80.77) 35.66,80.8 R405.2 ; v2(59.85,97.67) 59.85,97.73 CPU1.E39
  BOTTOM w0.102: v2(59.85,97.67) 59.4,97.21 59.4,96.73 58.6,95.94 v1(58.6,95) 58.6,92.89 54.09,88.38 54.08,88.38 52.97,87.27 52.97,87.26 52.95,87.24 52.95,87.23 47.08,81.36 37.8,81.36 37.21,80.77 v2(35.69,80.77)
VIDALERT#_CPU_R: length 28.2
  TOP w0.102: R405.1 32.91,80.8 R401.2 32,79.9 v2(32,79.63) ; PR4406.2 24.26,76.03 v2(24.03,75.81) 23.62,75.39 v1(23.14,75.39) 22.93,75.18 22.66,75.18 21.01,73.54 PU4401.4
  BOTTOM w0.102: v2(24.03,75.81) 23.16,74.93 22.99,74.93 22.61,75.3 22.61,75.45 23.4,76.23 24.17,77 24.31,77 24.8,76.51 24.95,76.51 25.09,76.65 25.09,76.8 24.6,77.29 24.6,77.43 25.86,78.69 26,78.69 26.3,78.39 26.45,78.39 26.59,78.53 26.59,78.68 26.29,78.98 26.29,79.12 27.3,80.14 29.67,80.14 29.77,80.04 29.77,79.1 29.87,78.99 30.08,78.99 30.18,79.1 30.18,80.04 30.28,80.14 30.48,80.14 30.58,80.04 30.58,79.1 30.69,78.99 30.89,78.99 30.99,79.1 30.99,80.04 31.09,80.14 31.42,80.14 31.93,79.63 v2(32,79.63)
VIDSCK_CPU: length 13.5
  TOP w0.102: CPU1.E38 v2(60.74,97.71)
  BOTTOM w0.102: R407.2 54.16,87.92 59.18,92.94 v1(59.18,93.85) 59.18,96.01 59.53,96.36 60.01,96.36 60.26,96.61 60.26,97.22 v2(60.74,97.71)
VIDSCK_CPU_R: length 38.3
  TOP w0.102: PR4411.2 23.24,78.42 PR4405.2 23.3,81.6 23.85,82.14 27.41,82.14 v2(27.76,81.79)
  BOTTOM w0.102: v2(27.76,81.79) 28.14,81.41 33.33,81.41 v1(33.94,80.79) 34.39,80.34 37.29,80.34 37.95,81 47.35,81 R407.1
VIDSOUT_CPU: length 14.1
  TOP w0.102: CPU1.E40 v2(58.87,97.67)
  BOTTOM w0.102: v2(58.87,97.67) 58.87,97.66 58.42,97.21 58.41,97.21 58.04,96.83 v1(58.04,96.27) 58.01,96.24 58.01,92.94 R408.2
VIDSOUT_CPU_R: length 31.9
  TOP w0.102: PR4404.2 PR4410.2 25.55,79.57 v2(25.25,79.26) ; v2(35.69,81.58) 35.33,81.94 R403.2 31.98,81.01 v2(31.98,80.7)
  BOTTOM w0.102: v2(35.69,81.58) 36.58,81.58 36.7,81.71 46.79,81.71 R408.1 ; v2(31.98,80.7) 31.75,80.92 26.91,80.92 26.38,80.39 v1(26.16,80.39) 26.16,80.18 v2(25.25,79.26)
VPP_EN: length 30.5
  TOP w0.102: PR5204.1 141.58,188.82 140.67,189.74 140.67,202.11 144.27,205.71 150.37,205.71 v1(150.5,205.59) 153.12,205.59 C4009.1 R4019.2
VPP_EN_CR: length 4.4
  TOP w0.102: Q4001.C 150.69,203.33 R4017.2 151.71,204.14 v1(151.89,203.96) R4019.1
VPP_EN_DDR4: length 9.9
  TOP w0.102: R4018.2 146.56,198.55 v1(146.81,198.8) 146.81,201.93 147.32,202.44 147.53,202.44 Q4002.3 147.56,201.94 148.09,201.41 148.46,201.41 148.84,201.03 148.84,200.64 Q4002.6 150.5,200.63 Q4001.B
VR_ENABLE: length 312.5
  TOP w0.102: U4005.3 97.98,23.75 R4006.2 R4005.2 99.21,23.66 v2(99.21,26.3) 98.74,26.77 R4007.1 ; D4303.1 211.45,216.48 210.64,216.48 209.8,215.64 198.61,215.64 195.17,212.21 195.17,207.77 194.44,207.04 v2(194.44,205.87) ; v2(159.21,47.13) 159.11,47.24 159.11,64.06 163.14,68.1 163.14,105.29 165.79,107.93 165.79,110.38 171.2,115.79 171.2,131.27 169.7,132.77 169.7,139.33 167.67,141.36 167.67,146.51 167.61,146.57 167.61,146.58 163.6,150.59 163.6,163.88 161.9,165.58 161.9,165.83 161.9,182.85 v2(162.31,183.26) ; U4002.6 83.45,22.21 83.13,22.53 83.13,24.55 v2(84.75,26.17)
  BOTTOM w0.102: v2(84.75,26.17) 85.18,26.59 88.26,26.59 88.69,26.16 97.31,26.16 97.61,26.47 99.04,26.47 v2(99.21,26.3) 99.46,26.3 101.78,28.62 120.64,28.62 121.89,29.87 126.88,29.87 127.21,30.2 131.18,30.2 132.04,31.06 150.46,31.06 155.96,36.56 155.96,43.88 v2(159.21,47.13) ; v2(194.44,205.87) 194.44,205.23 193.84,204.63 v1(192.66,204.63) 189.26,204.63 170.05,185.42 167.69,185.42 165.53,183.26 v2(162.31,183.26)
VR_ENABLE_IMVP: length 135.1
  TOP w0.102: v2(23.9,57.45) 22.86,56.41 v2(17.17,56.41) ; PU4401.2 21.81,73.31 22.54,74.04 v2(23.11,74.04) ; v2(97.66,30.61) 97.85,30.42 R4007.2 97.98,28.32 U4005.4
  BOTTOM w0.102: v2(97.66,30.61) 97.28,30.99 69.69,30.99 67.25,33.43 56.13,33.43 54.15,31.45 22.11,31.45 22.11,31.44 21.35,31.44 17.12,35.68 17.12,54.97 16.79,55.3 16.79,56.03 v2(17.17,56.41) ; v2(23.11,74.04) 23.11,73.66 23.6,73.18 v1(23.6,72.52) 23.6,59.31 23.9,59 v2(23.9,57.45)
VR_READY: length 179.1
  TOP w0.102: v2(78.23,21.36) 78.97,20.62 R4015.1 ; v2(93.73,22.1) 93.62,22.2 R4013.2 93.2,22.83 U4008.4 ; v2(197.74,72.36) 197.74,72.64 198.11,73.01 Q2405.1
  BOTTOM w0.102: v2(78.23,21.36) 83.44,21.36 84.4,22.33 86.42,22.33 86.73,22.02 93.65,22.02 v2(93.73,22.1) 94.21,22.1 95.07,22.96 v1(98.32,22.96) 111.25,22.96 113.38,25.09 123.29,25.09 123.9,25.7 128.6,25.7 128.93,26.03 140.08,26.03 142.32,23.8 146.99,23.8 150.54,20.24 157.53,20.24 158.14,19.63 160.22,19.63 160.5,19.36 160.51,19.36 176.33,19.36 177.16,18.53 185.74,18.53 189.51,22.3 189.51,24.54 190.02,25.05 190.02,48.85 192.1,50.93 192.1,62.67 192.07,62.69 192.07,69.42 195.01,72.36 v2(197.74,72.36)
VR_READY_A: length 2.7
  TOP w0.102: U4009.1 80.15,22.87 R4011.2 81.05,21.72 v1(81.15,21.62)
VR_READY_B: length 6.6
  TOP w0.102: v1(80.16,19.56) 80.18,19.57 R4015.2 81.15,20.62 81.71,21.18 81.71,23.62 81.46,23.88 U4009.2
VR_READY_IMVP: length 138.3
  TOP w0.102: v2(21.8,75.73) 21.1,75.03 20.78,75.03 20.21,74.47 PU4401.6 ; U4008.3 91.32,22.56 R4013.1 89.8,22.2 U4003.D 89.52,24.36 R4003.2 89.56,24.87 89.66,24.97 v2(89.66,28.91) ; v2(23.32,58.01) 22.48,57.18 v2(17.12,57.18)
  BOTTOM w0.102: v2(17.12,57.18) 16.43,56.49 16.43,55.07 16.76,54.74 16.76,35.53 21.21,31.09 22.26,31.09 54.3,31.09 56.28,33.07 67.1,33.07 71.14,29.03 89.53,29.03 v2(89.66,28.91) ; v2(21.8,75.73) v1(21.8,74.55) 21.8,73.19 23.24,71.75 23.24,59 23.32,58.93 v2(23.32,58.01)
VTT_EN: length 4.2
  TOP w0.102: R5001.2 48.61,185.93 v1(47.37,185.93) 46.55,185.93 C4013.1 R4026.2
VTT_EN_CR: length 2.4
  TOP w0.102: v1(43.56,188.22) 44.2,187.59 R4025.2 R4026.1
W_DISABLE#1: length 6.4
  TOP w0.102: R6311.2 214.43,202.16 v1(214.16,201.89) 213.77,201.5 NGFF1.56
W_DISABLE#2: length 6.5
  TOP w0.102: R6312.2 215.33,201.07 214.81,201.07 v1(214.33,200.58) 213.91,201 NGFF1.54
WAKE_M2_SSD_N: length 101.7
  TOP w0.102: v2(192.89,173.86) 192.96,173.79 195.55,173.79 196.32,173.02 198.83,173.02 202.23,169.62 202.23,167.54 201.85,167.16 201.85,164.92 202.25,164.53 R1503.1 202.31,162.79 203.8,161.3 203.8,157.99 204.86,156.92 204.86,156.04 205.09,155.81 SB1.AL47 ; v2(169.6,175.92) 169.49,175.82 169.49,170.63 170.48,169.64 170.48,153.73 v2(172.8,151.42) ; R6203.2 v2(152.32,142.24)
  BOTTOM w0.102: v2(169.6,175.92) 169.85,175.67 186.79,175.67 188.35,174.1 v1(188.98,174.1) 192.65,174.1 v2(192.89,173.86) ; v2(172.8,151.42) 172.5,151.42 169.47,148.39 161.39,148.39 155.24,142.24 v2(152.32,142.24)
WLAN_PEDET: length 59.2
  TOP w0.102: v2(212.7,194.74) 211.22,194.74 210.99,194.51 208,194.51 204.98,197.54 204.98,198.2 202.92,200.25 NGFF1.51 ; SB1.AR42 207.46,153.8 207.59,153.8 207.61,153.81 v2(207.61,153.81) ; v2(208.86,162.92) 208.99,163.04 208.99,163.59 R1709.2
  BOTTOM w0.102: v2(207.61,153.81) 207.47,153.96 207.47,154.87 207.62,155.02 207.62,160.48 208.86,161.72 v2(208.86,162.92) 208.86,166.09 209.63,166.85 209.63,167.77 210.11,168.25 210.11,171.31 209.98,171.57 209.98,173.14 210.06,173.22 210.06,183.31 210.3,183.55 210.3,184.01 v1(212.34,186.05) 211.94,186.46 211.94,192.18 212.75,192.99 212.75,194.69 v2(212.7,194.74)
WLAN_USB_DET: length 36.6
  TOP w0.102: SB1.AP48 207.19,156.66 207.19,159.72 204.33,162.57 R1901.1 204.83,163.18 204.83,167.08 204.33,167.57 v2(204.05,167.57) ; NGFF1.1 203.32,187.75 203.4,187.83 v2(203.71,187.83)
  BOTTOM w0.102: v2(203.71,187.83) v1(203.71,186.18) 203.77,186.12 203.77,172.16 203.91,172.02 203.91,172.02 204.44,171.49 204.44,167.85 204.17,167.57 v2(204.05,167.57)
XCLK_RBIAS: length 6.5
  TOP w0.102: R1802.2 195.82,129.3 v1(195.94,129.41) 195.94,129.9 197.26,131.22 197.26,133.84 SB1.T3
XDP_PCUDEBUG_3: length 47.1
  TOP w0.102: R423.2 124.82,78.29 123.32,76.79 123.32,67.69 125.67,65.34 128.66,65.34 129.76,64.25 131.99,64.25 v1(132.03,64.21) 132.7,64.21 135,61.91 138.13,61.91 138.52,62.29 143.32,62.29 v2(143.92,62.89)
  BOTTOM w0.102: XDP1.1 144.92,64.73 145.39,64.26 149.29,64.26 R9904.2 149.34,63.82 148.72,63.2 144.22,63.2 v2(143.92,62.89)
XDP_PRS: length 2.8
  TOP w0.102: v1(129.29,71.93) 129.29,71.14 v2(129.36,71.06) 129.41,71.01 130.18,70.99
  BOTTOM w0.102: XDP1.60 v2(129.36,71.06)
XDP_PWR_DEBUG: length 6.2
  TOP w0.102: v2(133.48,62.2) 133.51,62.2 133.6,62.1 R9913.2 R9912.2 132.59,60.48 v1(132.66,60.4)
  BOTTOM w0.102: XDP1.45 133.92,62.63 v2(133.48,62.2)
XDP_PWRGD: length 7.4
  TOP w0.102: R9906.2 135.51,61.32 v2(134.75,60.55)
  BOTTOM w0.102: R9907.2 R9908.2 ; R9908.2 135.42,61.94 v1(135.42,63.02) XDP1.39 ; R9908.2 134.75,60.83 v2(134.75,60.55)
XDP_VR_READY: length 10.8
  TOP w0.102: R9903.2 132.8,62.48 v2(133.31,62.99) ; R9922.1 132.02,57.34 v2(132.08,57.4)
  BOTTOM w0.102: v2(132.08,57.4) 131.72,57.76 v1(131.72,58.8) 131.72,60.6 R9905.2 R9903.2 132.8,62.48 v2(133.31,62.99) 133.42,63.1 XDP1.47
XTAL_24M_PCH_IN: length 12.7
  TOP w0.102: v2(198.7,137.35) 198.68,137.37 198.68,137.58 SB1.U10 ; v2(199.39,130.28) 199.07,129.96 R1812.1 199.07,128.73 C1802.1 199.2,127.76 X1801.3
  BOTTOM w0.102: v2(198.7,137.35) 198.78,137.27 198.78,135.64 200.57,133.85 200.57,131.1 v1(200.28,130.81) 199.75,130.28 v2(199.39,130.28)
XTAL_24M_PCH_OUT: length 15.1
  TOP w0.102: X1801.1 198.37,126.43 198.37,128.41 C1801.1 R1812.2 v2(198.18,130.3) ; SB1.U9 198.2,137.36 v2(197.95,137.61)
  BOTTOM w0.102: v2(198.18,130.3) 198.63,130.3 200.08,131.75 200.08,133.65 197.94,135.79 v1(197.94,136.53) 197.94,137.6 v2(197.95,137.61)

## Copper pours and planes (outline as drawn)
1V_CPU_CORE on TOP: 68.71,118.69 68.58,118.82 68.58,118.83 68.5,118.9 68.5,119.66 69.09,120.25 69.16,120.27 69.24,120.3 69.75,120.3 69.97,120.25 70.18,120.32 71.37,120.32 71.5,120.19 71.86,120.19 71.92,120.26 72.59,120.26 72.8,120.26 72.99,120.37 73.2,120.37 73.33,120.23 73.33,119.03 73,118.69
1V_CPU_CORE on TOP: outline of 165 points within 42.55,59.31 104.9,121.23 ; 12 cut-outs
1V_CPU_CORE on BOTTOM: outline of 97 points within 47.42,64.74 105.03,120.09
1V_CPU_CORE on BOTTOM: 46.28,59.64 46.02,59.89 46.02,60.93 45.82,61.14 43.56,61.14 42.27,62.43 42.27,64.01 42.88,64.62 49.68,64.62 49.94,64.36 49.94,60.86 49.92,60.85 49.92,60.26 49.3,59.64
1V_CPU_CORE on L2VCC: 49.72,57.61 48.72,58.61 43.89,58.61 41.59,60.91 41.59,63.56 42.24,63.56 43.75,65.07 43.75,70.28 45.53,72.06 45.53,79.04 46.05,79.57 52.5,79.57 52.9,79.17 52.9,71.45 49.72,68.28
1V_CPU_GT on TOP: 31.37,83.44 26.67,88.14 26.67,92.57 24.75,94.49 24.75,112.29 30.52,118.06 36.7,118.06 44.02,110.74 55.79,110.74 55.95,110.9 58.35,110.9 58.83,111.38 58.83,112.39 58.95,112.52 59.84,112.52 60.2,112.88 60.2,113.47 60.4,113.67 64.44,113.67 65.26,114.5 65.49,114.5 65.67,114.32 65.97,114.32 66.56,114.9 66.56,116.44 67.49,117.37 70.13,117.37 70.26,117.25 70.26,113.53 70.21,113.48 68.99,113.48 68.87,113.35 68.87,111.83 68.99,111.7 74.71,111.7 74.84,111.57 74.84,110.05 74.71,109.92 68.99,109.92 68.87,109.8 68.87,108.4 69.12,108.15 72.55,108.15 72.68,108.02 72.68,106.49 72.55,106.37 69.12,106.37 68.23,105.48 67.6,105.48 67.58,105.49 66.95,105.49 63.29,101.84 63.29,101.83 63.09,101.63 63.09,101.24 63.29,101.04 63.29,100 63.11,99.82 61.21,99.82 60.96,99.57 60.96,99.54 60.83,99.42 59.1,99.42 58.83,99.14 57.82,99.14 55.13,96.46 50.2,96.46 49.18,95.45 49.18,90.49 42.13,83.44 ; 2 cut-outs
1V_CPU_GT on BOTTOM: 49.18,95.45 49.18,90.49 43.91,85.22 32.67,85.22 31.02,86.87 31.02,87.19 26.21,92 26.21,92.02 25.63,92.61 25.63,95.73 26.54,96.65 26.54,98.3 26.42,98.42 25.91,98.42 25.53,98.81 25.53,109.32 25.76,109.55 26.49,109.55 26.8,109.86 26.8,111.35 26.67,111.48 25.5,111.48 25.17,111.81 25.17,112.71 30.57,118.11 34.42,118.11 42.9,109.63 57.61,109.63 59.08,111.1 59.08,112.15 59.75,112.15 60.5,112.91 63.55,112.91 63.56,112.92 64.61,112.92 66.19,114.5 67.09,114.5 68.11,115.51 71.53,115.51 71.98,115.07 71.98,111.76 72.3,111.45 73.19,111.45 73.31,111.32 73.31,110.3 73.19,110.18 71.79,110.18 71.41,109.8 71.41,106.75 70.9,106.24 67.77,106.24 62.87,101.34 62.87,101.34 62.87,100.33 62.7,100.17 58.96,100.17 58.71,99.92 58.63,99.92 55.18,96.46 50.2,96.46
1V_PCH_SB on TOP: 189.43,153.92 187.22,156.13 186.69,156.13 186.51,156.31 186.51,157.28 186.56,157.33 187.71,157.33 190.14,154.89 190.14,153.97 190.09,153.92 ; 1 cut-out
1V_PCH_SB on TOP: 189.05,130.56 188.85,130.76 188.85,131.55 190.66,133.36 190.66,134.37 190.79,134.5 190.91,134.5 191.12,134.3 191.12,134 191.25,133.87 191.55,133.87 191.73,133.68 191.9,133.68 192.23,133.36 192.31,133.36 192.44,133.23 192.44,133.1 189.89,130.56
1V_PCH_SB on TOP: 220.19,116.48 219.91,116.76 219.91,118.29 219.99,118.36 221.46,118.36 221.84,118.75 221.84,120.37 220.98,121.23 219.86,121.23 219.66,121.44 219.66,122.83 219.74,122.91 220.98,122.91 221.67,123.6 221.67,124.97 222,125.3 223.55,125.3 223.7,125.45 223.7,126.34 223.75,126.39 225.09,126.39 225.3,126.19 225.3,116.74 225.04,116.48 ; 8 cut-outs
1V_PCH_SB on TOP: 198.5,141.6 198.37,141.73 198.37,142.24 198.62,142.49 198.75,142.49 198.88,142.62 198.88,143.58 198.74,143.72 198.74,144.51 197.95,145.3 197.95,147.68 198.53,148.27 199.59,148.27 200.05,147.8 201.17,147.8 201.32,147.96 201.32,148.22 201.37,148.27 203.39,148.27 203.45,148.21 203.45,148.08 203.41,148.04 203.41,148.04 202.81,147.44 202.81,144.15 202.56,143.89 201.67,143.89 201.42,143.64 201.42,143.38 201.67,143.13 201.8,143.13 201.86,143.07 201.86,142.56 201.67,142.37 200.88,142.37 200.53,142.72 200.53,142.88 200.4,143 200.02,143 199.77,142.75 199.77,141.73 199.64,141.6
1V_PCH_SB on TOP: 214.25,128.4 213.87,128.78 213.87,129.54 214.5,130.18 215.26,130.18 215.39,130.05 215.39,128.65 215.14,128.4 ; 1 cut-out
1V_PCH_SB on TOP: 189.36,122.43 188.47,123.32 188.47,123.93 188.67,124.13 191.21,124.13 191.26,124.08 191.26,122.56 191.13,122.43 ; 2 cut-outs
1V_PCH_SB on BOTTOM: 223.65,126.06 224.28,126.7 225.09,126.7 225.32,126.47 225.32,116.94 224.89,116.51 223.85,116.51 223.65,116.71
1V_PCH_SB on BOTTOM: 188.82,124.38 188.82,131.14 189.08,131.39 190.2,131.39 190.37,131.22 190.37,123.9 189.46,122.99 188.82,122.99 188.65,123.16 188.65,124.21
1V_PCH_SB on L2VCC: 203.15,115.63 201.23,117.55 201.23,120.73 200.87,121.09 194.64,121.09 194.26,121.48 189.82,121.48 189.04,122.25 189.04,124.38 189.18,124.52 190.04,124.52 192.07,122.49 199.34,122.49 201.61,124.76 201.61,133.81 199.58,135.84 199.58,138.39 198.87,138.96 197.29,140.17 197.29,148.03 196.15,149.18 196.15,150.19 195.28,151.07 194.26,151.07 193.63,151.7 192.86,151.7 192.6,151.97 192.6,152.48 191.59,153.48 190.2,153.48 188.53,155.15 188.53,155.5 188.55,155.51 189.29,155.51 191.09,153.96 192.45,153.99 194.74,151.7 196.9,151.7 198.18,150.42 198.18,149.02 198.93,148.27 204.26,148.27 206.44,146.1 206.44,140.89 206.93,140.4 209.47,140.4 209.74,140.13 209.74,131.62 211.38,129.98 213.66,129.98 216.2,127.44 216.96,127.44 217.35,127.06 224.2,127.06 224.85,126.41 224.85,116.03 224.46,115.63
1V_VCCA_XTAL on TOP: 195.55,130.07 195.28,130.35 195.28,130.84 196.41,131.97 196.41,134.52 196.49,134.59 196.79,134.59 196.87,134.52 196.87,134.29 197.07,134.09 197.07,131.44 195.71,130.07
1V_VCCAMPHYPLL on TOP: 191.11,156.65 191.03,156.73 191.03,157.06 190.86,157.23 188.03,157.23 187.68,157.58 186.56,157.58 186.21,157.23 185.62,157.23 185.55,157.3 185.55,158.88 185.37,159.05 185.37,159.99 185.45,160.07 187.53,160.07 187.81,159.79 187.81,159.08 188.14,158.75 191.11,158.75 192.66,157.2 192.66,156.91 192.4,156.65 ; 4 cut-outs
5V_AUD_S5 on TOP: 74.42,231.39 73.91,231.9 73.91,233.43 73.41,233.93 70.99,233.93 70.87,233.81 66.17,233.81 66.17,235.33 66.55,235.71 71.12,235.71 71.5,236.09 75.82,236.09 76.12,235.79 76.12,231.52 76.02,231.42 75.84,231.42 75.82,231.39 ; 7 cut-outs
5V_DISPLAY_S0 on TOP: 43.81,12.06 43.43,12.45 43.43,13.97 43.69,14.22 45.09,14.22 45.34,14.48 45.34,17.14 45.59,17.4 47.24,17.4 47.5,17.14 47.5,12.57 46.99,12.06
5V_HDMI_CONN on TOP: 24.38,5.08 23.11,6.35 23.11,8.13 23.5,8.51 26.29,8.51 27.56,7.24 38.48,7.24 39.12,7.87 39.12,10.67 39.24,10.79 41.15,10.79 41.53,10.41 41.53,6.22 40.39,5.08 ; 2 cut-outs
5V_S0 on TOP: 91.69,215.65 91.57,215.77 91.57,218.19 92.2,218.82 92.2,224.92 93.22,225.93 108.08,225.93 114.55,232.41 155.45,232.41 158.12,229.74 158.12,225.55 160.53,223.14 166.75,223.14 169.16,225.55 169.16,230.76 170.56,232.16 184.66,232.16 185.29,231.52 185.29,224.79 185.04,224.54 183.26,224.54 182.88,224.92 182.88,227.84 182.5,228.22 177.67,228.22 176.28,226.82 175.13,226.82 174.88,227.08 174.88,228.85 174.62,229.11 172.44,229.11 171.92,228.59 171.92,223.84 168.2,220.12 168.15,220.12 167.61,219.58 159.08,219.58 152.1,226.57 148.21,226.57 147.7,226.06 147.7,224.03 147.45,223.77 145.41,223.77 145.03,224.16 145.03,226.31 144.02,227.33 139.57,227.33 138.18,225.93 137.41,225.93 136.91,226.44 136.91,228.22 136.14,228.98 117.6,228.98 109.09,220.47 101.09,220.47 98.3,217.68 95.63,217.68 94.36,216.41 93.73,216.41 92.96,215.65
5V_S0 on TOP: 221.49,33.15 219.84,34.8 219.84,39.5 220.85,40.51 230.76,40.51 231.27,40.01 231.27,36.96 227.46,33.15 ; 2 cut-outs
5V_S0 on TOP: 218.06,88.27 217.68,88.65 217.68,93.6 218.69,94.61 223.9,94.61 224.79,95.5 228.09,95.5 229.24,94.36 233.43,94.36 233.81,93.98 233.81,92.08 233.43,91.69 226.95,91.69 226.31,91.06 226.31,90.42 224.92,89.03 223.77,89.03 223.39,89.41 223.39,90.04 222.25,91.19 220.98,91.19 220.98,89.28 219.96,88.27 ; 2 cut-outs
5V_S0 on TOP: 218.39,17.25 217.53,18.11 217.53,26.95 219.05,28.47 225.32,28.47 230.89,34.04 234.95,34.04 235.2,33.78 235.2,20.09 234.31,19.2 229.36,19.2 228.57,18.41 225.81,18.41 225.02,19.2 223.29,19.2 222.76,18.67 221.13,18.67 219.71,17.25 ; 2 cut-outs
5V_S0 on TOP: 42.93,7.87 42.67,8.13 42.67,9.65 42.42,9.91 41.87,9.91 41.74,10.03 41.74,10.62 41.31,11.05 38.99,11.05 38.48,11.56 38.48,12.57 38.73,12.83 42.55,12.83 44.83,10.54 44.83,8.13 44.58,7.87 ; 1 cut-out
5V_S0 on BOTTOM: 228.6,32.26 228.35,32.51 228.35,37.21 228.98,37.85 231.27,37.85 231.39,37.72 231.39,32.89 230.76,32.26
5V_S0 on L3: 144.78,227.33 158.62,227.33 159.51,226.44 179.04,226.44 179.53,225.96 179.53,222.38 180.39,221.51 182.4,221.51 182.63,221.74 182.63,227.08 182.88,227.33 189.23,227.33 197.49,219.07 221.49,219.07 232.66,207.9 232.66,172.59 230.38,170.31 228.22,170.31 225.81,167.89 225.81,162.56 227.58,160.78 227.58,159.51 226.95,158.88 226.95,150.24 227.84,149.35 227.84,142.62 226.44,141.22 226.44,133.73 225.55,132.84 225.55,131.06 220.85,126.36 220.85,109.6 221.36,109.09 234.65,109.09 234.82,108.92 234.82,30.07 234.29,29.54 231.34,29.54 228.85,32.03 228.85,37.85 231.9,40.89 231.9,105.16 230.45,106.6 220.65,106.6 218.85,108.41 218.85,115.11 217.83,116.13 217.83,117.02 217.04,117.81 217.04,125.68 220,128.64 220,130.09 221.49,131.57 221.49,135.89 223.9,138.3 223.9,160.02 221.74,162.18 221.74,169.42 223.9,171.58 223.9,206.38 213.74,216.53 146.69,216.53 144.15,219.07 144.15,226.69
5V_S5 on TOP: 111,16.76 110.62,17.14 110.62,20.7 112.27,20.7 112.52,20.45 112.52,17.14 112.14,16.76 ; 2 cut-outs
5V_S5 on TOP: 76.83,231.39 76.45,231.78 76.45,232.66 76.96,233.17 78.36,233.17 78.61,232.92 78.61,231.9 78.11,231.39 ; 2 cut-outs
5V_S5 on TOP: 83.69,222.38 83.44,222.63 83.44,224.03 86.36,226.95 86.36,229.24 87.25,230.12 89.92,230.12 91.06,231.27 91.06,233.55 91.19,233.68 92.46,233.68 92.58,233.55 92.58,230.12 92.14,229.68 92.14,228.66 88.52,225.04 88.52,222.63 88.27,222.38 ; 2 cut-outs
5V_S5 on TOP: 92.2,16.26 92.08,16.38 92.08,19.68 92.58,20.19 96.52,20.19 96.9,19.81 96.9,17.65 96.52,17.27 95.5,17.27 94.49,16.26 ; 1 cut-out
5V_S5 on TOP: 11.05,194.69 9.91,195.83 9.91,210.82 20.07,220.98 66.07,220.98 66.67,221.59 80.77,221.59 81.38,220.98 89.79,220.98 90.17,220.6 90.17,218.01 90.83,217.35 90.83,216.18 89.74,216.18 89.38,216.53 88.75,216.53 88.62,216.41 86.54,216.41 85.01,217.93 23.62,217.93 15.75,210.06 15.75,206.5 16.13,206.12 16.13,194.82 16,194.69 ; 2 cut-outs
5V_S5 on BOTTOM: 77.47,232.28 77.09,232.66 77.09,233.43 77.47,233.81 92.08,233.81 92.2,233.68 92.2,232.41 92.08,232.28
5V_S5 on BOTTOM: 74.93,15.11 63.75,26.29 62.23,26.29 58.65,22.71 39.4,22.71 37.08,25.02 30.2,25.02 28.57,26.64 24.26,26.64 23.88,27.03 23.88,29.21 24.26,29.59 29.72,29.59 31.43,27.88 39.32,27.88 41.24,25.96 53.98,25.96 55.88,27.86 55.88,27.88 57.28,27.88 58.99,29.59 64.01,29.59 76.07,17.53 91.69,17.53 92.33,18.16 95.5,18.16 95.89,17.78 95.89,15.62 95.38,15.11
5V_S5 on BOTTOM: 11.43,194.44 9.78,196.09 9.78,209.93 20.32,220.47 80.9,220.47 84.33,223.9 88.9,223.9 89.15,223.65 89.15,214.76 89.03,214.63 87.5,214.63 87.25,214.88 69.85,214.88 68.83,213.87 55.63,213.87 54.36,215.14 52.96,215.14 51.69,213.87 38.86,213.87 38.35,214.38 22.99,214.38 15.88,207.26 15.88,194.94 15.37,194.44
5V_S5 on L2VCC: 22.29,28.26 22.29,31.32 21.29,32.32 18.75,32.32 17.59,33.48 17.59,37.54 1.71,53.42 1.71,203.88 6.56,208.72 15.16,208.72 15.43,208.46 15.43,195.28 15.03,194.88 13.51,194.88 6.54,187.91 6.54,165.43 4.64,163.53 4.64,156.39 6.41,154.61 6.41,81.84 6.91,81.34 12.24,81.34 12.26,81.33 12.26,80.6 12.11,80.45 9.07,80.45 7.81,79.2 7.81,63.04 16.94,53.91 24.94,53.91 32.32,46.53 32.32,45.28 28.89,45.28 28.89,31.83 27.24,30.18 27.24,28.53 26.97,28.26
5V_USB_FRONT on TOP: 87.25,230.89 87.25,233.3 87.5,233.55 87.5,236.09 86.74,236.85 85.09,236.85 84.71,237.24 84.71,239.52 85.6,240.41 90.42,240.41 90.81,240.03 90.81,231.52 90.17,230.89 ; 2 cut-outs
5V_USB_FRONT on BOTTOM: 88.52,235.08 86.74,236.85 84.58,236.85 84.33,237.11 84.33,241.05 85.47,242.19 91.77,242.19 92.96,243.38 92.96,244.14 92.76,244.35 90.93,244.35 90.3,244.98 90.3,246.38 91.06,247.14 93.6,247.14 97.87,242.87 113.54,242.87 113.87,243.21 113.87,244.14 113.54,244.47 111.76,244.47 110.87,245.36 110.87,247.14 111.89,248.16 113.41,248.16 116.08,245.49 116.08,241.55 114.68,240.16 99.82,240.16 94.74,235.08
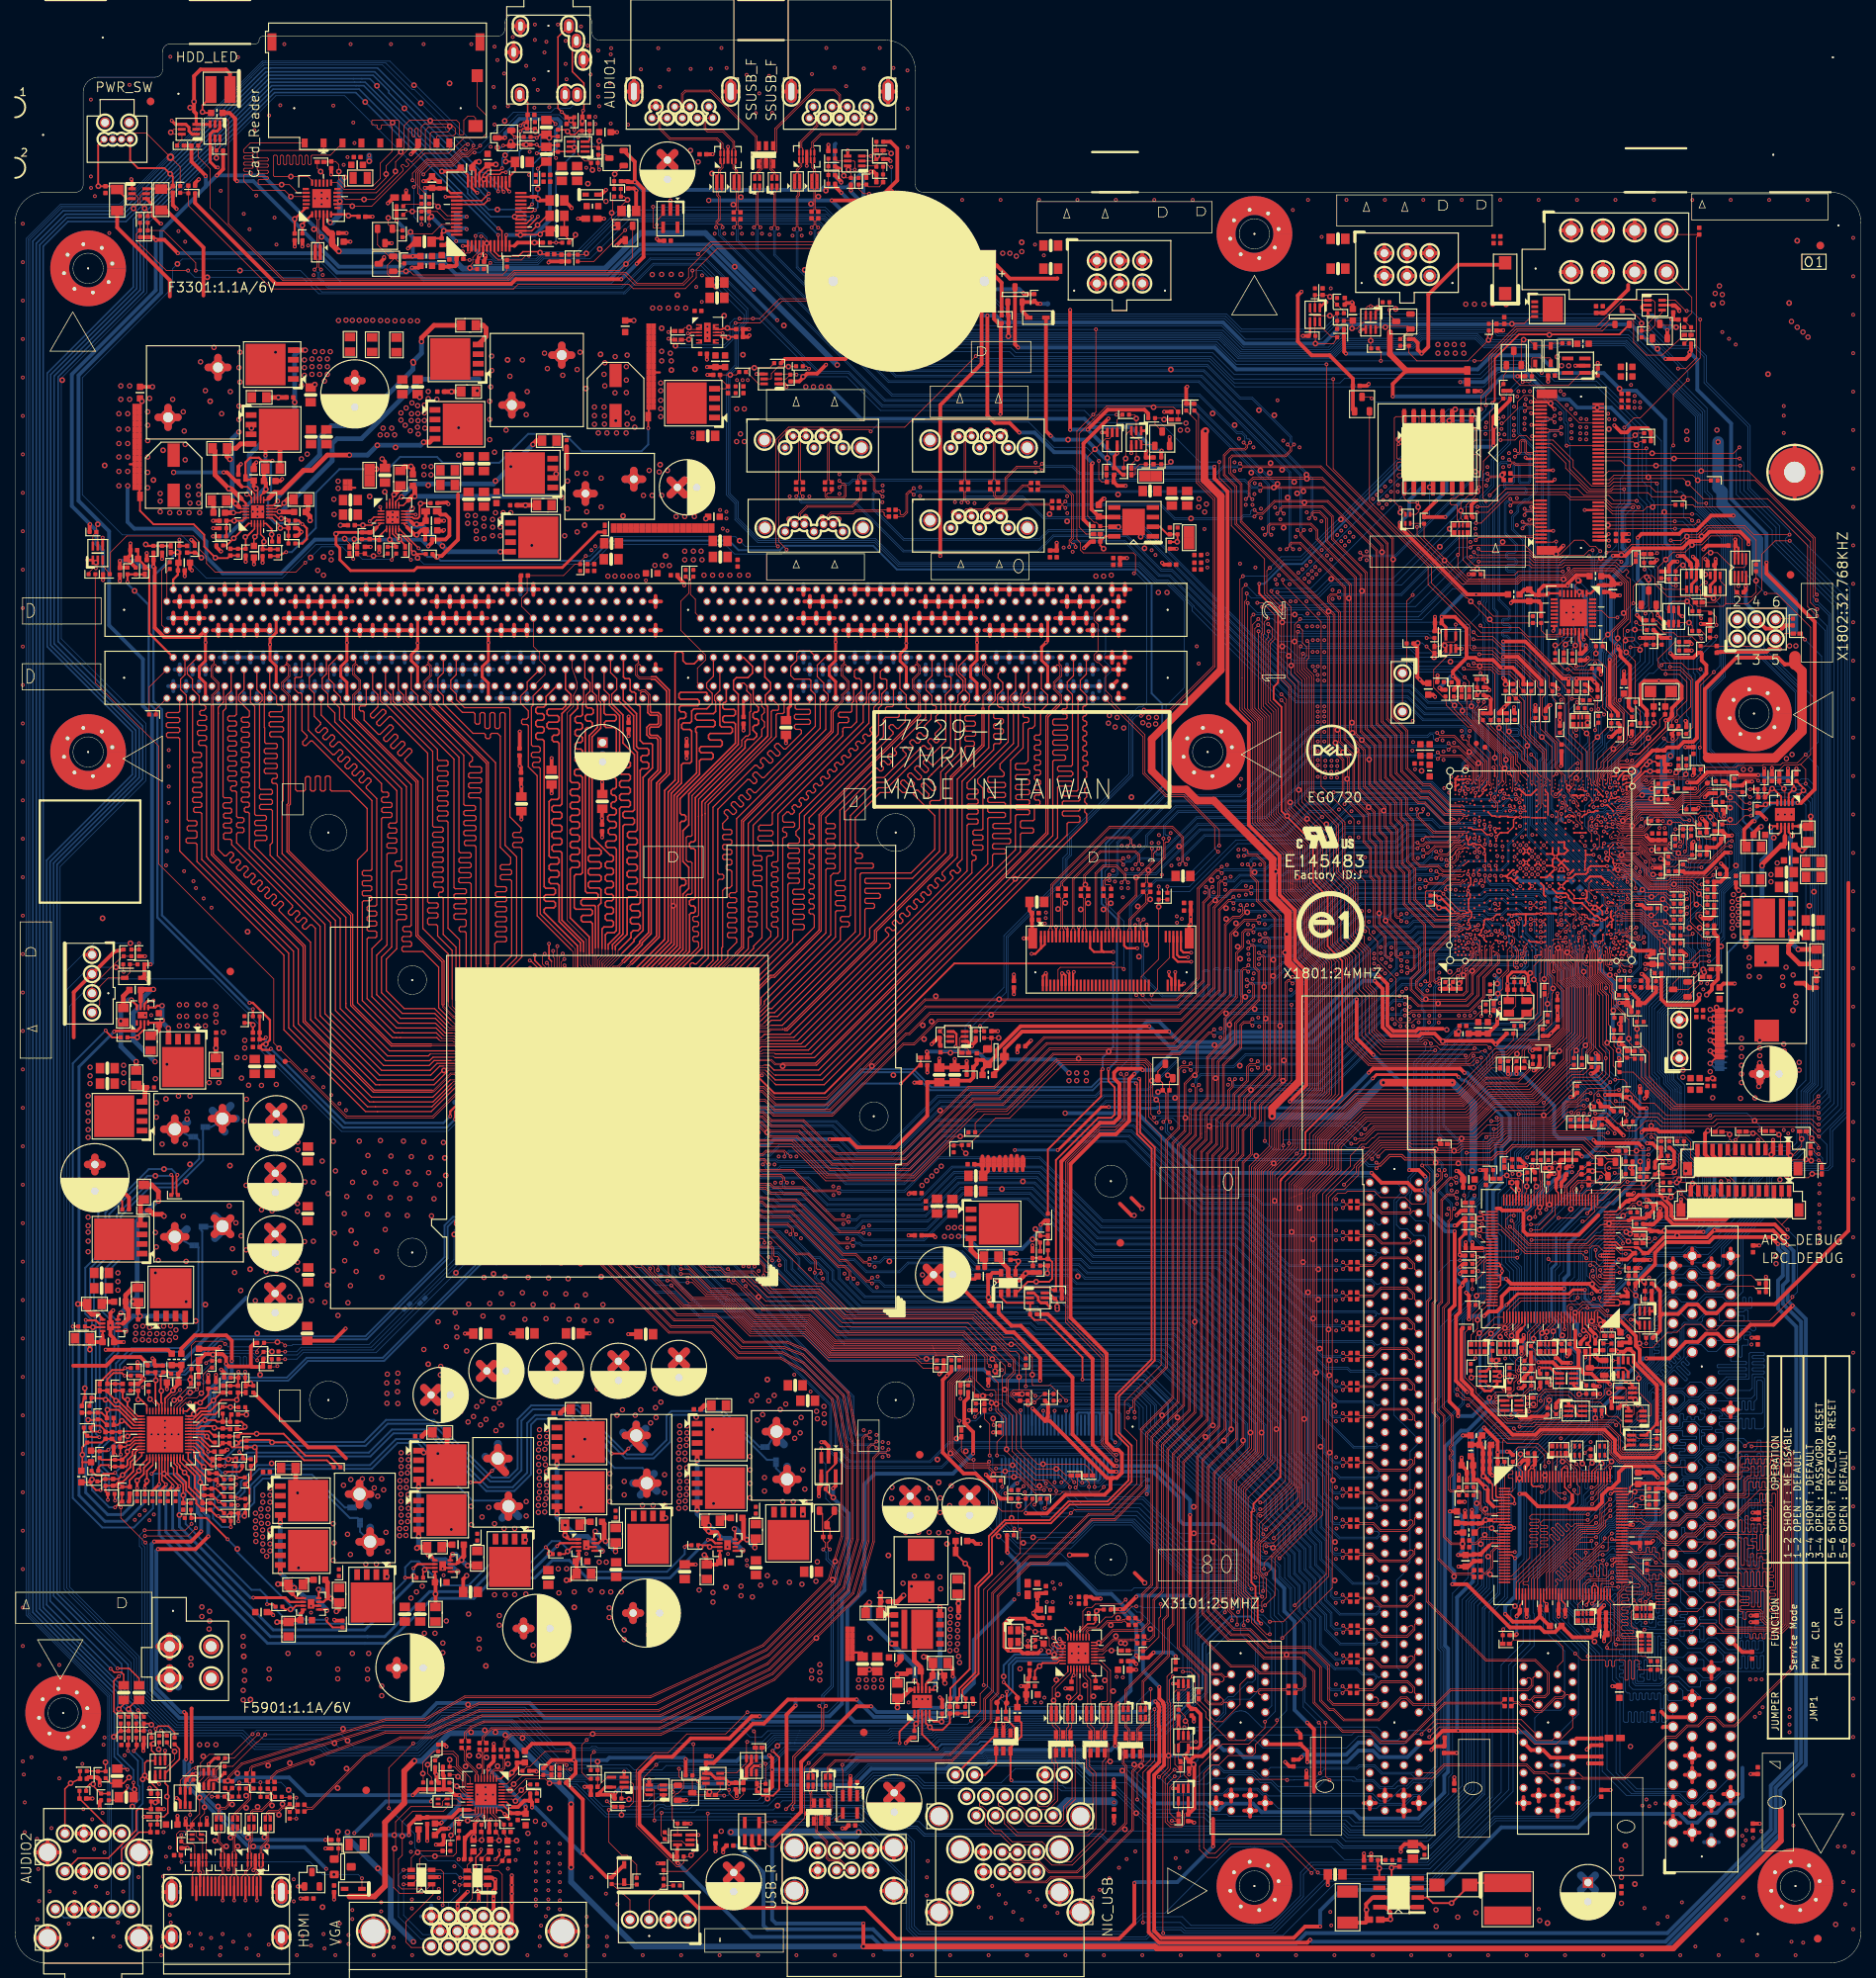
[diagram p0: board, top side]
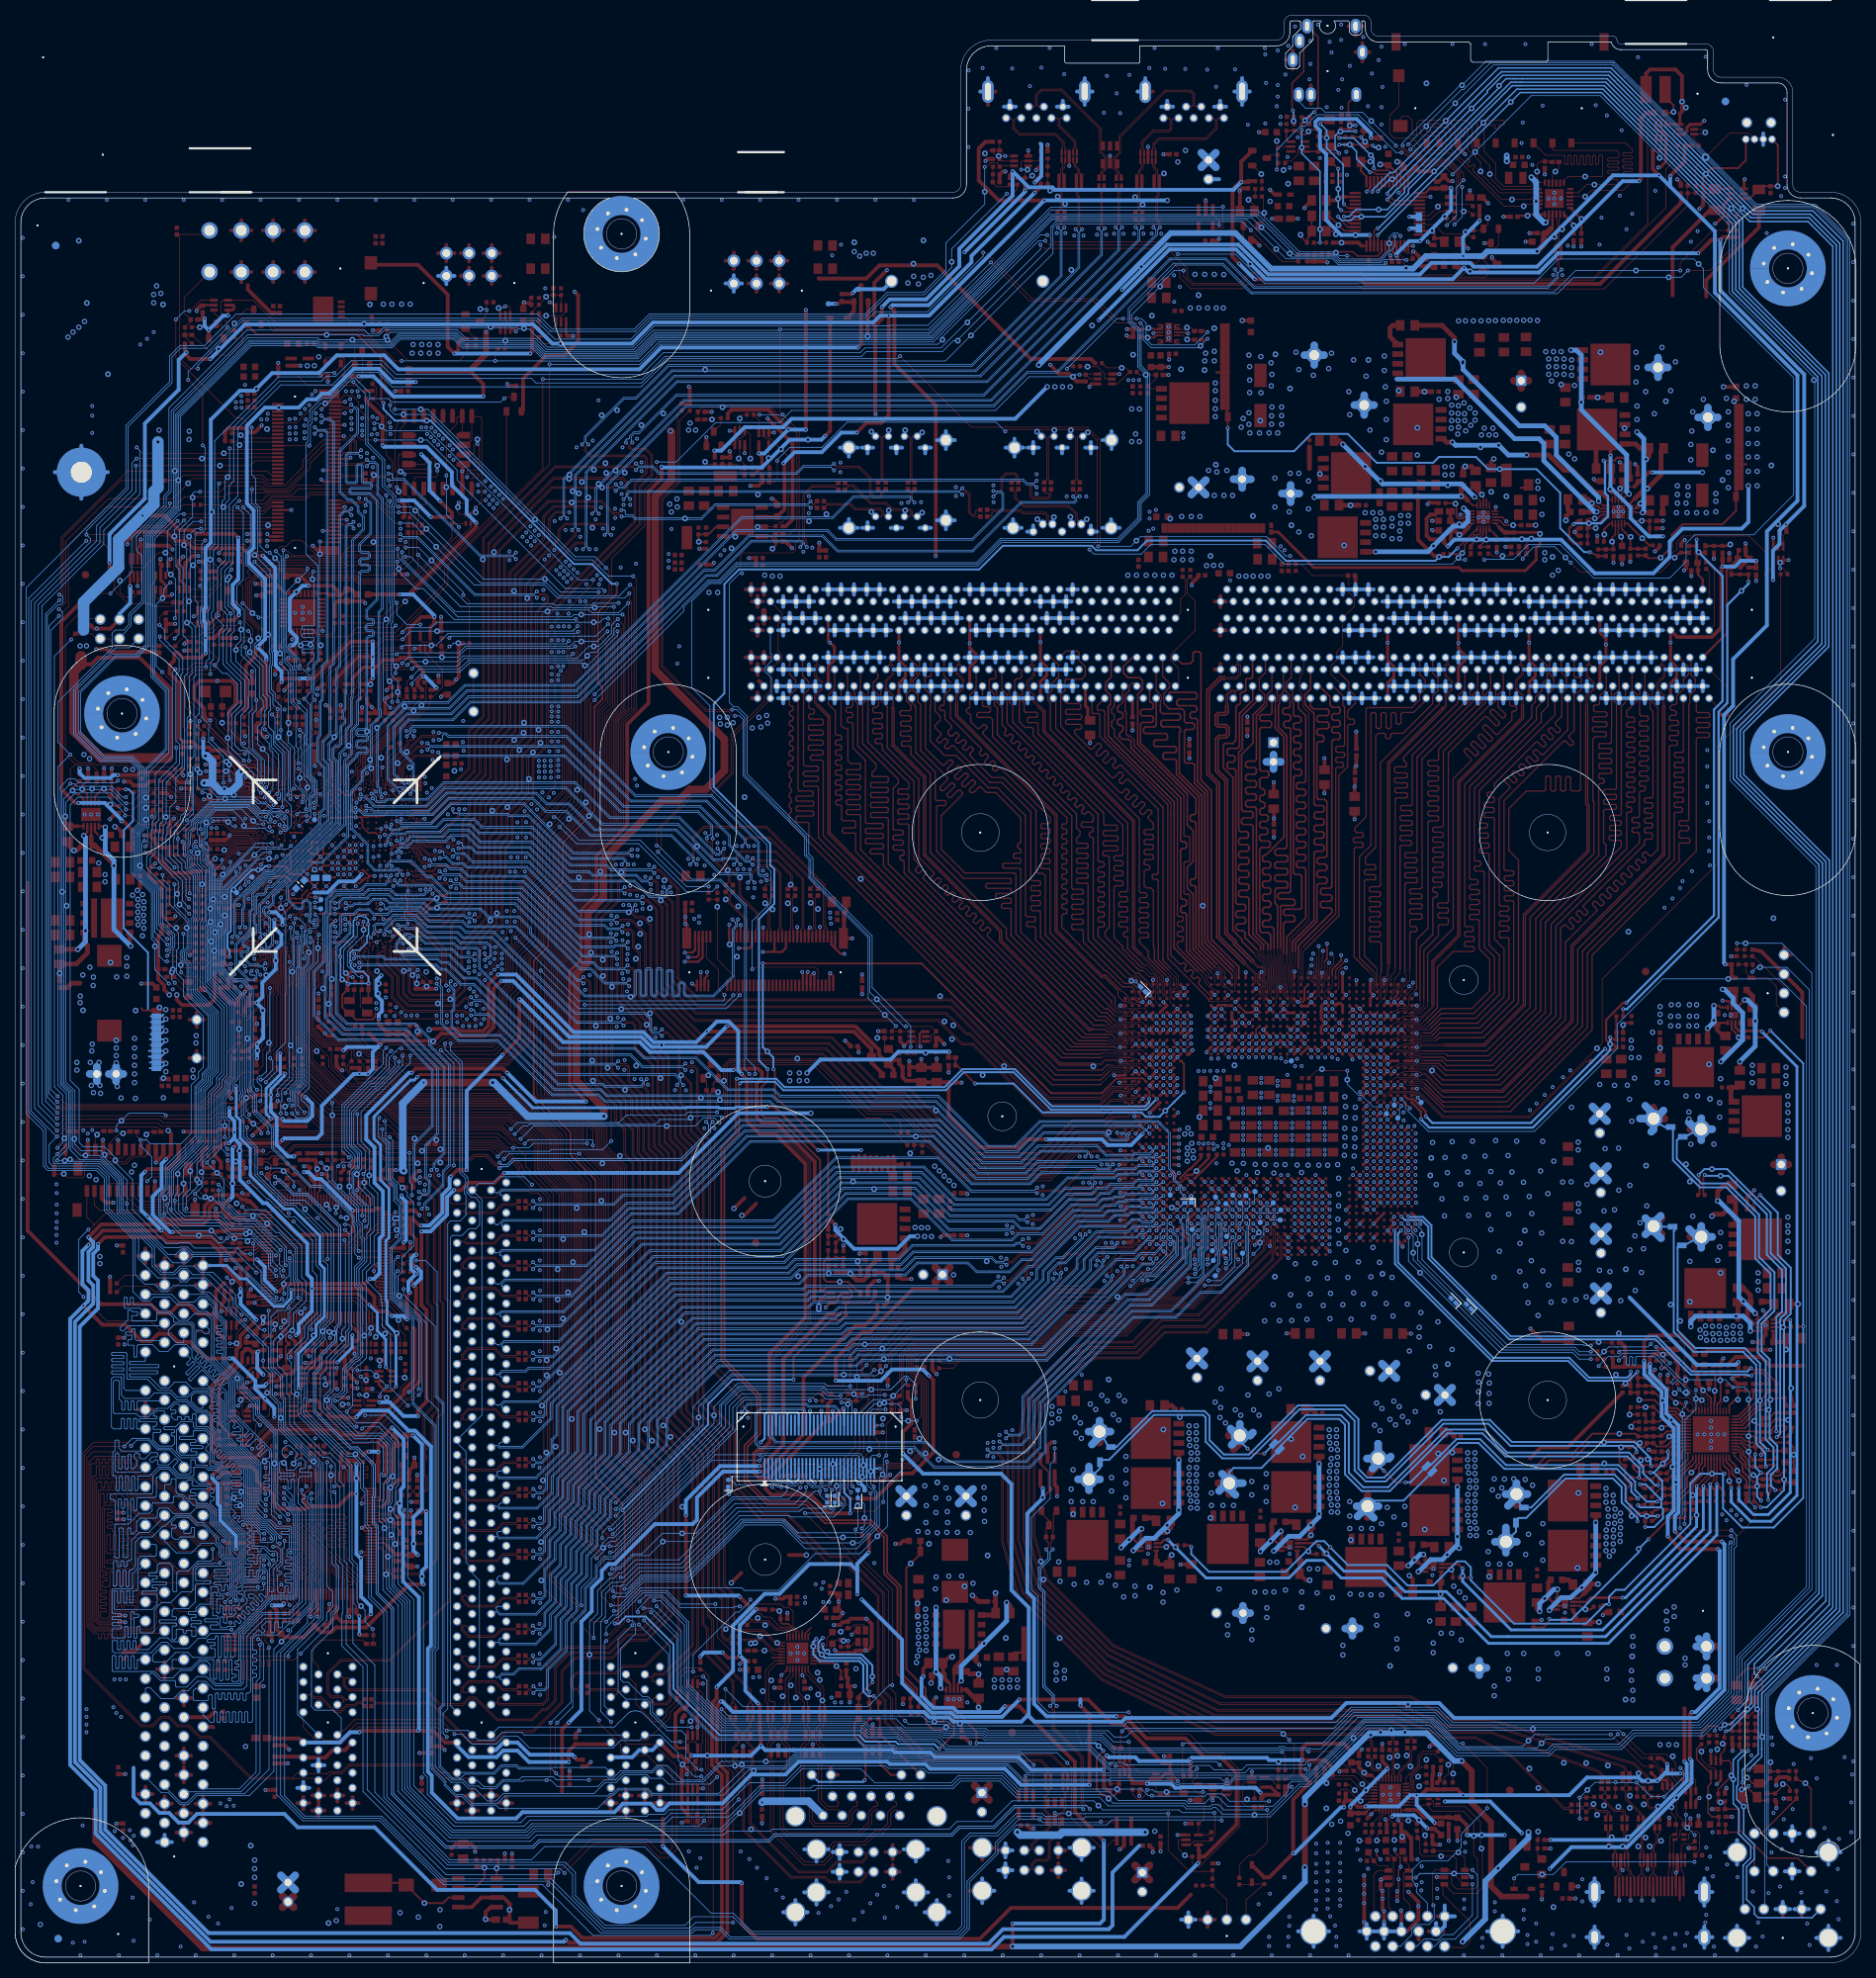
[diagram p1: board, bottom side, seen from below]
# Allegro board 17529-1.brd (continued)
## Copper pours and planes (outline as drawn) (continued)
5V_USB_REAR on TOP: 105.11,10.03 104.09,11.05 101.98,11.05 101.47,10.54 93.34,10.54 92.96,10.92 92.96,13.21 94.61,14.86 94.61,15.88 95.76,17.02 96.65,17.02 96.77,16.89 96.77,15.24 98.3,13.72 103.63,13.72 104.57,14.66 104.57,15.72 105.16,16.31 106.5,16.31 107.21,15.6 107.21,10.85 106.4,10.03 ; 2 cut-outs
5V_USB_RJ45 on TOP: 124.36,11 119.33,16.03 119.33,18.9 117.14,21.08 111.25,21.08 111,21.34 111,24.05 112.52,25.58 119.89,25.58 129.36,16.1 129.36,11.66 128.7,11 ; 2 cut-outs
5V_VGA_CONN on TOP: 52.45,2.41 52.2,2.67 52.2,3.56 52.58,3.94 54.79,3.94 55.09,3.63 55.47,3.63 55.73,3.38 56.52,3.38 56.67,3.53 57.15,3.53 57.51,3.89 57.51,4.42 57.91,4.83 58.83,4.83 59.42,4.23 59.42,3.06 59.44,3.05 58.93,2.54 54.36,2.54 54.23,2.41
5V_VGA_CONN on TOP: 43.43,14.61 43.31,14.73 43.31,17.65 43.43,17.78 44.96,17.78 45.09,17.65 45.09,14.73 44.96,14.61
5V_VGA_CONN on TOP: 54.74,20.83 54.48,21.08 54.48,22.1 54.61,22.23 56.13,22.23 56.26,22.1 56.26,20.83
12V_CPU on TOP: 104.83,36.27 104.7,36.4 104.7,39.78 109.25,44.32 110.24,44.32 110.24,36.65 109.86,36.27
12V_CPU on TOP: outline of 106 points within 1.52,32 104.98,122.94 ; 2 cut-outs
12V_CPU on BOTTOM: 23.58,32.8 21.22,35.17 20.71,35.17 19.61,36.27 19.61,47.24 20.56,48.2 26.73,48.2 33.59,41.34 50.23,41.34 55.5,46.61 60.58,46.61 63.69,49.72 88.07,49.72 90.04,51.69 103.38,51.69 106.91,48.16 106.91,37.13 104.57,34.8 55.5,34.8 53.51,32.8
12V_CPU on L2VCC: 6.79,88.46 6.79,118.94 11.99,118.94 12,118.92 12,115.11 12.37,114.74 15.29,114.74 15.81,114.22 15.81,104.09 14.78,103.06 12.88,103.06 12.26,102.44 12.26,99.62 13.38,98.49 15.42,98.49 15.81,98.09 15.81,93.03 11.73,93.03 10.86,92.15 10.86,88.85 10.46,88.46
12V_CPU on L2VCC: 29.27,33.72 29.27,44.89 32.69,44.89 33.96,43.62 44.02,43.62 44.51,44.12 44.51,49.96 44.91,50.36 49.58,50.36 49.72,50.21 49.72,45.9 50.09,45.53 57.61,45.53 60.77,48.69 60.77,49.71 62.67,51.61 62.67,54.66 63.07,55.05 68.12,55.05 68.26,54.91 68.26,50.72 68.63,50.36 71.42,50.36 72.06,49.72 75.26,49.72 75.76,50.21 75.76,51.86 75.77,51.88 76.76,51.88 77.14,51.5 80.47,51.5 80.96,51.99 80.96,57.58 81.36,57.98 86.41,57.98 86.55,57.83 86.55,51.61 86.92,51.24 98.25,51.24 99.38,52.37 99.38,58.09 99.77,58.48 104.58,58.48 104.58,50.12 98.06,43.6 82.51,37.27 59.52,37.27 53.54,34.48 43.93,33.72
12V_S0 on TOP: 201.93,216.87 201.83,216.97 201.83,221.26 202.44,221.87 202.44,224.66 203.96,226.19 211.07,226.19 211.96,225.3 211.96,220.4 210.13,218.57 207.87,218.57 206.17,216.87 ; 3 cut-outs
12V_S0 on TOP: 85.32,4.52 85.01,4.83 85.01,6.86 87.58,9.42 87.58,10.62 87.71,10.74 88.82,10.74 89.26,10.31 89.26,8.56 87.71,7.01 87.71,5.11 87.12,4.52 ; 1 cut-out
12V_S0 on TOP: 175.13,8.38 174.88,8.64 174.88,12.19 169.54,17.53 169.54,19.05 179.71,19.05 180.21,18.54 180.21,18.03 177.67,15.49 177.67,13.08 177.8,12.95 178.44,12.95 178.82,12.57 178.82,10.79 179.32,10.29 181.1,10.29 181.23,10.16 181.23,9.65 181.1,9.53 178.69,9.53 177.55,8.38 ; 2 cut-outs
12V_S0 on TOP: 141.6,220.22 140.34,221.49 137.54,221.49 137.03,222 137.03,224.16 139.57,226.69 143.89,226.69 144.65,225.93 144.65,220.98 143.89,220.22
12V_S0 on TOP: 218.44,8.76 211.77,15.43 187.77,15.43 186.44,16.76 170.18,16.76 169.29,17.65 159.38,17.65 157.73,19.3 157.73,23.24 158.12,23.62 168.91,23.62 169.27,23.98 172.72,23.98 173.08,23.62 183.9,23.62 184.35,23.16 189.33,23.16 189.48,23.01 189.48,22.99 205.87,22.99 206.57,22.29 210.69,22.29 210.7,22.28 216.45,22.28 217.14,21.59 217.14,17.91 217.88,17.17 219.89,17.17 221.21,18.49 222.33,18.49 222.52,18.3 222.95,18.3 223.32,17.93 230.84,17.93 231.67,17.09 231.67,15.27 225.17,8.76 ; 8 cut-outs
12V_S0 on TOP: 180.21,219.07 179.45,219.84 176.28,219.84 176.02,219.58 174.62,219.58 174.5,219.71 174.5,220.6 175.13,221.23 175.13,224.92 177.8,227.58 182.25,227.58 182.63,227.2 182.63,220.47 182.25,220.09 181.48,220.09 181.23,219.84 181.23,219.2 181.1,219.07 ; 4 cut-outs
12V_S0 on L2VCC: 215.6,15.18 214.82,15.95 214.82,22.02 215.47,22.67 234.27,22.67 238.7,27.1 238.82,92.2 238.82,104.61 239.08,105.25 239.08,114.84 238.82,115.48 238.82,214.58 235.66,217.74 230.81,217.74 229.36,216.3 225.25,220.41 140.67,220.41 140.02,221.06 140.02,229.16 142.06,231.2 157.02,231.2 157.8,230.43 157.8,225.09 159.81,223.08 167.21,223.08 169.61,225.47 169.61,229.41 171.4,231.2 233.35,231.2 242.25,222.3 242.25,20.02 238.68,16.45 230.81,16.45 229.54,15.18
12V_S0 on L3: 203.71,220.34 203.71,225.55 204.72,226.57 224.41,226.57 241.68,209.3 241.68,190.75 238.38,187.45 238.38,182.3 237.49,181.41 237.49,177.14 238.38,176.25 238.38,115.19 238,114.81 238,105.66 238.38,105.28 238.38,17.78 235.33,14.73 228.47,14.73 227.84,15.37 227.84,18.54 228.35,19.05 234.31,19.05 235.08,19.81 235.08,108.71 235.59,109.22 235.59,174.88 234.85,175.62 234.85,190.65 238.51,194.31 238.51,203.45 222.12,219.84 204.22,219.84
12V_S5 on TOP: 187.96,211.96 187.58,212.34 187.58,219.71 190.63,222.76 200.25,222.76 201.37,221.64 201.37,218.08 201.32,218.03 200.2,218.03 199.34,217.17 194.18,217.17 193.73,216.71 193.73,214.05 191.64,211.96 ; 2 cut-outs
12V_S5 on TOP: 238.66,142.67 238.65,142.68 238.21,142.68 238.1,142.8 238.1,146.69 238.25,146.84 238.25,154.31 239.27,155.32 239.27,202.44 238.25,203.45 238.25,214.76 234.7,218.31 225.55,218.31 224.28,219.58 224.28,221.87 224.92,222.5 241.17,222.5 242.57,221.11 242.57,142.7 242.54,142.67
12V_S5 on TOP: 54.03,194.26 53.59,194.69 53.59,197.87 52.83,198.63 50.16,198.63 47.88,200.91 47.88,202.56 48.64,203.33 50.04,203.33 52.7,200.66 52.83,200.66 53.34,200.15 55.7,200.15 56.82,199.03 56.82,194.46 56.62,194.26
12V_S5 on TOP: 42.75,213.94 42.16,214.53 42.16,217.58 42.27,217.68 54.48,217.68 54.61,217.55 54.61,217.04 52.63,215.06 52.63,214.27 52.3,213.94
12V_S5 on BOTTOM: 191.13,218.57 191.01,218.69 191.01,221.87 191.26,222.12 225.3,222.12 226.31,221.11 226.31,218.82 226.06,218.57
12V_S5 on L2VCC: 54.43,194.5 53.66,195.28 53.66,197.56 52.91,198.31 50.24,198.31 48.97,199.58 45.16,199.58 42.23,202.52 42.23,221.28 45.16,224.22 74.5,224.22 75.39,225.11 113.59,225.11 121.71,216.98 130.99,216.98 133.27,214.69 192.71,214.69 193.74,213.66 193.74,210.77 190.93,207.96 109.81,207.96 103.84,213.93 51.1,213.93 49.85,212.68 49.85,203.76 53.39,200.22 57.2,200.22 57.98,199.44 57.98,194.77 57.71,194.5
12V_SYSATX_S5 on TOP: 195.07,223.52 194.69,223.9 194.69,227.2 195.07,227.58 196.98,227.58 200.41,231.01 206.88,231.01 207.65,230.25 207.65,227.71 206.5,226.57 202.18,226.57 199.14,223.52 ; 3 cut-outs
-12V_S0 on TOP: 204.34,6.22 202.82,7.75 202.82,10.29 200.79,12.32 193.68,12.32 193.37,12.01 190.53,12.01 189.76,11.25 189.76,9.8 189.36,9.4 186.89,9.4 186.77,9.53 186.77,10.57 186.54,10.79 184.15,10.79 183.57,11.38 183.57,13.13 183.46,13.23 182.68,13.23 182.6,13.16 181.79,13.16 181.74,13.21 181.74,14.07 181.94,14.27 183.64,14.27 184.1,14.73 211.84,14.73 213.11,13.46 213.11,10.03 212.85,9.78 211.33,9.78 211.2,9.65 211.2,7.62 209.8,6.22 ; 6 cut-outs
-12V_S0 on BOTTOM: 213.16,9.3 211.66,10.79 211.66,16.41 212.6,17.35 225.76,17.35 226.75,16.36 226.75,13.03 223.01,9.3
AGND on TOP: 67.56,235.97 67.06,236.47 67.06,238.89 66.8,239.14 65.41,239.14 64.64,238.38 61.34,238.38 61.21,238.51 61.21,239.9 62.87,241.55 62.87,253.84 63.75,253.84 65,254.35 65.51,255.6 65.51,256.4 65.58,256.57 65.75,256.64 75.25,256.64 75.42,256.57 75.49,256.4 75.49,255.1 76,253.85 77.25,253.34 77.6,253.34 77.6,237.36 76.83,236.6 71.63,236.6 70.99,235.97 ; 13 cut-outs
AGND on TOP: 4,0.76 1.71,1.71 0.76,4 0.76,25.4 6.99,25.4 11.81,30.23 14.1,30.23 14.35,29.97 14.35,28.07 14.73,27.69 14.73,27.05 14.22,26.54 12.45,26.54 11.56,25.65 8.64,25.65 5.71,22.73 5.71,16.51 6.1,16.13 7.11,16.13 7.49,16.51 7.49,20.32 7.87,20.7 9.02,20.7 10.54,19.18 10.54,16.64 11.05,16.13 12.83,16.13 13.21,15.75 13.21,15.11 12.19,14.1 7.11,14.1 5.59,12.57 5.59,11.43 5.97,11.05 7.11,11.05 7.75,11.68 7.75,12.32 8.76,13.34 12.83,13.34 13.08,13.08 13.08,11.18 13.46,10.79 14.73,10.79 14.99,11.05 14.99,12.7 14.73,12.95 14.73,15.24 16.13,16.64 18.41,16.64 18.54,16.76 18.54,17.53 18.67,17.65 19.3,17.65 19.43,17.78 19.43,18.8 19.56,18.92 20.19,18.92 20.45,18.67 20.45,17.4 18.16,15.11 18.16,0.76 ; 3 cut-outs
AGND on BOTTOM: 4,0.76 1.71,1.71 0.76,4 0.76,25.4 7.11,25.4 11.81,30.1 20.32,30.1 21.84,28.57 21.84,25.02 20.45,23.62 20.45,17.4 18.29,15.24 18.29,0.76 ; 1 cut-out
AGND on L2VCC: 4,0.76 1.71,1.71 0.76,4 0.76,25.59 7.19,25.59 12.38,30.78 12.38,36.15 10.6,37.92 10.6,38.91 10.87,39.18 15.42,39.18 17.21,37.39 17.21,33.32 18.59,31.94 21.13,31.94 21.91,31.16 21.91,24.97 20.51,23.57 20.51,17.35 18.22,15.06 18.22,0.76
AGND on L2VCC: 63.83,226.25 63.69,226.39 63.69,227.92 61.42,230.19 56.18,230.19 55.29,229.3 52.66,229.3 50.99,230.96 50.99,235.25 54.18,238.44 57.48,238.44 59.64,240.6 61.8,240.6 62.8,241.6 62.8,253.84 63.75,253.84 65,254.35 65.51,255.6 65.51,256.4 65.58,256.57 65.75,256.64 75.25,256.64 75.42,256.57 75.49,256.4 75.49,255.1 76,253.85 77.25,253.34 77.66,253.34 77.66,240.46 79.18,238.94 79.18,237.95 75.88,234.65 75.88,229.44 73.45,227.01 67.1,227.01 66.34,226.25
AGND on L3: 4,0.76 1.71,1.71 0.76,4 0.76,25.53 1.27,25.53 1.42,25.68 1.42,228.5 5.46,232.54 13.59,232.54 32.64,251.59 61.62,251.59 62.81,252.78 62.81,253.84 63.75,253.84 65,254.35 65.51,255.6 65.51,256.4 65.58,256.57 65.75,256.64 75.25,256.64 75.42,256.57 75.49,256.4 75.49,255.1 76,253.85 77.25,253.34 77.67,253.34 77.67,240.46 79.2,238.94 79.2,237.95 75.9,234.65 75.9,229.41 73.48,227 67.11,227 66.34,226.24 63.86,226.24 63.68,226.42 63.68,227.91 61.42,230.17 56.18,230.17 55.31,229.3 52.62,229.3 50.93,230.99 50.93,238.76 43.18,246.51 34.44,246.51 17.65,229.72 17.65,220.6 6.48,209.42 6.48,175.01 17.53,163.96 17.53,156.08 6.1,144.65 6.1,49.4 15.49,40.01 15.49,34.92 21.84,28.57 21.84,25.02 20.45,23.62 20.45,17.27 18.29,15.11 18.29,0.76 ; 1 cut-out
GND on TOP: 232.24,150.9 232.11,151.03 232.11,152.65 232.13,152.67 235.33,152.67 235.46,152.55 235.46,151.02 235.33,150.9
GND on TOP: 117.98,33.66 117.79,33.85 117.79,34.61 118.62,35.43 121.21,35.43 121.34,35.31 121.34,33.73 121.26,33.66
GND on TOP: 56.46,49.68 56.26,49.89 56.26,50.85 56.06,51.05 56.06,53.21 56.11,53.26 56.95,53.26 57,53.21 57,52.4 57.02,52.37 57.91,52.37 57.99,52.3 57.99,52.12 57.91,52.04 57.15,52.04 57,51.89 57,51.44 57.63,50.8 57.63,49.83 57.48,49.68 ; 1 cut-out
GND on TOP: 232.66,141.43 231.79,142.3 231.79,144.82 233.27,146.3 234.06,146.3 234.26,146.1 234.26,145.14 233.78,144.65 233.78,141.48 233.73,141.43 ; 1 cut-out
GND on TOP: outline of 93 points within 166.24,123.49 198.22,183.74 ; 4 cut-outs
GND on TOP: 79.22,114.07 79.02,114.27 79.02,115.11 79.22,115.32 80.92,115.32 81.05,115.19 81.05,114.15 80.98,114.07
GND on TOP: 69.22,58.93 68.83,59.31 68.83,70.87 70.99,73.03 71.37,73.03 71.5,72.9 71.5,72.26 72.39,71.37 72.39,67.82 70.48,67.82 70.38,67.72 70.38,65.33 70.71,65 72.19,65 72.39,64.8 72.39,61.21 70.64,61.21 70.36,60.93 70.36,59 70.28,58.93 ; 1 cut-out
GND on TOP: 33.78,7.62 33.27,8.13 33.27,11.18 33.91,11.81 37.72,11.81 38.86,10.67 38.86,8 38.48,7.62 ; 2 cut-outs
GND on TOP: 81.53,108.46 81.41,108.58 81.41,109.47 81.53,109.6 83.44,109.6 83.44,108.46
GND on TOP: 188.06,130.53 187.96,130.63 187.96,133.2 189.97,135.2 190.42,135.2 190.55,135.33 191.47,135.33 191.67,135.13 191.67,134.8 191.31,134.44 191.13,134.44 191.01,134.57 190.6,134.57 190.55,134.52 190.55,133.48 190.45,133.38 189.92,133.38 188.59,132.05 188.59,130.63 188.49,130.53
GND on TOP: 205.54,200.89 204.93,201.5 204.93,203.25 204.85,203.33 204.22,203.33 203.99,203.56 203.99,204.8 203.76,205.03 203.3,205.03 202.82,205.51 202.82,205.77 202.49,206.1 200.81,206.1 200.66,205.94 200.33,205.94 199.92,206.35 199.36,206.35 199.19,206.17 199.19,204.8 199.52,204.47 199.8,204.47 200,204.27 200,202.41 199.69,202.11 198.78,202.11 198.3,201.63 196.11,201.63 195.88,201.85 195.88,203.94 198.12,206.17 198.12,207.04 197.92,207.24 197.66,207.24 197.46,207.44 197.46,207.9 197.56,208 200.76,208 200.79,208.03 204.67,208.03 205.41,207.29 205.41,206.43 207.47,204.37 208.08,204.37 208.23,204.22 208.23,202.9 208.22,202.88 208.22,201.16 207.95,200.89
GND on TOP: outline of 169 points within 191.13,134.21 209.12,155.3
GND on TOP: 29.46,127.13 27.81,128.78 19.81,128.78 18.54,130.05 18.54,133.22 16.38,135.38 13.34,135.38 9.27,131.32 1.14,131.32 1.02,131.44 1.02,231.01 3.05,233.04 8.76,233.04 9.88,234.16 12.24,234.16 12.34,234.06 12.34,233.15 12.32,233.12 12.32,229.49 12.95,228.85 12.95,227.84 15.37,225.43 15.37,217.42 9.14,211.2 9.14,188.72 9.78,188.09 9.78,184.78 9.14,184.15 9.14,183.01 10.16,181.99 10.16,169.16 18.67,160.66 18.67,144.91 33.66,129.92 33.66,127.76 33.02,127.13 ; 1 cut-out
GND on TOP: 187.12,4.32 186.99,4.45 186.99,6.96 187.38,7.34 190.6,7.34 191.13,7.87 201.8,7.87 204.22,5.46 210.06,5.46 211.84,7.24 211.84,9.27 212.09,9.53 212.85,9.53 212.98,9.4 212.98,5.84 211.46,4.32 ; 1 cut-out
GND on TOP: 91.82,175.01 90.3,176.53 90.3,180.34 89.79,180.85 89.79,181.86 90.17,182.25 142.62,182.25 143.38,181.48 143.38,179.71 142.24,178.56 142.24,177.16 142.88,176.53 142.88,175.39 142.49,175.01
GND on TOP: 219.58,0.76 219.58,1.14 234.19,15.75 234.19,18.41 234.44,18.67 236.73,18.67 238.51,20.45 238.51,33.27 235.46,36.32 235.46,67.69 233.81,69.34 228.6,69.34 227.97,69.98 227.97,70.99 227.46,71.5 225.68,71.5 225.43,71.75 225.43,74.17 225.93,74.68 227.71,74.68 227.97,74.93 227.97,81.15 228.85,82.04 231.01,82.04 236.22,87.25 236.22,89.53 243.24,96.55 243.24,4 242.29,1.71 240,0.76 ; 2 cut-outs
GND on TOP: 156.59,183.39 156.34,183.64 156.34,187.07 156.46,187.2 157.73,187.2 157.99,186.94 157.99,183.51 157.86,183.39 ; 5 cut-outs
GND on TOP: 95.07,208 94.92,208.15 94.92,209.19 95.2,209.47 97.13,209.47 97.51,209.09 97.51,208.2 97.31,208 ; 3 cut-outs
GND on TOP: 124.59,39.37 124.46,39.5 124.46,40.51 124.08,40.89 122.05,40.89 121.77,41.17 121.77,45.09 123.19,45.09 123.29,45.19 123.29,47.07 123.42,47.19 123.9,47.19 124.05,47.04 124.05,46.02 124.16,45.92 125.15,45.92 125.27,45.8 125.27,39.55 125.09,39.37 ; 1 cut-out
GND on TOP: 119.63,100.33 119.51,100.46 119.51,103.17 123.75,107.42 124.41,107.42 124.69,107.14 124.69,106.55 125.2,106.05 126.11,106.05 126.21,105.94 126.21,105.13 126.62,104.72 126.62,101.35 126.36,101.09 125.48,101.09 124.71,100.33 ; 7 cut-outs
GND on TOP: 79.38,112.01 79.25,112.14 79.25,113.03 79.38,113.16 81.28,113.16 81.28,112.01
GND on TOP: 226.77,141.99 228.35,141.99 229.37,140.96 229.37,137.15 229.3,137.08 228.14,137.08 227.81,136.75 227.81,135.51 227.56,135.25 226.78,135.25 226.4,135.64 226.4,141.61
GND on TOP: 89.41,200.79 88.9,201.29 88.9,202.51 89.1,202.72 90.88,202.72 91.19,202.41 91.19,201.04 90.93,200.79
GND on TOP: 37.24,99 36.99,99.26 36.99,100.53 37.24,100.78 39.15,100.78 39.53,100.4 39.53,99.38 39.15,99
GND on TOP: 189.51,156.99 190.69,156.99 190.89,156.79 190.89,155.47 190.55,155.13 190.55,154.88 190.49,154.81 190.39,154.81 189.4,155.8 189.4,156.88
GND on TOP: 38.89,44.88 38.63,45.14 38.63,48.36 38.73,48.46 39.52,48.46 39.57,48.41 39.57,46.63 40.21,46 40.21,45.03 40.06,44.88 ; 1 cut-out
GND on TOP: 42.04,190.63 41.78,190.88 41.78,193.8 42.04,194.06 43.81,194.06 44.07,193.8 44.07,190.75 43.94,190.63
GND on TOP: 149.99,185.8 149.61,186.18 149.61,188.59 149.86,188.85 151.26,188.85 151.64,188.47 151.64,186.06 151.38,185.8
GND on TOP: 77.14,52.45 76.83,52.76 76.83,53.29 77.04,53.49 80.16,53.49 80.26,53.39 80.26,52.58 80.14,52.45
GND on TOP: 156.87,191.24 156.08,192.02 156.08,193.17 155.57,193.68 150.5,193.68 150.37,193.8 150.37,195.2 150.5,195.33 155.83,195.33 157.94,193.22 157.94,191.49 157.68,191.24
GND on TOP: 114.3,64.14 114.05,64.39 114.05,66.67 114.43,67.06 114.68,67.06 115.19,66.55 115.7,66.55 115.95,66.8 115.95,67.94 115.7,68.2 115.06,68.2 114.94,68.07 114.55,68.07 114.3,68.33 114.3,69.09 114.05,69.34 113.79,69.34 113.54,69.6 113.54,71.25 114.05,71.75 117.98,71.75 119.13,72.9 119.13,77.22 119.89,77.98 122.43,77.98 122.68,77.72 122.68,77.6 122.3,77.22 122.3,64.52 121.92,64.14
GND on TOP: 0.76,26.29 0.76,40.01 0.76,40.01 0.76,230 1.71,232.29 4,233.24 8,233.24 9.25,233.75 9.76,235 9.76,247.2 10.13,248.07 11,248.44 18.5,248.44 19.75,248.95 20.26,250.2 20.26,252.6 20.33,252.77 20.5,252.84 31.75,252.84 32.54,253.12 32.99,253.84 62.24,253.84 62.24,253.33 33.34,253.33 32.69,252.6 31.75,252.33 20.77,252.33 20.77,250.2 20.11,248.59 18.5,247.93 11,247.93 10.48,247.72 10.27,247.2 10.27,235 9.61,233.39 8,232.73 4,232.73 2.07,231.93 1.27,230 1.27,45.21 11.43,35.05 11.43,30.61 7.11,26.29
GND on TOP: 144.86,57.25 144.86,49.35
GND on TOP: 94.21,52.5 94.11,52.6 94.11,53.75 93.74,54.11 93.74,56.03 93.88,56.17 94.58,56.17 94.61,56.13 94.61,55.19 94.64,55.17 95.53,55.17 95.61,55.09 95.61,54.91 95.53,54.84 94.77,54.84 94.61,54.69 94.61,54.1 95.12,53.59 95.12,52.58 95.07,52.58 95,52.5
GND on TOP: 16.15,124.84 16.08,124.92 16.08,125.63 16.13,125.68 16.81,125.68 16.94,125.81 16.94,126.57 16.99,126.62 17.2,126.62 17.22,126.59 17.22,125.78 17.32,125.68 17.86,125.68 18.03,125.86 19.3,125.86 19.43,125.73 19.43,124.97 19.3,124.84
GND on TOP: 19.18,0.89 18.92,1.14 18.92,5.71 20.32,7.11 21.08,7.11 23.62,4.57 40.89,4.57 43.81,7.49 45.21,7.49 45.85,8.13 48.01,8.13 48.64,8.76 53.34,8.76 53.72,8.38 53.72,8 51.44,5.71 51.44,2.41 52.07,1.78 58.93,1.78 59.69,2.54 59.69,4.06 58.8,4.95 58.67,4.95 58.17,5.46 58.17,6.86 57.1,7.92 57.1,12.83 59.08,14.81 59.08,16.79 59.23,16.94 59.82,16.94 59.94,16.81 59.94,13.56 59.51,13.13 59.28,13.13 58.98,12.83 58.98,11.07 58.47,10.57 58.47,9.91 58.85,9.53 59.44,9.53 60.45,10.54 60.45,14.35 61.72,15.62 64.77,15.62 65.15,16 65.15,16.94 65.05,17.04 65.05,19.08 65.23,19.25 66.75,19.25 67.02,18.99 68.21,18.99 68.68,19.46 68.68,21.67 68.78,21.77 69.29,21.77 69.49,21.97 69.49,22.86 69.38,22.97 68.95,22.97 68.58,23.34 68.58,23.83 68.76,24 69.9,24 70.61,23.29 70.61,23.24 72.9,20.95 72.9,12.32 73.53,11.68 76.71,11.68 80.26,8.13 80.26,4.45 83.69,1.02 83.57,0.89 ; 14 cut-outs
GND on TOP: 77.22,108.46 77.09,108.58 77.09,109.47 77.22,109.6 79.12,109.6 79.12,108.46
GND on TOP: 80.01,0.76 79.25,1.52 79.25,2.54 85.98,2.54 88.14,4.7 88.14,6.35 88.39,6.6 110.62,6.6 111.38,5.84 111.38,1.78 112.01,1.14 112.01,0.76
GND on TOP: 69.25,108.53 69.12,108.65 69.12,109.54 69.25,109.67 74.81,109.67 74.83,109.65 74.83,108.66 74.69,108.53
GND on TOP: 79.38,106.55 79.25,106.68 79.25,107.52 79.43,107.7 81.28,107.7 81.28,106.55
GND on TOP: 52.58,201.68 50.42,203.84 50.42,207.9 50.55,208.03 56.01,208.03 56.13,207.9 56.13,202.31 54.1,202.31 53.47,201.68 ; 1 cut-out
GND on TOP: 37.24,91.25 36.99,91.51 36.99,92.78 37.24,93.03 39.15,93.03 39.53,92.65 39.53,91.64 39.15,91.25
GND on TOP: 232.66,193.29 230.76,195.2 230.76,202.44 231.39,203.07 237.74,203.07 239.08,201.74 239.08,193.61 238.76,193.29
GND on TOP: 93.62,185.09 93.57,185.14 93.57,188.93 93.04,189.46 93.04,189.94 93.17,190.07 94.46,190.07 94.72,189.81 94.72,186.79 95.86,185.65 95.86,185.19 95.76,185.09 ; 1 cut-out
GND on TOP: 219.89,113.79 216.62,117.06 216.62,119.82 214.99,121.46 214.99,124.92 216.28,126.21 223.39,126.21 223.47,126.14 223.47,125.68 223.39,125.6 221.97,125.6 221.36,124.99 221.36,123.7 221.01,123.34 219.38,123.34 219.18,123.14 219.18,121.03 219.35,120.85 220.62,120.85 221.36,120.12 221.36,118.97 221.11,118.72 219.58,118.72 219.1,118.24 219.1,116.41 219.33,116.18 224.94,116.18 225.5,115.62 225.5,114.07 225.22,113.79 ; 10 cut-outs
GND on TOP: 116.71,3.94 111.89,8.76 111.89,15.24 113.03,16.38 118.11,16.38 123.83,10.67 130.68,10.67 131.19,10.16 136.65,10.16 137.29,10.79 141.86,10.79 147.32,16.26 148.08,16.26 148.72,15.62 148.72,12.19 147.07,10.54 147.07,5.46 145.54,3.94
GND on TOP: 75.31,184.53 75.18,184.66 75.18,185.42 75.69,185.93 75.69,186.69 77.29,188.29 78.28,188.29 78.49,188.09 78.49,184.91 78.11,184.53 ; 2 cut-outs
GND on TOP: 33.15,53.21 31.37,54.99 31.37,59.44 32.26,60.33 32.26,65.15 32.38,65.28 32.89,65.28 33.07,65.1 33.07,64.19 33.38,63.88 35.56,63.88 35.81,63.63 35.81,60.07 33.88,60.07 33.78,59.97 33.78,57.56 34.09,57.25 35.74,57.25 35.81,57.18 35.81,53.47 33.78,53.47 33.53,53.21
GND on TOP: 69.16,111.89 69.04,112.01 69.04,113.28 69.09,113.33 70.28,113.33 70.46,113.51 70.46,117.25 70.66,117.45 72.06,117.45 72.36,117.14 72.36,115.01 72.42,114.96 76.68,114.96 76.73,114.91 76.73,113.41 76.96,113.18 76.96,112.04 76.81,111.89 ; 3 cut-outs
GND on TOP: 185.01,157.28 184.28,158.01 184.28,161.49 184.53,161.75 187.38,161.75 187.55,161.57 187.55,160.4 187.4,160.25 185.32,160.25 185.17,160.1 185.17,158.17 185.38,157.95 185.38,157.48 185.18,157.28 ; 6 cut-outs
GND on TOP: 81.53,110.11 81.41,110.24 81.41,111.1 81.56,111.25 83.44,111.25 83.44,110.11
GND on TOP: 43.89,112.19 34.42,121.67 34.42,130.3 19.3,145.41 19.3,160.78 10.92,169.16 10.92,181.36 12.45,182.88 16.51,182.88 16.89,182.5 16.89,175.39 18.41,173.86 18.41,170.69 17.02,169.29 17.02,164.85 17.53,164.34 18.92,164.34 19.3,163.96 19.3,162.05 20.07,161.29 20.83,161.29 21.21,160.91 21.21,146.56 35.05,132.72 35.05,122.94 45.21,112.78 45.21,112.37 45.03,112.19
GND on TOP: 36.58,206.5 36.45,206.63 36.45,207.77 36.07,208.15 36.07,212.22 38.86,212.22 39.24,212.6 39.24,213.16 39.4,213.31 41.83,213.31 42.04,213.11 42.04,209.3 40.26,207.52 37.97,207.52 36.96,206.5 ; 1 cut-out
GND on TOP: 105.66,50.04 105.54,50.16 105.54,53.21 105.79,53.47 106.43,53.47 106.83,53.06 106.83,50.93 105.94,50.04
GND on TOP: 236.98,94.61 234.95,96.65 234.95,102.74 235.59,103.38 241.55,103.38 241.68,103.25 241.68,97.28 239.01,94.61
GND on TOP: 212.65,132.81 212.4,133.07 212.4,134.46 212.65,134.72 213.03,134.72 213.42,134.34 213.42,133.96 213.92,133.45 213.92,132.94 213.8,132.81
GND on TOP: 75.06,106.55 74.93,106.68 74.93,107.57 75.06,107.7 76.96,107.7 76.96,106.55
GND on TOP: 227.08,205.36 225.3,207.14 225.3,217.17 225.93,217.81 232.92,217.81 237.74,212.98 237.74,205.74 237.36,205.36
GND on TOP: 43.43,237.24 43.18,237.49 43.18,238.76 44.07,239.65 44.07,241.3 43.94,241.43 31.75,241.43 29.84,243.33 29.84,249.05 29.08,249.81 29.08,252.22 29.46,252.6 32.26,252.6 33.4,253.75 46.61,253.75 46.74,253.62 62.1,253.62 62.23,253.49 62.23,252.6 62.1,252.48 60.96,252.48 60.07,251.59 60.07,244.6 59.44,243.97 47.24,243.97 46.35,243.08 46.35,240.03 45.97,239.65 45.47,239.65 45.09,239.27 45.09,237.36 44.96,237.24 ; 3 cut-outs
GND on TOP: 170.05,198.75 169.54,199.26 169.54,200.91 169.16,201.29 168.28,201.29 167.89,200.91 164.08,200.91 163.7,201.29 162.23,201.29 161.98,201.04 158.5,201.04 157.99,201.55 157.99,206.12 154.94,209.17 145.16,209.17 143.76,210.57 143.76,217.3 145.03,218.57 145.03,222.63 145.54,223.14 147.32,223.14 148.08,223.9 148.08,225.81 148.46,226.19 151.79,226.19 158.75,219.23 164.64,219.23 166.62,217.25 166.62,214 172.72,207.9 172.72,198.88 172.59,198.75
GND on TOP: 96.52,52.2 96.32,52.4 96.32,53.37 96.75,53.8 98.68,53.8 98.7,53.77 98.7,52.65 98.64,52.59 97.22,52.59 96.82,52.2
GND on TOP: 84.61,105.44 84.05,105.99 84.05,113.33 83.69,113.69 83.19,113.69 83.03,113.84 83.03,114.71 82.8,114.94 82.07,114.94 81.97,115.04 81.97,115.87 82.02,115.93 84.2,115.93 84.4,116.13 84.4,116.89 84.76,117.25 85.98,117.25 86.23,116.99 86.23,108.74 86.11,108.62 84.9,108.62 84.73,108.45 84.73,108.13 84.73,106.4 85.01,106.12 85.29,106.12 85.5,105.92 85.5,105.59 85.34,105.44 ; 3 cut-outs
GND on TOP: 12.65,81.61 12.57,81.69 12.57,82.52 12.14,82.96 12.14,85.8 12.85,86.51 13.18,86.51 13.26,86.44 13.26,86.13 12.88,85.75 12.88,85.09 13.06,84.91 13.06,84.23 13.11,84.18 13.94,84.18 14,84.12 14,83.87 13.94,83.82 13.13,83.82 13.06,83.74 13.06,83.06 13.39,82.73 14.43,82.73 14.63,82.52 14.63,81.84 14.4,81.61
GND on TOP: 50.67,46.35 50.55,46.48 50.55,49.02 52.2,50.67 54.23,50.67 54.48,50.42 54.48,46.61 54.23,46.35
GND on TOP: 77.22,110.11 77.09,110.24 77.09,111.12 77.22,111.25 79.12,111.25 79.12,110.11
GND on TOP: 151.05,142.47 150.65,142.88 150.65,144.15 152.86,146.35 153.82,146.35 154.03,146.15 154.03,145.75 153.44,145.16 153.44,144.78 153.64,144.58 153.97,144.58 154.1,144.45 154.1,143.03 153.54,142.47
GND on TOP: 183.13,217.3 182.88,217.55 182.88,224.03 183.13,224.28 185.42,224.28 185.55,224.41 185.55,233.24 240,233.24 242.29,232.29 243.24,230 243.24,221.33 241.43,223.14 224.16,223.14 223.9,223.39 223.9,227.97 222.88,228.98 222,228.98 220.73,230.25 217.42,230.25 216.92,229.74 216.92,221.74 216.53,221.36 212.47,221.36 212.22,221.62 212.22,225.68 211.33,226.57 208.03,226.57 207.9,226.69 207.9,230.25 206.76,231.39 200.41,231.39 196.85,227.84 192.79,227.84 188.85,223.9 186.56,223.9 185.67,223.01 185.67,218.06 184.91,217.3 ; 5 cut-outs
GND on TOP: 15.44,57.71 14.68,58.47 14.68,61.09 14.86,61.26 21.51,61.26 21.69,61.09 21.69,60.38 21.89,60.17 22.61,60.17 22.81,59.97 22.81,58.01 22.5,57.71 ; 15 cut-outs
GND on TOP: 135.64,223.14 133.99,224.79 133.99,227.46 134.24,227.71 136.53,227.71 136.65,227.58 136.65,223.27 136.53,223.14
GND on TOP: 144.86,107.25 144.86,99.35
GND on TOP: 75.13,52.63 75.03,52.73 75.03,55.98 75.16,56.11 75.95,56.11 75.97,56.08 75.97,55.17 76,55.14 76.89,55.14 76.96,55.07 76.96,54.89 76.89,54.81 76.12,54.81 75.97,54.66 75.97,54.2 76.35,53.82 76.35,52.93 76.05,52.63 ; 1 cut-out
GND on TOP: 69.47,174.62 68.96,175.13 68.96,179.45 67.94,180.47 67.94,181.99 68.33,182.37 82.55,182.37 82.93,182.75 82.93,184.02 83.06,184.15 83.82,184.15 83.95,184.02 83.95,182.63 83.19,181.86 83.19,175.01 82.8,174.62
GND on TOP: 100.33,105.03 100.08,105.28 100.08,106.55 100.46,106.93 101.22,106.93 101.35,106.81 101.35,106.3 101.6,106.05 102.62,106.05 102.87,106.3 102.87,106.68 103,106.81 103.38,106.81 103.5,106.68 103.5,105.16 103.38,105.03
GND on TOP: 242.73,4.06 242.73,230 241.93,231.93 240,232.73 120,232.73 118.39,233.39 117.73,235 117.73,250.1 116.93,252.03 115,252.83 78.41,252.83 78.41,253.29 78.46,253.34 115,253.34 117.29,252.39 118.24,250.1 118.24,235 118.75,233.75 120,233.24 240,233.24 242.29,232.29 243.24,230 243.24,4.06
GND on TOP: 237.87,100.84 237.49,101.22 237.49,101.47 239.52,103.5 239.52,113.79 238.89,114.43 235.97,114.43 235.59,114.81 235.59,119.25 235.71,119.38 237.36,119.38 237.87,119.89 237.87,125.43 237.13,126.16 235.66,126.16 235,126.82 235,128.04 235.08,128.12 236.42,128.12 236.58,127.97 238.71,127.97 239.42,128.68 239.42,134.92 239.22,135.13 238.38,135.13 238.12,135.38 238.12,138.18 238.38,138.43 240.92,138.43 241.43,137.92 241.43,116.08 241.68,115.82 241.68,101.73 240.79,100.84
GND on TOP: 92.86,190.5 92.63,190.73 92.63,192.23 92.94,192.53 94.41,192.53 94.61,192.33 94.61,190.63 94.49,190.5 ; 1 cut-out
GND on TOP: 21.72,174.62 20.45,175.9 20.45,180.72 22.35,182.63 66.67,182.63 67.44,181.86 67.44,181.23 66.67,180.47 66.67,179.2 68.07,177.8 68.07,175.01 67.69,174.62 ; 1 cut-out
GND on TOP: 12.67,115.44 12.57,115.54 12.57,118.95 12.75,119.13 14.61,119.13 14.86,118.87 14.86,115.7 14.61,115.44
GND on TOP: 37.72,198.25 37.34,198.63 37.34,198.88 38.35,199.9 38.35,201.04 38.61,201.29 41.78,201.29 42.04,201.04 42.04,200.28 41.91,200.15 40.39,200.15 38.48,198.25
GND on TOP: 21.21,121.28 21.21,127.25 22.1,128.14 26.75,128.14 28.63,126.26 28.63,122.91 28.3,122.58 25.37,122.58 25.22,122.43 25.22,121.74 24.77,121.28 ; 2 cut-outs
GND on TOP: 69.72,51.31 69.6,51.44 69.6,52.58 69.72,52.7 73.03,52.7 73.28,52.45 73.28,51.56 73.03,51.31
GND on TOP: 106.05,70.36 105.66,70.74 105.66,73.03 105.17,73.52 105.17,75.07 104.62,75.62 103.58,75.62 103.53,75.67 103.53,76.86 102.74,77.65 102.74,77.98 103.76,77.98 107.44,74.3 107.44,70.74 107.06,70.36
GND on TOP: 102.49,95 101.09,96.39 101.09,96.9 101.22,97.03 102.11,97.03 102.23,96.9 102.23,96.52 102.11,96.39 102.11,96.14 102.36,95.89 103.63,95.89 103.76,96.01 104.14,96.01 104.27,95.89 104.27,95.12 104.14,95
GND on TOP: 77.52,116.05 77.5,116.08 77.5,117.22 77.52,117.25 79.45,117.25 79.53,117.17 79.53,116.18 79.4,116.05
GND on TOP: 208.46,141.99 208.33,142.11 208.33,142.54 208.64,142.85 208.64,143.18 208.56,143.26 208.25,143.26 207.72,142.72 207.59,142.72 207.44,142.88 207.44,143.26 208.28,144.09 210.41,144.09 210.82,143.69 210.82,143.15 211.46,142.52 211.46,142.09 211.35,141.99
GND on TOP: 216.41,30.23 215.75,30.89 215.75,32.49 215.9,32.64 217.3,32.64 217.93,32 219.71,32 219.96,31.75 219.96,30.73 219.71,30.48 218.44,30.48 218.19,30.23 ; 2 cut-outs
GND on TOP: 15.89,81.9 15.52,82.27 15.52,84.23 15.93,84.63 15.93,85.29 15.98,85.34 17.09,85.34 17.17,85.42 17.17,86.16 17.22,86.21 21.56,86.21 21.62,86.16 21.62,82.09 21.42,81.9 ; 1 cut-out
GND on TOP: 18.8,191.13 18.41,191.52 18.41,193.93 20.07,195.58 24.64,195.58 24.77,195.45 24.77,191.39 24.51,191.13
GND on TOP: 118.11,239.27 115.95,241.43 114.81,241.43 114.43,241.81 114.43,244.98 113.16,246.25 110.49,246.25 108.71,248.03 105.28,248.03 100.58,243.33 96.9,243.33 92.2,248.03 87.88,248.03 86.36,246.51 86.36,245.11 85.98,244.73 83.69,244.73 81.53,242.57 78.49,242.57 78.41,242.65 78.41,253.31 78.44,253.34 115,253.34 117.29,252.39 118.24,250.1 118.24,239.27
GND on TOP: 87.76,59.44 87.38,59.82 87.38,71.37 89.53,73.53 89.92,73.53 90.04,73.41 90.04,72.77 90.93,71.88 90.93,68.33 89.18,68.33 88.87,68.02 88.87,65.61 89.2,65.28 90.83,65.28 90.93,65.18 90.93,61.72 89.1,61.72 88.93,61.54 88.93,59.61 88.75,59.44 ; 1 cut-out
GND on TOP: 11.89,88.27 11.81,88.34 11.81,91.9 11.86,91.95 13.97,91.95 14.22,91.69 14.22,89.05 13.44,88.27
GND on TOP: 50.93,55.88 50.55,56.26 50.55,67.82 52.7,69.98 53.09,69.98 53.21,69.85 53.21,69.22 54.1,68.33 54.1,64.77 52.17,64.77 52.1,64.69 52.1,62.43 52.5,62.03 53.9,62.03 54.1,61.82 54.1,58.17 52.2,58.17 52.02,57.99 52.02,56.08 51.82,55.88 ; 1 cut-out
GND on TOP: 173.1,2.54 172.85,2.79 172.85,6.73 173.48,7.37 174.24,7.37 174.37,7.24 174.37,4.32 174.75,3.94 211.96,3.94 213.87,5.84 213.87,8.13 214.25,8.51 223.52,8.51 223.77,8.26 223.77,7.49 218.82,2.54
GND on TOP: 58.42,198.5 58.17,198.75 58.17,199.9 58.29,200.03 63.63,200.03 63.75,199.9 63.75,199.52 62.74,198.5
GND on TOP: 213.13,204.98 212.9,205.21 212.9,207.85 213.23,208.18 213.23,212.29 213.28,212.34 215.26,212.34 215.39,212.22 215.39,205.74 214.63,204.98 ; 8 cut-outs
GND on TOP: 110.24,86.87 107.06,90.04 105.92,90.04 104.65,91.31 104.65,91.95 104.78,92.08 105.28,92.08 105.41,91.95 105.41,91.06 105.79,90.68 107.7,90.68 108.46,91.44 109.6,91.44 109.86,91.19 109.86,90.93 109.6,90.68 109.6,90.3 109.86,90.04 111.89,90.04 112.52,89.41 113.54,89.41 113.67,89.53 113.67,91.19 113.28,91.57 113.28,95.12 112.52,95.89 112.52,97.41 112.27,97.66 111.89,97.66 111.12,96.9 109.47,96.9 109.09,97.28 109.09,97.79 109.22,97.92 109.6,97.92 110.11,97.41 110.62,97.41 110.87,97.66 110.87,98.93 110.74,99.06 110.24,99.06 109.73,98.55 108.71,98.55 107.57,99.69 107.57,101.47 107.82,101.73 108.33,101.73 108.71,101.35 109.22,101.35 109.47,101.6 109.47,102.74 109.86,103.12 116.97,103.12 117.6,102.49 117.6,94.36 116.71,93.47 116.71,87.25 116.33,86.87
GND on TOP: 19.3,1.65 18.92,2.03 18.92,14.48 19.18,14.73 21.21,14.73 21.59,14.35 21.59,1.91 21.34,1.65 ; 1 cut-out
GND on TOP: 29.08,118.87 28.57,119.38 28.57,121.16 29.16,121.74 29.16,125.86 29.29,125.98 30.66,125.98 30.84,125.81 30.84,124.94 30.68,124.79 29.92,124.79 29.77,124.64 29.77,123.65 29.97,123.44 30.73,123.44 30.86,123.32 30.86,122.56 30.99,122.43 31.62,122.43 31.75,122.3 31.75,120.65 32.26,120.14 34.29,120.14 34.42,120.02 34.42,119.13 34.16,118.87 ; 4 cut-outs
GND on TOP: 153.29,3.81 152.27,4.83 152.27,17.27 152.4,17.4 155.7,17.4 156.08,17.02 156.08,14.48 157.1,13.46 159.26,13.46 161.16,15.37 167,15.37 174.37,8 174.37,6.48 173.35,5.46 170.31,5.46 168.66,3.81
GND on TOP: 55.3,3.68 54.76,4.22 53.92,4.22 53.56,4.58 53.56,5.42 53.54,5.44 53.54,6.81 55.63,8.89 55.63,10.79 55.5,10.92 54.48,10.92 54.36,11.05 54.36,11.68 54.48,11.81 56.26,11.81 56.52,11.56 56.52,6.12 57.38,5.26 57.38,3.89 57.18,3.68
GND on TOP: 90.5,217.93 90.42,218.01 90.42,220.73 89.79,221.36 89.79,222 90.3,222.5 90.3,223.27 90.55,223.52 91.31,223.52 91.82,223.01 91.82,218.82 91.31,218.31 91.31,218.11 91.14,217.93 ; 1 cut-out
GND on TOP: 111.12,36.07 110.87,36.32 110.87,38.99 111,39.12 115.06,39.12 115.32,38.86 115.32,36.45 114.94,36.07
GND on TOP: 60.96,187.45 59.18,189.23 59.18,193.29 59.31,193.42 65.28,193.42 65.79,192.91 65.79,192.15 66.17,191.77 66.17,187.45 ; 4 cut-outs
GND on TOP: 171.7,220.85 171.45,221.11 171.45,222.25 172.09,222.88 172.09,228.47 172.47,228.85 174.62,228.85 174.62,221.23 174.24,220.85 ; 3 cut-outs
GND on TOP: 37.3,107.13 37.04,107.38 37.04,108.65 37.42,109.03 39.15,109.03 39.66,108.53 39.66,107.38 39.4,107.13
GND on TOP: 232.79,114.05 232.28,114.55 232.28,119 232.66,119.38 234.57,119.38 234.95,119 234.95,114.55 234.44,114.05
GND on TOP, BOTTOM: 75.95,201.42 75.44,201.93 75.44,205.99 75.69,206.25 80.01,206.25 82.3,203.96 82.3,202.18 81.53,201.42
GND on BOTTOM: 18.8,191.13 18.29,191.64 18.29,193.8 20.07,195.58 24.89,195.58 25.02,195.45 25.02,191.64 24.51,191.13
GND on BOTTOM: 43.05,226.82 33.02,236.85 26.26,236.85 26.26,237.21 34.82,245.77 42.9,245.77 50.24,238.43 50.24,230.84 49.91,230.5 49.91,229.87 51.05,228.73 51.05,227.33 50.55,226.82
GND on BOTTOM: 155.83,183.9 154.56,185.17 154.56,188.85 155.83,190.12 162.94,190.12 164.85,188.21 164.85,184.53 164.21,183.9
GND on BOTTOM: 169.67,186.44 169.42,186.69 169.42,187.58 170.94,189.1 170.94,189.87 171.45,190.37 172.09,190.37 172.47,190.75 172.47,195.83 169.54,198.75 169.54,202.69 166.24,205.99 166.24,207.01 167,207.77 177.42,207.77 179.58,205.61 187.07,205.61 187.58,205.1 187.58,203.84 170.18,186.44
GND on BOTTOM: 117.73,188.47 114.94,191.26 114.94,194.69 115.82,195.58 117.86,195.58 117.98,195.45 117.98,193.93 118.49,193.42 124.33,193.42 124.59,193.17 124.59,192.91 123.32,191.64 123.32,190.63 123.7,190.25 130.68,190.25 132.21,191.77 134.24,191.77 135.38,190.63 135.38,189.1 134.75,188.47
GND on BOTTOM: 15.84,81.9 15.52,82.22 15.52,84.23 15.88,84.58 20.9,84.58 21.62,83.87 21.62,82.07 21.45,81.9
GND on BOTTOM: 232.94,114.02 232.31,114.66 232.31,118.85 232.82,119.35 234.59,119.35 234.95,119 234.95,114.53 234.44,114.02
GND on BOTTOM: 44.2,111.38 34.1,121.48 32.27,127.11 19.43,139.95 19.43,182.12 19.81,182.5 82.42,182.5 82.8,182.88 142.32,182.88 143.64,181.56 143.64,163.88 146.58,160.93 146.58,156.87 138.81,149.1 138.81,146.56 138.04,145.78 138.04,143.68 130.25,135.89 130.25,129.16 123.11,122.02 120.27,122.02 117.63,119.38 111.63,119.38 105.66,113.41 95.38,113.41 94.36,114.43 90.55,114.43 89.79,115.19 89.79,119.51 89.03,120.27 88.06,120.27 87.3,121.03 85.88,121.03 85.75,120.9 85.75,120.45 85.57,120.27 84.38,120.27 84.18,120.47 84.18,120.93 84.07,121.03 83.26,121.03 82.98,120.75 82.98,120.35 82.91,120.27 69.09,120.27 65.53,116.71 65.53,115.06 64.39,113.92 60.83,113.92 59.18,112.27 57.53,112.27 56.64,111.38
GND on BOTTOM: 173.99,4.45 173.61,4.83 173.61,6.99 175.45,8.83 188.28,8.83 196.72,17.27 209.04,17.27 211.07,15.24 211.07,11.05 213.74,8.38 220.98,8.38 221.23,8.13 221.23,7.87 217.81,4.45
GND on BOTTOM: 6.86,218.31 4.57,220.6 4.57,226.19 7.49,229.11 13.21,229.11 14.86,227.46 14.86,221.74 11.43,218.31
GND on BOTTOM: 8.13,232.79 8,232.92 8,233.04 8.13,233.17 8.89,233.17 9.91,234.19 9.91,247.52 10.79,248.41 19.43,248.41 20.32,249.3 20.32,252.22 20.7,252.6 32.38,252.6 33.53,253.75 62.23,253.75 62.36,253.62 62.36,242.06 61.85,241.55 60.07,241.55 50.06,251.56 32.36,251.56 13.59,232.79
GND on BOTTOM: 83.19,234.7 79.76,238.12 79.76,239.65 78.41,241 78.41,253.03 78.61,253.24 114.81,253.24 115.06,252.98 116.08,252.98 118.11,250.95 118.11,244.73 118.24,244.6 118.24,238.51 117.73,238 115.32,238 114.68,237.36 109.86,237.36 109.22,238 109.22,239.4 109.6,239.78 114.81,239.78 116.46,241.43 116.46,245.75 113.67,248.54 111.51,248.54 109.22,246.25 107.19,246.25 106.55,245.62 106.55,244.98 106.17,244.6 104.39,244.6 103.5,243.71 97.54,243.71 93.6,247.65 91.06,247.65 89.53,246.13 86.87,246.13 85.47,244.73 83.82,244.73 83.31,244.22 83.31,242.95 83.82,242.44 83.82,237.24 84.58,236.47 86.74,236.47 87.12,236.09 87.12,234.95 86.87,234.7
GND on BOTTOM: 33.15,53.21 31.37,54.99 31.37,59.44 32.26,60.33 32.26,62.1 33.27,63.12 34.04,63.12 34.16,62.99 34.16,53.47 33.91,53.21
GND on BOTTOM: 108.81,188.42 108.76,188.47 108.76,189.38 109.22,189.84 109.22,191.05 109.16,191.19 109.12,191.34 108.87,191.58 102.35,191.58 102.11,191.34 102.11,189.97 102.46,189.61 102.46,188.67 102.23,188.44 98.37,188.44 95.89,190.93 95.89,193.17 94.87,194.18 94.87,199.26 95.12,199.52 97.54,199.52 97.92,199.9 97.92,201.93 98.93,202.95 100.97,202.95 101.35,202.56 101.35,201.55 101.98,200.91 108.71,200.91 109.6,201.8 113.41,201.8 114.68,203.07 122.17,203.07 123.06,202.18 123.06,201.42 123.57,200.91 134.87,200.91 135.25,200.53 135.25,196.6 135,196.34 108.58,196.34 108.33,196.09 108.33,194.82 108.71,194.44 109.6,194.44 110.24,195.07 113.03,195.07 113.41,194.69 113.41,193.93 112.9,193.42 105.03,193.42 104.65,193.8 104.65,194.18 104.39,194.44 103.12,194.44 102.74,194.06 102.74,192.91 102.95,192.71 110.82,192.71 113.49,190.04 113.49,188.75 113.16,188.42
GND on BOTTOM: 50.93,55.88 50.55,56.26 50.55,67.44 51.05,67.94 52.2,67.94 52.45,67.69 52.45,56.13 52.2,55.88
GND on BOTTOM: 82.17,3.05 75.18,10.03 75.18,13.84 76.07,14.73 85.22,14.73 95.89,4.06 95.89,3.17 95.76,3.05
GND on BOTTOM: 120.27,4.45 119.63,5.08 119.63,14.73 121.16,16.26 143.26,16.26 144.27,15.24 155.45,15.24 155.7,14.99 155.7,13.46 153.54,11.3 148.08,11.3 147.7,10.92 147.7,5.84 146.3,4.45
GND on BOTTOM: 202.44,22.48 202.18,22.73 202.18,27.81 202.31,27.94 204.6,27.94 204.98,28.32 206.38,28.32 207.14,29.08 207.9,29.08 208.15,28.83 208.15,23.11 207.52,22.48
GND on BOTTOM: 52.21,201.68 50.57,203.31 50.57,204.85 53.75,208.03 55.63,208.03 56.13,207.52 56.13,202.31 54.08,202.31 53.44,201.68
GND on BOTTOM: 21.72,121.79 21.21,122.3 21.21,127.25 22.1,128.14 26.75,128.14 28.65,126.24 28.65,122.53 27.91,121.79
GND on BOTTOM: 217.93,0.76 234.06,16.89 234.06,22.48 237.36,25.78 237.36,85.22 236.09,86.49 236.09,95.76 235.2,96.65 235.2,98.17 236.09,99.06 236.09,104.01 236.35,104.27 238.25,104.27 240.41,106.43 240.41,109.6 242.95,112.14 243.24,112.14 243.24,4 242.29,1.71 240,0.76
GND on BOTTOM: 0.76,26.29 0.76,230 1.71,232.29 4,233.24 8,233.24 9.25,233.75 9.76,235 9.76,247.2 10.13,248.07 11,248.44 18.5,248.44 19.75,248.95 20.26,250.2 20.26,252.6 20.33,252.77 20.5,252.84 31.75,252.84 32.54,253.12 32.99,253.84 62.25,253.84 62.25,253.33 33.34,253.33 32.69,252.6 31.75,252.33 20.77,252.33 20.77,250.2 20.11,248.59 18.5,247.93 11,247.93 10.48,247.72 10.27,247.2 10.27,235 9.61,233.39 8,232.73 4,232.73 2.07,231.93 1.27,230 1.27,44.83 11.4,34.7 11.4,30.94 6.76,26.29
GND on BOTTOM: 242.73,4.06 242.73,230 241.93,231.93 240,232.73 120,232.73 118.39,233.39 117.73,235 117.73,250.1 116.93,252.03 115,252.83 78.41,252.83 78.41,252.83 78.41,253.19 78.56,253.34 115,253.34 117.29,252.39 118.24,250.1 118.24,235 118.75,233.75 120,233.24 240,233.24 242.29,232.29 243.24,230 243.24,4.06
GND on BOTTOM: 242.95,182.12 229.74,195.33 229.74,203.58 224.66,208.66 224.66,211.84 222.5,214 219.07,214 215.39,217.68 215.39,218.06 215.65,218.31 219.2,218.31 220.73,216.79 223.39,216.79 224.28,217.68 229.11,217.68 230,216.79 230.05,216.79 233.51,213.32 237.62,213.32 238.63,214.34 238.63,223.27 229.24,232.66 174.75,232.66 165.61,223.52 162.53,223.52 158.5,225.43 150.68,233.24 240,233.24 242.29,232.29 243.24,230 243.24,201.64 243.21,201.68 243.21,182.25 243.08,182.12
GND on BOTTOM: 22.48,226.31 21.08,227.71 21.08,229.74 25.91,234.57 31.62,234.57 39.24,226.95 39.24,226.69 38.86,226.31
GND on BOTTOM: 229.11,17.91 228.85,18.16 228.85,25.02 229.11,25.27 231.01,25.27 231.52,24.77 231.52,18.54 230.89,17.91
GND on BOTTOM: 230.17,108.25 230.07,108.36 230.07,109.12 230.94,109.98 230.94,111.2 229.46,112.67 227.56,112.67 227.08,113.16 227.08,114.81 227.28,115.01 231.01,115.01 232.79,113.23 234.47,113.23 235.03,112.67 235.03,108.48 234.8,108.25
GND on BOTTOM: 69.22,58.93 68.83,59.31 68.83,70.48 69.34,70.99 70.48,70.99 70.74,70.74 70.74,59.18 70.48,58.93
GND on BOTTOM: 101.6,5.71 100.71,6.6 100.71,15.49 101.6,16.38 105.03,16.38 105.41,16 113.41,16 113.92,15.49 113.92,14.1 117.6,10.41 117.6,6.35 116.97,5.71
GND on BOTTOM: 111.12,36.07 110.87,36.32 110.87,38.99 111,39.12 114.94,39.12 115.32,38.73 115.32,36.58 114.81,36.07
GND on BOTTOM: 123.57,39.37 123.15,39.79 123.15,47.21 123.27,47.32 125.07,47.32 125.27,47.12 125.27,39.55 125.09,39.37
GND on BOTTOM: 226.95,135.38 226.69,135.65 226.69,141.23 227.58,142.13 228.45,142.13 228.85,141.73 228.85,136.91 227.33,135.38
GND on BOTTOM: 154.18,154.94 152.65,156.46 152.65,165.86 155.32,168.53 155.32,174.24 155.57,174.5 158.75,174.5 166.95,166.29 180.85,166.29 182.63,164.52 185.04,164.52 185.27,164.29 185.27,163.93 185.12,163.78 177.88,163.78 177.29,164.36 176.1,164.36 175.56,163.83 171.15,163.83 162.26,154.94
GND on BOTTOM: 19.18,0.89 19.05,1.02 19.05,14.78 19.89,15.62 20.7,15.62 21.34,14.99 21.34,13.21 21.84,12.7 38.73,12.7 40.89,10.54 47.88,10.54 49.15,9.27 49.15,5.08 52.07,2.16 53.59,2.16 54.51,1.24 60.81,1.24 61.06,1.5 61.06,2.24 59.54,3.76 59.54,4.6 58.88,5.26 56.97,5.26 55.74,4.03 54.14,4.03 51.94,6.22 51.94,16.13 52.96,17.14 57.53,17.14 59.56,19.18 61.34,19.18 61.59,18.92 62.23,18.92 63.25,19.94 64.77,19.94 65.28,19.43 69.34,19.43 72.77,16 72.77,10.16 82.04,0.89
GND on BOTTOM: 146.15,166.29 145.62,166.83 145.62,181.41 145.71,181.5 145.14,182.07 142.19,182.07 142.09,182.17 142.09,182.45 142.32,182.68 148.84,182.68 148.95,182.58 148.95,166.42 148.82,166.29
GND on BOTTOM: 173.35,218.19 172.85,218.69 172.85,220.73 174.37,222.25 176.53,222.25 177.67,221.11 177.67,218.82 177.04,218.19
GND on BOTTOM: 87.76,59.44 87.38,59.82 87.38,71.37 87.5,71.5 89.03,71.5 89.28,71.25 89.28,59.69 89.03,59.44
GND on BOTTOM: 59.82,187.45 59.05,188.21 59.05,192.15 59.56,192.66 65.79,192.66 66.04,192.41 66.04,187.96 65.53,187.45
GND on BOTTOM: 169.21,183.64 188.9,203.33 194.03,203.33 195.53,204.83 196.8,204.83 197.09,204.53 197.09,202.81 195.73,201.45 191.13,201.45 190.86,201.73 189.48,201.73 185.55,197.79 185.55,196.32 171.07,181.84 166.95,181.84 166.94,181.85 166.76,181.85 166.34,182.27 166.34,183.13 166.85,183.64
GND on BOTTOM: 38.1,207.9 37.85,208.15 37.85,211.96 38.1,212.22 38.86,212.22 39.24,212.6 39.24,213.21 39.34,213.31 41.91,213.31 42.06,213.16 42.06,209.19 40.77,207.9
GND on L2VCC: outline of 281 points within 0.76,0.76 243.24,253.84 ; 47 cut-outs
GND on L2VCC: 211.05,153.81 210.96,153.9 210.96,154.73 211.31,155.08 212.01,155.08 212.18,154.91 212.18,154.26 211.73,153.81
GND on L2VCC: 224.73,161.23 224.73,167.43 229.44,172.15 231.7,172.15 233.74,170.1 233.74,162.77 232.2,161.23
GND on L2VCC: 216.36,127.83 213.82,130.37 211.53,130.37 210.96,130.94 211.22,131.06 211.32,131.32 211.31,132.08 210.92,132.46 210.54,132.07 210.55,131.35 210.12,131.78 210.12,137.73 210.87,137.73 211.38,137.22 214.42,137.22 214.46,137.19 214.39,137.21 214.32,137.21 213.56,137.21 213.18,136.83 213.56,136.45 214.32,136.45 214.64,136.61 214.68,136.97 216.85,134.8 216.85,127.83 ; 3 cut-outs
GND on L2VCC: 210.26,156.15 209.74,156.67 209.74,157.15 213.55,160.96 213.55,161.21 213.69,161.35 213.95,161.35 215.46,162.86 215.46,165.31 214.82,165.94 214.82,169.21 215.34,169.74 219.63,169.74 220.41,168.96 220.41,165.56 214.17,159.32 212.52,159.32 210.5,157.3 210.5,156.29 210.36,156.15
GND on L2VCC: 220.3,98.74 219.77,99.27 219.77,100.89 220.04,101.16 229.69,101.16 232.11,103.57 233.47,103.57 233.87,103.17 233.87,100.03 232.59,98.74
GND on L2VCC: 219.53,146.11 219.01,146.64 219.01,147.65 218.77,147.89 216.11,147.89 215.34,148.65 210.64,148.65 209.87,149.43 209.87,150.42 210.26,150.81 211.25,150.81 212.77,149.29 218.26,149.29 219.41,150.43 221.41,150.43 222.17,149.67 223.06,149.67 224.47,148.26 224.47,146.11
GND on L2VCC: 227.79,113.98 227.39,114.38 227.39,128.86 226.76,129.49 226.76,141.27 228.28,142.8 228.28,155.24 231.22,158.18 238.44,158.18 238.44,115.63 237.9,115.63 236.76,113.98
GND on L2VCC: 53.55,200.6 50.23,203.91 50.23,212.52 51.26,213.55 60.37,213.55 60.13,213.31 60.13,208.74 59.88,208.49 59.88,206.96 59.48,206.57 56.56,206.57 56.2,206.2 56.2,200.6
GND on L3: 242.73,4.06 242.73,223.81 233.81,232.73 120,232.73 118.39,233.39 117.73,235 117.73,250.1 116.93,252.03 115,252.83 78.41,252.83 78.41,253.19 78.56,253.34 115,253.34 117.29,252.39 118.24,250.1 118.24,235 118.75,233.75 120,233.24 240,233.24 242.29,232.29 243.24,230 243.24,4.06
GND on L3: 0.76,26.29 0.76,230 1.71,232.29 4,233.24 8,233.24 9.25,233.75 9.76,235 9.76,247.2 10.13,248.07 11,248.44 18.5,248.44 19.75,248.95 20.26,250.2 20.26,252.6 20.33,252.77 20.5,252.84 31.75,252.84 32.54,253.12 32.99,253.84 62.3,253.84 62.3,253.33 33.34,253.33 32.69,252.6 31.75,252.33 20.77,252.33 20.77,250.2 20.11,248.59 18.5,247.93 11,247.93 10.48,247.72 10.27,247.2 10.27,235 9.61,233.39 8,232.73 5.46,232.73 1.27,228.54 1.27,26.29
GND on L3: 238.76,176.33 237.59,177.5 237.59,181.08 238.76,182.25 238.76,186.94 242.06,190.25 242.06,210.69 225.81,226.95 203.96,226.95 203.07,226.06 203.07,220.98 201.8,219.71 198.12,219.71 189.87,227.97 182.88,227.97 182.09,227.18 176.48,227.18 176.47,227.19 169.38,227.19 166.5,230.07 119,230.07 116.31,232.77 116.31,251.46 116.74,251.89 117.2,251.89 118.03,251.05 118.03,234.14 118.95,233.22 235.15,233.22 243.15,225.22 243.15,15.82 242.21,14.88 239.5,14.88 238.76,15.62
GND on L3: 228.09,160.78 233.81,160.78 235.33,162.31 235.33,174.37 234.57,175.13 234.57,191.01 238.38,194.82 238.38,203.07 235.2,206.25 233.81,206.25 232.92,205.36 232.92,172.59 230.38,170.05 228.85,170.05 225.68,166.88 225.68,163.19
GND on L3: outline of 98 points within 6.86,0.89 243.21,253.31 ; 1 cut-out
GND on L3: 10.79,248.28 9.78,247.27 9.78,233.93 9.14,233.3 8.64,233.3 8.13,232.79 13.54,232.79 32.56,251.82 61.47,251.82 62.31,252.65 62.31,253.59 62.2,253.7 33.43,253.7 32.46,252.73 21.08,252.73 20.45,252.09 20.45,249.43 19.3,248.28
VCCPGPPD_PWR on BOTTOM: 205.66,142.39 205.21,142.85 203.76,142.85 203.58,143.03 203.58,144.09 204.27,144.78 204.83,144.78 206.5,143.1 206.5,142.93 205.97,142.39
0D95V_CPU_VCCIO on TOP: 83.29,116.23 83.16,116.36 83.16,117.93 83.52,118.29 87.66,118.29 87.88,118.06 87.88,117.68 87.58,117.37 84.23,117.37 84.14,117.28 84.14,116.34 84.02,116.23
0D95V_CPU_VCCIO on TOP: 72.59,115.19 72.49,115.29 72.49,116.26 72.57,116.33 73.2,116.33 73.51,116.64 73.51,119.25 74.14,119.89 74.14,120.4 73.66,120.88 73.66,121.16 73.86,121.36 74.17,121.36 75.29,120.24 75.29,117.45 75.11,117.27 75.11,115.32 74.98,115.19 ; 4 cut-outs
0D95V_CPU_VCCIO on TOP: 85.02,107.14 84.87,107.29 84.87,108.34 84.98,108.45 86.24,108.45 86.44,108.65 86.44,109.64 86.48,109.68 87.58,109.68 87.72,109.53 87.72,107.32 87.54,107.14 ; 3 cut-outs
0D95V_CPU_VCCIO on TOP: 117.35,88.39 117.09,88.65 117.09,93.22 119.38,95.5 121.79,95.5 122.05,95.76 122.05,96.27 121.67,96.65 119.38,96.65 119.25,96.77 119.25,99.44 119.89,100.08 120.65,100.08 121.03,99.69 125.22,99.69 125.6,100.08 127,100.08 127.08,100 127.08,96.65 125.32,96.65 125.09,96.42 125.09,94.49 127.51,92.08 127.51,91.57 127.38,91.44 125.73,91.44 125.09,92.08 123.19,92.08 122.94,91.82 122.94,88.77 122.56,88.39 ; 2 cut-outs
0D95V_CPU_VCCIO on BOTTOM: 86.52,103.57 84.9,105.19 84.9,111.26 83.93,112.23 83.93,117.9 83.93,118.22 84.05,118.34 88.51,118.34 89.07,117.78 89.07,114.66 91.01,112.72 91.01,105.33 90.46,104.78 90.46,104.21 89.82,103.57
0D95V_CPU_VCCIO on L2VCC: 120.35,86.93 119.57,87.71 119.57,102.06 118.57,103.06 107.27,103.06 102.57,107.76 96.6,107.76 95.58,108.78 93.42,108.78 93.03,109.17 93.03,110.68 92.65,111.06 88.05,111.06 87.7,110.72 87.7,108.95 87.69,108.85 87.69,108.1 87.57,107.6 87.5,107.38 85.93,107.38 85.58,107.38 84.9,107.38 84.9,112.98 83.36,114.51 83.36,117.43 82.74,118.05 73.47,118.05 73.33,118.19 73.33,120.7 73.47,120.84 86.14,120.84 87.16,119.83 88.3,119.83 89.06,119.06 89.57,119.06 89.97,118.67 89.97,117.56 89.71,117.3 89.71,114.73 90.08,114.37 92.39,114.37 93.03,115 93.92,115 95.7,116.78 98.21,116.78 100.36,114.62 107.25,114.62 120.78,128.14 121.74,129.1 132.51,129.1 132.91,128.7 132.91,106.89 126.94,100.92 126.94,89.49 124.38,86.93
0D675V_VTT_S0 on TOP: 42.29,194.56 42.16,194.69 42.16,195.83 42.55,196.22 43.56,196.22 43.81,195.96 43.81,194.56
0D675V_VTT_S0 on TOP: 84.58,170.18 83.69,171.07 83.69,180.85 84.07,181.23 84.07,185.04 84.33,185.29 86.74,185.29 86.87,185.17 86.87,183.26 87.63,182.5 87.63,175.26 86.74,174.37 86.74,170.56 86.36,170.18 ; 6 cut-outs
0D675V_VTT_S0 on BOTTOM: 42.04,182.88 40.26,184.66 40.26,186.56 40.64,186.94 42.8,186.94 44.45,185.29 50.55,185.29 51.18,184.66 76.38,184.66 78.41,186.69 87.25,186.69 87.63,186.31 87.63,183.39 87.38,183.13 83.82,183.13 83.19,183.77 78.11,183.77 77.22,182.88
0D675V_VTT_S0 on L2VCC: 39.94,184.85 39.94,195.63 40.72,196.41 42.97,196.41 43.24,196.14 43.24,185.21 43.61,184.85
0D675V_VTT_S0 on L3: 83.59,171.42 83.59,169.88 84.33,169.14 84.33,168.35 83.62,167.64 83.62,166.6 84.23,165.99 85.55,165.99 85.75,166.19 85.75,172.09 85.5,172.34 84.51,172.34
1D2V_SM_S3 on TOP: 74.19,182.63 74.02,182.8 74.02,184.1 74.19,184.28 78.36,184.28 78.74,184.66 78.74,189.15 78.94,189.36 80.9,189.36 81.15,189.61 92.33,189.61 92.86,189.08 92.86,184.91 92.99,184.78 96.52,184.78 97.66,183.64 97.66,182.88 97.41,182.63 90.3,182.63 90.17,182.75 90.17,183.64 90.04,183.77 87.63,183.77 87.25,184.15 87.25,185.17 87,185.42 83.95,185.42 82.68,184.15 82.68,183.01 82.3,182.63 ; 10 cut-outs
1D2V_SM_S3 on TOP: 127.25,106.17 127.25,108.84 129.54,111.12 132.08,111.12 139.06,118.11 141.99,118.11 142.24,117.86 142.24,114.2 134.21,106.17
1D2V_SM_S3 on TOP: 39.62,182.88 39.37,183.13 39.37,189.36 39.88,189.87 39.88,196.6 41.66,198.37 47.5,198.37 47.62,198.25 47.62,196.72 42.24,196.72 41.29,195.77 41.29,195.59 41.27,195.58 41.27,187.25 40.94,186.92 40.94,184.94 41.27,184.61 41.27,183.13 41.02,182.88
1D2V_SM_S3 on BOTTOM: 138.94,116.08 138.43,116.59 138.43,127.76 140.59,129.92 140.59,133.22 139.45,134.37 139.45,145.8 139.9,146.25 139.9,148.41 148.15,156.65 148.15,164.4 148.72,164.97 151,164.97 151.26,164.72 151.26,155.45 143.76,147.96 143.76,144.91 143.26,144.4 143.26,139.83 144.46,138.62 144.46,127.83 142.3,125.67 142.3,118.05 142.24,117.98 142.24,116.2 142.11,116.08
1D2V_SM_S3 on L2VCC: outline of 162 points within 24.07,126.56 154.88,189.55
1D2V_SM_S3 on L3: 149.35,162.18 151.51,162.18 155.19,165.86 155.19,179.71 153.16,181.74 149.73,181.74 149.22,181.23 149.22,165.13 148.67,164.57 148.67,162.86
1D05V_CPU_SA on TOP: 115.95,52.83 115.29,53.49 115.29,63.47 115.7,63.88 126.49,63.88 127.8,62.57 127.8,57.24 127.48,56.92 125.32,56.92 124.82,56.41 124.82,54.84 124.56,54.58 123.67,54.58 121.92,52.83 ; 2 cut-outs
